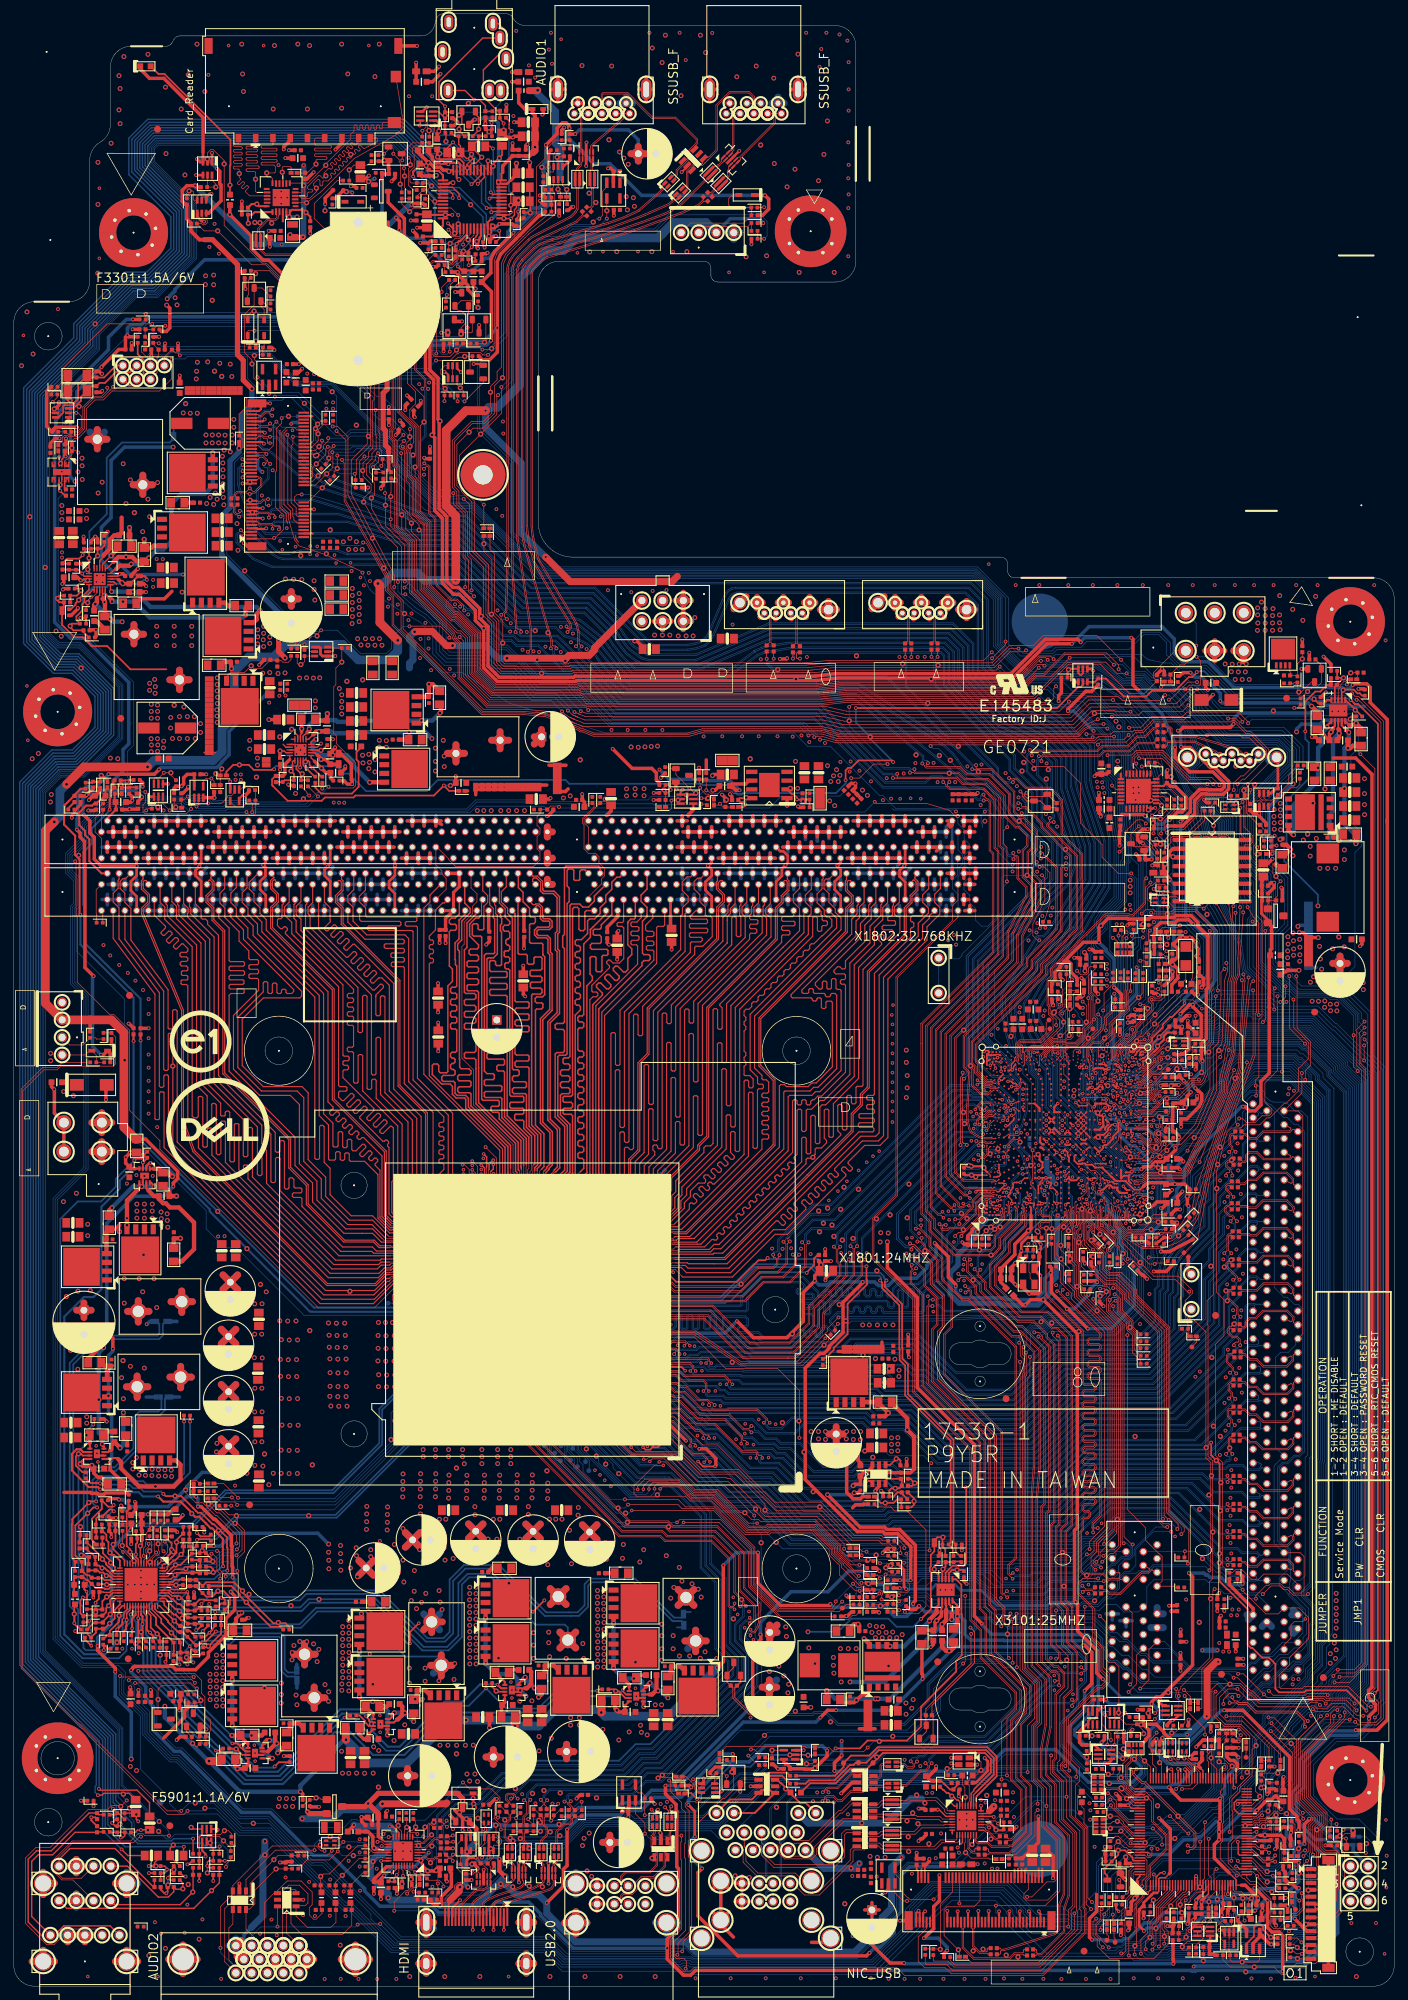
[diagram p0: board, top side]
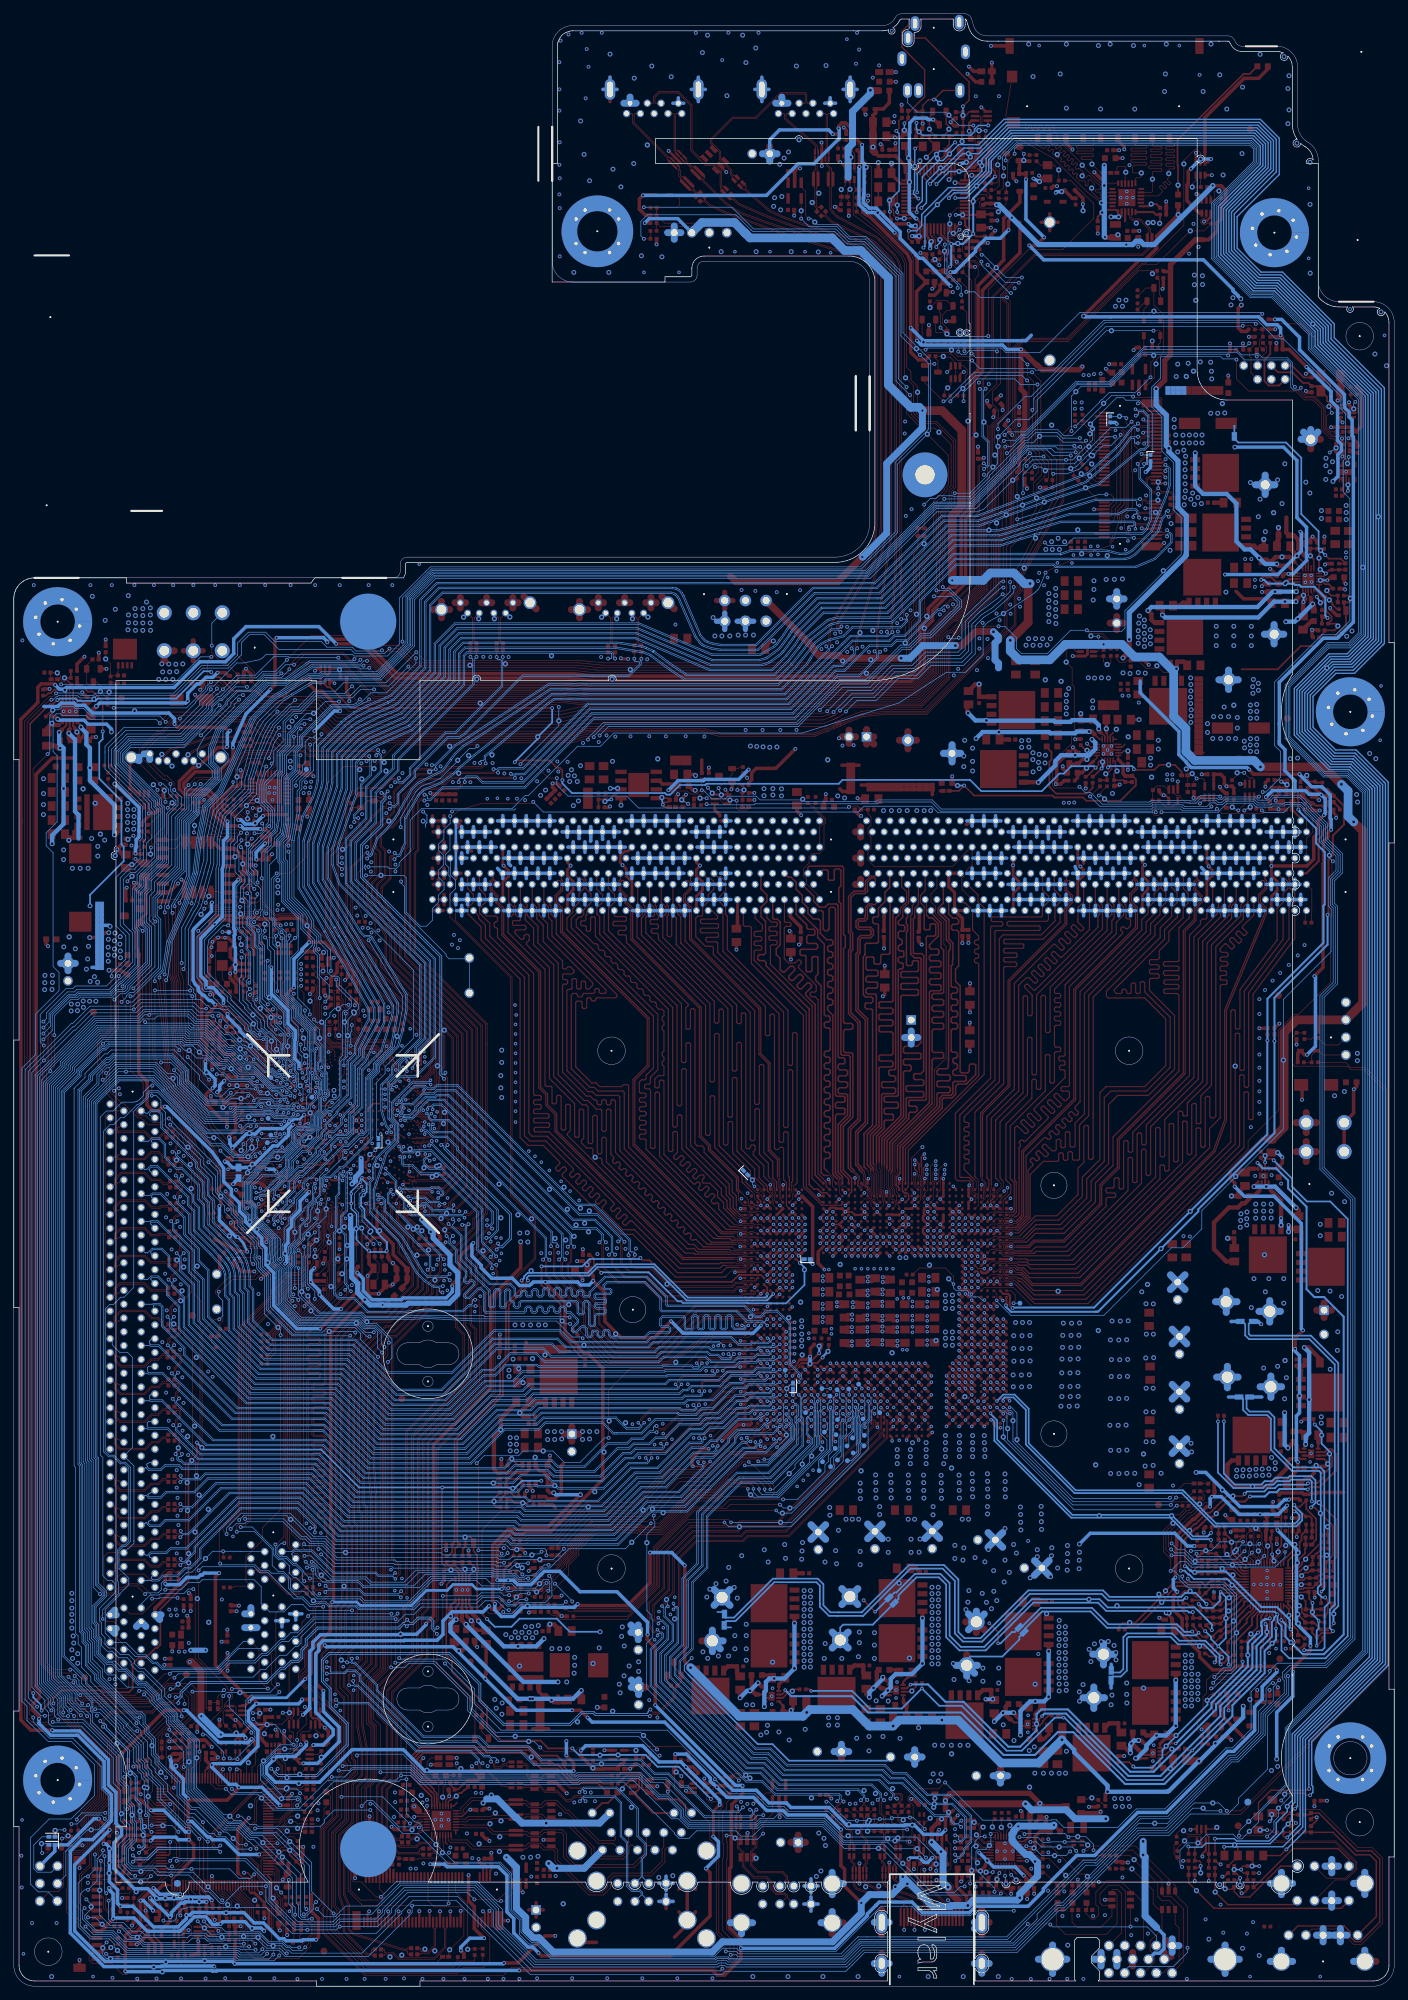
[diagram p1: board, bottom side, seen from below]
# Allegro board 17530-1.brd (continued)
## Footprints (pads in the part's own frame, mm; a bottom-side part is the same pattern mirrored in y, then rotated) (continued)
C402H22
  custom 0.152x0.152 smd: 1(0,0.445) 2(0,-0.445)
C603H35
  custom 0.216x0.216 smd: 1(0,0.762) 2(0,-0.762)
C603H36
  custom 0.216x0.216 smd: 1(0,0.762) 2(0,-0.762)
C603H40
  custom 0.216x0.216 smd: 1(0,0.762) 2(0,-0.762)
C805H50
  rect 1.397x1.143 smd: 1(0,0.965) 2(0,-0.965)
C805H54
  rect 1.397x1.143 smd: 1(0,0.965) 2(0,-0.965)
C805H56
  rect 1.397x1.143 smd: 1(0,0.965) 2(0,-0.965)
C805H58
  rect 1.397x1.143 smd: 1(0,0.965) 2(0,-0.965)
C35012W-L101-39AA00R
  round 0.254 hole 1.27 unplated: (0,0) (0,-6)
  oval 1.321x2.134 hole 0.61x1.422: 1(-3.8,-9.1) 2(3.7,-1.5) 3(-3.7,0.8) 4(2.7,0.6) 5(2.2,-9.1) 6(3.8,-9.1) 7(-4.6,-3.5) 8(4.6,-4.5)
D5126145AKH91
  rect 1.702x2.032 smd: A(0,2.172) K(0,-2.172)
DFN8G2-G1309-UH40
  rect 0.305x0.737 smd: 1(0.75,1.018) 2(0.25,1.018) 3(-0.25,1.018) 4(-0.75,1.018) 5(-0.75,-1.018) 6(-0.25,-1.018) 7(0.25,-1.018) 8(0.75,-1.018)
  rect 1.295x0.889 smd: 9(0,0)
DFN10G3-G265175H32
  rect 0.305x0.914 smd: 1(1,1.549) 2(0.5,1.549) 3(0,1.549) 4(-0.5,1.549) 5(-1,1.549) 6(-1,-1.549) 7(-0.5,-1.549) 8(0,-1.549) 9(0.5,-1.549) 10(1,-1.549)
  rect 2.642x1.753 smd: 11(0,0)
DFN10G2510H26
  rect 0.305x0.787 smd: 1(1,0.494) 5(-1,0.494) 6(-1,-0.494) 10(1,-0.494)
  rect 0.254x0.787 smd: 2(0.521,0.494) 4(-0.521,0.494) 7(-0.521,-0.494) 9(0.521,-0.494)
  rect 0.025x0.025 smd: 3(0,0.494)
  rect 0.406x1.753 smd: 8(0,-0.494)
ECAP-100D6D3H375
  rect 1.397x1.397 hole 0.991: 1(0,-1.27)
  round 1.397 hole 0.991: 2(0,1.27)
ECAP-100D6D3H493
  rect 1.397x1.397 hole 0.991: 1(0,-1.27)
  round 1.397 hole 0.991: 2(0,1.27)
ECAP-138D8-UH355
  rect 1.397x1.397 hole 0.991: 1(0,-1.75)
  round 1.397 hole 0.991: 2(0,1.75)
GAP-CLOSE-PWR-2U
  rect 0.521x0.61 smd: 1(-0.235,0) 2(0.235,0)
GAP-CLOSE-PWR-3
  rect 0.66x0.762 smd: 1(-0.305,0) 2(0.305,0)
GEN315R158-8-F-C-S-U
  round 0.254 hole 4.013 unplated: (0,0)
  round 0.864 hole 0.508: 1(3.189,0.634) 2(1.806,2.703) 3(-0.634,3.189) 4(-2.703,1.806) 5(-3.189,-0.634) 6(-1.806,-2.703) 7(0.634,-3.189) 8(2.703,-1.806)
GEN330R190-8-F-C
  round 0.254 hole 4.826 unplated: (0,0)
  round 0.864 hole 0.508: 1(3.079,1.778) 2(1.778,3.079) 3(-1.778,3.079) 4(-3.079,1.778) 5(-3.079,-1.778) 6(-1.778,-3.079) 7(1.778,-3.079) 8(3.079,-1.778)
HB9603E-DW
  round 1.397 hole 0.991: 1(-2.54,0) 2(2.54,0)
HF2704F-RM1
  round 0.254 hole 1.27 unplated: (-1.27,-2.16)
  round 1.422 hole 1.016: 1(3.81,0) 2(1.27,0) 3(-1.27,0) 4(-3.81,0)
HM3502E-P1
  round 0.254 hole 3.023 unplated: (-6.8,-2.29)
  round 2.184 hole 1.422: 1(-2.1,2.75) 2(2.1,2.75) 3(-2.1,-2.75) 4(2.1,-2.75)
L402H24
  custom 0.14x0.14 smd: 1(0,0.445) 2(0,-0.445)
L603H38
  custom 0.216x0.216 smd: 1(0,0.762) 2(0,-0.762)
L805H44
  rect 1.397x1.143 smd: 1(0,0.965) 2(0,-0.965)
L1608-UH38
  custom 0.216x0.216 smd: 1(0,0.762) 2(0,-0.762)
L7066-1830-UH119
  rect 3.505x2.921 smd: 1(0,2.78) 2(0,-2.78)
L115100-2030H158
  rect 3.251x2.896 smd: 1(0,4.944) 2(0,-4.944)
L125100-4PH24
  rect 0.457x0.838 smd: 1(-0.326,-0.587) 2(0.326,-0.587) 3(0.326,0.587) 4(-0.326,0.587)
LE18077-Z55D-4F
  round 0.991 hole 0.635: 1(3.81,0) 2(2.755,1.5) 3(1.055,1.5) 4(0,0) 5(-1.055,1.5) 6(-2.755,1.5) 7(-3.81,0)
  round 1.854 hole 1.372: 8(6.29,0) 9(-6.54,1)
LED1608AKH28
  custom 0.216x0.216 smd: A(0,0.762) K(0,-0.762)
LQFP48H63
  rect 0.305x1.524 smd: 1(2.75,4.242) 2(2.25,4.242) 3(1.75,4.242) 4(1.25,4.242) 5(0.751,4.242) 6(0.25,4.242) 7(-0.25,4.242) 8(-0.751,4.242) 9(-1.25,4.242) 10(-1.75,4.242) 11(-2.25,4.242) 12(-2.75,4.242) 25(-2.75,-4.242) 26(-2.25,-4.242) 27(-1.75,-4.242) 28(-1.25,-4.242) 29(-0.751,-4.242) 30(-0.25,-4.242) 31(0.25,-4.242) 32(0.751,-4.242) 33(1.25,-4.242) 34(1.75,-4.242) 35(2.25,-4.242) 36(2.75,-4.242)
  rect 1.524x0.305 smd: 13(-4.242,2.75) 14(-4.242,2.25) 15(-4.242,1.75) 16(-4.242,1.25) 17(-4.242,0.751) 18(-4.242,0.25) 19(-4.242,-0.25) 20(-4.242,-0.751) 21(-4.242,-1.25) 22(-4.242,-1.75) 23(-4.242,-2.25) 24(-4.242,-2.75) 37(4.242,-2.75) 38(4.242,-2.25) 39(4.242,-1.75) 40(4.242,-1.25) 41(4.242,-0.751) 42(4.242,-0.25) 43(4.242,0.25) 44(4.242,0.751) 45(4.242,1.25) 46(4.242,1.75) 47(4.242,2.25) 48(4.242,2.75)
NTC-402H24-U
  custom 0.14x0.14 smd: 1(0,0.445) 2(0,-0.445)
OSC-3225-4P-3H36
  rect 1.397x0.914 smd: 1(-1.171,-0.825) 2(1.171,-0.825) 3(1.171,0.825) 4(-1.171,0.825)
P254-1104A0ADKP-W
  round 0.254 hole 1.27 unplated: (-1.27,-2.16)
  round 1.422 hole 1.016: 1(3.81,0) 2(1.27,0) 3(-1.27,0) 4(-3.81,0)
PFPCC128-5H48
  rect 0.203x1.524 smd: 1(6.2,7.747) 2(5.8,7.747) 3(5.4,7.747) 4(5,7.747) 5(4.6,7.747) 6(4.2,7.747) 7(3.8,7.747) 8(3.4,7.747) 9(3,7.747) 10(2.6,7.747) 11(2.2,7.747) 12(1.8,7.747) 13(1.4,7.747) 14(0.999,7.747) 15(0.599,7.747) 16(0.199,7.747) 17(-0.199,7.747) 18(-0.599,7.747) 19(-0.999,7.747) 20(-1.4,7.747) 21(-1.8,7.747) 22(-2.2,7.747) 23(-2.6,7.747) 24(-3,7.747) 25(-3.4,7.747) 26(-3.8,7.747) 27(-4.2,7.747) 28(-4.6,7.747) 29(-5,7.747) 30(-5.4,7.747) 31(-5.8,7.747) 32(-6.2,7.747) 65(-6.2,-7.747) 66(-5.8,-7.747) 67(-5.4,-7.747) 68(-5,-7.747) 69(-4.6,-7.747) 70(-4.2,-7.747) 71(-3.8,-7.747) 72(-3.4,-7.747) 73(-3,-7.747) 74(-2.6,-7.747) 75(-2.2,-7.747) 76(-1.8,-7.747) 77(-1.4,-7.747) 78(-0.999,-7.747) 79(-0.599,-7.747) 80(-0.199,-7.747) 81(0.199,-7.747) 82(0.599,-7.747) 83(0.999,-7.747) 84(1.4,-7.747) 85(1.8,-7.747) 86(2.2,-7.747) 87(2.6,-7.747) 88(3,-7.747) 89(3.4,-7.747) 90(3.8,-7.747) 91(4.2,-7.747) 92(4.6,-7.747) 93(5,-7.747) 94(5.4,-7.747) 95(5.8,-7.747) 96(6.2,-7.747)
  rect 1.524x0.203 smd: 33(-7.747,6.2) 34(-7.747,5.8) 35(-7.747,5.4) 36(-7.747,5) 37(-7.747,4.6) 38(-7.747,4.2) 39(-7.747,3.8) 40(-7.747,3.4) 41(-7.747,3) 42(-7.747,2.6) 43(-7.747,2.2) 44(-7.747,1.8) 45(-7.747,1.4) 46(-7.747,0.999) 47(-7.747,0.599) 48(-7.747,0.199) 49(-7.747,-0.199) 50(-7.747,-0.599) 51(-7.747,-0.999) 52(-7.747,-1.4) 53(-7.747,-1.8) 54(-7.747,-2.2) 55(-7.747,-2.6) 56(-7.747,-3) 57(-7.747,-3.4) 58(-7.747,-3.8) 59(-7.747,-4.2) 60(-7.747,-4.6) 61(-7.747,-5) 62(-7.747,-5.4) 63(-7.747,-5.8) 64(-7.747,-6.2) 97(7.747,-6.2) 98(7.747,-5.8) 99(7.747,-5.4) 100(7.747,-5) 101(7.747,-4.6) 102(7.747,-4.2) 103(7.747,-3.8) 104(7.747,-3.4) 105(7.747,-3) 106(7.747,-2.6) 107(7.747,-2.2) 108(7.747,-1.8) 109(7.747,-1.4) 110(7.747,-0.999) 111(7.747,-0.599) 112(7.747,-0.199) 113(7.747,0.199) 114(7.747,0.599) 115(7.747,0.999) 116(7.747,1.4) 117(7.747,1.8) 118(7.747,2.2) 119(7.747,2.6) 120(7.747,3) 121(7.747,3.4) 122(7.747,3.8) 123(7.747,4.2) 124(7.747,4.6) 125(7.747,5) 126(7.747,5.4) 127(7.747,5.8) 128(7.747,6.2)
POLYSW-2114H30
  rect 1.6x0.965 smd: 1(0,0.94) 2(0,-0.94)
PPAK-8P-3333-2H36
  rect 0.406x0.914 smd: 1(-0.975,-2.347) 2(-0.325,-2.347) 3(0.325,-2.347) 4(0.975,-2.347)
  rect 3.48x3.023 smd: 5(0,0)
  rect 0.025x0.025 smd: 6(0.975,1.029) 7(0,1.029) 8(-0.975,1.029)
PPAK-8P-5262H40
  rect 0.762x1.448 smd: 1(-1.905,-3.684) 2(-0.635,-3.684) 3(0.635,-3.684) 4(1.905,-3.684)
  rect 5.512x5.309 smd: 5(1.543,1.492)
  rect 0.025x0.025 smd: 6(-1.543,1.492) 7(-1.543,-1.492) 8(1.543,-1.492)
PPAK-8P-G5324H44-COLAY
  rect 0.762x1.016 smd: 1(-1.905,-3.01) 2(-0.635,-3.01) 3(0.635,-3.01) 4(1.905,-3.01) 5(1.905,3.01) 6(0.635,3.01) 7(-0.635,3.01) 8(-1.905,3.01)
  rect 5.207x2.896 smd: 9(0,0.65)
  rect 5.207x0.787 smd: 10(0,-1.7)
QFN20-G1D75H32
  rect 0.203x0.914 smd: 1(0.8,1.551) 2(0.4,1.551) 3(0,1.551) 4(-0.4,1.551) 5(-0.8,1.551) 11(-0.8,-1.551) 12(-0.4,-1.551) 13(0,-1.551) 14(0.4,-1.551) 15(0.8,-1.551)
  rect 0.914x0.203 smd: 6(-1.551,0.8) 7(-1.551,0.4) 8(-1.551,0) 9(-1.551,-0.4) 10(-1.551,-0.8) 16(1.551,-0.8) 17(1.551,-0.4) 18(1.551,0) 19(1.551,0.4) 20(1.551,0.8)
  rect 1.753x1.753 smd: 21(0,0)
QFN24-G2D5H40-U
  rect 0.305x0.838 smd: 1(1.25,2.095) 6(-1.25,2.095) 13(-1.25,-2.095) 18(1.25,-2.095)
  rect 0.305x0.965 smd: 2(0.751,2.032) 3(0.25,2.032) 4(-0.25,2.032) 5(-0.751,2.032) 14(-0.751,-2.032) 15(-0.25,-2.032) 16(0.25,-2.032) 17(0.751,-2.032)
  rect 0.838x0.305 smd: 7(-2.095,1.25) 12(-2.095,-1.25) 19(2.095,-1.25) 24(2.095,1.25)
  rect 0.965x0.305 smd: 8(-2.032,0.751) 9(-2.032,0.25) 10(-2.032,-0.25) 11(-2.032,-0.751) 20(2.032,-0.751) 21(2.032,-0.25) 22(2.032,0.25) 23(2.032,0.751)
  rect 2.489x2.489 smd: 25(0,0)
QFN32G5-G3D6H32
  rect 0.305x0.914 smd: 1(1.75,2.551) 8(-1.75,2.551) 17(-1.75,-2.551) 24(1.75,-2.551)
  rect 0.305x0.991 smd: 2(1.25,2.513) 3(0.75,2.513) 4(0.25,2.513) 5(-0.25,2.513) 6(-0.75,2.513) 7(-1.25,2.513) 18(-1.25,-2.513) 19(-0.75,-2.513) 20(-0.25,-2.513) 21(0.25,-2.513) 22(0.75,-2.513) 23(1.25,-2.513)
  rect 0.914x0.305 smd: 9(-2.551,1.75) 16(-2.551,-1.75) 25(2.551,-1.75) 32(2.551,1.75)
  rect 0.991x0.305 smd: 10(-2.513,1.25) 11(-2.513,0.75) 12(-2.513,0.25) 13(-2.513,-0.25) 14(-2.513,-0.75) 15(-2.513,-1.25) 26(2.513,-1.25) 27(2.513,-0.75) 28(2.513,-0.25) 29(2.513,0.25) 30(2.513,0.75) 31(2.513,1.25)
  rect 3.607x3.607 smd: 33(0,0)
QFN32J4-G2D85H36
  rect 0.203x0.864 smd: 1(1.4,2.085) 2(1,2.085) 3(0.6,2.085) 4(0.2,2.085) 5(-0.2,2.085) 6(-0.6,2.085) 7(-1,2.085) 8(-1.4,2.085) 17(-1.4,-2.085) 18(-1,-2.085) 19(-0.6,-2.085) 20(-0.2,-2.085) 21(0.2,-2.085) 22(0.6,-2.085) 23(1,-2.085) 24(1.4,-2.085)
  rect 0.864x0.203 smd: 9(-2.085,1.4) 10(-2.085,1) 11(-2.085,0.6) 12(-2.085,0.2) 13(-2.085,-0.2) 14(-2.085,-0.6) 15(-2.085,-1) 16(-2.085,-1.4) 25(2.085,-1.4) 26(2.085,-1) 27(2.085,-0.6) 28(2.085,-0.2) 29(2.085,0.2) 30(2.085,0.6) 31(2.085,1) 32(2.085,1.4)
  rect 2.845x2.845 smd: 33(0,0)
QFN52J6-G4D8-UH40
  rect 0.203x0.838 smd: 1(2.4,3.063) 13(-2.4,3.063) 27(-2.4,-3.063) 39(2.4,-3.063)
  rect 0.203x0.889 smd: 2(2,3.063) 3(1.6,3.063) 4(1.2,3.063) 5(0.8,3.063) 6(0.4,3.063) 7(0,3.063) 8(-0.4,3.063) 9(-0.8,3.063) 10(-1.2,3.063) 11(-1.6,3.063) 12(-2,3.063) 28(-2,-3.063) 29(-1.6,-3.063) 30(-1.2,-3.063) 31(-0.8,-3.063) 32(-0.4,-3.063) 33(0,-3.063) 34(0.4,-3.063) 35(0.8,-3.063) 36(1.2,-3.063) 37(1.6,-3.063) 38(2,-3.063)
  rect 0.838x0.203 smd: 14(-3.063,2.4) 26(-3.063,-2.4) 40(3.063,-2.4) 52(3.063,2.4)
  rect 0.889x0.203 smd: 15(-3.063,2) 16(-3.063,1.6) 17(-3.063,1.2) 18(-3.063,0.8) 19(-3.063,0.4) 20(-3.063,0) 21(-3.063,-0.4) 22(-3.063,-0.8) 23(-3.063,-1.2) 24(-3.063,-1.6) 25(-3.063,-2) 41(3.063,-2) 42(3.063,-1.6) 43(3.063,-1.2) 44(3.063,-0.8) 45(3.063,-0.4) 46(3.063,0) 47(3.063,0.4) 48(3.063,0.8) 49(3.063,1.2) 50(3.063,1.6) 51(3.063,2)
  rect 4.801x4.801 smd: 53(0,0)
R402H14
  custom 0.14x0.14 smd: 1(0,0.445) 2(0,-0.445)
R402H16
  custom 0.14x0.14 smd: 1(0,0.445) 2(0,-0.445)
R603
  custom 0.216x0.216 smd: 1(0,0.762) 2(0,-0.762)
R603H22
  custom 0.216x0.216 smd: 1(0,0.762) 2(0,-0.762)
R805H24
  rect 1.397x1.143 smd: 1(0,0.965) 2(0,-0.965)
R1206H28
  rect 1.651x1.27 smd: 1(0,1.397) 2(0,-1.397)
RT-D6D3-1D4-103065H394
  round 2.388 hole 1.626: 1(3.15,0.7) 2(-3.15,-0.7)
RT-D6D4-1D9-103072H394
  round 1.778 hole 1.016: 1(3.2,0.95) 2(-3.2,-0.95)
RT-D6D6-6D6-108108H426
  round 2.083 hole 1.321: 1(-3.3,-3.3) 2(3.3,3.3)
RUA1JA-KJKC-DE0-0R
  round 1.346 hole 0.94: 1(-3.5,-7.34) 2(-1,-7.34) 3(1,-7.34) 4(3.5,-7.34) 5(-3.5,-4.72) 6(-1,-4.72) 7(1,-4.72) 8(3.5,-4.72)
  round 1.321 hole 0.914: 9(5.715,0.1) 10(4.445,2.64) 11(3.175,0.1) 12(1.905,2.64) 13(0.635,0.1) 14(-0.635,2.64) 15(-1.905,0.1) 16(-3.175,2.64) 17(-4.445,0.1) 18(-5.715,2.64) 19(-4.66,5.47) 20(-7.2,5.47) 21(4.66,5.47) 22(7.2,5.47)
  round 2.718 hole 2.311: 23(-9.35,-12.68) 24(9.35,-12.68) 25(-6.57,-10.05) 26(6.57,-10.05) 27(-6.57,-4.37) 28(6.57,-4.37) 29(-9.35,0) 30(9.35,0)
SC70-5H44
  rect 0.406x1.219 smd: 1(0.65,0.826) 2(0,0.826) 3(-0.65,0.826) 4(-0.65,-0.826) 5(0.65,-0.826)
SE3116H241
  rect 1.626x3.099 smd: 1(0,2.654) 2(0,-2.654)
SKT-HDMI23-150122-9-U
  rect 0.305x2.591 smd: 1(4.5,0.76) 2(4,0.76) 3(3.5,0.76) 4(3,0.76) 5(2.5,0.76) 6(2,0.76) 7(1.5,0.76) 8(1,0.76) 9(0.5,0.76) 10(0,0.76) 11(-0.5,0.76) 12(-1,0.76) 13(-1.5,0.76) 14(-2,0.76) 15(-2.5,0.76) 16(-3,0.76) 17(-3.5,0.76) 18(-4,0.76) 19(-4.5,0.76)
  oval 1.626x3.124 hole 0.914x2.413: 20(7.25,0) 21(-7.25,0)
  oval 1.626x2.311 hole 0.914x1.6: 22(7.25,-5.96) 23(-7.25,-5.96)
SKT-SOIC8-1H211
  rect 0.889x1.499 smd: 1(1.905,3.751) 2(0.635,3.751) 3(-0.635,3.751) 4(-1.905,3.751) 5(-1.905,-3.751) 6(-0.635,-3.751) 7(0.635,-3.751) 8(1.905,-3.751)
SKT-SOIC16-153139H258
  rect 0.508x1.676 smd: 1(4.445,4.897) 2(3.175,4.897) 3(1.905,4.897) 4(0.635,4.897) 5(-0.635,4.897) 6(-1.905,4.897) 7(-3.175,4.897) 8(-4.445,4.897) 9(-4.445,-4.897) 10(-3.175,-4.897) 11(-1.905,-4.897) 12(-0.635,-4.897) 13(0.635,-4.897) 14(1.905,-4.897) 15(3.175,-4.897) 16(4.445,-4.897)
SKT-USB11-138166
  round 1.067 hole 0.711: 1(-3.5,2) 2(-1,2) 3(1,2) 4(3.5,2) 5(4,3.5) 6(2,3.5) 7(0,3.5) 8(-2,3.5) 9(-4,3.5)
  oval 1.524x3.023 hole 0.813x2.311: 10(-6.4,0) 11(6.4,0)
SKT-USB12-157183
  round 1.346 hole 0.94: 1(-3.5,2.71) 2(-1,2.71) 3(1,2.71) 4(3.5,2.71) 5(-3.5,5.33) 6(-1,5.33) 7(1,5.33) 8(3.5,5.33)
  round 2.718 hole 2.311: 9(-6.57,0) 10(6.57,0) 11(-6.57,5.68) 12(6.57,5.68)
SKTBGA1151R754612-UH369
  round 0.254 hole 3.81 unplated: (-35.21,0) (25.81,18) (25.81,-18)
  round 0.508 smd: A4(-16.187,18.288) A5(-15.273,18.288) AT40(18.931,-14.63) AU1(-18.931,-14.63) AU39(18.016,-15.545) AU40(18.931,-15.545) AV1(-18.931,-15.545) AV2(-18.016,-15.545) AV38(17.102,-16.459) AV39(18.016,-16.459) AW2(-18.016,-16.459) AW3(-17.102,-16.459) AW37(16.187,-17.374) AW38(17.102,-17.374) AY3(-17.102,-17.374) AY4(-16.187,-17.374) B3(-17.102,17.374) B4(-16.187,17.374) B37(16.187,16.459) B38(17.102,16.459) B39(18.016,16.459) C2(-18.016,16.459) C3(-17.102,16.459) C39(18.016,15.545) C40(18.931,15.545) D1(-18.931,15.545) D2(-18.016,15.545) D40(18.931,14.63) E40(18.931,13.716)
  round 0.429 smd: A6(-14.359,18.288) A7(-13.444,18.288) A25(3.015,18.288) A26(3.929,18.288) A27(4.844,18.288) A28(5.758,18.288) A29(6.673,18.288) A30(7.587,18.288) AA5(-15.273,0) AA6(-14.359,0) AA7(-13.444,0) AA8(-12.53,0) AA33(12.53,-0.914) AA34(13.444,-0.914) AA35(14.359,-0.914) AA36(15.273,-0.914) AA37(16.187,-0.914) AA38(17.102,-0.914) AB5(-15.273,-0.914) AB6(-14.359,-0.914) AB7(-13.444,-0.914) AB8(-12.53,-0.914) AB33(12.53,-1.829) AB34(13.444,-1.829) AB35(14.359,-1.829) AB36(15.273,-1.829) AB37(16.187,-1.829) AC5(-15.273,-1.829) AC6(-14.359,-1.829) AC7(-13.444,-1.829) AC8(-12.53,-1.829) AC33(12.53,-2.743) AC34(13.444,-2.743) AC35(14.359,-2.743) AC36(15.273,-2.743) AC37(16.187,-2.743) AD3(-17.102,-2.743) AD4(-16.187,-2.743) AD5(-15.273,-2.743) AD6(-14.359,-2.743) AD7(-13.444,-2.743) AD8(-12.53,-2.743) AD33(12.53,-3.658) AD34(13.444,-3.658) AD35(14.359,-3.658) AD36(15.273,-3.658) AD37(16.187,-3.658) AE3(-17.102,-3.658) AE4(-16.187,-3.658) AE5(-15.273,-3.658) AE6(-14.359,-3.658) AE7(-13.444,-3.658) AE8(-12.53,-3.658) AE33(12.53,-4.572) AE34(13.444,-4.572) AE35(14.359,-4.572) AE36(15.273,-4.572) AE37(16.187,-4.572) AE38(17.102,-4.572) AF4(-16.187,-4.572) AF5(-15.273,-4.572) AF6(-14.359,-4.572) AF7(-13.444,-4.572) AF8(-12.53,-4.572) AF33(12.53,-5.486) AF34(13.444,-5.486) AF35(14.359,-5.486) AF36(15.273,-5.486) AF37(16.187,-5.486) AF38(17.102,-5.486) AG4(-16.187,-5.486) AG5(-15.273,-5.486) AG6(-14.359,-5.486) AG7(-13.444,-5.486) AG8(-12.53,-5.486) AG33(12.53,-6.401) AG34(13.444,-6.401) AG35(14.359,-6.401) AG36(15.273,-6.401) AG37(16.187,-6.401) AG38(17.102,-6.401) AH3(-17.102,-6.401) AH4(-16.187,-6.401) AH5(-15.273,-6.401) AH6(-14.359,-6.401) AH7(-13.444,-6.401) AH8(-12.53,-6.401) AH33(12.53,-7.315) AH34(13.444,-7.315) AH35(14.359,-7.315) AH36(15.273,-7.315) AH37(16.187,-7.315) AH38(17.102,-7.315) AJ3(-17.102,-7.315) AJ4(-16.187,-7.315) AJ5(-15.273,-7.315) AJ6(-14.359,-7.315) AJ7(-13.444,-7.315) AJ8(-12.53,-7.315) AJ9(-11.615,-7.315) AJ11(-7.587,-8.23) AJ12(-6.673,-8.23) AJ13(-5.758,-8.23) AJ14(-4.844,-8.23) AJ15(-3.929,-8.23) AJ16(-3.015,-8.23) AJ17(-2.101,-8.23) AJ18(-1.186,-8.23) AJ19(-0.272,-8.23) AJ20(0.643,-8.23) AJ21(1.557,-8.23) AJ22(2.471,-8.23) AJ23(3.386,-8.23) AJ24(4.3,-8.23) AJ25(5.215,-8.23) AJ26(6.129,-8.23) AJ27(7.043,-8.23) AJ28(7.958,-8.23) AJ29(8.872,-8.23) AJ30(9.787,-8.23) AJ31(10.701,-8.23) AJ32(11.615,-8.23) AJ33(12.53,-8.23) AJ34(13.444,-8.23) AJ35(14.359,-8.23) AJ36(15.273,-8.23) AJ37(16.187,-8.23) AJ38(17.102,-8.23) AK3(-17.102,-8.23) AK4(-16.187,-8.23) AK5(-15.273,-8.23) AK6(-14.359,-8.23) AK7(-13.444,-8.23) AK8(-12.53,-8.23) AK9(-11.615,-8.23) AK10(-10.701,-8.23) AK11(-7.587,-9.144) AK12(-6.673,-9.144) AK13(-5.758,-9.144) AK14(-4.844,-9.144) AK15(-3.929,-9.144) AK16(-3.015,-9.144) AK17(-2.101,-9.144) AK18(-1.186,-9.144) AK19(-0.272,-9.144) AK20(0.643,-9.144) AK21(1.557,-9.144) AK22(2.471,-9.144) AK23(3.386,-9.144) AK24(4.3,-9.144) AK25(5.215,-9.144) AK26(6.129,-9.144) AK27(7.043,-9.144) AK28(7.958,-9.144) AK29(8.872,-9.144) AK30(9.787,-9.144) AK31(10.701,-9.144) AK32(11.615,-9.144) AK33(12.53,-9.144) AK34(13.444,-9.144) AK35(14.359,-9.144) AK36(15.273,-9.144) AK37(16.187,-9.144) AK38(17.102,-9.144) AL3(-17.102,-9.144) AL4(-16.187,-9.144) AL5(-15.273,-9.144) AL6(-14.359,-9.144) AL7(-13.444,-9.144) AL8(-12.53,-9.144) AL9(-11.615,-9.144) AL10(-10.701,-9.144) AL11(-7.587,-10.058) AL12(-6.673,-10.058) AL13(-5.758,-10.058) AL14(-4.844,-10.058) AL15(-3.929,-10.058) AL16(-3.015,-10.058) AL17(-2.101,-10.058) AL18(-1.186,-10.058) AL19(-0.272,-10.058) AL20(0.643,-10.058) AL21(1.557,-10.058) AL22(2.471,-10.058) AL23(3.386,-10.058) AL24(4.3,-10.058) AL25(5.215,-10.058) AL26(6.129,-10.058) AL27(7.043,-10.058) AL28(7.958,-10.058) AL29(8.872,-10.058) AL30(9.787,-10.058) AL31(10.701,-10.058) AL32(11.615,-10.058) AL33(12.53,-10.058) AL34(13.444,-10.058) AL35(14.359,-10.058) AL36(15.273,-10.058) AL37(16.187,-10.058) AL38(17.102,-10.058) AM3(-17.102,-10.058) AM4(-16.187,-10.058) AM5(-15.273,-10.058) AM6(-14.359,-10.058) AM7(-13.444,-10.058) AM8(-12.53,-10.058) AM9(-11.615,-10.058) AM10(-10.701,-10.058) AM11(-7.587,-10.973) AM12(-6.673,-10.973) AM13(-5.758,-10.973) AM14(-4.844,-10.973) AM15(-3.929,-10.973) AM16(-3.015,-10.973) AM17(-2.101,-10.973) AM18(-1.186,-10.973) AM19(-0.272,-10.973) AM20(0.643,-10.973) AM21(1.557,-10.973) AM22(2.471,-10.973) AM23(3.386,-10.973) AM24(4.3,-10.973) AM25(5.215,-10.973) AM26(6.129,-10.973) AM27(7.043,-10.973) AM28(7.958,-10.973) AM29(8.872,-10.973) AM30(9.787,-10.973) AM31(10.701,-10.973) AM32(11.615,-10.973) AM33(12.53,-10.973) AM34(13.444,-10.973) AM35(14.359,-10.973) AM36(15.273,-10.973) AM37(16.187,-10.973) AM38(17.102,-10.973) AN3(-17.102,-10.973) AN4(-16.187,-10.973) AN5(-15.273,-10.973) AN6(-14.359,-10.973) AN7(-13.444,-10.973) AN8(-12.53,-10.973) AN9(-11.615,-10.973) AN10(-10.701,-10.973) AN11(-7.587,-11.887) AN12(-6.673,-11.887) AN13(-5.758,-11.887) AN14(-4.844,-11.887) AN15(-3.929,-11.887) AN16(-3.015,-11.887) AN17(-2.101,-11.887) AN18(-1.186,-11.887) AN19(-0.272,-11.887) AN20(0.643,-11.887) AN21(1.557,-11.887) AN22(2.471,-11.887) AN23(3.386,-11.887) AN24(4.3,-11.887) AN25(5.215,-11.887) AN26(6.129,-11.887) AN27(7.043,-11.887) AN28(7.958,-11.887) AN29(8.872,-11.887) AN30(9.787,-11.887) AN31(10.701,-11.887) AN32(11.615,-11.887) AN33(12.53,-11.887) AN34(13.444,-11.887) AN35(14.359,-11.887) AN36(15.273,-11.887) AN37(16.187,-11.887) AN38(17.102,-11.887) AP3(-17.102,-11.887) AP4(-16.187,-11.887) AP5(-15.273,-11.887) AP6(-14.359,-11.887) AP7(-13.444,-11.887) AP8(-12.53,-11.887) AP9(-11.615,-11.887) AP10(-10.701,-11.887) AP11(-7.587,-12.802) AP12(-6.673,-12.802) AP13(-5.758,-12.802) AP14(-4.844,-12.802) AP15(-3.929,-12.802) AP16(-3.015,-12.802) AP17(-2.101,-12.802) AP18(-1.186,-12.802) AP19(-0.272,-12.802) AP20(0.643,-12.802) AP21(1.557,-12.802) AP22(2.471,-12.802) AP23(3.386,-12.802) AP24(4.3,-12.802) AP25(5.215,-12.802) AP26(6.129,-12.802) AP27(7.043,-12.802) AP28(7.958,-12.802) AP29(8.872,-12.802) AP30(9.787,-12.802) AP31(10.701,-12.802) AP32(11.615,-12.802) AP33(12.53,-12.802) AP34(13.444,-12.802) AP35(14.359,-12.802) AP36(15.273,-12.802) AP37(16.187,-12.802) AP38(17.102,-12.802) AR3(-17.102,-12.802) AR4(-16.187,-12.802) AR5(-15.273,-12.802) AR6(-14.359,-12.802) AR7(-13.444,-12.802) AR8(-12.53,-12.802) AR9(-11.615,-12.802) AR10(-10.701,-12.802) AR11(-7.587,-13.716) AR12(-6.673,-13.716) AR13(-5.758,-13.716) AR14(-4.844,-13.716) AR15(-3.929,-13.716) AR16(-3.015,-13.716) AR17(-2.101,-13.716) AR18(-1.186,-13.716) AR19(-0.272,-13.716) AR20(0.643,-13.716) AR21(1.557,-13.716) AR22(2.471,-13.716) AR23(3.386,-13.716) AR24(4.3,-13.716) AR25(5.215,-13.716) AR26(6.129,-13.716) AR27(7.043,-13.716) AR28(7.958,-13.716) AR29(8.872,-13.716) AR30(9.787,-13.716) AR31(10.701,-13.716) AR32(11.615,-13.716) AR33(12.53,-13.716) AR34(13.444,-13.716) AR35(14.359,-13.716) AR36(15.273,-13.716) AR37(16.187,-13.716) AR38(17.102,-13.716) AT3(-17.102,-13.716) AT4(-16.187,-13.716) AT5(-15.273,-13.716) AT6(-14.359,-13.716) AT7(-13.444,-13.716) AT8(-12.53,-13.716) AT9(-11.615,-13.716) AT10(-10.701,-13.716) AT11(-7.587,-14.63) AT12(-6.673,-14.63) AT13(-5.758,-14.63) AT14(-4.844,-14.63) AT15(-3.929,-14.63) AT16(-3.015,-14.63) AT17(-2.101,-14.63) AT18(-1.186,-14.63) AT19(-0.272,-14.63) AT20(0.643,-14.63) AT21(1.557,-14.63) AT22(2.471,-14.63) AT23(3.386,-14.63) AT24(4.3,-14.63) AT25(5.215,-14.63) AT26(6.129,-14.63) AT27(7.043,-14.63) AT28(7.958,-14.63) AT29(8.872,-14.63) AT30(9.787,-14.63) AT31(10.701,-14.63) AT32(11.615,-14.63) AT33(12.53,-14.63) AT34(13.444,-14.63) AT35(14.359,-14.63) AT36(15.273,-14.63) AT37(16.187,-14.63) AT38(17.102,-14.63) AU3(-17.102,-14.63) AU4(-16.187,-14.63) AU5(-15.273,-14.63) AU6(-14.359,-14.63) AU7(-13.444,-14.63) AU8(-12.53,-14.63) AU9(-11.615,-14.63) AU10(-10.701,-14.63) AU11(-7.587,-15.545) AU12(-6.673,-15.545) AU13(-5.758,-15.545) AU14(-4.844,-15.545) AU15(-3.929,-15.545) AU16(-3.015,-15.545) AU17(-2.101,-15.545) AU18(-1.186,-15.545) AU19(-0.272,-15.545) AU20(0.643,-15.545) AU21(1.557,-15.545) AU24(4.3,-15.545) AU25(5.215,-15.545) AU26(6.129,-15.545) AU27(7.043,-15.545) AU28(7.958,-15.545) AU29(8.872,-15.545) AU30(9.787,-15.545) AU31(10.701,-15.545) AU32(11.615,-15.545) AU33(12.53,-15.545) AU34(13.444,-15.545) AU35(14.359,-15.545) AU36(15.273,-15.545) AU37(16.187,-15.545) AU38(17.102,-15.545) AV3(-17.102,-15.545) AV4(-16.187,-15.545) AV5(-15.273,-15.545) AV6(-14.359,-15.545) AV7(-13.444,-15.545) AV8(-12.53,-15.545) AV9(-11.615,-15.545) AV10(-10.701,-15.545) AV11(-7.587,-16.459) AV12(-6.673,-16.459) AV13(-5.758,-16.459) AV14(-4.844,-16.459) AV24(4.3,-16.459) AV25(5.215,-16.459) AV28(7.958,-16.459) AV29(8.872,-16.459) AV37(16.187,-16.459) AW4(-16.187,-16.459) AW9(-11.615,-16.459) AW10(-10.701,-16.459) AW11(-7.587,-17.374) AW12(-6.673,-17.374) AW13(-5.758,-17.374) AW14(-4.844,-17.374) AY10(-10.701,-17.374) B5(-15.273,17.374) B6(-14.359,17.374) B7(-13.444,17.374) B25(3.015,17.374) B26(3.929,17.374) B27(4.844,17.374) B28(5.758,17.374) B29(6.673,17.374) B30(7.587,17.374) B31(10.701,16.459) B32(11.615,16.459) B33(12.53,16.459) B34(13.444,16.459) B35(14.359,16.459) B36(15.273,16.459) C4(-16.187,16.459) C5(-15.273,16.459) C6(-14.359,16.459) C7(-13.444,16.459) C8(-12.53,16.459) C9(-11.615,16.459) C12(-8.872,16.459) C13(-7.958,16.459) C14(-7.043,16.459) C15(-6.129,16.459) C16(-5.215,16.459) C17(-4.3,16.459) C25(3.015,16.459) C26(3.929,16.459) C27(4.844,16.459) C28(5.758,16.459) C29(6.673,16.459) C30(7.587,16.459) C31(10.701,15.545) C32(11.615,15.545) C33(12.53,15.545) C34(13.444,15.545) C35(14.359,15.545) C36(15.273,15.545) C37(16.187,15.545) C38(17.102,15.545) D3(-17.102,15.545) D4(-16.187,15.545) D5(-15.273,15.545) D6(-14.359,15.545) D7(-13.444,15.545) D8(-12.53,15.545) D9(-11.615,15.545) D10(-10.701,15.545) D11(-9.787,15.545) D12(-8.872,15.545) D13(-7.958,15.545) D14(-7.043,15.545) D15(-6.129,15.545) D16(-5.215,15.545) D17(-4.3,15.545) D24(2.101,15.545) D25(3.015,15.545) D26(3.929,15.545) D27(4.844,15.545) D28(5.758,15.545) D29(6.673,15.545) D30(7.587,15.545) D31(10.701,14.63) D32(11.615,14.63) D33(12.53,14.63) D34(13.444,14.63) D35(14.359,14.63) D36(15.273,14.63) D37(16.187,14.63) D38(17.102,14.63) D39(18.016,14.63) E3(-17.102,14.63) E4(-16.187,14.63) E5(-15.273,14.63) E6(-14.359,14.63) E7(-13.444,14.63) E8(-12.53,14.63) E9(-11.615,14.63) E10(-10.701,14.63) E11(-9.787,14.63) E12(-8.872,14.63) E13(-7.958,14.63) E14(-7.043,14.63) E15(-6.129,14.63) E16(-5.215,14.63) E17(-4.3,14.63) E18(-3.386,14.63) E19(-2.471,14.63) E21(-0.643,14.63) E23(1.186,14.63) E24(2.101,14.63) E25(3.015,14.63) E26(3.929,14.63) E27(4.844,14.63) E28(5.758,14.63) E29(6.673,14.63) E30(7.587,14.63) E31(10.701,13.716) E32(11.615,13.716) E33(12.53,13.716) E34(13.444,13.716) E35(14.359,13.716) E36(15.273,13.716) E37(16.187,13.716) E38(17.102,13.716) E39(18.016,13.716) F4(-16.187,13.716) F5(-15.273,13.716) F6(-14.359,13.716) F7(-13.444,13.716) F8(-12.53,13.716) F9(-11.615,13.716) F10(-10.701,13.716) F11(-9.787,13.716) F12(-8.872,13.716) F13(-7.958,13.716) F14(-7.043,13.716) F15(-6.129,13.716) F16(-5.215,13.716) F17(-4.3,13.716) F18(-3.386,13.716) F19(-2.471,13.716) F20(-1.557,13.716) F21(-0.643,13.716) F22(0.272,13.716) F23(1.186,13.716) F24(2.101,13.716) F25(3.015,13.716) F26(3.929,13.716) F27(4.844,13.716) F28(5.758,13.716) F29(6.673,13.716) F30(7.587,13.716) F31(10.701,12.802) F32(11.615,12.802) F33(12.53,12.802) F34(13.444,12.802) F35(14.359,12.802) F36(15.273,12.802) F37(16.187,12.802) F38(17.102,12.802) F39(18.016,12.802) F40(18.931,12.802) G3(-17.102,12.802) G4(-16.187,12.802) G5(-15.273,12.802) G6(-14.359,12.802) G7(-13.444,12.802) G8(-12.53,12.802) G9(-11.615,12.802) G10(-10.701,12.802) G11(-9.787,12.802) G12(-8.872,12.802) G13(-7.958,12.802) G14(-7.043,12.802) G15(-6.129,12.802) G16(-5.215,12.802) G17(-4.3,12.802) G18(-3.386,12.802) G19(-2.471,12.802) G20(-1.557,12.802) G21(-0.643,12.802) G22(0.272,12.802) G23(1.186,12.802) G24(2.101,12.802) G25(3.015,12.802) G26(3.929,12.802) G27(4.844,12.802) G28(5.758,12.802) G29(6.673,12.802) G30(7.587,12.802) G31(10.701,11.887) G32(11.615,11.887) G33(12.53,11.887) G34(13.444,11.887) G35(14.359,11.887) G36(15.273,11.887) G37(16.187,11.887) G38(17.102,11.887) G39(18.016,11.887) G40(18.931,11.887) H4(-16.187,11.887) H5(-15.273,11.887) H6(-14.359,11.887) H7(-13.444,11.887) H8(-12.53,11.887) H9(-11.615,11.887) H10(-10.701,11.887) H11(-9.787,11.887) H12(-8.872,11.887) H13(-7.958,11.887) H14(-7.043,11.887) H15(-6.129,11.887) H16(-5.215,11.887) H17(-4.3,11.887) H18(-3.386,11.887) H19(-2.471,11.887) H20(-1.557,11.887) H21(-0.643,11.887) H22(0.272,11.887) H23(1.186,11.887) H24(2.101,11.887) H25(3.015,11.887) H26(3.929,11.887) H27(4.844,11.887) H28(5.758,11.887) H29(6.673,11.887) H30(7.587,11.887) H31(10.701,10.973) H32(11.615,10.973) H33(12.53,10.973) H34(13.444,10.973) H35(14.359,10.973) H36(15.273,10.973) H37(16.187,10.973) H38(17.102,10.973) H39(18.016,10.973) H40(18.931,10.973) J3(-17.102,10.973) J4(-16.187,10.973) J5(-15.273,10.973) J6(-14.359,10.973) J7(-13.444,10.973) J8(-12.53,10.973) J9(-11.615,10.973) J10(-10.701,10.973) J11(-9.787,10.973) J12(-8.872,10.973) J13(-7.958,10.973) J14(-7.043,10.973) J15(-6.129,10.973) J16(-5.215,10.973) J17(-4.3,10.973) J18(-3.386,10.973) J19(-2.471,10.973) J20(-1.557,10.973) J21(-0.643,10.973) J22(0.272,10.973) J23(1.186,10.973) J24(2.101,10.973) J25(3.015,10.973) J26(3.929,10.973) J27(4.844,10.973) J28(5.758,10.973) J29(6.673,10.973) J30(7.587,10.973) J31(10.701,10.058) J32(11.615,10.058) J33(12.53,10.058) J34(13.444,10.058) J35(14.359,10.058) J36(15.273,10.058) J37(16.187,10.058) J38(17.102,10.058) J39(18.016,10.058) J40(18.931,10.058) K4(-16.187,10.058) K5(-15.273,10.058) K6(-14.359,10.058) K7(-13.444,10.058) K8(-12.53,10.058) K9(-11.615,10.058) K10(-10.701,10.058) K11(-9.787,10.058) K12(-8.872,10.058) K13(-7.958,10.058) K14(-7.043,10.058) K15(-6.129,10.058) K16(-5.215,10.058) K17(-4.3,10.058) K18(-3.386,10.058) K19(-2.471,10.058) K20(-1.557,10.058) K21(-0.643,10.058) K22(0.272,10.058) K23(1.186,10.058) K24(2.101,10.058) K25(3.015,10.058) K26(3.929,10.058) K27(4.844,10.058) K28(5.758,10.058) K29(6.673,10.058) K30(7.587,10.058) K31(10.701,9.144) K32(11.615,9.144) K33(12.53,9.144) K34(13.444,9.144) K35(14.359,9.144) K36(15.273,9.144) K37(16.187,9.144) K38(17.102,9.144) K39(18.016,9.144) K40(18.931,9.144) L3(-17.102,9.144) L4(-16.187,9.144) L5(-15.273,9.144) L6(-14.359,9.144) L7(-13.444,9.144) L8(-12.53,9.144) L9(-11.615,9.144) L10(-10.701,9.144) L11(-9.787,9.144) L12(-8.872,9.144) L13(-7.958,9.144) L14(-7.043,9.144) L15(-6.129,9.144) L16(-5.215,9.144) L17(-4.3,9.144) L18(-3.386,9.144) L19(-2.471,9.144) L20(-1.557,9.144) L21(-0.643,9.144) L22(0.272,9.144) L23(1.186,9.144) L24(2.101,9.144) L25(3.015,9.144) L26(3.929,9.144) L27(4.844,9.144) L28(5.758,9.144) L29(6.673,9.144) L30(7.587,9.144) L31(10.701,8.23) L32(11.615,8.23) L33(12.53,8.23) L34(13.444,8.23) L35(14.359,8.23) L36(15.273,8.23) L37(16.187,8.23) L38(17.102,8.23) L39(18.016,8.23) L40(18.931,8.23) M4(-16.187,8.23) M5(-15.273,8.23) M6(-14.359,8.23) M7(-13.444,8.23) M8(-12.53,8.23) M9(-11.615,8.23) M10(-10.701,8.23) M11(-9.787,8.23) M12(-8.872,8.23) M13(-7.958,8.23) M14(-7.043,8.23) M15(-6.129,8.23) M16(-5.215,8.23) M17(-4.3,8.23) M18(-3.386,8.23) M19(-2.471,8.23) M20(-1.557,8.23) M21(-0.643,8.23) M22(0.272,8.23) M23(1.186,8.23) M24(2.101,8.23) M25(3.015,8.23) M26(3.929,8.23) M27(4.844,8.23) M28(5.758,8.23) M29(6.673,8.23) M30(7.587,8.23) M32(11.615,7.315) M33(12.53,7.315) M34(13.444,7.315) M35(14.359,7.315) M36(15.273,7.315) M37(16.187,7.315) M38(17.102,7.315) M39(18.016,7.315) M40(18.931,7.315) N3(-17.102,7.315) N4(-16.187,7.315) N5(-15.273,7.315) N6(-14.359,7.315) N7(-13.444,7.315) N8(-12.53,7.315) N33(12.53,6.401) N34(13.444,6.401) N35(14.359,6.401) N36(15.273,6.401) N37(16.187,6.401) N38(17.102,6.401) N39(18.016,6.401) N40(18.931,6.401) P4(-16.187,6.401) P5(-15.273,6.401) P6(-14.359,6.401) P7(-13.444,6.401) P8(-12.53,6.401) P33(12.53,5.486) P34(13.444,5.486) P35(14.359,5.486) P36(15.273,5.486) P37(16.187,5.486) P38(17.102,5.486) P39(18.016,5.486) P40(18.931,5.486) R3(-17.102,5.486) R4(-16.187,5.486) R5(-15.273,5.486) R6(-14.359,5.486) R7(-13.444,5.486) R8(-12.53,5.486) R33(12.53,4.572) R34(13.444,4.572) R35(14.359,4.572) R36(15.273,4.572) R37(16.187,4.572) R38(17.102,4.572) R39(18.016,4.572) R40(18.931,4.572) T4(-16.187,4.572) T5(-15.273,4.572) T6(-14.359,4.572) T7(-13.444,4.572) T8(-12.53,4.572) T33(12.53,3.658) T34(13.444,3.658) T35(14.359,3.658) T36(15.273,3.658) T37(16.187,3.658) T38(17.102,3.658) T39(18.016,3.658) T40(18.931,3.658) U4(-16.187,3.658) U5(-15.273,3.658) U6(-14.359,3.658) U7(-13.444,3.658) U8(-12.53,3.658) U33(12.53,2.743) U34(13.444,2.743) U35(14.359,2.743) U36(15.273,2.743) U37(16.187,2.743) U38(17.102,2.743) U39(18.016,2.743) U40(18.931,2.743) V4(-16.187,2.743) V5(-15.273,2.743) V6(-14.359,2.743) V7(-13.444,2.743) V8(-12.53,2.743) V33(12.53,1.829) V34(13.444,1.829) V35(14.359,1.829) V36(15.273,1.829) V37(16.187,1.829) V38(17.102,1.829) V39(18.016,1.829) V40(18.931,1.829) W4(-16.187,1.829) W5(-15.273,1.829) W6(-14.359,1.829) W7(-13.444,1.829) W8(-12.53,1.829) W33(12.53,0.914) W34(13.444,0.914) W35(14.359,0.914) W36(15.273,0.914) W37(16.187,0.914) W38(17.102,0.914) Y5(-15.273,0.914) Y6(-14.359,0.914) Y7(-13.444,0.914) Y8(-12.53,0.914) Y33(12.53,0) Y34(13.444,0) Y35(14.359,0) Y36(15.273,0) Y37(16.187,0) Y38(17.102,0)
  oval 0.356x0.457 smd: A11(-9.787,18.288) A12(-8.872,18.288) A13(-7.958,18.288) A14(-7.043,18.288) A15(-6.129,18.288) A16(-5.215,18.288) A17(-4.3,18.288) A18(-3.386,18.288) A23(1.186,18.288) A24(2.101,18.288) AU22(2.471,-15.545) AU23(3.386,-15.545) AV15(-3.929,-16.459) AV16(-3.015,-16.459) AV17(-2.101,-16.459) AV18(-1.186,-16.459) AV19(-0.272,-16.459) AV20(0.643,-16.459) AV21(1.557,-16.459) AV22(2.471,-16.459) AV23(3.386,-16.459) AV26(6.129,-16.459) AV27(7.043,-16.459) AV30(9.787,-16.459) AV31(10.701,-16.459) AV32(11.615,-16.459) AV33(12.53,-16.459) AV34(13.444,-16.459) AV35(14.359,-16.459) AV36(15.273,-16.459) AW5(-15.273,-16.459) AW6(-14.359,-16.459) AW7(-13.444,-16.459) AW8(-12.53,-16.459) AW15(-3.929,-17.374) AW16(-3.015,-17.374) AW17(-2.101,-17.374) AW18(-1.186,-17.374) AW23(3.386,-17.374) AW24(4.3,-17.374) AW25(5.215,-17.374) AW26(6.129,-17.374) AW27(7.043,-17.374) AW28(7.958,-17.374) AW29(8.872,-17.374) AW30(9.787,-17.374) AW31(10.701,-17.374) AW32(11.615,-17.374) AW33(12.53,-17.374) AW34(13.444,-17.374) AW35(14.359,-17.374) AW36(15.273,-17.374) AY5(-15.273,-17.374) AY6(-14.359,-17.374) AY7(-13.444,-17.374) AY8(-12.53,-17.374) AY9(-11.615,-17.374) AY11(-7.587,-18.288) AY12(-6.673,-18.288) AY13(-5.758,-18.288) AY14(-4.844,-18.288) AY15(-3.929,-18.288) AY16(-3.015,-18.288) AY17(-2.101,-18.288) AY18(-1.186,-18.288) AY23(3.386,-18.288) AY24(4.3,-18.288) AY25(5.215,-18.288) AY26(6.129,-18.288) AY27(7.043,-18.288) AY28(7.958,-18.288) AY29(8.872,-18.288) AY30(9.787,-18.288) AY31(10.701,-18.288) B8(-12.53,17.374) B9(-11.615,17.374) B10(-10.701,17.374) B11(-9.787,17.374) B12(-8.872,17.374) B13(-7.958,17.374) B14(-7.043,17.374) B15(-6.129,17.374) B16(-5.215,17.374) B17(-4.3,17.374) B18(-3.386,17.374) B23(1.186,17.374) B24(2.101,17.374) C10(-10.701,16.459) C11(-9.787,16.459) C18(-3.386,16.459) C19(-2.471,16.459) C20(-1.557,16.459) C21(-0.643,16.459) C22(0.272,16.459) C23(1.186,16.459) C24(2.101,16.459) D18(-3.386,15.545) D19(-2.471,15.545) D20(-1.557,15.545) D21(-0.643,15.545) D22(0.272,15.545) D23(1.186,15.545) E20(-1.557,14.63) E22(0.272,14.63)
  oval 0.457x0.356 smd: AA3(-17.102,0) AA4(-16.187,0) AB3(-17.102,-0.914) AB4(-16.187,-0.914) AB38(17.102,-1.829) AB39(18.016,-1.829) AB40(18.931,-1.829) AC1(-18.931,-1.829) AC2(-18.016,-1.829) AC3(-17.102,-1.829) AC4(-16.187,-1.829) AC38(17.102,-2.743) AC39(18.016,-2.743) AC40(18.931,-2.743) AD1(-18.931,-2.743) AD2(-18.016,-2.743) AD38(17.102,-3.658) AD39(18.016,-3.658) AD40(18.931,-3.658) AE1(-18.931,-3.658) AE2(-18.016,-3.658) AE39(18.016,-4.572) AE40(18.931,-4.572) AF1(-18.931,-4.572) AF2(-18.016,-4.572) AF3(-17.102,-4.572) AF39(18.016,-5.486) AF40(18.931,-5.486) AG1(-18.931,-5.486) AG2(-18.016,-5.486) AG3(-17.102,-5.486) AG39(18.016,-6.401) AG40(18.931,-6.401) AH1(-18.931,-6.401) AH2(-18.016,-6.401) AH39(18.016,-7.315) AH40(18.931,-7.315) AJ1(-18.931,-7.315) AJ2(-18.016,-7.315) AJ39(18.016,-8.23) AJ40(18.931,-8.23) AK1(-18.931,-8.23) AK2(-18.016,-8.23) AK39(18.016,-9.144) AK40(18.931,-9.144) AL1(-18.931,-9.144) AL2(-18.016,-9.144) AL39(18.016,-10.058) AL40(18.931,-10.058) AM1(-18.931,-10.058) AM2(-18.016,-10.058) AM39(18.016,-10.973) AM40(18.931,-10.973) AN1(-18.931,-10.973) AN2(-18.016,-10.973) AN39(18.016,-11.887) AN40(18.931,-11.887) AP1(-18.931,-11.887) AP2(-18.016,-11.887) AP39(18.016,-12.802) AP40(18.931,-12.802) AR1(-18.931,-12.802) AR2(-18.016,-12.802) AR39(18.016,-13.716) AR40(18.931,-13.716) AT1(-18.931,-13.716) AT2(-18.016,-13.716) AT39(18.016,-14.63) AU2(-18.016,-14.63) E1(-18.931,14.63) E2(-18.016,14.63) F1(-18.931,13.716) F2(-18.016,13.716) F3(-17.102,13.716) G1(-18.931,12.802) G2(-18.016,12.802) H1(-18.931,11.887) H2(-18.016,11.887) H3(-17.102,11.887) J1(-18.931,10.973) J2(-18.016,10.973) K1(-18.931,10.058) K2(-18.016,10.058) K3(-17.102,10.058) L1(-18.931,9.144) L2(-18.016,9.144) M1(-18.931,8.23) M2(-18.016,8.23) M3(-17.102,8.23) N1(-18.931,7.315) N2(-18.016,7.315) P1(-18.931,6.401) P2(-18.016,6.401) P3(-17.102,6.401) R1(-18.931,5.486) R2(-18.016,5.486) T1(-18.931,4.572) T2(-18.016,4.572) T3(-17.102,4.572) U1(-18.931,3.658) U2(-18.016,3.658) U3(-17.102,3.658) V1(-18.931,2.743) V2(-18.016,2.743) V3(-17.102,2.743) W1(-18.931,1.829) W2(-18.016,1.829) W3(-17.102,1.829) Y3(-17.102,0.914) Y4(-16.187,0.914)
SMD49-3215-0713H36
  rect 1.549x1.549 smd: 1(0,1.371) 2(0,-1.371)
SMD-ARES4H18
  rect 0.356x0.66 smd: 1(-0.325,-0.599) 2(0.325,-0.599) 3(0.325,0.599) 4(-0.325,0.599)
SMD-OSC38H20
  rect 1.092x0.737 smd: 1(-0.769,-0.495) 2(0.769,-0.495) 3(0.769,0.495) 4(-0.769,0.495)
SOD323AKH38
  rect 0.559x1.016 smd: A(0,1.143) K(0,-1.143)
SOD-523-4H28
  rect 0.559x0.864 smd: 1(0,0.778) 2(0,-0.778)
SOIC8-1H86
  rect 0.635x1.651 smd: 1(-1.905,-3.493) 2(-0.635,-3.493) 3(0.635,-3.493) 4(1.905,-3.493) 5(1.905,3.493) 6(0.635,3.493) 7(-0.635,3.493) 8(-1.905,3.493)
SOIC8-G3530H63
  rect 0.635x1.651 smd: 1(-1.905,-2.555) 2(-0.635,-2.555) 3(0.635,-2.555) 4(1.905,-2.555) 5(1.905,2.555) 6(0.635,2.555) 7(-0.635,2.555) 8(-1.905,2.555)
  rect 3.505x2.997 smd: 9(0,0)
SOIC16-6H105
  rect 0.635x1.651 smd: 1(-4.445,-4.718) 2(-3.175,-4.718) 3(-1.905,-4.718) 4(-0.635,-4.718) 5(0.635,-4.718) 6(1.905,-4.718) 7(3.175,-4.718) 8(4.445,-4.718) 9(4.445,4.718) 10(3.175,4.718) 11(1.905,4.718) 12(0.635,4.718) 13(-0.635,4.718) 14(-1.905,4.718) 15(-3.175,4.718) 16(-4.445,4.718)
SON14J3020-G2610H32
  rect 0.025x0.025 smd: 1(1.2,1.105) 6(-0.8,1.105) 9(-0.8,-1.105) 14(1.2,-1.105)
  custom 0.151x0.151 smd: 2(0.8,1.105) 7(-1.2,1.105) 8(-1.2,-1.105) 13(0.8,-1.105)
  rect 0.203x0.813 smd: 3(0.4,1.105) 4(0,1.105) 5(-0.4,1.105) 10(-0.4,-1.105) 11(0,-1.105) 12(0.4,-1.105)
  rect 2.591x0.889 smd: 15(0,0)
SOT23-2D4-123H44
  custom 0.191x0.191 smd: 1(0,0.953) 2(-0.984,-0.953) 3(0.984,-0.953)
SOT23-2D4-312H48
  custom 0.191x0.191 smd: 1(-0.984,-0.953) 2(0.984,-0.953) 3(0,0.953)
SOT23CBE2D4H44
  custom 0.191x0.191 smd: B(-0.984,-0.953) C(0,0.953) E(0.984,-0.953)
SOT23DGS2D4H44
  custom 0.191x0.191 smd: D(0,0.953) G(-0.984,-0.953) S(0.984,-0.953)
SOT23DGS2D4H48
  custom 0.191x0.191 smd: D(0,0.953) G(-0.984,-0.953) S(0.984,-0.953)
SOT23DGS2D8H50
  custom 0.254x0.254 smd: D(0,1.118) G(-1.016,-1.118) S(1.016,-1.118)
SOT-6-1H58
  rect 0.584x1.219 smd: 1(-0.95,-1.194) 2(0,-1.194) 3(0.95,-1.194) 4(0.95,1.194) 5(0,1.194) 6(-0.95,1.194)
SOT-6H58
  rect 0.584x1.016 smd: 1(-0.953,-1.346) 2(0,-1.346) 3(0.953,-1.346) 4(0.953,1.346) 5(0,1.346) 6(-0.953,1.346)
SOT-23-5H51
  rect 0.508x1.524 smd: 1(-0.95,-1.143) 2(0,-1.143) 3(0.95,-1.143) 4(0.95,1.143) 5(-0.95,1.143)
SOT-23-5H56
  rect 0.508x1.524 smd: 1(-0.95,-1.143) 2(0,-1.143) 3(0.95,-1.143) 4(0.95,1.143) 5(-0.95,1.143)
SOT-23-5H58
  rect 0.508x1.524 smd: 1(-0.95,-1.143) 2(0,-1.143) 3(0.95,-1.143) 4(0.95,1.143) 5(-0.95,1.143)
SOT-23-9H44
  custom 0.178x0.178 smd: 1(-0.95,-0.999) 2(0.95,-0.999) 3(0,0.999)
SOT-363-1H44
  rect 0.356x1.219 smd: 1(-0.65,-0.922) 2(0,-0.922) 3(0.65,-0.922) 4(0.65,0.922) 5(0,0.922) 6(-0.65,0.922)
SOT-363H44
  rect 0.406x1.016 smd: 1(-0.65,-0.94) 2(0,-0.94) 3(0.65,-0.94) 4(0.65,0.94) 5(0,0.94) 6(-0.65,0.94)
STF256R109H99
  round 6.502 hole 2.769: 1(0,0)
TPAD28
  round 0.711 smd: 1(0,0)
TPAD30
  round 0.762 smd: 1(0,0)
unnamed#2
  round 1.016 smd: (0,0)
unnamed#3
  round 8.153 smd: 1(0,0)
VDS075W-D307-00A3F2B
  round 1.448 hole 1.041: 1(4.33,1.98) 2(2.04,1.98) 3(-0.25,1.98) 4(-2.54,1.98) 5(-4.83,1.98) 6(5.475,0) 7(3.185,0) 8(0.895,0) 9(-1.395,0) 10(-3.685,0) 11(4.33,-1.98) 12(2.04,-1.98) 13(-0.25,-1.98) 14(-2.54,-1.98) 15(-4.83,-1.98)
  round 3.607 hole 3.2: 16(-12.495,0) 17(12.495,0)
W4202VT-203P-D
  round 0.254 hole 3.023 unplated: (-8.9,0)
  round 2.184 hole 1.422: 1(-4.2,5.04) 2(0,5.04) 3(4.2,5.04) 4(-4.2,-0.46) 5(0,-0.46) 6(4.2,-0.46)
WK21921-151146-7H
  round 0.254 hole 1.219 unplated: (-11.2,0)
  round 0.254 hole 1.702 unplated: (10.8,0)
  rect 0.813x1.194 smd: 1(6.925,4.6) 2(4.425,4.6) 3(1.925,4.6) 4(-0.575,4.6) 5(-3.075,4.6) 6(-5.575,4.6) 7(-8,4.6) 8(-9.7,4.6) 9(9.425,4.6)
  rect 1.905x1.6 smd: 10(-13.17,2.35)
  rect 1.499x1.702 smd: 11(-13.39,-4.3)
  rect 1.194x2.311 smd: 12(-13.75,-8.75) 13(13.75,-8.75)

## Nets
1V_CPU_CORE: CPU1.A25 CPU1.A26 CPU1.A27 CPU1.A28 CPU1.A29 CPU1.A30 CPU1.AJ11 CPU1.AJ12 CPU1.AJ13 CPU1.AJ14 CPU1.AJ15 CPU1.AJ16 CPU1.AJ17 CPU1.AJ18 CPU1.AJ19 CPU1.AJ20 CPU1.AJ21 CPU1.AJ25 CPU1.AJ26 CPU1.AJ27 CPU1.AJ28 CPU1.AJ29 CPU1.AK21 CPU1.B25 CPU1.B27 CPU1.B29 CPU1.B31 CPU1.B32 CPU1.B33 CPU1.B34 CPU1.B35 CPU1.B36 CPU1.B37 CPU1.C25 CPU1.C26 CPU1.C27 CPU1.C28 CPU1.C29 CPU1.C30 CPU1.C32 CPU1.C34 CPU1.C36 CPU1.D25 CPU1.D27 CPU1.D29 CPU1.D31 CPU1.D32 CPU1.D33 CPU1.D34 CPU1.D35 CPU1.D36 CPU1.E24 CPU1.E25 CPU1.E26 CPU1.E27 CPU1.E28 CPU1.E29 CPU1.E30 CPU1.E32 CPU1.E34 CPU1.E36 CPU1.F23 CPU1.F24 CPU1.F25 CPU1.F27 CPU1.F29 CPU1.F31 CPU1.F32 CPU1.F33 CPU1.F34 CPU1.F35 CPU1.F37 CPU1.G23 CPU1.G24 CPU1.G25 CPU1.G26 CPU1.G27 CPU1.G28 CPU1.G29 CPU1.G30 CPU1.G32 CPU1.G34 CPU1.G35 CPU1.H22 CPU1.H23 CPU1.H25 CPU1.H27 CPU1.H29 CPU1.H31 CPU1.H32 CPU1.H33 CPU1.H34 CPU1.J21 CPU1.J22 CPU1.J23 CPU1.J24 CPU1.J25 CPU1.J26 CPU1.J27 CPU1.J28 CPU1.J29 CPU1.J30 CPU1.J31 CPU1.J33 CPU1.J35 CPU1.K16 CPU1.K18 CPU1.K20 CPU1.K21 CPU1.K23 CPU1.K25 CPU1.K27 CPU1.K29 CPU1.K31 CPU1.K32 CPU1.K34 CPU1.L14 CPU1.L15 CPU1.L16 CPU1.L17 CPU1.L18 CPU1.L19 CPU1.L20 CPU1.L21 CPU1.L22 CPU1.L23 CPU1.L24 CPU1.L25 CPU1.L26 CPU1.L27 CPU1.L28 CPU1.L29 CPU1.L30 CPU1.L31 CPU1.L33 CPU1.M13 CPU1.M14 CPU1.M16 CPU1.M18 CPU1.M20 CPU1.M22 CPU1.M24 CPU1.M26 CPU1.M28 CPU1.M30 CPU1.M32 PC1001.1 PC1002.1 PC1004.1 PC1005.1 PC1006.1 PC1007.1 PC1008.1 PC1009.1 PC1010.1 PC1011.1 PC1012.1 PC1018.1 PC1019.1 PC1020.1 PC1021.1 PC1022.1 PC1023.1 PG4502.1 PG4504.1 PG4506.1 PG4508.1 PL4501.2 PL4502.2 PL4503.2 PL4504.2 PR4416.1 PT4502.1 PT4503.1 PT4505.1 PT4507.1 PT4508.1
1V_CPU_GT: CPU1.AA34 CPU1.AA35 CPU1.AA36 CPU1.AA37 CPU1.AA38 CPU1.AB33 CPU1.AB34 CPU1.G36 CPU1.G37 CPU1.G38 CPU1.G39 CPU1.G40 CPU1.H36 CPU1.H38 CPU1.H40 CPU1.J36 CPU1.J37 CPU1.J38 CPU1.J39 CPU1.J40 CPU1.K36 CPU1.K38 CPU1.K40 CPU1.L34 CPU1.L35 CPU1.L36 CPU1.L37 CPU1.L38 CPU1.L39 CPU1.L40 CPU1.M33 CPU1.M34 CPU1.M36 CPU1.M38 CPU1.M40 CPU1.N34 CPU1.N35 CPU1.N36 CPU1.N37 CPU1.N38 CPU1.N39 CPU1.N40 CPU1.P33 CPU1.P34 CPU1.P36 CPU1.P38 CPU1.P40 CPU1.R34 CPU1.R35 CPU1.R36 CPU1.R37 CPU1.R38 CPU1.R39 CPU1.R40 CPU1.T33 CPU1.T34 CPU1.T36 CPU1.T38 CPU1.T40 CPU1.U34 CPU1.U35 CPU1.U36 CPU1.U37 CPU1.U38 CPU1.U39 CPU1.U40 CPU1.V33 CPU1.V34 CPU1.V36 CPU1.V38 CPU1.V40 CPU1.W34 CPU1.W35 CPU1.W36 CPU1.W37 CPU1.W38 CPU1.Y33 CPU1.Y34 CPU1.Y36 CPU1.Y38 PC1034.1 PC1035.1 PC1036.1 PC1037.1 PC1038.1 PC1039.1 PC1040.1 PC1041.1 PC1042.1 PC1043.1 PC1044.1 PC1045.1 PC1058.1 PG4602.1 PG4604.1 PL4601.2 PL4602.2 PR4445.1 PT4602.1 PT4603.1 PT4604.1 PT4605.1
1V_PCH_SB: C2113.1 C2114.1 C2115.1 C2116.1 C2117.1 C2120.1 C2121.1 C2122.1 C2123.1 C2124.1 C2127.1 C2128.1 C2129.1 L2101.1 L2102.1 PR5117.2 PR5118.2 PR5119.2 PR5120.2 PR5121.2 PR5122.2 PR5123.2 PR5124.2 PR5125.2 PR5126.2 PR5127.2 PR5128.2 PR5129.2 PR5130.2 PR5131.2 PR5132.2 PR5133.2 PR5134.2 PR5135.2 Q801.D Q2406.1 R803.1 R9909.1 SB1.AA22 SB1.AA23 SB1.AB20 SB1.AB22 SB1.AB23 SB1.AB27 SB1.AB28 SB1.AB30 SB1.AD20 SB1.AD23 SB1.AD27 SB1.AD28 SB1.AD30 SB1.AD31 SB1.AE17 SB1.AF23 SB1.AF27 SB1.AF30 SB1.AF31 SB1.AG31 SB1.B1 SB1.B2 SB1.B3 SB1.C1 SB1.C2 SB1.D1 SB1.E1 SB1.U26 SB1.U29 SB1.V19 SB1.V25 SB1.V27 SB1.V28 SB1.V30 SB1.V31 SB1.W19 SB1.W20 SB1.W22 SB1.W23 SB1.W31
1V_VCCA_XTAL: C2118.1 C2119.1 L2102.2 SB1.P2 SB1.P3
1V_VCCAMPHYPLL: C2110.1 C2111.1 C2112.1 L2101.2 SB1.C49 SB1.D49 SB1.E49
1V_VCCDSW: C2125.1 SB1.BG45 SB1.BG46
5V_AUD_S5: C2704.1 C2705.1 C2708.1 C2709.1 D2701.1 L2701.1 R2701.1 U2701.24
5V_DDC_HDMI: C5609.1 D5601.K RN5601.1(A) RN5601.2(A)
5V_DISPLAY_S0: C5906.1 C5907.1 D5601.A F5901.1 Q5901.D U5602.3 U5901.17
5V_DISPLAY_SFR_G: Q5901.G R5918.2 R5919.1
5V_HDMI_CONN: HDMI1.18 U5602.2
5V_S0: C4207.1 C4208.1 C6013.1 C9902.1 C9907.1 C9908.1 C9909.1 C9910.1 C9911.1 PR4712.2 Q2402.4 R6418.1 R6419.1 SATAP1.2 U4201.13 U4201.14
5V_S5: C3201.1 C3805.1 C3901.1 C4203.1 L2701.2 PC5202.1 PR4401.1 PR4925.2 PR4927.2 PR4929.2 PR4933.2 PR4934.2 PR4936.2 PR4937.2 PR4938.2 PR4939.2 PR4940.2 PR4945.2 PR4946.2 PR4947.2 PR4948.2 PR4949.2 PR5001.1 PR5002.2 PR5115.2 PU5201.6 Q5901.S R2419.2 R2468.1 R3816.2 R4301.1 R6409.1 R6413.1 U3201.5 U3801.5 U3901.5 U4201.1 U4201.2 U4201.4
5V_USB_FRONT: R3811.1 TC3801.1 U3801.1 UC3801.1 USB3F1.1 USB3F2.1
5V_USB_REAR: TC3901.1 U3901.1 UC3901.1 USB2R1.1 USB2R1.5
5V_USB_RJ45: RJ45R1.1 RJ45R1.5 TC3201.1 U3201.1 UC3203.1
5V_VGA_CONN: F5901.2 RN5901.1(A) RN5901.2(A) VGA1.9
12V_CPU: ATX2.3 ATX2.4 C4220.1 C4221.1 C4225.1 C4303.1 D4301.K PC4501.1 PC4502.1 PC4506.1 PC4507.1 PC4511.1 PC4512.1 PC4516.1 PC4517.1 PC4601.1 PC4602.1 PC4606.1 PC4607.1 PR4402.1 PR4701.2 PR4702.2 PR4703.2 PR4704.2 PR4705.2 PR4706.2 PT4501.1 PT4504.1 PT4506.1 PT4601.1 PU4501.5 PU4501.6 PU4501.7 PU4501.8 PU4505.5 PU4505.6 PU4505.7 PU4505.8 PU4509.5 PU4509.6 PU4509.7 PU4509.8 PU4513.5 PU4513.6 PU4513.7 PU4513.8 PU4601.5 PU4601.6 PU4601.7 PU4601.8 PU4604.5 PU4604.6 PU4604.7 PU4604.8 Q4206.S R2402.1 R4222.1
12V_CPU_N: C4224.1 C4225.2 Q4206.G R4223.2
12V_CPU_S0: C4222.1 C4223.1 PR4525.1 PR4526.1 PR4527.1 PR4528.1 PR4808.1 Q4206.D R5918.1
12V_S0: C6014.1 C9106.1 C9310.1 C9405.1 FANC1.2 FANS1.2 PR4613.1 PR4614.1 Q9101.G R2601.1 R2615.1 R4203.1 SATAP1.1 SATAP1.4 SLOT1.A2 SLOT1.A3 SLOT1.B1 SLOT1.B2 SLOT1.B3 SLOT2.A2 SLOT2.A3 SLOT2.B1 SLOT2.B2 SLOT2.B3 U4204.5 U4204.6 U4204.7 U4204.8
12V_S5: ATX1.5 ATX1.6 C4218.1 C4304.1 D4302.K PL4903.1 PL4904.1 PL4905.1 PL5002.2 PL5003.2 PL5104.2 PL5105.2 R804.1 R807.1 R2466.1 R2467.1 R4206.1 R4220.1 U4204.1 U4204.2 U4204.3
12VBDC_EN_2: Q4205.C R4220.2 R4221.1
12VBDC_EN_3: C4218.2 C4219.1 R4221.2 U4204.4
12VCPU_EN_2: Q4207.C R4222.2 R4223.1
+12V_PG_U29: R4207.1 U4202.5
AGND: AUD1.1 AUD1.4 AUD1.24 AUD1.34 AUD1.G1 AUD1.G2 AUD1.G3 AUD1.G4 C2701.1 C2703.2 C2704.2 C2705.2 C2706.2 C2707.2 C2708.2 C2709.2 C2710.2 C2719.2 C2720.2 C2903.2 C2906.2 C2907.2 C3003.2 C3004.2 C3005.2 C3006.2 C3009.2 C3010.2 HPMIC1.3 HPMIC1.5 HPMIC1.7 HPMIC1.8 Q2901.1 Q2901.4 Q3001.1 Q3001.4 R2701.2 R2705.2 R2708.2 R2907.2 R2909.2 R3003.2 R3004.2 R3007.2 R3009.2 R3015.2 R3016.2 R9929.2 R9930.2 U2701.26 U2701.35 U2701.38
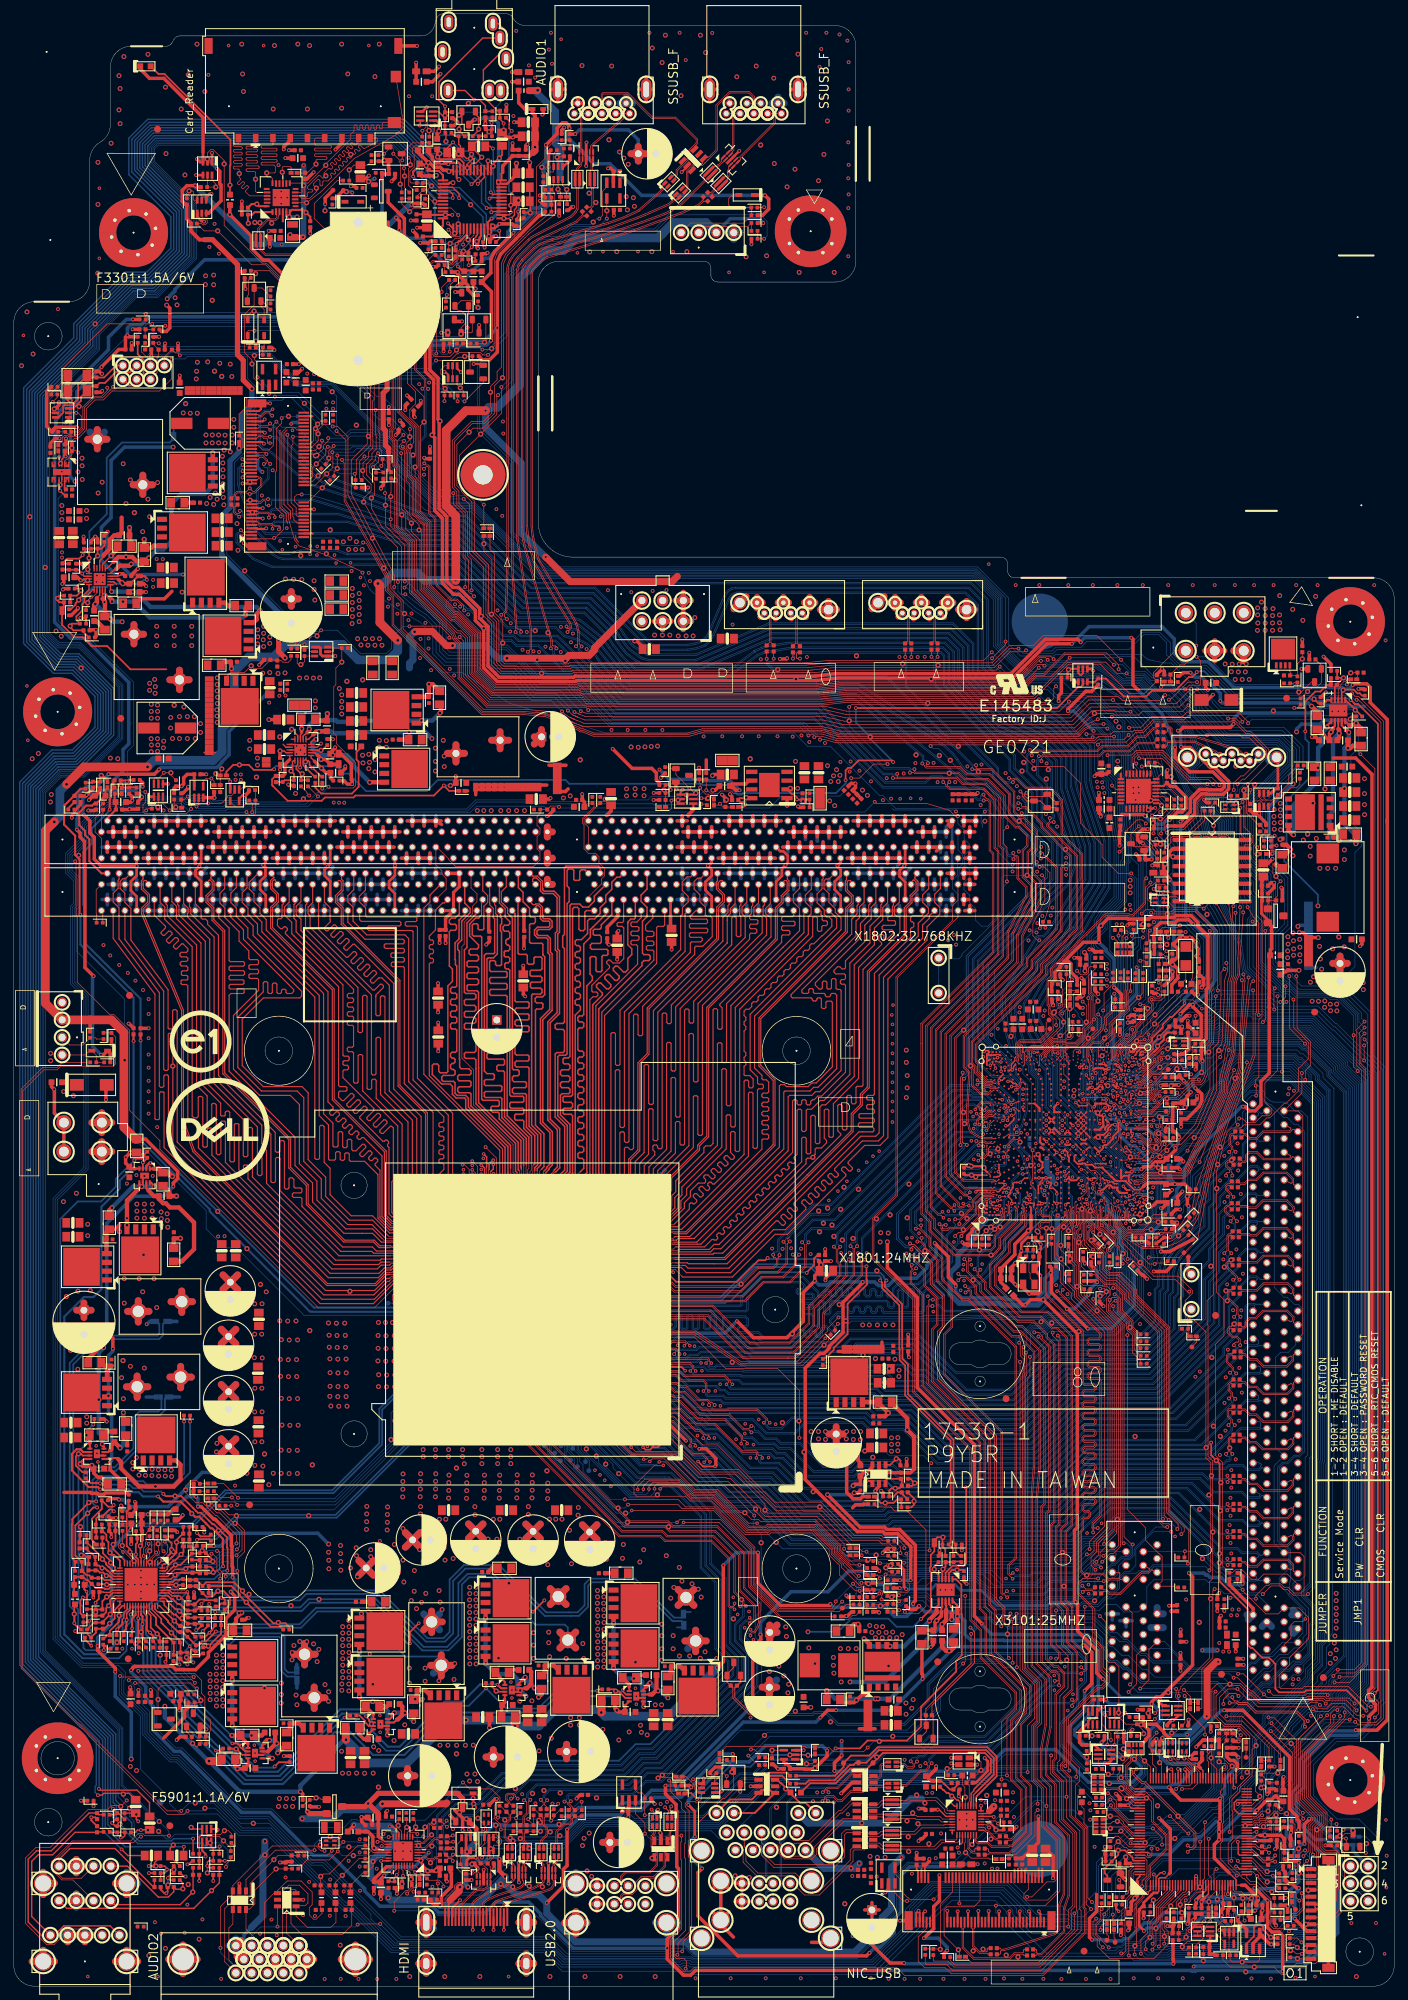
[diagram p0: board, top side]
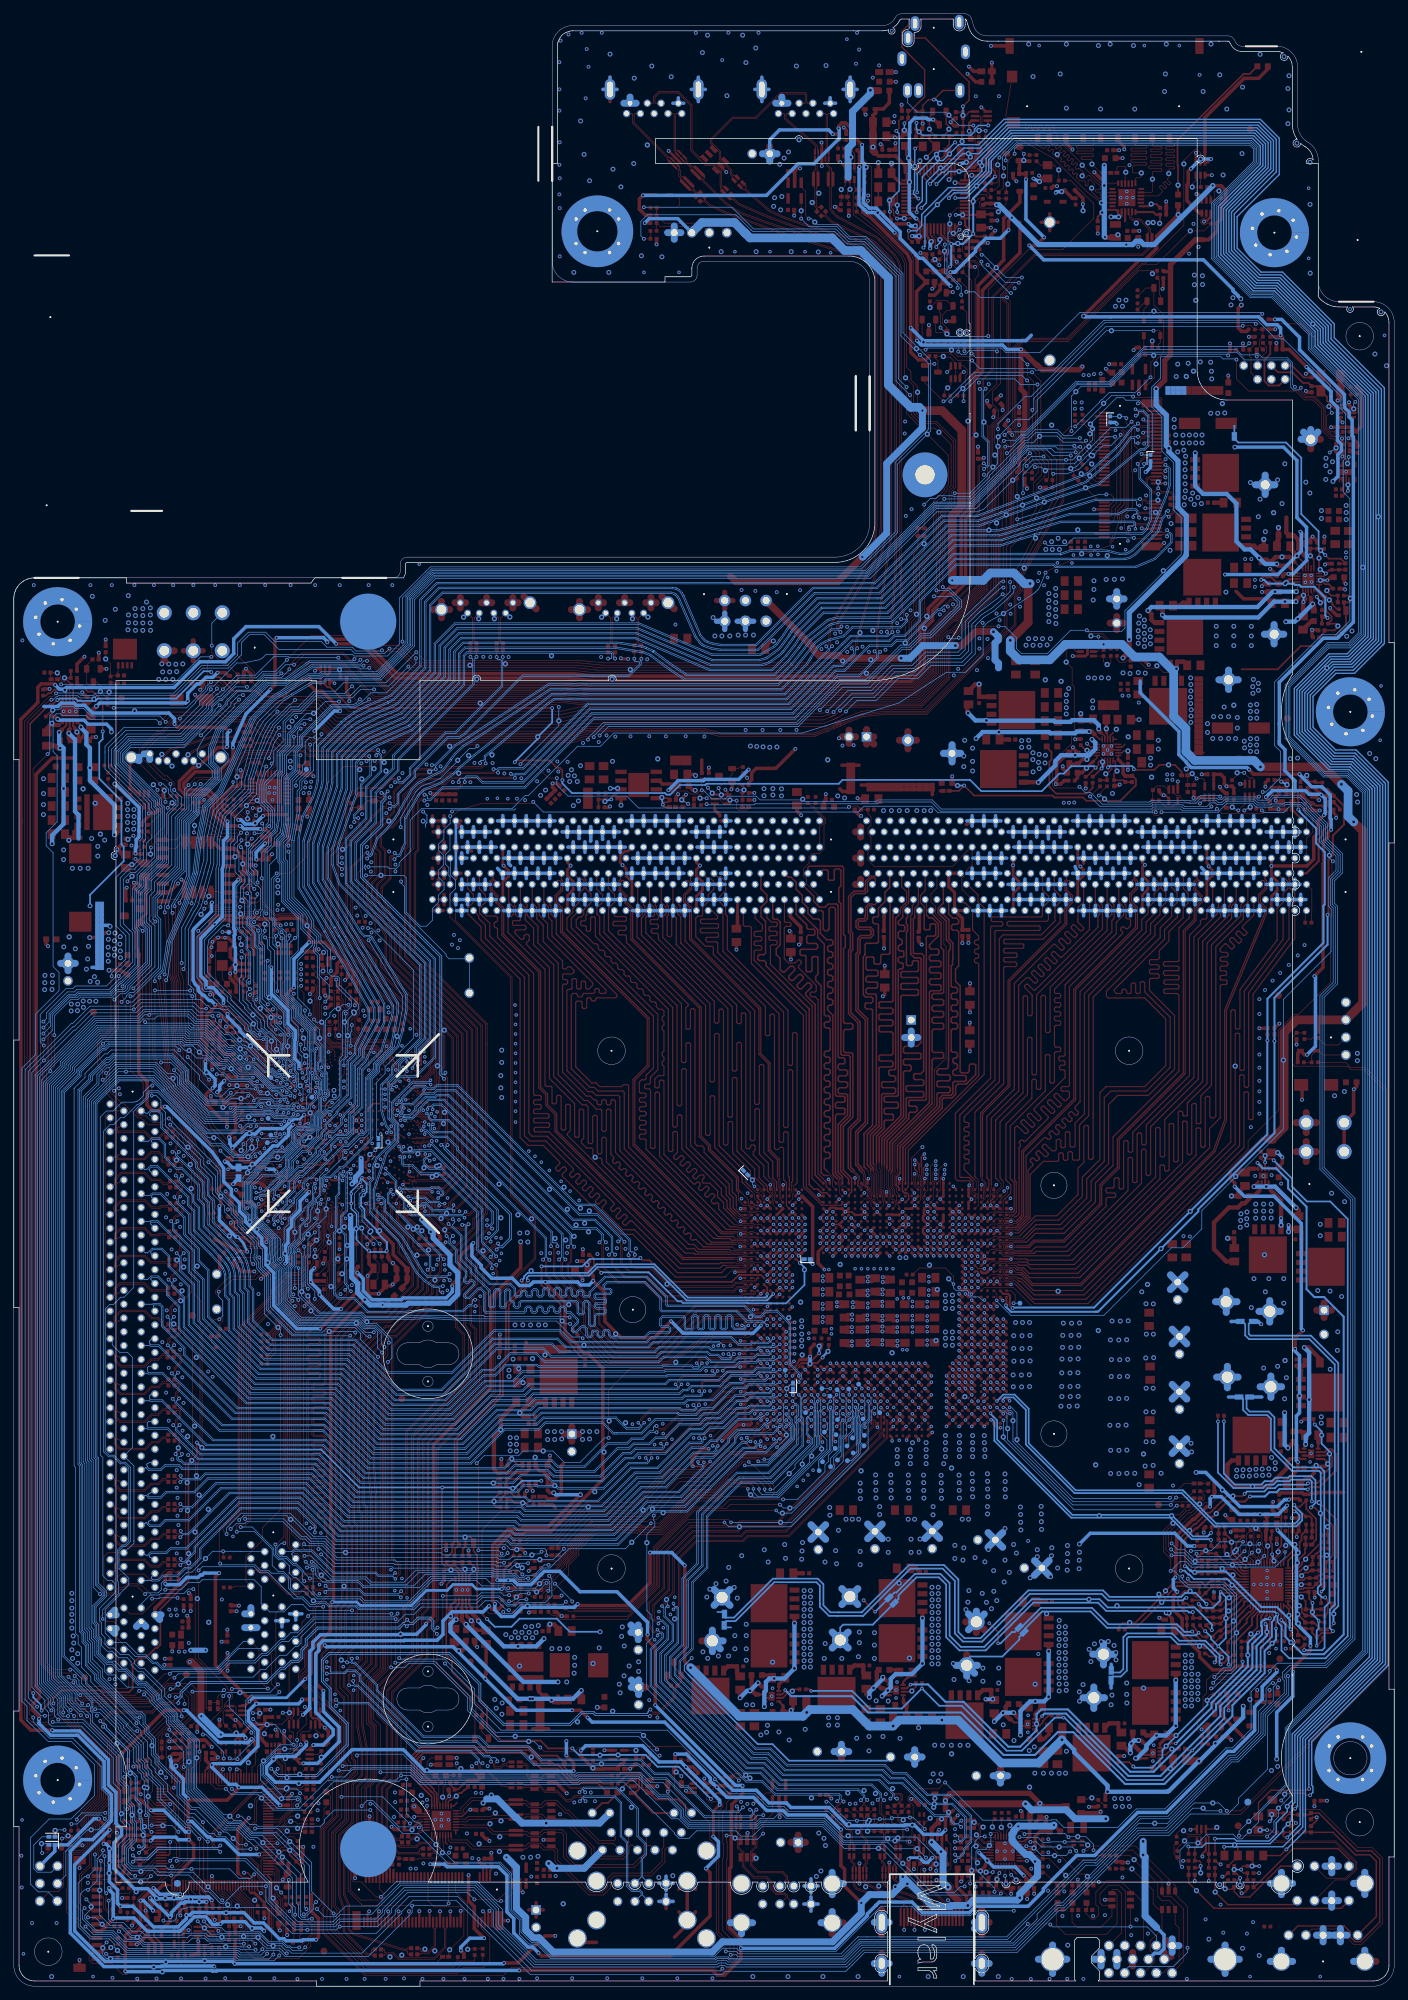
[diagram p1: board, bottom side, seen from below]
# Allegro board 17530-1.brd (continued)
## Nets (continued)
GND: ATX1.2 ATX1.3 ATX2.1 ATX2.2 BT2501.2 C402.2 C403.2 C601.2 C603.2 C801.2 C802.2 C804.2 C805.2 C806.2 C807.2 C808.2 C1025.2 C1026.2 C1027.2 C1028.2 C1029.2 C1030.2 C1031.2 C1032.2 C1033.2 C1101.2 C1102.2 C1103.2 C1104.2 C1105.2 C1106.2 C1107.2 C1108.2 C1109.2 C1110.2 C1201.2 C1202.2 C1203.2 C1204.2 C1205.2 C1206.2 C1207.2 C1208.2 C1210.2 C1211.2 C1212.2 C1213.2 C1801.2 C1802.2 C1803.2 C1804.2 C2006.2 C2007.2 C2101.2 C2102.2 C2103.2 C2104.2 C2105.2 C2106.2 C2107.2 C2108.2 C2109.2 C2110.2 C2111.2 C2112.2 C2113.2 C2114.2 C2115.2 C2116.2 C2117.2 C2118.2 C2119.2 C2120.2 C2121.2 C2122.2 C2123.2 C2124.2 C2125.2 C2126.2 C2127.2 C2128.2 C2129.2 C2405.2 C2406.2 C2407.2 C2408.2 C2411.2 C2412.2 C2413.2 C2414.2 C2415.2 C2416.2 C2417.2 C2418.2 C2419.2 C2420.2 C2421.2 C2422.2 C2423.2 C2424.2 C2425.2 C2426.2 C2501.2 C2711.2 C2712.2 C2713.2 C2714.2 C2715.2 C2717.2 C2718.2 C2719.1 C2720.1 C2721.2 C2722.2 C3101.2 C3102.2 C3103.2 C3104.2 C3105.2 C3106.2 C3107.2 C3108.2 C3111.2 C3112.2 C3113.2 C3114.2 C3117.2 C3118.2 C3119.2 C3201.2 C3301.2 C3302.2 C3303.2 C3304.2 C3305.2 C3306.2 C3307.2 C3805.2 C3806.2 C3807.2 C3901.2 C4007.2 C4008.2 C4009.2 C4010.2 C4011.2 C4012.2 C4013.2 C4201.2 C4202.2 C4203.2 C4204.2 C4205.2 C4206.2 C4207.2 C4208.2 C4209.2 C4211.2 C4212.2 C4219.2 C4220.2 C4221.2 C4222.2 C4223.2 C4224.2 C4226.2 C4227.2 C4301.2 C4302.2 C4303.2 C4304.2 C5101.2 C5609.2 C5610.2 C5611.2 C5901.2 C5902.2 C5903.1 C5904.2 C5905.2 C5906.2 C5907.2 C5908.2 C5909.2 C5916.2 C5917.2 C5918.2 C5919.2 C5920.2 C5921.2 C5922.2 C5923.2 C6013.2 C6014.2 C6201.2 C6203.2 C6205.2 C6206.2 C6213.2 C6214.2 C6215.2 C6301.2 C6302.2 C6303.2 C6304.2 C6307.2 C6308.2 C6309.2 C6310.2 C6402.2 C6403.2 C6404.2 C9101.2 C9102.2 C9103.2 C9104.2 C9105.2 C9106.2 C9310.2 C9311.2 C9312.2 C9403.2 C9404.2 C9405.2 C9410.2 C9411.2 C9901.2 C9902.2 C9903.2 C9904.2 C9905.2 C9907.2 C9908.2 C9909.2 C9910.2 C9911.2 CPU1.A4 CPU1.A7 CPU1.A11 CPU1.A13 CPU1.A15 CPU1.A17 CPU1.A24 CPU1.AA3 CPU1.AA8 CPU1.AA33 CPU1.AB5 CPU1.AB39 CPU1.AC3 CPU1.AC6 CPU1.AC33 CPU1.AC34 CPU1.AC35 CPU1.AD1 CPU1.AD4 CPU1.AD6 CPU1.AD7 CPU1.AD8 CPU1.AD33 CPU1.AD36 CPU1.AD37 CPU1.AD38 CPU1.AD39 CPU1.AD40 CPU1.AE3 CPU1.AE5 CPU1.AE8 CPU1.AE33 CPU1.AE36 CPU1.AF1 CPU1.AF5 CPU1.AF8 CPU1.AF33 CPU1.AF36 CPU1.AF37 CPU1.AF40 CPU1.AG1 CPU1.AG2 CPU1.AG3 CPU1.AG4 CPU1.AG5 CPU1.AG8 CPU1.AG33 CPU1.AG36 CPU1.AH5 CPU1.AH8 CPU1.AH33 CPU1.AH36 CPU1.AH37 CPU1.AH38 CPU1.AH39 CPU1.AH40 CPU1.AJ1 CPU1.AJ4 CPU1.AJ5 CPU1.AJ8 CPU1.AJ24 CPU1.AJ30 CPU1.AJ31 CPU1.AJ32 CPU1.AJ33 CPU1.AJ34 CPU1.AJ35 CPU1.AJ36 CPU1.AK5 CPU1.AK6 CPU1.AK7 CPU1.AK8 CPU1.AK9 CPU1.AK10 CPU1.AK12 CPU1.AK13 CPU1.AK15 CPU1.AK16 CPU1.AK17 CPU1.AK18 CPU1.AK19 CPU1.AK20 CPU1.AK22 CPU1.AK23 CPU1.AK25 CPU1.AK26 CPU1.AK27 CPU1.AK28 CPU1.AK29 CPU1.AK30 CPU1.AK36 CPU1.AK37 CPU1.AK40 CPU1.AL1 CPU1.AL2 CPU1.AL3 CPU1.AL4 CPU1.AL5 CPU1.AL11 CPU1.AL14 CPU1.AL21 CPU1.AL24 CPU1.AL27 CPU1.AL30 CPU1.AL36 CPU1.AM5 CPU1.AM11 CPU1.AM14 CPU1.AM17 CPU1.AM19 CPU1.AM24 CPU1.AM27 CPU1.AM30 CPU1.AM31 CPU1.AM32 CPU1.AM33 CPU1.AM34 CPU1.AM35 CPU1.AM36 CPU1.AM37 CPU1.AM38 CPU1.AM39 CPU1.AM40 CPU1.AN1 CPU1.AN4 CPU1.AN5 CPU1.AN6 CPU1.AN7 CPU1.AN8 CPU1.AN9 CPU1.AN10 CPU1.AN11 CPU1.AN14 CPU1.AN16 CPU1.AN19 CPU1.AN22 CPU1.AN23 CPU1.AN24 CPU1.AN27 CPU1.AN30 CPU1.AN36 CPU1.AP5 CPU1.AP11 CPU1.AP14 CPU1.AP24 CPU1.AP27 CPU1.AP30 CPU1.AP36 CPU1.AP37 CPU1.AP40 CPU1.AR1 CPU1.AR2 CPU1.AR3 CPU1.AR4 CPU1.AR5 CPU1.AR11 CPU1.AR14 CPU1.AR16 CPU1.AR17 CPU1.AR18 CPU1.AR19 CPU1.AR20 CPU1.AR21 CPU1.AR22 CPU1.AR23 CPU1.AR24 CPU1.AR27 CPU1.AR30 CPU1.AR31 CPU1.AR32 CPU1.AR33 CPU1.AR34 CPU1.AR35 CPU1.AR36 CPU1.AT5 CPU1.AT6 CPU1.AT7 CPU1.AT8 CPU1.AT9 CPU1.AT10 CPU1.AT11 CPU1.AT12 CPU1.AT13 CPU1.AT14 CPU1.AT15 CPU1.AT17 CPU1.AT24 CPU1.AT25 CPU1.AT26 CPU1.AT27 CPU1.AT28 CPU1.AT29 CPU1.AT30 CPU1.AT31 CPU1.AT32 CPU1.AT34 CPU1.AT36 CPU1.AT37 CPU1.AT38 CPU1.AT39 CPU1.AT40 CPU1.AU1 CPU1.AU4 CPU1.AU5 CPU1.AU7 CPU1.AU25 CPU1.AU30 CPU1.AU34 CPU1.AU39 CPU1.AU40 CPU1.AV2 CPU1.AV5 CPU1.AV9 CPU1.AV26 CPU1.AV28 CPU1.AV30 CPU1.AV34 CPU1.AV38 CPU1.AV39 CPU1.AW3 CPU1.AW5 CPU1.AW9 CPU1.AW30 CPU1.AW32 CPU1.AW34 CPU1.AW36 CPU1.AW38 CPU1.AY5 CPU1.AY7 CPU1.AY9 CPU1.AY27 CPU1.AY30 CPU1.B6 CPU1.B24 CPU1.B26 CPU1.B28 CPU1.B30 CPU1.B38 CPU1.C2 CPU1.C5 CPU1.C8 CPU1.C10 CPU1.C12 CPU1.C14 CPU1.C16 CPU1.C18 CPU1.C20 CPU1.C22 CPU1.C24 CPU1.C31 CPU1.C33 CPU1.C35 CPU1.C37 CPU1.D4 CPU1.D7 CPU1.D24 CPU1.D26 CPU1.D28 CPU1.D30 CPU1.D37 CPU1.D39 CPU1.D40 CPU1.E3 CPU1.E6 CPU1.E9 CPU1.E11 CPU1.E13 CPU1.E15 CPU1.E17 CPU1.E19 CPU1.E21 CPU1.E23 CPU1.E31 CPU1.E33 CPU1.E35 CPU1.E37 CPU1.F1 CPU1.F4 CPU1.F7 CPU1.F10 CPU1.F22 CPU1.F26 CPU1.F28 CPU1.F30 CPU1.F36 CPU1.F40 CPU1.G3 CPU1.G6 CPU1.G11 CPU1.G13 CPU1.G15 CPU1.G17 CPU1.G19 CPU1.G22 CPU1.G31 CPU1.G33 CPU1.H1 CPU1.H4 CPU1.H7 CPU1.H9 CPU1.H11 CPU1.H12 CPU1.H21 CPU1.H24 CPU1.H26 CPU1.H28 CPU1.H30 CPU1.H35 CPU1.H37 CPU1.H39 CPU1.J3 CPU1.J6 CPU1.J10 CPU1.J12 CPU1.J16 CPU1.J18 CPU1.J20 CPU1.J32 CPU1.J34 CPU1.K1 CPU1.K4 CPU1.K7 CPU1.K14 CPU1.K15 CPU1.K17 CPU1.K19 CPU1.K22 CPU1.K24 CPU1.K26 CPU1.K28 CPU1.K30 CPU1.K33 CPU1.K35 CPU1.K37 CPU1.K39 CPU1.L3 CPU1.L6 CPU1.L9 CPU1.L11 CPU1.L13 CPU1.L32 CPU1.M1 CPU1.M4 CPU1.M7 CPU1.M10 CPU1.M12 CPU1.M15 CPU1.M17 CPU1.M19 CPU1.M21 CPU1.M23 CPU1.M25 CPU1.M27 CPU1.M29 CPU1.M35 CPU1.M37 CPU1.M39 CPU1.N3 CPU1.N6 CPU1.N8 CPU1.N33 CPU1.P1 CPU1.P4 CPU1.P35 CPU1.P37 CPU1.P39 CPU1.R3 CPU1.R6 CPU1.R8 CPU1.R33 CPU1.T1 CPU1.T4 CPU1.T35 CPU1.T37 CPU1.T39 CPU1.U3 CPU1.U6 CPU1.U33 CPU1.V1 CPU1.V8 CPU1.V35 CPU1.V37 CPU1.V39 CPU1.W3 CPU1.W6 CPU1.W33 CPU1.Y5 CPU1.Y35 CPU1.Y37 D2701.2 D4301.A D4302.A DB2001.2 DIMM1.2 DIMM1.4 DIMM1.6 DIMM1.9 DIMM1.11 DIMM1.13 DIMM1.15 DIMM1.17 DIMM1.20 DIMM1.22 DIMM1.24 DIMM1.26 DIMM1.28 DIMM1.31 DIMM1.33 DIMM1.35 DIMM1.37 DIMM1.39 DIMM1.42 DIMM1.44 DIMM1.46 DIMM1.48 DIMM1.50 DIMM1.53 DIMM1.55 DIMM1.57 DIMM1.94 DIMM1.96 DIMM1.98 DIMM1.101 DIMM1.103 DIMM1.105 DIMM1.107 DIMM1.109 DIMM1.112 DIMM1.114 DIMM1.116 DIMM1.118 DIMM1.120 DIMM1.123 DIMM1.125 DIMM1.127 DIMM1.129 DIMM1.131 DIMM1.134 DIMM1.136 DIMM1.138 DIMM1.139 DIMM1.140 DIMM1.147 DIMM1.149 DIMM1.151 DIMM1.154 DIMM1.156 DIMM1.158 DIMM1.160 DIMM1.162 DIMM1.165 DIMM1.167 DIMM1.169 DIMM1.171 DIMM1.173 DIMM1.176 DIMM1.178 DIMM1.180 DIMM1.182 DIMM1.184 DIMM1.187 DIMM1.189 DIMM1.191 DIMM1.193 DIMM1.195 DIMM1.198 DIMM1.200 DIMM1.202 DIMM1.238 DIMM1.239 DIMM1.241 DIMM1.243 DIMM1.246 DIMM1.248 DIMM1.250 DIMM1.252 DIMM1.254 DIMM1.257 DIMM1.259 DIMM1.261 DIMM1.263 DIMM1.265 DIMM1.268 DIMM1.270 DIMM1.272 DIMM1.274 DIMM1.276 DIMM1.279 DIMM1.281 DIMM1.283 DIMM2.2 DIMM2.4 DIMM2.6 DIMM2.9 DIMM2.11 DIMM2.13 DIMM2.15 DIMM2.17 DIMM2.20 DIMM2.22 DIMM2.24 DIMM2.26 DIMM2.28 DIMM2.31 DIMM2.33 DIMM2.35 DIMM2.37 DIMM2.39 DIMM2.42 DIMM2.44 DIMM2.46 DIMM2.48 DIMM2.50 DIMM2.53 DIMM2.55 DIMM2.57 DIMM2.94 DIMM2.96 DIMM2.98 DIMM2.101 DIMM2.103 DIMM2.105 DIMM2.107 DIMM2.109 DIMM2.112 DIMM2.114 DIMM2.116 DIMM2.118 DIMM2.120 DIMM2.123 DIMM2.125 DIMM2.127 DIMM2.129 DIMM2.131 DIMM2.134 DIMM2.136 DIMM2.138 DIMM2.139 DIMM2.147 DIMM2.149 DIMM2.151 DIMM2.154 DIMM2.156 DIMM2.158 DIMM2.160 DIMM2.162 DIMM2.165 DIMM2.167 DIMM2.169 DIMM2.171 DIMM2.173 DIMM2.176 DIMM2.178 DIMM2.180 DIMM2.182 DIMM2.184 DIMM2.187 DIMM2.189 DIMM2.191 DIMM2.193 DIMM2.195 DIMM2.198 DIMM2.200 DIMM2.202 DIMM2.238 DIMM2.239 DIMM2.241 DIMM2.243 DIMM2.246 DIMM2.248 DIMM2.250 DIMM2.252 DIMM2.254 DIMM2.257 DIMM2.259 DIMM2.261 DIMM2.263 DIMM2.265 DIMM2.268 DIMM2.270 DIMM2.272 DIMM2.274 DIMM2.276 DIMM2.279 DIMM2.281 DIMM2.283 EU3201.2 EU3202.2 EU3203.2 EU3204.2 EU3801.3 EU3801.8 EU3802.3 EU3802.8 EU3803.2 EU3901.2 EU5601.3 EU5601.8 EU5602.3 EU5602.8 EU5603.3 EU5603.8 EU5901.2 EU5902.2 FANC1.1 FANS1.1 HDMI1.2 HDMI1.5 HDMI1.8 HDMI1.11 HDMI1.17 HDMI1.20 HDMI1.21 HDMI1.22 HDMI1.23 HS1902.1 HS1902.2 HS2601.1 HS2601.2 HS2601.3 HS2601.4 HS2601.5 HS2601.6 HS2601.7 HS2601.8 HS2602.1 HS2602.2 HS2602.3 HS2602.4 HS2602.5 HS2602.6 HS2602.7 HS2602.8 HS2603.1 HS2603.2 HS2603.3 HS2603.4 HS2603.5 HS2603.6 HS2603.7 HS2603.8 HS2604.1 HS2604.2 HS2604.3 HS2604.4 HS2604.5 HS2604.6 HS2604.7 HS2604.8 HS2605.1 HS2605.2 HS2605.3 HS2605.4 HS2605.5 HS2605.6 HS2605.7 HS2605.8 HS2606.1 HS2606.2 HS2606.3 HS2606.4 HS2606.5 HS2606.6 HS2606.7 HS2606.8 HS6301.1 JMP1.4 LPC1.3 LPC1.15 LPC1.16 NGFF1.7 NGFF1.13 NGFF1.18 NGFF1.19 NGFF1.33 NGFF1.39 NGFF1.45 NGFF1.57 NGFF1.63 NGFF1.69 NGFF1.75 NGFF1.76 NGFF1.77 NGFF2.1 NGFF2.3 NGFF2.9 NGFF2.15 NGFF2.21 NGFF2.27 NGFF2.33 NGFF2.39 NGFF2.45 NGFF2.51 NGFF2.57 NGFF2.71 NGFF2.73 NGFF2.75 NGFF2.76 NGFF2.77 PC1001.2 PC1002.2 PC1004.2 PC1005.2 PC1006.2 PC1007.2 PC1008.2 PC1009.2 PC1010.2 PC1011.2 PC1012.2 PC1018.2 PC1019.2 PC1020.2 PC1021.2 PC1022.2 PC1023.2 PC1034.2 PC1035.2 PC1036.2 PC1037.2 PC1038.2 PC1039.2 PC1040.2 PC1041.2 PC1042.2 PC1043.2 PC1044.2 PC1045.2 PC1046.2 PC1047.2 PC1048.2 PC1049.2 PC1050.2 PC1051.2 PC1052.2 PC1053.2 PC1058.2 PC4401.2 PC4402.2 PC4403.2 PC4414.2 PC4416.2 PC4426.2 PC4427.2 PC4428.2 PC4429.2 PC4501.2 PC4502.2 PC4504.1 PC4505.2 PC4506.2 PC4507.2 PC4509.1 PC4510.2 PC4511.2 PC4512.2 PC4514.1 PC4515.2 PC4516.2 PC4517.2 PC4519.1 PC4520.2 PC4601.2 PC4602.2 PC4604.1 PC4605.2 PC4606.2 PC4607.2 PC4609.1 PC4610.2 PC4701.2 PC4702.2 PC4703.2 PC4705.2 PC4706.2 PC4707.2 PC4801.2 PC4802.2 PC4803.2 PC4804.2 PC4805.2 PC4808.2 PC4809.2 PC4810.2 PC4901.2 PC4902.2 PC4903.2 PC4904.2 PC4905.2 PC4906.2 PC4909.2 PC4910.2 PC4911.2 PC4912.2 PC4913.2 PC4916.2 PC4917.2 PC4918.2 PC4919.2 PC5001.2 PC5002.2 PC5003.2 PC5004.2 PC5005.2 PC5006.2 PC5007.2 PC5009.2 PC5010.2 PC5011.2 PC5012.2 PC5014.2 PC5015.2 PC5101.2 PC5102.2 PC5103.2 PC5104.2 PC5105.2 PC5107.2 PC5109.2 PC5110.2 PC5201.2 PC5202.2 PC5203.2 PC5204.2 PC5205.2 PR4403.2 PR4413.2 PR4423.2 PR4424.2 PR4430.2 PR4441.2 PR4454.2 PR4456.2 PR4458.2 PR4465.2 PR4466.2 PR4467.2 PR4468.2 PR4469.2 PR4471.2 PR4708.1 PR4711.2 PR4717.2 PR4816.2 PR4952.2 PR4953.2 PR4956.2 PR4957.2 PR4961.2 PR4962.2 PR5003.2 PR5025.2 PR5111.2 PR5112.2 PR5116.2 PR5206.2 PT4501.2 PT4502.2 PT4503.2 PT4504.2 PT4505.2 PT4506.2 PT4507.2 PT4508.2 PT4601.2 PT4602.2 PT4603.2 PT4604.2 PT4605.2 PT4701.2 PT4702.2 PT4801.2 PT4901.2 PT4902.2 PT4903.2 PT5001.2 PT5101.2 PU4401.53 PU4502.6 PU4502.9 PU4503.1 PU4503.2 PU4503.3 PU4504.1 PU4504.2 PU4504.3 PU4506.6 PU4506.9 PU4507.1 PU4507.2 PU4507.3 PU4508.1 PU4508.2 PU4508.3 PU4510.6 PU4510.9 PU4511.1 PU4511.2 PU4511.3 PU4512.1 PU4512.2 PU4512.3 PU4514.6 PU4514.9 PU4515.1 PU4515.2 PU4515.3 PU4516.1 PU4516.2 PU4516.3 PU4602.6 PU4602.9 PU4603.1 PU4603.2 PU4603.3 PU4605.6 PU4605.9 PU4606.1 PU4606.2 PU4606.3 PU4701.11 PU4702.5 PU4702.6 PU4702.7 PU4801.2 PU4902.21 PU4904.1 PU4904.2 PU4904.3 PU4905.1 PU4905.2 PU4905.3 PU5001.1 PU5001.3 PU5001.14 PU5001.21 PU5003.1 PU5003.2 PU5003.3 PU5101.11 PU5102.5 PU5102.6 PU5102.7 PU5201.1 PWRSW1.4 Q802.1 Q802.4 Q2401.1 Q2401.4 Q2407.S Q2408.1 Q2408.4 Q2702.C Q2703.C Q2704.C Q3801.4 Q4002.1 Q4002.4 Q4205.E Q4207.E Q5601.1 Q6401.1 Q6401.4 Q9102.E Q9103.1 Q9103.4 R415.2 R418.2 R420.2 R424.2 R426.2 R427.2 R602.2 R806.2 R808.2 R810.2 R902.1 R903.1 R1106.2 R1206.2 R1207.2 R1511.1 R1512.2 R1514.2 R1515.2 R1516.2 R1609.2 R1610.2 R1611.2 R1708.2 R1713.2 R1802.1 R1905.2 R1918.2 R1919.2 R2011.2 R2035.2 R2043.2 R2045.2 R2046.2 R2047.2 R2048.2 R2052.2 R2053.2 R2054.2 R2055.2 R2304.2 R2305.2 R2309.2 R2312.2 R2323.2 R2326.2 R2328.2 R2406.2 R2408.2 R2409.2 R2410.2 R2416.2 R2417.2 R2423.2 R2424.2 R2442.2 R2446.1 R2448.1 R2449.1 R2450.1 R2453.2 R2471.2 R2472.2 R2474.2 R2475.2 R2505.2 R2604.2 R2611.2 R2617.2 R2619.2 R2704.2 R2705.1 R2708.1 R3101.1 R3106.2 R3302.2 R3812.1 R3815.2 R3817.2 R4023.2 R4205.2 R5609.2 R5904.2 R5908.2 R5909.2 R5910.2 R5913.2 R5914.2 R5915.2 R5919.2 R6301.1 R6302.1 R6308.2 R6315.2 R6406.2 R6407.2 R6408.2 R9110.1 R9904.1 R9929.1 R9930.1 R9938.2 R9939.2 RJ45R1.4 RJ45R1.8 RJ45R1.18 RJ45R1.23 RJ45R1.24 RJ45R1.25 RJ45R1.26 RJ45R1.27 RJ45R1.28 RJ45R1.29 RJ45R1.30 SATA1.1 SATA1.4 SATA1.7 SATA1.8 SATA1.9 SATA2.1 SATA2.4 SATA2.7 SATA2.8 SATA2.9 SATA3.1 SATA3.4 SATA3.7 SATA3.8 SATA3.9 SATAP1.3 SATAP1.5 SB1.A2 SB1.A3 SB1.A4 SB1.A5 SB1.A8 SB1.A28 SB1.A33 SB1.A37 SB1.A45 SB1.A46 SB1.A47 SB1.A48 SB1.AA5 SB1.AA19 SB1.AA20 SB1.AA25 SB1.AA27 SB1.AA28 SB1.AA30 SB1.AA31 SB1.AA49 SB1.AB19 SB1.AB25 SB1.AB31 SB1.AC4 SB1.AC12 SB1.AC17 SB1.AC33 SB1.AC38 SB1.AC46 SB1.AD1 SB1.AD2 SB1.AD19 SB1.AD22 SB1.AD25 SB1.AD49 SB1.AE4 SB1.AE12 SB1.AE33 SB1.AE38 SB1.AE46 SB1.AF22 SB1.AF25 SB1.AF28 SB1.AG1 SB1.AG22 SB1.AG23 SB1.AG25 SB1.AG27 SB1.AG28 SB1.AG30 SB1.AG49 SB1.AH12 SB1.AH17 SB1.AH33 SB1.AH38 SB1.AJ19 SB1.AJ20 SB1.AJ25 SB1.AJ27 SB1.AJ28 SB1.AJ30 SB1.AJ31 SB1.AK4 SB1.AK19 SB1.AK20 SB1.AK25 SB1.AK27 SB1.AK28 SB1.AK30 SB1.AK31 SB1.AK46 SB1.AL12 SB1.AL17 SB1.AL21 SB1.AL24 SB1.AL26 SB1.AL29 SB1.AL33 SB1.AL38 SB1.AM1 SB1.AM18 SB1.AM32 SB1.AM49 SB1.AN12 SB1.AN16 SB1.AN34 SB1.AN38 SB1.AP4 SB1.AP46 SB1.AR12 SB1.AR16 SB1.AR34 SB1.AR38 SB1.AT1 SB1.AT16 SB1.AT18 SB1.AT21 SB1.AT24 SB1.AT26 SB1.AT29 SB1.AT32 SB1.AT34 SB1.AT45 SB1.AV11 SB1.AV39 SB1.AW4 SB1.AW10 SB1.AW40 SB1.AW46 SB1.B47 SB1.B48 SB1.B49 SB1.BA5 SB1.BA6 SB1.BA12 SB1.BA14 SB1.BA44 SB1.BB9 SB1.BB41 SB1.BB43 SB1.BC8 SB1.BC10 SB1.BC13 SB1.BC15 SB1.BC19 SB1.BC24 SB1.BC26 SB1.BC31 SB1.BC35 SB1.BC40 SB1.BC45 SB1.BD43 SB1.BE44 SB1.BF1 SB1.BF2 SB1.BF3 SB1.BF48 SB1.BF49 SB1.BG2 SB1.BG3 SB1.BG4 SB1.BG17 SB1.BG22 SB1.BG25 SB1.BG28 SB1.BG33 SB1.BG37 SB1.BG48 SB1.C4 SB1.C5 SB1.C12 SB1.C25 SB1.C30 SB1.C48 SB1.D8 SB1.D12 SB1.D16 SB1.D17 SB1.D30 SB1.D33 SB1.E8 SB1.E10 SB1.E13 SB1.E15 SB1.E17 SB1.E19 SB1.E22 SB1.E24 SB1.E26 SB1.E31 SB1.E33 SB1.E35 SB1.E40 SB1.E42 SB1.F41 SB1.F43 SB1.F47 SB1.G6 SB1.G44 SB1.H8 SB1.J4 SB1.J9 SB1.J10 SB1.J26 SB1.J29 SB1.J40 SB1.J46 SB1.J47 SB1.J48 SB1.K11 SB1.K39 SB1.M5 SB1.M16 SB1.M18 SB1.M21 SB1.M24 SB1.M32 SB1.M34 SB1.M49 SB1.N12 SB1.N16 SB1.N34 SB1.N35 SB1.N37 SB1.N38 SB1.P4 SB1.P26 SB1.P29 SB1.P46 SB1.R3 SB1.R4 SB1.R12 SB1.R16 SB1.R26 SB1.R29 SB1.R34 SB1.R38 SB1.T4 SB1.T5 SB1.T7 SB1.T17 SB1.T18 SB1.T32 SB1.T49 SB1.U12 SB1.U15 SB1.U17 SB1.U21 SB1.U24 SB1.U33 SB1.U38 SB1.V4 SB1.V20 SB1.V22 SB1.V46 SB1.W25 SB1.W27 SB1.W28 SB1.W30 SB1.Y9 SB1.Y10 SB1.Y12 SB1.Y17 SB1.Y33 SB1.Y38 SD1.3 SD1.6 SD1.12 SD1.13 SLOT1.A1 SLOT1.A4 SLOT1.A12 SLOT1.A15 SLOT1.A18 SLOT1.B4 SLOT1.B7 SLOT1.B13 SLOT1.B16 SLOT1.B18 SLOT2.A1 SLOT2.A4 SLOT2.A12 SLOT2.A15 SLOT2.A18 SLOT2.A20 SLOT2.A23 SLOT2.A24 SLOT2.A27 SLOT2.A28 SLOT2.A31 SLOT2.A34 SLOT2.A37 SLOT2.A38 SLOT2.A41 SLOT2.A42 SLOT2.A45 SLOT2.A46 SLOT2.A49 SLOT2.A51 SLOT2.A54 SLOT2.A55 SLOT2.A58 SLOT2.A59 SLOT2.A62 SLOT2.A63 SLOT2.A66 SLOT2.A67 SLOT2.A70 SLOT2.A71 SLOT2.A74 SLOT2.A75 SLOT2.A78 SLOT2.A79 SLOT2.A82 SLOT2.B4 SLOT2.B7 SLOT2.B13 SLOT2.B16 SLOT2.B18 SLOT2.B21 SLOT2.B22 SLOT2.B25 SLOT2.B26 SLOT2.B29 SLOT2.B32 SLOT2.B35 SLOT2.B36 SLOT2.B39 SLOT2.B40 SLOT2.B43 SLOT2.B44 SLOT2.B47 SLOT2.B49 SLOT2.B52 SLOT2.B53 SLOT2.B56 SLOT2.B57 SLOT2.B60 SLOT2.B61 SLOT2.B64 SLOT2.B65 SLOT2.B68 SLOT2.B69 SLOT2.B72 SLOT2.B73 SLOT2.B76 SLOT2.B77 SLOT2.B80 SSKT1.4 SSKT2.10 TC1101.2 TC3201.2 TC3801.2 TC3901.2 U401.1 U401.4 U2401.1 U2401.3 U2401.17 U2401.18 U2401.35 U2401.40 U2401.59 U2401.66 U2401.82 U2401.83 U2401.86 U2401.88 U2401.90 U2401.117 U2405.3 U2501.4 U2502.10 U2601.2 U2601.4 U2602.3 U2701.1 U3101.33 U3201.2 U3301.25 U3801.2 U3901.2 U4002.1 U4002.4 U4003.S U4009.3 U4010.3 U4201.11 U4201.15 U4202.1 U4202.4 U4801.1 U4801.4 U5602.1 U5901.24 U5901.33 U6301.2 U6303.S U6401.1 U6401.4 U6402.1 U6402.4 U9101.16 U9101.23 U9101.33 UC3201.2 UC3202.2 UC3203.2 UC3801.2 UC3901.2 USB2R1.4 USB2R1.8 USB2R1.9 USB2R1.10 USB2R1.11 USB2R1.12 USB3F1.4 USB3F1.7 USB3F1.10 USB3F1.11 USB3F2.4 USB3F2.7 USB3F2.10 USB3F2.11 VGA1.5 VGA1.6 VGA1.7 VGA1.8 VGA1.10 VGA1.16 VGA1.17 X1801.2 X1801.4 X3101.2 X3101.4
V5_ALW_MON: C2426.1 Q2408.3 R2468.2 R2472.1 U2401.15
V5_ALW_MON_1: Q2408.5 Q2408.6 R2467.2
V5_ALW_MON_2: C2425.1 Q2408.2 R2466.2 R2471.1
VBAT1: BT2501.1 R2506.1 TP2501.1
VBAT1_L: D2501.A D2502.2 R2506.2 TP2502.1
VBAT1_R: D2502.1 R2504.2 R2505.1
VBAT2: C2405.1 D2501.K U2401.21
VCCGT_VCC_SEN: CPU1.F39 PR4445.2 PR4447.1
VCCGT_VSS_SEN: CPU1.F38 PC4422.2 PC4423.1 PR4450.1 PR4454.1
VCCIO_SENSE: CPU1.AF4 PR4815.2
VCCPLL_OC_R: C801.1 CPU1.AJ9 R801.1
VCCSA_SENSE: CPU1.AD5 PR4714.1 PR4715.2
VCCST_GD_CPU: CPU1.U2 R419.2 R420.1
VCCST_GD_DRIVER: R419.1 R4014.2 R9908.1
VDDQ_EN: C4012.1 R4024.2 R5003.1
VDDQ_EN_CR: R4024.1 U4010.4
VIN_DET: C2407.1 R2411.2 R2416.1 U2401.46
VSS_SA_IO_SENSE: CPU1.AE4 PR4716.2 PR4717.1
0D95V_CPU_VCCIO: CPU1.AJ23 CPU1.AK11 CPU1.AK14 CPU1.AK24 CPU1.M8 CPU1.P8 CPU1.T8 CPU1.U8 CPU1.W8 PC1046.1 PC1047.1 PC1048.1 PC1049.1 PC4806.2 PC4808.1 PC4809.1 PC4810.1 PR4812.2 PR4815.1 PT4801.1 PU4802.1 PU4802.2 PU4802.3 Q2402.1 R301.1 R422.1 R425.2 R701.2 R9912.1
0D675V_VTT_S0: C1204.1 C1205.1 DIMM1.77 DIMM1.221 DIMM2.77 DIMM2.221 PG5005.1 PG5006.1
1D2V_SM_S3: C807.1 C808.1 C1025.1 C1026.1 C1027.1 C1028.1 C1029.1 C1030.1 C1031.1 C1101.1 C1102.1 C1105.1 C1201.1 C1202.1 C1203.1 C1208.1 CPU1.AT18 CPU1.AT21 CPU1.AU13 CPU1.AU15 CPU1.AU19 CPU1.AU23 CPU1.AV11 CPU1.AV17 CPU1.AV21 CPU1.AW10 CPU1.AW14 CPU1.AW25 CPU1.AY12 CPU1.AY16 CPU1.AY18 CPU1.AY23 DIMM1.7 DIMM1.18 DIMM1.29 DIMM1.40 DIMM1.51 DIMM1.59 DIMM1.61 DIMM1.64 DIMM1.67 DIMM1.70 DIMM1.73 DIMM1.76 DIMM1.80 DIMM1.83 DIMM1.85 DIMM1.88 DIMM1.90 DIMM1.92 DIMM1.99 DIMM1.110 DIMM1.121 DIMM1.132 DIMM1.204 DIMM1.206 DIMM1.209 DIMM1.212 DIMM1.215 DIMM1.217 DIMM1.220 DIMM1.223 DIMM1.226 DIMM1.229 DIMM1.231 DIMM1.233 DIMM1.236 DIMM2.7 DIMM2.18 DIMM2.29 DIMM2.40 DIMM2.51 DIMM2.59 DIMM2.61 DIMM2.64 DIMM2.67 DIMM2.70 DIMM2.73 DIMM2.76 DIMM2.80 DIMM2.83 DIMM2.85 DIMM2.88 DIMM2.90 DIMM2.92 DIMM2.99 DIMM2.110 DIMM2.121 DIMM2.132 DIMM2.204 DIMM2.206 DIMM2.209 DIMM2.212 DIMM2.215 DIMM2.217 DIMM2.220 DIMM2.223 DIMM2.226 DIMM2.229 DIMM2.231 DIMM2.233 DIMM2.236 PR4801.2 PR4802.2 PR4803.2 PR4804.2 PR4805.2 PR4806.2 PR4807.2 PR4809.2 PR5006.2 PR5008.2 PR5010.2 PR5011.2 PR5012.2 PR5013.2 PR5014.1 PR5015.2 PR5017.2 PR5018.2 PR5020.2 PR5021.2 PR5022.2 PR5023.2 PR5026.2 PR5027.2 PR5028.2 PR5029.2 PR5030.2 Q2405.4 R801.2 R1101.1 R1103.1 R1104.1 R1201.1 R1203.1 R3818.2 TC1101.1
1D05V_CPU_SA: CPU1.AA6 CPU1.AA7 CPU1.AB6 CPU1.AB7 CPU1.AB8 CPU1.AC7 CPU1.AC8 CPU1.N7 CPU1.P7 CPU1.R7 CPU1.T7 CPU1.U7 CPU1.V7 CPU1.W7 CPU1.Y6 CPU1.Y7 CPU1.Y8 PC1050.1 PC1051.1 PC1052.1 PC1053.1 PC4705.1 PG4701.1 PL4701.2 PT4701.1 PT4702.1
1D05V_LAN: C3103.1 C3104.1 C3106.1 C3107.1 C3108.1 C3111.1 C3112.1 U3101.3 U3101.8 U3101.22 U3101.24 U3101.30
1D8V_SB: C2108.1 R2101.2 R2303.2 R2310.2 R9936.1 R9937.1 SB1.AF19 SB1.AF20 SB1.AG19 SB1.AG20 SB1.AN15 SB1.AR15 SB1.BB11
1D8V_SB_CNVI: R2101.1 R2102.1 SB1.AN24
1D24V_PCH: C2109.1 SB1.AJ22 SB1.AJ23 SB1.AK22 SB1.AK23 SB1.BG5
2D5V_VPP_S3: C1103.1 C1104.1 C1206.1 C1207.1 DIMM1.142 DIMM1.143 DIMM1.286 DIMM1.287 DIMM1.288 DIMM2.142 DIMM2.143 DIMM2.286 DIMM2.287 DIMM2.288 PR5203.2
3D3V_AUD_S0: C2706.1 C2707.1 C2713.1 C2714.1 C2718.1 L2702.2 L2703.2 U2701.5 U2701.37 U2701.48
3D3V_CARD_S0: F3301.1 U3301.5
3D3V_LAN: C3101.1 C3102.1 C3105.1 C3113.1 C3114.1 C3117.1 R3105.2 RJ45R1.21 U3101.11 U3101.23 U3101.32
3D3V_PCIVAUX_SB: C9312.1 C9404.1 C9410.1 C9411.1 R9403.2 SLOT1.B10 SLOT2.B10
3D3V_S0: C1109.1 C1110.1 C1212.1 C1213.1 C2406.1 C3301.1 C3302.1 C4210.2 C4211.1 C4212.1 C5904.1 C5905.1 C6201.1 C6203.1 C6205.1 C6206.1 C6213.1 C6214.1 C9311.1 C9403.1 D2601.K D2602.K DIMM1.284 DIMM2.140 DIMM2.284 L2702.1 L5901.1 L5902.1 LPC1.10 NGFF2.2 NGFF2.4 NGFF2.12 NGFF2.14 NGFF2.16 NGFF2.18 NGFF2.70 NGFF2.72 NGFF2.74 Q2406.4 Q4201.1 Q4201.2 Q4201.3 Q5601.2 Q5601.5 R1506.1 R1601.2 R1704.2 R1706.2 R1714.2 R1801.2 R1803.2 R1805.2 R1806.1 R1807.2 R1809.2 R1906.2 R1907.2 R1908.2 R1910.2 R1911.2 R1912.2 R2001.2 R2002.2 R2003.2 R2302.2 R2324.2 R2327.2 R2329.2 R2404.1 R2405.1 R2412.1 R2413.1 R2414.1 R2415.1 R2435.1 R2462.2 R2463.2 R2464.2 R2465.2 R2469.2 R2470.2 R2473.2 R2476.2 R2603.1 R2616.1 R2706.1 R2707.1 R2717.1 R3103.1 R4003.1 R4005.1 R4022.2 R4205.1 R4801.1 R5610.2 R5901.1 R5902.1 R5903.2 R5905.1 R5906.1 R5907.1 R6314.1 R6402.1 R6403.1 R6404.1 R6415.1 R6416.1 R6421.2 R9101.1 R9922.1 RN2401.5(B) RN2401.6(B) RN2401.7(B) RN2401.8(B) RN2402.6(B) RN2402.7(B) RN2402.8(B) RN2405.3(B) RN2405.4(B) SATAP1.6 SLOT1.A9 SLOT1.A10 SLOT1.B8 SLOT2.A9 SLOT2.A10 SLOT2.B8 U2401.4 U3301.4 U5601.2 U5601.5 U5901.14 U5901.26
3D3V_S5: C2107.1 C2415.1 C2416.1 C2417.1 C2418.1 C2419.1 C2420.1 C2421.1 C2422.1 C2423.1 C2424.1 C2721.1 C4204.1 C6310.1 PR4901.1 PR4902.1 PR4903.1 PR4904.1 PR4905.1 PR4906.1 PR4908.1 PR4910.1 PR4912.1 PR4914.1 PR4916.1 PR4918.1 PR4920.1 PR4922.1 PR4924.1 PR5201.2 PR5202.1 Q2701.E Q4201.5 Q4201.6 Q4201.7 Q4201.8 R2014.2 R2015.2 R2044.2 R2318.2 R2403.1 R2504.1 R2613.1 R2714.2 R3807.1 R6304.2 R6306.1 R6309.1 R6313.1 R6417.1 RN2001.3(B) RN2001.4(B) SB1.BE48 SB1.BE49 U2401.22 U2401.32 U2401.45 U2401.55 U2401.60 U2401.65 U2401.77 U2401.104 U2401.120 U2601.5 U2602.5 U4201.6 U4201.7 U6301.4 U6301.5
3D3V_SB: C2104.1 C2105.1 C2106.1 C2126.1 C2408.1 C4007.1 C4011.1 C4205.1 C4206.1 C9104.1 C9105.1 JMP1.2 L2703.1 PR5107.1 R413.1 R414.1 R1502.2 R1503.2 R1508.1 R1509.1 R1510.1 R1604.2 R1605.2 R1606.2 R1607.2 R1705.2 R1709.1 R1712.1 R1901.2 R1902.2 R1917.2 R2005.2 R2007.2 R2009.2 R2010.2 R2012.2 R2013.2 R2034.1 R2041.1 R2102.2 R2301.2 R2307.2 R2314.2 R2411.1 R2421.2 R2425.2 R2427.2 R2431.2 R2432.2 R2452.1 R2477.2 R2478.2 R2503.1 R3105.1 R3808.1 R4001.1 R4011.1 R4017.1 R4018.1 R4802.1 R4803.2 R6410.1 R6412.1 R9104.1 R9403.1 R9923.1 R9928.1 RN1901.5(B) RN1901.6(B) RN1901.7(B) RN1901.8(B) RN2403.5(B) RN2403.6(B) RN2403.7(B) RN2403.8(B) RN2404.3(B) RN2404.4(B) SB1.AC35 SB1.AC36 SB1.AE35 SB1.AE36 SB1.AN21 SB1.AN26 SB1.AN32 SB1.AN44 SB1.AP26 SB1.AT44 SB1.AW9 SB1.AY8 SB1.BB7 SB1.BB14 SB1.V23 U2401.27 U2405.5 U4009.5 U4010.5 U4201.8 U4201.9 U9101.1
3D3V_SPI: C2501.1 R2313.2 R2317.2 R2325.2 R2501.1 R2502.1 R2503.2 SSKT1.8 SSKT2.2 U2501.8 U2502.2
3D3V_WLAN_SB: C6301.1 C6302.1 C6303.1 C6304.1 C6307.1 C6308.1 C6309.1 NGFF1.2 NGFF1.4 NGFF1.72 NGFF1.74 R6309.2 R6311.1 R6312.1 U6301.3
3P0V_BAT_VREG: C2102.1 C2103.1 D2502.3 R1507.2 R2040.2 R2042.1 SB1.BC49 SB1.BD49
3P3V_S5_EN: C5101.1 PU5101.3 R5101.2
A20GATE: R2464.1 U2401.119
ACPRESENT: R2015.1 SB1.BG42
ALDO_CAP: C2710.1 U2701.23
ALL_SYS_PWRGD: C4008.1 R4014.1 R4016.1 U4009.4
AUD_AZACPU_SCLK: CPU1.V3 R2027.1
AUD_AZACPU_SCLK_R: R2027.2 SB1.AM3
AUD_AZACPU_SDI: CPU1.U1 R702.1
AUD_AZACPU_SDI_R: R702.2 SB1.AN3
AUD_AZACPU_SDO: CPU1.V2 R2025.1
AUD_AZACPU_SDO_R: R2025.2 SB1.AM2
AUD_BEEP: C2716.1 U2701.8
AUD_BEEP_R: C2716.2 C2717.1 R2702.1 R2704.1
AUD_LINE1_L: C3001.1 U2701.28
AUD_LINE1_R: C3002.1 U2701.27
AUD_LINE2_L: C2901.1 U2701.13
AUD_LINE2_R: C2902.1 U2701.14
AUD_LINK_SDO_C: Q2001.C R2038.2 R2039.1
AUD_LINK_SDO_R1: JMP1.1 R2039.2
AUD_MIC1_L: C3007.1 U2701.15
AUD_MIC1_R: C3008.1 U2701.16
AUD_MIC2_L: C2905.1 U2701.19
AUD_MIC2_L_C: C2901.2 C2902.2 R2902.1
AUD_MIC2_R: C2904.1 U2701.20
AUD_VREF: C2703.1 U2701.25
AUDOUT_L: R3005.1 U2701.40
AUDOUT_LL: L3003.1 Q3001.3 R3005.2 R3007.1
AUDOUT_R: R3006.1 U2701.39
AUDOUT_RR: L3004.1 Q3001.6 R3006.2 R3009.1
BATLOW_N: RN2001.1(A) SB1.BF44
BC1_TP: SB1.BC1 TP1509.1
BLUE_CRT: C5919.1 EU5901.4 L5905.2 VGA1.3
BPM_CPU_N0: CPU1.D16 TP417.1
BPM_CPU_N1: CPU1.D17 TP418.1
BPM_CPU_N2: CPU1.G14 TP401.1
BPM_CPU_N3: CPU1.H14 TP402.1
CAP_1: C2414.1 U2401.128
CATERR#_CPU: CPU1.D13 TP403.1
CBN: C2702.1 U2701.34
CBP: C2702.2 U2701.36
CHASSIS_ID_0: C9905.1 PWRSW1.7 R6415.2 SB1.L47
CNV_BRI_DT: R2303.1 R2305.1 R9932.2 SB1.AV4
CNV_BRI_DT_R: NGFF1.36 R9932.1
CNV_BRI_RSP: R9933.2 R9936.2 SB1.AY2
CNV_BRI_RSP_R: NGFF1.22 R9933.1
CNV_DET_S: D6301.A D6302.A R6313.2 U6302.S
CNV_RGI_DT: R2310.1 R2312.1 R9934.2 SB1.BA4
CNV_RGI_DT_R: NGFF1.32 R9934.1
CNV_RGI_RSP: R9935.2 R9937.2 SB1.AV3
CNV_RGI_RSP_R: NGFF1.34 R9935.1
CNV_WR_0_DN: NGFF1.15 SB1.BB3
CNV_WR_0_DP: NGFF1.17 SB1.BB4
CNV_WR_1_DN: NGFF1.9 SB1.BA3
CNV_WR_1_DP: NGFF1.11 SB1.BA2
CNV_WR_CLK_DN: NGFF1.21 SB1.BD4
CNV_WR_CLK_DP: NGFF1.23 SB1.BE3
CNV_WT_0_DN: NGFF1.65 SB1.BE6
CNV_WT_0_DP: NGFF1.67 SB1.BD7
CNV_WT_1_DN: NGFF1.59 SB1.BG6
CNV_WT_1_DP: NGFF1.61 SB1.BF6
CNV_WT_CLK_DN: NGFF1.71 SB1.BC5
CNV_WT_CLK_DP: NGFF1.73 SB1.BB6
CNV_WT_RCOMP: R1512.1 SB1.BA1
CPU1_AY3: CPU1.AY3 R903.2
CPU1_G8: CPU1.G8 R902.2
CPU_FAN_CTRL_CONN: D2601.A FANC1.4 R2603.2 R2605.2
CPU_FAN_CTRL_SIO: R2605.1 U2401.47
CPU_FAN_TACH_1: FANC1.3 R2601.2 R2602.1
CPU_FAN_TACH_SIO: R2602.2 R2604.1 U2401.37
CPU_THERMDA+: C2401.1 C2404.1 Q2404.B Q2404.C U2401.41
CPU_THERMDA-: C2401.2 C2404.2 Q2404.E U2401.42
CPVEE: C2701.2 U2701.33
DAS/DSS#: NGFF2.10 R9922.2 U6402.2
DAS/DSS#_NMOS: R6421.1 U6402.5 U6402.6
DCPRTC: C2101.1 SB1.BF47 SB1.BG47
DDI_VGA_DATA_C_N2: C5913.1 U5901.6
DDI_VGA_DATA_C_N3: C5915.1 U5901.8
DDI_VGA_DATA_C_P2: C5912.1 U5901.5
DDI_VGA_DATA_C_P3: C5914.1 U5901.7
DDI_VGA_DATA_CPU_N2: C5913.2 CPU1.H10
DDI_VGA_DATA_CPU_N3: C5915.2 CPU1.G9
DDI_VGA_DATA_CPU_P2: C5912.2 CPU1.G10
DDI_VGA_DATA_CPU_P3: C5914.2 CPU1.F9
DDPC_CTRL_CLK: R1906.1 SB1.AN13
DDPC_CTRL_DATA: R2327.1 SB1.AL10
DDPD_CTRL_CLK: R1907.1 SB1.AL9
DDPD_CTRL_DATA: R2329.1 SB1.AR3
DDR_VTT_CNTL_CPU: R414.2 R4025.1 U401.3
DDR_VTT_CNTL_GATE: R413.2 U401.5 U401.6
DDR_VTT_CNTL_R: R416.1 U401.2
DDSP_B_TX_N0: Q5601.6 R5601.2 R5602.2 R5603.2 R5604.2 R5605.2 R5606.2 R5607.2 R5608.2
DEVSLP: NGFF2.38 R6201.1
DEVSLP_N: R6201.2 SB1.AH35
DIMM1_EVENT_N: DIMM1.78 R1101.2
DIMM2_EVENT_N: DIMM2.78 R1201.2
DIMM_CA_CPU_VREF_RC: C602.2 R602.1
DIMM_CA_VREF_A: R601.2 R1103.2 R1105.1 R1106.1
DIMM_CA_VREF_A_L: C1106.1 C1107.1 DIMM1.146 R1105.2
DIMM_CA_VREF_B: R1203.2 R1205.1 R1206.1
DIMM_CA_VREF_B_L: C1210.1 C1211.1 DIMM2.146 R1204.2 R1205.2
DIMM_DQ_CPU_VREF_B_RC: C1209.2 R1207.1
DISP_UTIL_CPU: CPU1.D14 TP701.1
DLDO_CAP: C2711.1 C2712.1 U2701.47
DMI_RX_CPU_N0: CPU1.Y4 SB1.C29
DMI_RX_CPU_N1: CPU1.AA5 SB1.C31
DMI_RX_CPU_N2: CPU1.AB3 SB1.C32
DMI_RX_CPU_N3: CPU1.AC5 SB1.C33
DMI_RX_CPU_P0: CPU1.Y3 SB1.B29
DMI_RX_CPU_P1: CPU1.AA4 SB1.B31
DMI_RX_CPU_P2: CPU1.AB4 SB1.B32
DMI_RX_CPU_P3: CPU1.AC4 SB1.B33
DMI_TX_CPU_N0: CPU1.AC1 SB1.G30
DMI_TX_CPU_N1: CPU1.AD2 SB1.K32
DMI_TX_CPU_N2: CPU1.AE1 SB1.G33
DMI_TX_CPU_N3: CPU1.AF3 SB1.K34
DMI_TX_CPU_P0: CPU1.AC2 SB1.F30
DMI_TX_CPU_P1: CPU1.AD3 SB1.J32
DMI_TX_CPU_P2: CPU1.AE2 SB1.F34
DMI_TX_CPU_P3: CPU1.AF2 SB1.J35
DP_AUX_CON_N: C5911.1 U5901.3
DP_AUX_CON_P: C5910.1 U5901.2
DP_AUX_CPU_N: C5911.2 CPU1.E12
DP_AUX_CPU_P: C5910.2 CPU1.D12
DP_HPD_CPU: R1701.1 R5910.1 SB1.AL15 U5901.32
EAPD: R2719.1 U2701.45
EC_PWRGD_3V: R2433.2 U2401.57
EDP_5VDDCCL: EU5902.1 RN5901.4(B) U5901.15 VGA1.15
EDP_5VDDCDA: EU5902.3 RN5901.3(B) U5901.16 VGA1.12
EDP_AVC12: C5901.1 C5902.1 C5903.2 U5901.4 U5901.25
EDP_AVC33: C5908.1 L5901.2 U5901.1
EDP_BLUE_P: C5916.1 L5905.1 R5913.1 U5901.21
EDP_DAC33: C5909.1 L5902.2 U5901.20
EDP_EXPCLKIN: R5904.1 U5901.28
EDP_GPI1: R5905.2 U5901.11
EDP_GPI2: R5906.2 U5901.12
EDP_GPI3: R5907.2 U5901.13
EDP_GREEN_P: C5917.1 L5904.1 R5914.1 U5901.22
EDP_HSYNC: R5917.1 U5901.19
EDP_HSYNC_C: C5923.1 EU5902.6 R5917.2 VGA1.13
EDP_LDORSTB: R5903.1 U5901.27
EDP_RED_P: C5918.1 L5903.1 R5915.1 U5901.23
EDP_VSYNC: R5916.1 U5901.18
EDP_VSYNC_C: C5922.1 EU5902.4 R5916.2 VGA1.14
FDI_COMP: CPU1.M9 R701.1
FORM_FAC_ID_0: R6404.2 R6408.1 SB1.BD38
FORM_FAC_ID_1: R6403.2 R6407.1 SB1.BF35
FORM_FAC_ID_2: R6402.2 R6406.1 SB1.BD34
FP_CBL_DET: C9903.1 PWRSW1.6 R1510.2 SB1.BA24
FP_CBL_DET_PD: R2448.2 U2401.50
FP_MIC2_L: C2903.1 FL2901.2 HPMIC1.4
FP_OUT_L: C2906.1 FL2903.2 HPMIC1.1
FP_OUT_LL: FL2903.1 Q2901.6 R2906.2 R2907.1
FP_OUT_R: C2907.1 FL2902.2 HPMIC1.2
FP_OUT_RR: FL2902.1 Q2901.3 R2905.2 R2909.1
FP_RST_N: R2005.1 R9921.1 SB1.AU2
FP_RST_N_CN: R9921.2 TP9906.1
FRONT_JD: AUD1.23 R2710.2
GPD7: R2318.1 SB1.BE41
GPIO_LAN_RESET_N: R1912.1 SB1.M45
GPIO_PCI_RESET_N: R1601.1 SB1.AV43
GPIO_PEG_RESET_N: R1911.1 SB1.AT49
GPP_A7: R1902.1 SB1.BA36
GPP_A8: R2001.1 SB1.AV32
GPP_H_12: SB1.AB47 TP1506.1
GPP_H_15: R2301.1 SB1.AC47
GPP_J1: R1511.2 SB1.AY3
GPP_K3: R6314.2 R6315.1 SB1.U47 U6302.G
GPP_K5: R1713.1 R1714.1 SB1.N47
GREEN_CRT: C5920.1 EU5901.1 L5904.2 VGA1.2
H_PRDY_N: CPU1.B10 R9902.2
H_PREQ_N: CPU1.B9 R9901.2
H_PWRGD: C402.1 CPU1.F8 R2006.2 R9907.1
H_PWRGD_R: R2006.1 SB1.AE3
H_RSTOUT_XDP_N: R9909.2 R9910.2 R9911.2
H_SKTOCC_CPU: CPU1.AC38 R2478.1 R9924.2 U2405.1
H_SKTOCC_N: R1509.2 R9924.1 SB1.AP3 U2405.4
H_TCK: CPU1.F11 R415.1 R2021.1 SB1.AH4
H_TDI: CPU1.G12 R411.1
H_TDO: CPU1.H13 R402.1 R410.1
H_TMS: CPU1.F13 R412.1
H_TRST_N: CPU1.F12 R417.1
H_TRST_N_R: R417.2 R427.1 SB1.AM4
HD_LED_PWR1: PWRSW1.2 R6419.2
HDA_BITCLK_CODEC: C2715.1 R2017.1 U2701.2
HDA_BITCLK_PCH: R2017.2 R2052.1 SB1.BD11
HDA_RST#_CODEC: R2019.1 R2718.1 U2701.7
HDA_RST#_PCH: R2019.2 R2053.1 SB1.BE10
HDA_SDIN0_CODEC: R2703.2 U2701.4
HDA_SDIN0_PCH: R2703.1 SB1.BE11
HDA_SDOUT_CODEC: R2020.1 U2701.3
HDA_SDOUT_PCH: R2020.2 R2038.1 SB1.BF12
HDA_SYNC_CODEC: R2022.1 U2701.6
HDA_SYNC_PCH: R2022.2 SB1.BG13
HDD_LED_PWR1: LED1.A R6418.2
HDMI1_DETECT: R1702.2 SB1.P47
HDMI_CLK_CON: C5610.1 EU5603.1 EU5603.10 HDMI1.15 RN5601.4(B) U5601.3
HDMI_CLK_CPU: R1908.1 SB1.AL13 U5601.4
HDMI_DATA_CMC_N0: C5602.2 R5601.1 TR5601.4
HDMI_DATA_CMC_N1: C5604.2 R5603.1 TR5602.4
HDMI_DATA_CMC_N2: C5606.2 R5605.1 TR5603.4
HDMI_DATA_CMC_N3: C5608.2 R5607.1 TR5604.4
HDMI_DATA_CMC_P0: C5601.2 R5602.1 TR5601.3
HDMI_DATA_CMC_P1: C5603.2 R5604.1 TR5602.3
HDMI_DATA_CMC_P2: C5605.2 R5606.1 TR5603.3
HDMI_DATA_CMC_P3: C5607.2 R5608.1 TR5604.3
HDMI_DATA_CON: C5611.1 EU5603.2 EU5603.9 HDMI1.16 RN5601.3(B) U5601.6
HDMI_DATA_CON_N0: EU5601.2 EU5601.9 HDMI1.3 TR5601.1
HDMI_DATA_CON_N1: EU5601.5 EU5601.6 HDMI1.6 TR5602.1
HDMI_DATA_CON_N2: EU5602.2 EU5602.9 HDMI1.9 TR5603.1
HDMI_DATA_CON_N3: EU5602.5 EU5602.6 HDMI1.12 TR5604.1
HDMI_DATA_CON_P0: EU5601.1 EU5601.10 HDMI1.1 TR5601.2
HDMI_DATA_CON_P1: EU5601.4 EU5601.7 HDMI1.4 TR5602.2
HDMI_DATA_CON_P2: EU5602.1 EU5602.10 HDMI1.7 TR5603.2
HDMI_DATA_CON_P3: EU5602.4 EU5602.7 HDMI1.10 TR5604.2
HDMI_DATA_CPU: R2324.1 SB1.AR8 U5601.1
HDMI_DATA_CPU_N0: C5602.1 CPU1.D21
HDMI_DATA_CPU_N1: C5604.1 CPU1.E22
HDMI_DATA_CPU_N2: C5606.1 CPU1.A23
HDMI_DATA_CPU_N3: C5608.1 CPU1.D23
HDMI_DATA_CPU_P0: C5601.1 CPU1.C21
HDMI_DATA_CPU_P1: C5603.1 CPU1.D22
HDMI_DATA_CPU_P2: C5605.1 CPU1.B23
HDMI_DATA_CPU_P3: C5607.1 CPU1.C23
HDMI_DET_CON: EU5603.4 EU5603.7 HDMI1.19 Q5601.3 R5609.1
HDMI_DET_CPU: Q5601.4 R1702.1 R5610.1 SB1.AT6
HP_OUT_L: C2905.2 R2904.2 R2906.1 U2701.31
HP_OUT_R: C2904.2 R2903.2 R2905.1 U2701.32
I2C0_SCL_VGA: R5911.1 U5901.30
I2C0_SDA_VGA: R5912.1 U5901.29
I2S1_SFRM: R2054.1 SB1.BD12
ITP_PMODE: R9911.1 SB1.AL3
KBRST_N: R2463.1 SB1.BE39 U2401.118
KCLK: RN2403.4(A) U2401.113
KDAT: RN2403.3(A) U2401.114
LAN_CONN_CVT: RJ45R1.9 UC3201.1 UC3202.1
LAN_LEDACT_R#: EU3202.6 R3204.1 RJ45R1.22
LAN_MDI0_DN: R3203.3 U3101.2
LAN_MDI0_DN_C: EU3201.1 R3203.2 RJ45R1.11
LAN_MDI0_DP: R3203.4 U3101.1
LAN_MDI0_DP_C: EU3201.6 R3203.1 RJ45R1.10
LAN_MDI1_DN: R3205.3 U3101.5
LAN_MDI1_DN_C: EU3201.4 R3205.2 RJ45R1.13
LAN_MDI1_DP: R3205.4 U3101.4
LAN_MDI1_DP_C: EU3201.3 R3205.1 RJ45R1.12
LAN_MDI2_DN: R3206.3 U3101.7
LAN_MDI2_DN_C: EU3203.1 R3206.2 RJ45R1.15
LAN_MDI2_DP: R3206.4 U3101.6
LAN_MDI2_DP_C: EU3203.6 R3206.1 RJ45R1.14
LAN_MDI3_DN: R3207.3 U3101.10
LAN_MDI3_DN_C: EU3203.4 R3207.2 RJ45R1.17
LAN_MDI3_DP: R3207.4 U3101.9
LAN_MDI3_DP_C: EU3203.3 R3207.1 RJ45R1.16
LAN_RSET: R3101.2 U3101.31
LAN_XTALI: C3119.1 R3104.2 U3101.28 X3101.1
LAN_XTALO: R3104.1 R9931.2 U3101.29
LAN_XTALO_C: C3118.1 R9931.1 X3101.3
LANCLK_REQ_U_N: R3102.1 U3101.12
LANWAKE_R_N: RN2001.2(A) SB1.BG44
LDO5V: PG4903.2 PR4958.2 PR4959.1
LINE1_JD: AUD1.33 R2711.2
LINE1_JD/LINE2_JD: R2707.2 R2711.1 R2712.1 U2701.43
LINE1_LL: L3001.1 R3001.2 R3003.1
LINE1_LL_C: C3001.2 R3001.1
LINE1_RR: L3002.1 R3002.2 R3004.1
LINE1_RR_C: C3002.2 R3002.1
LINE2_JD: HPMIC1.6 R2712.2
LINE2_VREFO: R2901.1 U2701.12
LINEIN_L: D2901.2 R2904.1
LINEIN_R: D2901.3 R2903.1
LINK_ACTIVITY_N: R3204.2 TP3101.1 U3101.27
LPC_AD_PCH_P0: LPC1.9 SB1.BB39 U2401.8
LPC_AD_PCH_P1: LPC1.8 SB1.AW37 U2401.9
LPC_AD_PCH_P2: LPC1.7 SB1.AV37 U2401.10
LPC_AD_PCH_P3: LPC1.6 SB1.BA38 U2401.11
LPC_CLK_14M_DEBUG: LPC1.2 R1915.2
LPC_CLK_14M_EC: R1914.2 U2401.7
LPC_CLK_33M_EC: R1916.2 U2401.16
LPC_CLK_PCH_P0: R1914.1 R1915.1 SB1.BB36
LPC_CLK_PCH_P1: R1916.1 SB1.BB34
LPC_FRAME#_PCH: LPC1.5 R1913.2 U2401.12
LPC_FRAME#_PCH_R: R1913.1 SB1.BE38
LPC_PME_N: R2421.1 SB1.AV21 U2401.75
LPC_SERIRQ_PCH: LPC1.1 R1910.1 SB1.AW35 U2401.127
LPSS_GSPI0_MOSI: SB1.BE30 TP1508.1
LPSS_GSPI1_MOSI: SB1.BA26 TP1507.1
M_A_A0: CPU1.AW15 DIMM1.79
M_A_A1: CPU1.AU18 DIMM1.72
M_A_A2: CPU1.AU17 DIMM1.216
M_A_A3: CPU1.AV19 DIMM1.71
M_A_A4: CPU1.AT19 DIMM1.214
M_A_A5: CPU1.AU20 DIMM1.213
M_A_A6: CPU1.AV20 DIMM1.69
M_A_A7: CPU1.AU21 DIMM1.211
M_A_A8: CPU1.AT20 DIMM1.68
M_A_A9: CPU1.AT22 DIMM1.66
M_A_A10: CPU1.AY14 DIMM1.225
M_A_A11: CPU1.AU22 DIMM1.210
M_A_A12: CPU1.AV22 DIMM1.65
M_A_A13: CPU1.AV12 DIMM1.232
M_A_A14: CPU1.AV14 DIMM1.228
M_A_A15: CPU1.AY11 DIMM1.86
M_A_A16: CPU1.AW13 DIMM1.82
M_A_ACT#: CPU1.AU24 DIMM1.62
M_A_ALERT#: CPU1.AT23 DIMM1.208
M_A_BG0: CPU1.AW23 DIMM1.63
M_A_BG1: CPU1.AV23 DIMM1.207
M_A_BS0: CPU1.AY13 DIMM1.81
M_A_BS1: CPU1.AV15 DIMM1.224
M_A_CKE0: CPU1.AY24 DIMM1.60
M_A_CKE1: CPU1.AW24 DIMM1.203
M_A_CLK0: CPU1.AW18 DIMM1.74
M_A_CLK1: CPU1.AW17 DIMM1.218
M_A_CLK#0: CPU1.AV18 DIMM1.75
M_A_CLK#1: CPU1.AY17 DIMM1.219
M_A_CS#0: CPU1.AW12 DIMM1.84
M_A_CS#1: CPU1.AU11 DIMM1.89
M_A_DQ0: CPU1.AE40 DIMM1.5
M_A_DQ1: CPU1.AE37 DIMM1.150
M_A_DQ2: CPU1.AG38 DIMM1.12
M_A_DQ3: CPU1.AG37 DIMM1.157
M_A_DQ4: CPU1.AE39 DIMM1.3
M_A_DQ5: CPU1.AE38 DIMM1.148
M_A_DQ6: CPU1.AG39 DIMM1.10
M_A_DQ7: CPU1.AG40 DIMM1.155
M_A_DQ8: CPU1.AJ40 DIMM1.16
M_A_DQ9: CPU1.AJ37 DIMM1.161
M_A_DQ10: CPU1.AL38 DIMM1.23
M_A_DQ11: CPU1.AL37 DIMM1.168
M_A_DQ12: CPU1.AJ39 DIMM1.14
M_A_DQ13: CPU1.AJ38 DIMM1.159
M_A_DQ14: CPU1.AL39 DIMM1.21
M_A_DQ15: CPU1.AL40 DIMM1.166
M_A_DQ16: CPU1.AN40 DIMM1.27
M_A_DQ17: CPU1.AN37 DIMM1.172
M_A_DQ18: CPU1.AR38 DIMM1.34
M_A_DQ19: CPU1.AR37 DIMM1.179
M_A_DQ20: CPU1.AN39 DIMM1.25
M_A_DQ21: CPU1.AN38 DIMM1.170
M_A_DQ22: CPU1.AR39 DIMM1.32
M_A_DQ23: CPU1.AR40 DIMM1.177
M_A_DQ24: CPU1.AV37 DIMM1.38
M_A_DQ25: CPU1.AW37 DIMM1.183
M_A_DQ26: CPU1.AU35 DIMM1.45
M_A_DQ27: CPU1.AV35 DIMM1.190
M_A_DQ28: CPU1.AU38 DIMM1.36
M_A_DQ29: CPU1.AU37 DIMM1.181
M_A_DQ30: CPU1.AT35 DIMM1.43
M_A_DQ31: CPU1.AW35 DIMM1.188
M_A_DQ32: CPU1.AY8 DIMM1.97
M_A_DQ33: CPU1.AU8 DIMM1.242
M_A_DQ34: CPU1.AV6 DIMM1.104
M_A_DQ35: CPU1.AU6 DIMM1.249
M_A_DQ36: CPU1.AW8 DIMM1.95
M_A_DQ37: CPU1.AV8 DIMM1.240
M_A_DQ38: CPU1.AY6 DIMM1.102
M_A_DQ39: CPU1.AW6 DIMM1.247
M_A_DQ40: CPU1.AV4 DIMM1.108
M_A_DQ41: CPU1.AV3 DIMM1.253
M_A_DQ42: CPU1.AT3 DIMM1.115
M_A_DQ43: CPU1.AT2 DIMM1.260
M_A_DQ44: CPU1.AY4 DIMM1.106
M_A_DQ45: CPU1.AW4 DIMM1.251
M_A_DQ46: CPU1.AT4 DIMM1.113
M_A_DQ47: CPU1.AT1 DIMM1.258
M_A_DQ48: CPU1.AP1 DIMM1.119
M_A_DQ49: CPU1.AP2 DIMM1.264
M_A_DQ50: CPU1.AM3 DIMM1.126
M_A_DQ51: CPU1.AM2 DIMM1.271
M_A_DQ52: CPU1.AP4 DIMM1.117
M_A_DQ53: CPU1.AP3 DIMM1.262
M_A_DQ54: CPU1.AM4 DIMM1.124
M_A_DQ55: CPU1.AM1 DIMM1.269
M_A_DQ56: CPU1.AK1 DIMM1.130
M_A_DQ57: CPU1.AK2 DIMM1.275
M_A_DQ58: CPU1.AH3 DIMM1.137
M_A_DQ59: CPU1.AH2 DIMM1.282
M_A_DQ60: CPU1.AK4 DIMM1.128
M_A_DQ61: CPU1.AK3 DIMM1.273
M_A_DQ62: CPU1.AH4 DIMM1.135
M_A_DQ63: CPU1.AH1 DIMM1.280
M_A_DQS_DN0: CPU1.AF39 DIMM1.152
M_A_DQS_DN1: CPU1.AK39 DIMM1.163
M_A_DQS_DN2: CPU1.AP39 DIMM1.174
M_A_DQS_DN3: CPU1.AU36 DIMM1.185
M_A_DQS_DN4: CPU1.AW7 DIMM1.244
M_A_DQS_DN5: CPU1.AU3 DIMM1.255
M_A_DQS_DN6: CPU1.AN3 DIMM1.266
M_A_DQS_DN7: CPU1.AJ3 DIMM1.277
M_A_DQS_DP0: CPU1.AF38 DIMM1.153
M_A_DQS_DP1: CPU1.AK38 DIMM1.164
M_A_DQS_DP2: CPU1.AP38 DIMM1.175
M_A_DQS_DP3: CPU1.AV36 DIMM1.186
M_A_DQS_DP4: CPU1.AV7 DIMM1.245
M_A_DQS_DP5: CPU1.AU2 DIMM1.256
M_A_DQS_DP6: CPU1.AN2 DIMM1.267
M_A_DQS_DP7: CPU1.AJ2 DIMM1.278
M_A_ODT0: CPU1.AW11 DIMM1.87
M_A_ODT1: CPU1.AU14 DIMM1.91
M_A_PARITY: CPU1.AY15 DIMM1.222
M_B_A0: CPU1.AL19 DIMM2.79
M_B_A1: CPU1.AL22 DIMM2.72
M_B_A2: CPU1.AM22 DIMM2.216
M_B_A3: CPU1.AM23 DIMM2.71
M_B_A4: CPU1.AP23 DIMM2.214
M_B_A5: CPU1.AL23 DIMM2.213
M_B_A6: CPU1.AW26 DIMM2.69
M_B_A7: CPU1.AY26 DIMM2.211
M_B_A8: CPU1.AU26 DIMM2.68
M_B_A9: CPU1.AW27 DIMM2.66
M_B_A10: CPU1.AP18 DIMM2.225
M_B_A11: CPU1.AU27 DIMM2.210
M_B_A12: CPU1.AV27 DIMM2.65
M_B_A13: CPU1.AR15 DIMM2.232
M_B_A14: CPU1.AL17 DIMM2.228
M_B_A15: CPU1.AP16 DIMM2.86
M_B_A16: CPU1.AN18 DIMM2.82
M_B_ACT#: CPU1.AU28 DIMM2.62
M_B_ALERT#: CPU1.AY25 DIMM2.208
M_B_BG0: CPU1.AW28 DIMM2.63
M_B_BG1: CPU1.AY28 DIMM2.207
M_B_BS0: CPU1.AL18 DIMM2.81
M_B_BS1: CPU1.AM18 DIMM2.224
M_B_CKE0: CPU1.AY29 DIMM2.60
M_B_CKE1: CPU1.AV29 DIMM2.203
M_B_CLK0: CPU1.AM20 DIMM2.74
M_B_CLK1: CPU1.AP22 DIMM2.218
M_B_CLK#0: CPU1.AM21 DIMM2.75
M_B_CLK#1: CPU1.AP21 DIMM2.219
M_B_CS#0: CPU1.AP17 DIMM2.84
M_B_CS#1: CPU1.AN15 DIMM2.89
M_B_DQ0: CPU1.AE34 DIMM2.5
M_B_DQ1: CPU1.AE35 DIMM2.150
M_B_DQ2: CPU1.AH34 DIMM2.12
M_B_DQ3: CPU1.AH35 DIMM2.157
M_B_DQ4: CPU1.AD34 DIMM2.3
M_B_DQ5: CPU1.AD35 DIMM2.148
M_B_DQ6: CPU1.AG34 DIMM2.10
M_B_DQ7: CPU1.AG35 DIMM2.155
M_B_DQ8: CPU1.AL34 DIMM2.16
M_B_DQ9: CPU1.AL35 DIMM2.161
M_B_DQ10: CPU1.AK31 DIMM2.23
M_B_DQ11: CPU1.AL31 DIMM2.168
M_B_DQ12: CPU1.AK34 DIMM2.14
M_B_DQ13: CPU1.AK35 DIMM2.159
M_B_DQ14: CPU1.AK32 DIMM2.21
M_B_DQ15: CPU1.AL32 DIMM2.166
M_B_DQ16: CPU1.AP35 DIMM2.27
M_B_DQ17: CPU1.AN34 DIMM2.172
M_B_DQ18: CPU1.AN31 DIMM2.34
M_B_DQ19: CPU1.AP31 DIMM2.179
M_B_DQ20: CPU1.AN35 DIMM2.25
M_B_DQ21: CPU1.AP34 DIMM2.170
M_B_DQ22: CPU1.AN32 DIMM2.32
M_B_DQ23: CPU1.AP32 DIMM2.177
M_B_DQ24: CPU1.AM29 DIMM2.38
M_B_DQ25: CPU1.AM28 DIMM2.183
M_B_DQ26: CPU1.AR29 DIMM2.45
M_B_DQ27: CPU1.AR28 DIMM2.190
M_B_DQ28: CPU1.AL29 DIMM2.36
M_B_DQ29: CPU1.AL28 DIMM2.181
M_B_DQ30: CPU1.AP29 DIMM2.43
M_B_DQ31: CPU1.AP28 DIMM2.188
M_B_DQ32: CPU1.AR12 DIMM2.97
M_B_DQ33: CPU1.AP12 DIMM2.242
M_B_DQ34: CPU1.AL13 DIMM2.104
M_B_DQ35: CPU1.AL12 DIMM2.249
M_B_DQ36: CPU1.AR13 DIMM2.95
M_B_DQ37: CPU1.AP13 DIMM2.240
M_B_DQ38: CPU1.AM13 DIMM2.102
M_B_DQ39: CPU1.AM12 DIMM2.247
M_B_DQ40: CPU1.AP9 DIMM2.108
M_B_DQ41: CPU1.AR9 DIMM2.253
M_B_DQ42: CPU1.AP7 DIMM2.115
M_B_DQ43: CPU1.AP6 DIMM2.260
M_B_DQ44: CPU1.AP10 DIMM2.106
M_B_DQ45: CPU1.AR10 DIMM2.251
M_B_DQ46: CPU1.AR7 DIMM2.113
M_B_DQ47: CPU1.AR6 DIMM2.258
M_B_DQ48: CPU1.AM9 DIMM2.119
M_B_DQ49: CPU1.AL9 DIMM2.264
M_B_DQ50: CPU1.AL6 DIMM2.126
M_B_DQ51: CPU1.AL7 DIMM2.271
M_B_DQ52: CPU1.AM10 DIMM2.117
M_B_DQ53: CPU1.AL10 DIMM2.262
M_B_DQ54: CPU1.AM6 DIMM2.124
M_B_DQ55: CPU1.AM7 DIMM2.269
M_B_DQ56: CPU1.AJ7 DIMM2.130
M_B_DQ57: CPU1.AH6 DIMM2.275
M_B_DQ58: CPU1.AF7 DIMM2.137
M_B_DQ59: CPU1.AE7 DIMM2.282
M_B_DQ60: CPU1.AH7 DIMM2.128
M_B_DQ61: CPU1.AJ6 DIMM2.273
M_B_DQ62: CPU1.AF6 DIMM2.135
M_B_DQ63: CPU1.AE6 DIMM2.280
M_B_DQS_DN0: CPU1.AF34 DIMM2.152
M_B_DQS_DN1: CPU1.AK33 DIMM2.163
M_B_DQS_DN2: CPU1.AN33 DIMM2.174
M_B_DQS_DN3: CPU1.AN29 DIMM2.185
M_B_DQS_DN4: CPU1.AN13 DIMM2.244
M_B_DQS_DN5: CPU1.AR8 DIMM2.255
M_B_DQS_DN6: CPU1.AM8 DIMM2.266
M_B_DQS_DN7: CPU1.AG6 DIMM2.277
M_B_DQS_DP0: CPU1.AF35 DIMM2.153
M_B_DQS_DP1: CPU1.AL33 DIMM2.164
M_B_DQS_DP2: CPU1.AP33 DIMM2.175
M_B_DQS_DP3: CPU1.AN28 DIMM2.186
M_B_DQS_DP4: CPU1.AN12 DIMM2.245
M_B_DQS_DP5: CPU1.AP8 DIMM2.256
M_B_DQS_DP6: CPU1.AL8 DIMM2.267
M_B_DQS_DP7: CPU1.AG7 DIMM2.278
M_B_ODT0: CPU1.AM16 DIMM2.87
M_B_ODT1: CPU1.AL16 DIMM2.91
M_B_PARITY: CPU1.AL20 DIMM2.222
M_VREF_DQ_DIM0: CPU1.AC40 TP601.1
M_VREF_DQ_DIM1: C603.1 C1209.1 CPU1.AC39 R1204.1
MB_REG_PG: Q2402.6 Q2405.6 Q2406.3 Q2406.6 R2469.1 U2401.109
MB_REG_PG_1: Q2402.2 R2404.2 R2409.1
MB_REG_PG_2: Q2406.5 R2415.2 R2424.1
MB_REG_PG_3: Q2406.2 R2414.2 R2423.1
MCLK: RN2403.2(A) U2401.115
MDAT: RN2403.1(A) U2401.116
ME_CNTL: R2037.1 SB1.BF32
ME_CNTL_1: Q2001.B R2037.2
ME_CNTL_2: Q2001.E R2034.2
MEM_REG_PG: Q2405.3 R2470.1 U2401.111
MEM_REG_PG_1: Q2405.5 R2413.2 R2417.1
MEM_REG_PG_2: Q2405.2 R2412.2
MIC1_JD: AUD1.3 R2709.2
MIC1_JD/FRONT_JD: R2706.2 R2709.1 R2710.1 U2701.44
MIC1_LL: L3005.1 R3011.2 R3013.2 R3016.1
MIC1_LL_C: C3007.2 R3013.1
MIC1_RR: L3006.1 R3012.2 R3014.2 R3015.1
MIC1_RR_C: C3008.2 R3014.1
MIC1_VREFO_LL: R3011.1 U2701.9
MIC1_VREFO_RR: R3012.1 U2701.10
MIC2_VREFO: D2901.1 U2701.11
MUTE: Q2701.C R2908.1 R2910.1 R3008.1 R3010.1
MUTE_AUDOUT_LL: Q3001.5 R3010.2
MUTE_AUDOUT_RR: Q3001.2 R3008.2
MUTE_FP_OUT_LL: Q2901.2 R2908.2
MUTE_FP_OUTR_RR: Q2901.5 R2910.2
NGFF_WIFI_PWR_CRL: D6302.K R1712.2 SB1.U48
NGFF_WIFI_PWR_EN: R6306.2 U6301.1 U6302.D
PC_SPKR_DET_PD: R2449.2 U2401.54
PCH_CPU_BCLK_DN: CPU1.W4 SB1.C8
PCH_CPU_BCLK_DP: CPU1.W5 SB1.B8
PCH_CPU_NSSC_CLK_DN: CPU1.J9 SB1.C6
PCH_CPU_NSSC_CLK_DP: CPU1.K9 SB1.D7
PCH_CPU_PCIBCLK_DN: CPU1.W2 SB1.B6
PCH_CPU_PCIBCLK_DP: CPU1.W1 SB1.A6
PCH_DPWROK: R2612.2 R2619.1 SB1.AW41 U2602.4
PCH_HEATSINK_DET: HS1901.1 HS1901.2 RN1901.2(A) SB1.AN37
PCH_INTRUDER_N: R1507.1 SB1.BB44
PCH_JTAG_TCK_48077565: R2011.1 SB1.AJ3
PCH_JTAG_TDI: R411.2 R2026.1 SB1.AH2
PCH_JTAG_TDO: R410.2 R2024.1 SB1.AH3
PCH_JTAG_TMS: R412.2 R2028.1 SB1.AJ4
PCH_PECI: R1708.1 SB1.AF2
PCH_PME_N: R1508.2 SB1.BE36
PCH_PS_ON_N: R1919.1 SB1.AP41
PCH_PWROK: DB2001.1 R4016.2 SB1.AY42
PCH_PWROK_EC: C2413.1 R2433.1 R2439.1 R2442.1
PCH_RTCRST_DOWN: JMP1.6 R2035.1
PCH_RTCRST_N: R2036.2 R9919.1
PCH_RTCRST_PULLUP: C2006.1 JMP1.5 R2036.1 R2040.1 SB1.BE47
PCH_RTCX1: C1803.1 R1814.1 SB1.BA49 X1802.1
PCH_RTCX2: C1804.1 R1814.2 SB1.BA48 X1802.2
PCH_SATA_LED_N: R1704.1 SB1.AK48 U6401.2
PCH_SATA_LED_NMOS: R6416.2 U6401.5 U6401.6
PCH_SIO_DPWROK: R2475.1 R2612.1 U2401.28 U2602.1
PCH_SLP_A_N: R2047.1 R9916.1 SB1.BE40 U2401.126
PCH_SRTCRSTB_PULLUP: C2007.1 R2042.2 R2043.1 SB1.BD46
PCH_SYSPWROK: R2003.1 R2439.2 R9905.1 SB1.AU3
PCH_WAKE_N: NGFF1.55 R2014.1 R6202.2 SB1.BB47 SLOT1.B11 SLOT2.B11 U3101.21
PCH_XDP_PRDY_R_N: R9902.1 SB1.AM5
PCH_XDP_PREQ_R_N: R9901.1 SB1.AL2
PCIAUX_GATE: R2432.1 U2401.92
PCIE_RCOMP_N: R1513.1 SB1.B12
PCIE_RCOMP_P: R1513.2 SB1.A13
PCIE_RX_CON_N5: C3109.1 U3101.18
PCIE_RX_CON_P5: C3110.1 U3101.17
PCIE_RX_PCH_N5: C3109.2 SB1.F20
PCIE_RX_PCH_N7: SB1.L24 SLOT1.A17
PCIE_RX_PCH_N8: NGFF1.43 SB1.F24
PCIE_RX_PCH_P5: C3110.2 SB1.G20
PCIE_RX_PCH_P7: SB1.J24 SLOT1.A16
PCIE_RX_PCH_P8: NGFF1.41 SB1.G24
PCIE_SLOT1_PRSNT_N: R1506.2 SB1.BB26 SLOT1.B17
PCIE_SLOT2_PRSNT_N: R1806.2 SB1.BA30 SLOT2.B17 SLOT2.B31 SLOT2.B48 SLOT2.B81
PCIE_TX_CON_N5: C3115.1 U3101.14
PCIE_TX_CON_N7: C9402.2 SLOT1.B15
PCIE_TX_CON_N8: C6305.1 NGFF1.37
PCIE_TX_CON_P5: C3116.1 U3101.13
PCIE_TX_CON_P7: C9401.2 SLOT1.B14
PCIE_TX_CON_P8: C6306.1 NGFF1.35
PCIE_TX_PCH_N5: C3115.2 SB1.B21
PCIE_TX_PCH_N7: C9402.1 SB1.C23
PCIE_TX_PCH_N8: C6305.2 SB1.B24
PCIE_TX_PCH_P5: C3116.2 SB1.A22
PCIE_TX_PCH_P7: C9401.1 SB1.B23
PCIE_TX_PCH_P8: C6306.2 SB1.C24
PCIRST1#: R2401.1 R2406.1 U2401.51
PCIRST2#: R2407.1 R2410.1 U2401.52
PCIVAUX_CTRL: R1905.1 SB1.AN40
PCM_OUT: NGFF1.14 R2032.1 R6301.2 R6303.2
PCM_OUT_C: Q9103.3 R6303.1
PCM_OUT_PCH: R2032.2 SB1.BA17
PCM_SYNC: NGFF1.10 R2033.1 R6302.2 R6321.2
PCM_SYNC_C: Q9103.6 R6321.1
PCM_SYNC_PCH: R2033.2 SB1.BE16
PECI_CPU: CPU1.G7 R2428.1
PECI_EC: R2428.2 U2401.30
PECI_READY: R2430.2 U2401.31
PEG_CLK1_PCH: NGFF1.47 SB1.AH10
PEG_CLK1_PCH#: NGFF1.49 SB1.AH9
PEG_CLK2_PCH: SB1.AE15 U3101.15
PEG_CLK2_PCH#: SB1.AE14 U3101.16
PEG_CLK8_PCH: SB1.AC15 SLOT2.A13
PEG_CLK8_PCH#: SB1.AC14 SLOT2.A14
PEG_CLK9_PCH: SB1.U3 SLOT1.A13
PEG_CLK9_PCH#: SB1.U2 SLOT1.A14
PEG_CLKREQ1_PCH#: NGFF1.53 R1801.1 SB1.BE31
PEG_CLKREQ2_PCH#: R1803.1 R3102.2 SB1.AR32
PEG_CLKREQ3_PCH#: R1805.1 SB1.BB30
PEG_CLKREQ8_PCH#: R1807.1 SB1.AE41 SLOT2.B12
PEG_CLKREQ9_PCH#: R1809.1 SB1.AF48 SLOT1.B12
PEG_RCOMP_CPU: CPU1.L7 R301.2
PEG_RX_CPU_N0: CPU1.B7 SLOT2.A17
PEG_RX_CPU_N1: CPU1.C6 SLOT2.A22
PEG_RX_CPU_N2: CPU1.D5 SLOT2.A26
PEG_RX_CPU_N3: CPU1.E4 SLOT2.A30
PEG_RX_CPU_N4: CPU1.F5 SLOT2.A36
PEG_RX_CPU_N5: CPU1.G4 SLOT2.A40
PEG_RX_CPU_N6: CPU1.H5 SLOT2.A44
PEG_RX_CPU_N7: CPU1.J4 SLOT2.A48
PEG_RX_CPU_N8: CPU1.K5 SLOT2.A53
PEG_RX_CPU_N9: CPU1.L4 SLOT2.A57
PEG_RX_CPU_N10: CPU1.M5 SLOT2.A61
PEG_RX_CPU_N11: CPU1.N4 SLOT2.A65
PEG_RX_CPU_N12: CPU1.P5 SLOT2.A69
PEG_RX_CPU_N13: CPU1.R4 SLOT2.A73
PEG_RX_CPU_N14: CPU1.T5 SLOT2.A77
PEG_RX_CPU_N15: CPU1.U4 SLOT2.A81
PEG_RX_CPU_P0: CPU1.B8 SLOT2.A16
PEG_RX_CPU_P1: CPU1.C7 SLOT2.A21
PEG_RX_CPU_P2: CPU1.D6 SLOT2.A25
PEG_RX_CPU_P3: CPU1.E5 SLOT2.A29
PEG_RX_CPU_P4: CPU1.F6 SLOT2.A35
PEG_RX_CPU_P5: CPU1.G5 SLOT2.A39
PEG_RX_CPU_P6: CPU1.H6 SLOT2.A43
PEG_RX_CPU_P7: CPU1.J5 SLOT2.A47
PEG_RX_CPU_P8: CPU1.K6 SLOT2.A52
PEG_RX_CPU_P9: CPU1.L5 SLOT2.A56
PEG_RX_CPU_P10: CPU1.M6 SLOT2.A60
PEG_RX_CPU_P11: CPU1.N5 SLOT2.A64
PEG_RX_CPU_P12: CPU1.P6 SLOT2.A68
PEG_RX_CPU_P13: CPU1.R5 SLOT2.A72
PEG_RX_CPU_P14: CPU1.T6 SLOT2.A76
PEG_RX_CPU_P15: CPU1.U5 SLOT2.A80
PEG_TX_CON_N0: C9304.2 SLOT2.B15
PEG_TX_CON_N1: C9302.2 SLOT2.B20
PEG_TX_CON_N2: C9303.2 SLOT2.B24
PEG_TX_CON_N3: C9308.2 SLOT2.B28
PEG_TX_CON_N4: C9313.2 SLOT2.B34
PEG_TX_CON_N5: C9315.2 SLOT2.B38
PEG_TX_CON_N6: C9317.2 SLOT2.B42
PEG_TX_CON_N7: C9319.2 SLOT2.B46
PEG_TX_CON_N8: C9321.2 SLOT2.B51
PEG_TX_CON_N9: C9323.2 SLOT2.B55
PEG_TX_CON_N10: C9325.2 SLOT2.B59
PEG_TX_CON_N11: C9328.2 SLOT2.B63
PEG_TX_CON_N12: C9331.2 SLOT2.B67
PEG_TX_CON_N13: C9334.2 SLOT2.B71
PEG_TX_CON_N14: C9336.2 SLOT2.B75
PEG_TX_CON_N15: C9338.2 SLOT2.B79
PEG_TX_CON_P0: C9301.2 SLOT2.B14
PEG_TX_CON_P1: C9305.2 SLOT2.B19
PEG_TX_CON_P2: C9306.2 SLOT2.B23
PEG_TX_CON_P3: C9307.2 SLOT2.B27
PEG_TX_CON_P4: C9309.2 SLOT2.B33
PEG_TX_CON_P5: C9314.2 SLOT2.B37
PEG_TX_CON_P6: C9316.2 SLOT2.B41
PEG_TX_CON_P7: C9318.2 SLOT2.B45
PEG_TX_CON_P8: C9320.2 SLOT2.B50
PEG_TX_CON_P9: C9322.2 SLOT2.B54
PEG_TX_CON_P10: C9324.2 SLOT2.B58
PEG_TX_CON_P11: C9326.2 SLOT2.B62
PEG_TX_CON_P12: C9329.2 SLOT2.B66
PEG_TX_CON_P13: C9332.2 SLOT2.B70
PEG_TX_CON_P14: C9335.2 SLOT2.B74
PEG_TX_CON_P15: C9337.2 SLOT2.B78
PEG_TX_CPU_N0: C9304.1 CPU1.A6
PEG_TX_CPU_N1: C9302.1 CPU1.B5
PEG_TX_CPU_N2: C9303.1 CPU1.C4
PEG_TX_CPU_N3: C9308.1 CPU1.D3
PEG_TX_CPU_N4: C9313.1 CPU1.E2
PEG_TX_CPU_N5: C9315.1 CPU1.F3
PEG_TX_CPU_N6: C9317.1 CPU1.G2
PEG_TX_CPU_N7: C9319.1 CPU1.H3
PEG_TX_CPU_N8: C9321.1 CPU1.J2
PEG_TX_CPU_N9: C9323.1 CPU1.K3
PEG_TX_CPU_N10: C9325.1 CPU1.L2
PEG_TX_CPU_N11: C9328.1 CPU1.M3
PEG_TX_CPU_N12: C9331.1 CPU1.N2
PEG_TX_CPU_N13: C9334.1 CPU1.P3
PEG_TX_CPU_N14: C9336.1 CPU1.R1
PEG_TX_CPU_N15: C9338.1 CPU1.T3
PEG_TX_CPU_P0: C9301.1 CPU1.A5
PEG_TX_CPU_P1: C9305.1 CPU1.B4
PEG_TX_CPU_P2: C9306.1 CPU1.C3
PEG_TX_CPU_P3: C9307.1 CPU1.D2
PEG_TX_CPU_P4: C9309.1 CPU1.E1
PEG_TX_CPU_P5: C9314.1 CPU1.F2
PEG_TX_CPU_P6: C9316.1 CPU1.G1
PEG_TX_CPU_P7: C9318.1 CPU1.H2
PEG_TX_CPU_P8: C9320.1 CPU1.J1
PEG_TX_CPU_P9: C9322.1 CPU1.K2
PEG_TX_CPU_P10: C9324.1 CPU1.L1
PEG_TX_CPU_P11: C9326.1 CPU1.M2
PEG_TX_CPU_P12: C9329.1 CPU1.N1
PEG_TX_CPU_P13: C9332.1 CPU1.P2
PEG_TX_CPU_P14: C9335.1 CPU1.R2
PEG_TX_CPU_P15: C9337.1 CPU1.T2
PF_MIC2_LL: FL2901.1 R2901.2 R2902.2
PIRQA_N: R1917.1 R1918.1 R9112.2 SB1.T45
PLTRST#_PCH: R1504.1 SB1.AV29
PLTRST#_SIO: R1504.2 R1516.1 U2401.14
PLTRST_BUF_LAN_N: R2407.2 R4008.1
PLTRST_BUF_PCI_N: R2401.2 R4009.1 R4010.1
PLTRST_CPU_N: C403.1 CPU1.E7 R9910.1 SB1.AG5
PLTRST_LAN_N: LPC1.4 NGFF1.52 NGFF2.50 Q9101.D R4008.2 R9111.1 U3101.19
PLTRST_PCI_N: R4010.2 SLOT1.A11
PLTRST_PEG_N: R4009.2 SLOT2.A11
PM_DOWN_CPU: CPU1.D8 R421.2
PM_DOWN_PCH: R421.1 SB1.AE2
PM_SYNC_CPU: CPU1.E8 R1711.2
PM_SYNC_PCH: R1711.1 SB1.AF3
POL1_SDA: R5901.2 R5908.1 U5901.10
POL2_SCL: R5902.2 R5909.1 U5901.9
PROC_TRIGIN_CPU: CPU1.D1 R2201.2
PROC_TRIGIN_PCH: R2201.1 SB1.AK3
PROC_TRIGOUT_CPU: CPU1.B3 R901.2
PROC_TRIGOUT_PCH: R901.1 SB1.AK2
PROCHOT#_CPU: CPU1.C39 R409.2
PROCHOT#_CPU_R: PR4461.1 R404.2 R409.1 R2458.2
PROCHOT#_EC: R2458.1 U2401.36
PROCHOT#_IMVP: PR4461.2 PU4401.10
PS_ON_N: ATX1.1 C4302.1 R4301.2 R4302.2
PSPWRGD: ATX1.4 C4301.1 R4201.1 R4207.2
PULSAR_38D4M_REFCLK: NGFF1.64 R1816.2 R6308.1
PW_CLEAR: JMP1.3 R2041.2 SB1.V48
PWR2_PRSN_1: Q2401.2 R2402.2 R2408.1
PWR2_PRSN_2: Q2401.5 Q2401.6 R2403.2 U2405.2
PWR2_PRSNT: Q2401.3 R2465.1 U2401.108
PWR_1D0V: PC5107.1 PC5108.1 PL5101.2 PR5114.1 PR5117.1 PR5118.1 PR5119.1 PR5120.1 PR5121.1 PR5122.1 PR5123.1 PR5124.1 PR5125.1 PR5126.1 PR5127.1 PR5128.1 PR5129.1 PR5130.1 PR5131.1 PR5132.1 PR5133.1 PR5134.1 PR5135.1 PT5101.1
PWR_1D0V_BOOT: PR5110.2 PU5101.10
PWR_1D0V_BOOT_R: PC5106.2 PR5110.1
PWR_1D0V_CS: PR5111.1 PU5101.2
PWR_1D0V_FB: PC5108.2 PR5114.2 PR5116.1 PU5101.4
PWR_1D0V_LGATE: PU5101.6 PU5102.8
PWR_1D0V_PG: PR5107.2 PU5101.1
PWR_1D0V_PHASE: PC5106.1 PL5101.1 PR5109.2 PR5113.1 PU5101.8 PU5102.9
PWR_1D0V_RF: PR5112.1 PU5101.5
PWR_1D0V_SNB: PC5110.1 PR5113.2
PWR_1D0V_UGATE: PR5108.2 PU5101.9
PWR_1D0V_UGATE_R: PR5108.1 PR5109.1 PU5102.1
PWR_1D0V_VCC: PC5109.1 PR5115.1 PU5101.7
PWR_2D5V: PC5203.1 PC5204.1 PC5206.2 PR5203.1 PR5205.1 PU5201.3 PU5201.4
PWR_2D5V_EN: PC5205.1 PR5204.1 PU5201.8
PWR_2D5V_FB: PC5206.1 PR5205.2 PR5206.1 PU5201.2
PWR_2D5V_VIN: PC5201.1 PR5201.1 PU5201.5 PU5201.9
PWR_3D3V: PC4909.1 PG4902.2 PL4901.1 PR4901.2 PR4902.2 PR4903.2 PR4904.2 PR4905.2 PR4906.2 PR4908.2 PR4910.2 PR4912.2 PR4914.2 PR4916.2 PR4918.2 PR4920.2 PR4922.2 PR4924.2 PT4902.1
PWR_3D3V_SN: PC4911.1 PR4950.2
PWR_3V_BOOT2: PR4942.2 PU4902.9
PWR_3V_BOOT2_R: PC4907.2 PR4942.1
PWR_3V_CS2: PR4952.1 PU4902.5
PWR_3V_EN2: PC4918.1 PR4959.2 PR4961.1 PU4902.6
PWR_3V_FB2: PC4914.2 PR4954.2 PR4956.1 PU4902.4
PWR_3V_FB2_A: PC4914.1 PG4902.1 PR4954.1
PWR_3V_LGATE2: PU4902.11 PU4904.4
PWR_3V_PHASE2: PC4907.1 PL4901.2 PR4950.1 PU4901.1 PU4901.2 PU4901.3 PU4902.8 PU4904.5 PU4904.6 PU4904.7 PU4904.8
PWR_3V_UGATE2: PR4944.1 PU4902.10
PWR_3V_UGATE2R: PR4944.2 PU4901.4
PWR_5V: PC4910.1 PC4913.1 PG4901.2 PL4902.2 PR4925.1 PR4927.1 PR4929.1 PR4933.1 PR4934.1 PR4936.1 PR4937.1 PR4938.1 PR4939.1 PR4940.1 PR4945.1 PR4946.1 PR4947.1 PR4948.1 PR4949.1 PT4903.1 PU4902.14
PWR_5V3D3V_LDO3: PC4916.1 PU4902.3
PWR_5V3D3V_VIN: PC4901.1 PC4902.1 PC4903.1 PC4904.1 PC4905.1 PL4903.2 PL4904.2 PL4905.2 PR4932.1 PR4960.1 PT4901.1 PU4901.5 PU4901.6 PU4901.7 PU4901.8 PU4903.5 PU4903.6 PU4903.7 PU4903.8
PWR_5V_BOOT1: PR4943.1 PU4902.17
PWR_5V_BOOT1_R: PC4908.1 PR4943.2
PWR_5V_CS1: PR4953.1 PU4902.1
PWR_5V_EN1: PC4919.1 PR4960.2 PR4962.1 PU4902.20
PWR_5V_FB1: PC4915.2 PR4955.2 PR4957.1 PU4902.2
PWR_5V_FB1_A: PC4915.1 PG4901.1 PR4955.1
PWR_5V_LGATE1: PU4902.15 PU4905.4
PWR_5V_PHASE1: PC4908.2 PL4902.1 PR4951.1 PU4902.18 PU4903.1 PU4903.2 PU4903.3 PU4905.5 PU4905.6 PU4905.7 PU4905.8
PWR_5V_SN: PC4912.1 PR4951.2
PWR_5V_UGATE1: PR4941.2 PU4902.16
PWR_5V_UGATE1R: PR4941.1 PU4903.4
PWR_12V_DUAL_1D0V: PC5101.1 PC5102.1 PC5103.1 PC5104.1 PC5105.1 PL5104.1 PL5105.1 PU5102.2 PU5102.3 PU5102.4 PU5102.10
PWR_BTNJ_C: PWRSW1.5 R6420.1
PWR_DDR4_BT: PR5007.1 PU5001.18
PWR_DDR4_BT1: PC5008.1 PR5007.2
PWR_DDR4_CS: PR5003.1 PU5001.13
PWR_DDR4_FB: PC5013.2 PR5024.2 PR5025.1 PU5001.6
PWR_DDR4_LDOIN: PC5009.1 PR5014.2 PU5001.19
PWR_DDR4_LG: PU5001.15 PU5003.4
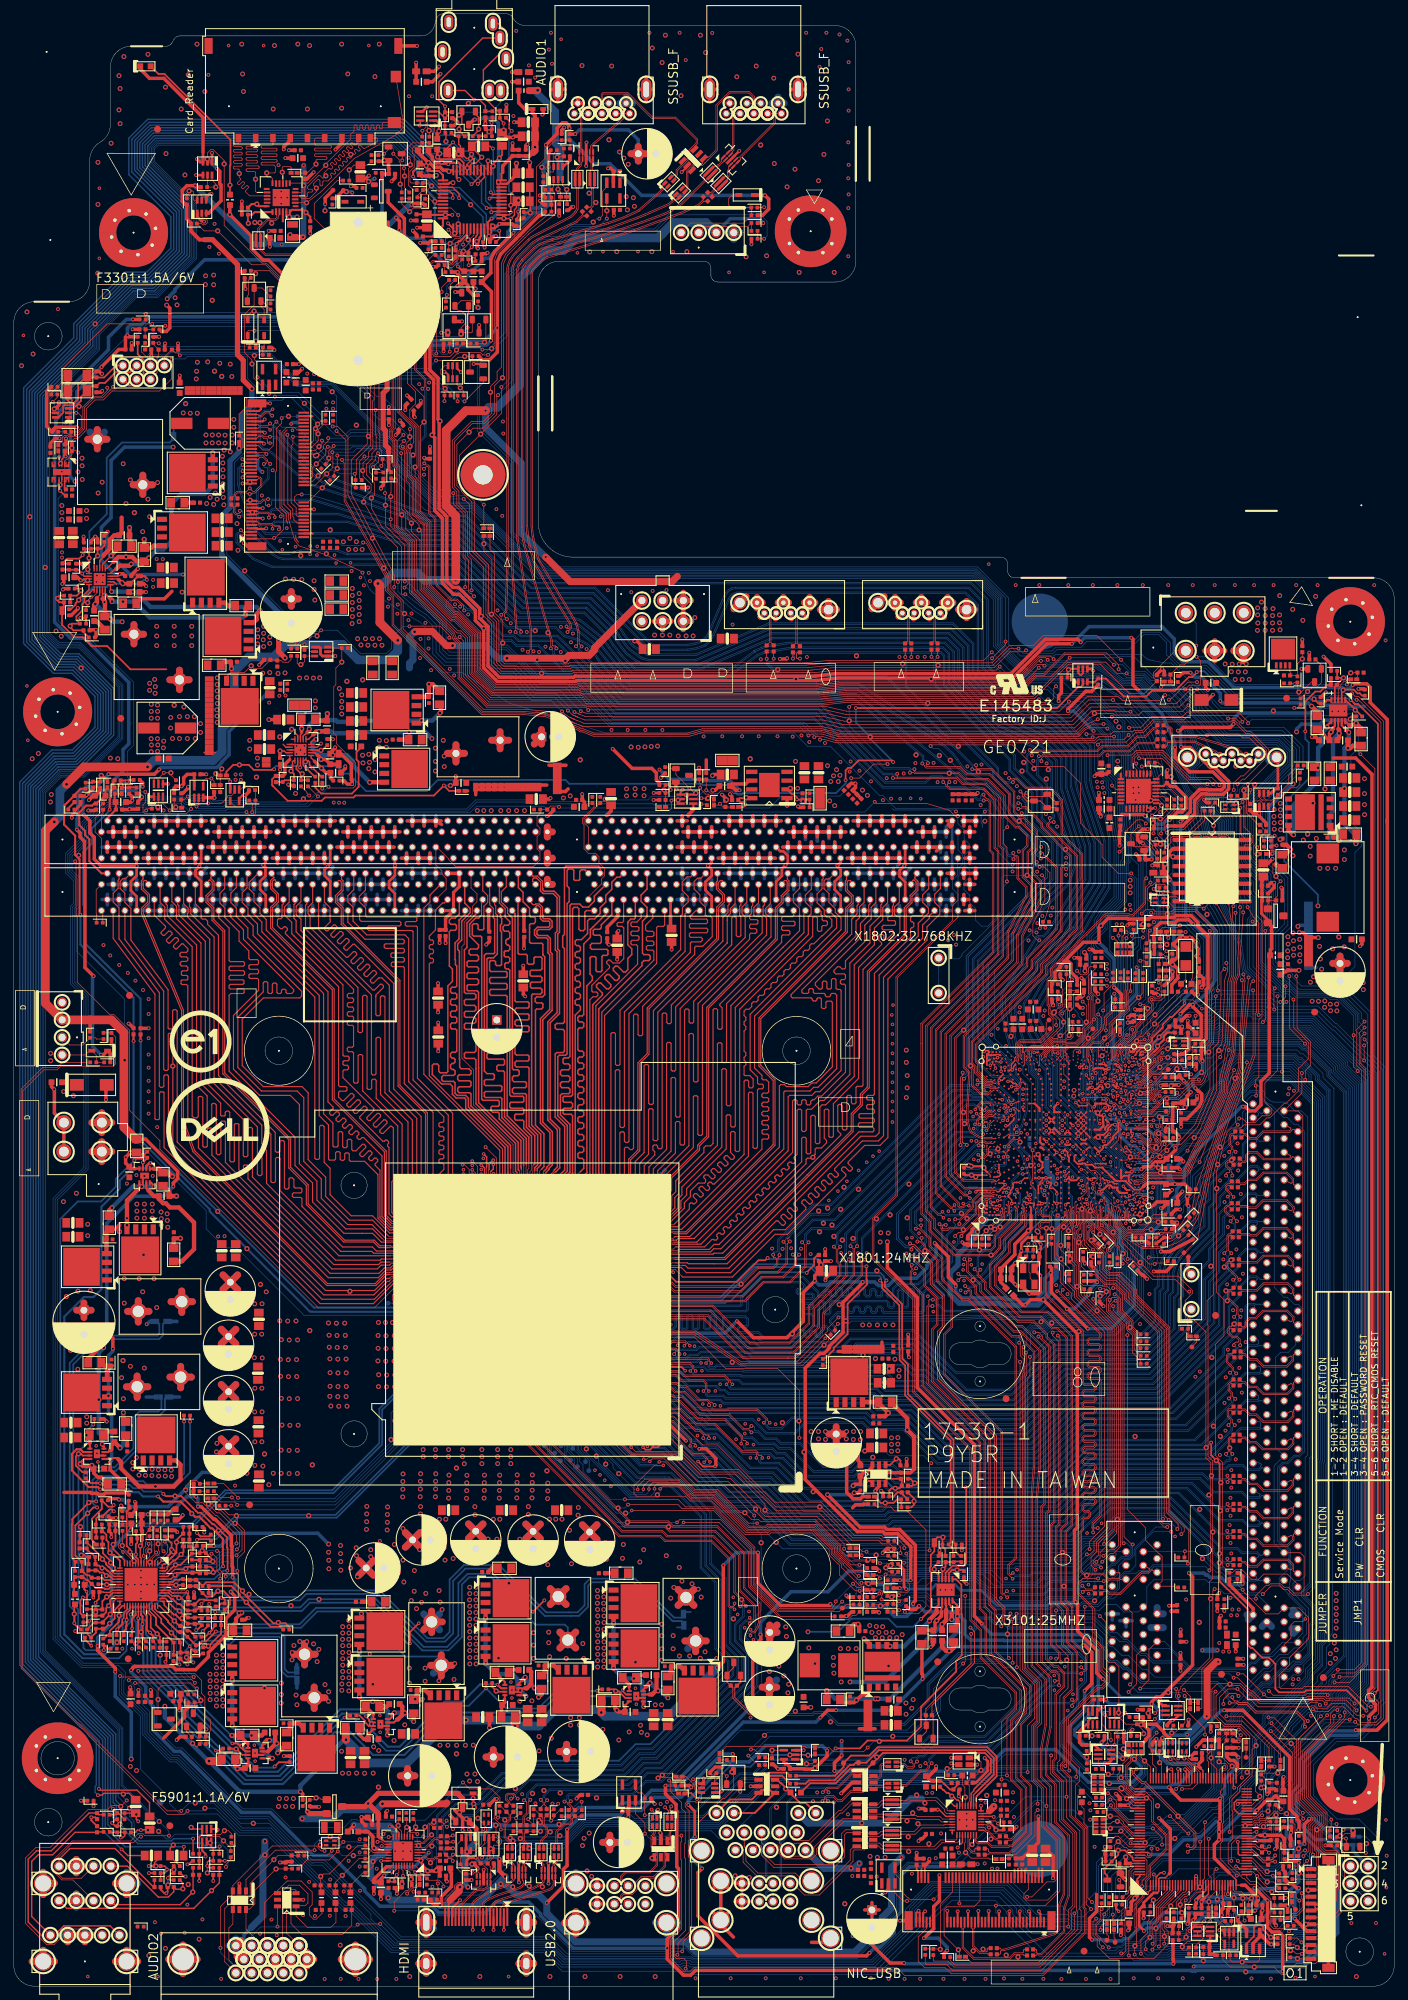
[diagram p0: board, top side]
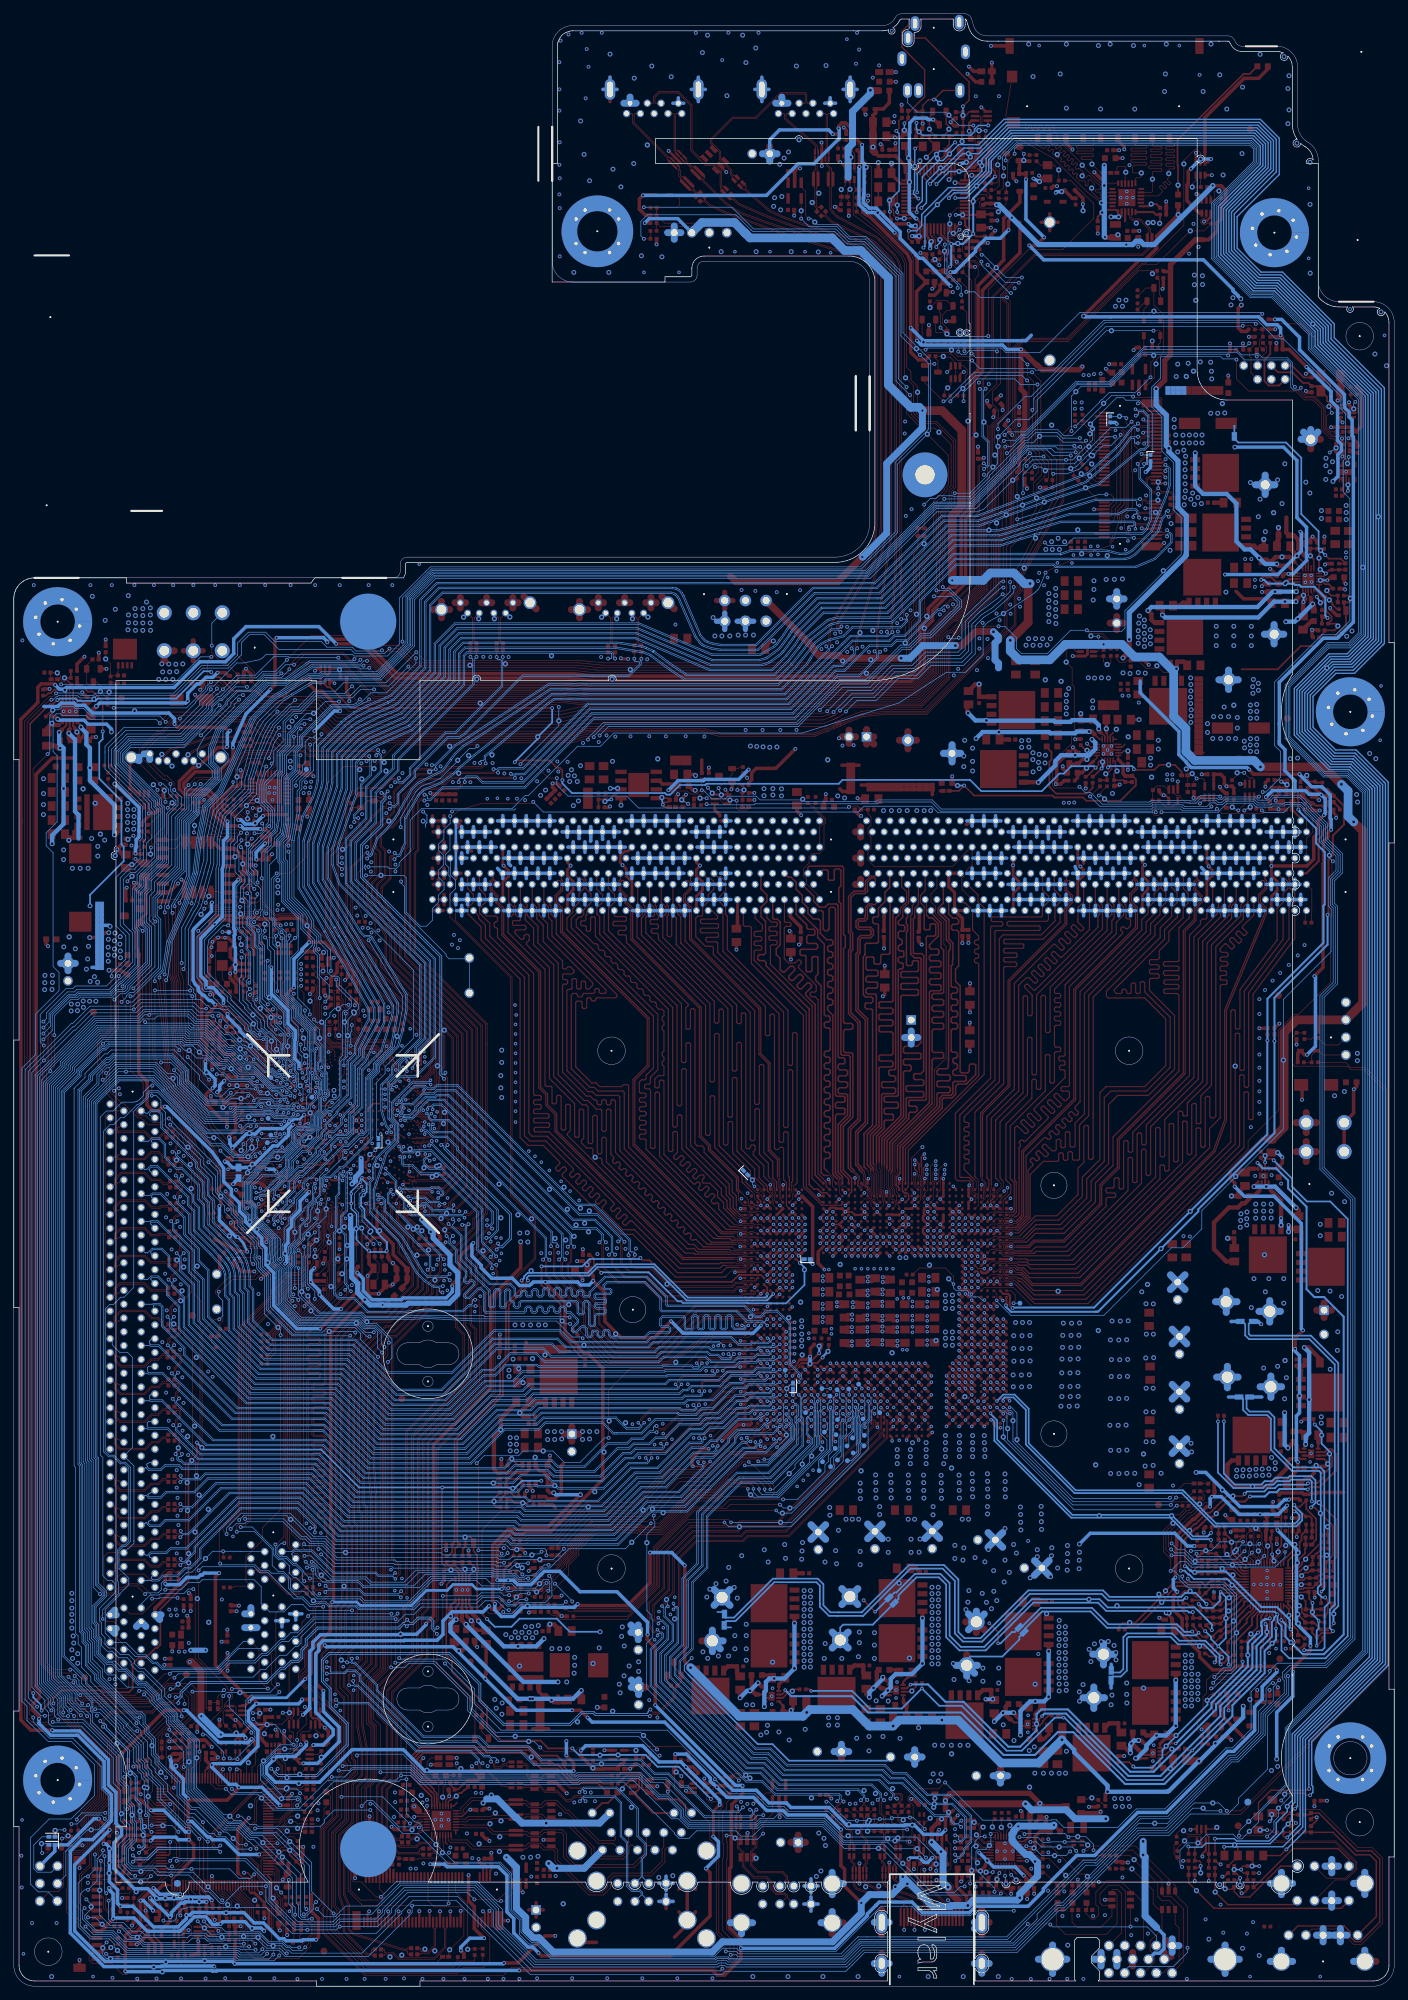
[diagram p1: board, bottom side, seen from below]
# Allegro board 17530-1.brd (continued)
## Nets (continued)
PWR_DDR4_LX: PC5008.2 PL5001.1 PR5004.2 PR5016.1 PU5001.16 PU5002.1 PU5002.2 PU5002.3 PU5003.5 PU5003.6 PU5003.7 PU5003.8
PWR_DDR4_UG: PR5005.2 PU5001.17
PWR_DDR4_UG1: PR5004.1 PR5005.1 PU5002.4
PWR_DDR4_VDDQ: PC5013.1 PR5019.1 PR5024.1 PU5001.5
PWR_DDR4_VTTREF: PC5015.1 PU5001.4
PWR_GT_BST1: PR4601.1 PU4602.1
PWR_GT_BST1_R: PC4603.1 PR4601.2
PWR_GT_BST2: PR4608.1 PU4605.1
PWR_GT_BST2_R: PC4608.1 PR4608.2
PWR_GT_COMP: PC4418.2 PC4419.2 PU4401.18
PWR_GT_COMP_A: PC4417.1 PR4439.2
PWR_GT_COMP_R: PC4418.1 PR4440.2
PWR_GT_CSCOMP: PC4424.1 PC4425.1 PR4451.1 PR4455.1 PR4457.2 PU4401.19
PWR_GT_CSN1: PC4420.2 PG4602.2 PR4443.2 PR4459.2 PU4401.24
PWR_GT_CSN2: PC4421.2 PG4604.2 PR4446.2 PR4460.2 PU4401.26
PWR_GT_CSP1: PG4601.2 PR4444.1 PR4449.2
PWR_GT_CSP1_IC: PC4420.1 PR4443.1 PR4444.2 PU4401.23
PWR_GT_CSP2: PG4603.2 PR4448.1 PR4453.2
PWR_GT_CSP2_IC: PC4421.1 PR4446.1 PR4448.2 PU4401.25
PWR_GT_CSREF: PC4427.1 PR4459.1 PR4460.1 PU4401.22
PWR_GT_CSSUM: PC4424.2 PC4425.2 PR4449.1 PR4452.2 PR4453.1 PU4401.21
PWR_GT_DOUT: PR4439.1 PR4442.1 PU4401.16
PWR_GT_EN1: PR4606.2 PU4602.3
PWR_GT_EN2: PR4612.2 PU4605.3
PWR_GT_FB: PC4417.2 PC4419.1 PR4440.1 PR4442.2 PU4401.17
PWR_GT_HG1: PR4604.1 PU4602.8
PWR_GT_HG1_R: PR4603.1 PR4604.2 PU4601.4
PWR_GT_HG2: PR4610.1 PU4605.8
PWR_GT_HG2_R: PR4609.1 PR4610.2 PU4604.4
PWR_GT_ILIM: PR4457.1 PU4401.20
PWR_GT_IOUT: PC4426.1 PR4458.1 PU4401.13
PWR_GT_LG1: PU4602.5 PU4603.4
PWR_GT_LG2: PU4605.5 PU4606.4
PWR_GT_PWM1: PR4465.1 PU4401.28 PU4602.2
PWR_GT_PWM2: PR4441.1 PU4401.29 PU4605.2
PWR_GT_SNB1: PC4605.1 PR4605.2
PWR_GT_SNB2: PC4610.1 PR4611.2
PWR_GT_SW1: PC4603.2 PG4601.1 PL4601.1 PR4603.2 PR4605.1 PU4601.1 PU4601.2 PU4601.3 PU4602.7 PU4603.5 PU4603.6 PU4603.7 PU4603.8
PWR_GT_SW2: PC4608.2 PG4603.1 PL4602.1 PR4609.2 PR4611.1 PU4604.1 PU4604.2 PU4604.3 PU4605.7 PU4606.5 PU4606.6 PU4606.7 PU4606.8
PWR_GT_TCP: PR4451.2 PR4452.1 PR4455.2
PWR_GT_TSNS: PC4428.1 PR4463.1 PU4401.27
PWR_GT_TSNS_R: PR4463.2 PR4467.1 PR4468.1
PWR_GT_VCC1: PC4604.2 PR4613.2 PU4602.4
PWR_GT_VCC2: PC4609.2 PR4614.2 PU4605.4
PWR_GT_VSN: PC4423.2 PR4450.2 PU4401.14
PWR_GT_VSP: PC4422.1 PR4447.2 PU4401.15
PWR_LED_G: C6402.1 PWRSW1.1 Q6401.6 R6409.2
PWR_LED_Y: C6403.1 PWRSW1.3 Q6401.3 R6413.2
PWR_PSYS: PR4462.1 PR4471.1 PU4401.8
PWR_RT6575_LDO5: PC4917.1 PG4903.1 PU4902.13
PWR_RT6575_PG: PR4958.1 PU4902.7
PWR_RT6575_VIN: PC4906.1 PR4932.2 PU4902.12
PWR_V_12V_CPU_S0_VSA: PC4701.1 PC4702.1 PC4703.1 PR4701.1 PR4702.1 PR4703.1 PR4704.1 PR4705.1 PR4706.1 PU4702.2 PU4702.3 PU4702.4 PU4702.10
PWR_VCCIO_DRV: PC4807.1 PR4810.2 PR4811.1 PU4801.5
PWR_VCCIO_DRV_R: PC4806.1 PR4810.1 PU4802.4
PWR_VCCIO_FB: PC4807.2 PC4811.2 PC4812.2 PR4814.2 PR4816.1 PU4801.3
PWR_VCCIO_FB1: PR4812.1 PR4813.1 PR4814.1
PWR_VCCIO_FB2: PC4811.1 PR4813.2
PWR_VCCIO_FB3: PC4812.1 PR4811.2
PWR_VCCIO_SS: PC4805.1 PU4801.4
PWR_VCCIO_VCC: PC4804.1 PR4808.2 PU4801.6
PWR_VCCIO_VCCSA_EN: PU4701.3 PU4801.1 R4801.2 U4801.3
PWR_VCCIO_VIN: PC4801.1 PC4802.1 PC4803.1 PR4801.1 PR4802.1 PR4803.1 PR4804.1 PR4805.1 PR4806.1 PR4807.1 PR4809.1 PU4802.5 PU4802.6 PU4802.7 PU4802.8
PWR_VCCSA_BOOT: PR4709.1 PU4701.10
PWR_VCCSA_BOOT_R: PC4704.2 PR4709.2
PWR_VCCSA_CS: PR4708.2 PU4701.2
PWR_VCCSA_FB: PC4708.2 PR4714.2 PR4716.1 PU4701.4
PWR_VCCSA_FB1: PC4708.1 PG4701.2 PR4715.1
PWR_VCCSA_LG: PU4701.6 PU4702.8
PWR_VCCSA_PG: PU4701.1 R4006.1
PWR_VCCSA_PHASE: PC4704.1 PL4701.1 PR4710.1 PR4713.1 PU4701.8 PU4702.9
PWR_VCCSA_RF: PR4711.1 PU4701.5
PWR_VCCSA_SNB: PC4707.1 PR4713.2
PWR_VCCSA_UG: PR4707.2 PU4701.9
PWR_VCCSA_UG_R: PR4707.1 PR4710.2 PU4702.1
PWR_VCCSA_VCC: PC4706.1 PR4712.1 PU4701.7
PWR_VCORE_BST1: PR4501.1 PU4502.1
PWR_VCORE_BST1_R: PC4503.1 PR4501.2
PWR_VCORE_BST2: PR4507.1 PU4506.1
PWR_VCORE_BST2_R: PC4508.1 PR4507.2
PWR_VCORE_BST3: PR4514.1 PU4510.1
PWR_VCORE_BST3_R: PC4513.1 PR4514.2
PWR_VCORE_BST4: PR4520.1 PU4514.1
PWR_VCORE_BST4_R: PC4518.1 PR4520.2
PWR_VCORE_COMP: PC4405.2 PC4406.2 PU4401.48
PWR_VCORE_COMP_A: PC4404.1 PR4407.2
PWR_VCORE_COMP_R: PC4405.1 PR4408.2
PWR_VCORE_CSCOMP: PC4413.1 PC4415.1 PR4427.1 PR4431.1 PR4433.2 PU4401.47
PWR_VCORE_CSN1: PC4407.2 PG4502.2 PR4412.2 PR4435.2 PU4401.36
PWR_VCORE_CSN2: PC4408.2 PG4504.2 PR4415.2 PR4436.2 PU4401.38
PWR_VCORE_CSN3: PC4410.2 PG4506.2 PR4419.2 PR4437.2 PU4401.40
PWR_VCORE_CSN4: PC4412.2 PG4508.2 PR4422.2 PR4438.2 PU4401.42
PWR_VCORE_CSP1: PG4501.2 PR4414.1 PR4426.2
PWR_VCORE_CSP1_IC: PC4407.1 PR4412.1 PR4414.2 PU4401.37
PWR_VCORE_CSP2: PG4503.2 PR4417.1 PR4429.2
PWR_VCORE_CSP2_IC: PC4408.1 PR4415.1 PR4417.2 PU4401.39
PWR_VCORE_CSP3: PG4505.2 PR4421.1 PR4432.2
PWR_VCORE_CSP3_IC: PC4410.1 PR4419.1 PR4421.2 PU4401.41
PWR_VCORE_CSP4: PG4507.2 PR4425.1 PR4434.2
PWR_VCORE_CSP4_IC: PC4412.1 PR4422.1 PR4425.2 PU4401.43
PWR_VCORE_CSREF: PC4416.1 PR4435.1 PR4436.1 PR4437.1 PR4438.1 PU4401.44
PWR_VCORE_CSSUM: PC4413.2 PC4415.2 PR4426.1 PR4428.2 PR4429.1 PR4432.1 PR4434.1 PU4401.45
PWR_VCORE_DOUT: PR4407.1 PR4409.1 PU4401.50
PWR_VCORE_DRVON: PR4506.1 PR4512.1 PR4518.1 PR4524.1 PR4606.1 PR4612.1 PU4401.30
PWR_VCORE_EN1: PR4506.2 PU4502.3
PWR_VCORE_EN2: PR4512.2 PU4506.3
PWR_VCORE_EN3: PR4518.2 PU4510.3
PWR_VCORE_EN4: PR4524.2 PU4514.3
PWR_VCORE_FB: PC4404.2 PC4406.1 PR4408.1 PR4409.2 PU4401.49
PWR_VCORE_HG1: PR4504.1 PU4502.8
PWR_VCORE_HG1_R: PR4503.1 PR4504.2 PU4501.4
PWR_VCORE_HG2: PR4510.1 PU4506.8
PWR_VCORE_HG2_R: PR4509.1 PR4510.2 PU4505.4
PWR_VCORE_HG3: PR4516.1 PU4510.8
PWR_VCORE_HG3_R: PR4515.1 PR4516.2 PU4509.4
PWR_VCORE_HG4: PR4522.1 PU4514.8
PWR_VCORE_HG4_R: PR4521.1 PR4522.2 PU4513.4
PWR_VCORE_ILIM: PR4433.1 PU4401.46
PWR_VCORE_IOUT: PC4414.1 PR4430.1 PU4401.1
PWR_VCORE_LG1: PU4502.5 PU4503.4 PU4504.4
PWR_VCORE_LG2: PU4506.5 PU4507.4 PU4508.4
PWR_VCORE_LG3: PU4510.5 PU4511.4 PU4512.4
PWR_VCORE_LG4: PU4514.5 PU4515.4 PU4516.4
PWR_VCORE_PWM1: PR4413.1 PU4401.34 PU4502.2
PWR_VCORE_PWM2: PR4424.1 PU4401.33 PU4506.2
PWR_VCORE_PWM3: PR4456.1 PU4401.32 PU4510.2
PWR_VCORE_PWM4: PR4403.1 PU4401.31 PU4514.2
PWR_VCORE_SCLK: PR4411.1 PU4401.5
PWR_VCORE_SDIO: PR4410.1 PU4401.3
PWR_VCORE_SNB1: PC4505.1 PR4505.2
PWR_VCORE_SNB2: PC4510.1 PR4511.2
PWR_VCORE_SNB3: PC4515.1 PR4517.2
PWR_VCORE_SNB4: PC4520.1 PR4523.2
PWR_VCORE_SW1: PC4503.2 PG4501.1 PL4501.1 PR4503.2 PR4505.1 PU4501.1 PU4501.2 PU4501.3 PU4502.7 PU4503.5 PU4503.6 PU4503.7 PU4503.8 PU4504.5 PU4504.6 PU4504.7 PU4504.8
PWR_VCORE_SW2: PC4508.2 PG4503.1 PL4502.1 PR4509.2 PR4511.1 PU4505.1 PU4505.2 PU4505.3 PU4506.7 PU4507.5 PU4507.6 PU4507.7 PU4507.8 PU4508.5 PU4508.6 PU4508.7 PU4508.8
PWR_VCORE_SW3: PC4513.2 PG4505.1 PL4503.1 PR4515.2 PR4517.1 PU4509.1 PU4509.2 PU4509.3 PU4510.7 PU4511.5 PU4511.6 PU4511.7 PU4511.8 PU4512.5 PU4512.6 PU4512.7 PU4512.8
PWR_VCORE_SW4: PC4518.2 PG4507.1 PL4504.1 PR4521.2 PR4523.1 PU4513.1 PU4513.2 PU4513.3 PU4514.7 PU4515.5 PU4515.6 PU4515.7 PU4515.8 PU4516.5 PU4516.6 PU4516.7 PU4516.8
PWR_VCORE_TCP: PR4427.2 PR4428.1 PR4431.2
PWR_VCORE_TSNS: PC4429.1 PR4464.1 PU4401.35
PWR_VCORE_TSNS_R: PR4464.2 PR4466.1 PR4469.1
PWR_VCORE_VCC: PC4402.1 PR4401.2 PR4462.2 PU4401.7
PWR_VCORE_VCC1: PC4504.2 PR4525.2 PU4502.4
PWR_VCORE_VCC2: PC4509.2 PR4526.2 PU4506.4
PWR_VCORE_VCC3: PC4514.2 PR4527.2 PU4510.4
PWR_VCORE_VCC4: PC4519.2 PR4528.2 PU4514.4
PWR_VCORE_VRMP: PC4403.1 PR4402.2 PU4401.9
PWR_VCORE_VSN: PC4411.2 PR4420.2 PU4401.52
PWR_VCORE_VSP: PC4409.1 PR4418.2 PU4401.51
PWR_VDDQ: PC5010.1 PL5001.2 PR5006.1 PR5008.1 PR5010.1 PR5011.1 PR5012.1 PR5013.1 PR5015.1 PR5017.1 PR5018.1 PR5019.2 PR5020.1 PR5021.1 PR5022.1 PR5023.1 PR5026.1 PR5027.1 PR5028.1 PR5029.1 PR5030.1 PT5001.1
PWR_VDDQ_PG: PU5001.10 R4802.2 U4801.2
PWR_VDDQ_PG_ISOLATE: R4803.1 U4801.5 U4801.6
PWR_VDDQ_S3_EN: PU5001.7 R5001.1 R5002.1
PWR_VDDQ_S5_EN: PU5001.8 R5003.2
PWR_VDDQ_SNB: PC5014.1 PR5016.2
PWR_VDDQ_TON: PR5009.2 PU5001.9
PWR_VDDQ_VDDP: PC5002.1 PR5002.1 PU5001.12
PWR_VDDQ_VIN: PC5003.1 PC5004.1 PC5005.1 PC5006.1 PC5007.1 PL5002.1 PL5003.1 PR5009.1 PU5002.5 PU5002.6 PU5002.7 PU5002.8
PWR_VDDQ_VIOP: PC5001.1 PR5001.2 PU5001.11
PWR_VTT: PC5011.1 PC5012.1 PG5005.2 PG5006.2 PU5001.2 PU5001.20
PWRBTN_N: C6404.1 C9904.1 R6417.2 R6420.2 R9920.1 SB1.BE46 U2401.34
PWRBTN_N_CN: R9920.2 TP9905.1
PWRGD_PS: Q2407.D R2435.2 U2401.123
PWRGD_VPP: PR5202.2 PU5201.7 U4010.2
Q82_B: Q2703.B R2718.2
Q83_B: Q2704.B R2719.2
Q84_B: Q2702.B Q2703.E Q2704.E R2717.2
Q84_E: Q2702.E R2715.1
Q84_E2: C2722.1 R2715.2 R2716.1
Q85_B: Q2701.B R2714.1 R2716.2
Q9103: Q9103.2 Q9103.5 R6304.1 U6303.D
RED_CRT: C5921.1 EU5901.3 L5903.2 VGA1.1
RP_AUDOUT_L: AUD1.22 C3006.1 L3003.2
RP_AUDOUT_R: AUD1.25 C3005.1 L3004.2
RP_LINE1_L: AUD1.32 C3004.1 L3001.2
RP_LINE1_R: AUD1.35 C3003.1 L3002.2
RP_MIC1_L: AUD1.2 C3010.1 L3005.2
RP_MIC1_R: AUD1.5 C3009.1 L3006.2
RSMRST_SIO_N: R2434.1 R2474.1 R9906.1 SB1.BA47 U6303.G
RSMRST_SIO_N_1: R2434.2 U2401.58
RTCRST_N_CN: R9919.2 TP9904.1
RTL_ISOLATE_N: R3103.2 R3106.1 U3101.20
S0_5V_EN: R4201.2 U4201.3
S3_QUK: R4001.2 U4002.2 U4002.3 U4003.G
S4_VPP_OR: Q4002.5 R4021.1
S4_VPP_OR_R: C4010.1 R4021.2 R4022.1 R4023.1
SATA_LED_OUT: LED1.K U6401.3 U6402.3
SATA_RX_CON_N0: C6004.2 SATA1.5
SATA_RX_CON_N2: C6007.2 SATA2.3
SATA_RX_CON_N3: C6012.2 SATA3.5
SATA_RX_CON_P0: C6003.2 SATA1.6
SATA_RX_CON_P2: C6008.2 SATA2.2
SATA_RX_CON_P3: C6011.2 SATA3.6
SATA_RX_PCH_N0: C6004.1 SB1.C45
SATA_RX_PCH_N1: C6210.1 SB1.D46
SATA_RX_PCH_N1_C: C6210.2 NGFF2.43
SATA_RX_PCH_N2: C6007.1 SB1.F44
SATA_RX_PCH_N3: C6012.1 SB1.L41
SATA_RX_PCH_P0: C6003.1 SB1.C46
SATA_RX_PCH_P1: C6209.1 SB1.C47
SATA_RX_PCH_P1_C: C6209.2 NGFF2.41
SATA_RX_PCH_P2: C6008.1 SB1.E45
SATA_RX_PCH_P3: C6011.1 SB1.M40
SATA_TX_CON_N0: C6001.2 SATA1.3
SATA_TX_CON_N2: C6006.2 SATA2.5
SATA_TX_CON_N3: C6010.2 SATA3.3
SATA_TX_CON_P0: C6002.2 SATA1.2
SATA_TX_CON_P2: C6005.2 SATA2.6
SATA_TX_CON_P3: C6009.2 SATA3.2
SATA_TX_PCH_N0: C6001.1 SB1.B38
SATA_TX_PCH_N1: C6211.1 SB1.C39
SATA_TX_PCH_N1_C: C6211.2 NGFF2.47
SATA_TX_PCH_N2: C6006.1 SB1.B40
SATA_TX_PCH_N3: C6010.1 SB1.B41
SATA_TX_PCH_P0: C6002.1 SB1.C38
SATA_TX_PCH_P1: C6212.1 SB1.D39
SATA_TX_PCH_P1_C: C6212.2 NGFF2.49
SATA_TX_PCH_P2: C6005.1 SB1.C40
SATA_TX_PCH_P3: C6009.1 SB1.C41
SB3V_CT2: C4202.1 U4201.10
SB3V_EN: R4202.2 U4201.5
SB5V_CT1: C4201.1 U4201.12
SD_CD_BD: SD1.10 U3301.13
SD_CLK_BD: C3305.1 R3301.1 SD1.5
SD_CMD_BD: SD1.2 U3301.18
SD_DATA0_BD: SD1.7 U3301.11
SD_DATA1_BD: SD1.8 U3301.10
SD_DATA2_BD: SD1.9 U3301.21
SD_DATA3_BD: SD1.1 U3301.20
SD_RCOMP: R1514.1 SB1.BD1 SB1.BE1 SB1.BE2 SB1.BE4 SB1.BE5
SD_WP_BD: SD1.11 U3301.8
SIO_GREEN: R6412.2 R6414.2 U2401.2 U2401.24
SIO_GREEN_1: Q6401.5 R6414.1
SIO_PECI_REQ_N: R2002.1 SB1.BF36 U2401.20
SIO_PS_ON_N: R4302.1 U2401.53
SIO_SMBCLK1: R2425.1 U2401.70
SIO_SMBCLK2: R2426.2 U2401.26
SIO_SMBDAT1: R2427.1 U2401.72
SIO_SMBDAT2: R2422.2 U2401.25
SIO_SPKR: R2452.2 R2453.1 U2401.125
SIO_YELLOW: R6410.2 R6411.2 U2401.23
SIO_YELLOW_1: Q6401.2 R6411.1
SKL_CNL_N: CPU1.AB36 R422.2
SKL_PCUDEBUG_0: CPU1.H15 R9913.1 TP404.1
SKL_PCUDEBUG_1: CPU1.F15 TP405.1
SKL_PCUDEBUG_2: CPU1.F16 TP406.1
SKL_PCUDEBUG_3: CPU1.H16 R423.1 TP407.1
SKL_PCUDEBUG_4: CPU1.F19 R424.1
SKL_PCUDEBUG_5: CPU1.H18 TP408.1
SKL_PCUDEBUG_6: CPU1.G21 TP409.1
SKL_PCUDEBUG_7: CPU1.H20 TP410.1
SKL_PCUDEBUG_8: CPU1.G16 TP411.1
SKL_PCUDEBUG_9: CPU1.E16 R425.1
SKL_PCUDEBUG_10: CPU1.F17 TP412.1
SKL_PCUDEBUG_11: CPU1.H17 TP413.1
SKL_PCUDEBUG_12: CPU1.G20 TP414.1
SKL_PCUDEBUG_13: CPU1.F20 TP415.1
SKL_PCUDEBUG_14: CPU1.F21 R426.1
SKL_PCUDEBUG_15: CPU1.H19 TP416.1
SKL_PCUSTB_0_DN: CPU1.E14 TP420.1
SKL_PCUSTB_0_DP: CPU1.F14 TP419.1
SKL_PCUSTB_1_DN: CPU1.G18 TP422.1
SKL_PCUSTB_1_DP: CPU1.F18 TP421.1
SLP_A_N_CN: R9916.2 TP9901.1
SLP_S0_N: DB2002.1 SB1.BC28 U9101.29
SLP_S0_PLT_N: DB2002.2 TP2002.1
SLP_S3_N: R2046.1 R4224.1 R4225.1 R5002.2 R9917.1 SB1.BF42 U2401.121 U4002.5
SLP_S3_N_CN: R9917.2 TP9902.1
SLP_S3_N_Q4205: C4226.1 Q4205.B R4225.2
SLP_S3_N_Q4207: C4227.1 Q4207.B R4224.2
SLP_S4_N: R809.2 R2045.1 R4020.1 R9918.1 SB1.BE42 U2401.69 U2401.122 U3201.4 U3801.4 U3901.4 U4010.1
SLP_S4_N_CN: R9918.2 TP9903.1
SLP_S4_N_SFR: C806.1 Q802.2 R809.1
SLP_S4_N_SFR_1: Q802.5 Q802.6 R807.2 R810.1
SLP_S4_N_SFR_2: Q802.3 R804.2 R805.1 R806.1
SLP_S4_N_SFR_G: C802.1 C803.1 Q801.G R805.2
SLP_S4_VPP_N: Q4002.2 R4020.2
SLP_S5_N: SB1.BC42 TP2003.1
SLP_SUSB: R2055.1 R4202.1 R5101.1 SB1.BD39 U2401.71
SLP_WLAN_N: D6301.K R2044.1 R2048.1 SB1.BD42
SM_DRAMRST#: C1108.1 DIMM1.58 DIMM2.58 R1104.2 SB1.BB46
SM_PGCNTL: CPU1.AC36 R416.2
SMB_CLK_MAIN: DIMM1.141 DIMM2.141 R5911.2 RN2405.1(A) U2401.81
SMB_CLK_RESUME: RN2404.1(A) SB1.BE26 SLOT1.B5 SLOT2.B5 U2401.80
SMB_DATA_MAIN: DIMM1.285 DIMM2.285 R5912.2 RN2405.2(A) U2401.79
SMB_DATA_RESUME: RN2404.2(A) SB1.BF26 SLOT1.B6 SLOT2.B6 U2401.78
SMBALERT_N: R2314.1 SB1.BE25
SML0ALERT#: R2323.1 SB1.BF24
SML0CLK_PCH: R2009.1 SB1.BF25
SML0DATA_PCH: R2010.1 SB1.BE24
SMLICLK_PCH: R2012.1 R2426.1 SB1.BF27
SMLIDATA_PCH: R2013.1 R2422.1 SB1.BE27
SP_CTS_N: RN2402.3(A) U2401.101
SP_DCD_N: RN2401.4(A) U2401.96
SP_DSR_N: RN2401.3(A) U2401.97
SP_DTR_N: RN2402.2(A) U2401.102
SP_RI_N: RN2402.1(A) U2401.103
SP_RTS_N: RN2401.1(A) U2401.99
SP_RXD_N: R6802.1 RN2401.2(A) U2401.98
SP_RXD_N_CON: LPC1.14 R6802.2
SP_TXD_N: Q2402.3 R2429.2 R2473.1
SP_TXD_N_1: Q2402.5 R2405.2
SP_TXD_SIO: R2429.1 R6801.1 U2401.100
SP_TXD_SIO_CON: LPC1.13 R6801.2
SPEED_100*_CON: EU3202.4 R3201.1 RJ45R1.19
SPEED_100_N: R3201.2 TP3102.1 U3101.26
SPEED_1000*_CON: EU3202.3 R3202.1 RJ45R1.20
SPEED_1000_N: R3202.2 TP3103.1 U3101.25
SPI_CLK_PCH: R1515.1 R9107.1 RN2502.4(B) SB1.AW47
SPI_CLK_ROM1: RN2502.1(A) SSKT1.6 SSKT2.16 U2501.6 U2502.16
SPI_CLK_TPM: R9107.2 U9101.19
SPI_CS_PCH_N0: SB1.AY47 SSKT1.1 SSKT2.7 U2501.1 U2502.7
SPI_CS_PCH_N2: R9108.1 R9928.2 SB1.AT40
SPI_HOLD_PCH: R2317.1 R2502.2 R2507.2 SB1.BA46
SPI_HOLD_ROM1: R2507.1 SSKT1.7 SSKT2.1 U2501.7 U2502.1
SPI_SI_PCH: R2325.1 R2326.1 R9106.1 R9903.1 RN2502.3(B) SB1.AU41
SPI_SI_ROM1: RN2502.2(A) SSKT1.5 SSKT2.15 U2501.5 U2502.15
SPI_SI_TPM: R9106.2 U9101.21
SPI_SO_PCH: R2328.1 R9113.1 RN2501.1(A) SB1.BA45
SPI_SO_PCH_TPM: R9105.1 R9113.2
SPI_SO_ROM1: RN2501.4(B) SSKT1.2 SSKT2.8 U2501.2 U2502.8
SPI_SO_TPM: R9105.2 U9101.24
SPI_WP_PCH: R2313.1 R2501.2 RN2501.2(A) SB1.AY48
SPI_WP_ROM1: RN2501.3(B) SSKT1.3 SSKT2.9 U2501.3 U2502.9
SPKR: R2302.1 R2304.1 R2702.2 SB1.AW29
SSD_PEDET: C6215.1 NGFF2.69 R1705.1 SB1.AM46
SSD_PEWAKE_N: NGFF2.54 R6202.1 R6203.1
SUS_ACK_EN_N: Q3801.1 R2419.1 R3809.2 U2401.94
SUS_PWR_ACK: C3806.1 R2004.1 R3807.2 R3809.1 R3810.1 R3812.2 SB1.BE35
SUS_PWR_ACK_5V_DUAL: R3811.2 R3814.1 R3815.1 R3818.1
SUS_PWR_ACK_5V_DUAL_L: C3807.1 Q3801.5 R3814.2
SUS_PWR_ACK_BJT: Q3801.2 R3813.2 R3817.1
SUS_PWR_ACK_BJT_L: Q3801.3 R3813.1 R3816.1
SUS_PWR_ACK_R: Q3801.6 R3808.2 R3810.2
SUS_WARNB: R2004.2 R2438.1 R2477.1 SB1.BC37
SUS_WARNB_R: C2412.1 R2438.2 U2401.68
SUSCLK: R1818.1 R1822.1 SB1.BE45
SUSCLK_SIO: R1818.2 U2401.19
SUSCLK_WIFI: NGFF1.50 R1822.2
SYS_FAN2_TACH_SIO: R2462.1 U2401.39
SYS_FAN_CTRL_CONN: D2602.A FANS1.4 R2614.2 R2616.2
SYS_FAN_CTRL_SIO: R2614.1 U2401.48
SYS_FAN_TACH_1: FANS1.3 R2615.2 R2618.1
SYS_FAN_TACH_SIO: R2476.1 R2617.1 R2618.2 U2401.38
SYS_THERMDA+: C2402.1 C2403.1 C2427.1 Q2403.B Q2403.C Q2409.E U2401.43
SYS_THERMDA-: C2402.2 C2403.2 C2427.2 Q2403.E Q2409.B Q2409.C U2401.44
TH_SET: R2611.1 U2601.1
THERMTRIP#_CPU: CPU1.D11 R1703.1 R1710.2
THERMTRIP#_PCH: R1710.1 SB1.AD3
TMIN_SHIFT: R2306.2 R2431.1 R2446.2 U2401.33
TMIN_SHIFT_PCH: R2306.1 R2307.1 R2309.1 SB1.BD33
TP_CLKIN_XTAL: R1816.1 SB1.R6
TP_CPU1_L8: CPU1.L8 TP903.1
TP_DIMM1_PIN1: DIMM1.1 R1102.1
TP_DIMM1_PIN145: DIMM1.145 R1102.2
TP_DIMM2_PIN1: DIMM2.1 R1202.1
TP_DIMM2_PIN145: DIMM2.145 R1202.2
TP_SLP_LAN_N: SB1.BF40 TP2001.1
TP_VCCPHY_SENSE: SB1.K47 TP2101.1
TP_VSS_AL37: SB1.AL37 TP1501.1
TP_VSSPHY_SENSE: SB1.K46 TP2102.1
TPEV_CFG_RCOMP: CPU1.M11 R418.1
TPM_CS: R9108.2 U9101.20
TPM_PIRQ: R9112.1 U9101.18
TPM_PP: TP9106.1 U9101.4
TPM_RST_R: Q9101.S R9110.2 R9111.2 U9101.17
TPM_VDD_P8: C9101.1 C9102.1 C9103.1 R9101.2 R9104.2 U9101.8 U9101.22
TRST_N: R2450.2 U2401.124
TS_CRIT#: R2613.2 U2601.3 U2602.2
U1.1: R3302.1 U3301.1
U1.6: C3304.1 U3301.6
U1.15: R3301.2 U3301.15
U1.24: C3303.1 U3301.24
UART0_RX: SB1.BE23 TP1505.1
UART0_TX: SB1.BB24 TP1504.1
UART_BT_WAKE_N: NGFF1.20 R2007.1 SB1.BE32
USB2_COMP: R1609.1 SB1.F4
USB2_ID: R1611.1 SB1.G3
USB2_VBUSSENSE: R1610.1 SB1.F3
USB30_RX_CON_N1: EU3801.1 EU3801.10 R3804.4 USB3F1.5
USB30_RX_CON_N2: EU3802.1 EU3802.10 R3806.4 USB3F2.5
USB30_RX_CON_P1: EU3801.2 EU3801.9 R3804.3 USB3F1.6
USB30_RX_CON_P2: EU3802.2 EU3802.9 R3806.3 USB3F2.6
USB30_RX_PCH_N1: R3804.1 SB1.D11
USB30_RX_PCH_N2: R3806.1 SB1.B9
USB30_RX_PCH_P1: R3804.2 SB1.C11
USB30_RX_PCH_P2: R3806.2 SB1.C9
USB30_TX_CMC_N1: C3802.2 R3801.1
USB30_TX_CMC_N2: C3804.2 R3802.1
USB30_TX_CMC_P1: C3801.2 R3801.2
USB30_TX_CMC_P2: C3803.2 R3802.2
USB30_TX_CON_N1: EU3801.4 EU3801.7 R3801.4 USB3F1.8
USB30_TX_CON_N2: EU3802.4 EU3802.7 R3802.4 USB3F2.8
USB30_TX_CON_P1: EU3801.5 EU3801.6 R3801.3 USB3F1.9
USB30_TX_CON_P2: EU3802.5 EU3802.6 R3802.3 USB3F2.9
USB30_TX_PCH_N1: C3802.1 SB1.F9
USB30_TX_PCH_N2: C3804.1 SB1.C3
USB30_TX_PCH_P1: C3801.1 SB1.F7
USB30_TX_PCH_P2: C3803.1 SB1.D4
USB_CON_PN1: EU3803.1 TR3801.4 USB3F1.2
USB_CON_PN2: EU3803.4 TR3802.4 USB3F2.2
USB_CON_PN5: EU3204.4 RJ45R1.2 TR3202.4
USB_CON_PN6: EU3204.1 RJ45R1.6 TR3201.4
USB_CON_PN7: EU3901.4 TR3902.3 USB2R1.6
USB_CON_PN8: R3303.2 U3301.2
USB_CON_PN9: EU3901.1 TR3901.3 USB2R1.2
USB_CON_PP1: EU3803.6 TR3801.3 USB3F1.3
USB_CON_PP2: EU3803.3 TR3802.3 USB3F2.3
USB_CON_PP5: EU3204.3 RJ45R1.3 TR3202.3
USB_CON_PP6: EU3204.6 RJ45R1.7 TR3201.3
USB_CON_PP7: EU3901.3 TR3902.4 USB2R1.7
USB_CON_PP8: R3303.1 U3301.3
USB_CON_PP9: EU3901.6 TR3901.4 USB2R1.3
USB_OC0_R_N: RN1901.4(A) SB1.AH36 U3801.3
USB_OC1_R_N: RN1901.3(A) SB1.AL40 U3901.3
USB_OC2_R_N: R1605.1 SB1.AJ44
USB_OC3_R_N: R1604.1 SB1.AL41 U3201.3
USB_OC4_R_N: R1607.1 SB1.AV47
USB_OC5_R_N: RN1901.1(A) SB1.AR35
USB_OC6_R_N: R1606.1 SB1.AR37
USB_PCH_PN1: SB1.J3 TR3801.1
USB_PCH_PN2: SB1.N13 TR3802.1
USB_PCH_PN5: SB1.M1 TR3202.1
USB_PCH_PN6: SB1.K7 TR3201.1
USB_PCH_PN7: SB1.L4 TR3902.2
USB_PCH_PN8: R3303.3 SB1.G4
USB_PCH_PN9: SB1.M6 TR3901.2
USB_PCH_PN14: NGFF1.5 SB1.E5
USB_PCH_PP1: SB1.J2 TR3801.2
USB_PCH_PP2: SB1.N15 TR3802.2
USB_PCH_PP5: SB1.L2 TR3202.2
USB_PCH_PP6: SB1.K6 TR3201.2
USB_PCH_PP7: SB1.L3 TR3902.1
USB_PCH_PP8: R3303.4 SB1.G5
USB_PCH_PP9: SB1.N8 TR3901.1
USB_PCH_PP14: NGFF1.3 SB1.F6
V_3_CARD_BD: C3306.1 C3307.1 F3301.2 SD1.4
V_CPU_ST_PLL: C803.2 C804.1 C805.1 C1032.1 C1033.1 C2411.1 CPU1.V4 CPU1.V5 CPU1.V6 PC4401.1 PR4404.1 PR4405.1 PR4406.1 Q801.S R401.1 R402.2 R403.1 R404.1 R803.2 R808.1 R1703.2 R2021.2 R2024.2 R2026.2 R2028.2 R2430.1 U2401.29
V_SM_VREF_CNT: C601.1 C602.1 CPU1.AB40 R601.1
V_VCC3P3_EN: C4209.1 C4210.1 Q4201.4 R4204.2
V_VCC3P3_EN_R: R4203.2 R4204.1 U4202.6
VCORE_VCC_SEN: CPU1.C38 PR4416.2 PR4418.1 R802.1
VCORE_VSS_SEN: CPU1.D38 PC4409.2 PC4411.1 PR4420.1 PR4423.1 R802.2
VCTRL_VCC_EN: Q2407.G R4206.2 U4202.2 U4202.3
VGA1_DETECT: R1701.2 R1706.1 SB1.P48
VGA_CABLE_DET_N: EU5901.6 R1502.1 SB1.Y48 VGA1.4
VIDALERT#_CPU: CPU1.E39 R405.2
VIDALERT#_CPU_R: PR4406.2 PU4401.4 R401.2 R405.1
VIDSCK_CPU: CPU1.E38 R407.2
VIDSCK_CPU_R: PR4405.2 PR4411.2 R407.1
VIDSOUT_CPU: CPU1.E40 R408.2
VIDSOUT_CPU_R: PR4404.2 PR4410.2 R403.2 R408.1
VPP_EN: C4009.1 PR5204.2 R4019.2
VPP_EN_CR: Q9102.C R4017.2 R4019.1
VPP_EN_DDR4: Q4002.3 Q4002.6 Q9102.B R4018.2
VR_ENABLE: R4005.2 R4006.2 R4007.1
VR_ENABLE_IMVP: PU4401.2 R4007.2 U4002.6
VR_READY: Q2405.1 R4013.2 R4015.1
VR_READY_A: R4011.2 U4009.1
VR_READY_B: R4015.2 U4009.2
VR_READY_IMVP: PU4401.6 R4003.2 R4013.1 U4003.D
VTT_EN: C4013.1 R4025.2 R5001.2
W_DISABLE#1: NGFF1.56 R6311.2
W_DISABLE#2: NGFF1.54 R6312.2
WAKE_M2_SSD_N: R1503.1 R6203.2 SB1.AL47
WLAN_PEDET: NGFF1.51 R1709.2 R9938.1 SB1.AR42
WLAN_USB_DET: NGFF1.1 R1901.1 R9939.1 SB1.AP48
XCLK_RBIAS: R1802.2 SB1.T3
XDP_PCUDEBUG_3: R423.2 R9904.2
XDP_PWR_DEBUG: R9912.2 R9913.2
XDP_PWRGD: R9906.2 R9907.2 R9908.2
XDP_VR_READY: C9901.1 R9903.2 R9905.2 R9923.2
XTAL_24M_PCH_IN: C1802.1 R1812.1 SB1.U10 X1801.3
XTAL_24M_PCH_OUT: C1801.1 R1812.2 SB1.U9 X1801.1

Pads without a net: CPU1 A12 A14 A16 A18 AB35 AB37 AB38 AC37 AJ22 AL15 AL25 AL26 AM15 AM25 AM26 AN17 AN20 AN21 AN25 AN26 AP15 AP19 AP20 AP25 AP26 AR25 AR26 AT16 AT33 AU9 AU10 AU12 AU16 AU29 AU31 AU32 AU33 AV1 AV10 AV13 AV16 AV24 AV25 AV31 AV32 AV33 AW2 AW16 AW29 AW31 AW33 AY10 AY31 B11 B12 B13 B14 B15 B16 B17 B18 B39 C9 C11 C13 C15 C17 C19 C40 D9 D10 D15 D18 D19 D20 E10 E18 E20 H8 J7 J8 J11 J13 J14 J15 J17 J19 K8 K10 K11 K12 K13 L10 L12; DIMM1 8 19 30 41 47 49 52 54 56 93 100 111 122 133 144 192 194 196 197 199 201 205 227 230 234 235 237; DIMM2 8 19 30 41 47 49 52 54 56 93 100 111 122 133 144 192 194 196 197 199 201 205 227 230 234 235 237; EU3201 5; EU3202 1 5; EU3203 5; EU3204 5; EU3803 5; EU3901 5; EU5603 5 6; EU5901 5; EU5902 5; HDMI1 13 14; LPC1 11 12; NGFF1 6 8 12 16 38 40 42 44 46 48 58 60 62 66 68 70; NGFF2 5 6 7 8 11 13 17 19 20 22 23 24 25 26 28 29 30 31 32 34 35 36 37 40 42 44 46 48 52 53 55 56 58 67 68; NOREF#44 1; NOREF#45 1; PU4401 11 12; PU4902 19; PWRSW1 8; RN2402 4 5; SB1 A17 A25 A42 A44 AA1 AA45 AB2 AB3 AB48 AC2 AC3 AC6 AC7 AC9 AC11 AC39 AC41 AC43 AC44 AC48 AD47 AD48 AE6 AE7 AE9 AE11 AE39 AE43 AE44 AE47 AE48 AF47 AG45 AH14 AH15 AH40 AH41 AH46 AH47 AH48 AJ6 AJ7 AJ43 AJ46 AJ47 AK47 AL35 AL48 AM7 AM43 AM45 AM47 AM48 AN4 AN6 AN10 AN18 AN29 AN35 AN46 AN47 AP2 AP9 AP21 AP24 AP29 AP47 AR2 AR13 AR18 AR47 AR48 AT5 AT10 AU4 AU9 AU24 AU26 AU46 AU47 AU48 AV6 AV7 AV13 AV16 AV18 AV34 AV44 AV46 AW2 AW3 AW13 AW15 AW18 AW21 AW24 AW26 AW32 AW48 B10 B14 B15 B17 B18 B19 B25 B26 B27 B35 B36 B42 B44 BA20 BA33 BB16 BB20 BC17 BC22 BC33 BD8 BD16 BD17 BD20 BD21 BD29 BD30 BE8 BE9 BE12 BE14 BE15 BE17 BE18 BE19 BE20 BE21 BE29 BE33 BE34 BF8 BF9 BF10 BF14 BF15 BF17 BF18 BF19 BF21 BF23 BF29 BF31 BF33 BF38 BF41 BG8 C10 C14 C15 C16 C17 C18 C19 C20 C21 C26 C27 C34 C35 C36 C42 C44 D20 D21 D29 D34 D38 D42 D43 E28 E37 F11 F14 F16 F26 F36 F39 F46 G1 G2 G12 G14 G17 G26 G36 G38 G45 G46 G47 G48 G49 H2 H3 H42 H47 H48 J13 J15 J18 J21 J37 J41 K3 K4 K13 K16 K18 K21 K29 K37 K43 K44 L9 L26 L46 L48 M10 M26 M29 M44 N2 N3 N18 N32 N42 N48 P9 P21 P24 P41 R10 R13 R15 R18 R21 R24 R32 R35 R37 R40 R44 R46 R47 T1 T2 T43 T46 T47 T48 U13 U35 U37 U40 U41 V2 V3 V47 W3 W4 W6 W7 W43 W44 W46 W47 Y2 Y3 Y4 Y14 Y15 Y35 Y36 Y40 Y41 Y46 Y47; SLOT1 A5 A6 A7 A8 B9; SLOT2 A5 A6 A7 A8 A19 A32 A33 A50 B9 B30 B82; SSKT2 3 4 5 6 11 12 13 14; U2401 5 6 13 49 56 61 62 63 64 67 73 74 76 84 85 87 89 91 93 95 105 106 107 110 112; U2502 3 4 5 6 11 12 13 14; U2701 17 18 21 22 29 30 41 42 46; U3301 7 9 12 14 16 17 19 22 23; U5901 31; U9101 2 3 5 6 7 9 10 11 12 13 14 15 25 26 27 28 30 31 32; VGA1 11

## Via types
v1: diameter 0.508, hole 0.254, TOP to BOTTOM, 1346 vias
v2: diameter 0.762, hole 0.381, TOP to BOTTOM, 918 vias
v3: diameter 0.559, hole 0.305, TOP to BOTTOM, 2123 vias
v4: diameter 0.711, hole 0.406, TOP to BOTTOM, 1126 vias

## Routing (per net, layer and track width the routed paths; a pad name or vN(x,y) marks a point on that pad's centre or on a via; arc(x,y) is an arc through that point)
1V_CPU_CORE: length 235.9
  TOP w0.254: v1(58.67,52.58) 57.4,51.31 v1(57.4,49.66) ; v1(75.21,54.23) v3(76.87,55.89)
  TOP w0.406: v1(59.44,84.71) 58.95,85.2 CPU1.F37
  TOP w0.432: CPU1.L30 v1(67.07,88.4) ; CPU1.G32 v1(63.95,85.66) CPU1.F32 ; v1(67.99,82) 67.98,82 CPU1.D29 ; CPU1.L25 v1(72.55,89.31) CPU1.L24 ; CPU1.M28 v1(69.81,90.23) ; CPU1.L17 v1(79.87,89.31) CPU1.L16 ; CPU1.G23 v1(74.38,85.66) ; CPU1.L23 v1(74.38,89.31) CPU1.L22 ; CPU1.M32 v1(63.04,90.23) CPU1.L33 v1(62.12,89.31) CPU1.K34 v1(61.21,88.4) CPU1.J35 ; v1(71.64,82.02) 71.18,81.57 CPU1.C26 ; v1(71.64,82.02) 72.07,82.46 CPU1.D25 ; v1(71.64,82.02) 72.1,81.57 CPU1.C25 ; CPU1.M16 v1(80.78,90.23) ; CPU1.G35 v1(61.21,86.57) CPU1.H34 v1(62.12,87.48) CPU1.J33 v1(63.04,88.4) CPU1.K32 v1(63.95,89.31) CPU1.L31 ; CPU1.J21 v1(76.21,87.48) CPU1.K20 ; CPU1.AJ21 v1(73.1,105.77) ; v1(68.91,79.11) 68.91,79.27 CPU1.A28 ; CPU1.C34 v1(62.12,82) ; CPU1.D31 v1(64.87,83.83) ; CPU1.M26 v1(71.64,90.23) ; CPU1.AJ18 v1(76.75,105.77) CPU1.AJ17 ; CPU1.M13 v1(82.61,89.31) CPU1.M14 ; CPU1.E30 v1(67.07,83.83) ; CPU1.L29 v1(68.89,89.31) CPU1.L28 ; CPU1.AJ27 v1(67.63,105.79) ; CPU1.L20 v1(76.21,89.31) CPU1.L21 ; v1(66.92,80.21) 67.02,80.21 CPU1.A30 ; CPU1.D32 v1(63.95,83.83) ; CPU1.H32 v1(63.95,87.48) ; CPU1.L26 v1(70.72,89.31) CPU1.L27 ; CPU1.M30 v1(67.98,90.23) ; CPU1.G29 v1(68.89,85.66) ; CPU1.L18 v1(78.04,89.31) CPU1.L19 ; CPU1.K31 v1(64.87,88.4) CPU1.J31 ; CPU1.F31 v1(64.87,85.66) ; CPU1.AJ26 v1(68.54,105.79) ; CPU1.K18 v1(78.95,87.48) ; CPU1.AJ25 v1(69.46,105.79) ; CPU1.J30 v1(67.07,87.48) ; CPU1.A27 70.64,79.34 v1(70.64,79.09) ; CPU1.B35 v1(61.21,81.08) ; CPU1.G27 v1(70.72,85.66) ; CPU1.M18 v1(78.95,90.23) ; CPU1.M20 v1(77.12,90.23) ; CPU1.E29 v1(68.89,83.83) ; CPU1.B36 59.84,81.52 v1(59.41,81.08) 58.95,81.54 CPU1.B37 ; CPU1.AJ15 v1(78.58,105.77) CPU1.AJ16 ; CPU1.AJ13 v1(81.33,105.77) ; CPU1.K16 v1(80.78,87.48) ; CPU1.J29 v1(68.89,87.48) ; CPU1.J23 v1(74.38,87.48) CPU1.K23 ; CPU1.L15 v1(81.7,89.31) CPU1.L14 ; CPU1.M22 v1(75.3,90.23) ; CPU1.G25 v1(72.55,85.66) ; CPU1.D36 v1(60.29,83.83) ; CPU1.J25 v1(72.55,87.48) ; CPU1.AJ19 v1(74.92,105.77) CPU1.AJ20 ; CPU1.AJ29 v1(65.8,105.79) ; CPU1.M24 v1(73.47,90.23) ; CPU1.D34 v1(62.12,83.83) ; CPU1.H31 v1(64.87,87.48) ; v1(63.04,87.48) CPU1.H33 v1(62.12,86.57) CPU1.G34 v1(61.21,85.66) ; CPU1.C36 v1(60.29,82) ; CPU1.D27 v1(69.81,82) ; CPU1.AJ28 v1(66.71,105.79) ; CPU1.B31 v1(64.87,81.08) ; CPU1.J27 v1(70.72,87.48) ; CPU1.C32 v1(63.95,82) ; CPU1.E27 v1(70.72,83.83) ; CPU1.G30 v1(67.07,85.66) ; CPU1.B33 v1(63.04,81.08)
  TOP w0.508: v3(74.13,100.23) 74.83,100.23 PC1022.1 74.9,100.91 v3(74.12,100.91) ; v3(74.1,102.01) 73.38,102.01 PC1023.1 73.36,102.69 v3(74.1,102.69) ; v1(74.14,93.57) 74.94,93.57 PC1007.1 74.85,92.94 v1(74.16,92.94) ; v1(78.56,92.79) 79.27,92.79 PC1005.1 79.41,93.42 v1(78.56,93.42) ; v3(28.96,63.75) 28.07,63.75 28.04,63.78 PR4416.1 ; v1(76.31,96.55) 77.19,96.55 PC1019.1 76.92,97.18 v1(76.31,97.18) ; v1(80.76,98.45) 79.96,98.45 PC1018.1 79.93,99.09 v1(80.76,99.09) ; v1(76.31,95.45) 77.02,95.45 PC1006.1 77.08,94.82 v1(76.31,94.82) ; v1(72,97.08) 72.82,97.08 PC1004.1 72.59,96.39 v1(72,96.39) ; v1(74.16,98.53) 74.9,98.53 PC1021.1 74.88,99.16 v1(74.16,99.16) ; v1(72,95.45) 72.7,95.45 PC1008.1 72.72,94.77 v1(72,94.77)
  TOP w1.016: PT4502.1 52.11,61.63 ; PT4502.1 52.11,59.52 ; PT4502.1 50,61.63 ; PT4502.1 50,59.52 ; PL4503.2 80.01,55.29 ; PL4503.2 77.72,57.59 ; PL4503.2 77.72,55.29 ; PL4503.2 80.01,57.59 ; PT4505.1 67.98,64.86 ; PT4505.1 65.87,66.97 ; PT4505.1 67.98,66.97 ; PT4505.1 65.87,64.86 ; 74.18,64.83 PT4507.1 ; PT4507.1 74.18,66.94 ; PT4507.1 76.29,64.83 ; PT4507.1 76.29,66.94 ; PL4501.2 42.12,49.63 ; PL4501.2 43.67,48.08 ; PL4501.2 42.12,46.53 ; PL4501.2 40.57,48.08 ; 96.24,57.46 PL4504.2 ; PL4504.2 96.24,55.17 ; PL4504.2 98.53,55.17 ; PL4504.2 98.53,57.46 ; PT4503.1 58.84,63.59 ; PT4503.1 56.73,63.59 ; PT4503.1 58.84,65.7 ; PT4503.1 56.73,65.7 ; 59.39,51.62 PL4502.2 ; PL4502.2 60.54,54.32 ; PL4502.2 62.09,52.77 ; PL4502.2 60.54,51.22 ; 82.38,66.84 PT4508.1 ; PT4508.1 84.49,64.73 ; PT4508.1 84.49,66.84 ; PT4508.1 82.38,64.73
  BOTTOM w0.254: PG4504.1 54.99,51.31 55.37,51.31 57.02,49.66 v1(57.4,49.66) ; PG4508.1 98.07,54.2 ; PG4506.1 v1(75.21,54.23)
  BOTTOM w0.508: v4(45.61,64.03) 44.03,65.61 31.81,65.61 29.95,63.75 v3(28.96,63.75) ; PG4502.1 41,46.63
  BOTTOM w1.016: 65.87,66.97 PT4505.1 ; PT4505.1 67.98,66.97 ; PT4505.1 65.87,64.86 ; PT4505.1 67.98,64.86 ; 82.38,64.73 PT4508.1 ; PT4508.1 84.49,66.84 ; PT4508.1 84.49,64.73 ; PT4508.1 82.38,66.84 ; PT4503.1 58.84,65.7 ; PT4503.1 56.73,65.7 ; PT4503.1 56.73,63.59 ; PT4503.1 58.84,63.59 ; 40.57,48.08 PL4501.2 ; PL4501.2 42.12,46.53 ; PL4501.2 43.67,48.08 ; PL4501.2 42.12,49.63 ; PT4507.1 76.29,64.83 ; PT4507.1 76.29,66.94 ; PT4507.1 74.18,66.94 ; PT4507.1 74.18,64.83 ; PL4502.2 61.68,51.62 ; PL4502.2 59.39,53.92 ; PL4502.2 60.54,54.32 ; PL4502.2 61.68,53.92 ; PT4502.1 52.11,61.63 ; PT4502.1 52.11,59.52 ; PT4502.1 50,59.52 ; PT4502.1 50,61.63 ; PL4503.2 80.01,57.59 ; PL4503.2 77.72,57.59 ; PL4503.2 77.72,55.29 ; PL4503.2 80.01,55.29 ; PL4504.2 98.53,57.46 ; PL4504.2 98.53,55.17 ; PL4504.2 96.24,55.17 ; PL4504.2 96.24,57.46
  vias: v1(60.29,84.75) v1(70.59,92.18) v1(71.22,92.2) v1(71.72,79.08) v1(72.53,83.84) v1(72.62,103.93) v1(73.44,84.75) v1(73.44,83.84) v1(73.53,103.93) v1(74.44,103.93) v1(75.36,103.93) v1(75.84,105.77) v1(76.27,103.93) v1(76.26,98.93) v1(76.28,98.3) v1(77.19,103.93) v1(77.67,105.77) v1(78.1,103.93) v1(79.5,105.77) v1(82.61,87.48) v2(42.72,68.15) v2(44.22,56.03) v2(62.2,85.39) v2(64.14,75.06) v2(67.33,104.45) v2(72.75,91.74) v2(77.24,74.65) v2(80.26,104.55) v3(53.04,64.49) v4(40.34,48.34) v4(40.31,47.27) v4(40.59,49.35) v4(41.43,49.94) v4(42.44,49.91) v4(43.43,49.58) v4(43.94,47.02) v4(44.2,48.79) v4(45.61,62.86) v4(45.64,61.7) v4(45.65,60.47) v4(47.34,63.83) v4(47.34,62.66) v4(47.37,61.5) v4(47.38,60.27) v4(48.77,60.58) v4(49.6,63.51) v4(49.66,62.36) v4(49.78,59.31) v4(51.13,68.41) v4(51.12,67.28) v4(51.09,66.17) v4(51.15,69.5) v4(51.71,63.22) v4(51.71,62.2) v4(52.73,59.16) v4(54.13,68.32) v4(54.12,67.2) v4(54.09,66.08) v4(54.15,69.41) v4(54.74,62.74) v4(55.14,63.98) v4(55.75,59.94) v4(56.34,70.87) v4(56.39,74.2) v4(56.37,73.11) v4(56.37,71.98) v4(56.39,66.29) v4(56.39,61.72) v4(56.52,58.55) v4(57.58,55.85) v4(58.04,60.2) v4(58.01,57.2) v4(58.34,54.69) v4(58.8,63.25) v4(58.94,74.23) v4(58.91,73.14) v4(58.91,72.01) v4(58.88,70.9) v4(58.93,69.47) v4(58.92,68.4) v4(59.08,55.6) v4(59.31,77.72) v4(59.31,76.71) v4(59.31,61.47) v4(59.38,79.76) v4(59.38,78.74) v4(59.69,56.9) v4(60.73,62.08) v4(61.09,79.76) v4(61.09,78.74) v4(61.09,77.72) v4(61.09,76.71) v4(61.14,74.23) v4(61.11,73.14) v4(61.11,72.01) v4(61.08,70.9) v4(61.62,57.3) v4(61.77,55.63) v4(62.05,54.56) v4(62.36,63.5) v4(62.48,61.72) v4(62.99,79.76) v4(62.99,78.74) v4(62.99,77.72) v4(62.99,76.71) v4(63.03,72.94) v4(63.02,71.81) v4(62.99,70.7) v4(63.05,74.03) v4(63.65,63.86) v4(63.65,61.95) v4(65.02,79.76) v4(65.02,78.74) v4(65.02,77.72) v4(65.02,76.71) v4(65.27,75.68) v4(65.63,72.91) v4(65.62,71.78) v4(65.6,70.67) v4(65.65,74) v4(66.8,69.47) v4(66.81,68.28) v4(67.82,78.74) v4(67.82,77.72) v4(67.82,76.71) v4(67.82,75.69) v4(68.14,70.7) v4(68.19,74.03) v4(68.17,72.94) v4(68.17,71.81) v4(68.71,64.77) v4(68.83,62.87) v4(69.79,78.72) v4(70,64.74) v4(70,62.84) v4(70.1,77.72) v4(70.1,76.71) v4(70.1,75.69) v4(70.34,70.7) v4(70.39,74.03) v4(70.37,72.94) v4(70.37,71.81) v4(72.01,77.72) v4(72.01,76.71) v4(72.01,75.69) v4(72.94,74.06) v4(72.91,72.97) v4(72.91,71.84) v4(72.88,70.73) v4(73.3,64.74) v4(73.3,62.84) v4(74.55,69.47) v4(74.55,68.33) v4(75.14,74.06) v4(75.11,72.97) v4(75.11,71.84) v4(75.08,70.73) v4(77.34,70.63) v4(77.37,72.87) v4(77.37,71.74) v4(77.37,62.97) v4(77.37,61.06) v4(80.52,66.04) v4(80.8,61.19) v4(80.92,63.09) v4(81.79,69.34) v4(81.75,68.23) v4(82.47,61.44) v4(85.72,64.26) v4(85.8,63.04) v4(85.85,61.85) v4(88.19,61.98) v4(88.32,63.98) v4(90.7,61.44) v4(91.26,63.22) v4(94.54,62.36) v4(95.17,56.21) v4(95.63,57.76) v4(96.42,60.66) v4(96.8,58.67) v4(98.27,58.29) v4(99.16,57.51) v4(99.59,56.36)
1V_CPU_GT: length 143.5
  TOP w0.432: CPU1.R36 v1(60.29,92.97) CPU1.P36 ; CPU1.P38 v1(58.47,92.97) CPU1.R38 ; CPU1.U38 v1(58.47,94.8) CPU1.T38 ; CPU1.Y33 v1(63.04,98.46) ; CPU1.W36 v1(60.29,96.63) CPU1.V36 ; CPU1.L39 v1(56.64,90.23) CPU1.L40 ; CPU1.P40 v1(56.64,92.97) CPU1.R40 ; CPU1.G38 v1(58.47,86.57) ; CPU1.Y38 v1(58.47,98.46) CPU1.AA37 ; CPU1.M38 v1(58.47,91.14) ; CPU1.J37 v1(58.47,88.4) CPU1.J38 ; CPU1.N37 v1(59.38,92.06) CPU1.N36 ; CPU1.H40 v1(56.64,87.48) ; CPU1.K40 v1(56.64,89.31) ; CPU1.M33 v1(63.04,91.14) ; CPU1.U34 v1(62.12,94.8) CPU1.T34 ; CPU1.AB33 v1(63.04,100.29) ; CPU1.AA38 v1(57.55,98.46) ; CPU1.J40 v1(56.64,88.4) CPU1.J39 ; CPU1.R34 v1(62.12,92.97) CPU1.P34 ; CPU1.M34 v1(62.12,91.14) ; CPU1.W38 v1(58.47,96.63) CPU1.V38 ; CPU1.R35 v1(61.21,93.89) ; CPU1.G37 v1(59.38,86.57) ; CPU1.N40 v1(56.64,92.06) CPU1.N39 v1(57.55,92.06) CPU1.N38 ; CPU1.M40 v1(56.64,91.14) ; CPU1.L35 v1(60.29,90.23) CPU1.L36 ; CPU1.U35 v1(61.21,95.71) ; CPU1.G39 v1(57.55,86.57) ; CPU1.G40 v1(56.64,86.57) ; CPU1.AA35 v1(61.21,99.37) ; CPU1.L34 v1(62.12,90.23) ; CPU1.W37 v1(59.38,97.54) ; CPU1.Y36 v1(60.29,98.46) CPU1.AA36 ; CPU1.R39 v1(57.55,93.89) ; CPU1.AA34 v1(62.12,98.46) CPU1.Y34 ; CPU1.M36 v1(60.29,91.14) ; CPU1.U39 v1(57.55,95.71) ; CPU1.V33 v1(63.04,96.63) ; CPU1.L37 v1(58.47,90.23) CPU1.L38 ; CPU1.N34 v1(61.21,92.06) CPU1.N35 ; CPU1.AB34 v1(62.12,100.29) ; CPU1.U36 v1(60.29,94.8) CPU1.T36 ; CPU1.V40 v1(56.64,96.63) ; v1(60.29,88.4) CPU1.J36 ; CPU1.W35 v1(61.21,97.54) ; CPU1.T33 v1(63.04,94.8) ; CPU1.W34 v1(62.12,96.63) CPU1.V34 ; CPU1.H38 v1(58.47,87.48) ; CPU1.U40 v1(56.64,95.71) ; CPU1.U37 v1(59.38,95.71) ; CPU1.K38 v1(58.47,89.31) ; CPU1.K36 v1(60.29,89.31) ; CPU1.P33 v1(63.04,92.97) ; CPU1.T40 v1(56.64,94.8) ; CPU1.R37 v1(59.38,93.89)
  TOP w0.457: PR4445.1 13.85,70.61 15.12,70.61 v3(15.24,70.48)
  TOP w1.016: PT4604.1 32.17,93.05 ; PT4604.1 30.06,95.16 ; PT4604.1 32.17,95.16 ; PT4604.1 30.06,93.05 ; PL4602.2 24.33,100.7 ; PL4602.2 25.88,99.15 ; PL4602.2 24.33,97.6 ; PL4602.2 22.78,99.15 ; PL4601.2 25.72,88.23 ; PL4601.2 22.62,88.23 ; PL4601.2 24.17,86.68 ; PL4601.2 24.17,89.78 ; PT4602.1 32.17,77.18 ; PT4602.1 30.06,79.29 ; PT4602.1 32.17,79.29 ; PT4602.1 30.06,77.18 ; PT4605.1 32.17,85.05 ; PT4605.1 32.17,87.16 ; PT4605.1 30.06,87.16 ; PT4605.1 30.06,85.05 ; PT4603.1 32.42,100.93 ; PT4603.1 32.42,103.04 ; PT4603.1 30.31,100.93 ; PT4603.1 30.31,103.04
  BOTTOM w0.508: 23.62,96.27 23.6,96.29 PG4604.1 ; v4(28.7,74.42) 27.3,74.42 22.35,69.47 16.9,69.47 15.89,70.48 15.61,70.48 15.6,70.48 v3(15.24,70.48) ; PG4602.1 24,85.34
  BOTTOM w1.016: 30.31,100.93 PT4603.1 ; PT4603.1 30.31,103.04 ; PT4603.1 32.42,103.04 ; PT4603.1 32.42,100.93 ; 24.17,86.68 PL4601.2 ; PL4601.2 25.72,88.23 ; PL4601.2 22.62,88.23 ; PL4601.2 24.17,89.78 ; 30.06,93.05 PT4604.1 ; PT4604.1 32.17,93.05 ; PT4604.1 30.06,95.16 ; PT4604.1 32.17,95.16 ; 30.06,85.05 PT4605.1 ; PT4605.1 32.17,87.16 ; PT4605.1 32.17,85.05 ; PT4605.1 30.06,87.16 ; PL4602.2 24.33,100.7 ; PL4602.2 22.78,99.15 ; PL4602.2 24.33,97.6 ; PL4602.2 25.88,99.15 ; 30.06,79.29 PT4602.1 ; PT4602.1 32.17,79.29 ; PT4602.1 32.17,77.18 ; PT4602.1 30.06,77.18
  vias: v1(67.67,97.08) v1(67.67,96.39) v1(67.67,93.57) v1(67.67,92.89) v1(69.82,97.13) v1(69.8,96.44) v2(35.74,101.65) v2(36.32,77.09) v2(42.88,94.97) v2(43.26,75.51) v2(66.19,100.91) v2(66.4,93.52) v4(29.44,78.64) v4(29.36,77.39) v4(33.78,74.3) v4(34.9,98.83) v4(34.85,91.04) v4(34.9,83.19) v4(34.92,75.44) v4(35.97,98.85) v4(36,91) v4(35.97,83.2) v4(36.09,75.34) v4(36.58,100.58) v4(37.59,74.3) v4(38.54,96.38) v4(38.62,90.78) v4(38.65,88.34) v4(38.73,77.65) v4(38.73,74.3) v4(38.76,93.64) v4(38.76,85.14) v4(38.85,81.28) v4(39.68,96.34) v4(39.77,90.74) v4(39.8,88.3) v4(39.91,93.6) v4(39.91,85.1) v4(39.88,77.61) v4(39.88,74.26) v4(40,81.24) v4(40.88,96.36) v4(40.97,90.76) v4(41,88.31) v4(41.11,93.61) v4(41.11,85.11) v4(41.08,77.63) v4(41.08,74.27) v4(41.2,81.26) v4(45.59,96.07) v4(45.68,94.3) v4(45.71,92.55) v4(45.79,90.87) v4(45.82,88.87) v4(45.82,86.9) v4(45.79,85.44) v4(45.94,84.04) v4(46.74,96.03) v4(46.82,94.26) v4(46.85,92.51) v4(46.94,90.83) v4(46.94,85.4) v4(46.97,88.83) v4(46.97,86.86) v4(47.08,84) v4(47.94,96.04) v4(48.02,94.27) v4(48.05,92.53) v4(48.14,90.84) v4(48.14,85.41) v4(48.17,88.84) v4(48.17,86.87) v4(48.28,84.01) v4(52.83,96.14) v4(52.78,94.25) v4(52.78,92.4) v4(52.75,90.57) v4(52.84,86.85) v4(52.86,88.57) v4(53.85,96.14) v4(53.92,94.21) v4(53.92,92.36) v4(53.9,90.53) v4(54.01,88.53) v4(53.98,86.81) v4(54.86,96.14) v4(55.12,94.23) v4(55.12,92.37) v4(55.1,90.54) v4(55.21,88.54) v4(55.18,86.83) v4(64.01,100.1) v4(64.01,99.19) v4(64.01,98.17) v4(64.01,94.77) v4(64.01,93.85) v4(64.01,92.84) v4(65.02,100.1) v4(65.02,99.19) v4(65.02,98.17) v4(65.02,94.77) v4(65.02,93.85) v4(65.02,92.84)
1V_PCH_SB: length 180.2
  TOP w0.254: SB1.E1 SB1.D1 ; SB1.AE17 152.88,120.06 152.68,120.26 152.68,120.79 SB1.AD20
  TOP w0.305: v1(151.91,120.79) 152.3,121.17 SB1.AD20
  TOP w0.356: Q2406.1 166.87,40.71 166.39,40.71 v3(165.86,41.24)
  TOP w0.406: v3(129.29,57.53) 128.98,57.84 128.98,60.3 128.13,61.15 R9909.1
  TOP w0.508: v3(157.79,44.48) 156.9,45.38 156.9,48.68 154.13,51.45 154.13,55.37 v3(153.86,55.64) 153.68,55.82 153.68,66.04 154.08,66.44 154.08,94.51 v2(149.15,99.44) 147.32,99.44 v1(146.56,98.68) 146.18,98.68 L2102.1 ; v4(155.19,147.04) 155.19,147.76 C2113.1 ; C2114.1 155.38,149.44 155.12,149.71 v4(155.12,149.76) ; C2116.1 166.47,130.56 166.37,130.47 166.25,130.47 166.23,130.44 v3(166.17,130.44) ; v3(161.42,140.33) 161.47,140.33 161.48,140.34 161.49,140.34 161.81,140.65 C2123.1 ; C2120.1 154.27,143.28 154.67,143.28 v3(154.88,143.48) 154.88,143.7 155.07,143.89 C2124.1 ; v3(140.91,111.04) 140.27,111.04 138.86,109.63 138.86,109.32 138.23,108.69 C2115.1 ; PR5133.2 PR5134.2 PR5135.2 PR5117.2 PR5119.2 PR5118.2 PR5126.2 186.81,152.61 v4(186.25,152.61) ; C2117.1 169.2,139.9 169.81,140.51 169.85,140.51 169.91,140.58 v3(170.36,140.58)
  BOTTOM w0.406: v3(129.29,57.53) 132.97,57.53 133.63,58.19 136.35,58.19 137.21,57.33 140.21,57.33 142.39,55.14 149.78,55.14 150.28,55.64 v3(153.86,55.64) ; v3(157.79,44.48) 160.49,41.78 165.32,41.78 v3(165.86,41.24)
  BOTTOM w0.508: PR5132.2 PR5131.2 PR5130.2 PR5129.2 PR5128.2 ; PR5128.2 PR5127.2 PR5126.2 PR5120.2 PR5121.2 PR5122.2 PR5123.2 PR5124.2 PR5125.2 ; PR5128.2 186.22,153.67 v4(186.05,153.51)
  BOTTOM w0.762: v3(151.26,111.63) 151.19,111.57 151.19,109.66 151.05,109.52 151.05,109.23 151.04,109.21 151.04,103.63 151.04,103.62 151.04,102.67 150.16,101.8 150.16,100.45 148.4,98.68 v1(146.56,98.68) 146.53,98.65 143.15,98.65 142.88,98.93 136.96,98.93 135.68,100.21 135.68,103.34 136.8,104.47 136.8,105.93 139.24,108.37 139.24,109.37 v3(140.91,111.04) ; v1(149.68,119.91) 149.68,118.01 150.5,117.19 150.5,116.72 150.52,116.7 150.52,116.69 v3(151,116.2)
  vias: v1(149.61,126.25) v1(149.59,125.44) v1(149.59,124.66) v1(149.59,123.89) v1(150.38,121.61) v1(151.91,125.44) v1(151.91,124.66) v1(151.91,123.94) v1(151.89,122.3) v1(152.69,126.21) v1(152.66,122.31) v3(149.17,140.54) v3(149.37,141.33) v4(184.59,152.02) v4(184.63,150.95) v4(184.56,149.95) v4(184.56,148.97) v4(185.34,152.55) v4(185.41,151.43) v4(185.42,150.25) v4(185.42,149.33) v4(186.31,151.64) v4(186.33,150.49) v4(186.33,149.41) v4(186.31,148.46)
1V_VCCA_XTAL: length 14
  TOP w0.254: 147.37,111.71 SB1.P2 147.37,112.79 SB1.P3
  TOP w0.508: L2102.2 143.76,101.22 143,101.98 C2119.1 143,102.95 143,102.95 143,103.78 C2118.1 143.03,103.97 145.03,105.98 145.03,107.47 v2(147,109.44) 147.37,109.81 147.37,111.71
1V_VCCAMPHYPLL:
  vias: v2(144.48,137.59)
1V_VCCDSW: length 7.4
  TOP w0.203: SB1.BG45 SB1.BG46 163.74,133.96 165.15,135.37 165.23,135.37
  TOP w0.305: C2125.1 167.08,138.13 166.62,137.67 166.62,137.1 v2(165.71,136.19) 165.71,135.85 165.23,135.37
5V_AUD_S5: length 18.1
  TOP w0.305: 70.84,262.74 70.66,262.56 U2701.24
  TOP w0.508: 70.84,262.74 70.84,263.68 72.26,265.1 C2704.1 C2708.1 R2701.1 74.74,265.11 75.24,265.61 ; D2701.1 74.04,271.91 73.15,272.8 L2701.1
  TOP w0.559: C2705.1 75.51,270.97 75.14,271.34 D2701.1
  TOP w1.016: 75.24,265.61 75.51,265.89 v2(75.51,266.4) C2709.1 C2705.1
5V_DDC_HDMI:
  vias: v2(66.62,26.42)
5V_DISPLAY_S0: length 27.1
  TOP w0.203: 53.09,21.46 53.37,21.18 53.49,21.18 53.72,20.96 U5901.17
  TOP w0.508: 53.09,21.46 52.82,21.73 C5906.1 52.82,24.42 C5907.1
  TOP w0.762: U5602.3 65.02,27.18 D5601.A 52.81,27.94 v2(51.33,26.47) ; C5907.1 52.81,24.99 v2(51.33,26.47) ; v2(51.33,26.47) 50.88,26.02 Q5901.D
5V_DISPLAY_SFR_G: length 4.1
  TOP w0.102: R5918.2 41.85,26.11 42.26,26.52 42.4,26.52 R5919.1 43.52,26.99 v2(43.81,27.28) 44.3,27.28 44.55,27.03 Q5901.G
5V_HDMI_CONN: length 15.9
  TOP w0.305: HDMI1.18 63,12.25 63.17,12.42
  TOP w0.635: v4(67.02,20.85) 67.02,22.82 U5602.2
  TOP w1.016: v4(64.64,14.35) 64.52,14.22 64.52,13.76 63.17,12.42
  BOTTOM w1.016: v4(67.02,20.85) v2(65.67,19.5) 65.36,19.19 65.36,16.13 65.35,16.13 65.35,15.06 v4(64.64,14.35)
5V_S0: length 247.7
  TOP w0.406: Q2402.4 158.99,32.68 158.58,32.27
  TOP w0.508: v3(116.87,38.91) 117.92,39.97 v3(119.13,39.97) ; C9910.1 v3(54.33,228.75) ; v3(65.02,22.61) 65.02,24.36 63.88,25.5 ; v3(56.73,228.3) 56.73,228.98 56.97,229.22 ; v4(45.01,241.91) 40.92,246 40.92,246.01 36.92,250.01 36.14,250.01 34.42,251.74 34.42,253.49 v2(31.29,256.62) 31.29,257.96 R6418.1 ; C9909.1 v3(60.3,223) ; v3(154.94,49.38) 155.16,49.38 156.17,48.36 156.17,43.83 v3(155.14,42.8) ; R6419.1 16.68,238.93 v3(16.46,239.14) 16.18,238.86 C9902.1 15.22,237.08 12.71,234.57 v3(12.71,234.54) ; C9907.1 57.95,227.41 v3(58.09,227.26) ; 158.58,32.27 v3(158.04,32.27) ; v3(131.67,44.5) 131.67,45.16 131.57,45.26 PR4712.2 ; 56.39,226.09 56.39,226.29 55.96,226.72 55.96,226.77 v3(55.92,226.8)
  TOP w0.762: 92.81,197.71 SATAP1.2 ; SATAP1.2 94,196.52 ; SATAP1.2 95.19,197.71
  TOP w1.016: 62.74,26.54 62.61,26.42 v4(53.42,26.42)
  BOTTOM w0.508: v3(154.94,49.38) 154.73,49.17 136.34,49.17 v3(131.67,44.5) 127.14,39.97 v3(119.13,39.97) ; v3(16.46,239.14) 16.46,240.16 16.56,240.26 16.56,240.28 16.95,240.66 18.47,240.66 19.62,241.81 41.05,241.81 44.77,241.81 44.87,241.91 v4(45.01,241.91) ; v4(8.88,217.97) 8.15,218.7 8.15,221.29 8.17,221.3 8.17,221.85 7.65,222.37 7.65,223.33 8.22,223.91 8.22,224.45 8.2,224.47 8.2,228.68 9.14,229.62 9.14,229.72 9.14,229.72 9.14,230.27 9.14,230.27 9.14,231 12.68,234.54 v3(12.71,234.54) ; v3(158.04,32.27) 155.99,32.27 152.87,35.4 152.87,37.53 155.14,39.8 v3(155.14,42.8) ; v3(116.87,38.91) 116.21,38.25 105.7,38.25 95.83,28.38 92.41,28.38 90.58,26.54 88.06,26.54 87.4,25.88 81.84,25.88 79.22,23.27 70.94,23.27 70.84,23.37 69.55,23.37 68.18,22 65.63,22 v3(65.02,22.61)
  BOTTOM w0.762: 92.81,197.71 SATAP1.2 ; SATAP1.2 95.19,197.71 ; SATAP1.2 94,196.52
  BOTTOM w1.016: v4(53.42,26.42) 52.55,25.55 47.52,25.55 46.23,24.26 v4(41.78,24.26)
  vias: v2(4.55,205.51) v4(5.31,171.53) v4(5.33,135.13) v4(5.33,134.06) v4(5.44,172.62) v4(6.12,196.29) v4(6.88,195.54) v4(9.91,218.25) v4(12.22,216.28) v4(12.8,217.86) v4(92.84,195.71) v4(93.98,195.71) v4(95.05,195.71)
5V_S5: length 243
  TOP w0.203: v3(7.51,221.58) 7.37,221.58 6.96,221.17 U4201.4
  TOP w0.508: v3(14.7,45.54) 14.7,46.08 12.14,48.63 v3(12.14,49.3) ; v3(81.05,257.73) 80.85,257.73 80.35,257.24 R3816.2 ; v3(168,3.25) 168,3.91 167.96,3.95 167.96,5.98 167.92,6.02 167.92,6.67 R2468.1 ; v3(165.53,35.81) 165.03,35.31 165.03,35.21 164.97,35.16 R2419.2 ; PR5002.2 47.37,178.54 48.9,177.01 48.9,174.75 49.02,174.62 v3(49.02,174.12) 48.34,174.12 47.83,174.62 PR5001.1 ; PU5201.6 106.51,174.62 106.02,174.14 104.04,174.14 PC5202.1 103.94,173.69 104.18,173.69 104.64,173.23 v3(105.16,173.23) ; v3(170.49,190.26) 170.48,190.27 169.38,190.27 168.91,189.8 R4301.1 ; v3(128.98,3.35) 126.97,3.35 123.04,7.29 v3(121.54,7.29) ; v3(175.37,39.96) 175.39,39.98 178.08,39.98 184.86,33.2 184.86,25.67 185.93,24.6 185.93,24.2 186.22,23.91 186.22,22.74 v3(186.11,22.63) ; v3(16.89,66.04) 17.02,66.17 PR4401.1 ; v3(7.51,221.58) 7.41,221.68 C4203.1
  TOP w0.635: v4(188.03,185.41) 188.85,184.59 PR5115.2
  TOP w0.762: v3(8.18,229.69) 7.8,230.07 7.8,231.06 R6413.1 R6409.1 ; Q5901.S 42.82,25 v3(42.55,25.27)
  TOP w1.016: v4(75.9,274.62) 75.84,274.57 L2701.2
  BOTTOM w0.508: v3(170.49,190.26) 171.17,189.59 172.16,189.59 173.1,188.65 173.43,188.65 174.8,187.27 v3(174.8,186.16) 175.08,185.88 187.56,185.88 v4(188.03,185.41) ; v3(186.11,22.63) 191.18,17.56 191.18,7.98 186.81,3.61 168.35,3.61 v3(168,3.25) 129.08,3.25 v3(128.98,3.35) ; v3(12.14,49.3) 12.14,50.5 14.15,52.5 14.15,63.3 v3(16.89,66.04) ; v3(93.55,176.23) 94.97,174.8 99.9,174.8 99.93,174.78 100.08,174.62 103.76,174.62 v3(105.16,173.23) ; v3(14.7,45.54) 14.7,41.98 17.02,39.66 v4(17.02,32.89) ; v3(165.53,35.81) 165.68,35.67 166.06,35.28 166.61,35.28 166.64,35.31 170.29,35.31 174.95,39.96 v3(175.37,39.96)
  BOTTOM w1.016: 79.12,262 79.12,266.24 78.49,266.88 78.49,271.55 75.9,274.14 v4(75.9,274.62)
  vias: v2(28.75,244.2) v2(29.08,233.93) v2(30.12,233.17) v2(35.03,248.06) v2(92.46,18.54) v2(120.4,11.94) v4(2.67,177.8) v4(3.56,178.56) v4(8.95,220.82) v4(9.3,219.35) v4(9.89,221.33) v4(9.89,220.24) v4(14,177.89) v4(15.06,177.8) v4(16.89,31.83) v4(17.78,31.24) v4(26.44,232.82) v4(26.48,233.92) v4(26.59,235.23) v4(27.79,247.75) v4(27.76,246.48) v4(28.09,235.28) v4(28.96,247.85) v4(28.96,246.46) v4(29.84,235.08) v4(31.37,234.95) v4(31.59,233.16) v4(65.66,30.73) v4(66.04,29.72) v4(66.8,30.73) v4(67.18,29.64) v4(82.4,20.37) v4(82.63,21.41) v4(83.37,22.18) v4(88.72,259.23) v4(88.9,257.3) v4(89.78,259.06) v4(89.92,257.81) v4(124.06,18.8) v4(125.12,18.67) v4(126.24,18.67)
5V_USB_FRONT: length 25.6
  TOP w0.508: R3811.1 80.53,268.27 v3(81.33,268.27)
  TOP w1.016: 90.47,264.38 TC3801.1 ; TC3801.1 90.47,266.48 ; TC3801.1 91.53,265.43 ; TC3801.1 89.42,265.43
  BOTTOM w0.508: v3(81.33,268.27) 81.94,268.88 89.05,268.88 90.47,267.46 TC3801.1
  BOTTOM w1.016: 109.83,272.75 USB3F2.1 ; USB3F2.1 111.61,272.75 ; USB3F2.1 110.72,273.64 ; 90.47,264.38 TC3801.1 ; TC3801.1 91.53,265.43 ; TC3801.1 89.42,265.43 ; USB3F1.1 89.61,272.75 ; USB3F1.1 87.83,272.75 ; USB3F1.1 88.72,273.64
  vias: v2(86.23,267.46) v2(108.2,266.7) v4(87.76,265.68) v4(88.39,264.8) v4(89.03,263.91)
5V_USB_REAR: length 20.7
  TOP w0.508: USB2R1.1 85.53,11.9 ; USB2R1.1 84.5,10.87 ; USB2R1.1 84.5,12.93 ; USB2R1.1 83.47,11.9 ; 84.5,13.49 USB2R1.5 ; USB2R1.5 84.5,15.55 ; USB2R1.5 83.47,14.52 ; USB2R1.5 85.53,14.52
  TOP w1.016: TC3901.1 87.41,20.83 ; TC3901.1 86.36,21.88 ; TC3901.1 85.31,20.83 ; TC3901.1 86.36,19.77
  BOTTOM w0.508: 84.5,10.87 USB2R1.1 ; USB2R1.1 85.53,11.9 ; USB2R1.1 84.5,12.93 ; USB2R1.1 83.47,11.9 ; 83.47,14.52 USB2R1.5 ; USB2R1.5 84.5,13.49 ; USB2R1.5 85.53,14.52 ; USB2R1.5 84.5,15.55
  vias: v4(83.06,16.69) v4(83.72,15.9)
5V_USB_RJ45: length 19.7
  TOP w0.508: 104.47,14.9 RJ45R1.5 ; RJ45R1.5 105.5,15.93 ; RJ45R1.5 105.5,13.87 ; RJ45R1.5 106.53,14.9 ; 124.33,9.99 TC3201.1 ; TC3201.1 124.33,12.1 ; TC3201.1 125.39,11.05 ; TC3201.1 123.28,11.05 ; 104.47,12.28 RJ45R1.1 ; RJ45R1.1 105.5,13.31 ; RJ45R1.1 106.53,12.28 ; RJ45R1.1 105.5,11.25
  BOTTOM w0.508: RJ45R1.1 105.5,13.31 ; RJ45R1.1 104.47,12.28 ; RJ45R1.1 106.53,12.28 ; RJ45R1.5 105.5,15.93 ; RJ45R1.5 106.53,14.9 ; RJ45R1.5 104.47,14.9 ; RJ45R1.5 105.5,13.87
  vias: v4(104.52,16) v4(106.55,15.75)
5V_VGA_CONN: length 19.7
  BOTTOM w0.508: VGA1.9 34.73,4.77 34,4.77 33.36,5.42 33.36,7.45 34.42,8.51
  BOTTOM w1.016: 34.42,8.51 36.09,10.19 36.09,18.73 v2(36.37,19.01) v4(36.37,20.98)
12V_CPU: length 122.7
  TOP w0.508: 7.26,71.53 11.11,71.53 11.24,71.39 12.08,71.39 12.24,71.24 13.08,71.24 13.28,71.45 16.42,71.45 PR4402.1 ; R4222.1 25.3,41.08 25.3,40.44 24.77,39.9 24.77,38.99 21.72,35.94 ; v3(118.89,31.17) 118.9,31.17 118.9,32.33 119.94,33.38 v3(119.94,33.43) ; v3(157.61,35.31) 158.03,35.73 R2402.1 ; 122.5,37.29 PR4706.2 PR4705.2 PR4704.2 PR4703.2 PR4702.2 PR4701.2
  TOP w1.016: PT4501.1 70.53,33.2 ; PT4501.1 69.47,34.25 ; PT4501.1 68.42,33.2 ; PT4501.1 69.47,32.14 ; 12.75,119.44 ATX2.3 ; ATX2.3 12.75,122.34 ; ATX2.3 11.3,120.89 ; ATX2.3 14.2,120.89 ; PT4601.1 11.21,97.91 ; PT4601.1 10.16,98.97 ; PT4601.1 9.11,97.91 ; PT4601.1 10.16,96.86 ; PT4506.1 58.11,30.48 ; PT4506.1 57.05,29.43 ; PT4506.1 57.05,31.53 ; PT4506.1 56,30.48 ; ATX2.4 14.2,125.09 ; ATX2.4 11.3,125.09 ; ATX2.4 12.75,126.54 ; ATX2.4 12.75,123.64 ; PT4504.1 80.09,35.04 ; PT4504.1 80.09,32.93 ; PT4504.1 79.03,33.99 ; PT4504.1 81.14,33.99
  BOTTOM w0.508: v3(118.89,31.17) 118.95,31.11 140.41,31.11 143.56,34.26 150.98,34.26 155.7,29.55 162.1,29.55 163.37,30.82 163.37,31.78 161.88,33.27 159.2,33.27 157.61,34.87 v3(157.61,35.31) ; v3(119.94,33.43) v3(119.94,35.51)
  BOTTOM w1.016: 56,30.48 PT4506.1 ; PT4506.1 58.11,30.48 ; PT4506.1 57.05,29.43 ; 69.47,32.14 PT4501.1 ; PT4501.1 68.42,33.2 ; PT4501.1 69.47,34.25 ; PT4501.1 70.53,33.2 ; PT4504.1 81.14,33.99 ; PT4504.1 80.09,35.04 ; PT4504.1 79.03,33.99
  vias: v2(52.83,28.83) v2(64.14,33.66) v4(7.21,129.59) v4(7.19,113.64) v4(7.62,99.9) v4(8.18,94.79) v4(8.23,92.1) v4(8.64,128.98) v4(9.07,114.86) v4(9.3,100.69) v4(9.27,89.36) v4(11.07,100.76) v4(38.35,26.04) v4(38.48,27.18) v4(39.37,26.04) v4(39.5,27.18) v4(40.39,26.04) v4(40.51,27.18) v4(47.62,30.86) v4(48.54,30.84) v4(49.66,30.86) v4(50.83,30.85) v4(52.07,30.86) v4(61.75,34.9) v4(62.89,34.9) v4(64.16,34.9) v4(65.43,34.9) v4(66.57,34.91) v4(71.6,35.89) v4(74.07,36.17) v4(76.1,36.17) v4(76.1,34.09) v4(77.88,35.92) v4(80.67,38.89) v4(80.67,37.82) v4(81.94,38.89) v4(81.94,37.82) v4(85.34,37.21) v4(87.66,35.66) v4(89.15,36.83) v4(90.81,37.8) v4(90.93,36.78) v4(91.77,36.4)
12V_CPU_N: length 12.1
  TOP w0.102: R4223.2 25.26,42.39 25.27,42.41 25.27,42.85 24.56,43.56 21.46,43.56 20.9,43 v2(20.9,41.53) 20.9,39.71 Q4206.G 20.68,39.67 19.91,40.43 C4224.1 19.02,42.06 C4225.2
12V_CPU_S0: length 187.4
  TOP w0.508: R5918.1 41.85,27.84 v4(41.53,28.17) ; v3(118.31,55.36) 118.16,55.14 111.08,55.14 107.82,58.39 v3(107.82,62.81) ; PR4808.1 122.31,71.48 v4(121.77,71.48) ; v4(117.9,71.19) 122.61,66.5 126.16,66.5 126.49,66.17 128.35,66.17 130.61,63.9 130.61,55.81 130.3,55.5 v3(130.3,55.37) ; v3(102.81,60.95) 102.79,60.95 102.79,46.98 v4(101.96,46.15)
  TOP w1.143: v4(85.12,39.65) 85.17,39.7 PR4528.1 ; v4(48.13,35.7) 48.1,35.73 48.1,37.42 PR4526.1 ; PR4527.1 v4(72.59,37.68) ; v4(28.3,32.61) 29.87,32.61 PR4525.1
  BOTTOM w0.508: v3(118.31,55.36) 118.78,54.89 126.26,54.89 127.6,53.55 129.36,53.55 130.3,54.49 v3(130.3,55.37) ; v3(102.81,60.95) 104.67,62.81 v3(107.82,62.81) ; v4(121.77,71.48) 121.49,71.19 v4(117.9,71.19)
  BOTTOM w0.635: v4(48.13,35.7) 47.84,35.7 46.37,34.23 46.37,33.9 41.53,29.06 v4(41.53,28.17) 32.86,28.17 32.76,28.27 32.64,28.27 v4(28.3,32.61) 28.21,32.61 21.88,38.95 v4(21.88,40.55)
  BOTTOM w1.27: v4(48.13,35.7) 51.5,32.33 56.97,32.33 63.18,38.54 v2(65.53,38.54) 71.73,38.54 v4(72.59,37.68) 76.06,37.68 78.45,40.07 84.7,40.07 v4(85.12,39.65) 85.66,39.1 94.91,39.1 v4(101.96,46.15)
12V_S0: length 431.3
  TOP w0.508: PR4613.1 15.57,73.2 13.96,74.82 v3(13.96,75.93) ; C9310.1 v3(178.18,46.55) ; v3(13.21,95) 14.35,93.85 v3(14.35,92.33) ; v3(163.6,165.53) 163.43,165.7 163.16,165.7 162.81,166.05 162.81,166.89 163.52,167.59 164.28,167.59 v3(164.29,167.6) ; v3(164.85,163.2) 164.84,163.19 C9106.1 163.89,163.3 163.89,164.37 Q9101.G ; v3(167.22,168.05) 168.22,168.05 168.22,168.05 169.33,168.05 171.09,169.82 171.09,171.73 172.07,172.71 172.79,172.71 172.84,172.65 175.24,172.65 176.01,173.42 176.01,174.52 174,176.53 173.35,176.53 172.3,177.56 170.44,179.43 169.19,179.43 v3(169.11,179.51) ; R4203.1 v3(42.11,194.36) ; R2601.1 11.05,139.97 ; R2615.1 v3(108.58,255.4) ; v3(23.11,115.82) 23.11,116.35 23.74,116.97 23.74,118.05 19.11,122.68 PR4614.1 ; v3(168.66,181.86) 168.93,181.86 169.42,182.35 176.25,182.35 v3(176.72,182.82) ; C9405.1 v3(169.04,45.69)
  TOP w0.762: SATAP1.4 98.19,200.71 ; SATAP1.4 97,199.52 ; SATAP1.4 95.81,200.71 ; SATAP1.4 97,201.9 ; SATAP1.1 97,198.9 ; SATAP1.1 98.19,197.71 ; SATAP1.1 97,196.52
  TOP w1.016: v3(77.06,207.01) 80.62,203.45 95.38,203.45 96.14,204.22
  TOP w1.27: v4(19.38,176.61) 10.16,176.61 v4(7.65,174.09) ; v4(5.87,168.65) 4.57,167.35 4.57,142.4 FANC1.2 14.13,139.97 15.95,138.15 15.95,124.41 17.68,122.68 PR4614.1 ; v4(55.63,194.94) 53.04,197.54 53.04,202.9 v4(52.76,203.17) ; v3(64.03,203.63) 64.03,212.98 63.49,213.52 63.49,213.58 62.65,214.42 62.65,215.81 62.64,215.82 62.64,216.69 62.65,216.7 62.65,225.36 65.51,228.22 v3(68.35,228.22)
  BOTTOM w0.508: v3(168.66,181.86) 169.06,181.46 169.06,179.56 v3(169.11,179.51) ; 195.65,185.37 193.6,185.37 193.12,185.85 191.27,185.85 190.95,185.53 189.72,185.53 188.6,184.42 177.55,184.42 176.72,183.59 v3(176.72,182.82) ; v3(108.58,255.4) 107.95,256.03 103.8,256.03 FANS1.2 ; v3(23.11,115.82) 21.72,114.43 17.4,114.43 14.67,111.7 14.67,111.7 13.46,110.49 13.46,95.25 v3(13.21,95) ; v3(14.35,92.33) 14.35,91.97 13.72,91.34 v2(13.72,85.52) 13.72,83.06 14.17,82.6 14.17,76.15 v3(13.96,75.93) ; v3(164.85,163.2) 164.9,163.25 164.9,164.24 v3(163.6,165.53) ; v3(164.29,167.6) 164.34,167.65 166.67,167.65 167.08,168.05 v3(167.22,168.05)
  BOTTOM w0.762: 97,196.52 SATAP1.1 ; SATAP1.1 98.19,197.71 ; SATAP1.1 97,198.9
  BOTTOM w1.016: v3(77.06,207.01) 77,207.01 73.53,210.47 73.53,220.55 68.35,225.73 v3(68.35,228.22)
  BOTTOM w1.27: v3(64.03,203.63) 59.56,203.63 58.5,204.7 55.09,204.7 53.57,203.17 v4(52.76,203.17) ; v4(19.38,176.61) 20.32,177.55 28.91,177.55 30.18,178.82 30.18,182.17 31.96,183.95 31.96,190.45 34.04,192.53 37.62,192.53 39.45,194.36 v3(42.11,194.36) 47.66,194.36 49.9,192.13 54.36,192.13 55.63,193.4 v4(55.63,194.94) ; v4(5.87,168.65) 6.68,169.45 6.68,173.13 v4(7.65,174.09) ; v3(68.35,228.22) 68.83,228.7 70.06,228.7 73.28,231.92 73.28,247.42 77.26,251.41 79.63,251.41 81.46,253.24 93.35,253.24 93.9,253.79 94.1,254 95.58,255.47 100.3,255.47 FANS1.2
  vias: v4(96.27,195.58) v4(97.41,195.58) v4(98.42,195.58) v4(98.68,198.25) v4(180.21,199.64) v4(180.21,198.63) v4(180.24,197.46) v4(180.19,196.39) v4(180.78,200.49) v4(181.31,199.54) v4(181.31,198.53) v4(181.31,197.46) v4(181.31,196.39) v4(182.44,199.54) v4(182.37,198.53) v4(182.37,197.46) v4(182.37,196.39) v4(183.39,198.63) v4(183.39,197.49) v4(183.46,196.48) v4(190.74,48.16) v4(190.73,46.79) v4(191.32,49.71) v4(191.41,50.72) v4(191.49,47.47) v4(191.59,48.72) v4(194.41,146.43) v4(194.41,145.39) v4(194.46,144.37) v4(195.49,146.4) v4(195.51,145.36) v4(195.53,144.35)
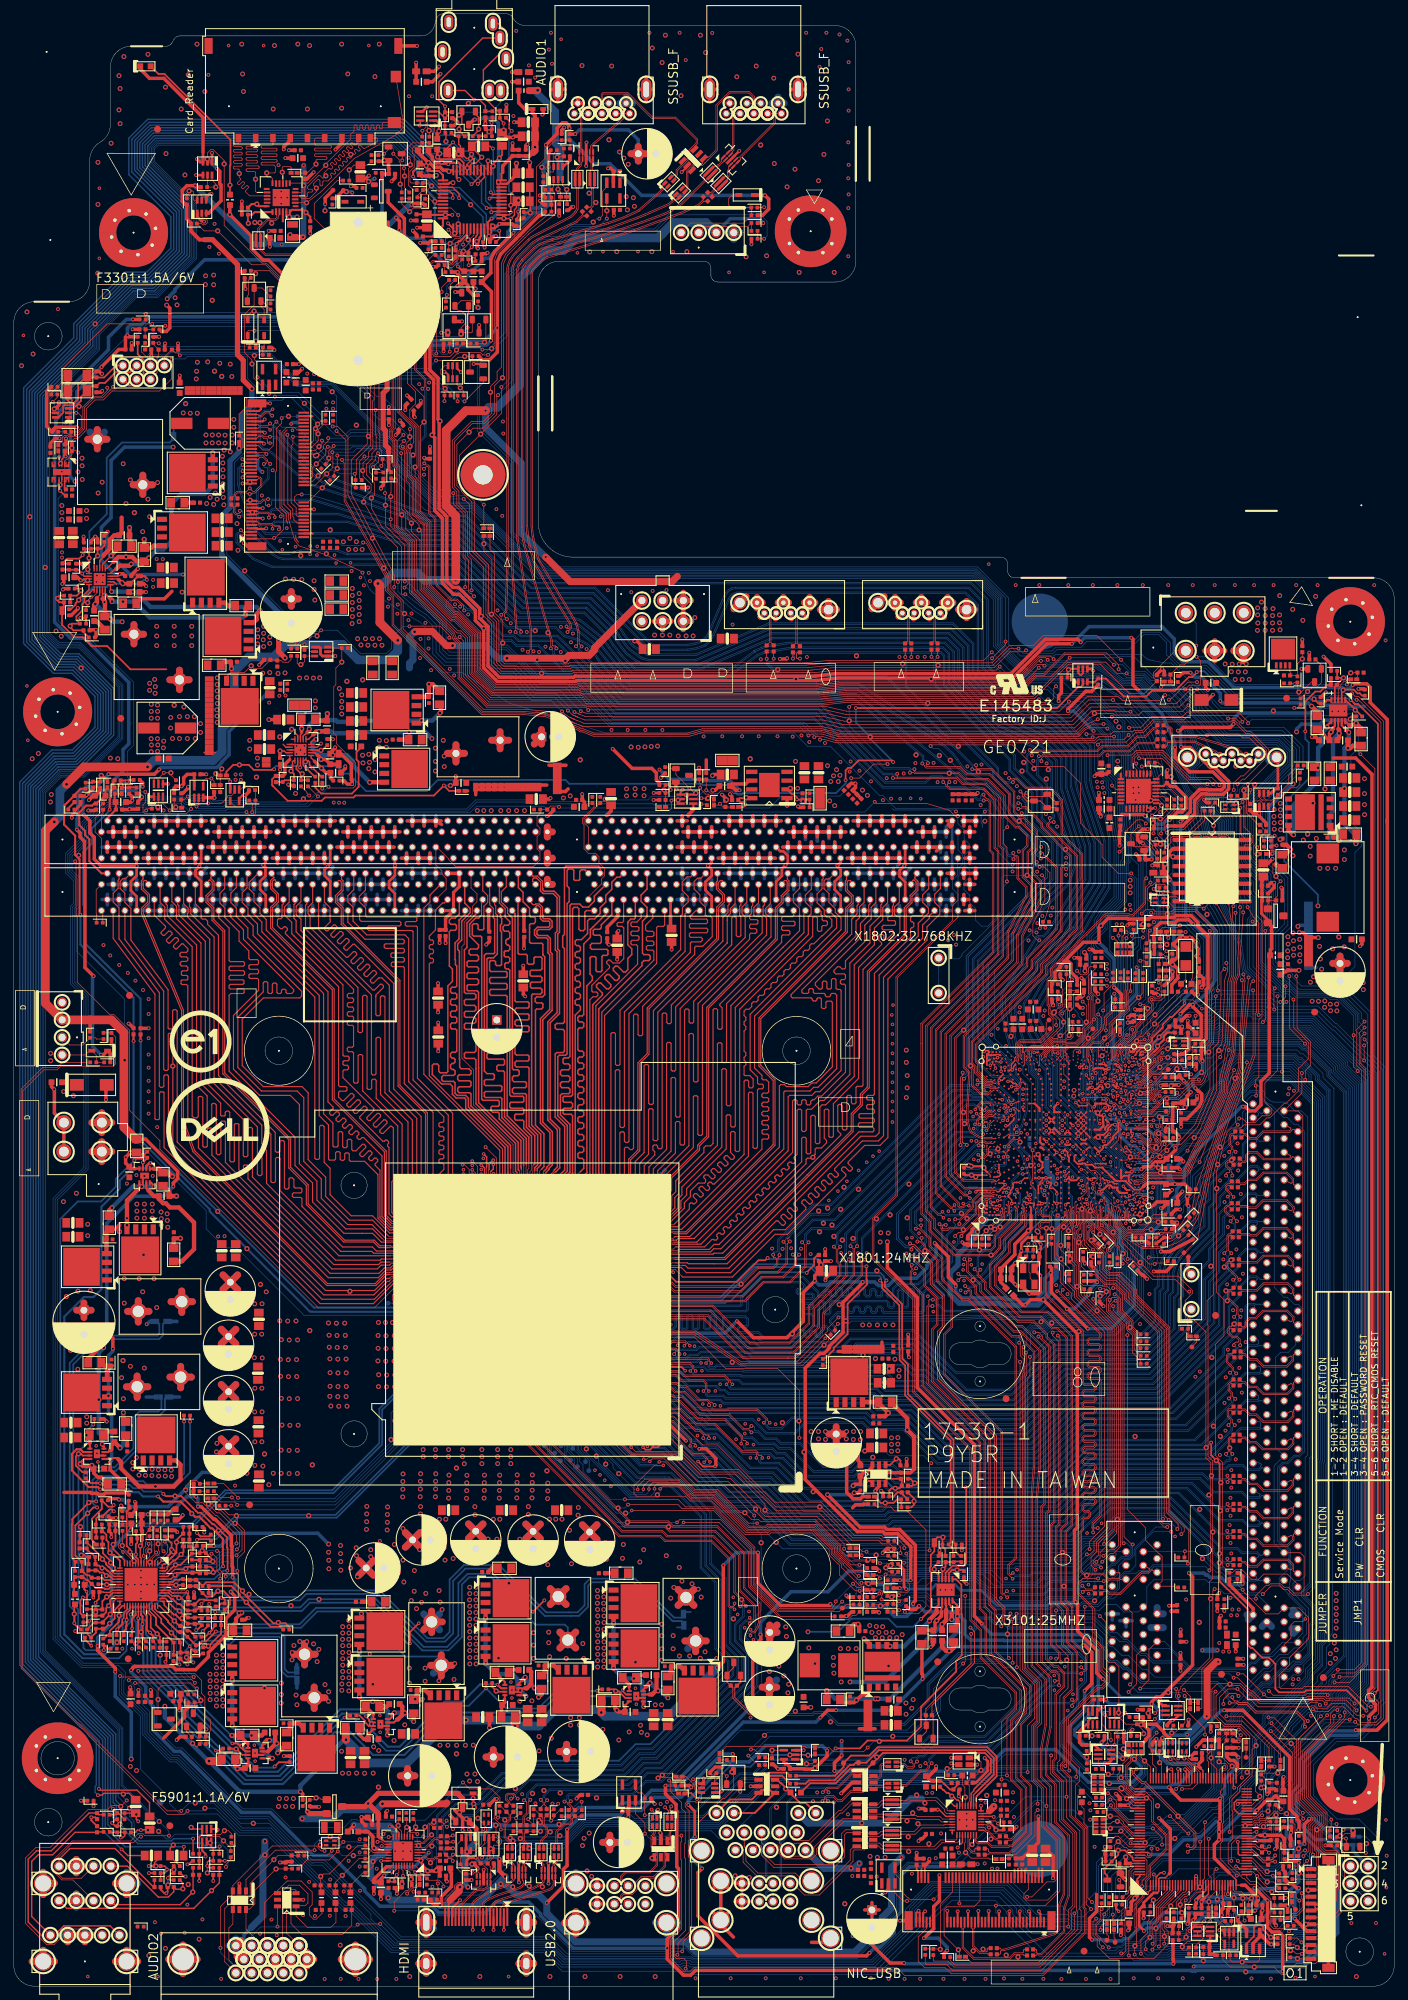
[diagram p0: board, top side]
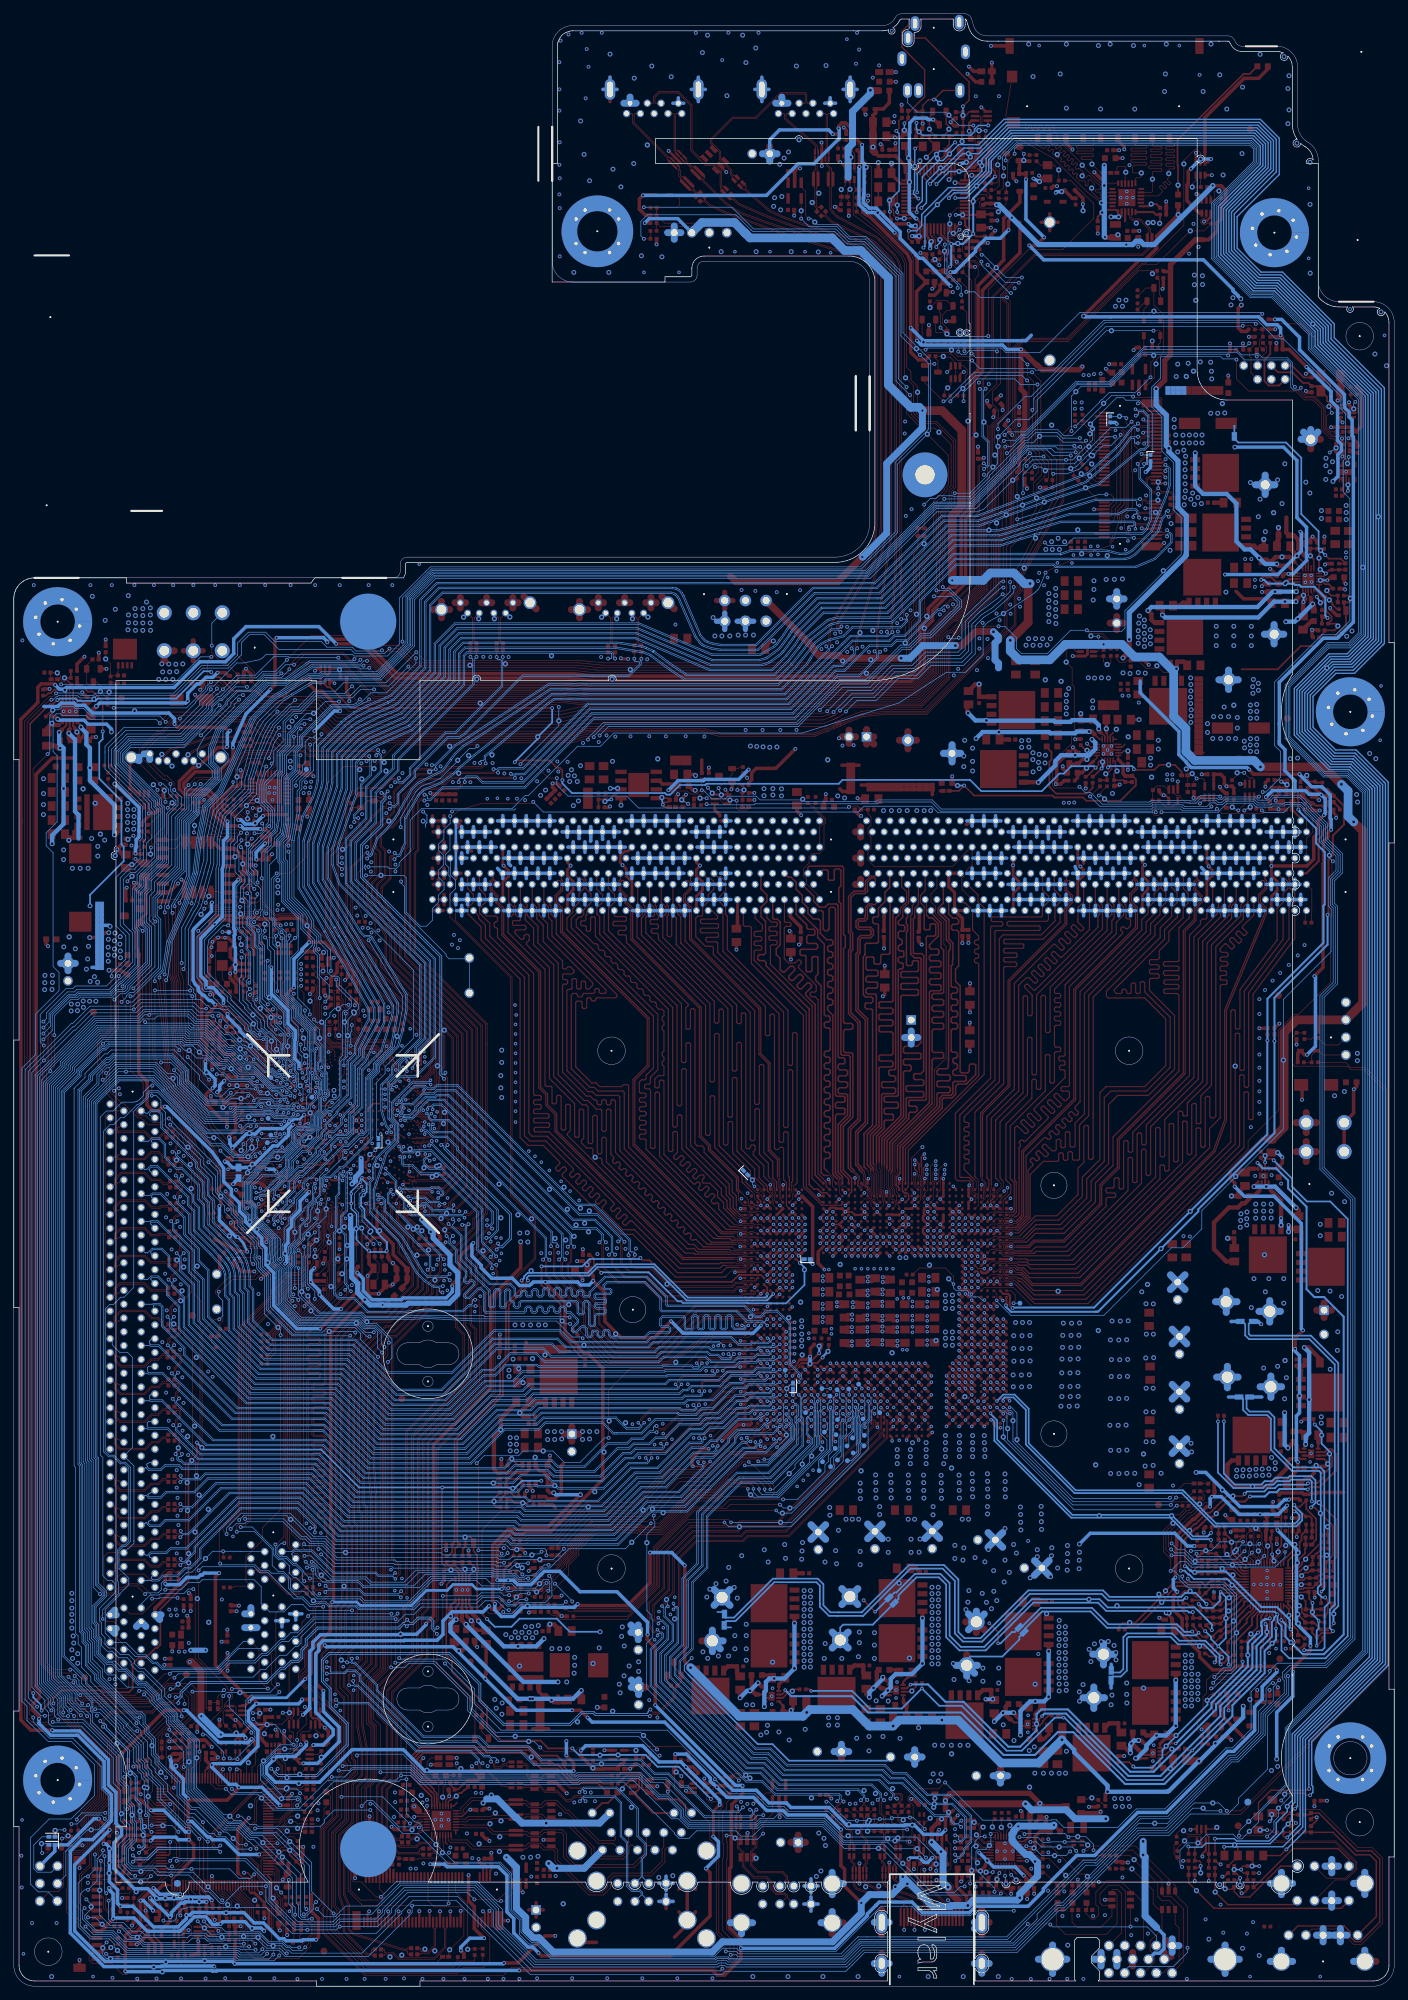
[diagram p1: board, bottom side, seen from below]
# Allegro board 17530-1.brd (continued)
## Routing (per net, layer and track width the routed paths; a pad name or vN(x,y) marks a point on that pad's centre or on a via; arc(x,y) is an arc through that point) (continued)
12V_S5: length 217.1
  TOP w0.508: v3(196.34,38.73) 196.34,39.07 197.28,40.01 197.28,40.83 197.07,41.03 196.29,41.81 196.29,42.81 196.77,43.29 196.77,175.54 194.41,177.9 191.16,177.9
  TOP w0.762: ATX1.5 175.45,193.44 ; ATX1.5 172.55,193.44 ; ATX1.5 174,194.89 ; ATX1.5 174,191.99
  TOP w1.016: 176.75,193.44 ATX1.6 178.2,191.99
  BOTTOM w0.508: v3(170.94,2.84) 170.98,2.84 171.05,2.92 178.57,2.92 178.65,2.84 186.94,2.84 191.81,7.72 191.81,19.56 190.14,21.23 188.57,21.23 185.86,23.94 185.86,27.75 186.92,28.8 186.92,32.53 190.73,36.35 194.63,36.35 196.34,38.06 v3(196.34,38.73)
  vias: v2(182.5,184.73) v4(49.05,202.46) v4(49.05,201.45) v4(49.05,200.43) v4(49.05,199.42) v4(49.05,198.4) v4(49.01,197.38) v4(49.81,195.18) v4(50.04,201.73) v4(50.04,200.72) v4(50.04,199.7) v4(50.04,198.68) v4(50.04,197.67) v4(50.29,194.29) v4(50.95,195.18) v4(51.31,194.23) v4(51.96,195.18) v4(52.32,194.23) v4(52.98,195.18) v4(53.34,194.23) v4(175.52,191.52) v4(176.4,190.41) v4(176.53,191.49) v4(176.96,189.28) v4(177.42,190.37) v4(177.55,191.51) v4(177.98,189.28) v4(178.44,190.37) v4(178.56,191.54) v4(178.99,189.28)
12VBDC_EN_2: length 5.5
  TOP w0.102: Q4205.C 188,188.91 186.53,187.45 v2(186.18,187.45) 185.98,187.66 R4221.1 185.97,188.85 185.52,188.85 185.39,188.72 R4220.2
12VBDC_EN_3: length 6.4
  TOP w0.102: C4219.1 v2(186.69,192.25) 185.98,191.54 R4221.2 185.84,189.87 C4218.2 184.94,189.88 184.94,190.35 184.87,190.41 U4204.4
12VCPU_EN_2: length 4.4
  TOP w0.102: R4223.1 26.62,42.27 27.1,41.78 v2(27.1,41.4) 27.1,41.32 26.87,41.1 R4222.2 26.16,41.08 26.16,40.64 26.3,40.5 26.3,40.12 26.01,39.83 Q4207.C
+12V_PG_U29: length 6.8
  TOP w0.102: U4202.5 42.96,193.32 42.85,193.42 v3(42.85,195.48) 42.24,195.48 41.06,194.3 R4207.1
  BOTTOM w0.102: v2(43.94,195.58) v3(42.85,195.48)
AGND: length 168.4
  TOP w0.254: C3003.2 21.27,14 21.81,13.46 v3(22.1,13.46) 22.29,13.65 C3004.2 ; R3007.2 25.86,18.16 25.35,17.65 v3(25.15,17.65) ; v3(24.89,15.88) 24.64,15.88 24.13,16.38 R3003.2 ; R3015.2 14.72,23.18 v3(14.25,23.65) 14.8,24.19 R3016.2 ; R3009.2 v3(30.58,18.16) ; C3005.2 v3(28.89,15.24) ; v3(26.86,15.24) C3006.2 ; C3010.2 11.8,24.46 v3(11.23,24.46) 11.23,24.02 C3009.2 ; R3004.2 v3(19.58,16.38)
  TOP w0.305: v4(63.63,261.24) 63.15,261.24 62.99,261.08 U2701.38 ; U2701.35 64.17,261.99 64.46,261.7 v4(64.5,261.7) ; v3(29.51,22.66) 29.41,22.77 Q3001.1 ; v4(68.71,264.41) 68.67,264.38 U2701.26 ; v3(27.79,18.8) 27.79,19.15 27.29,19.65 Q3001.4
  TOP w0.356: Q2901.4 59.18,271.54 59.79,272.15 v3(59.82,272.15) ; v4(61.58,268.7) 61.58,269.89 61.22,270.24 Q2901.1
  TOP w0.508: R2708.2 v3(72.19,277.27) ; C2903.2 71.37,271.72 v3(71.37,272.54) ; C2708.2 C2704.2 v3(72.26,266.95) ; C2720.2 73.09,275.86 v3(72.19,275.86) ; R2705.2 60.93,277.37 v3(61.62,278.05) ; R9929.2 v3(11.56,26.06) ; R2907.2 68.39,269.13 68.33,269.2 v3(68.33,269.8) C2906.2 ; C2907.2 63.7,270.57 v3(64.27,270) 63.77,269.49 R2909.2 ; v3(74.42,266.81) 74.4,266.81 74.17,266.57 R2701.2 ; C2705.2 v3(72.48,270) ; C2719.2 60.66,275.84 v3(61.82,277.01) ; C2709.2 72.52,267.97 v3(72.34,267.79) 71.45,267.79 C2703.2 ; C2710.2 v4(74.75,264.16) ; C2706.2 59.09,262.22 C2707.2 61.13,262.22 v4(61.21,262.3) ; v4(61.58,268.7) 61.58,268.59 61.34,268.35 C2701.1
  TOP w1.016: 8.77,7.39 AUD1.4 7.8,6.42 ; AUD1.24 10.02,12.39 ; AUD1.24 8.08,12.39 ; AUD1.24 9.05,13.36 ; AUD1.1 11.27,7.39 ; AUD1.1 10.3,6.42 ; AUD1.1 9.33,7.39 ; AUD1.G1 5.87,3.59 ; AUD1.G1 2.65,3.59 ; AUD1.G1 4.26,5.2 ; AUD1.34 10.02,17.39 ; AUD1.34 9.05,16.42 ; AUD1.34 9.05,18.36 ; AUD1.34 8.08,17.39 ; AUD1.G3 5.87,14.89 ; AUD1.G3 4.26,13.28 ; AUD1.G3 4.26,16.5 ; 14.73,3.59 AUD1.G2 ; AUD1.G2 17.95,3.59 ; AUD1.G2 16.34,5.2 ; 16.34,13.28 AUD1.G4 14.73,14.89
  L3SGND w0.508: HPMIC1.3 62.99,284.46 62.99,281.79
  L3SGND w1.016: 7.8,6.42 AUD1.4 ; AUD1.4 8.77,7.39 ; AUD1.4 6.83,7.39 ; AUD1.4 7.8,8.36 ; 16.34,13.28 AUD1.G4 ; AUD1.G4 17.95,14.89 ; AUD1.G4 16.34,16.5 ; AUD1.G4 14.73,14.89 ; HPMIC1.7 62.12,281.51 ; HPMIC1.7 62.12,278.87 ; HPMIC1.7 61.21,280.19 ; HPMIC1.7 63.03,280.19 ; 9.05,16.42 AUD1.34 ; AUD1.34 10.02,17.39 ; AUD1.34 9.05,18.36 ; AUD1.34 8.08,17.39 ; AUD1.24 10.02,12.39 ; AUD1.24 9.05,11.42 ; AUD1.24 9.05,13.36 ; AUD1.24 8.08,12.39 ; 71.32,277.87 HPMIC1.8 ; HPMIC1.8 71.32,280.51 ; HPMIC1.8 72.23,279.19 ; HPMIC1.8 70.4,279.19 ; 9.33,7.39 AUD1.1 ; AUD1.1 10.3,8.36 ; AUD1.1 10.3,6.42 ; AUD1.1 11.27,7.39 ; 4.26,13.28 AUD1.G3 ; AUD1.G3 4.26,16.5 ; AUD1.G3 5.87,14.89 ; AUD1.G3 2.65,14.89 ; HPMIC1.5 68.92,275.91 ; HPMIC1.5 68,274.59 ; HPMIC1.5 68.92,273.27 ; AUD1.G2 17.95,3.59 ; AUD1.G2 16.34,1.98 ; AUD1.G2 14.73,3.59 ; AUD1.G2 16.34,5.2 ; AUD1.G1 4.26,5.2 ; AUD1.G1 2.65,3.59 ; AUD1.G1 4.26,1.98 ; AUD1.G1 5.87,3.59
  BOTTOM w1.016: AUD1.34 9.05,18.36 ; AUD1.34 9.05,16.42 ; AUD1.34 8.08,17.39 ; AUD1.34 10.02,17.39 ; AUD1.24 9.05,13.36 ; AUD1.24 10.02,12.39 ; AUD1.24 8.08,12.39 ; AUD1.24 9.05,11.42 ; AUD1.1 11.27,7.39 ; AUD1.1 9.33,7.39 ; AUD1.1 10.3,6.42 ; AUD1.1 10.3,8.36 ; 4.26,13.28 AUD1.G3 ; AUD1.G3 4.26,16.5 ; AUD1.G3 5.87,14.89 ; 5.87,3.59 AUD1.G1 4.26,5.2 ; AUD1.4 8.77,7.39 ; AUD1.4 6.83,7.39 ; AUD1.4 7.8,6.42 ; AUD1.4 7.8,8.36 ; 14.73,3.59 AUD1.G2 ; AUD1.G2 17.95,3.59 ; AUD1.G2 16.34,5.2 ; AUD1.G4 17.95,14.89 ; AUD1.G4 16.34,16.5 ; AUD1.G4 14.73,14.89 ; AUD1.G4 16.34,13.28
  vias: v2(25.27,14.73) v3(25.15,11.81) v3(60.62,273.76) v3(72.39,270.89)
GND: length 2950.6
  TOP w0.102: SB1.A8 141.05,115.27 142.31,115.27 SB1.D8 ; CPU1.AU40 v1(55.6,114.13) ; v1(56.51,115.18) 56.51,115.09 57.09,114.5 CPU1.AV39 ; CPU1.AW38 58.01,115.7 v1(57.63,116.08) ; v1(56.02,115.66) 56.02,114.92 57.09,113.85 CPU1.AU39 ; 112.43,108.56 112.2,108.33 112.01,108.33
  TOP w0.127: 40.08,212.52 40.08,213.69 39.14,214.63 39.14,224.97 39.6,225.43 ; 39.62,211.86 39.62,212.06 39.47,212.22 39.47,213.28 38.56,214.2 38.56,225.35 38.61,225.4 ; v3(177.44,42.04) 177.06,42.42 176.15,42.42 175.26,41.53 v3(175.26,40.87) ; 41.27,209.17 41.06,209.39 40.93,209.56 40.89,209.67 40.82,210.13
  TOP w0.152: SB1.J47 145.02,134.45 SB1.J48 ; v1(151.93,111.22) 152.3,111.59 SB1.AD1 SB1.AD2 ; SB1.AJ28 154.24,125.44 ; SB1.AJ28 v1(154.98,125.41) ; SB1.AJ28 155.01,124.66 ; 154.24,125.44 SB1.AJ30 ; 154.24,125.44 SB1.AG30 ; 154.24,125.44 SB1.AG28 ; SB1.AK25 155.01,123.89 ; 155.01,123.89 SB1.AJ25 ; 155.01,123.89 SB1.AK27 155.01,124.66 ; 155.01,123.89 SB1.AJ27 ; 154.24,123.89 SB1.AG25 v1(154.24,123.11) ; 154.24,123.89 SB1.AJ25 ; 154.24,123.89 SB1.AG27 ; 154.24,123.89 SB1.AJ27 ; 155.03,126.23 SB1.AJ31 154.28,126.25 154.22,126.25 v1(154.21,126.24) SB1.AJ30 ; 155.03,126.23 SB1.AJ30 ; 155.03,126.23 SB1.AK31 ; 155.03,126.23 SB1.AK30 ; v1(153.94,110.06) 153.94,110.18 153.98,110.21 SB1.AG1 ; SB1.AG23 v1(154.24,123.11) ; v1(154.24,123.11) SB1.AJ25 ; v1(163.71,121.34) 163.61,121.43 SB1.BG22 ; SB1.AJ30 v1(154.98,125.41) ; SB1.AA49 150.78,135.15 v1(151.26,135.15) ; 155.01,124.66 SB1.AK28 v1(154.98,125.41) ; 155.01,124.66 SB1.AJ27 ; SB1.AJ20 SB1.AG22 ; v1(164.05,125.56) 163.99,125.56 SB1.BG28 ; SB1.AE46 152.88,133.75 152.58,134.05 152.58,135.04 SB1.AD49 ; SB1.AG49 v1(154.41,135.31) ; v1(140.68,126.87) 140.68,127.06 SB1.A33 ; SB1.AM1 156.17,111.41 v1(156.36,111.22) ; v1(140.56,129.82) 140.81,129.57 SB1.A37 ; SB1.AM49 v1(156.17,135.8) ; SB1.N38 v1(146.22,129.94) ; SB1.BG37 v1(164.21,129.57) ; SB1.AR16 SB1.AN16
  TOP w0.203: SB1.AT1 158.4,111.3 158.24,111.14 v1(158.24,111.08) ; SB1.AK46 154.77,133.25 154.57,133.25 v1(154.42,133.1) ; v1(164.16,127.42) 164.12,127.37 SB1.BG33 ; SB1.E10 143.31,116.33 143.36,116.28 143.44,116.28 143.6,116.11 v1(143.64,116.11) 143.64,116.09 143.17,115.62 143.17,115.61 142.94,115.39 SB1.E8 142.73,115.09 SB1.D8 ; 160.43,118.25 SB1.BA14 ; v1(147.83,135.25) 148.35,135.25 148.41,135.31 SB1.T49 ; SB1.C12 142.41,117.2 SB1.D12 142.73,117.29 SB1.E13 142.94,117.7 v1(142.66,117.98) 142.74,118.06 SB1.E15 142.74,118.99 SB1.D16 ; U2401.82 170.29,31.07 169.94,31.42 v3(169.7,31.42) 169.7,31.19 169.89,31 U2401.83 ; SB1.A8 140.96,115.23 139.57,115.23 v1(139.4,115.06) ; SB1.C5 142.05,113.57 v1(141.53,113.57) 141.53,113.4 SB1.C4 ; SB1.K39 145.14,130.76 SB1.J40 144.58,130.97 144.58,130.97 144.48,131.07 v1(144.05,131.07) ; U5901.24 53.22,18.16 v3(53.21,18.16) ; v1(149.77,116.46) 150.14,116.46 SB1.Y10 150.29,116.06 150.1,115.87 SB1.Y9 150.61,115.58 151.12,115.08 v1(151.12,114.78) ; SB1.M32 146.22,126.92 v1(146.22,127.33) ; SB1.N12 146.46,117.06 v1(145.83,116.43) 145.82,116.42 SB1.K11 144.97,116.42 SB1.J10 144.79,115.74 SB1.J9 144.72,115.58 144.4,115.26 SB1.H8 144.31,114.88 144.31,114.78 144.1,114.56 SB1.G6 144.58,113.89 v1(144.58,113.36) 144.65,113.44 SB1.J4 ; CPU1.V1 94.69,95.26 95.2,95.77 v1(95.2,95.83) ; v1(145.97,136.17) 146.2,135.94 146.2,135.32 SB1.M49 ; v1(143.74,124.64) 144.04,124.64 144.88,125.48 SB1.J29 ; CPU1.AW3 92.21,114.17 91.75,113.72 v1(91.75,113.09) 92.62,113.09 93.07,113.54 CPU1.AV2 ; SB1.T7 148.46,115.43 148.45,115.44 148.45,115.95 148.69,116.19 148.69,116.47 149.04,116.82 SB1.U12 v1(148.53,117.08) 148.5,117.08 148.47,117.06 SB1.R12 ; PU5001.3 v1(41.53,179.07) ; v3(164.21,13.46) 164.69,13.94 U2401.1 ; v3(44.5,179.98) 44.37,179.85 44.34,179.85 43.96,179.47 PU5001.14 ; v1(142.77,131.22) 142.66,131.11 142.66,130.75 SB1.E40 ; v1(142.77,131.22) 142.77,131.23 142.77,131.52 SB1.E42 143.3,132.05 SB1.F43 ; v1(142.77,131.22) 143.22,131.22 SB1.F41 ; SB1.J26 144.95,124.22 v1(145.31,124.59) ; SB1.AL33 155.45,127.53 SB1.AH33 153.92,127.92 153.92,127.98 v1(153.89,128.02) ; U2401.18 171.49,15.76 v3(171.3,15.95) 171.3,15.9 171.09,15.7 U2401.17 ; U2401.40 177.6,18.98 177.39,19.18 177.39,20.86 v3(177.34,20.91) ; v3(176.83,28.75) 176.69,28.9 U2401.66 ; U2401.90 167.09,31.22 167.29,31.42 v3(167.69,31.42) 167.89,31.22 U2401.88 ; SB1.C48 142.25,134.87 142.33,134.96 142.71,134.96 142.8,134.87 142.93,134.87 SB1.F47 ; U2401.59 177.53,26.58 v3(177.33,26.38) ; SB1.E35 143.13,128.47 143.21,128.39 v1(143.22,128.39) ; U2401.86 v3(168.69,31.47) ; SB1.AT16 SB1.AR16 ; SB1.AW10 159.46,116.24 SB1.AV11 159.19,116.51 v1(158.6,116.51) 158.34,116.76 158.04,116.76 SB1.AR12 ; SB1.M5 146.5,113.64 v1(146.78,113.36) 146.86,113.44 SB1.P4 147.36,113.4 SB1.R4 147.83,113.18 147.74,113.08 SB1.R3 ; SB1.AE12 152.55,116.84 152.49,116.84 v1(152.36,116.71) ; U4201.11 U4201.15 ; SB1.AL24 155.89,123.01 SB1.AK25 ; v1(40.97,179.65) 40.75,179.87 PU5001.1 ; v3(166.65,16.43) 166.12,16.43 165.68,16 165.68,15.99 165.49,15.8 U2401.3 ; SB1.T5 148.7,113.64 v1(148.98,113.36) ; v1(161.99,129.15) 161.86,129.02 SB1.BC35 ; SB1.G44 144.31,132.63 144.4,132.72 v1(144.65,132.72) ; CPU1.AW36 59.84,116 v1(59.76,116.08) ; v1(58.47,113.11) 58.47,113.73 58.01,114.18 CPU1.AV38 ; SB1.BC31 v1(161.86,126.76) ; U2401.117 161.92,20.58 v3(161.8,20.7) ; 80.41,110.34 v1(81.33,110.34) ; SB1.BC40 161.51,130.67 v1(161.33,130.85) 161.07,131.1 SB1.BB41 ; v1(148.98,113.36) 148.8,113.19 SB1.T4 ; v1(148.98,113.36) 149.05,113.44 SB1.V4 ; SB1.J46 145.13,133.45 144.84,133.16 144.84,132.91 v1(144.65,132.72) ; SB1.AP4 157.27,113.53 157.56,113.82 157.56,113.82 v1(157.56,113.83) ; SB1.N34 SB1.R34 ; v1(144.65,132.72) 144.53,132.84 144.53,133.56 SB1.J47 ; SB1.BG25 v1(164.1,123.5) ; SB1.AK20 155.71,121.49 SB1.AL21 ; SB1.AK4 155.42,113.44 v1(155.57,113.28) ; v3(177.08,17.34) 177.23,17.34 177.59,16.98 U2401.35 ; SB1.AA5 150.98,113.36 v1(151.12,113.36) 151.2,113.44 SB1.AC4 ; v1(161.11,121.54) 161.12,121.54 161.86,120.8 SB1.BC19 ; 148.01,125.12 SB1.R29 ; v1(164.98,120.21) 164.39,119.63 SB1.BG17 ; v1(140.46,125.18) SB1.A28
  TOP w0.254: SB1.AE12 152.91,117.14 152.91,117 153.19,116.71 153.59,116.71 153.62,116.74 153.95,116.74 SB1.AH12 ; SB1.A5 SB1.A4 140.68,113.04 140.53,112.89 ; SB1.AH17 v1(154.9,119.82) ; 161.54,117.39 161.54,116.65 SB1.BC10 ; 161.54,117.39 SB1.BC13 ; 161.54,117.39 160.81,117.39 SB1.BA12 ; SB1.U12 v1(149.55,117.1) SB1.Y12 ; v1(160.76,115.88) 160.79,115.84 160.79,115.83 161.07,115.55 SB1.BB9 161.24,115.31 SB1.BC8 ; SB1.AN12 156.35,117.06 v1(156.13,116.84) 155.8,116.84 SB1.AL12 ; v1(79.51,112.17) 79.25,112.17 79.23,112.16 78.57,112.16 CPU1.AR16 ; CPU1.AF1 94.7,102.57 v1(94.74,102.53) ; SB1.A48 SB1.A47 SB1.A46 ; SB1.A48 SB1.B49 141.15,135.51 140.72,135.51 v1(140.59,135.38) ; SB1.A48 141.08,134.87 141.43,134.87 SB1.B48 141.51,134.87 SB1.C48 ; SB1.BG48 SB1.BF48 SB1.BF49 163.33,135.38 163.87,135.38 163.88,135.39 v1(163.89,135.39) ; SB1.B47 SB1.A46 ; SB1.A46 SB1.A45 ; SB1.BC24 162.06,123.12 v1(162.06,123.51) 161.86,123.71 SB1.BC26 ; SB1.A3 140.9,112.54 140.55,112.89 140.53,112.89 ; CPU1.AD1 v1(94.68,100.74) ; v1(94.59,79.34) 93.32,78.08 92.55,78.08 ; CPU1.AF8 v1(87.18,103.03) ; SB1.AF22 152.95,121.83 152.42,121.83 SB1.AD22 ; SB1.AT26 158.13,124.22 158.15,124.24 158.15,124.38 158.55,124.78 v1(158.55,124.97) ; SB1.AA20 v1(151.13,120.78) SB1.AA19 ; C3118.2 136.77,29.19 136.14,28.57 C3106.2 135.64,28.49 134.9,29.23 134.87,29.23 134.35,29.76 R3101.1 ; v1(101.6,75.31) 101.58,75.29 99.85,75.29 v1(99.13,76.01) ; 140.53,112.89 v1(140.5,112.89) ; 92.55,78.08 v1(92.55,78.83) ; 92.55,78.08 92.19,77.71 91.51,77.71 v1(91.16,78.07) ; v1(97.28,89.15) 96.74,89.69 v1(94.76,89.69) ; SB1.BC15 161.74,118.53 v1(161.42,118.85) ; v1(152.4,113.18) 152.66,113.44 SB1.AE4 ; SB1.AB19 v1(152.02,119.89) ; v3(33.15,218.54) 33.15,218.65 33.67,219.17 NGFF1.39 ; v3(33.12,221.18) 33.64,220.67 NGFF1.45 ; SB1.BF3 163.43,113.04 SB1.BG4 ; SB1.A2 140.64,112.04 140.42,112.26 v1(140.41,112.26)
  TOP w0.305: v1(68,116.99) 68,116.96 68.07,116.9 CPU1.AY27 ; v3(66.62,234.99) 67.58,234.99 67.78,234.79 U6303.S ; v3(64.64,12.45) 63.78,11.58 63.73,11.58 63.57,11.42 63.57,10.08 HDMI1.17 ; EU3803.2 97.59,263.6 v3(96.77,262.77) ; PU4502.6 35.2,33.51 v1(34.95,33.76) ; SB1.V20 148.89,121.49 SB1.U21 ; v3(36.23,223.44) 36.01,223.67 NGFF1.57 ; SB1.AP46 157.72,133.56 v1(157.86,133.7) 158.21,133.36 SB1.AT45 ; PU4514.6 90.44,41.76 v1(90.19,42) ; SB1.AW46 159.72,133.56 v1(159.97,133.31) 160.5,132.78 SB1.BA44 ; NGFF1.7 35.28,211.17 35.36,211.09 36.49,211.09 v3(36.58,211.18) ; v1(156.22,130.21) 155.85,130.21 SB1.AL38 ; v3(165.38,170.67) 165.08,170.67 164.96,170.55 U9101.16 ; NGFF1.33 v3(33.15,217.67) ; NGFF2.27 v3(142.75,10.84) ; v3(182.96,165.23) 182.31,165.23 R806.2 ; NGFF2.15 v3(145.75,10.84) ; NGFF1.75 35.56,228.17 35.81,228.42 35.81,228.69 NGFF1.77 v3(37.13,229.27) ; SB1.AV39 159.69,130.16 v1(159.96,130.16) 159.81,130.31 SB1.AW40 ; SB1.AT29 158.55,125.17 v1(158.55,124.97) ; v1(158.7,123.42) 158.62,123.42 SB1.AT24 ; NGFF2.9 147.25,10.66 v3(147.07,10.85) ; NGFF2.71 131.75,10.57 v3(132.03,10.85) ; SB1.AA30 v1(150.36,125.44) ; v1(150.36,125.44) SB1.W30 ; v1(150.36,125.44) SB1.AA28 ; v1(150.36,125.44) SB1.W28 ; CPU1.AM39 57.09,109.07 57.45,109.46 v1(57.54,109.46) ; HDMI1.11 v3(66.5,8.16) ; v1(160.07,10.85) 159.74,11.18 159.74,11.25 159.7,11.29 R2453.2 ; SB1.V22 149.01,121.95 148.71,122.26 SB1.U24 ; CPU1.AD8 v1(87.18,101.2) ; v1(156.52,127.37) 156.69,127.55 SB1.AN34 SB1.AR34 SB1.AT34 158.76,127.34 v1(158.8,127.34) 158.8,127.17 158.38,126.76 SB1.AT32 ; CPU1.AE8 v1(87.18,102.11) ; v3(148.51,10.84) 148.51,10.73 148.75,10.49 NGFF2.3 ; SB1.R34 148.62,127.14 SB1.T32 ; SB1.AF25 153.02,123.5 v1(152.67,123.84) 152.33,123.5 SB1.AD25 ; SB1.AA25 v1(150.36,123.89) ; v1(150.36,123.89) SB1.W27 ; v1(150.36,123.89) SB1.AA27 SB1.AB25 ; v1(150.36,123.89) SB1.W25 ; v3(165.52,166.22) 165.48,166.22 166.31,165.4 R9110.1 ; Q2401.4 156.96,39.11 156.66,38.8 156.02,38.8 155.85,38.64 155.85,38.62 155.66,38.43 Q2401.1 ; NGFF2.33 v3(141.25,10.87) ; PU4602.9 12.29,76.86 PU4602.6 ; v1(63.04,89.31) CPU1.K33 ; NGFF1.13 35.98,212.67 v3(36.07,212.59) ; HDMI1.8 v3(68,8.16) ; NGFF2.21 v3(144.25,10.84) ; Q9103.4 64.23,234.32 64.74,233.81 v3(64.77,233.81) ; PU4605.9 18.7,117.15 PU4605.6 ; v3(36.07,214.09) 35.36,214.09 35.28,214.17 NGFF1.19 ; v1(55.52,105.32) CPU1.AH40 CPU1.AH39 ; U9101.23 164.19,174.35 ; CPU1.AT13 81,112.77 81.65,112.77 CPU1.AT12 ; SB1.BF1 SB1.BG2 ; v1(72.16,42.9) 72.41,42.65 PU4510.6 ; NGFF1.63 36.12,225.17 36.27,225.02 v3(36.37,225.02) ; NGFF2.45 v3(138.25,10.85) ; CPU1.AR17 CPU1.AR16 ; SB1.BA14 SB1.BA12 ; 98.46,170.41 Q4002.1 ; v3(62.92,255.35) 62.92,255.34 U2701.1 ; PU4506.6 53.36,37.7 v1(53.11,37.95) ; v3(96.9,173.32) 96.9,173.3 96.61,173.02 Q4002.4 ; NGFF2.57 v3(135.25,10.92) ; v1(74.01,107.6) 74.01,107.61 ; NGFF1.69 36.07,226.67 v3(36.35,226.95) ; SB1.T18 SB1.T17 148.94,119.37 SB1.U17 SB1.U15 v1(148.5,118.07) ; SB1.AR38 157.74,130.22 v1(157.52,130.45) 157.37,130.45 156.87,129.94 SB1.AN38 ; NGFF2.51 v3(136.75,10.84) ; HDMI1.5 v3(69.5,8.15) ; NGFF1.18 v3(43.48,213.92) ; Q9103.1 62.92,233.43 62.62,233.73 62.56,233.73 62.46,233.83 v3(62.35,233.83) ; HDMI1.2 v3(71,8.15) ; NGFF2.73 131.25,10.61 131.09,10.77 v3(131.09,10.92) 131.05,10.92 130.75,10.62 NGFF2.75 ; SB1.AB31 SB1.AA31 150.75,127.36 v1(151.26,127.86) ; SB1.AF28 v1(153.46,124.66) ; CPU1.L32 v1(63.95,90.23) ; 73.56,108.06 CPU1.AL21 ; NGFF2.39 v3(139.75,10.9)
  TOP w0.356: v1(55.52,112.63) CPU1.AT40 ; CPU1.AF37 59.11,103.3 59.65,103.3 CPU1.AF36 ; CPU1.AM11 v1(83.15,109.43) CPU1.AN11 ; CPU1.AW32 63.49,115.46 v1(63.88,115.85) ; v3(154.95,37.44) 155.43,37.92 Q2401.1 ; CPU1.C16 v1(80.78,81.08) ; CPU1.F22 v1(74.38,84.74) ; CPU1.AT28 67.15,112.66 67.58,113.1 v1(67.71,113.1) 67.72,113.11 67.73,112.95 68.07,112.66 CPU1.AT27 68.11,112.59 68.11,112.45 68.13,112.42 68.13,111.96 68.11,111.93 68.11,111.76 CPU1.AR27 68.07,111.71 68.27,111.51 68.27,111.01 CPU1.AP27 68.04,110.8 v1(67.57,110.34) 68.04,109.89 CPU1.AN27 68.27,109.68 68.27,109.18 CPU1.AM27 ; CPU1.AK23 v1(71.27,107.6) ; v1(55.52,107.14) CPU1.AK40 ; CPU1.AT12 81.78,112.61 v1(82.24,112.17) CPU1.AT11 ; CPU1.AR11 v1(83.15,111.26) CPU1.AP11 ; CPU1.T1 94.65,93.43 v1(94.71,93.49) ; CPU1.D24 v1(73.42,82.86) ; CPU1.AT32 v1(63.01,113.1) ; CPU1.AT26 69.01,112.63 v1(69.48,113.09) 69.87,112.63 CPU1.AT25 CPU1.AT24 ; U2405.3 v3(31.35,174.5) ; CPU1.C18 v1(78.95,81.08) ; v1(61.56,116.03) 61.67,115.93 CPU1.AW34 CPU1.AV34 61.67,114.43 v1(61.23,114) 61.67,113.57 CPU1.AU34 CPU1.AT34 ; CPU1.C14 v1(82.61,81.08) ; CPU1.A15 81.24,79.16 v1(80.95,78.87) ; CPU1.AT37 58.92,112.66 ; 58.92,112.66 v1(59.38,113.11) 59.84,112.66 CPU1.AT36 ; 58.92,112.66 v1(58.47,113.11) 58.01,112.66 CPU1.AT38 57.98,112.63 v1(57.55,113.06) 57.12,112.63 CPU1.AT39 ; CPU1.AM40 v1(55.52,108.97) ; CPU1.AU25 69.9,113.57 v1(69.48,114) 69.44,114 CPU1.AV26 ; v1(86.2,82.01) 85.81,81.61 CPU1.C10 ; v1(88.1,103.94) CPU1.AH8 ; CPU1.A24 72.74,79.44 v1(72.74,78.99) ; CPU1.F10 v1(85.35,84.74) CPU1.G11 ; CPU1.AW9 86.73,114.48 v1(86.28,114.93) CPU1.AY9 ; CPU1.AW5 v1(90.84,114) CPU1.AV5 ; v1(76.73,112.17) CPU1.AR17 ; v1(76.73,112.17) CPU1.AT17 ; v1(76.73,112.17) CPU1.AR18 ; CPU1.G19 v1(77.11,84.74) ; CPU1.B24 v1(72.58,81.06) ; v1(63.04,89.31) CPU1.L32 ; v3(157.84,40.46) 157.67,40.46 Q2401.4 ; CPU1.AL1 v1(94.75,107.14) ; CPU1.AL2 93.1,107.14 v1(92.67,107.58) 92.24,107.14 CPU1.AL3 ; CPU1.E17 79.4,83.37 v1(78.96,82.93) ; CPU1.AN22 v1(72.18,109.43) CPU1.AN23 71.27,110.34 v1(71.17,110.34) ; CPU1.F40 56.12,85.2 v1(55.72,84.8) ; v1(87.15,113.13) 86.73,113.54 CPU1.AV9 ; CPU1.P1 v1(94.87,91.6) ; CPU1.AK36 v1(59.38,107.58) 59.84,108.03 CPU1.AL36 ; CPU1.E21 v1(75.3,82.91) ; CPU1.AA3 v1(92.85,98) ; CPU1.AG2 v1(92.67,103.94) ; v1(88.1,103.03) CPU1.AG8 ; CPU1.A13 83.07,79.05 v1(82.83,78.82) ; v1(67.56,114.03) 67.56,114.05 CPU1.AV28 ; CPU1.E23 v1(74.36,83.81) ; CPU1.A11 v1(84.9,78.89) ; CPU1.AP24 v1(70.35,111.26) CPU1.AR24 ; CPU1.AP24 71.17,110.44 v1(71.17,110.34) ; CPU1.AP24 v1(70.35,110.34) CPU1.AN24 71.17,110.25 v1(71.17,110.34) ; v1(65.32,116.98) CPU1.AY30 CPU1.AW30 CPU1.AV30 65.35,114.43 65.37,114.43 v1(65.79,114.02) 65.32,113.56 CPU1.AU30 ; CPU1.F1 v1(94.68,84.28) ; CPU1.C24 v1(72.55,82) ; CPU1.A17 79.41,79.01 ; CPU1.H1 v1(94.68,86.11) ; v1(95.53,103.41) 95.45,103.49 CPU1.AG1 ; v1(94.76,89.69) 94.69,89.77 CPU1.M1 ; CPU1.E19 v1(77.12,82.91) ; v1(74.88,80.96) 74.84,80.99 CPU1.C22 ; v1(58.47,107.58) CPU1.AK37 ; CPU1.AY5 90.38,116.05 90.39,116.06 v1(90.39,116.07) ; CPU1.AG36 59.84,104.41 v1(59.36,104.89) 58.93,105.32 CPU1.AH37 CPU1.AH38 ; v1(83.15,108.52) CPU1.AL11 v1(83.15,107.6) ; CPU1.C20 v1(76.67,80.96) ; v1(94.7,110.8) CPU1.AR1 ; CPU1.AR19 v1(74.9,112.17) CPU1.AR20 ; v1(56.72,99.33) 57.09,99.7 CPU1.AB39 ; v3(105.12,265.85) EU3802.8 ; v1(94.7,108.97) CPU1.AN1 ; CPU1.AR3 v1(92.67,111.26) CPU1.AR2 ; v1(55.52,110.8) CPU1.AP40 ; Q2408.1 173.34,6.64 173.28,6.58 v3(173.28,6.5) ; v3(170.35,8) 170.35,8.03 170.92,8.6 Q2408.4 ; CPU1.AT13 CPU1.AT14 79.95,112.61 v1(79.51,112.17) CPU1.AR14 ; CPU1.AR22 72.71,111.79 73.49,111.79 CPU1.AR21 ; CPU1.AP14 80.41,110.34 CPU1.AN14 ; v1(89.01,113.09) CPU1.AU7 ; CPU1.AN36 v1(59.38,109.46) ; 74.01,107.61 73.56,108.06 ; v1(55.52,101.66) CPU1.AD40 ; CPU1.G17 v1(78.95,84.74) ; v1(92.67,95.71) CPU1.W3 ; v1(55.52,103.49) CPU1.AF40 ; CPU1.AY7 88.55,116.04 88.53,116.07 v1(88.53,116.08) ; v1(94.7,105.32) CPU1.AJ1 ; CPU1.AL21 v1(73.1,107.6) ; CPU1.AM14 v1(79.5,108.52) ; CPU1.K1 v1(94.68,87.94)
  TOP w0.381: v1(71.2,112.19) 71.26,112.19 CPU1.AR23 CPU1.AR22 ; v3(140.67,33.05) 141.09,32.62 141.09,31.16 139.39,29.46 C3119.2 ; 145.78,105.69 145.78,106.1 145.97,106.28 v3(145.97,106.54) 145.97,107.54 146.86,108.43 R1802.1 148.02,108.24 v3(148.79,107.47) 148.79,106.78 v3(148.56,106.55) ; v3(80.26,264.21) 79.63,263.58 Q3801.4 ; v1(79.51,112.17) 79.05,112.63 CPU1.AT15 ; CPU1.AU7 CPU1.AT6 ; v3(129.69,91.1) 129.69,91.11 129.59,91.21 C808.2 ; U6401.4 v3(26.42,262.33)
  TOP w0.406: v3(77.47,14.86) EU5601.8 EU5601.3 v3(77.47,17.79) ; v3(73.2,15.04) 73.15,15.09 EU5602.8 EU5602.3 v3(73.15,17.91) ; U6402.4 27.88,259.15 28.32,259.59 v3(28.65,259.59) ; v1(78.03,86.55) 78.5,87.02 CPU1.J18 ; C4010.2 v3(92.68,171.83) ; U6402.1 26.58,256.29 27.16,255.7 27.46,255.7 v3(27.56,255.6) ; v1(79.88,86.58) 80.32,87.02 CPU1.J16 ; R4023.2 v3(92.71,172.85) ; 29.01,172.15 29.02,172.14 v3(29.08,172.14) ; v3(82.98,267.06) 82.93,267 EU3801.8 EU3801.3 v3(82.93,263.65) ; v3(8.41,169.24) 8.39,169.55 8.77,169.96 8.77,170.08 8.78,170.09 R602.2 8.98,170.43 9.67,171.13 C1105.2 ; Q5601.1 66.18,22.41 v3(65.94,22.66) ; v3(7.49,226.51) 7.49,226.52 7.92,226.95 Q6401.1 ; U401.1 v3(19.59,172.31) ; v3(180.44,169.87) 180.46,169.89 Q802.1 ; v3(102.62,28.32) 102.35,28.05 U4002.1 ; CPU1.AJ24 70.81,106.23 v1(70.36,106.68) ; PR4458.2 13.82,66.75 13.83,66.74 PC4426.2 13.83,65.87 14.12,65.58 v3(14.12,65.05) ; U4202.4 44.27,193.97 44.43,193.81 44.43,192.96 44.72,192.67 U4202.1 v3(46.58,192.67) ; v1(153.53,188.72) 153.73,188.93 U4801.1 ; U2602.3 175.11,8.13 v3(174.69,8.13) ; v3(68.07,16.88) EU5603.3 EU5603.8 ; U401.4 v3(22.32,174.15) ; v1(59.37,85.66) 59.84,85.2 CPU1.F36 ; U4002.4 99.95,29.66 v3(99.95,30.09) ; U6401.1 v3(28.72,265.56) ; CPU1.K7 88.19,87.58 v1(88.11,87.58) ; U4009.3 v3(114.43,34.18) ; U4801.4 156.11,190.8 v3(156.36,190.55) ; CPU1.G22 v1(75.3,85.66) ; SATA2.8 183.15,177.83 R810.2 182.82,173.47 182.13,172.79 Q802.4 ; CPU1.H9 87.12,85.72 v1(87.12,85.62)
  TOP w0.432: v1(62.12,103.94) CPU1.AG33 ; CPU1.AE33 v1(62.12,102.11) CPU1.AD33 ; CPU1.AK26 v1(68.54,106.7) ; CPU1.E31 v1(64.87,84.74) ; CPU1.M12 v1(83.53,89.31) ; CPU1.AR36 v1(59.38,111.26) CPU1.AP36 ; CPU1.D37 v1(59.38,83.83) ; CPU1.M7 v1(89.01,90.23) CPU1.N6 ; CPU1.AK9 v1(86.29,105.79) 85.85,106.23 CPU1.AK10 v1(85.35,106.69) ; CPU1.H4 v1(91.75,86.57) CPU1.J3 ; CPU1.AF5 v1(90.84,102.11) CPU1.AE5 ; v1(84.45,81.07) 84.45,81.07 CPU1.C12 ; CPU1.B30 v1(67.07,81.08) ; CPU1.K22 v1(75.3,88.4) ; v1(89.04,100.21) 89.05,100.21 89.06,100.2 89.09,100.2 89.47,99.83 CPU1.AC6 ; CPU1.AM35 60.35,109.37 v1(60.35,109.47) ; CPU1.AK17 v1(77.67,106.69) ; CPU1.AT31 64.4,112.63 v1(63.94,112.17) ; CPU1.C8 v1(88.15,81.03) ; CPU1.AU5 v1(90.84,113.09) CPU1.AU4 ; v1(55.67,82.94) 55.75,82.94 CPU1.D40 ; v1(91.75,109.46) 91.32,108.97 CPU1.AN4 ; CPU1.AC3 92.21,99.85 v1(91.75,100.31) 91.73,100.31 CPU1.AD4 ; CPU1.AT10 v1(85.38,111.26) ; v1(90.84,103.03) CPU1.AG5 v1(89.93,103.94) ; CPU1.L13 v1(83.53,88.4) ; CPU1.AR32 v1(63.94,112.17) ; v1(63.94,112.17) CPU1.AR31 ; CPU1.AE36 v1(59.38,102.11) CPU1.AD36 ; CPU1.AT8 v1(87.18,112.17) CPU1.AT9 ; CPU1.L9 v1(87.18,88.4) ; CPU1.N33 v1(63.04,92.06) ; v1(87.18,105.77) CPU1.AJ8 ; CPU1.AL27 v1(67.61,107.6) ; v1(86.27,108.52) CPU1.AN10 85.81,109 v1(85.35,109.46) ; v1(91.75,93.89) CPU1.U3 ; CPU1.K19 v1(78.04,88.4) ; CPU1.W6 v1(89.93,95.71) ; CPU1.B28 v1(68.89,81.08) ; CPU1.AD39 57.1,101.66 57.52,102.08 v1(57.55,102.11) 57.59,102.07 58.01,101.66 CPU1.AD38 ; CPU1.AN30 65.32,109.91 v1(65.78,110.34) CPU1.AP30 CPU1.AR30 ; v1(63.04,101.2) CPU1.AC33 v1(62.12,101.2) CPU1.AC34 61.25,100.33 61.25,100.26 v1(61.24,100.25) CPU1.AC35 ; CPU1.AB5 90.78,98.52 90.78,98.52 90.83,98.47 v1(90.83,98.44) ; CPU1.V8 v1(86.87,95.26) ; CPU1.K30 v1(67.98,88.4) ; CPU1.AM17 v1(77.67,108.52) ; CPU1.AP5 v1(90.84,109.46) CPU1.AN5 ; CPU1.G6 v1(89.01,84.74) CPU1.F7 ; v1(74.92,108.52) CPU1.AM19 75.38,109 v1(75.81,109.43) 75.38,109.86 CPU1.AN19 ; CPU1.D7 v1(89.01,82) ; CPU1.K35 v1(61.21,89.31) ; v1(90.84,104.86) CPU1.AH5 ; CPU1.D26 v1(71.64,82.91) ; CPU1.E35 v1(61.21,84.74) ; CPU1.AK19 v1(75.84,106.69) ; CPU1.AK30 v1(64.87,107.6) CPU1.AL30 ; CPU1.D30 v1(67.98,82.91) ; CPU1.H26 v1(71.64,86.57) ; v1(62.12,103.03) CPU1.AF33 ; v1(70.35,108.52) CPU1.AM24 ; CPU1.K24 v1(73.47,88.4) ; CPU1.AM5 v1(90.84,107.58) CPU1.AL5 ; CPU1.M37 v1(59.38,91.14) ; v1(63.04,105.77) CPU1.AJ32 ; CPU1.D28 v1(69.81,82.91) ; CPU1.H28 v1(69.81,86.57) ; CPU1.E11 v1(85.35,83.83) ; CPU1.K26 v1(71.64,88.4) ; CPU1.AH36 v1(59.38,105.75) CPU1.AJ36 ; v1(89.01,92.06) CPU1.R6 ; CPU1.AM33 v1(63.04,109.46) ; CPU1.H21 v1(75.31,86.55) ; CPU1.AM36 59.84,109 v1(59.38,109.46) ; CPU1.AR34 v1(61.21,111.26) CPU1.AR35 ; CPU1.W33 v1(63.04,97.54) ; CPU1.E15 v1(80.8,82.93) ; CPU1.AT7 v1(88.1,111.26) ; CPU1.N8 v1(88.1,90.23) ; v1(63.04,99.37) CPU1.AA33 ; CPU1.AR4 v1(91.75,111.26) ; CPU1.H37 v1(59.38,87.48) ; CPU1.B6 v1(89.01,80.17) CPU1.A7 ; CPU1.AK29 v1(65.8,106.7) ; CPU1.G33 v1(63.04,86.57) ; CPU1.H39 v1(57.55,87.48) ; CPU1.C35 v1(61.21,82.91) ; v1(90.84,79.23) 91.3,79.69 CPU1.A4 ; CPU1.AK15 v1(79.5,106.69) ; v1(87.18,109.46) CPU1.AN8 ; CPU1.K14 v1(81.7,87.48) CPU1.K15 ; CPU1.AK12 v1(82.24,106.69) ; CPU1.R8 v1(86.87,92.51) ; CPU1.AT32 63.47,112.63 v1(63.04,112.2) 62.58,111.74 CPU1.AR33 ; CPU1.AK5 v1(90.84,105.77) CPU1.AJ5 ; CPU1.K4 v1(91.75,88.4) CPU1.L3 ; v1(86.27,109.46) CPU1.AN9 ; CPU1.J6 v1(89.01,86.57) CPU1.H7 ; CPU1.E3 v1(92.66,82.93) ; v1(92.67,101.23) CPU1.AE3 ; CPU1.T35 v1(61.21,94.8) ; CPU1.AK13 v1(81.33,106.69) ; CPU1.C37 v1(59.38,82.91) ; CPU1.K39 v1(57.55,89.31) ; CPU1.P4 v1(91.75,92.06) CPU1.R3 ; CPU1.G13 v1(82.61,84.74) ; CPU1.M21 v1(76.21,90.23) ; CPU1.AK22 v1(72.2,106.7) ; CPU1.D4 91.31,82.46 91.74,81.99 v1(91.73,81.99) ; CPU1.AT5 v1(90.84,111.26) CPU1.AR5 ; CPU1.AN6 v1(89.01,109.46) ; CPU1.Y35 v1(61.21,98.46) ; CPU1.Y37 v1(59.38,98.46) ; CPU1.C5 90.76,81.14 90.76,81.05 v1(90.81,81) ; CPU1.G31 v1(64.87,86.57) ; CPU1.AK25 v1(69.46,106.7) ; CPU1.E9 v1(87.18,82.91) ; CPU1.L11 v1(85.35,89.31) CPU1.M10 ; CPU1.V37 v1(59.38,96.63) ; CPU1.B26 v1(70.72,81.08) ; CPU1.AM34 v1(61.21,109.46) ; CPU1.E33 v1(63.04,84.74) ; v1(89.01,106.69) CPU1.AK6 v1(89.93,105.77) ; v1(91.75,107.58) 91.32,107.14 CPU1.AL4 ; v1(58.47,102.11) CPU1.AD37 ; CPU1.AK18 v1(76.75,106.69) ; CPU1.C31 v1(64.87,82.91) ; v1(66.68,113.18) 66.67,113.18 66.67,113.07 66.24,112.64 CPU1.AT29 CPU1.AT30 ; CPU1.U33 v1(63.04,95.71) ; CPU1.Y5 v1(89.93,96.63) ; v1(88.1,109.46) CPU1.AN7 ; CPU1.H24 v1(73.47,86.57) ; CPU1.AK8 v1(88.1,105.77) ; CPU1.V39 v1(57.55,96.63) ; CPU1.E13 v1(82.61,82.91) ; CPU1.AJ30 v1(64.88,105.79) ; v1(58.47,111.26) CPU1.AP37 ; CPU1.K28 v1(69.81,88.4) ; CPU1.M29 v1(68.89,90.23) ; CPU1.M19 v1(78.04,90.23) ; CPU1.AJ35 60.38,105.85 60.38,105.75 v1(60.35,105.72) ; v1(63.95,105.77) CPU1.AJ31 ; CPU1.K33 v1(62.12,88.4) CPU1.J34 v1(61.21,87.48) CPU1.H35 ; CPU1.K17 v1(79.87,88.4) ; CPU1.L6 v1(89.01,88.4) ; v1(92.67,103.94) CPU1.AG3 ; CPU1.J10 v1(85.35,87.48) ; v1(58.46,109.46) CPU1.AM37 ; v1(62.12,104.86) CPU1.AH33 ; v1(61.21,92.97) CPU1.P35 ; CPU1.F4 v1(91.75,84.74) CPU1.G3 ; CPU1.T39 v1(57.55,94.8) ; CPU1.E6 v1(89.93,82.91) ; v1(58.47,103.94) CPU1.AF37 ; CPU1.AD7 v1(89.01,101.2) CPU1.AD6 ; CPU1.E37 v1(58.5,83.86) ; CPU1.AK16 v1(78.58,106.69) ; CPU1.N3 v1(91.75,90.23) CPU1.M4 ; CPU1.F26 v1(71.64,84.74) ; CPU1.AA8 87.25,98.39 v1(87.22,98.39) ; v1(59.38,92.97) CPU1.P37 ; CPU1.AK28 v1(66.71,106.7) ; CPU1.C33 v1(63.04,82.91) ; CPU1.AK20 v1(74.92,106.69) ; v1(76.17,86.58) 76.22,86.58 CPU1.J20 ; CPU1.AM14 v1(80.41,108.52) CPU1.AL14 v1(80.41,107.6) ; CPU1.M39 v1(57.55,91.14) ; CPU1.AG4 v1(91.78,103.94) ; CPU1.AM31 v1(64.87,108.52) ; CPU1.AJ4 v1(91.75,105.77) ; CPU1.AM38 v1(57.54,109.46) ; v1(57.55,92.97) CPU1.P39 ; CPU1.J12 v1(83.53,87.48) ; CPU1.J32 v1(63.95,88.4) ; CPU1.M25 v1(72.55,90.23) ; v1(65.78,108.52) CPU1.AM30 ; v1(89.01,105.77) CPU1.AK7 ; CPU1.AN16 v1(78.58,110.34) ; v1(62.12,105.77) CPU1.AJ33 ; CPU1.F28 v1(69.81,84.74) ; CPU1.M17 v1(79.87,90.23) ; CPU1.M23 v1(74.38,90.23) ; CPU1.H30 v1(67.98,86.57) ; CPU1.AM32 v1(63.95,109.46) ; CPU1.F30 v1(67.98,84.74) ; CPU1.D39 v1(56.64,82.91) ; CPU1.M27 v1(70.72,90.23) ; CPU1.V35 v1(61.21,96.63) ; CPU1.M35 v1(61.21,91.14) ; CPU1.U6 v1(89.01,93.89) ; CPU1.G15 v1(80.76,84.72) ; v1(61.21,105.77) CPU1.AJ34 v1(61.21,106.69) ; CPU1.AK27 v1(67.63,106.7) ; v1(70.35,107.6) CPU1.AL24 ; CPU1.M15 v1(81.7,90.23) ; CPU1.R33 v1(63.04,93.89) ; CPU1.T37 v1(59.38,94.8) ; CPU1.K37 v1(59.38,89.31) ; v1(67.61,108.52) CPU1.AM27
  TOP w0.457: PR4454.2 13.96,67.82 v3(14.81,67.82) ; v1(89.93,109.46) 89.47,109 CPU1.AN6 ; CPU1.T4 v1(91.75,93.89)
  TOP w0.508: DIMM2.15 24.6,164.14 ; DIMM2.15 23.86,163.4 ; DIMM2.15 24.6,162.66 ; DIMM2.15 25.34,163.4 ; C2722.2 51.04,261.85 v3(51.45,262.26) ; DIMM2.178 41.49,168.8 ; DIMM2.178 40.75,168.06 ; DIMM2.178 40.01,168.8 ; PR5025.2 40.59,173.93 40.58,173.94 39.89,173.94 v3(39.77,174.07) ; R1611.2 R1609.2 R1610.2 C2115.2 138.13,107.51 137.69,107.51 v1(137.42,107.77) ; C3107.2 131.89,25.73 v3(131.09,25.73) ; DIMM2.26 33.95,165.74 ; DIMM2.26 34.69,165 ; DIMM2.26 33.95,164.26 ; DIMM2.26 33.21,165 ; R2055.2 v3(173.42,36.86) ; 99.4,166.46 DIMM2.241 ; DIMM2.241 99.4,167.94 ; DIMM2.241 100.14,167.2 ; DIMM2.241 98.66,167.2 ; R2043.2 167.85,148.13 168.64,147.33 168.64,146.7 v3(168.66,146.69) 168.66,146.03 168.25,145.62 168.25,145.55 167.78,145.08 C1804.2 ; R2043.2 167.27,148.08 C2007.2 ; R2043.2 168.19,148.65 168.63,149.1 168.63,150.29 168,150.93 168,150.93 ; U2501.4 175.23,159.82 v3(175.72,160.3) ; PC4705.2 v4(115.47,40.39) ; 100.82,272.98 USB3F2.11 ; USB3F2.11 101.84,274.75 ; USB3F2.11 100.82,276.52 ; USB3F2.11 99.8,274.75 ; v3(6.55,229.43) 6.55,229.05 Q6401.4 ; C1203.2 85.98,151.13 v3(86.23,150.88) ; DIMM2.257 113.74,167.2 ; DIMM2.257 113,167.94 ; DIMM2.257 112.26,167.2 ; DIMM2.257 113,166.46 ; LPC1.15 v3(190.47,17.13) ; 117.25,164.26 DIMM2.118 ; DIMM2.118 116.51,165 ; DIMM2.118 117.99,165 ; DIMM2.118 117.25,165.74 ; DIMM2.101 102.8,164.14 ; DIMM2.101 102.8,162.66 ; DIMM2.101 103.54,163.4 ; DIMM2.101 102.06,163.4 ; C2117.2 168.31,139.88 C2101.2 168.39,138.94 169.16,138.94 169.23,139 v3(169.27,139) 169.27,138.79 169.1,138.62 C2125.2 ; R2423.2 v3(162.81,40.06) ; PC4805.2 129.36,75.45 v3(129.36,76.38) ; DIMM2.151 18.54,167.2 ; DIMM2.151 17.8,166.46 ; DIMM2.151 17.8,167.94 ; DIMM2.151 17.06,167.2 ; 54.35,164.26 DIMM2.50 ; DIMM2.50 54.35,165.74 ; DIMM2.50 55.09,165 ; DIMM2.50 53.61,165 ; C1030.2 v3(95.31,150.15) ; v3(13.35,128.4) 13.35,129.79 13.47,129.92 D4301.A ; v3(13.46,81.79) 13.08,82.17 PR4468.2 ; C5902.2 v3(52.17,13.39) ; DIMM2.9 20.24,163.4 ; DIMM2.9 19.5,164.14 ; DIMM2.9 19.5,162.66 ; DIMM2.9 18.76,163.4 ; v3(7.56,224.18) 7.56,223.47 C4203.2 ; HS1902.2 170.17,103.57 C6215.2 ; C2416.2 C2405.2 171.2,9.91 v3(170.89,9.6) ; C2419.2 182.7,28.59 R2442.2 181.91,28.12 181.61,27.81 v3(181.61,27.79) ; 80.93,272.75 USB3F1.4 ; USB3F1.4 81.72,273.54 ; USB3F1.4 82.51,272.75 ; DIMM2.28 35.65,165.74 ; DIMM2.28 36.39,165 ; DIMM2.28 34.91,165 ; DIMM2.28 35.65,164.26 ; v3(169.31,115.12) 169.31,115.08 168.58,114.35 168.58,113.49 C2109.2 ; DIMM2.17 26.3,164.14 ; DIMM2.17 25.56,163.4 ; DIMM2.17 26.3,162.66 ; v3(46.56,179.45) 46.56,179.35 46.15,178.94 46.15,178.84 PC5002.2 ; 43.41,168.8 DIMM2.182 ; DIMM2.182 44.15,168.06 ; DIMM2.182 44.89,168.8 ; 16.95,164.26 DIMM2.6 ; DIMM2.6 16.95,165.74 ; DIMM2.6 16.21,165 ; DIMM2.6 17.69,165 ; DIMM2.44 49.25,165.74 ; DIMM2.44 48.51,165 ; DIMM2.44 49.99,165 ; DIMM2.44 49.25,164.26 ; v3(76.29,100.76) 77.01,100.76 PC1020.2 77.04,100.08 v3(76.29,100.08) ; DIMM2.191 52.54,167.2 ; DIMM2.191 51.06,167.2 ; DIMM2.191 51.8,167.94 ; DIMM2.191 51.8,166.46 ; v3(150.59,142.07) 150.57,142.09 150.57,142.17 150.55,142.2 150.55,142.24 150.44,142.35 150.44,142.79 150.38,142.85 R6406.2 ; v3(63.37,249.78) 63.98,250.39 C2718.2 ; PC4402.2 17.64,68.9 PC4403.2 17.64,70.06 v1(17.54,70.16) ; v3(27.6,65.71) 27.6,66.27 PR4423.2 ; v3(133.64,31.86) 133.64,31.55 133.55,31.47 133.55,31.39 132.59,30.43 C3102.2 132.83,29.76 C3101.2 R3101.1 ; Q2702.C 64.8,245.4 v3(63.95,245.4) ; U2502.10 177.51,158.42 v3(176.21,159.72) ; C603.2 v3(19.53,138.75) ; v3(38.56,17.92) C5923.2 39.52,18.05 C5922.2 ; C1102.2 73.91,151.94 v3(73.91,150.33) ; R2617.2 v3(106.87,252.3) ; 166.37,190.78 166.69,190.46 C4302.2 ; 166.37,190.78 v3(166.37,190.83) ; 166.37,190.78 165.61,190.01 C4301.2 ; v3(154.69,146.05) 155.07,145.67 C2124.2 ; 78.82,272.98 USB3F1.11 ; USB3F1.11 78.82,276.52 ; USB3F1.11 77.8,274.75 ; USB3F1.11 79.84,274.75 ; v3(154.95,37.44) 154.42,36.91 R2408.2 154.42,35.32 154.79,34.95 155.44,34.95 R2409.2 ; v3(148.56,106.55) 148.56,105.73 C1802.2 148.53,105.61 148.53,104.63 X1801.4 147.89,103.79 148.7,102.97 148.7,102.92 v3(148.73,102.9) 148.73,100.59 148.45,100.3 v3(147.13,100.3) 146.24,101.2 X1801.2 146.04,101.44 145.32,101.44 v3(145.11,101.65) 144.53,102.23 C2119.2 144.53,102.95 144.48,103 144.48,103.73 C2118.2 144.55,104.15 145.08,104.68 v3(145.08,104.76) 145.13,104.76 145.66,105.28 145.66,105.56 145.78,105.69 C1801.2 ; R1515.2 172.82,171.45 v1(172.43,171.84) ; Q2703.C v3(67.41,240.61) ; v3(138.05,58.29) 137.67,58.67 PR4708.1 ; R415.2 124.97,60.58 v3(125.4,60.15) ; DIMM2.187 49.14,167.2 ; DIMM2.187 47.66,167.2 ; DIMM2.187 48.4,167.94 ; DIMM2.187 48.4,166.46 ; R2424.2 170.14,37.76 170.21,37.82 v3(170.21,38.61) ; DIMM2.46 51.69,165 ; DIMM2.46 50.95,165.74 ; DIMM2.46 50.21,165 ; DIMM2.46 50.95,164.26 ; R2323.2 166.88,124.23 167.21,124.56 v3(167.21,124.61) ; C6214.2 150.53,18.88 150.53,18.76 150.58,18.71 150.58,15.67 v3(150.56,15.65) ; v3(167.13,8.69) R2472.2 ; R2472.2 168.07,8.83 R1516.2 ; R2472.2 167.93,7.72 C2426.2 ; v3(51.31,217.08) 51.31,217.07 50.82,217.07 50.81,217.07 R6302.1 ; v3(164.95,162.34) 164.99,162.34 165.04,162.4 165.76,162.4 C2501.2 ; 34.8,166.46 DIMM2.171 ; DIMM2.171 34.8,167.94 ; DIMM2.171 34.06,167.2 ; DIMM2.171 35.54,167.2 ; v3(188.09,180.94) 188.63,180.94 PC5109.2 ; 7.24,204.09 7.24,203.33 v3(7.03,203.12) ; v3(159.69,27.87) 160.22,27.34 160.22,27.11 C2417.2 ; DIMM2.31 38.94,163.4 ; DIMM2.31 38.2,162.66 ; DIMM2.31 38.2,164.14 ; DIMM2.31 37.46,163.4 ; 127.56,163.4 DIMM2.131 ; DIMM2.131 128.3,164.14 ; DIMM2.131 128.3,162.66 ; DIMM2.165 29.7,167.94 ; DIMM2.165 28.96,167.2 ; DIMM2.165 30.44,167.2 ; DIMM2.165 29.7,166.46 ; 47.55,164.26 DIMM2.42 ; DIMM2.42 48.29,165 ; DIMM2.42 46.81,165 ; DIMM2.42 47.55,165.74 ; C2408.2 176.11,11.99 176.11,11.32 175.93,11.14 175.93,11.07 R2475.2 175.91,10.9 175.87,10.86 v3(175.87,10.24) ; R2035.2 v3(190.04,20.4) ; 97.81,165 DIMM2.96 ; DIMM2.96 99.29,165 ; DIMM2.96 98.55,164.26 ; DIMM2.96 98.55,165.74 ; U3801.2 86.87,262.83 UC3801.2 86.5,263.32 v3(86.1,263.32) ; v3(54.36,226.12) 54.36,226.95 C9910.2 ; DIMM2.180 43.19,168.8 ; DIMM2.180 41.71,168.8 ; DIMM2.180 42.45,168.06 ; v3(183.97,30.33) 183.88,30.24 C2413.2 183.88,28.36 C2424.2 ; 28.11,165 DIMM2.20 ; DIMM2.20 28.85,165.74 ; DIMM2.20 28.85,164.26 ; DIMM2.20 29.59,165 ; 45,162.66 DIMM2.39 ; DIMM2.39 45,164.14 ; DIMM2.39 44.26,163.4 ; U4003.S v3(105.25,28.17) ; v3(7.11,202.31) 7.24,202.44 PR4956.2 ; 112.6,274.75 USB3F2.10 ; USB3F2.10 113.62,276.52 ; USB3F2.10 114.64,274.75 ; USB3F2.10 113.62,272.98 ; DIMM2.276 129.89,168.8 ; DIMM2.276 129.15,168.06 ; DIMM2.276 128.41,168.8 ; DIMM2.276 129.15,169.54 ; v3(19.84,42.91) 19.84,42.82 19.91,42.75 C4224.2 ; v3(38.58,176.2) PC5015.2 ; DIMM2.127 124.9,164.14 ; DIMM2.127 125.64,163.4 ; DIMM2.127 124.16,163.4 ; DIMM2.127 124.9,162.66 ; C6308.2 41.21,233.72 v3(41.78,234.29) ; C2103.2 171.7,148.84 v1(171.32,149.22) 171.56,149.47 171.56,150.29 v1(171.36,150.5) 171.36,151.13 v1(171.21,151.27) 170.62,151.86 170.42,151.86 v3(170.38,151.9) 170.37,151.89 v1(169.39,151.89) 169.36,151.86 168.95,151.86 168.88,151.79 168.86,151.79 168,150.93 ; R2047.2 160.45,7.59 160.39,7.53 v3(160.39,7.39) ; 50.1,166.46 DIMM2.189 ; DIMM2.189 49.36,167.2 ; DIMM2.189 50.1,167.94 ; DIMM2.189 50.84,167.2 ; 60.3,162.66 DIMM2.57 ; DIMM2.57 60.3,164.14 ; DIMM2.57 59.56,163.4 ; 133.51,165 DIMM2.138 133.68,164.43 ; EU3203.2 v3(123.27,21.21) ; v3(125.37,54.13) 125.35,54.13 125.25,54.23 C402.2 ; EU5901.2 v3(41.94,12.52) ; R424.2 120.45,53.57 120.5,53.62 v3(120.62,53.62) 120.78,53.62 121.39,54.23 R426.2 ; C403.2 126.49,63.37 125.98,62.87 125.98,62.83 v3(125.89,62.74) ; v3(151.99,145.75) 151.63,146.11 R1713.2 ; v3(12.8,233.55) 12.7,233.55 12.33,233.92 C6402.2 ; 108.86,163.4 DIMM2.109 ; DIMM2.109 109.6,162.66 ; DIMM2.109 110.34,163.4 ; DIMM2.109 109.6,164.14 ; 106.2,162.66 DIMM2.105 ; DIMM2.105 105.46,163.4 ; DIMM2.105 106.94,163.4 ; DIMM2.105 106.2,164.14 ; PC4401.2 23.88,67.56 24.47,68.15 v3(24.47,68.24) ; DIMM2.243 101.84,167.2 ; DIMM2.243 101.1,166.46 ; DIMM2.243 101.1,167.94 ; DIMM2.243 100.36,167.2 ; 118.95,164.26 DIMM2.120 ; DIMM2.120 119.69,165 ; DIMM2.120 118.95,165.74 ; DIMM2.120 118.21,165 ; R2305.2 v3(163.41,107.77) 163.46,107.82 164.23,107.82 R2312.2 ; DIMM2.265 120.54,167.2 ; DIMM2.265 119.06,167.2 ; DIMM2.265 119.8,167.94 ; DIMM2.265 119.8,166.46 ; PR4952.2 8.32,198.56 9.27,199.52 v3(9.27,199.64) ; C9106.2 163.11,163.46 162.6,163.97 v3(162.59,163.97) ; DIMM2.22 31.29,165 ; DIMM2.22 30.55,164.26 ; DIMM2.22 29.81,165 ; DIMM2.22 30.55,165.74 ; v3(157.88,98.5) 157.3,99.08 R427.2 ; PR4953.2 10.11,209.16 v3(10.11,209.98) ; v3(78.57,94.77) 79.32,94.77 PC1005.2 79.3,95.46 v3(78.56,95.46) ; C5611.2 66.74,17.59 67.18,17.14 67.18,17 v3(67.19,16.99) ; R2704.2 67.78,250.28 67.79,250.29 C2717.2 67.88,250.95 68.45,250.95 68.58,251.08 v3(68.64,251.08) ; DIMM2.274 128.19,168.8 ; DIMM2.274 127.45,169.54 ; DIMM2.274 126.71,168.8 ; DIMM2.274 127.45,168.06 ; C3807.2 80.58,264.53 v3(80.26,264.21) ; DIMM2.254 111.19,168.8 ; DIMM2.254 110.45,168.06 ; DIMM2.254 109.71,168.8 ; DIMM2.254 110.45,169.54 ; R6301.1 53.54,217.45 53.21,217.12 53.21,216.92 v3(53.21,216.92) ; PC4506.2 v4(68.91,37.43) ; DIMM2.252 109.49,168.8 ; DIMM2.252 108.75,169.54 ; DIMM2.252 108.01,168.8 ; DIMM2.252 108.75,168.06 ; C6403.2 12.6,230.87 v3(12.8,231.08) ; C2412.2 176.77,35.46 v3(177.47,35.46) ; v3(10.88,171.81) 11.02,171.94 11.02,171.98 11.53,172.49 11.71,172.49 C1107.2 12.52,173.2 R1106.2 ; DIMM2.4 15.25,165.74 ; DIMM2.4 15.25,164.26 ; DIMM2.4 14.51,165 ; DIMM2.4 15.99,165 ; v3(125.65,71.75) 125.95,71.46 PR4816.2 ; C1025.2 77.6,171.96 77.72,172.09 v3(77.76,172.09) ; DIMM2.239 98.44,167.2 ; DIMM2.239 97.7,166.46 ; DIMM2.239 96.96,167.2 ; DIMM2.239 97.7,167.94 ; 58.6,162.66 DIMM2.55 ; DIMM2.55 59.34,163.4 ; DIMM2.55 58.6,164.14 ; DIMM2.55 57.86,163.4 ; DIMM2.147 15.14,167.2 ; DIMM2.147 14.4,166.46 ; DIMM2.147 13.66,167.2 ; DIMM2.147 14.4,167.94 ; SD1.3 40.04,267.37 39.12,266.45 39.12,266.08 v3(39.1,266.07) ; DIMM2.173 36.5,167.94 ; DIMM2.173 37.24,167.2 ; DIMM2.173 36.5,166.46 ; DIMM2.173 35.76,167.2 ; DIMM2.33 39.9,164.14 ; DIMM2.33 39.16,163.4 ; DIMM2.33 40.64,163.4 ; DIMM2.33 39.9,162.66 ; v3(113.61,170.89) 113.68,170.89 113.8,170.76 PR5206.2 ; U5602.1 64.03,23.95 v3(63.24,24.74) ; v3(87.42,148.71) C1027.2 ; 120.76,163.4 DIMM2.123 ; DIMM2.123 122.24,163.4 ; DIMM2.123 121.5,164.14 ; DIMM2.123 121.5,162.66 ; C1031.2 v3(61.47,145.29) ; R2054.2 168.73,118.54 v1(168.96,118.31) ; v3(148.45,24.61) 148.45,20.82 C6206.2 147.49,19.91 C6205.2 146.08,18.5 C6203.2 ; C5610.2 69.6,17.72 v3(69.6,16.94) ; v3(173,187.78) 172.67,188.11 C4304.2 ; v3(169.03,48.29) 169.04,48.28 C9405.2 ; v3(33.03,258.52) C3303.2 R3302.2 ; C2713.2 66.59,246.21 v3(66.93,245.87) ; v3(190.08,187.41) 189.37,186.7 PR5112.2 ; v3(153.64,148.97) 154.24,148.97 154.37,148.84 C2114.2 C2113.2 ; 107.9,162.66 DIMM2.107 ; DIMM2.107 107.9,164.14 ; DIMM2.107 108.64,163.4 ; DIMM2.107 107.16,163.4 ; v3(36.98,230.65) U6301.2 ; C1201.2 v3(61.7,151.12) ; C1206.2 C1207.2 C1103.2 C1104.2 139.46,172.66 v3(139.65,172.85) ; C4227.2 24.06,36.12 v3(23.6,35.66) ; v3(182.37,163.3) 181.74,162.66 C804.2 ; 131.81,165 DIMM2.136 ; DIMM2.136 132.55,164.26 ; DIMM2.136 133.29,165 ; DIMM2.136 132.55,165.74 ; R9904.1 120.85,56.36 v3(120.62,56.59) ; 115.55,164.26 DIMM2.116 ; DIMM2.116 116.29,165 ; DIMM2.116 114.81,165 ; DIMM2.116 115.55,165.74 ; C4011.2 v3(27.89,175.54) ; R2448.1 183.63,22.83 183.85,23.05 R2406.2 R2410.2 185.12,22.3 v3(185.04,22.23) 184.98,22.16 C2407.2 R2416.2 ; DIMM2.94 97.59,165 ; DIMM2.94 96.11,165 ; DIMM2.94 96.85,164.26 ; DIMM2.94 96.85,165.74 ; v3(154.87,141.73) 154.5,141.73 C2120.2 ; DIMM2.37 43.3,164.14 ; DIMM2.37 43.3,162.66 ; DIMM2.37 44.04,163.4 ; DIMM2.37 42.56,163.4 ; R2446.1 v3(184.3,12.78) ; v3(74.13,96.42) 74.7,96.42 75.18,96.91 ; C1204.2 82.68,171.51 C1205.2 v3(82.36,172.67) ; DIMM2.167 32.14,167.2 ; DIMM2.167 30.66,167.2 ; DIMM2.167 31.4,167.94 ; DIMM2.167 31.4,166.46 ; 56.16,163.4 DIMM2.53 ; DIMM2.53 57.64,163.4 ; DIMM2.53 56.9,164.14 ; DIMM2.53 56.9,162.66 ; v3(19.91,236.07) C9904.2 ; PC5010.2 v3(64.03,175.26) ; v3(78.45,99.06) 77.77,99.06 PC1019.2 77.67,98.36 78.39,98.36 78.41,98.37 v3(78.45,98.37) ; 25.45,168.06 DIMM2.160 ; DIMM2.160 26.19,168.8 ; DIMM2.160 24.71,168.8 ; v3(46.61,266.04) 47.54,266.98 SD1.6 ; DIMM2.184 46.59,168.8 ; DIMM2.184 45.85,168.06 ; DIMM2.184 45.11,168.8 ; C5909.2 50.39,23.86 50.39,24.49 v3(50.37,24.51) 50.39,24.51 50.47,24.43 C5907.2 51.93,23.79 C5906.2 ; C2712.2 v3(57.51,255.77) ; C2423.2 170.69,32.89 v3(170.43,33.15) 171.07,33.78 C2422.2 ; R1905.2 161.61,153.91 v3(161.34,153.64) ; 27.15,168.06 DIMM2.162 ; DIMM2.162 26.41,168.8 ; DIMM2.162 27.89,168.8 ; C1032.2 117.6,102.54 v3(117.6,102.23) ; 130.96,167.2 DIMM2.279 ; DIMM2.279 131.7,166.46 ; DIMM2.279 132.44,167.2 ; DIMM2.279 131.7,167.94 ; v3(76.29,102.08) 75.67,102.08 PC1022.2 75.47,102.8 76.19,102.8 76.23,102.77 v3(76.29,102.77) ; DIMM2.263 118.84,167.2 ; DIMM2.263 117.36,167.2 ; DIMM2.263 118.1,167.94 ; DIMM2.263 118.1,166.46 ; DIMM2.11 21.2,164.14 ; DIMM2.11 20.46,163.4 ; DIMM2.11 21.2,162.66 ; DIMM2.11 21.94,163.4 ; DIMM2.48 52.65,165.74 ; DIMM2.48 52.65,164.26 ; DIMM2.48 53.39,165 ; DIMM2.48 51.91,165 ; C5908.2 62.62,15.35 62.74,15.24 v3(62.74,15.16) ; C9101.2 157.23,169.93 157.48,169.67 v3(157.48,169.42) ; v3(187.69,193.17) 187.69,192.19 C4226.2 ; C9909.2 59.59,221.26 v3(59.46,221.4) ; PC4918.2 11.06,196.47 v3(11.91,196.47) 11.91,195.54 PR4961.2 ; R2619.2 174.03,4.47 173.85,4.65 R2471.2 C2425.2 173.24,6.46 v3(173.28,6.5) ; DIMM2.238 96.85,169.54 ; DIMM2.238 96.85,168.06 ; DIMM2.238 97.59,168.8 ; DIMM2.238 96.11,168.8 ; 113.96,167.2 DIMM2.259 ; DIMM2.259 114.7,167.94 ; DIMM2.259 115.44,167.2 ; DIMM2.259 114.7,166.46 ; DIMM2.24 32.99,165 ; DIMM2.24 32.25,164.26 ; DIMM2.24 32.25,165.74 ; DIMM2.24 31.51,165 ; v3(174.64,56.96) 174.62,56.94 174.62,56.9 174.37,56.64 C9311.2 ; v3(19.18,202.79) 18.82,203.15 PC4917.2 ; v3(18.66,173.75) 18.66,174.31 R1207.2 ; 13.55,164.26 DIMM2.2 ; DIMM2.2 13.55,165.74 ; DIMM2.2 14.29,165 ; C3304.2 v3(42.95,253.87) ; v3(78.55,97.28) 79.2,97.28 PC1018.2 79.32,96.55 v3(78.55,96.55) ; v3(134.11,63.13) 134.11,62.45 PR4711.2 ; C1211.2 16.95,171.53 v3(17.17,171.74) 17.17,172.28 R1206.2 ; v3(128.4,9.5) 129.03,9.5 129.65,9.5 NGFF2.77 ; v3(128.37,57.66) R420.2 ; R2328.2 162.55,141.41 v3(162.46,141.5) ; PC4706.2 133.22,49.48 v3(132.87,49.12) ; v3(21.92,237.95) 21.87,237.9 C9903.2 ; C3307.2 v3(39.85,265.94) ; X3101.4 v3(139.6,32.09) ; PC5201.2 101.4,175.51 101.24,175.36 v4(101.23,175.36) ; v3(161.44,8.08) 161.6,8.24 161.6,9.08 C2414.2 ; C806.2 179.59,169.9 180.41,169.9 v3(180.44,169.87) 180.44,169.47 181.44,168.47 C9901.2 ; v3(76.58,271.09) 76.7,271.21 D2701.2 ; v3(117.55,106.76) 117.55,105.93 C801.2 ; v3(37.76,236.98) 37.38,237.36 R2048.2 ; C9908.2 57.07,230.38 57.06,230.38 57.02,230.42 v3(56.98,230.42) ; 91.62,272.98 USB3F1.10 ; USB3F1.10 90.6,274.75 ; USB3F1.10 92.64,274.75 ; USB3F1.10 91.62,276.52 ; ATX2.1 ATX2.2 5.88,126.46 5.88,129.88 v3(5.84,129.92) 5.46,130.3 C4303.2 ; DIMM2.13 22.9,164.14 ; DIMM2.13 23.64,163.4 ; DIMM2.13 22.16,163.4 ; DIMM2.13 22.9,162.66 ; v1(99.31,77.85) 99.32,77.84 100.32,77.84 101.72,76.44 101.72,75.43 v1(101.6,75.31) ; v3(43.45,262.75) 42.48,261.79 C3305.2 ; DIMM2.103 105.24,163.4 ; DIMM2.103 104.5,162.66 ; DIMM2.103 104.5,164.14 ; DIMM2.103 103.76,163.4 ; C601.2 16.69,139.43 v3(16.63,139.43) ; v3(17.98,205.28) 17.91,205.28 17.34,204.7 17.34,204.7 17.03,204.39 PC4913.2 ; 52.76,167.2 DIMM2.193 ; DIMM2.193 53.5,166.46 ; DIMM2.193 54.24,167.2 ; DIMM2.193 53.5,167.94 ; 125.75,168.06 DIMM2.272 ; DIMM2.272 125.75,169.54 ; DIMM2.272 126.49,168.8 ; DIMM2.272 125.01,168.8 ; C9902.2 17.07,237.09 v3(17.07,238.02) ; v4(112.03,171.05) PU5201.1 ; PC5001.2 48.03,176.4 v3(48.03,176.7) ; R9929.1 v3(9.74,26.87) ; DIMM2.248 105.35,169.54 ; DIMM2.248 105.35,168.06 ; DIMM2.248 104.61,168.8 ; DIMM2.248 106.09,168.8 ; v3(170.09,139.85) 170.09,139.04 C2107.2 170.35,139 171.22,138.13 DB2001.2 ; v3(74.13,95.55) 74.88,95.55 PC1007.2 74.82,94.84 v3(74.13,94.84) ; DIMM2.246 103.65,169.54 ; DIMM2.246 103.65,168.06 ; DIMM2.246 104.39,168.8 ; DIMM2.246 102.91,168.8 ; C3301.2 v3(36.93,254.25) ; C9103.2 160.32,167.43 160.21,167.31 v3(160.21,165.2) ; C2116.2 v3(168.78,130.56) ; R5919.2 43,25.97 v3(44.22,25.97) ; v3(58.29,278.63) R2705.1 C2719.1 ; C4223.2 24.19,41.47 C4222.2 v3(24,39.95) ; C1028.2 v3(61.49,139.57) ; v3(64.95,241.15) 64.1,241.15 Q2704.C ; C5609.2 69.74,27.13 v3(69.98,27.13) ; R2011.2 154.94,105.09 155.17,104.87 v3(155.17,104.67) ; v3(27.91,37.2) 27.9,37.2 27.47,37.63 Q4207.E 26.94,37.57 R2046.2 ; 100.25,164.26 DIMM2.98 ; DIMM2.98 100.25,165.74 ; DIMM2.98 99.51,165 ; DIMM2.98 100.99,165 ; PR4430.2 PC4414.2 23.37,66.04 23.62,65.79 v1(23.7,65.79) ; 168,150.93 C2006.2 ; C2415.2 v3(180.91,10.95) 180.77,10.81 C2411.2 ; 39.05,168.06 DIMM2.176 ; DIMM2.176 39.79,168.8 ; DIMM2.176 38.31,168.8 ; 122.46,163.4 DIMM2.125 ; DIMM2.125 123.2,164.14 ; DIMM2.125 123.2,162.66 ; DIMM2.125 123.94,163.4 ; v3(161.39,139.56) 161.39,139.56 161.45,139.62 162.04,139.62 162.18,139.76 C2123.2 ; C2418.2 182.99,20.09 v3(182.75,19.85) ; C3806.2 76.76,258.06 76.25,258.57 v3(76.25,258.62) ; 59.45,168.06 DIMM2.200 ; DIMM2.200 58.71,168.8 ; DIMM2.200 60.19,168.8 ; 115.66,167.2 DIMM2.261 ; DIMM2.261 117.14,167.2 ; DIMM2.261 116.4,166.46 ; DIMM2.261 116.4,167.94 ; v3(35.56,191.39) 35.56,191.4 C4209.2 ; v3(171.45,128.96) 171.45,128.53 170.94,128.02 C2126.2 ; v3(112.04,192.35) 111.94,192.25 v3(111,192.25) ; C2721.2 55.23,261.94 v3(54.74,261.44) ; v3(16.87,43.29) 16.87,43.13 16.92,43.08 C4221.2 ; U3901.2 89.13,26.06 89.04,25.97 UC3901.2 v3(89.04,24.49) ; R1708.2 v1(152.81,106.73) ; Q9102.E 95.92,173.48 v3(96.03,173.37) ; C4007.2 v3(110.69,31.5) 110.05,32.14 C4008.2 ; C4204.2 5.31,223.49 6.02,224.21 v3(6.63,224.21) ; 98.46,170.41 97.71,169.66 97.71,169.49 ; 60.41,168.8 DIMM2.202 ; DIMM2.202 61.89,168.8 ; DIMM2.202 61.98,168.28 ; DIMM2.202 61.15,168.06 ; v3(33.57,245.86) 33.45,245.97 33.45,247.43 R6315.2 ; C5904.2 53.91,25.21 v3(54.1,25.4) ; v3(118.39,105.03) C1033.2 ; 32.36,167.2 DIMM2.169 ; DIMM2.169 33.84,167.2 ; DIMM2.169 33.1,167.94 ; DIMM2.169 33.1,166.46 ; C802.2 183.78,158.99 v3(183.64,159.13) ; 121.61,168.8 DIMM2.268 ; DIMM2.268 123.09,168.8 ; DIMM2.268 122.35,169.54 ; DIMM2.268 122.35,168.06 ; DIMM2.35 41.6,164.14 ; DIMM2.35 41.6,162.66 ; DIMM2.35 42.34,163.4 ; DIMM2.35 40.86,163.4 ; C3108.2 132.14,21.87 131.64,21.36 131.41,21.36 v3(131.09,21.03) ; v3(77.25,169.51) 77.4,169.51 78.17,170.28 C1108.2 ; 15.36,167.2 DIMM2.149 ; DIMM2.149 16.1,166.46 ; DIMM2.149 16.84,167.2 ; DIMM2.149 16.1,167.94 ; v3(183.57,25.63) 182.91,26.29 R2449.1 ; U3201.2 126.72,14.05 v3(126.26,13.59) ; v3(162.08,37.16) 161.84,36.92 R2417.2 ; v3(46.23,180.62) 45.87,180.62 45.83,180.66 PR5003.2 ; C2714.2 58.36,253.47 58.36,253.73 57.86,254.23 57.86,254.25 v3(57.81,254.3) ; v3(165.79,143.58) 165.56,143.81 165.12,143.81 R2326.2 ; DIMM2.158 24.49,168.8 ; DIMM2.158 23.75,168.06 ; DIMM2.158 23.01,168.8 ; 106.31,168.8 DIMM2.250 ; DIMM2.250 107.05,168.06 ; DIMM2.250 107.05,169.54 ; DIMM2.250 107.79,168.8 ; R2304.2 61.28,249.05 v3(60.73,249.05) ; v3(161.04,15.44) 160.82,15.66 160.82,15.67 160.34,16.15 Q2407.S 160.34,16.73 160.21,16.86 R2450.1 ; v3(122.33,76.86) 122.33,76.15 122.66,75.82 PC4804.2 ; 130.85,164.26 DIMM2.134 ; DIMM2.134 131.59,165 ; DIMM2.134 130.11,165 ; DIMM2.134 130.85,165.74 ; C2421.2 C2420.2 v3(177.47,34.53) ; C805.2 182.16,159.84 v3(182.6,159.84) 182.6,159.14 R808.2 ; PC4919.2 12.14,209.63 11.81,209.96 ; 54.46,167.2 DIMM2.195 ; DIMM2.195 55.2,166.46 ; DIMM2.195 55.94,167.2 ; DIMM2.195 55.2,167.94 ; DIMM2.129 127.34,163.4 ; DIMM2.129 126.6,162.66 ; DIMM2.129 125.86,163.4 ; DIMM2.129 126.6,164.14 ; PC4427.2 v1(11.52,56.29) ; R1919.2 160.27,137.82 v3(160.25,137.79) ; v3(29.08,172.14) 29.02,172.2 C4012.2 ; 19.61,168.8 DIMM2.154 ; DIMM2.154 20.35,168.06 ; DIMM2.154 21.09,168.8 ; v3(195.05,150.65) 195.33,150.93 PC5107.2 ; v3(76.2,259.38) 76.68,259.38 76.98,259.08 R3812.1 ; v3(58.97,229.65) 58.97,229.23 C9907.2 ; PU4801.2 125.35,72.38 124.99,72.03 124.99,71.96 124.82,71.78 v3(124.82,71.73) ; U2601.2 179.55,6.2 180.5,7.15 U2601.4 180.97,7.25 180.97,7.1 182.03,6.05 v3(182.19,6.05) 182.23,6.08 R2611.2 ; v3(178.13,47.43) C9310.2 ; D4302.A 172.97,186.31 v3(173.74,187.07) ; C9312.2 v3(167.72,54.32) ; R2505.2 49.39,260.73 v3(48.85,260.73) ; C4220.2 v3(18.06,42.93) ; v3(55.5,13.39) 55.5,13.91 C5905.2 55.2,14.22 55.23,14.25 55.55,14.25 55.59,14.29 R5904.2 ; v3(167.16,176.15) 167.06,176.05 C9102.2 ; C2106.2 156.65,144.21 157.1,143.76 v3(157.1,143.71) ; v3(76.29,92.84) 77.04,92.84 PC1006.2 77.03,93.51 76.31,93.51 v3(76.29,93.53) ; SD1.12 v3(58.42,281.05) ; DIMM2.198 58.49,168.8 ; DIMM2.198 57.75,168.06 ; DIMM2.198 57.01,168.8 ; v3(93.68,22.2) 93.68,22.15 93.75,22.08 EU3901.2 ; v3(167.82,115.34) 167.13,114.66 C2108.2 ; v3(10.02,205.93) 9.97,205.93 9.84,206.06 PR4957.2 ; 104.27,7.11 102.43,8.95 RJ45R1.25 ; C2711.2 v3(58.45,254.72) ; v3(33.32,209.04) 33.4,209.04 33.87,208.57 NGFF1.76 ; 22.05,168.06 DIMM2.156 ; DIMM2.156 22.79,168.8 ; DIMM2.156 21.31,168.8 ; v3(137.35,63.13) PR4717.2 ; C3805.2 v3(86.93,256.46) ; PR4466.2 v3(39.12,33.34) ; C1026.2 86.53,170.22 v3(85.92,169.61) ; C3302.2 v3(37.08,251.97) ; 113.85,164.26 DIMM2.114 ; DIMM2.114 114.59,165 ; DIMM2.114 113.11,165 ; DIMM2.114 113.85,165.74 ; CPU1.H12 v1(84.44,86.57) ; 101.24,14.06 RJ45R1.27 ; RJ45R1.27 103.62,14.06 ; RJ45R1.27 RJ45R1.25 ; v3(68.45,150.88) 68.91,151.33 C1101.2 ; C1803.2 171.11,143.64 v3(171.55,143.64) 171.45,143.74 171.45,145.08 171.7,145.33 C2102.2 ; v3(130.81,19.33) C6213.2 C6201.2 ; 133.4,166.46 DIMM2.281 ; DIMM2.281 132.66,167.2 ; DIMM2.281 133.4,167.94 ; v3(19.15,201.96) PC4906.2 ; v3(73.81,147.83) C1029.2 ; PC4416.2 26.12,57.01 26.11,57.02 v1(26.11,57.1) ; C6013.2 91.11,194.01 90.26,194.85 v4(89.95,194.85) ; 11.81,209.96 11.81,209.93 11.18,209.3 PR4962.2 ; 11.81,209.96 v3(11.81,209.98) ; v3(156.59,175.26) 156.92,175.59 C9104.2 158.33,175.59 C9105.2 ; C1213.2 C1212.2 121.56,173.24 121.95,173.63 v3(121.95,174.22) 121.3,174.22 C1110.2 ; C9905.2 v3(23.8,237.95) ; v3(103.76,172.67) 103.76,172.59 104.03,172.33 104.03,171.88 PC5205.2 ; v3(81.53,27.18) 81.53,27.2 82.04,27.71 C3901.2 ; 115.57,6.35 117.76,6.35 RJ45R1.24 ; C2127.2 C2122.2 v4(186.21,147.15) ; X3101.2 v3(135.82,33.08) ; C9410.2 C9404.2 174.69,53.4 174.88,53.59 v3(174.88,53.67) ; C9911.2 55.76,225.1 v3(55.34,224.68) ; v3(34.04,53.37) 33.81,53.37 33.53,53.09 PC4505.2 ; DIMM2.270 124.79,168.8 ; DIMM2.270 124.05,168.06 ; DIMM2.270 124.05,169.54 ; DIMM2.270 123.31,168.8 ; C5903.1 v3(63.63,19.96) ; CPU1.C2 93.35,81.31 v1(94.27,81.31) 95.08,81.31 v1(97.4,78.99) ; C2104.2 C2105.2 156.59,149.85 156.28,150.16 155.86,150.16 v3(155.84,150.19) ; v3(169,112.51) 168.35,112.51 167.73,111.89 R1514.2 ; EU3202.2 v3(106.76,28.96) ; v3(58.88,252.53) 58.89,252.51 60.05,252.51 R2052.2 60.34,252.76 C2715.2 ; C4009.2 103,171.82 103,172.21 v3(102.62,172.59) ; v3(25.25,173.74) 25.25,173.56 24.47,172.78 C4013.2 ; v4(101.28,173.23) 101.6,173.23 PC5202.2 ; v3(14.15,136.4) R2604.2 ; C6404.2 v3(17.22,240) ; v3(71.97,93.47) 72.75,93.47 PC1008.2 72.66,92.79 v3(71.97,92.79) ; v3(186.57,190.82) Q4205.E ; R3817.2 v3(79.02,256.44) ; C9411.2 v3(177.04,48.49) ; EU5902.2 v3(32.69,14.86) ; v3(194.82,187.91) 195.54,187.91 195.63,187.82 PR5111.2 ; v3(92.86,26.42) 92.32,26.96 R2045.2 ; R2474.2 v3(182.68,31.81) ; C1202.2 v3(62.56,151.09) ; v3(10.79,170.3) 11.65,170.3 11.78,170.42 C1106.2 ; R2309.2 182.64,9.13 182.88,8.89 v3(182.88,8.79) ; v3(189.76,192.58) 190.84,191.5 PR5116.2 ; RJ45R1.25 103.62,10.76 ; RJ45R1.25 101.24,10.76 ; R2053.2 v3(62.27,236.8) ; v3(163.68,9.83) 163.68,9.86 163.7,9.88 C2406.2 ; DIMM2.112 112.89,165 ; DIMM2.112 111.41,165 ; DIMM2.112 112.15,165.74 ; v1(138.05,24.1) v1(138.05,24.99) ; v3(74.13,97.1) 74.16,97.08 75.01,97.08 75.18,96.91 ; C9403.2 v3(169.9,49.9) ; R3815.2 79.39,268.3 79.39,268.84 79.76,269.2 v3(79.76,269.24) ; PR4471.2 v3(17.01,64.03) ; 75.18,96.91 PC1021.2 ; LPC1.16 v3(190.47,3.8) ; U4010.3 29.01,172.15 ; v3(24.04,233.3) PC4910.2 ; v3(41.3,234.95) C6310.2 ; R1918.2 154.27,138.02 154.28,138.01 v3(154.28,137.82) ; CPU1.H11 v1(85.35,86.57) ; R6408.2 R6407.2 171.33,132.87 v3(171.22,132.77) ; CPU1.AU1 v1(94.7,112.63) ; v3(53.19,12.62) C5901.2 ; v1(57.02,80.9) 57.39,80.9 58.01,81.52 CPU1.B38 ; C4219.2 v3(186.69,195.07) ; C1208.2 17.96,170.5 16.78,170.5 v3(16.76,170.48) 16.69,170.48 16.64,170.43 C1210.2 ; v3(119.89,27.94) 119.89,27.94 121.46,29.51 EU3204.2 ; R1511.1 167.83,109.65 168.56,110.38 v3(168.56,110.59) 168.51,110.64 167.86,110.64 R1512.2 ; v4(36.96,183.46) PC5009.2 ; C3306.2 v3(39.34,264.8) ; R5609.2 v3(66.32,15.38)
  TOP w1.016: 40.2,196.5 PT4901.2 ; PT4901.2 41.15,197.45 ; PT4901.2 39.25,197.45 ; PT4901.2 40.2,198.4 ; SATA1.9 118.04,200.58 ; SATA1.9 118.04,198.22 ; SATA1.9 116.86,199.4 ; SATA1.9 119.22,199.4 ; 73.18,9.25 HDMI1.20 ; HDMI1.20 75.32,9.25 ; HDMI1.20 74.25,7.43 ; HDMI1.20 74.25,11.07 ; HDMI1.23 59.75,4.7 ; HDMI1.23 60.82,3.29 ; HDMI1.23 58.68,3.29 ; HDMI1.23 59.75,1.88 ; 138.04,198.22 SATA3.9 ; SATA3.9 139.22,199.4 ; SATA3.9 136.86,199.4 ; SATA3.9 138.04,200.58 ; 49.49,1.84 VGA1.17 ; VGA1.17 49.49,5.96 ; VGA1.17 47.44,3.9 ; VGA1.17 51.55,3.9 ; 73.18,3.29 HDMI1.22 ; HDMI1.22 75.32,3.29 ; HDMI1.22 74.25,4.7 ; HDMI1.22 74.25,1.88 ; SATA3.1 128.44,200.4 ; SATA3.1 127.69,199.65 ; SATA3.1 127.69,201.15 ; SATA3.1 126.94,200.4 ; SATA1.4 112.25,200.4 ; SATA1.4 110.75,200.4 ; SATA1.4 111.5,201.15 ; 33.31,4.88 VGA1.10 32.35,4.32 ; VGA1.6 43.45,3.9 ; VGA1.6 42.47,2.92 ; VGA1.6 42.47,4.88 ; 37.9,2.92 VGA1.8 37.9,4.88 ; SATA1.7 116.06,200.4 ; SATA1.7 115.31,199.65 ; SATA1.7 114.56,200.4 ; SATA1.7 115.31,201.15 ; 126.1,201.29 SATA3.8 124.32,199.51 ; 106.94,200.4 SATA1.1 ; SATA1.1 108.44,200.4 ; SATA1.1 107.69,201.15 ; SATA1.1 107.69,199.65 ; 78.04,180.97 PT5001.2 ; PT5001.2 78.99,180.02 ; PT5001.2 79.95,180.97 ; PT5001.2 78.99,181.93 ; USB2R1.9 83.04,9.19 ; USB2R1.9 81.43,10.8 ; USB2R1.9 81.43,7.58 ; USB2R1.9 79.82,9.19 ; 33.13,6.3 VGA1.5 32.91,6.62 ; 40.18,4.88 VGA1.7 40.18,2.92 ; VGA1.16 24.5,5.96 ; VGA1.16 26.56,3.9 ; VGA1.16 22.45,3.9 ; VGA1.16 24.5,1.84 ; 130.75,200.4 SATA3.4 ; SATA3.4 131.5,201.15 ; SATA3.4 132.25,200.4 ; 135.31,199.65 SATA3.7 ; SATA3.7 135.31,201.15 ; SATA3.7 136.06,200.4 ; SATA3.7 134.56,200.4 ; 59.75,7.43 HDMI1.21 ; HDMI1.21 60.82,9.25 ; HDMI1.21 58.68,9.25 ; HDMI1.21 59.75,11.07 ; 104.32,199.51 SATA1.8 106.1,201.29
  L3SGND w0.508: SLOT2.A54 179.55,100.58 ; SLOT2.A54 179.55,99 ; SLOT2.A54 178.76,99.79 ; SLOT2.A54 180.34,99.79 ; 113.62,272.98 USB3F2.10 ; USB3F2.10 113.62,276.52 ; USB3F2.10 112.6,274.75 ; USB3F2.10 114.64,274.75 ; 181.55,116 SLOT2.A71 ; SLOT2.A71 182.34,116.79 ; SLOT2.A71 181.55,117.58 ; SLOT2.A71 180.76,116.79 ; USB3F2.7 108.01,271.25 ; USB3F2.7 107.22,272.04 ; USB3F2.7 106.43,271.25 ; USB3F2.7 107.22,270.46 ; 185.26,109.79 SLOT2.B64 ; SLOT2.B64 186.05,110.58 ; SLOT2.B64 186.05,109 ; SLOT2.B64 186.84,109.79 ; RJ45R1.29 99.65,21.23 ; RJ45R1.29 99.65,18.01 ; RJ45R1.29 101.26,19.62 ; RJ45R1.29 98.04,19.62 ; 185.26,105.79 SLOT2.B60 ; SLOT2.B60 186.05,105 ; SLOT2.B60 186.84,105.79 ; SLOT2.B60 186.05,106.58 ; SLOT2.B39 184.84,84.79 ; SLOT2.B39 184.05,85.58 ; SLOT2.B39 183.26,84.79 ; SLOT2.B39 184.05,84 ; SLOT2.B35 184.05,81.58 ; SLOT2.B35 184.84,80.79 ; SLOT2.B35 184.05,80 ; SLOT2.B35 183.26,80.79 ; FANC1.1 7,143.48 ; FANC1.1 7.97,142.51 ; FANC1.1 7,141.54 ; FANC1.1 6.03,142.51 ; SLOT2.A23 181.55,69.58 ; SLOT2.A23 182.34,68.79 ; SLOT2.A23 180.76,68.79 ; SLOT2.A23 181.55,68 ; 181.55,72 SLOT2.A27 ; SLOT2.A27 181.55,73.58 ; SLOT2.A27 180.76,72.79 ; SLOT2.A27 182.34,72.79 ; SLOT2.B32 186.84,77.79 ; SLOT2.B32 186.05,78.58 ; SLOT2.B32 185.26,77.79 ; SLOT2.B32 186.05,77 ; 184.05,66 SLOT2.B21 ; SLOT2.B21 184.05,67.58 ; SLOT2.B21 183.26,66.79 ; SLOT2.B21 184.84,66.79 ; 186.05,67 SLOT2.B22 ; SLOT2.B22 186.05,68.58 ; SLOT2.B22 185.26,67.79 ; SLOT2.B22 186.84,67.79 ; 98.04,6.94 RJ45R1.23 ; RJ45R1.23 101.26,6.94 ; RJ45R1.23 99.65,8.55 ; RJ45R1.23 99.65,5.33 ; 179.55,103 SLOT2.A58 ; SLOT2.A58 178.76,103.79 ; SLOT2.A58 179.55,104.58 ; SLOT2.A58 180.34,103.79 ; SLOT2.B77 184.05,123.58 ; SLOT2.B77 183.26,122.79 ; SLOT2.B77 184.84,122.79 ; SLOT2.B77 184.05,122 ; SLOT2.B53 184.05,99.58 ; SLOT2.B53 184.05,98 ; SLOT2.B53 184.84,98.79 ; SLOT2.B53 183.26,98.79 ; 49.91,234.39 BT2501.2 ; BT2501.2 51.03,235.51 ; BT2501.2 49.91,236.63 ; BT2501.2 48.79,235.51 ; 60.41,168.8 DIMM2.202 ; DIMM2.202 61.15,168.06 ; DIMM2.202 61.89,168.8 ; DIMM2.202 61.15,169.54 ; USB3F1.4 82.51,272.75 ; USB3F1.4 81.72,273.54 ; USB3F1.4 80.93,272.75 ; 9.21,94.41 PT4601.2 ; PT4601.2 10.16,95.37 ; PT4601.2 11.11,94.41 ; PT4601.2 10.16,93.46 ; PT4603.2 31.37,100.39 ; PT4603.2 32.32,99.44 ; PT4603.2 30.42,99.44 ; PT4603.2 31.37,98.49 ; 181.55,76 SLOT2.A31 ; SLOT2.A31 182.34,76.79 ; SLOT2.A31 180.76,76.79 ; SLOT2.A31 181.55,77.58 ; 186.05,71 SLOT2.B26 ; SLOT2.B26 186.05,72.58 ; SLOT2.B26 186.84,71.79 ; SLOT2.B26 185.26,71.79 ; SLOT2.B18 186.05,64.58 ; SLOT2.B18 186.05,63 ; SLOT2.B18 185.26,63.79 ; SLOT2.B18 186.84,63.79 ; DIMM2.274 128.19,168.8 ; DIMM2.274 127.45,169.54 ; DIMM2.274 127.45,168.06 ; DIMM2.274 126.71,168.8 ; SLOT2.A24 180.34,69.79 ; SLOT2.A24 178.76,69.79 ; SLOT2.A24 179.55,70.58 ; SLOT2.A24 179.55,69 ; DIMM2.248 106.09,168.8 ; DIMM2.248 105.35,169.54 ; DIMM2.248 104.61,168.8 ; 178.76,119.79 SLOT2.A74 ; SLOT2.A74 180.34,119.79 ; SLOT2.A74 179.55,120.58 ; SLOT2.A74 179.55,119 ; 179.55,91 SLOT2.A46 ; SLOT2.A46 179.55,92.58 ; SLOT2.A46 178.76,91.79 ; SLOT2.A46 180.34,91.79 ; 185.26,81.79 SLOT2.B36 ; SLOT2.B36 186.05,82.58 ; SLOT2.B36 186.84,81.79 ; SLOT2.B36 186.05,81 ; 184.05,74 SLOT2.B29 ; SLOT2.B29 184.05,75.58 ; SLOT2.B29 184.84,74.79 ; SLOT2.B29 183.26,74.79 ; 178.76,65.79 SLOT2.A20 ; SLOT2.A20 179.55,66.58 ; SLOT2.A20 180.34,65.79 ; SLOT2.A20 179.55,65 ; SLOT2.A51 181.55,97.58 ; SLOT2.A51 181.55,96 ; SLOT2.A51 182.34,96.79 ; SLOT2.A51 180.76,96.79 ; 21.31,168.8 DIMM2.156 ; DIMM2.156 22.79,168.8 ; DIMM2.156 22.05,169.54 ; SLOT2.B65 184.84,110.79 ; SLOT2.B65 183.26,110.79 ; SLOT2.B65 184.05,111.58 ; SLOT2.B65 184.05,110 ; 102.93,272.75 USB3F2.4 ; USB3F2.4 103.72,273.54 ; USB3F2.4 104.51,272.75 ; 116.74,19.62 RJ45R1.30 ; RJ45R1.30 118.35,21.23 ; RJ45R1.30 119.96,19.62 ; RJ45R1.30 118.35,18.01 ; 45.11,168.8 DIMM2.184 ; DIMM2.184 45.85,169.54 ; DIMM2.184 46.59,168.8 ; 183.26,70.79 SLOT2.B25 ; SLOT2.B25 184.84,70.79 ; SLOT2.B25 184.05,70 ; SLOT2.B25 184.05,71.58 ; 179.55,57 SLOT2.A12 ; SLOT2.A12 178.76,57.79 ; SLOT2.A12 179.55,58.58 ; SLOT2.A12 180.34,57.79 ; 124.05,168.06 DIMM2.270 ; DIMM2.270 123.31,168.8 ; DIMM2.270 124.79,168.8 ; DIMM2.270 124.05,169.54 ; RJ45R1.27 104.04,15.25 ; RJ45R1.27 102.43,13.64 ; RJ45R1.27 102.43,16.86 ; RJ45R1.27 100.82,15.25 ; DIMM2.154 21.09,168.8 ; DIMM2.154 20.35,169.54 ; DIMM2.154 19.61,168.8 ; DIMM2.250 107.79,168.8 ; DIMM2.250 106.31,168.8 ; DIMM2.250 107.05,169.54 ; SLOT2.A70 180.34,115.79 ; SLOT2.A70 178.76,115.79 ; SLOT2.A70 179.55,115 ; SLOT2.A70 179.55,116.58 ; DIMM2.198 58.49,168.8 ; DIMM2.198 57.01,168.8 ; DIMM2.198 57.75,168.06 ; DIMM2.198 57.75,169.54 ; 185.26,85.79 SLOT2.B40 ; SLOT2.B40 186.05,86.58 ; SLOT2.B40 186.84,85.79 ; SLOT2.B40 186.05,85 ; SLOT2.A78 179.55,124.58 ; SLOT2.A78 179.55,123 ; SLOT2.A78 180.34,123.79 ; SLOT2.A78 178.76,123.79 ; 85.22,270.46 USB3F1.7 ; USB3F1.7 84.43,271.25 ; USB3F1.7 86.01,271.25 ; USB3F1.7 85.22,272.04 ; 181.55,104 SLOT2.A59 ; SLOT2.A59 180.76,104.79 ; SLOT2.A59 181.55,105.58 ; SLOT2.A59 182.34,104.79 ; 185.26,125.79 SLOT2.B80 ; SLOT2.B80 186.05,125 ; SLOT2.B80 186.84,125.79 ; SLOT2.B80 186.05,126.58 ; 179.55,63 SLOT2.A18 ; SLOT2.A18 179.55,64.58 ; SLOT2.A18 178.76,63.79 ; SLOT2.A18 180.34,63.79 ; SLOT2.A38 180.34,83.79 ; SLOT2.A38 179.55,84.58 ; SLOT2.A38 179.55,83 ; SLOT2.A38 178.76,83.79 ; 181.55,108 SLOT2.A63 ; SLOT2.A63 181.55,109.58 ; SLOT2.A63 182.34,108.79 ; SLOT2.A63 180.76,108.79 ; 125.01,168.8 DIMM2.272 ; DIMM2.272 125.75,169.54 ; DIMM2.272 125.75,168.06 ; DIMM2.272 126.49,168.8 ; 185.26,117.79 SLOT2.B72 ; SLOT2.B72 186.05,117 ; SLOT2.B72 186.05,118.58 ; SLOT2.B72 186.84,117.79 ; SLOT2.B4 186.05,48.58 ; SLOT2.B4 186.05,47 ; SLOT2.B4 186.84,47.79 ; SLOT2.B4 185.26,47.79 ; 196.22,13.89 JMP1.4 ; JMP1.4 197.18,14.86 ; JMP1.4 195.25,14.86 ; JMP1.4 196.22,15.82 ; 183.26,102.79 SLOT2.B57 ; SLOT2.B57 184.84,102.79 ; SLOT2.B57 184.05,103.58 ; SLOT2.B57 184.05,102 ; PT4605.2 31.11,84.52 ; PT4605.2 32.07,83.57 ; PT4605.2 31.11,82.61 ; PT4605.2 30.16,83.57 ; SLOT2.A4 180.34,47.79 ; SLOT2.A4 178.76,47.79 ; SLOT2.A4 179.55,47 ; SLOT2.A4 179.55,48.58 ; SLOT2.A28 179.55,74.58 ; SLOT2.A28 180.34,73.79 ; SLOT2.A28 179.55,73 ; SLOT2.A28 178.76,73.79 ; PT4602.2 32.07,75.69 ; PT4602.2 31.11,76.65 ; PT4602.2 31.11,74.74 ; PT4602.2 30.16,75.69 ; SLOT2.B49 184.05,95.58 ; SLOT2.B49 183.26,94.79 ; SLOT2.B49 184.84,94.79 ; SLOT2.B49 184.05,94 ; RJ45R1.26 117.18,9.57 ; RJ45R1.26 115.57,7.96 ; RJ45R1.26 113.96,9.57 ; RJ45R1.26 115.57,11.18 ; RJ45R1.8 112.5,15.83 ; RJ45R1.8 111.57,14.9 ; RJ45R1.8 112.5,13.97 ; RJ45R1.8 113.43,14.9 ; 185.26,97.79 SLOT2.B52 ; SLOT2.B52 186.05,98.58 ; SLOT2.B52 186.05,97 ; SLOT2.B52 186.84,97.79 ; DIMM2.178 40.75,169.54 ; DIMM2.178 41.49,168.8 ; DIMM2.178 40.01,168.8 ; 185.26,113.79 SLOT2.B68 ; SLOT2.B68 186.05,114.58 ; SLOT2.B68 186.84,113.79 ; SLOT2.B68 186.05,113 ; SLOT2.B61 184.84,106.79 ; SLOT2.B61 183.26,106.79 ; SLOT2.B61 184.05,107.58 ; SLOT2.B61 184.05,106 ; DIMM2.162 27.89,168.8 ; DIMM2.162 27.15,169.54 ; DIMM2.162 26.41,168.8 ; SLOT2.A75 182.34,120.79 ; SLOT2.A75 181.55,121.58 ; SLOT2.A75 180.76,120.79 ; SLOT2.A75 181.55,120 ; USB3F1.11 79.84,274.75 ; USB3F1.11 78.82,276.52 ; USB3F1.11 78.82,272.98 ; USB3F1.11 77.8,274.75 ; 178.76,79.79 SLOT2.A34 ; SLOT2.A34 180.34,79.79 ; SLOT2.A34 179.55,80.58 ; SLOT2.A34 179.55,79 ; USB3F2.11 101.84,274.75 ; USB3F2.11 99.8,274.75 ; USB3F2.11 100.82,272.98 ; USB3F2.11 100.82,276.52 ; TC3901.2 88.9,21.78 ; TC3901.2 89.85,20.83 ; TC3901.2 88.9,19.87 ; TC3901.2 87.95,20.83 ; SLOT2.A67 181.55,113.58 ; SLOT2.A67 180.76,112.79 ; SLOT2.A67 181.55,112 ; SLOT2.A67 182.34,112.79 ; 183.26,118.79 SLOT2.B73 ; SLOT2.B73 184.05,118 ; SLOT2.B73 184.84,118.79 ; SLOT2.B73 184.05,119.58 ; DIMM2.158 24.49,168.8 ; DIMM2.158 23.01,168.8 ; DIMM2.158 23.75,169.54 ; 12.81,164.68 DIMM2.2 12.81,165 ; 181.55,60 SLOT2.A15 ; SLOT2.A15 180.76,60.79 ; SLOT2.A15 181.55,61.58 ; SLOT2.A15 182.34,60.79 ; 116.74,6.94 RJ45R1.24 ; RJ45R1.24 118.35,5.33 ; RJ45R1.24 118.35,8.55 ; RJ45R1.24 119.96,6.94 ; 180.76,86.79 SLOT2.A41 ; SLOT2.A41 181.55,87.58 ; SLOT2.A41 182.34,86.79 ; SLOT2.A41 181.55,86 ; 24.71,168.8 DIMM2.160 ; DIMM2.160 25.45,169.54 ; DIMM2.160 26.19,168.8 ; 121.61,168.8 DIMM2.268 ; DIMM2.268 122.35,169.54 ; DIMM2.268 123.09,168.8 ; DIMM2.268 122.35,168.06 ; 178.76,111.79 SLOT2.A66 ; SLOT2.A66 180.34,111.79 ; SLOT2.A66 179.55,112.58 ; SLOT2.A66 179.55,111 ; DIMM2.252 108.75,169.54 ; DIMM2.252 109.49,168.8 ; DIMM2.252 108.01,168.8 ; 183.26,58.79 SLOT2.B13 ; SLOT2.B13 184.05,58 ; SLOT2.B13 184.84,58.79 ; SLOT2.B13 184.05,59.58 ; 128.41,168.8 DIMM2.276 ; DIMM2.276 129.89,168.8 ; DIMM2.276 129.15,169.54 ; SLOT2.A62 179.55,108.58 ; SLOT2.A62 179.55,107 ; SLOT2.A62 180.34,107.79 ; SLOT2.A62 178.76,107.79 ; 102.37,22.26 RJ45R1.18 ; RJ45R1.18 103.29,21.35 ; RJ45R1.18 104.2,22.26 ; RJ45R1.18 103.29,23.17 ; 30.16,91.57 PT4604.2 ; PT4604.2 31.11,90.61 ; PT4604.2 32.07,91.57 ; PT4604.2 31.11,92.52 ; 181.55,100 SLOT2.A55 ; SLOT2.A55 182.34,100.79 ; SLOT2.A55 181.55,101.58 ; SLOT2.A55 180.76,100.79 ; SLOT2.A79 181.55,125.58 ; SLOT2.A79 181.55,124 ; SLOT2.A79 180.76,124.79 ; SLOT2.A79 182.34,124.79 ; SLOT2.B69 184.05,115.58 ; SLOT2.B69 184.84,114.79 ; SLOT2.B69 183.26,114.79 ; SLOT2.B69 184.05,114 ; 179.55,127 SLOT2.A82 ; SLOT2.A82 180.34,127.79 ; SLOT2.A82 178.76,127.79 ; 186.05,121 SLOT2.B76 ; SLOT2.B76 186.05,122.58 ; SLOT2.B76 185.26,121.79 ; SLOT2.B76 186.84,121.79 ; 180.76,44.79 SLOT2.A1 ; SLOT2.A1 181.55,44 ; SLOT2.A1 182.34,44.79 ; SLOT2.A1 181.55,45.58 ; 39.05,169.54 DIMM2.176 39.79,168.8 ; SLOT2.B7 184.84,50.79 ; SLOT2.B7 183.26,50.79 ; SLOT2.B7 184.05,50 ; SLOT2.B47 184.84,92.79 ; SLOT2.B47 183.26,92.79 ; SLOT2.B47 184.05,93.58 ; SLOT2.B47 184.05,92 ; 58.71,168.8 DIMM2.200 ; DIMM2.200 60.19,168.8 ; DIMM2.200 59.45,168.06 ; DIMM2.200 59.45,169.54 ; DIMM2.254 110.45,169.54 ; DIMM2.254 109.71,168.8 ; DIMM2.254 111.19,168.8 ; SLOT2.A37 182.34,82.79 ; SLOT2.A37 180.76,82.79 ; SLOT2.A37 181.55,82 ; SLOT2.A37 181.55,83.58 ; SLOT2.B44 186.84,89.79 ; SLOT2.B44 186.05,90.58 ; SLOT2.B44 186.05,89 ; SLOT2.B44 185.26,89.79 ; 115.57,13.64 RJ45R1.28 ; RJ45R1.28 117.18,15.25 ; RJ45R1.28 115.57,16.86 ; RJ45R1.28 113.96,15.25 ; 103.65,169.54 DIMM2.246 104.39,168.8 ; SLOT2.A49 181.55,95.58 ; SLOT2.A49 182.34,94.79 ; SLOT2.A49 180.76,94.79 ; SLOT2.A49 181.55,94 ; SLOT2.A42 180.34,87.79 ; SLOT2.A42 179.55,87 ; SLOT2.A42 178.76,87.79 ; SLOT2.A42 179.55,88.58 ; 91.62,272.98 USB3F1.10 ; USB3F1.10 92.64,274.75 ; USB3F1.10 90.6,274.75 ; USB3F1.10 91.62,276.52 ; 180.76,90.79 SLOT2.A45 ; SLOT2.A45 181.55,90 ; SLOT2.A45 181.55,91.58 ; SLOT2.A45 182.34,90.79 ; 111.57,12.28 RJ45R1.4 ; RJ45R1.4 112.5,13.21 ; RJ45R1.4 113.43,12.28 ; RJ45R1.4 112.5,11.35 ; SLOT2.B56 186.05,102.58 ; SLOT2.B56 186.05,101 ; SLOT2.B56 185.26,101.79 ; SLOT2.B56 186.84,101.79 ; RJ45R1.25 102.43,11.18 ; RJ45R1.25 102.43,7.96 ; RJ45R1.25 100.82,9.57 ; RJ45R1.25 104.04,9.57 ; 184.05,88 SLOT2.B43 ; SLOT2.B43 183.26,88.79 ; SLOT2.B43 184.05,89.58 ; SLOT2.B43 184.84,88.79 ; DIMM2.182 44.89,168.8 ; DIMM2.182 44.15,169.54 ; DIMM2.182 43.41,168.8 ; SLOT2.B16 186.84,61.79 ; SLOT2.B16 186.05,62.58 ; SLOT2.B16 186.05,61 ; SLOT2.B16 185.26,61.79 ; DIMM2.180 42.45,169.54 ; DIMM2.180 41.71,168.8 ; DIMM2.180 43.19,168.8
  L3SGND w0.762: 178.2,197.59 ATX1.3 ; ATX1.3 178.2,200.29 ; ATX1.3 176.85,198.94 ; 7.25,119.54 ATX2.1 ; ATX2.1 5.9,120.89 ; ATX2.1 7.25,122.24 ; ATX2.1 8.6,120.89 ; ATX1.2 175.35,198.94 ; ATX1.2 174,200.29 ; ATX1.2 172.65,198.94 ; ATX1.2 174,197.59 ; SATAP1.5 94,201.8 ; SATAP1.5 94,199.62 ; SATAP1.5 92.91,200.71 ; SATAP1.5 95.09,200.71 ; 7.25,123.74 ATX2.2 ; ATX2.2 8.6,125.09 ; ATX2.2 7.25,126.44 ; ATX2.2 5.9,125.09 ; 89.91,197.71 SATAP1.3 ; SATAP1.3 91,198.8 ; SATAP1.3 92.09,197.71 ; SATAP1.3 91,196.62
  L3SGND w1.016: SATA1.9 118.04,200.58 ; SATA1.9 118.04,198.22 ; SATA1.9 116.86,199.4 ; SATA1.9 119.22,199.4 ; 159.15,63.14 SLOT1.A18 159.15,64.74 ; 79.82,9.19 USB2R1.9 ; USB2R1.9 81.43,10.8 ; USB2R1.9 81.43,7.58 ; USB2R1.9 83.04,9.19 ; 170.02,176.86 SATA2.9 ; SATA2.9 171.16,178 ; SATA2.9 168.88,178 ; 32.34,3.9 VGA1.10 ; VGA1.10 33.31,2.92 ; VGA1.10 33.31,4.88 ; 138.04,198.22 SATA3.9 ; SATA3.9 136.86,199.4 ; SATA3.9 139.22,199.4 ; SATA3.9 138.04,200.58 ; 164.85,61.94 SLOT1.B16 ; SLOT1.B16 166.45,61.94 ; SLOT1.B16 165.65,62.74 ; SLOT1.B16 165.65,61.14 ; 58.68,3.29 HDMI1.23 ; HDMI1.23 59.75,1.88 ; HDMI1.23 59.75,4.7 ; HDMI1.23 60.82,3.29 ; HDMI1.22 75.32,3.29 ; HDMI1.22 74.25,4.7 ; HDMI1.22 73.18,3.29 ; HDMI1.22 74.25,1.88 ; PT5001.2 79.95,180.97 ; PT5001.2 78.99,180.02 ; PT5001.2 78.04,180.97 ; PT5001.2 78.99,181.93 ; PT4508.2 84.39,63.25 ; PT4508.2 83.44,62.29 ; PT4508.2 82.49,63.25 ; PT4508.2 83.44,64.2 ; FANS1.1 105.28,254 ; FANS1.1 103.34,254 ; FANS1.1 104.31,253.03 ; FANS1.1 104.31,254.97 ; 158.35,47.94 SLOT1.A4 ; SLOT1.A4 159.15,48.74 ; SLOT1.A4 159.15,47.14 ; SLOT1.A4 159.95,47.94 ; 59.37,64.64 PT4503.2 ; PT4503.2 61.28,64.64 ; PT4503.2 60.33,63.69 ; PT4503.2 60.33,65.6 ; VGA1.5 32.17,6.86 ; VGA1.5 31.19,5.88 ; VGA1.5 32.17,4.9 ; 107.69,199.65 SATA1.1 ; SATA1.1 107.69,201.15 ; SATA1.1 108.44,200.4 ; SATA1.1 106.94,200.4 ; 170.6,102.19 HS1902.2 ; HS1902.2 169.65,103.14 ; HS1902.2 170.6,104.09 ; HS1902.2 171.55,103.14 ; TC3201.2 125.29,8.51 ; TC3201.2 124.33,7.56 ; TC3201.2 123.38,8.51 ; TC3201.2 124.33,9.46 ; 92.06,265.43 TC3801.2 ; TC3801.2 93.97,265.43 ; TC3801.2 93.01,266.38 ; TC3801.2 93.01,264.48 ; USB2R1.4 91.5,12.83 ; USB2R1.4 91.5,10.97 ; USB2R1.4 90.57,11.9 ; USB2R1.4 92.43,11.9 ; PT4501.2 73.92,33.2 ; PT4501.2 72.97,34.15 ; PT4501.2 72.97,32.24 ; PT4501.2 72.02,33.2 ; PT4502.2 54.55,60.58 ; PT4502.2 53.59,61.53 ; PT4502.2 52.64,60.58 ; 24.5,1.84 VGA1.16 ; VGA1.16 22.45,3.9 ; VGA1.16 26.56,3.9 ; VGA1.16 24.5,5.96 ; 177.31,178.85 SATA2.4 176.5,177.69 ; HDMI1.21 60.82,9.25 ; HDMI1.21 59.75,11.07 ; HDMI1.21 59.75,7.43 ; HDMI1.21 58.68,9.25 ; USB2R1.12 96.18,14.87 ; USB2R1.12 94.57,16.48 ; USB2R1.12 92.96,14.87 ; USB2R1.12 94.57,13.26 ; 165.65,47.14 SLOT1.B4 ; SLOT1.B4 166.45,47.94 ; SLOT1.B4 164.85,47.94 ; SLOT1.B4 165.65,48.74 ; 67.98,217.08 HS6301.1 ; HS6301.1 67.98,220.76 ; HS6301.1 66.14,218.92 ; HS6301.1 69.82,218.92 ; 91.5,13.59 USB2R1.8 ; USB2R1.8 92.43,14.52 ; USB2R1.8 90.57,14.52 ; USB2R1.8 91.5,15.45 ; 118.2,77.44 PT4801.2 ; PT4801.2 119.15,78.4 ; PT4801.2 119.15,76.49 ; PT4801.2 120.1,77.44 ; 40.2,196.5 PT4901.2 ; PT4901.2 41.15,197.45 ; PT4901.2 39.25,197.45 ; PT4901.2 40.2,198.4 ; PT4506.2 60.55,31.43 ; PT4506.2 60.55,29.53 ; PT4506.2 61.5,30.48 ; PT4506.2 59.6,30.48 ; SATA3.7 136.06,200.4 ; SATA3.7 135.31,201.15 ; SATA3.7 134.56,200.4 ; SATA3.7 135.31,199.65 ; 164.85,63.94 SLOT1.B18 ; SLOT1.B18 165.65,63.14 ; SLOT1.B18 165.65,64.74 ; SLOT1.B18 166.45,63.94 ; 181.84,178 SATA2.8 182.98,176.86 ; 162.85,58.94 SLOT1.B13 ; SLOT1.B13 163.65,59.74 ; SLOT1.B13 164.45,58.94 ; SATA1.7 115.31,201.15 ; SATA1.7 115.31,199.65 ; SATA1.7 114.56,200.4 ; SATA1.7 116.06,200.4 ; 131.5,199.65 SATA3.4 ; SATA3.4 130.75,200.4 ; SATA3.4 131.5,201.15 ; SATA3.4 132.25,200.4 ; 126.94,200.4 SATA3.1 ; SATA3.1 128.44,200.4 ; SATA3.1 127.69,199.65 ; SATA3.1 127.69,201.15 ; USB2R1.10 96.18,9.19 ; USB2R1.10 92.96,9.19 ; USB2R1.10 94.57,10.8 ; USB2R1.10 94.57,7.58 ; 111.5,199.65 SATA1.4 ; SATA1.4 111.5,201.15 ; SATA1.4 110.75,200.4 ; SATA1.4 112.25,200.4 ; 65.98,63.37 PT4505.2 ; PT4505.2 66.93,64.33 ; PT4505.2 66.93,62.42 ; PT4505.2 67.88,63.37 ; 37.9,2.92 VGA1.8 37.9,4.88 ; 73.18,9.25 HDMI1.20 ; HDMI1.20 75.32,9.25 ; HDMI1.20 74.25,7.43 ; HDMI1.20 74.25,11.07 ; SLOT1.A12 159.95,57.94 ; SLOT1.A12 159.15,57.14 ; SLOT1.A12 159.15,58.74 ; 109.47,39.81 109.47,40.77 ; 109.47,40.77 108.52,40.77 ; 109.47,40.77 110.43,40.77 ; 109.47,40.77 109.47,41.72 ; PT4507.2 75.23,64.3 ; PT4507.2 75.23,62.39 ; PT4507.2 76.19,63.35 ; PT4507.2 74.28,63.35 ; 17.12,232.07 PWRSW1.4 17.8,231.86 ; 42.47,2.92 VGA1.6 ; VGA1.6 42.47,4.88 ; VGA1.6 43.45,3.9 ; 125.21,199.22 SATA3.8 ; SATA3.8 126.39,200.4 ; SATA3.8 125.21,201.58 ; SATA3.8 124.03,200.4 ; 172.69,177.69 SATA2.7 171.88,178.5 ; 163.65,50.14 SLOT1.B7 163.03,50.32 ; 104.03,200.4 SATA1.8 ; SATA1.8 105.21,201.58 ; SATA1.8 105.21,199.22 ; SATA1.8 106.39,200.4 ; SLOT1.A1 161.15,45.74 ; SLOT1.A1 160.35,44.94 ; SLOT1.A1 161.95,44.94 ; HS1902.1 170.6,99.01 ; HS1902.1 171.55,98.06 ; HS1902.1 169.65,98.06 ; SLOT1.A15 161.95,60.94 ; SLOT1.A15 160.35,60.94 ; SLOT1.A15 161.15,61.74 ; SLOT1.A15 161.15,60.14 ; 181.12,178.5 SATA2.1 180.31,177.69 ; USB2R1.11 83.04,14.87 ; USB2R1.11 81.43,13.26 ; USB2R1.11 81.43,16.48 ; USB2R1.11 79.82,14.87 ; VGA1.17 51.55,3.9 ; VGA1.17 47.44,3.9 ; VGA1.17 49.49,5.96 ; VGA1.17 49.49,1.84 ; 82.64,33.99 PT4504.2 ; PT4504.2 84.54,33.99 ; PT4504.2 83.59,33.03 ; PT4504.2 83.59,34.94 ; PT4702.2 110.48,48.72 ; PT4702.2 109.52,49.67 ; PT4702.2 108.57,48.72 ; 40.18,2.92 VGA1.7 40.18,4.88
  BOTTOM w0.102: 136.12,170.38 136.12,170.38 127.48,170.38 127.25,170.6
  BOTTOM w0.127: v3(140.69,170.14) 140.14,169.6 140.14,168.53 140.34,168.34 140.34,167.87 ; 147.7,120.22 148.16,119.68 ; 149.05,161.7 149.05,161.79 149.14,161.88 149.14,162.27 149.05,162.36 149.05,162.46
  BOTTOM w0.152: 102.27,45.12 102.84,45.69 102.84,46.48 v3(101.79,47.54)
  BOTTOM w0.203: v1(151.12,114.78) 151.14,114.81 151.14,115.1 v1(149.77,116.46) 149.77,116.89 149.57,117.1 149.55,117.1 v1(149.55,117.1) ; v1(151.12,113.36) 151.12,112.63 150.34,111.86 150.34,108.13 148.77,106.55 v3(148.56,106.55)
  BOTTOM w0.254: PT4501.2 73.51,32.66 87.68,32.66 90.08,35.06 92.21,35.06 102.27,45.12 ; v1(149.55,117.1) 149.53,117.08 149.53,116.9 148.88,116.25 148.88,115.05 v3(149.33,114.6) 149.69,114.24 149.69,113.03 149.2,112.55 149.2,111.33 147.45,109.58 147.45,109.27 145.92,107.75 145.92,106.59 v3(145.97,106.54) 146.16,106.35 148.36,106.35 v3(148.56,106.55) ; v1(151.12,114.78) v1(151.12,113.36)
  BOTTOM w0.508: DIMM2.15 25.36,163.4 ; DIMM2.15 24.6,164.16 ; DIMM2.15 24.6,162.64 ; DIMM2.15 23.84,163.4 ; DIMM2.107 107.9,164.16 ; DIMM2.107 108.66,163.4 ; DIMM2.107 107.14,163.4 ; DIMM2.107 107.9,162.64 ; DIMM1.48 53.41,157.4 ; DIMM1.48 51.89,157.4 ; DIMM1.48 52.65,156.64 ; DIMM1.48 52.65,158.16 ; DIMM2.149 16.86,167.2 ; DIMM2.149 16.1,167.96 ; DIMM2.149 15.34,167.2 ; DIMM2.149 16.1,166.44 ; 126.69,161.2 DIMM1.274 ; DIMM1.274 127.45,160.44 ; DIMM1.274 127.45,161.96 ; DIMM1.274 128.21,161.2 ; 39.99,161.2 DIMM1.178 ; DIMM1.178 40.75,160.44 ; DIMM1.178 40.75,161.96 ; DIMM1.178 41.51,161.2 ; 43.3,162.64 DIMM2.37 ; DIMM2.37 44.06,163.4 ; DIMM2.37 42.54,163.4 ; DIMM2.37 43.3,164.16 ; DIMM2.147 14.4,167.96 ; DIMM2.147 15.16,167.2 ; DIMM2.147 13.64,167.2 ; DIMM2.147 14.4,166.44 ; DIMM1.283 135.1,160.36 ; DIMM1.283 135.1,158.84 ; DIMM1.283 134.34,159.6 ; DIMM2.252 109.51,168.8 ; DIMM2.252 107.99,168.8 ; DIMM2.252 108.75,168.04 ; DIMM2.252 108.75,169.56 ; 34.8,158.84 DIMM1.171 ; DIMM1.171 34.04,159.6 ; DIMM1.171 34.8,160.36 ; DIMM1.171 35.56,159.6 ; DIMM1.31 38.96,155.8 ; DIMM1.31 37.44,155.8 ; DIMM1.31 38.2,155.04 ; DIMM1.31 38.2,156.56 ; 113.94,167.2 DIMM2.259 ; DIMM2.259 114.7,167.96 ; DIMM2.259 114.7,166.14 114.68,166.12 ; DIMM2.259 115.46,167.2 ; DIMM2.189 50.1,166.18 ; DIMM2.189 50.1,167.96 ; DIMM2.189 49.34,167.2 ; DIMM2.189 50.86,167.2 ; 131.7,158.84 DIMM1.279 ; DIMM1.279 132.46,159.6 ; DIMM1.279 130.94,159.6 ; DIMM1.279 131.7,160.36 ; 57.84,163.4 DIMM2.55 ; DIMM2.55 59.36,163.4 ; DIMM2.55 58.6,164.16 ; DIMM2.55 58.6,162.64 ; 33.95,156.64 DIMM1.26 ; DIMM1.26 33.95,158.16 ; DIMM1.26 34.71,157.4 ; DIMM1.26 33.19,157.4 ; DIMM1.189 50.86,159.6 ; DIMM1.189 50.1,158.84 ; DIMM1.189 50.1,160.36 ; DIMM1.189 49.34,159.6 ; DIMM1.250 107.05,161.96 ; DIMM1.250 107.05,160.44 ; DIMM1.250 106.29,161.2 ; DIMM1.250 107.81,161.2 ; DIMM1.112 112.15,158.16 ; DIMM1.112 111.39,157.4 ; DIMM1.112 112.15,156.64 ; DIMM1.112 112.91,157.4 ; 130.09,165 DIMM2.134 ; DIMM2.134 130.85,165.76 ; DIMM2.134 131.61,165 ; DIMM2.134 130.85,164.24 ; 44.24,155.8 DIMM1.39 ; DIMM1.39 45.76,155.8 ; DIMM1.39 45,155.04 ; DIMM1.39 45,156.56 ; DIMM2.176 39.05,169.56 ; DIMM2.176 38.29,168.8 ; DIMM2.176 39.05,168.04 ; DIMM2.176 39.81,168.8 ; 47.64,159.6 DIMM1.187 ; DIMM1.187 49.16,159.6 ; DIMM1.187 48.4,160.36 ; DIMM1.187 48.4,158.84 ; DIMM1.125 123.2,156.56 ; DIMM1.125 122.44,155.8 ; DIMM1.125 123.96,155.8 ; DIMM1.125 123.2,155.04 ; DIMM1.17 27.06,155.8 ; DIMM1.17 26.3,156.56 ; DIMM1.17 25.54,155.8 ; DIMM1.17 26.3,155.04 ; DIMM1.6 17.71,157.4 ; DIMM1.6 16.95,158.16 ; DIMM1.6 16.95,156.64 ; DIMM1.6 16.19,157.4 ; DIMM2.96 98.55,165.76 ; DIMM2.96 98.55,164.24 ; DIMM2.96 99.31,165 ; DIMM2.96 97.79,165 ; 114.7,158.84 DIMM1.259 ; DIMM1.259 115.46,159.6 ; DIMM1.259 114.7,160.36 ; DIMM1.259 113.94,159.6 ; 97.7,166.44 DIMM2.239 ; DIMM2.239 97.7,167.96 ; DIMM2.239 98.46,167.2 ; DIMM2.239 96.94,167.2 ; DIMM2.241 99.4,167.96 ; DIMM2.241 99.4,166.44 ; DIMM2.241 98.64,167.2 ; DIMM2.241 100.16,167.2 ; 28.09,157.4 DIMM1.20 ; DIMM1.20 28.85,158.16 ; DIMM1.20 28.85,156.64 ; DIMM1.20 29.61,157.4 ; DIMM2.57 60.3,164.16 ; DIMM2.57 60.3,162.64 ; DIMM2.57 61.06,163.4 ; DIMM2.57 59.54,163.4 ; DIMM1.200 60.21,161.2 ; DIMM1.200 59.45,161.96 ; DIMM1.200 58.69,161.2 ; DIMM1.200 59.45,160.44 ; 128.02,162.31 128.3,162.59 DIMM2.131 ; 56.9,155.04 DIMM1.53 ; DIMM1.53 57.66,155.8 ; DIMM1.53 56.9,156.56 ; DIMM1.53 56.14,155.8 ; 39.9,162.64 DIMM2.33 ; DIMM2.33 39.14,163.4 ; DIMM2.33 40.66,163.4 ; DIMM2.33 39.9,164.16 ; DIMM1.257 113.76,159.6 ; DIMM1.257 112.24,159.6 ; DIMM1.257 113,158.84 ; DIMM1.257 113,160.36 ; DIMM1.116 116.31,157.4 ; DIMM1.116 115.55,158.16 ; DIMM1.116 115.55,156.64 ; DIMM1.116 114.79,157.4 ; 102.89,168.8 DIMM2.246 ; DIMM2.246 103.65,168.04 ; DIMM2.246 104.41,168.8 ; DIMM2.246 103.65,169.56 ; DIMM2.261 117.16,167.2 ; DIMM2.261 115.64,167.2 ; DIMM2.261 116.4,167.96 ; DIMM2.261 116.4,165.92 116.46,165.86 ; DIMM1.147 14.4,160.36 ; DIMM1.147 13.64,159.6 ; DIMM1.147 14.4,158.84 ; DIMM1.147 15.16,159.6 ; 57.75,160.44 DIMM1.198 ; DIMM1.198 58.51,161.2 ; DIMM1.198 56.99,161.2 ; DIMM1.198 57.75,161.96 ; DIMM2.11 21.2,164.16 ; DIMM2.11 21.2,162.64 ; DIMM2.11 20.44,163.4 ; DIMM2.11 21.96,163.4 ; DIMM2.160 25.45,169.56 ; DIMM2.160 26.21,168.8 ; DIMM2.160 25.45,168.04 ; DIMM2.160 24.69,168.8 ; DIMM2.109 109.6,164.16 ; DIMM2.109 108.84,163.4 ; DIMM2.109 109.6,162.64 ; DIMM2.109 110.36,163.4 ; DIMM1.35 42.36,155.8 ; DIMM1.35 41.6,155.04 ; DIMM1.35 41.6,156.56 ; DIMM1.35 40.84,155.8 ; 135.1,166.44 DIMM2.283 ; DIMM2.283 135.1,167.96 ; DIMM2.283 134.34,167.2 ; DIMM1.98 101.01,157.4 ; DIMM1.98 100.25,156.64 ; DIMM1.98 99.49,157.4 ; DIMM1.98 100.25,158.16 ; 113,166.44 DIMM2.257 ; DIMM2.257 113.76,167.2 ; DIMM2.257 113,167.96 ; DIMM2.257 112.24,167.2 ; 30.64,167.2 DIMM2.167 ; DIMM2.167 31.4,166.44 ; DIMM2.167 32.16,167.2 ; DIMM2.167 31.4,167.96 ; 117.34,167.2 DIMM2.263 ; DIMM2.263 118.1,167.96 ; DIMM2.263 118.1,166.25 118.11,166.24 ; DIMM2.263 118.86,167.2 ; DIMM1.165 30.46,159.6 ; DIMM1.165 29.7,160.36 ; DIMM1.165 29.7,158.84 ; DIMM1.165 28.94,159.6 ; DIMM2.101 102.8,164.16 ; DIMM2.101 103.56,163.4 ; DIMM2.101 102.8,162.64 ; DIMM2.101 102.04,163.4 ; 26.3,162.64 DIMM2.17 ; DIMM2.17 26.3,164.16 ; DIMM2.17 27.06,163.4 ; DIMM2.17 25.54,163.4 ; DIMM2.42 48.31,165 ; DIMM2.42 47.55,165.76 ; DIMM2.42 46.79,165 ; DIMM2.42 47.55,164.24 ; DIMM2.270 124.05,169.56 ; DIMM2.270 124.05,168.04 ; DIMM2.270 124.81,168.8 ; DIMM2.270 123.29,168.8 ; DIMM2.195 55.96,167.2 ; DIMM2.195 55.2,167.96 ; DIMM2.195 54.44,167.2 ; DIMM2.195 55.2,166.44 ; DIMM1.254 110.45,161.96 ; DIMM1.254 111.21,161.2 ; DIMM1.254 110.45,160.44 ; DIMM1.254 109.69,161.2 ; 19.5,162.64 DIMM2.9 ; DIMM2.9 18.74,163.4 ; DIMM2.9 19.5,164.16 ; DIMM2.9 20.26,163.4 ; DIMM1.37 44.06,155.8 ; DIMM1.37 42.54,155.8 ; DIMM1.37 43.3,155.04 ; DIMM1.37 43.3,156.56 ; 22.05,160.44 DIMM1.156 ; DIMM1.156 21.29,161.2 ; DIMM1.156 22.05,161.96 ; DIMM1.156 22.81,161.2 ; 19.59,168.8 DIMM2.154 ; DIMM2.154 21.11,168.8 ; DIMM2.154 20.35,169.56 ; DIMM2.154 20.35,168.04 ; DIMM2.154 20.32,167.87 ; 14.49,165 DIMM2.4 ; DIMM2.4 16.01,165 ; DIMM2.4 15.25,164.24 ; DIMM2.4 15.25,165.76 ; 124.99,161.2 DIMM1.272 ; DIMM1.272 126.51,161.2 ; DIMM1.272 125.75,161.96 ; DIMM1.272 125.75,160.44 ; DIMM1.15 24.6,156.56 ; DIMM1.15 25.36,155.8 ; DIMM1.15 24.6,155.04 ; DIMM1.15 23.84,155.8 ; DIMM1.149 16.1,160.36 ; DIMM1.149 15.34,159.6 ; DIMM1.149 16.86,159.6 ; DIMM1.149 16.1,158.84 ; DIMM1.176 39.81,161.2 ; DIMM1.176 39.05,160.44 ; DIMM1.176 38.29,161.2 ; DIMM1.176 39.05,161.96 ; 50.19,165 DIMM2.46 ; DIMM2.46 50.95,165.76 ; DIMM2.46 51.71,165 ; DIMM2.46 50.95,164.24 ; DIMM2.191 52.56,167.2 ; DIMM2.191 51.8,166.44 ; DIMM2.191 51.04,167.2 ; DIMM2.191 51.8,167.96 ; DIMM1.193 53.5,160.36 ; DIMM1.193 54.26,159.6 ; DIMM1.193 52.74,159.6 ; DIMM1.193 53.5,158.84 ; 122.35,160.44 DIMM1.268 ; DIMM1.268 121.59,161.2 ; DIMM1.268 123.11,161.2 ; DIMM1.268 122.35,161.96 ; DIMM2.165 30.46,167.2 ; DIMM2.165 29.7,166.44 ; DIMM2.165 29.7,167.96 ; DIMM2.165 28.94,167.2 ; DIMM1.182 44.91,161.2 ; DIMM1.182 44.15,161.96 ; DIMM1.182 43.39,161.2 ; DIMM1.182 44.15,160.44 ; 121.5,155.04 DIMM1.123 ; DIMM1.123 121.5,156.56 ; DIMM1.123 122.26,155.8 ; DIMM1.123 120.74,155.8 ; 129.92,161.93 129.2,161.2 DIMM1.276 ; 132.64,167.2 DIMM2.281 ; DIMM2.281 133.4,166.44 ; DIMM2.281 134.16,167.2 ; DIMM2.281 133.4,167.96 ; DIMM1.169 33.86,159.6 ; DIMM1.169 33.1,160.36 ; DIMM1.169 32.34,159.6 ; DIMM1.169 33.1,158.84 ; 112.15,164.24 DIMM2.112 ; DIMM2.112 112.15,165.76 ; DIMM2.112 111.39,165 ; DIMM2.112 112.91,165 ; 96.09,165 DIMM2.94 ; DIMM2.94 97.61,165 ; DIMM2.94 96.85,165.76 ; DIMM2.94 96.85,164.24 ; 116.49,165 DIMM2.118 ; DIMM2.118 117.25,165.76 ; DIMM2.118 118.01,165 ; DIMM2.118 117.25,164.24 ; 34.04,167.2 DIMM2.171 ; DIMM2.171 34.8,167.96 ; DIMM2.171 35.56,167.2 ; DIMM2.171 34.8,166.44 ; 122.35,168.04 DIMM2.268 ; DIMM2.268 121.59,168.8 ; DIMM2.268 122.35,169.56 ; DIMM2.268 123.11,168.8 ; 113.85,164.24 DIMM2.114 ; DIMM2.114 113.85,165.76 ; DIMM2.114 114.61,165 ; DIMM2.114 113.09,165 ; 22.9,162.64 DIMM2.13 ; DIMM2.13 22.14,163.4 ; DIMM2.13 23.66,163.4 ; DIMM2.13 22.9,164.16 ; 51.8,158.84 DIMM1.191 ; DIMM1.191 51.8,160.36 ; DIMM1.191 51.04,159.6 ; DIMM1.191 52.56,159.6 ; 118.19,165 DIMM2.120 ; DIMM2.120 118.95,165.76 ; DIMM2.120 118.95,164.24 ; DIMM2.120 119.71,165 ; 124.05,160.44 DIMM1.270 ; DIMM1.270 123.29,161.2 ; DIMM1.270 124.05,161.96 ; DIMM1.270 124.81,161.2 ; DIMM2.254 110.45,169.56 ; DIMM2.254 110.45,168.04 ; DIMM2.254 111.21,168.8 ; DIMM2.254 109.69,168.8 ; 134.25,164.24 DIMM2.138 ; DIMM2.138 134.25,165.76 ; DIMM2.138 135.01,165 ; DIMM2.138 133.49,165 ; DIMM2.116 115.55,165.76 ; DIMM2.116 115.55,164.24 ; DIMM2.116 116.31,165 ; DIMM2.116 114.79,165 ; 107.99,161.2 DIMM1.252 ; DIMM1.252 108.75,161.96 ; DIMM1.252 109.51,161.2 ; DIMM1.252 108.75,160.44 ; DIMM1.173 37.26,159.6 ; DIMM1.173 36.5,160.36 ; DIMM1.173 36.5,158.84 ; DIMM1.173 35.74,159.6 ; USB3F2.10 113.62,276.52 ; USB3F2.10 112.6,274.75 ; USB3F2.10 114.64,274.75 ; 100.25,164.24 DIMM2.98 ; DIMM2.98 100.25,165.76 ; DIMM2.98 99.49,165 ; DIMM2.98 101.01,165 ; DIMM2.265 120.56,167.2 ; DIMM2.265 119.8,167.96 ; DIMM2.265 119.04,167.2 ; DIMM2.265 119.8,166.44 ; DIMM2.127 125.66,163.4 ; DIMM2.127 124.14,163.4 ; DIMM2.127 124.9,164.16 ; DIMM2.127 124.9,162.64 ; 16.19,165 DIMM2.6 ; DIMM2.6 17.71,165 ; DIMM2.6 16.95,165.76 ; DIMM2.6 16.95,164.24 ; 129.15,168.04 DIMM2.276 ; DIMM2.276 128.39,168.8 ; DIMM2.276 129.91,168.8 ; DIMM2.276 129.15,169.56 ; 35.74,167.2 DIMM2.173 ; DIMM2.173 36.5,166.44 ; DIMM2.173 37.26,167.2 ; DIMM2.173 36.5,167.96 ; DIMM2.35 41.6,164.16 ; DIMM2.35 41.6,162.64 ; DIMM2.35 42.36,163.4 ; DIMM2.35 40.84,163.4 ; 27.15,168.04 DIMM2.162 ; DIMM2.162 26.39,168.8 ; DIMM2.162 27.91,168.8 ; DIMM2.162 27.15,169.56 ; DIMM2.105 106.2,164.16 ; DIMM2.105 105.44,163.4 ; DIMM2.105 106.96,163.4 ; DIMM2.105 106.2,162.64 ; DIMM2.103 105.26,163.4 ; DIMM2.103 104.5,162.64 ; DIMM2.103 103.74,163.4 ; DIMM2.103 104.5,164.16 ; DIMM1.151 17.8,160.36 ; DIMM1.151 18.56,159.6 ; DIMM1.151 17.8,158.84 ; DIMM1.151 17.04,159.6 ; DIMM1.136 133.31,157.4 ; DIMM1.136 132.55,156.64 ; DIMM1.136 132.55,158.16 ; DIMM1.136 131.79,157.4 ; DIMM1.139 135.86,155.8 ; DIMM1.139 135.1,156.56 ; DIMM1.139 135.1,155.04 ; DIMM1.139 134.34,155.8 ; 118.19,157.4 DIMM1.120 ; DIMM1.120 119.71,157.4 ; DIMM1.120 118.95,158.16 ; DIMM1.120 118.95,156.64 ; 91.62,272.98 USB3F1.10 ; USB3F1.10 90.6,274.75 ; USB3F1.10 91.62,276.52 ; USB3F1.10 92.64,274.75 ; DIMM2.136 132.55,165.76 ; DIMM2.136 132.55,164.24 ; DIMM2.136 131.79,165 ; DIMM2.136 133.31,165 ; 21.2,155.04 DIMM1.11 ; DIMM1.11 21.96,155.8 ; DIMM1.11 21.2,156.56 ; DIMM1.11 20.44,155.8 ; DIMM1.246 104.41,161.2 ; DIMM1.246 103.65,160.44 ; DIMM1.246 102.89,161.2 ; DIMM1.246 103.65,161.96 ; DIMM2.20 29.61,165 ; DIMM2.20 28.09,165 ; DIMM2.20 28.85,164.24 ; DIMM2.20 28.85,165.76 ; 122.44,163.4 DIMM2.125 ; DIMM2.125 123.2,162.64 ; DIMM2.125 123.2,164.16 ; DIMM2.125 123.96,163.4 ; 128.39,161.2 DIMM1.276 ; DIMM1.276 129.15,160.44 ; DIMM1.107 107.9,156.56 ; DIMM1.107 107.14,155.8 ; DIMM1.107 108.66,155.8 ; DIMM1.107 107.9,155.04 ; 37.44,163.4 DIMM2.31 ; DIMM2.31 38.96,163.4 ; DIMM2.31 38.2,164.16 ; DIMM2.31 38.2,162.64 ; R9938.2 35.31,219.99 35.95,219.34 v3(36.02,219.34) ; DIMM2.22 31.31,165 ; DIMM2.22 30.55,164.24 ; DIMM2.22 30.55,165.76 ; DIMM2.22 29.79,165 ; DIMM1.134 131.61,157.4 ; DIMM1.134 130.85,158.16 ; DIMM1.134 130.85,156.64 ; DIMM1.134 130.09,157.4 ; DIMM1.46 51.71,157.4 ; DIMM1.46 50.95,156.64 ; DIMM1.46 50.95,158.16 ; DIMM1.46 50.19,157.4 ; 107.05,168.04 DIMM2.250 ; DIMM2.250 106.29,168.8 ; DIMM2.250 107.81,168.8 ; DIMM2.250 107.05,169.56 ; DIMM1.180 42.45,161.96 ; DIMM1.180 42.45,160.44 ; DIMM1.180 41.69,161.2 ; DIMM1.180 43.21,161.2 ; 100.34,167.2 DIMM2.243 ; DIMM2.243 101.1,167.96 ; DIMM2.243 101.86,167.2 ; DIMM2.243 101.1,166.44 ; 108.84,155.8 DIMM1.109 ; DIMM1.109 109.6,155.04 ; DIMM1.109 110.36,155.8 ; DIMM1.109 109.6,156.56 ; DIMM2.50 54.35,165.76 ; DIMM2.50 55.11,165 ; DIMM2.50 54.35,164.24 ; DIMM2.50 53.59,165 ; 105.35,160.44 DIMM1.248 ; DIMM1.248 106.11,161.2 ; DIMM1.248 105.35,161.96 ; DIMM1.248 104.59,161.2 ; 52.65,164.24 DIMM2.48 ; DIMM2.48 51.89,165 ; DIMM2.48 53.41,165 ; DIMM2.48 52.65,165.76 ; DIMM1.33 40.66,155.8 ; DIMM1.33 39.9,156.56 ; DIMM1.33 39.9,155.04 ; DIMM1.33 39.14,155.8 ; DIMM1.28 35.65,158.16 ; DIMM1.28 34.89,157.4 ; DIMM1.28 36.41,157.4 ; DIMM1.28 35.65,156.64 ; DIMM2.187 49.16,167.2 ; DIMM2.187 47.64,167.2 ; DIMM2.187 48.4,167.96 ; DIMM2.187 48.4,166.44 ; DIMM1.118 118.01,157.4 ; DIMM1.118 117.25,156.64 ; DIMM1.118 116.49,157.4 ; DIMM1.118 117.25,158.16 ; DIMM1.162 27.91,161.2 ; DIMM1.162 27.94,162.05 ; DIMM1.162 27.15,160.44 ; DIMM1.162 26.39,161.2 ; 124.14,155.8 DIMM1.127 ; DIMM1.127 124.9,156.56 ; DIMM1.127 125.66,155.8 ; DIMM1.127 124.9,155.04 ; 101.1,158.84 DIMM1.243 ; DIMM1.243 101.86,159.6 ; DIMM1.243 100.34,159.6 ; DIMM1.243 101.1,160.36 ; DIMM1.42 48.31,157.4 ; DIMM1.42 47.55,158.16 ; DIMM1.42 46.79,157.4 ; DIMM1.42 47.55,156.64 ; DIMM1.44 49.25,158.16 ; DIMM1.44 50.01,157.4 ; DIMM1.44 49.25,156.64 ; DIMM1.44 48.49,157.4 ; 77.8,274.75 USB3F1.11 ; USB3F1.11 78.82,276.52 ; USB3F1.11 78.82,272.98 ; USB3F1.11 79.84,274.75 ; DIMM1.22 31.31,157.4 ; DIMM1.22 30.55,158.16 ; DIMM1.22 29.79,157.4 ; DIMM1.22 30.55,156.64 ; 40.75,168.04 DIMM2.178 ; DIMM2.178 40.75,169.56 ; DIMM2.178 41.51,168.8 ; DIMM2.178 39.99,168.8 ; 22.9,155.04 DIMM1.13 ; DIMM1.13 23.66,155.8 ; DIMM1.13 22.14,155.8 ; DIMM1.13 22.9,156.56 ; 134.25,156.64 DIMM1.138 ; DIMM1.138 135.01,157.4 ; DIMM1.138 134.25,158.16 ; DIMM1.138 133.49,157.4 ; 17.8,166.44 DIMM2.151 ; DIMM2.151 17.04,167.2 ; DIMM2.151 17.8,167.96 ; DIMM2.151 18.56,167.2 ; 48.49,165 DIMM2.44 ; DIMM2.44 49.25,164.24 ; DIMM2.44 49.25,165.76 ; DIMM2.44 50.01,165 ; 22.99,168.8 DIMM2.158 ; DIMM2.158 23.75,168.04 ; DIMM2.158 24.51,168.8 ; DIMM2.158 23.75,169.56 ; DIMM2.123 122.26,163.4 ; DIMM2.123 120.74,163.4 ; DIMM2.123 121.5,162.64 ; DIMM2.123 121.5,164.16 ; DIMM2.26 33.95,165.76 ; DIMM2.26 33.19,165 ; DIMM2.26 33.95,164.24 ; DIMM2.26 34.71,165 ; 96.85,168.04 DIMM2.238 ; DIMM2.238 96.85,169.56 ; DIMM2.238 96.09,168.8 ; 127.54,155.8 DIMM1.131 ; DIMM1.131 128.3,156.56 ; DIMM1.131 128.3,155.04 ; DIMM1.131 129.06,155.8 ; 126.69,168.8 DIMM2.274 ; DIMM2.274 127.45,168.04 ; DIMM2.274 128.21,168.8 ; DIMM2.274 127.45,169.56 ; DIMM1.9 19.5,156.56 ; DIMM1.9 19.5,155.04 ; DIMM1.9 18.74,155.8 ; DIMM1.9 20.26,155.8 ; DIMM1.96 99.31,157.4 ; DIMM1.96 98.55,156.64 ; DIMM1.96 98.55,158.16 ; DIMM1.96 97.79,157.4 ; DIMM2.193 53.5,167.96 ; DIMM2.193 52.74,167.2 ; DIMM2.193 53.5,166.44 ; DIMM2.193 54.26,167.2 ; DIMM2.2 14.31,165 ; DIMM2.2 12.79,165 ; DIMM2.2 13.55,164.24 ; DIMM2.2 13.55,165.76 ; 32.25,156.64 DIMM1.24 ; DIMM1.24 33.01,157.4 ; DIMM1.24 32.25,158.16 ; DIMM1.24 31.49,157.4 ; 130.94,167.2 DIMM2.279 ; DIMM2.279 132.46,167.2 ; DIMM2.279 131.7,167.96 ; DIMM2.279 131.7,166.44 ; 60.3,155.04 DIMM1.57 ; DIMM1.57 61.06,155.8 ; DIMM1.57 60.3,156.56 ; DIMM1.57 59.54,155.8 ; DIMM1.261 116.4,160.36 ; DIMM1.261 115.64,159.6 ; DIMM1.261 117.16,159.6 ; DIMM1.261 116.4,158.84 ; DIMM2.39 45.76,163.4 ; DIMM2.39 44.24,163.4 ; DIMM2.39 45,164.3 ; R902.1 87.12,86.45 v1(87.12,85.62) ; DIMM1.103 104.5,156.56 ; DIMM1.103 105.26,155.8 ; DIMM1.103 104.5,155.04 ; DIMM1.103 103.74,155.8 ; DIMM1.281 133.4,160.36 ; DIMM1.281 133.4,158.84 ; DIMM1.281 134.16,159.6 ; DIMM1.281 132.64,159.6 ; 58.69,168.8 DIMM2.200 ; DIMM2.200 59.45,168.04 ; DIMM2.200 59.45,169.56 ; DIMM2.200 60.21,168.8 ; DIMM1.154 21.11,161.2 ; DIMM1.154 20.35,160.44 ; DIMM1.154 20.35,161.96 ; DIMM1.154 19.59,161.2 ; 32.34,167.2 DIMM2.169 ; DIMM2.169 33.86,167.2 ; DIMM2.169 33.1,167.96 ; DIMM2.169 33.1,166.44 ; 56.9,162.64 DIMM2.53 ; DIMM2.53 56.14,163.4 ; DIMM2.53 57.66,163.4 ; DIMM2.53 56.9,164.16 ; DIMM1.263 118.86,159.6 ; DIMM1.263 118.1,158.84 ; DIMM1.263 118.1,160.36 ; DIMM1.263 117.34,159.6 ; DIMM1.202 61.15,161.96 ; DIMM1.202 60.39,161.2 ; DIMM1.202 61.91,161.2 ; DIMM1.202 61.15,160.44 ; 58.6,155.04 DIMM1.55 ; DIMM1.55 59.36,155.8 ; DIMM1.55 57.84,155.8 ; DIMM1.55 58.6,156.56 ; DIMM2.248 105.35,169.56 ; DIMM2.248 106.11,168.8 ; DIMM2.248 104.59,168.8 ; DIMM2.248 105.35,168.04 ; DIMM1.167 32.16,159.6 ; DIMM1.167 31.4,160.36 ; DIMM1.167 30.64,159.6 ; DIMM1.167 31.4,158.84 ; 128.27,164.34 128.3,164.31 DIMM2.131 ; 135.19,157.4 DIMM1.140 ; DIMM1.140 135.95,158.16 ; DIMM1.140 135.95,156.64 ; v1(40.18,226.29) 40.4,226.5 R9939.2 ; 98.64,159.6 DIMM1.241 ; DIMM1.241 100.16,159.6 ; DIMM1.241 99.4,160.36 ; DIMM1.241 99.4,158.84 ; 96.85,156.64 DIMM1.94 ; DIMM1.94 97.61,157.4 ; DIMM1.94 96.85,158.16 ; DIMM1.94 96.09,157.4 ; 44.15,168.04 DIMM2.182 ; DIMM2.182 43.39,168.8 ; DIMM2.182 44.91,168.8 ; DIMM2.182 44.15,169.56 ; DIMM1.238 96.85,161.96 ; DIMM1.238 96.85,160.44 ; DIMM1.238 97.61,161.2 ; DIMM1.238 96.09,161.2 ; 45.85,168.04 DIMM2.184 ; DIMM2.184 46.61,168.8 ; DIMM2.184 45.85,169.56 ; DIMM2.184 45.09,168.8 ; 31.49,165 DIMM2.24 ; DIMM2.24 33.01,165 ; DIMM2.24 32.25,165.76 ; DIMM2.24 32.25,164.24 ; DIMM1.2 13.55,158.16 ; DIMM1.2 14.31,157.4 ; DIMM1.2 13.55,156.64 ; DIMM1.2 12.79,157.4 ; 15.25,156.64 DIMM1.4 ; DIMM1.4 14.49,157.4 ; DIMM1.4 16.01,157.4 ; DIMM1.4 15.25,158.16 ; 102.8,155.04 DIMM1.101 ; DIMM1.101 102.04,155.8 ; DIMM1.101 102.8,156.56 ; DIMM1.101 103.56,155.8 ; 119.8,158.84 DIMM1.265 ; DIMM1.265 120.56,159.6 ; DIMM1.265 119.04,159.6 ; DIMM1.265 119.8,160.36 ; DIMM2.28 36.41,165 ; DIMM2.28 34.89,165 ; DIMM2.28 35.65,165.76 ; DIMM2.28 35.65,164.24 ; DIMM2.272 125.75,169.56 ; DIMM2.272 124.99,168.8 ; DIMM2.272 125.75,168.04 ; DIMM2.272 126.51,168.8 ; 96.94,159.6 DIMM1.239 ; DIMM1.239 97.7,158.84 ; DIMM1.239 97.7,160.36 ; DIMM1.239 98.46,159.6 ; DIMM1.184 46.61,161.2 ; DIMM1.184 45.09,161.2 ; DIMM1.184 45.85,160.44 ; DIMM1.184 46.23,162.18 ; DIMM2.180 42.45,169.56 ; DIMM2.180 42.45,168.04 ; DIMM2.180 43.21,168.8 ; DIMM2.180 41.69,168.8 ; 57.75,168.04 DIMM2.198 ; DIMM2.198 56.99,168.8 ; DIMM2.198 58.51,168.8 ; DIMM2.198 57.75,169.56 ; DIMM2.202 61.91,168.8 ; DIMM2.202 61.15,168.04 ; DIMM2.202 61.15,169.56 ; DIMM2.202 60.39,168.8 ; 100.82,272.98 USB3F2.11 ; USB3F2.11 100.82,276.52 ; USB3F2.11 99.8,274.75 ; USB3F2.11 101.84,274.75 ; 53.59,157.4 DIMM1.50 ; DIMM1.50 54.35,156.64 ; DIMM1.50 54.35,158.16 ; DIMM1.50 55.11,157.4 ; DIMM1.105 106.2,156.56 ; DIMM1.105 105.44,155.8 ; DIMM1.105 106.96,155.8 ; DIMM1.105 106.2,155.04 ; 127.54,163.4 DIMM2.131 ; DIMM2.131 129.06,163.4 ; 126.6,162.64 DIMM2.129 ; DIMM2.129 127.36,163.4 ; DIMM2.129 126.6,164.16 ; DIMM2.129 125.84,163.4 ; 113.09,157.4 DIMM1.114 ; DIMM1.114 113.85,158.16 ; DIMM1.114 113.85,156.64 ; DIMM1.114 114.61,157.4 ; 24.69,161.2 DIMM1.160 ; DIMM1.160 26.21,161.2 ; DIMM1.160 25.45,160.44 ; DIMM1.160 25.45,161.96 ; 23.75,160.44 DIMM1.158 ; DIMM1.158 23.75,161.96 ; DIMM1.158 24.51,161.2 ; DIMM1.158 22.99,161.2 ; USB3F1.4 81.72,273.54 ; USB3F1.4 80.93,272.75 ; USB3F1.4 82.51,272.75 ; DIMM1.195 55.2,160.36 ; DIMM1.195 55.96,159.6 ; DIMM1.195 54.44,159.6 ; DIMM1.195 55.2,158.84 ; DIMM2.139 135.1,164.16 ; DIMM2.139 135.1,162.64 ; DIMM2.139 134.34,163.4 ; USB3F2.4 104.51,272.75 ; USB3F2.4 102.93,272.75 ; USB3F2.4 103.72,273.54 ; 126.6,155.04 DIMM1.129 ; DIMM1.129 125.84,155.8 ; DIMM1.129 126.6,156.56 ; DIMM1.129 127.36,155.8 ; DIMM2.156 22.05,169.56 ; DIMM2.156 22.81,168.8 ; DIMM2.156 21.29,168.8 ; DIMM2.156 22.05,168.04
  BOTTOM w1.016: 58.68,3.29 HDMI1.23 ; HDMI1.23 60.82,3.29 ; HDMI1.23 59.75,1.88 ; 74.25,1.88 HDMI1.22 ; HDMI1.22 75.32,3.29 ; HDMI1.22 73.18,3.29 ; VGA1.17 49.49,5.96 ; VGA1.17 49.49,1.84 ; VGA1.17 51.55,3.9 ; VGA1.17 47.44,3.9 ; 69.98,136.46 TC1101.2 ; TC1101.2 70.93,137.41 ; TC1101.2 69.98,138.37 ; TC1101.2 69.02,137.41 ; 22.45,3.9 VGA1.16 ; VGA1.16 24.5,5.96 ; VGA1.16 26.56,3.9 ; VGA1.16 24.5,1.84 ; 103.34,254 FANS1.1 ; FANS1.1 104.31,253.03 ; FANS1.1 105.28,254 ; FANS1.1 104.31,254.97 ; 79.82,14.87 USB2R1.11 ; USB2R1.11 81.43,16.48 ; USB2R1.11 81.43,13.26 ; VGA1.5 32.17,6.86 ; VGA1.5 31.19,5.88 ; VGA1.5 32.17,4.9 ; 94.57,7.58 USB2R1.10 ; USB2R1.10 96.18,9.19 ; USB2R1.10 92.96,9.19 ; 40.18,4.88 VGA1.7 40.18,2.92 ; 83.04,9.19 USB2R1.9 81.43,10.8 ; 181.12,178.5 SATA2.1 180.31,177.69 ; 181.86,177.52 SATA2.8 181.84,178 ; VGA1.6 43.45,3.9 ; VGA1.6 42.47,4.88 ; VGA1.6 42.47,2.92 ; 60.82,8.34 HDMI1.21 60.82,9.25 ; 73.18,9.25 HDMI1.20 75.32,9.25
  vias: v1(1.4,239.12) v1(1.91,188.34) v1(2.03,180.47) v1(6.96,219.38) v1(10.72,1.4) v1(11.94,78.27) v1(12.04,204.34) v1(11.96,203.4) v1(12.04,77.19) v1(12.19,75.95) v1(12.4,260.44) v1(12.4,250.28) v1(12.93,204.34) v1(12.88,203.35) v1(16.51,58.17) v1(17.12,48.9) v1(17.53,58.17) v1(18.41,60.2) v1(18.41,59.18) v1(18.44,58.17) v1(18.41,57.15) v1(18.41,56.13) v1(19.3,58.19) v1(20.35,58.19) v1(20.88,1.4) v1(31.12,281.1) v1(34.85,34.91) v1(34.96,32.6) v1(36.2,281.1) v1(37.85,259.08) v1(38.58,209.35) v1(38.73,259.97) v1(38.73,259.08) v1(38.73,258.19) v1(38.91,208.08) v1(39.55,211.2) v1(39.62,259.08) v1(40.38,225.37) v1(40.82,208.51) v1(40.97,178.49) v1(42.11,179.65) v1(42.11,178.51) v1(42.93,207.4) v1(42.95,208.58) v1(43.92,207.3) v1(43.97,208.55) v1(46.47,207.3) v1(46.69,206.15) v1(48.8,206.17) v1(50.23,204.05) v1(51.44,281.1) v1(53.04,39.23) v1(53.09,36.78) v1(55.24,19.56) v1(56.39,20.7) v1(56.39,19.56) v1(56.39,18.41) v1(57.53,19.56) v1(65.15,118.27) v1(66.42,118.88) v1(66.42,117.61) v1(67.41,102.79) v1(67.41,102.03) v1(67.44,100.84) v1(67.44,100.08) v1(67.72,118.3) v1(67.67,99.16) v1(67.67,98.37) v1(67.67,95.53) v1(67.67,94.82) v1(68.02,119.91) v1(69.8,99.19) v1(69.8,98.45) v1(69.8,95.5) v1(69.8,94.72) v1(70.36,99.71) v1(71.12,99.71) v1(71.68,1.4) v1(72.01,99.57) v1(72.03,44.06) v1(72.17,41.74) v1(79.3,282.02) v1(81.53,95.25) v1(81.53,94.49) v1(81.66,251.08) v1(84.2,74.74) v1(84.94,74.07) v1(85.36,251.25) v1(85.62,73.28) v1(86.51,72.39) v1(87.25,106.68) v1(90.07,43.16) v1(90.2,40.85) v1(90.44,251.25) v1(93.68,114.87) v1(94.57,114.07) v1(95.52,251.25) v1(96.19,92.84) v1(97.21,91.57) v1(98.63,92.71) v1(99.12,86.23) v1(99.06,79.76) v1(99.57,90.27) v1(99.69,89.15) v1(99.82,84.33) v1(101.5,79.41) v1(101.65,86.23) v1(102.35,87.2) v1(102.37,84.07) v1(103.63,248.25) v1(104.24,56.34) v1(104.65,79.22) v1(104.87,53.84) v1(105.91,80.05) v1(105.89,51.92) v1(105.97,81.46) v1(106.53,54.27) v1(106.72,76.53) v1(107.16,78.45) v1(107.16,50.18) v1(107.92,82.09) v1(108.71,248.25) v1(109.35,76.57) v1(110.37,81.41) v1(118.08,113.82) v1(119.41,115.16) v1(120.7,116.59) v1(122.4,118.16) v1(123.57,119.35) v1(124.49,120.22) v1(125.37,120.95) v1(127.2,140.69) v1(127.3,139.32) v1(127.3,137.92) v1(127.3,136.53) v1(127.3,135.13) v1(127.3,133.73) v1(127.3,132.33) v1(127.3,130.94) v1(127.3,129.54) v1(127.3,128.14) v1(127.3,126.75) v1(127.3,125.17) v1(127.38,142.11) v1(128.43,172) v1(129.41,108.37) v1(129.35,106.15) v1(129.61,105.11) v1(129.93,172.07) v1(130.13,108.43) v1(130.55,103.23) v1(131.15,109.07) v1(131.4,172.01) v1(131.44,111) v1(132.43,99.95) v1(133.22,97.71) v1(134.24,57.4) v1(135,57.4) v1(135.41,112.25) v1(135.51,111.02) v1(135.89,57.4) v1(136.22,107.8) v1(137.03,24.1) v1(137.16,114.17) v1(137.19,100.79) v1(137.54,103.76) v1(137.59,104.52) v1(137.67,102.21) v1(138.05,23.22) v1(138.68,126.64) v1(138.73,122.45) v1(138.74,104.5) v1(138.94,24.1) v1(138.99,125.96) v1(139.06,124.23) v1(139.09,119.76) v1(140.31,104.6) v1(140.39,120.55) v1(140.46,134.62) v1(140.46,133.86) v1(140.46,123.42) v1(140.49,121.67) v1(141.26,205.98) v1(142.57,138.68) v1(142.74,126.86) v1(142.74,123.41) v1(142.66,120.18) v1(143.03,56.26) v1(143.76,136.22) v1(143.76,59.05) v1(144.81,57.3) v1(145.41,119.51) v1(145.36,60.33) v1(146.22,129.18) v1(146.22,128.42) v1(146.67,124.88) v1(146.84,123.44) v1(146.86,119.78) v1(148.08,122.07) v1(148.49,118.92) v1(148.58,132.69) v1(150.24,47.55) v1(150.74,45) v1(150.76,118.89) v1(150.77,42.88) v1(151.24,117.02) v1(152.17,131.09) v1(152.27,46.28) v1(152.7,39.93) v1(153.39,117.2) v1(153.48,121.6) v1(153.47,42.28) v1(154.21,124.69) v1(154.64,44.4) v1(154.69,116.71) v1(154.66,46.99) v1(155.01,120.84) v1(155.51,65.64) v1(155.7,58.17) v1(155.73,56.85) v1(157.61,67.06) v1(157.93,119.82) v1(158.9,119.38) v1(159.94,113.74) v1(161.07,113.57) v1(161.54,132.63) v1(162.2,173.61) v1(162.23,172.8) v1(162.53,171.83) v1(162.97,173.65) v1(163.02,172.85) v1(163.17,110.82) v1(164.08,112.27) v1(168.25,65.15) v1(188.52,1.4) v1(191.01,184.66) v1(191.9,184.66) v1(192.79,184.66) v1(198.6,4.68) v1(198.81,24.08) v2(23.04,133.27) v2(34.92,255.47) v2(40.03,253.7) v2(48.26,189.01) v2(48.69,100.66) v2(48.82,265.33) v2(115.77,120.07) v3(6.4,242.93) v3(6.99,207.7) v3(6.99,206.93) v3(12.99,150.8) v3(13.97,149.3) v3(15.27,147.93) v3(15.72,48.9) v3(16.38,116.26) v3(16.52,146.77) v3(17.62,145.65) v3(17.77,117.47) v3(18.11,48.26) v3(18.72,144.3) v3(18.92,117.35) v3(19.53,142.98) v3(19.53,140.82) v3(19.53,137.31) v3(19.53,134.95) v3(19.53,133.05) v3(19.53,131.14) v3(19.53,129.62) v3(19.53,128.09) v3(19.53,126.39) v3(20.13,117.37) v3(20.18,203.71) v3(20.18,202.69) v3(20.45,9.27) v3(20.7,206.72) v3(20.78,124.43) v3(21.34,7.62) v3(21.59,206.72) v3(24.77,7.75) v3(27.33,9.68) v3(28.19,276.86) v3(28.35,251.94) v3(29.08,255.27) v3(29.62,108.6) v3(29.72,250.95) v3(30.05,1.07) v3(30.53,108.64) v3(32.05,72.52) v3(35.69,7.62) v3(35.94,215.93) v3(37.01,185.93) v3(37.34,9.65) v3(37.52,219.58) v3(38.1,7.39) v3(38.35,263.78) v3(38.48,186.92) v3(38.68,212.9) v3(39.37,186.94) v3(39.37,15.75) v3(41.91,10.29) v3(42.52,233.58) v3(42.8,15.11) v3(43.5,233.51) v3(43.62,10.16) v3(44.25,233.35) v3(45.01,233.38) v3(45.03,1.04) v3(45.85,15.44) v3(45.78,10.21) v3(47.37,1.07) v3(47.8,13.72) v3(48.07,10.16) v3(48.51,18.16) v3(48.94,204.99) v3(49.94,1.04) v3(50.11,21.27) v3(50.11,19.37) v3(50.11,17.34) v3(50.16,13.84) v3(50.72,202.92) v3(51.44,204.72) v3(51.61,203.53) v3(52.58,17.02) v3(52.65,1.04) v3(54.2,199.82) v3(54.36,200.99) v3(55,245.94) v3(55.42,1.04) v3(55.63,200.13) v3(55.58,198.81) v3(57.18,197.87) v3(57.26,273.76) v3(57.62,198.83) v3(58.74,232.06) v3(58.93,195.15) v3(58.85,192.38) v3(59.44,218.95) v3(59.64,197.48) v3(60.1,195.22) v3(60.09,193.75) v3(60.17,232.28) v3(60.45,190.63) v3(60.65,14.41) v3(63.17,190.8) v3(63.63,22.76) v3(63.8,189.87) v3(63.93,200.16) v3(65.84,198.7) v3(69.93,213.94) v3(70.08,199.29) v3(70.76,212.98) v3(70.87,226.64) v3(70.93,224.9) v3(71.91,196.22) v3(72.01,197.43) v3(72.8,283.24) v3(73.71,193.59) v3(73.66,27.81) v3(74.32,196.16) v3(74.63,278.23) v3(75.54,276.45) v3(75.58,26.48) v3(76.1,193.27) v3(77.03,194.03) v3(77.52,280.52) v3(77.83,282.96) v3(77.98,278.46) v3(78.05,26.45) v3(78.32,179.75) v3(78.87,26.42) v3(79.25,193.27) v3(79.28,196.9) v3(79.93,179.71) v3(80.44,180.77) v3(80.72,194.67) v3(81.01,195.93) v3(82.81,102.84) v3(82.79,102.16) v3(82.8,100.94) v3(82.79,100.15) v3(82.8,98.83) v3(82.79,98.12) v3(82.79,96.93) v3(82.82,96.22) v3(82.99,193.68) v3(86.08,202.21) v3(86.6,181.97) v3(88.94,181.97) v3(89.46,201.93) v3(91.51,181.97) v3(92.1,282.96) v3(92.56,202.11) v3(93.72,26.41) v3(93.97,181.97) v3(94.56,202.23) v3(94.64,26.7) v3(96.47,282.96) v3(97.36,278.99) v3(98.78,1.14) v3(99.95,181.03) v3(101.19,282.93) v3(102.65,181.05) v3(103.86,1.14) v3(104.14,197.23) v3(105.52,181.05) v3(106.74,38.91) v3(107.92,181.05) v3(107.94,41.44) v3(108.23,192.2) v3(108.94,1.14) v3(109.87,106.85) v3(110.65,181.05) v3(111.38,106.81) v3(112.62,106.9) v3(112.85,181) v3(114.02,1.14) v3(114.12,181.18) v3(114.05,106.82) v3(114.81,282.96) v3(114.91,192.53) v3(115.25,180.21) v3(115.44,106.05) v3(115.8,26.8) v3(116.41,28.06) v3(116.74,278.03) v3(116.99,280.59) v3(117.14,273.46) v3(117.52,180.08) v3(117.73,282.96) v3(118.8,26.62) v3(119.1,1.14) v3(119.63,282.7) v3(119.76,177.34) v3(119.86,106.2) v3(120.78,281.81) v3(120.9,267.08) v3(120.9,261.87) v3(120.9,257.56) v3(120.9,250.57) v3(120.85,24.89) v3(120.95,278.69) v3(120.95,274.75) v3(120.95,271.68) v3(120.95,263.83) v3(120.95,259.54) v3(121.1,175.94) v3(121.11,106.25) v3(121.25,177.4) v3(121.49,15.96) v3(122.3,106.17) v3(122.53,176.07) v3(123.57,106.17) v3(124.18,174.52) v3(124.18,1.14) v3(125.02,15.88) v3(125.93,171.8) v3(126.47,174.98) v3(126.75,1.07) v3(127.11,172.01) v3(128.32,192.53) v3(128.93,175.67) v3(129.06,32.79) v3(129.06,1.07) v3(130.63,177.16) v3(130.96,192.53) v3(131.34,31.88) v3(131.32,1.07) v3(131.98,192.56) v3(133.26,177.2) v3(133.58,18.54) v3(133.85,174.39) v3(134.7,1.07) v3(135.82,32.28) v3(136.39,174.41) v3(136.5,170.15) v3(137.74,1.07) v3(138.16,176.68) v3(140.09,171.1) v3(140.21,176.96) v3(140.79,1.07) v3(141.66,137.82) v3(143.46,1.12) v3(143.69,175.72) v3(144.7,162.46) v3(144.71,161.47) v3(144.78,28.07) v3(144.75,26.67) v3(144.91,24.51) v3(145.16,202.95) v3(145.33,173.82) v3(145.56,172.2) v3(145.62,164.36) v3(145.69,141.05) v3(145.75,132.77) v3(145.75,141.81) v3(146.03,169.9) v3(146.13,1.07) v3(146.41,178.84) v3(147.01,151.47) v3(147.18,152.93) v3(147.71,177.49) v3(148.21,162.81) v3(148.17,152.63) v3(148.27,161.44) v3(148.31,153.98) v3(148.59,202.95) v3(148.84,165.02) v3(149.02,155.03) v3(149.17,1.07) v3(149.54,169.78) v3(149.46,153.32) v3(149.64,177.13) v3(150.24,155.08) v3(150.48,156.24) v3(151.03,101.55) v3(151.16,167.97) v3(151.79,1.04) v3(152.17,130.18) v3(152.48,163.47) v3(152.48,160.99) v3(152.67,100.24) v3(152.78,202.95) v3(155.35,1.04) v3(156.34,202.95) v3(158.9,1.04) v3(159.89,202.95) v3(161.62,109.82) v3(162.26,1.14) v3(163.58,202.95) v3(164.53,113.3) v3(165.07,115.7) v3(165.81,1.14) v3(167.26,202.95) v3(169.37,1.14) v3(170.81,202.95) v3(171.2,88.27) v3(171.83,89.03) v3(172.21,1.12) v3(173.99,202.95) v3(174.74,76.94) v3(174.75,116.71) v3(175.24,105.27) v3(175.39,120.27) v3(175.41,113.59) v3(175.42,84.48) v3(175.55,80.48) v3(175.58,88.19) v3(175.8,101.65) v3(175.77,1.12) v3(175.9,109.98) v3(175.9,92.2) v3(176.15,66.8) v3(176.28,70.74) v3(176.28,68.15) v3(176.28,64.21) v3(176.4,74.75) v3(176.4,72.21) v3(176.4,62.69) v3(176.66,97.92) v3(176.91,202.95) v3(177.04,76.31) v3(177.13,106.72) v3(177.3,122.08) v3(177.39,118.16) v3(177.55,81.92) v3(177.56,89.56) v3(177.77,114.76) v3(177.94,111.37) v3(177.85,97.89) v3(177.93,85.98) v3(178.08,103.2) v3(178.49,93.29) v3(179.32,1.12) v3(179.71,202.95) v3(182.12,1.09) v3(182.52,202.95) v3(185.7,1.22) v3(185.8,202.95) v3(187.96,39.19) v3(188.9,202.95) v3(189.26,14.99) v3(193.8,9.14) v3(197.1,202.95) v3(197.36,9.14) v3(198.75,194.94) v3(198.91,18.9) v3(198.86,14.3) v4(1.12,234.72) v4(1.91,242.52) v4(2.79,236.42) v4(10.54,213.74) v4(10.54,212.6) v4(10.57,82.47) v4(10.57,81.56) v4(10.71,110.36) v4(10.71,108.71) v4(12.19,264.19) v4(12.19,258.09) v4(12.17,248.13) v4(14.1,266.95) v4(15.24,276.73) v4(15.24,271.78) v4(15.4,274.87) v4(15.4,269.79) v4(15.95,279.5) v4(17.23,75.84) v4(17.25,74.93) v4(17.83,113.28) v4(17.83,112.27) v4(17.83,111.25) v4(17.77,76.58) v4(18.14,74.04) v4(18.17,74.96) v4(18.92,113.28) v4(18.92,112.27) v4(18.92,111.25) v4(19.13,74.9) v4(19.07,73.99) v4(19.43,279.83) v4(19.56,4.45) v4(19.92,185.68) v4(19.91,184.66) v4(19.91,183.67) v4(19.9,180.7) v4(19.94,179.79) v4(19.91,178.81) v4(20.04,74.88) v4(20,73.97) v4(20.07,113.28) v4(20.07,112.27) v4(20.07,111.25) v4(20.83,185.57) v4(20.83,184.66) v4(20.83,183.67) v4(20.81,180.7) v4(20.83,178.87) v4(20.86,179.79) v4(20.95,74.8) v4(20.99,73.89) v4(21.34,112.14) v4(21.36,111.18) v4(21.36,110.26) v4(21.72,180.34) v4(21.67,179.38) v4(21.89,74.8) v4(21.97,275.08) v4(22.05,265.46) v4(21.95,73.89) v4(21.97,5.49) v4(22.21,111.88) v4(22.24,110.92) v4(22.3,109.93) v4(22.81,74.75) v4(22.86,73.84) v4(24.26,271.91) v4(24.79,262.36) v4(25.27,276.86) v4(26.54,281.31) v4(26.85,6.81) v4(27.69,274.45) v4(27.85,224.69) v4(27.85,223.55) v4(27.94,214.76) v4(28.45,215.65) v4(28.42,45.19) v4(28.45,44.25) v4(28.45,43.33) v4(28.45,42.42) v4(28.45,41.5) v4(28.76,224.69) v4(28.76,223.55) v4(28.96,214.63) v4(29.21,216.28) v4(29.34,45.19) v4(29.36,47.96) v4(29.36,47.04) v4(29.36,46.13) v4(29.36,44.25) v4(29.36,43.33) v4(29.36,42.42) v4(29.36,41.5) v4(29.36,40.59) v4(29.46,215.39) v4(29.67,224.69) v4(29.67,223.55) v4(30.23,221.62) v4(30.25,216.6) v4(30.29,220.64) v4(30.3,219.65) v4(30.3,218.63) v4(30.3,217.62) v4(30.28,47.96) v4(30.28,47.04) v4(30.28,46.13) v4(30.25,45.19) v4(30.28,44.25) v4(30.28,43.33) v4(30.28,42.42) v4(30.28,41.5) v4(30.28,40.59) v4(30.35,215.65) v4(30.43,214.58) v4(30.48,222.5) v4(30.61,224.66) v4(30.61,223.52) v4(31.37,222.25) v4(31.66,224.69) v4(31.66,223.55) v4(31.88,226.95) v4(31.88,225.81) v4(32.33,211.86) v4(32.47,207.99) v4(33.02,281.31) v4(33.15,276.99) v4(33.27,274.45) v4(34.18,180.47) v4(34.18,179.2) v4(34.89,94.45) v4(34.92,86.61) v4(34.92,78.87) v4(35.35,196.47) v4(35.34,195.45) v4(35.33,194.44) v4(35.91,94.45) v4(35.94,86.61) v4(35.94,78.87) v4(36.15,195.03) v4(36.2,197.89) v4(36.2,196.98) v4(36.2,195.96) v4(36.2,194.06) v4(36.91,198.47) v4(37.01,197.43) v4(36.96,72.64) v4(37.08,196.34) v4(37.08,195.43) v4(37.08,194.51) v4(37.59,271.91) v4(37.77,281.1) v4(41.15,281.31) v4(42.55,271.91) v4(42.85,281.1) v4(47.16,187.97) v4(47.29,5.94) v4(47.5,281.31) v4(47.5,272.03) v4(47.51,187.06) v4(47.51,186.11) v4(47.51,185.19) v4(47.51,184.28) v4(47.52,43.77) v4(47.52,42.86) v4(47.49,34.04) v4(47.62,50.24) v4(47.65,52.07) v4(47.65,51.16) v4(47.65,49.33) v4(47.65,48.34) v4(47.65,47.42) v4(47.65,46.51) v4(47.65,45.59) v4(47.65,44.68) v4(48.39,276.99) v4(48.51,208.11) v4(48.53,52.98) v4(48.54,50.24) v4(48.54,43.76) v4(48.54,42.77) v4(48.56,52.07) v4(48.56,51.16) v4(48.56,49.33) v4(48.56,48.34) v4(48.56,47.42) v4(48.56,46.51) v4(48.56,45.59) v4(48.56,44.68) v4(49.53,208.11) v4(50.47,208.11) v4(50.53,178.31) v4(50.59,177.19) v4(51.44,178.44) v4(51.43,176.37) v4(51.53,177.28) v4(52.13,34.67) v4(52.32,276.61) v4(52.34,178.66) v4(52.32,175.9) v4(52.35,177.67) v4(52.93,179.48) v4(52.87,34.13) v4(52.96,281.31) v4(52.96,180.47) v4(53.98,180.42) v4(53.98,179.45) v4(55.09,35.59) v4(56.64,37.86) v4(57.36,1.4) v4(61.67,67.64) v4(62.44,1.4) v4(62.59,67.64) v4(66.03,55.96) v4(66.04,54.13) v4(66.04,53.19) v4(66.06,57.78) v4(66.06,56.87) v4(66.06,55.04) v4(66.06,52.27) v4(66.06,51.36) v4(66.06,50.44) v4(66.06,49.53) v4(66.06,48.62) v4(66.07,47.6) v4(66.07,46.69) v4(66.95,55.96) v4(66.97,57.78) v4(66.97,56.87) v4(66.97,55.04) v4(66.95,54.13) v4(66.95,53.19) v4(66.97,52.27) v4(66.97,51.36) v4(66.97,50.44) v4(66.97,49.53) v4(66.97,48.62) v4(66.98,47.6) v4(66.98,46.69) v4(67.52,1.4) v4(69.49,67.64) v4(70.41,67.64) v4(73.3,41.3) v4(75.06,41.34) v4(77.6,67.64) v4(77.68,1.4) v4(78.51,67.64) v4(79.43,67.64) v4(82.32,278.21) v4(82.76,1.4) v4(83.44,251.21) v4(84.55,55.47) v4(84.57,57.3) v4(84.57,56.39) v4(84.57,54.56) v4(84.6,53.62) v4(84.6,52.68) v4(84.6,51.71) v4(84.6,50.8) v4(84.6,49.89) v4(84.6,48.97) v4(84.6,48.06) v4(84.58,47.14) v4(84.58,46.23) v4(85.49,57.3) v4(85.49,56.39) v4(85.46,55.47) v4(85.49,54.56) v4(85.51,53.62) v4(85.52,52.68) v4(85.51,51.71) v4(85.51,50.8) v4(85.51,49.89) v4(85.51,48.97) v4(85.51,48.06) v4(85.49,47.14) v4(85.49,46.23) v4(86.61,278.13) v4(87.36,251.25) v4(87.84,1.4) v4(92.44,251.25) v4(92.51,280.75) v4(92.94,40.75) v4(92.92,1.4) v4(93.93,278.64) v4(93.85,40.75) v4(94.4,282.6) v4(96.67,273.84) v4(97.52,251.25) v4(99.48,282.6) v4(100.23,280.09) v4(104.75,276.58) v4(106.1,250.49) v4(107.57,278.13) v4(109.07,250.65) v4(110.11,276.38) v4(110.19,264.01) v4(112.04,260.63) v4(113.18,263.19) v4(113.26,177.42) v4(113.61,279.86) v4(113.79,248.25) v4(116.59,261.52) v4(117.37,265.33) v4(117.88,270.18) v4(117.89,176.78) v4(118.87,248.25) v4(124.02,52.24) v4(124.33,51.24) v4(124.84,50.48) v4(124.96,52.1) v4(125.34,51.25) v4(125.83,50.46) v4(125.88,52.07) v4(126.39,51.24) v4(126.92,50.48) v4(127.17,79.43) v4(127.17,78.49) v4(127.17,77.49) v4(127.34,51.3) v4(127.66,90.83) v4(127.91,50.48) v4(128.08,79.46) v4(128.08,78.51) v4(128.08,77.55) v4(128.24,88.32) v4(128.25,89.23) v4(128.71,50.93) v4(129.26,41.02) v4(129.27,39.4) v4(130.1,40.26) v4(130.3,41.53) v4(182.6,170.43) v4(182.58,169.43) v4(182.62,168.5) v4(182.63,167.58) v4(183.41,201.42) v4(183.49,171.33) v4(183.52,170.42) v4(183.49,169.5) v4(183.53,168.57) v4(183.54,167.51) v4(185.29,199.44) v4(186.77,197.84) v4(188.62,201.32) v4(194.52,1.4) v4(195.69,174.9) v4(195.69,172.75) v4(195.69,171.15) v4(195.71,169.7)
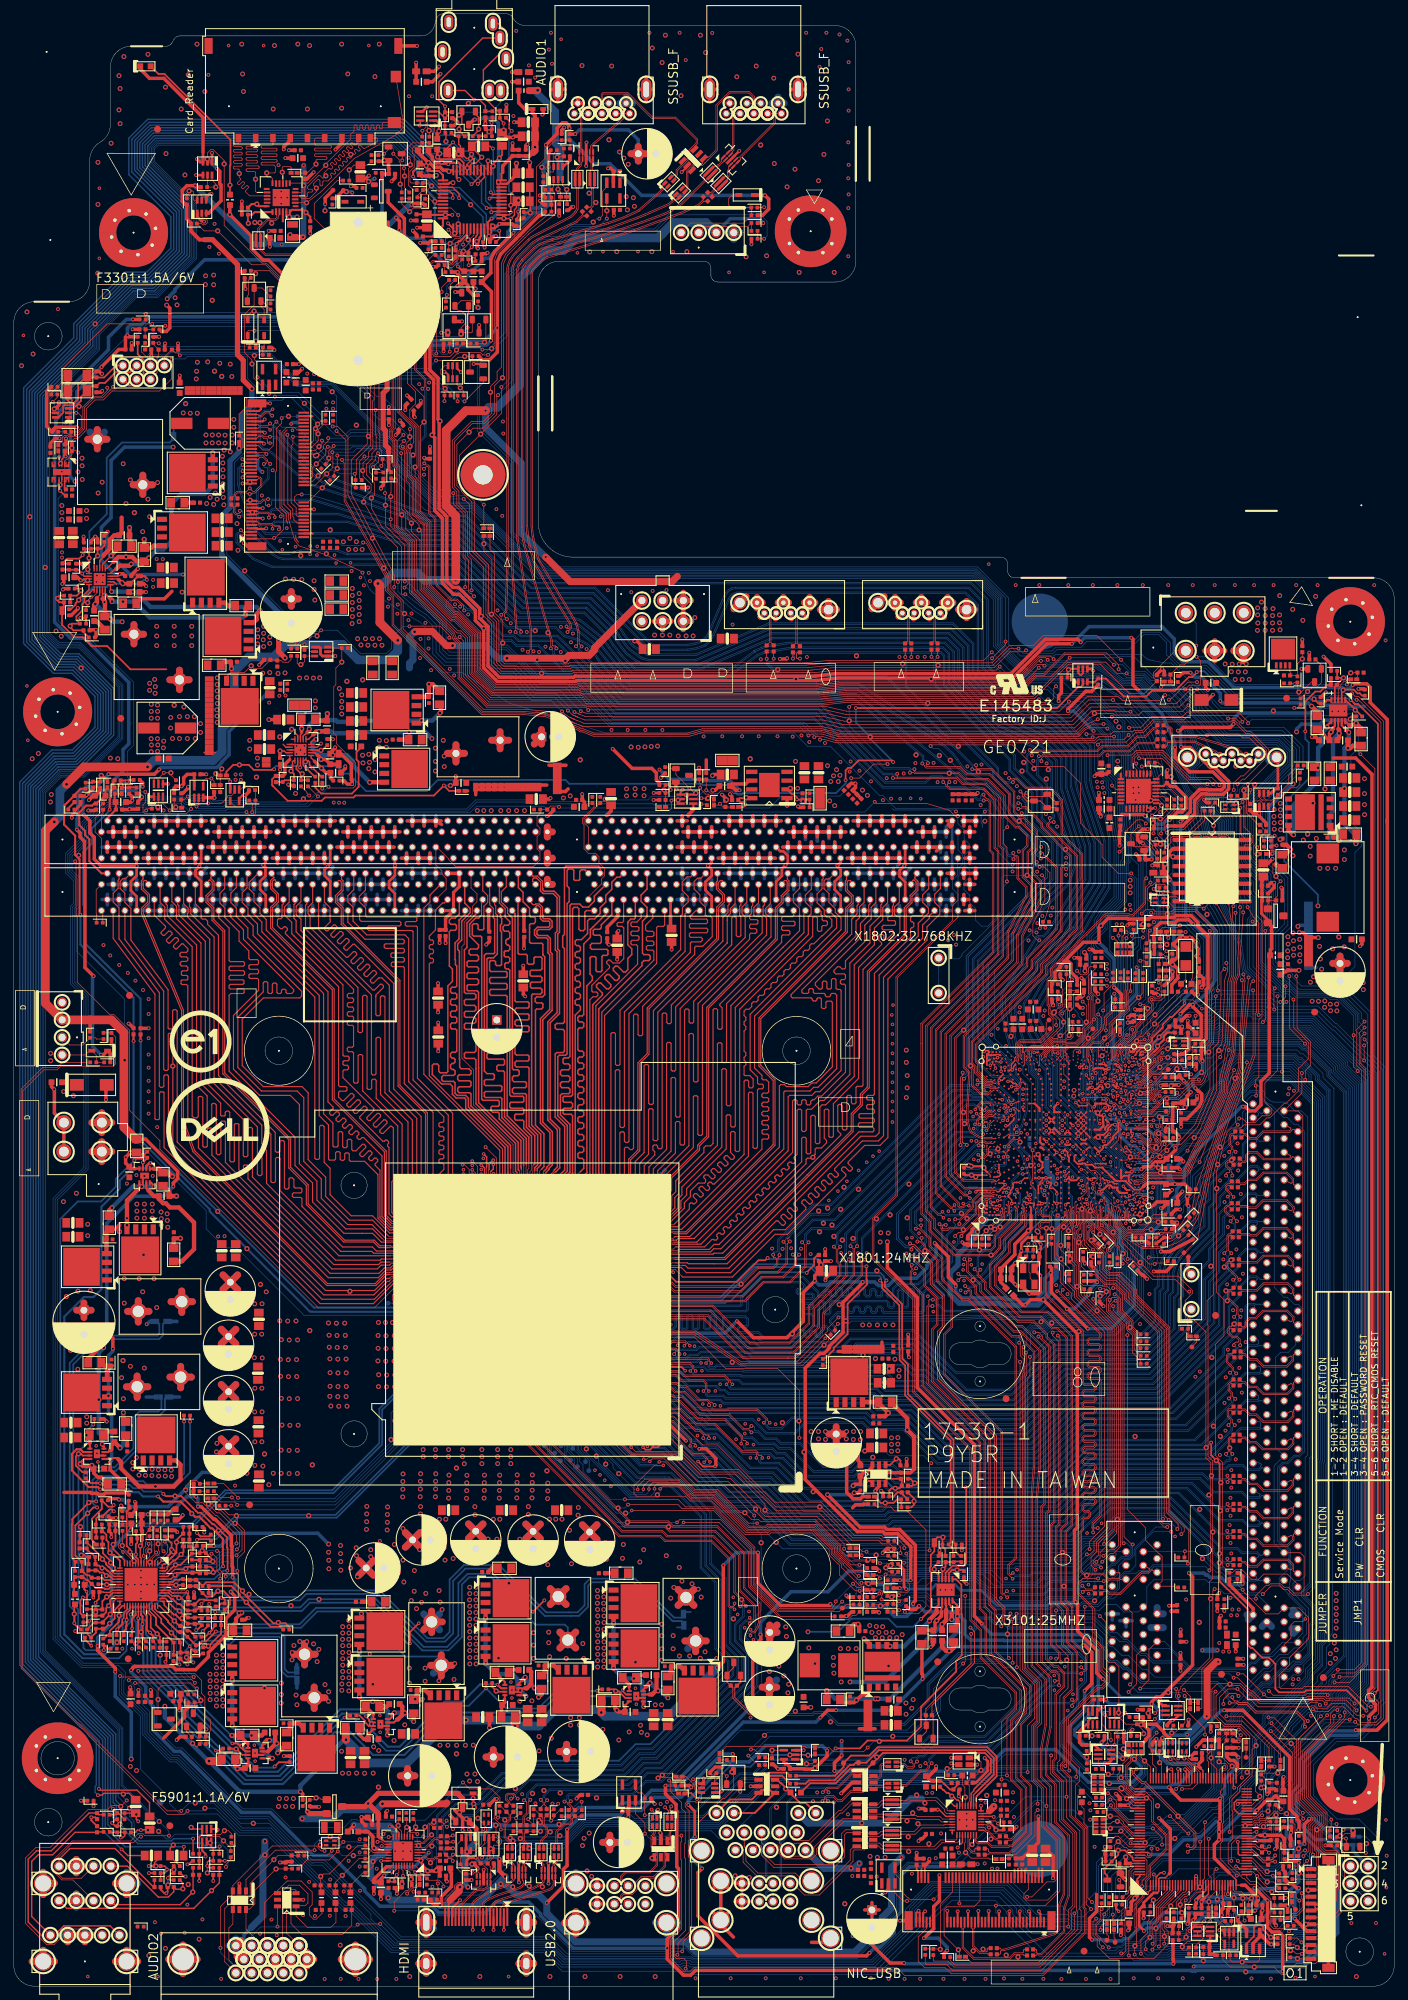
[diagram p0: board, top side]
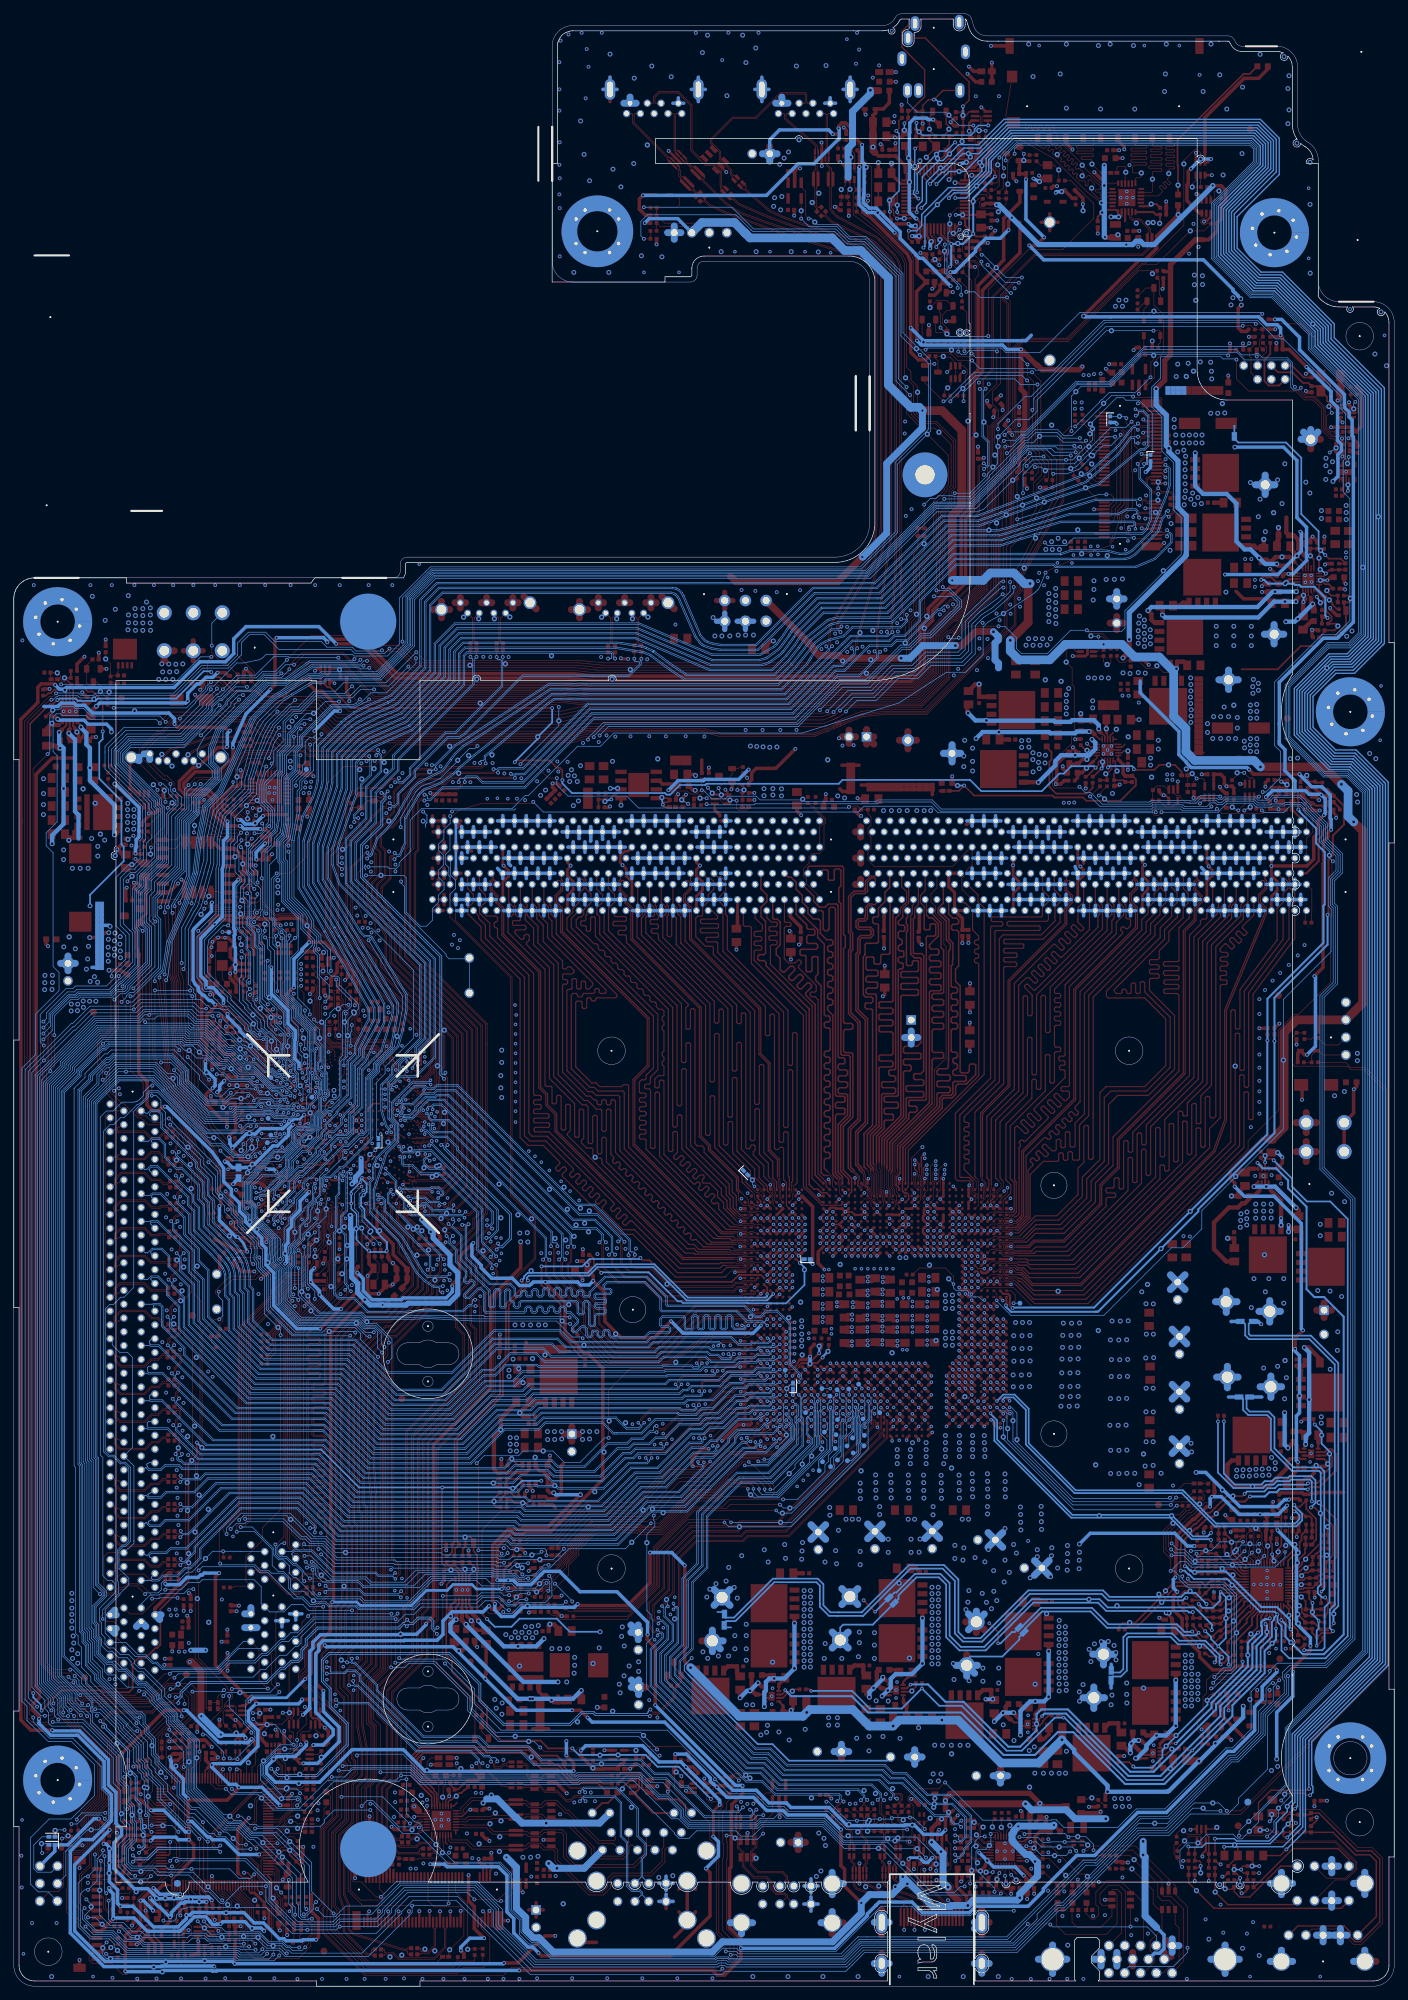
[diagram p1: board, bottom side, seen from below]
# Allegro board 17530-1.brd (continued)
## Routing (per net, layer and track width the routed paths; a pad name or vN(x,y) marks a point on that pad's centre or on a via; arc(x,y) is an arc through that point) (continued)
V5_ALW_MON: length 15.3
  TOP w0.102: U2401.15 170.29,13.78 169.82,13.31 169.55,13.31 168.42,12.18 168.42,11.47 168.61,11.29 168.61,9.35 168.81,9.14 168.81,8.7 R2472.1 168.81,8.67 168.81,8.23 168.78,8.2 168.78,7.68 C2426.1 168.78,7.66 168.78,6.69 R2468.2 169.42,6.68 v2(169.85,7.11) 169.85,8.15 170.66,8.96 172.18,8.96 172.53,8.6 Q2408.3
V5_ALW_MON_1: length 5.3
  TOP w0.102: R2467.2 169.89,5.23 169.39,5.23 169.29,5.33 v2(169.29,5.71) 170.03,6.45 170.34,6.45 170.66,6.78 170.66,7.14 170.83,7.3 Q2408.6 Q2408.5
V5_ALW_MON_2: length 6.6
  TOP w0.102: Q2408.2 172.67,7.95 172.31,7.59 172.31,6.96 171.3,5.94 R2466.2 171.84,5.6 171.91,5.66 C2425.1 R2471.1 v2(172.35,3.68)
VBAT1: length 8.3
  TOP w0.508: 48.69,255.51 BT2501.1 ; BT2501.1 49.91,254.29 ; BT2501.1 51.13,255.51 ; BT2501.1 49.91,256.73 ; TP2501.1 45.11,259 v3(45.11,258.11)
  BOTTOM w0.254: v3(45.11,258.11) v2(45.08,257.17)
VBAT1_L: length 3
  TOP w0.508: R2506.2 46.6,258.97 TP2502.1
  BOTTOM w0.508: v2(48.18,259.94) 48.92,259.94 49.02,259.84 49.02,259.84 49.04,259.82 v3(49.04,259.78)
VBAT1_R: length 1
  BOTTOM w0.508: v3(52.27,261.83) v2(51.39,261.4)
VBAT2: length 411.8
  TOP w0.203: 171.87,13.06 172.45,13.64 172.49,13.64 172.69,13.84 U2401.21
  TOP w0.508: v3(153.3,194.45) 149.69,194.45 144.73,189.48 143.01,189.48 142.38,189.48 119.44,189.48 116.25,189.13 81.56,189.13 81.41,188.97 70.05,188.97 68.07,190.95 68.07,196.62 66.88,197.82 66.88,199.28 64.54,201.63 63.7,201.63 62.1,203.23 62.1,212.57 61.84,212.84 61.84,212.89 60.99,213.75 60.99,224.28 v2(60.58,224.69) 60.83,224.94 60.83,232.67 59.65,233.85 59.65,245.65 54.23,251.07 54.23,255.52 ; C2405.1 171.2,11.85 171.32,11.97 v3(171.32,12.45) 171.32,12.51 171.87,13.06 ; v3(194.01,188.47) 194.18,188.65 196.01,188.65 196.52,188.14 196.52,185.94 198.98,183.48 198.98,168.94 198.98,168.58 198.98,38.56 198.13,37.71 197.82,37.39 197.71,37.29 197.71,37.29 197.51,37.08 v3(194.44,37.08)
  BOTTOM w0.508: v3(194.01,188.47) 193.98,188.47 193.4,187.88 192.64,187.88 192.41,188.11 176.76,188.11 173.04,191.84 169.32,191.84 168.14,193.02 168.14,195.16 166.36,196.94 155.79,196.94 v3(153.3,194.45) ; v3(171.32,12.45) 171.79,12.91 175.38,12.91 175.62,12.67 179.15,12.67 180.59,14.12 182.55,14.12 185.49,17.06 185.49,20.78 184.38,21.89 184.38,22.76 185.19,23.57 185.19,28.07 186.28,29.16 186.28,32.8 190.47,36.98 194.34,36.98 v3(194.44,37.08)
VCCGT_VCC_SEN: length 67.9
  TOP w0.254: v1(56.65,84.75) 57.09,85.2 CPU1.F39 ; v3(14.47,69.69) 14.47,69.69 14.24,69.46 13.66,69.46 PR4445.2 12.74,69.13 11.3,67.69 11.3,64.68 11.95,64.04 PR4447.1
  BOTTOM w0.254: v1(56.65,84.75) 56.65,85.09 56.46,85.28 55.17,85.28 53.37,83.48 53.37,78.48 46.31,71.42 30.79,71.42 25.97,66.61 25.76,66.61 25.76,66.6 24.69,66.6 24.69,66.61 20.04,66.61 ; 20.04,66.61 v2(20.04,66.32) ; 20.04,66.61 14.2,66.61 13.34,67.47 13.34,68.42 14.47,69.56 v3(14.47,69.69)
VCCGT_VSS_SEN: length 63.8
  TOP w0.254: CPU1.F38 58.01,85.2 v1(57.57,84.75) ; PC4422.2 11.95,65.76 11.87,65.84 PC4423.1 PR4450.1 11.87,66.93 11.95,67.01 11.95,67.76 12.23,68.05 PR4454.1 13.84,69.05 14.21,69.05 14.51,68.75 14.51,68.78 v3(14.49,68.78)
  BOTTOM w0.254: 28.41,69.63 25.8,67.01 25.59,67.01 25.59,67.01 24.86,67.01 24.85,67.01 14.37,67.01 13.74,67.64 13.74,68.25 14.27,68.78 v3(14.49,68.78) ; 28.41,69.63 v2(28.19,69.85) ; 28.41,69.63 30.38,71.59 30.62,71.83 46.14,71.83 52.96,78.65 52.96,83.65 55,85.69 56.63,85.69 v1(57.57,84.75)
VCCIO_SENSE: length 51.3
  TOP w0.254: CPU1.AF4 91.74,103.02 94.5,103.02 94.53,103.04 94.95,103.04 95.96,102.03 104.78,102.03 107.9,105.16 108.89,105.16 v3(109.22,105.49) ; PR4815.2 117.39,91.04 117.67,91.04 118.79,92.16 118.79,92.44 120.8,94.45 120.8,96.09 120.8,96.09 120.8,98.82 123.62,101.64 123.62,102.27 123.55,102.35 v3(123.55,104.27)
  BOTTOM w0.254: 117.17,104.73 116.56,105.33 109.37,105.33 v3(109.22,105.49) ; 117.17,104.73 117.63,104.27 v3(123.55,104.27) ; 117.17,104.73 v2(116.95,104.51)
VCCPLL_OC_R: length 41
  TOP w0.254: v3(86.1,104.77) 86.65,105.32 CPU1.AJ9 ; v3(114.88,103.33) 114.94,103.38 114.94,103.45 115.95,104.47 115.95,105.41 116.46,105.92 C801.1
  BOTTOM w0.254: v3(114.88,103.33) 114.81,103.4 108,103.4 103.81,99.21 103.3,99.21 103.04,98.96 93.7,98.96 93.67,98.92 90.63,98.92 90.61,98.91 88.11,98.91 85.45,101.57 v2(85.45,103.78) 85.45,104.11 v3(86.1,104.77) 85.56,105.31 R801.1
VCCSA_SENSE: length 84.8
  TOP w0.254: CPU1.AD5 89.97,100.33 89.97,100.28 v1(89.95,100.27) ; PR4714.1 136.14,62.66 136.06,62.75 136.06,63.36 135.45,63.97 PR4715.2 135.45,64 135.74,64.29 135.74,79 129.14,85.59 129.14,89.9 128.35,90.7 128.35,92.25 128.29,92.3 128.29,98.64 125.81,101.13 125.81,101.93 v3(125.52,102.22)
  BOTTOM w0.254: v3(125.52,102.22) 125.68,102.38 125.68,102.62 125.38,102.92 116.66,102.92 115.42,104.17 107.34,104.17 105.12,101.94 ; 105.12,101.94 v2(105.36,101.7) ; 105.12,101.94 102.51,99.34 90.88,99.34 v1(89.95,100.27)
VCCST_GD_CPU: length 79.4
  TOP w0.102: v3(129.32,62.65) 129.44,62.53 129.44,58.59 129.74,58.29 129.74,57.34 129.48,57.07 128.46,57.07 128.43,57.1 127.14,57.1 R419.2 R420.1 ; v3(132.93,75.76) 132.69,75.51 v3(132.69,63.13) ; v3(113.82,79.43) 113.82,86.31 110.67,89.46 103.17,89.46 98.62,94.01 93.51,94.01 93.18,94.34 CPU1.U2
  BOTTOM w0.102: v3(132.69,63.13) 129.8,63.13 v3(129.32,62.65) ; v3(132.93,75.76) 131.85,76.83 126.87,76.83 126.19,77.52 v2(123.29,77.52) 121.89,77.52 120.24,75.87 117.96,75.87 114.4,79.43 v3(113.82,79.43)
VCCST_GD_DRIVER: length 61.2
  TOP w0.102: R9908.1 R419.1 128.02,56.52 128.14,56.64 v3(128.24,56.64) ; v3(137.54,46.74) 137.85,47.04 v3(137.85,56.54) ; R4014.2 107.98,33.19 107.98,33.63 107.31,34.29 v3(106.81,34.29)
  BOTTOM w0.102: v3(137.54,46.74) 133.6,42.8 133.6,40.21 130.17,36.78 109.22,36.78 v2(108.76,36.32) 106.81,34.37 v3(106.81,34.29) ; v3(128.24,56.64) 129.02,56.64 129.35,56.97 132.3,56.97 132.73,56.54 v3(137.85,56.54)
VDDQ_EN: length 3.4
  TOP w0.102: v2(30.12,176.33) 29.91,176.11 R5003.1 R4024.2 C4012.1
VDDQ_EN_CR: length 4.2
  TOP w0.102: U4010.4 27.45,174.61 27.77,174.93 v3(28.63,174.93) 29.02,174.54 R4024.1
  BOTTOM w0.102: v3(28.63,174.93) v2(29.27,175.64)
VIN_DET: length 7.9
  TOP w0.203: 180.5,21.87 180.48,21.84 180.03,21.84 179.57,21.38 U2401.46
  TOP w0.508: 180.5,21.87 v2(181.28,21.87) 183.01,21.87 183.02,21.86 183.58,21.86 184.09,21.35 C2407.1 R2416.1 184.09,19.33 R2411.2
VSS_SA_IO_SENSE: length 85.7
  TOP w0.254: CPU1.AE4 90.83,101.19 90.83,100.32 90.86,100.29 v1(90.86,100.25) ; v3(126.43,102.22) 126.21,102 126.21,101.29 128.7,98.81 128.7,92.47 128.75,92.42 128.75,90.87 129.55,90.07 129.55,85.76 136.14,79.17 136.14,64.3 PR4717.1 136.46,62.92 137.06,62.32 PR4716.2
  BOTTOM w0.254: v1(90.86,100.25) 90.86,99.94 91.05,99.75 102.35,99.75 107.17,104.57 115.59,104.57 116.83,103.33 125.04,103.33 ; v3(126.43,102.22) 126.09,102.57 126.09,102.79 125.54,103.33 125.04,103.33 ; 125.04,103.33 v2(125.04,103.63)
0D95V_CPU_VCCIO: length 73.8
  TOP w0.381: v3(156.59,34.94) 156.6,34.94 157.14,34.4 Q2402.1
  TOP w0.432: CPU1.P8 86.88,91.6 v1(86.87,91.61) ; 83.46,106.04 83.46,106.38 CPU1.AK11 ; CPU1.M8 87.64,89.85 v1(86.96,90.53) ; CPU1.U8 v1(86.87,94.34) ; CPU1.AK14 v1(80.41,106.69) ; CPU1.T8 v1(86.87,93.43) ; CPU1.AK24 70.81,107.1 v1(71.24,106.67) 71.68,106.23 CPU1.AJ23 ; CPU1.W8 v1(86.87,96.17)
  TOP w0.508: R425.2 123.11,69.82 123.03,69.75 122.51,69.75 121.97,69.75 121.54,69.32 ; R9912.1 129.73,54.61 130.68,54.61 v3(131.15,55.08) ; v1(82.55,103.81) 83.46,104.72 83.46,106.04 ; 120.4,75.69 120.68,75.41 120.68,71.53 121.59,70.61 122.67,70.61 122.98,70.92 PR4812.2
  TOP w1.016: 118.1,79.98 PT4801.1 ; PT4801.1 119.15,78.93 ; PT4801.1 120.21,79.98 ; PT4801.1 119.15,81.04
  BOTTOM w0.508: v3(131.15,55.08) 132,54.23 132.35,54.23 132.35,54.23 136.5,54.23 137.82,52.91 137.82,50.95 138.65,50.11 143.37,50.11 143.44,50.05 155.2,50.05 155.8,49.45 155.8,48.6 156.26,48.14 156.26,39.7 153.73,37.17 153.73,36.41 155.2,34.94 v3(156.59,34.94)
  vias: v1(81.92,103.81) v1(84.81,94.59) v1(84.81,93.83) v2(85.78,91.44) v2(86,99.09) v4(70.74,105.54) v4(71.63,105.54) v4(115.52,80.34) v4(116.59,80.34) v4(116.59,79.27) v4(117.6,80.34) v4(117.6,79.2) v4(120.62,79.26) v4(120.65,80.34) v4(121.63,79.2) v4(121.67,80.34) v4(122.68,80.34) v4(122.66,79.17)
0D675V_VTT_S0: length 9.8
  TOP w1.016: 77.3,162.66 DIMM2.77 ; DIMM2.77 77.3,164.14 ; DIMM2.77 78.04,163.4 ; 77.3,160.34 DIMM1.221 78.04,159.6 ; 77.3,166.46 DIMM2.221 ; DIMM2.221 77.3,167.94 ; DIMM2.221 78.04,167.2
  L3SGND w0.762: DIMM1.221 77.43,159.47 77.43,155.93 DIMM1.77
  vias: v4(35.31,177.89) v4(35.31,176.87) v4(79.64,172.12) v4(80.62,172.42)
1D2V_SM_S3: length 357
  TOP w0.127: v3(158.1,39.32) 158.81,38.61 Q2405.4
  TOP w0.254: CPU1.AW25 69.9,115.34 69.52,114.97 v1(69.52,114.89) ; CPU1.AY16 78.13,117.08 v1(78.12,117.08) ; CPU1.AV17 v1(76.75,114.92)
  TOP w0.305: CPU1.AY12 81.78,116.63 81.97,116.81 v1(81.97,116.87)
  TOP w0.356: CPU1.AV21 73.55,114.85 73.56,114.87 v1(73.56,115.06) ; v1(74.9,113.09) 75.36,113.54 CPU1.AU19 ; CPU1.AY23 71.72,116.91 v1(71.67,116.97) ; CPU1.AT18 v1(76.73,113.09) ; v1(79.52,114.93) 79.9,115.3 79.9,115.32 CPU1.AW14 ; CPU1.AT21 73.2,112.98 v1(73.2,113.08) ; v1(79.51,113.09) 79.05,113.54 CPU1.AU15 ; CPU1.AW10 v1(86.27,114) ; CPU1.AU23 71.7,113.54 v1(71.27,113.97) ; v1(83.36,114.63) 83.19,114.46 CPU1.AV11 ; CPU1.AU13 v1(80.41,114) ; CPU1.AY18 76.3,116.84 76.17,116.96 v1(76.17,116.97)
  TOP w0.406: DIMM2.51 55.2,162.63 55.22,162.61 55.22,162.36 v3(55.22,162.36) 55.22,162.35 55.22,160.88 54.39,160.05 54.39,159.11 55.2,158.3 DIMM1.51 ; DIMM2.40 45.85,162.56 v3(45.47,162.18) 45.04,161.75 45.04,160.86 45.44,160.47 45.85,160.05 DIMM1.40 ; DIMM2.132 129.15,162.42 v3(129.03,162.31) 128.34,161.61 128.34,160.75 129.15,159.94 DIMM1.132 ; DIMM2.18 27.15,162.67 26.92,162.44 26.92,162.25 v3(26.88,162.21) 26.88,162.19 26.34,161.65 26.34,160.86 27.15,160.05 DIMM1.18 ; DIMM2.29 36.5,162.8 v3(36.12,162.42) 36.46,162.07 36.46,160.83 35.69,160.05 35.69,158.86 36.5,158.04 DIMM1.29 ; DIMM1.99 101.1,157.86 100.21,158.75 100.21,159.95 101.11,160.85 101.11,161.74 100.58,162.27 v3(100.58,162.32) 100.63,162.32 101.11,162.79 101.11,163.39 DIMM2.99 ; DIMM2.7 17.79,163.39 v3(17.79,162.27) 17.79,160.85 16.96,160.03 16.96,158.68 17.8,157.85 DIMM1.7 ; DIMM2.110 111.04,164.41 111.48,164.41 112.14,163.75 112.14,162.72 v3(111.81,162.39) 111.29,161.87 111.29,160.85 110.45,160.01 DIMM1.110 ; DIMM1.92 95.15,154.99 ; DIMM2.121 119.81,163.39 119.81,162.79 v3(119.33,162.32) 119.33,162.22 119.81,161.74 119.81,160.86 118.94,159.99 118.94,158.83 119.8,157.97 DIMM1.121
  TOP w0.457: DIMM1.59 DIMM1.61 63.7,158.41 64.54,159.25 64.54,161.19 DIMM1.206
  TOP w0.508: C1201.1 C1202.1 62.56,154.66 DIMM1.61 ; 80.01,176.86 PR5013.2 PR5012.2 PR5011.2 PR5010.2 PR5008.2 PR5006.2 79.93,173.05 80.31,173.43 ; v3(87.6,152.85) 87.42,152.67 C1027.1 ; v3(74.09,143.38) 73.81,143.66 C1029.1 ; C808.1 v3(129.59,94.39) ; DIMM1.73 73.9,154.94 73.91,154.92 73.91,152.92 C1102.1 ; 95.15,154.99 95.15,153.34 C1030.1 ; R1103.1 11.48,173.48 v3(10.54,172.54) 10.4,172.41 C1105.1 ; DIMM1.204 DIMM1.206 ; 125.78,93.29 PR4807.2 PR4805.2 PR4809.2 PR4806.2 PR4804.2 PR4803.2 PR4802.2 PR4801.2 ; C1101.1 68.8,152.85 DIMM1.67 ; 66.93,172.59 PR5027.2 PR5030.2 PR5028.2 PR5029.2 PR5026.2 PR5015.2 PR5017.2 PR5018.2 PR5020.2 PR5021.2 PR5022.2 PR5023.2 ; DIMM1.83 87.5,154.94 85.98,153.42 C1203.1 ; v3(17.79,162.27) 12.65,162.27 11.66,163.26 11.66,166.42 11.02,167.06 11.02,168.78 10.21,169.6 10.21,169.6 v3(10.2,169.61) ; C1208.1 18.01,171.63 18.57,172.19 v3(18.57,172.26) 18.57,172.26 18.1,172.73 R1203.1 ; v3(61.49,135.42) C1028.1 ; v4(126.57,107.82) 126.57,104.07 130.52,100.13 130.9,99.74 130.9,86.71 139.18,78.43 139.18,53.61 v1(140.26,52.53) ; C1031.1 v3(61.47,141.06) ; v3(84.25,104.6) 84.25,112.9 CPU1.AW10 ; R3818.2 v3(17.27,241.43)
  BOTTOM w0.508: v1(140.26,52.53) 140.26,52.36 141.64,50.98 143.73,50.98 143.79,50.91 155.56,50.91 156.67,49.81 156.67,48.96 157.12,48.5 157.12,40.24 158.04,39.32 v3(158.1,39.32) ; R801.2 84.59,104.94 v3(84.25,104.6) ; v3(10.2,169.61) 10.01,169.8 10.01,172.01 v3(10.54,172.54) 10.64,172.64 12.32,172.64 12.86,173.18 14.38,173.18 ; 14.38,173.18 17.65,173.18 v3(18.57,172.26) ; 14.38,173.18 14.38,174.6 15.82,176.05 15.82,179.12 16.65,179.95 16.65,180.33 16.65,182.9 16.65,182.9 16.65,188.87 15.13,190.38 10.27,195.25 8.25,195.25 8.04,195.46 8.04,195.46 7.61,195.89 7.6,195.89 5.92,197.58 5.92,224.43 6.1,224.61 6.1,226.87 6.53,227.3 6.53,228.02 7.19,228.68 7.19,229.1 7.21,229.13 7.21,230.55 13.72,237.05 13.72,238.84 16.3,241.43 v3(17.27,241.43)
  vias: v2(35.15,175.13) v3(32.13,175.51) v3(32.13,174.75) v3(32.89,175.51) v3(32.89,174.75) v3(135.38,151.51) v3(135.64,150.37) v3(136.22,152.27) v3(136.53,150.88) v4(43.69,186.18) v4(43.69,185.17) v4(67.16,170.28) v4(68.1,170.28) v4(69.16,170.28) v4(70.56,170.28) v4(71.7,170.28) v4(72.85,170.28) v4(73.99,170.28) v4(88.77,173.43) v4(88.77,172.42) v4(90.02,173.46) v4(90.02,172.54) v4(91.31,173.46) v4(91.31,172.44) v4(122.99,95.78) v4(123.95,95.78) v4(125.13,95.78) v4(125.53,107.8) v4(125.6,109.14) v4(126.25,95.8) v4(126.7,109.09) v4(127.38,95.78) v4(129.31,135.59) v4(129.31,133.81) v4(129.31,128.73) v4(129.44,131.9) v4(129.44,130.12) v4(140.69,168.76)
1D05V_CPU_SA: length 54.5
  TOP w0.254: PG4701.1 133.38,62.99 132.87,62.48 132.87,60.8 132.72,60.65 132.72,60.12 132.87,59.97 132.87,54.61 v3(131.44,53.19)
  TOP w0.432: CPU1.N7 v1(88.1,91.14) CPU1.P7 v1(88.1,92.06) CPU1.R7 v1(88.1,92.97) CPU1.T7 v1(88.1,93.89) CPU1.U7 v1(88.1,94.8) CPU1.V7
  TOP w1.016: PT4702.1 110.58,51.26 ; PT4702.1 109.52,52.31 ; PT4702.1 110.58,52.31 ; PT4702.1 109.52,50.2 ; 108.42,43.31 PT4701.1 ; PT4701.1 110.53,43.31 ; PT4701.1 109.47,42.25 ; PT4701.1 109.47,44.36
  BOTTOM w0.254: v4(115.06,51.33) 119.43,51.33 121.34,53.24 126.72,53.24 127.89,52.07 130.33,52.07 v3(131.44,53.19)
  BOTTOM w1.016: PT4701.1 109.47,44.36 ; PT4701.1 110.53,43.31 ; PT4701.1 110.53,44.36 ; PT4701.1 109.47,42.25 ; PT4702.1 110.58,52.31 ; PT4702.1 109.52,50.2 ; PT4702.1 109.52,52.31 ; PT4702.1 110.58,51.26
  vias: v1(89.01,96.63) v1(89.01,95.71) v2(116.08,46.74) v4(85.85,94.45) v4(85.85,93.56) v4(85.85,92.7) v4(85.85,96.39) v4(85.85,95.5) v4(109.47,46.99) v4(109.47,45.59) v4(110.85,46.38) v4(111.56,49.28) v4(111.58,44.96) v4(111.84,52.04) v4(111.94,50.67) v4(112.15,42.5) v4(112.27,43.74) v4(115.19,49)
1D05V_LAN: length 9.3
  TOP w0.203: U3101.3 135.04,24.6 134.06,25.58 v3(133.86,25.58) ; v3(141.99,24.51) 141.89,24.6 U3101.22 ; U3101.30 137.44,26.1 137.44,26.95 136.91,27.47 v3(136.91,27.51) ; 135.97,22.05 135.97,22.28 135.96,22.28 U3101.8
  TOP w0.254: U3101.24 v3(140.13,26.14)
  TOP w0.508: v3(136.91,27.51) 136.91,28.37 C3106.1 ; v3(133.86,25.58) 133.03,25.58 C3107.1
  vias: v2(140.97,27.64) v3(134.34,22.12) v3(140.13,27) v3(140.79,26.62)
1D8V_SB: length 40
  TOP w0.254: SB1.AG19 153.67,120.22 153.67,119.56 154.14,119.09 154.71,119.09 154.79,119.18 155.19,119.18 155.38,118.99 156.24,118.99 SB1.AN15 SB1.AR15 157.74,118.53 159.02,117.25 159.08,117.25 159.36,116.96 159.36,116.91 159.57,116.7 159.68,116.7 159.75,116.63 SB1.BB11 161.1,116.59 162.3,115.39 163.2,115.39 163.63,115.82
  TOP w0.381: v3(167.56,108.51) 167.49,108.45 R2303.2 166.45,108.24 166.32,108.24 165.94,107.86 165.81,107.86 R2310.2
  TOP w0.508: 163.63,115.82 163.74,115.93 163.76,115.93 164.01,116.18 164.18,116.18 164.38,116.38 166.73,116.38 C2108.1 v3(168.22,116.18) 169.63,116.18 R9936.1 170.37,114.74 v2(170.03,114.4) 170.03,113.18 v3(170.21,113) ; R9937.1 167.41,106.4 v3(166.17,106.4)
  BOTTOM w0.381: v3(166.17,106.4) 166.85,107.8 v3(167.56,108.51)
  BOTTOM w0.508: R2101.2 168,116.5 168,116.41 v3(168.22,116.18) ; v3(167.56,108.51) 167.8,108.51 170.21,110.92 v3(170.21,113)
1D8V_SB_CNVI: length 18.3
  TOP w0.254: v3(159.54,124.79) 159.06,124.79 158.51,124.24 158.51,123.92 157.9,123.32 157,123.32 SB1.AN24
  TOP w0.508: v3(169.46,119.48) 169.1,119.84 R2102.1
  BOTTOM w0.508: v3(159.54,124.79) 160.19,124.14 160.19,123.27 160.54,122.92 160.6,122.92 161.8,121.72 162.47,121.72 165.14,119.04 v2(165.43,119.04) 165.44,119.04 165.88,118.6 166.45,118.6 166.47,118.58 R2101.1 168.32,118.58 169.09,119.34 169.32,119.34 v3(169.46,119.48)
1D24V_PCH: length 8.3
  TOP w0.254: SB1.AJ22 154.75,122.07 155.28,122.07 SB1.AK22 ; SB1.AK23 155.21,122.54 154.81,122.54 SB1.AJ23
  TOP w0.279: 165.15,113.12 164.8,112.77 164.31,112.77 164.01,113.08 164.01,113.2 163.76,113.45 163.7,113.45 SB1.BG5
  TOP w0.508: v1(166.18,112.71) 166.41,112.71 167.03,113.33 C2109.1 166.96,113.46 166.82,113.6 165.63,113.6 165.15,113.12
  BOTTOM w0.254: v3(157.93,122.36) v2(157.1,122.96)
2D5V_VPP_S3: length 24.3
  TOP w0.508: 138.5,166.46 DIMM2.287 ; DIMM2.287 138.5,167.94 ; DIMM2.287 137.76,167.2 ; DIMM2.287 139.24,167.2 ; DIMM2.286 138.39,168.8 ; DIMM2.286 137.65,168.06 ; DIMM2.286 137.65,169.54 ; 139.35,168.06 DIMM2.288 ; DIMM2.288 138.61,168.8 ; DIMM2.288 139.35,169.54 ; 138.5,162.66 DIMM2.143 ; DIMM2.143 139.24,163.4 ; DIMM2.143 138.5,164.14 ; DIMM2.143 137.76,163.4 ; 137.65,160.46 DIMM1.286 ; DIMM1.286 138.39,161.2 ; DIMM1.286 137.65,161.94 ; 138.5,158.86 DIMM1.287 ; DIMM1.287 137.76,159.6 ; DIMM1.287 139.24,159.6 ; DIMM1.287 138.5,160.34 ; DIMM1.288 139.35,161.94 ; DIMM1.288 138.61,161.2 ; DIMM1.288 139.35,160.46 ; 137.65,156.66 DIMM1.142 ; DIMM1.142 137.65,158.14 ; DIMM1.142 138.39,157.4 ; DIMM2.142 138.39,165 ; DIMM2.142 137.65,165.74 ; DIMM2.142 137.65,164.26 ; DIMM1.143 138.5,156.54 ; DIMM1.143 137.76,155.8 ; DIMM1.143 139.24,155.8
  vias: v4(118.19,171.69) v4(118.93,171) v4(122.96,173.25) v4(123.67,172.49)
3D3V_AUD_S0: length 36.5
  TOP w0.305: U2701.48 62.18,255.02 v3(61,253.84) 60.6,253.44 C2714.1 ; L2703.2 67.67,248.51 66.59,248.51 66.59,248.51 C2713.1 66.47,248.51 65.38,248.51 L2702.2 65.15,248.54 64.9,248.54 v3(64.34,249.1) ; v3(57.86,262.13) 57.86,262.83 58.82,263.79 C2706.1 59.22,264.01 C2707.1 60.29,262.94 61.57,262.94 62.18,262.33 U2701.37 ; U2701.5 65.67,253.77 64.68,252.78 64.49,252.78 64.19,252.48 v3(64.19,252.37) 64.06,252.25 64.06,252.15 63.89,251.99 63.89,251.64 63.98,251.55 C2718.1
  BOTTOM w0.305: v3(64.34,249.1) 64.19,249.25 v3(64.19,252.37) 62.46,252.37 v3(61,253.84) v2(61,258.52) 61,258.99 v3(57.86,262.13)
3D3V_CARD_S0: length 3.5
  TOP w0.305: v4(41.05,256.29) 40.88,256.12 39.81,256.12 39.49,256.45 U3301.5
  BOTTOM w0.508: v4(41.05,256.29) v2(39.93,256.29)
3D3V_LAN: length 24.7
  TOP w0.203: 135.76,26.59 136.27,26.09 U3101.32 ; U3101.11 137.45,20.81 137.21,20.57 ; 141.36,25.39 140.97,25 U3101.23
  TOP w1.016: v3(141.99,26.04) 141.99,26.02 141.36,25.39
  BOTTOM w1.016: 131.5,27.13 129.97,27.13 127.28,24.43 127.18,24.43 126.36,23.62 v2(122.86,23.62) 115.13,23.62 RJ45R1.21
  vias: v3(132.26,27.99) v3(133.07,28.02) v3(136.75,20.09) v3(136.93,19.35) v3(142.16,26.95)
3D3V_PCIVAUX_SB: length 4.9
  TOP w0.508: C9312.1 168.47,55.12 v3(167.39,55.12)
  BOTTOM w1.016: 165.65,54.84 SLOT1.B10 166.55,53.94 ; 185.16,53.79 SLOT2.B10 185.37,54.47
  vias: v2(173.41,56.13) v3(176.38,53.72) v3(176.55,54.57) v3(177.24,53.72) v3(177.47,54.55)
3D3V_S0: length 791.6
  TOP w0.203: U5901.14 55.79,22.24 55.66,22.37 ; 54.72,16.27 55.39,16.93 U5901.26 ; 165.66,13.52 165.89,13.74 U2401.4 165.89,15.55 166.07,15.72 166.85,15.72 167.41,16.28
  TOP w0.254: v3(54.47,23.15) 54.88,23.15 55.66,22.37 ; C6201.1 132,17.42 NGFF2.70 ; 131.5,16.99 NGFF2.72 ; C6213.1 130.81,16.89 131,16.7 NGFF2.74
  TOP w0.305: 38.99,255.65 38.99,255.65 U3301.4 ; NGFF2.12 146.5,16.83 146.69,17.02 ; 146,16.97 NGFF2.14 ; RN2405.3 167.9,35.2 167.9,35.69 167.57,36.02 167.49,36.02 167.43,36.08 167.25,36.08 RN2405.4 ; NGFF2.16 145.5,17 ; 149,17.07 NGFF2.2 ; 148.5,17.06 NGFF2.4 ; 145,16.91 NGFF2.18
  TOP w0.356: v3(167.87,38.56) 168.1,38.56 168.71,39.17 Q2406.4
  TOP w0.406: 66.02,18.62 v3(66.92,18.62) ; 66.02,18.62 65.6,18.19 R5610.2 ; 66.02,18.62 65.53,19.11 Q5601.5 Q5601.2 ; U5601.5 U5601.2 68.83,18.68 68.77,18.62 v3(68.77,18.62) ; 165.66,13.52 165.12,13.52 164.82,13.22 164.82,13.21 163.7,12.09 C2406.1 163.53,11.57 163.07,11.11 163.07,10.97 163.04,10.95 163.04,8.76 163.74,8.06 v3(163.74,7.99)
  TOP w0.508: C6201.1 132.14,17.59 132.64,18.08 132.64,18.39 v3(132.66,18.41) ; 167.41,16.28 167.55,16.42 167.55,22.74 v3(165.95,24.35) ; 160.82,35.28 R2405.1 v3(160.82,36.96) ; v3(169.11,124.47) R2001.2 169.94,125.62 171.77,127.44 172.11,128.25 172.11,129.23 171.72,129.62 171.65,129.62 v3(171.2,130.07) ; R1706.2 154.05,145.75 154.03,145.78 154.03,146.03 153.16,146.89 153.16,148.08 152.81,148.43 152.17,148.43 ; R1911.2 160.41,142.9 R1704.2 160.46,143.67 159.49,144.65 v3(159.41,144.65) ; 152.17,148.43 154.95,151.21 v3(157.23,151.21) 157.23,153.37 158.55,154.69 161.31,154.69 161.43,154.57 R1601.2 164.39,154.57 R6415.1 164.62,154.81 168.1,154.81 168.37,155.08 170.57,155.08 171.55,154.1 171.55,153.54 173.02,152.07 173.02,144.61 172.77,144.35 172.77,137.23 172.07,136.53 R6404.1 R6403.1 172.06,135.49 172.06,134.33 172.24,134.15 v3(172.24,133.99) ; 152.17,148.43 152.17,148.38 151.63,147.84 R1714.2 151.63,147.64 150.85,146.86 150.85,145.83 150.38,145.36 R1912.2 R6402.1 ; v3(135.22,5.16) 134.79,4.72 R1805.2 ; DIMM2.284 135.95,168.21 135.65,167.91 ; DIMM2.284 135.21,168.8 ; DIMM2.284 135.38,168.23 ; R4801.1 156.17,187.58 155.33,187.58 152.73,184.98 v3(152.73,184.71) ; v3(185.6,9.78) 185.67,9.7 185.67,9.68 186.79,8.56 186.79,8.5 187.02,8.28 187.07,8.28 187.39,7.96 LPC1.10 ; v3(175.39,54.36) R1806.1 ; v3(167.87,38.56) 167.77,38.56 167.12,37.91 R2415.1 ; 135.21,165 DIMM2.140 ; DIMM2.140 135.95,165.74 ; DIMM2.140 135.95,164.26 ; C9311.1 v3(174.37,54.33) ; v3(80.16,22.68) 80.16,17.48 79.63,16.94 79.63,14.48 v3(77.22,12.06) ; R2413.1 165.51,37.95 166.62,36.83 166.62,36.7 167.25,36.08 ; R2413.1 164.47,37.1 164.47,36.25 164.01,35.79 164.01,35.63 RN2401.5 ; R2413.1 R2414.1 R2412.1 ; R2003.2 168.08,104.66 166.96,103.53 v3(165.15,103.53) ; v3(77.09,266.7) 78.71,268.33 78.71,269.13 79.48,269.9 80.03,269.9 80.42,269.51 80.42,269.21 v3(80.52,269.11) ; R6314.1 33.34,248.36 32.41,248.36 ; R4022.2 93.54,174.3 93.1,174.74 93.1,175.74 92.44,176.4 89.59,176.4 v3(86.77,179.22) ; v3(12.62,134.92) 13,134.92 D2601.K 13.97,135.13 13.97,133.83 R2603.1 ; v3(164.19,102.46) 163.61,103.04 163.45,103.04 R2329.2 ; R2463.2 158.83,20.18 v3(158.06,20.18) 158.12,20.13 158.12,19.16 R2464.2 R2435.1 ; v3(21.02,176.24) 21.02,176.21 20.37,175.56 v3(13.72,175.56) ; R9922.1 25.64,255.41 25.07,255.98 R6421.2 24.85,258.08 24.41,258.52 24.41,260.13 25.08,260.81 26.28,260.81 v3(26.29,260.82) 26.29,260.8 26.49,260.6 R6416.1 ; R1910.2 183.91,17.37 183.91,16.86 184.21,16.55 R2462.2 R2476.2 184.37,15.29 184.8,14.86 185.22,14.86 185.85,14.22 v3(186.18,14.22) ; D2602.K 108.2,259.46 108.26,259.4 v3(108.84,259.4) 109.37,258.87 109.37,257.41 108.5,256.54 R2616.1 ; v3(49.29,23.35) 49.29,23.3 L5902.1 ; v3(55.88,254.38) 55.88,255.68 v3(55.4,256.16) ; v3(131.86,6.95) 132.5,7.59 132.54,7.59 133.28,8.34 133.28,11.54 134.11,12.37 v3(134.11,16.08) ; SLOT2.A10 179.55,54.72 176.12,58.15 R1807.2 ; v3(145.28,23.1) 144.88,22.71 R3103.1 ; v3(9.14,167.51) 9.6,167.06 9.6,166.47 10.24,165.83 10.24,162.63 10.31,162.55 10.31,147.55 v3(11.56,146.3) ; R2706.1 59.46,258.03 59.26,258.23 R2707.1 57.8,258.23 v3(57.61,258.04) ; DIMM1.284 135.95,161.94 ; DIMM1.284 135.95,160.46 ; DIMM1.284 135.21,161.2 ; L5901.1 63.25,16.54 63.4,16.39 63.4,14.43 61.95,12.98 61.95,12.08 61.94,12.08 61.94,11.85 v4(61.77,11.68) 60.99,11.68 60.41,12.26 R5902.1 R5901.1 ; v3(170.05,9.01) 170.23,9.19 R2002.2 ; L2702.1 65.78,246.39 65.78,245.75 66.6,244.93 67.25,244.93 R2717.1 ; L2702.1 64.96,246.57 64.58,246.57 v3(64.26,246.25) ; L2702.1 65.28,247.01 64.31,247.98 v3(64.31,248.28) R2302.2 ; v3(104.17,33.62) 104.2,33.59 R4003.1 ; v3(98.15,28.83) 97.92,29.06 R4005.1 ; v3(169.06,51.66) C9403.1 ; R9101.1 157.23,172.85 v3(157.2,172.87) ; R1801.2 v4(32.64,222.76)
  TOP w0.559: R9922.1 25.64,254.24 26.9,252.98 27.64,252.98
  TOP w0.635: v4(71.2,15.88) 70.36,16.71 v3(70.36,18.41)
  TOP w0.762: v4(38.38,195.07) 38.38,193.32 v4(39.29,192.41) ; v4(34.49,231.39) 33.25,232.64 33.25,235.48 32.41,236.32 32.41,249.37 28.8,252.98 27.64,252.98
  TOP w1.016: v4(63.58,194.18) 62.69,194.18 60.63,196.24 58.39,196.24 58.34,196.19 v4(58.06,196.19) ; v4(71.45,192.35) 71.45,192.35 80.02,192.35 80.44,192.77 83.37,192.77 84.15,193.55 84.15,193.86 SATAP1.6
  L3SGND w0.508: SLOT1.A10 160.05,53.94 ; SLOT1.A10 158.25,53.94 ; SLOT1.A10 159.15,53.04 ; SLOT1.A10 159.15,54.84 ; 160.25,52.94 SLOT1.A9 ; SLOT1.A9 161.15,53.84 ; SLOT1.A9 161.15,52.04 ; SLOT1.A9 162.05,52.94
  L3SGND w1.016: 182.44,52.79 SLOT2.A9 180.66,52.79 ; 178.66,53.79 SLOT2.A10 ; SLOT2.A10 180.44,53.79 ; SLOT2.A10 179.55,54.68 ; 186.94,51.79 SLOT2.B8 185.16,51.79 ; 166.55,51.94 SLOT1.B8 164.75,51.94
  BOTTOM w0.381: DIMM1.284 DIMM2.140 DIMM2.284
  BOTTOM w0.406: v3(70.36,18.41) 70.15,18.62 v3(68.77,18.62)
  BOTTOM w0.508: v3(21.02,176.24) 21.05,176.24 21.34,176.53 29.41,176.53 30.1,177.22 30.1,177.3 31.19,178.4 31.19,181.75 36.8,187.36 36.8,189.05 ; v3(135.22,5.16) 135.22,5.67 133.94,6.95 v3(131.86,6.95) ; v3(11.56,146.3) 11.4,146.15 11.4,136.14 v3(12.62,134.92) ; v3(108.84,259.4) 90.95,259.4 86.37,263.98 84.08,263.98 80.42,267.65 80.42,269.01 v3(80.52,269.11) ; v3(152.73,184.71) 153.57,184.71 v3(156.45,181.83) ; v3(157.23,151.21) 158.24,150.19 158.24,149.94 159.41,148.78 v3(159.41,144.65) ; 160.25,52.94 SLOT1.A9 ; SLOT1.A9 161.15,52.04 ; SLOT1.A9 162.05,52.94 ; v3(66.92,18.62) 66.92,18.6 67.56,17.96 68.11,17.96 v3(68.77,18.62) ; v3(64.31,248.28) 63.65,248.28 60.66,251.28 60.66,251.68 59.15,253.19 57.07,253.19 v3(55.88,254.38) ; v3(64.26,246.25) 68.3,250.29 68.79,250.29 69.3,250.81 69.3,250.86 71.58,253.13 71.58,254.12 72.12,254.66 72.15,254.66 75.05,257.56 76.07,257.56 76.48,257.96 76.52,257.96 76.91,258.35 76.91,258.9 76.86,258.95 76.86,259.66 76.81,259.71 76.81,264.01 77.09,264.29 v3(77.09,266.7) ; v3(172.24,133.99) 172.24,132.78 170.84,131.39 170.84,130.43 v3(171.2,130.07) ; v3(9.14,167.51) 9.14,169.04 9.27,169.17 9.27,172.54 10.46,173.74 11.94,173.74 13.72,175.51 v3(13.72,175.56) ; v3(186.18,14.22) 186.16,14.2 186.16,13.96 185.94,13.74 185.94,13.72 185.62,13.4 185.62,12.69 185.6,12.67 185.6,9.78 v3(185.6,9.78) 185.5,9.88 182.58,9.88 180.65,7.96 175.93,7.96 174.35,9.53 174.35,9.54 173.84,10.06 172.19,10.06 171.55,9.42 171.55,9.33 171.17,8.94 170.62,8.94 170.58,8.98 170.09,8.98 v3(170.05,9.01) 169.72,9.35 166.52,9.35 165.61,8.43 164.19,8.43 v3(163.74,7.99) ; v3(80.16,22.68) 80.21,22.68 82.33,24.8 87.9,24.8 88.55,25.45 90.92,25.45 92.83,27.36 96.68,27.36 v3(98.15,28.83) 98.63,29.31 98.7,29.31 99.09,29.7 99.09,30.16 102.55,33.62 v3(104.17,33.62) ; SLOT1.A10 160.05,53.94 ; SLOT1.A10 158.25,53.94 ; SLOT1.A10 159.15,53.04
  BOTTOM w0.762: v3(26.29,260.82) 26.29,260.76 34.78,252.27 36.28,252.27 36.76,252.76 37.41,252.76 37.89,252.27 v3(38.81,252.27) 51.51,252.27 v3(55.4,256.16) 57.28,258.04 v3(57.61,258.04) ; v4(38.38,195.07) 38.38,198.97 30.23,207.13 30.23,207.21 30.12,207.31 30.12,213 31.33,214.21 31.33,220.94 32.64,222.25 v4(32.64,222.76) 33.02,223.14 33.02,227.56 34.49,229.03 v4(34.49,231.39)
  BOTTOM w1.016: v4(58.06,196.19) 57.36,195.49 57.36,195 57.84,194.53 57.84,192.12 57.33,191.61 57.33,190.96 ; 185.37,51.11 SLOT2.B8 185.16,51.79 ; v4(71.45,192.35) 70.16,192.35 68.33,194.18 v4(63.58,194.18) ; 178.87,53.11 SLOT2.A10 178.66,53.79 ; 182.23,52.11 SLOT2.A9 180.87,52.11 ; 164.75,51.94 SLOT1.B8 166.55,51.94 ; v3(128.63,18.67) 127.18,17.22 127.18,11.31 125.83,9.96 125.83,8.12 124.72,7.01 123.9,7.01 121.83,4.95 98.82,4.95 97.34,6.43 81.37,6.43 77.22,10.58 v3(77.22,12.06) 76.02,13.26 72.77,13.26 71.2,14.83 v4(71.2,15.88) 66.85,11.53 64.26,11.53 64.11,11.68 v4(61.77,11.68) 60.99,12.47 54.58,12.47 v4(54.25,12.8) 54.25,13.36 51.66,15.95 51.66,17.9 52.83,19.08 53.39,19.08 55.12,20.8 55.12,20.83 55.17,20.88 55.17,20.95 55.37,21.15 55.37,22.04 55.12,22.29 55.12,22.5 v3(54.47,23.15) 54.43,23.19 49.45,23.19 v3(49.29,23.35)
  vias: v2(82.08,177.64) v2(171.75,52.7) v3(130.12,16.31) v3(141.73,17.03) v3(142.52,17.03) v3(155.85,26.49) v3(155.98,25.48) v3(156.92,174.47) v3(157.02,173.66) v3(157.68,174.38) v3(157.78,173.63) v3(158.01,172.82) v3(163.17,95.91) v3(164.54,100.25) v3(169.86,56.01) v4(36.07,190.2) v4(37.08,190.28) v4(38.28,190.14) v4(39.29,190.23) v4(41.4,189.48) v4(42.42,189.52) v4(43.41,189.48) v4(44.32,189.52) v4(118.36,174.5) v4(118.77,175.31) v4(119.2,176.2) v4(119.46,174.5) v4(119.69,175.39) v4(188.11,142.67) v4(189.03,142.67) v4(189.94,142.7) v4(189.92,141.79) v4(190.75,142.24) v4(190.78,141.3) v4(191.59,56.9) v4(191.59,55.85) v4(191.59,54.76) v4(191.59,53.85) v4(191.59,52.88) v4(191.59,51.87) v4(191.66,142.25) v4(191.69,141.27)
3D3V_S5: length 323.2
  TOP w0.203: 179.84,25.21 179.6,24.98 U2401.55 177.46,24.98 176.82,25.62 176.82,26.59 177.21,26.98 U2401.60 ; v3(161.42,26.2) 161.51,26.2 161.93,25.78 U2401.104 ; v3(164.44,19.08) 164.44,19.22 164.29,19.38 U2401.120 ; 171.93,31.59 172.29,31.23 U2401.77 ; U2401.22 173.09,13.38 172.47,12.75 ; 177.09,31.36 U2401.65 ; 176.08,16.42 176.88,15.62 176.89,15.62 177.09,15.42 U2401.32 177.85,14.63 ; U2401.45 180.06,20.98 v3(180.16,21.08)
  TOP w0.254: v1(164.47,135.81) 164.39,135.89 163.3,135.89 162.76,135.35 SB1.BE49 SB1.BE48 ; PR4908.1 29.18,178.69
  TOP w0.305: RN2001.4 169.94,136.9 170.23,137.19 ; RN2001.3 170.05,136.25 170.23,136.07
  TOP w0.508: C2107.1 170.13,137.29 170.23,137.19 ; 172.47,12.75 172.09,12.37 v3(172.09,12.22) C2416.1 ; C2417.1 v3(161.42,26.2) ; C2415.1 180.06,11.82 180.06,12.19 180.29,12.42 v3(180.29,12.76) 180.17,12.89 180.17,12.96 179.75,13.38 179.75,13.38 179.64,13.49 179.56,13.49 178.42,14.63 177.85,14.63 ; R2014.2 177.55,59.88 178.05,59.37 v3(178.05,58.29) ; v3(164.85,40.89) 164.85,41.16 165.59,41.9 166.17,41.9 170.79,46.51 170.79,59.31 v3(170.26,59.84) ; 170.23,137.19 170.23,135.76 169.48,135.01 R2318.2 169.14,135.01 169.06,134.94 168.3,134.94 168.22,135.01 168.15,135.01 R2015.2 ; 170.23,137.19 171.75,137.19 172.03,137.47 172.03,140.69 170.81,141.9 v3(170.81,142.18) 170.38,142.18 v3(169.04,140.84) ; 171.93,31.59 171.47,32.05 ; 171.47,32.05 v3(171.32,32.05) ; 171.47,32.05 171.52,32.05 172.17,32.71 C2423.1 172.15,32.92 C2422.1 ; v3(50.72,253.31) 51.89,252.15 v3(52.86,252.15) ; R2403.1 v3(158.24,41.53) ; U2601.5 178.6,8.23 178.09,8.74 178.02,8.74 177.37,9.39 v3(177.37,9.98) ; 179.84,25.21 v3(180.11,25.49) 181.28,26.65 181.28,26.67 181.66,27.05 182.26,27.05 182.71,27.5 C2419.1 183.63,26.77 C2424.1 ; R6304.2 67.35,236.11 67.88,235.57 68.93,235.57 70.05,236.7 v3(70.05,240.21) 70.05,249.79 70.53,250.88 72.76,253.11 76.1,256.45 76.2,256.5 76.34,256.5 76.67,256.73 76.71,256.76 R3807.1 ; R2714.2 54.2,264.35 Q2701.E 54.29,263.33 54.34,263.28 C2721.1 53.48,262.51 R2504.1 53.33,262.51 53.35,262.48 v3(53.35,261.7) ; C2418.1 182.03,21.08 v3(180.16,21.08) ; v3(167.39,28.8) 167.74,28.45 167.74,28.3 169.09,26.95 174.52,26.95 v3(174.75,27.18) v3(174.75,23.88) 174.62,23.75 v3(174.62,22.35) v3(174.62,21.21) 173.94,20.52 173.94,18.56 176.08,16.42 ; v4(22.15,243.51) 22.61,243.05 22.61,240.2 22.1,239.69 21.38,239.69 R6417.1 ; 100.33,177.62 PR5202.1 ; v3(177.44,33.15) 176.94,33.64 C2420.1 C2421.1 175.74,33.21 176.25,32.7 176.78,32.7 177.29,32.19 177.29,31.56 177.09,31.36
  BOTTOM w0.508: v3(50.72,253.31) 53.35,255.94 v3(53.35,261.7) ; v3(70.05,240.21) 68.2,238.35 53.37,238.35 52.58,239.14 ; v3(174.75,23.88) 174.21,23.88 171.95,21.62 171.62,21.62 171.2,21.2 169.5,21.2 167.38,19.08 v3(164.44,19.08) ; v3(169.04,140.84) 169.04,140.43 167.23,138.63 167.23,138.35 166.47,137.59 166.17,137.59 164.47,135.88 v1(164.47,135.81) ; v4(22.23,244.42) 22.63,244.83 22.63,244.88 23.06,245.31 23.11,245.31 23.35,245.55 23.35,245.78 27.64,250.06 50.77,250.06 v3(52.86,252.15) ; v3(177.44,33.15) 177.29,33 177.29,32.64 177.19,32.54 177.19,31.78 175.44,30.02 175.44,27.86 v3(174.75,27.18) ; v3(158.24,41.53) 158.24,41.4 158.75,40.89 v3(164.85,40.89) 164.94,40.89 166.01,39.82 166.01,38.43 164.64,37.06 164.64,34.75 167.16,32.23 171.15,32.23 v3(171.32,32.05) 171.32,31.75 168.81,29.24 167.82,29.24 v3(167.39,28.8) 164.02,28.8 v3(161.42,26.2) ; v3(178.05,58.29) 177.93,58.17 175.98,58.17 174.93,59.21 173.31,59.21 172.95,59.56 172.69,59.56 172.42,59.84 v3(170.26,59.84) ; v3(180.16,21.08) 179.65,21.59 176.53,21.59 176.15,21.21 v3(174.62,21.21) ; v3(172.09,12.22) 175.18,12.22 175.36,12.04 175.8,12.04 177.16,10.68 177.16,10.19 v3(177.37,9.98) 178.89,11.51 179.03,11.51 v3(180.29,12.76) ; v3(170.81,142.18) 171.41,142.77 171.69,142.77 172.46,143.54 172.6,143.54 173.25,144.19 173.25,144.44 173.28,144.51 173.28,144.71 173.75,145.18 174.02,145.75 174.02,152.9 173.85,153.22 172.55,154.52 172.53,154.52 172.08,154.97 171.36,155.69 171.36,156.92 v3(171.31,156.97) ; v3(174.62,22.35) 175.13,22.35 178.27,25.49 v3(180.11,25.49)
  vias: v2(2.31,212.85) v2(9.75,190.93) v2(11.79,240.79) v3(185.28,43.72) v3(185.37,44.48) v3(186.13,44.48) v4(19.68,188.72) v4(19.67,187.71) v4(20.41,189.28) v4(20.5,188.24) v4(20.47,187.27) v4(23.37,244.58) v4(23.65,243.54) v4(29.41,184.89) v4(29.44,183.97) v4(29.49,189.51) v4(29.46,188.54) v4(29.46,187.63) v4(29.52,186.72) v4(29.49,185.8) v4(29.47,183.06) v4(38.86,244.22) v4(39.37,243.33) v4(39.88,244.22) v4(40.39,243.33) v4(89.43,179.5) v4(90.47,179.45) v4(91.44,179.52) v4(92.36,179.57) v4(93.27,179.63) v4(161.75,160.2) v4(161.75,159.28) v4(161.75,158.37) v4(187.86,145.43) v4(188.32,146.22) v4(188.93,145.54)
3D3V_SB: length 431.1
  TOP w0.203: U2401.27 175.09,12.74 175.21,12.62 175.21,12.57 175.23,12.55 175.23,12.03 C2408.1
  TOP w0.254: v1(160.12,125.3) 160.03,125.21 160.03,125.02 160.05,125 160.05,124.58 160.03,124.57 160.03,123.84 159.27,123.08 159.27,122.76 158.37,121.87 158.04,121.87 157.82,121.64 157.82,121.4 157.1,120.68 157.1,120.65 v3(157.09,120.64) 157.09,120.99 SB1.AN21 ; v3(157.2,115.06) 157.3,115.06 157.64,115.4 157.87,115.4 ; v3(161.98,117.98) 161.87,117.88 SB1.BB14
  TOP w0.305: SB1.AN44 156.7,132.97 157.79,132.97 SB1.AT44 157.98,132.8 157.99,132.81 158.41,132.81 158.42,132.8 158.55,132.8 v1(158.67,132.92) ; SB1.AN32 157.34,126.11 157.78,126.11 157.89,126.21 v3(157.95,126.21) 157.94,126.21 157.94,126.06 157.8,125.92 157.8,125.24 157.86,125.18 157.86,124.63 157.77,124.54 157.77,124.49 SB1.AP26 SB1.AN26 ; SB1.V23 149.57,122.35 149.63,122.35 v1(149.65,122.34) ; SB1.BB7 160.25,114.91 SB1.AY8 159.88,115.29 SB1.AW9 159.2,115.68 158.88,115.99 158.46,115.99 157.87,115.4 ; U9101.1 160.39,175.63 160.38,175.64 ; U2405.5 32.65,172.02 33.15,172.52 v3(33.38,172.52)
  TOP w0.406: C4011.1 26.14,175.53 26.14,174.9 26.15,174.89 U4010.5 ; v3(97.73,26.27) 98.65,25.35 v3(98.65,21.67) ; U4009.5 111.57,32.45
  TOP w0.508: R1510.1 20.21,238.91 v3(21.06,238.91) ; v4(193.65,183.54) 194.03,183.92 PR5107.1 ; v3(186.15,17.88) 185.92,18.11 184.42,18.11 R2411.1 ; R1712.1 35.05,237.36 v4(35.05,238.3) ; v3(175.01,10.29) 174.99,10.3 174.99,11.03 175.21,11.25 175.21,11.3 175.23,11.33 175.23,12 C2408.1 ; v3(93.76,175.01) 93.76,175.1 R4018.1 ; R2478.2 34.07,173.02 33.57,172.52 v3(33.38,172.52) ; v3(151.38,186.13) 151.38,186.94 151.78,187.34 R4803.2 ; R2007.2 54.66,219.3 54.32,219.65 54.32,220.54 54.31,220.55 54.31,221.2 R1709.1 54.31,221.22 54.31,222.17 ; R4001.1 100.9,31.02 101.63,31.75 v3(102.62,31.75) ; R2307.2 v3(184.56,11.58) 184.4,11.73 R2431.2 ; R3808.1 77.47,265.62 v3(77.47,263.52) ; v3(72.39,254) 69.65,251.26 69.12,250.19 69.12,248.19 L2703.1 69.19,245.47 69.19,240.6 69.16,240.58 69.16,238.38 v3(69.14,238.35) ; R414.1 23.24,173.55 R413.1 v3(24.31,173.8) 24.31,173.85 24.61,174.16 24.61,175.03 25.12,175.54 C4011.1 ; R2432.2 166.01,35.36 166.34,35.69 166.34,35.86 v3(166.44,35.96) ; v3(187.68,24.26) 187.68,24.15 186.99,23.46 v3(186.99,20.62) ; 156.9,13.31 156.9,10.85 155.85,9.8 155.85,7.09 v3(156.21,6.73) ; R1508.1 168.59,131.67 R1902.2 168.9,131.76 v3(169.52,131.14) ; v3(163.38,118.34) 163.73,118.69 164.7,118.69 165.41,119.41 166.59,119.41 R2102.2 168.32,121.14 v3(168.32,121.42) ; R4017.1 99.32,175.71 99.32,176.43 99.29,176.45 v3(99.29,176.5) ; v3(170.54,129.49) 170,128.96 170,128.72 169.38,128.09 C2126.1 169.24,128.02 169.15,127.93 168.36,127.93 168.32,127.89 R2009.2 167.96,127.56 167.92,127.52 167.92,125.99 167.88,125.95 R2314.2 167.87,125.46 167.87,123.91 R2010.2 168.16,123.79 168.81,123.14 v3(168.81,122.96) ; v3(9.14,225.81) 6.05,225.81 5.76,225.53 5.76,225.37 R6410.1 4.78,225.93 4.78,230.99 5.45,231.67 R6412.1 ; v3(44.7,173.48) R4802.1 ; v3(123.98,4.83) 123.55,4.39 104.91,4.39 99.14,10.17 99.14,16.46 v3(99.72,17.04) ; R2425.2 R2477.2 174.51,35.64 173.52,35.64 R2427.2 R2421.2 172.3,35.65 v3(171.32,34.67) ; v3(182.37,164.06) 182.32,164.01 R9923.1 ; 111.57,32.45 111.84,32.18 112.02,32.18 112.46,31.74 C4007.1 114.49,31.5 114.54,31.45 115.79,31.45 R4011.1 116.09,31.75 116.25,31.75 117.83,33.33 v3(117.83,34.14)
  TOP w0.762: v3(45.19,234.59) 45.64,234.14 51,234.14 51.69,234.82 51.82,234.82 v3(54.08,237.08) 54.08,231.31 53.52,230.76 53.52,225.68 53.85,225.35 53.85,223.22 54.31,222.76 54.31,222.17
  TOP w1.016: v3(172.83,39.1) 172.89,39.16 172.89,45.64 174.24,46.99 v3(174.5,46.99)
  L3SGND w0.508: v1(160.12,125.3) 159.96,125.3 159.81,125.45 159.51,125.45 159.48,125.48 158.96,125.48 158.84,125.6 158.26,125.6 158.13,125.48 157.72,125.48 156.46,126.74 156.26,126.74 155.88,127.11 155.88,127.64 156.31,128.07 156.62,128.07 157.95,129.4 157.95,129.77 158.75,130.57 158.75,131.95 158.83,132.04 158.83,132.76 v1(158.67,132.92)
  BOTTOM w0.381: v3(157.95,126.21) 158.57,125.59 159.4,125.59 159.63,125.36 160.06,125.36 v1(160.12,125.3)
  BOTTOM w0.508: v1(160.68,104.65) 160.45,104.88 160.45,105.33 160.45,105.73 160.63,105.91 160.63,107.14 160.63,107.14 160.63,107.3 160.27,107.66 160.27,109.5 159.74,110.03 159.74,111.17 158.52,112.39 158.52,113.73 157.4,114.85 157.4,114.85 v3(157.2,115.06) ; v4(185.85,181.69) 185.85,182.09 186.56,182.8 189.25,182.8 189.84,183.39 193.5,183.39 v4(193.65,183.54) ; v3(117.83,34.14) 117.13,34.84 108.89,34.84 106.54,32.49 103.35,32.49 v3(102.62,31.75) 100.05,29.18 99.99,29.18 97.73,26.93 v3(97.73,26.27) ; v3(170.54,129.49) 170.15,129.87 170.15,130.51 v3(169.52,131.14) ; v3(170,36.44) 169.92,36.35 166.75,36.35 166.44,36.04 v3(166.44,35.96) ; v3(186.99,20.62) 186.66,20.62 186.15,20.12 v3(186.15,17.88) 186.15,15.13 184.96,13.94 184.96,11.99 v3(184.56,11.58) 182.75,11.58 179.76,8.59 176.19,8.59 174.99,9.8 174.99,10.3 ; 174.99,10.3 174.49,10.3 174.1,10.69 171.93,10.69 171.87,10.63 v2(169.24,10.63) 166.64,10.63 165.18,9.17 163.83,9.17 161.53,6.87 160.85,6.87 160.56,6.58 158.23,6.58 158.08,6.73 v3(156.21,6.73) ; 174.99,10.3 v3(175.01,10.29) ; v3(77.47,263.52) 77.47,263.49 77.55,263.41 77.55,258.09 76.79,257.33 76.74,257.33 76.34,256.92 75.68,256.92 75.68,256.92 75.31,256.92 v3(72.39,254) ; v3(162.69,147.57) 162.69,143.74 160.27,141.33 160.27,139.44 159.21,138.38 159.21,137.16 159.28,137.08 159.28,134.35 158.67,133.74 v1(158.67,132.92) ; v3(187.68,24.26) 188.39,24.26 192.18,20.47 R2034.1 194.06,20.43 194.06,19.56 JMP1.2 ; v3(98.65,21.67) 97.91,20.92 97.91,18.85 v3(99.72,17.04) ; v3(123.98,4.83) 124.82,5.66 125.51,5.66 127.56,7.71 127.56,9.78 128.55,10.78 128.55,16.05 129.79,17.3 137.21,17.3 137.58,17.68 v3(139.65,17.68) ; v1(160.12,125.3) 160.12,125.1 161,124.22 164.23,124.22 165.01,123.44 166.3,123.44 v3(168.32,121.42) 168.71,122.07 168.71,122.86 v3(168.81,122.96) ; v3(161.98,117.98) 162.33,118.34 v3(163.38,118.34) ; v3(54.08,237.08) 56.11,237.08 56.74,237.72 68.46,237.72 68.59,237.85 68.63,237.85 v3(69.14,238.35) ; v4(185.36,174.13) 185.25,174.13 181.84,170.72 181.84,169.99 181.84,169.99 181.84,169.13 181.86,169.1 181.86,167.34 181.86,166.48 182.27,166.07 182.27,164.95 182.37,164.85 v3(182.37,164.06)
  BOTTOM w0.762: v3(172.21,48.67) v3(174.37,48.67)
  BOTTOM w1.016: v3(170,36.44) 170.17,36.44 v3(172.83,39.1)
  vias: v2(165.71,26.14) v3(46.36,171.46) v3(47.12,171.42) v3(47.88,171.42) v3(140.67,17.78) v3(153.57,140.56) v3(154.89,140.84) v3(155.95,24.13) v3(156.59,20.19) v3(158.37,148.08) v3(158.37,147.32) v3(158.37,146.56) v3(158.37,145.8) v3(158.37,144.91) v3(159.09,183.86) v3(159.79,153.82) v3(160.55,153.82) v3(161.04,155.96) v3(161.7,156.64) v3(161.8,155.88) v3(174.65,49.71) v3(175.23,48.46) v3(176.07,48.46) v3(184.64,129.2) v3(184.79,130.05) v3(185.47,129.7) v4(6.96,214.48) v4(6.96,213.46) v4(6.96,212.45) v4(40.82,172.77) v4(153.62,129.77) v4(153.57,128.93) v4(159.69,183.24) v4(159.94,177.44) v4(159.94,176.53) v4(160.12,182.4)
3D3V_SPI: length 28.5
  TOP w0.508: R2317.2 167.33,145.59 167.33,145.59 167.62,145.88 167.62,145.88 167.9,146.16 v3(167.9,146.94) 167.89,146.94 167.7,147.13 R2313.2 R2325.2 ; U2501.8 170.93,165.57 170.13,164.77 U2502.2 SSKT2.2 167.94,164.77 167.44,164.26 167.44,163.89 166.93,163.39 166.75,163.39 R2502.1 166.62,163.26 166.62,162.5 166.69,162.43 C2501.1 166.62,162.29 R2503.2 167.46,160.45 v3(167.46,160.28) 167.34,160.16 R2501.1
  BOTTOM w0.508: v3(167.9,146.94) v2(167.9,147.98) 167.9,150.45 168.07,150.62 168.07,152.19 167.97,152.3 167.97,153.01 168.12,153.16 168.12,159.62 v3(167.46,160.28)
3D3V_WLAN_SB: length 2.6
  TOP w0.305: NGFF1.4 43.33,210.42 ; NGFF1.72 43.27,227.42
  vias: v2(49.63,226.11) v3(45.29,229.41) v3(45.29,228.5) v3(46.25,229.41) v3(46.25,228.5) v4(47.75,209.22) v4(48.69,209.73) v4(49.64,209.24)
3P0V_BAT_VREG: length 265.1
  TOP w0.254: SB1.BC49 SB1.BD49 162.26,135.35 163.15,136.25 164.22,136.25 164.92,136.94 164.92,137.34 166.45,138.86 166.45,139.29 167.54,140.39 167.79,140.39 169.62,142.21 v1(169.62,142.42)
  TOP w0.508: v3(154.58,194.67) 154.14,195.11 149.45,195.11 144.47,190.12 142.38,190.12 118.91,190.12 116.11,189.76 81.3,189.76 81.15,189.61 70.32,189.61 68.71,191.22 68.71,196.95 67.51,198.15 67.51,199.55 64.45,202.62 63.61,202.62 62.74,203.49 62.74,212.84 62.47,213.1 62.47,213.16 61.62,214.01 61.62,226.56 v2(61.76,226.69) 61.47,226.98 61.47,232.93 60.29,234.11 60.29,246.32 56.58,250.02 56.58,256.04 54.24,258.39 D2502.3 ; v3(168.25,179.43) 168.25,177.97 170.33,175.9 173.74,175.9 175.38,174.26 175.38,173.69 174.97,173.29 173.11,173.29 173.05,173.34 171.81,173.34 170.46,172 170.46,170.13 v3(169.04,168.71) ; v3(162.81,187.83) 162.15,188.49 162.15,195.1 v3(161.93,195.33) ; C2103.1 C2102.1 171.95,146.37 172.39,145.93 172.39,145.03 172.14,144.77 v3(172.14,144.65) ; v3(170.89,153.82) 170.88,153.82 170.26,154.45 168.63,154.45 168.24,154.05 166.16,154.05 165.33,153.22 165.33,152.41 165.17,152.24 R2040.2 165.17,151.67 165.24,151.6 165.24,150.67 R1507.2 165.24,150.57 R2042.1
  BOTTOM w0.508: v3(161.93,195.33) 155.12,195.33 154.58,194.79 v3(154.58,194.67) ; v3(168.25,179.43) 168.25,180.01 166.37,184.28 v3(162.81,187.83) ; v1(169.62,142.42) 169.62,143.05 170.54,143.97 170.54,144.06 171.13,144.65 v3(172.14,144.65) 172.14,145.57 172.91,146.34 172.91,151.77 172.56,152.11 172.45,152.23 172.29,152.39 172.29,152.39 v3(170.89,153.82) 170.88,153.82 169.8,154.91 169.8,161.76 169.62,162.4 169.62,165.91 169.04,166.5 v3(169.04,168.71)
3P3V_S5_EN: length 6.9
  TOP w0.102: 193.65,190.23 193.69,190.2 194.11,190.2 194.18,190.27 C5101.1 194.67,190.26 194.67,189.67 194.58,189.59 R5101.2 ; 193.65,190.23 193.22,189.8 193.22,189.28 192.89,188.95 192.68,188.95 192.18,188.44 192.18,188.11 191.9,187.84 PU5101.3 ; 193.65,190.23 v2(193.7,190.23)
A20GATE: length 5.9
  TOP w0.102: R2464.1 159.47,19.5 159.47,20.4 v2(160.02,20.95) 160.86,20.12 161.15,20.12 161.49,19.78 U2401.119
ACPRESENT: length 6.2
  TOP w0.102: R2015.1 167.75,134.52 v2(167.21,134.52) 167.03,134.7 166.1,134.7 165.86,134.46 165.86,134 164.7,132.84 164.61,132.84 163.69,131.91 163.69,131.87 SB1.BG42
ALDO_CAP: length 4.3
  TOP w0.305: U2701.23 71.47,261.08 71.53,261.14 71.54,261.14 71.7,261.31 71.7,261.32 71.96,261.57
  TOP w0.508: 71.96,261.57 72.82,262.43 C2710.1 v2(72.82,264.03)
ALL_SYS_PWRGD: length 5.1
  TOP w0.102: R4016.1 R4014.1 108.99,33.03 C4008.1 v2(109.86,34.16) 109.87,34.18 U4009.4
AUD_AZACPU_SCLK: length 77.2
  TOP w0.102: v1(117.58,93.86) 113.91,90.2 105.34,90.2 98.63,94.7 92.77,94.7 CPU1.V3 ; v1(158.75,104.01) R2027.1
  BOTTOM w0.102: v1(117.58,93.86) 117.75,94.03 119.05,94.03 121.36,96.34 133.12,96.34 139.89,96.72 140.11,96.72 142.32,96.58 149.17,96.58 149.44,96.85 149.44,96.85 149.77,97.18 156.29,97.18 v2(156.95,97.84) 156.95,98.21 158.75,100.01 v1(158.75,104.01)
AUD_AZACPU_SCLK_R: length 8.9
  TOP w0.102: SB1.AM3 156.4,112.59 156.6,112.38 156.6,112.03 156.98,111.65 156.98,109.96 157.46,109.49 157.65,109.49 159.21,107.92 159.21,107.77 159.21,107.77 159.21,107.58 158.68,107.05 158.57,107.05 158.3,106.78 158.3,106.4 158.75,105.95 R2027.2
AUD_AZACPU_SDI: length 27.8
  TOP w0.102: CPU1.U1 98.63,94.34 105.25,89.97 105.59,89.97 114.33,89.97 117.22,92.86 v2(117.39,92.86) 118.03,93.5 118.03,94.07 R702.1
AUD_AZACPU_SDI_R: length 56.2
  TOP w0.089: 157.19,111.26 157.19,111.78 156.8,112.17 156.8,112.82 SB1.AN3
  TOP w0.102: v3(119.4,95.94) 118.97,95.51 R702.2 ; v3(158.76,106.59) 159.44,107.27 159.44,107.98 157.73,109.69 157.54,109.69 157.19,110.04 157.19,111.26
  BOTTOM w0.102: v3(119.4,95.94) 120.12,95.94 v2(120.55,96.37) 120.85,96.67 133.2,96.67 139.87,96.95 140.21,96.95 143.57,96.82 143.7,96.81 149.08,96.81 149.21,96.95 149.68,97.41 155.72,97.41 158.32,100.01 158.32,106.15 v3(158.76,106.59)
AUD_AZACPU_SDO: length 78.8
  TOP w0.102: R2025.1 158.45,107.65 v3(157.92,107.12) ; CPU1.V2 93.48,94.9 98.81,94.9 105.4,90.45 113.46,90.45 117.9,94.88 117.9,95.29 v3(119.48,96.88)
  BOTTOM w0.102: v3(119.48,96.88) 119.6,96.99 131.81,96.99 132,97.18 132.01,97.17 141.9,97.17 142.25,97.16 143.06,97.09 143.36,97.07 143.71,97.04 148.98,97.04 149.58,97.64 155.63,97.64 157.12,99.14 157.12,99.69 v2(157.4,99.97) 158.09,100.66 158.09,101.51 158.09,105.69 157.92,105.85 v3(157.92,107.12)
AUD_AZACPU_SDO_R: length 4.6
  TOP w0.102: R2025.2 157.36,108.93 v2(157.36,108.93) 157.36,109.12 157.37,109.14 157.37,109.28 156.78,109.87 156.78,111.49 156.37,111.91 SB1.AM2
AUD_BEEP: length 5.3
  TOP w0.203: C2716.1 65.85,251.4 66.32,251.87 66.32,251.89 v3(66.34,251.92) 66.47,252.05 66.47,252.89 66.98,253.4 66.98,253.5 67.17,253.69 U2701.8
  BOTTOM w0.203: v3(66.34,251.92) 66.34,252.02 65.82,252.54 v2(65.82,252.99)
AUD_BEEP_R: length 5.4
  TOP w0.102: C2717.1 66.9,250.37 66.9,250.37 66.9,249.92 R2704.1 66.27,249.29 v3(65.91,249.29) 65.86,249.34 R2702.1 65.85,250.14 65.85,250.19 C2716.2
  BOTTOM w0.102: v3(65.91,249.29) v2(66.54,250.12)
AUD_LINE1_L: length 343.1
  TOP w0.203: v3(24.64,20.19) 24.59,20.14 C3001.1 ; U2701.28 67.67,262.33 66.36,261.02 v3(66.32,261.02)
  BOTTOM w0.203: v3(66.32,261.02) 64.47,262.86 v2(63.04,262.86) 62.21,262.86 55.88,269.19 19.89,269.19 17.88,267.18 17.88,263.23 23.95,257.16 23.95,251.26 19.78,247.09 16.71,247.09 9.93,240.31 9.93,238.2 2.64,230.91 2.64,195.01 6.18,191.46 8.82,191.46 12.95,187.34 12.95,181.86 8.86,177.78 5.95,177.78 5.92,177.75 2.3,174.12 2.06,173.88 2.06,47.07 13.25,35.88 13.25,23.07 16.12,20.19 v3(24.64,20.19)
AUD_LINE1_R: length 338.8
  TOP w0.203: U2701.27 68.17,262 v3(67.23,261.06) ; v3(15.62,19.81) 16.51,18.92 C3002.1
  BOTTOM w0.203: v3(15.62,19.81) 12.87,22.57 12.87,35.73 1.68,46.92 1.68,174.04 5.77,178.13 5.82,178.18 8.73,178.18 12.57,182.02 12.57,187.18 8.67,191.08 6.02,191.08 2.26,194.85 2.26,231.07 9.55,238.36 9.55,240.47 16.55,247.47 19.62,247.47 23.57,251.42 23.57,256.97 17.5,263.04 17.5,267.34 19.73,269.57 56.06,269.57 60.18,265.45 v2(61.71,265.45) 62.51,265.45 65.23,262.74 65.56,262.74 v3(67.23,261.06)
AUD_LINE2_L: length 5.3
  TOP w0.203: C2901.1 72.82,257.6 72.54,257.32 72.54,256.54 v3(72.03,256.03) 72.01,256.03 72.01,256.03 71.23,256.03 71.18,256.08 U2701.13
  BOTTOM w0.203: v3(72.03,256.03) v2(70.99,256.06)
AUD_LINE2_R: length 6.6
  TOP w0.203: U2701.14 71.79,256.58 72.01,256.79 v3(72.01,256.96) 72.01,259.64 72.82,260.45 C2902.1
  BOTTOM w0.203: v3(72.01,256.96) v2(72.01,257.98)
AUD_LINK_SDO_C: length 6.3
  TOP w0.102: v3(192.66,22.65) 192.66,22.57 R2038.2 192.39,21.63 192.87,22.11 Q2001.C
  BOTTOM w0.102: v3(192.66,22.65) 193.93,22.65 v2(194.02,22.56) R2039.1
AUD_LINK_SDO_R1: length 10.1
  BOTTOM w0.102: 193.68,17.4 194.56,16.51 196.58,16.51 197.1,17.03 197.1,20.45 195.91,21.64 R2039.2
AUD_MIC1_L: length 339.4
  TOP w0.203: v3(12.19,27.67) 12.79,27.67 13.06,27.94 16.71,27.94 C3007.1 ; U2701.15 69.3,257.08 v3(69.18,256.96)
  BOTTOM w0.203: v3(12.19,27.67) 11.79,28.07 11.79,28.93 11.95,29.1 11.95,35.42 1.1,46.27 0.86,46.51 0.86,174.41 5.52,179.07 8.47,179.07 11.76,182.36 11.76,186.84 8.43,190.17 5.75,190.17 1.66,194.26 1.42,194.5 1.42,231.52 8.69,238.79 8.69,240.79 16.18,248.28 19.29,248.28 22.76,251.76 22.76,256.31 16.66,262.41 16.66,267.69 19.38,270.41 56.54,270.41 60.2,266.75 63.08,266.75 v2(64.43,265.4) 65.38,264.45 66.01,264.45 68.38,262.08 68.38,258.6 69.18,257.79 v3(69.18,256.96)
AUD_MIC1_R: length 340.4
  TOP w0.203: v3(12.32,28.57) 12.5,28.4 17.85,28.4 19.66,26.59 19.66,24.61 C3008.1 ; U2701.16 v3(68.51,257.58)
  BOTTOM w0.203: v3(12.32,28.57) 12.36,28.61 12.36,35.59 1.27,46.68 1.27,174.21 1.51,174.45 5.6,178.54 5.6,178.54 5.67,178.61 8.59,178.61 12.17,182.19 12.17,187.01 8.55,190.63 5.91,190.63 1.85,194.68 1.85,231.31 9.14,238.6 9.14,240.64 16.39,247.88 19.45,247.88 23.17,251.59 23.17,256.72 17.09,262.79 17.09,267.51 19.56,269.98 56.3,269.98 60.03,266.24 62.41,266.24 65.27,263.39 v2(65.72,263.39) 67.77,261.34 67.77,258.32 v3(68.51,257.58)
AUD_MIC2_L: length 10.7
  TOP w0.203: C2905.1 69.04,266.5 69.34,266.19 v3(69.41,266.19) ; U2701.19 69.1,259.08 68.96,258.94 v3(68.94,258.94)
  BOTTOM w0.203: v3(69.41,266.19) 69.46,266.13 69.46,263.63 v2(69.45,263.62) 69.49,262.46 69.49,260.21 69.65,260.06 69.65,259.62 68.97,258.94 v3(68.94,258.94)
AUD_MIC2_L_C: length 4.7
  TOP w0.203: R2902.1 73.98,256.9 v2(74.83,256.9) 74.83,258.47 C2901.2 C2902.2
AUD_MIC2_R: length 13.6
  TOP w0.203: C2904.1 62.79,266.24 v3(63.63,267.08) ; U2701.20 69.35,259.58 69.11,259.81 v3(69.11,259.84)
  BOTTOM w0.203: v3(63.63,267.08) 64.74,265.97 64.76,265.97 64.92,265.81 65.86,265.81 v2(66.32,265.35) 69.11,262.56 v3(69.11,259.84)
AUD_VREF: length 4.2
  TOP w0.254: 70.74,266.57 70.74,265.25 70.36,264.86 v2(70.36,264.8) 70.1,264.54 70.03,264.54 69.17,263.68 U2701.25
AUDOUT_L: length 338.3
  TOP w0.203: v3(63.6,259.02) 63.6,259.56 63.09,260.08 U2701.40 ; v3(25.97,21.36) R3005.1
  BOTTOM w0.203: v3(63.6,259.02) 62,259.02 58.37,262.66 58.37,264.44 55.14,267.67 20.52,267.67 19.41,266.55 19.41,263.87 25.48,257.79 25.48,250.63 20.41,245.57 17.34,245.57 11.46,239.68 11.46,237.57 4.17,230.28 4.17,195.64 6.81,192.99 9.46,192.99 14.48,187.97 14.48,181.23 9.47,176.23 6.56,176.23 3.82,173.49 3.58,173.25 3.58,47.71 14.77,36.52 14.77,26.89 15.49,26.16 v2(15.49,26.04) 15.49,25.27 17.09,23.67 17.09,22.07 18.13,21.03 22.83,21.03 23.16,21.36 v3(25.97,21.36)
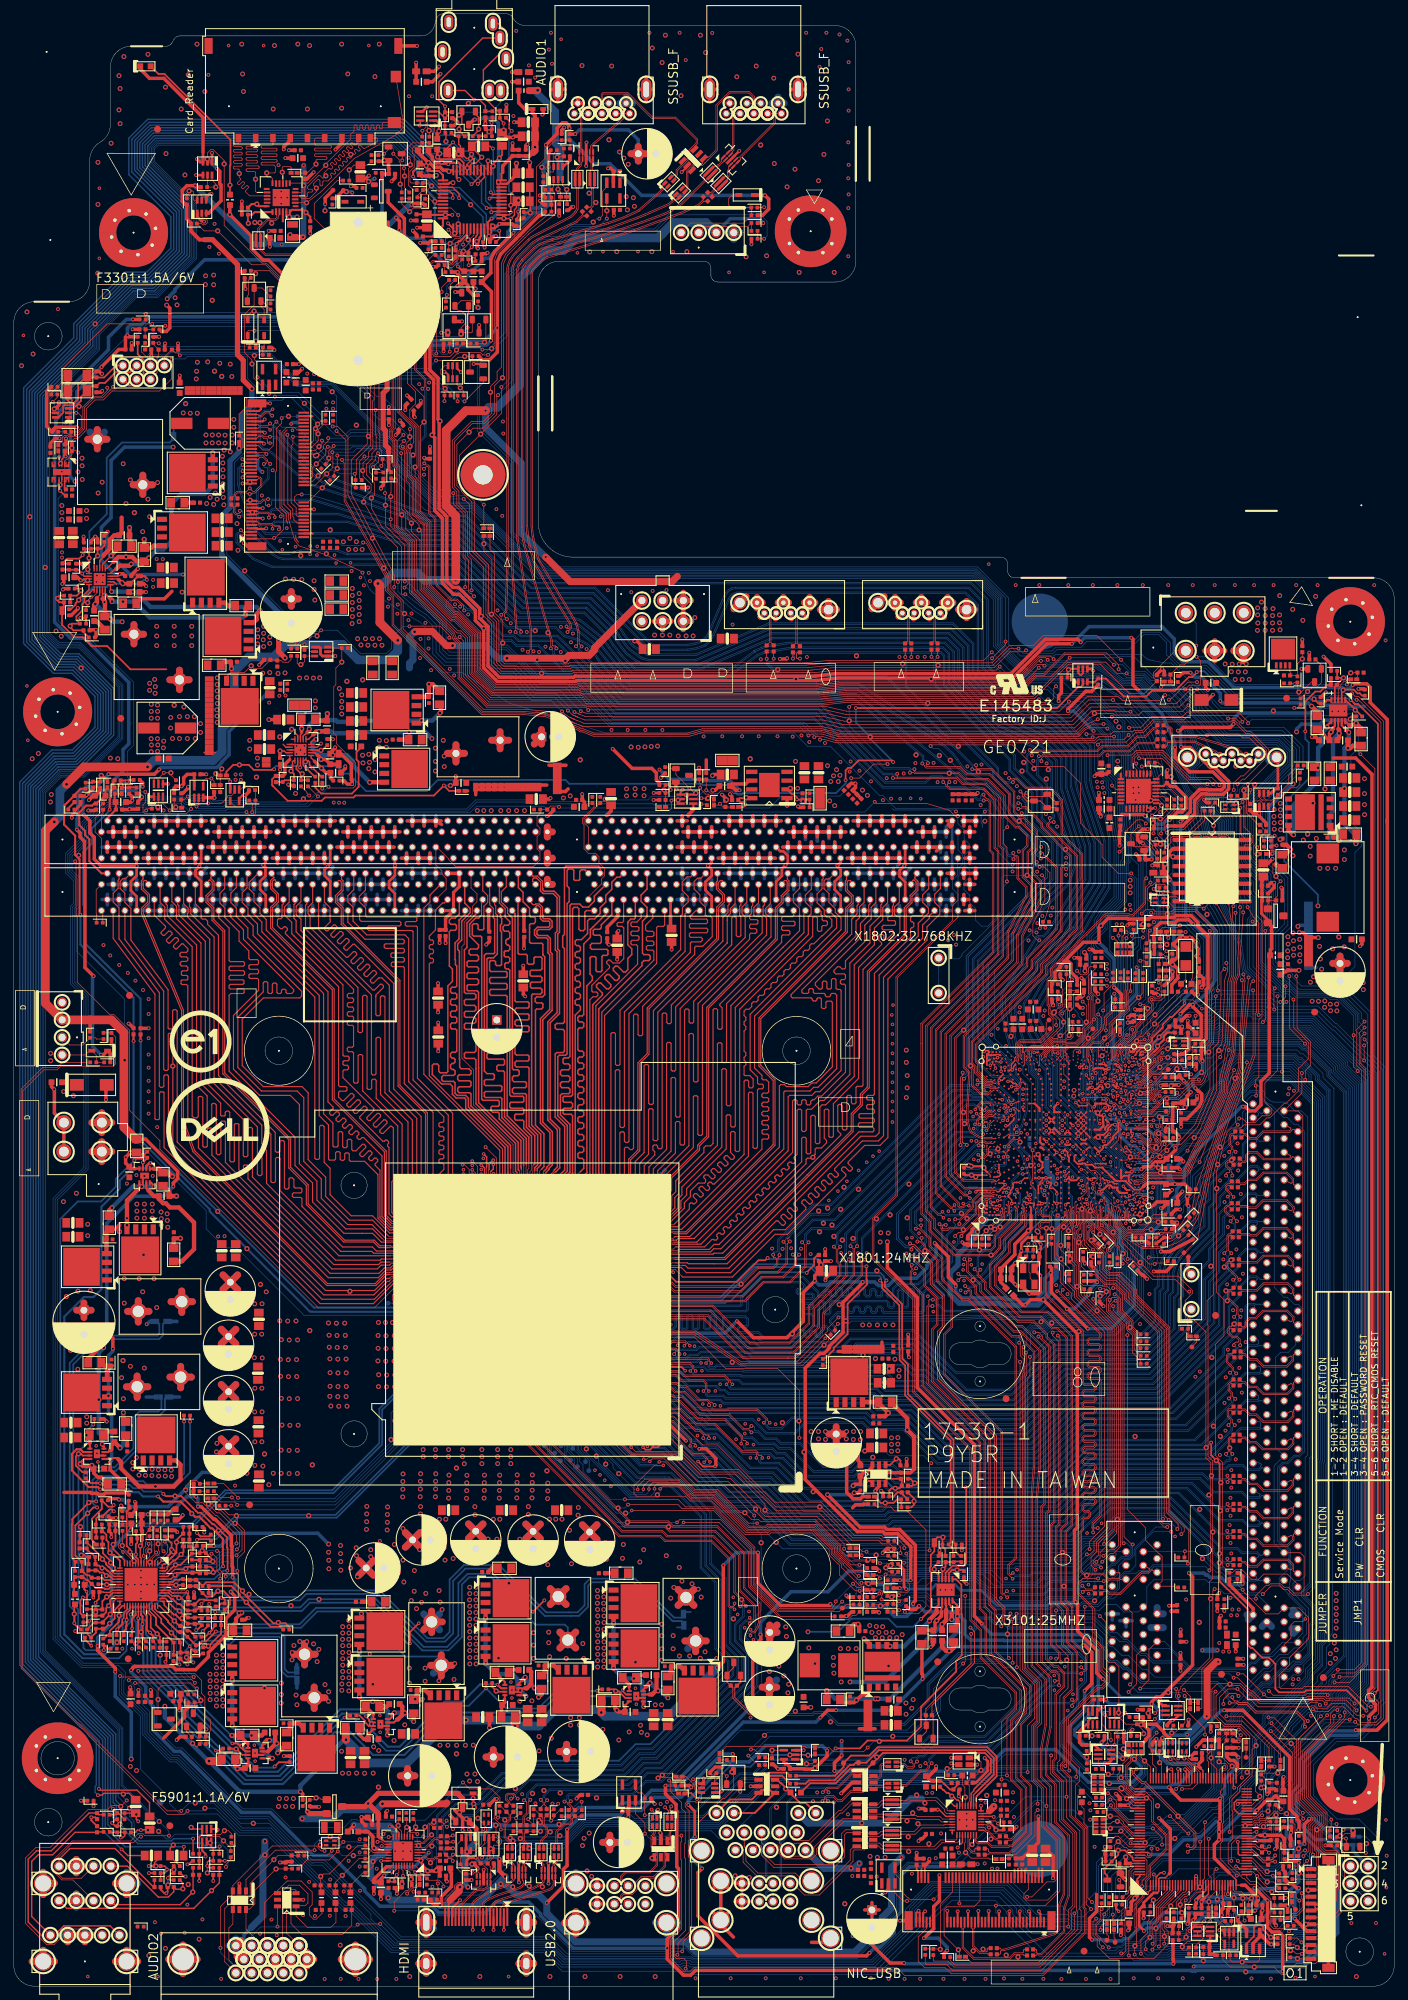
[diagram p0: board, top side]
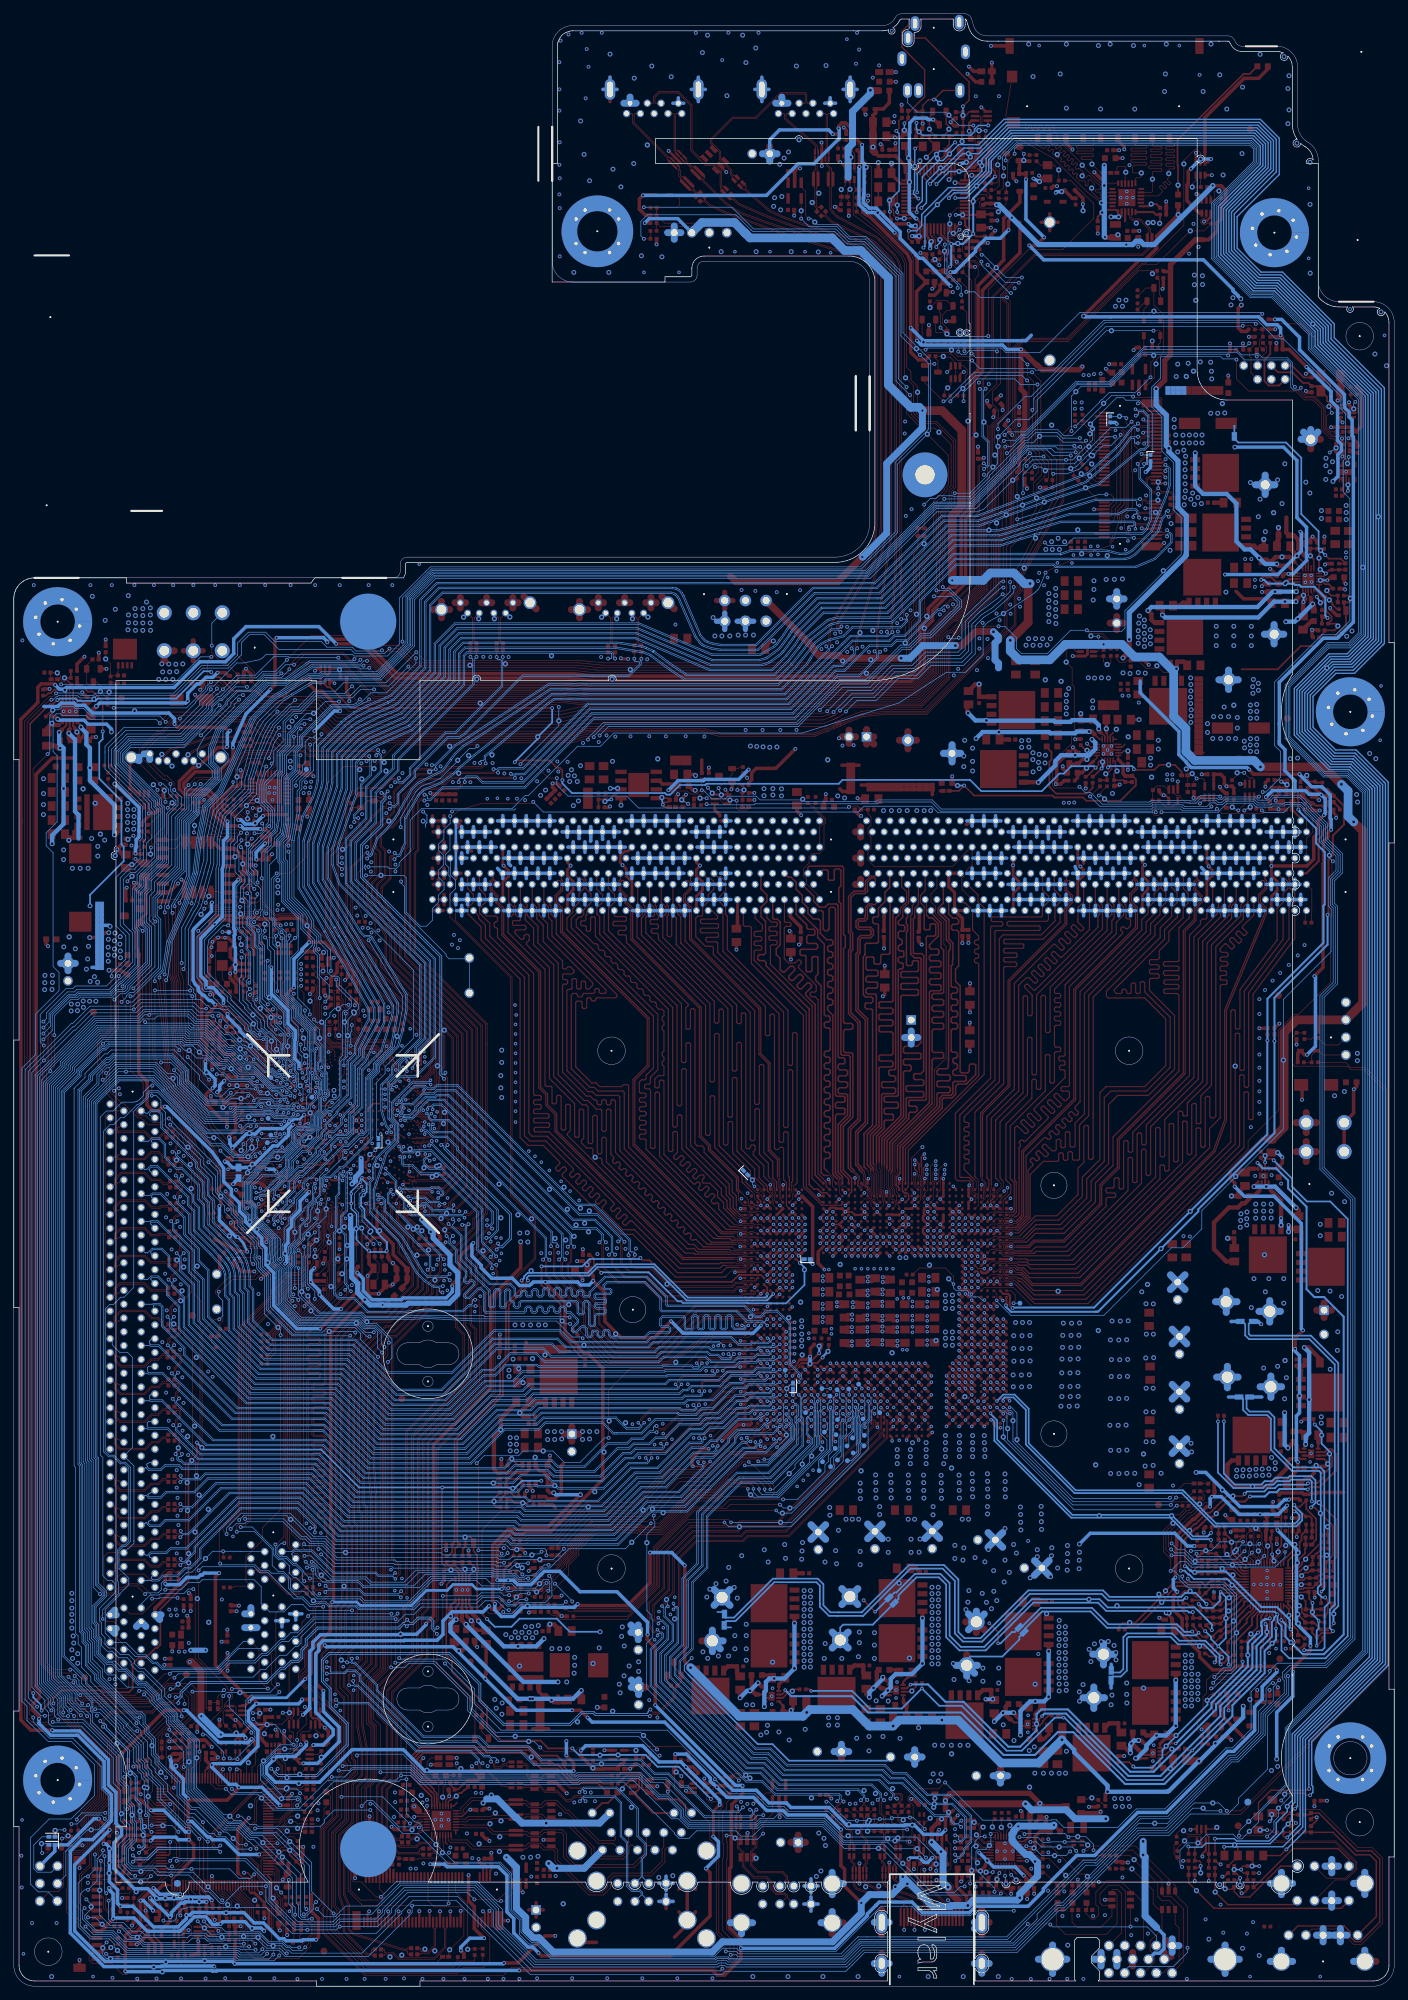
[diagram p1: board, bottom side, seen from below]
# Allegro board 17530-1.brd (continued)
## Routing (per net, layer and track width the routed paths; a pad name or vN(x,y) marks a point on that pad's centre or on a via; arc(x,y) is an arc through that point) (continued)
AUDOUT_LL: length 7.5
  TOP w0.203: L3003.1 R3007.1 R3005.2 26.86,21.6 26.88,21.63 27.29,22.03 Q3001.3 25.93,22.77 v2(25.7,23)
AUDOUT_R: length 344.8
  TOP w0.203: U2701.39 63.55,260.58 64.52,259.61 v3(64.52,259) ; R3006.1 29.78,20.19 v3(29.83,20.24)
  BOTTOM w0.203: v3(64.52,259) 63.75,259.77 61.8,259.77 58.75,262.81 58.75,264.6 55.3,268.05 20.36,268.05 19.02,266.71 19.02,263.71 25.1,257.64 25.1,250.79 20.25,245.95 17.19,245.95 11.07,239.84 11.07,237.72 3.78,230.43 3.78,195.48 6.66,192.61 9.3,192.61 14.1,187.81 14.1,181.39 9.31,176.61 6.4,176.61 3.44,173.65 3.2,173.41 3.2,47.55 14.39,36.36 14.39,26.63 14.86,26.16 14.86,24 v2(15.37,23.5) 16.13,22.73 16.13,22.49 17.97,20.65 22.99,20.65 23.04,20.7 27.3,20.7 27.86,20.14 29.73,20.14 v3(29.83,20.24)
AUDOUT_RR: length 6.3
  TOP w0.203: Q3001.6 28.59,20.22 28.89,19.91 R3006.2 R3009.1 28.24,18.16 28.04,17.96 v3(28.04,17.42) 28.32,17.14 L3004.1
  BOTTOM w0.203: v3(28.04,17.42) v2(28.04,16.41)
BATLOW_N: length 7.3
  TOP w0.102: RN2001.1 167.47,136.9 v2(167.28,137.08) 166.63,136.43 166.63,136.32 165.27,134.96 165.1,134.96 164.54,134.4 164.54,133.97 163.74,133.17 163.38,133.17 SB1.BF44
BC1_TP: length 8.3
  TOP w0.089: SB1.BC1 162.77,110.67 162.77,110.65 162.87,110.55 162.87,110.5 163.11,110.27 163.94,110.27 164.21,110.54
  TOP w0.102: 164.21,110.54 164.92,111.25 168.73,111.25 TP1509.1
BLUE_CRT: length 23.1
  TOP w0.102: L5905.2 44.45,11.94 44.45,11.15 44.55,11.05 C5919.1 44.65,11.04 44.65,10.54 43.81,9.7 43.44,9.7 42.81,10.33 42.81,11.39 43.23,11.81 43.23,13.64 41.63,15.24 39.6,15.24 38.2,13.84 EU5901.4 37.71,13.47 36.32,12.09 36.32,6.31 VGA1.3
BPM_CPU_N0: length 8.1
  TOP w0.102: v1(79.88,82) CPU1.D16
  BOTTOM w0.102: TP417.1 81.66,76.45 80.44,77.67 80.44,78.08 80.47,78.11 80.47,79.43 80.16,79.74 80.16,81.72 v1(79.88,82)
BPM_CPU_N1: length 7.1
  TOP w0.102: CPU1.D17 v1(78.96,82.02)
  BOTTOM w0.102: TP418.1 80.03,76.86 80.03,79.29 79.36,79.96 79.36,81.62 v1(78.96,82.02)
BPM_CPU_N2: length 1.6
  TOP w0.102: CPU1.G14 v1(82.61,85.66)
  BOTTOM w0.102: TP401.1 81.97,85.66 v1(82.61,85.66)
BPM_CPU_N3: length 1.9
  TOP w0.102: CPU1.H14 v1(81.7,86.57)
  BOTTOM w0.102: TP402.1 v1(81.7,86.57)
CAP_1: length 6.2
  TOP w0.254: 162.76,15.14 162.76,15.52 163.14,15.9 U2401.128
  TOP w0.508: C2414.1 161.87,10.9 161.87,11.43 161.9,11.46 161.9,12.18 162.4,12.68 162.4,12.72 v2(162.43,12.75) 162.76,13.08 162.76,15.14
CATERR#_CPU: length 3.5
  TOP w0.102: CPU1.D13 83.53,82.91 83.53,83.55 83.8,83.83 v1(84.44,83.83)
  BOTTOM w0.102: v1(84.44,83.83) 84.73,83.54 84.84,83.54 TP403.1
CBN: length 7.9
  TOP w0.305: U2701.34 64.67,263.88 64.44,264.11 63.15,264.11 v3(62.95,263.91)
  TOP w0.508: v3(62.95,263.91) 62.76,264.11 61.17,264.11 61.12,264.16 61.09,264.19 60.64,264.63 60.64,264.99 60.07,265.56 C2702.1
  BOTTOM w0.508: v3(62.95,263.91) 61.98,264.21 v2(61.98,264.21)
CBP: length 6.5
  TOP w0.254: U2701.36 62.87,263.07
  TOP w0.508: 62.87,263.07 62.2,263.07 61.79,263.47 60.9,263.47 60.23,264.15 v2(60.05,264.15) 58.55,265.65 C2702.2
CHASSIS_ID_0: length 247
  TOP w0.102: v3(157.05,183.51) 155.2,182.63 154.05,181.48 119.61,181.48 118.31,181.86 117.08,182.14 99.79,182.14 97.49,181.51 84.09,181.51 83.88,181.59 82.48,182.14 82.2,182.14 82.02,182.33 81.33,182.6 81.05,182.71 81.02,182.73 80.93,182.78 80.86,182.81 80.63,182.91 80.54,182.95 80.44,182.99 80.34,183.03 80.29,183.05 79.93,183.21 79.86,183.28 79.83,183.29 79.24,183.52 77.16,184.34 77.12,184.34 77.07,184.36 76.94,184.36 75.93,184.46 73.95,184.66 67.94,184.66 56.11,196.48 56.11,200.56 54.33,202.34 54.33,204.15 54.28,204.25 54.11,204.57 54.11,204.57 54.06,204.66 53.99,204.8 53.98,204.81 48.11,215.17 48.11,223.92 v3(46.76,225.27) ; v3(24.05,236.22) 24.05,236.3 23.77,236.58 23.43,236.58 23.23,236.78 23.19,236.78 C9905.1 22.9,237.06 21.8,235.96 PWRSW1.7 ; v3(164.08,160.48) 163.75,160.16 163.75,156.92 162.07,155.24 161.69,155.24 161.59,155.35 158.15,155.35 150.19,147.38 150.19,146.34 149.7,145.85 149.7,142.1 149.91,141.9 149.91,140.78 150.57,140.12 150.57,138.98 150.65,138.9 150.65,138.46 148.86,136.68 145.91,136.68 145.57,136.34 145.57,136 145.8,135.77 145.8,134.52 SB1.L47 ; R6415.2 164.78,153.71 v3(165.2,154.13)
  BOTTOM w0.102: v3(165.2,154.13) 164.24,155.09 164.24,155.62 163.93,155.92 163.93,160.3 164.08,160.45 v3(164.08,160.48) 164.08,164.22 163.09,165.2 163.09,166.36 162.06,167.39 161.77,168.98 161.77,175.39 161.32,175.85 161.32,178.58 160.1,179.8 160.1,181.31 159.13,182.27 159.13,182.45 158.07,183.51 v3(157.05,183.51) ; v3(24.05,236.22) 24.22,236.39 36.35,236.39 40.99,231.75 45.34,231.75 v2(46.13,230.96) 46.76,230.33 v3(46.76,225.27)
CNV_BRI_DT: length 15.6
  TOP w0.102: SB1.AV4 159.29,113.08 159.29,112.66 159.19,112.57 159.19,112.23 159.26,112.16 159.53,110.43 159.55,110.27 159.99,109.69 161.12,108.56 161.98,108.46 R2305.1 162.52,107.96 162.53,107.94 162.97,107.5 163.6,107.15 163.63,107.12 165.87,107.12 R2303.1 167.84,108.01 v2(168.76,108.69) R9932.2
CNV_BRI_DT_R: length 224.9
  TOP w0.102: NGFF1.36 43.06,218.42 43.31,218.67 43.31,219.98 v2(43.83,220.5) 45.2,221.87 45.21,222.7 v3(45.49,222.99) ; v3(178.9,146.12) 178.14,137.95 177.89,132.99 177.78,132.64 177.71,132.38 177.5,131.76 177.44,131.6 177.44,131.59 177.37,131.4 176.69,129.48 176.46,128.84 174.91,124.44 173.17,118.86 171.57,112.04 171.5,111.87 171.18,111.25 170.09,110.17
  BOTTOM w0.102: v3(178.9,146.12) 178.84,146.18 178.84,146.51 178.55,146.8 178.27,147.11 177.57,151.26 175.18,156.98 173.87,161.12 173.87,161.13 173.85,161.18 173.83,161.24 173.78,161.39 173.29,165.76 173.23,166.37 173.23,166.42 172.83,168.44 172.42,170.88 172.42,170.88 170.17,173.13 165.54,183.56 162.4,186.7 161.69,187.14 161.56,187.22 161.4,187.32 161.22,187.43 157.26,189.87 155.66,189.87 155.35,190.17 147.25,190.17 142.95,194.47 142.95,201 142.95,201.18 139.58,204.56 139.31,204.83 76.52,204.83 66.61,214.73 61.24,214.73 55.19,220.78 55.19,220.98 54.93,221.25 53.19,222.98 53,222.98 49.04,222.98 48.71,222.65 46.16,222.65 45.83,222.98 45.49,222.98 v3(45.49,222.99)
CNV_BRI_RSP: length 231.3
  TOP w0.102: v3(177.93,145.72) 178.07,145.56 177.43,133.07 177.06,131.91 176.03,129 174.48,124.59 174.47,124.58 174.42,124.43 174.42,124.41 174.38,124.27 174.37,124.26 174.35,124.19 174.35,124.19 172.45,118.83 R9936.2 170.74,112.73 170.11,111.92 168.93,110.12 168.06,109.25 168.02,109.2 166.47,109.2 164.9,109.06 164.16,109.06 164.12,109.09 162.08,109.09 161.97,108.98 161.27,108.98 160.34,109.91 159.92,110.69 159.92,112.15 SB1.AY2 ; v3(46.87,221.71) 46.86,221.71 v2(46.86,219.84) 46.42,219.39 R9933.2
  BOTTOM w0.102: v3(46.87,221.71) 46.87,221.72 49.48,221.72 50.29,222.53 53,222.53 54.74,220.79 54.74,220.59 61.06,214.27 66.42,214.27 76.33,204.37 139.12,204.37 142.49,201 142.49,194.28 142.49,194.28 147.06,189.71 155.16,189.71 155.47,189.41 157.06,189.41 159.86,187.68 160.43,187.35 160.5,187.31 160.51,187.31 160.98,187.03 160.98,187.03 161.3,186.84 162.16,186.29 165,183.45 169.79,172.85 171.88,170.76 172.6,167.23 172.67,166.86 172.75,166.49 172.77,166.27 172.77,166.27 172.78,166.17 172.79,166.16 172.92,164.96 173.32,161.41 173.33,161.3 173.4,161.1 173.41,161.05 173.43,160.99 174.72,156.91 174.72,156.89 175.78,154.36 177.09,151.22 177.09,150.2 177.11,150.07 177.69,146.26 177.7,146.26 177.7,146.15 177.82,145.83 177.93,145.72 v3(177.93,145.72)
CNV_BRI_RSP_R: length 5.1
  TOP w0.102: NGFF1.22 42.58,214.92 v2(44.7,217.04) R9933.1
CNV_DET_S: length 8.6
  TOP w0.102: D6302.A 33.88,241.98 34.53,242.63 v2(34.81,242.63) 35.02,242.63 D6301.A 36.27,242.87 35.81,243.33 U6302.S 35.98,244.08 37.19,242.88 R6313.2
CNV_RGI_DT: length 16.3
  TOP w0.089: SB1.BA4 160.09,113.2 159.82,112.93 159.82,112.83 159.64,112.21
  TOP w0.102: R9934.2 169.12,109.98 169.11,109.97 168.11,108.97 166.52,108.97 R2310.1 R2312.1 164.46,108.47 164.04,108.89 162.16,108.89 162.05,108.78 161.19,108.78 160.14,109.82 159.71,110.58 159.64,111.04 159.64,112.21
CNV_RGI_DT_R: length 222.2
  TOP w0.102: v3(178.15,146.55) 178.34,145.96 178.39,145.91 178.39,145.53 178.37,145.51 178.13,142.2 177.8,135.75 177.66,133.03 177.55,132.7 177.49,132.45 177.4,132.19 177.28,131.83 177.25,131.75 177.25,131.75 176.62,129.97 176.42,129.4 176.25,128.92 174.69,124.51 174.69,124.51 174.66,124.43 174.66,124.42 172.95,118.93 172.92,118.84 172.92,118.83 R9934.1 ; v3(46.15,222.2) 46.16,222.2 46.23,222.12 46.23,219.96 v2(45.34,219.07) 43.68,217.42 NGFF1.32
  BOTTOM w0.102: v3(178.15,146.55) 178.12,146.61 177.32,151.22 177.32,151.26 174.96,156.9 173.65,161.06 173.63,161.12 173.61,161.17 173.56,161.34 173.55,161.44 173.01,166.28 173.01,166.28 173,166.29 172.97,166.53 172.61,168.4 172.27,170.36 172.2,170.77 172.19,170.78 169.97,173 166.81,180.14 165.23,183.5 165.23,183.55 162.31,186.47 161.5,186.99 161.5,186.99 161.42,187.04 161.35,187.08 161.34,187.08 161.09,187.23 161.09,187.23 160.78,187.41 160.54,187.55 157.15,189.64 155.56,189.64 155.26,189.94 147.16,189.94 142.72,194.38 142.72,200.9 142.72,201.09 139.35,204.46 139.21,204.6 76.42,204.6 66.52,214.5 61.15,214.5 54.97,220.69 54.97,220.89 54.83,221.02 53.1,222.75 49.73,222.75 49.17,222.2 46.15,222.2 v3(46.15,222.2)
CNV_RGI_RSP: length 237.6
  TOP w0.102: R9935.2 45.64,220.92 v2(45.64,221.34) 45.65,222.42 46.35,223.1 v3(46.35,223.11) ; SB1.AV3 159.06,112.72 158.99,112.65 158.99,112.14 159.06,112.07 159.37,110.12 159.72,109.67 161.03,108.36 163.4,106.92 163.42,106.92 163.49,106.88 166.23,106.88 168.45,107.64 R9937.2 171.55,111.21 171.84,112.05 171.88,112.16 173.34,118.56 173.94,120.46 173.98,120.65 173.98,120.67 174.13,121.16 174.95,123.8 175.03,124.06 175.11,124.27 175.13,124.33 176.66,128.68 176.9,129.36 177.96,132.36 178,132.6 178.11,132.95 178.3,136.7 179.17,145.17 v3(179.58,145.59)
  BOTTOM w0.102: v3(46.35,223.11) 46.45,223.21 53.29,223.21 55.02,221.48 55.42,221.08 55.42,220.88 61.34,214.96 66.71,214.96 76.61,205.05 139.4,205.05 139.8,204.65 143.18,201.28 143.18,194.63 147.41,190.4 155.45,190.4 155.75,190.09 157.34,190.09 162.52,186.9 165.77,183.65 165.77,183.65 169.33,175.58 170.36,173.26 172.63,170.99 172.63,170.99 173.06,168.48 173.47,166.37 173.47,166.32 174.02,161.41 174.09,161.16 174.09,161.16 175.39,157.06 177.75,151.41 177.78,151.39 177.79,151.32 177.87,151.13 178.11,149.4 178.48,147.22 178.66,147.02 179.58,146.1 v3(179.58,145.59)
CNV_RGI_RSP_R: length 3.7
  TOP w0.102: R9935.1 44.55,219.82 44.55,219.25 v2(44.1,218.8) 43.22,217.92 NGFF1.34
CNV_WR_0_DN: length 220.9
  TOP w0.089: v1(162.26,110.31) 162.14,111.01 161.91,111.24 161.56,111.47 161.47,111.56 161.47,111.76 SB1.BB3
  TOP w0.102: NGFF1.15 35.22,213.17 35.34,213.3 36.82,213.3 36.96,213.16 v3(36.96,212.72)
  BOTTOM w0.102: v3(36.96,212.72) 37.13,212.9 37.13,213.74 37.4,214.01 38.71,214.01 40.06,213.35 46.99,213.35 54.53,211.08 56.3,210.51 57.24,210.29 64.24,210.29 74.06,200.47 83.27,200.47 87.12,196.62 87.12,196.62 87.22,196.52 87.38,196.3 87.44,196.23 87.47,196.17 87.67,195.86 87.68,195.85 87.94,195.45 88.7,194.42 89.03,193.98 89.35,193.66 90.89,192.54 91.11,192.43 91.98,192.19 98.77,192.19 109.6,196.79 135.82,196.79 138.39,194.21 138.39,190.02 143.93,184.47 149.31,182.06 150.3,181.4 150.86,180.92 153.28,178.5 153.28,173.79 154.61,169.65 155.94,165.52 155.94,165.44 156.02,165.17 156.02,160.06 145.2,142.09 145.2,141.07 145.29,140.56 146.86,135.49 149.63,132.71 149.63,127.35 151,125.98 151,123.57 151.64,122.93 153.07,122.93 154.15,121.84 154.15,121.11 154.82,120.44 155.17,120.44 158.21,117.4 158.65,117.4 159.46,116.59 159.46,115.27 160.57,114.16 160.57,113.25 162.52,111.29 162.52,110.91 162.26,110.64 v1(162.26,110.31)
CNV_WR_0_DP: length 221
  TOP w0.089: SB1.BB4 161.29,112.54 161.29,111.99 161.28,111.98 161.28,111.48 161.71,111.05 161.72,111.01 161.73,110.91 v1(161.74,110.84)
  TOP w0.102: NGFF1.17 35.25,213.67 35.41,213.51 36.91,213.51 37.19,213.23 37.69,213.23 37.82,213.11 v1(37.82,212.78)
  BOTTOM w0.102: v1(37.82,212.78) 37.82,213.08 37.67,213.23 37.41,213.23 37.35,213.3 37.35,213.65 37.49,213.79 38.66,213.79 39.97,213.15 39.99,213.13 46.96,213.13 54.46,210.88 56.25,210.3 56.26,210.29 57.21,210.07 64.15,210.07 73.97,200.25 83.18,200.25 86.95,196.48 87.05,196.38 87.26,196.1 87.26,196.1 87.45,195.81 87.51,195.72 87.6,195.57 87.68,195.46 87.76,195.33 88.29,194.61 88.53,194.29 88.87,193.84 89.21,193.5 90.78,192.35 91.03,192.23 91.95,191.97 98.83,191.97 98.85,191.99 109.65,196.57 135.73,196.57 138.18,194.12 138.18,190.1 138.18,189.93 143.81,184.29 149.21,181.87 150.16,181.23 150.71,180.76 153.06,178.41 153.06,173.76 155.73,165.48 155.73,165.4 155.8,165.14 155.8,160.12 144.98,142.15 144.98,141.05 145.08,140.51 146.67,135.37 149.42,132.62 149.42,127.26 150.79,125.9 150.79,123.48 151.55,122.71 152.98,122.71 153.94,121.75 153.94,121.02 154.73,120.22 155.08,120.22 158.12,117.18 158.56,117.18 159.25,116.5 159.25,115.18 160.35,114.07 160.35,113.16 162.31,111.2 162.31,111 162.15,110.84 v1(161.74,110.84)
CNV_WR_1_DN: length 218.9
  TOP w0.089: v1(161.11,110.52) 161.2,111.16 161.09,111.43 161.09,112.06 161.1,112.07 161.1,112.27 SB1.BA3
  TOP w0.102: v1(37.49,211.1) 37.49,211.46 37.27,211.67 NGFF1.9
  BOTTOM w0.102: v1(161.11,110.52) 161.26,111.03 161.49,111.25 161.49,111.57 159.54,113.52 159.54,114.17 158.14,115.57 158.14,116.36 157.32,117.18 156.96,117.18 152.29,121.86 151.63,121.86 150,123.48 149.42,123.48 149.06,123.85 149.06,131.6 147.87,132.79 147.87,133.65 145.42,136.09 144.5,141 144.5,142.41 155.32,160.26 155.32,165.07 155.24,165.35 152.75,173.05 152.58,173.59 152.58,178.17 150.16,180.59 148.79,181.49 143.6,183.82 137.68,189.74 137.68,193.93 135.53,196.09 109.78,196.09 104.35,193.77 99,191.48 92.05,191.48 91.67,191.49 91.01,191.66 90.62,191.86 90.55,191.88 90.28,192.03 89.16,192.87 88.89,193.1 88.71,193.28 88.58,193.44 88.5,193.52 88.32,193.77 88.1,194.04 87.7,194.6 87.36,195.05 87.25,195.23 87.04,195.53 87.03,195.53 86.64,196.11 86.58,196.17 86.57,196.18 83,199.75 82.98,199.75 73.79,199.75 63.95,209.59 56.86,209.59 54.32,210.42 48.32,212.22 37.71,212.22 37.49,211.99 v1(37.49,211.1)
CNV_WR_1_DP: length 219
  TOP w0.089: SB1.BA2 160.9,112.11 160.9,111.37 v1(160.73,111.2)
  TOP w0.102: NGFF1.11 35.25,212.17 35.54,211.89 37.36,211.89 37.74,211.51 38.48,211.51 38.58,211.4 38.58,211.21 38.4,211.03 v3(38.4,211.02)
  BOTTOM w0.102: v3(38.4,211.02) 38.4,211.03 38.58,211.21 38.58,211.4 38.48,211.51 37.87,211.51 37.7,211.67 37.7,211.9 37.8,212 48.29,212 54.25,210.21 56.83,209.37 63.86,209.37 73.7,199.54 82.89,199.54 82.9,199.54 82.91,199.54 86.41,196.04 86.41,196.04 86.47,195.97 86.86,195.41 86.86,195.4 87.07,195.11 87.18,194.93 87.53,194.47 87.93,193.91 88.14,193.64 88.34,193.38 88.42,193.3 88.55,193.14 88.74,192.94 89.03,192.7 90.16,191.85 90.46,191.69 90.53,191.66 90.93,191.46 91.64,191.27 92.05,191.26 99.04,191.26 109.82,195.87 135.44,195.87 137.46,193.84 137.46,189.65 143.47,183.64 148.68,181.3 150.02,180.42 152.36,178.08 152.36,173.56 155.04,165.28 155.11,165.04 155.11,160.32 144.28,142.47 144.28,140.98 145.22,135.99 147.65,133.56 147.65,132.7 148.84,131.51 148.84,123.76 149.33,123.26 149.91,123.26 151.54,121.64 152.2,121.64 156.87,116.97 157.23,116.97 157.92,116.27 157.92,115.48 159.32,114.08 159.32,113.43 161.27,111.48 161.27,111.34 161.13,111.2 v1(160.73,111.2)
CNV_WR_CLK_DN: length 215.8
  TOP w0.102: v1(161.76,113.2) SB1.BD4 ; v1(36.92,214.48) 36.55,214.48 36.45,214.59 36.45,215.08 36.35,215.18 36.16,215.18 35.78,214.8 35.37,214.8 35.24,214.67 NGFF1.21
  BOTTOM w0.102: v1(161.76,113.2) 161.76,113.47 161.44,113.79 161.07,114.16 161.07,114.16 160.06,115.17 160.06,116.45 158.57,117.93 158.11,117.93 155.59,120.46 155.59,120.88 153.27,123.2 151.76,123.2 151.26,123.71 151.26,126.21 149.96,127.51 149.96,132.87 149.02,133.81 146.24,139.52 146.24,142.36 148.91,147.17 151.17,150.78 151.91,152.07 152.64,153.37 156.51,159.84 156.51,165.58 153.98,173.25 153.76,174.34 153.76,178.7 151.05,181.41 150.73,181.68 150.48,181.88 150.15,182.14 149.55,182.48 149,182.73 147.13,183.71 145.29,184.42 144.94,184.55 144.4,184.8 144.1,185.01 143.84,185.25 138.88,190.21 138.88,194.4 136.02,197.27 109.46,197.27 98.86,192.76 91.82,192.76 89.81,193.93 89.42,194.28 89.39,194.31 88.97,194.87 88.97,194.87 88.33,195.73 87.84,196.5 87.58,196.85 87.49,196.97 87.36,197.15 83.87,200.65 83.56,200.95 74.84,200.95 74.26,200.95 64.44,210.77 57.43,210.77 56.1,211.08 53.63,211.88 45.89,214.4 43.32,215.18 37.44,215.18 37.34,215.08 37.34,214.59 37.24,214.48 v1(36.92,214.48)
CNV_WR_CLK_DP: length 215.8
  TOP w0.102: v3(36.83,215.4) 36.07,215.4 35.69,215.01 35.41,215.01 35.25,215.17 NGFF1.23 ; SB1.BE3 v1(162.08,112.5)
  BOTTOM w0.102: v3(36.83,215.4) 43.35,215.4 45.95,214.61 53.69,212.09 56.16,211.29 57.45,210.99 64.53,210.99 74.35,201.17 74.75,201.17 83.65,201.17 87.53,197.29 87.66,197.1 87.75,196.98 88.01,196.62 88.51,195.85 89.13,195.01 89.14,195.01 89.55,194.45 89.57,194.44 89.94,194.11 91.88,192.98 98.81,192.98 109.42,197.49 136.11,197.49 139.1,194.49 139.1,190.3 143.99,185.41 144.24,185.18 144.5,184.98 145.03,184.75 147.22,183.91 149.09,182.92 149.65,182.68 150.25,182.33 150.28,182.31 150.64,182.03 150.87,181.85 150.93,181.8 151.2,181.57 153.97,178.79 153.97,174.36 154.19,173.31 156.73,165.61 156.73,159.78 152.82,153.26 152.18,152.12 151.36,150.66 149.09,147.06 146.46,142.31 146.46,139.57 149.19,133.94 150.18,132.96 150.18,127.6 151.47,126.3 151.47,123.8 151.85,123.42 153.36,123.42 155.8,120.97 155.8,120.55 158.2,118.15 158.66,118.15 160.27,116.54 160.27,115.26 161.29,114.25 161.29,114.25 161.53,114.01 161.53,114.01 162.16,113.37 162.16,112.89 v1(162.08,112.5)
CNV_WT_0_DN: length 222.9
  TOP w0.102: v1(164.88,114.96) 164.59,114.96 164.2,114.56 163.48,114.56 162.81,114.56 SB1.BE6 ; v1(37.13,225.43) 36.75,225.81 35.52,225.81 35.38,225.67 NGFF1.65
  BOTTOM w0.102: v1(164.88,114.96) 164.39,114.96 164.3,115.05 163.66,115.05 161.78,116.93 161.54,116.93 160.01,118.46 160.01,119.67 158.1,121.58 157.39,121.58 155.91,123.07 155.91,123.8 155.41,124.3 155.41,125.61 154.38,126.65 153.92,126.65 151.52,129.04 151.52,133.92 150.44,135 150.44,136.17 149.24,138.56 148.45,140.02 148.45,141.48 151.67,147.17 154.86,152.81 154.86,152.82 154.87,152.83 156.06,154.94 158.61,159.13 158.61,166.32 158.43,167.31 158.43,167.31 158.27,168.22 158.27,168.22 158.15,168.87 158.06,169.37 158.05,169.4 156.55,172.18 156.08,173.59 155.87,174.6 155.86,174.65 155.86,179.57 155.74,179.69 155.49,179.94 155.45,179.98 152.47,182.95 152.47,182.96 152.39,183.04 152.36,183.07 151.88,183.48 151.87,183.48 151.72,183.6 151.41,183.82 151.39,183.84 150.62,184.38 149.66,184.91 148.97,185.27 148.69,185.38 146.08,186.5 146.06,186.51 145.46,186.8 145.2,186.97 140.98,191.19 140.98,200.81 138.66,203.13 75.22,203.13 65.48,212.86 60.31,212.86 60.23,212.9 44.3,219.03 40.67,222.3 40.26,222.71 40.17,222.79 39.77,223.2 37.9,225.63 37.74,225.79 37.5,225.79 v1(37.13,225.43)
CNV_WT_0_DP: length 222.8
  TOP w0.102: SB1.BD7 162.37,114.78 162.78,114.78 162.79,114.78 163.46,114.78 163.48,114.78 164.11,114.78 164.29,114.96 v1(164.29,115.58) ; NGFF1.67 35.38,226.17 35.52,226.03 36.8,226.03 v3(37.13,226.36)
  BOTTOM w0.102: v3(37.13,226.36) 37.48,226.01 37.83,226.01 38.06,225.78 39.93,223.34 40.32,222.95 40.41,222.87 40.82,222.46 44.42,219.22 44.42,219.21 51.14,216.63 60.31,213.1 60.35,213.08 65.57,213.08 75.31,203.34 138.75,203.34 141.2,200.89 141.2,191.28 145.33,187.14 145.57,186.99 146.15,186.7 146.17,186.69 148.78,185.58 149.06,185.46 149.77,185.1 150.42,184.74 150.72,184.57 150.73,184.56 150.74,184.55 151.2,184.24 151.52,184.01 151.54,183.99 151.85,183.78 152.02,183.64 152.5,183.23 152.53,183.2 152.61,183.12 152.61,183.12 155.64,180.09 155.89,179.84 156.08,179.66 156.08,179.48 156.07,179.48 156.07,174.68 156.08,174.65 156.29,173.64 156.74,172.27 158.24,169.49 158.25,169.49 158.27,169.43 158.36,168.91 158.48,168.24 158.48,168.24 158.59,167.63 158.64,167.39 158.65,167.35 158.83,166.34 158.83,159.07 156.25,154.83 155.06,152.73 155.05,152.71 148.67,141.42 148.67,140.07 149.43,138.66 149.44,138.66 150.66,136.22 150.66,135.09 151.74,134.01 151.74,129.13 154,126.86 154.47,126.86 155.63,125.7 155.63,124.39 156.12,123.89 156.12,123.16 157.48,121.79 158.19,121.79 160.22,119.76 160.22,118.55 161.63,117.14 161.87,117.14 163.75,115.27 163.97,115.27 v1(164.29,115.58)
CNV_WT_1_DN: length 229.5
  TOP w0.102: SB1.BG6 163.61,113.96 163.8,113.77 163.94,113.77 v1(164.09,113.92) ; NGFF1.59 35.16,224.17 35.44,224.45 35.95,224.45 36.18,224.22 36.62,224.22 36.73,224.11 36.73,223.57 36.78,223.52 v1(37.13,223.52)
  BOTTOM w0.102: v1(37.13,223.52) 37.54,223.52 37.64,223.62 37.64,224.12 37.74,224.22 38.09,224.22 38.15,224.15 40,221.74 44.6,217.79 56.91,213.34 57.06,213.28 57.73,213.02 58.32,212.81 59.29,212.49 59.57,212.4 60.18,212.17 65.19,212.17 74.93,202.43 84.16,202.43 92.43,194.16 97.56,194.16 98.76,194.36 99.56,194.63 99.61,194.65 99.92,194.84 100.09,195.01 100.29,195.2 100.64,195.66 100.68,195.73 102.84,200.75 103.08,201.3 103.32,201.75 103.71,202.14 104.01,202.3 104.11,202.35 104.62,202.43 138.33,202.43 140.28,200.47 140.28,190.9 144.92,186.26 145.73,185.87 146.12,185.67 146.3,185.58 147.3,185.16 148.5,184.67 150.27,183.77 151.3,183.05 151.36,183 151.42,182.95 151.91,182.53 152,182.44 152,182.44 154.95,179.49 154.99,179.45 155.16,179.28 155.16,174.48 155.34,173.59 155.35,173.57 155.98,171.66 156.09,171.41 156.98,168.68 157.83,166.13 157.88,165.96 157.92,165.85 157.92,159.33 153.89,152.72 147.66,141.72 147.66,140.02 147.78,139.79 147.99,139.4 149.81,135.75 149.81,134.8 151.01,133.6 151.01,128.71 153.1,126.62 153.1,126.38 154.69,124.79 154.69,124.21 155.27,123.62 155.27,123.06 157.53,120.8 158.14,120.8 159.5,119.44 159.5,118.37 163.42,114.45 164.24,114.45 164.4,114.29 164.4,114.02 164.3,113.92 v1(164.09,113.92)
CNV_WT_1_DP: length 229.5
  TOP w0.102: v3(37.11,224.43) 36.27,224.43 36.04,224.67 NGFF1.61 ; v1(164.95,114.12) 164.16,114.35 163.48,114.35 SB1.BF6
  BOTTOM w0.102: v3(37.11,224.43) 38.18,224.43 38.32,224.29 40.16,221.89 44.71,217.98 56.9,213.57 56.9,213.57 56.91,213.57 57.14,213.48 57.8,213.22 58.39,213.01 59.36,212.7 59.64,212.61 60.22,212.38 65.28,212.38 75.02,202.64 84.25,202.64 92.52,194.37 97.54,194.37 98.71,194.57 99.48,194.83 99.5,194.84 99.78,195.01 99.94,195.16 100.12,195.34 100.46,195.78 100.48,195.83 102.64,200.83 102.88,201.4 102.9,201.42 102.89,201.41 103.14,201.88 103.17,201.9 103.56,202.29 103.58,202.31 103.91,202.5 103.96,202.52 104.06,202.56 104.09,202.56 104.59,202.64 104.61,202.64 138.42,202.64 140.5,200.56 140.5,190.99 145.05,186.44 145.33,186.3 145.83,186.06 146.39,185.78 147.38,185.36 148.59,184.86 150.38,183.95 151.43,183.22 151.56,183.11 152.06,182.69 152.14,182.6 152.14,182.6 155.11,179.64 155.15,179.6 155.38,179.37 155.38,174.5 155.55,173.65 156.18,171.74 156.29,171.48 157.19,168.75 158.03,166.19 158.09,166.02 158.13,165.88 158.13,159.27 154.08,152.61 147.88,141.67 147.88,140.07 147.97,139.89 148.18,139.5 150.03,135.8 150.03,134.89 151.22,133.69 151.22,128.8 153.31,126.71 153.31,126.47 154.9,124.88 154.9,124.3 155.49,123.71 155.49,123.15 157.62,121.02 158.23,121.02 159.72,119.53 159.72,118.46 163.51,114.67 164.33,114.67 164.64,114.35 164.72,114.35 v1(164.95,114.12)
CNV_WT_CLK_DN: length 234.3
  TOP w0.102: SB1.BC5 v1(162.33,114.01) ; NGFF1.71 35.38,227.17 35.52,227.31 35.75,227.31 35.75,227.31 35.92,227.31 36.49,227.88 37.08,227.88 37.42,227.54 37.42,227.51 v3(37.43,227.5)
  BOTTOM w0.102: v1(162.33,114.01) 162.33,115.26 158.75,118.83 158.26,118.83 156.34,120.75 156.34,121.36 154.96,122.74 154.96,123.32 154.39,123.89 153.66,123.89 152.65,124.89 152.65,125.67 152.28,126.04 152.28,126.24 150.7,127.82 150.7,133.38 149.45,134.62 149.45,135.73 147.76,138.75 147.55,139.15 147.51,139.23 147.16,139.95 147.16,141.82 152.97,152.07 152.98,152.09 153.66,153.29 153.67,153.32 157.43,159.48 157.43,165.78 157.42,165.81 157.41,165.87 156.19,169.54 155.63,171.24 155.53,171.5 154.87,173.49 154.67,174.43 154.67,179.08 154.61,179.15 151.67,182.09 151.17,182.51 151.15,182.53 150.64,182.92 150.01,183.3 147.88,184.4 147.57,184.52 147.51,184.55 145.96,185.14 145.14,185.52 144.7,185.75 144.45,185.93 139.8,190.59 139.8,200.07 137.92,201.95 104.72,201.95 104.31,201.81 104.09,201.69 104.03,201.64 103.76,201.35 103.73,201.31 103.52,200.97 103.51,200.95 103.5,200.95 101.22,195.7 101.13,195.54 101.05,195.4 100.69,194.94 100.51,194.7 100.14,194.35 100.01,194.27 98.88,193.89 97.6,193.68 92.23,193.68 84.04,201.87 74.64,201.87 64.82,211.68 60.09,211.68 59.4,211.95 59.14,212.03 58.17,212.35 57.56,212.57 56.74,212.88 49.45,215.52 42.86,217.67 39.82,220.2 36.77,222.72 36.23,222.72 35.75,223.2 35.75,227.44 36.39,228.08 36.99,228.08 37.06,228.02 37.06,227.62 37.17,227.5 v3(37.43,227.5)
CNV_WT_CLK_DP: length 234.3
  TOP w0.102: NGFF1.73 35.38,227.67 35.52,227.53 35.66,227.53 35.67,227.53 35.83,227.53 36.4,228.1 37.16,228.1 v1(37.49,228.43) ; SB1.BB6 161.17,114.25 161.53,114.25 161.65,114.37 v1(161.65,114.5)
  BOTTOM w0.102: v1(161.65,114.5) 161.99,114.5 162.11,114.63 162.11,115.17 158.66,118.62 158.17,118.62 156.12,120.66 156.12,121.27 154.74,122.65 154.74,123.23 154.31,123.67 153.57,123.67 152.44,124.8 152.44,125.58 152.07,125.95 152.07,126.15 150.48,127.73 150.48,133.29 149.24,134.53 149.24,135.68 147.57,138.65 147.36,139.05 147.31,139.14 146.94,139.9 146.94,141.88 152.78,152.18 152.79,152.2 153.44,153.35 153.44,153.36 153.49,153.43 157.22,159.54 157.22,165.75 155.99,169.47 155.43,171.17 155.32,171.42 154.66,173.44 154.46,174.41 154.46,178.99 151.52,181.93 151.04,182.34 151.02,182.35 150.52,182.74 149.9,183.12 147.79,184.2 147.48,184.32 147.42,184.35 145.88,184.94 145.04,185.32 144.59,185.57 144.31,185.77 139.58,190.5 139.58,199.98 137.83,201.73 104.76,201.73 104.4,201.61 104.21,201.5 104.18,201.48 103.92,201.21 103.9,201.19 103.7,200.86 101.42,195.62 101.31,195.43 101.23,195.28 100.78,194.69 100.66,194.54 100.29,194.2 100.26,194.17 100.1,194.07 98.93,193.68 97.62,193.46 92.14,193.46 83.95,201.65 74.55,201.65 64.73,211.47 60.05,211.47 59.33,211.74 59.07,211.83 58.1,212.15 57.49,212.37 56.67,212.68 49.38,215.32 42.75,217.48 36.69,222.5 36.14,222.5 35.53,223.11 35.53,227.53 36.3,228.3 37.36,228.3 v1(37.49,228.43)
CNV_WT_RCOMP: length 8.8
  TOP w0.102: SB1.BA1 160.32,111.39 160.32,110.88 160.78,110.05 161.44,109.39 161.8,109.39 161.98,109.58 163.6,109.58 164.72,110.69 v2(165.81,110.69) 165.85,110.73 166.85,110.73 R1512.1
CPU1_AY3: length 2.7
  TOP w0.102: CPU1.AY3 v1(92.68,115.84)
  BOTTOM w0.102: R903.2 92.99,116.85 v2(92.99,116.79) 92.99,116.15 v1(92.68,115.84)
CPU1_G8: length 2.9
  TOP w0.102: CPU1.G8 88.01,85.57 v1(88.09,85.57)
  BOTTOM w0.102: R902.2 87.22,87.36 v2(88.02,86.56) 88.09,86.5 v1(88.09,85.57)
CPU_FAN_CTRL_CONN: length 7.7
  TOP w0.102: FANC1.4 10.33,134.89 10.95,135.51 11.3,135.51 11.95,134.86 R2605.2 R2603.2
CPU_FAN_CTRL_SIO: length 308.6
  TOP w0.102: v3(176.4,18.16) 176.4,20.61 177.57,21.78 U2401.47 ; v3(25.17,25.4) 25.15,25.4 24.64,24.89 22.23,24.89 10.86,36.27 10.66,36.56 9.89,37.33 9.6,37.53 1.07,46.06 1.07,129.96 2.85,131.74 4.21,133.1 6.29,133.1 7.02,133.82 R2605.1
  BOTTOM w0.102: v3(176.4,18.16) 166.49,18.16 163.02,14.69 163.02,12.39 159.23,8.61 153.48,8.61 152.72,9.37 147.39,9.37 146.25,10.51 146.25,10.98 143.31,13.92 133.44,13.92 130.48,10.96 130.48,8.58 125.1,3.2 124.68,2.79 97.93,2.79 97.72,3 97,3 96.79,2.79 79.33,2.79 78.91,3.2 76.88,5.23 54.79,5.23 48.67,11.35 47.82,11.35 36.97,22.2 32.77,22.2 29.18,25.78 v2(27.69,25.78) 27.3,25.4 v3(25.17,25.4)
CPU_FAN_TACH_1: length 7
  TOP w0.102: R2602.1 12.03,137.2 12.01,137.18 11.82,137.38 R2601.2 11.04,137.38 9.99,136.33 8.1,136.33 FANC1.3
CPU_FAN_TACH_SIO: length 314.9
  TOP w0.102: R2602.2 R2604.1 14.15,138.07 14.73,137.49 14.73,133.6 14.39,133.26 6.78,133.26 6.64,133.12 6.26,132.74 4.35,132.74 1.3,129.68 1.3,46.15 9.28,38.16 9.82,37.8 22.23,25.4 v3(24.26,25.4) ; U2401.37 177.65,17.78 177.34,18.08 v3(177.34,18.16)
  BOTTOM w0.102: v3(24.26,25.4) 25.4,26.54 v2(26.29,26.54) 28.97,26.54 32.96,22.56 37.12,22.56 47.97,11.71 48.81,11.71 54.93,5.59 77.03,5.59 79.47,3.14 96.64,3.14 96.85,3.35 97.87,3.35 98.08,3.14 124.54,3.14 130.12,8.73 130.12,11.11 133.29,14.27 143.46,14.27 146.61,11.13 146.61,10.66 147.54,9.73 152.87,9.73 153.63,8.97 159.09,8.97 162.66,12.54 162.66,14.84 166.34,18.52 176.11,18.52 176.21,18.62 176.89,18.62 v3(177.34,18.16)
CPU_THERMDA+: length 128
  TOP w0.127: 103.86,43.54 C2401.1 ; 103.86,43.54 103.33,44.06 Q2404.B 103.33,45.19 104.32,46.17 Q2404.C ; 103.86,43.54 104.18,43.22 104.18,41.73 106.5,39.41 106.95,39.41 106.95,39.41 107.56,39.41 v3(107.85,39.12) ; U2401.41 179.49,19.38 179.83,19.03 179.88,19.03 181.03,17.88 181.44,17.88 C2404.1 182.16,18.02 182.37,18.02 182.38,18.02 v3(182.75,18.02) ; v3(170.09,19.46) 170.44,19.81 170.8,19.81 171.27,20.28 171.27,22.28 163.94,29.61 163.54,29.61 162.33,30.82 162.33,31.14 v3(162.69,31.5)
  BOTTOM w0.127: 118.59,38.55 119.34,37.8 129.1,37.8 132.61,41.31 132.61,43.7 136.98,48.06 154.25,48.06 155.15,47.16 155.15,44.25 154.03,43.12 154.03,40.56 151.56,38.1 151.56,34.86 156.04,30.38 161.76,30.38 162.32,30.93 162.32,31.13 v3(162.69,31.5) ; 118.59,38.55 v2(118.33,38.29) ; 118.59,38.55 117.65,39.48 116.04,39.48 115.77,39.22 107.95,39.22 v3(107.85,39.12) ; v3(170.09,19.46) 170.45,19.82 179.05,19.82 180.56,18.31 182.46,18.31 v3(182.75,18.02)
CPU_THERMDA-: length 124.8
  TOP w0.127: v3(161.77,31.5) 162.05,31.22 162.05,30.7 163.42,29.33 163.82,29.33 170.99,22.16 170.99,20.39 170.69,20.09 170.36,20.09 v3(170.08,20.38) ; v3(182.75,18.94) 182.75,18.8 182.25,18.3 181.92,18.3 C2404.2 181.42,18.16 181.15,18.16 179.99,19.31 179.95,19.31 179.49,19.78 U2401.42 ; v3(107.78,40.08) 107.39,39.69 107.07,39.69 107.07,39.69 106.61,39.69 104.46,41.85 104.46,43.22 104.76,43.53 C2401.2 104.77,43.54 105.3,44.06 Q2404.E
  BOTTOM w0.127: v3(161.77,31.5) 162.04,31.23 162.04,31.05 161.65,30.66 156.15,30.66 151.84,34.97 151.84,37.98 154.31,40.45 154.31,43.01 155.43,44.14 155.43,47.28 154.36,48.34 136.86,48.34 132.33,43.82 132.33,41.43 128.98,38.07 119.46,38.07 117.77,39.76 115.92,39.76 115.66,39.5 113.23,39.5 ; v3(170.08,20.38) 170.35,20.1 179.16,20.1 180.67,18.59 182.32,18.59 182.65,18.92 182.74,18.92 v3(182.75,18.94) ; 113.23,39.5 108.25,39.5 108.12,39.62 108.12,39.74 v3(107.78,40.08) ; 113.23,39.5 v2(113.23,39.83)
CPVEE: length 6.3
  TOP w0.254: v2(61.4,264.95) 61.41,264.95 61.7,264.66 64.65,264.66 65.17,264.13 U2701.33
  TOP w0.508: C2701.2 61.4,266 v2(61.4,264.95)
DAS/DSS#: length 393.6
  TOP w0.102: v3(149.86,186.4) 149.39,185.93 120.3,185.93 117.42,185.6 82.97,185.6 82.86,185.49 68.61,185.49 64.59,189.51 64.59,194.46 63.88,195.17 63.63,195.9 57.69,201.83 57.58,201.94 57.58,209.14 55.42,211.3 55.42,220.01 55.16,220.27 55.16,223.88 54.65,224.4 54.65,225.39 55.04,225.78 55.04,237.23 53.79,238.48 47.35,238.48 36.48,249.35 34.44,249.35 v2(29.54,254.25) 27.58,254.25 26.53,255.31 R9922.2 27.19,255.32 27.37,255.14 27.75,255.14 28.02,255.41 28.02,255.79 27.72,256.08 27.43,256.08 27.23,256.29 U6402.2 ; v3(146.62,91.78) 146.76,91.64 146.76,88.49 146.61,88.34 146.61,46.05 148.6,44.05 148.6,38.22 147.96,37.57 147.96,29.91 149.15,28.72 149.15,23.26 151.24,21.16 151.24,13.92 149.8,12.48 146.62,12.48 146.35,12.74 146.35,13.4 147,14.04 NGFF2.10
  BOTTOM w0.102: v3(149.86,186.4) 150.39,185.87 150.41,185.85 150.82,185.62 154.01,185.62 154.18,185.46 158.6,181.04 158.6,180.85 158.6,180.66 158.6,179.74 159.41,178.93 159.41,176.25 160.64,175.01 160.64,168.44 160.68,168.23 160.68,168.21 160.93,166.89 160.95,166.76 160.99,166.72 161.73,165.97 161.73,162.82 161.45,162.54 161.45,161 161.72,160.73 161.97,160.73 162.32,160.38 162.32,154.76 162.01,154.45 162.01,153.67 161.48,153.14 161.02,153.14 160.53,152.64 160.53,151.51 160.55,151.49 160.55,143.58 158.75,141.78 158.75,140.58 156.64,138.48 156.64,135.69 156.26,135.31 156.26,132.67 156.08,132.5 156.08,131.97 155.4,131.29 155.4,129.87 155.47,129.8 155.47,129.25 155.8,128.92 155.8,126.97 156.64,126.13 156.64,124.81 157.1,124.35 157.83,124.35 158.07,124.12 158.86,124.12 159.32,123.66 159.32,122.18 160.78,120.73 162.17,120.73 164.92,117.98 164.92,117.85 166.34,116.43 166.34,113.48 165.77,112.9 165.77,112.78 165.58,112.59 165.58,111.08 164.35,109.84 164.18,109.84 162.49,108.15 162.49,105.92 162.58,105.84 162.58,104.85 161.44,103.71 161.44,98.96 158.65,96.16 150.19,96.16 149.28,95.25 147.74,95.25 147.32,94.83 147.32,92.48 v3(146.62,91.78)
DAS/DSS#_NMOS: length 5.6
  TOP w0.102: R6421.1 25.07,259.71 v2(25.4,260.05) 25.91,260.05 26.06,259.89 26.06,258.8 26.16,258.7 U6402.6 26.58,259.3 26.74,259.46 27.05,259.46 27.23,259.28 U6402.5
DCPRTC: length 6.7
  TOP w0.203: C2101.1 165.94,137.53 v2(165.94,137.46) 165.05,136.57 165.05,135.75 163.76,134.46 SB1.BG47 SB1.BF47
DDI_VGA_DATA_C_N2: length 4.1
  TOP w0.102: C5913.1 61.62,21.47 60.93,21.47 59.52,20.07 59.15,20.07 59.06,20.16 U5901.6
DDI_VGA_DATA_C_N3: length 5.3
  TOP w0.102: 59.94,23.04 59.94,21.48 59.33,20.87 58.93,20.87 58.84,20.96 U5901.8 ; 59.94,23.04 v2(59.56,23.04) ; 59.94,23.04 59.94,23.39 60.17,23.62 60.51,23.62 C5915.1
DDI_VGA_DATA_C_P2: length 4.6
  TOP w0.102: v2(60.58,20.29) 60.32,20.56 ; 60.32,20.56 61.02,21.26 61.42,21.26 61.85,20.83 C5912.1 ; 60.32,20.56 59.61,19.85 59.15,19.85 59.06,19.76 U5901.5
DDI_VGA_DATA_C_P3: length 5.3
  TOP w0.102: 60.16,21.92 60.16,23.3 60.26,23.4 60.43,23.4 C5914.1 ; 60.16,21.92 60.16,21.39 59.42,20.65 58.95,20.65 58.86,20.56 U5901.7 ; 60.16,21.92 v2(60.53,21.92)
DDI_VGA_DATA_CPU_N2: length 108.7
  TOP w0.102: v3(63.6,21.84) 63.47,21.72 C5913.2 ; CPU1.H10 v1(86.27,85.66)
  BOTTOM w0.102: 66.73,26.29 67.33,26.29 71.08,30.04 72.96,30.04 74.11,31.19 88.3,31.19 90.7,33.59 92.87,33.59 104.31,45.02 104.31,47.39 102.48,49.22 102.48,58.08 102.48,58.84 100.36,60.96 100.36,68.4 94.99,73.76 94.24,73.76 94.23,73.76 90.39,73.76 85.8,78.35 85.8,82.17 86.06,82.43 86.06,85.44 v1(86.27,85.66) ; 66.73,26.29 v2(66.73,25.91) ; 66.73,26.29 64.08,26.29 62.23,24.44 62.23,21.62 62.7,21.15 63.02,21.15 63.12,21.25 63.12,21.72 63.25,21.84 v3(63.6,21.84)
DDI_VGA_DATA_CPU_N3: length 104.6
  TOP w0.102: C5915.2 62.2,23.58 62.45,23.58 62.71,23.85 v3(62.71,23.99) ; CPU1.G9 v1(87.18,84.74)
  BOTTOM w0.102: v3(62.71,23.99) 63.12,23.58 63.66,23.58 64.11,24.03 64.11,24.46 64.47,24.82 64.56,24.82 ; 64.56,24.82 66.54,24.82 71.27,29.54 73.14,29.54 74.31,30.71 88.5,30.71 90.9,33.11 93.07,33.11 104.79,44.82 104.79,47.59 102.98,49.4 102.98,59.02 100.84,61.16 100.84,68.6 95.19,74.24 94.03,74.24 90.59,74.24 86.36,78.47 86.36,81.59 86.61,81.84 86.61,82.32 86.32,82.61 86.32,84.11 86.6,84.39 86.83,84.39 v1(87.18,84.74) ; 64.56,24.82 v2(64.56,25.2)
DDI_VGA_DATA_CPU_P2: length 108.6
  TOP w0.102: C5912.2 63.55,20.83 v3(63.65,20.93) ; v1(85.38,85.63) CPU1.G10
  BOTTOM w0.102: v3(63.65,20.93) 62.61,20.93 62.01,21.53 62.01,24.52 63.99,26.5 65.02,26.5 ; v2(65.02,26.87) 65.02,26.5 ; 65.02,26.5 67.24,26.5 70.99,30.25 72.87,30.25 74.02,31.4 88.21,31.4 90.61,33.81 92.78,33.81 104.09,45.11 104.09,47.3 102.26,49.13 102.26,58.17 102.26,58.75 100.14,60.87 100.14,68.31 94.9,73.55 94.32,73.55 90.3,73.55 85.58,78.26 85.58,82.26 85.84,82.52 85.84,85.17 v1(85.38,85.63)
DDI_VGA_DATA_CPU_P3: length 104.7
  TOP w0.102: v3(62.75,23.08) 62.46,23.37 62.2,23.37 61.79,22.95 C5914.2 ; v1(87.18,83.83) 87.18,84.19 87.09,84.28 CPU1.F9
  BOTTOM w0.102: 65.58,24.6 66.63,24.6 71.35,29.32 73.23,29.32 74.4,30.49 88.59,30.49 90.99,32.89 93.16,32.89 105,44.73 105,47.68 103.2,49.49 103.2,59.11 101.05,61.25 101.05,68.69 95.28,74.46 93.95,74.46 93.94,74.46 90.68,74.46 86.58,78.56 86.58,81.5 86.83,81.75 86.83,82.41 86.54,82.7 86.54,84.02 86.69,84.18 86.83,84.18 v1(87.18,83.83) ; 65.58,24.6 64.56,24.6 64.33,24.37 64.33,23.94 63.75,23.37 63.04,23.37 v3(62.75,23.08) ; 65.58,24.6 v2(65.58,24.23)
DDPC_CTRL_CLK: length 32.2
  TOP w0.102: R1906.1 163.26,90.75 163.16,90.86 162.98,90.86 162.1,91.73 162.1,94.27 161.24,95.13 161.24,95.96 159.28,97.91 v3(159.28,98.5) ; SB1.AN13 156.96,117.51 156.96,116.84 v1(156.36,116.25)
  BOTTOM w0.102: v3(159.28,98.5) 159.52,98.5 160.43,99.4 160.43,102.91 160.43,102.91 160.43,103.29 160.43,104.24 160.01,104.65 160.01,105.15 160.01,105.15 160.01,105.91 160.2,106.09 160.2,106.96 160.2,107.12 159.84,107.48 159.84,107.48 159.28,108.04 v2(159.28,109.22) 159.28,111.01 157.96,112.33 157.96,112.65 156.74,113.87 156.74,115.86 v1(156.36,116.25)
DDPC_CTRL_DATA: length 26.6
  TOP w0.102: R2327.1 162.15,95.51 162.15,96.39 160.63,97.92 160.63,100.16 159.67,101.12 v3(159.28,101.12) ; v1(154.38,114.02) 154.58,114.22 154.58,114.23 154.76,114.41 154.78,114.41 155.45,115.07 155.45,116.21 SB1.AL10
  BOTTOM w0.102: v3(159.28,101.12) 159.28,104.09 159.1,104.27 159.1,106.25 159.1,106.25 159.1,106.29 159.26,106.45 159.28,106.47 159.28,106.74 157.86,108.16 157.86,108.71 156.06,110.52 155.76,110.52 154.74,111.53 v2(154.74,112.58) 154.74,113.68 154.41,114.02 v1(154.38,114.02)
DDPD_CTRL_CLK: length 26.2
  TOP w0.102: SB1.AL9 155.79,114.32 v1(155.42,113.94) ; v3(159.49,100.2) 159.7,100.2 160.33,99.57 160.33,97.84 161.93,96.24 161.93,95.42 162.79,94.56 162.79,93.86 R1907.1
  BOTTOM w0.102: v3(159.49,100.2) 159.74,100.45 159.74,102.62 159.74,103 159.74,103.96 159.33,104.37 159.33,106.19 159.51,106.38 159.51,106.84 158.12,108.23 158.12,108.87 155.91,111.08 155.91,112.22 v2(155.98,112.29) 156.01,112.32 156.01,113.36 155.98,113.39 155.98,113.44 155.96,113.46 155.96,113.48 155.74,113.69 155.68,113.69 v1(155.42,113.94)
DDPD_CTRL_DATA: length 10.7
  TOP w0.102: R2329.1 161.94,104.55 161.53,104.55 160.71,105.37 v2(160.71,106.12) 160.12,106.71 160.12,107.12 159.89,107.35 159.89,108.28 158.23,109.95 158.23,110.23 157.63,110.82 157.63,111.33 157.66,111.36 157.66,112.59 SB1.AR3
DDR_VTT_CNTL_CPU: length 5.7
  TOP w0.102: R414.2 23.24,170.88 R4025.1 23.05,170.31 v3(22.58,170.31) 21.6,171.28 U401.3
  BOTTOM w0.102: v3(22.58,170.31) v2(23.47,170.79)
DDR_VTT_CNTL_GATE: length 6.7
  TOP w0.102: U401.5 20.95,174.76 20.68,175.03 ; 20.68,175.03 21.03,175.03 21.73,175.73 v3(21.73,175.76) 22.43,175.76 R413.2 ; 20.68,175.03 20.48,175.03 20.31,174.85 U401.6
  BOTTOM w0.102: v3(21.73,175.76) 21.75,175.77 v2(22.76,175.77)
DDR_VTT_CNTL_R: length 3.7
  TOP w0.102: v3(21.72,170.31) 21.46,170.56 R416.1 20.88,170.57 20.88,170.87 20.95,170.94 U401.2
  BOTTOM w0.102: v2(20.85,170.79) v3(21.72,170.31)
DDSP_B_TX_N0: length 30
  TOP w0.102: v3(70.15,24.43) 70.22,24.43 70.36,24.56 R5607.2 ; R5601.2 79.11,25.51 78.35,24.75 R5604.2 78.26,24.73 78.26,24.38 v3(77.85,23.98) ; Q5601.6 66.77,19.63 67.77,20.63 67.77,22.52 v3(68.02,22.78) ; v3(82.27,26.72) 82.3,26.7 R5602.2 ; v3(74.52,24.21) 74.52,24.12 R5606.2 R5603.2 ; R5608.2 73.39,25.08 73,24.69 73,24.49 72.85,24.33 v3(72.77,24.33) 72.77,23.85 72.8,23.83 72.8,23.72 72.4,23.33 R5605.2
  BOTTOM w0.102: v3(82.27,26.72) 81.94,26.72 79.2,23.98 v3(77.85,23.98) 76.12,23.98 v2(76.07,24.03) 75.9,24.21 v3(74.52,24.21) 72.9,24.21 v3(72.77,24.33) 72.68,24.43 v3(70.15,24.43) 69.67,24.43 v3(68.02,22.78)
DEVSLP: length 16.8
  TOP w0.102: R6201.1 136.99,5.14 v2(136.86,5.28) 136.83,5.28 134.79,7.32 134.79,11.11 135.19,11.51 139.12,11.51 140,12.39 NGFF2.38
DEVSLP_N: length 162.7
  TOP w0.102: v1(157.35,124.96) 157.06,125.25 157.06,125.96 156.29,126.73 156.29,127.03 156.11,127.21 156.11,127.51 155.69,127.94 154.67,127.94 SB1.AH35 ; R6201.2 138.77,3.38 148.43,3.38 153.24,8.19 153.24,10.29 153.19,10.34 153.19,11 153.73,11.55 153.73,22.2 153.71,22.22 151.82,24.11 151.82,29.61 150.48,30.95 150.48,32.66 150.85,33.03 150.85,42.31 152.03,43.5 152.03,45.36 151.22,46.18 150.68,46.18 149.49,47.36 149.49,68.54 149.92,68.97 149.92,92.61 148.83,93.7 148.83,93.74 v3(148.46,94.11)
  BOTTOM w0.102: v3(148.46,94.11) 148.84,94.11 150.44,95.71 158.84,95.71 161.9,98.77 161.9,103.52 163.04,104.66 163.04,106.02 162.95,106.11 162.95,107.96 163.22,108.23 163.31,108.23 165.99,110.91 165.99,111.56 166.84,112.41 166.84,114.17 166.8,114.2 166.8,117.17 v2(166.13,117.84) 165.63,117.84 162.34,121.13 161.57,121.13 160.94,121.13 159.73,122.35 159.73,123.83 159.03,124.52 158.24,124.52 157.8,124.96 v1(157.35,124.96)
DIMM1_EVENT_N: length 17.7
  TOP w0.102: DIMM1.78 83.25,157.77 85.14,159.66 85.14,160.37 85.59,160.82 85.59,161.89 84.79,162.69 84.79,163.61 84.31,164.09 83.27,164.09 82.62,164.74 82.62,168.25 82.41,168.45 82.41,169.15 84.07,170.81 84.07,171.13 R1101.2
DIMM2_EVENT_N: length 7.7
  TOP w0.102: DIMM2.78 83.25,167.9 82.62,168.54 82.62,169.06 82.99,169.44 83.02,169.44 84.3,170.71 84.3,170.75 84.94,171.39 R1201.2
DIMM_CA_CPU_VREF_RC: length 1.5
  TOP w0.305: R602.1 7.89,170.61 C602.2
DIMM_CA_VREF_A: length 4.5
  TOP w0.305: R1105.1 13.56,174.68 12.86,175.38 12.68,175.38 v2(12.67,175.39) 12.52,175.23 R1106.1 12.4,174.49 12.37,174.46 11.51,174.46 R1103.2 11.33,174.33 R601.2
DIMM_CA_VREF_A_L: length 17
  TOP w0.305: R1105.2 13.28,173.32 C1107.1 13.28,172.44 13.25,172.44 11.94,171.31 C1106.1 11.66,171.31 11.36,171.01 10.5,171.01 9.49,170 9.49,168.17 10.31,167.35 10.31,167.11 10.31,167.11 10.31,166.76 10.95,166.13 10.95,162.96 12.71,161.2 DIMM1.146
DIMM_CA_VREF_B: length 2.2
  TOP w0.305: R1203.2 17.74,173.66 16.75,173.66 R1206.1 R1205.1
DIMM_CA_VREF_B_L: length 5.6
  TOP w0.305: R1205.2 R1204.2 14.61,171.65 C1211.1 14.8,171.46 C1210.1 13.55,169.19 DIMM2.146
DIMM_DQ_CPU_VREF_B_RC: length 3
  TOP w0.305: R1207.1 16.64,174.73 v3(16.38,174.47) 16.21,174.65 C1209.2
  BOTTOM w0.305: v2(15.52,174.04) v3(16.38,174.47)
DISP_UTIL_CPU: length 2.7
  TOP w0.102: CPU1.D14 v1(82.59,82.02)
  BOTTOM w0.102: v1(82.59,82.02) 82.12,81.54 82.12,80.7 TP701.1
DLDO_CAP: length 6.2
  TOP w0.254: v3(63.53,256.58) U2701.47
  TOP w0.305: U2701.47 59.94,256.58 C2711.1 58.35,256.65 C2712.1
  BOTTOM w0.254: v2(62.53,256.58) v3(63.53,256.58)
DMI_RX_CPU_N0: length 73.1
  TOP w0.102: CPU1.Y4 91.49,96.89 91.49,96.74 91.72,96.51 100.04,96.51 100.97,95.57 103.81,92.73 105.49,91.06 105.61,90.93 112.1,90.93 113.26,90.93 117.41,95.08 117.41,97.42 122.99,103 122.99,104.92 v3(123.32,105.25) ; SB1.C29 141.67,125.13 141.33,124.79 141.33,124.37 v1(140.94,123.98)
  BOTTOM w0.102: v1(140.94,123.98) 140.68,123.98 140.52,123.83 140.23,123.83 139.32,122.91 137.29,122.91 135.82,121.44 135.82,121.11 126.69,111.98 ; 126.69,111.98 v2(126.96,111.72) ; 126.69,111.98 123.01,108.31 123.01,105.55 v3(123.32,105.25)
DMI_RX_CPU_N1: length 75.3
  TOP w0.102: CPU1.AA5 90.57,97.81 90.57,97.6 90.76,97.42 92.49,97.42 92.86,97.04 100.52,97.04 105.93,91.63 112.39,91.63 112.97,91.63 116.71,95.37 116.71,97.85 121.82,102.95 121.82,106.83 v3(122.17,107.19) ; v1(139.89,124.8) 139.73,124.97 139.73,125.37 139.94,125.59 140.88,125.59 141.28,125.98 141.86,125.98 SB1.C31
  BOTTOM w0.102: v1(139.89,124.8) 139.88,124.8 139.71,124.63 139.71,123.97 139.35,123.61 136.59,123.61 129.43,116.45 ; v3(122.17,107.19) 122.17,109.19 129.43,116.45 ; 129.43,116.45 v2(129.69,116.18)
DMI_RX_CPU_N2: length 73.5
  TOP w0.102: SB1.C32 141.86,126.63 141.32,126.63 140.69,126.01 139.88,126.01 v1(139.5,126.39) ; v3(120.08,105.26) 120.51,104.83 120.51,102.94 120.14,102.57 115.8,98.23 115.8,95.75 112.59,92.54 106.4,92.54 100.99,97.96 93.77,97.96 92.95,98.78 92.35,98.78 CPU1.AB3
  BOTTOM w0.102: 120.41,108.08 120.41,108.99 136.97,125.55 139.45,125.55 139.74,125.84 139.74,126.15 v1(139.5,126.39) ; 120.41,108.08 v2(120.04,108.08) ; 120.41,108.08 120.41,105.59 v3(120.08,105.26)
DMI_RX_CPU_N3: length 76.4
  TOP w0.102: SB1.C33 141.51,128.08 140.07,128.08 139.56,127.57 139.56,127.26 v1(139.3,126.99) ; v3(119.73,107.11) 119.38,106.76 119.38,105.03 119.84,104.57 119.84,102.95 119.66,102.77 115.32,98.43 115.32,95.95 112.39,93.03 106.6,93.03 104.25,95.38 101.19,98.44 93.66,98.44 92.86,99.24 90.76,99.24 90.57,99.43 90.57,99.64 CPU1.AC5
  BOTTOM w0.102: 137.34,126.85 138.06,127.57 139.13,127.57 139.3,127.4 v1(139.3,126.99) ; 137.34,126.85 119.41,108.91 119.41,107.44 v3(119.73,107.11) ; 137.34,126.85 v2(137.6,126.58)
DMI_RX_CPU_P0: length 73.2
  TOP w0.102: CPU1.Y3 91.81,97.09 91.71,96.98 91.71,96.98 91.71,96.82 91.81,96.72 100.13,96.72 105.7,91.15 112.19,91.15 113.17,91.15 117.2,95.17 117.2,97.51 122.77,103.09 122.77,105.07 122.63,105.21 v3(122.4,105.21) ; v1(140.59,124.55) 140.75,124.38 141.05,124.38 141.12,124.46 141.12,124.88 141.48,125.24 SB1.B29
  BOTTOM w0.102: v3(122.4,105.21) 122.8,105.6 122.8,108.4 125.27,110.87 ; 125.27,110.87 135.6,121.2 135.6,121.53 137.2,123.13 139.23,123.13 140.14,124.04 140.43,124.04 140.59,124.2 v1(140.59,124.55) ; 125.27,110.87 v2(124.99,111.15)
DMI_RX_CPU_P1: length 75.3
  TOP w0.102: SB1.B31 141.22,126.23 140.8,125.81 139.85,125.81 139.51,125.46 139.51,124.98 139.37,124.84 v1(139.26,124.84) ; CPU1.AA4 91.3,98 90.89,98 90.79,97.89 90.79,97.69 90.85,97.63 92.58,97.63 92.95,97.26 100.61,97.26 106.02,91.85 112.48,91.85 112.88,91.85 116.5,95.46 116.5,97.94 121.6,103.04 121.6,106.82 v3(121.23,107.19)
  BOTTOM w0.102: 121.96,108.31 121.96,109.28 136.5,123.83 139.26,123.83 139.5,124.06 139.5,124.6 v1(139.26,124.84) ; 121.96,108.31 121.96,107.77 121.86,107.67 121.34,107.67 121.23,107.57 v3(121.23,107.19) ; 121.96,108.31 v2(121.59,108.31)
DMI_RX_CPU_P2: length 73.5
  TOP w0.102: v3(120.99,105.26) 120.73,105 120.73,102.85 120.36,102.48 116.02,98.14 116.02,95.66 112.68,92.33 106.31,92.33 100.9,97.74 93.68,97.74 92.86,98.56 91.65,98.56 CPU1.AB4 ; v1(140.16,126.42) 140.16,126.4 140.34,126.23 140.6,126.23 141.27,126.89 SB1.B32
  BOTTOM w0.102: v1(140.16,126.42) 139.95,126.21 139.95,125.75 139.54,125.34 137.74,125.34 ; v2(137.74,124.94) 137.74,125.34 ; 137.74,125.34 137.06,125.34 120.62,108.9 120.62,105.64 v3(120.99,105.26)
DMI_RX_CPU_P3: length 76.4
  TOP w0.102: SB1.B33 141.53,127.61 141.53,127.75 141.42,127.86 140.16,127.86 139.78,127.48 139.78,127.33 v1(140.06,127.04) ; CPU1.AC4 90.9,99.83 90.89,99.83 90.79,99.72 90.79,99.52 90.85,99.46 92.95,99.46 93.75,98.65 101.28,98.65 106.69,93.24 112.3,93.24 115.1,96.04 115.1,98.52 119.44,102.86 119.62,103.04 119.62,104.48 119.16,104.94 119.16,106.77 v3(118.82,107.11)
  BOTTOM w0.102: v2(118.82,108.61) 119.19,108.61 ; 119.19,108.61 119.19,109 137.97,127.79 139.22,127.79 139.55,127.46 139.98,127.46 140.06,127.38 v1(140.06,127.04) ; 119.19,108.61 119.19,107.48 v3(118.82,107.11)
DMI_TX_CPU_N0: length 68.4
  TOP w0.102: CPU1.AC1 93.79,99.83 93.7,99.74 93.7,99.47 93.82,99.35 105.89,99.35 108.64,102.11 112.42,102.11 114.58,104.27 114.58,107.39 v3(114.21,107.76) ; SB1.G30 v1(143.96,125.42)
  BOTTOM w0.102: v3(114.21,107.76) 114.59,108.14 114.59,108.93 115.53,109.87 118.54,109.87 ; 118.54,109.87 v2(118.54,110.26) ; 118.54,109.87 118.98,109.87 137.6,128.49 139.97,128.49 141.34,127.12 141.34,126.78 142.29,125.83 143.39,125.83 143.42,125.8 143.58,125.8 v1(143.96,125.42)
DMI_TX_CPU_N1: length 70.9
  TOP w0.102: CPU1.AD2 92.86,100.74 92.76,100.64 92.76,100.43 92.82,100.37 94.42,100.37 94.74,100.05 105.6,100.05 108.35,102.81 111.42,102.81 113.21,104.6 113.21,105.63 v3(112.87,105.97) ; v1(144.39,126.87) 144.4,126.88 144.4,126.94 144.76,127.3 145.01,127.3 SB1.K32
  BOTTOM w0.102: 120.08,112.28 118.91,111.11 115.76,111.11 113.22,108.57 113.22,106.32 v3(112.87,105.97) ; 120.08,112.28 136.98,129.18 138.72,129.18 139,128.91 140.37,128.91 141.94,127.34 141.94,126.97 142.66,126.25 143.57,126.25 143.6,126.22 143.93,126.22 144.17,126.46 144.17,126.65 v1(144.39,126.87) ; 120.08,112.28 v2(119.8,112.53)
DMI_TX_CPU_N2: length 68.8
  TOP w0.102: SB1.G33 v1(143.77,126.63) ; v3(111.52,107.84) 111.87,107.48 111.87,104.74 110.64,103.5 108.06,103.5 105.31,100.75 95.76,100.75 95.12,101.38 94.37,101.38 94.28,101.29 93.8,101.29 93.69,101.4 93.69,101.56 93.79,101.66 CPU1.AE1
  BOTTOM w0.102: v2(116.61,112.29) 116.61,111.9 ; 116.61,111.9 115.4,111.9 111.87,108.37 111.87,108.19 v3(111.52,107.84) ; 116.61,111.9 118.02,111.9 136,129.88 138.72,129.88 139.19,129.41 140.74,129.41 142.28,127.88 143.61,127.88 143.92,127.57 143.92,127.25 v1(143.77,126.63)
DMI_TX_CPU_N3: length 70.1
  TOP w0.102: v3(110.93,105.9) 110.93,105.7 110.71,105.47 110.71,104.56 110.13,103.99 107.85,103.99 105.1,101.23 95.86,101.23 95.33,101.76 94.49,101.76 94.25,102 92.59,102 92.4,102.19 92.4,102.38 CPU1.AF3 ; SB1.K34 v1(144.54,127.74)
  BOTTOM w0.102: v1(144.54,127.74) 143.91,127.86 143.64,128.14 143.64,128.56 141.94,130.25 140.42,130.25 140.08,129.91 139.09,129.91 138.63,130.37 135.75,130.37 118.45,113.07 117.91,113.07 ; 117.91,113.07 115.89,113.07 110.87,108.05 110.87,106.31 110.93,106.25 v3(110.93,105.9) ; 117.91,113.07 v2(117.91,112.7)
DMI_TX_CPU_P0: length 68.4
  TOP w0.102: CPU1.AC2 93.39,99.83 93.48,99.74 93.48,99.38 93.73,99.14 105.98,99.14 108.73,101.89 112.51,101.89 114.8,104.18 114.8,107.4 v3(115.14,107.75) ; SB1.F30 143.63,125.86 143.63,125.72 143.32,125.41 v1(143.32,125.41)
  BOTTOM w0.102: 116.74,109.65 115.62,109.65 114.81,108.84 114.81,108.08 v3(115.14,107.75) ; 116.74,109.65 119.07,109.65 137.69,128.27 139.88,128.27 141.12,127.03 141.12,126.7 142.2,125.62 143.11,125.62 v1(143.32,125.41) ; 116.74,109.65 v2(116.74,109.27)
DMI_TX_CPU_P1: length 70.9
  TOP w0.102: v1(144.59,126.14) 144.86,126.14 145.08,126.37 145.08,126.8 SB1.J32 ; CPU1.AD3 92.44,100.74 92.54,100.64 92.54,100.34 92.73,100.16 94.33,100.16 94.65,99.83 105.69,99.83 108.44,102.59 111.51,102.59 113.42,104.51 113.42,105.6 v3(113.78,105.95)
  BOTTOM w0.102: v2(117.3,110.52) 117.3,110.9 ; 117.3,110.9 119,110.9 137.07,128.97 138.63,128.97 138.91,128.69 140.28,128.69 141.72,127.25 141.72,126.88 142.57,126.03 143.48,126.03 143.51,126 144.02,126 144.3,126.28 144.45,126.28 v1(144.59,126.14) ; 117.3,110.9 115.85,110.9 113.44,108.48 113.44,106.3 v3(113.78,105.95)
DMI_TX_CPU_P2: length 68.7
  TOP w0.102: CPU1.AE2 93.38,101.66 93.47,101.57 93.47,101.31 93.71,101.07 94.37,101.07 94.46,101.17 95.03,101.17 95.67,100.53 105.4,100.53 108.15,103.29 110.73,103.29 112.09,104.65 112.09,107.54 v3(112.43,107.88) ; v1(143.49,127.21) 143.76,127.21 143.86,127.31 143.86,127.62 143.76,127.72 SB1.F34
  BOTTOM w0.102: v1(143.49,127.21) 143.63,127.21 143.7,127.28 143.7,127.48 143.52,127.66 142.19,127.66 140.65,129.2 139.1,129.2 138.63,129.67 136.09,129.67 122.12,115.7 ; 122.12,115.7 118.11,111.68 115.49,111.68 112.09,108.28 112.09,107.98 112.19,107.88 v3(112.43,107.88) ; 122.12,115.7 v2(122.39,115.43)
DMI_TX_CPU_P3: length 70.2
  TOP w0.102: SB1.J35 144.85,128.24 144.75,128.14 144.23,128.14 v1(144.14,128.23) ; CPU1.AF2 92.72,102.57 92.62,102.47 92.62,102.28 92.68,102.22 94.34,102.22 94.58,101.97 95.42,101.97 95.94,101.45 105.01,101.45 107.76,104.2 110.04,104.2 110.49,104.65 110.49,105.41 110.39,105.51 110.12,105.51 110.02,105.61 v3(110.02,105.94)
  BOTTOM w0.102: 120.55,115.47 v2(120.28,115.74) ; 120.55,115.47 118.36,113.28 115.8,113.28 110.66,108.14 110.66,106.45 110.55,106.35 110.12,106.35 110.02,106.25 v3(110.02,105.94) ; 120.55,115.47 135.66,130.58 138.72,130.58 139.18,130.12 139.99,130.12 140.33,130.47 142.03,130.47 143.85,128.65 143.85,128.35 143.97,128.23 v1(144.14,128.23)
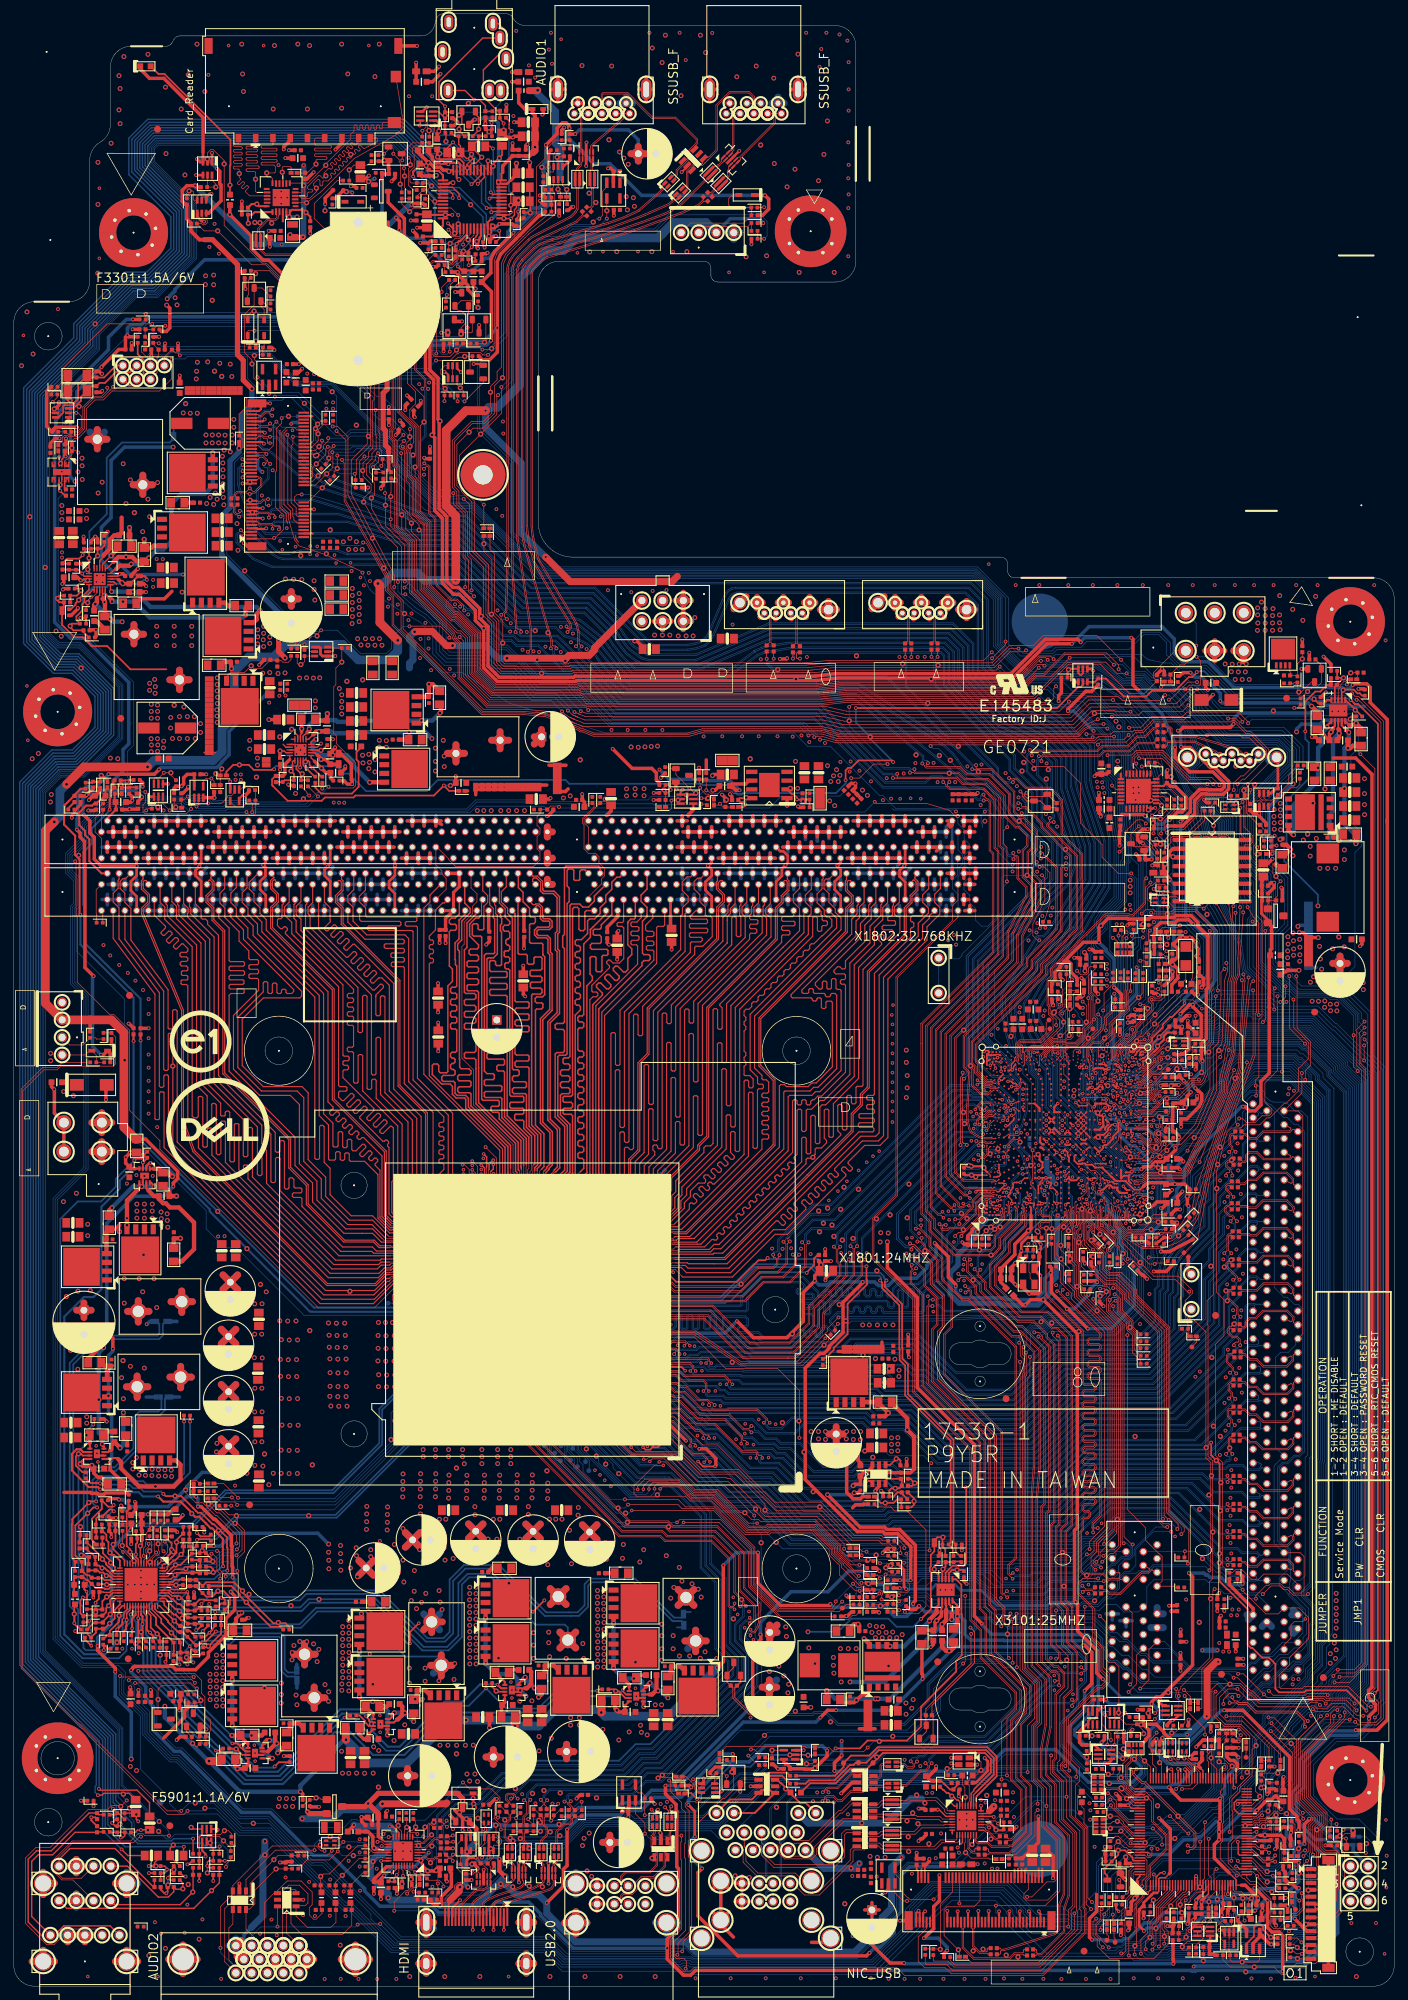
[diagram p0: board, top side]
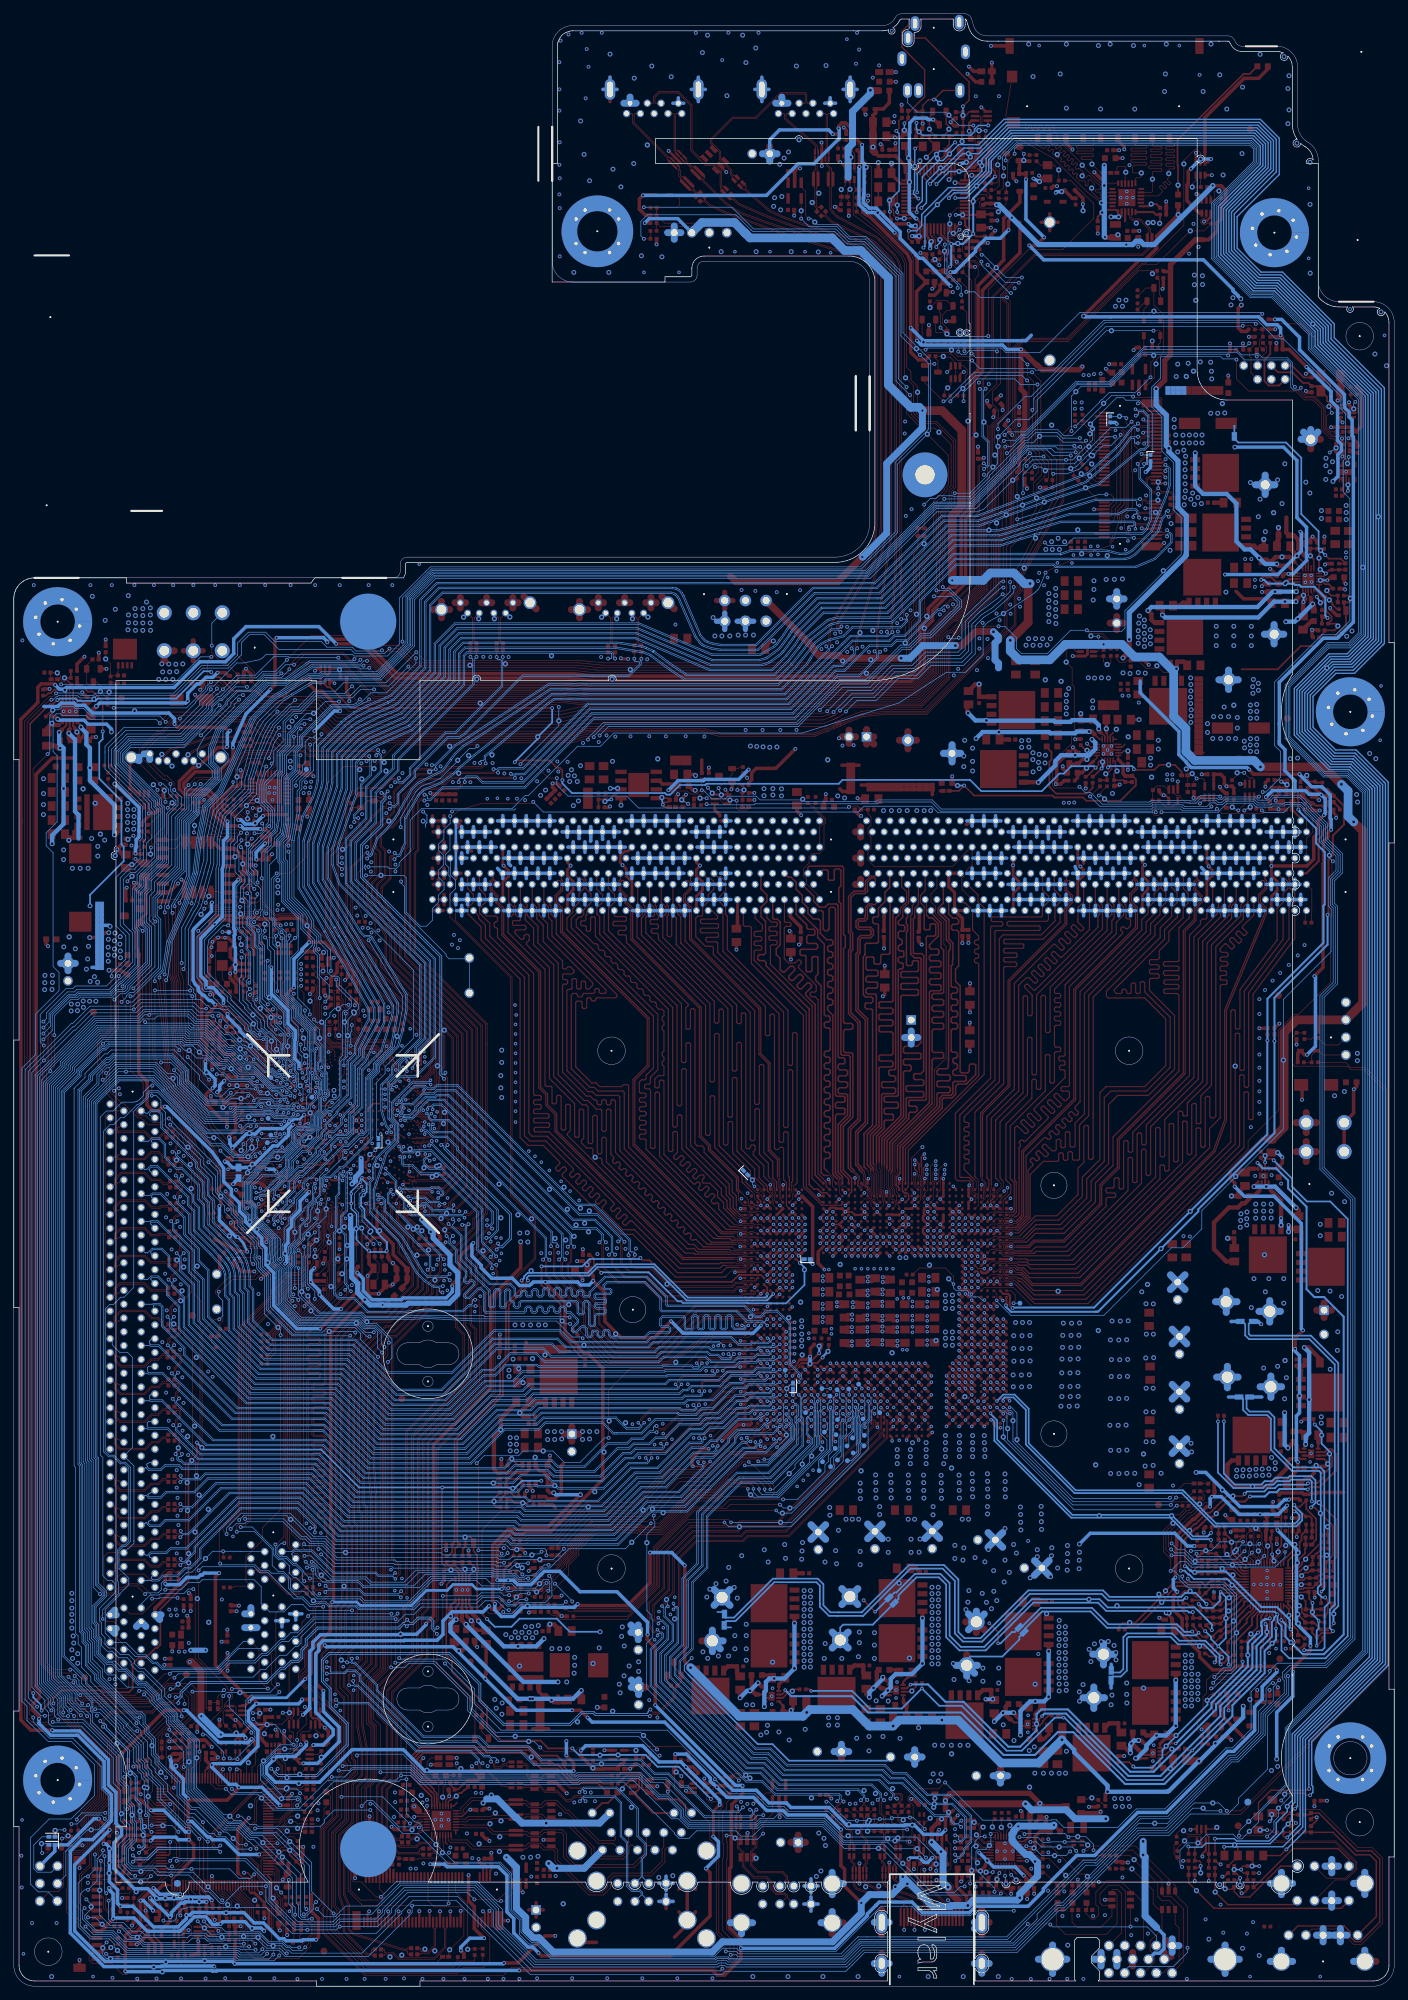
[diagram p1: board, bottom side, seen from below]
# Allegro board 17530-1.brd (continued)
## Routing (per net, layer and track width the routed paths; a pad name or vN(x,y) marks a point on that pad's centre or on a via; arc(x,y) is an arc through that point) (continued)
DP_AUX_CON_N: length 3.7
  TOP w0.102: U5901.3 59.06,18.96 59.15,18.87 59.62,18.87 59.99,18.49 60.78,18.49 61.01,18.72 61.4,18.72 C5911.1
DP_AUX_CON_P: length 4.1
  TOP w0.102: C5910.1 61.39,18.5 61.1,18.5 60.87,18.28 60.38,18.28 ; 60.38,18.28 59.9,18.28 59.53,18.65 59.15,18.65 59.06,18.56 U5901.2 ; 60.38,18.28 v2(60.38,17.88)
DP_AUX_CPU_N: length 109.3
  TOP w0.102: v1(84.44,82.94) 84.41,82.94 CPU1.E12 ; C5911.2 62.98,18.69 63.45,18.69 63.63,18.87 v3(63.63,19.05)
  BOTTOM w0.102: 66.55,27.6 64.41,27.6 61.44,24.64 61.44,20.9 62.45,19.9 62.45,19.35 63.07,18.73 63.31,18.73 v3(63.63,19.05) ; 66.55,27.6 67.65,27.6 70.79,30.73 72.67,30.73 73.82,31.89 88.01,31.89 90.41,34.29 92.58,34.29 103.61,45.31 103.61,47.1 101.78,48.93 101.78,58.55 99.66,60.67 99.66,68.11 94.7,73.06 94.52,73.06 90.1,73.06 84.49,78.67 84.49,79.25 85.18,79.93 85.18,82.34 84.96,82.55 84.83,82.55 v1(84.44,82.94) ; 66.55,27.6 v2(66.55,27.2)
DP_AUX_CPU_P: length 109.3
  TOP w0.102: C5910.2 62.94,18.48 63.46,18.48 63.6,18.34 v3(63.6,18.14) ; CPU1.D12 v1(84.44,82)
  BOTTOM w0.102: 61.23,23.72 61.23,24.73 64.32,27.81 67.56,27.81 70.7,30.95 72.58,30.95 73.73,32.1 87.92,32.1 90.32,34.51 92.49,34.51 103.39,45.4 103.39,47.01 101.56,48.84 101.56,58.46 99.44,60.58 99.44,68.02 94.61,72.85 90.01,72.85 84.27,78.58 84.27,79.34 84.96,80.02 84.96,82.25 84.87,82.33 84.78,82.33 v1(84.44,82) ; 61.23,23.72 v2(60.86,23.72) ; 61.23,23.72 61.23,20.81 62.23,19.81 62.23,19.26 62.98,18.51 63.22,18.51 v3(63.6,18.14)
DP_HPD_CPU: length 257.1
  TOP w0.102: R1701.1 153.04,145.67 153.19,145.82 v3(153.29,145.82) ; v3(62.24,14.45) 62.24,14.75 61.63,15.36 61.23,15.36 61.21,15.34 60.11,15.34 R5910.1 59.83,15.61 59.44,16 59.44,16.2 58.17,17.47 U5901.32 ; v3(146.89,30.99) 146.89,37.77 147.87,38.75 147.87,43.74 145.8,45.81 v3(145.8,90.42) ; SB1.AL15 156.04,118.12 156.78,118.12 157.41,117.49 v1(157.41,116.09)
  BOTTOM w0.102: v1(157.41,116.09) 157.41,115.51 159,113.92 159,112.49 160.15,111.34 160.15,110.92 160.15,110.92 160.15,110.42 160.83,109.75 160.83,107.79 161.11,107.5 161.11,107.34 161.11,107.34 161.11,105.71 160.93,105.53 160.93,105.14 161.33,104.73 ; 161.33,104.73 161.42,104.73 161.84,105.15 161.84,105.53 161.76,105.62 161.76,108.28 163.93,110.45 164.1,110.45 164.97,111.33 164.97,112.84 165.16,113.03 165.16,113.19 165.71,113.74 165.71,115.96 164.12,117.55 161.8,117.55 160.63,118.72 160.63,120.01 158.66,121.98 158.66,122.53 157.45,123.74 156.84,123.74 156.03,124.56 156.03,125.88 154.89,127.02 154.89,127.59 154.05,128.42 153.72,128.42 153.72,128.42 153.36,128.42 152.81,128.97 152.81,134.37 152.37,134.8 152.37,141.08 152.1,141.36 151.67,141.36 151.05,141.97 151.05,142.66 153.29,144.89 v3(153.29,145.82) ; 161.33,104.73 161.33,104.64 160.71,104.01 160.71,103.4 160.71,103.02 160.71,99.26 158.34,96.9 149.89,96.9 148.97,95.99 147.43,95.99 145.21,93.77 145.21,91.01 v3(145.8,90.42) ; v3(62.24,14.45) 62.84,14.45 63.73,13.56 66.95,13.56 v2(71.19,17.79) 73.94,20.55 79.88,20.55 82.77,23.44 91.63,23.44 92.19,22.89 102.33,22.89 103.69,24.25 104.69,24.25 110.27,29.83 117.95,29.83 118.27,29.51 141.07,29.51 141.18,29.62 141.18,29.62 142.56,30.99 v3(146.89,30.99)
EAPD: length 16.4
  TOP w0.102: v3(64.39,256.54) 63.35,257.58 U2701.45 ; v3(62.74,244.98) 62.61,244.86 R2719.1
  BOTTOM w0.102: v3(64.39,256.54) v2(64.39,255.27) 64.39,254.18 64.64,253.93 64.64,251.59 64.59,251.54 64.59,250.92 64.8,250.72 64.8,248.12 64.38,247.7 64.17,247.7 62.74,246.27 v3(62.74,244.98)
EC_PWRGD_3V: length 5.7
  TOP w0.102: U2401.57 179.61,25.78 181.08,27.25 181.08,28.37 v2(180.72,28.74) 180.72,28.74 R2433.2
EDP_5VDDCCL: length 42.9
  TOP w0.102: v3(43.57,19.7) 37.9,19.7 33.64,15.44 EU5902.1 33.64,13.27 33.4,13.03 32.36,13.03 30.56,11.23 30.56,3.53 VGA1.15 ; v3(53.56,22.03) 53.57,22.03 53.92,22.37 55.16,22.37 55.39,22.15 U5901.15 ; RN5901.4 46.75,21.08 47.19,21.52 v3(47.19,21.59)
  BOTTOM w0.102: v3(53.56,22.03) 53.46,22.12 47.73,22.12 v3(47.19,21.59) 47.13,21.66 v2(45.85,21.66) 44.67,21.66 43.57,20.56 v3(43.57,19.7)
EDP_5VDDCDA: length 50.7
  TOP w0.102: v3(47.75,20.9) 47.27,20.43 RN5901.3 ; U5901.16 54.36,21.64 v3(54.31,21.59) ; v3(45.02,19.61) 44.53,19.61 43.83,20.31 37.45,20.31 31.74,14.59 EU5902.3 31.74,13.32 29.95,11.53 v3(29.95,5.56)
  BOTTOM w0.102: v3(54.31,21.59) 54.23,21.51 51.59,21.51 50.89,20.82 49.92,20.82 49.84,20.9 v3(47.75,20.9) 44.86,20.9 v2(44.4,20.45) 44.4,20.23 v3(45.02,19.61) ; VGA1.12 39.04,2.26 38.46,2.84 31.98,2.84 29.95,4.88 v3(29.95,5.56)
EDP_AVC12: length 15.1
  TOP w0.203: U5901.4 59.57,19.36 ; U5901.25 54.68,17.47 54.51,17.3
  TOP w0.508: v3(53.68,16.03) 53.68,16.01 53.19,15.52 C5901.1 C5902.1 52.17,15.47 54,17.3 54.51,17.3
  BOTTOM w0.508: v3(60.11,19.34) v2(58.97,18.2) 58.04,17.27 54.92,17.27 v3(53.68,16.03)
EDP_AVC33: length 5.2
  TOP w0.203: 59.23,17.65 58.72,18.16 U5901.1
  TOP w0.508: 59.23,17.65 59.23,17.4 v2(59.94,16.69) 60.93,16.69 61.32,17.07 L5901.2 61.72,16.01 C5908.1
EDP_BLUE_P: length 14.5
  TOP w0.102: L5905.1 44.45,13.72 44.45,14.59 C5916.1 v2(44.46,15.9) 44.82,16.26 45.72,16.26 49.85,20.38 R5913.1 51.02,20.38 52.04,19.36 U5901.21
EDP_DAC33: length 6.4
  TOP w0.203: U5901.20 53.1,19.76 52.98,19.88 52.72,19.88
  TOP w0.508: L5902.2 49.92,22.42 C5909.1 51.3,22.42 52.02,21.69 52.02,20.19 v2(52.2,20.02) 52.34,19.88 52.72,19.88
EDP_EXPCLKIN: length 3.6
  TOP w0.102: R5904.1 56.26,15.88 56.36,15.98 v3(56.39,15.98) 56.39,16.73 56.19,16.94 U5901.28
  BOTTOM w0.102: v3(56.39,15.98) v2(56.24,14.83)
EDP_GPI1: length 3.5
  TOP w0.102: U5901.11 56.99,22.23 57.29,22.53 57.68,22.53 v2(58.22,23.06) 58.22,23.89 R5905.2
EDP_GPI2: length 2.7
  TOP w0.102: R5906.2 56.93,24.16 56.93,23.02 v2(56.93,23.01) 56.82,22.9 56.82,22.89 56.59,22.66 U5901.12
EDP_GPI3: length 2.9
  TOP w0.102: R5907.2 55.69,24.05 v2(55.69,23.28) 55.69,22.95 56.19,22.45 U5901.13
EDP_GREEN_P: length 10.8
  TOP w0.102: U5901.22 51.72,18.96 51.24,18.48 R5914.1 50.03,18.48 v2(47.6,16.05) 46.62,15.07 C5917.1 46.61,14.59 L5904.1
EDP_HSYNC: length 15
  TOP w0.102: U5901.19 53.43,20.16 53.31,20.28 v3(53.3,20.28) ; v3(46.94,19.53) 45.7,18.29 42.48,18.29 R5917.1
  BOTTOM w0.102: v3(46.94,19.53) 47.56,18.91 v2(49.2,18.91) 51.04,18.91 52.41,20.28 v3(53.3,20.28)
EDP_HSYNC_C: length 21.6
  TOP w0.102: VGA1.13 36.31,1.92 34.7,3.53 34.7,4.48 35.36,5.14 35.36,6.55 33.64,8.27 EU5902.6 33.76,11.1 33.84,11.18 34.17,11.18 34.92,11.93 34.92,13.91 v2(38,16.99) 39.35,16.99 C5923.1 40.31,17.03 R5917.2
EDP_LDORSTB: length 3.6
  TOP w0.102: R5903.1 55.16,15.79 v3(55.49,16.12) 55.49,16.22 55.79,16.52 U5901.27
  BOTTOM w0.102: v3(55.49,16.12) v2(54.76,15.39)
EDP_RED_P: length 8.6
  TOP w0.102: U5901.23 53.46,18.56 53.4,18.62 52.6,18.62 v2(52.04,18.06) 52.04,17.37 51.12,16.45 R5915.1 50.62,16.45 C5918.1 48.77,14.59 L5903.1
EDP_VSYNC: length 13.2
  TOP w0.102: R5916.1 45.39,18.92 v3(46.08,19.61) ; U5901.18 53.69,20.56 53.34,20.9 v3(52.7,20.9)
  BOTTOM w0.102: v3(52.7,20.9) 51.85,20.9 51.11,20.17 v2(48.54,20.17) 46.63,20.17 v3(46.08,19.61)
EDP_VSYNC_C: length 25.7
  TOP w0.102: R5916.2 40.27,18.92 C5922.1 38.29,18.94 v2(37.68,18.33) 34.25,14.9 34.25,13.02 33.65,12.42 32.61,12.42 31.74,11.54 EU5902.4 31.74,9 31.17,8.43 31.17,3.79 32.13,2.82 32.54,2.82 33.45,1.92 VGA1.14
FDI_COMP: length 5.9
  TOP w0.254: CPU1.M9 86.59,90.03 86.28,90.53 86.11,90.78
  TOP w0.508: 86.11,90.78 85.04,90.78 v3(84.63,91.19) 84.58,91.24 84.58,92.39 R701.1
  BOTTOM w0.508: v2(84.65,90.17) 84.63,90.19 v3(84.63,91.19)
FORM_FAC_ID_0: length 15
  TOP w0.102: R6404.2 171.18,136.51 170.74,136.07 170.74,134.88 R6408.1 170.31,134.44 169.85,133.99 169.85,133.26 169.99,133.12 169.99,132.73 169.74,132.47 168.93,132.47 v2(168.5,132.91) 167.73,132.13 166.45,132.13 165.54,131.23 165.54,131 165.06,130.51 165.05,130.51 164.96,130.42 164.85,130.42 164.58,130.15 164.58,129.78 164.62,129.74 164.62,129.4 164.38,129.17 164.04,129.17 163.86,129.34 162.48,129.34 SB1.BD38
FORM_FAC_ID_1: length 15.2
  TOP w0.102: SB1.BF35 164.5,128.43 165.23,129.15 165.23,129.36 165.74,129.87 165.74,130.62 166.16,131.04 168.95,131.04 169.3,130.68 169.71,130.68 169.98,130.95 169.98,131.01 170.44,131.47 170.5,131.47 171.17,131.47 172.05,132.35 v2(172.09,132.35) 172.09,133.48 171.78,133.8 171.78,133.93 171.78,133.93 171.78,134 R6407.1 171.33,135.08 171.18,135.23 R6403.2
FORM_FAC_ID_2: length 27.3
  TOP w0.102: SB1.BD34 160.96,127.04 160.31,127.04 160.13,127.22 160.13,127.37 159.57,127.94 159.23,127.94 159.14,127.85 158.89,127.85 158.71,128.03 158.71,128.28 158.74,128.3 158.74,128.47 158.44,128.76 158.1,128.76 158.06,128.72 155.25,128.72 v3(154.97,128.44) ; R6402.2 151.25,144.06 151.25,142.99 R6406.1 151.1,142.81 151.1,142.57 v3(151.51,142.16)
  BOTTOM w0.102: v3(154.97,128.44) 154.74,128.66 154.61,128.66 154.25,129.02 154.25,129.39 154.25,129.56 154.58,129.89 154.58,132.32 154.82,132.55 154.82,139.92 154.2,140.54 154.2,140.94 153.57,141.58 v2(152.98,141.58) 152.4,142.16 v3(151.51,142.16)
FP_CBL_DET: length 301.5
  TOP w0.089: 163.44,120.93 162.87,120.36 162.01,120.36 161.95,120.42
  TOP w0.102: SB1.BA24 160.41,121.58 160.76,121.23 160.76,120.92 161.26,120.42 161.95,120.42 ; v3(184.25,144.82) 184.25,143.29 v3(183.51,142.55) ; v3(161.24,190.17) 159.82,190.17 158.19,191.8 152.69,191.8 147.74,186.84 120.76,186.84 117.12,186.46 117.09,186.44 82.62,186.44 82.51,186.33 68.96,186.33 65.43,189.86 65.43,195.24 64.66,196.01 64.23,196.01 58.04,202.21 58.04,209.33 56.21,211.16 v2(56.21,213.13) 55.88,213.46 55.88,220.2 55.62,220.46 55.62,223.9 56.41,224.69 56.44,224.69 v3(56.45,224.7) ; 163.44,120.93 163.98,120.93 164.17,121.12 164.55,121.12 165.04,120.62 166.04,120.62 167.84,122.43 168.92,122.43 169,122.5 169.27,122.77 170.5,124.13 171.08,124.71 172.76,128.68 173.3,129.96 173.3,136.02 173.3,136.02 173.3,136.09 173.81,136.6 173.81,136.87 173.82,136.87 v3(174.14,143.38) ; v3(21.01,237.97) 20.94,238.04 R1510.2 20.19,237.84 C9903.1 20.98,236.12 20.75,235.89 20.75,233.7 PWRSW1.6
  BOTTOM w0.102: v3(183.51,142.55) 182.8,142.55 181.64,143.71 174.47,143.71 v3(174.14,143.38) ; v3(21.01,237.97) 21.49,237.49 23.61,237.49 23.61,237.49 36.22,237.49 41.28,232.44 45.77,232.44 45.77,232.44 46.15,232.44 53.44,225.15 55.98,225.15 56.43,224.7 v3(56.45,224.7) ; v3(161.24,190.17) 161.55,189.85 163.72,189.85 165.84,187.73 167.68,187.73 169.27,186.14 169.27,185.82 175.26,179.82 182.99,179.82 184.28,178.54 184.28,177.36 178.87,171.96 178.87,171.18 178.44,170.75 178.44,163.01 180.95,160.49 180.95,159.16 181.64,158.47 181.64,153.81 180.87,153.05 180.87,148.3 184.25,144.93 v3(184.25,144.82)
FP_CBL_DET_PD: length 3.7
  TOP w0.102: U2401.50 179.51,22.98 179.65,22.83 180.77,22.83 v2(181.05,23.12) 181.34,22.83 R2448.2
FP_MIC2_L: length 19.5
  TOP w0.203: v3(70.97,269.83) 70.97,269.9 70.42,270.45 FL2901.2 C2903.1 70.09,271.65 68.03,273.71 68.03,277.56 71.31,280.84 71.31,283.17 70.19,284.29 HPMIC1.4
  BOTTOM w0.203: v2(70.97,268.83) v3(70.97,269.83)
FP_OUT_L: length 9.2
  TOP w0.203: HPMIC1.1 65.37,274.59 v3(66.7,273.27) 67.47,273.27 68.33,272.42 C2906.1 FL2903.2
  BOTTOM w0.203: v2(65.85,272.73) 66.38,273.27 v3(66.7,273.27)
FP_OUT_LL: length 16
  TOP w0.203: Q2901.6 58.9,269.72 58.8,269.62 v3(58.8,269.53) ; R2906.2 R2907.1 69.28,269.81 69.21,269.88 v3(69.21,269.9) 69.21,269.91 69.34,270.04 FL2903.1
  BOTTOM w0.203: v3(58.8,269.53) 60.25,269.53 60.77,269.01 60.77,268.68 61.33,268.12 68.35,268.12 v2(68.85,268.62) 69.22,268.99 69.22,269.9 v3(69.21,269.9)
FP_OUT_R: length 18.5
  TOP w0.203: HPMIC1.2 67.94,282.19 61.59,275.84 61.59,273.18 v3(62.48,272.29) FL2902.2 C2907.1
  BOTTOM w0.203: v2(62.48,270.98) v3(62.48,272.29)
FP_OUT_RR: length 5.6
  TOP w0.203: Q2901.3 61.53,271.54 62.48,270.59 FL2902.1 62.48,270.08 62.45,270.04 R2909.1 62.45,268.53 R2905.2 62.61,268.36 v2(62.61,267.21)
FP_RST_N: length 25.9
  TOP w0.102: SB1.AU2 158.57,111.9 158.65,111.82 158.65,110.1 160.6,108.15 160.6,107.72 161.87,106.45 161.87,106.15 v2(163.2,104.82) 165.18,102.84 168.72,102.84 170.76,100.8 170.76,100.36 169.72,99.32 169.72,96.3 170.14,95.88 R2005.1 170.14,94.44 R9921.1
FP_RST_N_CN: length 1.8
  TOP w0.102: TP9906.1 171.34,93.23 R9921.2
FRONT_JD: length 347.6
  TOP w0.102: v3(22.48,21.79) 18.99,21.79 18.66,22.12 18.05,22.12 16.96,21.03 8.47,21.03 5.43,18 5.43,16.93 6.97,15.39 8.55,15.39 AUD1.23 ; R2710.2 56.21,260.81 v2(55.99,261.03) 56.03,261.07 56.03,264.07 55.83,264.28 55.83,264.59 v3(54.99,265.43)
  BOTTOM w0.102: v3(54.99,265.43) 54.99,266.16 54.47,266.67 20.93,266.67 20.4,266.14 20.4,264.31 26.47,258.24 26.47,250.22 20.82,244.58 17.75,244.58 12.45,239.27 12.45,237.07 5.16,229.78 5.16,196.05 6.59,194.61 9.04,194.61 9.04,194.62 9.66,194.62 15.8,188.48 15.8,180.72 10.24,175.16 6.89,175.16 4.57,172.84 4.57,48.62 15.79,37.41 15.79,29.15 v2(21.07,23.86) 22.48,22.45 v3(22.48,21.79)
GPD7: length 8.2
  TOP w0.089: SB1.BE41 162.71,131.06 163.22,131.06 163.52,131.36 163.82,131.36 164.3,131.84
  TOP w0.102: 164.3,131.84 164.3,131.97 164.78,132.44 165.37,132.44 v2(166.04,133.12) 166.63,133.71 168.48,133.71 168.89,134.12 R2318.1
GPIO_LAN_RESET_N: length 16.1
  TOP w0.102: R1912.1 151.27,145.12 151.97,144.42 151.97,141.97 151.7,141.71 151.35,141.71 v2(150.76,141.12) 150.76,140.69 151.49,139.96 151.49,138.87 148.89,136.27 147.41,136.27 146.46,135.32 146.46,133.51 SB1.M45
GPIO_PCI_RESET_N: length 25.6
  TOP w0.102: SB1.AV43 159.2,132.23 159.54,132.23 v1(159.89,132.59) ; v3(163.65,152.88) 163.65,153.39 163.36,153.68 R1601.1
  BOTTOM w0.102: v2(163.65,153.85) v3(163.65,152.88) 163.65,152.58 164.06,152.17 164.06,151.18 163.68,150.8 163.68,143.37 161.87,141.56 161.87,139.4 160.68,138.21 160.68,136.58 160.88,136.38 160.88,135.91 160.84,135.87 160.84,134.75 159.57,133.48 159.57,132.92 v1(159.89,132.59)
GPIO_PEG_RESET_N: length 7.5
  TOP w0.102: SB1.AT49 158.31,135.31 v3(157.85,135.78) ; v3(158.24,138.46) 158.24,139.17 158.34,139.27 158.34,140.26 159.52,141.44 R1911.1
  BOTTOM w0.102: v3(157.85,135.78) 157.85,137.15 v2(158.03,137.33) 158.24,137.54 v3(158.24,138.46)
GPP_A7: length 13.3
  TOP w0.102: v3(170.59,132.09) 170.59,132.08 170.48,131.98 R1902.1 ; SB1.BA36 160.77,128.4 v1(160.82,128.4)
  BOTTOM w0.102: v3(170.59,132.09) 170.53,132.03 169.65,132.03 168.68,131.06 165.99,131.06 165.44,130.51 165.4,130.51 165.28,130.39 164.82,130.39 164.58,130.15 164.58,129.78 164.62,129.74 164.62,129.4 164.38,129.17 163.42,129.17 v2(163.25,129.33) 162.99,129.33 162.26,128.6 161.01,128.6 v1(160.82,128.4)
GPP_A8: length 11.7
  TOP w0.102: SB1.AV32 159.33,127.11 159.33,127.46 v1(159.4,127.53) ; R2001.1 169.11,126.72 v3(168.59,127.25)
  BOTTOM w0.102: v1(159.4,127.53) 159.55,127.38 161.33,127.38 161.54,127.58 162.79,127.58 v2(163.09,127.89) 163.23,128.03 164.42,128.03 164.98,127.47 168.36,127.47 v3(168.59,127.25)
GPP_H_12: length 7.6
  TOP w0.102: TP1506.1 155.55,137.9 155.55,137.62 154.06,136.13 152.75,136.13 152.67,136.04 152.42,135.8 152.12,135.8 151.7,135.38 151.7,134.91 151.34,134.54 151.34,134.41 SB1.AB47
GPP_H_15: length 15.7
  TOP w0.102: SB1.AC47 152.07,134.52 152.07,135.46 152.21,135.59 152.51,135.59 152.84,135.92 154.33,135.92 156.97,138.56 156.97,140.22 156.63,140.56 156.63,142.26 v2(157.07,142.7) 157.07,143.06 156.16,143.97 156.16,144.9 156.65,145.4 R2301.1
GPP_J1: length 9.9
  TOP w0.102: R1511.2 166.8,109.61 v2(164.79,109.61) 164.79,109.61 163.92,109.61 163.69,109.37 162.07,109.37 161.88,109.18 161.35,109.18 160.61,109.93 160.12,110.83 160.12,111.48 160.31,112.14 160.31,112.46 SB1.AY3
GPP_K3: length 243.1
  TOP w0.102: U6302.G 33.84,244.83 34.02,245.02 34.02,247.14 R6315.1 34.35,247.47 R6314.2 37.02,248.49 47.26,238.25 53.7,238.25 54.81,237.14 54.81,225.87 54.42,225.48 54.42,224.3 54.94,223.79 54.94,220.17 55.19,219.91 55.19,211.2 57.35,209.04 57.35,201.84 57.53,201.67 57.62,201.58 62.36,196.85 63.43,195.77 63.44,195.76 63.65,195.08 64.36,194.37 64.36,189.42 68.51,185.27 82.96,185.27 83.05,185.36 117.68,185.36 120.66,184.68 151.49,184.68 v3(152.88,186.08) ; v3(151.18,136.22) 150.58,136.22 149.37,135.01 149.37,134.89 149.3,134.82 149.3,134.58 SB1.U47 ; v3(151.03,139.22) 151.02,139.22 151.02,140 150.14,140.88 150.14,141.99 149.93,142.2 149.93,145.59 150.42,146.08 150.42,147.04 150.44,147.07 150.44,147.32 158.25,155.12 161.49,155.12 161.6,155.01 162.17,155.01 163.98,156.82 163.98,159.17 v3(164.69,159.87)
  BOTTOM w0.102: v3(151.18,136.22) 151.18,138.2 151.03,138.35 v3(151.03,139.22) ; v3(164.69,159.87) 164.69,161.44 165.4,162.15 165.4,164.38 162.28,167.5 162.21,167.86 162.21,170.46 163.45,171.7 163.45,171.9 163.45,173.26 163.45,173.26 163.45,173.61 163.45,173.93 163.39,174.1 161.54,175.95 161.54,178.3 161.54,178.67 160.32,179.89 160.32,181.42 159.36,182.38 159.36,182.57 157.55,184.38 v2(156.57,184.38) 154.86,186.08 v3(152.88,186.08)
GPP_K5: length 17.4
  TOP w0.102: R1714.1 R1713.1 152.52,143.1 152.3,142.88 152.3,141.87 151.79,141.36 151.72,141.36 151.45,141.09 151.45,140.71 152.1,140.07 v2(152.1,139.65) 152.1,139.05 150.51,137.46 150.39,137.46 148.99,136.07 147.49,136.07 146.94,135.52 146.94,134.5 146.71,134.27 SB1.N47
GREEN_CRT: length 26.7
  TOP w0.102: VGA1.2 38.91,6.01 38.91,13.69 39.85,14.63 41.38,14.63 42.62,13.39 42.62,12.06 42.22,11.66 40.98,11.66 EU5901.1 40.89,10.16 42.55,8.51 45.92,8.51 46.67,9.26 C5920.1 46.67,12 L5904.2
H_PRDY_N: length 44
  TOP w0.102: CPU1.B10 85.81,79.81 88.81,76.81 95.42,76.81 99.15,73.08 103.52,73.08 v2(107.47,69.12) 107.47,68.78 108.69,67.56 116.13,67.56 116.35,67.35 116.35,67.35 119.81,63.88 119.81,63.15 120.09,62.87 120.12,62.87 120.6,62.38 120.68,62.38 120.7,62.41 R9902.2
H_PREQ_N: length 42.9
  TOP w0.102: R9901.2 121.25,63.55 121.25,63.97 116.68,68.53 109.27,68.53 v2(108.84,68.96) 108.84,69.88 104.54,74.17 99.43,74.17 96.38,77.22 89.51,77.22 86.73,80 CPU1.B9
H_PWRGD: length 152.5
  TOP w0.102: v1(94.11,75.44) 92.81,75.44 89.85,72.48 89.85,71.36 90.25,70.97 97.31,70.97 98,70.28 101.1,70.28 105.95,65.42 109.41,65.42 109.65,65.66 115.66,65.66 118.14,63.19 118.14,62.55 118.21,62.38 119.4,61.19 119.42,61.19 119.64,60.97 119.64,59.56 121.92,57.28 v3(122.56,57.28) 122.56,57.06 122.96,56.66 122.96,56.09 123.63,55.42 R9907.1 123.65,55.23 123.65,54.79 123.63,54.78 123.63,54.72 123.62,54.71 123.62,54.24 C402.1 ; CPU1.F8 v1(88.1,83.83) ; R2006.2 152.91,101.81 154,100.72 154,99.91 158.83,95.09 158.83,66.27 156.85,64.3 156.85,62.88 156.08,62.11 156.08,60.96 v3(156.72,60.33)
  BOTTOM w0.102: v1(88.1,83.83) 87.69,83.42 87.69,82.56 87.23,82.1 87.23,81.58 86.88,81.23 86.88,79.17 90.69,75.36 94.03,75.36 v1(94.11,75.44) ; v3(156.72,60.33) 156.64,60.25 156.64,57.16 155.9,56.41 149.72,56.41 149.13,55.83 142.68,55.83 139.45,59.05 131.6,59.05 130.84,58.29 127.83,58.29 127.59,58.05 127.2,57.66 124.46,57.66 v2(123.83,58.29) 123.24,58.88 122.62,58.88 122.35,58.61 122.35,57.48 v3(122.56,57.28)
H_PWRGD_R: length 11.3
  TOP w0.089: SB1.AE3 153.06,112.87 153.06,112.21 152.9,112.05 152.9,111.05 152.72,110.86
  TOP w0.102: 152.72,110.86 151.46,109.6 151.46,107.86 151.12,107.53 151.12,105.96 v2(151.74,105.34) 151.74,105.2 152.91,104.03 R2006.1
H_RSTOUT_XDP_N: length 4
  TOP w0.102: R9910.2 126.7,62.36 127.25,61.8 127.25,61.18 R9909.2 126.54,61.16 126.34,60.96 v2(126.34,60.6) 126.34,60.48 126.8,60.02 R9911.2
H_SKTOCC_CPU: length 138.3
  TOP w0.102: CPU1.AC38 57.58,100.32 v1(57.58,99.34) ; U2405.1 32.86,173.34 33.36,173.85 34.37,173.85 R2478.1 35.01,173.2 R9924.2 35,171.74 35,171.3 35,171.3 35,169.86 34.73,169.6 34.17,169.6 v3(33.71,170.05)
  BOTTOM w0.102: v1(57.58,99.34) 57.58,99.24 55.52,97.18 42.06,97.18 32.28,106.96 30.61,106.96 27.88,109.69 27.88,112.33 16.05,124.15 v2(16.05,134.14) 16.05,142.95 9.14,149.86 9.14,156.06 9.55,156.47 9.55,160.5 8.43,161.62 8.43,163.7 10.57,165.84 10.57,168.02 12.98,170.44 12.98,170.61 13.54,171.17 15.71,171.17 15.94,170.94 17.62,170.94 17.77,170.79 20.02,170.79 20.58,171.35 24.22,171.35 25.52,170.05 v3(33.71,170.05)
H_SKTOCC_N: length 211
  TOP w0.102: v3(148.59,151.5) 148.32,151.5 147.64,152.18 147.64,153.84 149.38,157.26 149.38,160.5 v3(148.97,160.91) ; R1509.2 159.89,107.03 159.66,107.26 159.66,108.18 v3(157.63,110.21) 157.43,110.42 157.43,110.74 157.43,112.22 157.45,112.25 157.45,112.54 157.38,112.62 SB1.AP3 ; U2405.4 31.35,171.59 32.13,170.81 33.12,170.81 34.06,171.75 R9924.1 34.54,171.33 v3(34.54,170.05) ; v3(136.78,169.49) 136.4,169.49 135.56,170.33 132.25,171.32 124.97,171.32 v3(124.74,171.55)
  BOTTOM w0.102: v3(136.78,169.49) 136.78,168.43 137.69,167.51 137.69,166.18 138.47,165.4 138.47,164.56 137.72,163.8 137.72,162.4 138.47,161.65 138.47,160.67 137.66,159.87 137.66,158.83 138.47,158.02 138.47,156.98 139.32,156.13 139.32,154.43 140.21,153.54 141.1,153.54 143.15,155.59 143.15,160.55 143.51,160.91 v2(146.81,160.91) v3(148.97,160.91) ; v3(157.63,110.21) 156.97,110.87 156.97,112.46 156.66,112.78 156.66,113.09 156.13,113.62 156.13,113.97 155.52,114.58 155.52,116.64 155.51,116.65 155.51,117.06 155.03,117.54 154.83,117.54 152.43,119.94 152.43,120.06 152.32,120.16 152.32,120.96 152.08,121.19 151.5,121.19 149.81,122.89 149.15,122.89 148.54,123.49 148.54,131.52 147.45,132.62 147.45,133.48 144.87,136.05 144.27,138.47 144.27,138.47 144.21,138.76 143.8,140.94 143.8,140.96 143.71,141.43 143.71,143.45 148.57,151.47 148.59,151.49 v3(148.59,151.5) ; v3(34.54,170.05) 34.62,169.98 66.09,169.98 67.03,170.92 76.81,170.92 77.65,170.08 123.27,170.08 v3(124.74,171.55)
H_TCK: length 149.9
  TOP w0.089: 153.75,111.73 153.75,111.82 153.94,112.01 153.94,113 SB1.AH4
  TOP w0.102: CPU1.F11 v1(84.44,84.74) ; R415.1 123.2,61.01 122.53,61.04 v3(122.52,61.04) 121.3,61.04 120.97,61.37 120.97,61.37 119.93,62.41 119.9,62.41 119.35,62.96 119.35,63.69 116.17,66.88 115.16,66.88 115.16,66.88 109.15,66.88 108.91,66.64 106.55,66.64 101.69,71.5 98.51,71.5 96.56,73.44 91.43,73.44 90.4,72.42 v1(90.4,71.96) ; 153.75,111.73 153.75,110.68 153.69,110.62 153.69,110.61 153.52,110.44 153.52,109.86 153.75,109.63 153.75,109.14 153.59,108.98 153.59,108.29 153.75,108.14 153.75,105.03 154.23,104.55 154.23,104.3 154.23,104.3 154.23,101.82 R2021.1 155.08,100.13 159.74,95.47 159.74,65.89 159.74,65.56 158.43,64.24 158.43,63.85 157.39,62.81 157.39,62.01 v3(156.84,61.47)
  BOTTOM w0.102: v1(84.44,84.74) 84.03,84.33 84.03,78.35 86.82,75.56 86.82,75.08 v2(87.66,74.24) 89.94,71.96 v1(90.4,71.96) ; v3(156.84,61.47) 156.57,61.47 154.08,58.98 149.07,58.98 148.36,58.27 148.3,58.22 143.03,58.22 141.35,59.89 130.68,59.89 130.55,59.77 127.33,59.77 126.75,59.18 126.12,59.18 125.79,59.51 124.66,59.51 123.13,61.04 v3(122.52,61.04)
H_TDI: length 59.3
  TOP w0.102: R411.1 123.63,59.83 123.24,60.22 121.79,60.22 120.87,61.14 119.83,62.18 119.81,62.18 119.13,62.86 119.13,63.6 116.07,66.65 115.25,66.65 115.25,66.65 109.24,66.65 109,66.41 106.44,66.41 101.58,71.27 98.41,71.27 98.28,71.4 96.46,73.22 92.02,73.22 91.21,72.41 v1(91.21,71.98) ; CPU1.G12 v1(84.44,85.66)
  BOTTOM w0.102: v1(84.44,85.66) 83.96,85.17 83.96,84.56 83.8,84.41 83.8,83.37 83.82,83.35 83.82,79.68 83.69,79.55 83.69,78.29 85.76,76.22 v2(85.76,75.62) 85.76,75.23 89.51,71.48 91,71.48 91.21,71.68 v1(91.21,71.98)
H_TDO: length 63.9
  TOP w0.102: v1(92.84,72.04) 92.84,72.4 93.19,72.76 96.27,72.76 97.82,71.21 98.22,70.81 101.38,70.81 106.23,65.95 109.19,65.95 109.43,66.19 115.44,66.19 115.88,66.19 118.67,63.41 118.67,62.67 119.62,61.72 119.64,61.72 120.17,61.19 120.17,61.04 122.29,58.93 124.13,58.93 124.42,58.63 124.42,58.52 R410.1 125.81,58.42 126.19,58.8 R402.1 ; CPU1.H13 v1(83.53,85.66)
  BOTTOM w0.102: v1(92.84,72.04) 92.84,71.58 92.23,70.97 89.33,70.97 82.95,77.34 v2(82.95,77.83) 82.95,78.22 83.28,78.55 83.28,79.72 83.41,79.85 83.41,83.18 83.26,83.34 83.12,83.48 83.12,84.91 83.53,85.32 v1(83.53,85.66)
H_TMS: length 59.6
  TOP w0.102: CPU1.F13 v1(82.61,83.83) ; R412.1 123.4,57.4 122.84,57.96 122.62,57.96 119.94,60.64 119.94,61.1 119.73,61.32 119.55,61.49 119.53,61.49 118.46,62.55 118.44,62.61 118.44,63.31 115.79,65.96 115.54,65.96 109.53,65.96 109.29,65.72 106.08,65.72 101.22,70.58 98.13,70.58 97.59,71.12 96.38,72.33 93.94,72.33 v1(93.65,72.03)
  BOTTOM w0.102: v1(82.61,83.83) 82.61,83.7 83.08,83.23 83.08,80.01 82.19,79.12 82.19,77.73 89.15,70.78 89.19,70.78 89.23,70.74 92.81,70.74 v2(93.24,71.17) 93.65,71.58 v1(93.65,72.03)
H_TRST_N: length 166.7
  TOP w0.102: R417.1 157.4,107.26 157.4,106.94 158.14,106.2 158.14,104.01 158.77,103.38 160.02,103.38 160.48,103.38 162.52,101.33 162.52,101.07 162.66,100.93 162.66,100.23 167.49,95.4 167.49,68.86 170.23,66.12 170.23,61.34 v3(170.1,61.22) ; v1(92.02,72.01) 92.02,72.4 92.61,72.99 96.37,72.99 98.05,71.31 98.32,71.04 101.48,71.04 106.33,66.18 109.1,66.18 109.34,66.42 115.35,66.42 115.98,66.42 118.9,63.5 118.9,62.77 119.72,61.95 119.74,61.95 120.71,60.98 121.69,59.99 122.25,59.44 v3(122.43,59.44) ; CPU1.F12 v1(83.53,84.74)
  BOTTOM w0.102: v1(92.02,72.01) 92.02,71.65 91.57,71.2 89.42,71.2 85.66,74.96 85.63,74.96 84.72,75.86 84.72,76.47 v2(84.4,76.78) 84.4,77.29 83.49,78.2 83.49,79.64 83.62,79.77 83.62,83.27 83.53,83.36 v1(83.53,84.74) ; v3(122.43,59.44) 122.05,59.05 122.05,56.93 122.02,56.91 122.02,56.53 122.29,56.26 122.33,56.26 123.04,55.55 126.82,55.55 127.3,55.07 128.52,55.07 129.76,56.31 132.11,56.31 133.02,55.4 141.17,55.4 142.03,54.53 150.04,54.53 150.44,54.94 154.37,54.94 154.88,55.45 156.18,55.45 156.36,55.27 156.98,55.27 158.09,56.39 158.95,56.39 160.23,57.67 160.23,59.04 161,59.82 162.66,59.82 163.05,60.22 164.24,60.22 165.06,61.04 169.92,61.04 v3(170.1,61.22)
H_TRST_N_R: length 16.9
  TOP w0.089: SB1.AM4 156.32,112.98 156.14,112.8 156.14,112.02 155.95,111.83 155.95,111.13 155.96,111.12 155.96,111.06 156.1,110.91 156.1,110.89 156.13,110.87
  TOP w0.102: 156.13,110.87 156.57,110.42 156.57,110.41 156.58,110.41 156.58,109.79 156.58,109.78 156.58,109.4 v3(156.38,109.2) 156.38,108.29 R417.2 ; v3(157.39,101.03) 158,101.03 158.29,100.74 v2(158.29,100.61) 158.29,100.51 157.86,100.08 157.31,100.08 R427.1
  BOTTOM w0.102: v3(156.38,109.2) 157.38,108.2 157.38,105.97 157.78,105.56 157.78,101.64 157.78,101.63 157.78,101.42 v3(157.39,101.03)
HD_LED_PWR1: length 9.5
  TOP w0.254: R6419.2 17.96,236.41 18.8,235.58 18.8,232.49 18.17,231.86 16.69,231.86 PWRSW1.2
HDA_BITCLK_CODEC: length 6.8
  TOP w0.102: U2701.2 64.17,253.76 64.06,253.64 63.38,253.64 63.28,253.75 63.28,254.13 v3(62.99,254.43) 62.01,253.46 C2715.1 62.01,251.82 R2017.1
  BOTTOM w0.102: v3(62.99,254.43) 63.52,253.9 v2(63.88,253.9)
HDA_BITCLK_PCH: length 260.3
  TOP w0.102: v3(59.77,250.8) 59.77,250.85 60.07,251.15 R2052.1 60.46,251.6 60.66,251.79 R2017.2 ; v3(177.67,156.3) 177.37,148.9 177.37,146.56 177.34,146.51 177.33,146.49 177.07,145.99 177.05,145.95 176.88,145.42 176.88,138.79 176.88,138.79 176.86,138.27 176.86,138.26 176.86,138.24 176.86,138.19 176.71,135.61 176.71,135.35 176.69,135.28 176.69,135.28 175.44,131 175.44,129.52 172.87,123.47 171.07,120.04 170.6,118.92 170.6,118.91 170.53,118.75 170.52,118.74 170.49,118.67 170.37,118.41 170.24,118.13 170.2,118.05 170.13,117.9 169.42,117.2 164.33,117.2 163.93,116.79 163.76,116.79 163.57,116.61 162.76,116.61 162.66,116.51 162.22,116.51 SB1.BD11 ; v3(53.95,247.5) 54.52,247.5 57.05,244.97 57.05,232.16 58.17,231.03 58.17,229.15 57.37,228.35 57.37,227.24 58.7,225.91 58.7,213.56 60.22,212.04 60.22,202.82 61.92,201.13 63.92,199.13 64.35,199.13 67.41,196.06 67.41,190.68 69.78,188.31 81.68,188.31 81.84,188.47 116.28,188.47 116.42,188.48 118.89,188.72 119.05,188.74 119.59,188.82 145.01,188.82 148.62,192.43 149.49,192.43 v3(149.79,192.13)
  BOTTOM w0.102: v3(177.67,156.3) 176.68,160.01 175.18,161.51 175.18,168.67 173.8,170.06 173.8,170.06 173.74,170.12 173.74,170.12 173.74,172.12 172.75,173.1 172.56,173.1 170.71,174.95 170.71,176.34 171.54,177.17 171.54,179.27 170.48,182 168.65,183.83 163.35,189.13 160.74,189.13 160.48,189.3 160.41,189.35 157.46,191.52 157.11,191.74 150.17,191.74 v3(149.79,192.13) ; v3(53.95,247.5) 56.24,247.5 v2(57.67,248.93) 59.54,250.8 v3(59.77,250.8)
HDA_RST#_CODEC: length 29.9
  TOP w0.102: U2701.7 66.67,253.66 66.17,253.15 66.17,252.69 65.04,251.56 64.63,251.56 64.47,251.4 64.47,250.23 64.05,249.81 64.04,249.81 63.56,249.33 63.18,249.33 62.75,249.76 60.8,249.76 60.27,249.24 60.27,247.73 60.72,247.28 60.72,236.35 61.03,236.04 63.18,236.04 v2(64.14,237) R2019.1 R2718.1
HDA_RST#_PCH: length 246.7
  TOP w0.102: v3(63.16,236.78) 63.16,237.43 63.15,237.44 63.15,237.88 63.16,237.9 R2053.1 63.65,237.95 63.65,237.95 R2019.2 ; v3(57.56,236.8) 57.59,236.78 57.59,232.08 59.44,230.23 v2(59.44,226.57) 58.94,226.07 58.94,213.64 60.45,212.13 60.45,202.92 60.81,202.56 60.81,202.56 61.6,201.78 63.67,199.7 64.09,199.7 67.64,196.16 67.64,190.78 69.87,188.54 81.59,188.54 81.74,188.69 116.27,188.69 118.86,188.95 119.04,188.98 119.5,189.05 144.92,189.05 148.52,192.66 150.21,192.66 v3(150.65,192.22) ; SB1.BE10 162.43,116.15 163.11,116.15 163.3,116.33 163.59,116.33 163.84,116.59 164.01,116.59 164.39,116.97 169.52,116.97 170.33,117.78 170.37,117.87 170.45,118.03 170.48,118.11 170.7,118.53 170.7,118.54 170.75,118.64 171.25,119.84 173.06,123.34 175.16,128.27 175.67,129.48 175.67,130.9 176.94,135.31 176.94,135.59 177.08,138.07 177.09,138.27 177.09,138.29 177.11,138.69 177.11,138.7 177.11,145.38 177.11,145.39 177.25,145.82 177.27,145.89 177.59,146.47 177.7,149.27 v3(178.13,155.55)
  BOTTOM w0.102: v3(178.13,155.55) 178.13,156.49 176.98,160.14 175.41,161.71 175.41,168.76 174.03,170.15 174.03,170.16 173.96,170.22 173.96,172.21 172.85,173.33 172.66,173.33 170.94,175.05 170.94,176.25 171.77,177.08 171.77,179.37 170.71,182.09 163.45,189.36 160.81,189.36 160.71,189.42 160.54,189.53 158.42,191.09 157.71,191.61 157.53,191.74 157.18,191.97 150.9,191.97 v3(150.65,192.22) ; v3(63.16,236.78) 62.73,236.35 62.08,236.35 61.81,236.61 61.81,236.66 61.52,236.96 57.71,236.96 v3(57.56,236.8)
HDA_SDIN0_CODEC: length 4.4
  TOP w0.102: U2701.4 65.17,253.74 64.62,253.19 63.97,253.19 v2(63.22,252.44) 63.02,252.23 R2703.2
HDA_SDIN0_PCH: length 258.9
  TOP w0.102: v3(177.01,155.47) 177.01,146.41 176.84,146.04 176.66,145.46 176.66,138.89 176.64,138.36 176.63,138.35 176.63,138.25 176.48,135.62 176.48,135.38 176.46,135.33 176.46,135.33 175.23,131.11 175.21,131.1 175.21,129.57 172.68,123.6 171.04,120.58 170.39,119 170.32,118.84 170.31,118.83 170.03,118.23 169.94,118.03 169.33,117.42 164.27,117.42 163.84,117 163.68,117 163.49,116.81 162.67,116.81 162.6,116.74 SB1.BE11 ; v3(58.9,249.34) 60.04,249.34 60.69,249.99 62.45,249.99 R2703.1 ; v3(54.39,246.75) 54.94,246.75 56.79,244.9 56.79,244.33 56.11,243.65 56.11,228.14 58.13,226.12 58.41,225.84 58.41,220.31 v2(58.14,220.04) 58.14,218.71 58.41,218.44 58.41,213.53 59.99,211.94 59.99,202.73 63.76,198.97 63.83,198.9 64.25,198.9 67.18,195.97 67.18,190.59 69.68,188.08 81.79,188.08 81.94,188.24 116.29,188.24 119.96,188.59 145.11,188.59 148.48,191.97 v3(148.82,191.97)
  BOTTOM w0.102: v3(148.82,191.97) 149.29,191.97 149.77,191.49 156.76,191.49 157.19,191.21 157.24,191.16 158.59,190.27 160.27,189.16 160.28,189.16 160.45,189.04 160.67,188.9 163.25,188.9 170.26,181.89 171.32,179.13 171.32,177.27 170.48,176.44 170.48,174.86 172.47,172.87 172.66,172.87 173.51,172.02 173.51,170.05 173.63,169.88 173.67,169.83 174.96,168.54 174.96,160.91 175.66,159.07 177.16,156.59 177.16,155.62 v3(177.01,155.47) ; v3(58.9,249.34) 56.31,246.75 v3(54.39,246.75)
HDA_SDOUT_CODEC: length 6.9
  TOP w0.102: U2701.3 64.67,253.6 64.49,253.42 v3(62.79,253.42) 62.56,253.19 62.56,251.35 R2020.1
  BOTTOM w0.102: v2(61.97,253.92) v3(62.79,253.42)
HDA_SDOUT_PCH: length 392.1
  TOP w0.102: R2020.2 60.78,250.77 v3(59.82,249.81) ; R2038.1 191.72,23.42 v3(191.64,23.5) ; SB1.BF12 163.21,117.14 163.54,117.14 163.59,117.2 163.76,117.2 164.21,117.65 169.23,117.65 169.74,118.16 169.86,118.4 170.14,119 170.14,119.01 170.17,119.09 170.18,119.1 170.85,120.7 172.49,123.75 172.94,124.82 174.98,129.62 174.98,130.72 174.96,130.76 174.96,130.99 174.98,131.07 174.98,131.27 v3(176.02,135.59) 176.43,139 176.43,145.49 176.63,146.15 176.71,146.32 176.71,153.83 176.56,154.88 176.56,156.28 v3(176.71,156.43) ; v3(182.12,36.96) 185.29,33.78 185.29,25.92 186.63,24.59 186.69,24.59 186.79,24.49 186.79,24.27 v3(186.82,24.25) ; v3(149.33,191.28) 149.18,191.43 148.26,191.43 145.2,188.37 120.03,188.37 116.33,188.01 82.04,188.01 81.88,187.86 69.59,187.86 66.95,190.49 66.95,195.87 64.16,198.67 63.73,198.67 63.71,198.69 59.77,202.64 59.77,211.85 58.18,213.43 58.18,218.23 57.58,218.83 57.58,221.51 v2(57.85,221.78) 57.87,221.78 58.17,222.08 58.17,225.76 58.03,225.89 55.88,228.05 55.88,243.74 56.57,244.43 56.57,244.81 56.11,245.27 v3(55.54,245.27)
  BOTTOM w0.102: v3(176.71,156.43) 176.71,156.79 175.27,159.15 174.97,160.04 174.73,160.74 174.73,168.45 173.5,169.68 173.28,169.97 173.28,171.93 172.56,172.64 172.37,172.64 170.26,174.76 170.26,176.53 171.09,177.36 171.09,178.98 170.03,181.8 163.16,188.67 160.6,188.67 160.19,188.94 160.07,189.02 157.09,190.98 156.7,191.24 149.37,191.24 v3(149.33,191.28) ; v3(176.02,135.59) 176.02,135.66 176.53,136.17 186.13,136.17 186.69,135.61 187.06,135.61 190.25,132.42 190.25,131.86 192.66,129.44 192.66,47.88 189.41,44.63 189.41,43.9 183.48,37.97 183.48,37.86 182.58,36.96 v3(182.12,36.96) ; v3(191.64,23.5) 190.82,23.5 189.52,24.79 187.31,24.79 186.82,24.3 v3(186.82,24.25) ; v3(55.54,245.27) 55.73,245.27 59.82,249.35 v3(59.82,249.81)
HDA_SYNC_CODEC: length 11.4
  TOP w0.102: U2701.6 66.17,253.81 65.1,252.74 v3(65.1,252.27) ; R2022.1 63.93,247.14 63.25,246.46 v3(63.25,246)
  BOTTOM w0.102: v3(63.25,246) 63.25,246.46 64.26,247.47 64.47,247.47 65.15,248.15 v2(65.15,251.31) 65.15,251.66 65.1,251.71 v3(65.1,252.27)
HDA_SYNC_PCH: length 251.4
  TOP w0.102: v3(56.11,244.62) 55.65,244.16 55.65,227.95 57.94,225.67 57.94,223.57 v2(57.4,223.04) 57.4,222.13 57.29,222.01 57.29,218.8 57.95,218.14 57.95,213.34 59.54,211.75 59.54,202.54 63.64,198.44 64.06,198.44 66.73,195.78 66.73,190.4 69.49,187.63 81.98,187.63 82.13,187.78 116.47,187.78 120.11,188.14 145.67,188.14 v3(148.5,190.97) ; SB1.BG13 164.07,117.88 169.14,117.88 169.56,118.3 169.66,118.5 169.97,119.18 170.67,120.87 172.3,123.89 174.75,129.66 174.75,130.66 174.71,130.73 174.71,130.97 174.75,131.1 174.75,131.59 175.35,134.11 175.56,135.69 175.83,136.46 176.13,142.33 176.13,142.33 176.17,143.13 176.2,143.49 176.2,145.53 176.48,146.43 176.48,153.63 v3(176,156.92) ; R2022.2 62,246.08 v3(62,245.43)
  BOTTOM w0.102: v3(148.5,190.97) 148.65,190.82 149.82,190.82 150.01,191.01 156.63,191.01 160.53,188.44 163.06,188.44 169.7,181.81 169.7,179.2 168.95,178.45 168.95,177.43 169.95,176.43 169.95,174.74 172.28,172.41 172.47,172.41 173.05,171.83 173.05,169.9 173.32,169.53 174.5,168.35 174.5,160.64 175.08,158.96 v3(176,156.92) ; v3(56.11,244.62) 59.96,244.62 60.77,245.43 v3(62,245.43)
HDD_LED_PWR1: length 23.9
  TOP w0.254: R6418.2 v2(31.32,260.88) 31.32,263.74 31.39,263.81 31.39,267.42 21.83,276.99 20.95,276.99 LED1.A
HDMI1_DETECT: length 12.2
  TOP w0.102: R1702.2 153.03,141.64 152.65,141.25 152.65,139.14 152.63,139.11 152.63,138.44 151.89,137.69 151.74,137.69 151.74,137.69 v2(151.64,137.69) 151.21,137.26 150.47,137.26 149.07,135.86 147.58,135.86 147.14,135.43 147.14,134.46 147.32,134.28 147.32,134.16 SB1.P47
HDMI_CLK_CON: length 19
  TOP w0.102: RN5601.4 69.49,23.66 v2(69.82,23.33) 69.87,23.29 69.87,21.98 70.69,21.16 70.69,20.76 70.35,20.42 69.59,20.42 69.48,20.32 U5601.3 69.48,18.63 68.64,17.79 C5610.1 68.64,17.72 69.07,17.29 EU5603.1 EU5603.10 69.07,14.46 69,14.39 68.03,13.84 67.01,13.84 64.5,11.33 HDMI1.15
HDMI_CLK_CPU: length 202.7
  TOP w0.102: v3(160.81,64.16) 160.58,64.39 160.58,95.81 158.6,97.8 158.6,98.79 158.79,98.97 v3(158.79,99.4) 159.13,99.74 159.83,99.74 160.1,99.48 160.1,97.74 161.7,96.15 161.7,95.32 162.56,94.46 162.56,93.08 R1908.1 ; v1(154.67,118.3) 155.1,118.3 SB1.AL13 ; v3(157.1,59.06) 154.86,59.06 154.11,58.3 154.11,56.85 156.29,54.67 156.29,50.37 157.66,49 157.66,45.81 158.53,44.94 158.53,44.11 157.7,43.28 157,43.28 154.61,40.89 154.61,40.7 154.61,40.58 152.83,38.79 152.83,31.34 v3(152.93,31.24) ; v3(70.21,20.93) 70.21,21.25 69.93,21.54 U5601.4
  BOTTOM w0.102: v3(160.81,64.16) 161.26,64.16 161.87,63.55 161.87,62.64 161.45,62.22 160.45,62.22 159.45,61.22 159.08,61.22 157.98,60.11 157.98,59.93 v3(157.1,59.06) ; v3(152.93,31.24) 151.41,31.24 150.97,31.67 142.52,31.67 140.97,30.12 140.97,30.12 140.86,30.02 118.48,30.02 118.16,30.34 109.39,30.34 106.48,27.43 105.17,27.43 103.22,25.48 103.22,24.5 102.12,23.39 92.4,23.39 91.84,23.95 82.56,23.95 79.67,21.06 v2(72.34,21.06) 70.34,21.06 v3(70.21,20.93) ; v3(158.79,99.4) 159.13,99.74 159.68,99.74 159.97,100.03 159.97,102.72 159.97,102.72 159.97,103.1 159.97,104.05 159.56,104.46 159.56,104.96 159.56,106.1 159.74,106.28 159.74,106.93 158.45,108.22 158.45,110 157.28,111.18 157.28,112.76 156.34,113.7 156.34,114.05 155.73,114.66 155.73,117.25 v1(154.67,118.3)
HDMI_DATA_CMC_N0: length 7.7
  TOP w0.102: R5601.1 C5602.2 80.73,24.28 80.73,23.71 80.63,23.61 79.72,23.61 79.27,23.17 ; 79.27,23.17 78.53,22.42 78.53,20.72 78.29,20.48 TR5601.4 ; 79.27,23.17 v2(78.99,23.44)
HDMI_DATA_CMC_N1: length 7.2
  TOP w0.102: TR5602.4 76.13,20.45 76.34,20.66 76.34,21.17 77.11,21.95 77.11,22.86 76.64,23.33 76.64,23.72 ; v2(76.28,23.72) 76.64,23.72 ; 76.64,23.72 76.64,24.42 76.33,24.74 C5604.2 75.44,25.64 R5603.1
HDMI_DATA_CMC_N2: length 4.2
  TOP w0.102: v2(73.38,21.39) 73.76,21.39 ; 73.76,21.39 73.76,21.03 74.07,20.72 74.07,20.65 73.84,20.43 TR5603.4 ; 73.76,21.39 73.76,22.09 C5606.2 R5605.1
HDMI_DATA_CMC_N3: length 7.9
  TOP w0.102: 71.41,23.81 71.04,23.44 71.04,21.51 71.77,20.78 71.77,20.64 71.56,20.43 TR5604.4 ; 71.41,23.81 v2(71.13,24.09) ; 71.41,23.81 71.77,24.17 71.77,24.87 C5608.2 71.36,25.26 70.47,26.15 R5607.1
HDMI_DATA_CMC_P0: length 7.7
  TOP w0.102: 78.75,21.79 78.75,20.67 78.94,20.48 TR5601.3 ; 78.75,21.79 78.75,22.33 79.81,23.39 80.72,23.39 80.95,23.62 80.95,24.3 C5601.2 R5602.1 ; 78.75,21.79 v2(79.12,21.79)
HDMI_DATA_CMC_P1: length 7.3
  TOP w0.102: 77.33,22.35 77.33,22.95 76.86,23.42 76.86,24.4 C5603.2 78.11,25.64 R5604.1 ; 77.33,22.35 v2(77.72,22.35) ; 77.33,22.35 77.33,21.86 76.55,21.08 76.55,20.71 76.78,20.48 TR5602.3
HDMI_DATA_CMC_P2: length 4.8
  TOP w0.102: v2(76.3,22.44) R5606.1 C5605.2 74.3,22.43 73.98,22.11 73.98,21.12 74.29,20.81 74.29,20.66 74.49,20.45 TR5603.3
HDMI_DATA_CMC_P3: length 7.8
  TOP w0.102: TR5604.3 72.21,20.45 71.99,20.67 71.99,20.87 71.65,21.21 ; 71.65,21.21 71.26,21.6 71.26,23.35 71.98,24.08 71.98,24.84 72.39,25.25 C5607.2 73.1,25.97 R5608.1 ; 71.65,21.21 v2(71.92,21.48)
HDMI_DATA_CON: length 18.7
  TOP w0.102: HDMI1.16 64,11.21 64.78,11.99 64.83,11.99 66.92,14.07 67.97,14.07 67.98,14.08 67.99,14.08 68.59,14.42 EU5603.9 EU5603.2 68.59,17.01 67.82,17.78 C5611.1 67.37,18.03 67.37,19.81 68.18,20.62 U5601.6 68.18,22.29 68.48,22.59 68.48,22.97 68.29,23.15 68.28,23.15 68.13,23.31 RN5601.3 67.91,23.66 v2(67.23,24.33)
HDMI_DATA_CON_N0: length 14.5
  TOP w0.102: HDMI1.3 70.5,11.29 70.89,11.68 70.89,11.93 70.99,12.06 71.05,12.09 73.85,12.92 77.49,14.06 77.82,14.24 78.14,14.69 78.14,15.33 77.99,15.48 EU5601.9 EU5601.2 77.99,17.28 78.13,17.42 78.13,17.72 78.49,18.08 78.49,18.31 78.29,18.51 TR5601.1
HDMI_DATA_CON_N1: length 14.5
  TOP w0.102: 74.9,14.14 75.84,14.62 76.53,15.07 76.61,15.14 76.61,15.32 76.47,15.45 EU5601.6 EU5601.5 76.47,17.19 76.6,17.32 76.6,17.53 76.35,17.78 76.35,18.21 76.13,18.44 TR5602.1 ; 74.9,14.14 v2(74.68,14.51) ; 74.9,14.14 73.56,13.6 70.75,12.73 70.09,12.48 69.66,12.23 69.39,11.96 69.39,11.71 69,11.32 HDMI1.6
HDMI_DATA_CON_N2: length 13.5
  TOP w0.102: HDMI1.9 67.5,11.29 67.91,11.7 67.91,12.03 68.33,12.45 68.85,12.76 69.97,13.25 70.1,13.3 72.3,14.01 72.39,14.05 ; 72.39,14.05 73.31,14.39 73.55,14.57 73.56,14.58 73.77,14.79 73.84,14.94 73.84,15.23 73.67,15.39 EU5602.9 EU5602.2 73.67,17.39 73.79,17.5 73.79,17.76 74.07,18.04 74.07,18.23 73.84,18.46 TR5603.1 ; 72.39,14.05 v2(72.29,14.4)
HDMI_DATA_CON_N3: length 13.3
  TOP w0.102: HDMI1.12 66,11.34 66.4,11.74 66.4,12.04 66.58,12.31 66.6,12.33 67.09,12.76 69.45,14.09 70.46,14.37 70.63,14.42 ; 70.63,14.42 70.96,14.51 70.97,14.52 71.24,14.63 72.25,15.42 72.25,15.56 72.15,15.66 EU5602.6 EU5602.5 72.15,17.36 72.24,17.45 72.24,17.6 71.78,18.06 71.78,18.27 71.56,18.49 TR5604.1 ; 70.63,14.42 v2(70.54,14.81)
HDMI_DATA_CON_P0: length 14.5
  TOP w0.102: TR5601.2 78.94,18.51 78.7,18.28 78.7,17.99 78.35,17.63 78.35,17.44 78.47,17.31 EU5601.1 EU5601.10 78.47,15.48 78.36,15.37 78.36,14.63 77.97,14.08 77.58,13.87 73.91,12.71 71.13,11.89 71.11,11.86 71.11,11.67 71.5,11.28 HDMI1.1
HDMI_DATA_CON_P1: length 14.4
  TOP w0.102: HDMI1.4 70,11.33 69.61,11.72 69.61,11.88 69.79,12.06 70.18,12.28 70.82,12.53 73.64,13.39 74.99,13.95 75.93,14.43 75.95,14.44 76.41,14.73 ; v2(76.58,14.4) 76.41,14.73 ; 76.41,14.73 76.67,14.9 76.82,15.05 76.82,15.33 76.95,15.46 EU5601.7 EU5601.4 76.95,17.22 76.82,17.35 76.82,17.62 76.57,17.87 76.57,18.17 76.78,18.39 TR5602.2
HDMI_DATA_CON_P2: length 13.1
  TOP w0.102: TR5603.2 74.49,18.44 74.29,18.23 74.29,17.95 74,17.67 74,17.39 74.15,17.24 EU5602.1 EU5602.10 74.15,14.99 74.05,14.89 73.95,14.66 73.72,14.43 73.72,14.43 73.7,14.41 73.68,14.4 73.42,14.2 72.37,13.81 70.17,13.1 70.05,13.05 68.95,12.57 68.47,12.28 68.12,11.94 68.12,11.71 68.5,11.33 HDMI1.7
HDMI_DATA_CON_P3: length 12.9
  TOP w0.102: TR5604.2 72.21,18.51 71.99,18.3 71.99,18.15 72.46,17.69 72.46,17.56 72.63,17.39 EU5602.4 EU5602.7 72.63,15.61 72.47,15.44 72.47,15.31 71.35,14.44 71.06,14.32 71.03,14.3 69.53,13.88 67.22,12.58 66.76,12.18 66.62,11.97 66.62,11.67 67,11.28 HDMI1.10
HDMI_DATA_CPU: length 206.1
  TOP w0.102: v3(157.92,58.67) 157.85,58.6 154.73,58.6 154.34,58.21 154.34,56.94 156.64,54.64 156.64,50.34 157.89,49.09 157.89,46.16 158.76,45.29 158.76,44.02 157.79,43.05 157.1,43.05 154.84,40.79 154.84,40.1 153.05,38.32 153.05,32.34 153.94,31.46 v3(153.94,30.3) ; U5601.1 68.18,18.97 v3(67.83,18.62) ; v3(162.1,63.97) 161.99,63.97 160.86,65.1 160.86,95.85 160.04,96.67 158.83,97.89 158.83,98.69 159.42,99.29 v3(159.64,99.29) 159.87,99.06 159.87,97.65 161.47,96.05 161.47,95.23 162.33,94.37 162.33,92.24 R2324.1 ; v1(156.31,115.61) 156.31,115.61 156.31,115.44 156.76,114.99 156.76,114.88 157.02,114.63 157.03,114.63 157.05,114.6 157.41,114.6 157.66,114.86 157.66,114.88 SB1.AR8
  BOTTOM w0.102: v3(162.1,63.97) 162.1,62.55 161.54,61.99 160.54,61.99 159.54,60.99 159.17,60.99 158.21,60.02 158.21,58.96 v3(157.92,58.67) ; v3(159.64,99.29) 160.2,99.84 160.2,102.81 160.2,103.19 160.2,104.15 159.79,104.56 159.79,105.06 159.78,105.06 159.78,106 159.97,106.19 159.97,107.03 158.65,108.34 158.65,110.09 157.51,111.24 157.51,112.82 156.54,113.78 156.54,114.81 156.31,115.04 v1(156.31,115.61) ; v3(153.94,30.3) 152.02,30.3 150.88,31.45 142.62,31.45 141.07,29.9 141.06,29.9 140.96,29.79 118.38,29.79 118.06,30.11 109.49,30.11 106.58,27.2 105.27,27.2 103.45,25.39 103.45,24.41 102.21,23.16 92.31,23.16 91.75,23.72 82.66,23.72 79.76,20.83 73.36,20.83 72.45,19.91 v2(69.11,19.91) 67.83,18.63 v3(67.83,18.62)
HDMI_DATA_CPU_N0: length 99.4
  TOP w0.102: v3(79.79,26.75) 80.03,26.75 80.2,26.58 80.2,26.4 80.68,25.92 80.68,25.81 C5602.1 ; CPU1.D21 75.75,82.26 75.65,82.16 75.45,82.16 75.17,81.88 75.17,81.24 89.22,67.18 94.77,67.18 95.47,66.48 101.89,66.48 105.7,62.67 105.7,57.62 107.91,55.41 107.91,52.8 107.91,52.76 107.67,52.08 107.31,51.46 107.25,51.4 106.98,51.4 v1(106.74,51.64)
  BOTTOM w0.102: 93.34,29.78 93.84,29.78 107.58,43.53 107.58,48.75 105.88,50.45 105.88,51.07 106.11,51.3 106.4,51.3 v1(106.74,51.64) ; 93.34,29.78 91.53,29.78 89.63,27.89 80.4,27.89 80.12,27.61 80.12,27.07 79.8,26.75 v3(79.79,26.75) ; 93.34,29.78 v2(93.34,30.15)
HDMI_DATA_CPU_N1: length 103.2
  TOP w0.102: CPU1.E22 74.84,83.24 74.74,83.14 74.5,83.14 74.25,82.89 74.25,80.7 88.47,66.48 94.32,66.48 95.02,65.79 101.6,65.79 105,62.38 105,57.33 107.21,55.12 107.21,53.16 107.11,53.06 106.76,53.06 106.63,53.19 v1(106.63,53.38) ; v3(76.36,26.99) 76.7,26.65 76.7,26.26 76.33,25.9 C5604.1
  BOTTOM w0.102: v2(76.81,28.35) 77.1,28.05 ; 77.1,28.05 77.63,28.58 89.34,28.58 91.77,31.01 94.08,31.01 106.88,43.82 106.88,48.46 105.14,50.2 105.14,52.19 105.99,53.04 106.28,53.04 106.63,53.38 v1(106.63,53.38) ; 77.1,28.05 76.7,27.65 76.7,27.32 v3(76.36,26.99)
HDMI_DATA_CPU_N2: length 103.5
  TOP w0.102: v1(105.23,55.01) 105.53,55.31 105.58,55.35 105.58,55.77 104.31,57.04 104.31,62.09 101.31,65.09 94.61,65.09 93.91,65.79 88.08,65.79 74.35,79.52 74.35,79.88 74.17,80.06 74.03,80.06 73.92,79.95 CPU1.A23 ; C5606.1 73.76,23.69 73.76,24.57 74.31,25.11 74.31,26.71 74.08,26.94 v3(73.92,26.94)
  BOTTOM w0.102: v3(73.92,26.94) 74.28,27.3 74.28,27.89 75.68,29.28 89.05,29.28 91.48,31.71 93.79,31.71 106.18,44.11 106.18,48.17 104.39,49.96 104.39,52.43 105.6,53.63 105.6,54.88 105.47,55.01 v1(105.23,55.01) v2(105.43,56)
HDMI_DATA_CPU_N3: length 105.6
  TOP w0.102: CPU1.D23 73.92,82.23 73.82,82.13 73.6,82.13 73.37,81.9 73.37,81.72 73.37,79.42 87.7,65.09 93.62,65.09 94.32,64.39 101.02,64.39 103.49,61.91 103.49,55.05 103.73,54.81 104.2,54.81 v1(104.43,54.58) ; C5608.1 71.65,26.43 71.65,26.57 71.25,26.97 71.25,27.69 71.5,27.94 72.36,27.94 72.63,27.67 72.63,27.54 v3(73,27.17)
  BOTTOM w0.102: 103.9,53.21 103.9,49.78 105.7,47.97 105.7,44.31 93.59,32.19 91.28,32.19 88.85,29.77 74.66,29.77 72.67,27.77 72.67,27.5 v3(73,27.17) ; 103.9,53.21 103.9,54.7 104,54.8 104.21,54.8 v1(104.43,54.58) ; 103.9,53.21 v2(104.27,53.21)
HDMI_DATA_CPU_P0: length 99.4
  TOP w0.102: v3(80.7,26.79) 80.56,26.79 80.42,26.65 80.42,26.49 80.9,26.01 80.9,25.9 C5601.1 ; CPU1.C21 75.75,81.85 75.67,81.94 75.54,81.94 75.38,81.79 75.38,81.33 89.31,67.4 94.86,67.4 95.55,66.7 101.98,66.7 105.92,62.76 105.92,57.71 108.13,55.5 108.13,52.78 108.12,52.71 107.87,51.99 107.48,51.33 107.34,51.18 106.83,51.18 106.73,51.08 v1(106.73,50.77)
  BOTTOM w0.102: 84.43,27.67 80.49,27.67 80.34,27.52 80.34,27.15 v3(80.7,26.79) ; 84.43,27.67 89.72,27.67 91.62,29.57 93.93,29.57 107.8,43.44 107.8,48.84 106.1,50.54 106.1,50.98 106.2,51.08 106.63,51.08 106.73,50.98 v1(106.73,50.77) ; 84.43,27.67 v2(84.43,27.28)
HDMI_DATA_CPU_P1: length 103.1
  TOP w0.102: C5603.1 77.22,25.96 76.91,26.26 76.91,26.57 v3(77.27,26.94) ; CPU1.D22 74.84,82.82 74.74,82.92 74.59,82.92 74.47,82.8 74.47,80.79 88.56,66.7 94.41,66.7 95.11,66 101.69,66 105.22,62.47 105.22,57.42 107.43,55.21 107.43,53.07 107.2,52.84 106.71,52.84 106.61,52.74 v1(106.61,52.52)
  BOTTOM w0.102: v3(77.27,26.94) 76.91,27.3 76.91,27.56 77.72,28.37 79.17,28.37 ; 79.17,28.37 v2(79.17,28) ; 79.17,28.37 89.43,28.37 91.86,30.8 94.17,30.8 107.1,43.73 107.1,48.55 105.36,50.29 105.36,52.1 106.08,52.82 106.49,52.82 106.61,52.7 v1(106.61,52.52)
HDMI_DATA_CPU_P2: length 102.9
  TOP w0.102: C5605.1 73.98,23.65 73.98,24.48 74.52,25.02 74.52,26.7 v3(74.83,27) ; v1(106.09,55.07) 105.79,55.37 105.79,55.86 104.52,57.13 104.52,62.18 101.4,65.3 94.7,65.3 94,66 88.17,66 74.56,79.61 74.56,79.97 74.26,80.27 74.03,80.27 73.92,80.37 CPU1.B23
  BOTTOM w0.102: 74.89,28.19 74.5,27.8 74.5,27.34 v3(74.83,27) ; 74.89,28.19 75.77,29.07 89.14,29.07 91.57,31.5 93.88,31.5 106.4,44.02 106.4,48.26 104.61,50.05 104.61,52.34 105.82,53.54 105.82,54.79 v1(106.09,55.07) ; 74.89,28.19 v2(75.16,27.91)
HDMI_DATA_CPU_P3: length 105.6
  TOP w0.102: v3(72.05,27.17) 72.27,27.17 72.42,27.32 72.42,27.58 72.27,27.72 71.59,27.72 71.46,27.6 71.46,27.06 71.87,26.66 71.87,26.46 71.97,26.36 C5607.1 ; CPU1.C23 73.92,81.82 73.83,81.91 73.68,81.91 73.58,81.81 73.58,79.51 87.79,65.3 93.71,65.3 94.41,64.6 101.11,64.6 103.71,62 103.71,55.14 103.82,55.03 104.25,55.03 104.43,55.21 v1(104.43,55.45)
  BOTTOM w0.102: 72.94,28.35 74.57,29.98 88.76,29.98 91.19,32.41 93.5,32.41 105.49,44.4 105.49,47.88 103.68,49.69 103.68,54.79 103.91,55.02 104.24,55.02 104.43,55.21 104.43,55.45 v1(104.43,55.45) ; 72.94,28.35 72.45,27.86 72.45,27.28 72.35,27.17 v3(72.05,27.17) ; 72.94,28.35 v2(72.67,28.63)
HDMI_DET_CON: length 19.7
  TOP w0.102: HDMI1.19 62.5,12.12 62.48,12.13 62.48,12.7 63.83,14.05 63.83,14.51 64.36,15.04 65.1,15.04 v2(65.79,14.35) 67.4,14.35 67.55,14.5 EU5603.7 EU5603.4 67.55,16.28 67.3,16.53 66.85,16.53 66.74,16.43 66.74,16.42 66.56,16.24 66.18,16.24 66.17,16.26 65.52,16.26 R5609.1 65.01,16.27 64.24,17.04 64.24,20.55 64.88,21.19 Q5601.3
HDMI_DET_CPU: length 259.1
  TOP w0.102: SB1.AT6 157.97,114.19 157.97,113.3 158.14,113.13 158.14,111.55 157.83,111.25 157.83,110.91 158.45,110.29 158.45,110.02 160.17,108.29 160.17,107.47 161.39,106.26 v3(161.39,105.34) 161.89,105.34 162.97,104.26 163.08,104.26 164.98,102.36 168.28,102.36 170.03,100.61 v3(170.31,100.61) ; v3(170.23,96.6) 170.89,96.6 172.72,94.77 172.72,76.53 173.35,75.9 173.35,60.53 173.23,60.4 v3(173.23,60.22) ; R1702.1 152.79,142.87 152.68,142.87 152.58,142.77 152.58,141.57 v3(151.91,140.9) ; v3(66.37,16.7) 66.06,17.02 65.28,17.02 64.71,17.59 R5610.1 64.71,18.58 64.88,18.76 Q5601.4 ; v3(155.17,54.97) 155.17,51.09 157.38,48.88 157.38,45.69 158.25,44.82 158.25,44.23 157.58,43.56 156.89,43.56 154.33,41 154.33,40.69 152.55,38.91 152.55,32.16 152.53,32.15 152.53,32.06 v3(152.36,31.88)
  BOTTOM w0.102: v3(170.31,100.61) 170.31,99.87 169.72,99.29 169.72,97.1 v3(170.23,96.6) ; v3(151.91,140.9) 151.91,134.67 152.6,133.98 152.6,128.72 154.07,127.25 154.36,127.25 155.83,125.79 155.83,124.47 156.76,123.54 157.36,123.54 158.46,122.45 158.46,121.89 160.43,119.92 160.43,118.63 161.71,117.35 163.93,117.35 164.95,116.33 165.05,116.33 165.51,115.88 165.51,113.82 164.96,113.27 164.96,113.12 164.77,112.93 164.77,111.41 164.11,110.75 163.91,110.75 161.39,108.23 161.39,105.35 v3(161.39,105.34) ; v3(155.17,54.97) 157.07,54.97 158.21,56.11 159.34,56.11 163.17,59.94 164.36,59.94 165.18,60.76 172.69,60.76 v3(173.23,60.22) ; v3(152.36,31.88) 152.29,31.95 142.41,31.95 140.86,30.4 140.85,30.4 140.75,30.3 118.59,30.3 118.27,30.62 109.28,30.62 108.98,30.32 106.37,27.71 105.06,27.71 102.94,25.6 102.94,24.62 102,23.67 92.52,23.67 91.88,24.31 89.89,24.31 89.25,24.94 88.73,24.94 88.1,24.32 82.53,24.32 79.83,21.62 69.25,21.62 66.37,18.74 v2(66.37,17.68) v3(66.37,16.7)
HP_OUT_L: length 7.9
  TOP w0.203: R2906.1 R2904.2 67.37,267.5 C2905.2 66.37,266.34 v2(67.79,264.92) 66.93,264.06 66.4,264.06 66.17,263.83 U2701.31
HP_OUT_R: length 7.4
  TOP w0.203: R2905.1 63.41,268.44 63.88,267.97 R2903.2 64.47,267.96 64.47,266.79 64.72,266.53 C2904.2 65.59,264.74 v2(66.17,264.74) 66.2,264.71 66.2,264.42 65.67,263.89 U2701.32
I2C0_SCL_VGA: length 4
  TOP w0.102: U5901.30 56.99,17.04 57.18,16.85 57.84,16.85 v3(58.16,16.52) 58.16,16.23 58.79,15.61 R5911.1
  BOTTOM w0.102: v3(58.16,16.52) v2(59.13,16.52)
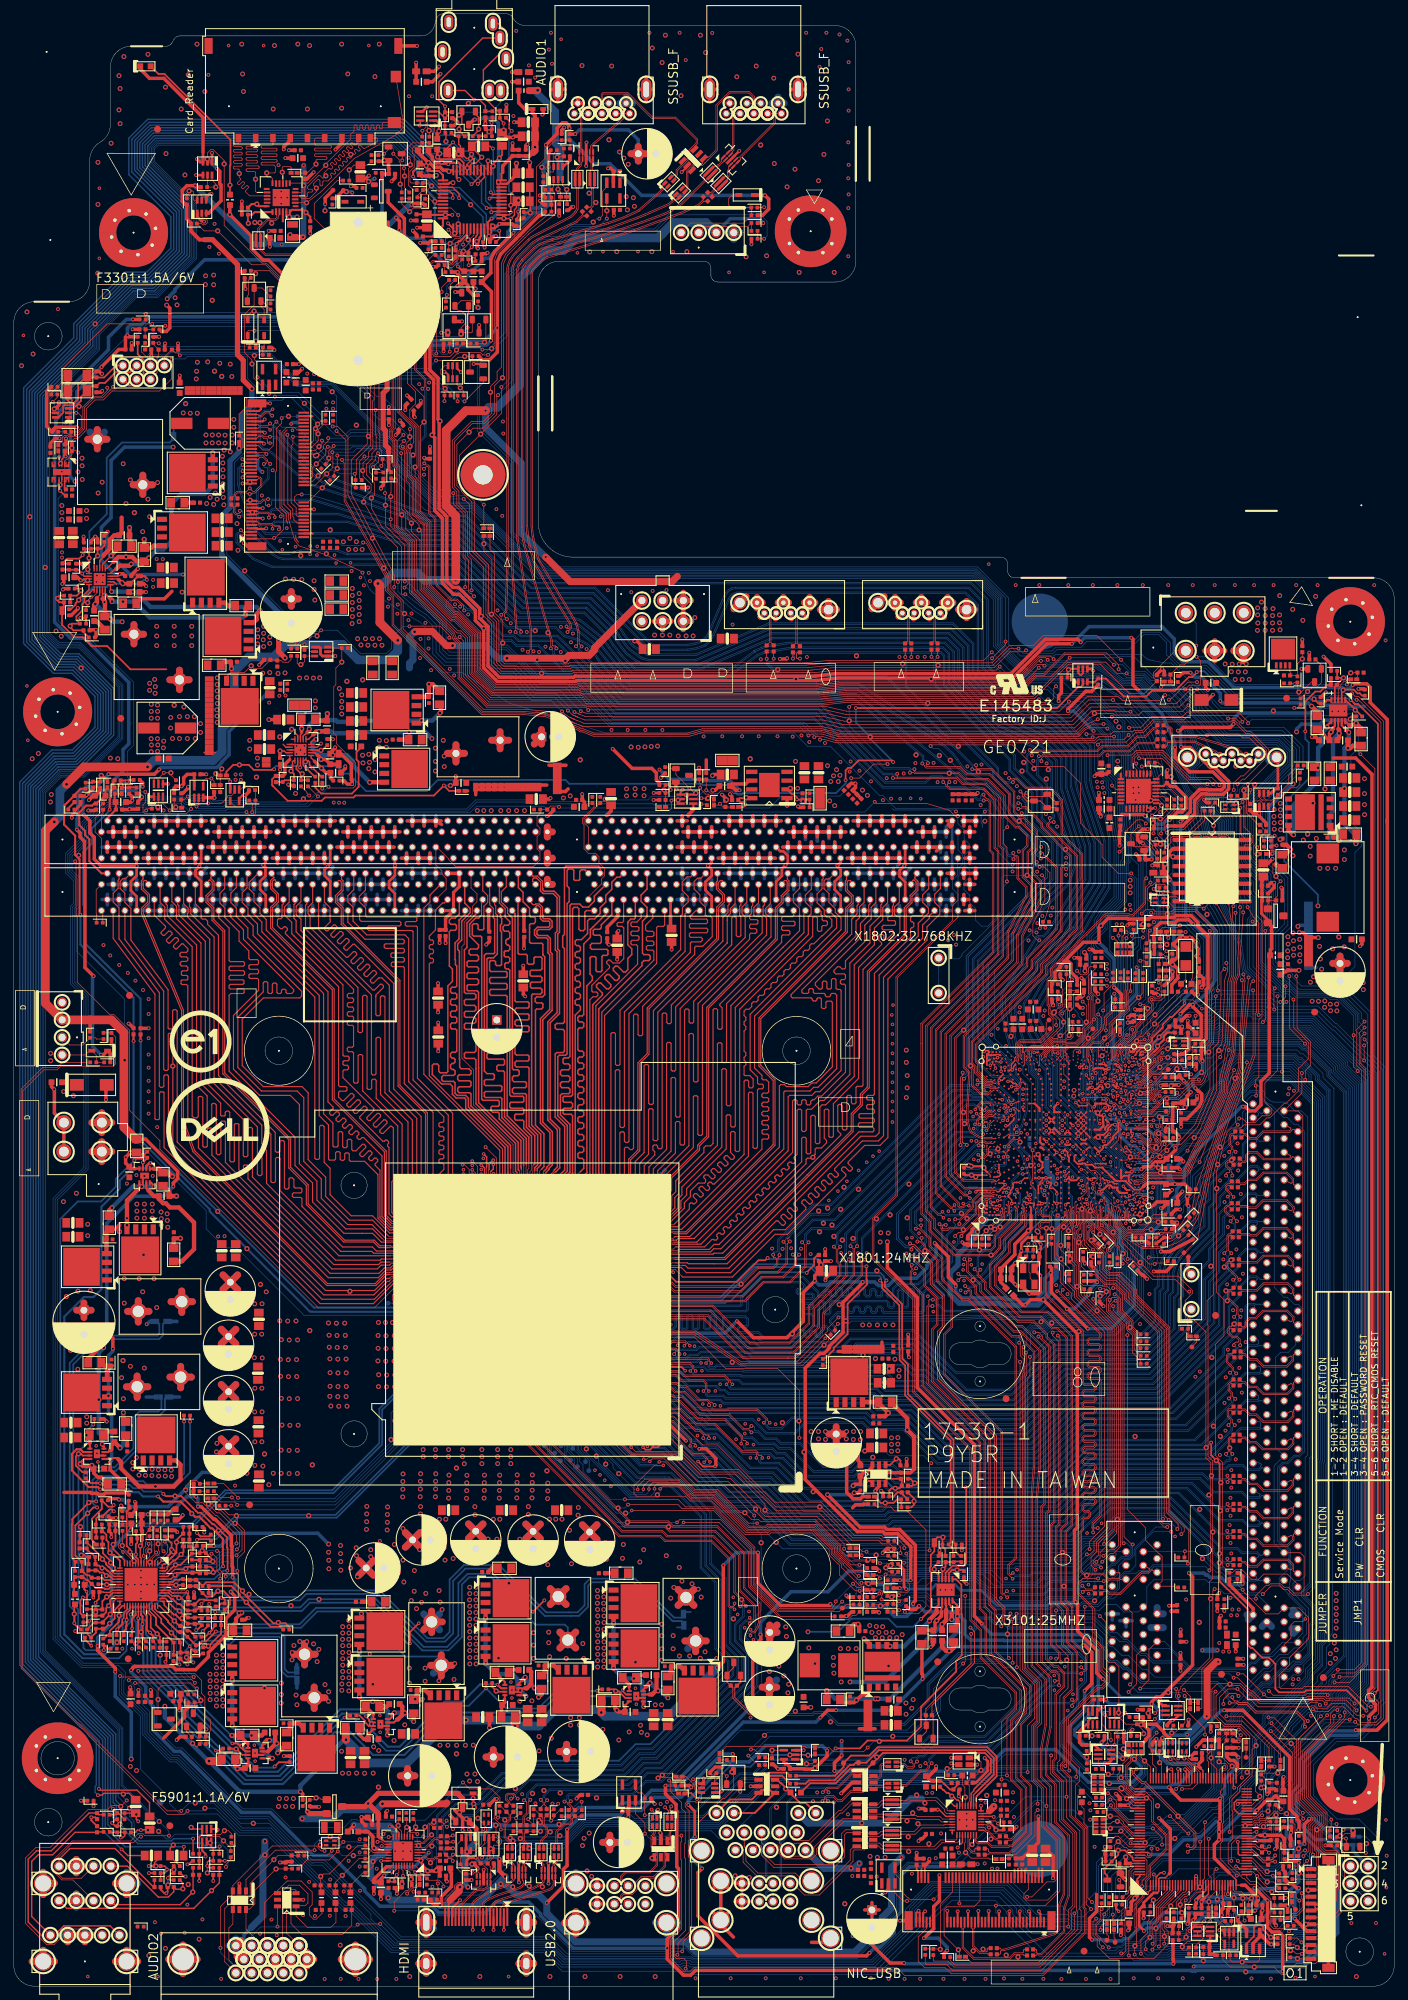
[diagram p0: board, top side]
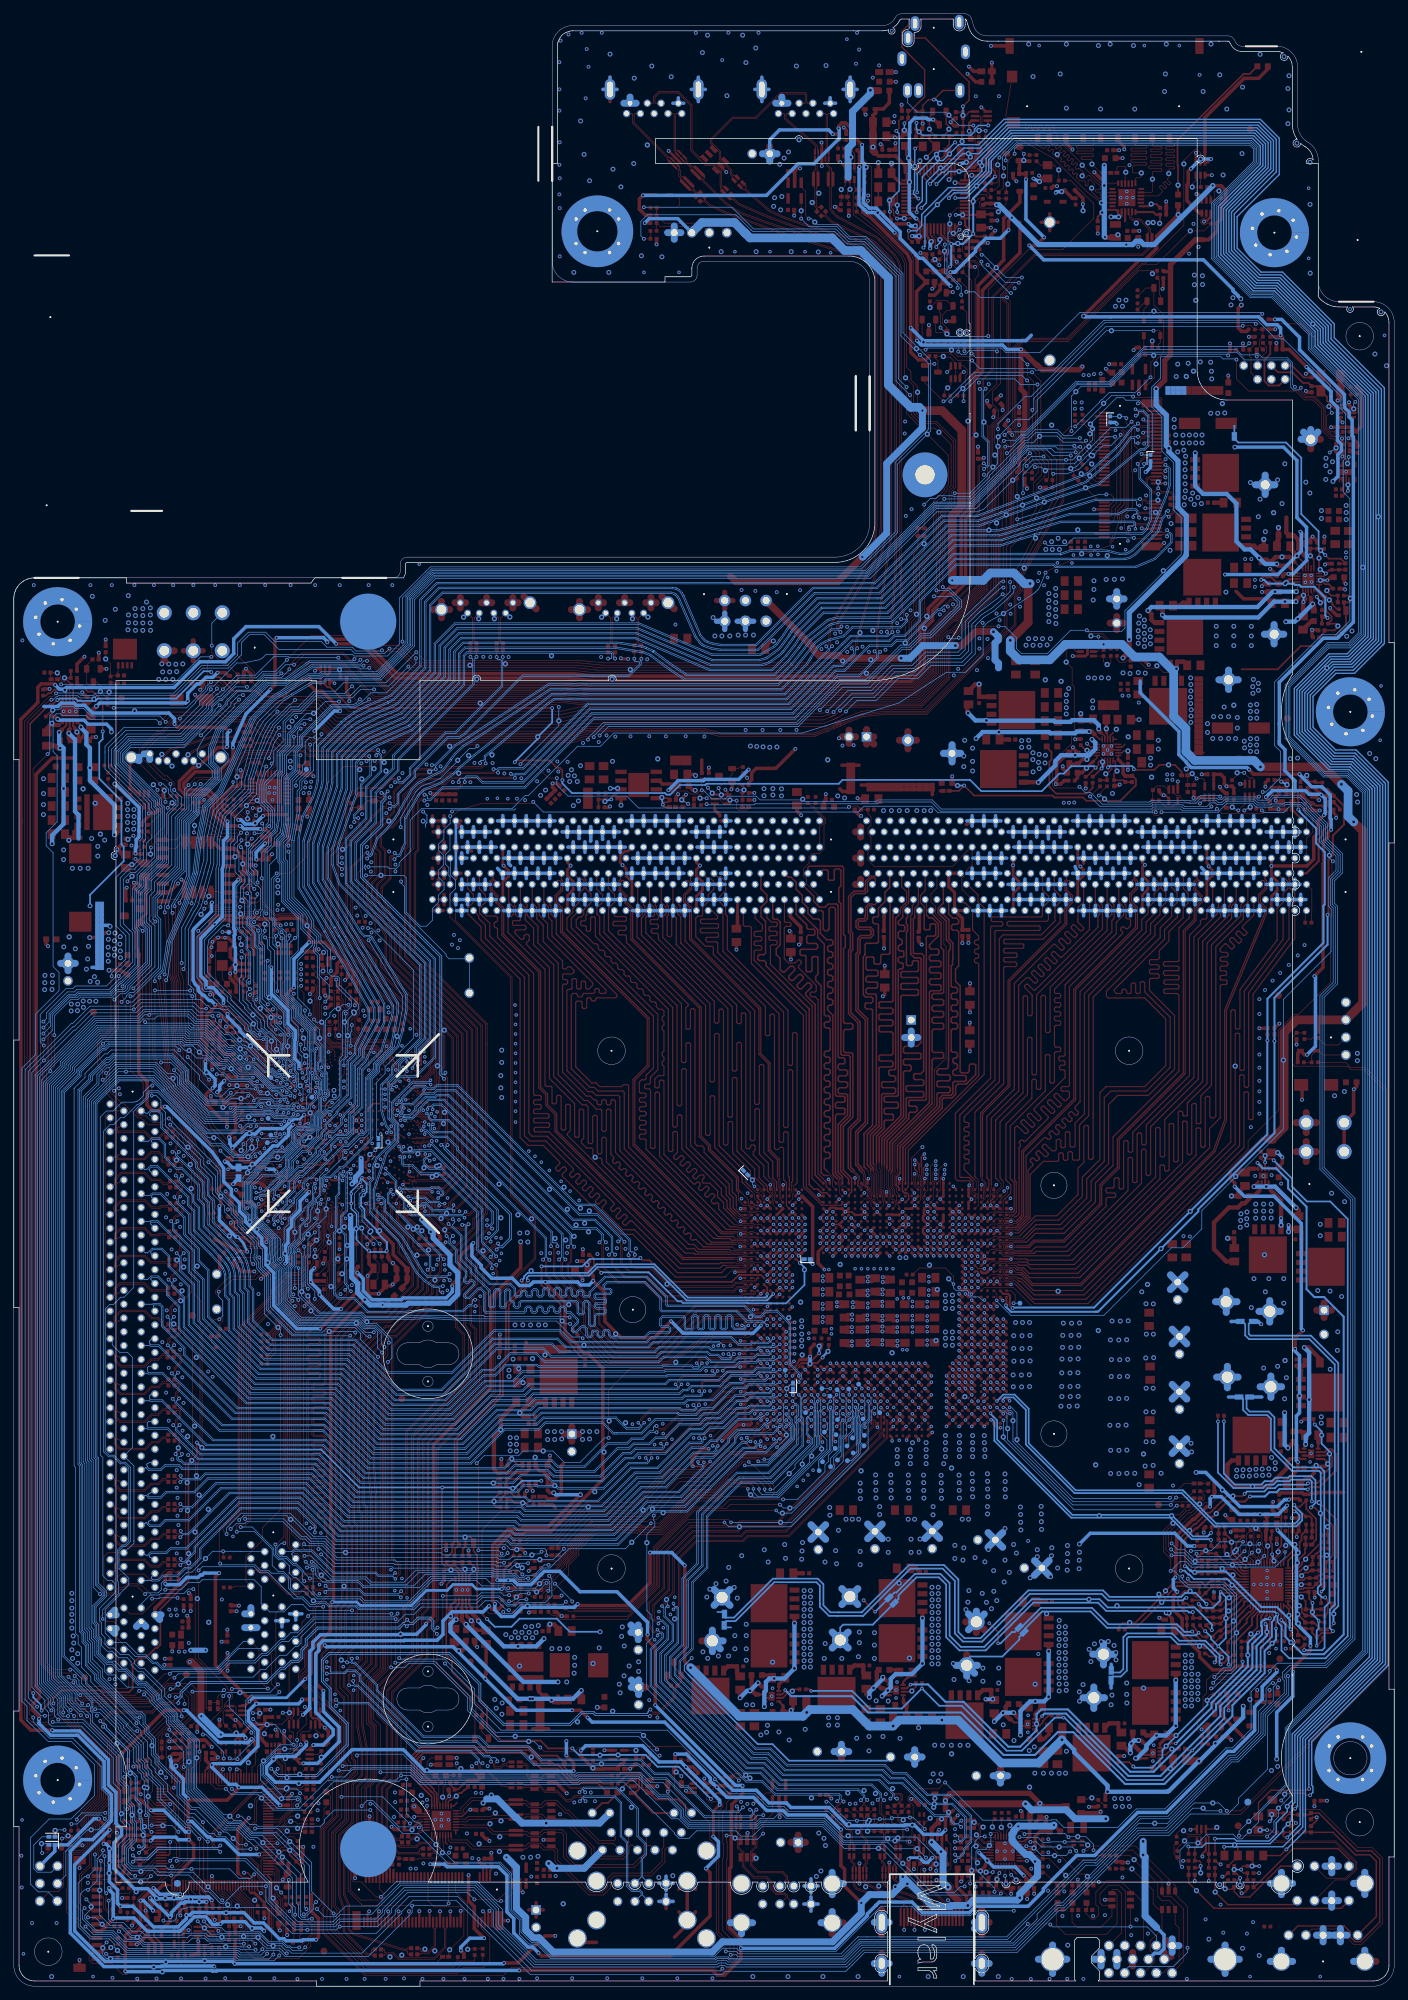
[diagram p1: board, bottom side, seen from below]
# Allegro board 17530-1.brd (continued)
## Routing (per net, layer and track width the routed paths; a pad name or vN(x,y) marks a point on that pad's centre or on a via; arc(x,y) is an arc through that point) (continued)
I2C0_SDA_VGA: length 3.3
  TOP w0.102: U5901.29 56.59,17.02 57.2,16.41 57.2,16.4 v3(57.21,16.39) 57.66,15.94 R5912.1
  BOTTOM w0.102: v3(57.21,16.39) v2(57.54,15.47)
I2S1_SFRM: length 5.3
  TOP w0.089: SB1.BD12 162.28,117.46 163.28,117.46 164.11,118.29 165.01,118.29
  TOP w0.102: R2054.1 v2(165.86,118.54) 165.26,118.54 165.01,118.29
ITP_PMODE: length 91.1
  TOP w0.089: v1(155.78,110.06) 155.78,110.4 155.53,110.64 155.53,110.68 155.39,110.82 155.39,110.88 155.38,110.89 155.38,112.11 155.44,112.18 155.44,112.57 SB1.AL3
  TOP w0.102: v3(156.39,99.55) 156.39,99.25 160.05,95.59 160.05,64.48 160.05,63.81 159.45,63.22 158.76,63.22 v3(157.88,62.33) ; v3(126.31,59.64) 126.39,59.56 127.66,59.56 128.12,60.02 R9911.1
  BOTTOM w0.102: v3(156.39,99.55) 156.39,100.67 157.48,101.76 157.48,105.44 157.05,105.87 157.05,107.14 v2(156.13,108.05) 155.78,108.41 v1(155.78,110.06) ; v3(157.88,62.33) 156.92,62.33 153.88,59.29 148.94,59.29 148.23,58.57 148.17,58.52 143.46,58.52 141.73,60.25 130.6,60.25 130.43,60.07 128,60.07 127.8,60.27 126.94,60.27 v3(126.31,59.64)
KBRST_N: length 167.9
  TOP w0.089: 163.74,130.19 162.49,130.19 SB1.BE39
  TOP w0.102: v1(163.98,130.37) 163.93,130.37 163.74,130.19 ; R2463.1 159.59,21.73 160.04,21.73 161.59,20.18 U2401.118 164.19,20.18 164.4,20.4 165.17,20.4 v3(165.71,19.86)
  BOTTOM w0.102: v1(163.98,130.37) 164.19,130.58 164.73,130.58 164.74,130.59 165.19,130.59 165.89,131.29 168.5,131.29 169.52,132.31 169.91,132.31 172.05,134.45 173.51,134.45 v2(174.6,135.54) 175.21,135.54 176.07,136.4 186.23,136.4 186.79,135.84 186.98,135.84 186.98,135.84 187.15,135.84 190.47,132.52 190.47,131.95 192.89,129.54 192.89,47.78 189.64,44.53 189.64,43.8 183.71,37.87 183.71,37.68 181.2,35.18 181.2,33.04 180.67,32.51 180.67,31.84 180.09,31.26 180.09,30.78 178.29,28.99 178.29,27.99 174.79,24.49 174.09,24.49 171.7,22.1 170.99,22.1 170.53,21.64 169.32,21.64 167.54,19.86 v3(165.71,19.86)
KCLK: length 6.7
  TOP w0.102: RN2403.4 158.41,24.17 v2(158.88,24.64) 159.92,24.64 160.77,23.79 160.77,23.58 162.17,22.18 U2401.113
KDAT: length 6.4
  TOP w0.102: U2401.114 162.25,21.78 160.15,23.88 v2(159.89,23.88) 159.26,23.88 158.9,23.52 RN2403.3
LAN_CONN_CVT: length 9.2
  BOTTOM w1.016: RJ45R1.9 117.36,17.08 v2(121.31,17.08) 121.8,17.08 122.12,17.39 v4(122.5,17.78)
LAN_LEDACT_R#: length 8
  TOP w0.267: EU3202.6 110.61,29.91 111.11,29.4 111.19,29.4 R3204.1 112.52,27.94 113.92,26.54 114.75,26.54 RJ45R1.22
LAN_MDI0_DN: length 9.6
  TOP w0.102: 132,26.89 133.57,26.89 134.82,25.64 134.82,25.34 135.16,25 135.96,25 U3101.2 ; 132,26.89 v2(132,26.54) ; 132,26.89 129.98,26.89 129.56,26.47 128.42,26.47 128.3,26.34 127.89,26.34
LAN_MDI0_DN_C: length 18
  TOP w0.102: RJ45R1.11 113.16,20.71 115.38,20.71 119.74,25.07 120.04,25.07 121.49,26.52 121.96,26.52 EU3201.1 122.29,26.52 122.83,26.52 123.48,25.87 125.31,25.87 125.94,26.5 126.08,26.5 126.24,26.34 R3203.2
LAN_MDI0_DP: length 9.7
  TOP w0.102: 130.81,27.3 133.74,27.3 135.23,25.81 135.23,25.5 135.33,25.4 U3101.1 ; 130.81,27.3 129.81,27.3 129.39,26.87 128.4,26.87 128.27,27 127.89,27 ; 130.81,27.3 v2(130.81,27.69)
LAN_MDI0_DP_C: length 18.1
  TOP w0.102: RJ45R1.10 112.85,21.67 112.85,21.26 113,21.11 115.21,21.11 119.57,25.48 119.88,25.48 121.32,26.92 123,26.92 123.65,26.28 124.44,26.28 EU3201.6 124.58,26.28 125.14,26.28 125.77,26.9 126.12,26.9 126.21,27 R3203.1
LAN_MDI1_DN: length 8.7
  TOP w0.102: 127.89,24.18 128.3,24.18 128.42,24.31 129.41,24.31 ; 129.41,24.31 130.58,24.31 130.73,24.16 134.04,24.16 134.39,23.8 U3101.5 ; 129.41,24.31 v2(129.41,23.95)
LAN_MDI1_DN_C: length 21.9
  TOP w0.102: RJ45R1.13 110.36,20.45 110.64,20.45 110.87,20.22 110.87,19.24 111.67,18.44 115.66,18.44 116.33,19.11 116.33,19.94 120.24,23.85 122.98,23.85 123.65,24.52 124.44,24.52 EU3201.4 124.58,24.52 125.84,24.52 126.19,24.18 R3205.2
LAN_MDI1_DP: length 8.7
  TOP w0.102: 130.24,24.71 128.4,24.71 128.27,24.84 127.89,24.84 ; 130.24,24.71 v2(130.24,25.1) ; 130.24,24.71 130.75,24.71 130.9,24.56 134.21,24.56 134.56,24.21 135.96,24.21 U3101.4
LAN_MDI1_DP_C: length 21.8
  TOP w0.102: R3205.1 126.19,24.84 126.1,24.93 123.48,24.93 122.81,24.26 122.32,24.26 EU3201.3 121.93,24.26 120.08,24.26 115.93,20.11 115.93,19.28 115.49,18.85 111.84,18.85 111.28,19.41 111.28,20.39 110.91,20.76 RJ45R1.12
LAN_MDI2_DN: length 8.9
  TOP w0.102: U3101.7 135.02,23 134.95,22.94 131.55,22.94 130.64,22.02 129.59,22.02 ; 129.59,22.02 v2(129.59,21.64) ; 129.59,22.02 128.45,22.02 128.32,21.89 127.89,21.89
LAN_MDI2_DN_C: length 26.3
  TOP w0.102: RJ45R1.15 107.79,20.42 108.12,20.42 108.31,20.23 108.31,19.01 110.09,17.22 118.87,17.22 120.35,18.69 120.35,21.92 120.68,22.25 122.03,22.25 EU3203.1 122.21,22.25 123.16,22.25 123.74,21.68 125.46,21.68 125.75,21.97 126.14,21.97 126.21,21.89 R3206.2
LAN_MDI2_DP: length 8.9
  TOP w0.102: v2(131,23.53) 131.29,23.25 ; 131.29,23.25 131.38,23.34 134.78,23.34 134.85,23.41 135.96,23.41 U3101.6 ; 131.29,23.25 130.47,22.43 128.4,22.43 128.27,22.56 127.89,22.56
LAN_MDI2_DP_C: length 26.2
  TOP w0.102: RJ45R1.14 108.37,20.74 108.71,20.4 108.71,19.18 110.26,17.63 118.7,17.63 119.94,18.86 119.94,22.09 120.51,22.66 123.33,22.66 123.9,22.09 124.44,22.09 EU3203.6 124.58,22.09 125.29,22.09 125.58,22.38 126.03,22.38 126.21,22.56 R3206.1
LAN_MDI3_DN: length 10.9
  TOP w0.102: v2(129.64,19.51) 129.64,19.86 ; 129.64,19.86 133.55,19.86 134.47,20.78 136.7,20.78 137.05,21.12 U3101.10 ; 129.64,19.86 128.4,19.86 128.27,19.74 127.89,19.74
LAN_MDI3_DN_C: length 30.9
  TOP w0.102: RJ45R1.17 105.2,20.07 105.37,20.07 105.66,19.77 105.66,17.96 107.65,15.98 113.06,15.98 113.54,15.49 113.54,14.22 114.55,13.21 116.71,13.21 121.59,18.08 121.59,19.54 121.78,19.74 123.24,19.74 123.83,20.32 124.45,20.32 EU3203.4 124.57,20.32 125.28,20.32 125.71,19.89 126.03,19.89 126.19,19.74 R3207.2
LAN_MDI3_DP: length 10.2
  TOP w0.102: v2(132.59,20.62) 132.59,20.27 ; 132.59,20.27 128.42,20.27 128.3,20.4 127.89,20.4 ; 132.59,20.27 133.38,20.27 134.3,21.18 136.53,21.18 136.64,21.29 136.64,21.91 U3101.9
LAN_MDI3_DP_C: length 31.5
  TOP w0.102: R3207.1 126.16,20.4 126.06,20.29 125.88,20.29 125.45,20.73 123.66,20.73 123.07,20.14 122.24,20.14 EU3203.3 122.01,20.14 121.62,20.14 121.18,19.71 121.18,18.25 116.54,13.61 114.72,13.61 113.94,14.39 113.94,15.66 113.22,16.38 107.81,16.38 106.07,18.13 106.07,19.94 105.83,20.19 RJ45R1.16
LAN_RSET: length 4.4
  TOP w0.203: 136.37,27.21 136.61,26.97 136.82,26.97 137.05,26.74 U3101.31
  TOP w0.254: R3101.2 134.2,28.87 134.65,28.42 134.72,28.42 135.15,28 135.42,28 v2(135.89,27.53) 136.05,27.53 136.37,27.21
LAN_XTALI: length 9.7
  TOP w0.102: X3101.1 139.54,33.08 140.13,32.49 v2(140.13,31.27) 139.39,30.53 R3104.2 138.42,30.02 138.42,29.85 C3119.1 138.43,29.07 138.43,27.19 138.43,26.74 138.25,26.57 U3101.28
LAN_XTALO: length 5.8
  TOP w0.102: R9931.2 136.31,30.53 R3104.1 137.45,30.47 137.45,29.92 137.45,29.15 137.79,28.81 137.79,27.45 v2(137.87,27.38) 137.85,27.36 U3101.29
LAN_XTALO_C: length 4.3
  TOP w0.102: C3118.1 135.37,29.95 R9931.1 135.23,30.72 v2(135.23,31.52) 135.71,31.52 136.28,32.09 X3101.3
LANCLK_REQ_U_N: length 7.5
  TOP w0.102: U3101.12 137.85,20.81 137.74,20.7 137.74,19.49 137.89,19.35 v2(137.9,19.35) 137.9,19.34 138.7,18.54 141.25,18.54 141.38,18.41 R3102.1
LANWAKE_R_N: length 6.3
  TOP w0.102: RN2001.2 167.64,136.25 v2(167.18,135.79) 166.41,135.79 165.38,134.76 165.19,134.76 164.74,134.32 164.74,133.89 163.82,132.96 163.68,132.96 SB1.BG44
LDO5V: length 16.6
  TOP w0.305: v3(9.65,198.2) 10.22,198.2 PR4958.2 10.46,197.37 PR4959.1 ; PG4903.2 18.95,204.24 19.28,203.91 v3(19.28,203.71)
  BOTTOM w0.305: v3(9.65,198.2) 9.98,198.53 9.98,201.12 11.58,202.72 13.51,202.72 13.77,202.97 14.38,202.97 14.56,203.15 v2(15.8,203.15) 18.29,203.15 18.85,203.71 v3(19.28,203.71)
LINE1_JD: length 343.9
  TOP w0.102: v3(18.42,21.67) 18.24,21.67 17.37,20.8 8.56,20.8 5.66,17.9 5.66,17.02 7.05,15.64 9.8,15.64 AUD1.33 ; R2711.2 57.88,260.17 57.17,260.89 57.17,263.29 57.45,263.57 v2(57.45,263.83) 57.45,264.6 v3(57.19,264.86)
  BOTTOM w0.102: v3(18.42,21.67) 17.42,22.66 17.42,23.89 16.76,24.55 v2(16.76,25.78) 15.1,27.44 15.1,37.13 4.29,47.94 4.02,48.21 3.89,48.34 3.89,173.12 4.12,173.36 4.12,173.36 6.68,175.92 10.03,175.92 15.11,181 15.11,188.2 9.46,193.85 6.38,193.85 4.47,195.76 4.47,230.11 11.76,237.4 11.76,238.98 11.76,239.55 17.47,245.26 20.54,245.26 25.78,250.51 25.78,257.96 19.71,264.03 19.71,266.43 20.65,267.36 54.91,267.36 57.2,265.07 57.2,264.87 v3(57.19,264.86)
LINE1_JD/LINE2_JD: length 8.7
  TOP w0.102: U2701.43 61.18,258.58 60.22,259.54 59.16,259.54 59.05,259.44 59.05,259.22 58.95,259.12 R2707.2 58.47,259.37 R2711.1 59.92,260.17 v2(60.52,260.77) 60.1,261.19 R2712.1
LINE1_LL: length 4.2
  TOP w0.203: L3001.1 22.63,15.37 v3(22.33,15.67) 22.33,15.8 22.91,16.38 R3003.1 23.2,16.4 23.2,17.38 R3001.2
  BOTTOM w0.203: v3(22.33,15.67) v2(22.33,14.66)
LINE1_LL_C: length 3.8
  TOP w0.203: R3001.1 22.66,18.81 C3001.2 22.66,19.99 v2(23.11,20.45)
LINE1_RR: length 4.5
  TOP w0.203: R3002.2 21.87,17.4 22.17,17.09 v3(22.17,16.89) 22.17,16.71 21.84,16.38 R3004.1 L3002.1
  BOTTOM w0.203: v3(22.17,16.89) v2(23.19,16.89)
LINE1_RR_C: length 3.6
  TOP w0.203: C3002.2 20.9,18.41 20.38,17.89 R3002.1 v3(19.56,17.4)
  BOTTOM w0.203: v3(19.56,17.4) v2(20.6,17.4)
LINE2_JD: length 24.9
  TOP w0.102: R2712.2 57.58,261.19 57.4,261.37 57.4,262.88 58.01,263.5 58.01,265.2 57.78,265.43 57.78,266.24 58.12,266.57 60.49,266.57 60.73,266.81 60.73,268.55 60.98,268.79 v3(60.98,269.53)
  BOTTOM w0.102: HPMIC1.6 70.52,272.83 69.14,271.45 64.95,271.45 v2(64.52,271.02) 63.96,270.46 63.95,270.46 63.02,269.53 v3(60.98,269.53)
LINE2_VREFO: length 5.2
  TOP w0.305: v3(70.36,255.27) 69.67,254.58 U2701.12
  TOP w0.508: v3(70.36,255.27) 72.2,255.27 72.52,254.95 R2901.1
  BOTTOM w0.508: v2(69.39,254.96) 69.39,254.97 70.05,254.97 v3(70.36,255.27)
LINEIN_L: length 4.1
  TOP w0.203: R2904.1 67.35,268.83 v2(67.35,268.99) 67.35,270.7 66.88,271.16 D2901.2
LINEIN_R: length 4.1
  TOP w0.203: D2901.3 64.91,269.77 64.52,269.37 v2(64.52,268.99) 64.52,268.78 65.33,267.97 R2903.1
LINK_ACTIVITY_N: length 38.3
  TOP w0.203: 139.32,28.73 139.09,28.49 139.09,28.3 138.71,27.92 138.71,27.07 138.71,26.68 138.71,26.63 138.66,26.58 138.66,26.1 138.65,26.09 U3101.27
  TOP w0.267: 139.32,28.73 141.56,30.97 141.56,32.91 140.7,33.77 125.9,33.77 TP3101.1 123.64,31.52 121.19,31.52 119.07,29.39 115.37,29.39 R3204.2
LPC_AD_PCH_P0: length 212.7
  TOP w0.102: v1(160.42,130.62) 160.68,130.37 SB1.BB39 ; v3(192.83,39.66) 192.83,38.94 187.55,33.67 187.55,27.48 189.99,25.04 189.99,23.41 189.27,22.68 189.27,20.08 189.94,19.41 191.48,19.41 191.9,18.98 191.9,14.12 192.11,13.91 192.11,11.14 v3(189.61,8.64) 189.28,8.96 LPC1.9 ; U2401.8 167.49,13.85 167.16,13.51 165.25,11.61 165.25,9.94 164.62,9.31 v2(164.62,7.06) 163.98,6.43 v3(163.98,5.36)
  BOTTOM w0.102: v3(189.61,8.64) 188.44,7.47 185.81,7.47 183.53,5.18 167.45,5.18 167.09,4.83 164.52,4.83 v3(163.98,5.36) ; v3(192.83,39.66) 192.83,40.16 193.04,40.37 193.04,41.77 195.4,44.13 195.4,130.82 192.99,133.23 192.99,133.77 187.85,138.91 174.73,138.91 174.35,138.53 174.31,138.53 173.11,138.53 172.29,138.53 169.15,135.39 168.53,135.39 166.72,133.58 164.97,133.58 163.73,132.34 162.71,132.34 161.98,131.61 161.5,131.61 160.52,130.62 v1(160.42,130.62)
LPC_AD_PCH_P1: length 211.9
  TOP w0.102: SB1.AW37 159.61,129.69 159.34,129.69 159.31,129.72 v1(159.24,129.72) ; LPC1.8 v3(189.26,9.96) 191.62,12.32 191.62,18.87 191.36,19.13 189.82,19.13 188.99,19.96 188.99,22.8 189.71,23.52 189.71,24.92 187.27,27.36 187.27,33.79 192.15,38.66 v3(192.15,39.12) ; v3(165,6.15) 165.18,6.32 165.18,7.29 164.92,7.55 164.92,8.81 165.53,9.43 165.53,11.5 167.27,13.23 167.28,13.23 167.89,13.84 U2401.9
  BOTTOM w0.102: v1(159.24,129.72) 159.27,129.75 159.27,130.34 160.07,131.14 160.75,131.14 161.42,131.81 161.9,131.81 162.62,132.54 163.65,132.54 164.95,133.84 165.42,133.84 165.44,133.86 166.6,133.86 168.41,135.67 169.03,135.67 172.17,138.81 173.23,138.81 173.23,138.81 173.99,138.81 173.99,138.81 174.19,138.81 174.57,139.19 187.96,139.19 193.27,133.88 193.27,133.35 195.68,130.94 195.68,44.01 193.32,41.65 193.32,39.5 192.93,39.12 v3(192.15,39.12) ; v3(189.26,9.96) 188.2,9.96 v2(187.2,8.97) 186.69,8.46 184.41,8.46 183.01,7.06 181.77,7.06 181.01,6.3 174.8,6.3 174.14,6.96 172.37,6.96 171.97,6.55 169.62,6.55 169.51,6.66 165.51,6.66 v3(165,6.15)
LPC_AD_PCH_P2: length 210.7
  TOP w0.102: U2401.10 168.29,13.85 167.4,12.95 167.39,12.95 165.81,11.38 165.81,9.31 165.48,8.98 v2(165.48,8.38) 165.48,5.94 164.97,5.43 v3(164.97,5.28) ; v1(159.32,128.81) 159.06,129.08 SB1.AV37 ; v3(191.26,39.12) 191.26,38.17 187,33.9 187,27.66 187,27.25 189.43,24.81 189.43,23.64 188.71,22.91 188.71,19.85 189.05,19.5 189.05,17.59 190.5,16.14 190.5,12.06 v3(189.74,11.3) 189.4,10.96 LPC1.7
  BOTTOM w0.102: v3(189.74,11.3) 190.06,10.98 190.06,9.73 189.43,9.09 189.42,9.09 188.08,7.75 185.7,7.75 183.41,5.46 167.33,5.46 167.15,5.28 v3(164.97,5.28) ; v1(159.32,128.81) 159.32,128.96 160.12,129.76 160.13,129.76 160.76,130.39 162.27,130.39 165.18,133.3 166.83,133.3 168.65,135.11 169.26,135.11 172.35,138.2 174.45,138.2 174.88,138.63 187.73,138.63 192.71,133.65 192.71,133.12 195.12,130.71 195.12,44.25 192.76,41.88 192.76,40.49 192.23,39.95 192.23,39.82 191.96,39.55 191.69,39.55 v3(191.26,39.12)
LPC_AD_PCH_P3: length 207.1
  TOP w0.102: LPC1.6 188.88,11.96 v3(189.48,12.57) 190.22,13.31 190.22,16.02 188.77,17.47 188.77,19.39 188.43,19.73 188.43,23.03 189.15,23.76 189.15,24.69 186.72,27.13 186.72,27.78 186.72,34.02 190.76,38.06 190.76,39.45 191.31,40.01 v3(191.77,40.01) ; U2401.11 168.69,13.85 167.52,12.67 167.5,12.67 166.09,11.26 166.09,9.19 166.09,9.19 166.09,5.93 v3(165.91,5.74) ; SB1.BA38 v1(160.43,129.46)
  BOTTOM w0.102: v1(160.43,129.46) 160.68,129.71 160.68,129.85 161.02,130.19 162.35,130.19 165.18,133.02 166.95,133.02 168.76,134.83 169.38,134.83 172.47,137.92 174.57,137.92 175.01,138.35 187.61,138.35 192.43,133.54 192.43,133 194.84,130.59 194.84,44.36 192.48,42 192.48,41.77 192.48,40.72 v3(191.77,40.01) ; v3(165.91,5.74) 165.93,5.74 165.99,5.69 167.16,5.69 167.21,5.74 181.24,5.74 182,6.5 184.06,6.5 185.58,8.03 187.96,8.03 189.31,9.37 189.31,9.37 189.71,9.78 189.71,10.26 188.8,11.18 v2(188.8,11.52) 188.8,11.89 v3(189.48,12.57)
LPC_CLK_14M_DEBUG: length 2.9
  TOP w0.102: LPC1.2 186.88,15.96 186.46,16.38 v2(186.18,16.38) 186.17,16.4 R1915.2
LPC_CLK_14M_EC: length 4.3
  TOP w0.102: U2401.7 167.09,13.92 165.63,12.46 v2(165.11,12.46) 164.74,12.09 164.74,11.67 R1914.2
LPC_CLK_33M_EC: length 4.9
  TOP w0.102: R1916.2 169.04,10.86 168.99,10.86 168.99,11.79 v2(169.01,11.81) 169.01,12.34 169.68,13 169.95,13 170.69,13.75 U2401.16
LPC_CLK_PCH_P0: length 209.3
  TOP w0.102: v3(189.26,15.9) 188.84,15.48 186.46,15.48 186.44,15.51 185.89,15.51 185.88,15.52 185.43,15.52 185.42,15.51 R1915.1 ; v1(161.09,129.69) 161.1,129.68 SB1.BB36 ; v3(163.3,4.71) 163.3,6.76 164.26,7.72 164.26,9.38 164.49,9.61 164.49,10.45 164.67,10.63 R1914.1 ; v3(190.28,39.24) 186.41,35.37 186.41,27.9 186.41,27.9 186.41,27 188.85,24.57 188.85,23.88 188.12,23.16 188.12,19.19 v3(188.24,19.08)
  BOTTOM w0.102: v3(190.28,39.24) 190.32,39.24 192.18,41.09 192.18,41.64 192.18,42.13 194.54,44.49 194.54,130.46 192.13,132.88 192.13,133.41 187.49,138.05 175.16,138.05 174.73,137.62 172.59,137.62 169.51,134.53 168.89,134.53 167.07,132.72 165.17,132.72 162.44,129.99 162.28,129.99 162.26,129.97 161.38,129.97 v1(161.09,129.69) ; v3(188.24,19.08) 188.24,16.92 v3(189.26,15.9) 189.26,15.9 189.71,15.9 190.67,14.94 190.67,8.62 188.91,6.86 186.18,6.86 185.37,6.05 185.37,5.56 v2(184.99,5.18) 184.38,4.57 167.7,4.57 167.34,4.22 163.8,4.22 v3(163.3,4.71)
LPC_CLK_PCH_P1: length 178.9
  TOP w0.102: v1(160.3,127.99) 160.66,127.99 160.66,127.99 160.83,127.99 SB1.BB34 ; R1916.1 169.67,10.35 169.67,12.3 169.77,12.4 169.77,12.42 v3(169.8,12.45)
  BOTTOM w0.102: v3(169.8,12.45) 169.93,12.45 v2(171.86,14.38) 173.99,16.51 174.46,16.51 174.46,16.51 178.92,16.51 179.5,17.1 182.94,17.1 183.66,17.82 183.66,20.02 182.54,21.15 182.54,23.6 182.78,23.83 182.78,26.01 183.34,26.57 183.34,28.92 184.46,30.04 184.46,33.63 188.89,38.07 188.89,39.3 189.73,40.13 190.35,40.13 191.57,41.35 191.57,41.87 191.57,42.38 193.93,44.74 193.93,130.21 191.52,132.62 191.52,133.16 187.23,137.44 175.44,137.44 175.01,137.01 173.14,137.01 170.05,133.92 169.14,133.92 167.33,132.11 165.14,132.11 162.58,129.55 161.82,129.55 161.08,128.81 160.65,128.81 160.3,128.46 v1(160.3,127.99)
LPC_FRAME#_PCH: length 36.2
  TOP w0.102: U2401.12 169.09,13.85 167.64,12.4 167.62,12.4 166.37,11.15 166.37,9.08 166.37,9.07 166.37,8.3 166.7,7.97 v2(166.7,7.21) 166.7,6.17 v3(166.67,6.15) ; LPC1.5 187.09,12.96 187,12.87 187,11.27 185.99,10.26 185.4,10.26 185.11,9.98 185.11,9.11 R1913.2 185.46,8.65 v3(184.76,7.95)
  BOTTOM w0.102: v3(184.76,7.95) 183.59,6.78 181.89,6.78 181.13,6.02 171.78,6.02 171.63,6.17 166.7,6.17 v3(166.67,6.15)
LPC_FRAME#_PCH_R: length 191.6
  TOP w0.089: 164.36,130.08 164.25,129.97 163.68,129.97 163.65,130 162.82,130 SB1.BE38
  TOP w0.102: v1(165.34,131.62) 165.34,131.09 164.97,130.72 164.97,130.72 164.87,130.62 164.77,130.62 164.36,130.22 164.36,130.08 ; R1913.1 184.14,8.33 182.55,8.33 182.13,8.75 182.13,12.58 179.95,14.76 179.95,14.76 179.09,14.76 178.26,15.6 178.1,15.6 177.64,16.06 177.64,16.22 177.25,16.61 177.16,16.61 175.95,17.82 175.95,20.66 176.61,21.32 176.61,25.36 176.49,25.48 176.49,27.1 177.6,28.21 177.6,28.65 179.41,30.46 179.41,34.27 v2(179.98,34.85) 179.98,35.74 177.79,37.93 175.52,37.93 174.19,39.26 174.19,40.19 174.19,42.03 175.69,43.54 177.64,43.54 178.99,42.19 179.22,42.19 180.46,40.95 187.67,40.95 187.81,41.1 188.88,41.1 v3(189.24,40.74)
  BOTTOM w0.102: v3(189.24,40.74) 189.5,40.48 190.27,40.48 191.11,41.32 191.11,42.35 193.62,44.87 193.62,130.08 191.21,132.5 191.21,133.03 187.11,137.13 175.56,137.13 175.13,136.7 173.26,136.7 170.18,133.62 169.27,133.62 167.45,131.8 165.52,131.8 v1(165.34,131.62)
LPC_PME_N: length 146.1
  TOP w0.102: v1(160.8,123.53) 160.79,123.52 160.58,123.52 160.11,123.05 160.11,122.9 160.02,122.81 160.02,122.53 SB1.AV21 ; U2401.75 173.09,32.52 172.89,32.72 172.89,33.44 173.09,33.64 173.09,33.66 173.1,33.67 v3(173.1,33.96) 173.1,34.12 R2421.1
  BOTTOM w0.102: v1(160.8,123.53) 160.8,123.47 161.43,122.83 162.47,122.83 162.55,122.76 164.09,122.76 164.35,123.01 165.62,123.01 166.27,122.36 166.27,121.06 166.83,120.5 167.94,120.5 168.41,120.97 168.51,120.97 170.45,122.91 v2(171.02,122.91) 171.87,122.91 178.54,129.58 178.54,129.64 178.59,129.69 178.59,129.76 179.97,131.14 184.68,131.14 187.69,128.14 187.95,127.87 187.95,76.74 187.73,76.51 187.73,58.4 186.59,57.27 186.59,56.42 188.09,54.93 188.09,52.79 187.76,52.46 187.76,50.78 187.27,50.3 187.27,49.33 186.46,48.51 185.72,48.51 184.78,47.57 183.57,47.57 183.01,47.02 183.01,46.56 181.99,45.54 181.59,45.54 181.3,45.54 178.61,42.86 178.61,42.86 178.61,41.79 176.38,39.56 176.25,39.42 176.25,38.69 173.73,36.17 173.73,36.17 173.33,35.77 173.1,35.54 v3(173.1,33.96)
LPC_SERIRQ_PCH: length 218.2
  TOP w0.102: v3(160.45,4.75) 160.76,4.75 161.11,5.1 161.11,7.22 160.99,7.34 160.99,11.05 161.32,11.38 161.32,11.66 161.34,11.69 161.34,12.41 161.84,12.95 162.15,13.26 162.15,13.28 162.18,13.31 162.18,16.36 162.4,16.58 U2401.127 ; v3(189.38,39.1) 186.11,35.83 186.11,28.03 186.11,26.88 188.54,24.44 188.54,24.01 187.82,23.28 187.82,19.34 187.71,19.22 187.71,18.49 187.95,18.25 LPC1.1 186.43,16.96 186.42,16.97 184.89,16.97 184.77,17.08 R1910.1 186.62,17.4 v3(187.39,18.16) ; v1(159.94,129.01) 159.75,128.81 SB1.AW35
  BOTTOM w0.102: v3(189.38,39.1) 190.11,39.83 190.48,39.83 191.87,41.22 191.87,41.51 191.87,41.52 191.87,42 191.87,42 191.87,42.25 194.23,44.61 194.23,130.34 191.82,132.75 191.82,133.28 187.36,137.74 175.31,137.74 174.88,137.31 172.9,137.31 169.81,134.23 169.01,134.23 167.2,132.41 165.15,132.41 162.52,129.78 162.52,129.78 162.49,129.75 161.73,129.75 160.99,129.01 160.56,129.01 160.56,129.01 v1(159.94,129.01) ; v3(160.45,4.75) 160.71,4.75 161.46,5.5 163.39,5.5 164.83,6.94 169.76,6.94 169.87,6.83 171.85,6.83 172.33,7.32 174.57,7.32 174.85,7.04 181.36,7.04 181.66,7.34 182.9,7.34 184.35,8.79 186.03,8.79 187.55,10.31 v2(187.55,13.89) 187.55,16.52 187.39,16.69 v3(187.39,18.16)
LPSS_GSPI0_MOSI: length 4.9
  TOP w0.102: SB1.BE30 162.53,125.87 162.59,125.8 163.38,125.8 163.55,125.96 165.05,125.96 165.81,126.72 TP1508.1
LPSS_GSPI1_MOSI: length 3.9
  TOP w0.102: SB1.BA26 160.41,124.89 v1(160.81,125.29)
  BOTTOM w0.102: v1(160.81,125.29) 162.74,125.29 TP1507.1
M_A_A0: length 55.4
  TOP w0.089: 80.29,116.99 80.3,116.98 80.3,116.09 80.08,115.87 79.53,115.87 CPU1.AW15
  TOP w0.216: DIMM1.79 82.95,155.8 82.74,155.58 82.74,153.11 82.52,152.89 82.09,152.89 81.88,153.11 81.88,156.06 81.66,156.27 81.17,156.27 80.96,156.06 80.96,129.12 80.74,128.9 79.74,128.9 79.58,128.73 79.58,128.2 79.74,128.04 80.74,128.04 80.96,127.82 80.96,127.39 80.74,127.17 79.74,127.17 79.58,127.01 79.58,126.47 79.74,126.31 80.74,126.31 80.96,126.09 80.96,117.74 80.29,117.08 80.29,116.99
M_A_A1: length 57.3
  TOP w0.089: 75.83,118.1 75.83,117.69 75.46,117.32 75.46,114.92 75.73,114.65 75.73,114.11 CPU1.AU18
  TOP w0.216: DIMM1.72 73.05,149.63 73.22,149.46 74.23,149.46 74.4,149.3 74.4,148.21 74.56,148.04 75.2,148.04 75.36,148.21 75.36,148.92 75.53,149.08 76.37,149.08 76.53,148.92 76.53,147.38 76.31,147.16 74.97,147.16 74.8,147 74.8,146.47 74.97,146.3 76.31,146.3 76.53,146.08 76.53,145.65 76.31,145.44 75.02,145.44 74.85,145.27 74.85,144.74 75.02,144.57 76.31,144.57 76.53,144.36 76.53,143.93 76.31,143.71 75.2,143.71 75.03,143.54 75.03,124.72 76.34,123.42 76.34,118.94 75.83,118.43 75.83,118.1
M_A_A2: length 56.2
  TOP w0.089: CPU1.AU17 76.71,114.05 76.1,114.05 75.95,114.2 75.95,114.74 75.68,115.01 75.68,117.18 76.17,117.68 76.17,118.06 76.45,118.34
  TOP w0.216: 76.45,118.34 76.81,118.69 76.81,123.48 75.58,124.72 75.58,141.37 75.74,141.54 76.44,141.54 76.66,141.76 76.66,142.26 76.49,142.43 75.76,142.43 75.54,142.64 75.54,143.07 75.76,143.29 76.59,143.29 76.92,143.62 76.92,149.11 76.67,149.36 76.67,149.46 76.66,149.47 76.66,150.9 76.49,151.06 74.89,151.06 74.73,151.23 74.73,152.68 74.73,153.74 74.89,153.91 75.35,153.91 75.56,154.12 75.56,154.71 75.4,154.87 74.89,154.87 74.73,155.04 74.73,156.15 73.78,157.09 73.78,158.45 73.1,159.13 73.1,161.15 DIMM1.216
M_A_A3: length 58.7
  TOP w0.089: CPU1.AV19 75.25,114.59 75.25,117.47 75.49,117.72 75.49,118.11
  TOP w0.216: 75.49,118.11 75.49,118.57 75.9,118.98 75.9,123.32 74.65,124.57 74.65,132.98 74.49,133.15 72.83,133.15 72.62,133.36 72.62,133.8 72.83,134.01 74.49,134.01 74.65,134.18 74.65,134.71 74.49,134.88 72.83,134.88 72.62,135.09 72.62,138.02 72.83,138.24 74.49,138.24 74.65,138.4 74.65,138.94 74.49,139.1 72.83,139.1 72.62,139.32 72.62,139.75 72.83,139.97 74.49,139.97 74.65,140.13 74.65,140.66 74.49,140.83 72.83,140.83 72.62,141.05 72.62,141.48 72.83,141.69 74.49,141.69 74.65,141.86 74.65,142.42 74.49,142.58 72.78,142.58 72.62,142.75 72.62,155.38 DIMM1.71
M_A_A4: length 57.8
  TOP w0.089: 75.36,119 75.21,118.85 75.21,117.86 75.06,117.7 75.06,117.59 75.03,117.56 75.03,114.26 75.33,113.97 75.5,113.97 75.79,113.68 75.79,113.04 CPU1.AT19
  TOP w0.165: 71.78,155.17 71.53,155.42 71.53,156.16 70.91,156.78 70.89,156.78 70.64,157.03 70.64,158.53 71.35,159.25 DIMM1.214
  TOP w0.216: 71.78,155.17 72.24,154.71 72.24,132.91 72.4,132.74 73.03,132.74 73.23,132.54 73.23,132.08 73.03,131.88 72.45,131.88 72.24,131.66 72.24,131.23 72.45,131.01 74.1,131.01 74.27,130.85 74.27,130.31 74.1,130.15 72.45,130.15 72.24,129.93 72.24,129.5 72.45,129.29 74.1,129.29 74.27,129.12 74.27,124.41 75.49,123.19 75.49,119.12 75.36,119
M_A_A5: length 59.5
  TOP w0.089: CPU1.AU20 74.82,113.89 74.82,114.65 74.77,114.7 74.77,117.95 74.99,118.17 74.99,118.94 75.01,118.95 75.01,119.2
  TOP w0.165: DIMM1.213 70.36,159.46 70.36,158.67 70.35,158.65 70.35,157.15 70.35,156.91 70.77,156.49 70.79,156.49 71.19,156.09 71.19,155 71.2,155
  TOP w0.216: 75.01,119.2 75.01,123.13 73.89,124.25 73.89,125.29 73.72,125.45 72.73,125.45 72.57,125.62 72.57,126.15 72.73,126.31 73.72,126.31 73.89,126.48 73.89,127.01 73.72,127.18 72.02,127.18 71.86,127.34 71.86,127.88 72.02,128.04 73.72,128.04 73.89,128.21 73.89,128.74 73.72,128.91 72.06,128.91 71.86,129.11 71.86,147.16 71.64,147.37 71.31,147.37 71.15,147.54 71.15,148.07 71.31,148.23 71.64,148.23 71.86,148.45 71.86,148.88 71.64,149.1 71.21,149.1 71.05,149.26 71.05,149.8 71.21,149.96 71.64,149.96 71.86,150.18 71.86,150.61 71.64,150.83 71.5,150.83 71.29,151.04 71.29,151.47 71.5,151.69 71.64,151.69 71.86,151.9 71.86,152.6 71.64,152.82 71.1,152.82 70.88,153.03 70.88,153.46 71.1,153.68 71.64,153.68 71.86,153.89 71.86,154.2 71.2,154.86 71.2,155
M_A_A6: length 57.5
  TOP w0.089: 74.63,119.43 74.63,118.47 74.47,118.31 74.47,115.42 74.49,115.4 74.49,115.08 74.49,114.72 74.49,114.69 74.47,114.66 CPU1.AV20
  TOP w0.216: DIMM1.69 70.5,154.86 70.69,154.67 70.69,153.89 70.5,153.71 70.5,152.87 70.67,152.7 70.67,147.98 70.53,147.84 69.96,147.84 69.8,148 69.8,148.39 69.63,148.55 69.08,148.55 68.94,148.41 68.94,147.14 69.1,146.98 71.31,146.98 71.48,146.81 71.48,146.28 71.31,146.11 69.1,146.11 68.94,145.95 68.94,145.41 69.1,145.25 71.31,145.25 71.48,145.08 71.48,144.55 71.31,144.38 69.1,144.38 68.94,144.22 68.94,143.69 69.1,143.52 71.31,143.52 71.48,143.36 71.48,126.11 74.63,122.96 74.63,119.43
M_A_A7: length 58.7
  TOP w0.089: CPU1.AU21 73.89,113.88 73.89,114.3 73.9,114.31 73.9,114.74 74.06,114.9 74.06,115.22 73.89,115.39 73.89,118.82 73.86,118.85
  TOP w0.165: 69.47,154.99 69.47,156.12 68.94,156.65 68.94,156.85 68.95,156.86 68.95,158.09 68.94,158.11 68.94,159.46 DIMM1.211
  TOP w0.216: 73.86,118.85 73.86,122.65 70.71,125.8 70.71,128.56 70.55,128.73 68.34,128.73 68.17,128.89 68.17,129.43 68.34,129.59 70.55,129.59 70.71,129.76 70.71,130.29 70.55,130.45 68.34,130.45 68.17,130.62 68.17,131.15 68.34,131.32 69.44,131.32 69.62,131.5 69.62,132 69.44,132.18 68.56,132.18 68.17,132.57 68.17,149.3 68.44,149.57 69.53,149.57 69.67,149.71 69.67,154.6 69.47,154.8 69.47,154.99
M_A_A8: length 56.2
  TOP w0.089: 74.24,119.02 74.24,118.69 74.21,118.66 74.21,115.37 74.28,115.31 74.28,114.99 74.28,114.81 74.12,114.65 74.12,114.22 74.11,114.21 74.11,113.79 74.02,113.7 74.02,113.08 CPU1.AT20
  TOP w0.165: 70.05,154.58 70.05,155.12 69.82,155.35 69.82,156.49 69.65,156.66 DIMM1.68
  TOP w0.216: 70.05,154.58 70.05,149.52 69.49,148.96 69.15,148.96 69.14,148.95 68.71,148.95 68.55,148.79 68.55,136.69 69.1,136.14 70.88,136.14 71.09,135.93 71.09,135.32 70.93,135.15 68.72,135.15 68.55,134.99 68.55,134.45 68.72,134.29 70.93,134.29 71.09,134.12 71.09,133.59 70.93,133.43 70.18,133.43 69.98,133.22 69.98,132.77 70.18,132.56 70.93,132.56 71.09,132.4 71.09,125.95 74.24,122.8 74.24,119.02
M_A_A9: length 60.4
  TOP w0.089: 73.19,118.14 73.25,118.07 73.25,115.66 72.92,115.33 72.92,114.8 72.99,114.73 72.99,114.19 72.77,113.97 72.52,113.97 72.29,113.74 72.29,112.98 CPU1.AT22
  TOP w0.165: 67.55,154.93 67.77,155.14 67.77,157.22 DIMM1.66
  TOP w0.216: 73.19,118.14 73.08,118.25 73.08,122.24 67.34,127.97 67.34,133.05 67.34,133.05 67.34,143.98 67.12,144.19 65.82,144.19 65.67,144.35 65.67,144.9 65.82,145.06 67.12,145.06 67.34,145.27 67.34,145.71 67.12,145.92 65.85,145.92 65.67,146.11 65.67,146.6 65.85,146.78 67.12,146.78 67.34,147 67.34,147.43 67.12,147.65 65.85,147.65 65.67,147.83 65.67,148.33 65.85,148.51 67.12,148.51 67.34,148.73 67.34,149.16 67.12,149.38 66.17,149.38 65.96,149.59 65.96,150.02 66.17,150.24 67.12,150.24 67.34,150.46 67.34,150.84 66.04,152.13 66.04,153.85 66.91,154.72 67.35,154.72 67.55,154.93
M_A_A10: length 55.6
  TOP w0.216: CPU1.AY14 79.95,116.84 79.95,116.85 79.95,117.22 79.95,117.22 79.95,117.28 80.58,117.9 80.58,124.84 79.2,126.22 79.2,129.04 79.43,129.28 80.4,129.28 80.58,129.45 80.58,129.93 80.36,130.14 79.41,130.14 79.2,130.36 79.2,130.79 79.41,131.01 80.36,131.01 80.58,131.22 80.58,131.66 80.36,131.87 79.41,131.87 79.2,132.09 79.2,132.52 79.41,132.74 80.36,132.74 80.58,132.95 80.58,133.38 80.36,133.6 79.76,133.6 79.58,133.78 79.58,134.28 79.76,134.46 80.36,134.46 80.58,134.68 80.58,156.54 80.79,156.75 81.99,156.75 82.43,156.31 83.26,156.31 84.1,157.15 84.1,157.9 DIMM1.225
M_A_A11: length 58.6
  TOP w0.089: CPU1.AU22 73.01,113.54 73.2,113.74 73.2,114.82 73.14,114.89 73.14,115.24 73.52,115.62 73.52,118.35
  TOP w0.165: DIMM1.210 67.95,158.68 68.66,157.97 68.66,156.98 68.11,156.43 68.11,155.07
  TOP w0.216: 68.11,155.07 68.11,153.19 67.94,153.02 67.42,153.02 67.26,153.19 67.26,153.72 67.09,153.88 66.61,153.88 66.42,153.69 66.42,152.32 66.63,152.11 67.63,152.11 67.79,151.94 67.79,128.49 67.96,128.32 70.17,128.32 70.33,128.16 70.33,127.62 70.17,127.46 69.3,127.46 69.14,127.29 69.14,126.83 69.37,126.59 70.17,126.59 70.33,126.43 70.33,125.64 73.48,122.49 73.48,118.69 73.52,118.65 73.52,118.35
M_A_A12: length 57.6
  TOP w0.089: 72.92,117.82 72.92,115.63 72.64,115.35 CPU1.AV22
  TOP w0.216: 72.92,117.82 72.69,118.05 72.69,122.08 66.96,127.81 66.96,132.89 66.95,132.9 66.95,134.18 66.74,134.39 65.46,134.39 65.28,134.57 65.28,135.08 65.46,135.25 66.74,135.25 66.95,135.47 66.95,138.4 66.74,138.62 65.46,138.62 65.28,138.8 65.28,139.3 65.46,139.48 66.74,139.48 66.95,139.7 66.95,140.13 66.74,140.35 65.46,140.35 65.28,140.52 65.28,141.03 65.46,141.21 66.74,141.21 66.95,141.43 66.95,141.86 66.74,142.07 65.46,142.07 65.28,142.25 65.28,142.76 65.46,142.94 66.74,142.94 66.95,143.15 66.95,143.58 66.74,143.8 65.46,143.8 65.28,143.98 65.28,150.08 65.66,150.46 65.66,154.01 67.1,155.45 DIMM1.65
M_A_A13: length 54.1
  TOP w0.216: DIMM1.232 91.75,158.92 90.88,158.05 90.88,157.14 91.74,156.27 91.74,154.93 91.08,154.27 91.08,149.64 91.3,149.42 91.99,149.42 92.2,149.21 92.2,148.77 91.99,148.56 91.3,148.56 91.01,148.27 91.01,147.81 84.76,141.57 84.76,116.13 84.07,115.44 83.49,115.44 83.17,115.12 83.16,115.12 82.96,114.92 82.25,114.92 CPU1.AV12
M_A_A14: length 57.1
  TOP w0.089: CPU1.AV14 80.37,114.87 80.37,115.85 80.52,116 80.52,116.81 80.64,116.93
  TOP w0.216: DIMM1.228 87.79,160.64 87.38,160.64 86.64,159.9 86.64,158.89 85.77,158.02 85.77,157.03 84.95,156.22 84.95,155.4 84.15,154.6 83.41,154.6 83.13,154.32 83.13,152.49 82.24,151.59 81.55,151.59 81.34,151.38 81.34,150.94 81.55,150.73 81.88,150.73 82.09,150.51 82.09,150.08 81.88,149.86 81.55,149.86 81.34,149.65 81.34,149.22 81.55,149 81.88,149 82.09,148.78 82.09,148.35 81.88,148.14 81.55,148.14 81.34,147.92 81.34,147.49 81.55,147.27 81.88,147.27 82.09,147.06 82.09,146.63 81.88,146.41 81.55,146.41 81.34,146.19 81.34,145.76 81.55,145.55 81.88,145.55 82.09,145.33 82.09,144.9 81.88,144.68 81.55,144.68 81.34,144.47 81.34,144.03 81.55,143.82 81.88,143.82 82.09,143.6 82.09,143.17 81.88,142.96 81.55,142.96 81.34,142.74 81.34,142.31 81.55,142.09 81.88,142.09 82.09,141.88 82.09,141.41 81.34,140.66 81.34,117.62 80.64,116.93
M_A_A15: length 53.2
  TOP w0.216: CPU1.AY11 83.9,117.49 83.9,142.18 85.27,143.55 85.27,143.86 84.42,144.71 84.42,145.01 84.73,145.32 85.03,145.32 85.88,144.47 86.19,144.47 86.49,144.77 86.49,145.08 85.64,145.93 85.64,146.23 85.95,146.54 86.26,146.54 87.1,145.69 87.41,145.69 87.72,146 87.72,146.3 86.87,147.15 86.87,147.45 87.17,147.76 87.48,147.76 88.33,146.91 88.63,146.91 88.96,147.24 88.96,148.87 89.53,149.44 89.53,150.26 88.96,150.84 88.96,154.01 88.98,154.02 88.98,154.16 89.39,154.57 89.89,154.57 90.05,154.74 DIMM1.86
M_A_A16: length 56.4
  TOP w0.089: 82.15,117.43 81.84,117.43 81.41,116.99 81.41,115.91 CPU1.AW13
  TOP w0.216: 82.15,117.43 82.62,117.43 83.03,117.85 83.03,144.92 83.82,145.71 83.82,146.26 83.49,146.59 83.49,148.97 83.65,149.13 84.19,149.13 84.35,148.97 84.35,147.12 84.52,146.95 85.05,146.95 85.22,147.12 85.22,149.15 85.38,149.31 85.92,149.31 86.08,149.48 86.08,150.02 85.92,150.19 83.76,150.19 83.54,150.4 83.54,150.83 83.76,151.05 84.95,151.05 85.12,151.22 85.12,152.01 84.9,152.23 84.11,152.23 83.95,152.4 83.95,152.93 84.11,153.09 84.9,153.09 85.12,153.31 85.12,153.73 86.65,155.27 DIMM1.82
M_A_ACT#: length 57.7
  TOP w0.216: DIMM1.62 64.55,155.32 63.96,154.72 63.4,154.72 63.1,154.42 63.1,154.03 63.32,153.82 63.95,153.82 64.13,153.64 64.13,153.13 63.95,152.95 63.32,152.95 63.1,152.74 63.1,147.78 63.55,147.33 63.55,145.55 62.89,144.89 62.89,132.5 62.7,132.31 61.79,132.31 61.57,132.52 61.57,133.36 61.35,133.58 60.85,133.58 60.63,133.36 60.63,132.06 61.95,130.73 62.01,130.73 62.06,130.68 63.21,130.68 63.55,130.34 63.55,129.18 64.08,128.65 65.3,128.65 65.48,128.47 65.48,127.2 71.18,121.5 71.18,116.76 71.25,116.7 71.25,115.21 71.22,115.19 71.22,115.15 70.98,114.91 70.94,114.91 70.94,114.91 70.62,114.91 70.35,114.63 70.35,114.01 CPU1.AU24
M_A_ALERT#: length 53.4
  TOP w0.101: 72.67,117.45 72.67,115.69 72.39,115.41 72.39,114.78 72.09,114.48 72.09,113.84 72.07,113.83 72.07,113.3 71.95,113.17
  TOP w0.102: DIMM1.208 66.25,159.09 67.11,158.23 67.11,157.08 66.45,156.42 66.45,155.31 65.25,154.11 65.25,150.93 64.92,150.6 64.92,134.42 66.6,132.74 66.6,127.66 72.33,121.93 72.33,117.89 72.67,117.55 72.67,117.45 ; CPU1.AT23 71.72,112.95 71.95,113.17
M_A_BG0: length 56.2
  TOP w0.216: CPU1.AW23 71.72,115.65 72.16,116.09 72.16,117.17 71.59,117.74 71.59,121.62 65.86,127.36 65.86,128.63 65.45,129.03 64.24,129.03 63.93,129.34 63.93,130.85 63.72,131.06 62.22,131.06 62,131.28 62,131.71 62.22,131.93 63.72,131.93 63.93,132.14 63.93,132.57 63.72,132.79 63.49,132.79 63.27,133.01 63.27,133.44 63.49,133.65 63.72,133.65 63.93,133.87 63.93,134.25 63.75,134.43 63.49,134.43 63.27,134.64 63.27,135.08 63.49,135.29 64,135.29 64.18,135.48 64.18,138.47 64,138.65 63.46,138.65 63.27,138.85 63.27,139.33 63.46,139.52 64,139.52 64.18,139.7 64.18,140.2 64,140.38 63.46,140.38 63.27,140.57 63.27,141.06 63.46,141.25 64,141.25 64.18,141.43 64.18,141.93 64,142.11 63.46,142.11 63.27,142.3 63.27,142.78 63.46,142.97 64,142.97 64.18,143.16 64.18,143.65 64,143.84 63.49,143.84 63.27,144.05 63.27,144.48 63.49,144.7 64,144.7 64.18,144.88 64.18,147.77 63.98,147.97 63.98,148.65 63.93,148.7 63.93,151.12 64.51,151.7 64.51,154.42 64.55,154.46 64.55,154.47 65.4,155.33 DIMM1.63
M_A_BG1: length 57.3
  TOP w0.089: CPU1.AV23 71.72,114.68 72.14,115.09 72.14,115.67 72.44,115.97 72.44,117.33 71.97,117.79 71.97,118.48
  TOP w0.216: DIMM1.207 65.33,159.53 65.33,156.89 66.12,156.1 66.12,155.49 64.89,154.26 64.89,151.54 64.31,150.96 64.31,150.18 64.56,149.93 64.56,149.78 64.56,134.27 64.6,134.23 64.6,133.11 64.81,132.89 65.93,132.89 66.24,132.59 66.24,132.18 66.06,132.01 64.53,132.01 64.31,131.79 64.31,131.36 64.53,131.14 66.06,131.14 66.24,130.96 66.24,130.46 66.06,130.28 64.53,130.28 64.31,130.06 64.31,129.63 64.53,129.42 66.06,129.42 66.24,129.24 66.24,127.51 71.97,121.78 71.97,118.48
M_A_BS0: length 54.9
  TOP w0.089: CPU1.AY13 81.19,116.61 81.19,117.08 82.08,117.97
  TOP w0.216: 82.08,117.97 82.58,118.47 82.58,119.69 82.36,119.91 81.93,119.91 81.72,120.12 81.72,120.55 81.93,120.77 82.36,120.77 82.58,120.99 82.58,121.42 82.36,121.63 81.93,121.63 81.72,121.85 81.72,122.28 81.93,122.5 82.36,122.5 82.58,122.71 82.58,123.14 82.36,123.36 81.93,123.36 81.72,123.58 81.72,124.01 81.93,124.22 82.36,124.22 82.58,124.44 82.58,124.87 82.36,125.09 81.93,125.09 81.72,125.3 81.72,125.74 81.93,125.95 82.36,125.95 82.58,126.17 82.58,126.6 82.36,126.81 81.93,126.81 81.72,127.03 81.72,127.46 81.93,127.68 82.36,127.68 82.58,127.89 82.58,128.33 82.36,128.54 81.93,128.54 81.72,128.76 81.72,129.19 81.93,129.41 82.36,129.41 82.58,129.62 82.58,130.05 82.36,130.27 81.93,130.27 81.72,130.48 81.72,130.92 81.93,131.13 82.36,131.13 82.58,131.35 82.58,131.78 82.36,132 81.93,132 81.72,132.21 81.72,132.64 81.93,132.86 82.36,132.86 82.58,133.08 82.58,133.51 82.36,133.72 81.93,133.72 81.72,133.94 81.72,134.37 81.93,134.59 82.36,134.59 82.58,134.8 82.58,135.23 82.36,135.45 81.93,135.45 81.72,135.67 81.72,138.6 81.93,138.81 82.36,138.81 82.58,139.03 82.58,139.46 82.36,139.68 81.93,139.68 81.72,139.89 81.72,140.33 81.93,140.54 82.36,140.54 82.58,140.76 82.58,150.96 83.53,151.92 83.53,153.04 83.57,153.07 83.57,153.09 83.95,153.48 83.97,153.48 85.8,155.31 DIMM1.81
M_A_BS1: length 58.5
  TOP w0.216: DIMM1.224 84.95,162.02 84.73,162.24 80,162.24 79.78,162.02 79.78,152.36 79.53,152.11 79.53,150.54 79.78,150.29 79.78,139.67 79.57,139.46 78.65,139.46 78.44,139.24 78.44,138.81 78.65,138.59 79.57,138.59 79.78,138.38 79.78,135.45 79.57,135.23 78.65,135.23 78.44,135.01 78.44,125.9 79.81,124.52 79.81,118.22 78.61,117.02 78.61,115.07 79.04,114.65 CPU1.AV15
M_A_CKE0: length 49.2
  TOP w0.165: DIMM1.60 62.36,156.91 62.13,156.91 61.09,155.87 61.09,153 60.2,152.11 60.2,151.7 60.36,151.53 60.64,151.53 60.81,151.37 60.81,151.04 60.64,150.87 60.36,150.87 60.2,150.71 60.2,150.38 60.36,150.21 60.64,150.21 60.81,150.05 60.81,149.72 60.64,149.55 60.36,149.55 60.2,149.39 60.2,149.06 60.36,148.89 60.64,148.89 60.81,148.73 60.81,148.4 60.64,148.23 60.36,148.23 60.2,148.07 60.2,131.88 65.05,127.03 65.05,127.02 70.81,121.25 CPU1.AY24
M_A_CKE1: length 50.1
  TOP w0.165: CPU1.AW24 70.4,115.78 70.4,121.09 64.64,126.85 64.64,126.86 59.41,132.09 59.41,156.17 60.3,157.06 60.3,158.05 61.85,159.6 DIMM1.203
M_A_CLK0: length 50
  TOP w0.089: CPU1.AW18 76.3,115.63 76.37,115.7 76.52,115.7 76.55,115.72 76.83,116.01 76.84,116.01 76.84,117.51 76.97,117.65 76.97,117.74 77.09,117.86
  TOP w0.165: 76.64,155.17 76.61,155.2 76.61,156.3 76.15,156.76 75.62,156.76 75.51,156.65 75.25,156.65 75,156.89 DIMM1.74
  TOP w0.216: 76.64,155.17 76.64,154.79 76.81,154.62 77.62,154.62 77.99,154.25 77.99,153.42 77.62,153.06 76.01,153.06 75.79,152.84 75.79,152.41 76.01,152.19 77.32,152.19 77.74,151.78 77.74,149.8 77.99,149.55 77.99,141.35 76.64,140 76.64,125.16 78.02,123.78 78.02,118.96 77.55,118.48 77.55,118.31 77.09,117.86
M_A_CLK1: length 51.2
  TOP w0.089: CPU1.AW17 77.78,115.94 77.78,116.71 77.66,116.83 77.66,117.19 77.7,117.23 77.7,117.25 77.95,117.5 77.97,117.5 78.4,117.94 78.51,117.94
  TOP w0.165: DIMM1.218 75.16,160.79 75.86,160.79 76.61,160.04 76.61,159.04 76.64,159
  TOP w0.216: 78.51,117.94 79.09,118.52 79.09,124.22 77.71,125.6 77.71,139.54 79.06,140.89 79.06,149.99 78.8,150.24 78.8,152.41 79.06,152.66 79.06,157.83 78.28,158.61 76.84,158.61 76.64,158.81 76.64,159
M_A_CLK#0: length 49.9
  TOP w0.089: 76.3,155.17 76.3,155.18 76.32,155.2 76.34,155.2 76.34,155.2 ; CPU1.AV18 76.3,114.83 75.95,115.18 75.95,115.57 76.27,115.89 76.44,115.89 76.47,115.91 76.65,116.09 76.65,117.59 76.76,117.7 76.76,118.01 76.85,118.1
  TOP w0.165: 76.34,155.2 76.34,156.19 76.04,156.49 75.73,156.49 75.6,156.36 DIMM1.75
  TOP w0.216: 76.85,118.1 77.2,118.45 77.2,118.62 77.68,119.1 77.68,123.64 76.3,125.02 76.3,140.15 77.65,141.49 77.65,149.41 77.39,149.66 77.39,151.63 77.18,151.85 75.87,151.85 75.45,152.27 75.45,152.98 75.87,153.4 77.48,153.4 77.65,153.56 77.65,154.11 77.48,154.28 76.67,154.28 76.3,154.64 76.3,155.17
M_A_CLK#1: length 51.2
  TOP w0.089: 78.27,118.18 78.27,118.07 77.89,117.69 77.87,117.69 77.51,117.33 77.51,117.31 77.47,117.27 77.47,116.9 77.47,116.75 77.59,116.63 77.59,116.02 77.34,115.77 77.19,115.77 77.05,115.91 77.05,116.13 CPU1.AY17
  TOP w0.165: DIMM1.219 75.18,160.02 75.18,160.36 75.35,160.53 75.75,160.53 76.34,159.93 76.34,158.96 76.3,158.92 76.3,158.9
  TOP w0.216: 78.27,118.18 78.75,118.66 78.75,124.08 77.37,125.46 77.37,139.68 78.71,141.03 78.71,149.85 78.46,150.1 78.46,152.55 78.71,152.8 78.71,157.69 78.13,158.27 76.7,158.27 76.3,158.67 76.3,158.9
M_A_CS#0: length 49.5
  TOP w0.165: CPU1.AW12 82.3,115.9 82.3,116.5 82.43,116.62 82.43,116.63 83.46,117.67 83.46,142.87 83.91,143.32 84.43,143.32 84.61,143.5 84.61,143.84 84.44,144 83.91,144 83.74,144.17 83.74,144.97 86.31,147.54 86.31,147.77 85.91,148.17 85.91,148.4 86.14,148.64 86.38,148.64 86.81,148.21 87.75,148.21 88.37,148.83 88.37,153.28 88.14,153.52 87.5,153.52 87.4,153.62 87.4,153.92 87.57,154.09 88.18,154.09 88.35,154.25 DIMM1.84
M_A_CS#1: length 51.5
  TOP w0.165: CPU1.AU11 82.93,113.54 85.19,115.81 85.19,141.08 92.74,148.63 92.74,149.91 92.57,150.07 91.81,150.07 91.64,150.24 91.64,150.57 91.81,150.73 92.57,150.73 92.74,150.9 92.74,151.23 92.57,151.39 91.81,151.39 91.64,151.56 91.64,151.89 91.81,152.05 92.57,152.05 92.74,152.22 92.74,152.62 92.55,152.81 91.76,152.81 91.53,153.03 91.53,153.67 92.6,154.74 DIMM1.89
M_A_DQ0: length 90.6
  TOP w0.089: CPU1.AE40 54.85,102.57 54.48,102.21
  TOP w0.165: DIMM1.5 16.1,151.63 21.72,144.12 21.72,132.81 21.88,132.65 22.21,132.65 22.38,132.81 22.38,137.9 22.5,138.02 22.91,138.02 23.04,137.9 23.04,122.01 44.91,100.14 52.16,100.14 54.1,102.08 54.36,102.08 54.48,102.21
M_A_DQ1: length 94.1
  TOP w0.089: CPU1.AE37 58.41,103.09 57.43,103.09 57.38,103.14 56.76,103.14 56.55,102.92 56.38,102.92 56.38,102.92 55.98,102.92 55.97,102.92 55.87,102.81 54.73,102.81 54.53,102.62
  TOP w0.165: 54.53,102.62 54.43,102.51 54.01,102.51 52.27,100.77 45.17,100.77 23.67,122.28 23.67,141.2 23.63,141.29 23.47,141.45 23.19,141.45 23.01,141.27 23.01,138.79 22.89,138.66 22.48,138.66 22.35,138.78 22.35,144.33 16.97,151.53 16.97,156.12 16.09,157 16.09,158.32 15.41,159 15.41,160.02 15.82,160.44 16.19,160.44 DIMM1.150
M_A_DQ2: length 92.3
  TOP w0.089: 54.51,104.52 54.65,104.66 55.77,104.66 55.86,104.75 56.38,104.75 56.43,104.7 56.85,104.7 56.9,104.75 57.29,104.75 57.34,104.7 57.71,104.7 CPU1.AG38
  TOP w0.165: DIMM1.12 22.05,156.77 22.23,156.58 22.23,155.07 26.48,150.82 26.48,130.5 28.02,128.96 28.02,125.07 28.14,124.94 28.57,124.94 28.68,125.04 28.68,127.74 28.8,127.86 29.12,127.86 29.34,127.64 29.34,120.65 29.54,120.45 29.81,120.45 30,120.64 30,125.17 30.12,125.3 30.53,125.3 30.66,125.17 30.66,119.33 46.09,103.9 52.67,103.9 53.21,104.44 54.43,104.44 54.51,104.52
M_A_DQ3: length 93.3
  TOP w0.089: CPU1.AG37 58.41,104.92 57.43,104.92 57.38,104.97 56.81,104.97 56.76,104.92 56.52,104.92 56.46,104.97 55.77,104.97 55.7,104.89 54.43,104.89
  TOP w0.165: 54.43,104.89 53.2,104.89 52.84,104.53 46.35,104.53 33.93,116.95 33.93,118.82 33.81,118.95 33.4,118.95 33.27,118.82 33.27,118.24 33.11,118.08 32.81,118.08 32.61,118.27 32.61,124.82 32.49,124.94 32.08,124.94 31.95,124.82 31.95,119.53 31.83,119.41 31.48,119.41 31.29,119.59 31.29,126.58 31.13,126.75 30.8,126.75 30.63,126.58 30.63,126.17 30.52,126.06 30.09,126.06 29.97,126.17 29.97,127.91 27.11,130.76 27.11,151.09 23.57,154.64 23.57,156.43 22.9,157.1 DIMM1.157
M_A_DQ4: length 91.8
  TOP w0.089: 54.93,101.71 55.3,102.08 55.82,102.08 55.89,102.01 56.46,102.01 56.52,102.06 56.87,102.06 57.09,102.28 CPU1.AE39
  TOP w0.165: DIMM1.3 14.4,151.77 20.45,143.69 20.45,125.65 20.57,125.53 20.98,125.53 21.11,125.65 21.11,129.41 21.23,129.54 21.64,129.54 21.77,129.41 21.77,121.49 44.38,98.87 52.09,98.87 54.93,101.71
M_A_DQ5: length 93.1
  TOP w0.089: 54.58,101.85 54.95,102.22 55.11,102.22 55.19,102.3 55.91,102.3 55.98,102.22 56.38,102.22 56.69,102.54 56.69,102.72 56.9,102.92 57.29,102.92 57.4,102.81 57.48,102.77 CPU1.AE38
  TOP w0.165: DIMM1.148 15.25,160.34 15.11,160.2 15.11,159.03 14.4,158.32 14.4,157.04 15.24,156.2 15.24,151.72 21.08,143.91 21.08,130.38 21.26,130.2 21.56,130.2 21.74,130.38 21.74,131.85 21.89,132 22.25,132 22.4,131.85 22.4,121.75 44.65,99.5 52.23,99.5 54.58,101.85
M_A_DQ6: length 91
  TOP w0.089: 54.88,103.95 54.92,103.99 54.92,103.99 55.06,104.13 55.79,104.13 55.86,104.05 56.38,104.05 56.72,104.4 CPU1.AG39
  TOP w0.165: DIMM1.10 20.35,155.15 21.98,153.52 21.98,153.31 21.35,152.67 21.35,152.49 21.63,152.2 21.81,152.2 22.43,152.82 22.68,152.82 22.92,152.58 22.92,152.37 22.12,151.57 22.12,151.39 22.4,151.1 22.58,151.1 23.36,151.88 23.62,151.88 23.85,151.65 23.85,151.44 23.14,150.73 23.14,150.55 23.43,150.26 23.61,150.26 24.33,150.99 24.51,150.99 25.21,150.29 25.21,149.95 25.02,149.76 24.26,149.76 24.08,149.58 24.08,149.27 24.26,149.1 25.02,149.1 25.21,148.9 25.21,148.63 25.02,148.44 24.3,148.44 24.1,148.24 24.1,147.97 24.3,147.78 25.02,147.78 25.21,147.58 25.21,147.2 25.08,147.07 24.44,147.07 24.28,146.91 24.28,146.54 24.41,146.41 25.06,146.41 25.21,146.27 25.21,145.88 25.08,145.75 24.36,145.75 24.23,145.62 24.23,145.22 24.36,145.09 25.02,145.09 25.21,144.9 25.21,125.77 26.75,124.23 26.75,121.44 45.56,102.63 52.81,102.63 53.91,103.73 54.66,103.73 54.88,103.95
M_A_DQ7: length 90
  TOP w0.089: 54.76,104.24 54.93,104.42 56.16,104.42 CPU1.AG40
  TOP w0.165: 54.76,104.24 54.55,104.04 53.69,104.04 52.91,103.26 45.82,103.26 28.7,120.38 28.7,124.18 28.57,124.31 28.17,124.31 28.04,124.18 28.04,121.7 27.88,121.53 27.56,121.53 27.38,121.71 27.38,128.7 27.2,128.88 26.85,128.88 26.72,128.75 26.72,125.98 26.52,125.78 26.1,125.78 25.84,126.03 25.84,150.56 21.87,154.54 21.87,156.31 21.2,156.98 DIMM1.155
M_A_DQ8: length 80.5
  TOP w0.165: DIMM1.16 25.45,156.36 25.63,156.18 25.63,155.36 29.02,151.97 29.02,131.64 35.93,124.73 35.93,122.03 36.09,121.87 36.42,121.87 36.59,122.03 36.59,123.43 36.75,123.6 37.06,123.6 37.25,123.41 37.25,116.57 37.41,116.41 37.74,116.41 37.91,116.57 37.91,119.88 38.07,120.04 38.4,120.04 38.57,119.88 38.57,115.24 47.37,106.44 51.88,106.44 52.14,106.17 55.11,106.17 55.17,106.23 CPU1.AJ40
M_A_DQ9: length 83.7
  TOP w0.089: CPU1.AJ37 58.41,106.74 57.8,106.74 57.75,106.79 56.68,106.79 56.47,106.58 55.98,106.58 55.91,106.5 55.05,106.5 55.04,106.5
  TOP w0.165: DIMM1.161 26.3,156.79 27.13,155.96 27.13,154.75 27.31,154.57 27.79,154.57 28.08,154.28 28.08,153.8 29.65,152.23 29.65,131.9 37.88,123.67 37.88,120.97 38.05,120.8 38.38,120.8 38.54,120.97 38.54,122.31 38.71,122.48 39.04,122.48 39.2,122.31 39.2,115.65 39.37,115.48 39.7,115.48 39.87,115.65 39.87,116.93 40.03,117.09 40.36,117.09 40.59,116.87 40.59,115.79 40.75,115.62 41.58,115.62 41.74,115.46 41.74,115.07 41.58,114.91 40.53,114.91 40.36,114.74 40.36,114.41 40.53,114.25 41.58,114.25 41.74,114.08 41.74,112.96 47.63,107.07 51.96,107.07 52.53,106.5 55.04,106.5
M_A_DQ10: length 81.8
  TOP w0.089: 53.73,108.47 53.87,108.33 55.91,108.33 55.98,108.41 57.29,108.41 57.34,108.36 57.35,108.36 CPU1.AL38
  TOP w0.165: DIMM1.23 31.4,154.9 33.27,153.02 33.27,151.64 40.55,144.37 40.55,144.08 40.26,143.79 39.61,143.79 39.44,143.96 39.44,144.24 39.28,144.41 38.95,144.41 38.78,144.24 38.78,143.96 38.62,143.79 38.28,143.79 38.12,143.96 38.12,145.13 37.95,145.3 37.62,145.3 37.46,145.13 37.46,143.96 37.29,143.79 36.96,143.79 36.8,143.96 36.8,145.34 36.63,145.5 36.3,145.5 36.14,145.34 36.14,144.03 32.46,140.36 32.46,133.09 35.88,129.67 41.05,129.67 42.01,128.7 42.01,119.47 44.55,116.93 44.55,114.13 48.36,110.32 51.88,110.32 53.73,108.47
M_A_DQ11: length 82.7
  TOP w0.089: CPU1.AL37 57.85,108.57 57.8,108.62 55.89,108.62 55.82,108.55 54.39,108.55 54.23,108.71
  TOP w0.165: DIMM1.168 32.25,159.14 31.45,158.34 31.45,156.98 32.24,156.18 32.24,154.95 33.91,153.28 33.91,151.9 41.71,144.11 41.71,143.42 41.44,143.16 36.16,143.16 33.1,140.09 33.1,133.35 36.14,130.3 41.76,130.3 42.65,129.41 42.65,119.74 45.19,117.2 45.19,114.39 48.62,110.96 51.98,110.96 54.23,108.71
M_A_DQ12: length 81.6
  TOP w0.089: CPU1.AJ39 56.58,105.71 56.52,105.71 56.46,105.66 55.77,105.66 55.7,105.74 55.34,105.74 54.93,105.33 54.75,105.33
  TOP w0.165: DIMM1.14 23.75,156.66 23.93,156.49 23.93,155.18 27.75,151.36 27.75,131.03 33.25,125.53 33.25,120.31 33.41,120.14 33.74,120.14 33.91,120.31 33.91,124.23 34.06,124.38 34.42,124.38 34.57,124.23 34.57,117.21 46.61,105.17 53.1,105.17 53.26,105.33 54.75,105.33
M_A_DQ13: length 82.8
  TOP w0.089: 54.62,105.8 55.1,105.8 55.25,105.96 55.79,105.96 55.86,105.88 56.38,105.88 56.69,106.2 56.69,106.37 56.9,106.58 57.66,106.58 CPU1.AJ38
  TOP w0.165: DIMM1.159 24.6,156.8 25.27,156.12 25.27,155.49 25.13,155.35 25.13,154.91 28.38,151.66 28.38,131.37 35.29,124.47 35.29,117.62 35.49,117.42 35.79,117.42 35.95,117.59 35.95,121.07 36.12,121.23 36.45,121.23 36.61,121.07 36.61,116.3 47.11,105.8 54.62,105.8
M_A_DQ14: length 80.3
  TOP w0.089: 55.09,107.79 55.79,107.79 55.86,107.71 56.38,107.71 56.58,107.91 56.58,107.93 56.71,108.06 CPU1.AL39
  TOP w0.165: 55.09,107.79 53.25,107.79 51.98,109.05 50.46,109.05 47.83,109.05 43.28,113.6 43.28,116.35 40.74,118.89 40.74,122.99 31.19,132.54 31.19,143.52 31.46,143.79 33.21,143.79 33.38,143.96 33.38,144.29 33.21,144.45 31.36,144.45 31.19,144.62 31.19,144.95 31.36,145.11 33.19,145.11 33.35,145.28 33.35,145.61 33.19,145.77 31.36,145.77 31.19,145.94 31.19,146.27 31.36,146.43 33.26,146.43 33.43,146.6 33.43,146.93 33.26,147.09 31.36,147.09 31.19,147.26 31.19,147.59 31.36,147.75 33.26,147.75 33.43,147.92 33.43,148.25 33.26,148.41 31.36,148.41 31.19,148.58 31.19,153.27 29.7,154.77 DIMM1.21
M_A_DQ15: length 79.2
  TOP w0.089: 53.37,108.31 53.37,108.31 53.62,108.06 CPU1.AL40
  TOP w0.165: DIMM1.166 30.55,158.99 29.86,158.3 29.86,156.89 30.58,156.17 30.58,154.8 32.64,152.74 32.64,151.38 34.05,149.97 34.05,148.87 34.21,148.7 35.29,148.7 35.46,148.54 35.46,148.13 35.29,147.96 34.23,147.96 34.06,147.8 34.06,147.47 34.23,147.3 35.29,147.3 35.46,147.13 35.46,146.8 35.29,146.64 34.23,146.64 34.06,146.47 34.06,146.14 34.23,145.98 35.29,145.98 35.46,145.81 35.46,144.25 31.83,140.62 31.83,132.82 32.2,132.45 35.62,129.03 40.06,129.03 41.38,127.71 41.38,119.15 43.92,116.61 43.92,113.87 48.09,109.69 51.98,109.69 53.37,108.31
M_A_DQ16: length 70
  TOP w0.165: DIMM1.27 34.8,155.28 35.94,154.14 35.94,152.73 44.88,143.79 44.88,126.37 46.23,125.01 46.23,121.73 46.4,121.56 46.82,121.56 46.99,121.73 46.99,123.61 47.15,123.77 47.48,123.77 47.65,123.61 47.65,121.62 47.81,121.46 48.14,121.46 48.31,121.62 48.31,122.5 48.47,122.67 48.8,122.67 48.97,122.5 48.97,121.19 49.15,121.01 49.57,121.01 50.51,121.95 50.75,121.95 50.98,121.72 50.98,121.48 50.13,120.64 50.13,120.4 50.37,120.17 50.6,120.17 51.42,120.99 51.65,120.99 51.89,120.76 51.89,120.52 51.42,120.06 51.42,119.82 51.66,119.59 51.89,119.59 52.25,119.95 52.49,119.95 52.72,119.72 52.72,119.49 52.36,119.12 52.36,118.89 53.05,118.2 53.05,111.37 54.55,109.87 56.16,109.87 CPU1.AN40
M_A_DQ17: length 72.7
  TOP w0.089: CPU1.AN37 58.41,110.4 57.43,110.4 57.38,110.45 56.76,110.45 56.54,110.24 55.98,110.24 55.87,110.12 54.71,110.12 54.56,110.26
  TOP w0.165: DIMM1.172 35.42,161.2 34.11,159.89 34.11,158.93 34.8,158.24 34.8,157.09 35.66,156.22 35.66,155.41 36.58,154.49 36.58,152.99 45.52,144.05 45.52,128.09 46.25,127.36 46.25,127.13 45.75,126.63 45.75,126.39 45.98,126.16 46.22,126.16 46.72,126.66 46.95,126.66 47.18,126.43 47.18,126.19 46.69,125.69 46.69,125.46 46.92,125.23 47.15,125.23 47.65,125.72 47.88,125.72 48.12,125.49 48.12,125.26 47.62,124.76 47.62,124.53 47.85,124.29 48.09,124.29 48.58,124.79 48.82,124.79 49.05,124.56 49.05,124.32 48.55,123.83 48.55,123.59 48.79,123.36 49.02,123.36 49.52,123.86 49.75,123.86 49.99,123.62 49.99,123.39 49.72,123.13 49.72,122.89 49.96,122.66 50.19,122.66 50.45,122.92 50.69,122.92 53.34,120.27 53.34,111.49 54.56,110.26
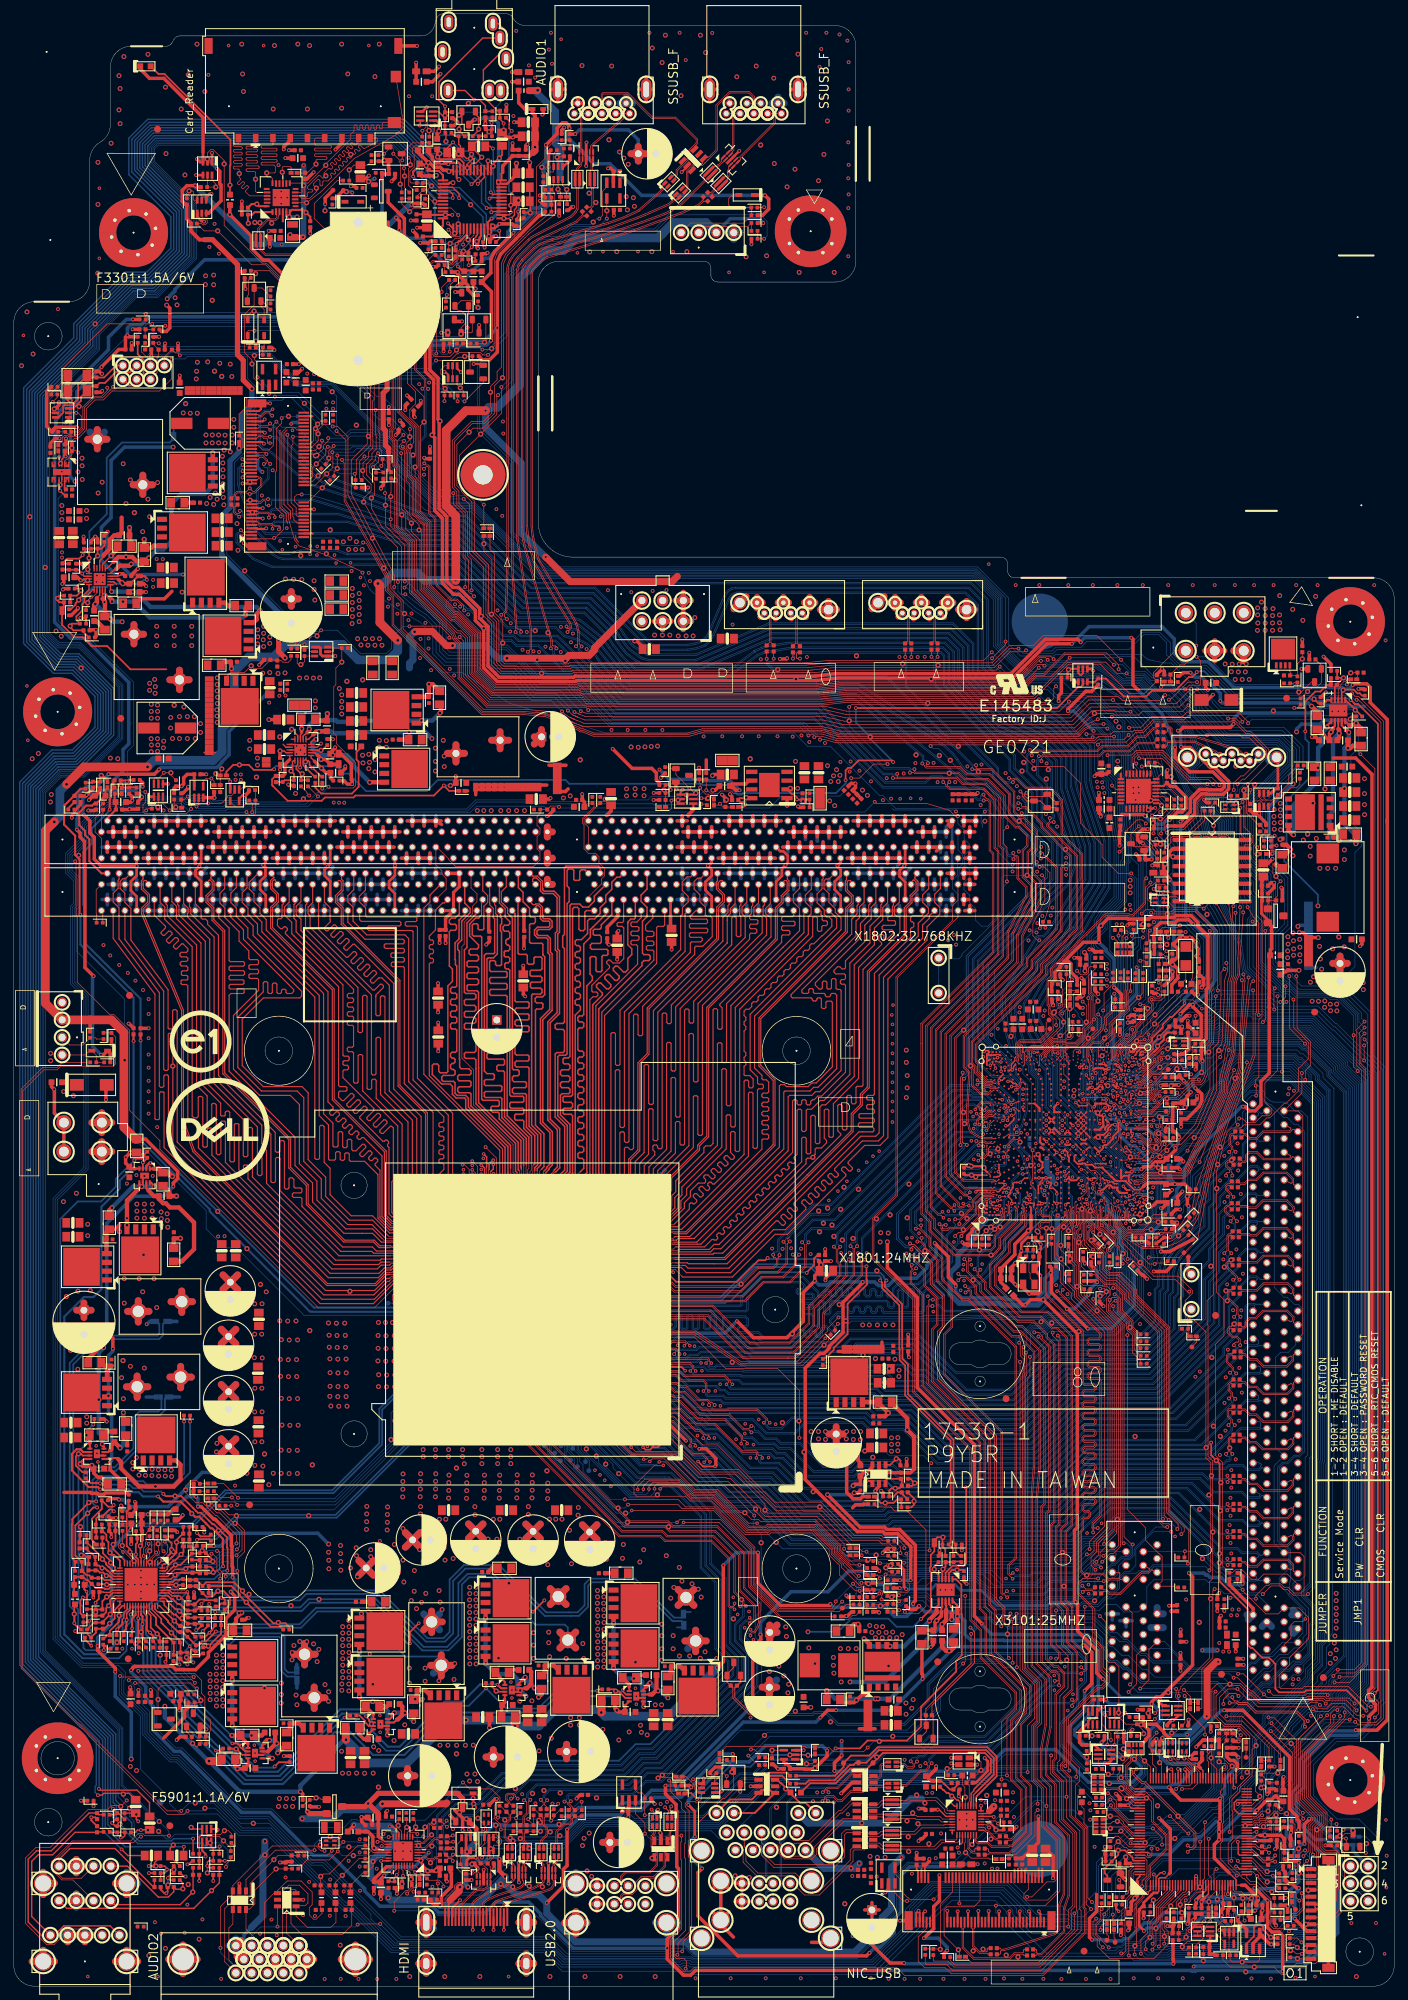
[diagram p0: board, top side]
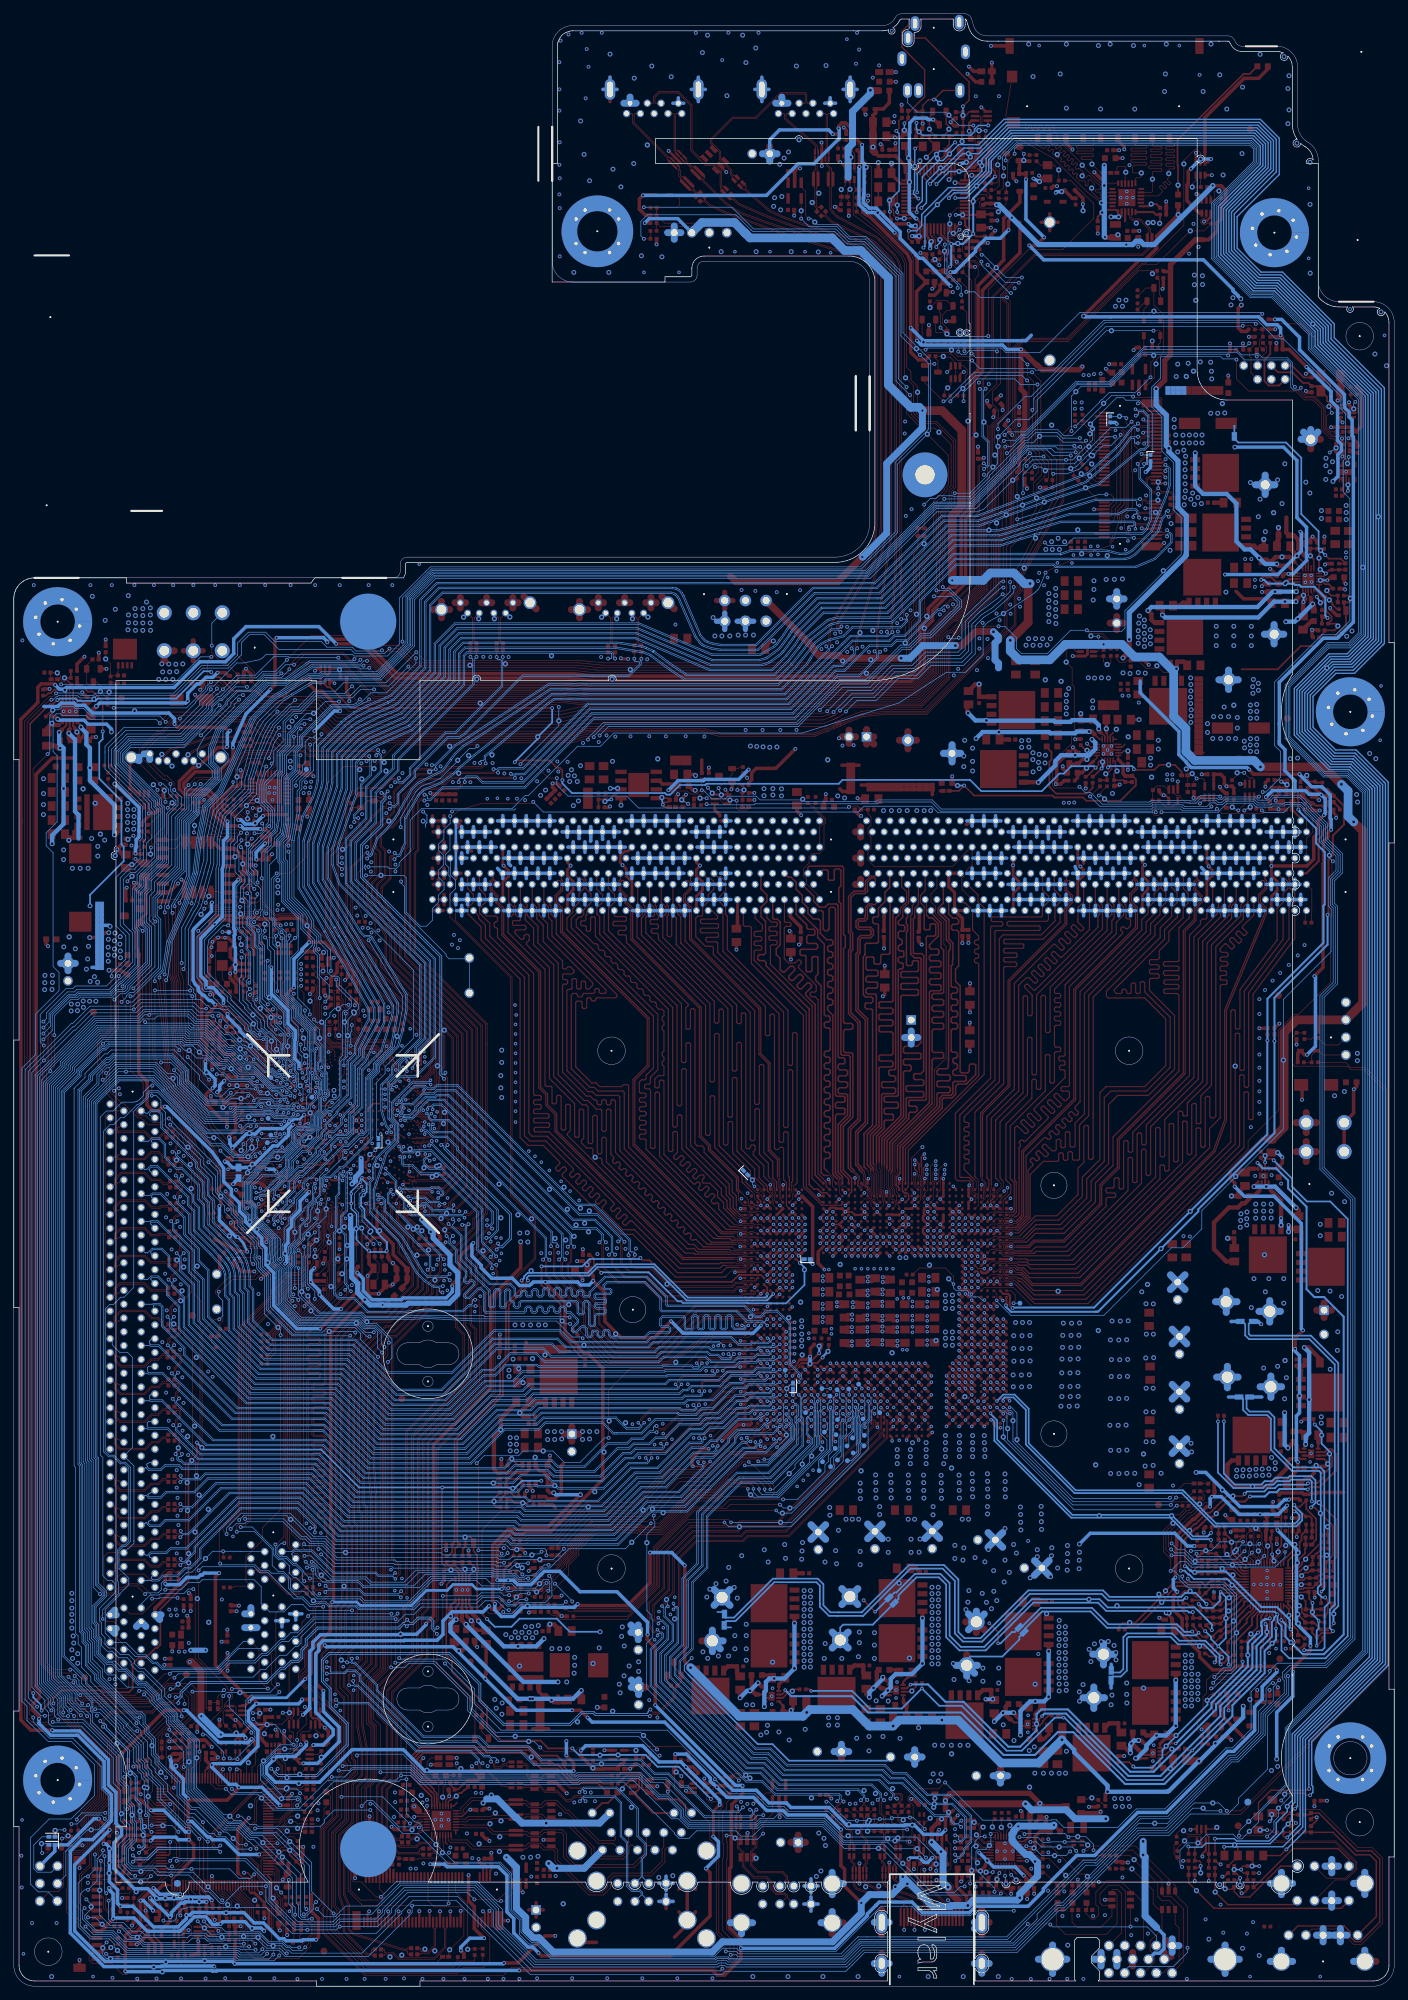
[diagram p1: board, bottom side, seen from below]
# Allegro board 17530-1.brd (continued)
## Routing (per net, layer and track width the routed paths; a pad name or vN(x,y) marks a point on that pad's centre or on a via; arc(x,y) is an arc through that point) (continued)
M_A_DQ18: length 70.6
  TOP w0.089: CPU1.AR38 57.66,112.07 56.67,112.07 56.62,112.12 56.32,112.12
  TOP w0.165: DIMM1.34 40.75,156.83 40.59,156.67 40.59,154.67 40.9,154.36 40.9,152.72 49.23,144.4 49.23,143.97 49.06,143.8 48.49,143.8 48.32,143.64 48.32,143.31 48.49,143.14 49.06,143.14 49.23,142.98 49.23,142.65 49.06,142.48 48.49,142.48 48.32,142.32 48.32,141.99 48.49,141.82 49.06,141.82 49.23,141.66 49.23,141.33 49.06,141.16 48.49,141.16 48.32,141 48.32,140.66 48.49,140.5 49.06,140.5 49.23,140.33 49.23,140 49.06,139.84 48.49,139.84 48.32,139.67 48.32,139.34 48.49,139.18 49.06,139.18 49.23,139.01 49.23,136.18 49.06,136.02 48.49,136.02 48.32,135.85 48.32,135.52 48.49,135.36 49.06,135.36 49.23,135.19 49.23,130.98 49.39,130.81 49.72,130.81 49.89,130.98 49.89,134.79 50.05,134.95 50.38,134.95 50.55,134.79 50.55,129.68 55.63,124.6 55.63,116.97 55.06,116.4 55.06,112.28 55.22,112.12 56.32,112.12
M_A_DQ19: length 71.6
  TOP w0.089: CPU1.AR37 58.52,112.12 57.91,112.12 57.75,112.28 56.86,112.28 56.67,112.47 56.67,113.77 56.49,113.94
  TOP w0.165: DIMM1.179 41.6,157.1 40.92,156.42 40.92,155.24 41.6,154.56 41.6,152.92 49.86,144.66 49.86,138.3 50.03,138.14 50.36,138.14 50.52,138.3 50.52,143.35 50.69,143.52 51,143.52 51.18,143.34 51.18,130.06 51.35,129.9 51.68,129.9 51.84,130.06 51.84,131.2 52.01,131.37 52.34,131.37 52.5,131.2 52.5,128.63 56.26,124.87 56.26,116.79 55.55,116.08 55.55,114.88 56.49,113.94
M_A_DQ20: length 70.7
  TOP w0.089: CPU1.AN39 57.09,109.73 56.69,109.32 55.77,109.32 55.7,109.4 55.34,109.4 55.06,109.12 54.89,109.12
  TOP w0.165: 54.89,109.12 54.43,109.12 51.96,111.59 48.88,111.59 45.82,114.66 45.82,118.48 44.96,119.34 44.96,124.49 44.76,124.69 44.46,124.69 44.3,124.52 44.3,119.93 44.13,119.76 43.78,119.76 43.61,119.93 43.61,125.84 43.61,143.26 34.67,152.2 34.67,153.58 33.1,155.15 DIMM1.25
M_A_DQ21: length 71.9
  TOP w0.089: CPU1.AN38 57.62,109.89 57.49,110.01 57.49,110.03 57.29,110.24 56.9,110.24 56.69,110.03 56.69,109.78 56.45,109.54 55.86,109.54 55.79,109.61 54.9,109.61 54.81,109.52
  TOP w0.165: DIMM1.170 33.79,161.04 33.79,159.1 33.1,158.4 33.1,156.98 33.93,156.14 33.93,155.23 35.31,153.86 35.31,152.46 44.25,143.52 44.25,126.1 45.6,124.75 45.6,119.78 45.72,119.66 46.46,119.66 46.62,119.82 46.62,120.71 46.79,120.88 47.12,120.88 47.28,120.71 47.28,119.8 47.45,119.63 47.78,119.63 47.94,119.8 47.94,120.54 48.11,120.7 48.44,120.7 48.6,120.54 48.6,119.65 48.77,119.48 50.83,119.48 52.76,117.55 52.76,111.25 54.48,109.52 54.81,109.52
M_A_DQ22: length 69.2
  TOP w0.089: CPU1.AR39 56.72,111.72 56.38,111.37 55.86,111.37 55.79,111.44 54.97,111.44
  TOP w0.165: DIMM1.32 39.05,156.77 38.87,156.59 38.87,154.79 38.7,154.62 38.37,154.62 38.2,154.46 38.2,153.63 38.65,153.18 38.88,153.18 39.16,153.45 39.39,153.45 39.63,153.22 39.63,152.99 39.35,152.71 39.35,152.48 39.63,152.19 39.63,152.19 40.38,151.45 47.05,144.77 47.05,130.47 47.22,130.31 48.09,130.31 48.26,130.14 48.26,129.81 48.09,129.65 47.22,129.65 47.05,129.48 47.05,128.79 47.56,128.29 47.79,128.29 48.82,129.31 49.05,129.31 49.28,129.08 49.28,128.84 48.26,127.82 48.26,127.58 48.49,127.35 48.73,127.35 49.76,128.39 50,128.39 50.23,128.15 50.23,127.92 49.19,126.88 49.19,126.65 49.43,126.42 49.66,126.42 50.7,127.45 50.93,127.45 51.16,127.22 51.16,126.99 50.13,125.95 50.13,125.72 53.45,122.4 53.68,122.4 53.84,122.56 54.08,122.56 54.31,122.32 54.31,122.09 54.15,121.93 54.15,121.7 54.36,121.49 54.36,111.86 54.77,111.44 54.97,111.44
M_A_DQ23: length 68.2
  TOP w0.165: DIMM1.177 39.9,157.02 39.22,156.33 39.22,155.15 40.27,154.09 40.27,152.46 40.64,152.08 47.69,145.04 47.69,134.88 47.85,134.71 48.43,134.71 48.59,134.55 48.59,134.22 48.43,134.05 47.85,134.05 47.69,133.88 47.69,133.55 47.85,133.39 48.32,133.39 48.49,133.22 48.49,132.89 48.32,132.73 47.85,132.73 47.69,132.56 47.69,131.61 52.17,127.13 52.17,126.86 51.16,125.85 51.16,125.62 51.4,125.39 51.63,125.39 52.67,126.42 52.9,126.42 53.13,126.19 53.13,125.96 52.1,124.92 52.1,124.69 52.33,124.45 52.57,124.45 53.6,125.49 53.84,125.49 54.07,125.26 54.07,125.02 53.03,123.99 53.03,123.75 53.27,123.52 53.5,123.52 54.54,124.56 54.74,124.56 54.99,124.31 54.99,116.75 54.76,116.52 54.76,112.06 55.11,111.72 CPU1.AR40
M_A_DQ24: length 61.6
  TOP w0.089: CPU1.AV37 58.5,114.88 58.5,115.49 58.38,115.6 58.38,116.03
  TOP w0.165: 58.38,116.03 58.38,125.71 54.41,129.68 54.41,144.98 53.33,146.06 52.88,146.06 52.13,145.32 51.9,145.32 51.67,145.55 51.67,145.78 52.54,146.65 52.54,146.85 52.27,147.12 52.07,147.12 51.2,146.25 50.97,146.25 50.73,146.48 50.73,146.72 51.58,147.56 51.58,147.8 51.35,148.03 51.11,148.03 50.27,147.18 50.03,147.18 49.8,147.42 49.8,147.65 50.67,148.52 50.67,148.72 50.4,148.99 50.2,148.99 49.33,148.12 49.1,148.12 48.87,148.35 48.87,148.59 49.67,149.39 49.67,149.62 49.43,149.85 49.2,149.85 48.4,149.05 48.16,149.05 44.15,153.07 DIMM1.38
M_A_DQ25: length 60.6
  TOP w0.165: DIMM1.183 45,157.04 45.82,156.22 45.82,154.47 45.87,154.42 45.87,154.19 45.02,153.35 45.02,153.11 45.25,152.88 45.49,152.88 46.33,153.72 46.57,153.72 46.8,153.49 46.8,153.26 45.95,152.41 45.95,152.18 46.19,151.94 46.42,151.94 47.25,152.77 47.48,152.77 47.72,152.54 47.72,152.3 46.89,151.48 46.89,151.24 47.12,151.01 47.35,151.01 48.11,151.76 48.34,151.76 48.57,151.53 48.57,151.29 47.82,150.54 47.82,150.31 48.06,150.08 48.29,150.08 49.14,150.92 49.37,150.92 55.04,145.25 55.04,129.95 59.02,125.97 59.02,117.11 58.72,116.81 58.72,115.82 58.92,115.63 CPU1.AW37
M_A_DQ26: length 63.2
  TOP w0.089: CPU1.AU35 60.75,113.91 60.4,114.26 60.4,114.65 60.61,114.86 60.78,114.86 61.1,115.18 61.1,115.57 60.97,115.7 60.97,115.7 60.92,115.75 60.92,116.47 61.06,116.61
  TOP w0.165: 61.06,116.61 61.59,117.14 62.78,117.14 62.94,117.31 62.94,126.18 57.85,131.27 57.85,152.75 57.68,152.92 51.45,152.92 51.28,153.08 51.28,153.41 51.45,153.58 55.92,153.58 56.08,153.74 56.08,154.07 55.92,154.24 50.34,154.24 50.1,154.48 DIMM1.45
M_A_DQ27: length 62.3
  TOP w0.089: 61.42,116.51 61.14,116.23 61.14,115.84 61.27,115.71 61.27,115.71 61.32,115.66 61.32,114.87 60.91,114.46 CPU1.AV35
  TOP w0.165: DIMM1.190 50.95,158.76 50.06,157.87 50.06,157.1 50.98,156.19 50.98,155.04 51.14,154.87 58.24,154.87 58.39,154.72 58.39,154.37 58.24,154.21 56.88,154.21 56.72,154.05 56.72,153.72 56.88,153.55 58.32,153.55 58.48,153.39 58.48,131.53 63.59,126.43 63.59,117.01 63.25,116.66 61.57,116.66 61.42,116.51
M_A_DQ28: length 62.1
  TOP w0.089: 58,113.54 57.54,114 57.54,114.88 56.62,115.8 56.62,116.58 56.75,116.71
  TOP w0.102: 58,113.54 CPU1.AU38
  TOP w0.165: DIMM1.36 42.45,156.75 42.27,156.57 42.27,153.15 51.82,143.6 51.82,132.17 51.98,132 52.31,132 52.48,132.17 52.48,137.27 52.64,137.44 52.97,137.44 53.14,137.27 53.14,129.16 57.11,125.18 57.11,117.08 56.75,116.71
M_A_DQ29: length 62.9
  TOP w0.089: 57.38,116.69 56.94,116.25 56.94,115.84 57.9,114.88 58.18,114.88 58.48,114.59 58.48,114.19 58.92,113.75 CPU1.AU37
  TOP w0.165: 57.38,116.69 57.75,117.06 57.75,125.45 53.77,129.42 53.77,143.28 53.61,143.44 53.28,143.44 53.11,143.28 53.11,140.74 52.95,140.57 52.62,140.57 52.45,140.74 52.45,143.34 52.45,143.57 52.72,143.83 53.56,144.67 53.56,144.9 53.32,145.14 53.09,145.14 52.25,144.3 52.02,144.3 42.93,153.39 42.93,155.07 42.63,155.36 42.63,156.3 43.3,156.96 DIMM1.181
M_A_DQ30: length 64.3
  TOP w0.089: 60.54,117.04 60.24,116.74 60.24,114.8 60.19,114.74 60.19,114.17 60.24,114.12 60.24,113.14 CPU1.AT35
  TOP w0.165: 60.54,117.04 60.74,117.25 60.74,126.58 56.58,130.74 56.58,147.52 56.41,147.69 54.85,147.69 54.69,147.85 54.69,148.18 54.85,148.35 56.41,148.35 56.58,148.51 56.58,148.84 56.41,149.01 54.8,149.01 54.64,149.17 54.64,149.5 54.8,149.67 56.41,149.67 56.58,149.83 56.58,150.16 56.41,150.33 53.84,150.33 53.67,150.49 53.67,150.82 53.84,150.99 56.4,150.99 56.57,151.15 56.57,151.48 56.4,151.65 50.88,151.65 48.4,154.13 DIMM1.43
M_A_DQ31: length 61.2
  TOP w0.089: 60.83,116.84 60.55,116.56 60.55,115.57 CPU1.AW35
  TOP w0.165: 60.83,116.84 62.31,118.31 62.31,119.01 62.14,119.17 61.76,119.17 61.59,119.34 61.59,119.67 61.76,119.83 62.14,119.83 62.31,120 62.31,120.33 62.14,120.49 61.76,120.49 61.59,120.66 61.59,120.99 61.76,121.15 62.14,121.15 62.31,121.32 62.31,121.65 62.14,121.81 61.76,121.81 61.59,121.98 61.59,122.31 61.76,122.47 62.14,122.47 62.31,122.64 62.31,122.97 62.14,123.13 61.76,123.13 61.59,123.3 61.59,123.63 61.76,123.79 62.14,123.79 62.31,123.96 62.31,124.29 62.14,124.45 61.76,124.45 61.59,124.62 61.59,124.95 61.76,125.11 62.14,125.11 62.31,125.28 62.31,125.91 57.21,131.01 57.21,151.74 56.67,152.28 51.14,152.28 49.15,154.28 49.15,156.3 48.39,157.07 48.39,157.95 49.25,158.81 DIMM1.188
M_A_DQ32: length 61.9
  TOP w0.165: DIMM1.97 98.82,155.8 98.02,155 98.02,154.74 98.18,154.57 100.34,154.57 100.51,154.41 100.51,154.07 100.34,153.91 98.03,153.91 97.89,153.77 97.89,153.39 98.03,153.25 100.37,153.25 100.53,153.08 100.53,152.75 100.37,152.59 98.06,152.59 97.89,152.42 97.89,152.09 98.06,151.93 99.58,151.93 99.75,151.76 99.75,151.48 99.53,151.27 98.18,151.27 98.02,151.1 98.02,149.76 89.13,140.87 89.13,122.39 88.96,122.22 88.63,122.22 88.47,122.39 88.47,123.58 88.3,123.75 87.97,123.75 87.81,123.58 87.81,117.37 87.64,117.21 CPU1.AY8
M_A_DQ33: length 64.8
  TOP w0.165: CPU1.AU8 88.07,113.06 88.07,116.41 88.47,116.81 88.47,121.35 88.63,121.51 88.96,121.51 89.29,121.18 89.58,121.18 89.79,121.39 89.79,140.63 89.96,140.8 90.28,140.8 90.45,140.64 90.45,137.84 90.61,137.68 90.94,137.68 91.11,137.84 91.11,141.93 98.65,149.47 98.65,150.47 98.82,150.63 99.8,150.63 100.71,151.55 100.71,151.55 101.19,152.03 101.19,154.72 100.91,155 100.37,155 100.2,155.17 100.2,156.3 99.39,157.11 99.39,158.1 98.58,158.91 98.58,160.01 99.06,160.49 99.54,160.49 DIMM1.242
M_A_DQ34: length 62.1
  TOP w0.089: CPU1.AV6 89.82,113.89 89.82,114.74 90.03,114.96 90.03,115.66 89.96,115.73 89.96,116.25 90.21,116.5 90.54,116.5 90.68,116.64
  TOP w0.165: 90.68,116.64 91.34,117.3 91.34,118.87 92.86,120.39 92.86,120.88 92.6,121.15 92.6,121.68 92.76,121.84 93.1,121.84 93.27,121.68 93.27,121.48 93.43,121.31 93.78,121.31 93.94,121.48 93.94,140.79 94.11,140.96 94.44,140.96 94.6,140.79 94.6,139.6 94.77,139.43 95.1,139.43 95.26,139.6 95.26,142.11 103.98,150.83 103.98,150.85 104.02,150.88 104.02,151.39 104.01,151.4 104.01,154.74 104.18,154.9 104.51,154.9 104.67,154.74 104.67,152.2 104.84,152.03 105.17,152.03 105.33,152.2 105.33,155 105.16,155.18 105.16,155.51 105.17,155.52 105.17,156.08 105.16,156.09 105.16,156.42 105.35,156.62 DIMM1.104
M_A_DQ35: length 63.1
  TOP w0.089: CPU1.AU6 89.99,113.15 89.99,113.76 90.03,113.8 90.03,114.65 90.24,114.86 90.25,114.86 90.3,114.91 90.53,114.91 90.68,115.06
  TOP w0.165: 90.68,115.06 90.83,115.21 90.83,115.9 92.02,117.09 92.02,118.65 94.58,121.21 94.58,136.54 94.74,136.7 95.07,136.7 95.24,136.54 95.24,132.73 95.4,132.56 95.73,132.56 95.9,132.73 95.9,141.85 105.97,151.92 105.97,154.88 105.87,154.99 105.87,155 105.51,155.36 105.51,156.29 106.2,156.99 DIMM1.249
M_A_DQ36: length 63
  TOP w0.089: CPU1.AW8 87.64,114.75 87.29,115.1 87.29,115.95
  TOP w0.165: DIMM1.95 97.25,155.35 97.25,149.89 88.47,141.1 88.47,124.55 88.3,124.38 87.97,124.38 87.81,124.55 87.81,132.58 87.64,132.74 87.31,132.74 87.15,132.58 87.15,116.64 87.29,116.49 87.29,115.95
M_A_DQ37: length 64
  TOP w0.089: 86.82,116.06 87.07,115.81 87.07,114.76 87.12,114.71 87.12,114.71 87.2,114.63 87.2,113.99 CPU1.AV8
  TOP w0.165: DIMM1.240 98.04,160.69 97.56,160.69 96.85,159.98 96.85,158.71 97.71,157.85 97.71,157.06 96.88,156.22 96.88,155.26 96.62,155 96.62,150.15 87.83,141.37 87.83,133.54 87.67,133.38 87.34,133.38 87.17,133.54 87.17,137.96 87.01,138.13 86.68,138.13 86.51,137.96 86.51,116.37 86.82,116.06
M_A_DQ38: length 59.8
  TOP w0.165: CPU1.AY6 89.47,116.5 90.04,117.07 90.04,119.47 91.33,120.76 91.33,133.34 91.49,133.5 91.82,133.5 91.99,133.34 91.99,127.9 92.15,127.74 92.51,127.74 92.67,127.9 92.67,141.32 102.71,151.35 102.71,151.37 102.73,151.4 102.73,154.79 103.47,155.52 103.47,156.5 103.65,156.69 DIMM1.102
M_A_DQ39: length 61
  TOP w0.089: 90.37,116.97 89.75,116.34 89.75,115.64 89.82,115.57 89.82,115.17 89.65,114.93 CPU1.AW6
  TOP w0.165: DIMM1.247 104.5,156.78 103.84,156.11 103.84,156.08 103.83,156.08 103.83,155.39 103.37,154.93 103.37,154.42 103.37,154.42 103.37,151.13 103.34,151.11 103.34,151.09 93.31,141.06 93.31,122.64 93.14,122.48 92.79,122.48 92.62,122.64 92.62,126.94 92.46,127.1 92.13,127.1 91.96,126.94 91.96,120.49 90.68,119.21 90.68,117.27 90.37,116.97
M_A_DQ40: length 66.1
  TOP w0.089: 93.27,115.8 92.43,114.96 92.4,114.96 92.39,114.95 92.1,114.95 91.68,114.53 91.68,114.3 91.3,113.91 CPU1.AV4
  TOP w0.165: DIMM1.108 108.75,156.61 108.57,156.43 108.57,155.22 109.07,154.72 109.07,152.26 99.14,142.33 99.14,131.15 98.97,130.99 98.64,130.99 98.48,131.15 98.48,137.83 98.31,138 97.98,138 97.82,137.83 97.82,121.75 93.93,117.86 93.93,116.46 93.27,115.8
M_A_DQ41: length 65.9
  TOP w0.089: 93.07,115.06 92.66,114.66 92.66,114.07 92.21,113.62 CPU1.AV3
  TOP w0.165: DIMM1.253 109.6,156.78 108.92,156.09 108.92,155.38 109.35,154.95 109.5,154.95 109.71,154.74 109.71,151.99 109.02,151.29 109,151.29 99.77,142.06 99.77,123.41 99.61,123.24 99.28,123.24 99.11,123.41 99.11,128.82 98.95,128.98 98.62,128.98 98.45,128.82 98.45,121.49 94.49,117.53 94.49,116.49 93.07,115.06
M_A_DQ42: length 67
  TOP w0.089: 95.42,111.91 94.95,111.44 94.31,111.44 94.24,111.37 93.85,111.37 93.63,111.58 93.63,111.75 93.32,112.07 92.56,112.07 CPU1.AT3
  TOP w0.165: 95.42,111.91 96.22,112.71 96.22,114.02 96.8,114.6 96.8,115.75 102.58,121.53 102.58,132.73 102.74,132.89 103.07,132.89 103.24,132.73 103.24,127.7 103.4,127.53 103.73,127.53 103.9,127.7 103.9,142.04 114.48,152.61 114.48,155.58 DIMM1.115
M_A_DQ43: length 65.3
  TOP w0.089: 95.57,111.65 95.15,111.23 94.4,111.23 94.33,111.15 93.68,111.15 93.13,111.7 CPU1.AT2
  TOP w0.165: 95.57,111.65 96.66,112.73 96.66,113.77 97.49,114.6 97.49,115.55 103.21,121.27 103.21,126.05 103.38,126.21 103.71,126.21 103.87,126.05 103.87,124.63 104.04,124.46 104.37,124.46 104.53,124.63 104.53,141.77 115.11,152.35 115.11,154.93 115.52,155.33 115.52,156.2 114.68,157.03 114.68,158.05 115.55,158.92 DIMM1.260
M_A_DQ44: length 64.1
  TOP w0.165: CPU1.AY4 91.3,115.83 92.66,117.2 92.66,118.39 95.22,120.96 95.22,131.47 95.38,131.62 95.72,131.62 95.89,131.46 95.89,126.05 96.05,125.88 96.38,125.88 96.55,126.05 96.55,141.6 106.6,151.66 106.6,152.35 106.77,152.51 107.46,152.51 107.65,152.7 107.65,153.01 107.48,153.17 106.77,153.17 106.6,153.34 106.6,153.67 106.77,153.83 107.66,153.83 107.8,153.98 107.8,154.35 107.66,154.49 106.77,154.49 106.6,154.66 106.6,155.1 106.88,155.38 106.88,156.38 107.05,156.55 DIMM1.106
M_A_DQ45: length 65.2
  TOP w0.089: CPU1.AW4 91.3,114.74 91.75,115.2 91.75,115.55 92.59,116.38
  TOP w0.165: DIMM1.251 107.9,156.92 107.21,156.24 107.21,155.14 107.38,154.98 108.27,154.98 108.44,154.81 108.44,152.59 98.5,142.66 98.5,139.67 98.34,139.51 98.01,139.51 97.84,139.67 97.84,141.37 97.68,141.54 97.38,141.54 97.18,141.34 97.18,122.01 97.01,121.84 96.69,121.84 96.52,122.01 96.52,125.08 96.35,125.25 96.02,125.25 95.86,125.08 95.86,120.69 93.29,118.13 93.29,117.09 92.59,116.38
M_A_DQ46: length 68.3
  TOP w0.089: 95.32,113 95.32,112.65 94.88,112.21 93.49,112.21 93.41,112.28 92.47,112.28 92.41,112.22 91.8,112.22 CPU1.AT4
  TOP w0.165: DIMM1.113 113,155.09 112.83,154.93 111.41,154.93 111.24,154.76 111.24,154.42 111.41,154.25 113.02,154.25 113.18,154.09 113.18,153.76 113.02,153.59 111.41,153.59 111.24,153.43 111.24,153.1 111.41,152.93 112.28,152.93 112.45,152.77 112.45,152.44 112.28,152.27 111.41,152.27 111.24,152.11 111.24,151.87 111.24,151.87 111.24,151.35 111.24,151.35 111.24,151.2 102.3,142.25 102.3,142.04 102.63,141.7 102.63,138.78 102.46,138.62 102.13,138.62 101.97,138.78 101.97,141.43 101.8,141.59 101.48,141.59 101.31,141.41 101.31,122.06 100.97,121.72 100.26,121.72 99.99,121.45 99.99,120.76 95.91,116.69 95.91,115.07 95.32,114.48 95.32,113
M_A_DQ47: length 65
  TOP w0.165: DIMM1.258 113.85,159.02 112.95,158.13 112.95,157.01 113.84,156.12 113.84,152.89 111.46,150.51 111.45,150.51 103.26,142.32 103.26,133.95 103.1,133.78 102.77,133.78 102.6,133.95 102.6,136.49 102.44,136.65 102.11,136.65 101.94,136.49 101.94,121.8 96.34,116.2 96.34,114.81 95.77,114.24 95.77,112.74 94.75,111.72 CPU1.AT1
M_A_DQ48: length 76.8
  TOP w0.089: 95.48,110.01 95.28,110.01 95.16,109.89 CPU1.AP1
  TOP w0.165: DIMM1.119 119.22,154.68 119.22,153.31 106.69,140.78 106.69,132.74 107.76,131.67 107.76,130.82 107.92,130.66 108.45,130.66 108.61,130.49 108.61,130.16 108.45,130 107.92,130 107.75,129.82 107.75,121.53 107.58,121.36 107.26,121.36 107.1,121.53 107.1,129.32 106.93,129.49 106.6,129.49 106.44,129.32 106.44,120.23 96.22,110.01 95.48,110.01
M_A_DQ49: length 77
  TOP w0.089: CPU1.AP2 93.5,109.89 93.85,109.54 94.24,109.54 94.35,109.65 95,109.65 95.02,109.63
  TOP w0.165: 95.02,109.63 96.77,109.63 108.39,121.26 108.39,122.57 108.53,122.71 109.21,122.71 109.37,122.87 109.37,123.25 109.21,123.42 108.57,123.42 108.41,123.58 108.41,123.92 108.57,124.08 109.18,124.08 109.35,124.25 109.35,124.58 109.18,124.75 108.56,124.75 108.39,124.91 108.39,125.24 108.56,125.41 109.21,125.41 109.37,125.57 109.37,125.9 109.21,126.07 108.57,126.07 108.38,126.26 108.38,126.54 108.57,126.73 109.21,126.73 109.37,126.89 109.37,127.22 109.21,127.39 108.57,127.39 108.38,127.58 108.38,127.86 108.57,128.05 109.21,128.05 109.37,128.21 109.37,128.54 109.21,128.71 108.57,128.71 108.38,128.9 108.38,129.18 108.57,129.37 109.2,129.37 109.37,129.54 109.37,130.96 109.04,131.29 108.56,131.29 108.39,131.46 108.39,131.93 107.33,133 107.33,140.52 119.86,153.05 119.86,154.72 119.02,155.55 119.02,156.07 118.11,156.99 118.11,158.27 117.39,158.99 117.39,160.12 117.65,160.37 118.12,160.37 DIMM1.264
M_A_DQ50: length 79
  TOP w0.089: CPU1.AM3 92.56,108.41 93.32,108.41 93.64,108.09 93.64,107.91 93.85,107.71 94.24,107.71 94.31,107.79 95.02,107.79 95.03,107.77 95.66,107.77
  TOP w0.165: 95.66,107.77 98.94,107.77 112.19,121.02 112.19,128.83 112.39,129.03 115.61,129.03 116.15,129.57 116.78,129.57 119.86,132.65 119.86,144.22 119.7,144.38 119.29,144.38 119.13,144.55 119.13,145.78 118.96,145.95 118.63,145.95 118.47,145.78 118.47,144.6 118.3,144.44 117.97,144.44 117.81,144.6 117.81,145.41 117.64,145.58 117.31,145.58 117.14,145.41 117.14,144.6 116.98,144.44 116.69,144.44 116.13,144.99 116.13,145.35 122.66,151.88 122.66,153.94 123.87,155.15 123.87,156.6 124.05,156.78 DIMM1.126
M_A_DQ51: length 77.9
  TOP w0.089: 95.42,107.48 95.02,107.48 94.93,107.57 94.58,107.57 94.5,107.49 93.47,107.49 93.13,107.84 CPU1.AM2
  TOP w0.165: DIMM1.271 124.9,156.94 124.23,156.27 124.23,154.61 123.3,153.68 123.3,151.33 120.5,148.52 120.5,147.51 120.34,147.36 119.99,147.36 119.68,147.67 119.36,147.67 118.82,147.13 118.82,146.9 119.09,146.63 120.33,146.63 120.5,146.47 120.5,145.97 120.33,145.81 119.93,145.81 119.76,145.64 119.76,145.31 119.93,145.15 120.33,145.15 120.5,144.98 120.5,132.38 117.05,128.93 116.48,128.93 115.95,128.4 115.7,128.4 115.47,128.17 115.47,127.83 115.3,127.66 114.97,127.66 114.81,127.83 114.81,128.23 114.64,128.4 114.31,128.4 114.15,128.23 114.15,127.83 113.98,127.66 113.65,127.66 113.49,127.83 113.49,128.23 113.32,128.4 113.03,128.4 112.83,128.19 112.83,121.28 112.83,121.28 112.83,120.76 99.56,107.49 99.08,107.49 99.06,107.48 95.42,107.48
M_A_DQ52: length 79.1
  TOP w0.089: CPU1.AP4 91.77,110.36 92.75,110.36 92.84,110.45 94.45,110.45 94.52,110.38 94.88,110.38 95.13,110.63 95.13,110.65 95.42,110.93 95.42,110.99
  TOP w0.165: DIMM1.117 116.8,155.8 116.97,155.63 116.97,155.19 117.12,155.04 117.12,154.48 117.28,154.32 117.72,154.32 117.88,154.15 117.88,153.8 117.72,153.63 117.23,153.63 117.07,153.47 117.07,152.96 116.9,152.79 116.6,152.79 116.43,152.96 116.43,154.74 116.27,154.9 115.91,154.9 115.75,154.74 115.75,152.09 105.17,141.51 105.17,121.07 105,120.9 104.67,120.9 104.51,121.07 104.51,123.63 104.34,123.8 104.01,123.8 103.85,123.63 103.85,120.77 104.4,120.23 104.4,119.99 104.16,119.76 103.93,119.76 103.38,120.31 103.15,120.31 102.91,120.07 102.91,119.84 103.46,119.29 103.46,119.06 103.23,118.82 102.99,118.82 102.45,119.37 102.21,119.37 101.98,119.14 101.98,118.91 102.53,118.36 102.53,118.12 102.29,117.89 102.06,117.89 101.51,118.44 101.28,118.44 101.05,118.2 101.05,117.97 101.59,117.42 101.59,117.19 101.36,116.96 101.13,116.96 100.58,117.5 100.14,117.5 99.97,117.34 99.97,117.1 100.23,116.85 100.23,116.49 100.06,116.33 99.17,116.33 98.02,115.18 98.02,114.36 97.16,113.49 97.16,112.73 95.42,110.99
M_A_DQ53: length 78.5
  TOP w0.089: 95.72,110.41 95.6,110.29 95.25,110.29 95.12,110.16 94.44,110.16 94.36,110.24 92.93,110.24 92.58,109.89 CPU1.AP3
  TOP w0.165: DIMM1.262 117.25,160.39 117.1,160.24 117.1,158.94 116.38,158.23 116.38,156.96 117.42,155.92 117.42,155.24 117.79,154.87 118.11,154.87 118.52,154.47 118.52,153.5 117.17,152.16 117.09,152.16 115.92,150.99 115.55,150.99 115.31,150.76 115.31,150.3 115.07,150.06 114.62,150.06 114.38,149.82 114.38,149.36 114.14,149.13 113.68,149.13 113.45,148.89 113.45,148.43 113.21,148.19 112.75,148.19 112.51,147.95 112.51,147.5 112.27,147.26 111.82,147.26 111.58,147.02 111.58,146.56 111.34,146.32 110.88,146.32 110.64,146.08 110.64,145.63 110.4,145.39 109.95,145.39 109.71,145.15 109.71,144.69 109.47,144.45 109.01,144.45 108.77,144.22 108.77,143.76 108.54,143.52 108.08,143.52 107.84,143.28 107.84,142.82 107.6,142.59 107.14,142.59 106.91,142.35 106.91,141.89 106.53,141.51 106.08,141.51 105.8,141.23 105.8,140.6 106.06,140.35 106.06,139.94 105.8,139.69 105.8,139.28 106.06,139.03 106.06,138.62 105.8,138.36 105.8,135.46 106.06,135.2 106.06,134.8 105.8,134.54 105.8,134.14 106.06,133.88 106.06,133.48 105.8,133.22 105.8,132.02 105.92,131.9 106.63,131.9 107.12,131.41 107.12,130.29 106.96,130.12 106.63,130.12 106.46,130.29 106.46,131.08 106.3,131.24 105.97,131.24 105.8,131.08 105.8,120.49 101.51,116.2 101.27,116.2 101,116.47 100.77,116.47 100.54,116.23 100.54,116 100.81,115.73 100.81,115.5 100.57,115.26 100.34,115.26 99.75,115.85 99.52,115.85 99.28,115.62 99.28,115.38 99.87,114.8 99.87,114.56 99.64,114.33 99.4,114.33 98.92,114.81 98.69,114.81 98.45,114.58 98.45,114.35 98.94,113.86 98.94,113.63 98.64,113.33 98.4,113.33 98.28,113.45 98.03,113.45 97.87,113.29 97.87,112.56 95.72,110.41
M_A_DQ54: length 79.7
  TOP w0.089: CPU1.AM4 91.7,108.46 92.31,108.46 92.47,108.62 93.41,108.62 93.63,108.41 94.36,108.41 94.44,108.33 95.53,108.33 95.71,108.51
  TOP w0.165: DIMM1.124 122.35,156.69 122.17,156.51 122.17,155.33 121.39,154.55 121.39,152.41 112.62,143.64 112.62,143.33 112.79,143.17 115.52,143.17 115.68,143 115.68,142.87 115.85,142.71 116.18,142.71 116.34,142.87 116.34,143 116.51,143.17 116.84,143.17 117.01,143 117.01,141.78 117.17,141.62 117.5,141.62 117.67,141.78 117.67,142.52 117.83,142.68 118.43,142.68 118.59,142.52 118.59,133.17 116.26,130.84 115.62,130.84 115.09,130.3 111.94,130.3 111.66,130.58 111.1,130.58 110.92,130.4 110.92,121.55 97.96,108.58 95.78,108.58 95.71,108.51
M_A_DQ55: length 77.1
  TOP w0.165: CPU1.AM1 95.53,108.06 95.53,108.06 96.01,108.06 96.23,108.29 98.08,108.29 98.1,108.32 98.59,108.32 111.56,121.28 111.56,129.49 111.73,129.67 115.35,129.67 115.88,130.2 116.52,130.2 119.23,132.91 119.23,143.55 118.97,143.8 118.5,143.8 118.34,143.64 118.34,143.48 118.17,143.32 117.74,143.32 117.58,143.48 117.58,143.64 117.41,143.8 116,143.8 115.84,143.97 115.84,144.35 115.67,144.51 115.34,144.51 115.18,144.35 115.18,143.97 115.01,143.8 114.36,143.8 114.18,143.98 114.18,144.3 122.03,152.15 122.03,154.29 122.53,154.79 122.53,156.32 123.2,156.99 DIMM1.269
M_A_DQ56: length 85.9
  TOP w0.089: 96.55,106.36 96.28,106.36 96.26,106.34 95.16,106.34 95.11,106.29 94.34,106.29 94.28,106.23 CPU1.AK1
  TOP w0.165: 96.55,106.36 100.95,106.36 101.41,106.81 102.44,106.81 113.68,118.05 114.78,119.15 114.78,119.76 114.96,119.94 115.57,119.94 115.99,120.36 115.99,120.36 116.1,120.48 116.1,121.23 116.28,121.41 117.02,121.41 117.75,122.15 117.75,122.5 117.42,122.83 117.42,126.86 117.59,127.03 117.92,127.03 118.08,126.86 118.08,123.13 118.25,122.96 118.58,122.96 118.75,123.13 118.75,127.84 122.4,131.5 122.4,147.56 125.73,150.89 125.73,151.12 125.32,151.52 125.32,152.17 125.49,152.33 125.9,152.33 126.06,152.17 126.06,151.83 126.23,151.67 126.53,151.67 127.38,152.52 127.38,152.85 127.22,153.01 125.97,153.01 125.81,153.18 125.81,153.49 125.99,153.67 127.62,153.67 127.75,153.8 127.75,154.21 127.62,154.33 126.72,154.33 126.62,154.43 126.62,154.83 126.75,154.96 127.05,154.96 127.3,155.21 127.3,156.41 127.45,156.56 DIMM1.130
M_A_DQ57: length 86.1
  TOP w0.089: CPU1.AK2 93.5,106.23 93.85,105.88 94.24,105.88 94.39,106.03 94.96,106.03
  TOP w0.165: 94.96,106.03 101.32,106.03 101.46,106.18 102.71,106.18 114.32,117.79 119.81,123.28 119.81,123.47 119.38,123.9 119.38,127.57 119.55,127.74 119.88,127.74 120.04,127.57 120.04,124.19 120.21,124.03 120.54,124.03 120.7,124.19 120.7,128.87 120.87,129.03 121.2,129.03 121.36,128.87 121.36,127.98 121.53,127.81 121.86,127.81 122.02,127.98 122.02,130.19 122.19,130.35 122.87,130.35 123.04,130.52 123.04,147.27 128.38,152.62 128.38,154.79 128.22,154.95 127.94,154.95 127.58,155.31 127.58,156.29 128.3,157.01 DIMM1.275
M_A_DQ58: length 89.5
  TOP w0.089: 95,104.11 94.3,104.11 94.24,104.05 93.85,104.05 93.63,104.26 93.63,104.43 93.53,104.54 93.53,104.55 93.32,104.75 92.93,104.75 92.58,104.4 CPU1.AH3
  TOP w0.165: 95,104.11 96.7,104.11 97.46,103.35 103.85,103.35 110.07,109.58 111.79,109.58 114.75,112.54 114.75,112.84 114.17,113.43 114.17,113.66 114.41,113.9 114.64,113.9 115.23,113.31 115.46,113.31 115.71,113.56 115.71,113.79 115.12,114.38 115.12,114.61 115.36,114.85 115.59,114.85 116.18,114.27 116.42,114.27 116.66,114.51 116.66,114.74 116.07,115.33 116.07,115.56 116.31,115.81 116.55,115.81 117.13,115.22 117.37,115.22 117.61,115.46 117.61,115.69 117.04,116.27 117.04,116.53 117.27,116.76 117.5,116.76 118.09,116.17 118.32,116.17 118.56,116.41 118.56,116.65 117.97,117.23 117.97,117.47 118.2,117.7 118.46,117.7 118.97,117.19 119.23,117.19 119.46,117.42 119.46,117.66 118.93,118.19 118.93,118.43 122.93,122.43 125.25,122.43 126.01,123.19 126.01,146.14 131.67,151.8 131.67,153.71 132.64,154.67 132.64,155.04 DIMM1.137
M_A_DQ59: length 88
  TOP w0.089: CPU1.AH2 93.69,103.84 95.81,103.84 96.77,102.87
  TOP w0.165: DIMM1.282 134.25,159 133.42,158.17 133.42,157 134.16,156.25 134.16,155.29 132.31,153.44 132.31,151.54 126.64,145.87 126.64,122.93 125.51,121.79 123.29,121.79 120.89,119.39 120.89,119.16 121.48,118.57 121.48,118.33 121.24,118.09 121.01,118.09 120.44,118.66 120.15,118.66 119.94,118.44 119.94,118.21 120.54,117.6 120.54,117.37 112.09,108.92 110.31,108.92 104.11,102.72 96.93,102.72 96.77,102.87
M_A_DQ60: length 87.9
  TOP w0.089: CPU1.AK4 91.68,106.62 92.66,106.62 92.84,106.79 94.5,106.79 94.58,106.72 94.93,106.72 94.98,106.77 95.55,106.77 95.87,107.09
  TOP w0.165: DIMM1.128 125.75,156.74 125.63,156.62 125.63,155.11 124.05,153.53 124.05,153.01 124.05,153.01 124.05,151.12 121.13,148.19 121.13,132.05 117.37,128.3 116.84,128.3 115.57,127.03 114.97,127.03 114.81,126.86 114.81,124.02 114.59,123.8 114.31,123.8 114.15,123.96 114.15,126.86 113.98,127.03 113.65,127.03 113.49,126.86 113.49,120.5 113.06,120.07 113.06,119.84 113.25,119.65 113.25,119.42 113.02,119.19 112.79,119.19 112.6,119.37 112.36,119.37 112.13,119.14 112.13,118.91 112.32,118.72 112.32,118.48 112.09,118.25 111.85,118.25 111.66,118.44 111.43,118.44 111.2,118.21 111.2,117.97 111.38,117.78 111.38,117.55 111.15,117.32 110.92,117.32 110.73,117.51 110.5,117.51 110.26,117.27 110.26,117.04 110.45,116.85 110.45,116.62 110.22,116.38 109.98,116.38 109.79,116.57 109.56,116.57 109.33,116.34 109.33,116.1 109.52,115.92 109.52,115.68 109.28,115.45 109.05,115.45 108.86,115.64 108.63,115.64 108.39,115.4 108.39,115.17 108.58,114.98 108.58,114.75 108.35,114.51 108.11,114.51 107.93,114.7 107.69,114.7 107.46,114.47 107.46,114.24 107.65,114.05 107.65,113.81 107.41,113.58 107.18,113.58 106.99,113.77 106.76,113.77 106.53,113.54 106.53,113.3 106.71,113.11 106.71,112.88 106.48,112.65 106.25,112.65 106.06,112.83 105.82,112.83 105.59,112.6 105.59,112.37 105.78,112.18 105.78,111.95 105.55,111.71 105.31,111.71 105.12,111.9 104.89,111.9 104.66,111.67 104.66,111.43 104.85,111.24 104.85,111.01 104.61,110.78 104.38,110.78 104.19,110.97 103.96,110.97 103.72,110.73 103.72,110.5 103.91,110.31 103.91,110.08 103.68,109.84 103.44,109.84 103.26,110.03 103.02,110.03 102.79,109.8 102.79,109.56 102.98,109.38 102.98,109.14 102.74,108.91 102.51,108.91 102.32,109.1 102.09,109.1 101.85,108.86 101.85,108.63 101.97,108.51 101.97,108.28 101.77,108.08 101.47,108.08 101.39,108.16 101.15,108.16 100.08,107.09 95.87,107.09
M_A_DQ61: length 86.8
  TOP w0.089: CPU1.AK3 92.58,106.23 92.93,106.58 94.41,106.58 94.49,106.5 95.02,106.5 95.07,106.55 96.17,106.55 96.27,106.65
  TOP w0.165: DIMM1.273 126.6,156.94 125.9,156.23 125.9,154.48 124.69,153.27 124.69,150.85 121.77,147.93 121.77,131.79 117.64,127.66 117.1,127.66 116.79,127.35 116.79,122.21 116.62,122.05 116.29,122.05 116.13,122.21 116.13,125.97 115.96,126.14 115.63,126.14 115.47,125.97 115.47,120.74 115.3,120.57 114.97,120.57 114.81,120.74 114.81,122.8 114.64,122.96 114.31,122.96 114.15,122.8 114.15,119.42 113.05,118.31 102.18,107.45 101.46,107.45 100.74,106.72 96.34,106.72 96.27,106.65
M_A_DQ62: length 89.8
  TOP w0.089: CPU1.AH4 91.7,104.8 92.68,104.8 92.84,104.97 93.46,104.97 93.67,104.75 94.24,104.75 94.36,104.62 95.22,104.62 95.38,104.78 95.86,104.78
  TOP w0.165: 95.86,104.78 97.61,104.78 97.74,104.65 101.46,104.65 101.46,104.64 103.34,104.64 115.85,117.15 122.45,123.75 122.98,123.75 122.98,123.75 124.45,123.75 124.61,123.91 124.61,124.24 124.45,124.41 122.54,124.41 122.38,124.57 122.38,124.9 122.54,125.07 124.52,125.07 124.69,125.23 124.69,125.56 124.52,125.73 122.62,125.73 122.45,125.9 122.45,126.23 122.62,126.39 124.52,126.39 124.69,126.56 124.69,126.89 124.52,127.05 123.74,127.05 123.57,127.22 123.57,127.55 123.74,127.71 124.52,127.71 124.69,127.88 124.69,128.21 124.52,128.37 123.74,128.37 123.57,128.54 123.57,128.87 123.74,129.03 124.52,129.03 124.69,129.2 124.69,146.7 129.92,151.93 129.92,153.16 130.09,153.33 130.21,153.33 130.4,153.52 130.4,153.99 130.21,154.18 130.09,154.18 129.92,154.34 129.92,154.77 130.16,155.02 131.47,155.02 131.7,155.25 DIMM1.135
M_A_DQ63: length 86.7
  TOP w0.089: 96.82,104.4 CPU1.AH1
  TOP w0.165: 96.82,104.4 97.3,104.4 97.69,104.01 103.61,104.01 110.46,110.86 110.69,110.86 111.34,110.22 111.54,110.22 111.81,110.48 111.81,110.68 111.16,111.33 111.16,111.56 111.39,111.79 111.63,111.79 112.27,111.15 112.47,111.15 112.74,111.42 112.74,111.62 112.1,112.26 112.1,112.49 112.33,112.73 112.56,112.73 113.06,112.23 113.3,112.23 113.53,112.46 113.53,112.7 113.03,113.2 113.03,113.43 116.49,116.89 122.71,123.11 124.89,123.11 125.37,123.6 125.37,146.47 131.04,152.13 131.04,153.97 132.51,155.44 132.51,156.17 131.67,157.01 131.67,158.09 132.55,158.97 DIMM1.280
M_A_DQS_DN0: length 83.3
  TOP w0.089: CPU1.AF39 57.09,103.78 57.01,103.86 56.83,103.86 56.66,103.7 56.66,103.4 56.41,103.15 56.39,103.15 56.38,103.14 55.89,103.14 55.88,103.14 55.81,103.06 55.34,103.06 55.33,103.07 54.38,103.07
  TOP w0.165: DIMM1.152 18.72,161.13 18.72,160.35 18.49,160.12 18.49,158.92 19.39,158.02 19.39,157.05 18.5,156.15 18.5,155.35 24.31,141.32 24.31,125.46 25.97,120.88 45.35,101.5 52.47,101.5 54.04,103.07 54.38,103.07
M_A_DQS_DN1: length 72.8
  TOP w0.089: 54.48,106.98 54.49,106.97 55.04,106.97 55.3,106.72 55.82,106.72 55.89,106.79 56.38,106.79 56.58,107 56.58,107.34 56.75,107.51 57.15,107.51 57.23,107.43 57.23,107.28 CPU1.AK39
  TOP w0.165: DIMM1.163 28,159.9 28.34,160.24 28.42,160.24 28.74,159.92 28.74,158.86 27.84,157.96 27.84,157 28.71,156.13 28.71,154.38 30.29,152.81 30.29,132.16 39.84,122.61 39.84,118.51 42.38,115.97 42.38,113.22 47.81,107.8 52.11,107.8 52.92,106.98 54.48,106.98
M_A_DQS_DN2: length 61.9
  TOP w0.089: 54.67,110.57 54.75,110.49 55.17,110.49 55.33,110.34 55.71,110.34 55.75,110.38 55.79,110.38 55.87,110.45 56.38,110.45 56.39,110.46 56.41,110.46 56.59,110.64 56.59,110.87 56.67,110.95 56.95,110.95 CPU1.AP39
  TOP w0.165: DIMM1.174 37.69,160.56 37.68,160.55 37.5,160.45 37.2,160.15 37.2,158.98 38.06,158.12 38.06,157.13 37.21,156.28 37.21,153.25 46.15,144.31 46.15,128.4 53.7,120.86 53.7,111.55 54.08,111.16 54.67,110.57
M_A_DQS_DN3: length 53.9
  TOP w0.089: 59.65,117.43 59.65,117.31 59.68,117.28 59.68,116.95 59.14,116.42 59.14,116.26 59.14,115.79 59.32,115.61 59.32,115.05 59.29,115.01 59.29,114.09 59.5,113.88 59.5,113.88 CPU1.AU36
  TOP w0.165: DIMM1.185 46.7,159.8 47.06,160.16 47.29,160.16 47.44,160.01 47.44,158.81 46.59,157.96 46.59,156.98 47.44,156.13 47.44,153.81 55.68,145.58 55.68,130.37 59.65,126.4 59.65,117.43
M_A_DQS_DN4: length 53.8
  TOP w0.089: 89.1,117.35 89.1,116.99 88.98,116.87 88.98,115.89 88.91,115.83 88.91,114.2 88.81,114.1 88.66,114.1 88.55,114.2 CPU1.AW7
  TOP w0.165: DIMM1.244 101.95,160.11 101.79,159.95 101.79,158.9 102.69,158.01 102.69,157.16 101.83,156.3 101.83,151.75 91.77,141.69 91.77,135.1 90.42,133.75 90.42,121.13 89.1,119.81 89.1,117.35
M_A_DQS_DN5: length 57.1
  TOP w0.089: 94.68,115.03 93.6,113.94 93.6,113.42 93.3,113.12 93.28,113.12 93.14,112.98 92.93,112.98 92.73,112.78 CPU1.AU3
  TOP w0.165: 94.68,115.03 95.02,115.37 95.02,115.37 95.03,115.38 95.03,117.17 99.09,121.23 99.09,121.75 99.09,121.82 100.41,123.14 100.41,141.79 110.34,151.72 110.34,156.2 111.19,157.05 111.19,157.96 112.04,158.81 112.04,160.01 111.89,160.16 111.66,160.16 111.3,159.8 DIMM1.255
M_A_DQS_DN6: length 69.4
  TOP w0.089: 95.76,109.26 95.59,109.26 95.49,109.36 94.92,109.36 94.88,109.4 94.49,109.4 94.42,109.32 93.85,109.32 93.72,109.19 93.45,109.19 93.32,109.32 92.99,109.32 CPU1.AN3
  TOP w0.165: DIMM1.266 120.65,160.28 120.49,160.12 120.49,158.7 121.34,157.85 121.34,157 120.49,156.15 120.49,152.78 107.96,140.25 107.96,133.26 110.02,131.21 110.02,121.92 97.36,109.26 95.76,109.26
M_A_DQS_DN7: length 78.2
  TOP w0.089: CPU1.AJ3 92.56,105.66 94.45,105.66 94.52,105.74 94.88,105.74 95.1,105.52 95.72,105.52 95.75,105.54 95.86,105.54
  TOP w0.165: 95.86,105.54 102.97,105.54 114.95,117.52 121.34,123.91 121.34,126.39 122.66,127.71 122.66,129.24 123.67,130.25 123.67,147 129.02,152.35 129.02,156.21 129.87,157.06 129.87,157.98 130.72,158.84 130.72,159.94 130.42,160.24 130.34,160.24 130,159.9 DIMM1.277
M_A_DQS_DP0: length 83.4
  TOP w0.089: 54.48,103.34 54.77,103.34 55.34,103.91 55.7,103.91 55.77,103.84 56.53,103.84 56.75,104.05 57.09,104.05 57.65,103.49 CPU1.AF38
  TOP w0.165: 54.48,103.34 53.93,103.34 52.35,101.76 45.46,101.76 26.2,121.02 24.57,125.51 24.57,141.38 18.76,155.4 18.76,156.04 19.66,156.94 19.66,158.13 18.76,159.03 18.76,160.01 18.91,160.16 19.14,160.16 19.5,159.8 DIMM1.153
M_A_DQS_DP1: length 73
  TOP w0.089: CPU1.AK38 57.78,107.14 57.23,107.7 56.67,107.7 56.46,107.49 55.77,107.49 55.7,107.57 55.34,107.57 55.29,107.52 55.29,107.52 54.94,107.17 54.72,107.17 54.68,107.21 54.63,107.21 54.59,107.25
  TOP w0.165: DIMM1.164 28.55,160.63 28.55,160.49 29.01,160.03 29.01,158.75 28.11,157.85 28.11,157.11 28.98,156.24 28.98,154.49 30.56,152.92 30.56,132.27 40.11,122.72 40.11,118.63 42.65,116.09 42.65,113.33 47.92,108.06 52.22,108.06 53.03,107.25 54.59,107.25
M_A_DQS_DP2: length 62
  TOP w0.089: CPU1.AP38 57.67,111.14 57.3,111.14 57.29,111.15 56.9,111.15 56.89,111.14 56.34,111.14 56.32,111.15 55.77,111.15 55.7,111.23 55.34,111.23 55.03,110.91 55.03,110.82 54.97,110.76 54.86,110.76 54.73,110.88
  TOP w0.165: 54.73,110.88 54.19,111.43 54.19,111.43 53.96,111.66 53.96,120.97 46.42,128.51 46.42,144.42 37.48,153.36 37.48,156.17 38.33,157.02 38.33,158.23 37.47,159.09 37.47,160.04 37.66,160.23 37.74,160.27 37.86,160.24 DIMM1.175
M_A_DQS_DP3: length 54
  TOP w0.089: 59.92,117.43 59.92,117.3 59.87,117.25 59.87,116.87 59.34,116.34 59.34,115.87 59.51,115.69 59.51,114.97 59.48,114.93 59.48,114.17 59.58,114.07 59.74,114.07 59.84,114.17 CPU1.AV36
  TOP w0.165: DIMM1.186 47.48,161.13 47.48,160.35 47.71,160.12 47.71,158.7 46.86,157.85 46.86,157.09 47.71,156.24 47.71,153.92 55.94,145.69 55.94,130.48 59.92,126.51 59.92,117.43
M_A_DQS_DP4: length 53.9
  TOP w0.089: 89.37,117.35 89.37,117.34 89.33,117.3 89.33,117.25 89.29,117.22 89.29,116.91 89.17,116.79 89.17,115.81 89.1,115.75 89.1,114.12 88.84,113.85 88.84,113.83 CPU1.AV7
  TOP w0.165: 89.37,117.35 89.37,119.7 90.69,121.02 90.69,133.64 92.04,134.99 92.04,141.58 102.1,151.64 102.1,156.19 102.96,157.05 102.96,158.12 102.06,159.01 102.06,159.84 102.37,160.16 102.6,160.16 102.8,159.96 DIMM1.245
M_A_DQS_DP5: length 57
  TOP w0.089: CPU1.AU2 93.37,112.87 93.37,112.92 93.57,113.12 94.27,113.12 95.02,113.87 95.02,114.88
  TOP w0.165: 95.02,114.88 95.02,114.99 95.29,115.26 95.29,115.26 95.3,115.27 95.3,117.06 99.35,121.11 99.35,121.71 100.67,123.03 100.67,141.68 110.61,151.61 110.61,156.09 111.46,156.94 111.46,157.85 112.31,158.7 112.31,160.12 112.08,160.35 112.08,161.13 DIMM1.256
M_A_DQS_DP6: length 69.3
  TOP w0.089: CPU1.AN2 93.49,108.97 93.84,108.62 94.45,108.62 94.52,108.55 94.98,108.55 95.15,108.71 95.15,109.11 95.21,109.17 95.41,109.17 95.59,108.99 95.76,108.99
  TOP w0.165: 95.76,108.99 97.47,108.99 110.29,121.81 110.29,131.32 108.23,133.38 108.23,140.14 120.76,152.67 120.76,156.04 121.61,156.89 121.61,157.96 120.76,158.81 120.76,160.01 120.91,160.16 121.21,160.16 121.5,159.87 DIMM1.267
M_A_DQS_DP7: length 78.2
  TOP w0.089: 95.86,105.28 95.85,105.28 95.81,105.32 95.76,105.32 95.75,105.33 95.22,105.33 95.13,105.24 95.13,105.03 94.98,104.89 94.4,104.89 94.33,104.97 93.85,104.97 93.5,105.32 CPU1.AJ2
  TOP w0.165: DIMM1.278 130.55,160.63 130.55,160.49 130.99,160.05 130.99,158.73 130.13,157.87 130.13,156.95 129.29,156.1 129.29,152.24 123.94,146.89 123.94,130.14 122.92,129.13 122.92,127.6 121.6,126.28 121.6,123.8 115.22,117.41 103.08,105.28 95.86,105.28
M_A_ODT0: length 49.3
  TOP w0.165: CPU1.AW11 84.33,117 84.33,142 90.38,148.05 90.38,150.68 90.21,150.84 89.57,150.84 89.41,151.01 89.41,151.34 89.57,151.5 90.41,151.5 90.58,151.67 90.58,152 90.41,152.16 89.57,152.16 89.41,152.33 89.41,152.66 89.57,152.82 90.41,152.82 90.58,152.99 90.58,153.32 90.41,153.48 89.57,153.48 89.41,153.65 89.41,153.98 89.57,154.14 90.28,154.14 90.9,154.77 DIMM1.87
M_A_ODT1: length 51.2
  TOP w0.165: DIMM1.91 94.3,153.69 94.13,153.53 93.31,153.53 93.14,153.36 93.14,148.14 85.6,140.6 85.6,115.8 82.94,113.14 82.9,113.14 82.87,113.12 80.12,113.12 79.95,113.29 CPU1.AU14
M_A_PARITY: length 53.9
  TOP w0.216: DIMM1.222 82.74,161.71 82.22,161.71 82,161.49 82,160.31 81.87,160.18 81.26,160.18 81.14,160.31 81.14,161.62 80.92,161.83 80.38,161.83 80.16,161.62 80.16,159.37 80.47,159.07 80.47,157.11 80.16,156.81 80.16,135.06 79.95,134.85 79.03,134.85 78.82,134.63 78.82,126.06 80.19,124.68 80.19,118.06 79.04,116.9 CPU1.AY15
M_B_A0: length 71.1
  TOP w0.216: CPU1.AL19 v1(75.84,107.6)
  L3SGND w0.089: v1(75.84,107.6) 75.41,108.03 75.41,108.63 74.85,109.19 74.85,109.52
  L3SGND w0.191: 74.85,109.52 74.85,110.82 75.4,111.37 75.4,115.2 75.45,115.24 75.45,115.26 76.65,116.46 76.65,117.23 76.4,117.48 76.4,118.21 76.77,118.57 76.77,119.66 80.59,123.47 80.59,142.6 80.62,142.63 80.62,142.64 82.42,144.44 82.42,148.44 82.23,148.63 81.06,148.63 80.87,148.82 80.87,149.2 81.06,149.39 82.23,149.39 82.42,149.58 82.42,149.96 82.23,150.15 81.06,150.15 80.87,150.34 80.87,150.72 81.06,150.91 82.23,150.91 82.42,151.1 82.42,151.48 82.23,151.67 81.06,151.67 80.87,151.86 80.87,152.25 81.06,152.44 82.23,152.44 82.42,152.63 82.42,153.01 82.23,153.2 81.06,153.2 80.87,153.39 80.87,156.98 80.52,157.34 80.52,159.82 DIMM2.79
M_B_A1: length 72.3
  TOP w0.216: CPU1.AL22 v1(72.18,107.6)
  L3SGND w0.089: v1(72.18,107.6) 72.18,107.78 71.73,108.23 71.73,109.74 71.86,109.87 71.86,112.64 71.75,112.75 71.75,113.26
  L3SGND w0.191: DIMM2.72 73.05,162.76 73.91,161.9 73.91,160.84 73.2,160.13 73.2,158.81 73.94,158.08 73.94,157.11 73.05,156.22 73.05,155.02 73.24,154.83 73.98,154.83 74.17,154.64 74.17,154.26 73.98,154.07 73.24,154.07 73.05,153.88 73.05,153.5 73.24,153.31 73.93,153.31 74.12,153.12 74.12,152.74 73.93,152.55 73.24,152.55 73.05,152.36 73.05,151.98 73.24,151.79 74.03,151.79 74.22,151.6 74.22,151.21 74.03,151.02 73.24,151.02 73.05,150.83 73.05,149.74 73.24,149.55 73.93,149.55 74.12,149.36 74.12,148.98 73.93,148.79 73.24,148.79 73.05,148.6 73.05,147.58 73.41,147.23 76.48,147.23 76.81,146.9 76.81,125.02 72.73,120.94 72.73,117.01 71.63,115.9 71.63,114.29 71.75,114.17 71.75,113.26
M_B_A2: length 69.8
  TOP w0.216: CPU1.AM22 v1(72.18,108.52)
  L3SGND w0.089: v1(72.18,108.52) 72.61,109.25 72.61,109.65 72.09,110.17 72.09,113.44
  L3SGND w0.191: DIMM2.216 73.05,166.43 73.91,165.57 73.91,164.62 74.73,163.81 74.73,162.75 75.62,161.86 75.62,160.82 76.45,159.98 76.45,158.91 75.59,158.05 75.59,156.96 74.75,156.12 74.75,150.65 74.94,150.46 75.81,150.46 75.96,150.31 75.96,149.85 75.81,149.7 74.94,149.7 74.75,149.51 74.75,148.46 74.94,148.27 77.06,148.27 77.25,148.08 77.25,124.84 73.18,120.76 73.18,116.56 72.09,115.47 72.09,113.44
M_B_A3: length 70.8
  TOP w0.216: v1(71.27,109.43) CPU1.AM23
  L3SGND w0.089: 71.27,112.83 71.63,112.47 71.63,110.11 71.27,109.75 v1(71.27,109.43)
  L3SGND w0.191: DIMM2.71 72.2,162.48 72.37,162.31 72.37,160.69 72.88,160.18 72.88,158.78 72.19,158.09 72.19,157.14 71.37,156.32 71.37,154.91 71.56,154.72 72.42,154.72 72.61,154.53 72.61,154.15 72.42,153.96 71.56,153.96 71.37,153.77 71.37,153.39 71.56,153.2 72.42,153.2 72.61,153.01 72.61,152.62 72.42,152.43 71.56,152.43 71.37,152.24 71.37,151.86 71.56,151.67 72.42,151.67 72.61,151.48 72.61,151.1 72.42,150.91 71.56,150.91 71.37,150.72 71.37,150.34 71.56,150.15 72.42,150.15 72.61,149.96 72.61,149.58 72.42,149.39 71.56,149.39 71.37,149.2 71.37,148.79 71.56,148.6 72.42,148.6 72.61,148.41 72.61,147.01 72.83,146.78 75.96,146.78 76.37,146.38 76.37,125.2 72.29,121.13 72.29,118.39 70.8,116.9 70.8,113.3 71.27,112.83
M_B_A4: length 69.7
  TOP w0.216: CPU1.AP23 71.2,111.3 v1(71.2,111.3)
  L3SGND w0.191: v1(71.2,111.3) 71.17,111.33 71.17,111.33 70.46,112.04 70.46,117.12 71.84,118.5 71.84,121.31 75.9,125.36 75.9,146.04 75.59,146.34 71.17,146.34 70.89,146.62 70.89,147.07 71.08,147.26 71.95,147.26 72.14,147.45 72.14,147.83 71.95,148.02 71.08,148.02 70.89,148.21 70.89,154.24 69.81,155.32 69.81,156.09 70.67,156.95 70.67,157.82 71.52,158.67 71.52,160.08 72.03,160.58 72.03,161.94 71.52,162.45 71.52,163.86 72.21,164.55 72.21,165.59 71.35,166.46 DIMM2.214
M_B_A5: length 72.3
  TOP w0.216: CPU1.AL23 v1(71.27,108.52)
  L3SGND w0.089: 70.22,109.56 v1(71.27,108.52)
  L3SGND w0.191: 70.22,109.56 69.88,109.91 69.88,112.39 70,112.52 70,117.26 71.4,118.66 71.4,122.64 71.59,122.83 72.36,122.83 72.56,123.02 72.56,123.4 72.37,123.59 71.59,123.59 71.4,123.78 71.4,124.29 71.67,124.56 74.47,124.56 75.45,125.55 75.45,145.69 75.26,145.88 70.64,145.88 70.45,146.07 70.45,153.31 69.48,154.28 69.48,156.19 70.35,157.06 70.35,158.11 71.19,158.95 71.19,160.11 70.67,160.63 70.67,161.92 71.18,162.43 71.18,163.8 70.66,164.32 70.66,166.17 70.5,166.33 DIMM2.213
M_B_A6: length 63.1
  TOP w0.089: v1(69.49,117.67) 69.49,117.62 69.6,117.49 69.6,116.53 69.55,116.48 69.55,115.92 69,115.37 CPU1.AW26
  L3SGND w0.178: 69.94,118.12 v1(69.49,117.67)
  L3SGND w0.191: 69.94,118.12 70.94,119.12 70.94,124.47 71.22,124.75 71.48,125.01 74.28,125.01 75.01,125.73 75.01,145.13 74.75,145.38 74.13,145.38 73.94,145.19 73.94,144.22 73.75,144.03 73.37,144.03 73.18,144.22 73.18,145.19 72.99,145.38 72.61,145.38 72.41,145.19 72.41,144.22 72.22,144.03 71.84,144.03 71.65,144.22 71.65,145.19 71.46,145.38 70.51,145.38 70,145.89 70,153.05 68.24,154.81 68.24,155.4 68.12,155.52 68.12,156.29 68.83,157.01 68.83,158.13 69.57,158.86 69.57,160.09 70.33,160.85 70.33,162.39 70.5,162.56 DIMM2.69
M_B_A7: length 61.3
  TOP w0.089: CPU1.AY26 68.99,116.3 68.99,117.27 68.8,117.46 68.8,118.23 68.86,118.29
  TOP w0.216: 68.86,118.29 68.86,119.1 69.41,119.66 v1(69.47,119.66)
  L3SGND w0.191: DIMM2.211 70.35,165.65 70.35,164.45 69.81,163.9 69.81,162.66 68.97,161.82 68.97,160.75 68.12,159.9 68.12,159.88 68.12,159.88 68.12,158.77 67.27,157.92 67.27,156.68 67.78,156.17 67.78,154.47 69.56,152.69 69.56,145.69 72.59,142.66 74.35,142.66 74.56,142.44 74.56,125.91 74.1,125.45 70.89,125.45 70.5,125.06 70.5,120.68 v1(69.47,119.66)
M_B_A8: length 64.9
  TOP w0.089: 69.08,117.99 69.07,117.97 69.07,117.5 69.17,117.4 69.17,117.4 69.33,117.24 69.33,116.09 69.11,115.87 68.94,115.87 68.63,115.57 68.63,113.89 CPU1.AU26
  TOP w0.216: 69.08,117.99 69.47,118.37 v1(69.47,119.02)
  L3SGND w0.191: v1(69.47,119.02) 69.4,119.02 68.94,119.48 68.94,119.81 70.05,120.93 70.05,125.63 70.32,125.9 73.88,125.9 74.12,126.14 74.12,138.81 73.93,139 72.3,139 72.11,139.19 72.11,139.58 72.3,139.77 73.93,139.77 74.12,139.96 74.12,140.5 69.11,145.5 69.11,152.51 66.42,155.2 66.42,156.31 66.93,156.82 66.93,157.12 66.93,157.12 66.93,157.68 66.93,157.68 66.93,158.11 67.8,158.98 67.8,160.08 68.63,160.91 68.63,162.03 69.48,162.88 69.48,164 69.65,164.17 DIMM2.68
M_B_A9: length 61.1
  TOP w0.102: CPU1.AW27 68.07,115.73 68.42,116.08 68.42,116.57 68.43,116.59 68.43,117.17 68.21,117.39 68.21,117.7
  TOP w0.216: v1(67.72,118.94) 67.74,118.94 67.89,118.79 67.93,118.79 68.21,118.5 68.21,117.7
  L3SGND w0.191: DIMM2.66 67.23,164.28 66.9,164.28 66.27,163.65 66.27,163.29 65.24,162.26 65.24,160.91 64.39,160.06 64.39,159.02 63.53,158.16 63.53,156.83 63.01,156.31 63.01,155 63.33,154.67 64,154.67 64.19,154.48 64.19,154.02 64,153.83 63.31,153.83 63.12,153.64 63.12,152.81 63.67,152.26 64.19,152.26 64.38,152.45 64.38,152.99 64.57,153.18 64.95,153.18 65.14,152.99 65.14,152.45 65.33,152.26 66.33,152.26 66.52,152.07 66.52,141.58 66.53,141.57 66.53,134.71 66.71,134.52 66.92,134.52 67.11,134.33 67.11,133.95 66.92,133.76 66.71,133.76 66.53,133.58 66.53,133.18 66.71,133 66.92,133 67.11,132.81 67.11,132.43 66.92,132.24 66.71,132.24 66.53,132.05 66.53,131.66 66.71,131.48 66.92,131.48 67.11,131.28 67.11,130.9 66.92,130.71 66.71,130.71 66.53,130.53 66.53,128.87 67.13,128.28 67.13,127.91 67.13,120 67.23,119.89 67.23,119.42 v1(67.72,118.94)
M_B_A10: length 70.2
  TOP w0.216: v1(76.73,111.34) 76.66,111.27 76.66,111.15 76.32,110.8 CPU1.AP18
  L3SGND w0.191: v1(76.73,111.34) 76.72,111.34 76.68,111.38 76.57,111.38 76.23,111.72 76.23,115.11 77.31,116.2 77.31,117.55 77.66,117.9 77.66,118.51 77.66,119.29 81.48,123.1 81.48,142.23 81.51,142.26 81.51,142.27 83.41,144.17 83.41,145.93 83.6,146.12 84.17,146.12 84.34,146.28 84.34,146.72 84.17,146.88 83.6,146.88 83.41,147.07 83.41,147.45 83.6,147.64 84.17,147.64 84.34,147.8 84.34,148.24 84.17,148.4 83.6,148.4 83.41,148.59 83.41,148.97 83.6,149.16 84.17,149.16 84.34,149.33 84.34,149.76 84.17,149.93 83.6,149.93 83.41,150.12 83.41,150.5 83.6,150.69 84.17,150.69 84.34,150.85 84.34,151.29 84.17,151.45 83.6,151.45 83.41,151.64 83.41,152.02 83.6,152.21 84.17,152.21 84.34,152.37 84.34,152.81 84.17,152.97 83.6,152.97 83.41,153.16 83.41,153.55 83.6,153.74 84.17,153.74 84.34,153.9 84.34,154.34 84.17,154.5 83.6,154.5 83.41,154.69 83.41,156.1 84.25,156.94 84.25,158.22 83.42,159.05 83.42,159.91 84.26,160.74 84.26,161.75 85.12,162.61 85.12,163.95 85.8,164.63 DIMM2.225
M_B_A11: length 64.8
  TOP w0.089: CPU1.AU27 68.07,113.86 68.42,114.21 68.42,115.75 68.55,115.88
  TOP w0.102: 68.51,118.68 68.51,117.44 68.68,117.27 68.68,116.52 68.64,116.48 68.64,116.1 68.64,116.09 68.64,115.97 68.55,115.88
  TOP w0.216: v1(68.07,120.55) 68.22,120.4 68.22,120.4 68.51,120.12 68.51,118.68
  L3SGND w0.191: v1(68.07,120.55) 68.48,120.55 69.61,121.68 69.61,125.81 70.14,126.34 72.26,126.34 73.67,127.75 73.67,131.51 67.82,137.36 67.82,152.92 66.1,154.63 66.1,156.23 65.56,156.78 65.56,158.11 66.41,158.96 66.41,159.97 67.27,160.83 67.27,161.91 68.12,162.76 68.12,163.68 68.96,164.52 68.96,165.64 67.95,166.66 DIMM2.210
M_B_A12: length 64.7
  TOP w0.102: v1(67.72,117.61) 67.57,117.46 67.57,115.32 68.07,114.82 CPU1.AV27
  L3SGND w0.191: v1(67.72,117.61) 68.17,118.07 68.17,118.08 68.2,118.1 68.2,119.12 68.17,119.15 67.89,119.44 67.82,119.44 67.54,119.72 67.54,122.05 67.94,122.45 68.25,122.45 68.39,122.59 68.39,122.97 68.2,123.16 67.76,123.16 67.57,123.36 67.57,123.74 67.76,123.93 68.17,123.93 68.36,124.12 68.36,124.5 68.17,124.69 67.76,124.69 67.57,124.88 67.57,125.26 67.76,125.45 68.26,125.45 68.45,125.64 68.45,126.02 68.26,126.21 67.76,126.21 67.57,126.4 67.57,126.78 67.76,126.97 68.35,126.97 68.54,127.17 68.54,127.55 68.35,127.74 67.76,127.74 67.57,127.93 67.57,128.31 67.76,128.5 68.35,128.5 68.54,128.69 68.54,129.07 68.35,129.26 67.76,129.26 67.57,129.45 67.57,129.83 67.76,130.02 68.35,130.02 68.54,130.21 68.54,130.59 68.35,130.78 67.76,130.78 67.57,130.98 67.57,131.36 67.76,131.55 68.35,131.55 68.54,131.74 68.54,132.12 68.35,132.31 67.76,132.31 67.57,132.5 67.57,132.88 67.76,133.07 68.35,133.07 68.54,133.26 68.54,133.64 68.35,133.83 67.76,133.83 67.57,134.02 67.57,134.4 67.76,134.59 68.35,134.59 68.54,134.79 68.54,135.51 67.02,137.03 67.02,152.41 64.41,155.02 64.41,156.28 63.87,156.82 63.87,158.07 64.68,158.88 64.68,158.9 64.71,158.92 64.71,159.95 65.56,160.8 65.56,161.86 DIMM2.65
M_B_A13: length 66.7
  TOP w0.216: CPU1.AR15 79.5,111.25 v1(79.56,111.25)
  L3SGND w0.191: v1(79.56,111.25) 79.02,111.8 79.02,113.41 80.64,115.04 80.64,118.28 84.3,121.94 84.3,141.06 84.33,141.1 84.33,141.1 91.84,148.61 91.84,154.5 91.34,155 90.55,155 90.04,155.51 90.04,156.22 89.37,156.89 89.37,158.08 89.99,158.7 89.99,159.93 90.73,160.67 90.73,160.92 90.73,160.92 90.73,161.48 90.73,161.48 90.73,161.86 90.22,162.37 90.22,163.7 90.93,164.41 90.93,165.73 91.75,166.55 DIMM2.232
M_B_A14: length 71.9
  TOP w0.216: CPU1.AL17 v1(77.67,107.6)
  L3SGND w0.089: 77.65,110.82 77.5,110.68 77.47,110.68 77.23,110.43 77.23,110.42 77.19,110.39 77.19,109.14 77.37,108.97 77.98,108.97 78.13,108.81 78.13,108.06 v1(77.67,107.6)
  L3SGND w0.191: 77.65,110.82 77.86,111.03 77.86,114.87 79.1,116.1 79.1,118.84 82.81,122.55 82.81,141.68 82.84,141.71 82.84,141.72 88.52,147.4 88.52,149.48 88.33,149.67 87.66,149.67 87.47,149.86 87.47,150.24 87.66,150.43 88.33,150.43 88.52,150.62 88.52,152.94 86.49,154.98 86.49,156.26 87.33,157.1 87.33,157.83 86.48,158.68 86.48,160.06 87.33,160.91 87.33,160.91 87.33,160.92 87.33,162.06 86.79,162.6 86.79,163.84 87.49,164.54 87.49,165.75 88.35,166.61 DIMM2.228
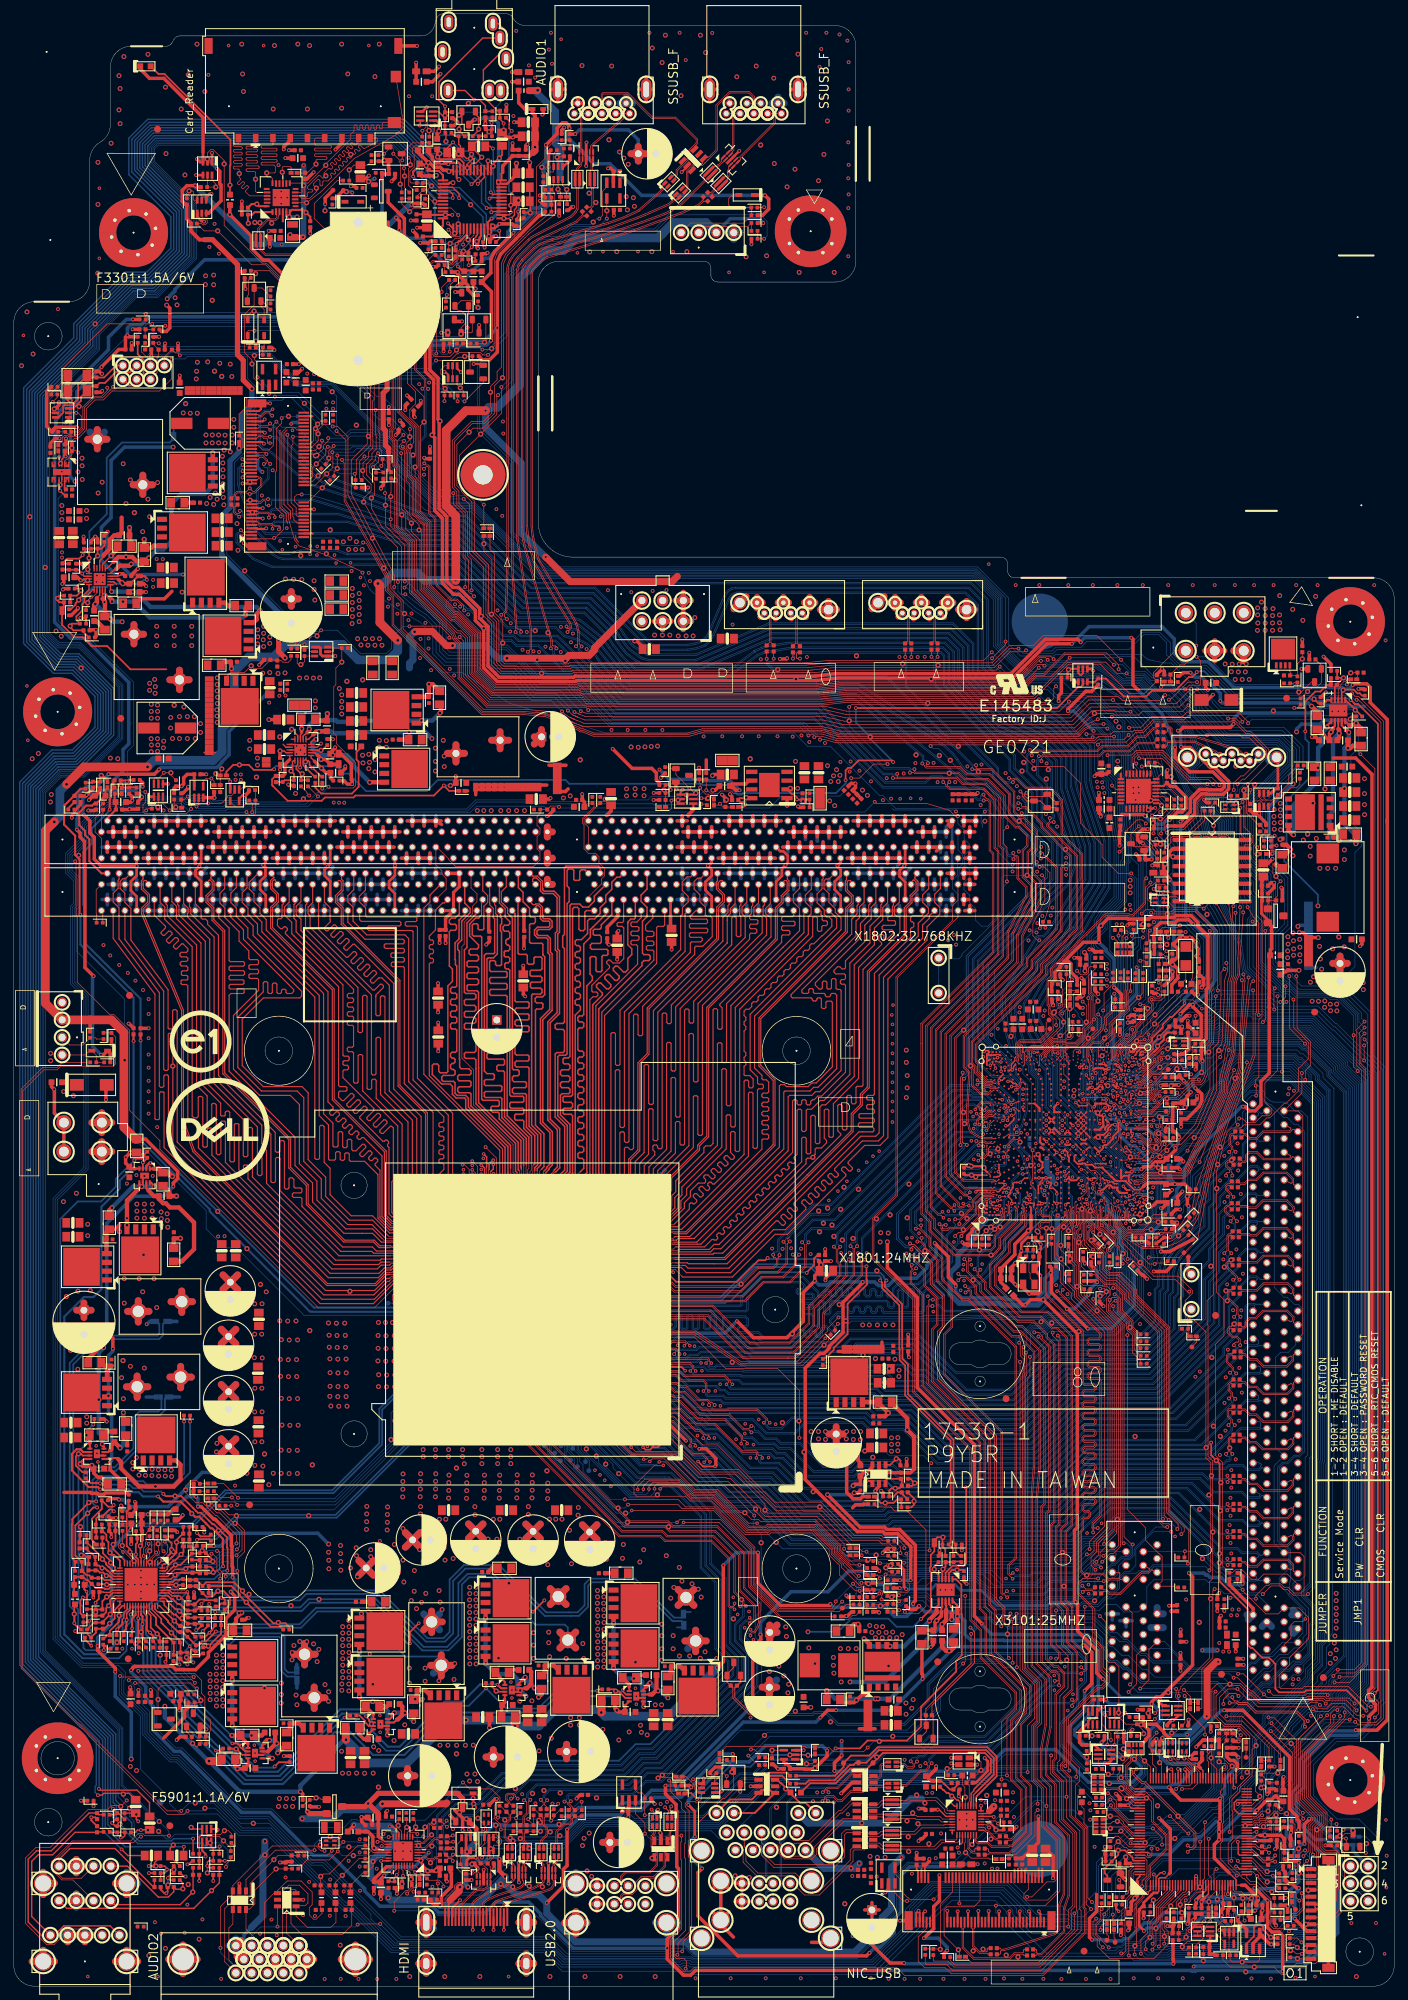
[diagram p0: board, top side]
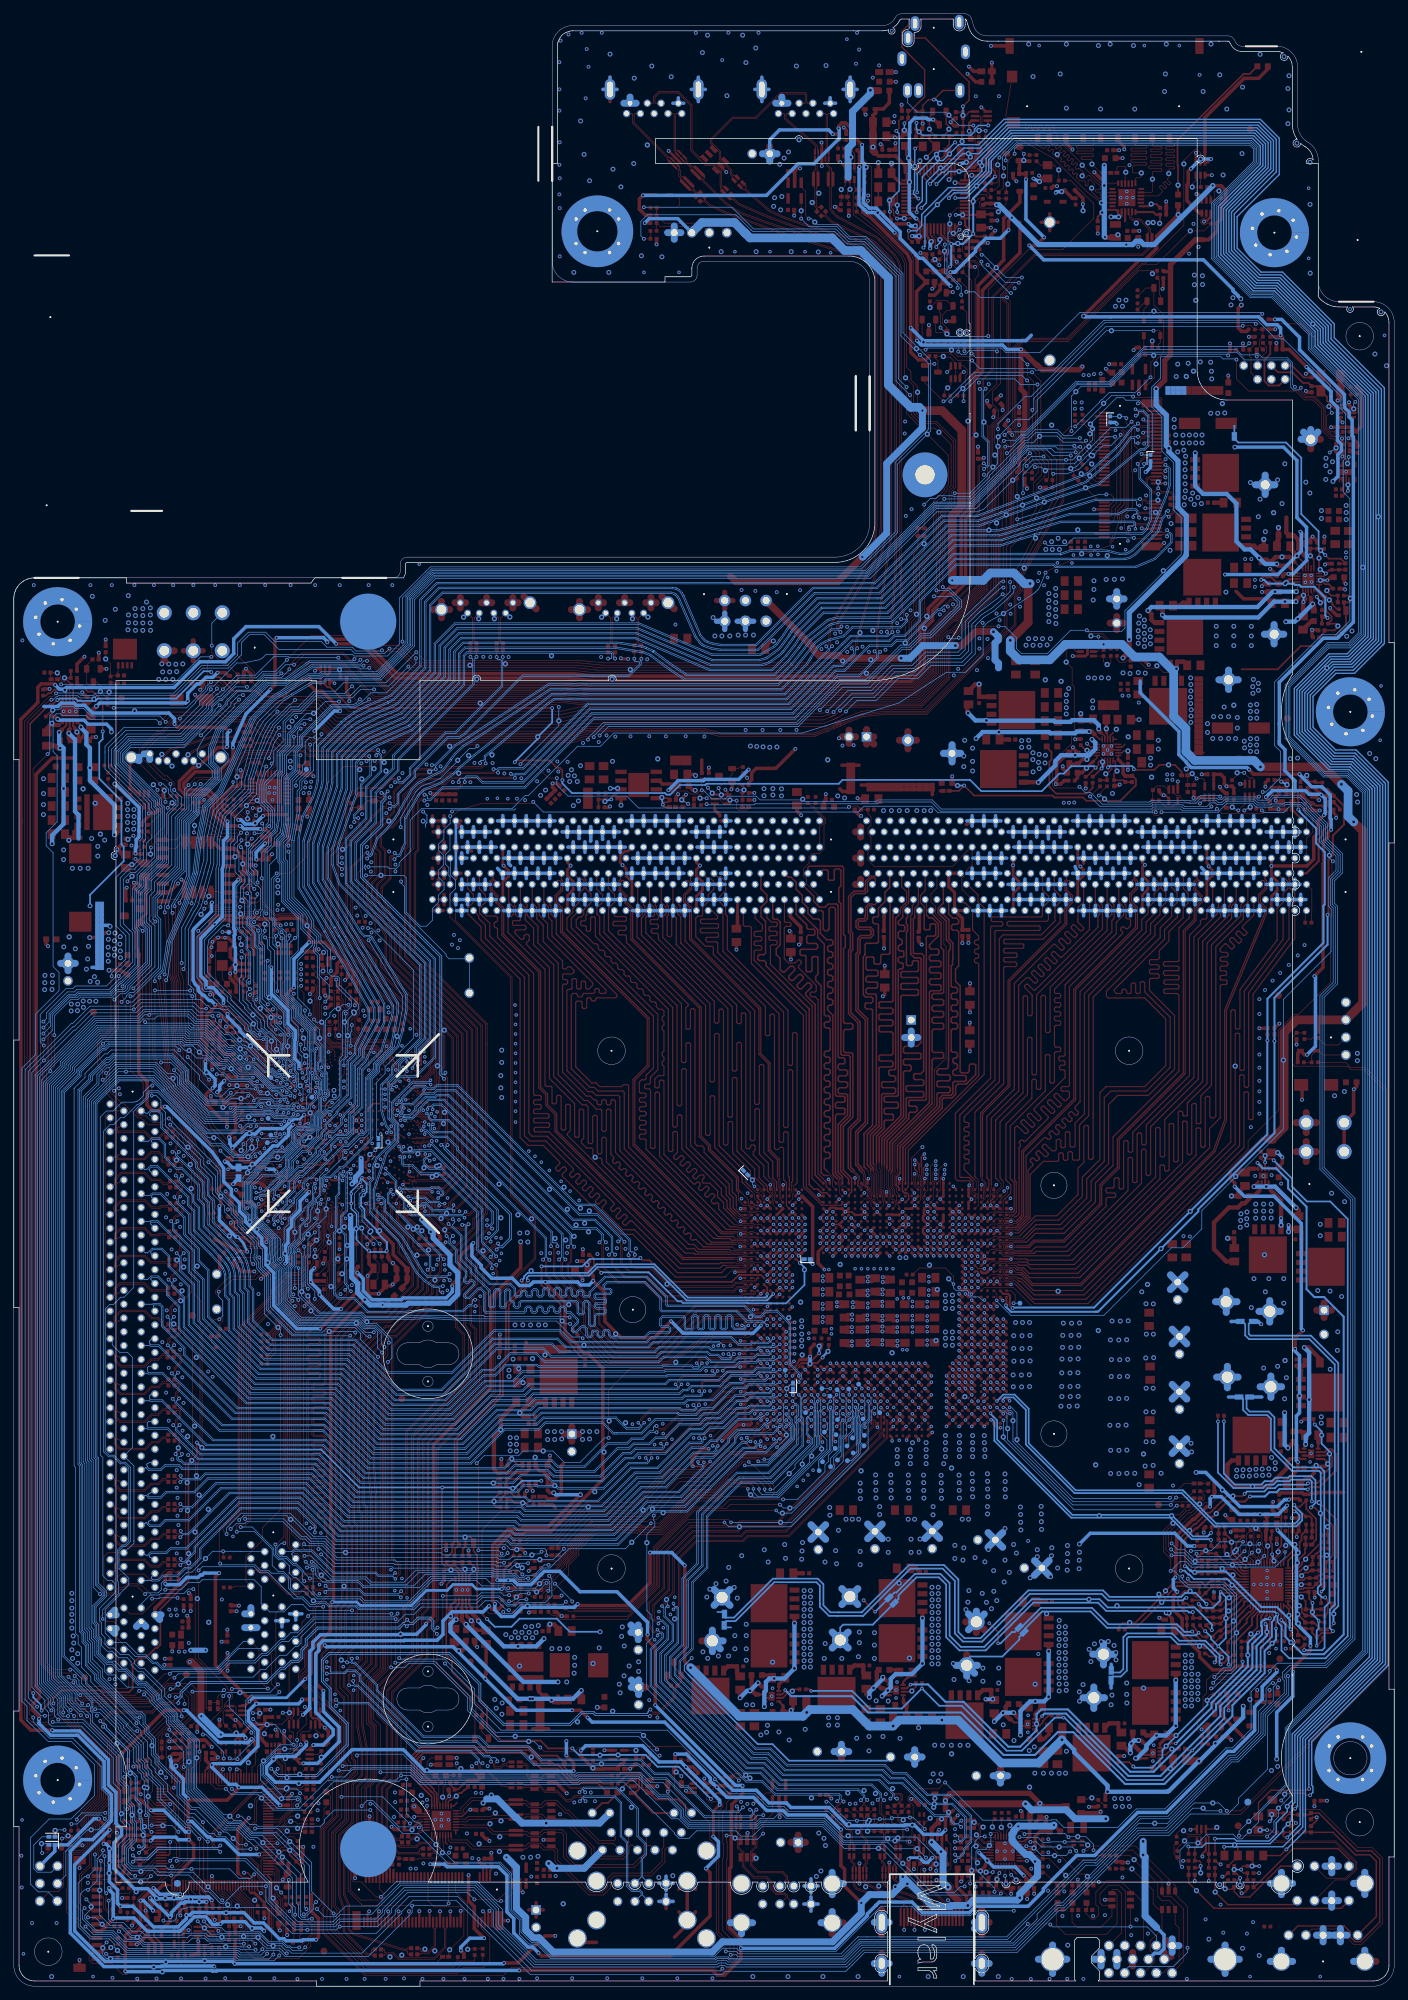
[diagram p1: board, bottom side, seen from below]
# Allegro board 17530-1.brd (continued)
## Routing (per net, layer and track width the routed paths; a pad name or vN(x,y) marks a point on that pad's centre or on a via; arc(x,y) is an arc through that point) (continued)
M_B_A15: length 68.8
  TOP w0.216: v1(78.67,111.28) 78.6,111.28 CPU1.AP16
  L3SGND w0.191: v1(78.67,111.28) 78.67,114.76 80.2,116.29 80.2,118.47 83.85,122.12 83.85,141.25 83.88,141.28 83.88,141.29 91.34,148.74 91.34,149.71 91.15,149.9 90.28,149.9 90.09,150.09 90.09,150.47 90.28,150.66 91.05,150.66 91.24,150.85 91.24,151.23 91.05,151.42 90.28,151.42 90.09,151.61 90.09,151.99 90.28,152.18 91.01,152.18 91.21,152.37 91.21,152.75 91.02,152.94 90.28,152.94 90.09,153.13 90.09,153.52 90.28,153.71 91.02,153.71 91.22,153.9 91.22,154.34 91.06,154.49 89.2,154.49 88.37,155.33 88.37,156.17 89.04,156.84 89.04,158.16 89.04,158.16 89.04,158.41 88.34,159.11 88.34,159.9 89.2,160.77 89.2,161.91 89.9,162.61 89.9,164.07 90.05,164.22 DIMM2.86
M_B_A16: length 69.3
  TOP w0.216: CPU1.AN18 76.33,109.89 v1(76.73,109.49)
  L3SGND w0.089: v1(76.73,109.49) 76.73,110.33 77.34,110.94
  L3SGND w0.191: DIMM2.82 86.65,164.32 86.5,164.18 86.5,163.97 86.5,163.96 86.5,162.49 85.96,161.95 85.96,160.72 85.53,160.29 85.51,160.29 85.11,159.89 85.11,159.1 85.97,158.24 85.97,156.95 85.12,156.1 85.12,155.35 85.44,155.03 85.44,154.44 85.63,154.25 86.28,154.25 86.92,153.62 86.92,152.02 87.11,151.83 87.77,151.83 87.96,151.64 87.96,151.26 87.77,151.07 87.06,151.07 86.87,150.88 86.87,148.99 86.68,148.8 86.41,148.8 86.22,148.61 86.22,148.23 86.41,148.04 87.68,148.04 87.87,147.85 87.87,147.52 87.63,147.28 85.41,147.28 85.22,147.1 85.22,146.63 85.39,146.46 86.04,146.46 86.23,146.27 86.23,145.74 82.4,141.9 82.4,141.9 82.37,141.86 82.37,122.74 78.66,119.03 78.66,116.15 77.55,115.04 77.55,111.16 77.34,110.95 77.34,110.94
M_B_ACT#: length 64.1
  TOP w0.089: CPU1.AU28 66.73,113.96 66.73,115.49 66.59,115.63 66.59,116.57 66.6,116.58 66.6,116.8 v1(66.42,116.98)
  L3SGND w0.191: DIMM2.62 64.07,164.52 63.62,164.52 62.87,163.76 62.87,163 62.03,162.16 62.03,160.84 61.32,160.14 61.32,158.95 60.47,158.1 60.47,156.85 60.98,156.34 60.98,155.5 60.81,155.33 60.81,152.63 61.06,152.38 61.06,149.67 63.28,147.45 63.28,145.01 63.59,144.7 64.89,144.7 65.19,144.4 65.19,143.95 65,143.76 63.42,143.76 63.23,143.57 63.23,143.19 63.42,143 65,143 65.19,142.81 65.19,142.43 65,142.24 63.42,142.24 63.23,142.05 63.23,141.67 63.42,141.48 65,141.48 65.19,141.29 65.19,141.03 65.2,141.02 65.2,128.32 65.77,127.74 65.77,117.59 66.22,117.14 66.26,117.14 66.42,116.98 v1(66.42,116.98)
M_B_ALERT#: length 58.3
  TOP w0.102: CPU1.AY25 69.9,117.46 69.93,117.49 69.93,119.96 v3(68.35,121.54)
  L3SGND w0.102: v3(68.35,121.54) 68.35,121.84 68.94,122.43 68.94,135.68 67.42,137.2 67.42,152.57 64.72,155.27 64.72,156.42 65.25,156.96 65.25,158.18 66.04,158.96 66.04,160.02 66.9,160.88 66.9,162.04 67.78,162.92 67.78,163.82 68.65,164.68 68.65,165.45 67.82,166.28 66.88,166.28 66.25,166.91 DIMM2.208
M_B_BG0: length 63
  TOP w0.089: v1(66.42,118.25) 66.85,117.82 66.85,116.53 66.8,116.48 66.8,115.72 CPU1.AW28
  L3SGND w0.191: v1(66.42,118.25) 66.58,118.41 66.62,118.41 66.9,118.69 66.9,118.79 66.9,118.8 66.9,119.74 66.68,119.96 66.68,128.09 66.08,128.69 66.08,141.39 66.08,141.39 66.08,148.51 65.89,148.7 63.8,148.7 63.61,148.89 63.61,149.27 63.8,149.47 65.89,149.47 66.08,149.66 66.08,150.04 65.89,150.23 63.8,150.23 63.61,150.42 63.61,150.8 63.8,150.99 65.89,150.99 66.08,151.18 66.08,151.62 65.89,151.81 63.49,151.81 61.87,153.43 61.87,154.69 62.7,155.52 62.7,156.28 62.16,156.83 62.16,157.82 63.02,158.68 63.02,159.9 63.86,160.74 63.86,161.7 64.71,162.55 64.71,162.77 65.33,163.4 DIMM2.63
M_B_BG1: length 61.5
  TOP w0.102: CPU1.AY28 67.16,116.3 67.16,118.78 v1(66.42,119.52)
  L3SGND w0.191: v1(66.42,119.52) 66.41,119.52 66.22,119.71 66.22,127.56 66.22,127.56 66.22,127.93 65.64,128.5 65.64,141.2 65.63,141.21 65.63,144.95 65.44,145.14 64.02,145.14 63.83,145.33 63.83,145.71 64.02,145.9 65.24,145.9 65.43,146.09 65.43,146.47 65.24,146.66 64.02,146.66 63.83,146.86 63.83,147.24 64.02,147.43 65.16,147.43 65.35,147.62 65.35,148.07 65.16,148.26 63.62,148.26 63.17,148.71 63.17,151.37 61.32,153.22 61.32,156.31 61.85,156.84 61.85,157.94 62.68,158.77 62.68,159.99 63.53,160.84 63.53,160.91 63.53,160.92 63.53,161.48 63.53,161.49 63.53,161.8 64.4,162.67 64.4,163.6 65.43,164.63 65.43,167.17 DIMM2.207
M_B_BS0: length 70.5
  TOP w0.165: CPU1.AL18 v1(76.75,107.6)
  L3SGND w0.089: v1(76.75,107.6) 76.33,108.02 76.33,109.29 76.3,109.31 76.3,109.67 76.33,109.69 76.33,110.31 77.23,111.21 77.23,111.38
  L3SGND w0.191: DIMM2.81 85.8,162.22 85.65,162.08 85.65,160.85 85.4,160.6 85.39,160.6 84.8,160.01 84.8,158.83 85.64,157.99 85.64,157.11 84.78,156.25 84.78,153.84 84.97,153.65 86.22,153.65 86.44,153.43 86.44,153.08 86.25,152.89 84.97,152.89 84.78,152.7 84.78,152.32 84.97,152.13 86.27,152.13 86.46,151.94 86.46,151.55 86.35,151.44 85.05,151.44 84.78,151.17 84.78,150.79 84.97,150.6 85.73,150.6 85.98,150.36 85.98,150.03 85.79,149.84 84.97,149.84 84.78,149.65 84.78,149.27 84.97,149.08 85.56,149.08 85.75,148.89 85.75,148.51 85.56,148.32 84.97,148.32 84.78,148.13 84.78,144.92 81.95,142.09 81.95,142.08 81.92,142.05 81.92,122.92 78.1,119.1 78.1,118.69 78.11,117.73 77.62,117.25 77.62,115.87 77.23,115.48 77.23,111.38
M_B_BS1: length 71
  TOP w0.165: CPU1.AM18 v1(75.84,108.52)
  L3SGND w0.191: v1(75.84,108.52) 75.84,108.73 75.34,109.23 75.34,109.24 75.34,109.25 75.34,110.41 75.72,110.8 75.72,115.05 76.96,116.29 76.96,117.83 77.22,118.08 77.22,119.47 81.03,123.29 81.03,142.42 81.06,142.45 81.06,142.46 82.96,144.35 82.96,153.46 82.77,153.65 81.72,153.65 81.53,153.84 81.53,154.22 81.72,154.41 82.64,154.41 82.84,154.6 82.84,154.98 82.64,155.17 81.75,155.17 81.56,155.36 81.56,155.75 81.75,155.94 82.77,155.94 83.93,157.1 83.93,157.85 82.96,158.83 82.96,159.2 82.96,159.92 83.95,160.91 83.95,162.06 84.79,162.91 84.79,163.94 84.12,164.6 84.12,165.42 84.95,166.24 DIMM2.224
M_B_CKE0: length 54.7
  TOP w0.102: CPU1.AY29 65.98,116.54 65.98,118.29 65.29,118.99 v1(65.02,118.99)
  L3SGND w0.152: DIMM2.60 62.2,164.35 61.93,164.35 61.31,163.73 61.31,162.53 60.43,161.65 60.43,160.77 60.96,160.23 60.96,159.87 60.96,159.28 60.11,158.43 60.11,156.87 59.64,156.4 59.64,155.19 59.93,154.91 59.93,152.78 60.45,152.26 60.45,149.55 62.66,147.33 62.66,141.16 62.87,140.96 64.52,140.96 64.67,140.8 64.67,137.53 64.67,137.52 64.67,127.91 65.25,127.33 65.25,119.18 65.06,118.99 v1(65.02,118.99)
M_B_CKE1: length 57.4
  TOP w0.089: v1(65.15,117.63) 65.27,117.63 65.76,117.14 65.76,115.32 65.89,115.2 65.89,115.18 66.09,114.97 66.11,114.97 66.24,114.85 CPU1.AV29
  L3SGND w0.152: DIMM2.203 62,164.81 61.01,163.83 61.01,162.99 60.15,162.13 60.15,160.64 59.46,159.95 59.46,158.73 58.6,157.87 58.6,157.06 59.31,156.35 59.31,152.38 59.82,151.87 59.82,149.47 62.16,147.12 62.16,140.95 64.17,138.94 64.17,127.53 64.52,127.18 64.52,118.27 64.69,118.09 64.69,118.08 64.96,117.81 64.97,117.81 v1(65.15,117.63)
M_B_CLK0: length 66.3
  TOP w0.216: v1(74.01,108.52) CPU1.AM20
  L3SGND w0.089: 72.68,111.58 72.68,111.56 72.63,111.5 72.63,110.25 72.92,109.95 73.91,109.29 74.01,109.19 v1(74.01,108.52)
  L3SGND w0.191: DIMM2.74 75.24,164.51 75.93,164.51 76.61,163.84 76.61,162.92 78.39,161.14 78.39,154.31 78.01,153.93 77.1,153.93 76.91,153.74 76.91,153.36 77.1,153.17 78.01,153.17 78.39,152.79 78.39,152.15 78.01,151.77 77.25,151.77 77.06,151.58 77.06,151.2 77.25,151.01 78.01,151.01 78.39,150.64 78.39,124.52 74.11,120.23 74.11,116.31 73.09,115.29 73.09,114.93 73.09,114.93 73.09,114.06 72.68,113.17 72.68,111.58
M_B_CLK1: length 64
  TOP w0.216: CPU1.AP22 v1(73.12,111.22)
  L3SGND w0.191: DIMM2.218 74.93,168.46 74.93,168.1 74.59,167.76 74.59,166.47 75.14,165.93 76.88,165.93 77.23,165.57 77.48,165.29 78.08,164.47 78.36,163.77 78.91,161.53 79,160.9 79.11,159.54 79.11,124.08 76.35,121.32 76.35,121.3 76.31,121.26 76.27,121.22 76.18,121.13 75.75,120.6 75.63,120.41 75.51,120.21 75.37,119.89 75.35,119.85 75,118.59 74.48,115.89 74.44,115.66 74.17,114.93 74.09,114.7 73.91,114.06 73.91,114.04 73.84,113.7 73.84,113.67 73.84,110.9 73.63,110.7 73.45,110.7 73.12,111.03 v1(73.12,111.22)
M_B_CLK#0: length 66.3
  TOP w0.216: CPU1.AM21 v1(73.12,108.55)
  L3SGND w0.089: 72.36,111.58 72.36,111.57 72.44,111.5 72.44,110.17 72.8,109.81 73.79,109.14 73.82,109.12 73.82,109 73.37,108.55 v1(73.12,108.55)
  L3SGND w0.191: DIMM2.75 75.27,163.73 75.27,164 75.46,164.19 75.8,164.19 76.29,163.71 76.29,162.79 78.07,161.01 78.07,154.44 77.88,154.25 76.97,154.25 76.59,153.87 76.59,153.23 76.97,152.85 77.88,152.85 78.07,152.66 78.07,152.28 77.88,152.09 77.12,152.09 76.75,151.72 76.75,151.07 77.12,150.69 77.88,150.69 78.07,150.5 78.07,124.65 77.37,123.95 73.79,120.36 73.79,116.44 72.77,115.43 72.77,115.39 72.77,115.39 72.77,114.8 72.77,114.8 72.77,114.13 72.36,113.24 72.36,111.58
M_B_CLK#1: length 64
  TOP w0.216: CPU1.AP21 v1(73.1,110.38)
  L3SGND w0.191: v1(73.1,110.38) 73.77,110.38 74.16,110.77 74.16,111.03 74.16,111.03 74.16,113.64 74.22,113.98 74.4,114.62 74.75,115.57 75.31,118.53 75.31,118.53 75.66,119.76 75.8,120.08 76.01,120.41 76.42,120.92 76.67,121.17 76.67,121.19 79.43,123.95 79.43,159.54 79.43,159.56 79.32,160.92 79.28,161.2 79.23,161.58 79.22,161.61 78.67,163.85 78.65,163.89 78.37,164.59 78.33,164.66 77.74,165.47 77.72,165.49 77.47,165.78 77.48,165.77 77.01,166.24 75.27,166.24 74.91,166.6 74.91,167.63 75.03,167.75 75.23,167.75 75.35,167.65 75.37,167.64 DIMM2.219
M_B_CS#0: length 62.7
  TOP w0.165: CPU1.AP17 77.21,110.69 77.65,110.25 v1(77.65,110.25)
  L3SGND w0.152: DIMM2.84 88.35,163.12 87.68,162.45 87.68,160.73 86.83,159.88 86.83,159.01 87.69,158.15 87.69,157.04 86.83,156.17 86.83,155.37 89.31,152.89 89.31,147.45 83.36,141.5 83.36,141.5 83.33,141.46 83.33,122.34 79.63,118.63 79.63,116.18 78.15,114.7 78.15,110.75 77.68,110.28 77.68,110.28 v1(77.65,110.25)
M_B_CS#1: length 64.5
  TOP w0.165: v1(79.47,109.49) 79.36,109.49 79.04,109.81 CPU1.AN15
  L3SGND w0.152: DIMM2.89 92.6,160.75 93.42,159.93 93.42,158.58 92.61,157.77 92.61,156.96 93.45,156.12 93.45,155.55 94.08,154.91 94.08,154.64 93.93,154.49 93.73,154.49 93.57,154.34 93.57,154.03 93.73,153.88 93.93,153.88 94.08,153.73 94.08,153.42 93.93,153.27 93.73,153.27 93.57,153.12 93.57,152.81 93.73,152.66 93.93,152.66 94.08,152.51 94.08,152.2 93.93,152.05 93.73,152.05 93.57,151.9 93.57,151.59 93.73,151.44 93.93,151.44 94.08,151.29 94.08,150.98 93.93,150.83 93.73,150.83 93.57,150.68 93.57,150.38 93.73,150.22 93.93,150.22 94.08,150.07 94.08,149.41 85.35,140.68 85.35,140.67 85.32,140.64 85.32,121.51 81.43,117.63 81.43,113.88 80.49,112.94 80.49,110.97 79.47,109.95 v1(79.47,109.49)
M_B_DQ0: length 100.1
  TOP w0.165: CPU1.AE34 v1(61.21,102.11)
  L3SGND w0.089: 16.14,162.72 16.07,162.76 arc(15.59,163.79) 16.71,163.59 16.64,163.49 DIMM2.5
  L3SGND w0.102: 16.14,162.72 16.16,162.64 16.16,162.42
  L3SGND w0.152: v1(61.21,102.11) 60.75,101.66 60.05,101.66 59.74,101.35 56.9,101.35 56.13,102.11 54.1,102.11 53.03,101.04 44.83,101.04 32.83,113.04 30.67,116.51 28.04,120.56 26.3,123.45 24,127.22 24,146.91 21.73,149.18 21.73,149.4 22.01,149.67 22.01,149.89 21.76,150.14 21.54,150.14 21.15,149.75 20.97,149.75 20.68,150.03 20.68,150.21 21.07,150.61 21.07,150.82 20.82,151.08 20.61,151.08 20.33,150.8 20.12,150.8 19.87,151.05 19.87,151.27 20.14,151.54 20.14,151.76 19.89,152.01 19.67,152.01 19.4,151.73 19.18,151.73 18.93,151.99 18.93,152.2 19.17,152.44 19.17,152.66 18.92,152.91 18.71,152.91 18.46,152.67 18.25,152.67 18,152.92 18,153.14 18.24,153.38 18.24,153.59 17.99,153.84 17.77,153.84 17.53,153.6 17.31,153.6 17.06,153.85 17.06,154.07 17.34,154.35 17.34,154.56 16.97,154.93 16.97,155.91 16.82,156.2 16.33,156.84 16.21,157.02 16.01,157.76 15.27,159.23 15.27,160.01 16.1,160.84 16.1,162.36 16.16,162.42
M_B_DQ1: length 98.9
  TOP w0.165: CPU1.AE35 v1(60.29,102.11)
  L3SGND w0.089: 16.99,168.12 16.92,168.16 arc(16.44,169.19) 17.56,168.99 17.49,168.89 DIMM2.150
  L3SGND w0.102: 16.99,168.12 17.01,168.04 17.01,167.82
  L3SGND w0.152: v1(60.29,102.11) 60.05,102.11 59.6,101.66 57.22,101.66 56.49,102.39 53.85,102.39 53.15,101.69 45.1,101.69 33.6,113.18 32.71,114.55 32.71,114.55 32.01,115.64 31.3,116.72 31.16,116.95 31.16,116.95 30.45,118.03 30.45,118.04 28.59,120.91 24.79,127.22 24.65,127.5 24.65,148.16 19.57,153.24 19.57,154.63 19.46,154.75 18.82,154.75 18.67,154.9 18.67,156.22 17.81,157.08 17.81,158.05 16.99,158.86 16.99,160.08 17.81,160.89 17.81,161.53 17.02,162.32 17.02,163.76 16.08,164.7 16.08,165.72 17.01,166.65 17.01,167.82
M_B_DQ2: length 98.9
  TOP w0.165: CPU1.AH34 v1(61.21,104.86)
  L3SGND w0.089: DIMM2.12 22.59,165.09 22.66,165.19 arc(21.54,165.39) 22.02,164.36 22.09,164.32
  L3SGND w0.102: 22.09,164.32 22.11,164.24 22.11,164.02
  L3SGND w0.152: 22.11,164.02 21.86,163.77 21.86,162.54 22.71,161.7 22.71,161.48 22.71,161.47 22.71,160.72 23.56,159.87 23.56,158.79 22.89,158.11 22.89,156.98 23.72,156.14 23.72,155.36 27.52,151.56 27.52,129.81 27.93,129.39 27.93,129.1 27.59,128.76 27.59,128.54 27.84,128.3 28.05,128.3 28.43,128.68 28.65,128.68 28.9,128.42 28.9,128.21 28.52,127.83 28.52,127.61 28.76,127.37 28.98,127.37 29.36,127.75 29.58,127.75 29.82,127.51 29.82,127.29 29.44,126.91 29.44,126.7 29.68,126.45 29.9,126.45 30.28,126.83 30.49,126.83 30.74,126.59 30.74,126.38 30.35,125.99 30.35,125.78 30.6,125.54 30.81,125.54 31.19,125.92 31.41,125.92 31.65,125.67 31.65,125.46 31.27,125.08 31.27,124.86 31.51,124.62 31.73,124.62 32.11,125 32.33,125 32.57,124.76 32.57,124.54 32.19,124.16 32.19,123.95 32.43,123.7 32.65,123.7 33.03,124.08 33.24,124.08 33.48,123.84 33.48,123.63 33.1,123.25 33.1,123.03 33.35,122.79 33.56,122.79 33.78,123.01 33.96,123.01 34.24,122.73 34.24,122.55 34.02,122.33 34.02,122.11 34.64,121.5 36.49,118.04 36.49,114.36 46.28,104.56 52.6,104.56 52.79,104.75 58.85,104.75 59.2,104.4 60.75,104.4 v1(61.21,104.86)
M_B_DQ3: length 98
  TOP w0.165: CPU1.AH35 v1(60.29,104.86)
  L3SGND w0.089: DIMM2.157 23.44,167.29 23.51,167.39 arc(22.39,167.59) 22.87,166.56 22.94,166.52 ; 58.6,105.56 58.84,105.32 59.83,105.32 v1(60.29,104.86)
  L3SGND w0.102: 22.96,166.22 22.96,166.44 22.94,166.52
  L3SGND w0.152: 22.96,166.22 22.96,165.8 22.88,165.72 22.88,164.31 22.24,163.67 22.24,162.98 23.09,162.13 23.09,160.93 23.94,160.08 23.94,158.79 24.61,158.11 24.61,156.88 25.4,156.09 25.4,154.6 28.17,151.83 28.17,130.07 35.28,122.96 35.28,121.77 35.66,121.39 36.93,121.39 37.06,121.26 37.06,120.85 36.93,120.73 36.22,120.73 36.04,120.55 36.04,120.24 36.1,120.13 36.23,120.01 37.59,120.01 37.72,119.88 37.72,119.46 37.59,119.34 36.94,119.34 36.8,119.2 36.8,118.82 36.81,118.81 36.93,118.69 37.74,118.69 37.95,118.49 37.95,118.14 37.8,117.99 37.33,117.99 37.19,117.85 37.19,117.5 37.34,117.34 37.74,117.34 37.9,117.19 37.9,116.85 37.74,116.7 37.27,116.7 37.16,116.58 37.16,116.2 37.31,116.05 37.74,116.05 37.9,115.9 37.9,115.55 37.74,115.4 37.34,115.4 37.19,115.25 37.19,114.9 37.34,114.75 37.74,114.75 37.9,114.6 37.9,113.86 46.55,105.21 54.51,105.21 54.84,105.54 55.09,105.54 55.33,105.77 58.39,105.77 58.6,105.56
M_B_DQ4: length 100
  TOP w0.165: CPU1.AD34 v1(61.21,101.2)
  L3SGND w0.089: DIMM2.3 14.94,163.49 15.01,163.59 arc(13.89,163.79) 14.37,162.76 14.44,162.72
  L3SGND w0.102: 14.46,162.42 14.46,162.64 14.44,162.72
  L3SGND w0.152: 14.46,162.42 14.37,162.32 13.32,162.32 12.69,161.69 12.69,160.83 13.36,160.16 13.36,158.9 12.84,158.38 12.84,156.89 13.54,156.2 13.54,155.22 22.71,140.67 22.71,126.63 23.64,125.16 23.58,124.9 23.12,124.61 23.07,124.4 23.26,124.1 23.47,124.06 23.93,124.35 24.19,124.29 24.33,124.06 24.27,123.8 23.82,123.52 23.78,123.31 23.97,123.01 24.16,122.96 24.62,123.25 24.88,123.2 25.6,122.06 25.98,121.47 26.94,119.88 28.55,117.4 30.83,113.79 31.81,112.23 44.29,99.75 53.52,99.75 54.23,100.46 55.15,100.46 55.42,100.73 60.73,100.73 v1(61.21,101.2)
M_B_DQ5: length 99.2
  TOP w0.165: CPU1.AD35 v1(60.29,101.2)
  L3SGND w0.089: 15.29,168.12 15.22,168.16 arc(14.74,169.19) 15.86,168.99 15.79,168.89 DIMM2.148
  L3SGND w0.102: 15.31,167.82 15.31,168.04 15.29,168.12
  L3SGND w0.152: v1(60.29,101.2) 60.11,101.02 53.95,101.02 53.33,100.39 44.56,100.39 32.32,112.63 30.12,116.17 27.49,120.22 25.89,122.87 23.35,126.82 23.35,140.94 15.24,155.3 15.24,155.96 15.04,156.39 14.6,156.84 14.43,157.23 14.33,157.73 13.72,159.13 13.72,159.31 13.71,159.32 13.71,159.88 13.72,159.89 13.72,160.02 13.85,160.21 14.31,160.87 14.49,161.52 15.23,163.04 15.23,163.83 14.38,164.68 14.38,165.48 15.31,167 15.31,167.82
M_B_DQ6: length 99.4
  TOP w0.165: v1(61.21,103.94) CPU1.AG34
  L3SGND w0.089: DIMM2.10 20.89,165.09 20.96,165.19 arc(19.84,165.39) 20.32,164.36 20.39,164.32
  L3SGND w0.102: 20.41,164.12 20.41,164.24 20.39,164.32
  L3SGND w0.152: v1(61.21,103.94) 60.05,103.94 59.59,103.48 57.68,103.48 57.15,104.01 53.37,104.01 52.62,103.26 45.75,103.26 35.19,113.82 35.19,116.83 33,119.02 33,119.23 33.51,119.74 33.51,119.96 33.25,120.22 33.03,120.22 32.41,119.6 32.19,119.6 31.95,119.84 31.95,120.05 32.9,121.01 32.9,121.22 32.66,121.47 32.45,121.47 32.07,121.09 31.89,121.09 31.61,121.37 31.61,121.55 32.02,121.96 32.02,122.18 28.94,125.26 26.23,127.98 26.23,150.43 25.87,150.79 25.69,150.79 25.07,150.18 24.87,150.18 22.15,152.89 22.15,153.93 22,154.09 21.3,154.09 21.15,154.24 21.15,154.66 21.31,154.82 21.69,154.82 21.84,154.98 21.84,155.51 21.86,155.53 21.86,156.15 21.01,157 21.01,158.27 20.29,158.99 20.29,159.98 21.01,160.69 21.01,160.92 21.01,160.93 21.01,161.47 21.01,161.48 21.01,161.8 20.17,162.64 20.17,163.88 20.41,164.12
M_B_DQ7: length 98.6
  TOP w0.165: v1(59.39,103.94) 60.2,103.94 60.21,103.96 60.31,103.96 CPU1.AG35
  L3SGND w0.089: 21.24,166.52 21.17,166.56 arc(20.69,167.59) 21.81,167.39 21.74,167.29 DIMM2.155
  L3SGND w0.102: 21.24,166.52 21.26,166.44 21.26,166.22
  L3SGND w0.152: v1(59.39,103.94) 59.12,103.94 58.65,104.4 53.11,104.4 52.62,103.91 46.02,103.91 35.84,114.09 35.84,117.88 34.14,121.05 26.87,128.32 26.87,150.83 25.93,151.77 25.75,151.77 25.09,151.11 24.87,151.11 24.63,151.35 24.63,151.57 25.31,152.24 25.31,152.42 25.04,152.68 24.83,152.68 24.17,152.02 23.96,152.02 23.72,152.27 23.72,152.48 24.26,153.03 24.26,153.28 24.06,153.49 23.8,153.49 23.26,152.94 23.04,152.94 22.8,153.18 22.8,153.4 23.35,153.95 23.35,154.16 22.25,155.26 22.25,155.52 22.24,155.53 22.24,156.2 21.41,157.03 21.41,157.1 21.39,157.13 21.39,157.98 22.05,158.63 22.05,160.04 21.39,160.7 21.39,162.03 20.54,162.87 20.54,163.76 21.18,164.4 21.18,165.68 21.26,165.76 21.26,166.22
M_B_DQ8: length 87.7
  TOP w0.165: CPU1.AL34 61.37,108.06 61.21,107.89 v1(61.21,107.58)
  L3SGND w0.089: 25.49,164.32 25.42,164.36 arc(24.94,165.39) 26.06,165.19 25.99,165.09 DIMM2.16
  L3SGND w0.102: 25.49,164.32 25.51,164.24 25.51,164.02
  L3SGND w0.152: 25.51,164.02 25.27,163.78 25.27,162.43 26.11,161.6 26.11,160.8 26.96,159.95 26.96,158.69 27.81,157.84 27.81,156.92 28.66,156.07 28.66,154.66 30.21,153.11 30.21,133.17 30.21,131.93 37.14,125 37.35,125 37.7,125.35 37.92,125.35 38.16,125.11 38.16,124.9 37.81,124.55 37.81,124.33 38.05,124.09 38.27,124.09 38.64,124.46 38.86,124.46 39.1,124.22 39.1,124.01 38.73,123.63 38.73,123.41 40.04,122.1 40.04,114.55 46.48,108.11 51.17,108.11 52.14,107.14 54.41,107.14 54.86,106.69 55.71,106.69 55.8,106.78 59.66,106.78 60,107.12 60.75,107.12 v1(61.21,107.58)
M_B_DQ9: length 87.1
  TOP w0.165: CPU1.AL35 60.29,107.6 v1(60.29,107.58)
  L3SGND w0.089: DIMM2.161 26.84,167.29 26.91,167.39 arc(25.79,167.59) 26.27,166.56 26.34,166.52
  L3SGND w0.102: 26.36,166.22 26.36,166.44 26.34,166.52
  L3SGND w0.152: v1(60.29,107.58) 60.03,107.58 59.57,107.12 57.32,107.12 56.84,107.6 54.78,107.6 54.51,107.87 52.32,107.87 51.44,108.76 46.75,108.76 40.69,114.82 40.69,125.35 39.87,126.17 37.06,126.17 30.86,132.37 30.86,132.91 30.86,153.38 29.04,155.2 29.04,156.28 28.19,157.13 28.19,158.12 27.33,158.98 27.33,160.09 26.49,160.93 26.49,161.92 25.64,162.77 25.64,163.67 26.36,164.4 26.36,166.22
M_B_DQ10: length 90.3
  TOP w0.165: CPU1.AK31 v1(64.87,106.69)
  L3SGND w0.089: DIMM2.23 31.94,163.49 32.01,163.59 arc(30.89,163.79) 31.37,162.76 31.44,162.72 ; v1(64.87,106.69) 64.41,107.15 64.41,107.81 64.12,108.09 63.78,108.09 63.15,108.71 61.93,108.71 61.62,109.03 61.16,109.03 61.16,109.03 60.13,109.03 59.81,109.36 59.81,109.68 59.66,109.82
  L3SGND w0.102: 31.44,162.72 31.46,162.64 31.46,162.42
  L3SGND w0.152: 59.66,109.82 59.55,109.93 57.94,109.93 57.84,110.03 54.53,110.03 52.91,111.66 48.13,111.66 48.12,111.67 47.9,111.67 43.56,116.01 43.56,140.12 39.89,143.79 35.97,143.79 35.81,143.94 35.81,144.37 35.97,144.52 37.34,144.52 37.5,144.67 37.5,145 37.33,145.17 34.52,145.17 34.37,145.32 34.37,145.66 34.52,145.82 35.38,145.82 35.53,145.97 35.53,146.31 35.38,146.46 33.93,146.46 33.76,146.64 33.76,156.1 32.91,156.95 32.91,158.1 32.06,158.95 32.06,159.89 31.22,160.73 31.22,161.98 31.46,162.22 31.46,162.42
M_B_DQ11: length 89.6
  TOP w0.165: CPU1.AL31 v1(63.95,108.52)
  L3SGND w0.089: 32.29,168.12 32.22,168.16 arc(31.74,169.19) 32.86,168.99 32.79,168.89 DIMM2.168 ; 58.96,110.24 59.8,110.24 60.12,109.92 61.36,109.92 61.69,109.58 61.69,109.38 61.74,109.32 61.74,109.31 61.99,109.07 62,109.07 62.05,109.02 63.44,109.02 v1(63.95,108.52)
  L3SGND w0.102: 32.31,167.82 32.31,168.04 32.29,168.12
  L3SGND w0.152: 32.31,167.82 32.31,166.38 31.42,165.49 31.42,164.68 32.23,163.87 32.23,162.2 31.59,161.56 31.59,160.93 32.44,160.08 32.44,159.33 33.29,158.48 33.29,157.13 34.14,156.28 34.14,155.22 34.57,154.79 34.57,148.93 38.9,144.6 40,144.6 44.21,140.39 44.21,121.18 44.36,121.03 45.11,121.03 45.26,120.88 45.26,120.54 45.11,120.38 44.36,120.38 44.21,120.23 44.21,119.89 44.36,119.74 45.19,119.74 45.34,119.58 45.34,119.24 45.19,119.09 44.36,119.09 44.21,118.94 44.21,116.28 48.17,112.32 53.04,112.32 54.99,110.36 55.31,110.36 55.33,110.34 55.71,110.34 55.73,110.36 57.9,110.36 58.02,110.24 58.96,110.24
M_B_DQ12: length 88.6
  TOP w0.165: CPU1.AK34 v1(62.12,106.69)
  L3SGND w0.089: DIMM2.14 24.29,165.09 24.36,165.19 arc(23.24,165.39) 23.72,164.36 23.79,164.32
  L3SGND w0.102: 23.81,164.02 23.81,164.24 23.79,164.32
  L3SGND w0.152: v1(62.12,106.69) 61.67,106.23 60.51,106.23 60.48,106.2 59.19,106.2 59.03,106.04 50.95,106.04 50.75,106.25 50.75,106.58 50.59,106.73 50.25,106.73 50.1,106.58 50.1,106.45 49.95,106.3 49.6,106.3 49.45,106.45 49.45,106.65 49.3,106.81 45.95,106.81 38.75,114.01 38.75,121.25 28.92,131.08 28.92,131.56 28.92,133.71 28.92,133.71 28.92,152.55 26.96,154.51 26.96,156.07 26.92,156.11 26.92,156.15 26.11,156.96 26.11,157.67 25.29,158.5 25.29,159.96 24.41,160.84 24.41,161.47 24.41,161.72 23.57,162.56 23.57,163.78 23.81,164.02
M_B_DQ13: length 87.6
  TOP w0.165: CPU1.AK35 60.75,106.95 60.46,106.66 v1(60.29,106.66)
  L3SGND w0.089: 24.64,166.52 24.57,166.56 arc(24.09,167.59) 25.21,167.39 25.14,167.29 DIMM2.159
  L3SGND w0.102: 24.66,166.22 24.66,166.44 24.64,166.52
  L3SGND w0.152: v1(60.29,106.66) 59.93,106.66 59.78,106.51 59.11,106.51 58.98,106.38 51.99,106.38 50.9,107.47 46.21,107.47 39.4,114.28 39.4,121.52 29.57,131.35 29.57,131.83 29.57,152.82 27.34,155.04 27.34,156.13 26.49,156.97 26.49,157.12 26.49,157.13 26.49,157.67 26.49,157.68 26.49,158 25.63,158.87 25.63,160.09 24.79,160.93 24.79,162.13 23.94,162.98 23.94,163.67 24.58,164.31 24.58,165.71 24.66,165.79 24.66,166.22
M_B_DQ14: length 90.1
  TOP w0.165: CPU1.AK32 v1(63.95,106.69)
  L3SGND w0.089: 61.45,108.52 61.53,108.52 62.03,108.03 63.25,108.03 63.48,107.8 63.48,107.48 v1(63.95,106.69) ; 29.74,162.72 29.67,162.76 arc(29.19,163.79) 30.31,163.59 30.24,163.49 DIMM2.21
  L3SGND w0.102: 29.74,162.72 29.76,162.64 29.76,162.42
  L3SGND w0.152: 61.45,108.52 57.45,108.52 57.41,108.56 57.38,108.56 56.49,109.45 53.47,109.45 52.58,110.34 47.4,110.34 42.27,115.47 42.27,126.74 41.25,127.76 40.05,127.76 39.8,128.02 39.8,129.21 39.6,129.41 39.3,129.41 39.15,129.26 39.15,127.99 39,127.84 38.65,127.84 38.5,127.99 38.5,129.26 38.35,129.41 38.01,129.41 37.85,129.26 37.85,128.27 37.7,128.12 37.38,128.12 37.21,128.3 37.21,129.26 37.05,129.41 36.37,129.41 32.44,133.35 32.44,154.37 32.06,154.74 32.06,156.2 31.21,157.05 31.21,157.67 30.36,158.52 30.36,159.94 29.51,160.78 29.51,162.17 29.76,162.42
M_B_DQ15: length 89.3
  TOP w0.165: CPU1.AL32 63.49,108.03 v1(63.94,107.59)
  L3SGND w0.089: v1(63.94,107.59) 63.94,107.63 63.2,108.37 61.98,108.37 61.73,108.61 61.73,108.62 61.56,108.79 61.06,108.79 ; 30.59,168.12 30.52,168.16 arc(30.04,169.19) 31.16,168.99 31.09,168.89 DIMM2.166
  L3SGND w0.102: 30.61,167.82 30.61,168.04 30.59,168.12
  L3SGND w0.152: 61.06,108.79 57.56,108.79 56.62,109.73 54.05,109.73 52.77,111.01 47.64,111.01 42.91,115.74 42.91,127.01 39.87,130.06 36.64,130.06 33.08,133.62 33.08,154.64 32.7,155.01 32.67,155.01 32.44,155.24 32.44,156.28 31.59,157.13 31.59,157.76 30.74,158.61 30.74,160.08 29.89,160.93 29.89,161.95 30.53,162.59 30.53,163.87 29.67,164.73 29.67,165.59 30.61,166.54 30.61,167.82
M_B_DQ16: length 75.9
  TOP w0.165: CPU1.AP35 v1(60.29,111.26)
  L3SGND w0.089: 34.84,162.72 34.77,162.76 arc(34.29,163.79) 35.41,163.59 35.34,163.49 DIMM2.27
  L3SGND w0.102: 34.84,162.72 34.86,162.64 34.86,162.42
  L3SGND w0.152: 34.86,162.42 34.61,162.17 34.61,160.79 35.46,159.94 35.46,158.52 36.31,157.67 36.31,157.02 37.16,156.17 37.16,156.07 37.16,155.33 36.96,155.13 36.96,149.81 39.87,146.9 40.74,146.9 46.47,141.17 46.47,127.92 46.62,127.77 47.73,127.77 47.88,127.62 47.88,127.27 47.73,127.12 46.55,127.12 46.39,126.97 46.39,126.63 46.55,126.47 47.98,126.47 48.13,126.32 48.13,125.98 47.98,125.83 46.61,125.83 46.46,125.67 46.46,125.3 46.61,125.15 48,125.15 48.16,124.99 48.16,124.61 53.75,119.02 53.75,113.72 55.32,112.14 56.01,112.14 56.41,111.74 57.24,111.74 59.81,111.74 v1(60.29,111.26)
M_B_DQ17: length 77.8
  TOP w0.165: CPU1.AN34 62.05,109.52 62.14,109.52 v1(62.17,109.49)
  L3SGND w0.089: v1(62.17,109.49) 62.17,109.7 61.68,110.19 61.68,110.5 61.63,110.54 61.63,110.55 61.38,110.8 61.08,110.8 61.05,110.83 61.03,110.83 60.78,111.09 60.78,111.38 60.14,112.01 58.65,112.01 ; 35.69,168.12 35.62,168.16 arc(35.14,169.19) 36.26,168.99 36.19,168.89 DIMM2.172
  L3SGND w0.102: 35.69,168.12 35.71,168.04 35.71,167.82
  L3SGND w0.152: 35.71,167.82 35.71,166.51 34.82,165.62 34.82,164.65 35.69,163.79 35.69,162.67 34.98,161.96 34.98,160.89 35.84,160.02 35.84,158.61 36.69,157.76 36.69,157.13 37.54,156.28 37.54,155.33 37.6,155.27 37.6,150.08 40.13,147.55 41.01,147.55 47.12,141.44 47.12,129.31 48.81,127.62 48.81,124.88 54.28,119.41 54.28,114.53 56.79,112.01 58.65,112.01
M_B_DQ18: length 80.2
  TOP w0.165: CPU1.AN31 v1(63.95,110.34)
  L3SGND w0.089: v1(63.95,110.34) 63.47,110.83 63.47,111.51 63.21,111.77 62.86,111.77 62.58,112.06 62.58,112.28 62.26,112.59 ; 40.79,164.32 40.72,164.36 arc(40.24,165.39) 41.36,165.19 41.29,165.09 DIMM2.34
  L3SGND w0.102: 40.79,164.32 40.81,164.24 40.81,164.02
  L3SGND w0.152: 62.26,112.59 61.62,113.24 60.85,113.24 58.19,115.9 58.19,116.23 56.97,117.45 56.97,121.01 56.08,121.89 56.08,122.12 56.74,122.78 56.74,122.99 56.46,123.27 56.24,123.27 55.53,122.56 55.34,122.56 55.07,122.83 55.07,123.02 55.8,123.74 55.8,123.98 55.57,124.21 55.35,124.21 54.69,123.55 54.45,123.55 54.22,123.78 54.22,124 54.86,124.63 54.86,124.85 54.63,125.08 54.38,125.08 53.77,124.47 53.48,124.47 53.28,124.67 53.28,124.89 53.96,125.58 53.96,125.79 53.72,126.03 53.51,126.03 53.26,125.79 53.02,125.79 52.81,126.01 52.81,126.25 53.11,126.56 53.11,126.77 52.87,127.01 52.65,127.01 52.26,126.62 52.02,126.62 51.79,126.85 51.79,127.07 52.07,127.34 52.07,127.69 51.68,128.08 51.68,140.94 42.17,150.46 41.44,150.46 40.87,151.03 40.87,154.41 41.45,154.99 41.88,154.99 42.27,155.37 42.27,156.2 41.41,157.06 41.41,157.95 40.56,158.8 40.56,160.16 40.09,160.63 40.09,162.12 40.56,162.59 40.56,163.77 40.81,164.02
M_B_DQ19: length 79.3
  TOP w0.165: CPU1.AP31 v1(63.95,111.26)
  L3SGND w0.089: 62.2,113.22 62.8,112.62 63.21,112.62 63.52,112.32 63.52,112 63.95,111.56 v1(63.95,111.26) ; DIMM2.179 42.14,167.29 42.21,167.39 arc(41.09,167.59) 41.57,166.56 41.64,166.52
  L3SGND w0.102: 41.66,166.22 41.66,166.44 41.64,166.52
  L3SGND w0.152: 41.66,166.22 41.66,165.92 41.58,165.84 41.58,164.35 40.94,163.71 40.94,162.42 41.41,161.95 41.41,160.65 40.94,160.18 40.94,159.88 40.94,159.87 40.94,159.33 40.94,159.32 40.94,159.11 41.79,158.26 41.79,157.13 42.64,156.28 42.64,155.14 42.79,154.99 43.1,154.99 43.26,154.84 43.26,154.51 43.09,154.34 41.83,154.34 41.68,154.19 41.68,153.85 41.83,153.69 43.07,153.69 43.21,153.55 43.21,153.19 43.07,153.05 41.69,153.05 41.55,152.91 41.55,152.63 41.78,152.4 43.1,152.4 43.26,152.25 43.26,151.9 43.1,151.75 41.73,151.75 41.58,151.6 41.58,151.26 41.73,151.1 43.1,151.1 43.26,150.95 43.26,150.28 52.32,141.21 52.32,128.52 57.64,123.21 57.64,117.57 58.65,116.56 58.65,115.94 61.08,113.51 61.91,113.51 62.2,113.22
M_B_DQ20: length 77.1
  TOP w0.165: CPU1.AN35 v1(60.29,110.34)
  L3SGND w0.089: DIMM2.25 33.64,163.49 33.71,163.59 arc(32.59,163.79) 33.07,162.76 33.14,162.72
  L3SGND w0.102: 33.14,162.72 33.16,162.64 33.16,162.42
  L3SGND w0.152: v1(60.29,110.34) 60.11,110.53 58.11,110.53 57.87,110.77 56.24,110.77 55.63,111.38 54.94,111.38 52.76,113.56 52.76,118.16 51.41,119.51 51.41,119.51 49.76,121.16 46.75,121.16 46.59,121.31 46.59,121.65 46.75,121.8 48.46,121.8 48.62,121.96 48.62,122.3 48.46,122.45 46.41,122.45 46.25,122.6 46.25,123.59 46.1,123.75 45.4,123.75 45.1,124.05 45.1,140.71 40.21,145.6 39.33,145.6 35.51,149.42 35.51,156.09 34.61,157 34.61,157.77 33.76,158.62 33.76,159.91 32.91,160.77 32.91,162.17 33.16,162.42
M_B_DQ21: length 77.3
  TOP w0.165: CPU1.AP34 v1(61.21,110.37)
  L3SGND w0.089: DIMM2.170 34.01,168.81 33.92,168.16 33.99,168.12
  L3SGND w0.102: 34.01,167.82 34.01,168.04 33.99,168.12
  L3SGND w0.152: v1(61.21,110.37) 61.05,110.37 60.62,110.8 58.23,110.8 57.76,111.26 56.25,111.26 55.75,111.76 55.17,111.76 53.24,113.69 53.24,118.6 48.7,123.14 47.14,123.14 46.99,123.29 46.99,123.65 47.14,123.8 47.4,123.8 47.55,123.95 47.55,124.29 47.4,124.45 45.97,124.45 45.75,124.67 45.75,140.98 40.48,146.25 39.6,146.25 36.31,149.54 36.31,154.88 35.84,155.35 35.84,156.16 34.95,157.05 34.95,158.37 34.14,159.18 34.14,160.07 33.29,160.92 33.29,161.81 33.93,162.45 33.93,163.87 33.1,164.7 33.1,165.72 34.01,166.64 34.01,167.82
M_B_DQ22: length 79.4
  TOP w0.165: CPU1.AN32 v1(63.04,110.34)
  L3SGND w0.089: v1(63.04,110.34) 62.58,110.8 62.58,111.4 62.3,111.68 62.26,111.68 62.04,111.9 ; DIMM2.32 39.59,165.09 39.66,165.19 arc(38.54,165.39) 39.02,164.36 39.09,164.32
  L3SGND w0.102: 39.09,164.32 39.11,164.24 39.11,164.08
  L3SGND w0.152: 39.11,164.08 38.86,163.83 38.86,162.9 38.23,162.27 38.23,160.77 38.86,160.13 38.86,158.52 39.71,157.67 39.71,156.92 40.56,156.07 40.56,155.53 40.17,155.14 39.94,155.14 39.57,154.78 39.57,150.49 40.9,149.16 41.63,149.16 49.99,140.8 49.99,137.2 49.83,137.05 49.2,137.05 48.83,136.68 48.83,133.82 48.98,133.66 49.28,133.66 49.43,133.51 49.43,133.17 49.28,133.02 48.98,133.02 48.83,132.86 48.83,132.52 48.98,132.37 50.14,132.37 50.29,132.22 50.29,131.87 50.14,131.72 48.98,131.72 48.83,131.57 48.83,131.23 48.98,131.07 50.22,131.07 50.37,130.92 50.37,130.58 50.22,130.42 48.98,130.42 48.83,130.27 48.83,129.9 48.98,129.74 50.25,129.74 50.38,129.62 50.38,125.69 50.42,125.65 50.42,125.63 55.78,120.27 55.78,116.56 58.45,113.89 59.26,113.89 60.43,112.72 60.43,112.72 60.56,112.6 61.35,112.6 62.04,111.9
M_B_DQ23: length 78.8
  TOP w0.165: CPU1.AP32 v1(63.04,111.26)
  L3SGND w0.089: 62.31,112.02 62.76,111.58 v1(63.04,111.26) ; 39.94,166.52 39.87,166.56 arc(39.39,167.59) 40.51,167.39 40.44,167.29 DIMM2.177
  L3SGND w0.102: 39.96,166.22 39.96,166.44 39.94,166.52
  L3SGND w0.152: 62.31,112.02 61.37,112.96 60.62,112.96 58.93,114.66 58.34,114.66 56.31,116.69 56.31,120.68 51.95,125.03 51.95,125.25 52.22,125.52 52.22,125.73 51.98,125.98 51.76,125.98 51.49,125.71 51.28,125.71 51.03,125.96 51.03,132.95 50.88,133.1 50.24,133.1 50.09,133.26 50.09,133.6 50.24,133.75 50.9,133.75 51.03,133.88 51.03,134.27 50.9,134.4 49.91,134.4 49.76,134.55 49.76,134.89 49.91,135.05 50.85,135.05 51,135.2 51,135.54 50.85,135.69 49.89,135.69 49.73,135.85 49.73,136.19 49.89,136.34 50.88,136.34 51.03,136.49 51.03,140.68 41.9,149.81 41.17,149.81 40.22,150.76 40.22,154.68 40.6,155.05 40.69,155.05 40.94,155.31 40.94,156.2 40.06,157.08 40.06,157.91 39.24,158.74 39.24,160.15 39.71,160.63 39.71,162.03 39.21,162.52 39.21,163.68 39.24,163.71 39.24,163.72 39.88,164.36 39.88,165.75 39.96,165.83 39.96,166.22
M_B_DQ24: length 75.3
  TOP w0.165: CPU1.AM29 v1(65.78,109.43)
  L3SGND w0.089: 44.19,164.32 44.12,164.36 arc(43.64,165.39) 44.76,165.19 44.69,165.09 DIMM2.38 ; 64.67,112.98 64.79,112.86 64.79,111.62 64.79,111.61 64.79,110.42 v1(65.78,109.43)
  L3SGND w0.102: 44.21,164.02 44.21,164.24 44.19,164.32
  L3SGND w0.152: 44.21,164.02 43.96,163.77 43.96,162.47 44.81,161.62 44.81,160.77 45.67,159.91 45.67,158.68 45.03,158.05 45.03,156.93 45.87,156.09 45.87,154.74 46.02,154.59 46.72,154.59 46.88,154.44 46.88,151.58 51.3,147.16 51.3,146.95 50.72,146.37 50.72,146.15 50.96,145.91 51.18,145.91 51.76,146.49 51.97,146.49 52.21,146.25 52.21,146.03 51.65,145.47 51.65,145.25 51.89,145.01 52.11,145.01 52.67,145.57 52.89,145.57 53.13,145.33 53.13,145.11 52.54,144.52 52.54,144.31 52.78,144.07 53,144.07 53.59,144.66 53.8,144.66 54.33,144.13 54.33,129.62 59.58,124.37 59.58,117.33 62.04,114.87 62.78,114.87 64.67,112.98
M_B_DQ25: length 75.3
  TOP w0.165: v1(66.7,108.52) CPU1.AM28
  L3SGND w0.089: 45.04,166.52 44.97,166.56 arc(44.49,167.59) 45.61,167.39 45.54,167.29 DIMM2.183 ; 64.86,113.2 64.99,113.07 64.99,111.7 65,111.69 65,111.34 65,111 65,110.82 65,110.5 65.64,109.87 65.95,109.87 66.25,109.57 66.25,109.27 66.7,108.82 v1(66.7,108.52)
  L3SGND w0.102: 45.04,166.52 45.06,166.44 45.06,166.22
  L3SGND w0.152: 64.86,113.2 62.26,115.81 62.26,116.26 60.23,118.28 60.23,124.64 54.98,129.89 54.98,144.4 53.6,145.77 53.6,145.99 54.05,146.43 54.05,146.66 53.81,146.9 53.6,146.9 53.14,146.45 52.93,146.45 52.69,146.69 52.69,146.9 53.14,147.36 53.14,147.58 52.91,147.81 52.67,147.81 52.23,147.36 52.01,147.36 48.39,150.99 48.39,154.71 48.23,154.86 47.68,154.86 47.52,155.01 47.52,156.2 46.71,157.01 46.71,158.18 46.04,158.85 46.04,160.08 45.19,160.93 45.19,161.77 44.34,162.62 44.34,163.67 45.06,164.4 45.06,166.22
M_B_DQ26: length 72.8
  TOP w0.165: v1(66.66,112.19) 66.64,112.17 66.64,112.14 66.24,111.74 CPU1.AR29
  L3SGND w0.089: 50.26,162.56 50.18,162.7 50.07,162.76 arc(49.59,163.79) 50.71,163.59 50.64,163.49 DIMM2.45
  L3SGND w0.102: 50.26,162.56 50.26,162.42
  L3SGND w0.152: v1(66.66,112.19) 66.22,112.63 66.22,113.38 66.51,113.68 66.51,114.34 62.57,118.28 62.57,125.51 57.2,130.89 57.2,152.04 57.05,152.2 56.68,152.2 56.53,152.04 56.53,150.74 56.42,150.62 56,150.62 55.88,150.74 55.88,152.04 55.73,152.2 55.39,152.2 55.23,152.04 55.23,150.8 55.08,150.65 54.74,150.65 54.59,150.8 54.59,152.04 54.43,152.2 54.08,152.2 53.92,152.04 53.92,150.83 53.77,150.67 53.43,150.67 53.28,150.83 53.28,153.05 51.14,155.18 51.14,156.28 50.29,157.13 50.29,158.19 50.76,158.66 50.76,160.29 50.26,160.79 50.26,162.42
M_B_DQ27: length 72.8
  TOP w0.165: v1(67.57,112.19) 67.57,111.96 67.33,111.72 CPU1.AR28
  L3SGND w0.089: 50.99,168.12 50.92,168.16 arc(50.44,169.19) 51.56,168.99 51.49,168.89 DIMM2.190
  L3SGND w0.102: 51.01,167.82 51.01,168.04 50.99,168.12
  L3SGND w0.152: 51.01,167.82 51.01,166.35 51.74,165.62 51.75,165.62 51.77,165.61 51.77,164.6 52.54,163.83 52.54,162.93 51.96,162.35 51.96,160.59 52.7,159.85 52.7,159.04 51.99,158.33 51.99,157.13 51.99,157.12 51.99,157.08 52.83,156.24 52.83,155.27 53.25,154.85 56.95,154.85 57.1,154.7 57.1,154.36 56.95,154.2 56.69,154.2 56.54,154.05 56.54,153.67 56.69,153.52 58.34,153.52 58.5,153.37 58.5,131.45 63.87,126.07 63.87,117.79 66.36,115.29 66.95,115.29 67.39,114.86 68.17,114.07 68.17,112.92 68.17,112.91 68.03,112.77 68.03,112.63 67.59,112.19 v1(67.57,112.19)
M_B_DQ28: length 76.1
  TOP w0.165: CPU1.AL29 v1(65.78,107.6)
  L3SGND w0.089: DIMM2.36 42.99,165.09 43.06,165.19 arc(41.94,165.39) 42.42,164.36 42.49,164.32 ; 64.02,112.73 64.37,112.39 64.37,111.44 64.38,111.44 64.38,110.17 64.36,110.15 64.36,109.88 65.32,108.92 65.32,108.37 65.78,107.91 v1(65.78,107.6)
  L3SGND w0.102: 42.49,164.32 42.51,164.24 42.51,164.02
  L3SGND w0.152: 64.02,112.73 62.81,113.95 61.94,113.95 61.33,114.55 60.6,114.55 59.17,115.98 59.17,116.57 58.29,117.46 58.29,123.83 53.04,129.09 53.04,141.91 47.39,147.56 47.39,147.77 47.95,148.34 47.95,148.55 47.71,148.8 47.49,148.8 46.93,148.23 46.71,148.23 46.47,148.47 46.47,148.69 47.04,149.25 47.04,149.47 46.79,149.71 46.58,149.71 46.08,149.21 45.86,149.21 45.62,149.45 45.62,149.67 46.12,150.17 46.12,150.39 43.96,152.54 43.96,156.09 43.11,156.94 43.11,158.3 42.44,158.96 42.44,160.07 41.79,160.72 41.79,162.14 42.26,162.61 42.26,163.77 42.51,164.02
M_B_DQ29: length 76.4
  TOP w0.165: CPU1.AL28 v1(66.7,107.6)
  L3SGND w0.089: 43.34,166.52 43.27,166.56 arc(42.79,167.59) 43.91,167.39 43.84,167.29 DIMM2.181 ; 64.24,112.96 64.58,112.61 64.58,111.53 64.59,111.52 64.59,109.99 65.63,108.95 65.95,108.95 66.27,108.63 66.27,108.33 66.7,107.91 v1(66.7,107.6)
  L3SGND w0.102: 43.36,166.22 43.36,166.44 43.34,166.52
  L3SGND w0.152: 64.24,112.96 62.74,114.45 61.93,114.45 60.22,116.16 60.22,116.27 58.93,117.55 58.93,124.1 53.68,129.35 53.68,142.2 49.59,146.3 49.59,146.51 50.1,147.02 50.1,147.24 49.85,147.48 49.64,147.48 49.26,147.1 49.04,147.1 48.8,147.34 48.8,147.56 49.28,148.04 49.28,148.26 44.66,152.88 44.66,154.95 44.32,155.28 44.32,156.29 43.48,157.12 43.48,158.3 44.15,158.96 44.15,160.06 43.33,160.87 43.33,162.36 42.64,163.05 42.64,163.71 43.28,164.35 43.28,165.72 43.36,165.8 43.36,166.22
M_B_DQ30: length 73.3
  TOP w0.165: v1(66.67,111.26) 66.67,111.11 66.36,110.8 CPU1.AP29
  L3SGND w0.089: 48.44,162.72 48.37,162.76 arc(47.89,163.79) 49.01,163.59 48.94,163.49 DIMM2.43
  L3SGND w0.102: 48.44,162.72 48.46,162.64 48.46,162.42
  L3SGND w0.152: 48.46,162.42 48.84,162.04 49.76,162.04 49.91,161.89 49.91,160.72 49.25,160.06 49.25,158.76 49.91,158.1 49.91,156.95 50.76,156.1 50.76,153.35 51.05,153.06 51.87,153.06 52.02,152.91 52.02,152.56 51.87,152.41 50.22,152.41 50.06,152.26 50.06,151.9 50.22,151.75 52.34,151.75 52.45,151.64 52.45,151.24 52.3,151.09 51.21,151.09 51.05,150.94 51.05,150.58 51.21,150.43 52.25,150.43 53.11,149.57 56.4,149.57 56.55,149.41 56.55,130.54 61.93,125.17 61.93,118.54 66.24,114.22 66.24,113.79 65.86,113.41 65.86,112.61 65.96,112.51 65.96,111.97 v1(66.67,111.26)
M_B_DQ31: length 73.9
  TOP w0.165: CPU1.AP28 67.25,110.8 67.57,111.13 v1(67.57,111.26)
  L3SGND w0.089: 49.29,168.12 49.22,168.16 arc(48.74,169.19) 49.86,168.99 49.79,168.89 DIMM2.188
  L3SGND w0.102: 49.29,168.12 49.31,168.04 49.31,167.82
  L3SGND w0.152: 49.31,167.82 49.31,166.35 50.11,165.54 50.11,164.81 51.07,163.85 51.07,162.28 51.61,161.73 51.61,160.53 51.14,160.05 51.14,158.94 51.61,158.47 51.61,156.95 52.46,156.1 52.46,154.88 53.18,154.16 55.27,154.16 55.42,154.01 55.42,153.66 55.27,153.5 54.32,153.5 54.15,153.34 54.15,153 54.31,152.84 57.7,152.84 57.85,152.69 57.85,131.18 63.22,125.81 63.22,118.02 67.11,114.13 67.11,113.84 67.13,113.82 67.13,112.99 67.12,112.97 67.12,111.72 v1(67.57,111.26)
M_B_DQ32: length 74.4
  TOP w0.165: CPU1.AR12 v1(82.24,111.26)
  L3SGND w0.089: DIMM2.97 99.94,163.49 100.01,163.59 arc(98.89,163.79) 99.37,162.76 99.44,162.72
  L3SGND w0.102: 99.46,162.42 99.46,162.64 99.44,162.72
  L3SGND w0.152: 99.46,162.42 99.46,162.22 99.21,161.97 99.21,160.83 98.36,159.98 98.36,158.7 97.89,158.23 97.89,156.62 98.37,156.13 98.37,155.36 97.92,154.9 97.92,150.72 97.92,150.72 97.92,149.64 93.26,144.98 93.26,143.98 93.1,143.83 92.11,143.83 91.95,143.67 91.95,143.34 92.1,143.18 93.1,143.18 93.26,143.03 93.26,142.69 93.1,142.54 90.83,142.54 90.68,142.38 90.68,142.04 90.83,141.89 92.91,141.89 93.09,141.71 93.09,141.41 92.91,141.23 90.11,141.23 89.95,141.08 89.95,140.68 90.11,140.52 91.36,140.52 91.52,140.37 91.52,140 91.36,139.85 90.11,139.85 89.95,139.7 89.95,122.56 85.27,117.87 85.27,117.4 84.12,116.26 84.12,116.13 84.11,116.11 84.11,113.49 82.7,112.08 82.7,111.98 82.24,111.53 v1(82.24,111.26)
M_B_DQ33: length 74.3
  TOP w0.165: CPU1.AP12 v1(82.24,110.34)
  L3SGND w0.089: 100.29,168.12 100.22,168.16 arc(99.74,169.19) 100.86,168.99 100.79,168.89 DIMM2.242
  L3SGND w0.102: 100.31,167.82 100.31,168.04 100.29,168.12
  L3SGND w0.152: 100.31,167.82 100.31,166.65 99.38,165.72 99.38,164.7 100.33,163.75 100.33,163 100.02,162.69 100.02,162.12 99.59,161.69 99.59,160.77 98.74,159.92 98.74,158.83 99.42,158.15 99.42,157.06 98.74,156.39 98.74,154.53 98.86,154.42 98.86,153.6 98.56,153.31 98.56,152.75 98.95,152.37 98.95,151.86 98.56,151.48 98.56,151 98.95,150.62 98.95,149.75 93.9,144.71 93.9,140.7 93.75,140.55 92.46,140.55 92.28,140.37 92.28,139.32 92.13,139.17 91.82,139.17 91.67,139.02 91.67,138.66 91.82,138.51 92.08,138.51 92.23,138.36 92.23,138 92.08,137.85 91.72,137.85 91.57,137.7 91.57,137.34 91.72,137.19 92.08,137.19 92.23,137.04 92.23,136.53 92.08,136.37 91.59,136.37 90.6,135.38 90.6,122.29 86.18,117.87 86.18,117.81 84.38,116 84.38,113.38 83.11,112.11 83.11,111.86 82.7,111.45 82.7,111.07 82.7,111.06 82.7,110.81 v1(82.24,110.34)
M_B_DQ34: length 80
  TOP w0.165: CPU1.AL13 v1(81.33,107.6)
  L3SGND w0.089: 105.39,164.32 105.32,164.36 arc(104.84,165.39) 105.96,165.19 105.89,165.09 DIMM2.104 ; v1(81.33,107.6) 81.76,108.03 83.31,108.03 83.52,108.25
  L3SGND w0.102: 105.39,164.32 105.41,164.24 105.41,164.02
  L3SGND w0.152: 83.52,108.25 84.62,109.35 84.62,111.54 85.81,112.72 85.81,114.19 86.09,114.47 86.47,114.47 86.74,114.74 86.74,115.12 93.52,121.9 93.52,132.72 94.04,133.25 96.38,133.25 96.77,133.64 96.77,143.5 105.27,152 105.27,152.25 105.12,152.4 104.83,152.4 104.67,152.55 104.67,152.91 104.83,153.06 105.12,153.06 105.27,153.21 105.27,153.58 105.12,153.73 103.45,153.73 103.3,153.88 103.3,154.22 103.45,154.38 105.12,154.38 105.27,154.53 105.27,154.87 105.12,155.03 104.14,155.03 103.84,155.33 103.84,156.29 104.65,157.1 104.65,158.43 105.16,158.95 105.16,160.2 104.69,160.68 104.69,162.13 105.16,162.6 105.16,163.12 105.16,163.13 105.16,163.77 105.41,164.02
M_B_DQ35: length 79.6
  TOP w0.165: CPU1.AL12 v1(82.24,107.6)
  L3SGND w0.089: 106.24,166.52 106.17,166.56 arc(105.69,167.59) 106.81,167.39 106.74,167.29 DIMM2.249
  L3SGND w0.102: 106.26,166.22 106.26,166.44 106.24,166.52
  L3SGND w0.152: 106.26,166.22 106.26,165.8 106.18,165.72 106.18,164.35 105.92,164.09 105.92,164.09 105.54,163.71 105.54,162.48 106.01,162 106.01,160.64 105.54,160.17 105.54,158.33 106.01,157.86 106.01,157 105.38,156.37 105.38,155.38 105.92,154.85 105.92,151.73 97.42,143.24 97.42,133.36 96.65,132.59 94.36,132.59 94.2,132.44 94.2,132.06 94.36,131.91 94.82,131.91 94.97,131.76 94.97,131.4 94.82,131.25 94.32,131.25 94.17,131.1 94.17,130.74 94.32,130.59 94.82,130.59 94.97,130.44 94.97,130.08 94.82,129.93 94.32,129.93 94.17,129.78 94.17,120.74 88.37,114.94 87.92,114.94 86.42,113.43 86.42,112.94 84.9,111.42 84.9,109.23 84.89,109.22 84.89,108.72 83.61,107.45 83.61,107.41 83.34,107.14 82.96,107.14 82.94,107.17 82.67,107.17 v1(82.24,107.6)
M_B_DQ36: length 75.7
  TOP w0.165: CPU1.AR13 v1(81.33,112.17)
  L3SGND w0.089: DIMM2.95 98.24,163.49 98.31,163.59 arc(97.19,163.79) 97.67,162.76 97.74,162.72
  L3SGND w0.102: 97.74,162.72 97.76,162.64 97.76,162.42
  L3SGND w0.152: 97.76,162.42 97.67,162.32 96.62,162.32 96.14,161.84 96.14,160.86 96.67,160.33 96.67,158.48 95.96,157.77 95.96,157.08 96.69,156.36 96.69,155.52 96.62,155.45 96.62,150.18 87.5,141.06 87.5,133.57 87.66,133.42 88.33,133.42 88.48,133.27 88.48,132.91 88.33,132.76 87.66,132.76 87.5,132.61 87.5,132.25 87.66,132.1 88.4,132.1 88.55,131.95 88.55,131.59 88.4,131.44 87.66,131.44 87.5,131.29 87.5,130.93 87.66,130.78 88.4,130.78 88.55,130.63 88.55,130.27 88.4,130.12 87.66,130.12 87.5,129.97 87.5,129.61 87.66,129.46 88.44,129.46 88.6,129.31 88.6,128.95 88.44,128.8 87.78,128.8 87.63,128.65 87.63,128.29 87.78,128.14 88.44,128.14 88.6,127.99 88.6,127.63 88.44,127.48 87.81,127.48 87.66,127.33 87.66,126.97 87.81,126.82 88.44,126.82 88.6,126.67 88.6,126.31 88.44,126.16 87.81,126.16 87.66,126.01 87.66,125.65 87.81,125.5 88.44,125.5 88.6,125.35 88.6,124.99 88.44,124.84 87.83,124.84 87.68,124.68 87.68,124.33 87.83,124.18 88.44,124.18 88.6,124.02 88.6,123.03 83.97,118.41 83.97,117.37 82.8,116.2 82.8,114.22 81.33,112.75 v1(81.33,112.17)
M_B_DQ37: length 77.1
  TOP w0.165: v1(81.4,111.26) 81.33,111.19 81.26,111.19 CPU1.AP13
  L3SGND w0.089: DIMM2.240 99.09,168.89 99.16,168.99 arc(98.04,169.19) 98.52,168.16 98.59,168.12
  L3SGND w0.102: 98.61,167.82 98.61,168.04 98.59,168.12
  L3SGND w0.152: 98.61,167.82 98.61,166.58 97.68,165.64 97.68,164.68 98.53,163.83 98.53,162.51 97.64,161.62 97.64,160.74 97.03,160.13 97.03,158.84 97.51,158.35 97.51,156.73 97.03,156.25 97.03,155.23 97.27,154.99 97.27,150.45 97.27,150.45 97.27,149.91 89.31,141.95 89.31,140.36 89.15,140.2 88.42,140.2 88.27,140.05 88.27,139.7 88.42,139.54 89.15,139.54 89.31,139.39 89.31,139.04 89.15,138.88 88.42,138.88 88.27,138.73 88.27,138.37 88.42,138.22 89.15,138.22 89.31,138.07 89.31,137.71 89.15,137.56 88.42,137.56 88.27,137.41 88.27,137.05 88.42,136.9 89.15,136.9 89.31,136.75 89.31,136.39 89.15,136.24 88.68,136.24 88.53,136.09 88.53,135.73 88.68,135.58 89.15,135.58 89.31,135.43 89.31,135.1 89.13,134.92 88.7,134.92 88.54,134.77 88.54,134.39 88.7,134.23 89.15,134.23 89.31,134.08 89.31,122.82 84.62,118.14 84.62,117.39 83.95,116.71 83.95,116.46 83.85,116.37 83.85,116.25 83.84,116.23 83.84,114.42 81.78,112.36 81.78,111.64 v1(81.4,111.26)
M_B_DQ38: length 78.9
  TOP w0.165: CPU1.AM13 v1(81.33,108.52)
  L3SGND w0.089: 84.14,111.53 84.14,111.02 82.71,109.59 82.71,109.38 82.3,108.97 81.78,108.97 v1(81.33,108.52) ; 103.69,164.32 103.62,164.36 arc(103.14,165.39) 104.26,165.19 104.19,165.09 DIMM2.102
  L3SGND w0.102: 103.71,164.04 103.71,164.24 103.69,164.32
  L3SGND w0.152: 84.14,111.53 84.14,111.97 85.23,113.06 85.23,114.91 92.18,121.86 92.18,134.14 92.65,134.61 95.36,134.61 95.48,134.72 95.48,144.04 100.81,149.37 100.81,150.4 100.96,150.56 101.79,150.56 101.94,150.71 101.94,151.25 101.79,151.4 100.84,151.4 100.69,151.55 100.69,151.89 100.84,152.05 101.79,152.05 101.94,152.2 101.94,152.54 101.79,152.69 100.79,152.69 100.63,152.85 100.63,153.19 100.79,153.34 101.79,153.34 101.94,153.49 101.94,153.84 101.79,153.99 100.79,153.99 100.63,154.14 100.63,154.48 100.79,154.64 101.79,154.64 101.94,154.79 101.94,156.27 102.61,156.94 102.61,158.16 101.9,158.86 101.9,159.9 102.79,160.79 102.79,161.73 103.46,162.4 103.46,163.79 103.71,164.04
M_B_DQ39: length 78.7
  TOP w0.165: CPU1.AM12 v1(82.24,108.52)
  L3SGND w0.089: v1(82.24,108.52) 82.66,108.94 82.98,108.94 82.98,108.94 83.34,108.94 84.38,109.98 84.38,111.79 84.59,112 ; DIMM2.247 105.04,167.29 105.11,167.39 arc(103.99,167.59) 104.47,166.56 104.54,166.52
  L3SGND w0.102: 104.54,166.52 104.56,166.44 104.56,166.22
  L3SGND w0.152: 104.56,166.22 104.56,165.76 104.48,165.67 104.48,164.31 103.84,163.67 103.84,162.74 104.32,162.26 104.32,160.54 103.66,159.88 103.66,158.91 102.99,158.25 102.99,156.81 103.46,156.34 103.46,155.36 102.59,154.49 102.59,153.28 102.79,153.08 103.86,153.08 104.01,152.93 104.01,152.58 103.86,152.43 102.74,152.43 102.59,152.28 102.59,151.94 102.74,151.78 103.48,151.78 103.63,151.63 103.63,151.29 103.48,151.14 102.79,151.14 102.59,150.93 102.59,150.23 96.13,143.77 96.13,134.11 95.97,133.96 93.09,133.96 92.87,133.74 92.87,121.85 86.4,115.39 86.09,115.39 85.5,114.8 85.5,112.91 84.59,112
M_B_DQ40: length 79.7
  TOP w0.165: CPU1.AP9 v1(86.27,110.34)
  L3SGND w0.089: v1(86.27,110.34) 86.75,110.82 86.75,111.41 86.76,111.42 86.76,111.44 87.07,111.75 87.36,111.75 88.45,112.84 88.45,113.21 ; DIMM2.108 109.29,165.09 109.36,165.19 arc(108.24,165.39) 108.72,164.36 108.79,164.32
  L3SGND w0.102: 108.81,164.02 108.81,164.24 108.79,164.32
  L3SGND w0.152: 108.81,164.02 108.71,163.92 108.71,163.9 108.59,163.77 108.59,163.12 108.58,163.11 108.58,162.41 108.09,161.92 108.09,160.62 108.56,160.15 108.56,158.85 108.09,158.38 108.09,156.82 108.56,156.35 108.56,155.31 107.99,154.74 107.99,151.05 99.36,142.43 99.36,125.48 99.21,125.32 97.1,125.32 96.95,125.17 96.95,124.85 97.13,124.68 99.21,124.68 99.36,124.52 99.36,124.18 99.21,124.03 97.1,124.03 96.95,123.88 96.95,123.53 97.1,123.38 99.21,123.38 99.36,123.23 99.36,122.89 99.21,122.73 97.61,122.73 96.11,121.23 96.11,118.51 91.14,113.54 88.82,113.54 88.8,113.52 88.75,113.52 88.45,113.21
M_B_DQ41: length 78.3
  TOP w0.165: CPU1.AR9 v1(87.18,111.26)
  L3SGND w0.089: 91.87,113.77 91.62,113.51 91.58,113.51 91.33,113.26 91.33,112.97 90.99,112.63 88.56,112.63 v1(87.18,111.26) ; DIMM2.253 110.14,167.29 110.21,167.39 arc(109.09,167.59) 109.57,166.56 109.64,166.52
  L3SGND w0.102: 109.64,166.52 109.66,166.44 109.66,166.22
  L3SGND w0.152: 109.66,166.22 109.66,164.45 108.94,163.73 108.94,163.67 108.94,162.31 109.63,161.62 109.63,160.78 108.94,160.1 108.94,158.83 109.6,158.17 109.6,156.98 108.92,156.29 108.92,155.11 109.07,154.96 109.52,154.96 109.68,154.81 109.68,154.46 109.52,154.31 108.82,154.31 108.67,154.16 108.67,153.81 108.82,153.66 109.54,153.66 109.69,153.52 109.69,153.16 109.54,153.01 108.81,153.01 108.67,152.87 108.67,152.5 108.81,152.36 109.52,152.36 109.68,152.21 109.68,151.83 100.01,142.16 100.01,122.31 98.92,121.22 98.71,121.22 98.36,121.57 98.15,121.57 97.9,121.32 97.9,121.1 98.24,120.76 98.24,120.54 97.99,120.29 97.77,120.29 97.39,120.67 97.18,120.67 96.94,120.43 96.94,120.19 97.31,119.82 97.31,119.61 96.76,119.06 96.76,118.39 94.67,116.31 94.41,116.31 91.87,113.77
M_B_DQ42: length 78.4
  TOP w0.165: CPU1.AP7 v1(89.01,110.34)
  L3SGND w0.089: DIMM2.115 115.24,163.49 115.31,163.59 arc(114.19,163.79) 114.67,162.76 114.74,162.72 ; v1(89.01,110.34) 89.67,110.77 89.75,110.77 90.24,110.77 90.39,110.62 92.58,110.62 92.58,110.63 93.09,110.63 93.4,110.93
  L3SGND w0.102: 114.74,162.72 114.76,162.64 114.76,162.42
  L3SGND w0.152: 114.76,162.42 114.76,162.22 114.51,161.97 114.51,160.78 113.67,159.93 113.67,158.78 114.51,157.93 114.51,157.13 114.48,157.09 114.48,157.07 113.66,156.26 113.66,155.19 113.49,155.02 112.88,155.02 112.73,154.87 112.73,154.52 112.88,154.37 113.53,154.37 113.68,154.22 113.68,153.88 113.53,153.72 112.88,153.72 112.73,153.57 112.73,153.25 112.91,153.08 113.53,153.08 113.68,152.92 113.68,152.58 113.53,152.43 112.91,152.43 112.73,152.25 112.73,151.93 112.88,151.78 113.43,151.78 113.58,151.63 113.58,151.41 104.09,141.92 104.09,125.25 103.94,125.09 103.15,125.09 103,124.94 103,124.61 103.17,124.43 103.94,124.43 104.09,124.28 104.09,123.92 103.89,123.72 103.2,123.72 103.05,123.57 103.05,123.21 103.2,123.06 103.94,123.06 104.09,122.91 104.09,122.33 99.63,117.87 99.63,116.85 94.6,111.82 94.28,111.82 93.4,110.93
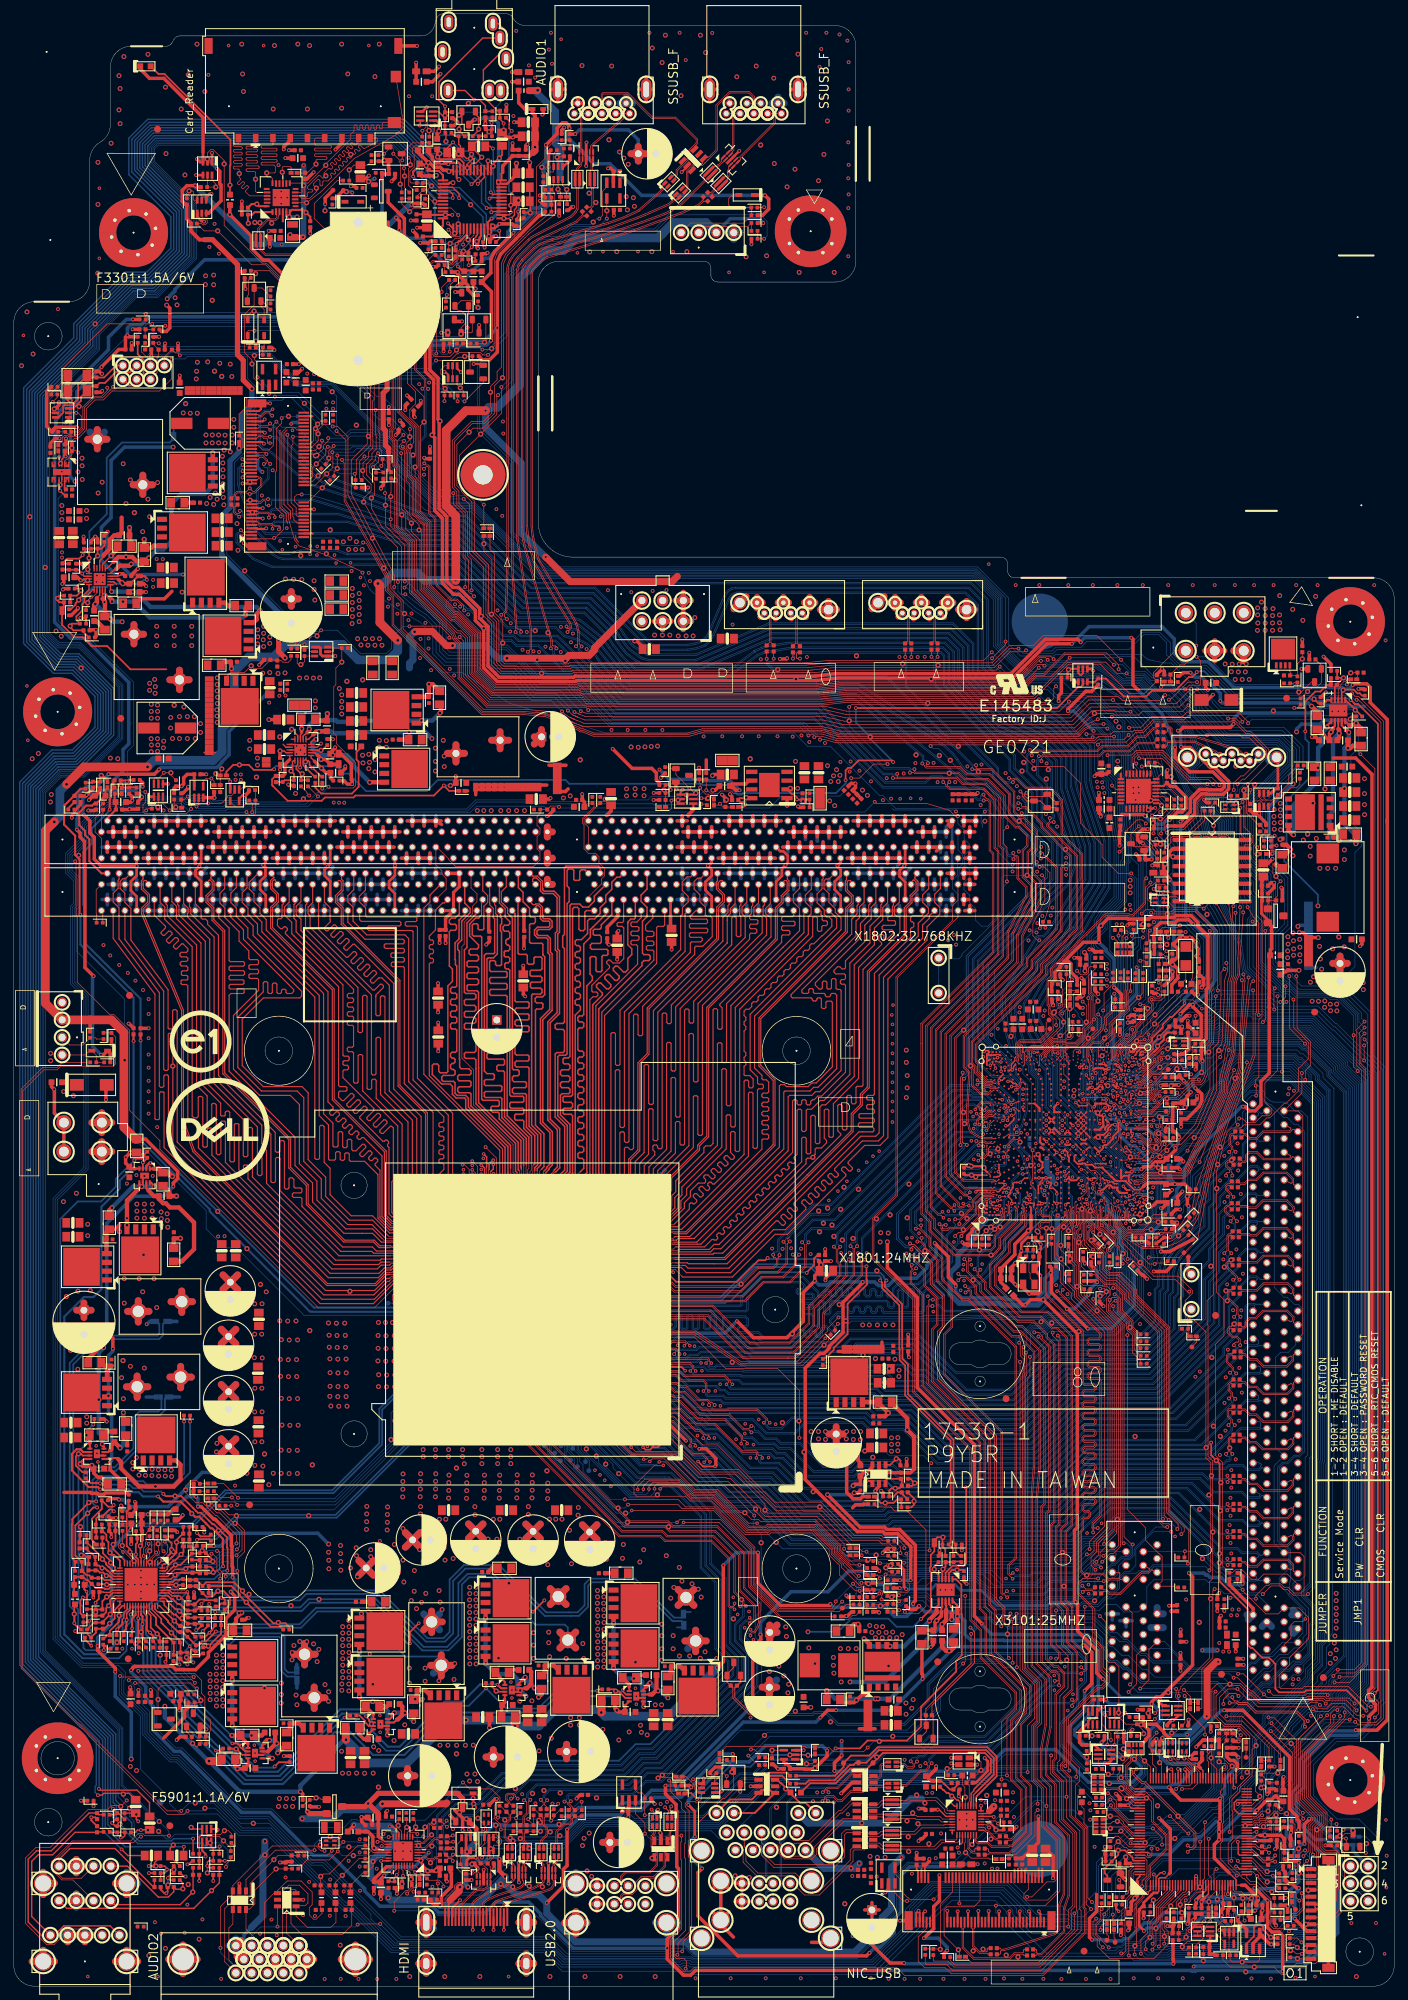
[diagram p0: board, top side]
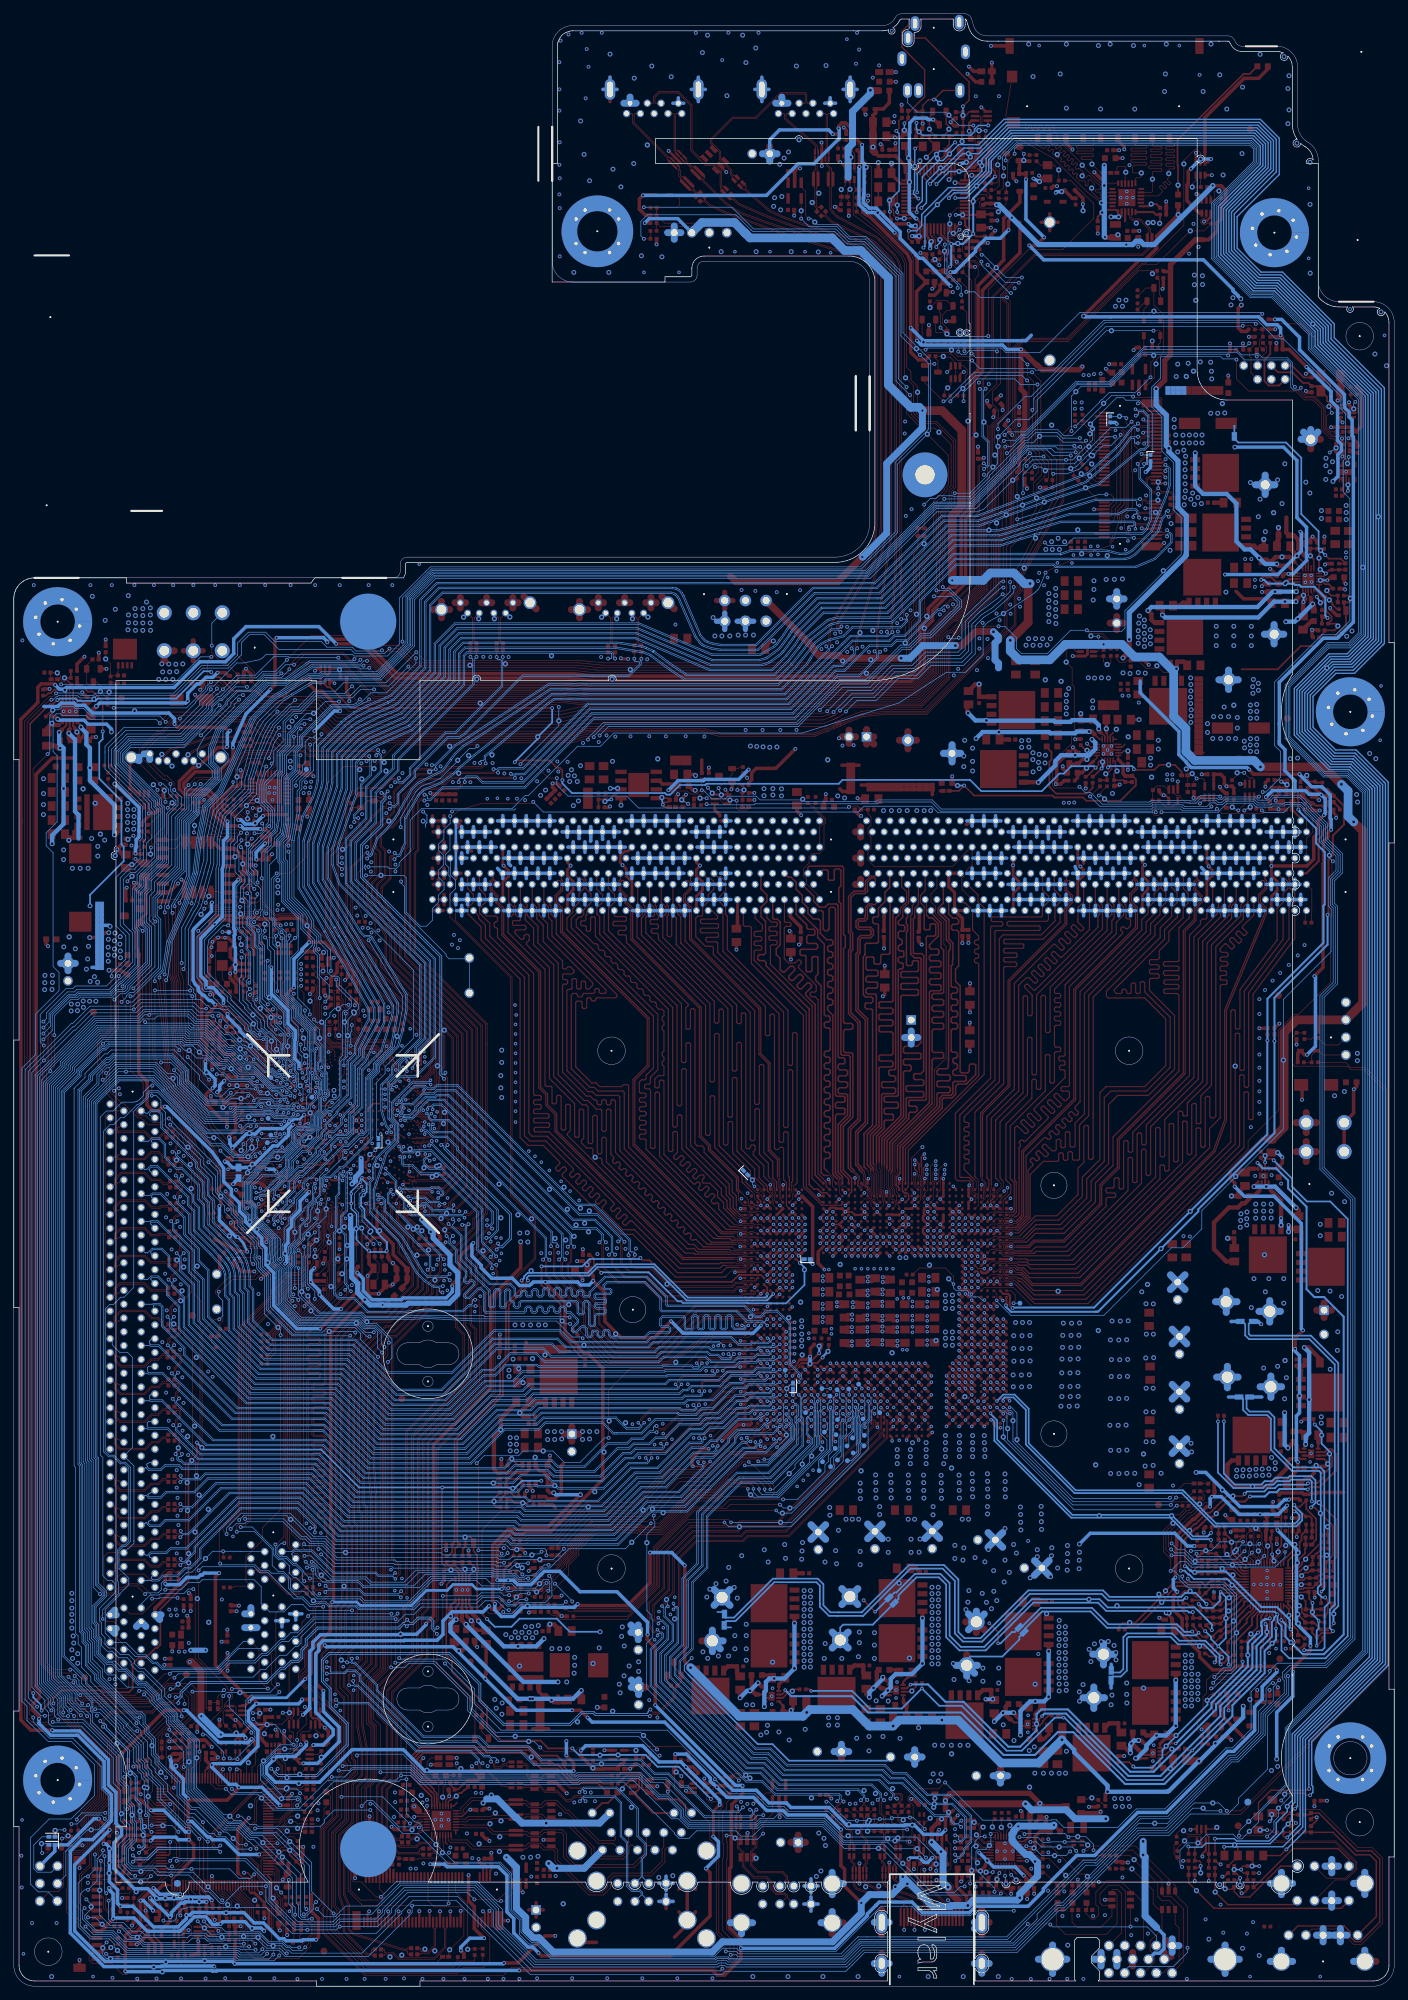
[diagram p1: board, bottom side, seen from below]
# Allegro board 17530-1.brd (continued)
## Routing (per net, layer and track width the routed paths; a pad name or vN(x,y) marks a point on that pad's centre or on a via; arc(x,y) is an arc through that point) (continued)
M_B_DQ43: length 77.5
  TOP w0.165: CPU1.AP6 v1(89.93,110.34)
  L3SGND w0.089: 115.59,168.12 115.52,168.16 arc(115.04,169.19) 116.16,168.99 116.09,168.89 DIMM2.260
  L3SGND w0.102: 115.61,167.82 115.61,168.04 115.59,168.12
  L3SGND w0.152: v1(89.93,110.34) 93.2,110.34 94.4,111.54 94.83,111.54 100.07,116.78 100.07,117.39 104.74,122.06 104.74,141.65 111.17,148.09 111.39,148.09 111.67,147.8 111.89,147.8 112.14,148.05 112.14,148.27 111.85,148.55 111.85,148.77 114.33,151.24 114.33,154.98 114.04,155.26 114.04,156.13 114.88,156.98 114.88,158.29 114,159.18 114,159.87 114.89,160.76 114.89,161.63 115.53,162.27 115.53,163.87 114.72,164.68 114.72,165.49 115.61,166.38 115.61,167.82
M_B_DQ44: length 80.2
  TOP w0.165: CPU1.AP10 v1(85.35,110.34)
  L3SGND w0.089: DIMM2.106 107.59,165.09 107.66,165.19 arc(106.54,165.39) 107.02,164.36 107.09,164.32
  L3SGND w0.102: 107.09,164.32 107.11,164.24 107.11,164.02
  L3SGND w0.152: v1(85.35,110.34) 85.84,110.83 85.84,111.86 86.69,112.71 86.69,113.32 87.8,114.43 89.71,114.43 91.06,115.77 91.06,116.97 94.82,120.73 94.82,127.8 94.97,127.95 96.22,127.95 96.37,128.1 96.37,128.45 96.22,128.6 95.71,128.6 95.55,128.75 95.55,129.11 95.71,129.26 97.92,129.26 98.07,129.41 98.07,129.78 97.92,129.93 95.89,129.93 95.73,130.09 95.73,130.43 95.89,130.58 97.92,130.58 98.07,130.73 98.07,131.08 97.92,131.23 96.16,131.23 96.01,131.38 96.01,131.72 96.16,131.88 97.92,131.88 98.07,132.03 98.07,142.97 106.57,151.46 106.57,154.99 106.86,155.28 106.86,155.52 106.86,155.53 106.86,156.07 106.86,156.08 106.86,156.4 106.39,156.87 106.39,158.01 106.89,158.51 106.89,160.16 106.39,160.65 106.39,161.99 106.86,162.46 106.86,163.12 106.86,163.13 106.86,163.77 107.11,164.02
M_B_DQ45: length 79.4
  TOP w0.165: CPU1.AR10 86.27,111.26 86.27,111.28 v1(86.29,111.3)
  L3SGND w0.089: 107.94,166.52 107.87,166.56 arc(107.39,167.59) 108.51,167.39 108.44,167.29 DIMM2.251
  L3SGND w0.102: 107.96,166.22 107.96,166.44 107.94,166.52
  L3SGND w0.152: 107.96,166.22 107.96,165.79 107.88,165.71 107.88,164.36 107.24,163.72 107.24,162.46 107.71,161.99 107.71,160.51 107.24,160.04 107.24,158.84 107.71,158.37 107.71,156.8 107.24,156.32 107.24,151.22 98.72,142.7 98.72,128.73 98.56,128.57 97.18,128.57 97.03,128.42 97.03,128.08 97.18,127.93 98.56,127.93 98.72,127.77 98.72,127.43 98.56,127.28 96.24,127.28 96.09,127.13 96.09,126.78 96.24,126.63 98.56,126.63 98.72,126.48 98.72,126.11 98.58,125.97 96.56,125.97 96.16,125.58 96.16,122.53 95.46,121.83 95.46,120.64 91.64,116.81 91.64,115.45 90.11,113.92 88.72,113.92 87.43,112.63 86.99,112.63 86.29,111.93 v1(86.29,111.3)
M_B_DQ46: length 76.9
  TOP w0.165: CPU1.AR7 v1(89.01,111.26)
  L3SGND w0.089: 113.04,162.72 112.97,162.76 arc(112.49,163.79) 113.61,163.59 113.54,163.49 DIMM2.113 ; 93.62,113.06 92.25,111.68 89.75,111.68 v1(89.01,111.26)
  L3SGND w0.102: 113.04,162.72 113.06,162.64 113.06,162.42
  L3SGND w0.152: 93.62,113.06 94.18,113.62 94.9,113.62 98.33,117.05 98.33,118.41 101.59,121.66 101.59,128.61 101.75,128.78 102.62,128.78 102.77,128.93 102.77,129.29 102.62,129.44 101.75,129.44 101.6,129.59 101.6,129.95 101.75,130.1 102.64,130.1 102.79,130.25 102.79,130.61 102.64,130.76 101.75,130.76 101.6,130.91 101.6,131.27 101.75,131.42 102.64,131.42 102.79,131.57 102.79,131.93 102.64,132.08 101.75,132.08 101.6,132.23 101.6,132.59 101.75,132.74 102.64,132.74 102.79,132.89 102.79,133.25 102.64,133.4 101.75,133.4 101.6,133.55 101.6,133.91 101.75,134.06 102.64,134.06 102.79,134.21 102.79,142.6 111.35,151.16 111.35,154.92 111.96,155.53 111.96,156.26 112.81,157.11 112.81,157.8 111.96,158.65 111.96,159.98 112.86,160.87 112.86,162.21 113.06,162.42
M_B_DQ47: length 76.2
  TOP w0.165: CPU1.AR6 v1(89.93,111.26)
  L3SGND w0.089: v1(89.93,111.26) 90.24,111.26 90.66,110.83 92.85,110.83 93.19,111.18 93.19,112.01 93.37,112.19 ; DIMM2.258 114.39,168.89 114.46,168.99 arc(113.34,169.19) 113.82,168.16 113.89,168.12
  L3SGND w0.102: 113.89,168.12 113.91,168.04 113.91,167.82
  L3SGND w0.152: 113.91,167.82 113.91,166.54 112.97,165.59 112.97,164.73 113.83,163.87 113.83,162.59 113.14,161.9 113.14,160.71 112.34,159.91 112.34,159.11 113.16,158.29 113.16,156.95 112.29,156.08 112.29,155.08 112.06,154.86 112.06,150.81 103.44,142.19 103.44,128.09 102.86,127.51 102.39,127.51 102.23,127.36 102.23,127 102.39,126.85 102.62,126.85 102.77,126.7 102.77,126.34 102.62,126.19 102.39,126.19 102.23,126.04 102.23,121.39 98.98,118.14 98.98,116.91 95.22,113.16 94.34,113.16 93.37,112.19
M_B_DQ48: length 87.8
  TOP w0.165: CPU1.AM9 v1(86.27,107.6)
  L3SGND w0.089: 92.51,108.92 92.37,108.78 87.44,108.78 v1(86.27,107.6) ; 118.14,162.72 118.07,162.76 arc(117.59,163.79) 118.71,163.59 118.64,163.49 DIMM2.119
  L3SGND w0.102: 118.16,162.42 118.16,162.64 118.14,162.72
  L3SGND w0.152: 92.51,108.92 92.77,109.18 93.59,109.18 94.14,109.73 95.15,109.73 109.8,124.38 109.8,129.57 109.58,129.79 107.54,129.79 107.39,129.95 107.39,130.29 107.54,130.44 108.03,130.44 108.18,130.59 108.18,130.94 108.03,131.09 107.34,131.09 106.68,131.75 106.68,140.85 110.55,144.71 112.17,144.71 116.32,148.87 116.32,150.47 117.27,151.42 117.27,152.71 117.42,152.86 118.11,152.86 118.26,153.02 118.26,153.36 118.11,153.51 116.66,153.51 116.45,153.71 116.45,154.06 116.61,154.21 118.01,154.21 118.16,154.36 118.16,154.65 118.01,154.81 117.42,154.81 117.27,154.96 117.27,156.23 117.91,156.87 117.91,158.1 117.25,158.76 117.25,160.12 117.91,160.79 117.91,162.16 117.91,162.16 118.16,162.42
M_B_DQ49: length 88.9
  TOP w0.165: CPU1.AL9 v1(86.27,106.69)
  L3SGND w0.089: v1(86.27,106.69) 86.75,107.17 86.75,107.66 86.82,107.73 86.82,107.75 87.07,107.99 87.09,107.99 87.59,108.5 92.57,108.5 92.68,108.61 ; 118.99,168.12 118.92,168.16 arc(118.44,169.19) 119.56,168.99 119.49,168.89 DIMM2.264
  L3SGND w0.102: 119.01,167.82 119.01,168.04 118.99,168.12
  L3SGND w0.152: 119.01,167.82 119.01,166.51 118.12,165.62 118.12,164.88 119.13,163.88 119.13,162.87 118.29,162.03 118.29,160.69 118.92,160.06 118.92,158.71 118.29,158.08 118.29,156.84 118.95,156.18 118.95,152.14 116.97,150.16 116.97,148.6 112.44,144.07 110.82,144.07 107.33,140.58 107.33,132.97 110.45,129.84 110.45,124.11 95.77,109.43 94.34,109.43 93.81,108.9 92.98,108.9 92.68,108.61
M_B_DQ50: length 87.2
  TOP w0.165: CPU1.AL6 v1(89.93,106.66)
  L3SGND w0.089: 124.09,164.32 124.02,164.36 arc(123.54,165.39) 124.66,165.19 124.59,165.09 DIMM2.126
  L3SGND w0.102: 124.11,164.02 124.11,164.24 124.09,164.32
  L3SGND w0.152: v1(89.93,106.66) 90.32,106.66 90.42,106.56 91.33,106.56 93.67,106.56 93.79,106.69 97.11,106.69 115.65,125.23 115.65,125.44 114.84,126.25 114.84,126.47 115.07,126.7 115.31,126.7 116.11,125.9 116.32,125.9 116.57,126.14 116.57,126.36 115.63,127.3 115.63,127.51 115.85,127.74 116.1,127.74 117.03,126.82 117.24,126.82 117.82,127.39 117.82,130.82 119.84,132.84 119.84,148.97 122.74,151.87 122.74,154.34 123.86,155.47 123.86,156.1 123.01,156.95 123.01,158.22 123.86,159.06 123.86,159.99 123.01,160.84 123.01,161.74 123.86,162.59 123.86,163.77 124.11,164.02
M_B_DQ51: length 88
  TOP w0.165: CPU1.AL7 v1(88.1,106.69)
  L3SGND w0.089: v1(88.1,106.69) 88.55,106.24 90.1,106.24 90.11,106.25 90.55,106.25 ; DIMM2.271 125.44,167.29 125.51,167.39 arc(124.39,167.59) 124.87,166.56 124.94,166.52
  L3SGND w0.102: 124.94,166.52 124.96,166.44 124.96,166.22
  L3SGND w0.152: 90.55,106.25 93.75,106.25 93.91,106.41 97.23,106.41 97.28,106.46 97.8,106.46 118.47,127.13 118.47,128.96 118.47,128.97 118.47,129.31 118.62,129.46 118.92,129.46 119.08,129.61 119.08,129.96 118.92,130.11 118.67,130.11 118.52,130.26 118.52,130.6 118.67,130.76 119.15,130.76 119.51,131.12 119.51,131.6 120.48,132.57 120.48,148.7 123.39,151.6 123.39,154.07 124.24,154.93 124.24,156.24 123.37,157.11 123.37,157.81 124.24,158.68 124.24,160.03 123.39,160.88 123.39,160.92 123.39,160.93 123.39,161.47 123.39,161.48 123.39,161.68 124.24,162.53 124.24,163.74 124.88,164.38 124.88,165.84 124.96,165.92 124.96,166.22
M_B_DQ52: length 88
  TOP w0.165: CPU1.AM10 v1(85.35,108.52)
  L3SGND w0.089: 90.58,109.96 90.14,109.96 90.06,109.88 87.01,109.88 86.75,109.63 86.75,109.33 86.42,109 86.23,109 v1(85.35,108.52) ; 116.44,162.72 116.37,162.76 arc(115.89,163.79) 117.01,163.59 116.94,163.49 DIMM2.117
  L3SGND w0.102: 116.44,162.72 116.46,162.64 116.46,162.42
  L3SGND w0.152: 90.58,109.96 93.21,109.96 94.51,111.26 95.73,111.26 100.7,116.22 100.7,117.11 106.91,123.32 106.91,125.04 107.06,125.2 108.32,125.2 108.47,125.35 108.47,125.74 108.32,125.9 106.91,125.9 106.76,126.05 106.76,126.39 106.91,126.54 108.32,126.54 108.47,126.7 108.47,127.04 108.32,127.19 106.86,127.19 106.71,127.34 106.71,127.69 106.86,127.84 108.32,127.84 108.47,127.99 108.47,128.33 108.32,128.49 106.67,128.49 105.38,129.77 105.38,141.38 110.01,146.01 111.63,146.01 112.77,147.15 112.77,147.15 114.99,149.37 114.99,154.66 115.36,155.03 115.36,156.18 116.2,157.02 116.2,157.12 116.21,157.13 116.21,157.67 116.2,157.68 116.2,158.01 115.36,158.86 115.36,160.04 116.2,160.88 116.2,160.92 116.21,160.93 116.21,162.17 116.46,162.42
M_B_DQ53: length 89.2
  TOP w0.165: CPU1.AL10 v1(85.35,107.6)
  L3SGND w0.089: 92.28,109.17 92.11,109 87.35,109 86.44,108.09 86.1,108.09 v1(85.35,107.6) ; DIMM2.262 117.79,168.89 117.86,168.99 arc(116.74,169.19) 117.22,168.16 117.29,168.12
  L3SGND w0.102: 117.29,168.12 117.31,168.04 117.31,167.82
  L3SGND w0.152: 117.31,167.82 117.31,166.64 116.4,165.72 116.4,164.7 117.23,163.87 117.23,162.45 116.59,161.81 116.59,160.76 115.74,159.91 115.74,159.16 116.59,158.31 116.59,157.01 115.74,156.16 115.74,152.51 116,152.24 116.43,152.24 116.59,152.09 116.59,151.75 116.43,151.6 115.86,151.6 115.67,151.41 115.67,149.13 113.04,146.5 111.9,145.36 110.28,145.36 106.03,141.11 106.03,130.34 107.24,129.13 108.84,129.13 109.12,128.85 109.12,124.61 101.08,116.57 101.08,116.21 94.88,110.01 94.02,110.01 94,109.98 93.98,109.98 93.46,109.46 92.57,109.46 92.28,109.17
M_B_DQ54: length 85.7
  TOP w0.165: CPU1.AM6 v1(89.93,107.58)
  L3SGND w0.089: DIMM2.124 122.89,165.09 122.96,165.19 arc(121.84,165.39) 122.32,164.36 122.39,164.32
  L3SGND w0.102: 122.41,164.02 122.41,164.24 122.39,164.32
  L3SGND w0.152: 122.41,164.02 122.21,163.82 122.21,163.78 122.16,163.73 122.16,163.05 121.31,162.2 121.31,160.76 122.15,159.92 122.15,159.89 122.16,159.87 122.16,159.01 121.31,158.16 121.31,156.95 122.16,156.1 122.16,155.32 121.44,154.6 121.44,152.41 118.54,149.51 118.54,133.38 115.53,130.37 113.28,130.37 113.13,130.21 113.13,129.84 113.28,129.68 114.91,129.68 115.09,129.51 115.09,129.19 114.94,129.04 113.08,129.04 112.93,128.88 112.93,125.98 113.08,125.83 113.43,125.83 113.72,125.54 113.72,125.12 96.42,107.83 95.72,107.83 95.7,107.86 95.08,107.86 95.06,107.88 94.45,107.88 94.42,107.86 93.8,107.86 93.06,107.12 90.65,107.12 90.35,107.42 90.08,107.42 v1(89.93,107.58)
M_B_DQ55: length 86.5
  TOP w0.165: CPU1.AM7 v1(89.01,107.58)
  L3SGND w0.089: DIMM2.269 123.74,167.29 123.81,167.39 arc(122.69,167.59) 123.17,166.56 123.24,166.52
  L3SGND w0.102: 123.26,166.22 123.26,166.44 123.24,166.52
  L3SGND w0.152: v1(89.01,107.58) 89.47,107.12 90.26,107.12 90.53,106.84 93.18,106.84 93.91,107.58 94.54,107.58 94.56,107.6 94.94,107.6 94.97,107.58 95.58,107.58 95.82,107.34 96.85,107.34 97.08,107.58 114.6,125.1 114.6,125.57 114.1,126.08 114.1,127.1 115.65,128.65 116.84,128.65 116.99,128.8 116.99,129.17 116.84,129.32 116.46,129.32 116.31,129.48 116.31,129.82 116.46,129.97 117.02,129.97 117.17,130.12 117.17,131.09 119.19,133.11 119.19,149.24 122.09,152.14 122.09,154.6 122.53,155.04 122.53,156.24 121.69,157.08 121.69,157.82 122.51,158.64 122.51,160.04 121.69,160.86 121.69,161.84 122.54,162.69 122.54,163.67 122.56,163.69 122.56,163.73 123.18,164.36 123.18,165.75 123.26,165.83 123.26,166.22
M_B_DQ56: length 99.2
  TOP w0.165: CPU1.AJ7 88.72,105.32 89.01,105.02 v1(89.01,104.86)
  L3SGND w0.089: v1(89.01,104.86) 89.01,104.56 89.18,104.39 90.2,104.39 90.37,104.22 91.14,104.22 91.69,104.78 94.84,104.78 95.14,105.07 ; DIMM2.130 127.99,165.09 128.06,165.19 arc(126.94,165.39) 127.42,164.36 127.49,164.32
  L3SGND w0.102: 127.49,164.32 127.51,164.24 127.51,164.02
  L3SGND w0.152: 95.14,105.07 95.3,105.23 99.57,105.23 100.33,105.99 100.69,105.99 100.91,105.77 101.19,105.77 101.43,106 101.43,106.21 101.02,106.62 101.02,106.84 101.26,107.08 101.48,107.08 101.89,106.67 102.1,106.67 102.34,106.92 102.34,107.13 101.94,107.54 101.94,107.75 102.18,108 102.4,108 102.8,107.59 103.02,107.59 103.26,107.83 103.26,108.05 102.85,108.45 102.85,108.67 103.1,108.91 103.31,108.91 103.72,108.51 103.93,108.51 104.18,108.75 104.18,108.96 103.77,109.37 103.77,109.59 104.01,109.83 104.23,109.83 104.64,109.42 104.85,109.42 105.09,109.67 105.09,109.88 104.69,110.29 104.69,110.5 104.93,110.75 105.14,110.75 105.55,110.34 105.77,110.34 106.01,110.58 106.01,110.8 105.6,111.2 105.6,111.42 105.85,111.66 106.06,111.66 106.47,111.26 106.68,111.26 106.93,111.5 106.93,111.71 106.52,112.12 106.52,112.34 106.76,112.58 106.98,112.58 107.38,112.17 107.6,112.17 107.84,112.41 107.84,112.63 107.44,113.04 107.44,113.25 107.68,113.5 107.89,113.5 108.3,113.09 108.52,113.09 122.48,127.05 122.48,147.68 125.62,150.81 125.62,153.56 126.3,154.24 126.3,154.53 127.26,155.49 127.26,156.24 126.77,156.73 126.77,158.65 127.26,159.14 127.26,160.15 126.79,160.62 126.79,162.13 127.26,162.6 127.26,163.77 127.51,164.02
M_B_DQ57: length 98.8
  TOP w0.165: CPU1.AH6 v1(89.01,103.94)
  L3SGND w0.089: DIMM2.275 128.84,167.29 128.91,167.39 arc(127.79,167.59) 128.27,166.56 128.34,166.52 ; v1(89.01,103.94) 89.44,103.52 90.1,103.52 90.52,103.94 91.17,103.94 91.76,104.52 95.07,104.52 95.29,104.74
  L3SGND w0.102: 128.36,166.22 128.36,166.44 128.34,166.52
  L3SGND w0.152: 95.29,104.74 95.43,104.88 100.53,104.88 100.73,105.08 101.42,105.08 123.13,126.78 123.13,146.04 123.6,146.51 123.6,146.73 123.14,147.18 123.14,147.4 123.39,147.65 123.61,147.65 124.08,147.18 124.3,147.18 124.55,147.43 124.55,147.65 124.08,148.12 124.08,148.33 124.33,148.59 124.54,148.59 124.91,148.22 125.13,148.22 125.38,148.47 125.38,148.69 125,149.06 125,149.28 125.25,149.53 125.47,149.53 125.94,149.06 126.15,149.06 126.4,149.31 126.4,149.53 125.93,150 125.93,150.21 126.19,150.47 126.4,150.47 126.87,150 127.09,150 127.74,150.65 127.74,151.08 127.51,151.31 126.62,151.31 126.26,151.66 126.26,153.13 127.2,154.07 127.2,154.51 127.64,154.95 127.64,156.25 128.3,156.9 128.3,158.29 127.64,158.95 127.64,160.26 128.22,160.84 128.22,162.05 127.64,162.63 127.64,163.71 128.36,164.43 128.36,166.22
M_B_DQ58: length 100.9
  TOP w0.165: CPU1.AF7 v1(88.1,102.11)
  L3SGND w0.089: DIMM2.137 133.94,163.49 134.01,163.59 arc(132.89,163.79) 133.37,162.76 133.44,162.72
  L3SGND w0.102: 133.46,162.42 133.46,162.64 133.44,162.72
  L3SGND w0.152: v1(88.1,102.11) 88.1,101.85 88.29,101.66 89.2,101.66 89.61,101.24 91.28,101.24 92,101.96 93.09,101.96 93.25,101.8 95.27,101.8 95.45,101.98 102.44,101.98 126,125.54 126,143.42 133.12,150.55 133.12,150.84 132.97,150.99 132.65,150.99 132.5,151.14 132.5,151.57 132.65,151.73 133.26,151.73 133.44,151.9 133.44,152.22 133.28,152.37 132.13,152.37 131.98,152.53 131.98,152.87 132.13,153.02 133.26,153.02 133.44,153.2 133.44,153.52 133.28,153.67 132.16,153.67 132,153.82 132,154.17 132.16,154.32 133.53,154.32 133.68,154.47 133.68,154.8 133.53,154.95 132.89,154.95 132.74,155.1 132.74,155.53 132.74,156.4 133.22,156.88 133.22,157.85 132.72,158.35 132.72,159.32 132.71,159.32 132.71,159.88 132.72,159.89 132.72,160.16 133.21,160.65 133.21,161.94 133.46,162.19 133.46,162.42
M_B_DQ59: length 101.1
  TOP w0.165: CPU1.AE7 v1(88.1,101.2)
  L3SGND w0.089: DIMM2.282 134.79,168.89 134.86,168.99 arc(133.74,169.19) 134.22,168.16 134.29,168.12
  L3SGND w0.102: 134.29,168.12 134.31,168.04 134.31,167.82
  L3SGND w0.152: v1(88.1,101.2) 88.8,100.74 89.32,100.74 89.93,100.82 91.37,100.82 92.23,101.68 92.97,101.68 93.13,101.52 102.89,101.52 126.64,125.27 126.64,143.15 134.08,150.59 134.08,153.78 134.37,154.06 134.37,156.31 133.58,157.1 133.58,158.05 134.26,158.74 134.26,159.85 133.58,160.54 133.58,161.77 134.37,162.56 134.37,163.77 133.47,164.67 133.47,166 134.31,166.85 134.31,167.82
M_B_DQ60: length 99.8
  TOP w0.165: v1(88.11,104.89) 88.11,104.85 CPU1.AH7
  L3SGND w0.089: v1(88.11,104.89) 88.53,105.32 92.06,105.32 92.29,105.55 ; 125.79,164.32 125.75,164.36 125.72,164.36 arc(125.24,165.39) 126.36,165.19 126.29,165.09 DIMM2.128
  L3SGND w0.102: 125.79,164.32 125.81,164.24 125.81,164.02
  L3SGND w0.152: 92.29,105.55 92.46,105.71 93.8,105.71 94.14,106.05 98.31,106.05 113.95,121.69 113.95,121.69 114.13,121.87 114.63,121.87 114.95,121.54 115.14,121.54 115.44,121.84 115.44,122.03 114.97,122.5 114.97,122.71 115.23,122.97 115.46,122.97 115.91,122.52 116.11,122.52 116.39,122.79 116.39,123 115.93,123.46 115.93,123.67 116.17,123.92 116.39,123.92 116.84,123.46 117.06,123.46 117.3,123.71 117.3,123.92 116.85,124.37 116.85,124.59 117.09,124.83 117.31,124.83 117.76,124.38 117.97,124.38 118.22,124.62 118.22,124.84 117.76,125.29 117.76,125.51 118.01,125.75 118.22,125.75 118.68,125.3 118.89,125.3 119.13,125.54 119.13,125.75 118.72,126.17 118.72,126.39 118.96,126.63 119.17,126.63 119.59,126.21 119.81,126.21 120.05,126.45 120.05,126.67 119.77,126.95 119.77,127.16 120.02,127.41 120.23,127.41 120.51,127.13 120.72,127.13 121.18,127.59 121.18,128.31 121.03,128.46 120.29,128.46 120.15,128.6 120.15,128.97 120.29,129.11 121.03,129.11 121.18,129.26 121.18,129.6 121.03,129.75 120.37,129.75 120.22,129.91 120.22,130.25 120.37,130.4 121.03,130.4 121.18,130.55 121.18,130.9 121.03,131.05 120.57,131.05 120.42,131.2 120.42,131.54 120.57,131.7 121.03,131.7 121.18,131.85 121.18,147.7 121.18,148.24 124.32,151.37 124.32,154.09 125.56,155.33 125.56,156.3 124.79,157.07 124.79,157.89 125.58,158.68 125.58,159.92 125.06,160.43 125.06,162.11 125.56,162.61 125.56,163.77 125.81,164.02
M_B_DQ61: length 98.2
  TOP w0.165: CPU1.AJ6 v1(89.93,104.86)
  L3SGND w0.089: DIMM2.273 127.14,167.29 127.21,167.39 arc(126.09,167.59) 126.57,166.56 126.64,166.52 ; v1(89.93,104.86) 90.21,104.86 90.64,104.43 91.02,104.43 91.68,105.09 92.47,105.09
  L3SGND w0.102: 126.64,166.52 126.66,166.44 126.66,166.22
  L3SGND w0.152: 92.47,105.09 93.83,105.09 94.51,105.77 98.95,105.77 107.42,114.25 108.06,114.25 108.16,114.14 108.3,114.01 108.52,114.01 108.98,114.47 108.98,114.68 108.53,115.14 108.53,115.35 108.77,115.6 108.99,115.6 109.44,115.14 109.66,115.14 109.9,115.39 109.9,115.6 109.44,116.05 109.44,116.27 109.69,116.51 109.9,116.51 110.36,116.06 110.57,116.06 110.81,116.3 110.81,116.52 110.36,116.97 110.36,117.19 110.6,117.43 110.82,117.43 111.27,116.98 111.49,116.98 111.73,117.22 111.73,117.43 111.28,117.89 111.28,118.1 111.52,118.35 111.74,118.35 112.19,117.89 112.4,117.89 112.65,118.14 112.65,118.35 112.19,118.8 112.19,119.02 112.44,119.26 112.65,119.26 113.11,118.81 113.32,118.81 113.56,119.05 113.56,119.27 113.18,119.65 113.18,119.86 113.44,120.12 113.63,120.12 114.02,119.73 114.24,119.73 114.48,119.97 114.48,120.18 114.12,120.54 114.12,120.75 114.37,121 114.58,121 114.94,120.64 115.15,120.64 121.83,127.32 121.83,147.97 124.97,151.11 124.97,153.82 125.65,154.51 125.65,154.78 125.94,155.06 125.94,156.62 126.42,157.1 126.42,158.06 125.94,158.54 125.94,160.24 126.41,160.71 126.41,162.58 125.94,163.05 125.94,163.71 126.58,164.35 126.58,165.72 126.66,165.8 126.66,166.22
M_B_DQ62: length 100.1
  TOP w0.165: CPU1.AF6 v1(89.93,102.11)
  L3SGND w0.089: v1(89.93,102.11) 90.38,102.57 91.28,102.57 91.43,102.72 91.96,102.72 ; 131.74,162.72 131.67,162.76 arc(131.19,163.79) 132.31,163.59 132.24,163.49 DIMM2.135
  L3SGND w0.102: 131.74,162.72 131.76,162.64 131.76,162.42
  L3SGND w0.152: 131.76,162.42 131.76,162.16 131.51,161.91 131.51,160.78 130.89,160.15 130.89,158.72 131.56,158.04 131.56,156.94 130.86,156.24 130.86,155.08 130.71,154.93 130.34,154.93 130.19,154.77 130.19,154.28 130.34,154.13 130.58,154.13 130.67,154.04 130.67,153.58 130.43,153.34 130.43,152.96 130.67,152.72 130.67,152.32 130.39,152.04 130.39,151.05 129.93,150.59 129.93,150.37 130.42,149.89 130.42,149.67 130.17,149.43 129.96,149.43 129.47,149.92 129.26,149.92 129.02,149.67 129.02,149.46 129.5,148.97 129.5,148.76 129.26,148.52 129.04,148.52 128.56,149 128.34,149 128.1,148.76 128.1,148.54 128.58,148.06 128.58,147.84 128.34,147.6 128.12,147.6 127.64,148.08 127.43,148.08 127.18,147.84 127.18,147.62 127.67,147.14 127.67,146.93 127.42,146.68 127.21,146.68 126.72,147.17 126.51,147.17 126.27,146.92 126.27,146.71 126.75,146.22 126.75,146.01 126.51,145.77 126.29,145.77 125.81,146.25 125.59,146.25 125.34,146 125.34,145.78 125.76,145.36 125.76,145.06 125.57,144.88 125.3,144.88 125.11,145.07 124.87,145.07 124.7,144.91 124.7,126.08 101.54,102.92 101.03,102.92 100.75,103.2 100.37,103.2 100.09,102.92 99.71,102.92 99.43,103.2 99.05,103.2 98.77,102.92 98.39,102.92 98.11,103.2 97.73,103.2 97.45,102.92 97.07,102.92 96.79,103.2 96.41,103.2 96.13,102.92 95.37,102.92 95.26,103.02 94.02,103.02 93.72,102.72 91.96,102.72
M_B_DQ63: length 99.9
  TOP w0.165: CPU1.AE6 v1(89.01,102.11)
  L3SGND w0.089: DIMM2.280 133.09,168.89 133.16,168.99 arc(132.04,169.19) 132.52,168.16 132.59,168.12
  L3SGND w0.102: 132.59,168.12 132.61,168.04 132.61,167.82
  L3SGND w0.152: v1(89.01,102.11) 89.28,102.11 89.74,101.66 91.29,101.66 91.97,102.34 93.45,102.34 93.71,102.08 94.93,102.08 95.31,102.46 102,102.46 125.35,125.81 125.35,143.69 131.8,150.14 131.8,150.33 131.65,150.48 131.19,150.48 131.04,150.63 131.04,150.98 131.19,151.13 131.7,151.13 131.85,151.28 131.85,151.62 131.7,151.78 131.47,151.78 131.32,151.93 131.32,154.8 131.44,154.93 132.18,154.93 132.36,155.1 132.36,155.53 132.36,156.45 131.84,156.97 131.84,158.33 132.36,158.85 132.36,159.33 132.36,160.21 131.89,160.68 131.89,161.77 132.53,162.41 132.53,163.79 131.78,164.55 131.78,165.96 132.61,166.8 132.61,167.82
M_B_DQS_DN0: length 98.9
  TOP w0.178: v1(61.21,103.03) CPU1.AF34
  L3SGND w0.152: DIMM2.152 18.93,168.26 18.86,168.01 18.7,167.92 18.52,167.74 18.52,166.64 17.68,165.81 17.68,164.56 18.52,163.73 18.52,162.7 19.38,161.83 19.38,160.89 18.51,160.02 18.51,158.8 19.35,157.95 19.35,156.96 20.22,156.09 20.22,153.51 25.3,148.43 25.3,127.65 25.36,127.53 29.35,123.54 29.35,123.26 28.67,122.58 28.67,122.14 29.09,121.72 29.54,121.72 30.14,122.33 30.35,122.33 30.61,122.07 30.61,121.86 29.81,121.06 29.81,120.62 34.26,116.17 34.26,113.44 45.36,102.34 53.19,102.34 53.51,102.66 60.02,102.66 60.1,102.57 60.75,102.57 v1(61.21,103.03)
M_B_DQS_DN1: length 87.8
  TOP w0.178: v1(63.04,106.69) CPU1.AK33
  L3SGND w0.089: v1(63.04,106.69) 63.02,106.69 62.7,107.01 62.43,107.01 61.42,108.03 57.62,108.03 57.56,107.97
  L3SGND w0.152: DIMM2.163 28.29,167.74 28.49,167.8 28.63,167.73 28.7,167.66 28.7,166.51 27.88,165.69 27.88,164.71 27.03,163.86 27.03,162.89 27.84,162.07 27.84,160.8 28.7,159.94 28.7,158.8 29.54,157.96 29.54,156.97 30.4,156.11 30.4,154.78 31.51,153.68 31.51,132.64 37.32,126.82 40.19,126.82 41.34,125.68 41.34,115.09 47.02,109.41 51.84,109.41 52.69,108.56 54.44,108.56 55.03,107.97 57.05,107.97 57.05,107.97 57.56,107.97
M_B_DQS_DN2: length 77.4
  TOP w0.178: v1(62.12,110.34) CPU1.AN33
  L3SGND w0.089: v1(62.12,110.34) 62.12,110.35 61.63,110.84 61.63,111.44 61.62,111.45 61.62,111.49 61.21,111.9 60.65,111.9 60.26,112.29 59.66,112.29
  L3SGND w0.152: 59.66,112.29 57.09,112.29 56.48,112.9 56.48,114.08 54.81,115.75 54.81,119.82 49.45,125.18 49.45,127.93 47.88,129.5 47.88,137.66 48.19,137.98 48.9,137.98 49.05,138.13 49.05,138.47 48.9,138.63 48.23,138.63 47.91,138.94 47.91,139.52 48.23,139.83 48.9,139.83 49.05,139.99 49.05,140.33 48.9,140.48 48.19,140.48 47.76,140.91 47.76,141.71 41.28,148.19 40.42,148.19 38.51,150.1 38.51,154.94 38.91,155.35 38.91,156.11 38.05,156.97 38.05,157.96 37.19,158.82 37.19,159.91 36.37,160.73 36.37,161.89 37.21,162.72 37.21,163.71 36.36,164.57 36.36,165.82 37.21,166.67 37.21,167.91 37.35,168.05 DIMM2.174
M_B_DQS_DN3: length 73.6
  TOP w0.178: v1(66.7,109.43) CPU1.AN29
  L3SGND w0.089: 65.04,113.4 65.18,113.26 65.18,113.17 65.2,113.15 65.2,111.79 67.12,109.87 67.12,109.64 66.91,109.43 v1(66.7,109.43)
  L3SGND w0.152: 65.04,113.4 62.74,115.71 62.74,116.6 60.88,118.46 60.88,124.91 55.63,130.16 55.63,146.63 55.47,146.78 54.85,146.78 54.53,147.1 54.53,147.67 54.85,147.99 55.45,147.99 55.6,148.14 55.6,148.49 55.45,148.64 51.69,148.64 49.1,151.23 49.1,156.14 48.26,156.98 48.26,157.92 47.43,158.75 47.43,159.88 46.58,160.73 46.58,162 45.69,162.89 45.69,163.8 46.56,164.67 46.56,165.68 47.4,166.52 47.4,167.65 47.29,167.75 47.19,167.8 46.99,167.74 DIMM2.185
M_B_DQS_DN4: length 76.8
  TOP w0.178: CPU1.AN13 80.87,109.8 v1(81.33,109.35)
  L3SGND w0.089: v1(81.33,109.35) 81.9,109.92 82.42,109.92 82.42,109.92 82.45,109.92 83.58,111.05 83.58,111.94 83.52,112
  L3SGND w0.152: DIMM2.244 101.95,168.12 101.79,167.95 101.79,166.64 100.98,165.84 100.98,164.57 101.83,163.72 101.83,162.85 100.98,162 100.98,160.85 100.13,160 100.13,159.2 100.97,158.37 100.97,157.08 100.13,156.25 100.13,155.42 99.59,154.87 99.59,149.49 94.55,144.44 94.55,139.78 94.37,139.6 93.28,139.6 92.94,139.26 92.94,138.69 93.25,138.38 94.37,138.38 94.53,138.23 94.53,137.87 94.37,137.72 93.43,137.72 93.09,137.38 93.09,136.82 93.41,136.5 94.31,136.5 94.46,136.35 94.46,135.67 94.32,135.53 91.77,135.53 91.25,135.01 91.25,122.02 84.68,115.45 84.68,113.29 83.52,112.14 83.52,112
M_B_DQS_DN5: length 78.3
  TOP w0.178: v1(87.18,110.34) CPU1.AR8
  L3SGND w0.089: v1(87.18,110.34) 87.55,110.9 87.66,111.07 87.67,111.09 87.67,111.44 87.93,111.7 88.37,111.7 88.46,111.79
  L3SGND w0.152: DIMM2.255 111.44,167.75 111.53,167.84 111.71,167.84 111.99,167.56 111.99,166.71 111.18,165.91 111.18,164.7 110.33,163.85 110.33,162.49 111.13,161.68 111.14,161.58 111.14,160.8 110.3,159.97 110.3,158.88 111.14,158.04 111.14,157.12 110.33,156.31 110.33,151.52 100.66,141.84 100.66,139.75 100.98,139.44 101.7,139.44 101.85,139.29 101.85,138.93 101.7,138.78 100.98,138.78 100.66,138.46 100.66,137.88 100.98,137.56 101.7,137.56 101.85,137.41 101.85,137.05 101.7,136.9 100.98,136.9 100.66,136.58 100.66,136 100.98,135.68 101.68,135.68 101.83,135.53 101.83,135.17 101.68,135.02 100.98,135.02 100.66,134.7 100.66,122.04 97.41,118.79 97.41,117.56 94.75,114.91 94.36,114.91 91.77,112.32 88.99,112.32 88.46,111.79
M_B_DQS_DN6: length 87.3
  TOP w0.178: CPU1.AM8 v1(87.25,107.57)
  L3SGND w0.089: v1(87.25,107.57) 87.93,108.25 92.81,108.25 92.86,108.29
  L3SGND w0.152: 92.86,108.29 93.04,108.29 93.24,108.49 95.77,108.49 111.1,123.82 111.1,130.11 107.98,133.23 107.98,140.31 110.82,143.15 112.49,143.15 115.98,146.64 116.48,146.64 116.76,146.35 116.98,146.35 117.22,146.6 117.22,146.81 116.93,147.1 116.93,147.6 117.61,148.28 117.61,149.89 120.52,152.79 120.52,156.14 119.68,156.97 119.68,158.26 120.52,159.1 120.52,159.94 119.66,160.8 119.66,161.9 120.49,162.73 120.49,163.68 120.08,164.09 120.07,164.09 119.65,164.5 119.65,165.81 120.49,166.66 120.49,167.75 120.7,167.96 120.87,168.05 120.94,168.26 DIMM2.266
M_B_DQS_DN7: length 99.2
  TOP w0.178: CPU1.AG6 v1(89.93,103.03)
  L3SGND w0.089: 93.73,103.91 93.72,103.9 93.72,103.82 93.71,103.8 93.71,103.76 93.47,103.52 91.22,103.52 91.1,103.65 90.54,103.65 v1(89.93,103.03)
  L3SGND w0.152: 93.73,103.91 93.94,104.11 95.19,104.11 95.51,104.43 101.69,104.43 123.77,126.51 123.77,145.74 129.46,151.43 129.46,151.81 129.3,151.98 127.27,151.98 126.95,152.3 126.95,152.87 127.27,153.19 129.26,153.19 129.41,153.34 129.41,153.69 129.26,153.84 128.23,153.84 127.91,154.15 127.91,154.68 128.23,154.99 128.85,154.99 129.01,155.15 129.01,156.19 129.84,157.03 129.84,158 129.01,158.84 129.01,160.01 129.84,160.85 129.84,162.19 129.03,163 129.03,163.89 129.88,164.74 129.88,165.62 130.73,166.47 130.73,167.71 130.44,168.01 129.54,168.01 129.39,167.85 129.39,167.35 129.54,167.2 DIMM2.277
M_B_DQS_DP0: length 98.9
  TOP w0.178: CPU1.AF35 60.63,103.61 60.43,103.61 60.27,103.45 60.27,103.18 v1(60.29,103.03)
  L3SGND w0.152: v1(60.29,103.03) 60.56,103.03 60.77,103.24 60.77,103.45 60.62,103.61 60.25,103.61 59.58,102.94 53.39,102.94 53.07,102.62 45.48,102.62 34.54,113.55 34.54,116.28 30.09,120.73 30.09,120.95 30.89,121.75 30.89,122.18 30.47,122.61 30.03,122.61 29.42,122 29.2,122 28.95,122.25 28.95,122.47 29.63,123.14 29.63,123.66 25.59,127.7 25.58,127.72 25.58,148.55 20.5,153.63 20.5,156.21 19.63,157.07 19.63,158.06 18.79,158.91 18.79,159.9 19.66,160.78 19.66,161.95 18.8,162.81 18.8,163.84 17.96,164.68 17.96,165.69 18.8,166.53 18.8,167.63 18.87,167.7 18.99,167.76 19.24,167.68 DIMM2.153
M_B_DQS_DP1: length 87.8
  TOP w0.178: v1(63.04,107.6) CPU1.AL33
  L3SGND w0.089: v1(63.04,107.6) 63.04,107.36 62.88,107.2 62.51,107.2 61.5,108.22 57.64,108.22 57.61,108.25
  L3SGND w0.152: 57.61,108.25 55.15,108.25 54.56,108.84 52.81,108.84 51.96,109.69 47.13,109.69 41.62,115.2 41.62,125.79 40.31,127.1 37.44,127.1 31.79,132.75 31.79,153.8 30.68,154.9 30.68,156.22 29.82,157.08 29.82,158.08 28.98,158.91 28.98,160.06 28.12,160.92 28.12,162.19 27.3,163 27.3,163.74 28.16,164.6 28.16,165.57 28.98,166.39 28.98,167.78 28.8,167.96 28.63,168.05 28.56,168.26 DIMM2.164
M_B_DQS_DP2: length 77.4
  TOP w0.178: v1(62.12,111.26) CPU1.AP33
  L3SGND w0.089: v1(62.12,111.26) 62.01,111.37 61.29,112.09 60.73,112.09 60.33,112.48 59.84,112.48 59.75,112.57 59.66,112.57
  L3SGND w0.152: DIMM2.175 38.56,167.56 38.56,167.92 38.37,168.11 37.81,168.11 37.49,167.79 37.49,166.56 36.63,165.7 36.63,164.69 37.49,163.83 37.49,162.61 36.65,161.77 36.65,160.85 37.47,160.03 37.47,158.93 38.33,158.08 38.33,157.08 39.19,156.22 39.19,155.23 38.79,154.83 38.79,150.22 40.53,148.47 41.4,148.47 48.04,141.83 48.04,141.03 48.31,140.76 49.01,140.76 49.33,140.44 49.33,139.87 49.01,139.55 48.34,139.55 48.19,139.4 48.19,139.06 48.34,138.91 49.01,138.91 49.33,138.59 49.33,138.02 49.01,137.7 48.31,137.7 48.16,137.55 48.16,129.62 49.73,128.04 49.73,125.3 55.09,119.94 55.09,115.86 56.76,114.2 56.76,113.02 57.2,112.57 59.66,112.57
M_B_DQS_DP3: length 73.7
  TOP w0.178: CPU1.AN28 67.57,109.47 v1(67.57,109.43)
  L3SGND w0.089: v1(67.57,109.43) 67.31,109.69 67.31,109.95 65.39,111.87 65.39,113.23 65.37,113.25 65.37,113.34 65.26,113.45 65.26,113.58 65.24,113.6
  L3SGND w0.152: DIMM2.186 47.33,168.38 47.33,168.05 47.46,167.98 47.68,167.76 47.68,166.41 46.84,165.57 46.84,164.55 45.97,163.68 45.97,163.01 46.86,162.12 46.86,160.85 47.71,159.99 47.71,158.86 48.54,158.04 48.54,157.1 49.38,156.26 49.38,151.34 51.8,148.92 55.56,148.92 55.88,148.6 55.88,148.03 55.56,147.71 54.97,147.71 54.81,147.56 54.81,147.22 54.97,147.06 55.59,147.06 55.91,146.75 55.91,130.27 61.16,125.02 61.16,118.58 63.02,116.72 63.02,115.82 65.24,113.6
M_B_DQS_DP4: length 76.8
  TOP w0.178: CPU1.AN12 81.78,109.86 v1(82.19,109.46)
  L3SGND w0.089: 83.8,112 83.77,111.96 83.77,110.98 82.53,109.73 82.46,109.73 v1(82.19,109.46)
  L3SGND w0.152: 83.8,112 83.8,112.02 84.96,113.18 84.96,115.33 91.53,121.9 91.53,134.9 91.89,135.25 94.44,135.25 94.74,135.56 94.74,136.46 94.43,136.78 93.52,136.78 93.37,136.93 93.37,137.26 93.55,137.44 94.49,137.44 94.81,137.76 94.81,138.34 94.49,138.66 93.37,138.66 93.22,138.81 93.22,139.14 93.4,139.32 94.49,139.32 94.83,139.66 94.83,144.33 99.87,149.37 99.87,154.76 100.41,155.3 100.41,156.14 101.24,156.97 101.24,158.49 100.41,159.32 100.41,159.88 101.26,160.73 101.26,161.89 102.11,162.74 102.11,163.84 101.26,164.69 101.26,165.73 102.07,166.53 102.07,167.84 102.46,168.24 102.7,168.24 102.8,168.13 DIMM2.245
M_B_DQS_DP5: length 78.3
  TOP w0.178: v1(88.1,110.34) CPU1.AP8
  L3SGND w0.089: 88.64,111.57 88.54,111.48 88.54,111.05 88.33,110.83 88.19,110.83 88.1,110.74 v1(88.1,110.34)
  L3SGND w0.152: DIMM2.256 111.76,168.41 111.76,168.19 112.27,167.68 112.27,166.59 111.46,165.79 111.46,164.59 110.61,163.73 110.61,162.6 111.42,161.8 111.42,160.69 110.58,159.85 110.58,159 111.42,158.16 111.42,157 110.61,156.2 110.61,151.4 100.94,141.73 100.94,139.87 101.09,139.72 101.82,139.72 102.13,139.4 102.13,138.81 101.82,138.5 101.09,138.5 100.94,138.35 100.94,137.99 101.09,137.84 101.82,137.84 102.13,137.52 102.13,136.94 101.82,136.62 101.09,136.62 100.94,136.47 100.94,136.11 101.09,135.96 101.79,135.96 102.11,135.64 102.11,135.06 101.79,134.74 101.09,134.74 100.94,134.59 100.94,121.93 97.69,118.68 97.69,117.45 94.87,114.63 94.48,114.63 91.89,112.04 89.1,112.04 88.64,111.57
M_B_DQS_DP6: length 87.3
  TOP w0.178: CPU1.AL8 v1(88.14,107.57)
  L3SGND w0.089: 92.93,108.01 92.9,108.01 92.86,108.06 88.01,108.06 87.78,107.83 87.78,107.67 87.88,107.57 v1(88.14,107.57)
  L3SGND w0.152: 92.93,108.01 93.16,108.01 93.35,108.21 95.89,108.21 111.38,123.7 111.38,130.23 108.25,133.35 108.25,140.19 110.94,142.88 112.61,142.88 116.09,146.36 116.36,146.36 116.65,146.07 117.09,146.07 117.5,146.48 117.5,146.93 117.21,147.21 117.21,147.48 117.89,148.16 117.89,149.78 120.79,152.68 120.79,156.25 119.96,157.08 119.96,158.14 120.8,158.98 120.8,160.05 119.94,160.92 119.94,161.78 120.77,162.61 120.77,163.8 120.2,164.37 120.18,164.37 119.93,164.62 119.93,165.7 120.77,166.54 120.77,167.63 120.87,167.73 121.01,167.8 121.21,167.74 DIMM2.267
M_B_DQS_DP7: length 99.3
  TOP w0.178: v1(89.01,103.03) CPU1.AG7
  L3SGND w0.089: v1(89.01,103.03) 89.7,102.6 90.1,102.6 90.29,102.8 90.37,103 90.43,103.17 90.48,103.28 90.64,103.45 91.02,103.45 91.14,103.33 93.55,103.33 93.95,103.73
  L3SGND w0.152: DIMM2.278 130.85,167.99 131.01,167.83 131.01,166.36 130.16,165.51 130.16,164.62 129.31,163.77 129.31,163.12 130.12,162.31 130.12,160.73 129.29,159.89 129.29,158.95 130.12,158.12 130.12,156.91 129.29,156.08 129.29,155.04 128.96,154.71 128.35,154.71 128.19,154.56 128.19,154.27 128.35,154.12 129.38,154.12 129.69,153.8 129.69,153.23 129.38,152.91 127.38,152.91 127.23,152.76 127.23,152.41 127.38,152.26 129.41,152.26 129.74,151.93 129.74,151.32 124.05,145.63 124.05,126.4 101.81,104.15 95.62,104.15 95.3,103.84 94.06,103.84 93.95,103.73
M_B_ODT0: length 65.6
  TOP w0.165: CPU1.AM16 78.53,109.38 v1(78.53,109.44)
  L3SGND w0.152: DIMM2.87 90.9,162.2 91.09,162.01 91.09,160.61 91.72,159.98 91.72,158.71 90.91,157.9 90.91,157.01 91.8,156.12 91.8,155.49 92.6,154.69 92.86,154.69 93.01,154.54 93.01,154.24 92.86,154.08 92.6,154.08 92.44,153.93 92.44,153.63 92.6,153.47 92.86,153.47 93.01,153.32 93.01,153.02 92.86,152.87 92.6,152.87 92.44,152.71 92.44,152.41 92.6,152.26 92.86,152.26 93.01,152.1 93.01,151.8 92.86,151.65 92.6,151.65 92.44,151.49 92.44,151.19 92.6,151.04 92.86,151.04 93.01,150.88 93.01,150.58 92.86,150.43 92.6,150.43 92.44,150.27 92.44,149.97 92.6,149.82 92.86,149.82 93.01,149.66 93.01,149.36 92.86,149.21 92.6,149.21 92.44,149.06 92.44,148.48 84.85,140.89 84.85,140.88 84.82,140.85 84.82,121.72 81.16,118.07 81.16,114.11 80.06,113 80.06,110.97 v1(78.53,109.44)
M_B_ODT1: length 66.4
  TOP w0.165: CPU1.AL16 v1(78.58,107.6)
  L3SGND w0.152: DIMM2.91 94.3,160.81 95.17,159.93 95.17,159.01 94.31,158.15 94.31,157.01 95.2,156.12 95.2,154.97 95.05,154.82 94.74,154.82 94.58,154.67 94.58,154.37 94.74,154.21 94.89,154.21 95.05,154.06 95.05,153.76 94.89,153.6 94.74,153.6 94.58,153.45 94.58,153.15 94.74,152.99 94.89,152.99 95.05,152.84 95.05,152.54 94.89,152.38 94.74,152.38 94.58,152.23 94.58,149.2 85.83,140.45 85.83,121.31 83.06,118.54 83.06,117.26 81.92,116.12 81.92,113.82 80.85,112.75 80.85,109.4 80.44,108.99 79.27,108.99 78.58,108.3 v1(78.58,107.6)
M_B_PARITY: length 70.4
  TOP w0.216: CPU1.AL20 v1(74.92,107.6)
  L3SGND w0.127: v1(74.92,107.6) 74.45,108.08 74.45,108.32 74.45,108.33 74.45,108.7 74.45,108.71 74.45,113.41 74.83,113.79
  L3SGND w0.191: DIMM2.222 80.83,168.8 80.14,168.11 80.14,148.01 80.33,147.82 80.77,147.82 80.96,147.63 80.96,147.25 80.77,147.06 80.33,147.06 80.14,146.87 80.14,146.49 80.33,146.3 80.73,146.3 80.92,146.11 80.92,145.73 80.73,145.54 80.33,145.54 80.14,145.34 80.14,144.96 80.33,144.77 80.68,144.77 80.87,144.58 80.87,144.2 80.68,144.01 80.33,144.01 80.14,143.82 80.14,123.66 76.33,119.84 76.33,118.76 75.69,118.12 75.69,115.94 75.14,115.39 75.14,115.37 75.04,115.28 75.04,114.01 74.83,113.79
M_VREF_DQ_DIM0: length 3.8
  TOP w0.102: CPU1.AC40 55.52,100.74 54.9,100.13 54.9,99.3 55.12,99.09 55.12,98.95 v3(55.15,98.92)
  BOTTOM w0.102: TP601.1 55.14,98.93 v3(55.15,98.92)
M_VREF_DQ_DIM1: length 108.7
  TOP w0.305: C1209.1 14.35,174.41 14.35,173.88 R1204.1 14.55,173.62 13.97,173.04 13.97,171.94 13.89,171.87 v3(13.89,170.43) ; CPU1.AC39 56.64,100.29 55.94,100.29 55.67,100.02 55.67,99.19 55.71,99.15 55.71,98.66 v3(55.3,98.25) ; C603.1 v3(18.36,136.98)
  BOTTOM w0.305: v3(55.3,98.25) 55.24,98.3 43.48,98.3 v2(29.55,112.23) 18.39,123.39 18.39,136.96 v3(18.36,136.98) 18.36,143.03 10.26,151.13 10.26,156.5 10.06,156.7 10.06,164.29 10.49,164.72 11.3,165.53 11.3,167.72 13.72,170.13 13.72,170.26 v3(13.89,170.43)
MB_REG_PG: length 39
  TOP w0.102: Q2406.6 167.93,40.58 167.82,40.47 167.82,39.67 167.42,39.28 Q2406.3 166.87,39.28 165.92,39.28 v3(165.32,38.68) ; R2469.1 158.09,26.26 v3(158.87,27.05) 159.51,26.4 159.51,25.8 161.53,23.78 U2401.109 ; Q2402.6 159,34.25 159,34.75 159.22,34.97 v3(159.46,34.97) 159.46,36.67 159.65,36.86 159.92,36.86 160.11,37.05 Q2405.6
  BOTTOM w0.102: v3(158.87,27.05) 161.44,27.05 164.26,29.87 164.26,32.15 161.44,34.97 v3(159.46,34.97) 161,36.5 161.01,36.5 161.39,36.88 161.39,37.12 162.17,37.9 v2(163.32,37.9) 164.53,37.9 v3(165.32,38.68)
MB_REG_PG_1: length 3.7
  TOP w0.102: R2404.2 155.45,32.3 v2(155.45,33.17) R2409.1 155.94,33.58 Q2402.2
MB_REG_PG_2: length 6.3
  TOP w0.102: Q2406.5 169.44,39.93 169.67,39.7 169.67,38.15 169.27,37.74 R2424.1 168.19,36.68 v2(167.77,36.68) 167.77,37.5 R2415.2
MB_REG_PG_3: length 4.8
  TOP w0.102: R2414.2 R2423.1 164.85,40.06 v3(165.35,39.55) 165.74,39.93 Q2406.2
  BOTTOM w0.102: v3(165.35,39.55) v2(164.36,39.55)
MCLK: length 6.2
  TOP w0.102: RN2403.2 158.72,23.02 v2(158.88,22.86) 159.07,23.05 160.62,23.05 160.96,22.71 160.96,22.68 162.26,21.38 U2401.115
MDAT: length 6.2
  TOP w0.102: RN2403.1 158.43,22.37 158.65,22.15 160.07,22.15 v2(160.4,22.48) 161.72,21.16 161.99,21.16 162.17,20.98 U2401.116
ME_CNTL: length 151.9
  TOP w0.102: v3(182.22,38.1) 182.22,38 v2(185.06,35.16) 185.6,34.62 185.6,26.26 v3(186.75,25.11) ; v3(168.56,129.41) 168.12,128.97 166.66,128.97 165.84,128.15 165.84,127.95 164.78,126.89 SB1.BF32 ; v3(190.88,24.13) 190.88,23.24 190.68,23.04 R2037.1
  BOTTOM w0.102: v3(182.22,38.1) 182.22,38.29 188.29,44.36 188.29,45.09 189.64,46.44 189.64,49.32 190.12,49.81 190.12,50.97 190.47,51.33 190.47,75.38 190.7,75.61 190.7,129.82 190.7,129.82 189.13,131.39 189.13,131.96 186.6,134.49 186.23,134.49 185.67,135.05 176.99,135.05 174.65,132.71 174.65,131.19 171.83,128.37 169.6,128.37 v3(168.56,129.41) ; v3(190.88,24.13) 190.88,24.34 190.12,25.11 v3(186.75,25.11)
ME_CNTL_1: length 4.9
  TOP w0.102: R2037.2 191.35,21.01 192.13,21.01 192.51,21.39 v3(193.01,21.39) 193.07,21.33 Q2001.B
  BOTTOM w0.102: v3(193.01,21.39) v2(192.13,21.78)
ME_CNTL_2: length 4.2
  TOP w0.102: Q2001.E 195.04,19.44 195.17,19.3 v3(195.89,19.3)
  BOTTOM w0.102: R2034.2 195.08,20.65 v2(195.99,20.65) 195.99,19.4 v3(195.89,19.3)
MEM_REG_PG: length 29.7
  TOP w0.102: U2401.111 162.01,22.98 158.96,26.02 v3(158.96,26.19) 158.85,26.19 157.89,25.22 R2470.1 ; Q2405.3 157.92,39.78 157.64,39.51 157.64,37.94 158.96,36.62 v3(158.96,35.67)
  BOTTOM w0.102: v3(158.96,26.19) 158.41,26.74 158.41,27.23 158.68,27.5 159.06,27.5 159.15,27.42 160.9,27.42 164.03,30.55 164.03,32.05 161.72,34.37 v2(160.76,34.37) 159.41,34.37 158.96,34.82 v3(158.96,35.67)
MEM_REG_PG_1: length 7.2
  TOP w0.102: Q2405.5 159.46,38.56 159.63,38.73 160.36,38.73 161.14,37.95 R2413.2 163.7,36.97 v2(163.7,36.58) 163.37,36.25 R2417.1
MEM_REG_PG_2: length 4.4
  TOP w0.102: Q2405.2 159.46,39.12 159.59,38.99 160.4,38.99 v3(161.03,39.62) R2412.2
  BOTTOM w0.102: v3(161.03,39.62) v2(160.06,39.62)
MIC1_JD: length 355.8
  TOP w0.102: v3(56.54,263.34) 56.61,263.27 v2(56.61,262.2) 56.61,260.51 57.29,259.83 R2709.2 ; v3(16.36,26.9) 15.62,26.16 14.55,26.16 14.54,26.17 14.16,26.17 13.59,25.6 10.78,25.6 5.24,20.07 3.18,20.07 1.68,18.57 1.68,9.11 4.74,6.04 5.86,6.04 6.91,7.1 6.91,7.76 7.43,8.28 11.91,8.28 AUD1.3
  BOTTOM w0.102: 15.88,27.82 15.88,27.94 15.33,28.49 15.33,37.22 4.11,48.43 4.11,173.03 6.43,175.35 6.7,175.62 10.05,175.62 15.34,180.91 15.34,188.29 9.5,194.13 6.43,194.13 4.7,195.86 4.7,230.02 11.99,237.31 11.99,239.08 11.99,239.46 17.57,245.03 20.63,245.03 26.01,250.41 26.01,258.05 19.94,264.12 19.94,266.33 20.74,267.13 54.66,267.13 56.74,265.06 56.74,264.67 56.74,264.66 56.74,263.71 56.54,263.5 v3(56.54,263.34) ; 15.88,27.82 v2(15.87,27.82) ; 15.88,27.82 15.88,27.39 v3(16.36,26.9)
MIC1_JD/FRONT_JD: length 10.8
  TOP w0.102: 56.22,258.94 R2709.1 ; 56.22,258.94 56.22,258.15 v2(57.35,257.03) 57.87,257.56 59.86,257.56 60.05,257.74 60.05,258.46 R2706.2 60.24,258.91 61.08,258.08 U2701.44 ; 56.22,258.94 R2710.1
MIC1_LL: length 336.1
  TOP w0.203: R3016.1 14.74,24.84 L3005.1 ; R3016.1 v3(14.35,25.72) ; R3016.1 15.15,25.08 R3013.2 ; R3011.2 67.98,252.63 67.98,252.05 v3(68.21,251.83)
  BOTTOM w0.203: v3(14.35,25.72) 14.01,26.06 14.01,36.2 2.82,47.39 2.82,173.57 3.06,173.81 6.24,176.99 9.16,176.99 13.72,181.55 13.72,187.65 9.14,192.23 6.5,192.23 3.4,195.32 3.4,230.59 10.69,237.88 10.69,239.99 17.03,246.33 20.1,246.33 24.72,250.95 24.72,257.48 18.64,263.55 18.64,266.87 20.2,268.43 55.46,268.43 59.13,264.76 59.13,262.97 61.96,260.15 64.09,260.15 v2(66.19,258.05) 67.98,256.25 67.98,252.05 v3(68.21,251.83)
MIC1_LL_C: length 4.1
  TOP w0.203: R3013.1 17.65,25.07 C3007.2 17.75,24.97 17.75,24.16 v3(18.03,23.88)
  BOTTOM w0.203: v2(17.75,24.87) 17.75,24.16 v3(18.03,23.88)
MIC1_RR: length 342.2
  TOP w0.203: L3006.1 13.97,22.29 R3015.1 16.06,22.29 R3014.2 16.08,21.79 15.83,21.54 15.5,21.54 v3(15.49,21.54) ; v3(70.32,254.28) 70.41,254.19 70.41,253.19 69.86,252.64 R3012.2
  BOTTOM w0.203: v3(70.32,254.28) 69.18,254.28 68.45,255 68.45,256.65 64.57,260.53 62.11,260.53 59.74,262.9 v2(59.74,263.7) 59.74,264.69 55.62,268.81 20.04,268.81 18.26,267.03 18.26,263.39 24.34,257.32 24.34,251.11 19.94,246.71 16.87,246.71 10.31,240.15 10.31,238.04 3.02,230.75 3.02,195.16 6.34,191.85 8.98,191.85 13.34,187.49 13.34,181.71 9,177.37 6.08,177.37 2.68,173.96 2.44,173.73 2.44,47.23 13.63,36.04 13.63,23.41 v3(15.49,21.54)
MIC1_RR_C: length 3.9
  TOP w0.203: C3008.2 18.47,22.66 v3(18.41,22.61) 17.91,22.61 17.58,22.28 17.47,22.28 17.46,22.27 R3014.1
  BOTTOM w0.203: v2(19.43,22.61) v3(18.41,22.61)
MIC1_VREFO_LL: length 4.3
  TOP w0.305: U2701.9 67.67,253.47 67.48,253.28 67.48,253.12 67.4,253.04 67.4,252.84 67.3,252.74 67.18,252.74 R3011.1
  TOP w0.508: R3011.1 67.08,252.23 67.13,252.18 67.13,251.82 v3(67.23,251.71)
  BOTTOM w0.508: v3(67.23,251.71) 67.23,252.55 v2(67.07,252.72)
MIC1_VREFO_RR: length 4.7
  TOP w0.305: 68.95,252.74 68.17,253.52 U2701.10
  TOP w0.508: v3(69.85,253.49) 69.8,253.44 69.54,253.44 68.96,252.86 R3012.1 68.95,252.66 68.95,252.74
  BOTTOM w0.508: v2(68.83,253.49) v3(69.85,253.49)
MIC2_VREFO: length 21
  TOP w0.305: U2701.11 68.67,255.49 v3(69.22,256.04)
  TOP w0.508: D2901.1 65.93,269.64 66.67,270.38 v3(66.79,270.38)
  BOTTOM w0.508: v3(69.22,256.04) 69.33,256.04 70.25,256.97 70.25,261.29 v2(70.23,261.32) 70.24,261.32 70.24,268.45 70.18,268.51 70.18,269.9 69.5,270.59 67.76,270.59 67.56,270.38 v3(66.79,270.38)
MUTE: length 338.6
  TOP w0.102: v3(30.73,17.27) 30.73,17.65 31.45,18.36 R3010.1 31.45,18.69 31.9,19.15 31.9,20.38 R3008.1 ; v3(56.29,264.46) 56.29,265.34 Q2701.C 57.78,267.02 R2910.1 R2908.1
  BOTTOM w0.102: v3(56.29,264.46) 56.29,265.19 54.57,266.9 20.83,266.9 20.17,266.24 20.17,264.22 26.24,258.15 26.24,250.32 20.73,244.81 17.66,244.81 12.22,239.36 12.22,239.17 12.22,237.21 4.93,229.92 4.93,195.95 6.5,194.39 9.57,194.39 15.57,188.39 15.57,180.81 10.14,175.39 6.79,175.39 6.66,175.25 6.66,175.25 4.34,172.94 4.34,48.53 15.56,37.31 15.56,29.05 19.68,24.92 19.68,23.72 v2(20.98,22.43) 22.07,21.34 22.67,21.34 23.35,22.02 27.15,22.02 v2(28.42,20.75) 29.96,20.75 31.04,19.67 31.04,17.58 v3(30.73,17.27)
MUTE_AUDOUT_LL: length 5.3
  TOP w0.102: Q3001.5 27.94,21.56 28.09,21.71 29.73,21.71 v2(30.38,21.06) 31.45,19.99 R3010.2
MUTE_AUDOUT_RR: length 5.2
  TOP w0.102: Q3001.2 27.94,22.1 28.07,21.97 29.95,21.97 v2(30.51,22.53) 31.09,22.53 31.52,22.1 R3008.2
MUTE_FP_OUT_LL: length 3.8
  TOP w0.102: Q2901.2 60.05,270.89 59.95,270.79 59.95,269.02 v2(60.16,268.81) 60.16,268.8 60.2,268.76 R2908.2
MUTE_FP_OUTR_RR: length 4.9
  TOP w0.102: R2910.2 59.18,268.75 v3(59.19,268.76) 59.72,269.29 59.72,270.79 59.62,270.89 Q2901.5
  BOTTOM w0.102: v3(59.19,268.76) v2(60.16,268.76)
NGFF_WIFI_PWR_CRL: length 220.9
  TOP w0.102: SB1.U48 148.91,134.84 150.72,136.65 152.42,136.65 152.5,136.74 153.81,136.74 154.79,137.72 154.79,138.64 155.35,139.21 155.75,139.65 155.75,142.17 155.68,142.24 v3(155.68,143.13) ; v3(65.41,202.67) 65.41,206.6 65.1,206.91 65.1,213.3 63.68,214.72 v3(63.68,216.26) ; v3(156.31,180.9) 156.13,180.72 119.3,180.72 117.25,181.32 116.99,181.38 115.79,181.38 v3(115.13,181.17) ; v3(34.87,239.8) 33.99,239.8 33.88,239.7 D6302.K 33.88,238.11 34.19,237.8 34.19,237.36 R1712.2
  BOTTOM w0.102: v3(155.68,143.13) 155.68,145.85 156.03,146.2 156.03,149.3 156.6,149.87 156.6,150.5 156.44,150.67 156.44,151.36 156.44,151.61 158.12,153.29 158.12,155.17 160.38,157.43 160.38,162.99 160.66,163.28 160.66,165.39 160,166.06 159.99,166.07 159.97,166.18 159.97,166.18 159.92,166.44 159.91,166.5 159.86,166.78 159.7,167.66 159.7,167.66 159.58,168.34 159.58,174.57 158.97,175.18 158.17,175.98 158.17,176.83 157.78,177.22 157.78,180.24 157.12,180.9 v3(156.31,180.9) ; v3(115.13,181.17) 113.85,182.45 86.36,182.45 80.41,188.39 80.16,188.65 76.28,188.65 71.28,193.65 70.06,193.65 68.41,195.3 67.13,195.3 62.71,199.72 62.71,200.51 62.71,200.76 64.44,202.49 65.23,202.49 v3(65.41,202.67) ; v3(34.87,239.8) v2(40.97,239.8) 41.71,239.8 51.74,229.77 51.74,228.11 52.92,226.92 54.87,226.92 57.48,224.32 57.48,220.51 58.98,219.01 58.98,218.76 61.48,216.26 v3(63.68,216.26)
NGFF_WIFI_PWR_EN: length 18.7
  TOP w0.102: U6301.1 35.76,231.95 34.77,232.93 34.77,234.72 v2(34.51,234.99) 34.51,235.55 33.43,236.64 33.43,242.15 34.82,243.55 U6302.D 35.98,245.99 37.19,244.78 R6306.2
PC_SPKR_DET_PD: length 4.4
  TOP w0.102: R2449.2 181.93,25.55 v2(181.73,25.35) 180.77,25.35 180.01,24.59 179.56,24.59 179.55,24.58 U2401.54
PCH_CPU_BCLK_DN: length 96.5
  TOP w0.089: 140.18,114.74 140.21,114.74 140.22,114.76 141.59,114.76 141.84,115.01 SB1.C8
  TOP w0.102: v1(90.84,95.71) CPU1.W4 ; 140.18,114.74 140.05,114.74 139.08,113.77 139.08,112.87 137.01,110.8 v3(137.01,110.42)
  BOTTOM w0.102: 119.6,99.12 v2(119.6,98.73) ; 119.6,99.12 118.56,99.12 118.39,98.94 118.39,97.49 118.13,97.23 117.57,97.23 117.34,97.46 117.34,98.94 117.17,99.12 116.91,99.12 116.73,98.94 116.73,95.81 116.46,95.53 115.92,95.53 115.69,95.76 115.69,97.06 115.51,97.24 114.49,97.24 114.18,97.55 114.18,97.98 114.49,98.28 115.51,98.28 115.69,98.46 115.69,98.67 115.59,98.77 114.36,98.77 114.13,99 114.13,99.47 114.36,99.69 115.63,99.69 115.74,99.8 115.74,100.08 115.63,100.18 113.58,100.18 113.35,100.41 113.35,100.86 113.58,101.09 114.33,101.09 114.43,101.19 114.43,101.47 114.03,101.87 108.59,101.87 106.4,99.67 106.4,97.94 106.14,97.68 95.32,97.68 93.82,96.18 91.65,96.18 91.54,96.08 91.2,96.08 v1(90.84,95.71) ; 119.6,99.12 126.42,99.12 126.6,98.94 126.6,98.5 126.91,98.2 127.34,98.2 127.64,98.5 127.64,98.94 127.82,99.12 127.98,99.12 128.21,99.35 128.21,100.66 128.31,100.77 128.59,100.77 128.69,100.66 128.69,98.45 128.92,98.22 129.42,98.22 129.65,98.45 129.65,100.75 129.75,100.85 130.11,100.85 130.26,100.7 130.26,98.5 130.49,98.27 130.98,98.27 131.2,98.5 131.2,100.72 133.87,103.38 133.87,103.74 135.29,105.17 135.29,108.7 v3(137.01,110.42)
PCH_CPU_BCLK_DP: length 96.6
  TOP w0.089: SB1.B8 141.39,114.95 140.15,114.95 140.14,114.96 140.13,114.96
  TOP w0.102: 137.58,111.67 137,111.1 v3(136.4,111.1) ; 137.58,111.67 138.86,112.96 138.86,113.86 139.96,114.96 140.13,114.96 ; 137.58,111.67 v2(137.3,111.95) ; CPU1.W5 v1(90.84,96.63)
  BOTTOM w0.102: v1(90.84,96.63) 91.18,96.29 91.45,96.29 91.56,96.4 93.73,96.4 95.23,97.9 106.05,97.9 106.18,98.03 106.18,99.76 108.5,102.08 114.12,102.08 114.64,101.56 114.64,101.1 114.42,100.88 113.67,100.88 113.56,100.77 113.56,100.5 113.67,100.39 115.72,100.39 115.95,100.17 115.95,99.71 115.72,99.48 114.45,99.48 114.35,99.38 114.35,99.09 114.45,98.98 115.68,98.98 115.91,98.76 115.91,98.37 115.6,98.07 114.58,98.07 114.4,97.89 114.4,97.64 114.58,97.46 115.6,97.46 115.91,97.15 115.91,95.85 116.01,95.75 116.37,95.75 116.52,95.9 116.52,99.03 116.82,99.34 117.25,99.34 117.56,99.03 117.56,97.55 117.66,97.45 118.04,97.45 118.17,97.57 118.17,99.03 118.47,99.34 126.51,99.34 126.82,99.03 126.82,98.59 127,98.41 127.25,98.41 127.43,98.59 127.43,99.03 127.73,99.34 127.89,99.34 127.99,99.44 127.99,100.75 128.22,100.98 128.68,100.98 128.91,100.75 128.91,98.54 129.01,98.44 129.34,98.44 129.44,98.54 129.44,100.84 129.66,101.07 130.2,101.07 130.48,100.79 130.48,98.59 130.58,98.48 130.89,98.48 130.99,98.59 130.99,100.81 133.66,103.47 133.66,103.83 135.08,105.26 135.08,108.79 136.45,110.16 136.45,110.31 136.1,110.66 136.1,110.8 v3(136.4,111.1)
PCH_CPU_NSSC_CLK_DN: length 91.7
  TOP w0.089: 140.15,113.97 140.17,113.99 140.17,114.01 140.54,114.38 141.91,114.38 SB1.C6
  TOP w0.102: CPU1.J9 v1(86.27,87.48) ; 140.15,113.97 139.52,113.34 139.52,111.94 137.3,109.72 135.6,109.72 135.37,109.49 134.56,109.49 134.33,109.71 134.33,110.18 v3(134.13,110.38)
  BOTTOM w0.102: 88,96.54 87.45,95.98 87.45,90.15 85.86,88.57 85.86,88.23 v1(86.27,87.48) ; 88,96.54 v2(87.72,96.82) ; 88,96.54 89.33,97.86 91.08,97.86 91.89,97.05 92.51,97.05 94.11,98.65 105.22,98.65 105.32,98.76 105.32,99.94 108.23,102.84 114.38,102.84 116.65,100.57 116.65,100.14 116.75,100.04 117.29,100.04 117.4,100.14 117.4,100.62 117.62,100.85 118.21,100.85 118.44,100.62 118.44,100.17 118.54,100.07 118.95,100.07 119.05,100.17 119.05,100.94 119.35,101.24 119.78,101.24 120.09,100.94 120.09,100.15 120.2,100.04 120.58,100.04 120.7,100.15 120.7,100.94 121,101.24 121.43,101.24 121.74,100.94 121.74,100.23 121.93,100.04 122.21,100.04 122.35,100.18 122.35,100.94 122.65,101.24 123.09,101.24 123.39,100.94 123.39,100.23 123.58,100.04 123.86,100.04 124,100.18 124,100.76 124.28,101.04 124.71,101.04 125.04,100.71 125.04,100.14 125.14,100.04 125.56,100.04 125.64,100.11 125.64,100.58 125.87,100.81 126.36,100.81 126.59,100.58 126.59,100.14 126.7,100.04 127.19,100.04 127.29,100.14 127.29,101.08 128.04,101.83 131.02,101.83 132.96,103.76 132.96,104.12 134.38,105.55 134.38,110.13 v3(134.13,110.38)
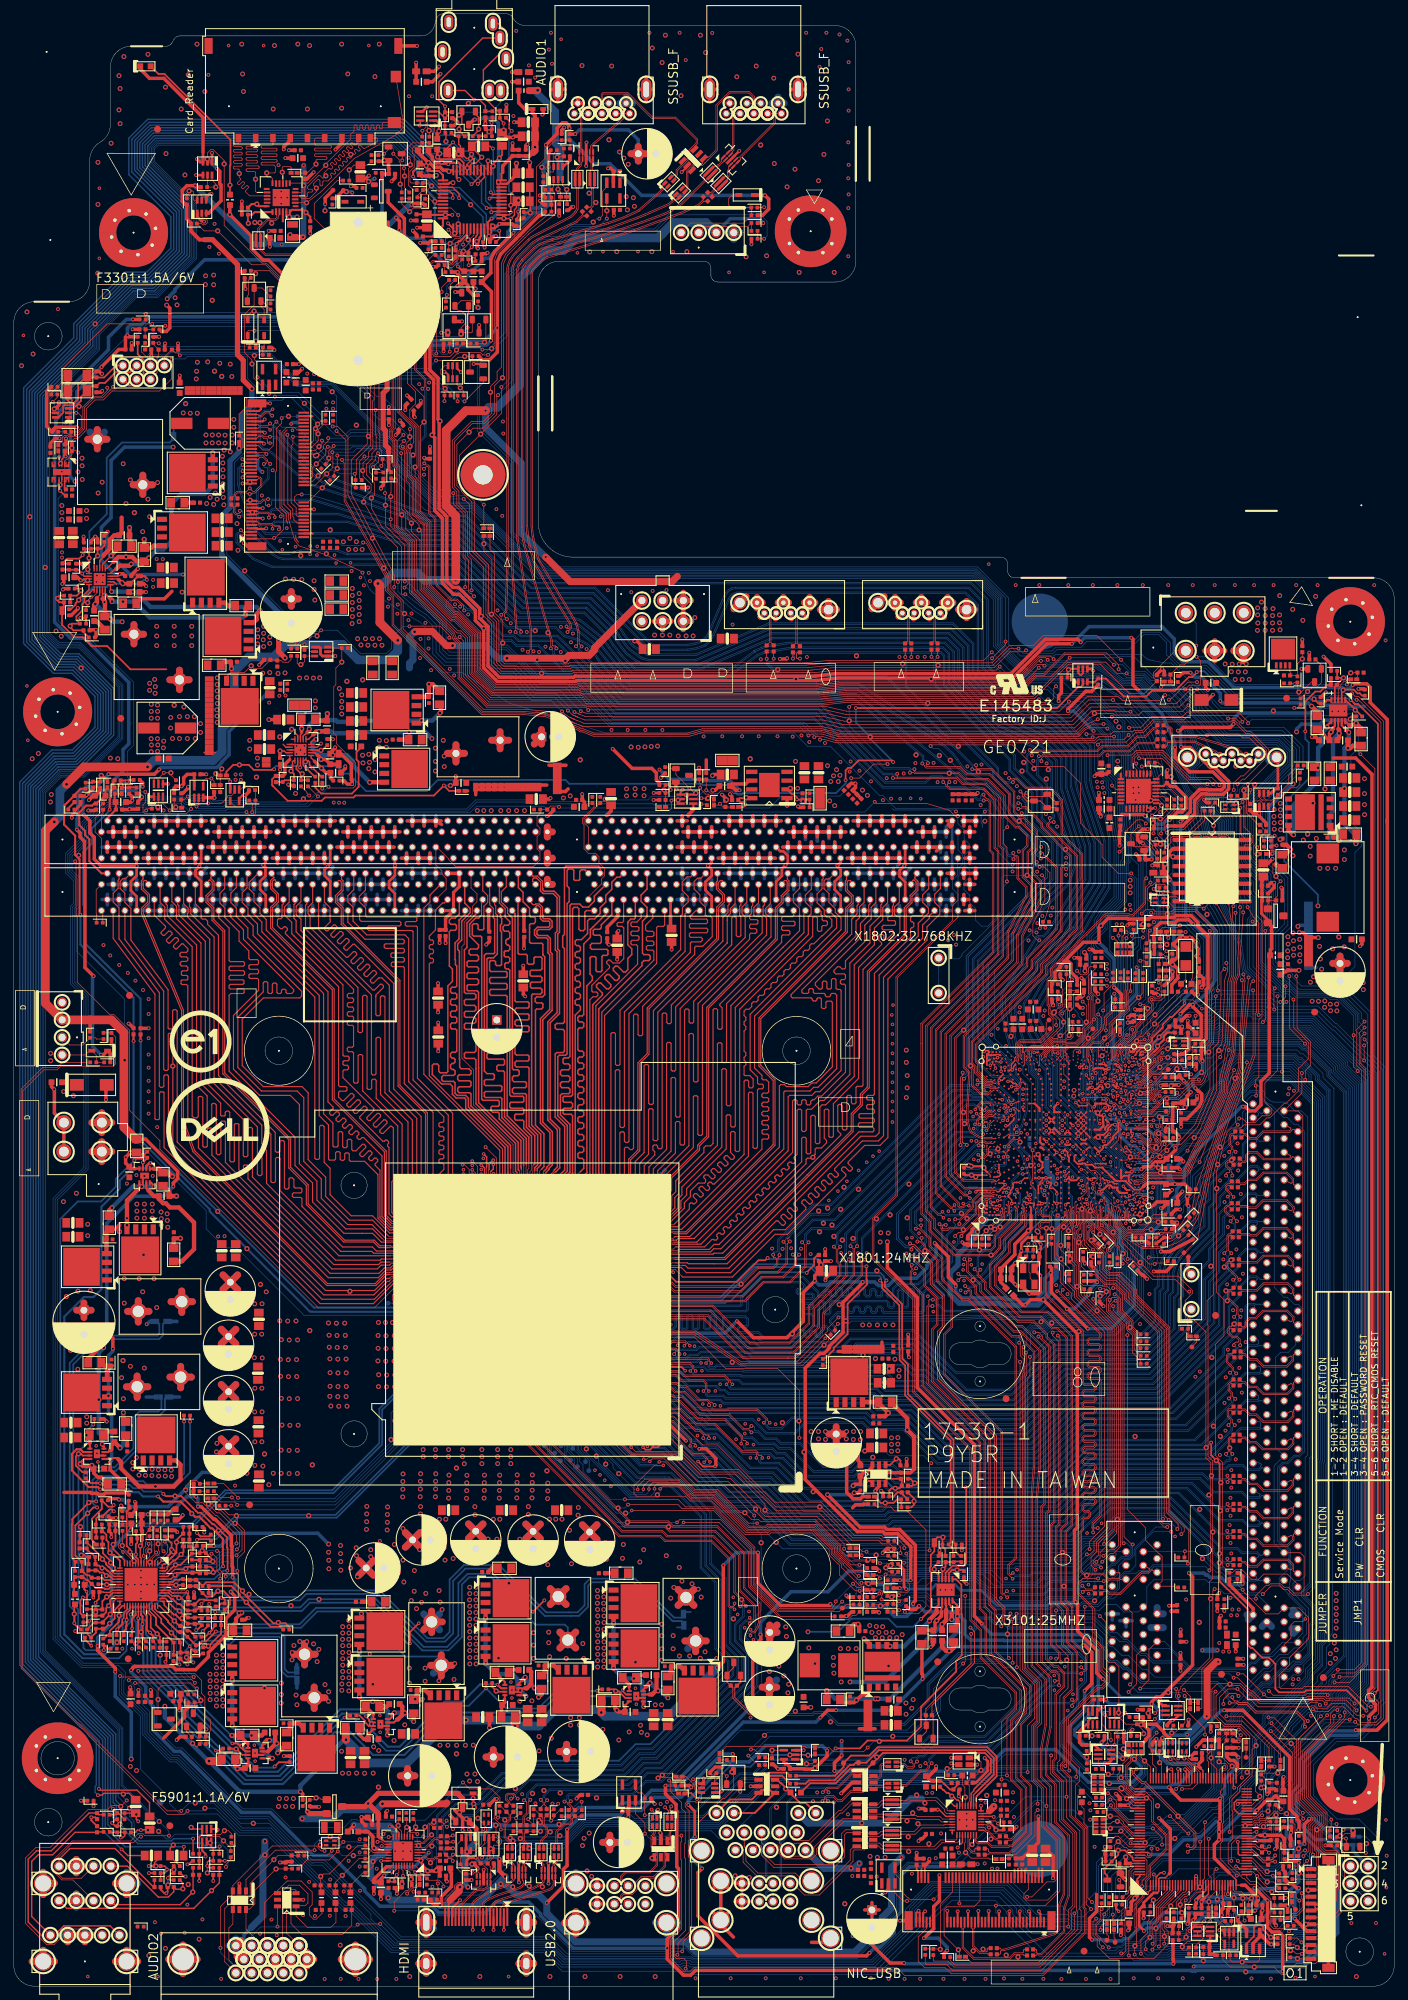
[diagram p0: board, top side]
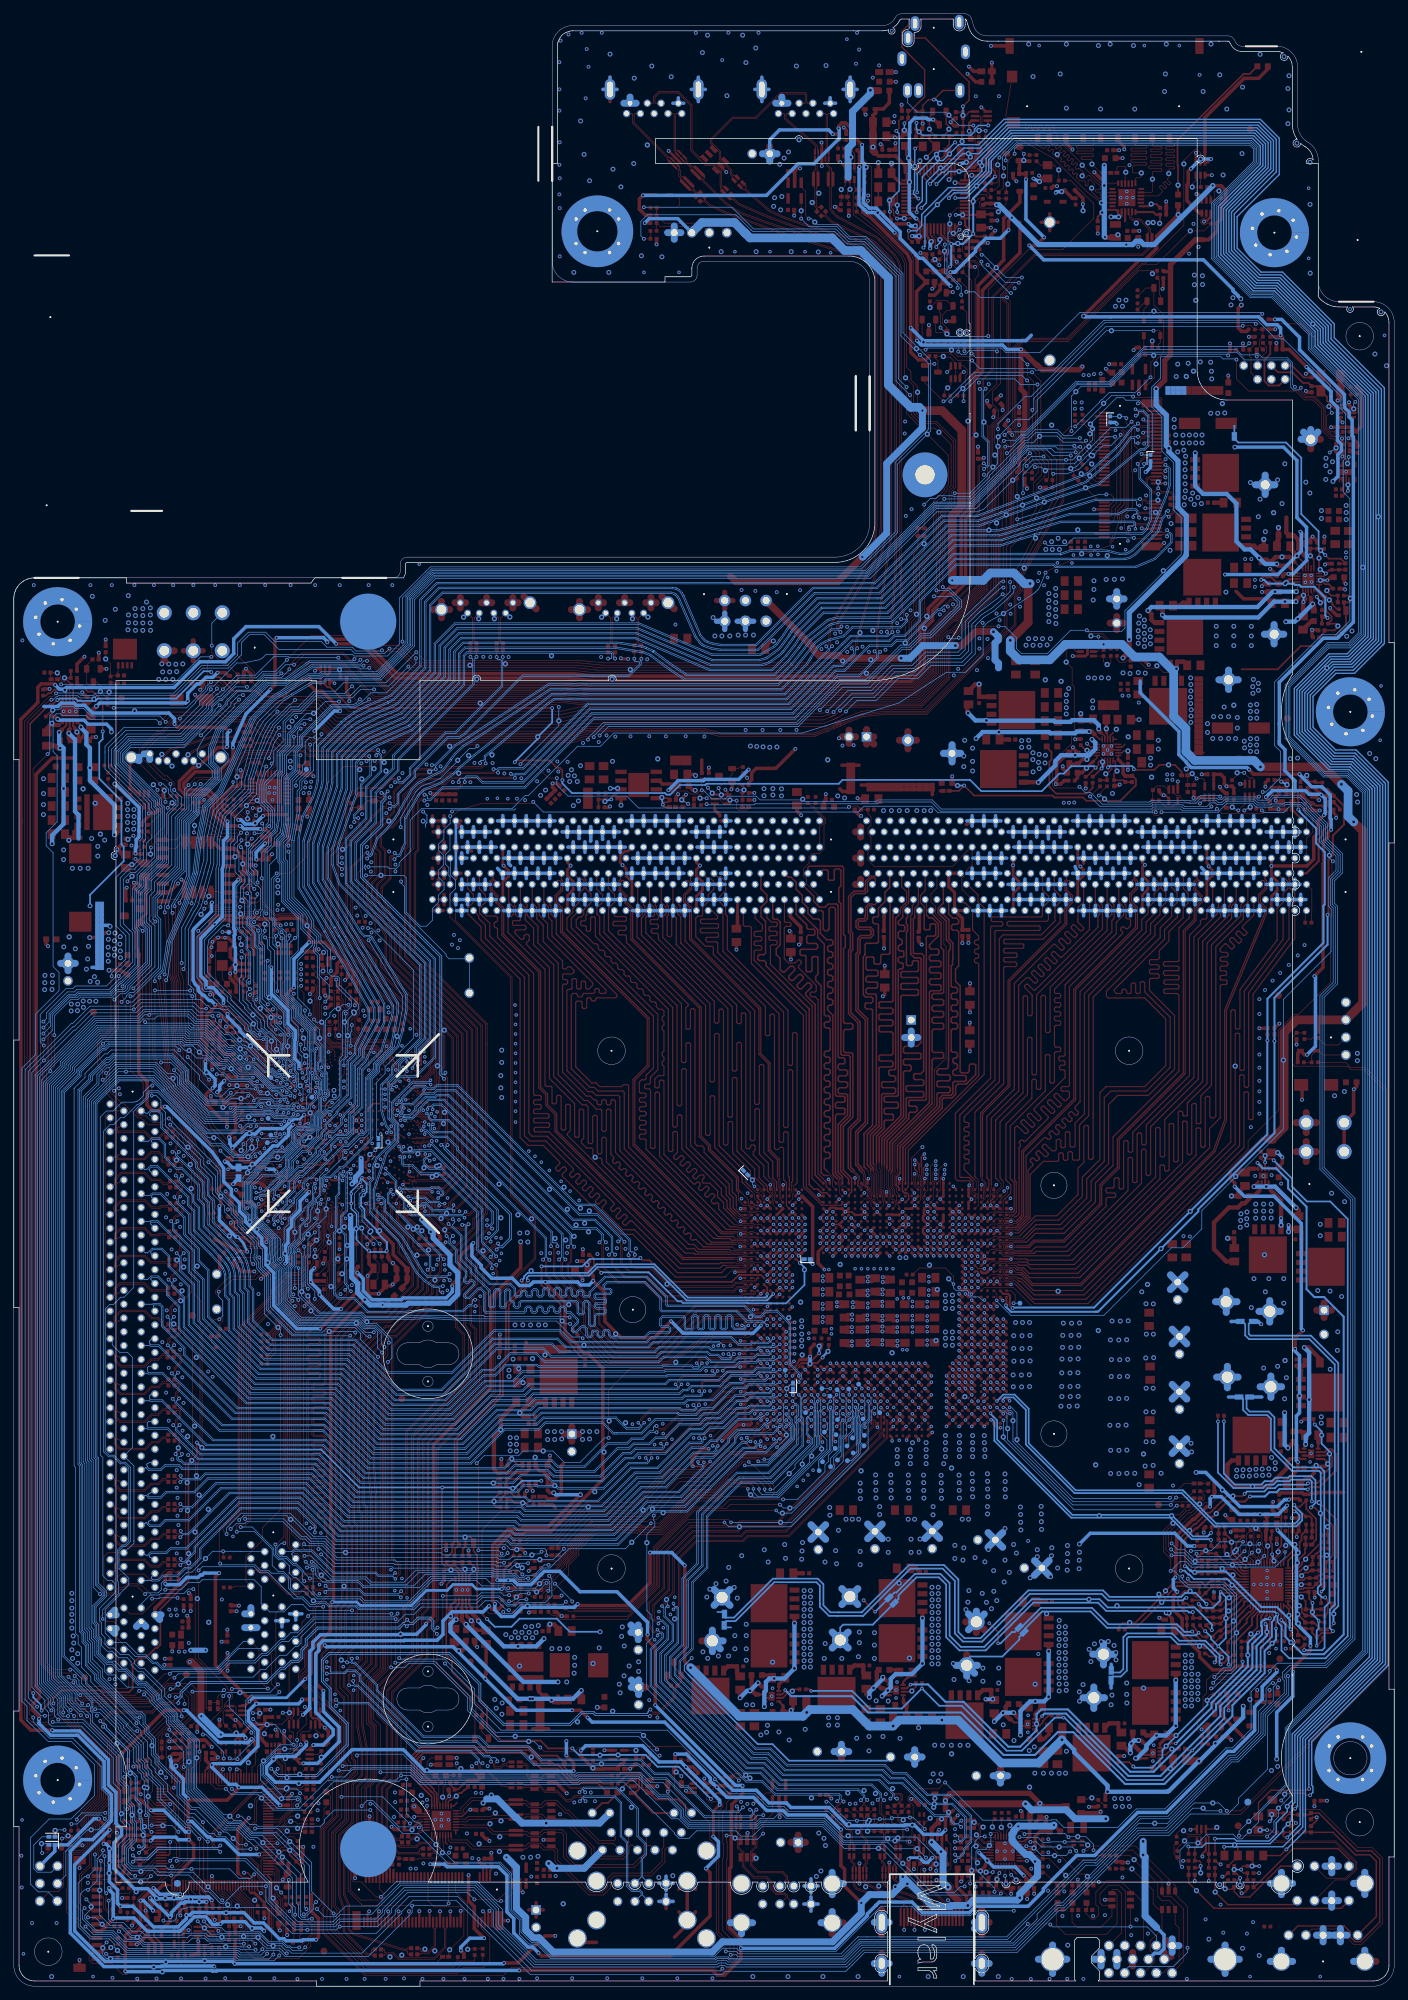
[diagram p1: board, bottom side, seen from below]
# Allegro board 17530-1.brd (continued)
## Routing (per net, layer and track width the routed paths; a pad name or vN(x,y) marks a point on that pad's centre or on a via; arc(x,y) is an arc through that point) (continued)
PCH_CPU_NSSC_CLK_DP: length 91.6
  TOP w0.089: SB1.D7 141.97,114.68 141.83,114.68 141.71,114.57 140.46,114.57 140.03,114.14 140.01,114.14 140,114.12
  TOP w0.102: CPU1.K9 86.26,87.94 86.18,88.03 86.18,88.31 v1(86.27,88.4) ; 140,114.12 139.3,113.43 139.3,112.03 137.21,109.94 135.51,109.94 135.28,109.7 134.65,109.7 134.54,109.8 134.54,110.11 134.7,110.27 v3(135.03,110.27)
  BOTTOM w0.102: v3(135.03,110.27) 134.94,110.36 134.7,110.36 134.59,110.26 134.59,105.46 133.17,104.03 133.17,103.67 131.11,101.61 128.13,101.61 127.51,100.99 127.51,100.05 127.28,99.82 126.61,99.82 126.38,100.05 126.38,100.49 126.28,100.59 125.96,100.59 125.86,100.49 125.86,100.02 125.65,99.82 125.05,99.82 124.83,100.05 124.83,100.62 124.62,100.83 124.37,100.83 124.22,100.67 124.22,100.09 123.95,99.82 123.49,99.82 123.17,100.14 123.17,100.85 123,101.03 122.74,101.03 122.56,100.85 122.56,100.09 122.3,99.82 121.84,99.82 121.52,100.14 121.52,100.85 121.34,101.03 121.09,101.03 120.91,100.85 120.91,100.06 120.67,99.82 120.11,99.82 119.87,100.06 119.87,100.85 119.69,101.03 119.44,101.03 119.26,100.85 119.26,100.08 119.03,99.86 118.45,99.86 118.22,100.08 118.22,100.53 118.12,100.63 117.71,100.63 117.61,100.53 117.61,100.05 117.38,99.82 116.66,99.82 116.43,100.05 116.43,100.48 114.29,102.63 108.32,102.63 105.54,99.85 105.54,98.67 105.31,98.44 94.2,98.44 92.99,97.23 ; 92.99,97.23 v2(93.26,96.96) ; 92.99,97.23 92.6,96.84 91.8,96.84 90.99,97.64 89.42,97.64 87.66,95.89 87.66,90.06 86.27,88.67 v1(86.27,88.4)
PCH_CPU_PCIBCLK_DN: length 98.7
  TOP w0.102: CPU1.W2 v1(93.58,95.71) ; v3(137.29,108.65) 137.49,108.92 139.99,111.42 139.99,112.96 140.86,113.83 141.1,113.83 SB1.B6
  BOTTOM w0.102: v1(93.58,95.71) 93.83,95.71 93.93,95.62 93.93,95.36 94.2,95.09 95.6,95.09 96.02,95.51 96.02,96.86 96.2,97.04 96.45,97.04 96.63,96.86 96.63,95.31 96.86,95.08 97.44,95.08 97.67,95.31 97.67,96.86 97.85,97.04 98.1,97.04 98.28,96.86 98.28,95.31 98.51,95.08 99.09,95.08 99.32,95.31 99.32,96.86 99.5,97.04 99.75,97.04 99.93,96.86 99.93,95.31 100.16,95.08 100.74,95.08 100.97,95.31 100.97,96.86 101.15,97.04 101.4,97.04 101.58,96.86 101.58,95.29 101.81,95.06 102.64,95.06 102.87,95.29 102.87,96.79 102.97,96.89 105.94,96.89 106.21,96.62 106.21,95.76 106.11,95.66 105.13,95.66 104.83,95.35 104.83,94.82 105.05,94.59 107.85,94.59 108.55,93.89 113.5,93.89 113.83,94.21 113.83,94.82 113.93,94.92 114.34,94.92 114.44,94.82 114.44,94.23 114.74,93.93 115.17,93.93 115.48,94.23 115.48,94.72 115.58,94.82 115.99,94.82 116.09,94.72 116.09,94.23 116.39,93.93 116.82,93.93 117.13,94.23 117.13,95.21 117.39,95.47 117.65,95.47 118.48,94.63 118.92,94.63 119.22,94.94 119.22,95.37 118.38,96.21 118.38,96.46 119.39,97.47 119.87,97.47 120.18,97.78 120.18,98.13 120.35,98.31 120.61,98.31 120.79,98.13 120.79,97.78 121.09,97.47 121.52,97.47 121.83,97.78 121.83,98.13 122.01,98.31 122.26,98.31 122.44,98.13 122.44,97.78 122.74,97.47 123.17,97.47 123.48,97.78 123.48,98.13 123.66,98.31 123.91,98.31 124.09,98.13 124.09,97.78 124.39,97.47 124.82,97.47 125.13,97.78 125.13,98.13 125.31,98.31 125.56,98.31 125.74,98.13 125.74,97.78 126.04,97.47 131.61,97.47 131.94,97.8 131.94,100.47 132.41,100.94 132.66,100.94 134.02,99.58 134.5,99.58 134.81,99.88 134.81,100.26 133.4,101.67 133.4,101.93 133.58,102.1 133.83,102.1 134.12,101.81 134.55,101.81 134.86,102.12 134.86,102.55 134.57,102.84 134.57,103.45 135.99,104.88 135.99,106.62 136.96,107.59 136.96,108.31 v3(137.29,108.65) v2(137.57,109.57)
PCH_CPU_PCIBCLK_DP: length 98.1
  TOP w0.102: v1(94.5,95.71) 94.14,95.71 94.04,95.82 CPU1.W1 ; v3(136.38,108.67) 136.85,109.14 137.41,109.14 139.77,111.51 139.77,113.05 140.83,114.1 SB1.A6
  BOTTOM w0.102: v1(94.5,95.71) 94.23,95.71 94.15,95.63 94.15,95.45 94.29,95.31 95.51,95.31 95.8,95.6 95.8,96.95 96.11,97.26 96.54,97.26 96.84,96.95 96.84,95.4 96.94,95.3 97.35,95.3 97.45,95.4 97.45,96.95 97.76,97.26 98.19,97.26 98.49,96.95 98.49,95.4 98.6,95.3 99,95.3 99.1,95.4 99.1,96.95 99.41,97.26 99.84,97.26 100.14,96.95 100.14,95.4 100.25,95.3 100.65,95.3 100.75,95.4 100.75,96.95 101.06,97.26 101.49,97.26 101.8,96.95 101.8,95.38 101.9,95.28 102.55,95.28 102.65,95.38 102.65,96.88 102.88,97.1 106.03,97.1 106.43,96.71 106.43,95.67 106.2,95.44 105.22,95.44 105.04,95.26 105.04,94.91 105.14,94.81 107.94,94.81 108.64,94.1 112.8,94.1 ; 112.8,94.1 113.41,94.1 113.61,94.3 113.61,94.91 113.84,95.14 114.43,95.14 114.65,94.91 114.65,94.32 114.83,94.15 115.08,94.15 115.26,94.32 115.26,94.81 115.49,95.03 116.08,95.03 116.3,94.81 116.3,94.32 116.48,94.15 116.74,94.15 116.91,94.32 116.91,95.3 117.3,95.69 117.74,95.69 118.57,94.85 118.83,94.85 119.01,95.03 119.01,95.28 118.17,96.12 118.17,96.55 119.3,97.69 119.78,97.69 119.96,97.87 119.96,98.22 120.27,98.53 120.7,98.53 121,98.22 121,97.87 121.18,97.69 121.43,97.69 121.61,97.87 121.61,98.22 121.92,98.53 122.35,98.53 122.65,98.22 122.65,97.87 122.83,97.69 123.08,97.69 123.26,97.87 123.26,98.22 123.57,98.53 124,98.53 124.3,98.22 124.3,97.87 124.48,97.69 124.73,97.69 124.91,97.87 124.91,98.22 125.22,98.53 125.65,98.53 125.95,98.22 125.95,97.87 126.13,97.69 131.52,97.69 131.72,97.89 131.72,100.55 132.32,101.15 132.75,101.15 134.11,99.79 134.41,99.79 134.59,99.97 134.59,100.18 133.19,101.58 133.19,102.02 133.49,102.32 133.92,102.32 134.21,102.03 134.46,102.03 134.64,102.21 134.64,102.46 134.35,102.75 134.35,103.54 135.78,104.97 135.78,106.71 136.75,107.68 136.75,108.3 v3(136.38,108.67) ; 112.8,94.1 v2(112.8,94.49)
PCH_DPWROK: length 204.2
  TOP w0.102: SB1.AW41 160.21,131.32 160.35,131.47 v1(160.35,131.55) ; v3(193.55,38.61) 192.89,38.61 187.83,33.55 187.83,27.59 190.27,25.16 190.27,23.29 189.55,22.57 189.55,20.19 190.06,19.68 191.59,19.68 192.18,19.1 192.18,14.24 192.39,14.02 192.39,13.79 192.39,10.77 189.08,7.46 189.08,3.76 188.58,3.27 185.81,3.27 184.25,1.7 183.66,1.7 182.59,2.77 v2(179.73,2.77) 176.25,2.77 175.18,3.84 175.18,4.28 175.2,4.29 R2619.1 175.18,4.48 175.18,5.08 175.45,5.35 U2602.4 175.42,6.16 175.42,6.35 174.23,7.55 174.23,8.62 175.06,9.45 R2612.2
  BOTTOM w0.102: v3(193.55,38.61) 194.09,39.15 194.09,40.13 194.36,40.4 194.72,40.75 194.72,41.76 196.6,43.63 196.6,131.85 188.25,140.2 181.99,140.2 181.01,141.17 174.52,141.17 173.38,140.03 171.66,140.03 169.46,137.82 168.79,137.82 166.97,136 166.58,136 166.32,135.74 166.17,135.74 166.12,135.68 166.11,135.68 164.74,134.32 164.74,134.29 163.2,132.74 162.54,132.74 161.81,132.02 161.33,132.02 160.96,131.64 160.44,131.64 v1(160.35,131.55)
PCH_HEATSINK_DET: length 125.5
  TOP w0.102: v3(143.89,160.02) 143.9,160.02 143.9,164.96 143.41,165.44 143.41,167.36 v3(143.94,167.89) ; v3(132.83,179.64) 132.99,179.81 141.89,179.81 144.68,179.81 147.81,176.67 152.13,176.67 154.56,174.24 154.56,168.48 157.67,165.37 157.67,163.54 160.02,161.19 v3(161.91,161.19) ; SB1.AN37 157.13,129.67 v1(157.32,129.67) ; RN1901.2 161.08,151.67 v3(161.21,151.8)
  BOTTOM w0.102: v3(132.83,179.64) 133.17,179.3 133.96,179.3 v2(135.69,177.57) 135.69,177.47 138.16,175 138.22,174.95 138.23,174.95 139.18,174.47 140.77,173.88 140.98,173.77 141.07,173.68 141.72,173.03 143.94,169.27 v3(143.94,167.89) ; HS1901.2 HS1901.1 134.12,148.82 136.93,148.82 137.37,149.26 137.37,149.49 143.41,155.52 143.41,159.28 143.89,159.77 v3(143.89,160.02) ; v1(157.32,129.67) 157.11,129.87 157.11,130.69 157.19,130.77 157.19,132.45 156.92,132.72 156.92,135.39 157.18,135.65 157.18,138.36 159.21,140.39 159.21,141.59 161.14,143.52 161.14,151.72 v3(161.21,151.8) 161.21,151.82 161.36,151.97 161.36,152.14 161.47,152.24 161.47,152.28 161.7,152.51 161.7,152.98 162.24,153.52 162.24,154.35 162.7,154.82 162.7,160.39 v3(161.91,161.19)
PCH_INTRUDER_N: length 21.7
  TOP w0.102: SB1.BB44 161.01,133.32 v1(161.04,133.35) ; R1507.1 166.4,150.62 167,150.01 v3(167,149.91)
  BOTTOM w0.102: v3(167,149.91) 166.42,149.32 166.42,146.21 166.8,145.82 166.8,142.81 166.07,142.08 166.07,141.77 164.26,139.96 164.26,139.69 164.19,139.61 164.19,138.77 164.13,138.71 163.99,138.71 163.36,138.07 163.06,138.07 161.93,136.93 v2(161.93,135.71) 161.47,135.25 161.47,134.52 161.04,134.09 v1(161.04,133.35)
PCH_JTAG_TCK_48077565: length 7.9
  TOP w0.089: 154.77,109.47 154.77,110.36 154.63,110.5 154.63,110.57 154.62,110.58 154.62,112.54 154.58,112.57 154.58,112.8 SB1.AJ3
  TOP w0.102: 154.77,109.47 154.77,108.98 154.51,108.71 v3(154.51,108.69) 154.51,107.77 154.51,107.77 154.51,107.28 154.51,107.28 154.51,106.79 R2011.1
  BOTTOM w0.102: v2(154.31,107.74) v3(154.51,108.69)
PCH_JTAG_TDI: length 94
  TOP w0.102: v3(157.71,61.49) 158.43,62.2 158.43,62.24 158.85,62.66 159.33,62.66 160.35,63.69 160.35,63.97 160.35,95.72 158.34,97.73 158.34,98.68 158.33,98.7 158.33,99.59 158.85,100.11 158.85,100.94 158.39,101.4 157.84,101.4 157.73,101.5 154.95,101.5 154.56,101.89 154.56,102.59 155.02,103.05 R2026.1 155.01,103.06 154.46,103.61 154.46,104.64 153.97,105.13 153.97,108.19 153.88,108.29 153.88,108.98 153.97,109.08 153.97,109.4 154.35,109.78 154.35,110.23 154.24,110.34 154.24,110.41 154.21,110.44 154.21,112.15 SB1.AH2 ; v3(125.48,59.05) 125.48,59.18 125.09,59.56 R411.2
  BOTTOM w0.102: v3(157.71,61.49) 157.24,61.01 156.43,61.01 155.94,60.52 155.94,60.03 v2(155.45,59.54) 154.66,58.75 150.06,58.75 149.35,58.04 149.29,57.99 142.06,57.99 140.87,59.18 140.39,59.66 130.77,59.66 130.65,59.54 127.42,59.54 126.84,58.95 126.03,58.95 125.93,59.05 v3(125.48,59.05)
PCH_JTAG_TDO: length 107.1
  TOP w0.089: 154.2,109.02 154.2,109.35 154.55,109.69 154.55,110.31 154.44,110.42 154.44,110.49 154.43,110.5 154.43,112.46 SB1.AH3
  TOP w0.102: 154.2,109.02 154.08,108.89 154.08,108.38 154.2,108.25 154.2,105.22 154.69,104.74 154.69,104.28 155.91,103.06 R2024.1 156.61,103.06 158.05,101.63 159.49,101.63 160.91,100.2 160.91,99.5 165.74,94.68 165.74,67.44 166.67,66.51 v3(167.13,66.51) ; v3(122.81,58.42) R410.2
  BOTTOM w0.102: v3(167.13,66.51) 165.45,66.51 162.33,63.39 162.33,62.45 161.64,61.76 160.95,61.76 160.05,60.86 160.05,59.81 159.45,59.22 159.13,59.22 156.02,56.11 149.84,56.11 149.26,55.52 142.55,55.52 139.32,58.75 132.97,58.75 132.21,57.99 129.1,57.99 128.83,57.72 128.83,57.47 128.56,57.2 127.79,57.2 127.64,57.35 124.61,57.35 124.36,57.1 v2(124.26,57.1) 124.26,57.1 124.13,57.1 v3(122.81,58.42)
PCH_JTAG_TMS: length 107.9
  TOP w0.089: SB1.AJ4 154.89,113.09 154.89,112.63 154.81,112.55 154.81,110.66 154.82,110.65 154.82,110.58 154.97,110.43 154.97,108.88 154.96,108.87
  TOP w0.102: v3(125.73,56.03) 125.73,56.58 125.86,56.71 125.86,57.09 125.53,57.42 124.54,57.42 R412.2 ; v3(167.69,65.84) 167.69,66.64 167.36,66.97 166.57,66.97 165.96,67.58 165.96,94.77 161.14,99.6 161.14,100.3 159.58,101.85 158.14,101.85 156.42,103.58 156.29,103.58 155.63,104.24 155.63,105.32 R2028.1 156.08,105.82 155.55,106.35 155.55,106.49 154.81,107.23 154.81,107.3 154.74,107.38 154.74,107.89 154.96,108.12 154.96,108.87
  BOTTOM w0.102: v3(125.73,56.03) 126.66,56.03 127.39,55.3 128.42,55.3 129.67,56.54 132.3,56.54 132.89,55.96 141.04,55.96 142.23,54.76 149.94,54.76 150.35,55.17 154.28,55.17 154.78,55.68 156.44,55.68 v2(156.59,55.83) 157.98,57.22 159.45,57.22 159.89,57.66 159.89,59.03 160.91,60.05 161.67,60.05 162.56,60.93 162.56,63.3 165.1,65.84 v3(167.69,65.84)
PCH_PECI: length 4.2
  TOP w0.089: SB1.AF2 153.49,112.11 153.28,111.9 153.28,110.87
  TOP w0.102: R1708.1 v2(152.81,109.4) 152.81,109.9 153.11,110.2 153.11,110.61 153.28,110.78 153.28,110.87
PCH_PME_N: length 6.3
  TOP w0.102: SB1.BE36 162.54,129.09 162.87,128.76 164.55,128.76 165.02,129.23 165.02,129.44 165.48,129.9 165.48,130.65 166.5,131.67 R1508.2
PCH_PS_ON_N: length 10.3
  TOP w0.102: R1919.1 159.51,138.75 159.51,137.55 158.45,136.48 v3(158.45,136.4) ; SB1.AP41 157.4,131.55 v1(158.12,131.55)
  BOTTOM w0.102: v1(158.12,131.55) 157.6,132.07 157.6,133 157.45,133.14 157.45,134.54 v2(157.68,134.77) 158.45,135.53 v3(158.45,136.4)
PCH_PWROK: length 248
  TOP w0.102: v3(176.73,44.68) 177.32,44.68 179.23,42.77 179.47,42.77 180.7,41.53 187.42,41.53 187.57,41.68 189.78,41.68 190.06,41.4 190.69,41.4 190.71,41.43 193.07,41.43 v3(194.55,39.94) ; v3(144.72,46.85) 144.67,46.9 v3(144.67,53.16) ; DB2001.1 v3(171.22,140.56) ; R4016.2 107.96,32.04 107.57,32.43 107.39,32.43 v3(106.43,33.4) ; SB1.AY42 160.78,132.03 v1(160.79,132.05)
  BOTTOM w0.102: v3(144.72,46.85) 143.34,46.85 143.12,47.07 139.02,47.07 138.74,46.79 133.91,41.97 133.91,40.08 130.02,36.2 v2(127.35,36.2) 109.5,36.2 106.71,33.4 v3(106.43,33.4) ; v3(194.55,39.94) 194.65,40.04 194.65,40.06 195.02,40.43 195.02,41.63 196.9,43.51 196.9,131.98 188.37,140.51 182.1,140.51 181.14,141.48 174.24,141.48 173.33,140.56 v3(171.22,140.56) 170.78,140.12 170.78,139.78 169.18,138.18 168.71,138.18 166.84,136.31 166.46,136.31 166.19,136.04 166.04,136.04 164.54,134.54 164.54,134.37 163.15,132.98 162.49,132.98 161.73,132.22 160.96,132.22 v1(160.79,132.05) ; v3(176.73,44.68) 176.16,45.25 170.25,45.25 168.69,46.81 165.05,46.81 163.95,47.91 163.22,47.91 161.22,49.91 160.2,49.91 159.45,50.66 158.97,50.66 156.45,53.19 144.7,53.19 v3(144.67,53.16)
PCH_PWROK_EC: length 6.4
  TOP w0.102: C2413.1 181.93,29.46 R2442.1 R2433.1 180.91,30.86 v2(183.13,30.86) 183.22,30.86 183.51,31.16 R2439.1
PCH_RTCRST_DOWN: length 10.7
  TOP w0.102: R2035.1 191.74,20.4 192.79,19.35 192.79,14.49 193.56,13.72 194.82,13.72 196.22,12.32
PCH_RTCRST_N: length 3.1
  TOP w0.102: v3(167.28,151.84) 167.01,152.11 R2036.2 167.58,152.75 167.61,152.77 R9919.1
  BOTTOM w0.102: v2(167.04,150.88) 167.04,150.85 v3(167.28,151.84)
PCH_RTCRST_PULLUP: length 287.7
  TOP w0.102: v1(162.08,134.5) 162.22,134.36 SB1.BE47 ; C2006.1 166.31,151.71 R2040.1 166.06,152.03 166.12,152.1 R2036.1 166.12,153.04 166.45,153.37 168.63,153.37 168.92,153.66 v3(168.96,153.66) ; v3(161.57,182.3) 161.63,182.36 163.3,182.36 164.86,183.92 169.34,183.92 169.97,184.56 177.42,184.56 178.83,183.14 v3(178.83,182.94)
  BOTTOM w0.102: v1(162.08,134.5) 163.25,135.67 163.25,137.39 164.16,138.3 164.69,138.3 165.15,138.76 165.15,139.21 165.23,139.29 165.23,139.56 168.53,142.86 168.53,143.45 171.91,146.84 171.91,150.54 171.75,151.52 170.36,152.92 170.36,152.95 169.65,153.66 v3(168.96,153.66) 168.81,153.81 168.81,161.62 168.63,162.26 168.63,165.5 168.05,166.08 168.05,169.27 v2(166.29,171.02) 165.43,171.88 165.43,172.04 164.85,172.62 164.85,172.68 164.85,172.75 164.85,173.4 164.85,173.41 164.84,173.61 164.84,174.16 163.71,177.73 163.64,177.8 163.64,177.95 163.6,178.06 163.02,179.38 162.68,180.37 162.39,180.8 162.03,181.53 v3(161.57,182.3) ; 193.68,12.32 195.02,13.67 196.46,13.67 197.59,14.79 197.59,21.5 194.87,24.22 191.7,24.22 188.29,27.63 188.29,32.07 191.65,35.43 195.01,35.43 198.09,38.51 198.09,40.56 198.83,41.29 198.83,132.95 196.85,134.93 196.85,140.79 193.45,144.2 193.45,146.84 194.31,147.7 194.31,164.2 195.31,165.2 195.31,167.06 193.73,168.65 193.73,178.26 194.31,178.84 194.31,183.85 193.86,184.3 193.22,184.3 193,184.08 189.56,184.08 188.98,183.5 179.4,183.5 v3(178.83,182.94)
PCH_RTCX1: length 20.6
  TOP w0.102: SB1.BA49 160.62,135.4 161.47,136.24 161.88,136.24 163.18,137.54 163.47,137.54 163.96,138.02 163.96,138.07 v2(165.28,139.4) 165.28,139.77 168.13,142.62 168.17,142.62 169.34,143.79 169.56,143.79 C1803.1 169.81,144.36 R1814.1 170.64,145.9 170.75,146.01 170.75,149.9 170.05,150.6 X1802.1
PCH_RTCX2: length 17.4
  TOP w0.089: 161.63,136.45 161.39,136.45 160.52,135.58 160.51,135.58 160.37,135.44 160.37,135.19 160.53,135.03 160.61,135.03 SB1.BA48
  TOP w0.102: 161.63,136.45 161.79,136.45 163.35,138 163.35,138.48 164.67,139.8 164.67,140.03 v2(165.35,140.7) 167.87,143.23 167.91,143.23 168.67,143.99 C1804.1 168.67,144.18 169.12,144.63 R1814.2 169.8,145.87 X1802.2
PCH_SATA_LED_N: length 246.6
  TOP w0.102: SB1.AK48 155.03,135.92 156.4,137.29 156.56,137.29 157.78,138.51 157.78,138.64 157.84,138.7 157.84,139.19 158.04,139.4 158.04,140.39 159.08,141.43 159.08,142.1 159.24,142.26 159.47,142.26 159.58,142.36 R1704.1 159.59,142.97 159.59,143.35 159.51,143.43 159.51,143.69 v3(159.44,143.77) ; U6401.2 28.07,265.56 28.52,266.01 28.91,266.01 30.48,264.44 v2(30.48,263.96) 30.48,255.06 35.96,249.58 36.59,249.58 47.46,238.71 53.89,238.71 55.27,237.33 55.27,225.68 54.88,225.29 54.88,224.49 55.39,223.98 55.39,220.36 55.65,220.1 55.65,211.39 57.81,209.23 57.81,202.03 58.25,201.6 63.83,196.03 64.11,195.27 64.82,194.56 64.82,189.61 68.7,185.72 82.77,185.72 82.87,185.83 117.28,185.83 120.83,186.23 148.36,186.23 148.39,186.26 v3(148.51,186.39)
  BOTTOM w0.102: v3(148.51,186.39) 148.81,186.09 148.97,186.02 149.26,185.9 149.49,185.78 149.5,185.78 149.63,185.71 149.99,185.52 150.64,185.17 153.82,185.17 158.14,180.85 158.14,179.93 158.14,179.55 158.95,178.74 158.95,176.06 159.22,175.79 160.19,174.83 160.19,168.4 160.51,166.65 160.53,166.52 160.54,166.48 161.27,165.74 161.27,163.03 160.98,162.74 160.98,157.18 158.72,154.92 158.72,152.05 158.8,151.98 158.8,150 159.87,148.93 159.87,144.2 v3(159.44,143.77)
PCH_SATA_LED_NMOS: length 5
  TOP w0.102: U6401.5 28.07,260.67 R6416.2 v2(29.26,260.6) 29.26,261.06 28.72,261.6 U6401.6
PCH_SIO_DPWROK: length 8.4
  TOP w0.102: U2401.28 175.49,13.58 175.44,13.52 175.44,13.15 175.76,12.83 v2(176.78,12.83) 176.78,12.27 176.8,12.26 R2475.1 176.8,10.55 176.68,10.44 176.68,10.08 176.38,9.77 176.38,9.46 R2612.1 176.39,8.93 176.75,8.57 U2602.1
PCH_SLP_A_N: length 190.3
  TOP w0.089: SB1.BE40 162.65,130.78 162.68,130.81
  TOP w0.102: v1(169.56,132.9) 169,133.46 167.18,133.46 166.6,132.89 166.6,132.89 165.96,132.24 164.86,132.24 164.5,131.88 164.5,131.75 163.91,131.16 163.6,131.16 163.3,130.86 162.73,130.86 162.68,130.81 ; v3(159.23,10.36) 159.23,9.47 159.41,9.3 R9916.1 159.51,8.98 160.35,8.98 R2047.1 160.45,9.53 160.53,9.6 160.53,10.99 161.04,11.5 161.04,12.5 161.14,12.6 161.59,13.09 161.59,13.1 161.6,13.1 161.87,13.38 161.87,16.61 162.24,16.98 U2401.126 ; v3(190.37,42.16) 190.12,42.42 187.41,42.42 187.13,42.14 182.47,42.14 v3(181.84,42.77)
  BOTTOM w0.102: v3(190.37,42.16) 190.37,42.34 193.12,45.08 193.12,129.63 190.7,132.05 190.7,132.61 187.25,136.07 186.88,136.07 186.32,136.63 175.87,136.63 175.44,136.19 175.28,136.19 174.02,136.19 v2(173.13,135.31) 172.59,134.77 172.05,134.77 170.18,132.9 v1(169.56,132.9) ; v3(159.23,10.36) 159.23,11.4 159.64,11.81 159.64,15.67 165.2,21.23 165.84,21.23 167.54,22.94 168,22.94 168,22.94 169.33,22.94 174.62,28.23 174.62,35.23 177.55,38.15 177.55,38.89 179.98,41.33 179.98,41.77 180.99,42.77 v3(181.84,42.77)
PCH_SRTCRSTB_PULLUP: length 22.2
  TOP w0.102: R2043.1 167.55,149.54 v3(167,149) 166.52,149.48 R2042.2 166.12,149.47 166.12,148.82 165.99,148.69 165.99,148.2 C2007.1 ; SB1.BD46 161.69,133.97 v1(161.58,133.87)
  BOTTOM w0.102: v3(167,149) 167,146.31 167.28,146.02 167.28,142.61 166.56,141.89 166.55,141.74 166.55,141.57 164.74,139.76 164.74,139.49 164.67,139.41 164.67,138.76 164.41,138.51 164.08,138.51 162.69,137.12 v2(162.69,136.91) 162.69,135.68 162.16,135.15 161.67,134.67 161.67,134.43 161.58,134.34 v1(161.58,133.87)
PCH_SYSPWROK: length 200.1
  TOP w0.089: 158.81,112.03 158.79,112.06 158.79,112.49 SB1.AU3
  TOP w0.102: 158.81,112.03 158.85,111.99 158.85,110.25 164.5,104.6 v3(165.31,104.6) 165.45,104.75 166.92,104.75 R2003.1 ; v3(180.01,129.01) 180.01,130.38 v3(179.93,130.45) 179.93,131.27 180.39,131.73 180.39,140.01 180.85,140.47 180.85,154.3 180.02,155.13 180.02,163.75 179.65,164.11 179.65,165.16 180.04,165.54 180.04,166.74 R9905.1 ; v3(175.68,39.09) 178,39.09 183.51,33.57 R2439.2
  BOTTOM w0.102: v3(179.93,130.45) 180.24,130.45 180.49,130.2 180.51,130.2 180.92,129.78 181.2,129.5 181.2,129.01 181.61,128.61 181.61,128.61 181.82,128.4 181.94,128.32 182.07,128.23 182.21,128.17 182.35,128.11 182.65,128.05 184.34,128.05 185.62,126.77 186.59,126.77 187.47,125.89 187.47,76.94 187.24,76.71 187.1,76.56 187.1,59.46 186.41,58.78 185.78,58.78 185.34,58.34 185.34,56.99 187.6,54.73 187.6,52.99 187.27,52.66 187.27,50.98 186.79,50.5 186.79,49.53 186.26,49 185.52,49 184.58,48.06 183.37,48.06 182.52,47.22 182.52,46.76 181.79,46.02 181.1,46.02 178.13,43.06 178.13,41.99 176.18,40.04 175.77,39.62 175.77,39.18 v3(175.68,39.09) ; v2(174.76,121.53) 174.76,121.53 ; 174.76,121.53 172.95,119.72 172.95,118.84 171.25,117.14 171.25,114.81 169.46,113.02 169.46,112.16 168.02,110.72 168.02,109.95 165.67,107.6 165.67,106.83 165.54,106.71 165.54,106.22 165.68,106.08 165.68,105.07 165.65,104.95 v3(165.31,104.6) ; 174.76,121.53 174.94,121.72 175.08,121.72 178,124.64 178,126.57 178.69,127.25 178.69,128.33 179.36,129.01 v3(180.01,129.01)
PCH_WAKE_N: length 526.9
  TOP w0.089: 161.96,135.61 161.65,135.61 161.47,135.43 161.47,135.19 161.51,135.15 161.61,135.04 SB1.BB47
  TOP w0.102: v3(182.63,141.48) 182.58,141.53 182.58,141.61 182.58,142.16 182.57,142.16 182.57,142.94 182.58,142.94 182.58,144.42 v3(182.69,144.54) ; 161.96,135.61 162.1,135.61 162.25,135.75 163.02,136.53 164.11,136.53 164.64,137.06 164.64,137.45 165.05,137.86 165.05,138.25 165.89,139.09 165.89,139.52 168.38,142.01 168.42,142.01 169.28,142.87 170.87,142.87 v1(172.14,141.6) ; v3(176.76,173.28) 176.76,174.28 177.79,175.31 178.16,175.31 181.05,178.19 181.05,178.81 179.03,180.82 178.03,180.82 177.47,181.38 173.08,181.38 v3(172.88,181.19) ; U3101.21 141.15,24.2 141.4,23.95 142.22,23.95 v3(142.61,23.56) ; NGFF1.55 35.4,223.17 36.04,222.53 36.98,222.53 37.59,223.15 37.59,226.16 v3(38.05,226.62) ; v3(56.64,203.48) 56.64,208.75 53.85,211.54 v2(53.85,214.53) 53.85,216.2 v3(53.78,216.27) ; R2014.1 177.29,58.19 v3(178.05,57.43) 178.05,57.43 178.05,57.28 181.41,53.92 183.18,53.92 SLOT2.B11 186.2,54.79 187.6,53.39 187.6,50.34 186.34,49.08 186.33,49.08 184.84,47.58 184.84,46.57 183.77,45.5 183.76,45.5 183.34,45.08 183.34,43.33 183.54,43.13 186.72,43.13 187,43.41 193.34,43.41 196.27,40.48 v3(196.62,40.48) ; R6202.2 132.05,3.28 132.18,3.15 135.16,3.15 136.02,2.29 148.88,2.29 154.64,8.04 154.64,8.44 154.64,10.94 154.44,11.13 154.44,22.49 152.53,24.41 v3(152.53,27.43) 152.53,29.91 151.19,31.25 151.19,32.37 151.56,32.74 151.56,42.02 152.74,43.2 152.74,47.84 151,49.58 v3(151,54.43) ; v3(83.22,184.85) 83.25,184.87 117.63,184.87 120.61,184.2 152.92,184.2 155.51,186.79 160.04,186.79 160.58,186.25 166.03,186.25 v3(166.8,187.02)
  BOTTOM w0.102: v3(56.64,203.48) 56.99,203.48 59.4,201.07 62.2,198.4 62.64,197.97 62.64,193.79 63.19,193.24 67.91,193.24 69.81,191.34 72.76,191.34 75.93,188.16 79.91,188.16 v3(83.22,184.85) ; v3(178.05,57.43) 175.74,57.43 174.71,58.46 173.09,58.46 172.67,58.88 165.18,58.88 164.16,57.86 164.16,55.45 SLOT1.B11 162.93,54.22 160.85,54.22 159.77,55.3 158.12,55.3 157.26,54.43 v3(151,54.43) ; v3(172.88,181.19) 168.55,185.52 168.55,185.85 167.38,187.02 v3(166.8,187.02) ; v3(38.05,226.62) 38.86,225.81 41.06,225.81 46.34,220.52 52.21,220.52 53.78,218.95 v3(53.78,216.27) ; v1(172.14,141.6) 173,141.6 173.81,142.42 173.82,142.42 173.84,142.44 181.54,142.44 182.5,141.48 v3(182.63,141.48) 188.77,141.48 191.28,138.96 191.46,138.96 197.87,132.55 197.87,41.76 196.7,40.59 196.7,40.56 v3(196.62,40.48) ; v3(182.69,144.54) 179.55,147.68 179.55,153.59 179.58,153.62 179.93,153.97 180.31,154.35 180.31,154.36 180.31,157.92 179.63,158.61 179.63,159.9 179.63,159.92 177.11,162.43 177.11,169.47 175.73,170.86 175.73,172.25 v3(176.76,173.28) ; v3(152.53,27.43) 146.56,27.43 142.69,23.56 v3(142.61,23.56)
PCH_XDP_PRDY_R_N: length 107.5
  TOP w0.089: 156.2,109.63 156.37,109.8 156.37,110.3 156.36,110.32 156.36,110.36 155.91,110.8 155.91,110.83 155.77,110.98 155.77,111.04 155.76,111.05 155.76,111.96 155.95,112.14 155.95,113.09 155.98,113.12 155.98,113.52 SB1.AM5
  TOP w0.102: v3(169.16,65.48) 169.58,65.9 169.58,66.44 167.39,68.63 167.26,68.76 167.26,95.31 162.43,100.13 162.43,100.83 160.12,103.15 158.68,103.15 157.91,103.92 157.91,106.11 156.31,107.71 156.31,107.75 155.78,108.28 155.78,109.21 156.2,109.63 ; v3(122.83,62.41) R9902.1
  BOTTOM w0.102: v3(169.16,65.48) 169.16,66.37 167.03,68.5 159.94,68.5 156.61,65.17 154.73,65.17 153.5,63.94 128.71,63.94 128.02,63.25 v2(127.13,63.25) 126.98,63.4 123.09,63.4 122.83,63.14 v3(122.83,62.41)
PCH_XDP_PREQ_R_N: length 102.9
  TOP w0.089: 155.74,108.02 155.57,108.19 155.57,109.29 155.94,109.66 155.94,109.66 156.18,109.89 156.18,110.22 156.17,110.24 156.17,110.28 155.72,110.72 155.72,110.75 155.58,110.9 155.58,110.96 155.57,110.97 155.57,112.04 155.63,112.1 155.63,112.26 SB1.AL2
  TOP w0.102: v3(168.58,66.22) 168.69,66.33 168.69,67.01 167.03,68.67 167.03,95.21 162.2,100.04 162.2,100.74 160.02,102.92 158.58,102.92 157.68,103.82 157.68,106.01 155.78,107.92 155.78,107.99 155.74,108.02 ; R9901.1 122.48,63.45 122.99,62.94 v3(123.55,62.94)
  BOTTOM w0.102: v3(168.58,66.22) 167.74,67.06 166.49,67.06 166.26,67.28 160.98,67.28 158.47,64.77 157.76,64.77 157.09,64.1 155.19,64.1 153.19,62.1 129.92,62.1 129.65,61.84 128.15,61.84 127.71,62.28 125.12,62.28 v2(124.94,62.46) 124.79,62.61 124.65,62.61 123.88,62.61 v3(123.55,62.94)
PCIAUX_GATE: length 4.1
  TOP w0.102: R2432.1 v2(166.01,32.38) 166.29,32.11 U2401.92
PCIE_RCOMP_N: length 4.7
  TOP w0.152: 141.03,117.92 141.48,117.47 SB1.B12
  TOP w0.305: R1513.1 137.88,118.77 v2(138.73,118.77) 140.18,118.77 141.03,117.92
PCIE_RCOMP_P: length 3.4
  TOP w0.152: SB1.A13 140.94,117.47 140.04,117.47
  TOP w0.305: R1513.2 137.86,117.47 v2(138.76,117.47) 140.04,117.47
PCIE_RX_CON_N5: length 3.6
  TOP w0.102: U3101.18 140.6,23 140.79,22.81 140.79,22.71 141.01,22.49 141.24,22.49 142.32,21.41 142.56,21.41 C3109.1
PCIE_RX_CON_P5: length 3.8
  TOP w0.102: 141.83,21.59 142.23,21.2 142.49,21.2 C3110.1 ; 141.83,21.59 v2(141.57,21.32) ; 141.83,21.59 141.15,22.28 140.92,22.28 140.59,22.6 U3101.17
PCIE_RX_PCH_N5: length 117.9
  TOP w0.102: v1(143.4,120.11) 143.68,120.39 143.68,120.64 SB1.F20 ; C3109.2 144.13,21.34 144.48,21.34 145.85,22.71 145.85,28.41 144.42,29.83 144.42,38.58 145.77,39.92 145.77,42.79 140.72,47.84 140.72,53.79 139.88,54.63 139.88,78.7 131.59,86.99 131.59,100.1 129.88,101.81 129.88,103.54 130.15,103.81 130.15,103.96 129.93,104.18 129.93,104.33 v3(130.1,104.5)
  BOTTOM w0.102: 132.27,106.26 130.5,104.5 v3(130.1,104.5) ; 132.27,106.26 v2(132,106.53) ; 132.27,106.26 132.72,106.71 132.72,112.21 138.33,117.82 141.01,117.82 142.19,119 143.46,119 143.6,119.14 143.6,119.9 v1(143.4,120.11)
PCIE_RX_PCH_N7: length 98.7
  TOP w0.102: v1(144.18,121.61) 144.18,121.85 144.19,121.86 144.19,121.89 144.92,122.62 145.41,122.62 SB1.L24 ; v1(144.76,59.87) 144.53,59.64 144.39,59.64 144.23,59.8 144.23,60.92 145.27,61.96 145.27,92.64 138.35,99.56 137.48,99.56 134.6,102.43 134.6,105.5 132.8,107.3 132.8,108.4 131.44,109.75 v3(131.44,110.21)
  BOTTOM w0.102: v1(144.76,59.87) 145.04,59.56 147.12,59.56 147.54,59.99 153.59,59.99 156.8,63.2 159.49,63.2 159.74,62.94 SLOT1.A17 ; 141.45,120.95 139.57,120.95 130.73,112.12 130.73,110.57 131.09,110.21 v3(131.44,110.21) ; 141.45,120.95 141.83,120.95 142.09,120.7 143.65,120.7 143.99,121.04 143.99,121.42 v1(144.18,121.61) ; 141.45,120.95 v2(141.45,120.57)
PCIE_RX_PCH_N8: length 211.3
  TOP w0.102: v1(145.31,123.67) 145.08,123.44 144.2,123.44 SB1.F24 ; NGFF1.43 33.35,220.17 v3(33.15,220.37)
  BOTTOM w0.102: v3(33.15,220.37) 32.88,220.1 32.68,220.1 32.45,219.88 32.45,217.6 32.45,217.34 32.96,215.75 35.07,210.69 37.87,207.89 38.55,207.48 38.88,207.38 39.82,207.37 41.54,207.81 43.59,207.87 45.29,207.87 ; 45.29,207.87 46.71,207.87 48.25,207.36 48.3,207.35 48.32,207.34 63.83,207.34 73.04,198.14 80.65,198.14 81.26,197.99 81.84,197.83 82.09,197.71 85.1,195.3 85.71,194.48 86.14,193.88 86.21,193.76 87.54,192.11 87.72,191.89 87.77,191.84 87.77,191.84 89.76,189.85 102.53,189.85 102.74,189.98 103.02,190.15 104.13,190.88 104.63,191.22 107.37,193.25 107.41,193.28 107.61,193.39 108.06,193.58 108.38,193.73 108.42,193.74 108.42,193.75 108.66,193.84 109.09,193.98 109.51,194.05 110.72,194.22 111.99,194.43 112.6,194.48 134.86,194.48 136.07,193.26 136.07,189.03 142.58,182.51 142.69,182.46 142.7,182.46 148.01,180.07 148.97,179.44 149.44,179.02 150.96,177.5 150.96,173.22 151.18,172.64 153.41,165.74 153.71,164.75 153.71,162.48 153.21,161.09 152.72,159.71 141,147.99 141,137.21 145.08,133.12 145.08,132.04 146.62,130.5 146.62,126.88 145.94,124.63 145.48,124.17 145.48,123.84 v1(145.31,123.67) ; 45.29,207.87 v2(45.29,207.49)
PCIE_RX_PCH_P5: length 117.9
  TOP w0.102: SB1.G20 143.89,120.85 143.89,120.29 v1(144.03,120.15) ; C3110.2 143.76,20.83 144.06,21.12 144.57,21.12 146.07,22.62 146.07,28.5 144.64,29.92 144.64,38.49 145.99,39.83 145.99,42.88 140.93,47.93 140.93,53.88 140.09,54.72 140.09,78.79 131.8,87.08 131.8,100.19 130.09,101.9 130.09,103.45 130.64,103.99 v3(130.74,103.99)
  BOTTOM w0.102: v1(144.03,120.15) 143.81,119.93 143.81,119.05 143.55,118.78 142.28,118.78 141.1,117.6 139.37,117.6 ; v3(130.74,103.99) 130.74,104.42 132.94,106.62 132.94,112.12 138.42,117.6 139.37,117.6 ; v2(139.37,117.25) 139.37,117.6
PCIE_RX_PCH_P7: length 98.7
  TOP w0.102: v1(144.72,59) 144.02,59.71 144.02,61.01 145.06,62.05 145.06,92.55 138.26,99.35 137.39,99.35 134.39,102.35 134.39,105.41 132.59,107.21 132.59,108.31 131.17,109.73 v3(130.68,109.73) ; v1(143.54,121.6) 143.6,121.6 144.92,122.92 SB1.J24
  BOTTOM w0.102: v2(142.6,121.28) 142.6,120.92 ; 142.6,120.92 143.56,120.92 143.78,121.13 143.78,121.36 v1(143.54,121.6) ; 142.6,120.92 142.18,120.92 141.92,121.17 139.48,121.17 130.52,112.21 130.52,110.48 130.9,110.09 130.9,109.95 v3(130.68,109.73) ; v1(144.72,59) 145.09,59.35 147.21,59.35 147.63,59.77 153.68,59.77 156.89,62.98 159.4,62.98 159.72,62.66 159.72,62.51 SLOT1.A16
PCIE_RX_PCH_P8: length 211.3
  TOP w0.102: NGFF1.41 33.36,219.67 v3(33.15,219.46) ; SB1.G24 144.19,123.12 144.29,123.23 145.55,123.23 v1(145.96,123.63)
  BOTTOM w0.102: v2(34.57,213.49) 34.2,213.34 ; 34.2,213.34 35.25,210.82 38,208.06 38.64,207.68 38.91,207.59 39.79,207.58 41.51,208.03 43.59,208.09 46.75,208.09 48.31,207.57 48.35,207.56 63.92,207.56 73.13,198.35 80.67,198.35 81.31,198.19 81.87,198.04 81.94,198.02 82.18,197.9 82.22,197.88 85.26,195.45 85.88,194.61 86.32,194 86.36,193.94 86.39,193.89 87.88,192.03 88.87,191.05 89.85,190.07 102.47,190.07 102.91,190.33 104.01,191.06 104.51,191.39 106,192.5 107.24,193.42 107.29,193.46 107.52,193.59 107.98,193.77 108.29,193.92 108.35,193.95 108.36,193.95 108.59,194.04 109.04,194.19 109.48,194.26 110.68,194.43 111.97,194.64 112.59,194.69 134.95,194.69 136.28,193.35 136.28,189.11 142.71,182.69 142.78,182.66 142.79,182.65 148.11,180.26 149.1,179.61 149.59,179.18 151.18,177.59 151.18,173.26 151.38,172.71 153.62,165.8 153.92,164.78 153.92,162.44 153.42,161.02 153.42,161.02 152.91,159.59 141.21,147.9 141.21,137.3 145.3,133.21 145.3,132.13 146.84,130.59 146.84,126.85 146.13,124.52 145.69,124.08 145.69,123.89 v1(145.96,123.63) ; 34.2,213.34 33.17,215.83 32.66,217.38 32.66,217.62 32.66,219.79 32.77,219.89 33.05,219.89 33.15,219.79 v3(33.15,219.46)
PCIE_SLOT1_PRSNT_N: length 134.5
  TOP w0.102: v3(169.67,62.99) 169.6,62.92 169.6,62.12 R1506.2 ; SB1.BB26 161.17,124.75 161.25,124.83 v1(161.25,124.83) ; v3(180.97,56.79) 181.95,57.77 181.97,57.77 182.17,57.98 183.43,57.98 183.75,57.66 183.78,57.63 183.93,57.48 184.53,57.48 185.36,56.65 187.36,56.65 v3(187.51,56.8)
  BOTTOM w0.102: v3(180.97,56.79) 180.8,56.97 179.07,56.97 178.64,57.4 178.64,58.37 178.21,58.8 176.08,58.8 175.02,59.86 175,59.86 174.89,59.97 174.19,59.97 v2(172.22,61.94) 171.17,62.99 v3(169.67,62.99) 167.13,62.99 167.08,62.94 SLOT1.B17 ; v3(187.51,56.8) 188.49,57.78 188.49,76.19 188.72,76.42 188.72,127.74 188.72,127.74 188.72,128.18 185,131.9 179.64,131.9 177.83,130.09 177.83,130.01 177.77,129.96 177.77,129.89 171.9,124.02 167.13,124.02 166.16,124.99 161.42,124.99 161.26,124.83 v1(161.25,124.83)
PCIE_SLOT2_PRSNT_N: length 130.4
  TOP w0.102: SB1.BA30 160.46,126.26 v1(160.2,126.52) ; v3(179.96,56.13) 179.96,56.59 181.45,58.08 181.84,58.08 182.05,58.28 183.3,58.28 183.55,58.28 183.94,57.89 183.97,57.87 184.06,57.78 184.66,57.78 185.49,56.95 186.49,56.95 186.94,57.4 186.94,62.23 186.38,62.79 SLOT2.B17 ; v3(186.63,132.27) 186.63,129.37 185.04,127.79 185.04,127.78 SLOT2.B81 186.06,126.79 186.76,126.08 186.76,94.5 SLOT2.B48 ; v3(176.28,56.26) 176.09,56.07 R1806.2
  BOTTOM w0.102: v3(179.96,56.13) 178.94,56.13 178.82,56.26 v3(176.28,56.26) ; SLOT2.B17 183.47,63.37 183.37,63.37 183.06,63.68 183.06,63.69 182.6,64.14 182.6,64.4 182.6,64.58 182.6,64.59 182.6,75.38 182.91,75.69 182.91,75.69 183.42,76.2 183.46,76.2 SLOT2.B31 182.81,78.03 182.81,91.09 183.54,91.82 184.66,91.82 185.74,92.9 185.74,93.48 SLOT2.B48 ; v1(160.2,126.52) 160.6,126.11 162.11,126.11 162.64,126.64 163.65,126.64 163.83,126.47 165.58,126.47 165.71,126.34 167.15,126.34 167.65,126.34 168.12,125.87 172.02,125.87 176.56,130.4 176.56,130.46 176.61,130.51 176.61,130.68 176.94,131.01 v2(176.94,131.5) 177.51,131.5 178.26,132.25 179.54,133.53 185.25,133.53 186.51,132.27 v3(186.63,132.27)
PCIE_TX_CON_N5: length 4.2
  TOP w0.102: v2(138.84,20.52) 138.46,20.52 ; 138.46,20.52 138.46,19.98 138.95,19.49 139.16,19.49 139.24,19.58 139.24,19.84 139.34,19.94 C3115.1 ; 138.46,20.52 138.46,21.21 138.65,21.39 U3101.14
PCIE_TX_CON_N7: length 10
  TOP w0.102: SLOT1.B15 164.54,60.49 164.59,60.36 164.52,60.23 164.34,60.05 163.37,60.05 160.29,56.96 158.79,56.96 158.32,57.43 157.9,57.43 C9402.2
PCIE_TX_CON_N8: length 8.7
  TOP w0.102: NGFF1.37 35.38,218.67 35.45,218.59 35.71,218.59 35.94,218.36 35.94,217.27 34.95,216.28 34.62,216.28 34.49,216.15 v3(34.19,216.15) 33.86,216.15 33.71,216.31 32.41,216.31 32.12,216.01 32.12,215.8 C6305.1
  BOTTOM w0.102: v3(34.19,216.15) v2(34.24,215.24)
PCIE_TX_CON_P5: length 3.9
  TOP w0.102: U3101.13 138.25,19.89 138.86,19.28 139.4,19.28 C3116.1
PCIE_TX_CON_P7: length 10
  TOP w0.102: SLOT1.B14 164.92,60.31 164.78,60.26 164.7,60.1 164.43,59.83 163.46,59.83 160.38,56.74 158.7,56.74 158.23,57.21 157.86,57.21 C9401.2
PCIE_TX_CON_P8: length 8.7
  TOP w0.102: NGFF1.35 35.24,218.17 35.45,218.38 35.62,218.38 35.73,218.27 35.73,217.36 34.86,216.5 34.66,216.5 v3(34.19,216.97) 33.74,216.52 32.32,216.52 31.9,216.1 31.9,215.89 C6306.1
  BOTTOM w0.102: v3(34.19,216.97) v2(34.19,217.88)
PCIE_TX_PCH_N5: length 124.2
  TOP w0.102: v3(130.11,105.72) 130.44,105.39 130.44,105.05 131.86,103.63 131.86,101.43 133.68,99.6 133.68,95.89 132.99,95.2 132.99,87.57 141.27,79.28 141.27,55.21 142.11,54.37 142.11,53.39 142.11,53.39 142.11,48.42 147.17,43.37 147.17,39.34 145.82,38 145.82,30.41 147.25,28.99 147.25,22.13 144.87,19.75 144.57,19.75 144.2,19.38 141.38,19.38 141.22,19.53 141.22,19.81 141.1,19.94 C3115.2 ; v1(139.73,119.57) 140.06,119.89 140.63,119.89 141.2,120.46 141.2,121.35 SB1.B21
  BOTTOM w0.102: v3(130.11,105.72) 130.42,106.03 130.42,106.19 132.02,107.79 132.02,112.62 137.93,118.53 138.35,118.53 ; v1(139.73,119.57) 140.06,119.89 140.21,119.89 140.46,119.63 140.46,119.25 139.74,118.53 138.35,118.53 ; v2(138.35,118.9) 138.35,118.53
PCIE_TX_PCH_N7: length 93.5
  TOP w0.102: v3(143.88,57.23) 143.54,56.9 143.34,56.9 143.23,57.01 143.23,80.37 134.94,88.66 134.94,94.39 136,95.44 136,100.05 133.9,102.15 133.9,105.21 132.11,107.01 132.11,107.35 131.53,107.92 v3(131.53,108.38) ; v3(154.83,58.01) 154.83,58.01 155.31,57.53 156.4,57.53 C9402.1 ; v3(139.8,121.79) 139.8,122.11 139.9,122.21 140.62,122.21 140.78,122.05 141.86,122.05 SB1.C23
  BOTTOM w0.102: v3(139.8,121.79) 139.7,121.89 139.48,121.89 130.02,112.44 130.02,109.53 131.13,108.42 131.14,108.42 131.18,108.38 v3(131.53,108.38) ; 152.15,57.57 154.38,57.57 v3(154.83,58.01) ; 152.15,57.57 149.88,57.57 149.16,56.85 144.26,56.85 v3(143.88,57.23) ; 152.15,57.57 v2(152.15,57.94)
PCIE_TX_PCH_N8: length 205.8
  TOP w0.102: SB1.B24 141.68,122.96 140.64,122.96 139.88,123.11 138.86,123.72 138.56,124.23 138.26,125.48 138.26,127.4 138.53,131.7 138.51,132.41 137.77,133.15 137.77,137.56 147.61,147.41 147.61,148.54 151.87,152.81 151.87,161.96 152.02,162.1 152.17,162.1 v3(152.46,161.81) ; C6305.2 32.05,214.26 32.05,213.54 32.26,213.33 32.61,213.33 32.77,213.49 v3(32.77,213.7)
  BOTTOM w0.102: 41.57,206.84 v2(41.57,207.21) ; 41.57,206.84 63.65,206.84 72.84,197.66 80.59,197.66 80.59,197.65 81.67,197.35 81.7,197.34 81.88,197.25 81.92,197.23 84.55,195.12 85.24,194.25 85.56,193.8 87.36,191.57 87.42,191.51 87.42,191.51 88.27,190.66 89.56,189.37 102.67,189.37 103.28,189.74 104.92,190.83 107.67,192.87 107.82,192.96 108.72,193.32 112.77,193.99 134.66,193.99 135.59,193.06 135.59,192.49 135.58,192.48 135.58,188.82 142.31,182.1 142.49,182.02 142.49,182.02 146.43,180.25 147.73,179.67 148.64,179.07 149.26,178.53 150.48,177.3 150.48,172.66 152.73,166.28 152.95,165.59 153.13,164.98 153.14,164.94 153.18,164.82 153.18,162.53 152.46,161.82 v3(152.46,161.81) ; 41.57,206.84 39.13,206.84 39.01,206.85 38.42,206.99 37.59,207.48 34.3,210.78 33.68,212.7 33.17,213.21 33.17,213.6 33.07,213.7 v3(32.77,213.7)
PCIE_TX_PCH_P5: length 124.2
  TOP w0.102: v3(130.92,105.63) 130.66,105.37 130.66,105.14 132.07,103.72 132.07,101.52 133.9,99.69 133.9,95.8 133.2,95.11 133.2,87.66 141.49,79.37 141.49,55.3 142.33,54.46 142.33,53.3 142.33,53.3 142.33,48.51 147.38,43.46 147.38,39.25 146.04,37.91 146.04,30.5 147.46,29.08 147.46,22.04 144.96,19.53 144.66,19.53 144.29,19.16 141.21,19.16 141.1,19.05 C3116.2 ; SB1.A22 140.99,120.55 140.54,120.11 140.06,120.11 v1(139.73,120.43)
  BOTTOM w0.102: 140.32,118.81 v2(140.58,118.55) ; 140.32,118.81 139.83,118.31 138.02,118.31 132.24,112.53 132.24,107.7 130.63,106.1 130.63,105.92 v3(130.92,105.63) ; 140.32,118.81 140.68,119.16 140.68,119.72 140.3,120.11 140.06,120.11 v1(139.73,120.43)
PCIE_TX_PCH_P7: length 93.4
  TOP w0.102: v3(130.91,107.86) 131.29,107.86 131.89,107.26 131.89,106.92 133.69,105.12 133.69,102.06 135.78,99.96 135.78,95.53 134.73,94.47 134.73,88.57 143.01,80.28 143.01,56.92 143.25,56.68 143.57,56.68 v3(143.94,56.32) ; C9401.1 156.24,57.32 155.09,57.32 154.87,57.1 v3(154.87,57.1) ; SB1.B23 141.57,122.27 140.87,122.27 140.71,122.43 v3(139.45,122.43)
  BOTTOM w0.102: v3(130.91,107.86) 130.91,108.33 129.81,109.44 129.81,111.3 ; v3(139.45,122.43) 139.45,122.17 129.81,112.53 129.81,111.3 ; 129.81,111.3 v2(129.44,111.3) ; v3(154.87,57.1) 154.61,57.35 149.97,57.35 149.25,56.63 144.25,56.63 v3(143.94,56.32)
PCIE_TX_PCH_P8: length 205.9
  TOP w0.102: v3(32.66,212.85) 32.4,213.12 32.17,213.12 31.84,213.45 31.84,214.3 C6306.2 ; SB1.C24 141.91,122.81 141.84,122.74 140.62,122.74 139.8,122.91 138.7,123.57 138.35,124.15 138.05,125.45 138.05,127.41 138.31,131.7 138.3,132.32 137.55,133.06 137.55,137.65 147.4,147.5 147.4,148.63 151.66,152.9 151.66,162.05 151.93,162.32 152.12,162.32 v3(152.46,162.66)
  BOTTOM w0.102: v3(32.66,212.85) 32.87,213.06 33.02,213.06 33.49,212.59 34.11,210.66 37.46,207.31 38.33,206.79 38.98,206.63 39.12,206.63 63.56,206.63 72.75,197.44 80.54,197.44 81.6,197.15 81.78,197.06 84.39,194.97 85.07,194.12 85.39,193.67 87.2,191.42 87.26,191.37 87.26,191.36 87.84,190.78 89.47,189.15 102.73,189.15 103.39,189.55 105.04,190.65 107.79,192.69 107.91,192.76 108.78,193.11 112.79,193.78 134.57,193.78 135.37,192.97 135.37,192.57 135.37,188.74 142.18,181.92 142.4,181.83 142.4,181.82 146.34,180.06 147.63,179.48 148.51,178.9 149.11,178.37 150.27,177.21 150.27,176.23 ; v2(149.89,176.23) 150.27,176.23 ; 150.27,176.23 150.27,172.62 152.52,166.21 152.74,165.53 152.92,164.92 152.96,164.79 152.96,162.76 152.86,162.66 v3(152.46,162.66)
PCIRST1#: length 6.9
  TOP w0.102: U2401.51 179.47,23.38 179.85,23.75 180.46,23.75 180.69,23.98 181.39,23.98 181.71,24.31 182.17,24.31 182.66,24.8 v2(182.88,24.8) 182.94,24.73 R2401.1 183.39,23.85 183.48,23.94 R2406.1
PCIRST2#: length 10.5
  TOP w0.102: R2407.1 185.62,22.34 185.62,23.43 R2410.1 185.12,24.29 v2(184.41,24.99) 183.48,24.99 183.11,25.35 182.65,25.35 181.91,24.61 181.59,24.61 181.26,24.29 180.57,24.29 180.33,24.05 179.78,24.05 179.5,23.78 U2401.52
PCIVAUX_CTRL: length 25.3
  TOP w0.102: v3(162.01,152.13) 162.04,152.13 162.21,152.3 162.21,152.97 R1905.1 ; SB1.AN40 157.24,130.96 157.56,130.96 157.66,131.06 v1(157.68,131.06)
  BOTTOM w0.102: v3(162.01,152.13) 162.01,152.01 162.11,151.91 162.11,151.76 162.11,151.36 v2(161.71,150.96) 161.37,150.62 161.37,143.42 159.44,141.49 159.44,140.3 157.4,138.27 157.4,135.59 157.12,135.31 157.12,133.18 157.39,132.91 157.39,131.36 v1(157.68,131.06)
PCM_OUT: length 55.9
  TOP w0.102: R6301.2 53.53,219.25 53.06,219.25 53.05,219.24 R2032.1 52.48,219.61 v3(52.04,220.04) 52.86,220.85 52.86,221.43 53.24,221.82 53.24,222.48 53.04,222.69 53.04,224.86 52.91,224.99 52.91,232.31 v3(53.19,232.59) ; NGFF1.14 41.08,212.92 40.91,213.09 40.91,213.62 40.91,214.15 40.57,214.49 40.18,214.88 40.18,223.07 40.44,223.33 v3(40.44,224.43) ; R6303.2 v3(64.3,229.57)
  BOTTOM w0.102: v3(53.19,232.59) 53.9,233.3 60.65,233.3 64.3,229.65 v3(64.3,229.57) ; v3(52.04,220.04) 51.1,220.04 50.6,219.53 v2(50.55,219.53) 50.32,219.76 46.96,219.76 46.08,220.1 41.75,224.43 v3(40.44,224.43)
PCM_OUT_C: length 2.8
  TOP w0.102: R6303.1 65.19,231.02 v2(64.69,231.52) 64.23,231.99 Q9103.3
PCM_OUT_PCH: length 214
  TOP w0.102: v1(164.34,120.71) 164.32,120.71 163.47,119.86 161.9,119.86 161.77,119.98 161.54,119.98 161.22,119.66 SB1.BA17 ; v3(175.67,148.21) 175.87,147.47 175.87,147.12 175.39,145.57 175.39,143.35 175.06,136.79 174.89,136.31 174.27,135.69 174.27,129.76 171.89,124.16 v3(170.06,121.02) ; v3(52.78,222.04) 52.38,221.63 52.38,221.05 51.56,220.24 51.56,219.28 52.48,218.36 R2032.2
  BOTTOM w0.102: v3(52.78,222.04) 52.8,222.04 54.25,220.59 54.25,220.39 60.6,214.05 66.33,214.05 76.24,204.14 139.02,204.14 142.21,200.95 142.21,194.24 142.26,194.19 142.26,194.19 147.02,189.43 154.76,189.43 155.27,188.93 156.92,188.93 157.18,188.77 157.22,188.74 158.68,187.81 158.7,187.8 159.63,187.26 159.78,187.17 159.79,187.17 159.8,187.16 160.18,186.94 160.4,186.8 160.42,186.8 160.89,186.52 161.88,185.89 164.29,183.48 164.7,182.96 165.53,181.14 166.51,178.88 167.67,176.24 v2(167.67,175.18) 167.67,173.75 169.85,171.57 171.1,170.25 171.48,168.63 171.59,168.14 171.61,167.93 171.71,167.52 171.82,167.08 171.92,166.6 171.94,166.49 171.98,166.11 171.98,163.06 172.45,161.38 172.45,161.27 173.81,156.66 174.21,156.07 174.26,155.98 174.33,155.84 174.57,155.39 175.67,153.31 v3(175.67,148.21) ; v3(170.06,121.02) 169.21,120.17 169.04,120.17 168.9,120.03 168.8,120.03 168.33,119.56 166.31,119.56 166.28,119.58 165.83,119.58 165.51,119.91 165.51,120.26 165.06,120.71 v1(164.34,120.71)
PCM_SYNC: length 56.3
  TOP w0.102: NGFF1.10 41.06,211.92 40.58,212.41 40.58,212.74 40.43,212.89 40.43,213.82 40.43,213.95 40.09,214.29 39.7,214.68 39.7,224.67 39.64,224.73 v3(39.63,224.73) ; R6302.2 49.52,217.09 R2033.1 49.52,218.81 49.4,218.92 v3(49.4,219.07) 49.63,219.3 49.63,221.13 51.69,223.19 v3(51.69,232) ; R6321.2 v3(62.4,229.59)
  BOTTOM w0.102: v3(39.63,224.73) 39.63,224.56 41,223.19 42.19,223.19 v2(43.7,221.68) 45.62,219.76 47.39,219.07 v3(49.4,219.07) ; v3(62.4,229.59) 62.4,230.87 60.45,232.82 54.97,232.82 54.15,232 v3(51.69,232)
PCM_SYNC_C: length 5.6
  TOP w0.102: R6321.1 63.28,230.62 v2(62.48,231.42) 62.16,231.75 62.16,233.25 61.87,233.53 61.87,234.16 62.43,234.72 Q9103.6
PCM_SYNC_PCH: length 210.9
  TOP w0.102: v3(50.8,221.58) 50.11,220.89 50.11,218.45 R2033.2 ; v3(175.41,147.35) 175.39,147.35 174.9,146.86 174.9,143.55 174.57,136.85 174.47,136.57 173.79,135.89 173.79,129.86 173.2,128.49 171.49,124.43 170.9,123.85 169.62,122.44 169.12,121.95 168.04,121.95 166.49,120.4 165.74,120.4 164.49,119.15 162.63,119.15 SB1.BE16
  BOTTOM w0.102: v3(50.8,221.58) 52.57,221.58 52.58,221.56 52.6,221.56 53.77,220.39 53.77,219.81 53.77,219.64 v2(55.27,218.14) 59.48,213.93 59.93,213.76 59.94,213.76 60.44,213.56 66.27,213.56 75.92,203.91 138.86,203.91 141.96,200.81 141.96,194.08 146.84,189.2 154.63,189.2 155.17,188.67 156.74,188.67 159.51,187.06 160.01,186.75 160.23,186.62 160.25,186.61 160.8,186.29 163.86,183.23 163.86,183.23 164.91,181.33 164.97,181.21 165.8,179.18 166.83,175.45 167,174.98 167,173.72 169.5,171.22 170.5,170.18 170.5,170.15 170.6,170.05 170.68,169.72 170.7,169.64 170.71,169.62 170.77,169.37 170.77,169.37 170.8,169.27 170.98,168.51 171.34,166.97 171.46,166.41 171.5,166.09 171.5,162.68 171.61,162.27 171.85,161.41 171.85,161.39 171.91,161.22 172.56,158.86 173.03,157.6 173.36,156.46 173.39,156.4 173.84,155.74 173.9,155.62 174.05,155.34 175.19,153.19 175.19,147.8 175.27,147.43 v3(175.41,147.35)
PECI_CPU: length 199.4
  TOP w0.102: CPU1.G7 v1(88.1,84.74) ; v3(107.29,68.17) 102.95,72.51 98.93,72.51 94.86,76.58 91.95,76.58 91.69,76.33 v1(91.26,76.33) ; R2428.1 177.85,10.74 178.13,10.46 178.13,9.77 178.28,9.62 178.28,9.55 v3(178.33,9.5) ; v3(97.33,2.54) 97.46,2.67 97.46,3.63 97.1,3.99 96.05,3.99 95.68,4.36 95.68,6.44 97.3,8.06 97.3,18.5 97.2,18.6 97.2,20.64 97.28,20.72 97.28,25.18 96.72,25.75 96.72,26.63 95.17,28.18 95.17,29.57 v3(94.95,29.79)
  BOTTOM w0.102: v1(88.1,84.74) 88.5,84.33 88.5,81.83 88.11,81.44 87.98,81.44 87.5,80.96 87.5,79.41 90.59,76.33 v1(91.26,76.33) ; v3(97.33,2.54) 97.64,2.23 124.91,2.23 125.66,2.97 135.69,13 142.73,13 144.73,11 144.73,10.42 147.54,7.61 159.64,7.61 163.43,11.4 171.55,11.4 171.61,11.46 174.86,11.46 175.04,11.28 175.47,11.28 176.4,10.35 176.4,9.87 176.85,9.42 178.26,9.42 v3(178.33,9.5) ; v3(94.95,29.79) 108.36,43.21 108.36,49.63 107.42,50.57 107.42,53.03 107.67,53.28 107.67,53.8 108.28,54.41 v2(108.28,64.24) 108.28,65.45 107.13,66.6 107.13,67.3 107.34,67.51 107.34,68.12 v3(107.29,68.17)
PECI_EC: length 4
  TOP w0.102: U2401.30 176.29,13.92 176.82,13.39 177.4,13.39 v2(178.06,12.73) 178.06,11.95 R2428.2
PECI_READY: length 5
  TOP w0.102: R2430.2 178.89,12.29 v2(179.33,12.73) 178.85,12.73 177.9,13.67 176.94,13.67 176.69,13.92 U2401.31
PEG_CLK1_PCH: length 221.3
  TOP w0.102: SB1.AH10 154.18,116.18 154.18,116.04 154.28,115.94 v1(154.87,115.94) ; v3(36.24,220.5) 36.46,220.5 36.56,220.6 36.56,220.97 36.08,221.45 35.66,221.45 35.38,221.17 NGFF1.47
  BOTTOM w0.102: 52.09,210.13 v2(51.97,209.75) ; 52.09,210.13 54.05,209.54 55.52,209.06 56.99,208.59 63.6,208.59 73.35,198.84 82.62,198.84 85.86,195.6 86.78,194.18 87.48,193.3 88,192.66 88.06,192.59 88.79,191.85 90.09,190.55 99.18,190.55 109.99,195.17 135.15,195.17 136.77,193.55 136.77,189.36 143.07,183.06 148.35,180.69 149.44,179.97 149.72,179.74 151.66,177.79 151.66,173.35 151.84,172.87 154.41,164.93 154.41,160.52 149.71,152.77 149.15,152.21 148.51,152.21 148.43,152.2 148.24,152.14 148.14,152.07 148.07,152 143.01,143.65 143.01,141.36 143.1,140.89 143.1,140.87 143.56,138.42 143.57,138.42 144.23,136.08 147.03,133.29 147.03,132.44 148.08,131.39 148.08,122.66 152.23,118.5 152.67,118.5 154.05,117.12 154.85,117.12 155.09,116.88 155.09,116.05 154.97,115.94 v1(154.87,115.94) ; 52.09,210.13 52.06,210.14 51.38,210.34 38.73,210.34 38.56,210.31 36.45,210.31 35.77,210.99 35.77,211.04 35.18,212.46 35.18,216.84 36.77,218.43 36.77,219.92 36.7,219.99 36.34,219.99 36.24,220.09 v3(36.24,220.5)
PEG_CLK1_PCH#: length 221.2
  TOP w0.102: NGFF1.49 36.17,221.67 36.78,221.06 36.78,220.87 v3(37.15,220.5) ; SB1.AH9 v1(155.05,115.24)
  BOTTOM w0.102: v3(37.15,220.5) 36.99,220.34 36.99,218.34 35.39,216.75 35.39,212.5 35.98,211.08 36.54,210.53 38.54,210.53 38.72,210.56 45.85,210.56 ; v1(155.05,115.24) 155.31,115.78 155.31,116.97 154.94,117.34 154.14,117.34 152.76,118.72 152.32,118.72 148.3,122.75 148.3,131.48 147.24,132.53 147.24,133.38 144.42,136.2 143.77,138.47 143.32,140.89 143.32,140.91 143.23,141.39 143.23,143.59 148.24,151.87 148.28,151.9 148.34,151.94 148.48,151.99 148.53,152 149.24,152 149.88,152.63 154.62,160.46 154.62,164.96 152.04,172.94 151.88,173.38 151.88,177.88 149.86,179.9 149.57,180.14 148.45,180.88 143.19,183.24 136.98,189.45 136.98,193.64 135.24,195.39 109.94,195.39 99.13,190.77 90.18,190.77 88.95,192 88.22,192.73 88.12,192.85 87.65,193.44 86.95,194.3 86.51,194.99 86.03,195.73 82.71,199.05 73.44,199.05 63.69,208.8 57.02,208.8 56.87,208.85 54.11,209.75 54.11,209.75 52.21,210.32 52.12,210.35 51.42,210.56 45.85,210.56 ; 45.85,210.56 v2(45.85,210.95)
PEG_CLK2_PCH: length 135.5
  TOP w0.102: v3(133.1,98.53) 132.69,98.53 132.5,98.34 132.5,87.37 140.79,79.08 140.79,55.01 141.63,54.17 141.63,48.22 146.68,43.17 146.68,43.05 146.69,43.05 146.69,39.54 145.34,38.2 145.34,30.21 146.76,28.79 146.76,22.33 144.67,20.23 144.29,20.23 144.16,20.1 141.64,20.1 141.12,20.62 139.61,20.62 139.14,21.1 139.14,21.39 139.05,21.48 U3101.15 ; SB1.AE15 v1(152.23,117.99)
  BOTTOM w0.102: v3(133.1,98.53) 134.01,98.53 134.85,97.69 141.73,97.69 143.73,97.52 148.7,97.52 150.71,99.53 152.95,99.53 153.66,100.24 153.66,101.35 ; 153.66,101.35 153.66,109.15 153.4,109.41 153.4,114.4 152.98,114.82 152.98,116.97 152.98,116.97 152.98,117.57 152.76,117.8 152.42,117.8 v1(152.23,117.99) ; 153.66,101.35 v2(154.05,101.35)
PEG_CLK2_PCH#: length 135.4
  TOP w0.102: v3(133.16,99.44) 132.67,99.44 132.59,99.35 132.59,98.73 132.29,98.43 132.29,87.28 140.58,78.99 140.58,54.92 141.41,54.08 141.41,48.13 146.47,43.08 146.47,42.96 146.47,42.96 146.47,39.63 145.12,38.29 145.12,30.12 146.55,28.7 146.55,22.42 144.58,20.45 144.2,20.45 144.07,20.32 141.73,20.32 141.21,20.84 139.7,20.84 139.36,21.19 139.36,21.37 139.45,21.47 U3101.16 ; SB1.AE14 v1(152.3,117.35)
  BOTTOM w0.102: v3(133.16,99.44) 133.48,99.44 133.58,99.34 133.58,98.84 133.68,98.74 134.1,98.74 134.94,97.9 141.74,97.9 143.74,97.74 148.61,97.74 150.62,99.75 152.86,99.75 153.44,100.33 153.44,105.36 ; 153.44,105.36 153.44,109.06 153.19,109.32 153.19,114.31 152.77,114.73 152.77,116.88 152.77,116.88 152.77,117.48 152.67,117.58 152.53,117.58 v1(152.3,117.35) ; 153.44,105.36 v2(153.06,105.36)
PEG_CLK8_PCH: length 102.4
  TOP w0.102: v3(157.05,66.36) 156.57,66.36 156.44,66.5 156.44,67.01 157.56,68.12 157.56,87.82 157.25,88.12 155.89,88.12 155.71,88.3 155.71,88.55 155.89,88.73 157.25,88.73 157.56,89.04 157.56,89.47 157.25,89.77 155.89,89.77 155.71,89.95 155.71,90.2 155.89,90.38 157.25,90.38 157.56,90.69 157.56,91.12 157.25,91.42 155.89,91.42 155.71,91.6 155.71,91.85 155.89,92.03 157.25,92.03 157.56,92.34 157.56,92.77 157.25,93.07 155.89,93.07 155.71,93.25 155.71,93.51 155.89,93.68 157.25,93.68 157.56,93.99 157.56,94.56 151.78,100.34 151.78,100.65 v1(151.99,100.86) ; v1(151.17,118.33) SB1.AC15
  BOTTOM w0.102: v3(157.05,66.36) 156.47,66.36 156.42,66.41 156.42,66.56 159.01,69.15 167.07,69.15 172.89,63.33 172.89,61.96 174.39,60.45 175.11,60.45 176.21,59.35 178.35,59.35 179.01,58.69 179.97,58.69 180.07,58.79 181.55,58.79 SLOT2.A13 ; v2(152.45,103.2) 152.07,103.2 ; 152.07,103.2 152.07,108.79 152.68,109.4 152.68,111.56 151.89,112.35 151.89,117.76 151.55,118.1 151.4,118.1 v1(151.17,118.33) ; 152.07,103.2 152.07,101.75 151.73,101.41 151.73,101.13 v1(151.99,100.86)
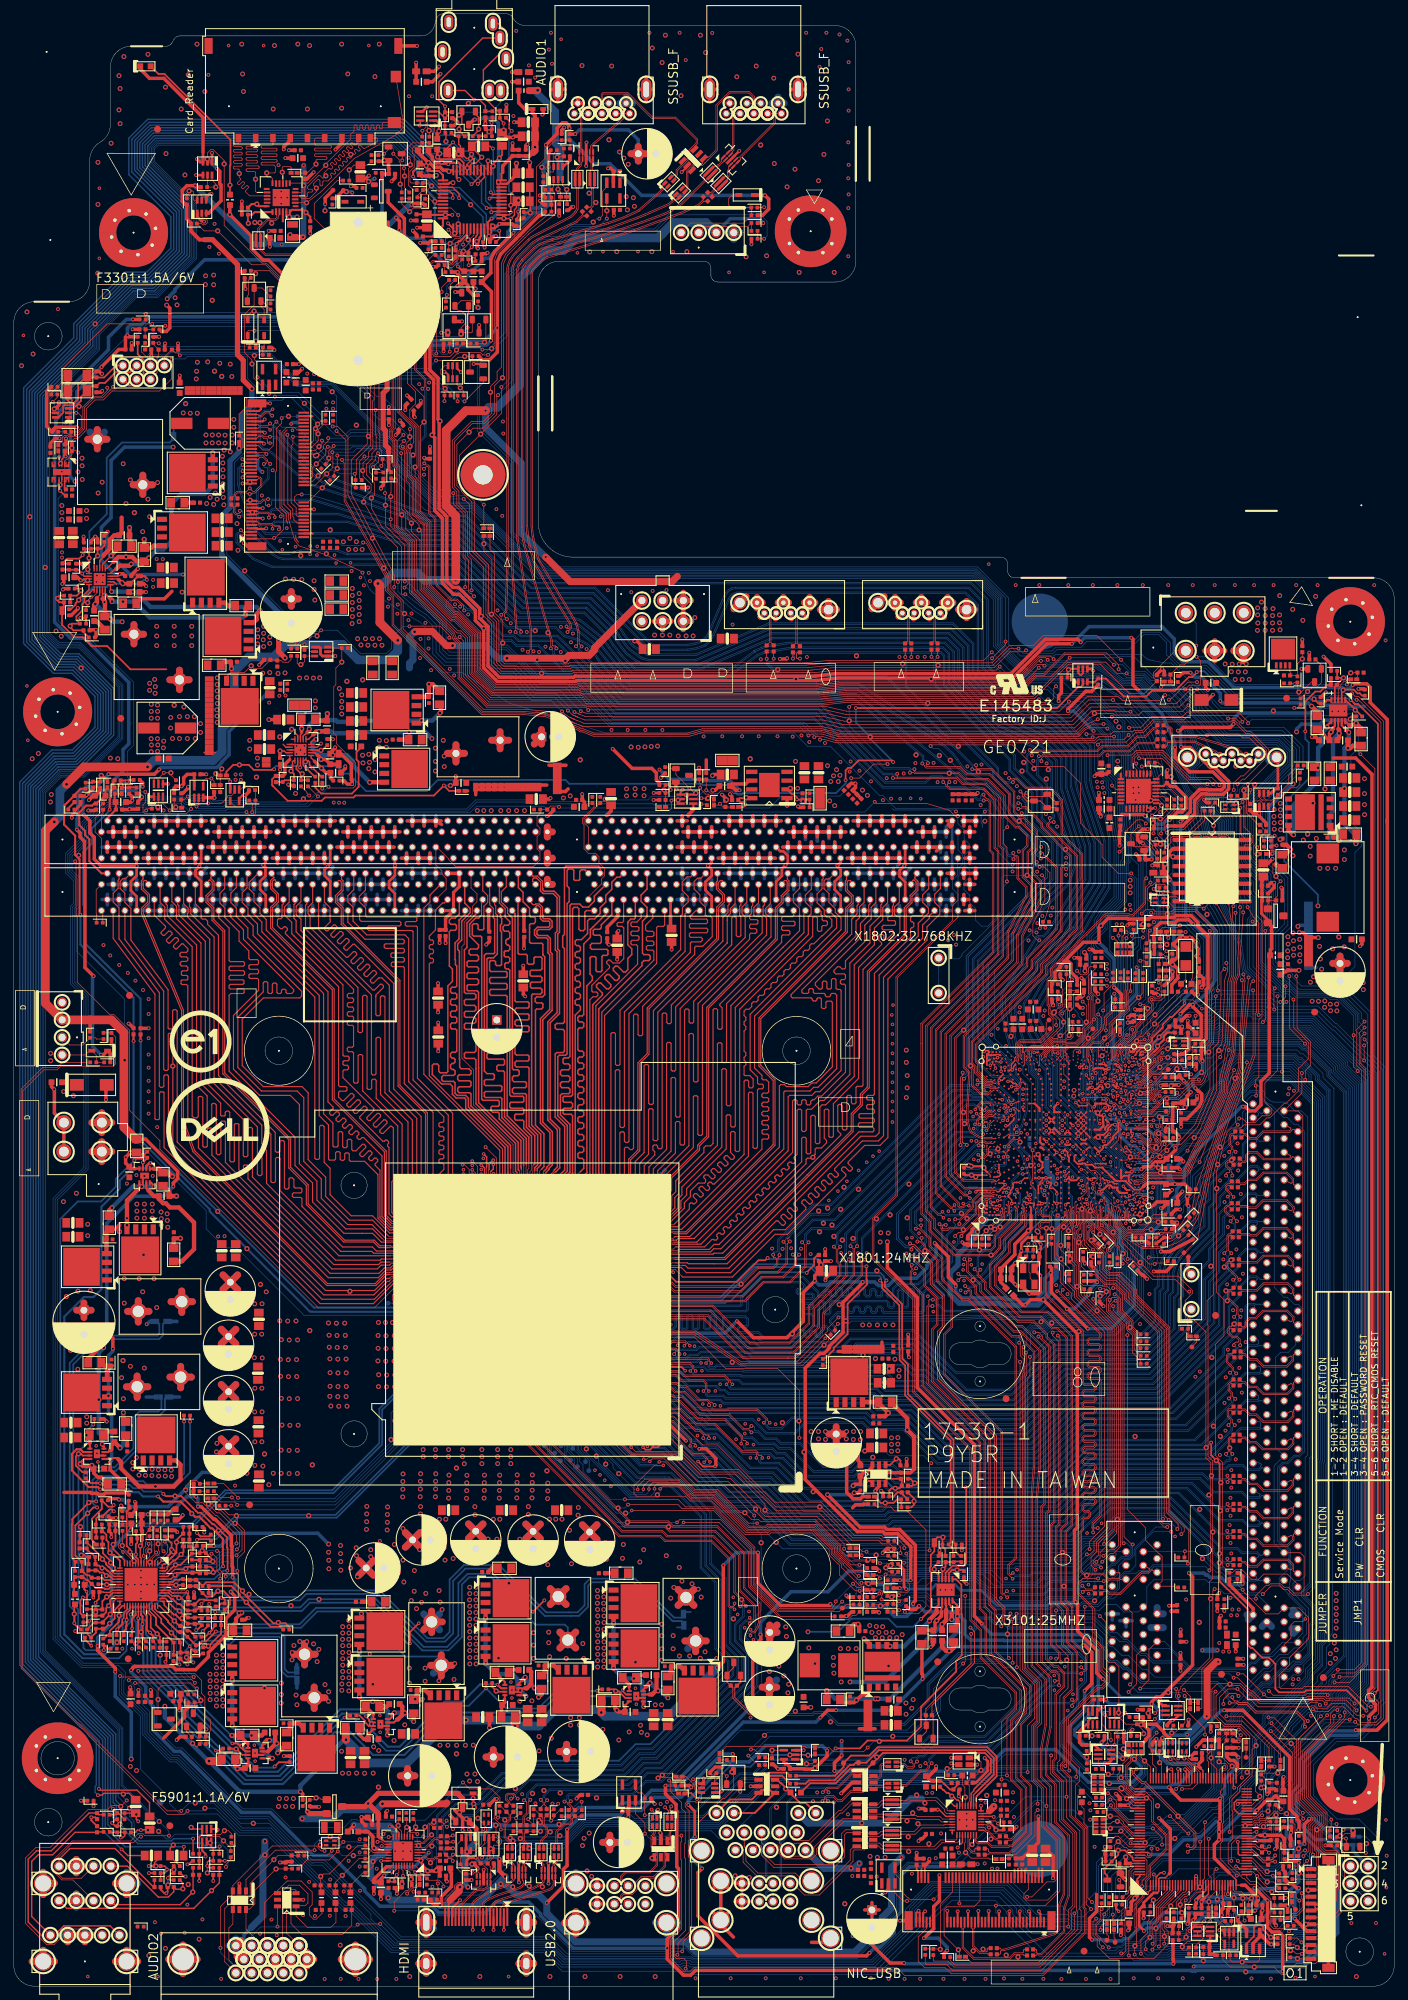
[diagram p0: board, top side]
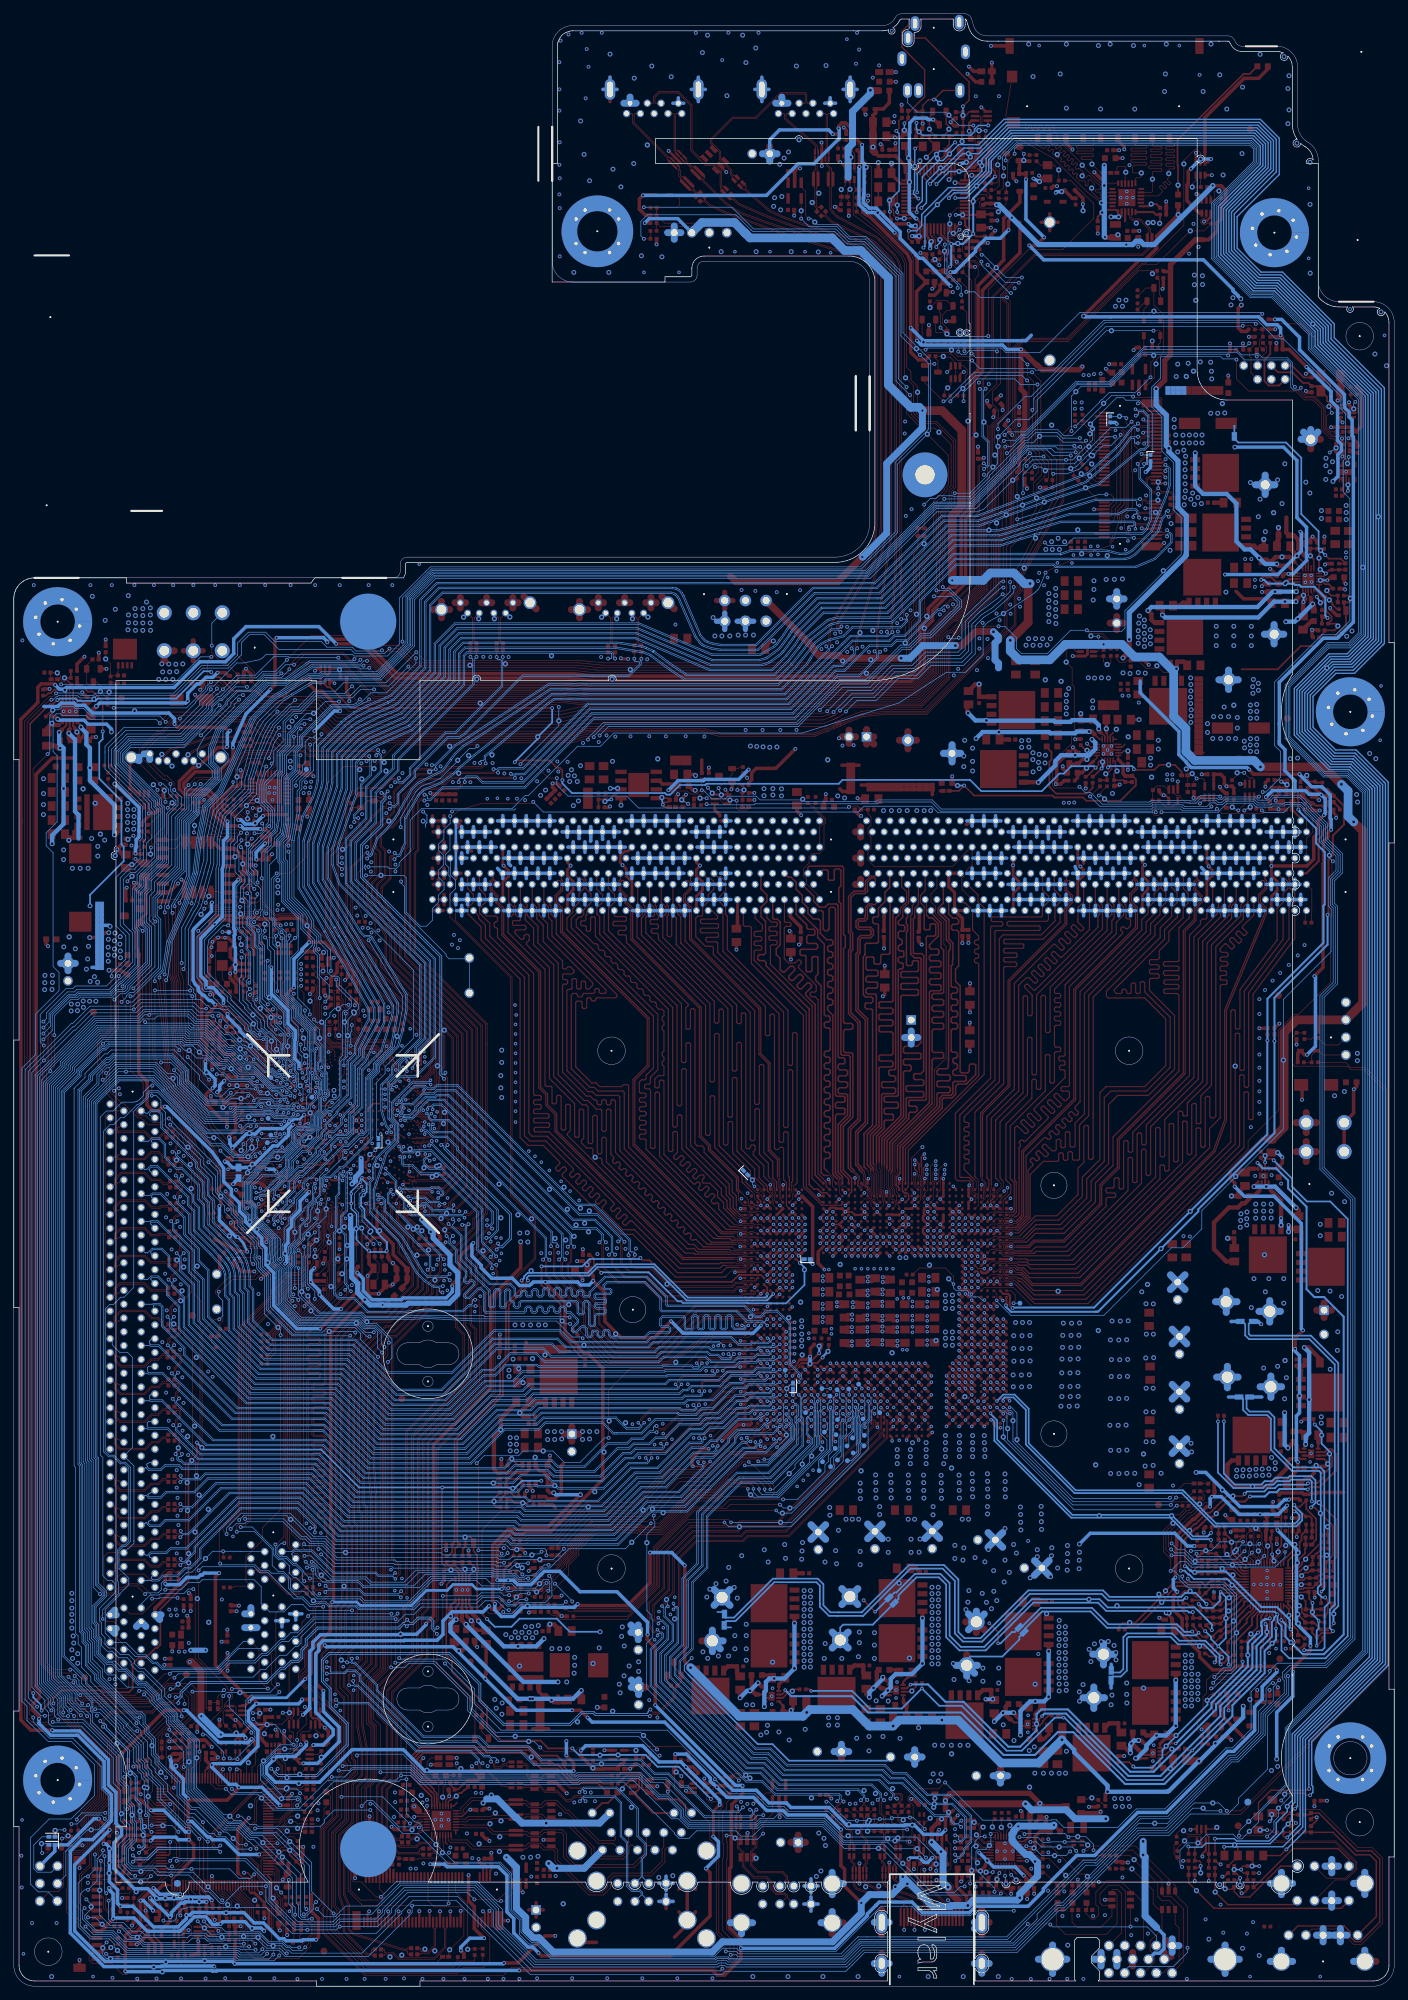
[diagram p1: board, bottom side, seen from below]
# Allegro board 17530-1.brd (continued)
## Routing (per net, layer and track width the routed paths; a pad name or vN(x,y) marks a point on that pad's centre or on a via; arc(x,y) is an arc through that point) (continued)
PEG_CLK8_PCH#: length 102.3
  TOP w0.102: v1(151.17,117.7) SB1.AC14 ; v1(151.15,100.67) 151.46,100.67 151.56,100.56 151.56,100.25 157.34,94.47 157.34,94.08 157.16,93.9 155.8,93.9 155.5,93.59 155.5,93.16 155.8,92.86 157.16,92.86 157.34,92.68 157.34,92.43 157.16,92.25 155.8,92.25 155.5,91.94 155.5,91.51 155.8,91.21 157.16,91.21 157.34,91.03 157.34,90.78 157.16,90.6 155.8,90.6 155.5,90.29 155.5,89.86 155.8,89.56 157.16,89.56 157.34,89.38 157.34,89.13 157.16,88.95 155.8,88.95 155.5,88.64 155.5,88.21 155.8,87.91 157.16,87.91 157.34,87.73 157.34,68.21 156.22,67.09 156.22,66.41 156.39,66.24 v3(156.39,65.73)
  BOTTOM w0.102: v2(152.12,109.98) 152.46,109.98 ; 152.46,109.98 152.46,109.49 151.85,108.88 151.85,101.84 151.51,101.5 151.51,101.03 v1(151.15,100.67) ; 152.46,109.98 152.46,111.47 151.67,112.26 151.67,117.67 151.46,117.88 151.35,117.88 v1(151.17,117.7) ; SLOT2.A14 180.07,59.27 180.07,59.09 179.88,58.9 179.1,58.9 178.44,59.56 176.3,59.56 175.2,60.67 174.48,60.67 173.1,62.05 173.1,63.42 167.16,69.36 158.92,69.36 156.21,66.65 156.21,66.32 156.38,66.15 156.39,66.15 v3(156.39,65.73)
PEG_CLK9_PCH: length 101.2
  TOP w0.102: SB1.U3 148.68,112.46 148.68,111.78 148.99,111.47 149.92,111.47 150.1,111.29 150.1,111.04 149.92,110.86 148.83,110.86 148.51,110.54 148.51,109.98 148.79,109.69 149.34,109.69 149.44,109.59 149.44,100.12 154.77,94.8 154.77,87.33 155.07,87.03 156.43,87.03 156.6,86.85 156.6,86.6 156.43,86.42 155.07,86.42 154.77,86.11 154.77,85.68 155.07,85.38 156.43,85.38 156.6,85.2 156.6,84.95 156.43,84.77 155.07,84.77 154.77,84.46 154.77,84.03 155.07,83.73 156.43,83.73 156.6,83.55 156.6,83.29 156.43,83.12 155.07,83.12 154.77,82.81 154.77,82.38 155.07,82.08 156.43,82.08 156.6,81.9 156.6,81.64 156.43,81.47 155.07,81.47 154.77,81.16 154.77,80.73 155.07,80.42 156.43,80.42 156.6,80.25 156.6,79.99 156.43,79.81 155.07,79.81 154.77,79.51 154.77,79.08 155.07,78.77 156.43,78.77 156.6,78.59 156.6,78.34 156.43,78.16 155.07,78.16 154.77,77.86 154.77,77.43 155.07,77.12 156.43,77.12 156.6,76.94 156.6,76.69 156.43,76.51 155.07,76.51 154.77,76.21 154.77,75.78 155.07,75.47 156.43,75.47 156.6,75.29 156.6,75.04 156.43,74.86 155.07,74.86 154.77,74.56 154.77,74.12 155.07,73.82 156.43,73.82 156.6,73.64 156.6,73.39 156.43,73.21 155.07,73.21 154.77,72.91 154.77,72.47 155.07,72.17 156.43,72.17 156.6,71.99 156.6,71.74 156.43,71.56 155.07,71.56 154.77,71.25 154.77,70.82 155.07,70.52 156.43,70.52 156.6,70.34 156.6,70.09 156.43,69.91 155.07,69.91 154.77,69.6 154.77,68.98 155.07,68.68 155.63,68.68 155.78,68.53 155.78,68.1 155.62,67.94 155,67.94 154.77,67.72 154.77,66.16 154.48,65.87 154.48,60.1 154.98,59.6 157.82,59.6 158.6,58.83 160.24,58.83 160.35,58.94 SLOT1.A13
PEG_CLK9_PCH#: length 101.2
  TOP w0.102: SLOT1.A14 160.15,59.94 160.25,59.84 160.25,59.14 160.15,59.04 158.69,59.04 157.91,59.82 155.07,59.82 154.7,60.19 154.7,65.78 154.98,66.07 154.98,67.63 155.09,67.73 155.71,67.73 155.99,68.01 155.99,68.62 155.72,68.9 155.16,68.9 154.98,69.07 154.98,69.51 155.16,69.69 156.51,69.69 156.82,70 156.82,70.43 156.51,70.73 155.16,70.73 154.98,70.91 154.98,71.16 155.16,71.34 156.51,71.34 156.82,71.65 156.82,72.08 156.51,72.38 155.16,72.38 154.98,72.56 154.98,72.82 155.16,72.99 156.51,72.99 156.82,73.3 156.82,73.73 156.51,74.04 155.16,74.04 154.98,74.21 154.98,74.47 155.16,74.65 156.51,74.65 156.82,74.95 156.82,75.38 156.51,75.69 155.16,75.69 154.98,75.87 154.98,76.12 155.16,76.3 156.51,76.3 156.82,76.6 156.82,77.03 156.51,77.34 155.16,77.34 154.98,77.52 154.98,77.77 155.16,77.95 156.51,77.95 156.82,78.25 156.82,78.68 156.51,78.99 155.16,78.99 154.98,79.17 154.98,79.42 155.16,79.6 156.51,79.6 156.82,79.9 156.82,80.34 156.51,80.64 155.16,80.64 154.98,80.82 154.98,81.07 155.16,81.25 156.51,81.25 156.82,81.55 156.82,81.99 156.51,82.29 155.16,82.29 154.98,82.47 154.98,82.72 155.16,82.9 156.51,82.9 156.82,83.21 156.82,83.64 156.51,83.94 155.16,83.94 154.98,84.12 154.98,84.37 155.16,84.55 156.51,84.55 156.82,84.86 156.82,85.29 156.51,85.59 155.16,85.59 154.98,85.77 154.98,86.02 155.16,86.2 156.51,86.2 156.82,86.51 156.82,86.94 156.51,87.24 155.16,87.24 154.98,87.42 154.98,94.89 149.66,100.21 149.66,109.68 149.43,109.91 148.88,109.91 148.73,110.06 148.73,110.45 148.92,110.65 150.01,110.65 150.32,110.95 150.32,111.38 150.01,111.69 149.08,111.69 148.9,111.87 148.9,112.3 SB1.U2
PEG_CLKREQ1_PCH#: length 247.6
  TOP w0.102: v3(37.82,230.25) 37.71,230.14 33.88,230.14 33.68,229.94 33.68,228.75 32.64,227.71 R1801.1 33.2,224.04 33.2,222.96 33.49,222.67 NGFF1.53 ; SB1.BE31 162.38,126.39 162.6,126.18 162.6,126.16 162.76,126 163.08,126 163.45,126.36 164.83,126.36 166.24,127.78 166.24,127.8 166.88,128.44 168.76,128.44 170.88,130.56 172.02,130.56 172.48,131.02 172.6,131.25 172.95,132.13 173,132.17 173,136.21 173.51,136.72 173.51,144.05 173.76,144.3 173.76,153.06 171.17,155.65 168.22,155.65 167.89,155.32 164.9,155.32 164.79,155.43 v3(164.79,155.49) ; v3(56.12,222.06) 56.18,222 56.18,213.98 56.79,213.37 56.79,211.06 58.36,209.5 58.36,208.36 58.44,202.23 64.36,196.32 64.78,196.32 65.74,195.37 65.74,189.99 69.08,186.64 82.39,186.64 82.49,186.74 116.84,186.74 120.71,187.15 147.12,187.15 v3(147.8,187.83)
  BOTTOM w0.102: v3(37.82,230.25) 37.98,230.41 40.97,230.41 v2(42.1,229.27) 42.1,229.16 46.67,224.59 47.88,224.59 48.74,225.45 52.04,225.45 53.21,224.28 53.74,224.28 55.95,222.07 56.11,222.07 v3(56.12,222.06) ; v3(147.8,187.83) 149.76,187.83 150.98,186.61 156.14,186.61 158.41,184.35 159.37,184.35 160.68,183.04 160.68,179.97 161.85,178.8 161.85,176.13 163.63,174.36 163.75,173.98 163.75,173.61 163.75,173.29 163.75,173.29 163.75,171.58 163.75,171.58 162.51,170.34 162.51,167.89 162.53,167.79 165.71,164.61 165.71,161.93 165.2,161.42 165.2,159.7 164.89,159.39 164.65,159.39 164.24,158.98 164.24,156.05 v3(164.79,155.49)
PEG_CLKREQ2_PCH#: length 191.1
  TOP w0.102: v3(148.34,25.51) 147.95,25.12 147.95,21.84 145.16,19.05 144.86,19.05 144.31,18.5 R1803.1 144.18,18.49 143.71,18.49 143.64,18.41 R3102.2 ; v3(167.51,24.64) 170.06,22.09 170.18,22.09 v3(170.18,22.12) ; SB1.AR32 157.95,127.25 158.11,127.25 v1(158.11,127.26)
  BOTTOM w0.102: v3(148.34,25.51) 153.57,25.51 154.97,24.12 154.97,23.76 155.56,23.16 164.64,23.16 164.9,23.42 165.81,23.42 167.03,24.64 v3(167.51,24.64) ; v3(170.18,22.12) 171.97,23.91 171.97,23.95 173.63,25.6 174.33,25.6 176.35,27.63 176.35,29.55 179.25,32.45 179.25,33.1 179.78,33.63 179.78,35.77 180.72,36.71 180.72,37.43 181.28,37.99 181.28,39.12 181.58,39.43 182.2,39.43 187.48,44.71 187.48,45.67 188.87,47.07 188.87,49.64 189.36,50.12 189.36,51.29 189.71,51.64 189.71,75.69 189.94,75.92 189.94,128.83 187.96,130.81 187.96,132.05 186.56,133.45 186.19,133.45 185.35,134.29 177.31,134.29 175.46,132.45 175.46,130.99 175.41,130.94 175.41,130.87 172.15,127.61 170.01,127.61 v2(169.7,127.29) 169.29,127.29 168.72,127.86 164.87,127.86 164.29,128.45 162.86,128.45 162.2,127.79 161.45,127.79 161.25,127.58 159.97,127.58 159.62,127.94 158.79,127.94 v1(158.11,127.26)
PEG_CLKREQ3_PCH#: length 201.2
  TOP w0.102: v3(166.37,20.49) 166.37,21.52 v3(165.04,22.85) ; v1(160.91,126.52) 161.2,126.23 SB1.BB30 ; v3(153.67,10.54) 153.67,8.19 148.56,3.07 136.35,3.07 135.66,3.76 135.66,4.2 R1805.1
  BOTTOM w0.102: v3(166.37,20.49) 167.3,20.49 v2(168.21,21.4) 169.14,22.33 169.6,22.33 173.18,25.91 174.2,25.91 176.02,27.73 176.02,29.65 178.94,32.57 178.94,33.22 179.48,33.76 179.48,35.9 180.42,36.84 180.42,37.55 180.97,38.11 180.97,39.25 181.46,39.73 182.07,39.73 187.12,44.78 187.12,45.9 188.57,47.35 188.57,49.76 189.05,50.25 189.05,51.42 189.41,51.77 189.41,75.82 189.63,76.04 189.63,127.36 189.63,128.71 187.66,130.68 187.66,131.92 186.56,133.02 186.19,133.02 185.38,133.83 179.41,133.83 177.76,132.18 176.8,132.18 176.3,131.69 176.3,130.64 176.25,130.59 176.25,130.53 171.9,126.18 168.25,126.18 167.94,126.49 167.75,126.67 163.92,126.67 163.74,126.85 162.56,126.85 162.06,126.35 161.07,126.35 v1(160.91,126.52) ; v3(153.67,10.54) 156.84,13.72 156.84,17.92 161.78,22.85 v3(165.04,22.85)
PEG_CLKREQ8_PCH#: length 231.6
  TOP w0.102: SB1.AE41 152.13,132.1 152.13,133.34 v1(152.17,133.38) ; v3(157.07,179.83) 157.45,180.2 161.16,180.2 162.53,181.57 163.62,181.57 165.19,183.13 169.01,183.13 176.32,183.13 176.51,183.32 176.93,183.32 177.23,183.03 177.23,182.73 178.53,181.43 178.79,181.43 179.1,181.43 181.53,179.01 181.53,177.99 178.36,174.83 177.99,174.83 v3(177.3,174.14) ; v3(185.41,142.91) 185.45,142.88 185.45,138.83 187.55,136.73 187.55,134.34 186.14,132.93 186.14,129.69 184.28,127.83 184.03,127.83 181.97,125.77 181.53,125.77 180.53,124.77 178.24,124.77 177.77,124.31 177.59,124.31 176.42,124.31 175.79,123.68 175.71,123.43 175.58,122.99 174.27,118.03 174.27,100.51 175.34,99.44 175.34,94.21 174.12,92.99 174.12,76.88 175.13,75.86 175.13,60.88 176.11,59.91 R1807.1 176.58,59.91 177.06,60.39 177.88,60.39 179.32,58.95 180.36,58.95 181.1,59.69 184.53,59.69 186.05,58.17 SLOT2.B12
  BOTTOM w0.102: v1(152.17,133.38) 152.17,134.12 151.69,134.6 151.69,136.32 151.6,136.41 151.6,140.04 v2(150.67,140.97) 150.06,141.58 150.06,142.26 152.81,145.01 152.81,146.02 153.09,146.3 153.97,146.3 154.53,146.87 154.53,149.96 155.8,151.23 155.8,152.12 156.84,153.16 156.84,154.28 156.94,154.45 157.61,155.56 159.72,157.66 159.72,165.92 159.7,166 159.69,166.03 159.69,166.03 159.68,166.06 159.61,166.43 159.61,166.44 159.56,166.73 159.42,167.48 159.42,167.52 159.39,167.68 159.27,168.31 159.27,168.31 159.01,169.73 158.95,170.05 158.95,173.14 158.57,173.52 158.57,174.57 157.65,175.49 157.6,175.49 157.05,176.04 157.05,176.51 157.07,176.53 v3(157.07,179.83) ; v3(185.41,142.91) 184.56,143.76 183.81,143.76 183.18,144.38 183.18,144.75 180.04,147.89 180.04,153.39 180.41,153.77 180.79,154.15 180.8,154.16 180.8,158.12 180.11,158.81 180.11,160.12 177.6,162.63 177.6,169.67 176.21,171.06 176.21,172.05 177.27,173.1 177.27,174.11 v3(177.3,174.14)
PEG_CLKREQ9_PCH#: length 200.4
  TOP w0.102: v3(157.12,140.76) 157.61,140.27 157.61,139.4 157.53,139.32 157.53,138.82 157.48,138.77 157.48,138.64 156.33,137.49 156.27,137.49 154.5,135.72 153.82,135.72 153.49,135.39 SB1.AF48 ; v3(161.35,94.31) 161.35,69.03 163.96,66.42 163.96,64.61 165.9,62.66 165.95,62.66 166.37,62.24 166.37,58.66 SLOT1.B12 168.07,57.94 168.25,57.76 R1809.1 ; v3(179.49,154.22) 180.06,153.64 180.06,141.07 179.86,140.87 179.86,134.83 179.73,134.48 176.99,126.94 176.99,125.13 v3(177.33,124.79) ; v3(158.47,178.3) 158.49,178.32 161.94,178.32 162.59,178.97 166.54,178.97 170.42,175.08 173.58,175.08 v3(174.69,173.97)
  BOTTOM w0.102: v3(157.12,140.76) 157.12,141.39 158.85,143.13 158.85,148.62 156.91,150.56 156.91,150.63 156.74,150.79 156.74,151.49 158.42,153.16 158.42,155.04 160.68,157.3 160.68,162.86 160.97,163.15 160.97,165.61 160.97,165.62 160.25,166.33 160.23,166.48 160.19,166.66 159.98,167.81 159.88,168.37 159.88,174.7 159.09,175.48 158.65,175.93 158.65,178.12 v3(158.47,178.3) ; v3(179.49,154.22) 179.83,154.56 179.83,157.72 179.15,158.41 179.15,159.7 176.63,162.22 176.63,169.27 175.24,170.67 175.24,173.43 v3(174.69,173.97) ; v3(177.33,124.79) 174.85,122.3 174.7,122.3 174.52,122.12 174.52,122.12 174.17,121.78 174.17,121.63 172.47,119.92 172.47,119.04 170.76,117.34 170.76,115.01 168.52,112.76 168.52,111.9 167.54,110.92 167.54,110.15 165.19,107.8 165.19,107.03 165.06,106.91 165.06,106.02 165.2,105.88 165.2,105.26 165.2,105.24 164.92,104.96 164.82,104.68 164.82,104.12 164.72,103.83 163.68,102.78 163.68,97.38 v2(161.72,95.43) 161.35,95.05 v3(161.35,94.31)
PEG_RCOMP_CPU: length 9
  TOP w0.203: CPU1.L7 88.08,89.33 86.58,89.33 86.23,89.67 86.23,89.94 85.93,90.24 85.84,90.24
  TOP w0.305: 85.84,90.24 84.77,90.24 v3(83.31,91.69) 83.31,92 82.98,92.33 R301.2
  BOTTOM w0.305: v2(83.31,92.71) v3(83.31,91.69)
PEG_RX_CPU_N0: length 107.3
  TOP w0.102: CPU1.B7 88.12,80.19 88.12,79.49 88.83,78.78 90.13,78.78 90.22,78.69 91.53,78.69 v1(91.79,78.96)
  BOTTOM w0.102: SLOT2.A17 180.74,62.38 180.6,62.43 180.54,62.56 180.19,62.9 177.94,62.9 177.31,63.54 175.02,63.54 167.7,70.85 158.44,70.85 152.92,65.34 128.13,65.34 127.59,64.8 112.78,64.8 107.98,69.6 102.83,69.6 94.35,78.07 92.72,78.07 92.15,78.64 91.89,78.64 91.79,78.74 v1(91.79,78.96)
PEG_RX_CPU_N1: length 105.1
  TOP w0.102: CPU1.C6 v1(89.93,81.08)
  BOTTOM w0.102: SLOT2.A22 180.49,67.32 180.54,67.18 180.48,67.05 180.23,66.8 178.89,66.8 178.09,67.6 174.68,67.6 170.04,72.25 157.86,72.25 152.34,66.74 127.56,66.74 127.01,66.19 113.36,66.19 108.56,70.99 103.41,70.99 95.59,78.81 95.59,79.48 94.92,80.15 90.01,80.15 89.42,80.74 89.42,80.99 89.52,81.08 v1(89.93,81.08)
PEG_RX_CPU_N2: length 102.4
  TOP w0.102: CPU1.D5 90.27,82.34 90.27,82.05 90.4,81.91 90.67,81.91 v1(90.86,82.09)
  BOTTOM w0.102: SLOT2.A26 180.53,71.3 180.57,71.17 180.5,71.03 180.37,70.89 178.77,70.89 177.99,71.67 173.9,71.67 171.91,73.65 157.1,73.65 151.59,68.14 126.98,68.14 126.43,67.59 113.94,67.59 109.14,72.39 105.56,72.39 101.26,76.69 98.72,76.69 96.53,78.87 96.53,79.38 95.21,80.7 92.02,80.7 91.21,81.51 90.93,81.67 90.86,81.74 v1(90.86,82.09)
PEG_RX_CPU_N3: length 100.3
  TOP w0.102: v1(91.75,82.91) 91.4,82.91 91.3,83.01 CPU1.E4
  BOTTOM w0.102: v1(91.75,82.91) 92.42,82.25 95.06,82.25 98.18,79.12 99.1,79.12 100.1,78.12 101.63,78.12 101.81,78.12 106.14,73.79 109.72,73.79 114.52,68.99 125.85,68.99 126.44,69.58 151.06,69.58 156.55,75.07 175.54,75.07 176.01,75.54 178.13,75.54 178.74,74.93 180.38,74.93 180.55,75.09 180.62,75.24 180.62,75.24 180.76,75.51 180.71,75.65 180.31,75.85 SLOT2.A30
PEG_RX_CPU_N4: length 103.1
  TOP w0.102: CPU1.F5 v1(89.93,83.83)
  BOTTOM w0.102: SLOT2.A36 180.49,81.79 180.67,81.61 180.67,81.06 180.49,80.89 177.66,80.89 173.24,76.47 155.97,76.47 150.48,70.98 125.86,70.98 125.27,70.38 115.39,70.38 110.59,75.18 106.77,75.18 101.84,80.11 100.06,80.11 99.17,81 97.14,81 95.07,83.07 93.46,83.07 92.95,83.58 90.17,83.58 v1(89.93,83.83)
PEG_RX_CPU_N5: length 103.1
  TOP w0.102: CPU1.G4 v1(90.84,84.74)
  BOTTOM w0.102: v1(90.84,84.74) 90.46,84.74 90.38,84.66 90.38,84.4 90.64,84.14 93.52,84.14 93.82,83.84 95.3,83.84 97.43,81.7 99.46,81.7 100.35,80.81 102.13,80.81 105.68,77.27 109.6,77.27 110.26,76.61 111.48,76.61 114.82,73.27 122.01,73.27 122.89,74.14 126.57,74.14 127.68,73.03 149.66,73.03 155.13,78.5 172.05,78.5 178.49,84.94 180.19,84.94 180.31,85.06 180.31,85.53 180.05,85.79 SLOT2.A40
PEG_RX_CPU_N6: length 104.5
  TOP w0.102: CPU1.H5 v1(89.93,85.66)
  BOTTOM w0.102: v1(89.93,85.66) 90.17,85.41 93.37,85.41 93.87,84.91 95.21,84.91 97.72,82.4 99.75,82.4 100.64,81.51 103.63,81.51 105.58,79.56 107.06,79.56 107.94,78.68 110.24,78.68 110.91,78 112.57,78 115.91,74.66 121.43,74.66 122.31,75.54 127.48,75.54 128.59,74.43 148.99,74.43 155.15,80.59 170.11,80.59 178.4,88.89 180.45,88.89 180.64,89.08 180.64,89.61 180.47,89.79 SLOT2.A44
PEG_RX_CPU_N7: length 105.3
  TOP w0.102: CPU1.J4 v1(90.84,86.57)
  BOTTOM w0.102: v1(90.84,86.57) 90.49,86.57 90.38,86.46 90.38,86.23 90.59,86.02 93.88,86.02 94.24,85.65 95.49,85.65 98.04,83.1 100.04,83.1 100.93,82.21 107.1,82.21 109.11,80.2 112.7,80.2 113.1,80.2 114.65,81.75 123.02,81.75 124.01,80.76 128.92,80.76 133.83,75.85 148.43,75.85 154.88,82.3 168.33,82.3 178.93,92.9 180.14,92.9 180.25,93.01 180.31,93.07 180.31,93.47 180,93.79 SLOT2.A48
PEG_RX_CPU_N8: length 107.9
  TOP w0.102: CPU1.K5 v1(89.93,87.48)
  BOTTOM w0.102: SLOT2.A53 179.87,98.79 179.77,98.89 178.82,98.89 178.38,98.46 178.38,95.68 175.2,92.49 175.2,91.5 167.54,83.85 154.45,83.85 147.88,77.27 134.38,77.27 129.5,82.16 124.59,82.16 123.6,83.15 103.77,83.15 103.73,83.11 103.71,83.11 103.51,82.91 101.22,82.91 100.33,83.8 98.78,83.8 95.78,86.79 94.01,86.79 93.5,87.29 90.12,87.29 v1(89.93,87.48)
PEG_RX_CPU_N9: length 108.6
  TOP w0.102: CPU1.L4 v1(90.84,88.4)
  BOTTOM w0.102: v1(90.84,88.4) 90.84,88.15 91.15,87.85 94.08,87.85 94.46,87.47 96.29,87.47 98.73,85.02 102.4,85.02 102.88,84.54 124.18,84.54 125.16,83.57 130.07,83.57 134.96,78.67 147.3,78.67 153.9,85.27 165.95,85.27 175.95,95.27 175.95,98.48 177.67,100.2 177.67,101.5 179.06,102.88 180.09,102.88 180.61,102.36 181.12,102.36 SLOT2.A57
PEG_RX_CPU_N10: length 111.9
  TOP w0.102: CPU1.M5 v1(89.93,89.31)
  BOTTOM w0.102: v1(89.93,89.31) 90.15,89.09 92.01,89.09 92.52,88.58 96.15,88.58 97.7,87.03 101.86,87.03 102.43,86.46 103.07,86.46 103.59,85.94 124.76,85.94 125.74,84.96 130.65,84.96 135.54,80.07 146.72,80.07 153.32,86.66 165.37,86.66 174.52,95.82 174.52,101.43 177.41,104.31 177.41,105.78 178.52,106.9 179.95,106.9 180.62,106.22 180.98,106.22 SLOT2.A61
PEG_RX_CPU_N11: length 112.9
  TOP w0.102: v1(90.84,90.23) CPU1.N4
  BOTTOM w0.102: v1(90.84,90.23) 90.5,89.89 90.5,89.73 90.6,89.62 92.39,89.62 92.93,89.09 96.7,89.09 97.89,87.9 105.07,87.9 105.63,87.34 125.34,87.34 126.32,86.36 131.23,86.36 136.12,81.47 146.14,81.47 152.79,88.11 164.8,88.11 173.11,96.43 173.11,102.12 174.52,103.53 174.52,106.3 179.1,110.88 180.15,110.88 180.24,110.79 SLOT2.A65
PEG_RX_CPU_N12: length 115.6
  TOP w0.102: CPU1.P5 v1(89.93,91.14)
  BOTTOM w0.102: SLOT2.A69 181.29,114.53 180.29,114.53 179.92,114.9 178.68,114.9 175.17,111.39 175.17,108.93 173.1,106.86 173.1,105.13 171.72,103.75 171.72,97.01 164.22,89.51 152.21,89.51 145.63,82.93 136.64,82.93 131.81,87.76 127.71,87.76 126.31,89.16 105.78,89.16 105.65,89.29 100.55,89.29 100.01,89.83 95.57,89.83 94.93,90.47 92.5,90.47 92.08,90.88 90.19,90.88 v1(89.93,91.14)
PEG_RX_CPU_N13: length 118.8
  TOP w0.102: CPU1.R4 v1(90.84,92.06)
  BOTTOM w0.102: SLOT2.A73 181.1,118.34 180.7,118.34 180.17,118.86 179.16,118.86 174.63,114.33 174.63,113.19 173.76,112.32 173.76,109.5 170.94,106.67 169.32,104.88 169.18,104.66 169.18,104.66 169.02,104.41 168.91,104.21 168.9,104.2 168.76,103.87 168.75,103.84 168.6,103.29 168.58,103.14 168.58,100.35 168.02,99.79 168.02,95.29 163.64,90.91 151.63,90.91 145.05,84.33 137.22,84.33 132.19,89.36 130.51,89.36 128.09,91.77 124.26,91.77 123.06,90.58 106.58,90.58 105.88,91.27 99.68,91.27 98.94,90.54 95.77,90.54 95.16,91.15 92.77,91.15 92.34,91.58 90.66,91.58 90.5,91.74 90.5,91.93 90.63,92.06 v1(90.84,92.06)
PEG_RX_CPU_N14: length 121.1
  TOP w0.102: CPU1.T5 v1(89.93,92.97)
  BOTTOM w0.102: v1(89.93,92.97) 90.18,92.71 92.01,92.71 92.44,92.29 98.86,92.29 99.25,92.67 106.52,92.67 107.18,92.01 120.86,92.01 122.02,93.17 130.35,93.17 137.74,85.78 144.53,85.78 151.05,92.3 163.06,92.3 166.62,95.87 166.62,100.38 167.12,100.88 167.12,102.74 167.22,103.56 167.44,104.36 167.45,104.39 167.6,104.73 167.6,104.73 167.84,105.16 167.86,105.19 167.89,105.24 167.9,105.26 167.95,105.34 167.99,105.39 168.18,105.69 168.39,105.98 168.68,106.36 168.89,106.61 168.98,106.71 169.13,106.88 172.36,110.11 172.36,113.27 173.13,114.03 173.13,116.1 175.56,118.54 176.4,118.54 177.99,120.13 177.99,121.98 178.88,122.87 180,122.87 180.47,122.4 181.16,122.4 SLOT2.A77
PEG_RX_CPU_N15: length 121.9
  TOP w0.102: v1(90.81,93.86) 90.84,93.89 CPU1.U4
  BOTTOM w0.102: v1(90.81,93.86) 90.79,93.89 90.6,93.89 90.47,93.76 90.47,93.55 90.75,93.28 93.12,93.28 93.32,93.08 94.98,93.08 96.01,94.11 107.65,94.11 108.35,93.4 119.14,93.4 120.83,95.1 130.43,95.1 136.54,88.99 145.76,88.99 150.49,93.73 162.51,93.73 165.23,96.45 165.23,100.97 165.72,101.46 165.72,102.83 165.85,103.84 166.19,105.09 166.42,105.55 166.43,105.55 166.7,105.99 166.75,106.06 166.82,106.17 166.86,106.23 167.07,106.55 167.08,106.57 167.09,106.58 167.15,106.67 167.67,107.34 168,107.72 168.07,107.79 168.2,107.92 169.84,109.56 169.84,109.56 170.97,110.69 170.97,111.31 170.97,113.85 171.73,114.61 171.73,116.94 173.43,118.64 173.43,119.38 178.49,124.44 178.49,126.37 179.03,126.91 180.15,126.91 180.6,126.46 180.88,126.46 SLOT2.A81
PEG_RX_CPU_P0: length 107.3
  TOP w0.102: CPU1.B8 87.91,80.36 87.91,79.4 88.74,78.57 90.04,78.57 90.13,78.48 91.51,78.48 v1(91.79,78.2)
  BOTTOM w0.102: v1(91.79,78.2) 91.79,78.32 91.89,78.42 92.06,78.42 92.63,77.85 94.26,77.85 102.74,69.38 107.89,69.38 112.69,64.58 127.68,64.58 128.22,65.13 153.01,65.13 158.53,70.64 167.61,70.64 174.93,63.32 177.22,63.32 177.85,62.69 180.1,62.69 180.36,62.43 180.41,62.33 180.36,62.2 SLOT2.A16
PEG_RX_CPU_P1: length 105.1
  TOP w0.102: CPU1.C7 v1(89.01,81.08)
  BOTTOM w0.102: v1(89.01,81.08) 89.2,80.89 89.2,80.65 89.92,79.93 94.83,79.93 95.38,79.39 95.38,78.72 103.32,70.78 108.47,70.78 113.27,65.98 127.1,65.98 127.64,66.52 152.43,66.52 157.95,72.03 169.95,72.03 174.59,67.39 178,67.39 178.8,66.59 180.31,66.59 180.65,66.92 180.73,67.08 180.87,67.13 SLOT2.A21
PEG_RX_CPU_P2: length 102.5
  TOP w0.102: CPU1.D6 v1(89.86,82.04)
  BOTTOM w0.102: v1(89.86,82.04) 90.78,81.5 90.79,81.5 90.79,81.49 91.08,81.33 91.09,81.32 91.14,81.28 91.93,80.48 95.12,80.48 96.32,79.29 96.32,78.78 98.63,76.47 101.17,76.47 105.47,72.17 109.05,72.17 113.85,67.37 126.52,67.37 127.07,67.92 151.68,67.92 157.19,73.43 171.82,73.43 173.81,71.45 177.9,71.45 178.68,70.68 180.46,70.68 180.68,70.9 180.76,71.07 180.9,71.11 SLOT2.A25
PEG_RX_CPU_P3: length 100.4
  TOP w0.102: CPU1.E5 v1(90.84,82.91)
  BOTTOM w0.102: v1(90.84,82.91) 91.69,82.44 91.92,82.44 92.33,82.03 94.97,82.03 98.09,78.91 99.01,78.91 100.01,77.9 101.72,77.9 106.05,73.57 109.63,73.57 114.43,68.77 125.94,68.77 126.53,69.36 151.15,69.36 156.64,74.85 175.63,74.85 176.1,75.32 178.04,75.32 178.65,74.71 180.47,74.71 180.72,74.97 180.77,75.06 180.91,75.11 SLOT2.A29
PEG_RX_CPU_P4: length 103.2
  TOP w0.102: CPU1.F6 v1(89.01,83.83)
  BOTTOM w0.102: v1(89.01,83.83) 89.89,83.37 92.86,83.37 93.37,82.86 94.98,82.86 97.05,80.79 99.08,80.79 99.97,79.9 101.75,79.9 106.68,74.97 110.5,74.97 115.3,70.17 125.36,70.17 125.95,70.76 150.57,70.76 156.06,76.25 173.33,76.25 177.75,80.67 180.58,80.67 180.7,80.79 SLOT2.A35
PEG_RX_CPU_P5: length 103
  TOP w0.102: CPU1.G5 v1(89.93,84.74)
  BOTTOM w0.102: SLOT2.A39 180.35,84.79 180.28,84.72 178.58,84.72 172.14,78.28 155.22,78.28 149.75,72.82 127.59,72.82 126.48,73.93 122.97,73.93 122.1,73.05 114.73,73.05 111.39,76.39 110.17,76.39 109.51,77.05 105.59,77.05 102.04,80.6 100.26,80.6 99.37,81.49 97.34,81.49 95.21,83.62 93.73,83.62 93.43,83.92 90.55,83.92 90.17,84.31 90.17,84.5 v1(89.93,84.74)
PEG_RX_CPU_P6: length 104.6
  TOP w0.102: CPU1.H6 v1(89.01,85.66)
  BOTTOM w0.102: SLOT2.A43 180.66,88.79 180.54,88.67 178.49,88.67 170.2,80.38 155.24,80.38 149.08,74.21 128.5,74.21 127.39,75.32 122.4,75.32 121.52,74.45 115.82,74.45 112.48,77.79 110.82,77.79 110.15,78.46 107.85,78.46 106.97,79.34 105.5,79.34 103.54,81.3 100.55,81.3 99.66,82.18 97.63,82.18 95.12,84.69 93.78,84.69 93.28,85.19 89.87,85.19 v1(89.01,85.66)
PEG_RX_CPU_P7: length 105.3
  TOP w0.102: CPU1.J5 v1(89.93,86.57)
  BOTTOM w0.102: v1(89.93,86.57) 90.17,86.33 90.17,86.14 90.5,85.8 93.79,85.8 94.15,85.44 95.4,85.44 97.95,82.88 99.95,82.88 100.84,81.99 107.01,81.99 109.02,79.98 112.61,79.98 113.01,79.98 113.18,79.98 114.73,81.53 122.93,81.53 123.92,80.54 128.83,80.54 133.74,75.64 148.52,75.64 154.97,82.08 168.42,82.08 179.02,92.68 180.23,92.68 180.34,92.79 SLOT2.A47
PEG_RX_CPU_P8: length 107.9
  TOP w0.102: CPU1.K6 v1(89.01,87.48)
  BOTTOM w0.102: SLOT2.A52 179.78,98.02 179.78,98.58 179.68,98.68 178.9,98.68 178.6,98.37 178.6,95.59 175.41,92.4 175.41,91.41 167.63,83.63 154.54,83.63 147.97,77.06 134.3,77.06 129.41,81.94 124.5,81.94 123.51,82.93 103.86,82.93 103.82,82.89 103.8,82.89 103.6,82.69 101.13,82.69 100.24,83.58 98.69,83.58 95.69,86.58 93.92,86.58 93.41,87.08 89.83,87.08 v1(89.01,87.48)
PEG_RX_CPU_P9: length 108.7
  TOP w0.102: v1(89.93,88.4) CPU1.L5
  BOTTOM w0.102: v1(89.93,88.4) 90.34,87.99 90.7,87.99 91.06,87.63 93.99,87.63 94.37,87.25 96.2,87.25 98.64,84.81 102.31,84.81 102.79,84.33 124.09,84.33 125.07,83.35 129.98,83.35 134.88,78.46 147.39,78.46 153.99,85.05 166.04,85.05 176.16,95.18 176.16,98.39 177.89,100.11 177.89,101.41 179.15,102.67 180,102.67 180.14,102.52 180.14,102.38 SLOT2.A56
PEG_RX_CPU_P10: length 112
  TOP w0.102: v1(89.01,89.31) CPU1.M6
  BOTTOM w0.102: SLOT2.A60 180.08,106.05 180.18,106.36 179.86,106.68 178.61,106.68 177.62,105.69 177.62,104.22 174.74,101.34 174.74,95.73 165.46,86.45 153.41,86.45 146.81,79.85 135.45,79.85 130.56,84.75 125.65,84.75 124.67,85.72 103.5,85.72 102.98,86.25 102.34,86.25 101.77,86.82 97.61,86.82 96.06,88.37 92.43,88.37 91.92,88.88 89.81,88.88 v1(89.01,89.31)
PEG_RX_CPU_P11: length 113
  TOP w0.102: v1(89.93,90.23) CPU1.N5
  BOTTOM w0.102: SLOT2.A64 180.17,110.41 180.17,110.56 180.06,110.67 179.19,110.67 174.74,106.21 174.74,103.44 173.33,102.03 173.33,96.34 164.89,87.9 152.88,87.9 146.23,81.25 136.03,81.25 131.14,86.14 126.23,86.14 125.25,87.12 105.54,87.12 104.98,87.68 97.8,87.68 96.61,88.87 92.84,88.87 92.3,89.41 90.51,89.41 90.29,89.64 90.29,89.87 v1(89.93,90.23)
PEG_RX_CPU_P12: length 115.7
  TOP w0.102: CPU1.P6 v1(89.01,91.14)
  BOTTOM w0.102: v1(89.01,91.14) 89.84,90.66 92,90.66 92.41,90.25 94.84,90.25 95.48,89.61 99.92,89.61 100.46,89.08 105.56,89.08 105.69,88.94 126.22,88.94 127.62,87.54 131.72,87.54 136.55,82.72 145.72,82.72 152.3,89.29 164.31,89.29 171.93,96.92 171.93,103.66 173.32,105.04 173.32,106.77 175.39,108.84 175.39,111.3 178.77,114.68 179.83,114.68 180.03,114.49 180.03,114.27 SLOT2.A68
PEG_RX_CPU_P13: length 118.9
  TOP w0.102: CPU1.R5 v1(89.93,92.06)
  BOTTOM w0.102: v1(89.93,92.06) 90.18,92.06 90.28,91.95 90.28,91.66 90.57,91.37 92.25,91.37 92.68,90.94 95.07,90.94 95.68,90.32 99.03,90.32 99.77,91.06 105.79,91.06 106.49,90.36 123.15,90.36 124.35,91.55 128,91.55 130.42,89.14 132.1,89.14 137.13,84.11 145.14,84.11 151.72,90.69 163.73,90.69 168.24,95.2 168.24,99.7 168.8,100.26 168.8,103.13 168.81,103.25 168.96,103.79 169.1,104.11 169.21,104.3 169.4,104.59 169.4,104.59 169.5,104.74 171.1,106.53 173.98,109.41 173.98,112.23 174.85,113.1 174.85,114.24 179.25,118.65 180.08,118.65 180.39,118.33 180.39,118.19 179.99,117.79 SLOT2.A72
PEG_RX_CPU_P14: length 121.2
  TOP w0.102: CPU1.T6 v1(89.01,92.97)
  BOTTOM w0.102: v1(89.01,92.97) 89.81,92.5 91.92,92.5 92.35,92.07 98.95,92.07 99.34,92.46 106.43,92.46 107.09,91.79 120.95,91.79 122.11,92.95 130.26,92.95 137.65,85.57 144.62,85.57 151.14,92.09 163.15,92.09 166.84,95.78 166.84,100.29 167.34,100.79 167.34,102.73 167.44,103.52 167.56,103.99 167.65,104.31 167.8,104.65 167.8,104.65 168.03,105.05 168.03,105.06 168.07,105.13 168.09,105.15 168.09,105.16 168.13,105.22 168.17,105.28 168.36,105.57 168.56,105.85 168.85,106.23 169.05,106.47 169.13,106.55 169.13,106.56 169.29,106.73 172.58,110.02 172.58,113.18 173.34,113.94 173.34,116.01 175.65,118.33 176.49,118.33 178.21,120.04 178.21,121.89 178.97,122.66 179.91,122.66 180.09,122.47 180.09,122.33 SLOT2.A76
PEG_RX_CPU_P15: length 121.9
  TOP w0.102: CPU1.U5 v1(89.93,93.89)
  BOTTOM w0.102: SLOT2.A80 180.35,126.19 180.35,126.41 180.06,126.7 179.12,126.7 178.7,126.28 178.7,124.35 173.65,119.29 173.65,118.55 171.95,116.85 171.95,114.52 171.18,113.76 171.18,111.22 171.18,110.6 170.05,109.47 169.07,108.49 168.23,107.65 168.06,107.46 167.98,107.37 167.85,107.21 167.32,106.53 167.27,106.46 167.26,106.44 167.25,106.43 167.04,106.12 167.01,106.05 166.93,105.94 166.88,105.87 166.61,105.44 166.39,105.01 166.06,103.79 165.94,102.82 165.94,101.37 165.44,100.88 165.44,96.36 162.6,93.51 150.58,93.51 145.85,88.77 136.45,88.77 130.34,94.88 120.92,94.88 119.23,93.19 108.26,93.19 107.56,93.89 96.1,93.89 95.07,92.86 93.23,92.86 93.03,93.07 90.66,93.07 90.26,93.46 90.26,93.55 v1(89.93,93.89)
PEG_TX_CON_N0: length 10.5
  TOP w0.102: C9304.2 177.94,61.32 178.31,61.32 178.92,60.71 180.16,60.71 181.1,61.65 184.58,61.65 185.22,61.01 185.22,60.48 185.15,60.35 185.02,60.31 SLOT2.B15
PEG_TX_CON_N1: length 10.7
  TOP w0.102: C9302.2 177.92,65.36 178.28,65.36 178.96,64.68 180.02,64.68 181,63.7 184.58,63.7 185.47,64.59 185.47,65.17 185.38,65.34 185.43,65.48 SLOT2.B20
PEG_TX_CON_N2: length 10.6
  TOP w0.102: SLOT2.B24 185.44,69.49 185.4,69.35 185.42,69.3 185.42,68.5 184.61,67.69 181,67.69 180.01,68.68 178.99,68.68 178.38,69.3 177.92,69.3 C9303.2
PEG_TX_CON_N3: length 10.6
  TOP w0.102: C9308.2 177.88,73.32 178.34,73.32 179.02,72.64 180.06,72.64 181.01,71.69 184.59,71.69 185.43,72.53 185.43,73.2 185.36,73.33 185.41,73.47 SLOT2.B28
PEG_TX_CON_N4: length 10.7
  TOP w0.102: C9313.2 177.92,79.33 178.38,79.33 179.02,78.69 179.93,78.69 180.92,77.7 184.63,77.7 185.46,78.53 185.46,79.16 185.37,79.34 185.42,79.47 SLOT2.B34
PEG_TX_CON_N5: length 10.8
  TOP w0.102: SLOT2.B38 185.42,83.47 185.37,83.34 185.46,83.16 185.46,82.49 184.63,81.66 180.98,81.66 179.96,82.68 179.04,82.68 178.33,83.39 177.92,83.39 C9315.2
PEG_TX_CON_N6: length 10.7
  TOP w0.102: SLOT2.B42 185.42,87.47 185.37,87.34 185.46,87.16 185.46,86.58 184.57,85.69 181.02,85.69 180.01,86.69 178.97,86.69 178.33,87.33 177.92,87.33 C9317.2
PEG_TX_CON_N7: length 10.5
  TOP w0.102: SLOT2.B46 185.39,91.46 185.34,91.32 185.41,91.19 185.41,90.59 184.49,89.67 181.01,89.67 180.01,90.68 179.04,90.68 178.32,91.4 178.05,91.4 C9319.2
PEG_TX_CON_N8: length 11.3
  TOP w0.102: SLOT2.B51 184.87,96.33 185.04,96.3 185.17,96.34 185.28,96.57 185.28,96.86 184.44,97.7 181.06,97.7 180.02,96.66 179.13,96.66 178.63,96.15 178.63,95.57 178.4,95.35 177.93,95.35 C9321.2
PEG_TX_CON_N9: length 10.4
  TOP w0.102: SLOT2.B55 185.05,100.29 185.18,100.34 185.25,100.47 185.25,100.96 184.53,101.68 181.13,101.68 180.14,100.69 178,100.69 177.62,100.3 C9323.2
PEG_TX_CON_N10: length 10.4
  TOP w0.102: SLOT2.B59 185.03,104.3 185.16,104.35 185.23,104.48 185.23,104.97 184.53,105.66 181.08,105.66 180.16,104.74 177.81,104.74 C9325.2
PEG_TX_CON_N11: length 10.4
  TOP w0.102: SLOT2.B63 185.01,108.31 185.15,108.35 185.22,108.48 185.22,108.87 184.4,109.68 181.08,109.68 180.06,108.66 179.09,108.66 178.95,108.81 177.81,108.81 C9328.2
PEG_TX_CON_N12: length 10.7
  TOP w0.102: C9331.2 177.69,112.86 178.61,112.86 178.8,112.66 180,112.66 181.01,113.68 184.39,113.68 185.29,112.78 185.32,112.63 185.19,112.39 185.14,112.34 185,112.31 SLOT2.B67
PEG_TX_CON_N13: length 10.8
  TOP w0.102: C9334.2 177.76,116.13 178.36,116.13 178.92,116.69 180.09,116.69 181.1,117.7 184.38,117.7 185.22,116.86 185.22,116.44 185.18,116.35 185.03,116.3 SLOT2.B71
PEG_TX_CON_N14: length 10.3
  TOP w0.102: SLOT2.B75 184.98,120.33 185.02,120.19 184.97,120.09 184.81,119.93 181.12,119.93 180.15,120.89 178.94,120.89 178.44,120.38 178.44,119.62 178.33,119.52 177.98,119.52 C9336.2
PEG_TX_CON_N15: length 9.3
  TOP w0.102: SLOT2.B79 184.99,124.32 185.04,124.18 184.98,124.05 184.81,123.89 180.99,123.89 180.02,122.92 179.11,122.92 178.5,123.53 178.16,123.53 C9338.2
PEG_TX_CON_P0: length 10.7
  TOP w0.102: C9301.2 177.93,61.53 178.4,61.53 179.01,60.92 180.07,60.92 181.01,61.86 184.67,61.86 185.43,61.1 185.43,60.43 185.34,60.26 185.39,60.12 SLOT2.B14
PEG_TX_CON_P1: length 10.6
  TOP w0.102: SLOT2.B19 185.06,65.29 185.19,65.25 185.26,65.12 185.26,64.68 184.49,63.92 181.09,63.92 180.11,64.9 179.05,64.9 178.37,65.58 177.95,65.58 C9305.2
PEG_TX_CON_P2: length 10.6
  TOP w0.102: SLOT2.B23 185.07,69.3 185.2,69.25 185.2,69.25 185.2,68.59 184.52,67.91 181.09,67.91 180.1,68.9 179.08,68.9 178.47,69.51 177.95,69.51 C9306.2
PEG_TX_CON_P3: length 10.6
  TOP w0.102: SLOT2.B27 185.04,73.28 185.17,73.24 185.17,73.24 185.21,73.15 185.21,72.62 184.5,71.91 181.1,71.91 180.15,72.86 179.11,72.86 178.43,73.54 177.98,73.54 C9307.2
PEG_TX_CON_P4: length 10.6
  TOP w0.102: SLOT2.B33 185.05,79.29 185.18,79.24 185.25,79.11 185.25,78.62 184.54,77.91 181.01,77.91 180.02,78.91 179.11,78.91 178.47,79.55 177.95,79.55 C9309.2
PEG_TX_CON_P5: length 10.7
  TOP w0.102: SLOT2.B37 185.05,83.29 185.18,83.24 185.25,83.11 185.25,82.58 184.54,81.88 181.06,81.88 180.05,82.89 179.13,82.89 178.42,83.61 177.95,83.61 C9314.2
PEG_TX_CON_P6: length 10.6
  TOP w0.102: C9316.2 177.95,87.55 178.42,87.55 179.06,86.91 180.1,86.91 181.1,85.9 184.48,85.9 185.25,86.67 185.25,87.11 185.18,87.24 185.05,87.29 SLOT2.B41
PEG_TX_CON_P7: length 10.4
  TOP w0.102: C9318.2 178.07,91.62 178.41,91.62 179.13,90.89 180.1,90.89 181.1,89.89 184.4,89.89 185.19,90.68 185.19,91.14 185.15,91.23 185.01,91.27 SLOT2.B45
PEG_TX_CON_P8: length 11.3
  TOP w0.102: SLOT2.B50 185.41,96.11 185.36,96.25 185.42,96.36 185.5,96.52 185.5,96.95 184.53,97.92 180.97,97.92 179.93,96.88 179.04,96.88 178.41,96.24 178.41,95.66 178.31,95.56 177.93,95.56 C9320.2
PEG_TX_CON_P9: length 10.4
  TOP w0.102: C9322.2 177.88,100.9 180.05,100.9 181.04,101.89 184.62,101.89 185.46,101.05 185.46,100.42 185.37,100.24 185.42,100.11 SLOT2.B54
PEG_TX_CON_P10: length 10.5
  TOP w0.102: SLOT2.B58 185.4,104.12 185.35,104.25 185.44,104.43 185.44,105.06 184.62,105.88 180.99,105.88 180.07,104.96 177.81,104.96 C9324.2
PEG_TX_CON_P11: length 10.6
  TOP w0.102: SLOT2.B62 185.39,108.12 185.34,108.26 185.43,108.43 185.43,108.95 184.49,109.89 180.99,109.89 179.97,108.88 179.18,108.88 179.04,109.02 177.81,109.02 C9326.2
PEG_TX_CON_P12: length 10.7
  TOP w0.102: C9329.2 177.69,113.07 178.7,113.07 178.89,112.88 179.91,112.88 180.92,113.89 184.48,113.89 185.5,112.88 185.54,112.6 185.36,112.25 185.41,112.11 SLOT2.B66
PEG_TX_CON_P13: length 10.8
  TOP w0.102: SLOT2.B70 185.42,116.11 185.37,116.26 185.43,116.39 185.43,116.95 184.47,117.92 181.01,117.92 180,116.9 178.83,116.9 178.27,116.34 177.6,116.34 C9332.2
PEG_TX_CON_P14: length 10.3
  TOP w0.102: C9335.2 177.91,119.3 178.42,119.3 178.65,119.53 178.65,120.29 179.03,120.68 180.06,120.68 181.03,119.71 184.9,119.71 185.15,119.96 185.23,120.12 185.34,120.14 186.04,119.79 SLOT2.B74
PEG_TX_CON_P15: length 9.3
  TOP w0.102: C9337.2 178.24,123.32 178.41,123.32 179.02,122.71 180.11,122.71 181.08,123.67 184.9,123.67 185.15,123.92 185.23,124.08 185.37,124.13 SLOT2.B78
PEG_TX_CPU_N0: length 102.3
  TOP w0.102: v3(175.87,61) 175.87,61.16 175.97,61.26 176.44,61.26 C9304.1 ; v1(88.99,79.28) 89.43,79.71 CPU1.A6
  BOTTOM w0.102: v3(175.87,61) 175.57,61.3 175.22,61.3 174.93,61.59 ; 174.93,61.59 v2(174.66,61.33) ; 174.93,61.59 174.27,62.25 173.67,62.85 173.67,63.54 167.27,69.94 158.82,69.94 153.3,64.43 128.51,64.43 127.97,63.88 112.4,63.88 107.6,68.68 103.37,68.68 102.45,68.68 93.89,77.24 90.96,77.24 89.34,78.86 89.34,79.19 89.25,79.28 v1(88.99,79.28)
PEG_TX_CPU_N1: length 98.5
  TOP w0.102: v3(175.87,65.02) 175.87,65.24 175.97,65.34 176.43,65.34 C9302.1 ; v1(93.26,78.91) 92.53,79.64 91.98,79.64 91.44,80.18 91.16,80.24 CPU1.B5
  BOTTOM w0.102: v3(175.87,65.02) 175.51,65.39 174.67,65.39 174,66.05 ; v2(173.74,65.79) 174,66.05 ; 174,66.05 168.72,71.34 158.24,71.34 152.72,65.82 127.93,65.82 127.39,65.28 112.98,65.28 108.18,70.08 103.03,70.08 94.47,78.64 93.8,78.64 93.53,78.91 v1(93.26,78.91)
PEG_TX_CPU_N2: length 97.4
  TOP w0.102: CPU1.C4 92.51,80.93 92.83,80.61 94.62,80.61 98.29,76.95 99.73,76.95 100.29,76.39 100.29,76.16 v1(100.01,75.88) ; v3(175.81,68.93) 176.15,69.27 176.44,69.27 C9303.1
  BOTTOM w0.102: v3(175.81,68.93) 175.48,69.27 174.83,69.27 ; 174.83,69.27 v2(174.83,68.88) ; 174.83,69.27 174.14,69.27 170.67,72.73 157.66,72.73 152.14,67.22 127.36,67.22 126.81,66.67 113.56,66.67 108.76,71.48 103.61,71.48 100.01,75.07 v1(100.01,75.88)
PEG_TX_CPU_N3: length 95
  TOP w0.102: C9308.1 176.4,73.37 175.97,73.37 175.87,73.27 v3(175.87,73.03) ; CPU1.D3 93.17,81.97 93.31,81.97 93.56,81.72 95.46,81.72 97.99,79.19 v1(97.99,78.26)
  BOTTOM w0.102: v2(174.88,72.95) 174.88,73.34 ; 174.88,73.34 172.98,73.34 172.19,74.13 156.9,74.13 151.39,68.62 126.78,68.62 126.23,68.07 114.14,68.07 109.34,72.87 105.76,72.87 101.46,77.17 98.57,77.17 98.13,77.61 98.13,78.12 v1(97.99,78.26) ; 174.88,73.34 175.56,73.34 v3(175.87,73.03)
PEG_TX_CPU_N4: length 97.1
  TOP w0.102: CPU1.E2 94.06,82.93 96.15,82.93 98.69,80.39 99.36,80.39 99.9,79.85 v3(99.9,79.38) ; C9313.1 176.39,79.35 176.28,79.35 176.17,79.25 176.17,77.47 v3(176.56,77.09)
  BOTTOM w0.102: v2(176.17,77.97) v3(176.56,77.09) 176.36,76.9 176.36,76.25 176.14,76.02 175.81,76.02 175.34,75.55 156.35,75.55 150.86,70.06 126.24,70.06 125.65,69.47 114.72,69.47 109.92,74.27 106.39,74.27 102.06,78.6 100.37,78.6 100.14,78.83 100.14,79.14 v3(99.9,79.38)
PEG_TX_CPU_N5: length 99
  TOP w0.102: v3(176.9,81.27) 176.56,81.61 176.56,82.07 176.02,82.6 176.02,83.32 176.12,83.42 176.38,83.42 C9315.1 ; CPU1.F3 92.47,84.28 92.57,84.19 92.57,83.95 92.82,83.7 94.37,83.7 94.55,83.52 96.58,83.52 97.49,82.6 98.82,81.28 101.55,81.28 105.49,77.34 107.49,77.34 107.59,77.24 107.59,76.52 v1(107.59,76.52)
  BOTTOM w0.102: v1(107.59,76.52) 107.91,76.19 107.91,75.96 108.21,75.67 110.84,75.67 114.51,72 115.82,72 ; v2(115.82,71.63) 115.82,72 ; 115.82,72 121.17,72 121.48,72.31 124.13,72.31 124.24,72.43 126.05,72.43 127.01,71.46 150.28,71.46 155.77,76.95 173.01,76.95 176.58,80.52 176.58,80.95 v3(176.9,81.27)
PEG_TX_CPU_N6: length 98.9
  TOP w0.102: v3(176.97,85.07) 176.57,85.48 176.57,85.97 176.15,86.39 176.15,87.14 176.3,87.3 176.44,87.3 C9317.1 ; v1(105.39,78.59) 105.39,79.6 103.01,81.98 99.12,81.98 96.4,84.7 94.48,84.7 94.4,84.61 93.69,84.61 93.46,84.85 93.46,85.12 93.39,85.2 CPU1.G2
  BOTTOM w0.102: v1(105.39,78.59) 105.71,78.27 105.71,78 105.97,77.75 109.87,77.75 110.53,77.09 111.68,77.09 115.02,73.75 121.81,73.75 122.69,74.63 127.03,74.63 128.13,73.52 149.37,73.52 154.86,79.01 171.16,79.01 173.55,81.39 ; v3(176.97,85.07) 176.65,84.75 176.65,84.5 173.55,81.39 ; v2(173.81,81.13) 173.55,81.39
PEG_TX_CPU_N7: length 100.9
  TOP w0.102: v3(177.11,88.76) 176.75,89.13 176.75,89.57 175.9,90.42 175.9,91.31 176.02,91.44 176.49,91.44 C9319.1 ; v3(106.88,80.23) 106.53,80.58 105.68,80.58 103.56,82.69 99.4,82.69 96.81,85.28 95.63,85.28 95.48,85.44 94.32,85.44 94.23,85.53 92.82,85.53 92.57,85.78 92.57,86.02 92.47,86.11 CPU1.H3
  BOTTOM w0.102: v2(114.48,77.37) 114.76,77.65 ; 114.76,77.65 117.26,75.15 121.23,75.15 122.11,76.02 127.79,76.02 128.9,74.91 148.79,74.91 155.04,81.17 169.86,81.17 176.78,88.09 176.78,88.43 v3(177.11,88.76) ; 114.76,77.65 113.89,78.51 111.09,78.51 110.42,79.18 108.83,79.18 107.78,80.23 v3(106.88,80.23)
PEG_TX_CPU_N8: length 102.9
  TOP w0.102: v1(108.67,81.62) 108.99,81.94 108.99,82.09 107.69,83.39 99.69,83.39 97.13,85.95 95.76,85.95 95.15,86.56 94.49,86.56 94.39,86.46 93.84,86.46 93.61,86.68 93.61,86.93 93.51,87.03 CPU1.J2 ; v3(177.69,92.84) 177.69,93.73 177.27,94.15 176.62,94.15 176.1,94.67 176.1,95.21 176.2,95.31 176.43,95.31 C9321.1
  BOTTOM w0.102: 113.74,82.23 123.22,82.23 124.21,81.24 129.12,81.24 134.01,76.36 148.26,76.36 154.83,82.93 167.95,82.93 177.33,92.32 177.33,92.49 v3(177.69,92.84) ; 113.74,82.23 v2(113.74,81.86) ; 113.74,82.23 112.81,82.23 111.27,80.68 109.37,80.68 108.99,81.06 108.99,81.29 v1(108.67,81.62)
PEG_TX_CPU_N9: length 104.7
  TOP w0.102: C9323.1 176.71,100.3 176.29,100.72 176.15,100.72 176.05,100.62 176.05,99.72 177.37,98.4 177.37,97.33 v3(177.73,96.97) ; v3(100.73,84.18) 100.73,84.49 100.43,84.79 99.31,84.79 97.35,86.74 96.43,86.74 95.96,87.21 94.48,87.21 94.34,87.36 92.82,87.36 92.6,87.59 92.6,87.82 92.47,87.94 CPU1.K3
  BOTTOM w0.102: v3(177.73,96.97) 177.42,96.66 177.42,95.45 173.31,91.34 ; v2(173.57,91.07) 173.31,91.34 ; 173.31,91.34 166.33,84.35 154.28,84.35 147.68,77.76 134.58,77.76 129.69,82.65 124.78,82.65 123.8,83.63 103.57,83.63 103.25,83.31 101.36,83.31 101.03,83.65 101.03,83.88 v3(100.73,84.18)
PEG_TX_CPU_N10: length 106.6
  TOP w0.102: v1(99.92,86.21) 100.2,86.49 100.2,87.26 99.86,87.6 96.65,87.6 95.86,88.4 94.52,88.4 94.39,88.27 93.68,88.27 93.45,88.5 93.45,88.76 93.36,88.86 CPU1.L2 ; v3(177.58,102.35) 177.27,102.66 177.27,102.82 175.82,104.27 175.82,104.64 175.92,104.74 176.28,104.74 C9325.1
  BOTTOM w0.102: v3(177.58,102.35) 177.16,101.93 177.16,101.45 175.45,99.73 175.45,99.29 ; 175.45,99.29 175.45,95.45 165.75,85.75 153.7,85.75 147.1,79.15 135.16,79.15 130.27,84.05 125.36,84.05 124.38,85.03 103.12,85.03 102.74,85.41 100.43,85.41 100.2,85.64 100.2,85.93 v1(99.92,86.21) ; 175.45,99.29 v2(175.82,99.29)
PEG_TX_CPU_N11: length 108
  TOP w0.102: C9328.1 176.32,108.76 176.09,108.76 175.98,108.65 175.98,106.59 v3(176.4,106.17) ; CPU1.M3 92.4,89.77 92.49,89.68 92.49,89.41 92.72,89.19 94.32,89.19 94.56,88.94 96.41,88.94 97.03,88.32 102.92,88.32 103.58,87.65 103.58,87.5 v1(103.26,87.18)
  BOTTOM w0.102: v3(176.4,106.17) 175.98,105.75 175.98,105.18 ; v2(176.38,105.18) 175.98,105.18 ; 175.98,105.18 175.98,103.57 174.03,101.61 174.03,96.05 165.13,87.15 153.12,87.15 146.52,80.55 135.74,80.55 130.85,85.45 125.94,85.45 124.96,86.42 103.84,86.42 103.61,86.65 103.61,86.83 v1(103.26,87.18)
PEG_TX_CPU_N12: length 110.5
  TOP w0.102: v1(98.02,89.13) 98.3,89.41 98.3,89.72 97.92,90.1 93.73,90.1 93.48,90.35 93.48,90.59 93.39,90.68 CPU1.N2 ; C9331.1 176.09,112.9 175.81,112.9 175.64,112.73 175.64,112.24 176.19,111.7 176.56,111.7 176.86,111.4 176.86,111.16 v3(177.21,110.81)
  BOTTOM w0.102: v3(177.21,110.81) 177.03,110.63 177.03,109.49 174.04,106.5 174.04,103.73 172.63,102.32 172.63,96.63 164.6,88.59 152.59,88.59 146.01,82.02 136.26,82.02 131.43,86.84 127.33,86.84 126.49,87.68 ; 126.49,87.68 125.93,88.25 105.4,88.25 105.27,88.38 98.53,88.38 98.3,88.61 98.3,88.84 v1(98.02,89.13) ; 126.49,87.68 v2(126.23,87.41)
PEG_TX_CPU_N13: length 111.8
  TOP w0.102: v1(176.74,114.32) 176.42,114.64 176.42,114.82 175.74,115.49 175.74,115.88 175.87,116 176.19,116 C9334.1 ; CPU1.P3 92.8,91.02 94.34,91.02 94.55,90.81 100.49,90.81 100.59,90.7 100.59,90.56 v1(100.28,90.25)
  BOTTOM w0.102: v1(176.74,114.32) 176.38,113.96 176.38,113.46 174.68,111.76 174.68,109.12 171.58,106.02 171.52,105.95 170.06,104.32 169.97,104.2 169.93,104.13 169.82,103.96 169.81,103.94 169.6,103.5 169.5,103.11 169.49,103.08 169.49,99.97 168.94,99.41 168.94,94.91 164.02,89.99 152.01,89.99 145.43,83.41 136.84,83.41 131.87,88.38 130.18,88.38 128.71,89.85 126.85,89.85 ; 126.85,89.85 124.22,89.85 124.01,89.64 106.04,89.64 105.91,89.78 101.84,89.78 101.59,89.52 100.79,89.52 100.57,89.75 100.57,89.97 v1(100.28,90.25) ; 126.85,89.85 v2(126.85,89.46)
PEG_TX_CPU_N14: length 114
  TOP w0.102: CPU1.R1 93.79,92.51 93.7,92.42 93.7,92.27 93.82,92.15 94.49,92.15 94.76,92.42 95.91,92.42 96.15,92.18 96.15,91.94 96.45,91.64 v3(96.45,91.56) ; C9336.1 176.38,119.55 175.82,119.55 175.56,119.3 175.56,118.77 176.16,118.17 176.16,117.93 176.06,117.83 175.73,117.83 175.63,117.73 v3(175.63,117.42)
  BOTTOM w0.102: 174.55,115.27 173.93,114.65 173.93,113.69 173.06,112.82 173.06,109.79 169.53,106.26 169.17,105.82 169.16,105.81 168.97,105.57 168.97,105.56 168.92,105.5 168.8,105.34 168.77,105.31 168.76,105.29 168.48,104.86 168.43,104.78 168.25,104.47 168.22,104.41 168.09,104.1 168.09,104.07 167.91,103.43 167.86,102.99 167.86,100.62 167.32,100.09 167.32,95.58 163.35,91.6 151.34,91.6 144.76,85.03 137.51,85.03 130.06,92.47 123.25,92.47 122.09,91.3 106.87,91.3 106.2,91.97 99.49,91.97 99.07,91.55 97.9,91.55 97.36,91.01 96.31,91.01 96.19,91.13 96.19,91.3 v3(96.45,91.56) ; 174.55,115.27 v2(174.3,115.55) ; 174.55,115.27 176,116.72 176,117.06 v3(175.63,117.42)
PEG_TX_CPU_N15: length 116.1
  TOP w0.102: v3(176.09,120.85) 176.4,121.16 176.4,121.54 176.06,121.88 176.06,122.92 176.18,123.3 176.38,123.5 176.65,123.5 C9338.1 ; v1(97.15,92.77) 97.38,93 97.38,93.14 97.26,93.26 95.36,93.26 94.95,92.84 94.77,92.84 92.73,92.84 92.52,93.05 92.52,93.27 92.36,93.43 CPU1.T3
  BOTTOM w0.102: v2(174.42,119.02) 174.69,118.76 ; 174.69,118.76 172.43,116.5 172.43,114.32 171.67,113.56 171.67,110.4 168.58,107.32 168.48,107.2 168.43,107.15 168.42,107.14 168.37,107.08 168.36,107.07 168.3,106.99 168.3,106.99 168.15,106.82 168.14,106.8 167.71,106.24 167.66,106.18 167.45,105.86 167.41,105.8 167.38,105.75 167.3,105.62 167.25,105.54 166.97,105.09 166.84,104.84 166.54,103.7 166.42,102.79 166.42,101.17 165.93,100.67 165.93,96.16 162.77,93 150.76,93 144.24,86.48 138.06,86.48 130.66,93.88 121.18,93.88 120.01,92.7 108.06,92.7 107.36,93.41 97.8,93.41 97.16,92.77 v1(97.15,92.77) ; 174.69,118.76 176.37,120.43 176.37,120.58 v3(176.09,120.85)
PEG_TX_CPU_P0: length 102.3
  TOP w0.102: CPU1.A5 90.37,79.71 v1(89.91,79.24) ; C9301.1 176.35,61.48 176.01,61.48 175.83,61.66 v3(175.83,61.91)
  BOTTOM w0.102: 174.42,62.4 173.88,62.94 173.88,63.63 167.36,70.15 158.73,70.15 153.21,64.64 128.42,64.64 127.88,64.1 112.49,64.1 107.69,68.9 103.28,68.9 103.28,68.9 102.54,68.9 93.98,77.46 91.05,77.46 89.56,78.95 89.56,79.14 89.66,79.24 v1(89.91,79.24) ; 174.42,62.4 v2(174.68,62.67) ; 174.42,62.4 175.31,61.51 175.73,61.51 175.83,61.61 v3(175.83,61.91)
PEG_TX_CPU_P1: length 98.5
  TOP w0.102: C9305.1 176.36,65.56 175.92,65.56 175.81,65.66 v3(175.81,65.95) ; CPU1.B4 91.55,80.38 92.07,79.86 92.62,79.86 93.06,79.41 93.2,79.41 93.46,79.67 93.6,79.67 v1(93.81,79.46)
  BOTTOM w0.102: 171.55,68.81 v2(171.82,69.08) ; 171.55,68.81 174.76,65.6 175.71,65.6 175.81,65.7 v3(175.81,65.95) ; 171.55,68.81 168.81,71.55 158.15,71.55 152.63,66.04 127.85,66.04 127.3,65.49 113.07,65.49 108.27,70.29 103.12,70.29 94.56,78.85 93.89,78.85 93.62,79.13 93.62,79.27 v1(93.81,79.46)
PEG_TX_CPU_P2: length 97.3
  TOP w0.102: C9306.1 176.35,69.48 175.97,69.48 175.87,69.58 v3(175.87,69.85) ; CPU1.C3 92.92,80.83 94.71,80.83 98.37,77.17 99.82,77.17 100.51,76.48 100.51,76.31 v1(100.87,75.95)
  BOTTOM w0.102: 172.86,70.85 174.23,69.48 175.5,69.48 v3(175.87,69.85) ; 172.86,70.85 170.76,72.95 157.57,72.95 152.06,67.44 127.27,67.44 126.72,66.89 113.65,66.89 108.85,71.69 103.7,71.69 100.23,75.16 100.23,75.44 100.33,75.54 100.77,75.54 100.87,75.64 v1(100.87,75.95) ; 172.86,70.85 v2(173.15,71.15)
PEG_TX_CPU_P3: length 95
  TOP w0.102: C9307.1 176.39,73.58 175.93,73.58 175.83,73.69 v3(175.83,73.94) ; v1(98.77,78.26) 98.77,78.54 98.67,78.64 98.31,78.64 98.21,78.74 98.21,79.28 95.55,81.93 93.65,81.93 CPU1.D2
  BOTTOM w0.102: 173.53,73.55 175.73,73.55 175.83,73.65 v3(175.83,73.94) ; 173.53,73.55 v2(173.53,73.94) ; 173.53,73.55 173.07,73.55 172.28,74.35 156.81,74.35 151.3,68.83 126.69,68.83 126.14,68.29 114.23,68.29 109.43,73.09 105.85,73.09 101.55,77.38 98.66,77.38 98.35,77.7 98.35,78.05 98.57,78.26 v1(98.77,78.26)
PEG_TX_CPU_P4: length 96.6
  TOP w0.102: v3(175.64,77.09) 175.96,77.41 175.96,79.34 176.19,79.57 176.4,79.57 C9309.1 ; v3(100.72,79.38) 100.72,79.73 100.62,79.83 100.23,79.83 99.45,80.61 98.78,80.61 96.24,83.15 94.26,83.15 CPU1.E1
  BOTTOM w0.102: v3(175.64,77.09) 175.64,76.83 175.74,76.73 176.05,76.73 176.15,76.63 176.15,76.34 176.05,76.24 175.72,76.24 175.25,75.77 174.22,75.77 ; 174.22,75.77 v2(174.22,76.15) ; 174.22,75.77 156.26,75.77 150.77,70.28 126.15,70.28 125.56,69.68 114.81,69.68 110.01,74.49 106.48,74.49 102.15,78.82 100.46,78.82 100.36,78.92 100.36,79.28 100.46,79.38 v3(100.72,79.38)
PEG_TX_CPU_P5: length 99.2
  TOP w0.102: C9314.1 176.41,83.64 176.03,83.64 175.81,83.41 175.81,82.51 176.34,81.98 176.34,81.64 v3(175.98,81.28) ; v1(108.45,76.52) 108.45,76.71 108.28,76.89 107.91,76.89 107.81,76.99 107.81,77.33 107.58,77.56 105.58,77.56 101.64,81.5 98.9,81.5 98.58,81.82 96.67,83.73 94.64,83.73 94.46,83.92 92.91,83.92 92.78,84.04 92.78,84.19 92.88,84.28 CPU1.F2
  BOTTOM w0.102: 175.11,79.35 176.36,80.61 176.36,80.9 v3(175.98,81.28) ; 175.11,79.35 172.92,77.17 155.68,77.17 150.19,71.68 127.1,71.68 126.14,72.64 124.15,72.64 124.04,72.53 121.39,72.53 121.08,72.21 114.6,72.21 110.93,75.88 108.29,75.88 108.13,76.05 108.13,76.19 v1(108.45,76.52) ; 175.11,79.35 v2(174.82,79.64)
PEG_TX_CPU_P6: length 99
  TOP w0.102: v1(106.25,78.59) 106.25,78.78 106.01,79.03 105.71,79.03 105.61,79.13 105.61,79.69 103.1,82.2 99.21,82.2 96.49,84.91 94.39,84.91 94.31,84.83 93.78,84.83 93.68,84.94 93.68,85.09 93.78,85.2 CPU1.G1 ; C9316.1 176.35,87.51 176.21,87.51 175.93,87.23 175.93,86.3 176.35,85.88 176.35,85.42 v3(176.06,85.13)
  BOTTOM w0.102: 162.46,79.22 171.07,79.22 176.44,84.59 176.44,84.76 v3(176.06,85.13) ; 162.46,79.22 v2(162.46,79.63) ; 162.46,79.22 154.77,79.22 149.28,73.73 128.22,73.73 127.12,74.84 122.6,74.84 121.72,73.96 115.11,73.96 111.77,77.3 110.62,77.3 109.96,77.97 106.06,77.97 105.93,78.09 105.93,78.27 v1(106.25,78.59)
PEG_TX_CPU_P7: length 101.1
  TOP w0.102: v3(106.88,81.15) 106.53,80.8 105.77,80.8 103.65,82.91 99.49,82.91 96.9,85.5 95.72,85.5 95.56,85.65 94.41,85.65 94.32,85.74 92.91,85.74 92.78,85.87 92.78,86.02 92.88,86.11 CPU1.H2 ; C9318.1 176.55,91.65 175.93,91.65 175.68,91.4 175.68,90.33 176.53,89.48 176.53,89.19 v3(176.21,88.87)
  BOTTOM w0.102: v3(106.88,81.15) 107.17,81.15 107.33,80.98 107.33,80.55 107.43,80.45 107.87,80.45 108.92,79.4 110.51,79.4 111.18,78.73 113.98,78.73 117.35,75.36 121.14,75.36 122.02,76.24 124.46,76.24 ; v2(124.46,76.61) 124.46,76.24 ; 124.46,76.24 127.88,76.24 128.99,75.13 148.7,75.13 154.95,81.38 169.77,81.38 176.57,88.18 176.57,88.5 v3(176.21,88.87)
PEG_TX_CPU_P8: length 102.8
  TOP w0.102: CPU1.J1 93.93,87.03 93.83,86.93 93.83,86.77 93.93,86.67 94.3,86.67 94.41,86.78 95.24,86.78 95.85,86.17 97.22,86.17 99.78,83.61 107.6,83.61 107.78,83.61 109.21,82.18 109.21,81.94 v1(109.53,81.62) ; C9320.1 176.37,95.53 176.11,95.53 175.88,95.3 175.88,94.58 176.53,93.93 177.18,93.93 177.47,93.64 177.47,93.4 177.36,93.29 177,93.29 176.77,93.06 v3(176.77,92.85)
  BOTTOM w0.102: v3(176.77,92.85) 177.12,92.5 177.12,92.41 167.86,83.15 154.74,83.15 148.17,76.58 134.09,76.58 129.21,81.46 124.3,81.46 123.31,82.45 112.73,82.45 111.62,81.34 ; v2(111.37,81.63) 111.62,81.34 ; 111.62,81.34 111.18,80.9 109.46,80.9 109.21,81.15 109.21,81.29 v1(109.53,81.62)
PEG_TX_CPU_P9: length 104.6
  TOP w0.102: v3(101.54,84.18) 101.14,84.59 100.93,84.59 100.52,85 99.4,85 97.44,86.96 96.52,86.96 96.05,87.43 94.57,87.43 94.43,87.57 92.91,87.57 92.81,87.67 92.81,87.85 92.9,87.94 CPU1.K2 ; C9322.1 176.49,100.94 176.06,100.94 175.83,100.71 175.83,99.63 177.15,98.31 177.15,97.31 v3(176.8,96.95)
  BOTTOM w0.102: 177.2,95.94 177.2,96.55 v3(176.8,96.95) ; 177.2,95.94 177.2,95.54 166.24,84.57 154.19,84.57 147.59,77.97 134.67,77.97 129.78,82.87 124.87,82.87 123.89,83.85 103.48,83.85 103.16,83.53 101.45,83.53 101.24,83.74 101.24,83.88 v3(101.54,84.18) ; 177.2,95.94 v2(176.83,95.94)
PEG_TX_CPU_P10: length 106.5
  TOP w0.102: v3(176.67,102.33) 176.91,102.33 177.05,102.48 177.05,102.73 175.6,104.18 175.6,104.72 175.83,104.95 176.26,104.95 C9324.1 ; CPU1.L1 93.76,88.86 93.67,88.76 93.67,88.59 93.77,88.49 94.3,88.49 94.43,88.61 95.95,88.61 96.74,87.82 99.95,87.82 100.42,87.35 100.42,86.49 v1(100.7,86.21)
  BOTTOM w0.102: v1(100.7,86.21) 100.42,85.93 100.42,85.72 100.52,85.62 102.82,85.62 103.21,85.24 124.47,85.24 125.45,84.26 130.36,84.26 135.25,79.37 147.01,79.37 153.61,85.97 165.66,85.97 175.23,95.54 175.23,99.82 175.88,100.47 ; 175.88,100.47 176.95,101.54 176.95,102.05 v3(176.67,102.33) ; 175.88,100.47 v2(175.62,100.74)
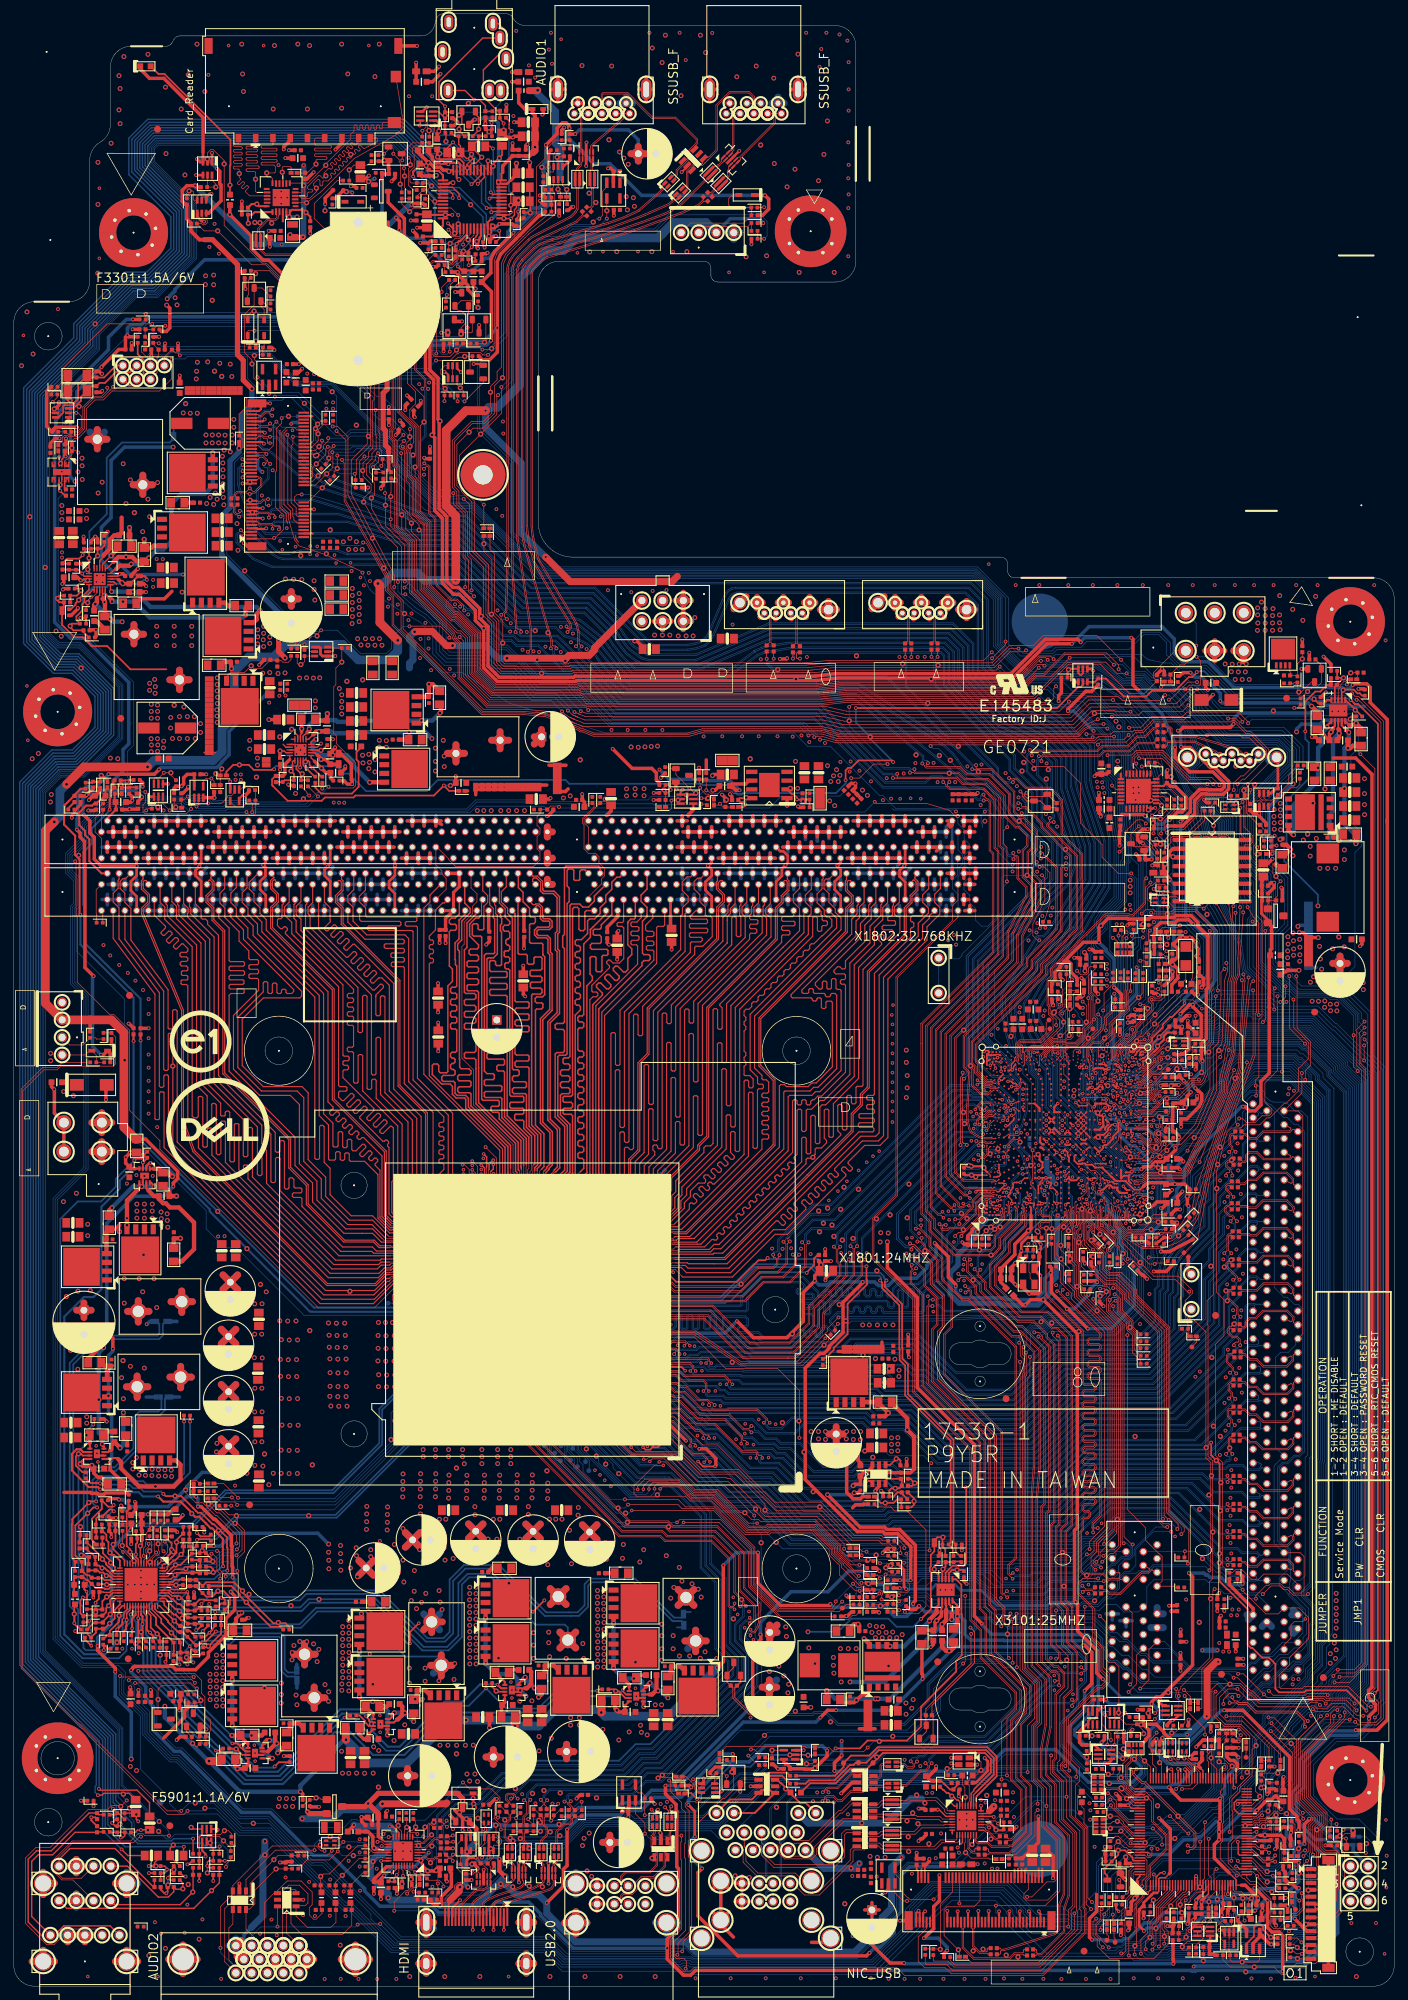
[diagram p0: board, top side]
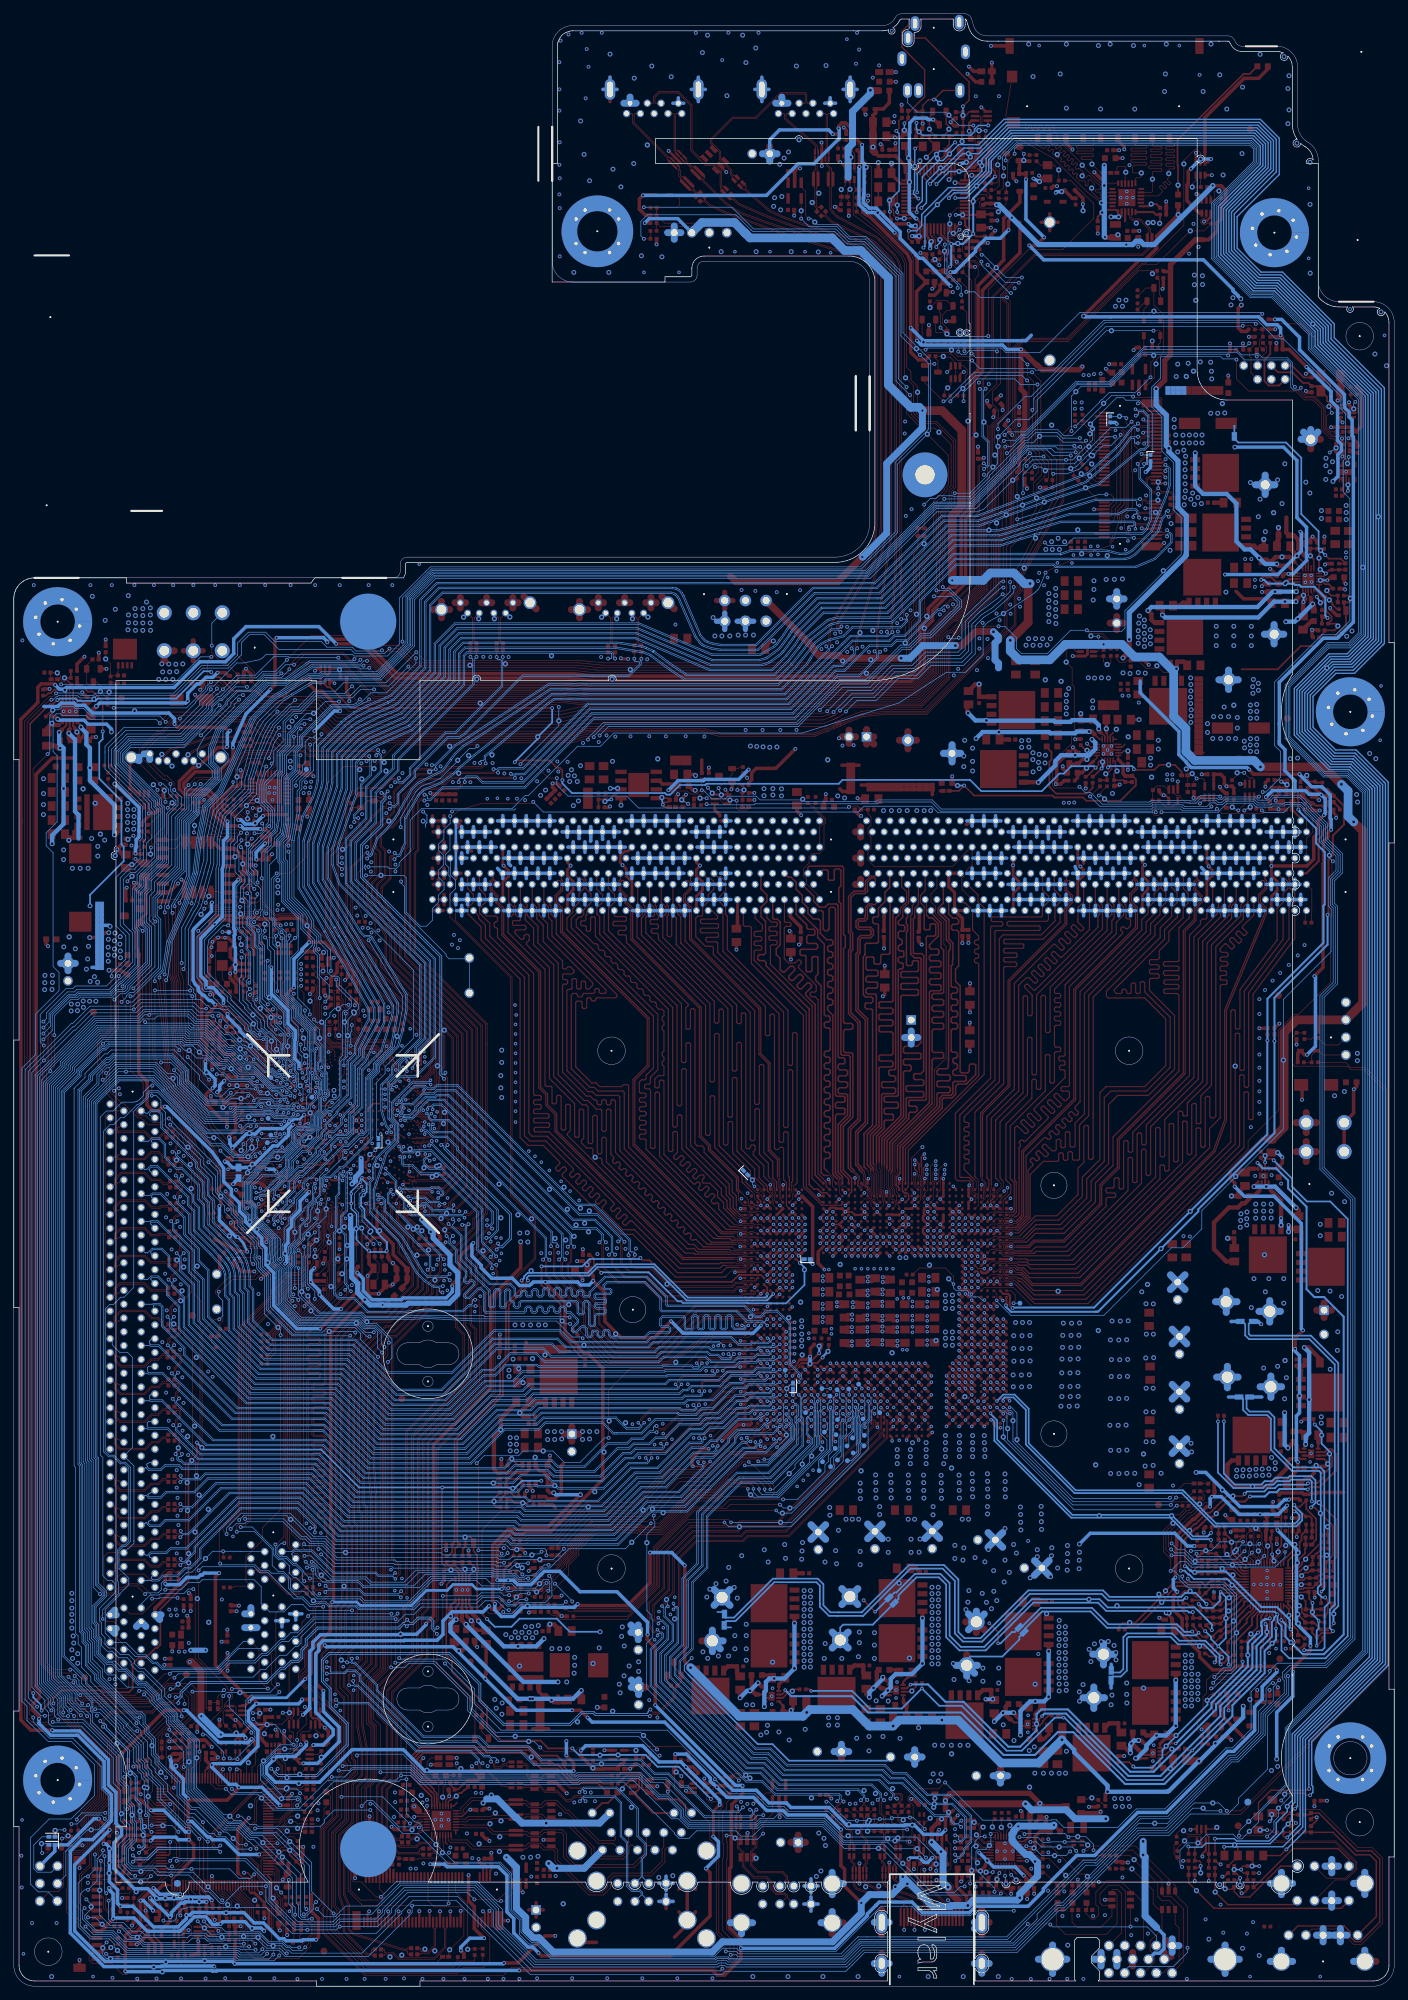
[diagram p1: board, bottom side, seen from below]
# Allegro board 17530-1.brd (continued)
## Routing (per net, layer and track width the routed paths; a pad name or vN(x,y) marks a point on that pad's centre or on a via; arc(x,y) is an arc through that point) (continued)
PEG_TX_CPU_P11: length 107.7
  TOP w0.102: v1(104.12,87.18) 103.8,87.5 103.8,87.74 103.01,88.53 97.12,88.53 96.5,89.15 94.65,89.15 94.41,89.4 92.81,89.4 92.71,89.5 92.71,89.68 92.8,89.77 CPU1.M2 ; C9326.1 176.22,108.97 176,108.97 175.77,108.74 175.77,106.55 v3(175.39,106.17)
  BOTTOM w0.102: 175.77,104.17 175.77,105.79 v3(175.39,106.17) ; 175.77,104.17 175.77,103.66 173.81,101.7 173.81,96.14 165.04,87.36 153.03,87.36 146.43,80.77 135.83,80.77 130.94,85.66 126.03,85.66 125.05,86.64 103.93,86.64 103.83,86.74 103.83,86.88 v1(104.12,87.18) ; 175.77,104.17 v2(175.39,104.17)
PEG_TX_CPU_P12: length 110.4
  TOP w0.102: v1(98.8,89.13) 98.51,89.41 98.51,89.81 98.01,90.32 93.82,90.32 93.7,90.44 93.7,90.59 93.79,90.68 CPU1.N1 ; C9329.1 176.17,113.12 175.72,113.12 175.43,112.82 175.43,112.15 176.1,111.48 176.47,111.48 176.64,111.31 176.64,111.16 v3(176.3,110.81)
  BOTTOM w0.102: v1(98.8,89.13) 98.51,88.84 98.51,88.7 98.62,88.6 105.36,88.6 105.49,88.46 126.01,88.46 127.42,87.06 131.52,87.06 136.35,82.23 145.92,82.23 152.5,88.81 164.51,88.81 172.42,96.72 172.42,102.41 173.82,103.82 173.82,104.29 ; 173.82,104.29 173.82,106.59 176.81,109.58 176.81,110.41 176.71,110.52 176.4,110.52 176.3,110.62 v3(176.3,110.81) ; 173.82,104.29 v2(173.43,104.29)
PEG_TX_CPU_P13: length 111.9
  TOP w0.102: CPU1.P2 93.11,91.62 92.79,91.62 92.71,91.54 92.71,91.41 92.89,91.23 94.43,91.23 94.64,91.02 100.58,91.02 100.81,90.79 100.81,90.51 v1(101.06,90.25) ; v1(175.87,114.38) 176.1,114.38 176.2,114.48 176.2,114.73 175.53,115.4 175.53,115.96 175.78,116.22 176.1,116.22 C9332.1
  BOTTOM w0.102: v1(101.06,90.25) 100.78,89.97 100.78,89.84 100.88,89.74 101.5,89.74 101.75,89.99 104.09,89.99 ; 104.09,89.99 v2(104.09,90.37) ; 104.09,89.99 105.99,89.99 106.13,89.86 123.92,89.86 124.13,90.07 128.8,90.07 130.27,88.6 131.96,88.6 136.93,83.63 145.34,83.63 151.92,90.21 163.93,90.21 168.72,95 168.72,99.5 169.28,100.06 169.28,103.1 169.29,103.15 169.4,103.57 169.62,104.04 169.63,104.06 169.78,104.29 169.88,104.45 171.36,106.09 171.42,106.17 174.46,109.2 174.46,111.85 176.16,113.55 176.16,114.09 v1(175.87,114.38)
PEG_TX_CPU_P14: length 114.1
  TOP w0.102: CPU1.R2 93.39,92.51 93.48,92.42 93.48,92.18 93.73,91.93 94.58,91.93 94.85,92.2 95.82,92.2 95.94,92.09 95.94,91.92 95.66,91.64 v3(95.66,91.56) ; C9335.1 176.38,119.34 175.91,119.34 175.78,119.21 175.78,118.86 176.38,118.26 176.38,117.94 176.54,117.77 v3(176.54,117.42)
  BOTTOM w0.102: v2(123.05,91.42) 122.8,91.71 ; 122.8,91.71 123.34,92.25 129.97,92.25 137.42,84.81 144.85,84.81 151.43,91.39 163.44,91.39 167.54,95.49 167.54,100 168.07,100.53 168.07,102.98 168.12,103.39 168.29,104.02 168.42,104.33 168.61,104.66 168.7,104.8 168.94,105.17 168.95,105.18 168.97,105.21 169.09,105.37 169.09,105.37 169.33,105.68 169.69,106.11 173.28,109.7 173.28,112.73 174.15,113.6 174.15,114.56 176.21,116.63 176.21,117.09 v3(176.54,117.42) ; 122.8,91.71 122.17,91.08 106.78,91.08 106.11,91.76 99.58,91.76 99.16,91.34 97.99,91.34 97.45,90.79 96.22,90.79 95.97,91.04 95.97,91.25 v3(95.66,91.56)
PEG_TX_CPU_P15: length 116.1
  TOP w0.102: CPU1.T2 92.84,93.43 92.74,93.32 92.74,93.14 92.82,93.06 94.86,93.06 95.27,93.47 97.35,93.47 97.6,93.23 97.6,93.14 v1(97.95,92.78) ; v3(177.01,120.85) 176.62,121.25 176.62,121.63 176.28,121.97 176.28,122.89 176.37,123.18 176.47,123.28 176.63,123.28 C9337.1
  BOTTOM w0.102: v1(97.95,92.78) 97.79,92.95 97.79,93.09 97.89,93.19 107.27,93.19 107.97,92.49 120.1,92.49 121.27,93.66 130.57,93.66 137.97,86.27 144.33,86.27 150.85,92.79 162.86,92.79 166.14,96.07 166.14,100.58 166.64,101.08 166.64,102.77 166.75,103.66 167.05,104.76 167.16,104.98 167.38,105.34 167.39,105.35 167.43,105.42 167.47,105.49 167.49,105.52 167.56,105.63 167.6,105.68 167.63,105.74 167.84,106.06 167.88,106.11 168.31,106.66 168.32,106.68 168.46,106.85 168.53,106.94 168.54,106.94 168.59,107 168.74,107.17 171.88,110.31 171.88,113.47 172.64,114.23 172.64,116.41 176.16,119.93 ; v3(177.01,120.85) 176.88,120.85 176.68,120.85 176.58,120.75 176.58,120.34 176.16,119.93 ; v2(176.43,119.66) 176.16,119.93
PF_MIC2_LL: length 17.1
  TOP w0.203: R2902.2 73.65,255.85 73.41,255.85 73.38,255.83 72.89,255.83 R2901.2 72.87,256.11 73.07,256.31 73.07,257 73.08,257 v3(73.08,257.05) ; v3(72.14,268.73) 71.76,269.11 71.76,269.69 71.78,269.71 71.78,270.17 FL2901.1
  BOTTOM w0.203: v3(73.08,257.05) 73.13,257.1 v2(73.13,258.67) 71.73,260.07 71.73,268.33 v3(72.14,268.73)
PIRQA_N: length 50.4
  TOP w0.102: SB1.T45 148.59,133.44 148.59,134.81 150.64,136.86 152.33,136.86 152.64,137.16 153.14,137.16 153.47,137.49 153.47,137.95 153.38,138.04 R1918.1 R1917.1 153.39,139.7 153.92,139.17 154.84,139.17 155.45,139.77 155.45,142.04 v3(154.87,142.62) ; v3(164.02,168.42) 164.02,168.42 163.5,168.94 162.74,168.94 160.99,167.18 160.99,165.12 v3(160.21,164.34) ; v3(165.13,166.99) 165.2,167.07 R9112.2
  BOTTOM w0.102: v3(154.87,142.62) 154.31,143.18 154.31,144.96 155.38,146.03 155.38,146.04 155.73,146.39 155.73,149.43 156.3,150 156.3,150.38 156.11,150.56 156.11,151.99 157.51,153.39 v2(157.51,153.62) 157.51,154.79 157.82,155.3 160.07,157.56 160.07,164.2 v3(160.21,164.34) ; v3(164.02,168.42) 163.83,168.23 163.83,167.41 164.25,166.99 v3(165.13,166.99)
PLTRST#_PCH: length 194.6
  TOP w0.102: v1(158.83,126.24) 158.98,126.08 SB1.AV29 ; R1504.1 167,9.28 166.67,8.95 166.67,8.5 167.26,7.91 167.26,6.08 165.16,3.99 158.78,3.99 156.97,5.8 156.97,6.73 156.36,7.34 156.36,9.32 v3(156.82,9.78)
  BOTTOM w0.102: v3(156.82,9.78) 156.84,9.75 157.25,9.75 157.36,9.64 158.31,9.64 158.78,10.11 158.78,11.76 159.08,12.06 159.08,15.95 v2(163.92,20.79) 164.67,21.54 165.71,21.54 167.42,23.24 169.19,23.24 174.32,28.37 174.32,35.36 177.24,38.28 177.24,39.01 179.68,41.45 179.68,41.9 181.1,43.32 183.58,43.32 184.76,44.5 184.76,44.51 185.33,45.08 186.34,45.08 186.82,45.55 186.82,46.47 188.26,47.92 188.26,49.89 188.75,50.37 188.75,51.54 189.1,51.9 189.1,75.95 189.33,76.17 189.33,127.49 189.33,128.44 184.85,132.92 179.79,132.92 177.22,130.35 177.22,130.26 177.16,130.21 177.16,130.15 172.28,125.26 167.87,125.26 167.4,125.73 165.71,125.73 165.38,126.06 163.66,126.06 163.48,126.24 162.81,126.24 162.28,125.7 159.77,125.7 159.54,125.93 159.13,125.93 v1(158.83,126.24)
PLTRST#_SIO: length 6.3
  TOP w0.102: U2401.14 169.89,13.81 169.7,13.61 169.42,13.61 167.63,11.82 v2(167.63,11.61) 167.6,11.58 167.59,11.58 167,11 R1504.2 167.06,10.73 167.07,10.72 167.61,10.72 167.61,10.72 168.06,10.72 R1516.1
PLTRST_BUF_LAN_N: length 2.5
  TOP w0.102: R2407.2 186.18,19.96 v2(186.15,19.93) 185.59,19.48 185.41,19.29 R4008.1
PLTRST_BUF_PCI_N: length 39.6
  TOP w0.102: 170.45,41.08 R4010.1 ; 170.45,41.08 R4009.1 ; 170.45,41.08 170.45,41.98 v3(169.53,42.89) ; v3(174.12,42.67) 173.88,42.44 173.88,40.07 173.88,39.13 175.39,37.62 177.67,37.62 179.07,36.22 179.07,30.56 177.29,28.78 177.29,28.33 176.15,27.19 v3(176.15,22.35) ; v3(180.04,23.29) 180.43,23.29 180.82,23.68 181.52,23.68 181.69,23.85 R2401.2
  BOTTOM w0.102: v3(169.53,42.89) 169.75,42.67 v3(174.12,42.67) ; v3(176.15,22.35) 177.05,23.25 v2(178.41,23.25) 180,23.25 v3(180.04,23.29)
PLTRST_CPU_N: length 137.2
  TOP w0.089: SB1.AG5 153.75,113.49 153.75,112.09 153.52,111.87 153.52,110.95
  TOP w0.102: v3(157.97,64.04) 157.97,64.55 159.44,66.02 159.44,95.34 154.64,100.14 154.64,100.98 153.92,101.69 153.92,104.42 153.39,104.95 153.39,106.19 153.39,106.2 153.39,109.07 153.44,109.12 153.44,109.65 153.31,109.78 153.31,109.95 153.31,110.52 153.49,110.7 153.49,110.71 153.52,110.74 153.52,110.95 ; v3(128.98,61.34) 128.91,61.34 127.89,62.36 R9910.1 C403.1 127.58,63.39 126.91,64.06 125.81,64.06 125.28,64.59 121.38,64.59 117.11,68.86 110.47,68.86 104.86,74.48 99.55,74.48 96.61,77.42 90.09,77.42 v1(89.43,78.08) ; CPU1.E7 v1(89.01,82.91)
  BOTTOM w0.102: v1(89.43,78.08) 88.06,79.45 v2(88.06,79.83) 88.06,80.26 88.57,80.77 88.57,81.22 88.87,81.52 89.1,81.52 89.42,81.83 89.42,82.51 v1(89.01,82.91) ; v3(128.98,61.34) 129.9,61.34 130.09,61.54 144.58,61.54 144.78,61.73 153.25,61.73 155.31,63.8 157.73,63.8 v3(157.97,64.04)
PLTRST_LAN_N: length 480.9
  TOP w0.102: v3(172.92,174.14) 170.5,174.14 166.28,178.36 162.84,178.36 162.33,177.85 162.33,177.4 v3(162.63,177.1) ; v3(177.53,125.68) 178.02,125.68 178.63,125.08 179.84,125.08 180.84,126.08 181.84,126.08 182.26,126.5 182.26,127.08 181.26,128.08 181.26,130.82 183.08,132.64 183.08,141.25 183.11,141.28 183.11,141.68 183.06,141.73 183.06,141.81 183.06,142.36 183.05,142.36 183.05,142.74 183.06,142.74 183.06,143.35 v3(183.09,143.39) ; R9111.1 165.66,163.4 164.67,164.39 164.67,164.81 164.43,165.05 164.42,165.05 164.41,165.06 162.29,165.06 Q9101.D 161.86,166.88 v3(163,168.01) ; v3(142.29,11.67) 149.43,11.67 151.55,13.79 151.55,21.29 149.61,23.23 v3(149.61,26.09) 149.61,28.69 148.26,30.04 148.26,37.44 148.91,38.09 148.91,44.18 146.91,46.17 146.91,88.14 147.22,88.45 v3(147.22,91.16) ; v3(44.65,223.88) 44.65,223.44 v2(44.22,223.01) 43.63,222.42 NGFF1.52 ; v3(65.19,215.43) 66.01,214.6 66.01,207.59 68.02,205.59 68.02,198.55 69.22,197.36 69.22,191.43 70.53,190.12 80.94,190.12 81.09,190.27 116.08,190.27 118.88,190.63 142.32,190.63 v3(142.84,191.15) ; v3(141.3,22.99) 140.89,23.4 U3101.19 ; LPC1.4 v3(189.26,13.96) ; v3(137,11.99) NGFF2.50 ; R4008.2 186.82,19.68 v3(187.08,19.68)
  BOTTOM w0.102: v3(142.84,191.15) 145.64,188.34 149.81,188.34 151.23,186.92 156.27,186.92 158.53,184.65 159.49,184.65 160.99,183.16 160.99,182.91 160.99,182.91 160.99,180.29 162.33,178.94 162.33,177.4 v3(162.63,177.1) 162.63,176.71 163.43,175.91 164.06,174.03 164.06,173.61 164.06,173.32 164.06,173.32 164.06,171.45 164.03,171.42 164.03,171.42 162.82,170.21 162.82,168.19 v3(163,168.01) ; v3(44.65,223.88) 44.87,223.65 47.95,223.65 48.83,224.54 51.36,224.54 v2(51.38,224.51) 52.32,223.57 53.36,223.57 55.73,221.2 55.73,221 61.3,215.43 v3(65.19,215.43) ; v3(183.09,143.39) 182.72,143.39 178.85,147.26 178.77,147.36 178.7,147.76 178.7,154.54 179.22,155.06 179.22,157.47 178.54,158.16 178.54,158.24 178.5,158.28 178.49,158.29 178.49,159.49 176.02,161.96 176.02,169.02 174.63,170.41 174.63,172.44 v3(172.92,174.14) ; v3(141.3,22.99) 141.39,23.08 144.18,23.08 147.98,26.89 148.81,26.89 v3(149.61,26.09) ; v3(177.53,125.68) 171.66,119.81 171.62,119.81 171.35,119.54 171.35,119.5 170.32,118.47 170.1,118.16 170.1,115.21 167.81,112.92 167.81,112.28 167.81,112.05 166.93,111.17 166.93,110.52 166.9,110.49 166.9,110.38 165.99,109.47 165.98,109.47 164.59,108.08 164.59,108.07 164.58,108.05 164.58,107.29 163.98,106.69 163.98,104.27 163.98,104.27 162.84,103.13 162.84,102.37 162.84,98.38 161.89,97.43 159.2,94.74 155.27,94.74 154.61,95.4 150.59,95.4 149.78,94.59 149.78,93.72 v3(147.22,91.16) ; v3(187.08,19.68) 187.08,19.29 187.93,18.44 187.93,15.29 v3(189.26,13.96) 189.75,13.96 190.37,13.34 190.37,8.74 188.78,7.16 185.94,7.16 183.65,4.88 167.57,4.88 167.22,4.52 164.18,4.52 163.5,5.2 161.58,5.2 160.68,4.29 148.65,4.29 142.29,10.65 v3(142.29,11.67) 137.32,11.67 v3(137,11.99)
PLTRST_PCI_N: length 22.7
  TOP w0.102: v3(161.72,43.71) 161.72,43.72 162.03,44.02 162.03,54.06 SLOT1.A11 ; R4010.2 170.09,40.2 169.82,40.46 169.82,41.86 v3(169.65,42.04)
  BOTTOM w0.102: v3(169.65,42.04) 169.15,42.53 v2(167.25,42.53) 162.91,42.53 v3(161.72,43.71)
PLTRST_PEG_N: length 27.6
  TOP w0.102: v3(173.99,57.52) 173.72,57.26 173.72,47.55 172.13,45.95 172.13,40.32 172,40.2 R4009.2
  BOTTOM w0.102: SLOT2.A11 181.55,55.36 180.24,56.67 178.94,56.67 178.71,56.9 175.35,56.9 174.72,57.52 v3(173.99,57.52)
PM_DOWN_CPU: length 48.1
  TOP w0.102: v1(92.15,76.03) 92.5,76.38 94.27,76.38 98.7,71.95 101.91,71.95 105.28,68.58 v2(105.92,68.58) 106.88,67.61 107.9,67.61 108.18,67.34 116.04,67.34 116.12,67.25 116.12,67.25 119.58,63.79 119.58,63.05 120,62.64 120.02,62.64 121.06,61.59 R421.2 ; CPU1.D8 v1(88.1,82)
  BOTTOM w0.102: v1(92.15,76.03) 92.04,75.92 90.71,75.92 87.29,79.34 87.29,81.04 87.64,81.39 87.64,81.54 v1(88.1,82)
PM_DOWN_PCH: length 87.8
  TOP w0.089: SB1.AE2 152.71,112.28 152.71,111.25 152.52,111.06 152.52,110.96 152.51,110.95
  TOP w0.102: 152.51,110.95 150.82,109.25 150.82,105.47 152.1,104.19 152.1,102.2 153.7,100.6 153.7,99.79 158.52,94.96 158.52,66.4 156.51,64.39 156.51,63.13 155.92,62.55 v3(155.47,62.55) ; R421.1 124.52,61.61 125.16,61.61 v3(125.5,61.26)
  BOTTOM w0.102: v3(155.47,62.55) 153.68,60.77 145.18,60.77 144.97,60.55 130.48,60.55 130.3,60.38 128.12,60.38 127.56,60.93 v2(127.01,60.93) 126.68,61.26 v3(125.5,61.26)
PM_SYNC_CPU: length 135.7
  TOP w0.102: v1(93.52,75.95) 94.38,75.95 98.6,71.73 101.79,71.73 106.26,67.26 106.44,67.07 v1(107.69,67.07) ; v1(88.1,82.88) 88.1,82.91 CPU1.E8 ; R1711.2 152.95,104.97 153.62,104.3 153.62,101.57 154.31,100.88 154.31,100.04 159.13,95.21 159.13,66.15 157.16,64.17 157.16,62.43 156.39,61.66 156.39,61.28 156.66,61.01 157.15,61.01 v3(157.52,60.65)
  BOTTOM w0.102: v1(88.1,82.88) 88.1,82.64 87.44,81.98 87.44,81.47 87.08,81.12 87.08,79.25 90.77,75.56 93.14,75.56 v1(93.52,75.95) ; v3(157.52,60.65) 157.04,60.65 156.91,60.78 156.53,60.78 156.26,60.51 156.26,59.56 155.23,58.52 153.89,58.52 153.64,58.52 150.16,58.52 149.44,57.81 149.39,57.76 141.18,57.76 139.58,59.36 139.07,59.36 130.79,59.36 130.72,59.28 127.49,59.28 127.2,58.99 126.81,58.6 125.25,58.6 123.27,60.58 122.33,60.58 119.53,63.37 111.39,63.37 v2(110.47,64.29) v1(107.69,67.07)
PM_SYNC_PCH: length 8.5
  TOP w0.089: 151.76,109.33 152.91,110.48 152.91,110.69 152.92,110.7 152.92,110.75 152.93,110.76 152.93,110.77 153.09,110.93 153.09,111.98 153.26,112.15 153.26,112.58 SB1.AF3
  TOP w0.102: R1711.1 152.49,105.85 151.68,106.66 v2(151.68,107.3) 151.76,107.38 151.76,109.33
POL1_SDA: length 14.7
  TOP w0.102: v3(57.91,13.68) 58.03,13.56 R5908.1 58.71,13.09 58.51,12.89 R5901.2 ; v3(58.47,22.05) 58.39,22.12 58.31,22.12 58.18,22.25 57.47,22.25 57.39,22.17 U5901.10
  BOTTOM w0.102: v3(57.91,13.68) 57.91,14.22 60.59,16.9 60.59,19.54 60.31,19.82 59.19,19.82 v2(58.65,20.37) 58.44,20.58 58.44,22.01 v3(58.47,22.05)
POL2_SCL: length 12.2
  TOP w0.102: U5901.9 57.94,21.64 58.06,21.53 59.17,21.53 v3(59.33,21.69) ; R5902.2 61.3,13.36 R5909.1 61.51,14.26 61.43,14.33 v3(61.43,14.88)
  BOTTOM w0.102: v3(59.33,21.69) 60.01,21.69 60.74,20.96 60.74,20.61 61.21,20.14 v2(61.21,16.76) 61.43,16.54 v3(61.43,14.88)
PROC_TRIGIN_CPU: length 126.1
  TOP w0.102: R2201.2 157.23,104.54 157.33,104.44 157.33,103.67 158.44,102.57 159.88,102.57 161.85,100.59 161.85,99.89 166.67,95.07 166.67,68.19 v3(167.34,67.52) ; CPU1.D1 95.71,82.46 99.77,78.4 101.94,78.4 110.24,70.1 116.97,70.1 121.77,65.3 125.64,65.3 125.97,64.97 127.85,64.97 129.01,63.81 v3(129.01,63.46)
  BOTTOM w0.102: v3(167.34,67.52) 166.72,68.15 160.43,68.15 v2(159.89,67.61) 159.6,67.61 156.8,64.81 154.89,64.81 154.47,64.39 154.47,64.39 153.45,63.37 138.1,63.37 137.88,63.59 129.14,63.59 v3(129.01,63.46)
PROC_TRIGIN_PCH: length 9.2
  TOP w0.089: 155.36,109.98 155.36,110.55 155.34,110.56 155.34,110.6 155.2,110.74 155.2,110.8 155.19,110.81 155.19,112.19 155.25,112.25 155.25,112.54 155.18,112.61 SB1.AK3
  TOP w0.102: 155.36,109.98 155.37,109.97 155.37,107.75 155.73,107.39 155.73,107.32 v3(156.37,106.68) 156.51,106.68 157.23,105.97 R2201.1
  BOTTOM w0.102: v3(156.37,106.68) v2(156.37,105.66)
PROC_TRIGOUT_CPU: length 41.1
  TOP w0.102: CPU1.B3 92.73,80.11 94.42,80.11 99.7,74.83 105.01,74.83 110.42,69.42 v2(116.76,69.42) 117.06,69.42 117.26,69.22 121.53,64.95 125.46,64.95 125.89,64.52 R901.2
PROC_TRIGOUT_PCH: length 93.2
  TOP w0.089: 155.16,108.03 155.16,110.48 155.15,110.49 155.15,110.52 155.01,110.66 155.01,110.73 155,110.74 155,112.37 SB1.AK2
  TOP w0.102: 155.16,108.03 155.09,107.96 155.09,107.52 155.17,107.45 155.17,107.38 155.91,106.64 155.91,106.49 156.18,106.22 156.38,106.22 156.64,105.95 156.64,104.63 156.95,104.32 156.95,103.55 158.29,102.21 159.73,102.21 161.49,100.45 161.49,99.74 166.32,94.92 166.32,67.87 v3(166.5,67.69) ; R901.1 128.46,63.63 v3(128.46,62.75)
  BOTTOM w0.102: v3(166.5,67.69) 160.89,67.69 158.32,65.13 157.61,65.13 156.95,64.46 155.04,64.46 153.4,62.81 v2(151.94,62.81) 138.13,62.81 137.77,62.46 129.77,62.46 129.51,62.2 129.01,62.2 v3(128.46,62.75)
PROCHOT#_CPU: length 33.9
  TOP w0.102: CPU1.C39 57.09,82.46 v1(56.61,81.98) ; R409.2 30.68,69.61 v3(31.5,69.61)
  BOTTOM w0.102: v3(31.5,69.61) 31.64,69.61 32.23,69.01 46.39,69.01 56.64,79.26 v2(56.64,79.55) 56.64,80.71 56.61,80.73 v1(56.61,81.98)
PROCHOT#_CPU_R: length 282.5
  TOP w0.102: v3(32.38,60.15) 32.38,61.88 33.43,62.92 33.43,66.03 32.38,67.08 32.38,68.02 v2(32.26,68.15) 32.13,68.28 31.16,68.28 29.84,69.6 R409.1 ; v1(15.82,62.89) 15.16,63.56 15.16,64.06 15.29,64.19 15.29,66.39 PR4461.1 15.75,67.79 15.72,67.81 R404.2 ; v3(26.06,44.79) 15.53,44.79 v3(15.39,44.93) ; v3(186.26,12.39) 185.78,12.88 185.78,13.46 185.57,13.67 185.04,13.67 184.48,14.22 184.24,14.22 R2458.2
  BOTTOM w0.102: v3(15.39,44.93) 15.28,44.82 15.28,42.19 18.34,39.13 18.34,31.45 22.56,27.23 22.56,26.46 24.07,24.94 29.51,24.94 32.61,21.84 36.83,21.84 47.67,11 48.52,11 54.64,4.88 76.73,4.88 78.55,3.06 79.45,2.16 96.92,2.16 97.41,1.67 125.15,1.67 126.22,2.74 135.92,12.45 142.16,12.45 143.79,10.81 143.79,10.57 149.57,4.79 159.74,4.79 160.19,5.23 160.65,5.23 161.27,5.86 163.25,5.86 164.68,7.29 169.91,7.29 170.01,7.19 171.7,7.19 172.19,7.67 175.43,7.67 175.7,7.4 180.98,7.4 181.55,7.96 182.87,7.96 184.12,9.22 185.83,9.22 186.26,9.65 v3(186.26,12.39) ; v3(26.06,44.79) 24.73,46.13 23.81,46.13 23.55,46.39 23.55,56.47 24.79,57.71 29.78,57.71 29.9,57.84 30.07,57.84 31.17,58.93 31.17,59.46 31.85,60.15 v3(32.38,60.15) 31.01,61.52 30.16,61.52 29.35,60.71 17.25,60.71 15.82,62.13 v1(15.82,62.89)
PROCHOT#_EC: length 6.1
  TOP w0.102: R2458.1 183.32,14.21 182.93,14.6 182.93,14.68 182.5,15.11 v2(181.61,15.11) 180.73,15.99 180.73,16 180.62,16.12 180.62,16.25 179.49,17.38 U2401.36
PROCHOT#_IMVP: length 5.4
  TOP w0.102: PU4401.10 17.24,61.66 16.26,62.64 16.26,63.07 15.72,63.61 v2(15.72,63.83) 15.72,64.4 15.75,64.43 PR4461.2
PS_ON_N: length 13.6
  TOP w0.102: v3(171.32,194.18) 171.32,193.15 170.91,192.75 170.91,192.74 169.56,191.39 168.97,191.39 C4302.1 R4302.2 167.64,188.91 R4301.2
  BOTTOM w0.102: ATX1.1 171.32,197.42 v3(171.32,194.18)
PSPWRGD: length 235.9
  TOP w0.102: R4207.2 40.17,193.84 42.29,195.96 42.65,195.96 42.65,195.96 43.05,195.96 43.06,195.96 44.09,195.96 v3(44.54,196.41) ; R4201.1 8.42,223.81 8.76,224.16 8.99,224.16 8.99,224.15 9.25,224.15 10.23,225.14 10.23,225.14 10.54,225.45 10.54,228.53 11.78,229.77 12.98,229.77 14.27,231.06 21.1,231.06 22.86,232.82 v3(22.86,235.61) ; v3(64.59,195.43) 65.13,194.9 65.13,189.73 68.83,186.03 82.64,186.03 82.75,186.13 117.22,186.13 120.8,186.54 147.86,186.54 147.89,186.56 152.82,191.49 157.38,191.49 161.63,187.24 163.81,187.24 C4301.1 165.1,189.55 165.1,190.26 168.28,193.44 ATX1.4 ; v3(57.33,196.98) 57.35,197 61.77,197 62.21,196.57 63.09,195.68 v3(63.09,195.33)
  BOTTOM w0.102: v3(64.59,195.43) 64.34,195.17 63.25,195.17 v3(63.09,195.33) ; v3(57.33,196.98) 56.4,196.98 55.26,195.83 54.74,195.31 54.74,193.76 53.99,193.01 50.27,193.01 46.88,196.41 v3(44.54,196.41) 44.34,196.22 39.52,196.22 39.01,196.72 39.01,199.24 30.86,207.39 30.86,212.72 31.97,213.83 31.97,220.68 33.66,222.37 33.66,227.3 35.13,228.77 35.13,231.62 33.85,232.91 33.85,235.98 33.74,236.09 25.17,236.09 24.8,235.71 22.96,235.71 v3(22.86,235.61)
PULSAR_38D4M_REFCLK: length 196.6
  TOP w0.102: NGFF1.64 41.03,225.42 40.64,225.8 39.55,225.8 38.83,225.09 38.83,214.33 39.82,213.34 39.82,212.5 40.5,210.06 40.71,209.45 41.3,208.64 45.11,207.37 47.36,206.32 50.32,204.95 v3(50.52,204.75) ; v3(148.68,153.25) 149,153.57 149,153.59 149.12,153.7 149.12,154.17 R6308.1 149.11,154.23 149.41,154.53 150.11,156.82 150.11,161.29 149.26,162.14 v3(148.63,162.14)
  BOTTOM w0.102: v3(148.63,162.14) 145.86,162.14 145.64,161.93 144.54,161.93 144.17,162.29 144.17,162.73 142.57,164.33 142.57,168.91 140.87,170.61 127.77,170.61 125.89,172.49 125.41,172.49 118.3,179.6 115,179.6 113.1,181.51 85.78,181.51 71.73,185.89 64.88,190.32 62.1,190.32 59.56,192.86 59.56,196.88 58.83,197.61 v2(56.62,198.83) 52.09,201.82 51.94,201.96 51.94,201.97 51.68,202.23 51.67,202.23 51.53,202.37 51.38,202.66 51.32,202.8 51.23,202.96 v3(50.52,204.75) ; R1816.2 147.47,123.1 147.47,130.91 146.2,132.18 146.2,133.2 142.11,137.29 142.11,147.22 148.15,153.25 v3(148.68,153.25)
PW_CLEAR: length 283.5
  TOP w0.102: v3(154.05,147.07) 154.61,146.51 155.41,146.51 155.73,146.82 155.73,147.47 155.98,147.73 R2041.2 156.67,147.71 156.67,147.33 155.7,146.37 155.7,143.78 156.14,143.35 156.14,142.94 156.06,142.86 156.06,139.54 155.94,139.41 155.63,139.06 155.58,139 155.09,138.52 155.09,137.73 153.89,136.53 152.59,136.53 152.5,136.45 152.05,136.45 151.39,135.79 151,135.79 150.99,135.8 150.44,135.8 149.57,134.92 SB1.V48 ; v3(177.99,183.13) 177.99,183.3 177.22,184.07 170.17,184.07 169.54,183.44 169.14,183.44 165.06,183.44 163.5,181.88 162.29,181.88 162.13,181.71 159.31,181.71 158.97,181.37 v3(155.41,181.37) ; v3(195.1,178.46) 197.21,176.35 197.21,43.12 196.72,42.63 196.72,42.15 197.5,41.37 197.71,41.17 197.71,39.44 v3(197.19,38.92)
  BOTTOM w0.102: v3(197.19,38.92) 197.19,38.29 194.81,35.92 191.45,35.92 187.35,31.81 187.35,28.63 186.3,27.57 186.3,24.12 187.76,22.66 v2(188.8,22.66) 189.33,22.66 192.46,19.53 192.46,16.08 193.68,14.86 ; v3(155.41,181.37) 155.41,181.1 156.56,179.95 156.56,179.28 156.56,176.1 157.48,175.18 157.53,175.18 158.27,174.44 158.27,173.39 158.6,173.06 158.6,169.95 158.67,169.73 158.71,169.71 158.74,169.55 158.74,169.55 158.87,168.8 158.97,168.28 158.97,168.28 159.07,167.72 159.1,167.54 159.14,167.32 159.16,167.21 159.26,166.67 159.32,166.37 159.39,165.98 159.39,165.98 159.4,165.94 159.41,165.87 159.41,157.78 157.37,155.75 156.67,154.6 156.54,154.36 156.54,153.29 155.5,152.25 155.5,151.49 154.15,150.14 154.1,150.05 154.1,148.78 154.05,148.73 v3(154.05,147.07) ; v3(195.1,178.46) 194.79,178.77 194.79,184.05 193.96,184.88 193.48,184.88 192.99,185.37 191.4,185.37 191.13,185.1 191.04,185.1 189.9,185.1 188.78,183.98 178.84,183.98 v3(177.99,183.13)
PWR2_PRSN_1: length 4
  TOP w0.102: Q2401.2 156.31,37.13 156.01,36.83 155.85,36.83 155.31,36.28 R2408.1 v2(156.21,36.27) 156.26,36.27 156.29,36.25 R2402.2
PWR2_PRSN_2: length 367.9
  TOP w0.102: Q2401.5 156.31,40.61 156.53,40.83 R2403.2 ; R2403.2 156.18,41.53 155.07,40.41 155.07,39.88 153.28,38.09 153.28,32.75 154.39,31.64 154.39,29.68 153.82,29.11 153.82,24.44 155.38,22.88 155.38,11.87 v3(156.08,11.18) ; R2403.2 155.66,40.66 Q2401.6 ; U2405.2 32,172.93 31.55,172.48 31.08,172.48 30.97,172.38 30.97,172.22 30.07,171.32 v3(28.14,171.32)
  BOTTOM w0.102: v3(28.14,171.32) 27.68,171.78 25.83,171.78 25.51,171.46 24.98,171.46 24.47,171.96 20.32,171.96 19.76,171.4 18.26,171.4 17.45,172.21 13.72,172.21 12.37,170.87 12.37,170.69 9.96,168.28 9.96,166.09 7.82,163.96 7.82,161.37 8.94,160.25 8.94,156.72 8.53,156.31 8.53,145.28 10.46,143.36 10.46,118.46 5.99,113.99 5.99,50.66 5.99,50.41 9.92,46.48 15.15,46.48 16.21,45.43 16.21,44.55 15.94,44.28 15.94,42.47 19,39.41 19,36.53 22.74,32.79 23.66,32.79 32.85,23.6 v2(34.7,23.6) 37.01,23.6 43.08,17.53 44.64,17.53 51.74,10.42 51.74,9.72 55.21,6.25 77.3,6.25 79.75,3.8 96.37,3.8 96.58,4.01 98.14,4.01 98.35,3.8 124.26,3.8 129.21,8.75 129.21,11.13 133.02,14.94 144.07,14.94 147.4,11.61 151.92,11.61 153.47,10.06 154.97,10.06 v3(156.08,11.18)
PWR2_PRSNT: length 26.4
  TOP w0.102: v3(158.42,34.99) 158.47,35.04 158.47,36.54 158.13,36.88 157.21,36.88 156.96,37.13 Q2401.3 ; R2465.1 157.73,27.3 158.37,27.94 v3(158.52,27.94) 158.62,27.94 159.74,26.82 159.74,25.89 161.46,24.18 U2401.108
  BOTTOM w0.102: v3(158.52,27.94) 158.52,28.09 159,28.57 v2(160.53,28.57) 161.74,28.57 163.8,30.64 163.8,31.96 162.03,33.73 159.68,33.73 v3(158.42,34.99)
PWR_1D0V: length 62.3
  TOP w0.254: v3(187.12,181.76) 187.12,186.08 188.57,187.53 189.3,187.53 190.26,188.49 PC5108.1
  TOP w0.508: PC5108.1 190.84,188.54 PR5114.1 ; PR5133.1 PR5134.1 PR5135.1 PR5117.1 PR5119.1 PR5118.1 v4(189,151.89)
  TOP w1.016: 192.15,147.1 PT5101.1 ; PT5101.1 192.15,149.21 ; PT5101.1 191.1,148.16 ; PT5101.1 193.21,148.16
  BOTTOM w0.254: v3(187.12,181.76) 187.12,180.64 187.62,180.15 187.62,174.92 184.4,171.7 184.4,165.38 184.07,165.05 184.07,162.97 188.95,158.09 v4(188.95,156.49)
  BOTTOM w0.508: 188.67,147.57 PR5125.1 PR5124.1 PR5123.1 PR5122.1 PR5121.1 PR5120.1 PR5126.1 PR5127.1 PR5128.1 PR5129.1 PR5130.1 PR5131.1 PR5132.1
  BOTTOM w1.016: PT5101.1 193.21,148.16 ; PT5101.1 192.15,147.1 ; PT5101.1 192.15,149.21 ; PT5101.1 191.1,148.16
  vias: v2(191.97,151.99) v4(189.18,150.62) v4(189.31,148.79) v4(189.48,147.32) v4(191.08,150.27) v4(192.76,150.55)
PWR_1D0V_BOOT: length 3.5
  TOP w0.305: 193.48,182.69 193.44,182.69 PU5101.10
  TOP w0.635: 193.48,182.69 194.25,182.69 v2(194.49,182.93) 194.49,182.91 195.2,182.19 PR5110.2
PWR_1D0V_BOOT_R: length 3.2
  TOP w0.635: PC5106.2 v2(193.29,179.32) 193.65,179.32 194.01,179.68 PR5110.1
PWR_1D0V_CS: length 5
  TOP w0.254: PR5111.1 195.75,186.94 195.34,186.94 195.01,187.28 194.66,187.28 194.13,187.81 192.66,187.81 v2(192.61,187.76) 192.41,187.55 192.41,186.34 PU5101.2
PWR_1D0V_FB: length 5.7
  TOP w0.254: PU5101.4 191.4,188.21 PC5108.2 191.74,188.56 191.74,188.62 192.51,189.38 192.53,189.38 v2(192.66,189.51) 191.76,189.51 PR5114.2 PR5116.1
PWR_1D0V_LGATE: length 20.5
  TOP w0.305: PU5101.6 190.29,182.63 190.29,182.39 v4(190.27,182.37)
  TOP w0.635: PU5102.8 184.7,167.41 185.33,166.78 v4(185.42,166.78)
  BOTTOM w0.635: v4(185.42,166.78) 185.42,171.09 188.98,174.65 v2(188.98,176.48) 188.98,179.36 189.48,179.87 189.48,181.51 190.27,182.3 v4(190.27,182.37)
PWR_1D0V_PG: length 3.5
  TOP w0.254: PR5107.2 194.45,184.84 v2(194.36,184.84) 194.36,184.92 193.51,185.77 193.47,185.77 192.91,186.33 PU5101.1
PWR_1D0V_PHASE: length 18.7
  TOP w0.254: 191.9,182.09 PU5101.8
  TOP w0.635: 191.9,182.09 192.02,181.97 v4(192.02,181.48) 192.02,180.85 191.77,180.59 PC5106.1
  BOTTOM w0.635: 190.63,166.24 190.63,169.67 191.13,170.18 191.13,180.59 v4(192.02,181.48)
  vias: v2(187.45,166.88) v2(188.21,171.35) v2(192.02,165.99) v4(186.84,166.01) v4(187.83,165.1) v4(187.83,163.7) v4(188.72,166.24) v4(189.23,161.93) v4(190.37,161.93) v4(191.52,161.93) v4(192.79,164.59) v4(192.79,163.19)
PWR_1D0V_RF: length 3.1
  TOP w0.254: PU5101.5 190.24,186.33 190.08,186.17 190.08,186.04 189.87,185.83 189.34,185.83 PR5112.1 189.01,185.81 v2(188.39,186.44)
PWR_1D0V_SNB: length 4
  TOP w0.635: PR5113.2 184.23,163.91 v3(184.99,164.67) 184.99,164.71 184.35,165.34 PC5110.1
  BOTTOM w0.254: v3(184.99,164.67) v2(185.32,163.76)
PWR_1D0V_UGATE: length 20.6
  TOP w0.305: PU5101.9 192.4,182.63 193.03,181.99
  TOP w0.635: v4(193.42,181.61) 193.04,181.99 193.03,181.99 ; PR5108.2 194.51,165.56 v4(194.44,165.48)
  BOTTOM w0.635: v4(193.42,181.61) 193.42,179.96 192.79,179.32 v2(192.79,173.48) 192.79,168.35 194.44,166.7 v4(194.44,165.48)
PWR_1D0V_UGATE_R: length 3.6
  TOP w0.635: PU5102.1 190.72,167.73 191.2,167.25 PR5109.1 192.07,166.37 PR5108.1
PWR_1D0V_VCC: length 5.6
  TOP w0.305: PU5101.7 191.4,182.53 191.16,182.3
  TOP w0.508: 191.16,182.3 191.16,182.14 190.96,181.94 190.96,181.76 v2(190.86,181.66) 190.63,181.43 PC5109.1 190.5,180.59 190.5,180.59 190.4,180.7 190.31,180.7 189.87,181.14 189.87,181.23 189.05,182.04 PR5115.1
PWR_2D5V: length 1
  BOTTOM w0.254: v4(113.56,173.51) v2(112.52,173.51)
PWR_2D5V_EN: length 5.6
  TOP w0.254: PU5201.8 105.17,172.09 104.97,171.88 PC5205.1 104.97,171.78 105.24,171.5 105.63,171.5 v3(105.98,171.15) 105.98,171.07 105.72,170.81 PR5204.1
  BOTTOM w0.254: v3(105.98,171.15) v2(106.11,172.18)
PWR_2D5V_FB: length 6.1
  TOP w0.254: PR5206.1 115.29,170.78 PR5205.2 PC5206.1 113.55,171.89 113.54,171.91 v3(113.44,171.91) 113.44,172.18 112.96,172.66 112.73,172.66 PU5201.2
  BOTTOM w0.254: v3(113.44,171.91) v2(114.36,171.61)
PWR_2D5V_VIN:
  vias: v2(106.71,177.77)
PWR_3D3V: length 31.2
  TOP w0.254: 22.1,190.75 16.89,190.75 13.53,194.12 11.26,194.12 9.98,195.4 8.76,195.4 6.99,197.18 PG4902.2 ; PR4908.2 27.58,178.69
  TOP w1.016: PL4901.1 25.4,189.23 ; PL4901.1 24,187.83 ; PL4901.1 24,190.63 ; PL4901.1 22.6,189.23
  BOTTOM w1.016: PL4901.1 24,190.63 ; PL4901.1 24,187.83 ; PL4901.1 22.6,189.23 ; PL4901.1 25.4,189.23
  vias: v2(23.24,185.55) v4(22.73,183.77) v4(22.72,182.25) v4(22.99,180.72) v4(24,183.9) v4(24,180.72) v4(24.64,185.29) v4(25.15,183.9) v4(25.15,180.72) v4(26.16,183.9) v4(26.29,180.72) v4(27.05,182.88) v4(27.05,181.61)
PWR_3D3V_SN: length 2.6
  TOP w0.635: v2(31.54,190.85) PC4911.1 30.51,191.85 PR4950.2
PWR_3V_BOOT2: length 5
  TOP w0.203: PU4902.9 12.85,200.97
  TOP w0.635: 12.85,200.97 13.14,200.68 v3(13.14,200.49) 13.21,200.43 PR4942.2
  BOTTOM w0.254: v2(13.14,201.46) v3(13.14,200.49)
PWR_3V_BOOT2_R: length 2.1
  TOP w0.635: PR4942.1 13.21,196.53 12,197.74 PC4907.2
PWR_3V_CS2: length 5
  TOP w0.203: PU4902.5 10.9,202.3 10.02,201.42 9.92,201.42
  TOP w0.254: PR4952.1 8.27,199.45 8.95,200.13 8.95,200.34 v2(9.4,200.79) 9.4,200.9 9.92,201.42
PWR_3V_EN2: length 11.5
  TOP w0.203: 11.05,201.85 11.48,202.28 PU4902.6
  TOP w0.254: 11.05,201.85 10.24,201.04 10.24,200.49 9.91,200.16 9.91,199.25 9.07,198.42 9.07,197.89 9.59,197.37 PR4959.2 8.42,197.36 8.17,197.1 v2(8.17,197.02) 8.17,196.86 8.64,196.39 PC4918.1 10.1,196.14 PR4961.1
PWR_3V_FB2: length 6.5
  TOP w0.203: 10.11,203.2 10.34,203.43 PU4902.4
  TOP w0.254: 10.11,203.2 9.98,203.07 9.46,203.07 PR4956.1 9.5,202.44 9.75,202.18 v2(9.75,202.16) 9.75,202.05 9.13,201.42 PR4954.2 PC4914.2
PWR_3V_FB2_A: length 3.5
  TOP w0.254: PG4902.1 7.24,199.82 7.24,200.15 7.28,200.19 PC4914.1 6.6,200.46 6.35,200.71 v2(6.35,201.02) 6.35,201.17 6.6,201.42 PR4954.1
PWR_3V_LGATE2: length 26.6
  TOP w0.203: PU4902.11 14,202.17 v4(14.17,202)
  TOP w0.635: PU4904.4 34.73,197.51 35.18,197.95 35.18,198.75 v4(35.69,199.26)
  BOTTOM w0.635: v4(35.69,199.26) 35.18,199.77 19.81,199.77 17.59,202 v2(17.27,202) v4(14.17,202)
PWR_3V_PHASE2: length 19.5
  TOP w0.203: 12.04,201.09 12.45,201.5 PU4902.8
  TOP w0.635: PC4907.1 11.63,200.03 v4(11.81,200.2) 12.04,200.43 12.04,201.09
  TOP w1.016: 17.4,194.43 PL4901.2 ; PL4901.2 16,195.83 ; PL4901.2 18.8,195.83 ; PL4901.2 17.4,197.23
  BOTTOM w0.635: v4(11.81,200.2) v2(13.97,198.04) 14.02,198.04 14.4,197.66 15.67,197.66 v4(15.7,197.64)
  BOTTOM w1.016: PL4901.2 17.4,197.23 ; PL4901.2 17.4,194.43 ; PL4901.2 18.8,195.83 ; PL4901.2 16,195.83
  vias: v4(20.7,196.98) v4(20.7,195.58) v4(20.7,194.18) v4(23.24,196.98) v4(23.24,195.58) v4(23.24,194.18) v4(25.78,196.98) v4(25.78,195.58) v4(25.78,194.18)
PWR_3V_UGATE2: length 24.1
  TOP w0.203: 13.84,201.17 13.25,201.76 PU4902.10
  TOP w0.635: v4(14.22,200.56) 14.22,200.79 13.84,201.17 ; v4(33.57,198.63) 33.57,199.56 PR4944.1
  BOTTOM w0.635: v4(33.57,198.63) 33.2,198.26 19.7,198.26 17.4,200.56 v2(15.82,200.56) v4(14.22,200.56)
PWR_3V_UGATE2R: length 2.5
  TOP w0.635: PR4944.2 31.04,199.97 30.61,200.4 PU4901.4
PWR_5V: length 43.3
  TOP w0.203: 15.16,204.42 14.98,204.24 PU4902.14
  TOP w0.508: PC4913.1 15.82,204.58 v3(15.33,204.58) 15.16,204.42
  TOP w1.016: 12.09,222.68 PL4902.2 ; PL4902.2 12.09,225.47 ; PL4902.2 10.69,224.08 ; PL4902.2 13.49,224.08
  BOTTOM w0.254: PG4901.2 23.16,226 23.13,226.03 23.14,226.03
  BOTTOM w0.508: v3(15.33,204.58) 14.62,204.58 12.7,206.5 12.7,211.33 14.1,212.72 14.1,221.01 16.03,222.94 v4(23.09,222.94)
  BOTTOM w1.016: 11.05,225.12 PL4902.2 ; PL4902.2 12.09,225.47 ; PL4902.2 13.13,225.12 ; PL4902.2 13.49,224.08
  vias: v2(24.89,229.24) v4(24.55,227.88) v4(25.57,227.84) v4(26.58,227.84)
PWR_5V3D3V_LDO3: length 3.4
  TOP w0.203: PU4902.3 10.16,203.84
  TOP w0.254: 10.16,203.84 9.97,203.64 v3(9.69,203.64)
  TOP w0.508: v3(9.69,203.64) 9.67,203.64 9.22,204.09 PC4916.1
  BOTTOM w0.254: v3(9.69,203.64) v2(10.69,203.64)
PWR_5V3D3V_VIN: length 30.4
  TOP w0.508: 22.91,202.06 21.82,200.96 18.39,200.96 PR4932.1 ; v3(13.59,210.69) 13.11,210.2 PR4960.1
  TOP w1.016: PT4901.1 41.26,200.95 ; PT4901.1 39.15,200.95 ; PT4901.1 40.2,202 ; PT4901.1 40.2,199.89
  BOTTOM w0.508: v3(24.51,204.48) 16.86,204.48 13.46,207.87 13.46,210.56 v3(13.59,210.69)
  BOTTOM w1.016: PT4901.1 40.2,202 ; PT4901.1 41.26,200.95 ; PT4901.1 40.2,199.89 ; PT4901.1 39.15,200.95
  vias: v2(33.45,205.03) v4(24.38,201.93) v4(39.37,203.84) v4(40.54,203.78) v4(41.73,203.76) v4(43.5,203.58) v4(43.51,202.31) v4(43.61,200.79)
PWR_5V_BOOT1: length 4.1
  TOP w0.203: PU4902.17 12.85,205.95 v2(14.1,207.2)
  TOP w0.635: v2(14.1,207.2) 14.1,207.26 15.06,208.23 PR4943.1
PWR_5V_BOOT1_R: length 2.8
  TOP w0.635: v2(16.76,211.28) PC4908.1 16.76,209.52 16.99,209.3 PR4943.2
PWR_5V_CS1: length 3.9
  TOP w0.203: PU4902.1 10.9,204.94
  TOP w0.254: PR4953.1 10.17,208.22 10.9,207.49 v2(10.9,206.86) 10.9,204.94
PWR_5V_EN1: length 5.7
  TOP w0.203: PU4902.20 11.65,206.69
  TOP w0.254: PC4919.1 11.2,208.24 PR4962.1 ; PC4919.1 v2(12.14,207.19) 11.65,206.69 ; PC4919.1 12.15,208.23 12.7,208.23 13.11,208.64 PR4960.2
PWR_5V_FB1: length 5.3
  TOP w0.203: v3(9.9,204.62) 9.91,204.62 9.91,204.52 10.19,204.24 PU4902.2
  TOP w0.254: PC4915.2 7.98,205.19 PR4955.2 PR4957.1 9.36,205.17 v3(9.9,204.62)
  BOTTOM w0.254: v2(10.72,205.21) v3(9.9,204.62)
PWR_5V_FB1_A: length 30.8
  TOP w0.254: PR4955.1 7.09,206.06 PC4915.1 7.06,206.1 7.74,206.78 9.47,206.78 9.98,207.29 v3(9.98,207.29)
  BOTTOM w0.254: v3(9.98,207.29) 9.99,207.29 v2(10.67,207.98) 10.69,207.98 10.95,208.23 10.95,210.72 13.46,213.23 13.46,221.39 15.67,223.6 22.58,223.6 PG4901.1
PWR_5V_LGATE1: length 29.1
  TOP w0.203: 14.81,205.26 14.62,205.26 PU4902.15
  TOP w0.635: 14.81,205.26 15.32,205.77 16.78,205.77 v4(17.02,206.01) ; PU4905.4 v4(28.83,222.1)
  BOTTOM w0.635: v4(28.83,222.1) 28.83,217.3 27.69,216.15 24.26,216.15 22.86,214.76 22.86,209.3 21.68,208.11 20.79,208.11 v2(19.56,206.88) 18.68,206.01 v4(17.02,206.01)
PWR_5V_PHASE1: length 20.2
  TOP w0.203: 13.02,207.23 13.02,207.07 12.45,206.5 PU4902.18
  TOP w0.635: 13.02,207.23 13.02,207.31 13.89,208.18 13.89,209.5 14.55,210.16 PC4908.2 15.62,210.54 15.62,212.72
  TOP w1.016: PL4902.1 18.69,218.87 ; PL4902.1 17.29,217.48 ; PL4902.1 18.69,216.08 ; PL4902.1 20.09,217.48
  BOTTOM w1.016: 18.69,216.08 PL4902.1 ; PL4902.1 18.69,218.87 ; PL4902.1 17.29,217.48 ; PL4902.1 20.09,217.48
  vias: v2(17.48,213.44) v4(15.85,220.52) v4(16.26,214.76) v4(16.89,218.19) v4(18.67,210.69) v4(19.43,215.39) v4(19.68,212.85) v4(20.83,217.81)
PWR_5V_SN: length 1.4
  TOP w0.635: PC4912.1 PR4951.2
PWR_5V_UGATE1: length 6.6
  TOP w0.203: PU4902.16 13.51,205.39 14.45,206.32
  TOP w0.635: PR4941.2 17.78,206.4 17.16,207.02 v2(16.26,207.02) 15.15,207.02 14.45,206.32
PWR_5V_UGATE1R: length 3.9
  TOP w0.635: PU4903.4 20.29,208.66 19.96,208.33 PR4941.1 v2(18.89,209.58)
PWR_12V_DUAL_1D0V:
  vias: v2(189.97,173.43)
PWR_BTNJ_C: length 4
  TOP w0.102: R6420.1 19.02,238 18.52,237.49 18.52,237.32 18.52,237.31 18.52,236.7 19.8,235.42 PWRSW1.5
PWR_DDR4_BT: length 3
  TOP w0.203: 41.69,181.64 41.69,181.44 41.53,181.28 PU5001.18
  TOP w0.508: 41.69,181.64 41.69,182.13 v2(41.71,182.14) PR5007.1
PWR_DDR4_BT1: length 2.8
  TOP w0.635: PR5007.2 43.84,183.31 PC5008.1 45.42,184.28 v2(45.42,184.33)
PWR_DDR4_CS: length 2.7
  TOP w0.203: PU5001.13 43.92,179.07
  TOP w0.254: 43.92,179.07 43.97,179.01 v2(44.5,179.01) 44.66,179.01 PR5003.1
PWR_DDR4_FB: length 6.1
  TOP w0.203: 40.38,176.95 40.37,176.96 40.37,177.37 40.53,177.52 PU5001.6
  TOP w0.254: PC5013.2 38.94,174.41 PR5024.2 39.2,174.68 40.58,174.68 PR5025.1 40.59,175.59 v2(40.16,176.02) 40.38,176.24 40.38,176.95
PWR_DDR4_LDOIN: length 1.2
  TOP w0.203: PU5001.19 41.13,181.17 40.69,181.61
  vias: v2(40.26,182.07)
PWR_DDR4_LG: length 15.6
  TOP w0.203: v4(43.79,180.59) 43.46,180.59 43.08,180.21 PU5001.15
  TOP w0.635: v4(51.56,174.37) 51.59,174.4 PU5003.4
  BOTTOM w0.635: v4(43.79,180.59) 43.31,180.11 43.31,179.2 44.2,178.31 v2(46.23,178.31) 48.26,178.31 49.09,177.48 49.09,176.85 v4(51.56,174.37)
PWR_DDR4_LX: length 30.4
  TOP w0.203: PU5001.16 42.7,180.62 43.4,181.32
  TOP w0.635: PC5008.2 44.37,181.79 44.32,181.74 v4(44.2,181.74) 43.81,181.74 43.4,181.32
  TOP w1.016: 62.81,178.58 PL5001.1 ; PL5001.1 64.06,177.33 ; PL5001.1 65.3,178.58 ; PL5001.1 64.06,179.82
  BOTTOM w0.635: v4(44.2,181.74) 45.97,181.74 46.23,181.48 49.82,181.48 50,181.66 v2(57.28,181.66) 59.64,181.66 v4(60.58,180.72)
  BOTTOM w1.016: PL5001.1 65.3,178.58 ; PL5001.1 64.06,179.82 ; PL5001.1 64.06,177.33 ; PL5001.1 62.81,178.58
  vias: v4(61.09,179.32) v4(61.09,177.42) v4(61.09,176.02) v4(62.23,180.47) v4(62.36,178.18) v4(62.36,176.66)
PWR_DDR4_UG: length 23.8
  TOP w0.203: 42.55,181.61 42.24,181.31 42.13,181.31 41.93,181.1 PU5001.17
  TOP w0.635: PR5005.2 61.88,185.46 61.88,184.56 v4(61.73,184.42) ; v4(42.8,182.12) 42.8,181.86 42.55,181.61
  BOTTOM w0.635: v4(42.8,182.12) 42.8,182.68 43.51,183.39 46.66,183.39 46.91,183.13 49.14,183.13 49.31,183.31 59.05,183.31 v2(59.08,183.34) 60.66,183.34 v4(61.73,184.42)
PWR_DDR4_UG1: length 5.6
  TOP w0.635: PR5005.1 60.68,188.59 v2(60.15,188.59) PR5004.1 60.1,186.75 60.08,186.77 PU5002.4
PWR_DDR4_VDDQ: length 36.2
  TOP w0.203: 39.98,177.67 PU5001.5
  TOP w0.254: PR5019.1 63.08,173.14 v3(62.31,173.91) 60.86,172.47 49.5,172.47 49.22,172.19 45.09,172.19 44.6,171.7 39.67,171.7 37.52,173.86 37.52,173.88 37.41,173.99 37.41,174.81 37.78,175.17 37.85,175.17 PC5013.1
  TOP w0.508: 39.98,177.67 39.27,176.96 39.27,175.63 PR5024.1 38.94,175.3 PC5013.1
  BOTTOM w0.254: v3(62.31,173.91) v2(63.27,173.91)
PWR_DDR4_VTTREF: length 2.5
  TOP w0.203: PU5001.4 39.44,178.67 39.19,178.92 v2(38.58,178.92)
  TOP w0.508: v2(38.58,178.92) PC5015.1
PWR_GT_BST1: length 2
  TOP w0.305: PU4602.1 11.02,78.55 11,78.57 11,78.69
  TOP w0.635: PR4601.1 11,78.69
PWR_GT_BST1_R: length 1.9
  TOP w0.635: PC4603.1 13.44,80.34 PR4601.2
PWR_GT_BST2: length 3.7
  TOP w0.305: PU4605.1 20.24,118.42
  TOP w0.635: 20.24,118.42 21.06,118.42 PR4608.1 22.41,117.86 v2(22.98,117.29)
PWR_GT_BST2_R: length 2.9
  TOP w0.635: v2(23.57,114.45) PC4608.1 22.53,115.01 PR4608.2
PWR_GT_COMP: length 5.1
  TOP w0.203: PU4401.18 14.35,58.97
  TOP w0.254: 14.35,58.97 14.06,59.26 14.03,59.26 13.82,59.46 v2(13.41,59.46) 12.95,59.92 12.46,59.92 12.16,60.22 11.85,60.22 PC4419.2 PC4418.2
PWR_GT_COMP_A: length 2.3
  TOP w0.254: PC4417.1 9.55,64.55 9.58,64.58 9.58,65 9.63,65.05 9.63,65.34 PR4439.2 9.64,65.61 9.66,65.63 v2(9.66,66.55)
PWR_GT_COMP_R: length 2.3
  TOP w0.254: v2(9.78,62.43) 10.24,62.43 10.49,62.18 PR4440.2 10.82,62.09 PC4418.1
PWR_GT_CSCOMP: length 44.7
  TOP w0.203: 14.33,58.57 PU4401.19
  TOP w0.254: v3(12.06,69.34) 11.53,69.34 v2(10.69,68.5) 8.92,66.73 8.92,62.38 9.83,61.47 PR4451.1 9.86,61.46 PC4425.1 9.92,60.16 10.57,59.51 10.93,59.51 PC4424.1 11.33,59.12 PR4457.2 12.84,59.12 13.13,58.83 13.95,58.83 14.21,58.57 14.33,58.57 ; PR4455.1 24.68,82.63 v3(24.68,81.79)
  BOTTOM w0.254: v3(24.68,81.79) 24.68,74.26 23.09,72.67 19.25,72.67 18.76,73.15 17.71,73.15 17.2,73.66 16.92,73.66 16.92,73.66 15.37,73.66 15.15,73.88 12,73.88 11.4,73.28 11.4,70 v3(12.06,69.34)
PWR_GT_CSN1: length 48.9
  TOP w0.203: PU4401.24 14.62,56.57 14.39,56.34
  TOP w0.254: 14.39,56.34 13.97,55.92 13.97,55.37 13.75,55.15 v2(13.75,55.12) 13.39,54.75 13.39,54.17 12.89,53.68 PC4420.2 PR4443.2 11.85,53.7 11.33,53.7 11.32,53.71 10.21,53.71 PR4459.2 9.65,54.01 9.65,55.91 10.01,56.26 v3(10.01,56.31)
  BOTTOM w0.254: v3(10.01,56.31) 10.46,56.31 11.07,56.93 11.07,57.73 10.64,58.17 10.64,74.38 10.9,74.64 14.64,74.64 14.64,74.64 14.8,74.64 17.86,77.7 17.86,82.19 18.4,82.73 21.15,82.73 21.89,83.47 21.89,85.06 PG4602.2
PWR_GT_CSN2: length 66.4
  TOP w0.203: PU4401.26 15.38,55.28
  TOP w0.254: v3(8.89,51.44) 9.19,51.14 10.55,51.14 PR4460.2 11.19,50.51 11.89,51.21 PR4446.2 PC4421.2 13.12,51.78 v2(13.88,52.54) 14.62,53.28 14.62,54.52 15.38,55.28
  BOTTOM w0.254: PG4604.2 21.59,95.89 21.59,94.28 21.04,93.73 12.28,93.73 8.61,90.06 8.61,55.27 9.32,54.56 9.32,51.87 v3(8.89,51.44)
PWR_GT_CSP1: length 40.1
  TOP w0.254: PR4444.1 10.59,56.05 10.62,56.08 10.62,57.05 10.53,57.14 v1(10.54,57.15) 10.24,57.45 10.24,58.12 PR4449.2
  BOTTOM w0.254: PG4601.2 21.39,85.22 21.39,83.68 20.94,83.24 18.19,83.24 17.35,82.4 17.35,77.91 14.58,75.15 14.43,75.15 14.43,75.15 11.3,75.15 ; v1(10.54,57.15) 10.13,57.56 10.13,74.6 10.69,75.15 11.3,75.15 ; 11.3,75.15 v2(11.3,75.44)
PWR_GT_CSP1_IC: length 6.5
  TOP w0.203: 13.9,56.56 14.08,56.74 14.11,56.74 14.33,56.97 PU4401.23
  TOP w0.254: 13.9,56.56 13.73,56.39 v2(13.46,56.39) 12.83,55.75 PC4420.1 PR4443.1 11.85,54.56 11.33,54.56 11.29,54.6 11.14,54.6 11.13,54.61 10.6,54.61 PR4444.2
PWR_GT_CSP2: length 58.8
  TOP w0.254: PR4448.1 9.3,52.08 9.15,52.08 8.76,52.47 v3(8.76,52.58) v2(8.76,53.92) 8.76,55.19 PR4453.2
  BOTTOM w0.254: v3(8.76,52.58) 8.81,52.63 8.81,54.35 8.1,55.06 8.1,90.27 12.07,94.23 20.83,94.23 21.08,94.49 21.08,95.94 PG4603.2
PWR_GT_CSP2_IC: length 7.5
  TOP w0.203: 14.45,55.75 14.87,56.17 PU4401.25
  TOP w0.254: 14.45,55.75 14.45,54.89 14.24,54.68 14.24,54.13 v2(13.98,53.87) 12.9,52.8 PC4421.1 PR4446.1 11.6,52.67 PR4448.2
PWR_GT_CSREF: length 14.2
  TOP w0.203: PU4401.22 14.26,57.37 13.94,57.05 13,57.05 12.95,57.1 PC4427.1
  TOP w0.254: v1(10.95,52.91) 10.87,52.91 10.66,52.69 PR4459.1 ; v3(11.85,55.52) 11.85,55.64 12.32,56.11 12.32,57.01 PC4427.1 ; PR4460.1 10.31,50.48 10.31,50.22 v1(11.23,49.3)
  BOTTOM w0.254: v3(11.85,55.52) v2(11.85,54.18) 11.85,53.88 10.95,52.98 v1(10.95,52.91) 10.95,51.79 11.23,51.51 v1(11.23,49.3)
PWR_GT_CSSUM: length 9.9
  TOP w0.203: 14.53,57.77 PU4401.21
  TOP w0.254: 14.53,57.77 13.96,57.77 13.73,57.53 13.2,57.53 13.05,57.68 11.86,57.68 11.28,58.27 PC4424.2 11.26,58.28 10.72,58.83 10.52,58.83 10.07,59.27 PC4425.2 PR4452.2 8.74,59.14 PR4449.1 8.74,56.95 PR4453.1
PWR_GT_DOUT: length 8.1
  TOP w0.203: 14.33,60.02 14.58,59.77 PU4401.16
  TOP w0.254: 14.33,60.02 14.33,60.19 13.81,60.71 13.76,60.71 13.39,61.08 13.39,61.3 v2(12.83,61.85) 12.83,62.03 PR4442.1 10.57,64.34 10.54,64.37 10.54,65.34 PR4439.1
PWR_GT_EN1: length 5.5
  TOP w0.254: PU4602.3 9.99,76.86 9.75,77.1 9.39,77.1 v2(9.37,77.12) 9,76.75 9,75.39 9.95,74.45 10.44,74.45 10.45,74.43 PR4606.2
PWR_GT_EN2: length 2.8
  TOP w0.254: PU4605.3 v3(18.7,119.33) 18.73,119.33 19.33,119.93 PR4612.2
  BOTTOM w0.254: v3(18.7,119.33) v2(18.7,120.29)
PWR_GT_FB: length 8.2
  TOP w0.203: 13.95,59.85 13.97,59.85 14.45,59.37 PU4401.17
  TOP w0.254: PC4417.2 PR4442.2 10.57,63.28 11.14,62.71 11.25,62.71 11.79,62.18 PR4440.1 11.8,61.68 11.84,61.65 PC4419.1 12.03,60.93 12.34,60.93 12.71,60.57 v2(12.79,60.57) 13.17,60.57 13.55,60.2 13.6,60.2 13.95,59.85
PWR_GT_HG1: length 18.7
  TOP w0.305: PU4602.8 13.06,78.13 12.82,78.36 v4(12.82,78.49)
  TOP w0.635: v4(13.03,92.51) 12.4,92.51 10.77,90.88 PR4604.1
  BOTTOM w0.635: v4(13.03,92.51) 12.32,91.8 v2(12.32,84.96) 12.32,80.14 12.82,79.63 v4(12.82,78.49)
PWR_GT_HG1_R: length 3.9
  TOP w0.635: PR4604.2 13.14,89.88 PR4603.1 13.72,89.45 13.72,89.44 13.5,89.22 PU4601.4
PWR_GT_HG2: length 9.7
  TOP w0.305: PU4605.8 19.89,116.38 20.32,115.95 v4(20.32,115.82)
  TOP w0.635: PR4610.1 13.84,112.39 v4(14.22,112.78)
  BOTTOM w0.635: v4(20.32,115.82) v2(18.54,115.82) 17.27,115.82 v4(14.22,112.78)
PWR_GT_HG2_R: length 6.4
  TOP w0.508: v3(15.3,110.25) 14.68,109.63 PR4610.2
  TOP w0.635: PR4610.2 13.42,109.21 PR4609.1 13.42,106.18 PU4604.4
  BOTTOM w0.508: v3(15.3,110.25) v2(15.3,109.28)
PWR_GT_ILIM: length 3.2
  TOP w0.203: PU4401.20 14.65,58.17
  TOP w0.254: 14.65,58.17 v2(13.46,58.17) 13.4,58.23 PR4457.1
PWR_GT_IOUT: length 6.5
  TOP w0.203: PU4401.13 16.04,61.68 15.49,62.23
  TOP w0.254: 15.49,62.23 14.4,63.32 v2(14.4,63.98) 14.73,64.31 14.73,65.93 PC4426.1 14.73,65.95 14.73,66.32 14.71,66.34 PR4458.1
PWR_GT_LG1: length 17.8
  TOP w0.305: PU4602.5 13.6,76.36 13.73,76.49 14.97,76.49 15.14,76.33
  TOP w0.635: PU4603.4 23.52,76.16 24.16,75.53 24.16,73.38 23.16,72.39 v2(20.52,72.39) 18.16,72.39 15.54,75.01 15.54,75.92 15.14,76.33
PWR_GT_LG2: length 8.5
  TOP w0.305: 17.91,115.32 18.2,115.61 PU4605.5
  TOP w0.635: 17.91,115.32 16.4,113.8 v3(16.4,111.25) PU4606.4
  BOTTOM w0.508: v3(16.4,111.25) v2(16.4,110.24)
PWR_GT_PWM1: length 60.3
  TOP w0.203: PU4401.28 16.44,54.63 15.95,54.14 15.95,53.35 15.72,53.11 15.72,52.86
  TOP w0.305: v3(12.53,71.95) 12.19,72.3 10.83,72.3 8.42,74.71 8.42,77.1 9.1,77.78 9.65,77.78 10.06,77.36 PU4602.2 ; 15.72,52.86 15.72,52.44 14.99,51.72 v3(14.99,51.69) 14.88,51.58 PR4465.1 ; v3(30.34,60.82) 30.34,60.83 30.29,60.88 30.29,64.79 28.76,66.32 28.55,66.32 27.87,67 27.87,67.01 26.88,68 26.24,68 v2(25.78,68.45) 25.78,68.58 24.17,70.19 21.65,70.19 20.91,70.94 v3(20.9,70.94)
  BOTTOM w0.305: v3(30.34,60.82) 30.18,60.82 29.56,60.2 29.43,60.2 29.3,60.07 24.38,60.07 19.23,54.91 16.98,54.91 15.14,53.07 15.14,51.84 v3(14.99,51.69) ; v3(12.53,71.95) 12.59,72.01 16.59,72.01 17.04,71.55 18.1,71.55 18.71,70.94 v3(20.9,70.94)
PWR_GT_PWM2: length 94.6
  TOP w0.203: 16.36,53.33 16.36,54 16.84,54.49 PU4401.29
  TOP w0.305: PR4441.1 15.93,51.41 16.25,51.73 16.25,52.11 16.32,52.19 16.32,52.85 16.36,52.88 v3(16.36,53.04) 16.36,53.33 ; PU4605.2 19.2,118.49 19.2,118.83 19.62,119.25 v3(19.81,119.25)
  BOTTOM w0.305: v3(19.81,119.25) 19.02,118.47 17.12,118.47 15.37,116.71 15.37,115.57 12.7,112.9 12.7,100.97 11.56,99.82 10.16,99.82 7.32,96.98 7.32,50.95 10.19,48.08 13.25,48.08 v2(14.95,49.79) 15.75,50.58 15.75,52.43 v3(16.36,53.04)
PWR_GT_SNB1: length 1.6
  TOP w0.559: PC4605.1 16.43,79.58 PR4605.2
PWR_GT_SNB2: length 2.4
  TOP w0.635: PR4611.2 PC4610.1 v2(24.14,108.33)
PWR_GT_SW1: length 22.9
  TOP w0.305: 13.98,77.66 13.68,77.36 PU4602.7
  TOP w0.635: 13.98,77.66 14.1,77.78 14.1,78.33 PC4603.2 15.39,78 v4(15.39,77.95)
  TOP w1.016: PL4601.1 17.87,88.38 ; PL4601.1 17.87,85.28 ; PL4601.1 16.32,86.83 ; PL4601.1 19.42,86.83
  BOTTOM w0.508: PG4601.1 19.18,85.34
  BOTTOM w0.635: v4(15.39,77.95) 15.88,78.44 v4(15.88,83.08)
  BOTTOM w1.016: PL4601.1 17.87,88.38 ; PL4601.1 16.32,86.83 ; PL4601.1 19.42,86.83 ; PL4601.1 17.87,85.28
  vias: v2(15.82,90.63) v4(15.62,88.14) v4(15.88,85.09) v4(16.89,89.79) v4(18.92,89.53)
PWR_GT_SW2: length 31
  TOP w0.305: PU4605.7 19.2,115.56 19.5,115.26
  TOP w0.635: PR4611.1 24.31,104.98 24.41,105.08 24.43,105.08 26.11,106.76 26.11,110.62 23.93,112.8 22.63,112.8 22.02,113.41 21.64,113.41 21.01,114.05 PC4608.2 20.31,114.45 19.5,115.26
  TOP w1.016: PL4602.1 18.03,99.3 ; PL4602.1 16.48,97.75 ; PL4602.1 18.03,96.2 ; PL4602.1 19.58,97.75
  BOTTOM w0.508: PG4603.1 19.71,96.29 19.3,95.89 v3(19.25,95.89)
  BOTTOM w1.016: 18.03,96.2 PL4602.1 ; PL4602.1 19.58,97.75 ; PL4602.1 18.03,99.3 ; PL4602.1 16.48,97.75
  vias: v2(18.8,105.94) v4(16,102.49) v4(16,98.93) v4(18.16,102.49) v4(18.67,100.58) v4(20.32,102.49) v4(20.7,98.3)
PWR_GT_TCP: length 38.6
  TOP w0.254: PR4455.2 v3(25.54,81.79) ; v3(11.94,70.23) 11.05,70.23 v2(10.87,70.05) 8.46,67.64 8.46,66.99 8.41,66.94 8.41,62.17 8.51,62.07 8.51,61.93 8.95,61.48 PR4451.2 8.86,61.38 PR4452.1
  BOTTOM w0.254: v3(25.54,81.79) 25.54,74.4 23.3,72.16 19.04,72.16 18.55,72.64 17.5,72.64 16.99,73.15 16.71,73.15 16.71,73.15 15.16,73.15 14.94,73.37 12.21,73.37 11.94,73.09 v3(11.94,70.23)
PWR_GT_TSNS: length 6.5
  TOP w0.203: PU4401.27 15.74,55.1
  TOP w0.254: PR4463.1 13.08,50.36 13.59,50.86 PC4428.1 13.92,51.47 14.64,52.2 14.64,52.2 15.25,52.81 v2(15.25,53.7) 15.25,54.62 15.74,55.1
PWR_GT_TSNS_R: length 39.7
  TOP w0.254: v3(13.04,48.67) 13.06,48.68 13.06,49.36 PR4463.2 13.08,49.47 13.65,48.9 PR4467.1 ; PR4468.1 11.67,81.52 v3(11.5,81.36)
  BOTTOM w0.254: v3(13.04,48.67) 10.43,48.67 10.08,49.01 10.08,54.88 9.37,55.59 9.37,77.44 10.52,78.59 v2(10.52,79.81) 10.52,80.37 v3(11.5,81.36)
PWR_GT_VCC1: length 7.4
  TOP w0.305: 9.64,75.83 10.17,76.36 PU4602.4
  TOP w0.508: 9.64,75.83 v2(9.64,75.65) 10.01,75.29 10.97,75.29 11.28,74.98 PC4604.2 11.61,74.93 11.61,74.3 12.19,73.71 12.67,73.71 PR4613.2
PWR_GT_VCC2: length 6
  TOP w0.305: PU4605.4 17.6,118.42
  TOP w0.508: 17.6,118.42 17.02,118.42 PC4609.2 16.21,119.23 v3(16.21,120.07) 16.89,120.75 PR4614.2
  BOTTOM w0.508: v3(16.21,120.07) v2(16.89,120.75)
PWR_GT_VSN: length 7.7
  TOP w0.203: PU4401.14 15.38,60.91
  TOP w0.254: PR4450.2 PC4423.2 12.92,65.89 13.41,65.39 13.41,64.62 13.72,64.32 13.72,62.99 v2(13.92,62.79) 13.92,62.76 14.17,62.51 14.35,62.51 14.38,62.48 14.53,62.48 15.38,61.63 15.38,60.91
PWR_GT_VSP: length 6.2
  TOP w0.203: 14.66,60.71 14.66,60.4 14.89,60.17 PU4401.15
  TOP w0.254: PC4422.1 PR4447.2 12.83,63.95 12.83,63.43 12.92,63.34 12.92,62.7 14.02,61.59 v2(14.02,61.34) 14.66,60.71
PWR_LED_G: length 14.9
  TOP w0.254: Q6401.6 6.46,227.25 7.16,227.94 7.16,228.86 7.31,229 8.41,229 9.32,229.92 9.32,232 R6409.2 10.88,233.03 C6402.1 11.98,233.02 13.08,233.02 14.81,234.75 PWRSW1.1
PWR_LED_Y: length 12.8
  TOP w0.254: PWRSW1.3 16.83,233.78 14.76,233.78 13.21,232.23 12.43,232.23 C6403.1 11.29,231.76 R6413.2 9.73,230.2 9.73,229.63 8.64,228.55 Q6401.3
PWR_PSYS: length 6
  TOP w0.203: PU4401.8 18.04,61.82 17.91,61.95
  TOP w0.254: 17.91,61.95 17.68,62.18 v3(17.68,62.53) 17.68,64.01 17.9,64.23 PR4471.1 17.9,65.1 17.73,65.27 17.73,65.92 PR4462.1
  BOTTOM w0.254: v3(17.68,62.53) v2(17.42,61.6)
PWR_RT6575_LDO5: length 4.7
  TOP w0.203: 15.14,203.73 15.04,203.84 PU4902.13
  TOP w0.305: PC4917.1 16.88,203.15 PG4903.1
  TOP w0.508: 15.14,203.73 15.2,203.73 15.46,203.48 15.49,203.48 v2(15.65,203.33) 15.82,203.15 PC4917.1
PWR_RT6575_PG: length 4.8
  TOP w0.102: PR4958.1 10.46,199.77 10.79,200.1 10.79,200.85 v3(11.21,201.26) 11.47,201.26 12.05,201.83 PU4902.7
  BOTTOM w0.254: v2(10.69,200.41) v3(11.21,201.26)
PWR_RT6575_VIN: length 1
  TOP w0.203: PU4902.12 14.5,203.43 14.86,203.07
PWR_V_12V_CPU_S0_VSA: length 4.5
  TOP w0.508: PR4701.1 PR4702.1 PR4703.1 PR4704.1 PR4705.1 PR4706.1 124.79,37.29
  vias: v2(125.22,41.63)
PWR_VCCIO_DRV: length 17.2
  TOP w0.508: PU4801.5 125.35,74.83 125.81,74.37 126.25,74.37 126.26,74.38 PC4807.1 PR4811.1 129.93,74.38 130.44,74.89
  TOP w0.635: 130.44,74.89 130.44,79.6 v2(129.45,80.59) 129.45,82.23 127.2,84.48 PR4810.2
PWR_VCCIO_DRV_R: length 6
  TOP w0.635: PU4802.4 123.79,84.61 123.79,84.61 PR4810.1 125.27,84.47 v2(126.7,83.05) 126.2,82.55 PC4806.1
PWR_VCCIO_FB: length 10.2
  TOP w0.254: PR4814.2 129.35,70.61 129.35,70.68 128.88,71.15 128.88,71.16 128.64,71.4 PC4811.2 128.04,71.53 127.46,70.94 PR4816.1 126.83,71.78 127.17,72.11 v2(127.71,72.11) 128.31,72.11 PC4812.2 128.66,73.36 PC4807.2 126.56,73.49 126.3,73.24 PU4801.3
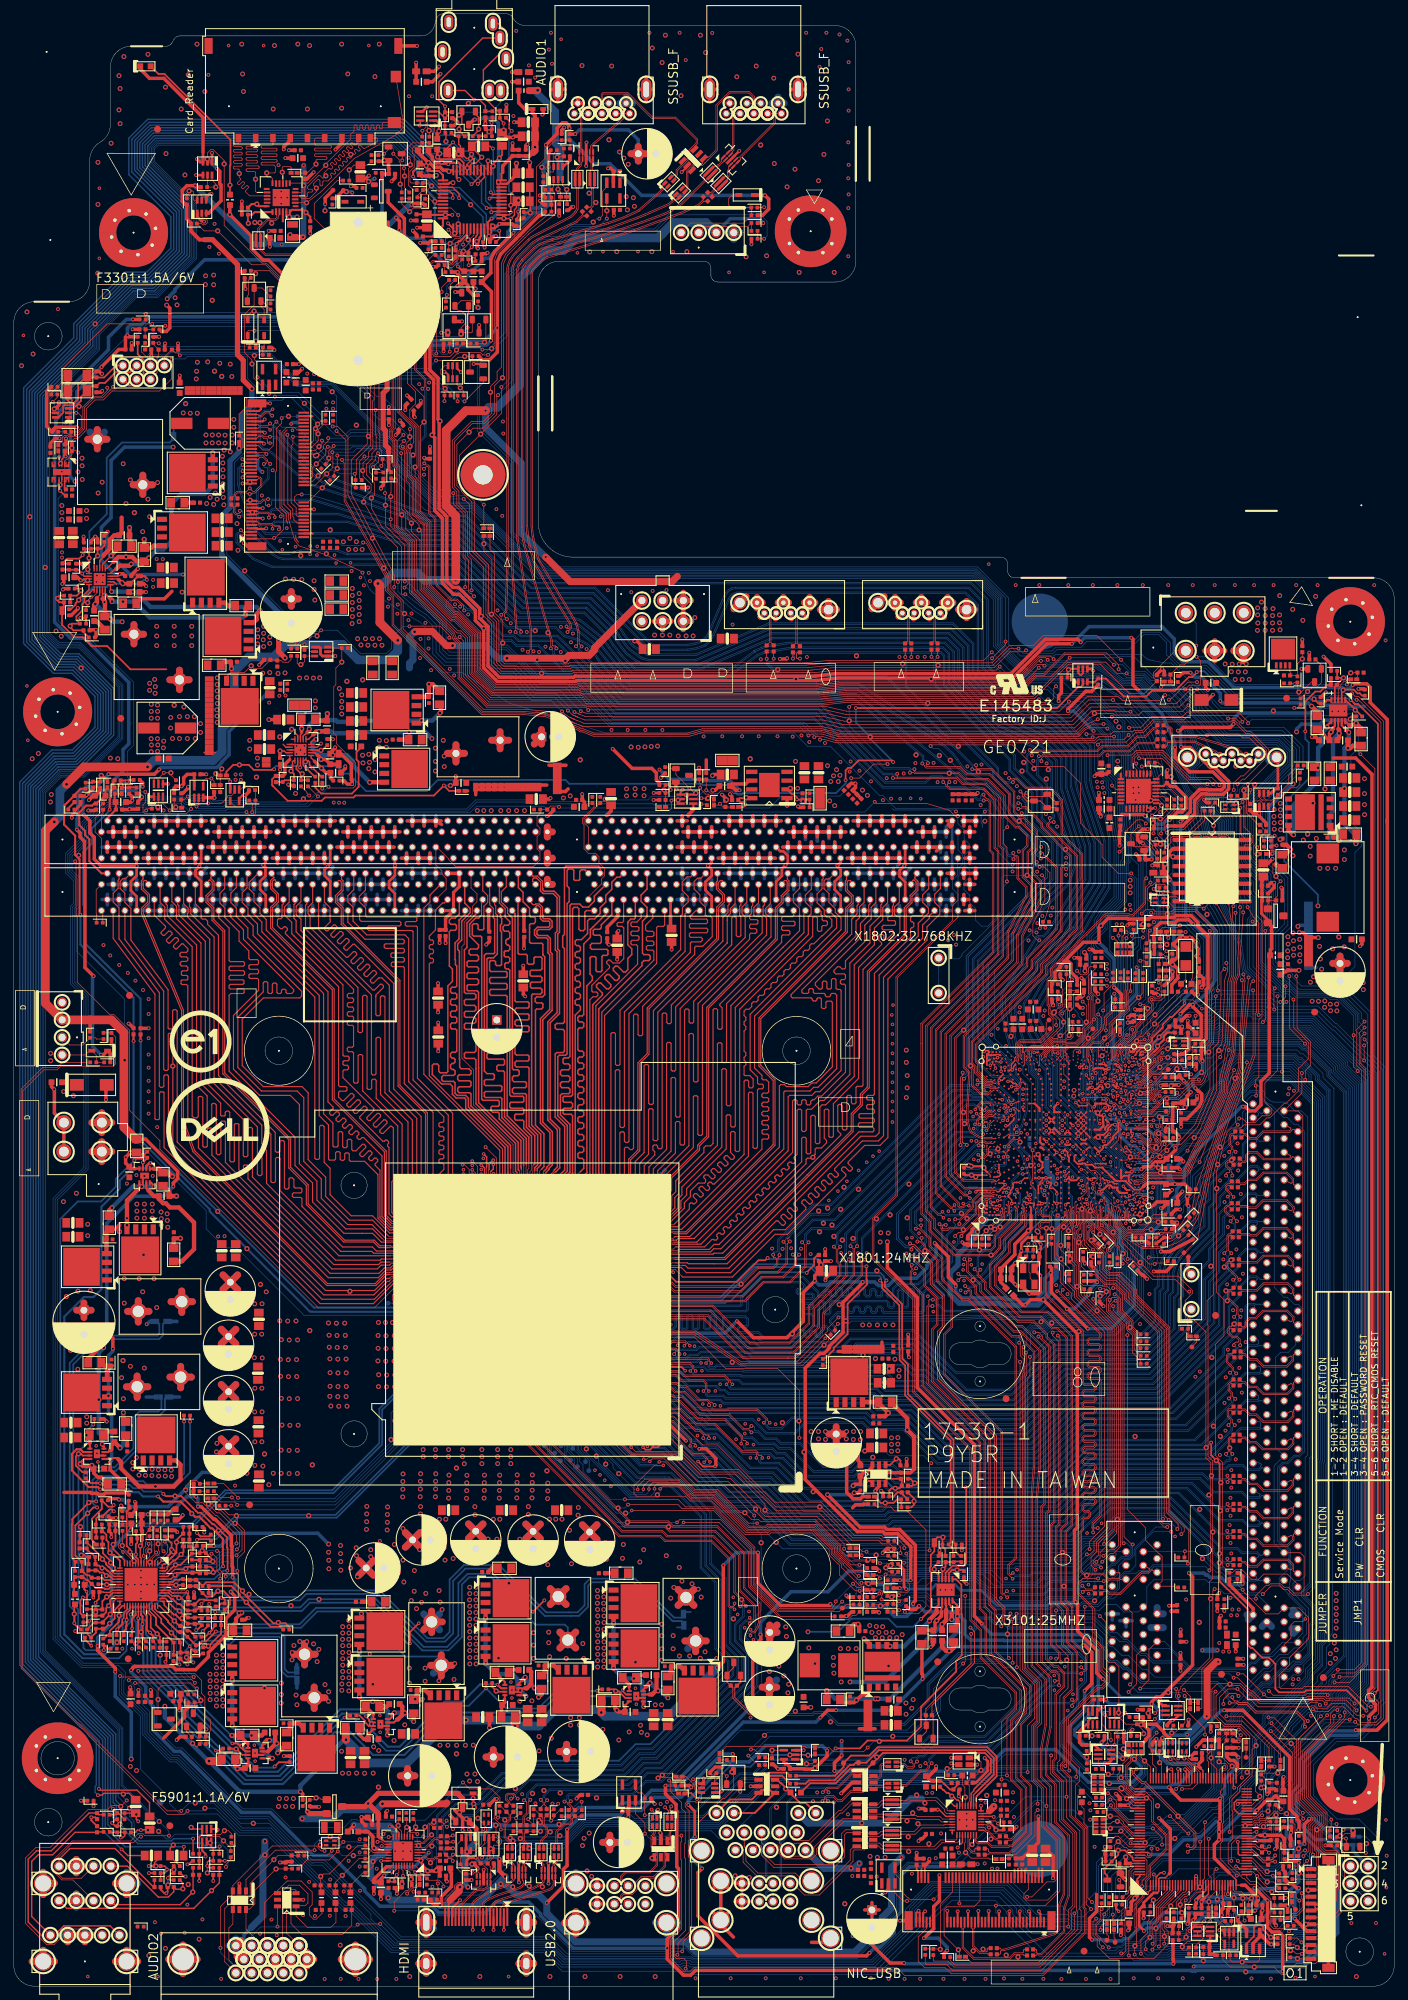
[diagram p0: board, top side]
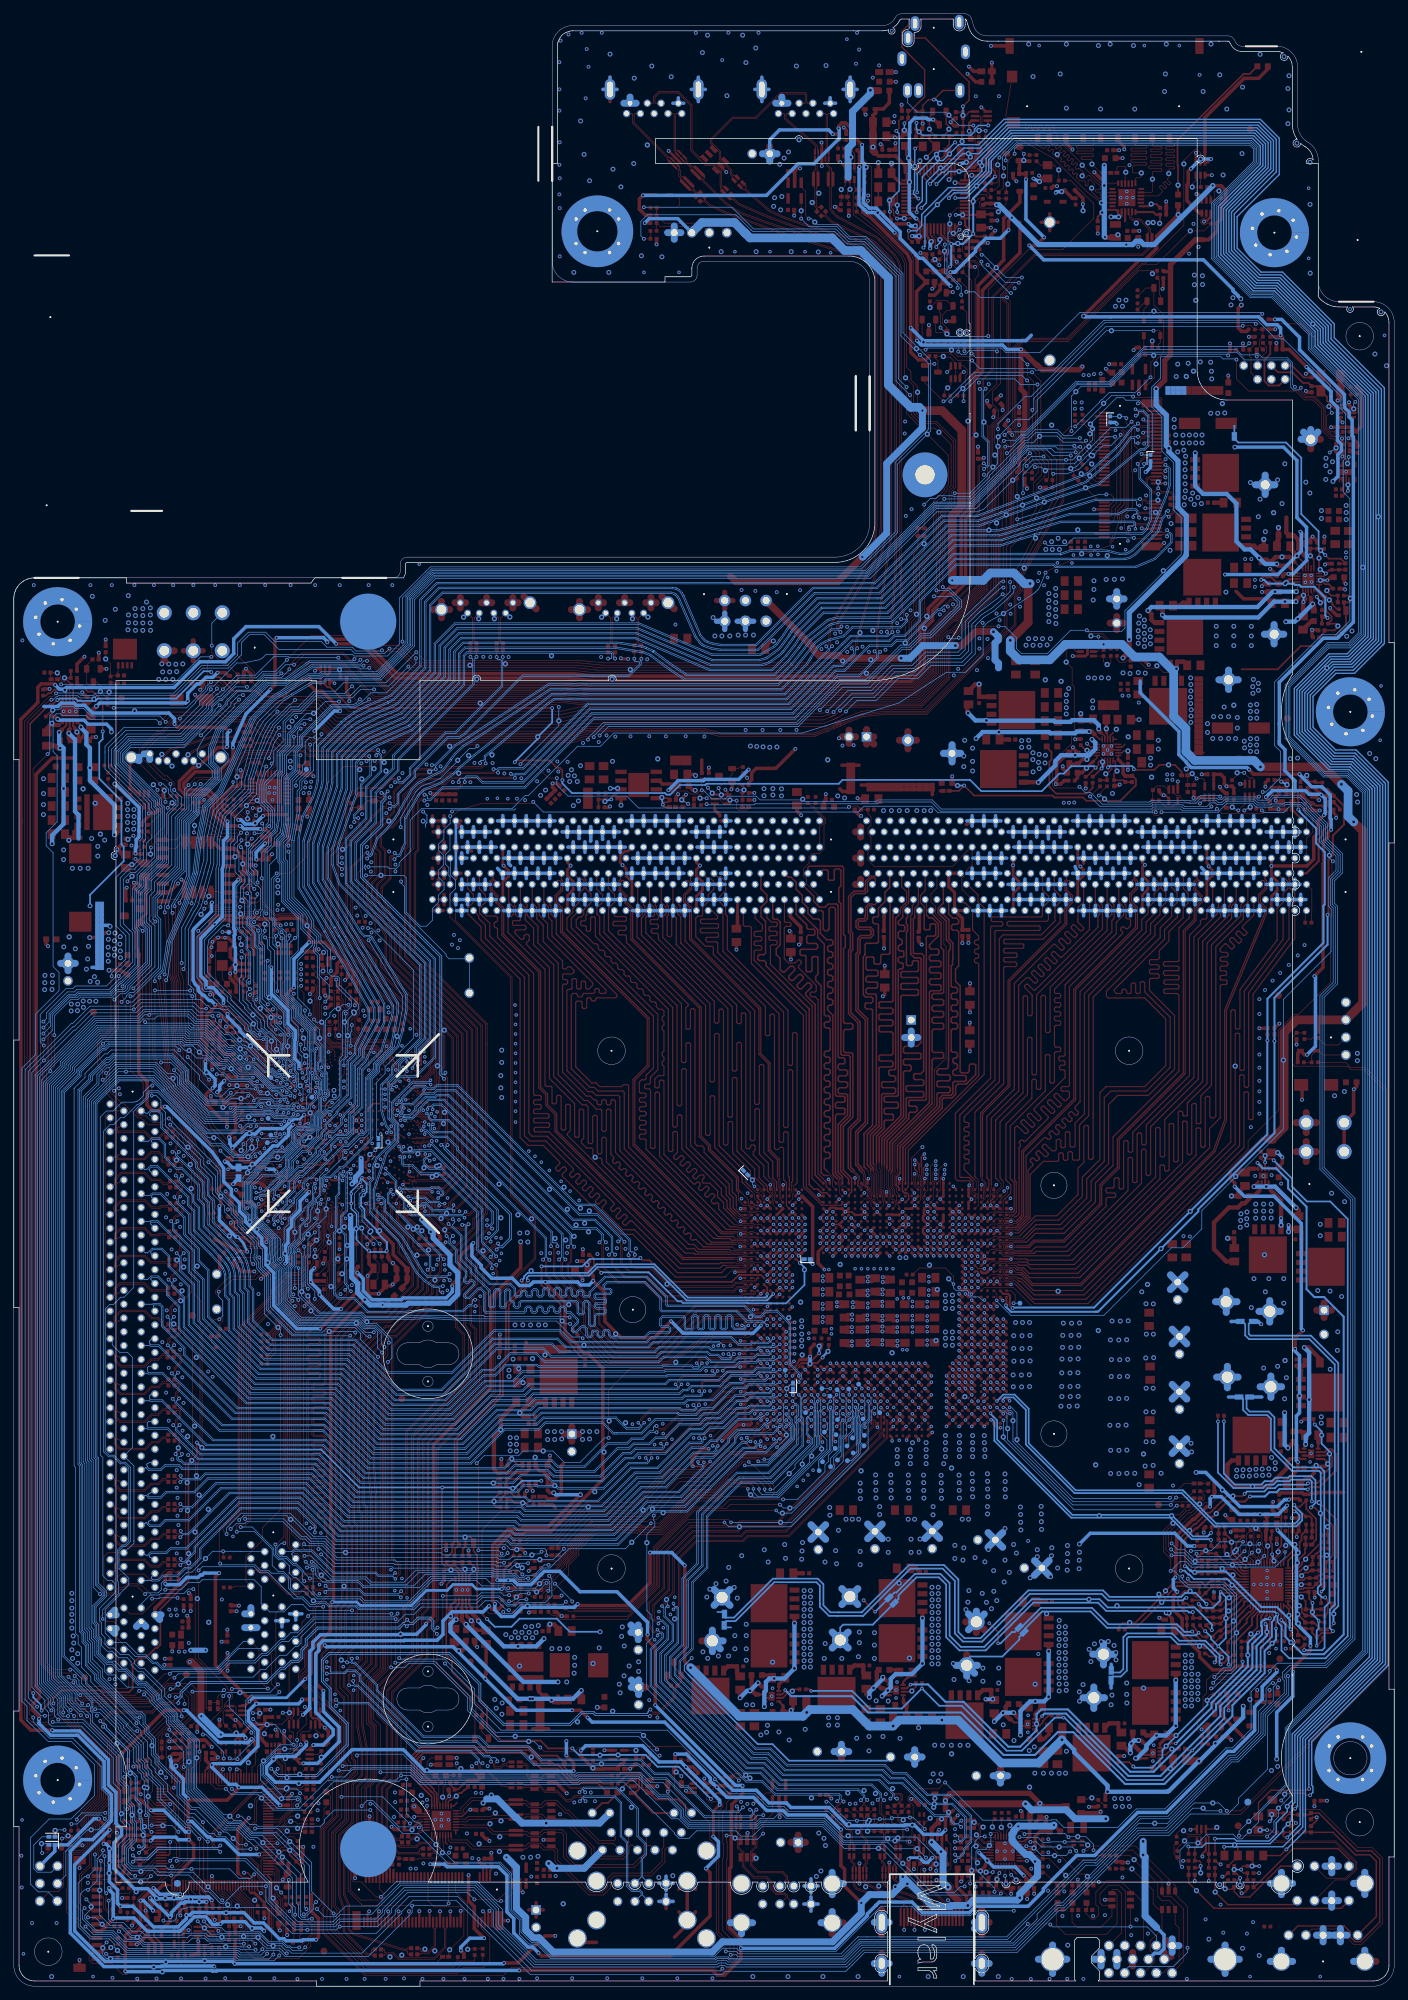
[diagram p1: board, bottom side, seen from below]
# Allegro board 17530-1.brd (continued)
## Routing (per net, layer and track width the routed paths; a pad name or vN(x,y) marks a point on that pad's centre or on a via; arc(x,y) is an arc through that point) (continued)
PWR_VCCIO_FB1: length 5.6
  TOP w0.254: PR4812.1 124.7,70.9 125.6,70 v2(126.26,70) 127.46,70 127.94,70.48 128.02,70.48 128.04,70.51 PR4814.1 128.57,70.5 128.57,69.95 128.6,69.93 128.6,69.38 PR4813.1
PWR_VCCIO_FB2: length 3.3
  TOP w0.254: PR4813.2 130.05,69.37 130.43,69.75 v2(130.43,70.23) 130.43,70.64 129.54,71.53 PC4811.1
PWR_VCCIO_FB3: length 2.4
  TOP w0.254: PR4811.2 129.91,73.49 v2(130.53,72.87) 130.12,72.47 PC4812.1
PWR_VCCIO_SS: length 3.3
  TOP w0.254: PC4805.1 128.46,76.15 128.21,76.4 v2(127.86,76.4) 126.97,75.51 PU4801.4
PWR_VCCIO_VCC: length 4.9
  TOP w0.508: PU4801.6 124.4,75.24 123.82,74.67 123.36,74.67 122.66,73.96 PC4804.1 PR4808.2 121.82,72.71 v2(121.62,72.51)
PWR_VCCIO_VCCSA_EN: length 316.5
  TOP w0.254: v3(171.4,190.35) 171.4,190.29 170.74,189.63 170.24,189.63 168.24,187.63 164.9,187.63 164.08,186.81 160.81,186.81 158.22,189.41 157.14,189.41 R4801.2 156.87,189.17 156.86,189.17 156.62,188.93 U4801.3 ; PU4701.3 135,59.88 136.03,60.91 136.53,60.91 136.55,60.93 136.89,60.93 136.9,60.91 137.61,60.91 137.99,61.28 137.99,72.17 v3(137.92,72.24) ; v3(197.18,42.44) 197.64,42.9 197.64,182.85 194.78,185.71 194.31,185.71 194.18,185.86 193.73,186.31 v3(193.69,186.31) ; v3(195.97,39.91) 194.94,40.94 194.94,41.01 193.11,42.85 187.23,42.85 186.95,42.58 183.3,42.58 182.78,43.1 182.78,46.67 181.88,47.58 180.88,47.58 179.45,49 179.22,49 178.76,49.46 178.76,54.61 174.7,58.67 174.7,75.68 173.48,76.9 v3(173.48,78.74) ; PU4801.1 124.02,73.2 v3(123.57,73.2)
  BOTTOM w0.254: v3(173.48,78.74) v2(172.76,78.02) 172.47,77.72 155.45,77.72 149.96,72.24 v3(137.92,72.24) 127.33,72.24 126.37,73.2 v3(123.57,73.2) ; v3(193.69,186.31) 193.56,186.31 193.36,186.51 191.03,186.51 190.69,186.17 188.16,186.17 187.82,186.51 176.46,186.51 172.51,190.47 171.52,190.47 v3(171.4,190.35) ; v3(197.18,42.44) 197.18,41.86 196.06,40.75 196.06,40 v3(195.97,39.91)
PWR_VCCIO_VIN: length 6.3
  TOP w0.508: 119.44,91.95 PR4801.1 PR4802.1 PR4803.1 PR4804.1 PR4806.1 PR4809.1 PR4805.1 PR4807.1
  vias: v2(124.84,90.91)
PWR_VCCSA_BOOT: length 4.6
  TOP w0.305: 136.7,54.76 136.7,55.15 PU4701.10
  TOP w0.635: PR4709.1 136.7,52.32 136.7,52.82 136.72,52.83 v2(136.72,53.59) 136.72,54.44 136.7,54.46 136.7,54.76
PWR_VCCSA_BOOT_R: length 3.8
  TOP w0.635: PC4704.2 134.49,49.15 135.05,48.59 v2(135.53,48.59) 135.74,48.59 136.14,49 PR4709.2
PWR_VCCSA_CS: length 3.3
  TOP w0.254: PR4708.2 137.51,60.29 v2(136.67,60.29) 135.95,60.29 135.5,59.84 PU4701.2
PWR_VCCSA_FB: length 5.1
  TOP w0.254: PU4701.4 134.5,60.28 v2(134.62,60.4) 135,60.78 PC4708.2 135.01,61.42 135.56,61.42 135.59,61.44 136.13,61.44 PR4714.2 136.33,61.43 136.42,61.52 137.13,61.52 137.21,61.43 PR4716.1
PWR_VCCSA_FB1: length 4.3
  TOP w0.254: PC4708.1 134.95,62.37 134.95,63.3 134.56,63.69 PR4715.1 134.56,64.96 v2(134.62,65.02) 133.83,65.02 PG4701.2
PWR_VCCSA_LG: length 16.3
  TOP w0.305: 133.69,54.55 133.69,54.92 134,55.23 PU4701.6
  TOP w0.635: v4(132.67,52.9) 132.67,53.08 133.69,54.1 133.69,54.55 ; v4(123.18,50.34) 123.95,49.57 PU4702.8
  BOTTOM w0.635: v4(132.67,52.9) 129,49.23 v2(126.95,49.23) 124.31,49.23 123.19,50.34 v4(123.18,50.34)
PWR_VCCSA_PG: length 63.6
  TOP w0.254: R4006.1 97.74,27.91 97.79,27.97 98.15,27.97 v3(99,27.11) ; PU4701.1 136.49,58.95 137.29,58.16 137.29,54.68 137.29,53.92 137.35,53.86 137.35,47.94 136.53,47.12 136.53,45.56 131.44,40.48 131.44,37.62 129.41,35.59 123.7,35.59 122.56,34.44 v3(119.08,34.44)
  BOTTOM w0.254: v3(119.08,34.44) 118.14,33.5 v2(112.45,33.5) 108.46,33.5 106.76,31.8 103.68,31.8 v3(99,27.11)
PWR_VCCSA_PHASE: length 21.2
  TOP w0.305: 135.09,54.52 135.09,55.15 135,55.24 PU4701.8
  TOP w0.635: 135.09,54.52 135.09,53.02 v4(134.49,52.43) PC4704.1
  BOTTOM w0.635: v4(134.49,52.43) 134.32,52.26 134.32,52.22 126.31,44.21 ; 126.17,44.07 v4(121.16,44.07)
  vias: v2(126.73,46.38) v4(118.75,47.62) v4(118.75,46.48) v4(118.82,45.34) v4(119.76,48.9) v4(119.89,44.07) v4(120.9,48.9) v4(122.05,48.9)
PWR_VCCSA_RF: length 3
  TOP w0.254: PU4701.5 134,59.52 133.35,60.17 v2(133.35,60.39) 133.35,60.8 PR4711.1
PWR_VCCSA_SNB: length 2.9
  TOP w0.635: PR4713.2 121.11,51.79 121.74,52.43 v2(122.33,52.43) 122.33,52.37 122.49,52.21 PC4707.1
PWR_VCCSA_UG: length 30
  TOP w0.305: PU4701.9 135.5,55.35 135.95,54.9 135.95,54.13
  TOP w0.635: PR4707.2 v4(117.78,42.84) ; 135.95,54.13 135.95,54 135.89,53.94 135.89,53.25 135.95,53.19 135.95,53.15 v4(135.9,53.1)
  BOTTOM w0.635: v4(117.78,42.84) 118.99,41.63 v2(124.84,41.63) 127,41.63 136.74,51.37 136.74,52.46 136.1,53.1 v4(135.9,53.1)
PWR_VCCSA_UG_R: length 5.8
  TOP w0.508: PU4702.1 123.95,42.68 123.46,42.19 122.86,42.19 v2(122.1,41.43) 121.75,41.08 PR4710.2 120.15,41.08 PR4707.1
PWR_VCCSA_VCC: length 6.5
  TOP w0.305: PU4701.7 134.5,54.92 134.39,54.81 134.39,54.23
  TOP w0.508: 134.39,54.23 134.39,53.63 v2(133.71,52.95) 133.48,52.72 133.48,51.82 PC4706.1 131.62,51.56 PR4712.1
PWR_VCORE_BST1: length 3.5
  TOP w0.305: 33.93,35.1 PU4502.1
  TOP w0.508: PR4501.1 32.84,36.2 33.93,35.1
  TOP w0.635: v2(31.61,36.32) PR4501.1
PWR_VCORE_BST1_R: length 1.8
  TOP w0.635: PR4501.2 35.92,36.32 PC4503.1
PWR_VCORE_BST2: length 2.2
  TOP w0.305: 52.09,39.4 PU4506.1
  TOP w0.508: PR4507.1 52.09,39.4
PWR_VCORE_BST2_R: length 1.6
  TOP w0.635: PR4507.2 54,40.49 PC4508.1
PWR_VCORE_BST3: length 2.4
  TOP w0.305: 70.42,44.8 71.14,44.07 PU4510.1
  TOP w0.508: PR4514.1 70.42,44.8
PWR_VCORE_BST3_R: length 1.6
  TOP w0.508: PC4513.1 72.09,45.82 PR4514.2
PWR_VCORE_BST4: length 2.3
  TOP w0.305: 89.17,43.41 PU4514.1
  TOP w0.508: PR4520.1 89.16,43.73 89.16,43.42 89.17,43.41
PWR_VCORE_BST4_R: length 1.6
  TOP w0.508: PC4518.1 90.53,45.06 PR4520.2
PWR_VCORE_COMP: length 5.9
  TOP w0.203: v2(23.37,59.56) 22.77,58.97 PU4401.48
  TOP w0.254: PC4405.2 26.9,59.88 PC4406.2 25.27,59.88 25.23,59.84 24.71,59.84 24.67,59.88 23.62,59.88 23.37,59.63 v2(23.37,59.56)
PWR_VCORE_COMP_A: length 2.8
  TOP w0.254: PC4404.1 28.03,61.52 28.75,61.52 28.76,61.53 v2(28.84,61.53) 28.84,61.72 28.46,62.1 28.42,62.1 28.11,62.42 28.11,62.45 PR4407.2
PWR_VCORE_COMP_R: length 2.8
  TOP w0.254: PR4408.2 28.52,60.76 28.91,60.38 v2(28.91,59.94) 28.78,59.82 PC4405.1
PWR_VCORE_CSCOMP: length 22.5
  TOP w0.203: 22.43,58.57 PU4401.47
  TOP w0.254: PR4431.1 39.92,52.03 39.37,52.58 37.59,52.58 34.32,55.85 34.32,55.86 33.94,56.24 33.93,56.24 33.24,56.93 33.24,57.16 v2(33.14,57.27) 31.9,58.5 30.14,58.5 30.13,58.49 29.69,58.49 29.68,58.5 27.88,58.5 PR4427.1 27.34,58 26.49,58.85 PC4413.1 PC4415.1 25.48,58.86 24.56,58.86 24.51,58.92 PR4433.2 24.42,58.9 23.98,58.9 23.94,58.86 23.36,58.86 23.06,58.57 22.43,58.57
PWR_VCORE_CSN1: length 35
  TOP w0.203: PU4401.36 19.64,54.35 20.27,53.72
  TOP w0.254: v3(25.15,46.61) 24.91,46.85 24.65,46.85 24.13,47.37 PC4407.2 23.95,47.43 23.39,47.99 PR4435.2 23.14,48.51 23.18,48.55 PR4412.2 23.11,49.85 23.11,49.85 23.08,49.87 20.6,52.34 20.6,53.39 20.27,53.72
  BOTTOM w0.254: 25.29,47.62 25.29,47.97 27.37,50.04 31.11,50.04 32.18,51.1 38.69,51.1 39.24,50.55 39.24,45.93 39.73,45.44 PG4502.2 ; 25.29,47.62 v2(25.02,47.62) ; 25.29,47.62 25.29,46.76 v3(25.15,46.61)
PWR_VCORE_CSN2: length 40
  TOP w0.203: PU4401.38 20.44,54.63 20.84,54.23 21.02,54.23
  TOP w0.254: v3(29.27,51.37) 27.84,49.94 27.25,49.94 26.73,49.42 PR4436.2 25.17,50.61 PR4415.2 24.46,51.3 PC4408.2 23.82,51.3 23.68,51.44 23.66,51.44 22.35,52.75 22.35,52.91 21.02,54.23
  BOTTOM w0.254: 54.11,52.18 53.82,52.18 51.21,54.79 43.77,54.79 41.41,52.43 38.33,52.43 ; 38.33,52.43 31.47,52.43 30.37,51.32 29.32,51.32 v3(29.27,51.37) ; 38.33,52.43 v2(38.33,52.68)
PWR_VCORE_CSN3: length 70.7
  TOP w0.203: 22.35,54.63 21.79,55.19 21.79,55.48 PU4401.40
  TOP w0.254: 22.35,54.63 23.15,53.83 23.43,53.83 23.44,53.82 23.45,53.82 24.25,53.02 24.27,53.02 24.69,53.02 PR4419.2 26.19,52.51 PC4410.2 27.03,52.49 PR4437.2 26.54,51.57 v3(26.42,51.57)
  BOTTOM w0.254: v3(26.42,51.57) 26.42,52.39 28.89,54.86 40.16,54.86 ; 40.16,54.86 41.5,54.86 42.7,56.06 52.48,56.06 59.39,49.15 62.78,49.15 64.41,50.78 64.41,58.39 65.08,59.06 65.75,59.73 69.43,59.73 72.14,57.02 72.42,57.02 PG4506.2 ; 40.16,54.86 v2(40.16,55.12)
PWR_VCORE_CSN4: length 99.9
  TOP w0.203: 22.04,56.57 PU4401.42
  TOP w0.254: PR4438.2 27.19,54.56 ; 27.19,54.56 27.06,54.69 26.67,54.69 26.53,54.55 26.34,54.55 PC4412.2 PR4422.2 25.07,54.55 24.88,54.55 24.07,55.36 23.75,55.36 23,56.11 22.78,56.11 22.32,56.57 22.04,56.57 ; 27.19,54.56 v3(27.19,55.37)
  BOTTOM w0.254: PG4508.2 96.83,53.39 95.66,53.39 90.02,59.03 89.6,59.03 83.5,59.03 82.7,58.23 82.7,55.18 81.68,54.15 80.49,54.15 80.49,54.15 77.25,54.15 77.24,54.15 77.14,54.15 70.29,61 65.22,61 63.14,58.92 63.14,51.31 62.26,50.42 59.92,50.42 56.76,53.58 53.01,57.33 42.17,57.33 41.23,56.39 34.09,56.39 ; v2(34.09,56.77) 34.09,56.39 ; 34.09,56.39 30.86,56.39 30.3,56.95 28.77,56.95 v3(27.19,55.37)
PWR_VCORE_CSP1: length 26.5
  TOP w0.254: v3(26.01,46.9) 25.68,46.9 PR4414.1 25.27,47.56 25.46,47.56 25.65,47.75 26.77,47.75 27.22,48.2 PR4426.2
  BOTTOM w0.254: 28.19,49.53 31.33,49.53 32.39,50.6 38.48,50.6 38.73,50.34 38.73,45.72 39.6,44.86 40.79,44.86 PG4501.2 ; 28.19,49.53 27.58,49.53 25.8,47.76 25.8,47.11 v3(26.01,46.9) ; 28.19,49.53 v2(28.19,49.25)
PWR_VCORE_CSP1_IC: length 9.5
  TOP w0.203: 21.37,53.21 20.04,54.53 PU4401.37
  TOP w0.254: PR4414.2 PC4407.1 24.16,48.35 24.16,49.69 PR4412.1 24.07,49.97 23.43,50.61 23.41,50.61 v2(22.84,51.18) 21.59,52.43 21.59,52.43 21.37,52.66 21.37,53.21
PWR_VCORE_CSP2: length 31.2
  TOP w0.254: PR4417.1 27.75,50.62 v1(28.34,51.21) 28.34,51.21 28.77,51.64 28.77,51.75 29.15,52.13 PR4429.2
  BOTTOM w0.254: PG4503.2 53.4,51.88 51,54.28 50.37,54.28 ; 50.37,54.28 43.98,54.28 41.62,51.92 31.68,51.92 30.58,50.81 28.73,50.81 v1(28.34,51.21) ; 50.37,54.28 v2(50.37,53.95)
PWR_VCORE_CSP2_IC: length 7.4
  TOP w0.203: 21.9,54.32 21.12,55.1 PU4401.39
  TOP w0.254: 21.9,54.32 21.9,54.27 v2(23.28,52.9) 23.99,52.18 PC4408.1 24.43,52.18 25.12,51.5 PR4415.1 25.46,51.5 26.28,50.69 PR4417.2
PWR_VCORE_CSP3: length 59.4
  TOP w0.254: PR4421.1 28.26,53.31 28.27,53.32 PR4432.2 29.15,54.17 v3(29.18,54.2)
  BOTTOM w0.254: v2(32.64,54.05) 32.64,54.36 ; 32.64,54.36 41.71,54.36 42.91,55.55 52.27,55.55 59.18,48.64 62.99,48.64 64.92,50.57 64.92,58.18 65.44,58.7 65.96,59.22 69.22,59.22 71.81,56.63 71.81,56.1 PG4505.2 ; 32.64,54.36 29.97,54.36 29.76,54.14 29.4,54.14 29.33,54.2 v3(29.18,54.2)
PWR_VCORE_CSP3_IC: length 7
  TOP w0.203: 22.44,55.59 22.18,55.85 22.18,55.96 21.97,56.17 PU4401.41
  TOP w0.254: 22.44,55.59 23.43,54.6 23.75,54.6 v2(24.01,54.34) 24.57,53.78 24.75,53.78 24.88,53.66 24.94,53.66 PR4419.1 25.2,53.4 25.39,53.4 25.41,53.38 PC4410.1 26.28,53.44 26.99,53.44 27.11,53.31 PR4421.2
PWR_VCORE_CSP4: length 91.3
  TOP w0.254: PR4425.1 29.6,55 30.04,55.44 PR4434.2 30.56,56.01 30.3,56.26 v3(30.1,56.26)
  BOTTOM w0.254: v3(30.1,56.26) 30.27,56.26 30.65,55.88 41.44,55.88 42.38,56.82 52.8,56.82 56.55,53.07 59.71,49.91 62.47,49.91 63.65,51.1 63.65,58.71 65.43,60.49 70.08,60.49 71.97,58.61 ; v2(71.73,58.37) 71.97,58.61 ; 71.97,58.61 76.93,53.64 77.03,53.64 77.04,53.64 80.7,53.64 80.7,53.64 81.89,53.64 83.21,54.97 83.21,55.39 83.21,58.02 83.71,58.52 89.81,58.52 95.45,52.88 96.77,52.88 PG4507.2
PWR_VCORE_CSP4_IC: length 8.8
  TOP w0.203: 23.31,56.51 22.91,56.51 22.48,56.95 22.44,56.95 22.42,56.97 PU4401.43
  TOP w0.254: 23.31,56.51 23.67,56.51 v2(23.93,56.26) 24.05,56.13 24.37,56.13 PR4422.1 PC4412.1 26.91,56.01 27.56,56.01 27.65,55.91 29.24,55.91 PR4425.2
PWR_VCORE_CSREF: length 29.2
  TOP w0.203: v1(25.15,57.12) 24.99,56.97 23.14,56.97 22.92,56.97 22.62,57.28 22.58,57.28 22.49,57.37 PU4401.44
  TOP w0.254: v1(25.48,49.23) 25.48,49.17 26.12,48.53 PR4436.1 ; v1(25.15,57.12) 25.23,57.04 PC4416.1 ; v3(24,46.58) 23.67,46.58 23.15,47.1 PR4435.1 ; v3(27.38,51.44) 28.13,52.18 PR4437.1 ; PR4438.1 28.08,54.75 28.32,54.99 v3(28.32,55.37)
  BOTTOM w0.254: v1(25.48,49.23) 25.48,49.33 24.38,50.42 v2(24.38,53.29) 24.38,56.36 v1(25.15,57.12) 25.25,57.02 25.25,55.83 26.26,54.81 27.76,54.81 v3(28.32,55.37) ; v1(25.48,49.23) 26.52,50.27 26.52,50.57 v3(27.38,51.44) ; v1(25.48,49.23) 24,47.75 v3(24,46.58)
PWR_VCORE_CSSUM: length 20.7
  TOP w0.203: 23.19,57.45 22.91,57.45 22.6,57.77 PU4401.45
  TOP w0.254: 23.19,57.45 24.74,57.45 25.24,57.96 PC4415.2 PC4413.2 26.39,57.91 PR4428.2 27.36,56.95 27.89,56.42 28.76,56.42 v2(29.57,57.23) 30.41,57.23 31.32,56.32 31.32,55.31 PR4434.1 30.56,54.18 30.04,53.66 PR4432.1 PR4429.1 30.04,51.08 28.04,49.09 PR4426.1
PWR_VCORE_DOUT: length 6.7
  TOP w0.203: PU4401.50 22.09,59.77 22.71,60.39
  TOP w0.254: PR4407.1 26.42,62.74 26.34,62.66 25.82,62.66 PR4409.1 24.16,61.02 v2(23.43,61.02) 23.34,61.02 22.71,60.39
PWR_VCORE_DRVON: length 238.9
  TOP w0.203: PU4401.30 17.24,54.25 16.93,53.94 v3(16.93,53.85)
  TOP w0.254: PR4518.1 68.43,43.9 v1(68.43,43.13) ; v3(30.93,60.19) 30.93,60.2 30.97,60.25 30.97,63.46 30.89,63.55 30.89,65.02 29,66.9 28.82,66.9 28.72,67.01 28.72,67.01 28.34,67.38 27.12,68.58 26.67,68.58 26.42,68.83 26.41,68.83 26.04,69.21 26.04,69.22 24.26,70.99 v2(23.37,70.99) 21.99,70.99 v3(21.67,71.31) ; v1(47.9,38.9) 48.22,39.22 PR4512.1 ; PR4506.1 30.12,34.42 29.84,34.14 v1(29.26,34.14) ; v3(12.5,72.84) 12.45,72.88 11.14,72.88 10.48,73.55 PR4606.1 ; PR4612.1 19.33,120.88 18.76,120.31 18.76,120.07 18.55,119.86 17.69,119.86 v3(17.46,119.63) ; v1(84.48,42.77) 84.71,43 PR4524.1
  BOTTOM w0.254: v1(84.48,42.77) 78.53,42.77 75.98,40.22 71.34,40.22 v1(68.43,43.13) 65.91,40.61 62.65,40.61 56.15,34.11 53.95,34.11 49.16,38.9 v1(47.9,38.9) 47.78,38.9 39.44,30.57 38.75,29.87 33.53,29.87 v1(29.26,34.14) 29.26,34.16 24.61,38.81 24.61,39.71 24.61,40.33 19.35,45.59 19.35,46.58 19.35,48.97 17.72,50.61 17.72,52.78 17.4,53.09 17.4,53.38 v3(16.93,53.85) ; v3(21.67,71.31) 21.33,71.65 18.82,71.65 18.34,72.14 17.29,72.14 16.78,72.64 16.5,72.64 16.5,72.64 12.69,72.64 v3(12.5,72.84) ; v3(16.93,53.85) 16.89,53.82 16.89,52.74 16.33,52.18 16.33,48.61 15.22,47.5 9.95,47.5 6.73,50.71 6.73,111.12 9.27,113.67 12.64,113.67 14.78,115.81 14.78,116.96 v3(17.46,119.63) ; v3(16.93,53.85) 17.33,54.25 19.46,54.25 24.18,58.98 29.04,58.98 29.67,59.61 29.8,59.61 30.37,60.19 v3(30.93,60.19)
PWR_VCORE_EN1: length 3.1
  TOP w0.254: PR4506.2 32.16,34.42 v2(32.22,34.36) 32.25,34.36 33.1,33.51 PU4502.3
PWR_VCORE_EN2: length 3.2
  TOP w0.254: PR4512.2 50.09,39.22 50.91,38.39 50.91,38.21 51.42,37.7 PU4506.3
PWR_VCORE_EN3: length 2.7
  TOP w0.254: PR4518.2 69.3,43.37 69.9,42.78 v2(69.9,42.75) 70,42.65 PU4510.3
PWR_VCORE_EN4: length 3.5
  TOP w0.254: PR4524.2 86.94,43 87.2,42.75 v2(87.2,42.74) 87.62,42.74 88.6,41.76 PU4514.3
PWR_VCORE_FB: length 8.3
  TOP w0.203: 23.79,60.39 23.32,60.39 22.3,59.37 PU4401.49
  TOP w0.254: 26.97,60.77 PC4406.1 25.26,60.77 24.97,60.48 v2(24.92,60.48) 24.83,60.39 23.79,60.39 ; 26.97,60.77 PR4408.1 ; 26.97,60.77 27.03,60.77 27.01,60.78 27.01,61.65 PC4404.2 25.87,61.72 PR4409.2
PWR_VCORE_HG1: length 6.2
  TOP w0.305: 36.3,35.23 35.97,34.9 PU4502.8
  TOP w0.635: v4(38.23,33.78) 39.27,34.82 PR4504.1 ; v4(37.03,35.61) 36.68,35.61 36.3,35.23
  BOTTOM w0.635: v4(37.03,35.61) 37.06,35.59 37.66,35.59 v2(38.08,35.16) 38.23,35.01 v4(38.23,33.78)
PWR_VCORE_HG1_R: length 3.7
  TOP w0.559: PR4503.1 39.97,37.2 PR4504.2
  TOP w0.635: PU4501.4 41.3,38.07 PR4503.1
PWR_VCORE_HG2: length 6.1
  TOP w0.305: PU4506.8 54.47,38.7 54.83,39.05 54.83,39.31
  TOP w0.635: v4(57.94,38.33) PR4510.1 ; 54.83,39.31 v4(55.13,39.61)
  BOTTOM w0.635: v4(55.13,39.61) 56.65,39.61 v2(56.67,39.59) v4(57.94,38.33)
PWR_VCORE_HG2_R: length 6.3
  TOP w0.635: v3(59.21,41.58) 59.08,41.45 PR4510.2 58.38,41.9 PR4509.1 59.59,42.9 PU4505.4
  BOTTOM w0.508: v3(59.21,41.58) v2(58.17,41.58)
PWR_VCORE_HG3: length 6.6
  TOP w0.305: PU4510.8 73.18,43.84 73.69,44.35
  TOP w0.635: v4(76.03,41.86) 76.03,41.87 76.48,42.32 PR4516.1 ; 73.69,44.35 v4(74.09,44.75)
  BOTTOM w0.635: v4(76.03,41.86) 76.03,42.6 v2(75.43,43.2) 74.09,44.54 v4(74.09,44.75)
PWR_VCORE_HG3_R: length 3.8
  TOP w0.635: PR4516.2 76.92,45.45 PR4515.1 78.22,46.46 PU4509.4
PWR_VCORE_HG4: length 6.3
  TOP w0.305: PU4514.8 91.2,42.97 91.64,43.4
  TOP w0.635: PR4522.1 v4(94.77,41.77) ; 91.64,43.4 v4(92.18,43.94)
  BOTTOM w0.635: v4(92.18,43.94) v2(93.33,42.79) 93.75,42.79 v4(94.77,41.77)
PWR_VCORE_HG4_R: length 3.8
  TOP w0.635: PU4513.4 96.55,46.33 PR4521.1 95.21,45.33 PR4522.2
PWR_VCORE_ILIM: length 3
  TOP w0.203: PU4401.46 22.38,58.17
  TOP w0.254: 22.38,58.17 23.42,58.17 v2(23.5,58.09) 23.51,58.1 PR4433.1
PWR_VCORE_IOUT: length 6.4
  TOP w0.203: 21.48,61.65 21.06,61.23 PU4401.1
  TOP w0.254: PC4414.1 PR4430.1 22.87,64.15 v2(22.87,63.21) 22.87,63.03 22.69,62.86 22.69,62.67 21.67,61.65 21.48,61.65
PWR_VCORE_LG1: length 18.1
  TOP w0.305: PU4502.5 36.89,33.01
  TOP w0.635: 36.89,33.01 37.45,33.01 v4(37.47,33.02) ; v4(31.65,44.32) PU4503.4 ; PU4504.4 v4(31.65,37.72)
  BOTTOM w0.635: v4(37.47,33.02) 37.26,33.02 35.89,34.39 35.89,34.86 v2(34.43,36.31) 33.05,36.31 v4(31.65,37.72) 31.65,44.32 v4(31.65,44.32)
PWR_VCORE_LG2: length 17.8
  TOP w0.305: v4(54.15,36.38) 54.15,36.66 54.13,36.68 PU4506.5
  TOP w0.635: PU4508.4 v4(50.06,41.91) ; v4(50.06,48.51) PU4507.4
  BOTTOM w0.635: v4(50.06,48.51) v4(50.06,41.91) 50.72,41.25 v2(52,41.25) 52.76,41.25 54.15,39.86 v4(54.15,36.38)
PWR_VCORE_LG3: length 18.2
  TOP w0.305: PU4510.5 74.05,42.15 v4(74.19,42.01)
  TOP w0.635: PU4512.4 68.35,47.6 v4(68.35,46.74) ; PU4511.4 68.35,54.3 v4(68.35,53.31)
  BOTTOM w0.635: v4(74.19,42.01) v2(73.37,42.83) 72.95,43.26 72.95,44.5 72.24,45.21 69.88,45.21 v4(68.35,46.74) v4(68.35,53.31)
PWR_VCORE_LG4: length 17.9
  TOP w0.305: PU4514.5 91.2,40.75 91.26,40.69 v4(91.26,40.49)
  TOP w0.635: PU4516.4 86.89,53.19 86.89,53.19 v4(86.89,52.58) ; v4(86.89,46.02) 86.89,46.2 86.89,46.2 PU4515.4
  BOTTOM w0.635: v4(91.26,40.49) 91.26,42.57 91.03,42.8 91.03,44.07 90.54,44.56 v2(89.83,44.56) 88.35,44.56 v4(86.89,46.02) v4(86.89,52.58)
PWR_VCORE_PWM1: length 29.6
  TOP w0.203: PU4401.34 18.84,54.08 19.11,53.81
  TOP w0.254: PU4502.2 33.53,34.01 33.22,34.32
  TOP w0.305: PR4413.1 20.19,50.69 19.74,51.15 v3(19.74,51.23) 19.65,51.23 19.26,51.63 19.26,53.67 19.11,53.81 ; v1(31.65,35.15) 31.67,35.18 32.37,35.18 33.22,34.32 33.22,34.32
  BOTTOM w0.305: v1(31.65,35.15) 26.47,40.34 26.47,41.03 21.21,46.29 v2(21.21,47.96) 21.21,49.76 v3(19.74,51.23)
PWR_VCORE_PWM2: length 56.6
  TOP w0.203: PU4401.33 18.44,53.94
  TOP w0.254: PU4506.2 51.71,38.2 51.47,38.44 51.47,38.63 51.21,38.89 51.21,38.94 v1(51.03,39.12)
  TOP w0.305: 18.44,53.94 18.44,53.77 18.65,53.57 v3(18.65,52.45) 18.65,50.44 19.14,49.95 PR4424.1
  BOTTOM w0.305: v1(51.03,39.12) 50.66,39.48 47.53,39.48 38.51,30.45 33.86,30.45 25.2,39.12 25.2,39.96 25.2,40.58 19.94,45.83 19.94,46.34 19.94,46.34 19.94,49.3 18.44,50.8 v2(18.44,51.31) 18.44,52.24 v3(18.65,52.45)
PWR_VCORE_PWM3: length 82.4
  TOP w0.203: PU4401.32 18.04,53.38
  TOP w0.254: PU4510.2 70.6,43.15
  TOP w0.305: PR4456.1 18.11,50.13 18.03,50.2 v3(18.03,53.29) 18.04,53.3 18.04,53.38 ; 70.6,43.15 v1(70.08,43.68)
  BOTTOM w0.305: v1(70.08,43.68) 70.04,43.71 67.54,43.71 65.02,41.2 62.41,41.2 55.91,34.7 54.19,34.7 51.82,37.07 v2(51.82,38) 51.82,38.69 51.82,39.39 51.12,40.09 47.28,40.09 38.25,31.06 34.83,31.06 25.81,40.09 25.81,40.83 20.55,46.09 20.55,49.56 19.15,50.95 19.15,52.09 19.26,52.2 19.26,52.7 18.9,53.06 18.83,53.06 18.73,53.16 18.16,53.16 v3(18.03,53.29)
PWR_VCORE_PWM4: length 98.4
  TOP w0.203: PU4401.31 17.64,54.03
  TOP w0.254: v1(88.24,42.9) 88.24,42.72 88.71,42.25 PU4514.2
  TOP w0.305: 17.64,54.03 17.64,53.77 17.13,53.27 v1(17.13,51.82) 17.13,50.98 PR4403.1
  BOTTOM w0.305: v1(17.13,51.82) 17.13,50.2 v2(17.68,49.66) 18.77,48.56 18.77,46.82 18.77,45.35 23.44,40.68 23.44,39.13 33.29,29.29 38.99,29.29 40.03,30.33 46.49,36.79 48.76,36.79 52.05,33.5 56.59,33.5 62.73,39.64 76.22,39.64 78.6,42.01 87.35,42.01 v1(88.24,42.9)
PWR_VCORE_SCLK: length 4.4
  TOP w0.102: PR4411.1 19.66,64.67 19.96,64.36 19.96,64.3 19.99,64.27 19.99,63.89 19.96,63.87 19.96,63.71 19.99,63.68 19.99,63.35 v2(19.68,63.05) 19.68,62.23 19.24,61.78 PU4401.5
PWR_VCORE_SDIO: length 4.7
  TOP w0.102: PR4410.1 20.78,64.32 20.88,64.22 20.88,64.11 v2(20.9,64.08) 20.98,64.01 20.98,63.1 21.08,63 21.08,62.62 20.81,62.35 20.52,62.35 20.04,61.87 PU4401.3
PWR_VCORE_SNB1: length 3
  TOP w0.508: PC4505.1 32.19,53.28 v2(33.02,54.1)
  TOP w0.559: PC4505.1 32.19,52.72 31.8,52.32 PR4505.2
PWR_VCORE_SNB2: length 1.4
  TOP w0.635: PR4511.2 PC4510.1
PWR_VCORE_SNB3: length 1.6
  TOP w0.635: PR4517.2 70.12,60.55 69.31,60.55 PC4515.1
PWR_VCORE_SNB4: length 1.4
  TOP w0.635: PC4520.1 PR4523.2
PWR_VCORE_SW1: length 17.3
  TOP w0.305: 36.83,34.01 PU4502.7
  TOP w0.635: PC4503.2 37.87,35.05 36.83,34.01
  TOP w1.016: PL4501.1 45.07,41.78 ; PL4501.1 43.52,40.23 ; PL4501.1 41.97,41.78 ; PL4501.1 43.52,43.33
  BOTTOM w0.508: PG4501.1 41.02,43.18
  BOTTOM w1.016: 41.97,41.78 PL4501.1 ; PL4501.1 43.52,40.23 ; PL4501.1 43.52,43.33 ; PL4501.1 45.07,41.78
  vias: v2(36.32,43.18) v4(38.73,41.02) v4(38.76,43.92) v4(38.76,42.27) v4(40.89,42.16) v4(41.02,40.77) v4(45.09,43.69) v4(45.62,42.65) v4(45.59,41.27)
PWR_VCORE_SW2: length 27.5
  TOP w0.305: PU4506.7 55.09,38.2 55.54,38.65
  TOP w0.635: 55.54,38.65 55.65,38.65 56.29,39.28 56.29,40.49 PC4508.2
  TOP w1.016: PL4502.1 61.94,48.02 ; PL4502.1 60.39,46.47 ; PL4502.1 63.49,46.47 ; PL4502.1 61.94,44.92
  BOTTOM w0.254: PL4502.1 61.94,47.23 61.42,47.75 56.77,47.75 54.31,50.22 54.31,50.6 53.84,51.07
  BOTTOM w1.016: 61.94,44.92 PL4502.1 ; PL4502.1 63.49,46.47 ; PL4502.1 60.39,46.47 ; PL4502.1 60.79,45.32
  vias: v2(52.02,43.74) v3(51.56,48.12) v4(57.3,46.08) v4(57.3,43.92) v4(59.59,46.08) v4(59.59,44.17) v4(61.59,44.25) v4(63.78,44.42) v4(63.88,46.74)
PWR_VCORE_SW3: length 28
  TOP w0.305: PU4510.7 74.07,43.15
  TOP w0.635: 74.07,43.15 74.32,43.15 74.96,43.79 74.96,45.54 PC4513.2
  TOP w1.016: 79.12,51.29 PL4503.1 ; PL4503.1 81.41,48.99 ; PL4503.1 79.12,48.99 ; PL4503.1 81.41,51.29
  BOTTOM w0.254: PG4505.1 75.54,52.37 79.83,52.37 80.27,51.94 PL4503.1
  BOTTOM w1.016: 79.12,51.29 PL4503.1 ; PL4503.1 81.41,48.99 ; PL4503.1 81.41,51.29 ; PL4503.1 79.12,48.99
  vias: v2(70.23,47.52) v4(75.3,51.21) v4(75.31,49.4) v4(75.31,47.47) v4(77.5,51.28) v4(77.5,49.76) v4(77.62,47.73) v4(80.04,47.47) v4(82.45,49.63) v4(82.58,47.47)
PWR_VCORE_SW4: length 17.8
  TOP w0.305: 92.1,42.25 PU4514.7
  TOP w0.635: 92.1,42.25 92.48,42.25 93.12,42.89 PC4518.2
  TOP w1.016: PL4504.1 100.34,50.01 ; PL4504.1 98.79,51.56 ; PL4504.1 98.79,48.46 ; PL4504.1 97.24,50.01
  BOTTOM w0.254: PG4507.1 96.09,51.97
  BOTTOM w1.016: 97.64,48.87 PL4504.1 ; PL4504.1 98.79,48.46 ; PL4504.1 98.79,51.56 ; PL4504.1 97.24,50.01
  vias: v2(90.07,46.94) v4(93.88,52.43) v4(93.88,50.77) v4(93.88,48.87) v4(93.88,47.22) v4(95.53,50.77) v4(95.53,48.87) v4(96.44,47.83) v4(97.92,47.83) v4(99.47,47.5) v4(100.15,48.44)
PWR_VCORE_TCP: length 14.6
  TOP w0.254: PR4431.2 38.62,52.07 37.21,52.07 v2(33.68,55.6) 32.74,56.55 32.74,56.77 31.53,57.97 PR4427.2 PR4428.1
PWR_VCORE_TSNS: length 6.9
  TOP w0.203: PU4401.35 19.24,54.28 19.84,53.68 19.84,53.32
  TOP w0.254: PR4464.1 PC4429.1 21.16,50.64 v2(20.77,51.03) 19.84,51.95 19.84,53.32
PWR_VCORE_TSNS_R: length 28.1
  TOP w0.254: v3(21.97,46.99) 22.11,47.13 PR4469.1 22.12,47.99 PR4464.2 ; PR4466.1 38.42,32.45 v3(37.8,31.83)
  BOTTOM w0.254: v3(37.8,31.83) 37.62,31.65 35.07,31.65 33.58,33.14 33.58,34.24 v2(33.04,34.78) 27.05,40.77 27.05,41.27 21.97,46.35 v3(21.97,46.99)
PWR_VCORE_VCC: length 7.3
  TOP w0.203: PU4401.7 18.44,61.99 18.31,62.12 18.31,63.74 18.33,63.76 v2(18.33,63.76) 18.34,63.76 18.59,64.02 18.59,64.57
  TOP w0.508: PC4402.1 18.47,68.2 18.47,67.11 PR4401.2 18.49,66.99 18.49,66.07 18.61,65.96 PR4462.2 18.59,65.92 18.59,64.57
PWR_VCORE_VCC1: length 4.2
  TOP w0.305: 33.93,32.33 PU4502.4
  TOP w0.508: PR4525.2 32.05,31.86 v2(32.41,31.51) 33.39,31.51 PC4504.2 33.93,32.05 33.93,32.33
PWR_VCORE_VCC2: length 4.3
  TOP w0.305: PU4506.4 51.51,36.61
  TOP w0.508: 51.51,36.61 51.31,36.41 PC4509.2 50.72,35.79 50.01,36.5 PR4526.2
PWR_VCORE_VCC3: length 3.4
  TOP w0.254: PU4510.4 71.14,41.6 71.09,41.55
  TOP w0.508: 71.09,41.55 71.09,41.07 PC4514.2 70.66,40.64 PR4527.2
PWR_VCORE_VCC4: length 4.6
  TOP w0.305: PU4514.4 88.54,40.63
  TOP w0.508: PR4528.2 87.1,40.23 v2(87.38,39.95) 87.6,39.73 PC4519.2 88.54,40.63
PWR_VCORE_VRMP: length 9.8
  TOP w0.203: 17.27,62.07 17.64,61.7 PU4401.9
  TOP w0.254: PR4402.2 16.65,70.31 16.65,69.45 PC4403.1 16.75,69.15 16.36,68.76 16.36,63.78 16.81,63.32 v2(16.81,62.92) 16.81,62.52 17.27,62.07
PWR_VCORE_VSN: length 7.4
  TOP w0.203: PU4401.52 21.5,60.95 21.69,61.14
  TOP w0.254: 21.69,61.14 21.88,61.14 22.91,62.17 22.95,62.17 23.57,62.79 v2(23.57,64.31) 23.57,64.62 24.5,65.54 24.54,65.54 PC4411.2 PR4420.2
PWR_VCORE_VSP: length 6.2
  TOP w0.203: PU4401.51 21.97,60.17 22.25,60.44 22.25,60.79
  TOP w0.254: PC4409.1 24.55,63.74 PR4418.2 24.59,63.7 24.59,62.89 v2(24.23,62.53) 23.36,61.66 23.12,61.66 22.25,60.79
PWR_VDDQ: length 25
  TOP w0.508: PR5027.1 PR5030.1 PR5028.1 PR5029.1 PR5026.1 PR5015.1 PR5017.1 PR5018.1 PR5020.1 PR5021.1 PR5022.1 PR5023.1 77.22,173.99 ; PR5006.1 PR5008.1 PR5010.1 PR5011.1 PR5012.1 PR5013.1 77.55,176.86 ; PR5019.2 65.75,173.14
  TOP w1.016: 75.4,179.92 PT5001.1 ; PT5001.1 76.45,182.03 ; PT5001.1 76.45,179.92 ; PT5001.1 75.4,180.97 ; 69.21,180.48 PL5001.2 ; PL5001.2 70.46,181.72 ; PL5001.2 70.46,179.23 ; PL5001.2 71.7,180.48
PWR_VDDQ_PG: length 138.9
  TOP w0.203: 42.85,177.32 42.65,177.52 PU5001.10
  TOP w0.254: v3(127.41,177.32) 127.17,177.55 122.38,177.55 121.3,176.47 120.88,176.47 120.52,176.11 v3(120.52,174.68) ; 42.85,177.32 42.85,176.9 v3(43.26,176.49) 44.55,175.2 R4802.2 ; v3(122,185.14) 151.16,185.14 154.18,188.16 154.55,188.16 154.89,188.5 U4801.2
  BOTTOM w0.254: v3(120.52,174.68) 120.52,174.22 119.13,172.82 105.65,172.82 105.42,172.59 104.89,172.59 103.5,173.99 99.81,173.99 99.64,174.17 80.48,174.17 79.93,174.73 61.44,174.73 59.82,173.1 51.05,173.1 48.51,175.64 47.88,175.64 46.8,176.72 43.49,176.72 v3(43.26,176.49) ; v3(127.41,177.32) 127.41,177.37 124.09,180.68 v2(124.09,180.96) 122,183.05 v3(122,185.14)
PWR_VDDQ_PG_ISOLATE: length 4.8
  TOP w0.254: R4803.1 152.67,190.55 v2(152.81,190.7) 152.92,190.8 U4801.6 154.24,190.19 154.48,189.94 154.66,189.94 154.89,190.17 U4801.5
PWR_VDDQ_S3_EN: length 4.4
  TOP w0.203: PU5001.7 41.13,176.94 40.97,176.78 40.97,176.77
  TOP w0.254: 40.97,176.77 40.94,176.75 40.94,176.31 41.64,175.62 v2(41.79,175.62) 41.61,175.43 R5001.1 R5002.1
PWR_VDDQ_S5_EN: length 13.4
  TOP w0.203: PU5001.8 41.53,176.58 41.48,176.53 v3(41.48,176.53)
  TOP w0.254: R5003.2 30.8,175.92 31.78,176.91 v2(32.69,176.91) 34.04,176.91 34.77,176.17 37.36,176.17 37.46,176.28 v3(37.72,176.28)
  BOTTOM w0.254: v3(37.72,176.28) 37.72,176.48 37.97,176.73 41.27,176.73 41.48,176.53 v3(41.48,176.53)
PWR_VDDQ_SNB: length 1.4
  TOP w0.635: PC5014.1 PR5016.2
PWR_VDDQ_TON: length 4.1
  TOP w0.203: PU5001.9 41.93,176.86 42.05,176.74
  TOP w0.254: 42.05,176.74 v3(42.4,176.39) 43.59,175.2 PR5009.2
  BOTTOM w0.254: v3(42.4,176.39) 42.26,176.53 42.26,177.33 v2(42.25,177.34)
PWR_VDDQ_VDDP: length 4.7
  TOP w0.203: PU5001.12 43.63,178.67 43.94,178.36
  TOP w0.508: PR5002.1 PC5002.1 45.16,177.7 v2(44.52,177.7) 44.52,177.78 43.94,178.36
PWR_VDDQ_VIN: length 14
  TOP w0.254: PR5009.1 43.69,173.61 44.55,172.75 48.98,172.75 49.96,173.73 49.96,174.09 49.96,177.37 49.66,177.67 49.66,178.77 50.29,179.4 50.29,179.58 PC5003.1
  vias: v2(50.55,189.23)
PWR_VDDQ_VIOP: length 5.4
  TOP w0.203: PU5001.11 43.08,177.92 43.56,177.44
  TOP w0.508: PR5001.2 45.87,175.04 PC5001.1 45.23,175.77 v2(44.57,176.43) 43.56,177.44
PWR_VTT: length 1.7
  TOP w0.203: PU5001.20 40.21,180.62 ; 39.01,179.88 39.43,179.47 PU5001.2
  vias: v2(38.53,180.97)
PWRBTN_N: length 456.9
  TOP w0.102: SB1.BE46 162.79,133.71 v1(163.05,133.45) ; U2401.34 179.51,16.58 v3(180.14,15.95) 180.14,15.8 181.66,14.27 182.47,14.27 183.29,13.46 184.56,13.46 184.87,13.14 R9920.1 ; C9904.1 19.51,237.57 19.51,238.43 19.02,238.91 R6420.2 19.02,239.94 C6404.1 19.11,239.98 R6417.2 20.77,240.54 21.91,240.54 v3(21.95,240.51) ; v3(195.65,136.27) v3(195.65,134.09) ; v3(56.73,201.61) 56.72,201.61 56.71,201.6 56.26,201.6 56.16,201.7 56.16,202.36 56.13,202.39 56.13,202.79 56.16,202.82 56.16,208.55 53.38,211.33 51.82,214.1 v2(51.82,215.57) 52.25,216 52.25,217.75 51.08,218.92 51.08,220.44 51.89,221.25 51.89,222.02 52.5,222.63 52.5,224.31 52.5,224.71 52.43,224.79 v3(52.43,228.32) ; v3(170.58,187.96) 168.39,185.77 155.85,185.77 153.32,183.24 120.34,183.24 117.36,183.91 82.78,183.91 81.98,184.22 81.91,184.25 81.86,184.3 81.83,184.3 81.83,184.31 81.78,184.32 81.76,184.33 81.59,184.42 81.56,184.42 81.39,184.49 v3(81.23,184.56)
  BOTTOM w0.102: v3(180.14,15.95) 180.55,15.54 183,15.54 184.81,17.35 184.81,20.5 183.68,21.62 183.68,23.03 183.74,23.09 183.74,23.18 184.51,23.94 184.51,28.35 185.6,29.44 185.6,33.08 190.19,37.67 194.52,37.67 195,38.14 195,39.68 195.13,39.82 195.13,39.86 195.51,40.23 195.51,41.43 197.38,43.31 197.38,132.35 v3(195.65,134.09) 191.26,138.48 191.08,138.48 188.57,141 182.3,141 181.34,141.96 174.04,141.96 174.01,141.92 174,141.92 173.17,141.1 170.27,141.1 170.17,141 170.1,141 169.72,140.61 169.72,140.15 167.92,138.35 167.92,138.07 166.64,136.79 166.3,136.79 166.27,136.76 166.23,136.76 163.05,133.58 v1(163.05,133.45) ; v3(52.43,228.32) 52.22,228.52 52.22,229.97 41.77,240.42 22.04,240.42 v3(21.95,240.51) ; v3(81.23,184.56) 78.59,187.2 75.53,187.2 72.36,190.37 69.41,190.37 67.51,192.28 62.79,192.28 61.67,193.39 61.67,197.49 61.62,197.54 60.14,198.99 v3(56.73,201.61) ; v3(195.65,136.27) 196.17,136.79 196.17,140.76 192.43,144.5 191.44,144.5 191.06,144.88 186.56,144.88 185.29,146.15 185.29,146.58 183.29,148.58 183.29,152.37 183.67,152.75 184.58,153.67 184.58,160.53 183.3,161.81 182.53,161.81 181.23,163.11 181.23,165.78 180.9,166.11 180.9,171.11 186.31,176.52 186.31,178.98 186.31,178.98 186.31,179.38 184.31,181.37 183.82,181.86 176.1,181.86 172.59,185.37 172.59,185.86 170.97,187.48 170.79,187.66 170.74,187.66 170.58,187.82 v3(170.58,187.96)
PWRBTN_N_CN: length 1.3
  TOP w0.102: TP9905.1 185.19,11.63 R9920.2
PWRGD_PS: length 9.2
  TOP w0.203: U2401.123 162.26,18.18 162.1,18.33
  TOP w0.254: 162.1,18.33 162.1,18.62 161.37,19.35 161.31,19.35 160.98,19.68 v2(160.02,19.68) 160.02,19.03 159.07,18.07 R2435.2 159.05,18.06 158.06,17.07 158.06,16.37 158.43,16 Q2407.D
PWRGD_VPP: length 86.4
  TOP w0.102: U4010.2 26.8,171.2 26.47,170.87 v3(26.48,170.87) ; PR5202.2 100.32,174.81 v3(100.32,173.23) 100.53,173.23 101.06,172.69 102,172.69 102.43,173.13 103.95,173.13 104.35,172.72 105.78,172.72 106.41,173.35 PU5201.7
  BOTTOM w0.102: v3(26.48,170.87) 26.79,170.56 30.48,170.56 30.73,170.81 34.86,170.81 35.16,170.51 65.61,170.51 66.93,171.83 74.8,171.83 75.06,171.58 85.34,171.58 v2(85.7,171.93) 85.8,171.83 91.87,171.83 92.41,172.36 96.57,172.36 96.95,171.98 98.83,171.98 100.07,173.23 v3(100.32,173.23)
Q82_B: length 4.6
  TOP w0.102: Q2703.B 68.4,238.33 v2(68.2,238.13) 68.01,237.95 R2718.2
Q83_B: length 5.8
  TOP w0.102: R2719.2 61.93,242.46 v3(61.93,239.51) Q2704.B
  BOTTOM w0.102: v3(61.93,239.51) 62.87,239.51 62.89,239.53 v2(62.9,239.53)
Q84_B: length 13.5
  TOP w0.102: R2717.2 v2(67.26,243.15) 66.27,244.14 64.8,244.14 64.05,243.4 Q2702.B 63.91,243.21 64.42,242.7 64.81,242.7 65.48,242.03 65.48,240.89 64.81,240.23 Q2704.E 66.33,239.51 66.43,239.61 Q2703.E
Q84_E: length 44.7
  TOP w0.102: Q2702.E 65.88,242.47 65.74,242.33 v3(65.74,240.23) ; R2715.1 46.86,261.54 43.53,258.21 43.53,256.06 48.05,251.54 53.01,251.54 58.8,245.75 v3(58.8,239.01)
  BOTTOM w0.102: v3(65.74,240.23) 64.85,239.34 v2(64.8,239.34) 64.43,238.98 58.84,238.98 v3(58.8,239.01)
Q84_E2: length 5.3
  TOP w0.102: R2716.1 51.24,263.78 C2722.1 49.29,263.78 v2(48.6,263.09) R2715.2
Q85_B: length 4.1
  TOP w0.102: R2716.2 R2714.1 53.48,265.24 v3(53.67,265.43) 54.29,266.05 Q2701.B
  BOTTOM w0.102: v2(53.67,264.46) v3(53.67,265.43)
Q9103: length 8.1
  TOP w0.102: U6303.D 66.1,235.42 66.46,235.78 R6304.1 65.38,236.12 v2(65.33,236.07) 65.22,235.96 64.38,235.96 63.57,235.15 Q9103.5 Q9103.2
RED_CRT: length 28.7
  TOP w0.102: L5903.2 48.96,11.87 C5921.1 48.96,8.83 47.62,7.49 41.73,7.49 40.16,9.07 40.16,13.21 40.42,13.47 EU5901.3 40.89,13.84 40.72,14.02 40.11,14.02 39.52,13.44 39.52,7.69 VGA1.1
RP_AUDOUT_L: length 16.4
  TOP w0.203: AUD1.22 14.63,11.81 24.1,11.81 v2(25.93,13.64) 25.97,13.68 C3006.1 L3003.2
RP_AUDOUT_R: length 27.4
  TOP w0.203: L3004.2 C3005.1 29.78,14.97 v2(28.65,13.84) 26.09,11.28 7.66,11.28 AUD1.25
RP_LINE1_L: length 14.9
  TOP w0.203: AUD1.32 16.46,17.39 20.95,12.9 22.38,12.9 23.18,13.7 C3004.1 23.48,14.05 24.37,14.05 24.43,14.11 v2(24.49,14.11) 24.49,14.95 L3001.2
RP_LINE1_R: length 18.8
  TOP w0.203: AUD1.35 6.55,18.36 8.13,19.94 14.67,19.94 20.26,14.35 C3003.1 L3002.2
RP_MIC1_L: length 39.2
  TOP w0.203: AUD1.2 13.95,8.74 7.24,8.74 6.34,7.83 6.34,7.1 5.69,6.45 4.91,6.45 2.08,9.28 2.08,18.4 3.29,19.61 3.72,19.61 3.72,19.61 5.43,19.61 10.9,25.08 C3010.1 12.31,24.84 L3005.2
RP_MIC1_R: length 24
  TOP w0.203: L3006.2 12.13,22.35 C3009.1 8.88,22.29 5.61,19.02 3.53,19.02 2.59,18.08 2.59,10.1 AUD1.5
RSMRST_SIO_N: length 453.1
  TOP w0.089: 161.82,136.01 161.52,136.01 161.49,135.98 161.48,135.98 161.09,135.59 161.09,135.03 161.1,135.02 161.1,134.51 SB1.BA47
  TOP w0.102: v3(65.3,229.57) 68.01,232.27 U6303.G ; v1(163.86,137.13) 163.63,137.13 163.48,136.98 162.9,136.98 161.93,136.01 161.82,136.01 ; v3(52.48,233.78) 51.21,232.51 51.21,223.39 48.9,221.08 48.9,220.86 48.9,216.17 49.23,215.58 55.12,204.42 v3(55.12,202.67) ; v3(195.5,39.17) 195.43,39.24 194.57,39.24 192.87,40.94 190.93,40.94 190.24,40.26 188.77,40.26 188.41,40.61 188.01,40.61 187.87,40.47 180.26,40.47 179.02,41.7 178.64,41.7 v3(177.29,43.05) 175.9,43.05 174.67,41.83 174.67,39.46 175.72,38.41 177.99,38.41 181.85,34.55 181.85,32.72 ; 181.85,32.72 181.84,32.7 R2434.1 ; 181.85,32.72 R2474.1 ; v3(161.8,184.61) 159.68,184.61 159.48,184.8 156.47,184.8 156.06,184.61 153.72,182.27 119.94,182.27 118.75,182.57 117.16,182.93 82.53,182.93 82.46,183 81.62,183.33 81.61,183.33 81.46,183.39 81.26,183.5 81.21,183.52 81.16,183.54 80.92,183.64 80.64,183.76 80.53,183.81 79.82,184.26 v3(79.43,184.65) ; R9906.1 128.17,54.23 128.27,54.33 v3(128.27,54.48)
  BOTTOM w0.102: v3(161.8,184.61) 161.93,184.46 163.35,183.04 163.44,182.92 164.25,181.43 165.38,178.87 166.11,176.08 166.27,175.56 166.38,175.28 166.52,174.83 166.52,173.46 170.06,169.92 170.07,169.91 170.17,169.81 170.87,166.87 170.99,166.29 171.02,166.06 171.02,162.59 171.37,161.32 171.44,161.09 172.1,158.72 172.66,157.08 172.9,156.25 173.42,155.5 173.46,155.41 173.62,155.12 174.71,153.07 174.71,145.13 174.33,144.75 174.3,144.75 174.02,144.48 173.94,144.3 173.94,143.91 173.8,143.77 173.66,143.63 173.66,142.93 ; v3(65.3,229.57) 65.07,229.57 60.85,233.78 v3(52.48,233.78) ; 173.66,142.93 181.74,142.93 182.6,142.07 182.7,141.96 188.97,141.96 191.48,139.45 191.66,139.45 198.35,132.75 198.35,41.49 196.02,39.17 v3(195.5,39.17) ; 173.66,142.93 172.97,142.93 172.13,142.09 171.88,142.09 171.43,141.63 170.12,141.63 169.97,141.48 169.03,141.48 166.55,139 166.55,138.64 166.19,138.28 165.94,138.28 164.8,137.13 v1(163.86,137.13) ; v3(79.43,184.65) 77.85,186.23 75.06,186.23 71.88,189.41 69.01,189.41 67.11,191.31 62.39,191.31 60.71,192.99 60.71,197.07 59.46,198.3 58.08,199.17 57.76,199.42 56.08,200.9 55.12,201.87 v3(55.12,202.67) ; v3(128.27,54.48) 128.62,54.48 129.96,55.83 131.72,55.83 132.64,54.91 140.97,54.91 142.01,53.87 143.28,53.87 144.45,52.7 156.25,52.7 158.39,50.56 158.39,49.67 158.85,49.22 159.22,49.22 160.5,47.93 161.47,47.93 163.5,45.9 164.19,45.9 165.32,44.77 175.17,44.77 v2(176.2,43.74) 176.89,43.05 v3(177.29,43.05)
RSMRST_SIO_N_1: length 7.5
  TOP w0.102: U2401.58 179.35,26.18 179.58,26.4 179.58,26.43 180.52,27.38 v2(180.52,27.48) 180.52,27.49 180.52,27.63 179.89,28.27 179.89,30.99 180.71,31.81 R2434.2
RTCRST_N_CN: length 1.8
  TOP w0.102: v3(169.77,152.7) 169.62,152.7 169.56,152.77 R9919.2
  BOTTOM w0.102: v3(169.77,152.7) 169.72,152.65 TP9904.1
RTL_ISOLATE_N: length 5
  TOP w0.102: U3101.20 140.99,23.8
  TOP w0.305: 140.99,23.8 141.2,23.6 141.55,23.6 141.55,23.57 142.1,23.03 142.1,22.86 v2(142.31,22.64) 142.37,22.58 143.29,22.58 R3103.2 R3106.1
S0_5V_EN: length 4.7
  TOP w0.102: U4201.3 7.36,220.9 7.58,221.12 7.7,221.12 8.42,221.84 R4201.2 9.08,222.41 v3(9.33,222.15)
  BOTTOM w0.102: v2(8.41,222.82) v3(9.33,222.15)
S3_QUK: length 7.3
  TOP w0.102: U4003.G v3(103.28,30.42) 102.84,30.86 R4001.2 101.52,30.59 U4002.3 102.09,29.35 102.23,29.21 102.23,28.8 102.13,28.7 U4002.2
  BOTTOM w0.102: v3(103.28,30.42) 104.02,31.03 v2(104.03,31.03)
S4_VPP_OR: length 5.7
  TOP w0.102: Q4002.5 95.38,171.96 95.28,171.86 v3(95.28,171.73) 95.28,170.59 95.05,170.36 93.88,170.36 93.54,170.7 R4021.1
  BOTTOM w0.102: v2(96.24,171.81) v3(95.28,171.73)
S4_VPP_OR_R: length 5.2
  TOP w0.102: R4022.1 94.82,173.99 95.17,173.63 v3(95.17,173.28) 94.74,172.85 R4023.1 C4010.1 R4021.2
  BOTTOM w0.102: v3(95.17,173.28) v2(94.21,173.28)
SATA_LED_OUT: length 31.2
  TOP w0.406: 27.42,265.67 U6401.3 27,264.21 v3(26.54,264.67)
  TOP w0.508: v3(29.44,263.27) 29.84,262.86 29.84,261.1 30.02,260.92 30.02,258.62 28.22,256.82 U6402.3 ; 27.42,265.67 27.42,270.68 21.74,276.35 19.66,276.35 18.31,277.7 LED1.K
  BOTTOM w0.508: v3(26.54,264.67) 28.04,264.67 v2(28.05,264.66) v3(29.44,263.27)
SATA_RX_CON_N0: length 6.1
  TOP w0.102: C6004.2 113.3,194.5 113.3,198.16 SATA1.5
  BOTTOM w0.102: SATA1.5 v2(112.65,198.08)
SATA_RX_CON_N2: length 15.8
  TOP w0.102: SATA2.3 178.19,177.5 178.3,177.6 178.3,178.04 177.29,179.05 171.25,180.85 168.12,180.85 167.6,181.37 167.6,182.08 167.5,182.18 167.21,182.18 167.11,182.08 167.11,181.74 167,181.64 C6007.2
  BOTTOM w0.102: v2(177.07,176.73) SATA2.3
SATA_RX_CON_N3: length 5.7
  TOP w0.102: SATA3.5 133.31,198.14 133.31,194.86 C6012.2
  BOTTOM w0.102: SATA3.5 v2(132.65,198.08)
SATA_RX_CON_P0: length 6.1
  TOP w0.102: SATA1.6 113.51,198.16 113.51,194.49 C6003.2
  BOTTOM w0.102: SATA1.6 v2(114.83,198.3)
SATA_RX_CON_P2: length 15.9
  TOP w0.102: SATA2.2 178.61,177.5 178.51,177.6 178.51,178.13 177.4,179.24 171.28,181.06 168.21,181.06 167.82,181.46 167.82,182.17 167.59,182.4 166.84,182.4 C6008.2
  BOTTOM w0.102: v2(178.55,178.43) SATA2.2
SATA_RX_CON_P3: length 5.7
  TOP w0.102: C6011.2 133.53,194.82 133.53,198.17 SATA3.6
  BOTTOM w0.102: SATA3.6 v2(134.83,198.3)
SATA_RX_PCH_N0: length 97
  TOP w0.102: C6004.1 v3(112.89,192.3) ; SB1.C45 v1(142.24,132.97)
  BOTTOM w0.102: v3(112.89,192.3) 113.16,192.57 113.16,193.07 113.38,193.29 134.37,193.29 134.89,192.77 134.89,188.54 145.11,178.31 145.11,176.45 145.82,175.74 ; v1(142.24,132.97) 141.87,133.67 141.69,133.85 141.42,134.12 141.41,134.27 141.41,135.7 139.81,137.3 139.81,148.48 151.28,159.95 151.28,165.21 151.28,165.21 151.28,165.96 148.36,168.89 148.36,173.2 145.82,175.74 ; 145.82,175.74 v2(146.08,176.02)
SATA_RX_PCH_N1: length 152.9
  TOP w0.102: v1(143.02,133.87) 142.67,133.87 SB1.D46 ; v3(137.83,101.41) 138.21,101.03 138.49,101.03 138.77,100.75 138.77,100.13 144.65,94.25 145.63,94.25 147.92,91.96 147.92,75.34 147.92,75.32 147.61,71.07 147.61,46.46 149.61,44.47 149.61,37.84 149.6,37.84 148.96,34.35 148.96,30.35 150.33,28.97 150.33,23.5 152.25,21.58 152.25,13.28 151.57,11.74 151.57,8.19 151.34,7.96 151.11,7.73 150.86,7.48 143.47,5.14 143.04,5.14 142.95,5.05 142.95,4.72 142.85,4.62 C6210.1
  BOTTOM w0.102: v1(143.02,133.87) 143.02,134.23 143.11,134.32 143.25,134.32 144.03,133.54 144.03,132.4 145.6,130.83 145.6,125.76 144.64,124.8 144.64,122.59 145.38,121.86 147.28,119.96 147.66,119.05 ; 147.66,119.05 v2(147.35,118.87) ; 147.66,119.05 147.84,118.63 147.84,116.88 148.28,116.44 148.28,112.16 144.3,108.19 141.55,103.42 140.39,102.27 139.06,101.41 v3(137.83,101.41)
SATA_RX_PCH_N1_C: length 7.1
  TOP w0.102: C6210.2 141.17,4.62 141.03,4.76 139.89,4.76 139.27,5.38 ; NGFF2.43 138.75,8.44 138.89,8.31 138.89,5.77 139.27,5.38 ; v2(139,5.12) 139.27,5.38
SATA_RX_PCH_N2: length 75.8
  TOP w0.102: v1(143.59,133.1) SB1.F44 ; C6007.1 165.7,182 165.58,182.12 165.2,182.12 163.96,180.87 162.82,180.87 161.45,179.51 157.74,179.51 157.07,178.83 147.68,178.83 147.49,178.64 v3(147.49,178.28)
  BOTTOM w0.102: v2(152.37,164.67) 151.98,164.67 ; 151.98,164.67 151.98,159.66 140.51,148.19 140.51,137.36 141.88,135.99 141.88,134.41 143.11,133.19 143.17,133.13 143.21,133.1 v1(143.59,133.1) ; 151.98,164.67 151.98,166.25 149.06,169.18 149.06,173.82 146.91,175.97 146.91,178.28 147.2,178.57 147.39,178.57 147.49,178.47 v3(147.49,178.28)
SATA_RX_PCH_N3: length 82.3
  TOP w0.102: v1(144.57,130.31) 145.17,130.31 145.2,130.27 145.52,130.27 145.67,130.43 145.76,130.85 SB1.L41 ; C6012.1 v3(132.96,192.56)
  BOTTOM w0.102: v1(144.57,130.31) 145.04,130.31 145.14,130.41 145.14,130.55 144.03,131.66 141.72,131.66 138.9,134.48 138.9,148.86 150.37,160.32 150.37,165.59 147.45,168.51 147.45,172.82 144.2,176.07 144.2,177.65 133.3,188.54 133.3,189.33 ; 133.3,189.33 133.3,192.21 v3(132.96,192.56) ; 133.3,189.33 v2(132.92,189.33)
SATA_RX_PCH_P0: length 97.1
  TOP w0.102: v1(141.48,133.39) 141.69,133.44 141.85,133.68 SB1.C46 ; C6003.1 113.58,193.21 113.41,193.04 113.41,192.42 113.53,192.3 v3(113.91,192.3)
  BOTTOM w0.102: 122.1,193.08 113.47,193.08 113.37,192.98 113.37,192.42 113.49,192.3 v3(113.91,192.3) ; 122.1,193.08 134.28,193.08 134.67,192.68 134.67,188.45 144.89,178.22 144.89,176.36 148.15,173.11 148.15,168.8 151.07,165.88 151.07,165.3 151.07,160.03 139.6,148.57 139.6,137.21 141.2,135.61 141.2,134.27 141.2,134.04 141.48,133.76 v1(141.48,133.39) ; 122.1,193.08 v2(122.1,192.71)
SATA_RX_PCH_P1: length 153
  TOP w0.102: v1(142.52,134.5) 142.52,134.5 141.99,134.36 SB1.C47 ; C6209.1 142.9,5.51 143.05,5.36 143.43,5.36 150.75,7.67 151.02,7.95 151.36,8.28 151.36,11.79 152.03,13.33 152.03,21.49 150.11,23.41 150.11,28.88 148.74,30.26 148.74,34.37 149.39,37.87 149.39,44.38 147.4,46.37 147.4,71.08 147.7,75.33 147.7,75.34 147.7,91.87 145.54,94.03 144.56,94.03 138.56,100.04 138.56,100.66 138.4,100.81 138.22,100.81 v3(137.9,100.49)
  BOTTOM w0.102: v3(137.9,100.49) 138.2,100.49 138.3,100.59 138.3,101.09 138.4,101.19 139.12,101.19 140.53,102.1 141.72,103.29 143.31,106.04 143.9,107.05 144.48,108.05 148.5,112.08 148.5,116.52 148.05,116.97 148.05,118.67 147.46,120.08 145.53,122.01 ; 145.53,122.01 144.86,122.68 144.86,124.71 145.81,125.67 145.81,130.92 144.25,132.49 144.25,133.63 143.34,134.54 143.02,134.54 142.98,134.5 v1(142.52,134.5) ; 145.53,122.01 v2(145.8,122.28)
SATA_RX_PCH_P1_C: length 7.1
  TOP w0.102: v2(140.44,5.36) 140.44,4.98 ; 140.44,4.98 140.92,4.98 141.02,5.08 141.02,5.41 141.12,5.51 C6209.2 ; 140.44,4.98 139.98,4.98 139.45,5.51 139.1,5.86 139.1,8.32 139.25,8.47 NGFF2.41
SATA_RX_PCH_P2: length 75.7
  TOP w0.102: SB1.E45 143.05,132.53 v1(143.04,132.53) ; v3(147.22,179.05) 147.22,179.05 156.98,179.05 157.65,179.72 161.36,179.72 162.73,181.09 163.87,181.09 165.11,182.33 165.38,182.33 C6008.1
  BOTTOM w0.102: v2(146.33,177.27) 146.7,177.27 ; 146.7,177.27 146.7,175.88 148.84,173.73 148.84,169.09 151.77,166.17 151.77,165.01 151.77,159.74 140.3,148.28 140.3,137.27 141.67,135.9 141.67,134.32 143.04,132.95 v1(143.04,132.53) ; 146.7,177.27 146.7,178.37 147.22,178.89 v3(147.22,179.05)
SATA_RX_PCH_P3: length 82.2
  TOP w0.102: C6011.1 v3(133.84,192.56) ; v1(145.19,129.85) 145.4,130.06 145.61,130.06 145.87,130.32 145.99,130.87 146.1,130.96 146.24,130.96 SB1.M40
  BOTTOM w0.102: v1(145.19,129.85) 145.27,129.93 145.27,130.24 145.35,130.32 145.35,130.64 144.12,131.88 141.81,131.88 139.12,134.57 139.12,148.77 150.58,160.23 150.58,165.68 147.66,168.6 147.66,172.91 144.41,176.16 144.41,177.74 133.52,188.63 133.52,191.34 ; 133.52,191.34 v2(133.91,191.34) ; 133.52,191.34 133.52,192.23 v3(133.84,192.56)
SATA_TX_CON_N0: length 6
  TOP w0.102: SATA1.3 109.7,198.16 109.7,194.61 C6001.2
  BOTTOM w0.102: SATA1.3 v2(110.36,198.08)
SATA_TX_CON_N2: length 11.1
  TOP w0.102: C6006.2 166.84,180.36 171.15,180.36 174.2,178.9 174.7,178.39 174.7,177.6 174.8,177.5 SATA2.5
  BOTTOM w0.102: SATA2.5 v2(174.76,178.39)
SATA_TX_CON_N3: length 5.6
  TOP w0.102: SATA3.3 129.73,198.19 129.73,194.8 C6010.2
  BOTTOM w0.102: SATA3.3 v2(130.36,198.08)
SATA_TX_CON_P0: length 6
  TOP w0.102: SATA1.2 109.49,198.16 109.49,194.63 C6002.2
  BOTTOM w0.102: SATA1.2 v2(108.13,198.33)
SATA_TX_CON_P2: length 11.1
  TOP w0.102: SATA2.6 174.39,177.5 174.49,177.6 174.49,178.3 174.07,178.72 171.1,180.15 167.21,180.15 167.11,180.05 167.11,179.71 167,179.6 C6005.2
  BOTTOM w0.102: SATA2.6 v2(173.21,176.82)
SATA_TX_CON_P3: length 5.7
  TOP w0.102: C6009.2 129.51,194.87 129.51,198.13 SATA3.2
  BOTTOM w0.102: SATA3.2 v2(128.13,198.33)
SATA_TX_PCH_N0: length 103.1
  TOP w0.102: v3(145.54,171.36) 145.54,171.37 145.55,171.37 145.9,171.37 146,171.27 146,170.98 146.1,170.88 146.66,170.88 149.03,168.5 149.03,167.9 153.18,163.76 153.18,153.12 148.31,148.25 148.31,147.12 138.47,137.28 138.47,133.36 139,132.83 139,130.5 140.16,129.34 141.15,129.34 141.48,129.67 SB1.B38 ; C6001.1 v3(110.1,192.28)
  BOTTOM w0.102: 110.43,190.44 109.31,191.55 109.31,191.76 109.45,191.9 109.99,191.9 110.1,192 v3(110.1,192.28) ; 110.43,190.44 110.93,189.93 126.3,189.93 134.74,181.49 135.54,180.99 137.18,180.99 142,176.17 142,175.17 143.66,173.51 144.46,172.71 144.46,171.39 144.83,171.02 145.2,171.02 v3(145.54,171.36) ; 110.43,190.44 v2(110.68,190.72)
SATA_TX_PCH_N1: length 152.7
  TOP w0.102: v1(139.62,131.23) 139.86,131 140.21,131 140.77,130.43 141.37,130.43 141.56,130.25 142.17,130.25 SB1.C39 ; C6211.1 148.08,5.33 148.21,5.21 148.21,4.86 148.31,4.76 148.83,4.76 152.06,7.99 152.06,8.14 152.06,8.29 152.06,11.18 152.73,13.14 152.73,21.78 150.81,23.7 150.81,29.17 149.45,30.53 149.45,34.18 150.09,37.56 150.09,37.64 150.09,37.64 150.09,44.67 148.09,46.66 148.09,70.49 148.53,75.27 148.53,92.03 145.83,94.73 144.85,94.73 139.26,100.33 139.26,101.28 137.86,102.68 137.26,102.68 v3(136.84,102.25)
  BOTTOM w0.102: 138.99,102.67 137.25,102.67 v3(136.84,102.25) ; 138.99,102.67 140.08,102.67 140.86,103.45 143.79,108.48 147.92,112.61 147.92,115.39 146.12,120.71 144.44,122.39 144.44,124.89 145.28,125.73 145.28,128.05 142.32,131.01 139.85,131.01 v1(139.62,131.23) ; 138.99,102.67 v2(138.99,102.29)
SATA_TX_PCH_N1_C: length 14.6
  TOP w0.102: 143.79,4.11 v2(143.79,4.5) ; 143.79,4.11 144.22,4.11 144.94,4.84 146.18,4.84 146.28,4.94 146.28,5.23 146.38,5.33 C6211.2 ; 143.79,4.11 139.14,4.11 137.62,5.64 137.62,8.36 137.75,8.49 NGFF2.47
SATA_TX_PCH_N2: length 77.6
  TOP w0.102: SB1.B40 141.68,130.64 140.86,130.64 139.2,132.29 139.2,133.13 138.71,133.63 138.71,136.83 148.79,146.92 148.79,148.05 153.92,153.19 153.92,163.7 149.67,167.96 149.67,168.31 150.1,168.74 150.1,168.75 v3(150.1,169.2) ; v3(148.51,178.17) 148.91,178.17 149.09,178.35 157.27,178.35 157.94,179.02 161.65,179.02 162.81,180.18 165.09,180.18 165.1,180.18 165.26,180.18 C6006.1
  BOTTOM w0.102: 148.2,176.35 148.2,177.65 148.51,177.97 v3(148.51,178.17) ; 148.2,176.35 v2(147.8,176.35) ; 148.2,176.35 148.2,175.4 149.57,174.03 149.57,170.6 150.57,169.6 150.57,169.29 150.48,169.2 v3(150.1,169.2)
SATA_TX_PCH_N3: length 86.3
  TOP w0.102: C6010.1 v3(130.03,192.53) ; v3(144.2,174.99) 144.54,174.86 144.78,174.88 144.87,174.97 145.38,174.97 146.66,173.69 150.14,173.69 151.94,171.88 151.94,166.97 154.84,164.08 154.84,152.81 149.71,147.68 149.71,146.54 139.53,136.37 139.53,133.95 139.85,133.63 139.85,132.54 141.12,131.27 141.6,131.27 SB1.B41
  BOTTOM w0.102: v3(130.03,192.53) 130.03,192.3 129.93,192.2 129.54,192.2 129.38,192.04 129.38,188.35 132.16,185.57 ; 132.16,185.57 136.04,181.69 137.47,181.69 142.65,176.5 142.7,176.4 142.7,175.46 143.67,174.49 144.18,174.49 144.32,174.62 144.32,174.86 v3(144.2,174.99) ; 132.16,185.57 v2(132.42,185.84)
SATA_TX_PCH_P0: length 103.1
  TOP w0.102: C6002.1 v3(109.08,192.28) ; v3(145.54,170.55) 145.91,170.55 146.02,170.66 146.57,170.66 148.82,168.41 148.82,167.82 152.96,163.67 152.96,153.21 148.09,148.34 148.09,147.21 138.25,137.36 138.25,133.27 138.79,132.74 138.79,130.41 140.07,129.12 141.24,129.12 141.67,129.55 SB1.C38
  BOTTOM w0.102: v3(109.08,192.28) 109.24,192.11 109.24,192 109.09,191.85 109.09,191.46 110.84,189.71 113.31,189.71 ; 113.31,189.71 126.21,189.71 134.6,181.32 135.48,180.77 137.09,180.77 141.78,176.08 141.78,175.08 143.57,173.3 144.25,172.62 144.25,171.3 144.74,170.8 145.29,170.8 v3(145.54,170.55) ; 113.31,189.71 v2(113.31,189.33)
SATA_TX_PCH_P1: length 152.7
  TOP w0.089: 139.78,130.78 v1(139.6,130.6)
  TOP w0.102: C6212.1 148.08,4.45 148.18,4.55 148.92,4.55 152.27,7.9 152.27,8.14 152.27,11.14 152.95,13.1 152.95,21.87 151.03,23.79 151.03,29.26 149.67,30.62 149.67,34.16 150.3,37.54 150.31,37.55 150.31,44.76 148.31,46.75 148.31,70.48 148.74,75.26 148.74,92.12 145.92,94.95 144.94,94.95 139.47,100.42 139.47,101.37 137.95,102.9 137.13,102.9 v3(136.86,103.17) ; SB1.D39 142.29,130.03 141.47,130.03 141.28,130.22 140.68,130.22 140.12,130.78 139.78,130.78
  BOTTOM w0.102: v3(136.86,103.17) 137.15,102.88 139.99,102.88 140.69,103.58 141.92,105.69 ; v2(141.58,105.9) 141.92,105.69 ; 141.92,105.69 141.96,105.77 143.61,108.61 147.7,112.7 147.7,115.36 145.93,120.59 144.22,122.3 144.22,124.98 145.06,125.82 145.06,127.96 142.23,130.79 139.81,130.79 v1(139.6,130.6)
SATA_TX_PCH_P1_C: length 14.6
  TOP w0.102: 145.49,4.62 146.2,4.62 146.38,4.45 C6212.2 ; 145.49,4.62 v2(145.49,4.24) ; 145.49,4.62 145.03,4.62 144.31,3.9 139.05,3.9 137.4,5.55 137.4,8.34 137.25,8.5 NGFF2.49
SATA_TX_PCH_P2: length 77.7
  TOP w0.102: v3(150.68,168.63) 150.29,168.63 149.88,168.22 149.88,168.05 154.14,163.79 154.14,153.1 149.01,147.97 149.01,146.83 138.93,136.74 138.93,133.72 139.42,133.22 139.42,132.38 140.95,130.85 141.77,130.85 SB1.C40 ; v3(148.89,177.45) 148.89,177.85 149.18,178.13 157.36,178.13 158.03,178.81 161.74,178.81 162.9,179.96 165.34,179.96 C6005.1
  BOTTOM w0.102: 149.31,174.59 149.78,174.12 149.78,170.69 150.79,169.69 150.79,169.2 150.68,169.09 v3(150.68,168.63) ; 149.31,174.59 v2(149.59,174.87) ; 149.31,174.59 148.41,175.49 148.41,177.56 148.51,177.66 148.68,177.66 v3(148.89,177.45)
SATA_TX_PCH_P3: length 86.3
  TOP w0.102: v3(144.75,174.4) 144.87,174.66 144.96,174.75 145.29,174.75 146.57,173.47 150.05,173.47 151.73,171.79 151.73,166.88 154.62,163.99 154.62,152.9 149.49,147.77 149.49,146.63 139.32,136.45 139.32,133.86 139.64,133.54 139.64,132.45 141.03,131.06 141.76,131.06 SB1.C41 ; v3(129.16,192.53) 129.15,192.55 C6009.1
  BOTTOM w0.102: 129.16,191.54 129.16,188.27 135.95,181.47 137.38,181.47 142.47,176.38 142.48,176.35 142.48,175.37 143.58,174.27 144.27,174.27 144.4,174.4 v3(144.75,174.4) ; 129.16,191.54 v3(129.16,192.53) ; 129.16,191.54 v2(128.78,191.54)
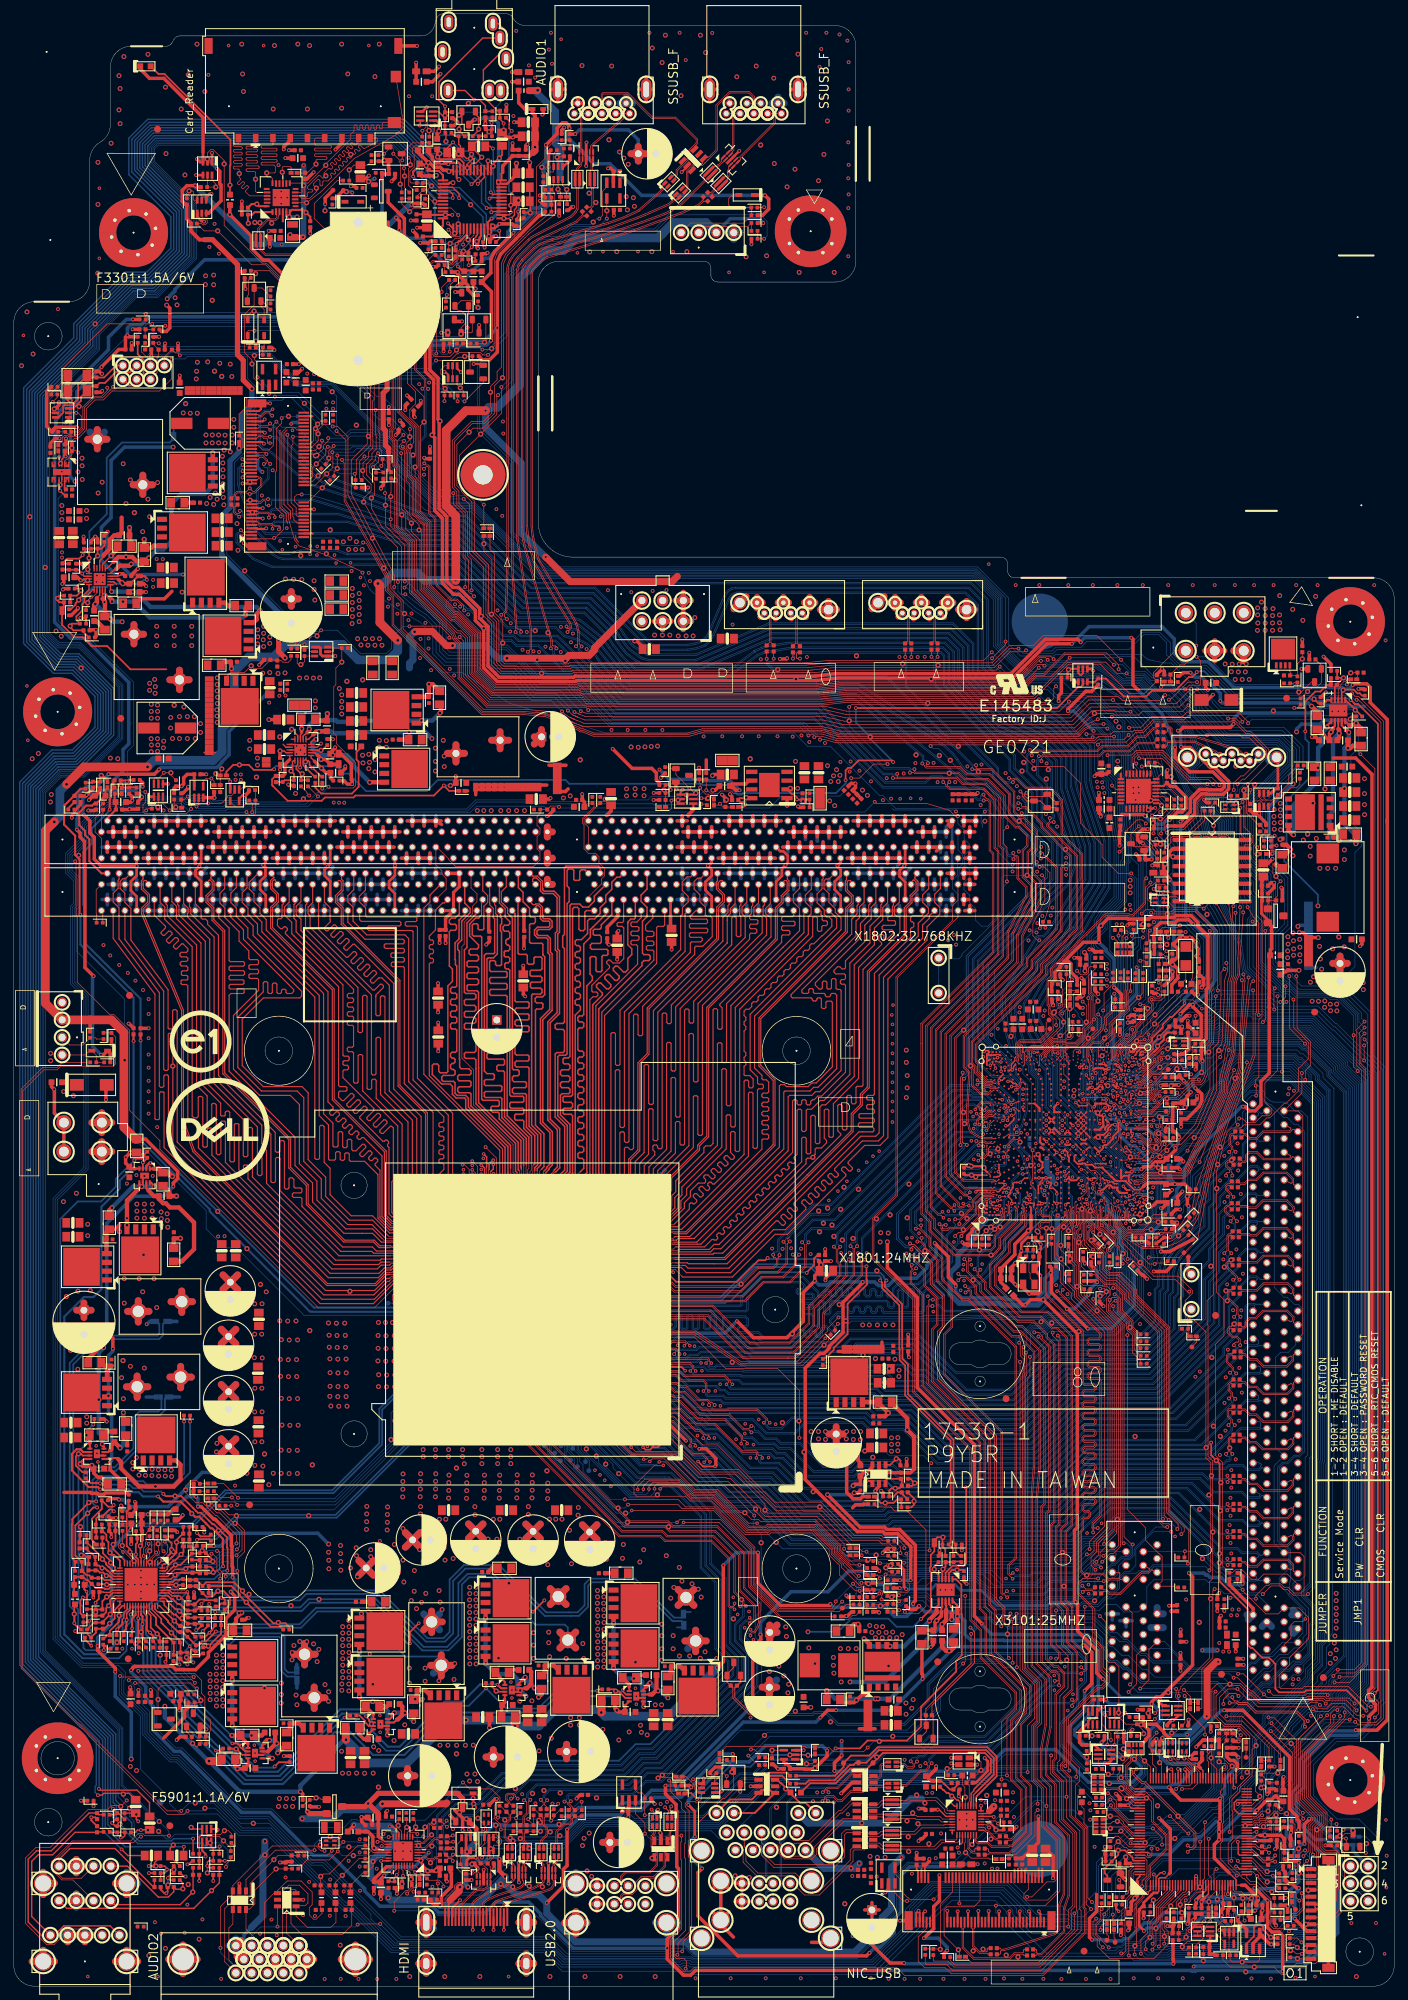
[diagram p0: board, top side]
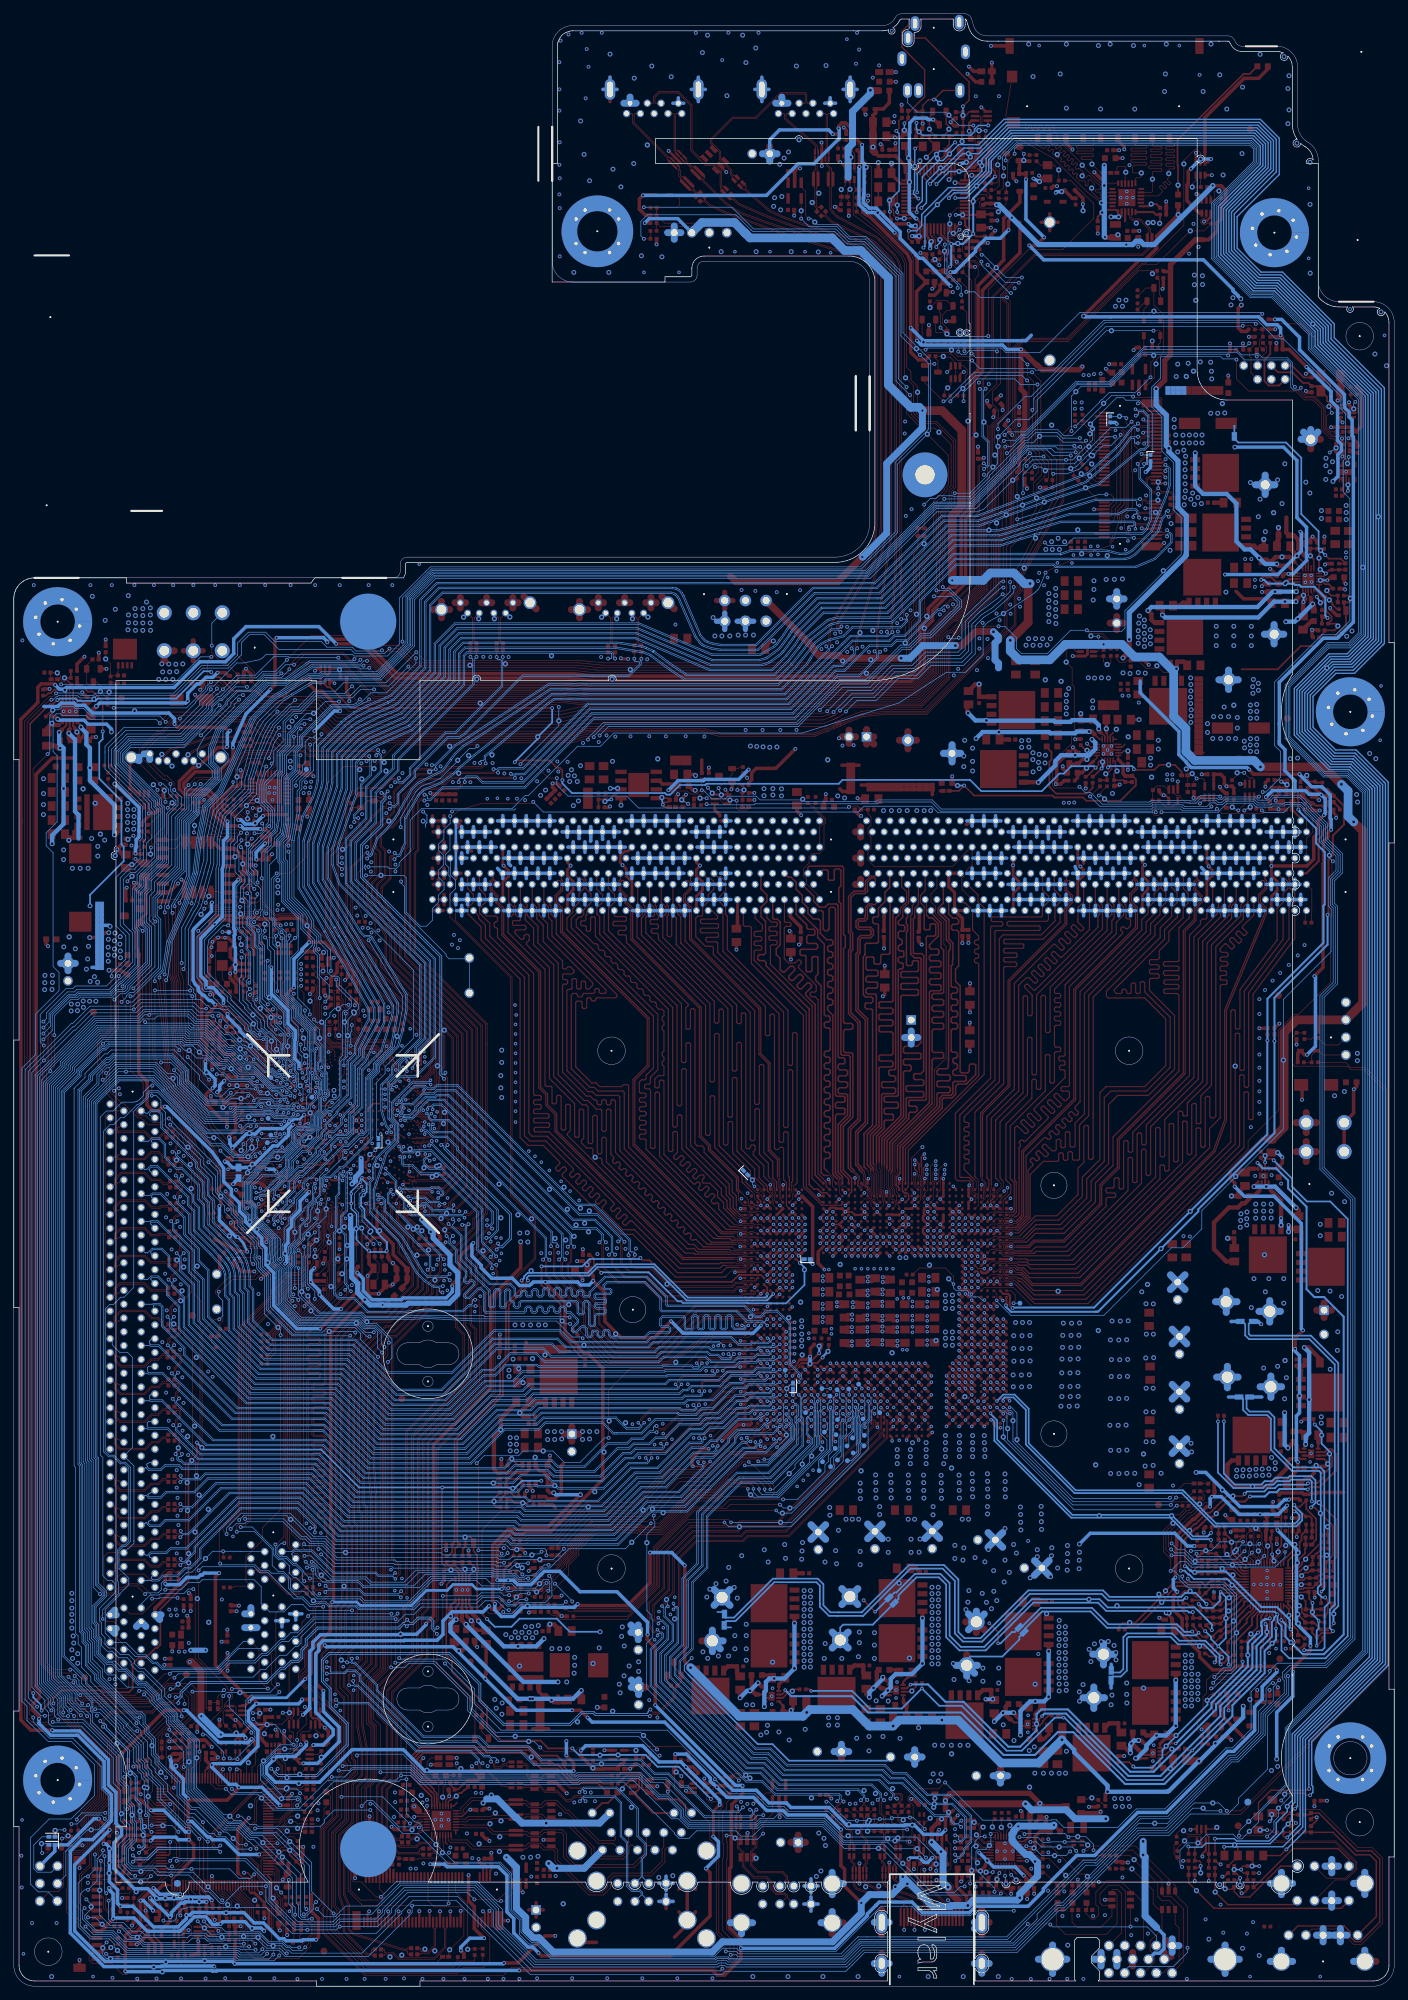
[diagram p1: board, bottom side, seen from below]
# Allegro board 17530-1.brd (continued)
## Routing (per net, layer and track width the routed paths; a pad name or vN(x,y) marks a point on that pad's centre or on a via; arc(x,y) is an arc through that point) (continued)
SB3V_CT2: length 3.7
  TOP w0.203: U4201.10 6.56,217.58
  TOP w0.254: 6.56,217.58 6.56,216.76 v3(6.71,216.61) 7.42,215.9 C4202.1
  BOTTOM w0.254: v2(6.71,217.47) v3(6.71,216.61)
SB3V_EN: length 3
  TOP w0.102: U4201.5 6.56,221.49 v3(6.58,221.51) 6.56,221.53 6.56,221.94 6.55,221.95 6.55,222.29 R4202.2
  BOTTOM w0.102: v3(6.58,221.51) v2(6.76,220.56)
SB5V_CT1: length 1.5
  TOP w0.203: 7.36,217.58 U4201.12
  TOP w0.254: C4201.1 7.36,217.01 7.36,217.58
SD_CD_BD: length 24.8
  TOP w0.102: SD1.10 53.5,269.95 53.38,269.83 53.38,269.16 53.26,269.04 53.1,269.04 52.98,269.16 52.98,269.48 52.86,269.59 52.69,269.59 52.57,269.48 52.57,269.08 52.45,268.96 52.28,268.96 52.16,269.08 52.16,269.48 52.05,269.59 51.88,269.59 51.76,269.48 51.76,269.08 51.64,268.96 51.47,268.96 51.35,269.08 51.35,269.48 51.23,269.59 51.06,269.59 50.95,269.48 50.95,269.08 50.83,268.96 50.66,268.96 50.54,269.08 50.54,269.48 50.42,269.59 50.25,269.59 50.13,269.48 50.13,269.03 50.01,268.91 49.85,268.91 49.73,269.03 49.73,269.48 49.61,269.59 49.43,269.59 49.3,269.47 49.3,268.73 48.82,268.25 48.82,267.56 45.2,263.95 v2(45.2,263.76) 45.14,263.7 42.61,261.18 U3301.13
SD_CLK_BD: length 20.7
  TOP w0.102: R3301.1 42.2,262.66 C3305.1 42.53,262.67 v2(43.79,263.93) 43.79,264.5 43.91,264.62 45.25,264.62 45.36,264.74 45.36,264.9 45.25,265.02 43.68,265.02 43.56,265.14 43.56,265.31 43.68,265.43 45.91,265.43 46.02,265.55 46.02,265.72 45.91,265.84 43.68,265.84 43.56,265.95 43.56,266.12 43.68,266.24 45.91,266.24 46.02,266.36 46.02,266.53 45.91,266.65 43.71,266.65 43.59,266.78 43.59,267.51 43.76,267.69 45.04,267.69 SD1.5
SD_CMD_BD: length 24.7
  TOP w0.102: SD1.2 37.55,266.76 37.43,266.64 35.96,266.64 35.84,266.52 35.84,266.35 35.96,266.23 38.02,266.23 38.14,266.11 38.14,265.94 38.02,265.83 35.96,265.83 35.84,265.71 35.84,265.54 35.96,265.42 38.02,265.42 38.14,265.3 38.14,265.13 38.02,265.01 35.96,265.01 35.84,264.89 35.84,264.73 35.96,264.61 38.02,264.61 38.14,264.49 38.14,264.32 38.02,264.2 35.96,264.2 35.84,264.08 35.84,263.91 35.96,263.79 37.68,263.79 37.9,263.57 37.9,262.78 37.77,262.65 v2(36.64,262.65) 36.64,262.19 36.86,261.98 37.31,261.98 37.49,261.8 U3301.18
SD_DATA0_BD: length 24.7
  TOP w0.102: 40.77,259.83 41.63,259.83 41.75,259.95 41.75,260.82 41.87,260.93 42.04,260.93 42.16,260.82 42.16,259.3 42.28,259.18 42.44,259.18 42.57,259.31 42.57,259.76 42.69,259.88 43.19,259.88 43.31,260 43.31,260.17 43.19,260.28 42.69,260.28 42.57,260.4 42.57,260.68 44.14,262.25 44.37,262.25 44.71,261.91 44.89,261.91 v2(45.21,262.23) 44.96,262.48 44.96,262.66 45.58,263.28 45.76,263.28 45.83,263.21 46.01,263.21 46.2,263.39 46.2,263.56 45.91,263.85 45.91,264.02 46.03,264.14 46.2,264.14 46.49,263.85 46.65,263.85 46.77,263.97 46.77,264.14 46.48,264.43 46.48,264.59 46.6,264.71 46.77,264.71 47.06,264.42 47.23,264.42 47.35,264.54 47.35,264.71 47.06,265 47.06,265.17 47.18,265.29 47.35,265.29 47.64,265 47.8,265 47.92,265.12 47.92,265.29 47.63,265.58 47.63,265.74 47.75,265.86 47.92,265.86 48.21,265.57 48.38,265.57 48.5,265.69 48.5,265.86 48.21,266.15 48.21,266.32 48.33,266.44 48.5,266.44 48.79,266.15 48.95,266.15 49.07,266.27 49.07,266.44 48.78,266.73 48.78,266.89 48.9,267.01 49.07,267.01 49.36,266.72 49.53,266.72 49.97,267.17 SD1.7
SD_DATA1_BD: length 24.5
  TOP w0.102: 40.77,259.33 41.36,259.33 41.76,258.93 42.82,258.93 43.84,259.94 v2(43.84,260.45) 43.42,260.87 43.42,261.07 44.03,261.68 44.21,261.68 44.36,261.53 44.36,260.9 44.48,260.78 44.64,260.78 44.76,260.9 44.76,261.37 44.88,261.49 45.52,261.49 46.05,262.03 46.05,262.19 45.91,262.33 45.91,262.5 46.03,262.62 46.2,262.62 46.34,262.48 46.51,262.48 46.62,262.6 46.62,262.77 46.49,262.91 46.49,263.07 46.61,263.19 46.78,263.19 46.91,263.06 47.08,263.06 47.2,263.18 47.2,263.34 47.06,263.48 47.06,263.65 47.18,263.77 47.35,263.77 47.49,263.63 47.66,263.63 47.77,263.75 47.77,263.92 47.64,264.06 47.64,264.22 47.76,264.34 47.93,264.34 48.04,264.23 48.21,264.23 48.32,264.35 48.32,264.52 48.21,264.63 48.21,264.8 48.33,264.92 48.5,264.92 48.61,264.81 48.78,264.81 48.9,264.93 48.9,265.09 48.79,265.21 48.79,265.37 48.91,265.49 49.08,265.49 49.21,265.36 49.38,265.36 49.5,265.48 49.5,265.64 49.36,265.78 49.36,265.95 49.48,266.07 49.65,266.07 49.89,265.83 50.06,265.83 50.18,265.95 50.18,266.12 49.94,266.36 49.94,266.52 50.06,266.64 50.23,266.64 50.63,266.24 50.81,266.21 51.36,266.49 52.7,267.25 52.7,267.57 52.58,267.7 SD1.8
SD_DATA2_BD: length 24.9
  TOP w0.102: U3301.21 34.17,259.33 33.58,259.92 33.58,260.09 33.99,260.5 33.99,260.67 33.87,260.79 33.7,260.79 33.29,260.38 33.12,260.38 33,260.5 33,260.67 33.41,261.08 33.41,261.25 33.3,261.37 33.13,261.37 32.71,260.95 32.54,260.95 32.43,261.07 32.43,261.24 32.84,261.65 32.84,261.82 32.66,262 v2(32.66,262.56) 32.66,263.1 32.55,263.22 31.95,263.22 31.83,263.34 31.83,263.51 31.95,263.63 32.98,263.63 33.1,263.75 33.1,263.91 32.98,264.03 31.95,264.03 31.83,264.15 31.83,264.32 31.95,264.44 32.98,264.44 33.1,264.56 33.1,264.73 32.98,264.85 31.95,264.85 31.83,264.96 31.83,265.13 31.95,265.25 32.98,265.25 33.1,265.37 33.1,265.54 32.98,265.66 31.95,265.66 31.83,265.78 31.83,265.95 31.95,266.06 32.98,266.06 33.1,266.18 33.1,266.35 32.98,266.47 31.95,266.47 31.83,266.59 31.83,266.76 31.95,266.88 32.42,266.88 32.55,267 SD1.9
SD_DATA3_BD: length 24.5
  TOP w0.102: SD1.1 35.03,267.68 35.03,266.64 34.91,266.52 33.78,266.52 33.66,266.4 33.66,266.23 33.78,266.11 35.2,266.11 35.31,265.99 35.31,265.82 35.2,265.7 33.78,265.7 33.66,265.59 33.66,265.42 33.78,265.3 35.2,265.3 35.31,265.18 35.31,265.01 35.2,264.89 33.78,264.89 33.66,264.77 33.66,264.6 33.78,264.49 35.2,264.49 35.31,264.37 35.31,264.2 35.2,264.08 33.78,264.08 33.66,263.96 33.66,263.79 33.78,263.67 35.42,263.67 35.54,263.55 35.54,263.39 35.42,263.27 33.78,263.27 33.66,263.15 33.66,262.98 33.78,262.86 34.91,262.86 35.03,262.74 v2(35.03,261.75) 35.03,259.96 35.15,259.83 U3301.20
SD_RCOMP: length 9.6
  TOP w0.102: SB1.BE2 162.26,111.89 SB1.BD1 SB1.BE1 162.76,111.69 163.22,111.23 163.34,111.23 163.41,111.16 v1(163.94,111.16) 164.52,111.16 165.15,111.79 R1514.1 ; SB1.BE5 162.55,113.57 v1(163.07,113.57) 163.07,113.4 SB1.BE4
  BOTTOM w0.102: v1(163.94,111.16) 163.85,111.16 v2(163.19,111.81) 163.19,113.45 v1(163.07,113.57)
SD_WP_BD: length 26.9
  TOP w0.102: 40.77,258.33 v2(42.42,258.33) 44.47,259.89 49.33,264.75 55.34,268.15 56.27,269.08 56.27,270.92 SD1.11
SIO_GREEN: length 438
  TOP w0.102: v3(20.05,240.79) 13.5,240.79 6.99,234.27 6.99,232.48 6.99,232.47 6.99,232.34 6.34,231.69 R6412.2 5.42,230.76 R6414.2 ; v3(174.26,16.99) 174.18,16.92 174.12,16.92 173.89,16.69 U2401.24 ; v3(160.07,190.75) 160.07,191.38 158.33,193.12 152.22,193.12 149.22,190.12 147.97,190.12 145.76,187.91 120.37,187.91 116.36,187.5 82.18,187.5 82.07,187.4 69.4,187.4 66.5,190.3 66.5,195.68 63.97,198.21 63.54,198.21 59.31,202.45 59.31,211.66 57.72,213.24 57.72,218.01 57.06,218.67 57.06,222.11 57.12,222.17 57.12,222.53 56.85,222.81 56.85,223.49 57.38,224.02 v2(57.38,224.43) 57.38,225.53 v3(57.4,225.55) ; U2401.2 165.09,16.12 v3(165.16,16.19) ; v3(195.71,137.13) 196.13,136.71 196.13,46.6 193.53,43.99 191.44,43.99 191.41,44.02 v3(191.36,44.02)
  BOTTOM w0.102: v3(195.71,137.13) 195.25,137.6 195.02,137.83 194.43,138.42 194.43,140.67 191.89,143.21 190.83,143.21 190.47,143.56 185.87,143.56 185.07,144.37 184.06,144.37 183.79,144.63 183.79,145 180.64,148.15 180.64,153.14 181.41,153.9 181.41,158.38 180.72,159.06 180.72,160.4 178.21,162.91 178.21,170.84 178.64,171.27 178.64,172.05 184.05,177.46 184.05,178.44 183.06,179.43 175.33,179.43 169.04,185.72 169.04,186.05 167.58,187.5 165.74,187.5 163.66,189.59 161.17,189.59 160.07,190.68 v3(160.07,190.75) ; v3(191.36,44.02) 191.36,43.8 188.78,41.22 188.78,40.54 188.9,40.42 188.9,39.85 188.59,39.54 188.59,38.23 184.15,33.79 184.15,31.15 183.03,30.03 183.03,29.05 183.03,26.69 182.47,26.14 182.47,23.96 182.23,23.72 182.23,21.02 183.36,19.9 183.36,17.95 182.81,17.4 178.06,17.4 177.54,16.88 175.45,16.88 175.34,16.99 v3(174.26,16.99) 168.74,16.99 167.37,15.62 165.74,15.62 v3(165.16,16.19) ; v3(57.4,225.55) 57.4,226.33 53.43,230.3 52.57,230.3 41.9,240.97 20.23,240.97 v3(20.05,240.79)
SIO_GREEN_1: length 4.9
  TOP w0.102: Q6401.5 5.41,227.9 5.31,228 5.31,229.16 v3(5.64,229.49) 6.31,230.16 R6414.1
  BOTTOM w0.102: v2(5.87,228.47) 5.92,229.16 v3(5.64,229.49)
SIO_PECI_REQ_N: length 164
  TOP w0.102: v3(172.59,23.75) 172.53,23.69 172.53,15.62 172.29,15.38 U2401.20 172.29,13.92 171.99,13.61 171.35,13.61 170.43,12.7 170.43,12.27 170.43,12.26 170.23,12.06 R2002.1 ; v1(164.99,129.98) 164.82,129.81 164.82,129.32 164.46,128.96 163.96,128.96 163.83,129.09 SB1.BF36
  BOTTOM w0.102: v3(172.59,23.75) 172.59,23.78 173.86,25.04 174.56,25.04 177.73,28.22 177.73,29.24 178.67,30.18 179.53,31.04 179.53,31.49 180.11,32.07 180.11,32.74 180.64,33.27 180.64,35.41 181.58,36.35 181.58,37.07 182.06,37.54 182.31,37.54 182.92,38.15 182.92,38.2 188.85,44.13 188.85,44.86 190.2,46.21 190.2,49.09 190.68,49.57 190.68,50.74 190.88,50.94 191.03,51.1 191.03,75.15 191.26,75.37 191.26,130.05 191.26,130.05 189.69,131.62 189.69,132.19 186.83,135.05 186.46,135.05 185.9,135.61 176.76,135.61 173.1,131.95 173.1,131.33 170.7,128.93 169.83,128.93 168.78,129.98 168.12,129.98 v2(167.66,130.44) 167.2,129.98 v1(164.99,129.98)
SIO_PS_ON_N: length 202.2
  TOP w0.102: v3(195.71,138) 195.17,137.46 195.17,133.64 195.86,132.94 195.86,46.65 194.02,44.8 192.08,44.8 v3(192.08,44.81) ; v3(180.85,24.77) 180.61,24.77 180.21,24.36 179.65,24.36 179.47,24.18 U2401.53 ; v3(166.22,188.2) 166.33,188.2 166.69,188.56 R4302.1
  BOTTOM w0.102: v3(180.85,24.77) 180.94,24.85 180.94,26.76 181.1,26.92 v2(181.1,28.83) 181.1,29.79 181.51,30.2 181.51,30.67 182.09,31.25 182.09,31.9 182.63,32.44 182.63,34.48 185.28,37.13 185.28,37.38 187.57,39.67 188.4,39.67 188.67,39.94 188.67,40.32 188.55,40.44 188.55,41.39 190.91,43.75 190.91,44.21 191.17,44.48 191.74,44.48 v3(192.08,44.81) ; v3(166.22,188.2) 167.89,188.2 169.72,186.37 169.86,186.23 170.16,186.23 171.17,185.26 171.17,184.78 175.51,180.44 183.23,180.44 184.89,178.79 184.89,177.11 179.48,171.7 179.48,170.92 179.04,170.49 179.04,163.27 181.56,160.75 181.56,159.41 182.25,158.72 182.25,153.34 181.86,152.96 181.86,147.78 184.38,145.26 184.5,145.26 185.97,143.79 190.64,143.79 191,143.43 191.99,143.43 194.66,140.76 194.66,139.04 v3(195.71,138)
SIO_SMBCLK1: length 5
  TOP w0.102: U2401.70 175.09,31.09 175.3,31.29 175.58,31.29 175.84,31.56 175.84,31.94 175.53,32.26 174.88,32.26 v2(174.62,32.51) R2425.1
SIO_SMBCLK2: length 3.5
  TOP w0.102: U2401.26 174.69,13.4 174.38,13.09 v2(174.38,12.58) 174.37,12.58 174.19,12.4 R2426.2
SIO_SMBDAT1: length 5.1
  TOP w0.102: R2427.1 173.58,34.68 173.58,33.18 v2(173.48,33.07) 173.45,33.04 173.45,32.29 174.29,31.45 U2401.72
SIO_SMBDAT2: length 3.8
  TOP w0.102: U2401.25 174.29,13.89 173.15,12.75 v2(173.15,12.24) 173.1,12.19 R2422.2
SIO_SPKR: length 8.2
  TOP w0.102: U2401.125 162.21,17.38 161.57,16.74 161.57,13.87 v3(161.26,13.57) 161.26,13.49 160.68,12.9 R2452.2 160.59,12.85 R2453.1
  BOTTOM w0.102: v2(161.95,14.25) v3(161.26,13.57)
SIO_YELLOW: length 419.8
  TOP w0.102: v3(13.54,231.53) 13.54,231.53 13.54,231.13 12.71,230.3 11.56,230.3 10.01,228.75 10.01,225.67 9.02,224.69 8.02,224.69 7.84,224.87 7.73,224.87 R6411.2 6.44,225.15 R6410.2 ; U2401.23 173.49,15.71 173.12,16.09 v3(173.12,21.35) ; v3(159.38,191.41) 157.91,192.89 152.31,192.89 149.31,189.89 148.06,189.89 145.85,187.68 120.57,187.68 116.51,187.27 82.27,187.27 82.17,187.17 69.3,187.17 66.27,190.21 66.27,195.59 63.87,197.98 63.87,197.98 63.45,197.98 63.43,198 59.08,202.35 59.08,210.57 v2(58.72,210.92) 58.72,211.66 57.37,213.02 57.37,217.61 56.83,218.14 56.83,222.01 56.83,222.2 56.9,222.27 56.9,222.43 56.62,222.71 56.62,222.75 56.48,222.88 56.48,222.88 v3(56.36,223) ; v3(191.19,44.93) 191.62,45.36 194.25,45.36 195.63,46.74 195.63,132.79 194.94,133.48 194.94,138.09 v3(195.71,138.86)
  BOTTOM w0.102: v3(191.19,44.93) 190.55,44.3 190.55,43.71 184.47,37.64 184.47,37.34 181.91,34.78 181.91,32.74 181.38,32.21 181.38,31.55 180.8,30.96 180.8,30.49 179.12,28.81 179.12,27.02 175.06,22.96 174.59,22.96 174.17,22.54 174.17,22.4 v3(173.12,21.35) ; v3(13.54,231.53) 13.64,231.43 13.64,231.42 13.86,231.2 14.58,231.2 14.99,231.61 14.99,235.09 15.46,235.56 21.69,235.56 22.81,236.68 36.39,236.68 41.09,231.98 45.96,231.98 53.35,224.59 53.87,224.59 53.87,224.59 55.44,223.01 56.35,223.01 v3(56.36,223) ; v3(159.38,191.41) 160.63,191.41 161.88,190.17 161.97,190.08 163.81,190.08 164.74,189.15 167.26,189.15 169.95,186.46 170.26,186.46 171.4,185.35 171.4,184.88 175.61,180.67 183.33,180.67 185.11,178.88 185.11,177.02 179.71,171.61 179.71,170.83 179.27,170.4 179.27,163.36 181.79,160.85 181.79,159.5 182.47,158.82 182.47,153.25 182.09,152.86 182.09,147.87 184.47,145.49 184.59,145.49 186.06,144.02 190.74,144.02 191.09,143.66 192.08,143.66 194.89,140.86 194.89,139.68 v3(195.71,138.86)
SIO_YELLOW_1: length 6.4
  TOP w0.102: R6411.1 9.16,225.15 9.78,225.77 9.78,227.43 9.31,227.9 v3(9.04,227.9) Q6401.2
  BOTTOM w0.102: v3(9.04,227.9) v2(9.46,228.82)
SKL_CNL_N: length 15.6
  TOP w0.102: R422.2 68.81,104.03 65.04,104.03 63.85,102.84 v1(63.85,101.69) ; CPU1.AB36 v1(59.38,99.37)
  BOTTOM w0.102: v1(59.38,99.37) 59.7,99.37 60.17,99.84 61.41,99.84 61.65,100.08 61.65,100.42 61.65,100.42 61.65,100.53 61.86,100.74 63.44,100.74 63.85,101.15 v1(63.85,101.69) v2(64.54,102.46)
SKL_PCUDEBUG_0: length 68.1
  TOP w0.102: v1(80.78,85.67) 81.23,86.11 CPU1.H15 ; v3(119.09,55.73) 119.09,55.52 118.54,54.71 110.9,54.71 107.37,58.24 107.37,63.57 101.5,69.43 97.32,69.43 96.24,70.51 v3(88.54,70.51) ; v3(121.59,58.3) 122.15,57.73 122.74,57.73 123.01,57.47 123.01,57.2 123.63,56.58 R9913.1
  BOTTOM w0.102: v3(119.09,55.73) 119.09,55.8 v3(121.59,58.3) ; v3(88.54,70.51) 86.49,70.51 82.47,74.52 82.47,75.51 81.99,76 81.99,76.88 TP404.1 81.41,78.33 81.41,83.4 81.21,83.61 81.21,85.24 v1(80.78,85.67)
SKL_PCUDEBUG_1: length 4.9
  TOP w0.102: CPU1.F15 v1(80.8,83.84)
  BOTTOM w0.102: v1(80.8,83.84) 80.8,83.68 81.21,83.27 81.21,80.22 TP405.1
SKL_PCUDEBUG_2: length 2.7
  TOP w0.102: CPU1.F16 v1(79.87,83.83)
  BOTTOM w0.102: TP406.1 80.34,82.4 80.34,83.35 v1(79.87,83.83)
SKL_PCUDEBUG_3: length 66.2
  TOP w0.102: CPU1.H16 v1(79.87,85.66) ; R423.1 120.6,55.3 TP407.1 119.55,54.25 110.71,54.25 106.91,58.05 106.91,63.38 101.38,68.91 v1(89.53,68.91)
  BOTTOM w0.102: v1(79.87,85.66) 79.41,85.2 79.41,82.8 79.06,82.45 78.82,82.45 78.55,82.17 78.55,80.45 79.82,79.17 79.82,76.02 87.31,68.53 v2(88.65,68.53) 89.15,68.53 v1(89.53,68.91)
SKL_PCUDEBUG_4: length 62.6
  TOP w0.102: v1(96.09,67.18) 96.51,67.61 102.36,67.61 106.68,63.29 106.68,57.96 111.07,53.57 R424.1 ; CPU1.F19 77.58,84.25 v1(77.14,83.81)
  BOTTOM w0.102: v1(96.09,67.18) v2(88.9,67.18) 87.3,67.18 77.37,77.11 77.37,78.53 77.52,78.68 77.52,81.27 77.37,81.42 77.37,81.82 77.5,81.95 77.5,82.58 77.64,82.72 77.64,83.31 v1(77.14,83.81)
SKL_PCUDEBUG_5: length 7.3
  TOP w0.102: CPU1.H18 v1(78.06,85.64)
  BOTTOM w0.102: TP408.1 78.14,79.77 78.14,82.34 78.28,82.48 78.28,83.14 78.46,83.32 78.46,85.23 v1(78.06,85.64)
SKL_PCUDEBUG_6: length 2.6
  TOP w0.102: v1(75.27,84.73) 75.73,85.2 CPU1.G21
  BOTTOM w0.102: TP409.1 74.85,83.35 74.85,84.32 v1(75.27,84.73)
SKL_PCUDEBUG_7: length 7.5
  TOP w0.102: CPU1.H20 v1(76.19,85.64)
  BOTTOM w0.102: TP410.1 77.11,80.13 77.11,81.1 76.81,81.41 76.66,81.41 76,82.07 76,84.28 75.8,84.47 75.8,85.25 v1(76.19,85.64)
SKL_PCUDEBUG_8: length 2.7
  TOP w0.102: CPU1.G16 v1(79.87,84.74)
  BOTTOM w0.102: v1(79.87,84.74) 80.38,85.25 80.38,86.07 TP411.1
SKL_PCUDEBUG_9: length 94.5
  TOP w0.102: CPU1.E16 79.87,82.91 v1(79.88,82.91) ; R425.1 125.11,69.42 127.05,69.42 127.64,68.83 129.41,68.83 132.16,66.09 132.16,55.02 131.08,53.95 129.36,53.95 v3(129.09,54.21) ; v3(89,69.75) 96.23,69.75 96.79,69.19 101.42,69.19 107.14,63.48 107.14,58.15 110.81,54.48 118.79,54.48 v3(120.02,55.7)
  BOTTOM w0.102: v3(89,69.75) 88.52,69.27 v2(87.55,69.27) 86.9,69.27 81.13,75.04 81.13,75.48 81.2,75.56 81.2,76.52 80.24,77.49 80.24,78.16 80.26,78.19 80.26,79.35 79.83,79.78 79.83,81.47 79.47,81.83 79.47,82.51 v1(79.88,82.91) ; v3(129.09,54.21) 128.88,54 127.79,54 126.47,55.32 120.4,55.32 v3(120.02,55.7)
SKL_PCUDEBUG_10: length 6.9
  TOP w0.102: CPU1.F17 79.38,84.28 v1(78.93,83.83)
  BOTTOM w0.102: TP412.1 79.01,78.53 79.01,79.64 78.34,80.3 78.34,82.26 78.49,82.4 78.49,83.06 78.93,83.5 v1(78.93,83.83)
SKL_PCUDEBUG_11: length 1.5
  TOP w0.102: CPU1.H17 v1(78.95,85.66)
  BOTTOM w0.102: v1(78.95,85.66) 78.95,86.45 TP413.1
SKL_PCUDEBUG_12: length 4.4
  TOP w0.102: CPU1.G20 v1(77.11,85.64)
  BOTTOM w0.102: v1(77.11,85.64) 76.7,85.23 76.7,84.19 76.71,84.14 76.71,82.4 TP414.1
SKL_PCUDEBUG_13: length 7.8
  TOP w0.102: CPU1.F20 v1(76.21,84.74)
  BOTTOM w0.102: TP415.1 77.31,78.76 77.31,81.19 76.89,81.61 76.75,81.61 76.21,82.15 v1(76.21,84.74)
SKL_PCUDEBUG_14: length 67.6
  TOP w0.102: CPU1.F21 75.75,84.26 v1(75.3,83.8) ; v1(97.04,67.17) 97.04,67.18 102.18,67.18 106.45,62.91 106.45,57.86 111.2,53.11 120.88,53.11 121.49,53.72 122.02,53.72 122.53,54.23 R426.1
  BOTTOM w0.102: v1(97.04,67.17) 96.41,66.55 v2(94.87,66.55) 87.43,66.55 76.23,77.75 76.23,81.56 75.77,82.01 75.77,83.33 v1(75.3,83.8)
SKL_PCUDEBUG_15: length 1.5
  TOP w0.102: CPU1.H19 v1(77.12,86.57)
  BOTTOM w0.102: v1(77.12,86.57) 77.12,86.73 TP416.1
SKL_PCUSTB_0_DN: length 9.1
  TOP w0.102: CPU1.E14 v1(81.68,83.84)
  BOTTOM w0.102: TP420.1 82.83,76.42 81.61,77.63 81.61,83.49 81.61,83.49 81.61,83.77 v1(81.68,83.84)
SKL_PCUSTB_0_DP: length 11.6
  TOP w0.102: v1(81.68,84.72) 82.12,84.28 CPU1.F14
  BOTTOM w0.102: TP419.1 83.36,74.73 83.36,76.19 83.05,76.5 83.05,76.5 81.83,77.72 81.83,83.38 82.08,83.64 82.08,84.32 v1(81.68,84.72)
SKL_PCUSTB_1_DN: length 10.6
  TOP w0.102: CPU1.G18 78.5,85.16 v1(78.06,84.72)
  BOTTOM w0.102: TP422.1 78.65,76.12 77.64,77.14 77.64,78.5 77.72,78.59 77.72,82.52 77.84,82.64 77.84,83.49 77.65,83.68 77.65,84.32 v1(78.06,84.72)
SKL_PCUSTB_1_DP: length 7.8
  TOP w0.102: CPU1.F18 v1(78.06,83.84)
  BOTTOM w0.102: TP421.1 77.95,77.24 77.85,77.34 77.85,78.41 77.94,78.5 77.94,82.43 78.06,82.55 v1(78.06,83.84)
SLP_A_N_CN: length 1.9
  TOP w0.102: R9916.2 159.41,7.04 159.56,6.88 TP9901.1
SLP_S0_N: length 249.5
  TOP w0.102: v3(184.39,142.58) 184.32,142.58 183.74,142.01 v3(183.74,132.46) ; v3(173.79,174.11) 173.12,174.78 170.3,174.78 166.41,178.66 162.71,178.66 162.03,177.98 162.03,176.84 162.69,176.18 U9101.29 ; SB1.BC28 161.81,124.95 163.76,124.95 163.8,124.99 164.12,124.99 164.55,125.43 v1(165.13,125.43) ; v3(156.21,12.19) 155.61,12.79 155.61,22.98 155.59,23 155.07,23.52 155.07,25.65 154.74,25.98 DB2002.1
  BOTTOM w0.102: v3(173.79,174.11) 174.93,172.97 174.93,170.54 176.33,169.14 176.33,162.09 178.84,159.58 178.84,158.28 179.53,157.6 179.53,154.94 179.01,154.42 179.01,154.21 179.05,147.5 179.06,147.49 179.08,147.47 182.63,143.92 183.22,143.92 183.64,143.49 183.64,143.33 v3(184.39,142.58) ; v3(156.21,12.19) 156.54,11.86 156.54,11.21 157.8,9.95 158.18,9.95 158.45,10.21 158.45,16.29 v2(161.6,19.44) 164.01,21.84 165.59,21.84 167.29,23.55 169.06,23.55 174.02,28.5 174.02,35.48 176.94,38.4 176.94,39.14 179.3,41.5 179.3,41.95 180.97,43.62 182.03,43.62 182.72,44.31 182.72,44.46 183.88,45.62 184.8,45.62 185.8,46.62 186.53,46.62 187.96,48.05 187.96,48.43 187.96,50.02 188.44,50.5 188.44,51.67 188.79,52.02 188.79,76.07 188.8,76.07 189.02,76.3 189.02,127.61 189.02,127.62 189.02,128.31 184.87,132.46 v3(183.74,132.46) 179.76,132.46 177.52,130.22 177.52,130.14 177.47,130.08 177.47,130.02 172.4,124.96 167.63,124.96 167.16,125.43 v1(165.13,125.43)
SLP_S0_PLT_N: length 3.5
  TOP w0.102: TP2002.1 154.13,25.52 154.13,27.56 DB2002.2
SLP_S3_N: length 660.7
  TOP w0.102: v3(180.37,140.69) 180.37,154.1 179.62,154.85 v3(178.77,156.3) ; U2401.121 163.89,18.98 164.25,18.62 164.63,18.62 164.9,18.89 164.9,19.89 v3(164.85,19.94) ; v3(194.26,40.94) 193.47,41.73 190.59,41.73 190.56,41.71 190.18,41.71 189.9,41.99 187.41,41.99 187.26,41.84 181.55,41.84 v3(181.13,42.27) 178.15,45.25 v3(177.38,45.25) ; R5002.2 42.62,173.79 v3(44.07,172.34) ; SB1.BF42 163.39,131.96 165.28,133.84 165.42,133.84 165.66,134.08 165.66,134.54 166.3,135.18 v1(166.42,135.18) ; R4224.1 R2046.1 27.83,36.36 28.5,37.03 28.5,38.56 27.69,39.37 27.69,41.93 27.18,42.44 27.18,44.32 26.21,45.29 22.93,45.29 22.56,45.67 v3(18.03,45.67) ; v3(185.52,185.17) 185.95,185.17 186.42,185.64 R4225.1 ; v3(167.35,186.36) 167.57,186.36 170.12,188.9 v3(171.42,188.9) ; v3(144.17,47.52) 143.97,47.73 v2(143.97,51) 143.97,52.03 144.22,52.28 144.22,53.35 144.4,53.53 v3(144.4,53.98) ; v3(177.47,37.17) 177.68,37.17 178.31,36.54 178.32,36.54 178.56,36.3 R9917.1 ; U4002.5 99.33,28.7 98.96,29.08 98.96,29.44 v3(98.42,29.97) ; v3(65.07,29.51) 65.11,29.51 66.04,28.57 69.2,28.57 70.43,27.34 70.43,26.92 70.11,26.59 70.06,26.59 69.69,26.22 69.69,24.24 69.96,23.97 69.97,23.97 70.56,23.38 v3(70.56,22.71)
  BOTTOM w0.102: v3(70.56,22.71) 79.38,22.71 81.98,25.31 87.69,25.31 88.42,26.04 90.37,26.04 90.37,26.03 90.79,26.03 92.62,27.87 96.32,27.87 v3(98.42,29.97) 98.42,30.22 105.29,37.08 129.41,37.08 133.24,40.91 133.24,43.08 137.54,47.38 144.03,47.38 v3(144.17,47.52) ; v1(166.42,135.18) 166.58,135.18 168.54,137.14 169.21,137.14 171.79,139.73 173.61,139.73 174.73,140.84 180.21,140.84 v3(180.37,140.69) 180.39,140.72 181.04,140.72 181.86,139.89 188.13,139.89 196.29,131.72 196.29,43.76 194.41,41.88 194.41,41.88 194.26,41.73 v3(194.26,40.94) ; v3(178.77,156.3) 178.29,157.91 178.19,158.25 178.19,159.37 175.72,161.84 175.72,168.89 174.33,170.28 174.33,170.28 174.27,170.34 174.27,172.34 172.97,173.63 172.78,173.63 171.25,175.17 171.25,176.12 171.94,176.81 172.06,176.91 172.51,177.28 173.43,178.19 173.43,179.12 172.42,180.93 168.28,185.08 168.14,185.21 168.14,185.25 168.07,185.32 168.07,185.64 v3(167.35,186.36) ; v3(171.42,188.9) 171.49,188.9 172.21,188.17 172.21,187.92 174.97,185.17 v3(185.52,185.17) ; v3(164.85,19.94) 165.84,20.93 165.97,20.93 167.67,22.63 168.13,22.63 168.13,22.63 169.47,22.63 174.93,28.09 174.93,34.63 v3(177.47,37.17) 177.47,37.64 177.85,38.02 177.85,38.76 180.29,41.2 180.29,41.43 v3(181.13,42.27) ; v3(144.4,53.98) 144.76,53.62 144.86,53.62 144.99,53.49 156.57,53.49 158.87,51.19 159.87,51.19 160.85,50.22 161.35,50.22 163.35,48.22 164.08,48.22 165.18,47.12 168.82,47.12 170.38,45.55 177.08,45.55 v3(177.38,45.25) ; v3(44.07,172.34) 42.65,170.92 35.19,170.92 34.99,171.12 30.61,171.12 30.35,170.87 27.15,170.87 26.62,171.4 25.88,171.4 25.63,171.15 24.85,171.15 24.35,171.65 20.45,171.65 19.89,171.09 17.9,171.09 17.75,171.25 16.07,171.25 15.84,171.48 13.41,171.48 12.67,170.74 12.67,170.56 10.26,168.15 10.26,165.96 8.13,163.83 8.13,161.49 9.25,160.37 9.25,156.59 8.84,156.19 8.84,145.41 10.76,143.49 10.76,118.33 6.3,113.87 6.3,50.53 10.05,46.78 16.95,46.78 18.03,45.69 v3(18.03,45.67) 18.03,45.37 20.73,42.67 20.73,37.25 23.46,34.52 24.37,34.52 33.21,25.68 37.37,25.68 40.07,22.99 47.85,22.99 48.92,24.05 48.97,24.11 49.6,24.11 49.66,24.05 50.54,24.05 50.54,24.05 59.61,24.05 v3(65.07,29.51)
SLP_S3_N_CN: length 1.3
  TOP w0.102: R9917.2 178.56,33.93 178.54,33.91 TP9902.1
SLP_S3_N_Q4205: length 7.7
  TOP w0.102: R4225.2 186.45,186.52 187.4,187.48 187.4,187.48 v2(187.45,187.53) 188.08,188.16 188.8,188.16 189.45,188.81 Q4205.B 189.45,191.33 C4226.1
SLP_S3_N_Q4207: length 4.2
  TOP w0.102: Q4207.B 25.03,36.88 C4227.1 25.78,35.31 v2(25.91,35.18) 26.41,34.68 26.55,34.68 26.94,35.07 R4224.2
SLP_S4_N: length 825.1
  TOP w0.102: U4010.1 26.15,171.43 25.68,170.97 v3(25.68,170.54) 24.99,169.85 18.99,169.85 18.72,170.12 18.72,171.12 19.1,171.5 19.1,172.5 19.05,172.55 v3(19.05,172.98) ; v3(152.78,8.64) 152.78,11.03 153.43,11.68 153.43,22.07 151.51,23.99 151.51,29.48 151.39,29.6 150.17,30.82 150.17,33.31 v3(150.29,33.43) ; v3(177.19,16.03) 177.19,16.06 174.8,18.44 174.8,20.67 175.13,21 175.13,22.56 175.13,22.56 175.13,23.54 175.26,23.67 175.26,27.39 174.8,27.85 174.8,28.24 175.49,28.93 U2401.69 ; 85.92,258.95 v2(85.92,257.18) v3(85.92,256.03) ; R9918.1 157.92,9.08 157.45,8.61 v3(157.45,8.15) ; v3(175.95,183.62) 175.96,183.63 177.06,183.63 177.53,183.15 177.53,182.86 178.65,181.74 179.23,181.74 181.83,179.13 181.83,177.19 v3(178.79,174.14) 178.79,173.86 178.77,173.84 178.77,173.79 R809.2 ; U3901.4 90.08,28.39 90.47,27.99 91.03,27.99 91.43,27.6 R2045.1 91.43,26.4 91.41,26.39 v3(91.41,24.77) ; v3(99.62,171.22) 100.34,171.22 100.46,171.11 100.46,171.08 R4020.1 ; v3(163.47,14.48) 163.47,15.28 163.63,15.44 164.17,15.98 164.17,18.27 163.86,18.58 U2401.122 ; SB1.BE42 162.74,131.99 163.38,132.63 163.78,132.63 165.25,134.11 v1(165.25,134.25) ; v3(194.71,132.56) 194.13,133.14 v3(194.13,137.75) ; v3(68.72,236.29) 67.95,236.29 67.61,236.63 64.56,236.63 64.37,236.44 64.18,236.44 63.22,235.48 v3(61.18,235.48) ; v3(133.27,12.57) 129.83,12.57 129.6,12.8 129.53,12.8 128.32,14.01 128.32,15.62 127.67,16.27 U3201.4
  BOTTOM w0.102: v3(194.13,137.75) 194.13,140.54 191.77,142.9 190.7,142.9 190.35,143.26 186.19,143.26 185.75,143.26 184.94,144.06 183.93,144.06 183.49,144.51 183.49,144.87 180.34,148.02 180.34,153.27 181.1,154.03 181.1,154.03 181.1,158.25 180.42,158.94 180.42,160.24 177.9,162.76 177.9,169.8 176.52,171.18 176.52,171.72 177.57,172.77 177.57,173.38 178.33,174.14 v3(178.79,174.14) ; v3(175.95,183.62) 173.69,185.87 173.69,186.01 171.91,187.8 171.91,188.05 171.64,188.32 171.04,188.32 167.7,191.66 166.78,191.66 166.54,191.71 164.92,192.03 164.92,192.03 164.56,192.1 164.22,192.25 163.91,192.45 163.47,192.89 150.92,192.89 150.71,192.68 145.86,192.68 144.15,194.39 144.15,201.07 140.34,204.87 139.62,205.59 77.34,205.59 72.3,210.63 72.3,220.71 67.46,225.54 67.46,235.04 v3(68.72,236.29) 71.48,239.05 71.48,247.96 76.58,253.06 78.94,253.06 80.77,254.89 84.78,254.89 v3(85.92,256.03) ; v3(99.62,171.22) 99.52,171.12 92.75,171.12 92.6,171.27 74.87,171.27 74.62,171.53 67.06,171.53 65.73,170.21 35.04,170.21 34.73,170.51 30.91,170.51 30.66,170.26 25.96,170.26 v3(25.68,170.54) ; 157.45,8.17 153.25,8.17 v3(152.78,8.64) 147.3,8.64 145.29,10.65 145.29,11.23 142.96,13.56 134.26,13.56 v3(133.27,12.57) ; 157.45,8.17 v3(157.45,8.15) ; 157.45,8.17 159.29,8.17 163.47,12.35 v3(163.47,14.48) 167.08,14.48 169.6,11.96 170,11.96 171.75,13.72 172.25,13.72 174.63,16.1 177.11,16.1 v3(177.19,16.03) 179.13,16.03 179.89,16.79 183.07,16.79 183.97,17.7 183.97,20.15 182.84,21.27 182.84,23.47 183.08,23.71 183.08,25.88 183.64,26.44 183.64,28.8 184.76,29.92 184.76,33.43 189.99,38.66 192.91,38.66 193.62,39.38 193.62,41.53 195.99,43.89 195.99,131.28 v3(194.71,132.56) 194.71,132.87 188,139.59 181.74,139.59 181.22,140.11 179.63,140.11 179.2,140.54 174.85,140.54 173.74,139.42 173.48,139.42 171.92,139.42 168.78,136.28 168.16,136.28 166.63,134.75 165.75,134.75 v1(165.25,134.25) ; v3(61.18,235.48) 60.01,234.31 52.15,234.31 51.92,234.09 49.28,234.09 42.06,241.3 41.91,241.3 19.83,241.3 17.13,238.61 16.03,238.61 7.72,230.3 7.72,228.92 7.7,228.89 7.7,228.45 7.04,227.79 7.04,224.45 7.09,224.4 7.09,224.02 7.04,223.97 7.04,221.34 7.39,220.98 7.39,216.43 6.43,215.47 6.43,197.79 7.81,196.4 7.82,196.4 8.46,195.76 10.48,195.76 10.51,195.73 17.32,188.91 17.32,179.71 16.48,178.87 16.48,175.07 18.58,172.98 v3(19.05,172.98) ; v3(150.29,33.43) 150.11,33.6 143.63,33.6 140.73,30.71 140.72,30.71 140.62,30.61 118.72,30.61 118.4,30.93 109.15,30.93 108.67,30.45 107.71,29.49 105.93,29.49 102.64,26.2 102.64,24.74 101.87,23.98 93.02,23.98 92.23,24.77 v3(91.41,24.77)
SLP_S4_N_CN: length 1.7
  TOP w0.102: TP9903.1 158.62,6.91 158.62,7.26 158.37,7.52 R9918.2
SLP_S4_N_SFR: length 6.7
  TOP w0.102: Q802.2 181.11,171.22 180.64,171.7 179.58,171.7 C806.1 178.92,171.46 178.92,171.61 178.92,171.9 178.84,171.98 178.84,171.99 178.37,172.47 R809.1 178.44,172.57 178.92,172.57 179.18,172.83 v3(179.18,173.28)
  BOTTOM w0.102: v2(179.78,174.04) v3(179.18,173.28)
SLP_S4_N_SFR_1: length 10.3
  TOP w0.102: R807.2 186,176.68 184.72,175.4 184.72,174.15 R810.1 182.94,172.37 182.9,172.37 182.34,171.81 181.46,171.81 ; Q802.6 180.46,172.22 180.88,171.81 181.46,171.81 ; 181.46,171.81 181.11,172.15 Q802.5
SLP_S4_N_SFR_2: length 14.5
  TOP w0.102: R804.2 186.33,174.07 185.85,173.59 185.06,173.59 183.61,172.14 182.99,172.14 Q802.3 181.94,170.73 181.94,166.95 182.25,166.65 182.68,166.65 v3(182.68,166.65) 182.69,166.64 182.69,166.49 R806.1 182.13,165.94 181.14,165.94 R805.1
  BOTTOM w0.102: v3(182.68,166.65) v2(183.48,166.11)
SLP_S4_N_SFR_G: length 13.3
  TOP w0.102: R805.2 181.67,164.52 182.56,164.52 182.83,164.25 182.83,162.89 182.42,162.48 182.42,161.16 v3(183.54,160.05) 183.51,160.05 183.1,159.63 183.1,157.93 182.88,157.71 182.88,157.29 C802.1 C803.1 181.76,157.26 181.76,156.79 181.71,156.74 Q801.G
  BOTTOM w0.102: v2(182.86,160.77) 182.86,160.76 v3(183.54,160.05)
SLP_S4_VPP_N: length 3
  TOP w0.102: R4020.2 100.32,172.09 v3(99.62,172.09) 99.49,171.96 Q4002.2
  BOTTOM w0.102: v3(99.62,172.09) v2(100.58,172.09)
SLP_S5_N: length 1.7
  TOP w0.102: v1(161.89,131.17) 161.66,131.4 SB1.BC42
  BOTTOM w0.102: TP2003.1 162.3,131.17 v1(161.89,131.17)
SLP_SUSB: length 477.3
  TOP w0.089: 164.41,130.78 164.4,130.77 163.76,130.77 163.39,130.4 162.76,130.4 162.68,130.48 162.21,130.48 SB1.BD39
  TOP w0.102: v3(175.39,31.75) 175.11,31.75 174.69,31.33 U2401.71 ; v3(171.37,192.56) 171.93,192 171.93,188.56 171.82,188.44 170.31,188.44 v3(169.71,187.85) ; v3(184.81,146.3) 184.81,142.81 184.85,142.77 184.85,142.39 184.81,142.36 184.81,138.79 v3(187.07,136.53) ; v3(14.39,231.66) 14.39,231.61 12.85,230.07 11.65,230.07 10.24,228.66 10.24,225.58 10.1,225.44 9.12,224.46 7.93,224.46 7.75,224.64 7.37,224.64 7.1,224.37 7.1,223.83 6.95,223.67 6.86,223.67 6.46,223.28 R4202.1 ; v3(56.55,223.84) 55.9,223.19 55.9,222.81 56.17,222.54 56.46,222.54 56.6,222.4 56.6,221.92 56.6,214.03 57.1,213.54 57.1,212.45 v2(57.61,211.94) 57.61,210.72 58.85,209.47 58.85,202.26 63.29,197.82 63.35,197.76 63.35,197.75 63.78,197.75 66.04,195.49 66.04,190.11 69.21,186.94 82.26,186.94 82.37,187.05 116.71,187.05 120.63,187.45 145.95,187.45 148.16,189.66 150.22,189.66 v3(152.98,192.43) ; v3(193.14,188.56) 193.69,189.11 R5101.1 ; v3(177.77,36.36) 177.63,36.36 176.67,37.31 174.66,37.31 R2055.1 173.58,38.4 173.58,39.94 173.58,43.02 174.37,43.81 177.75,43.81 179.1,42.46 179.34,42.46 180.57,41.23 187.55,41.23 187.7,41.38 189.64,41.38 v3(190.08,40.94) ; v1(164.74,131.07) 164.46,130.78 164.41,130.78
  BOTTOM w0.102: v3(193.14,188.56) 193.12,188.54 176.94,188.54 174.01,191.48 172.93,192.56 v3(171.37,192.56) ; v1(164.74,131.07) 165.36,131.07 165.82,131.52 167.57,131.52 169.38,133.34 170.29,133.34 173.38,136.42 175.25,136.42 175.68,136.86 186.74,136.86 v3(187.07,136.53) 187.11,136.53 190.93,132.71 190.93,132.38 193.34,129.97 193.34,44.98 190.83,42.47 190.83,42.24 190.83,41.69 v3(190.08,40.94) ; v3(177.77,36.36) 177.72,36.36 175.39,34.02 v3(175.39,31.75) ; v3(152.98,192.43) 160.08,192.43 160.24,192.58 162.31,192.58 162.46,192.43 164.18,190.72 164.19,190.71 165.01,189.89 167.67,189.89 v3(169.71,187.85) 170.39,187.17 170.53,187.17 170.54,187.17 172.11,185.66 172.11,185.17 175.9,181.38 183.62,181.38 183.83,181.17 185.82,179.18 185.82,176.72 180.42,171.31 180.42,170.53 179.98,170.1 179.98,166.34 180.75,165.58 180.75,162.91 182.33,161.33 183.1,161.33 184.1,160.33 184.1,153.87 183.18,152.95 182.8,152.57 182.8,148.31 v3(184.81,146.3) ; v3(14.39,231.66) 14.73,232 14.73,235.15 15.44,235.86 19.06,235.86 19.72,236.52 20.1,236.52 20.33,236.3 22.1,236.3 22.87,237.06 36.33,237.06 41.18,232.21 45.87,232.21 46.06,232.21 53.45,224.82 53.96,224.82 53.97,224.81 54.85,223.93 56.47,223.93 v3(56.55,223.84)
SLP_WLAN_N: length 258.3
  TOP w0.089: SB1.BD42 162.3,131.91 162.67,131.55 163.74,131.55 164.1,131.91 164.1,132.05 164.7,132.64 164.78,132.64 165.9,133.76 165.99,133.76
  TOP w0.102: v3(181.33,152.86) 181.33,140 v3(180.97,139.65) ; v1(166.27,134.29) 166.27,134.04 165.99,133.76 ; v3(170.19,185.54) 169.28,184.63 163.47,184.63 162.97,184.13 159.47,184.13 159.28,184.32 157.06,184.32 155.89,183.76 153.92,181.79 119.74,181.79 118.46,182.14 117.11,182.45 82.33,182.45 82.19,182.59 81.45,182.88 81.26,182.95 81.26,182.95 81.06,183.06 80.97,183.09 80.86,183.14 80.82,183.16 80.73,183.2 80.69,183.21 80.57,183.27 80.45,183.31 80.45,183.32 80.11,183.46 80.04,183.53 79.92,183.58 79.72,183.66 77.23,184.64 77.19,184.64 77.13,184.66 74.14,184.96 68.06,184.96 56.41,196.61 56.41,200.69 54.64,202.47 54.64,204.29 48.41,216.01 48.41,221.06 48.41,224.43 46.89,225.96 46.23,225.96 v3(46.2,225.93) ; v3(35.31,233.04) 35.26,233.1 35.26,233.24 35.26,235.2 34.85,235.61 v2(34.85,236.21) 34.94,236.3 R2044.1 36.08,237.36 R2048.1 36.27,237.55 D6301.K
  BOTTOM w0.102: v3(180.97,139.65) 180.82,139.5 174.32,139.5 173.94,139.12 173.86,139.12 172.04,139.12 168.91,135.98 168.29,135.98 166.6,134.29 v1(166.27,134.29) ; v3(46.2,225.93) 42.68,229.45 42.68,229.52 42.34,229.86 42.28,229.86 41.3,230.84 37.97,230.84 37.95,230.81 37.54,230.81 v3(35.31,233.04) ; v3(170.19,185.54) 170.87,184.86 170.87,184.66 175.39,180.14 183.11,180.14 184.58,178.66 184.58,177.24 179.17,171.83 179.17,171.05 178.74,170.62 178.74,163.14 181.25,160.62 181.25,159.28 181.94,158.6 181.94,153.69 181.94,153.68 181.94,153.46 181.56,153.09 v3(181.33,152.86)
SM_DRAMRST#: length 201.2
  TOP w0.089: 161.89,135.81 161.58,135.81 161.28,135.51 161.28,135.11 161.31,135.08 161.31,134.44 SB1.BB46
  TOP w0.102: v3(121.33,174.99) 122.54,174.99 124.57,177.02 v3(126.6,177.02) ; v1(164.39,137.9) 164.39,137.09 164.02,136.73 162.94,136.73 162.11,135.9 162.02,135.81 161.89,135.81 ; v3(121.04,185.29) 121.37,185.62 149.74,185.62 150.67,186.56 150.67,187.96 v3(151,188.29) ; DIMM1.58 62.64,158.89 62.64,160.48 62.03,161.09 62.03,161.54 61.15,162.42 DIMM2.58 61.3,165 62.99,163.31 62.99,163.21 64.02,162.18 75.28,162.18 76.24,163.14 76.24,164.32 75.81,164.74 75.81,166.52 76.24,166.94 76.24,167.73 75.81,168.15 75.81,169.41 76.26,169.86 R1104.2 C1108.1 77.79,170.94 78.87,170.94 v3(78.99,170.81)
  BOTTOM w0.102: v3(151,188.29) 152.07,187.22 156.39,187.22 158.66,184.96 159.74,184.96 162.16,182.54 162.64,181.5 163.12,180.56 164.04,178.57 164.14,178.31 164.92,175.9 164.96,175.74 165.15,175.17 165.22,174.98 165.33,174.63 165.33,172.96 168.53,169.76 168.53,166.28 169.11,165.7 169.11,162.33 169.29,161.69 169.29,154.7 170.84,153.15 170.84,153.12 172.2,151.75 172.4,151.56 172.4,146.64 169.01,143.25 169.01,142.66 165.71,139.36 165.71,139.09 165.63,139.01 165.63,138.56 165.35,138.28 165.15,138.28 164.77,137.9 v1(164.39,137.9) ; v3(78.99,170.81) 79.15,170.66 109.47,170.66 111.2,172.39 119.41,172.39 119.7,172.39 121.33,174.02 v3(121.33,174.99) ; v3(121.04,185.29) v2(121.04,183.29) 121.04,182.58 v3(126.6,177.02)
SM_PGCNTL: length 113.7
  TOP w0.089: CPU1.AC36 59.35,101.23 55.79,101.23
  TOP w0.102: R416.2 19.43,170.56 v3(19.18,170.31) ; v3(8.89,162.94) 9.02,162.81 9.02,155.11 9.19,154.93 9.19,145.44 13.85,140.78 14.47,140.78 16.76,138.49 16.76,126.87 21.16,122.47 21.16,121.24 44.13,98.27 52.24,98.27 55.2,101.23 55.79,101.23
  BOTTOM w0.102: v3(8.89,162.94) 9.4,163.45 v2(9.4,163.8) 9.4,164.35 10.79,165.74 10.79,167.93 13.21,170.34 13.21,170.52 13.63,170.94 15.08,170.94 15.99,170.03 18.9,170.03 v3(19.18,170.31)
SMB_CLK_MAIN: length 284.3
  TOP w0.102: DIMM1.141 136.8,154.85 128.04,146.09 128.04,114.52 124.61,111.09 124.61,105.42 130.47,99.56 130.47,86.13 138.75,77.86 138.75,53.09 140.23,51.61 140.23,47.64 145.29,42.59 145.29,40.12 143.89,38.73 v3(143.89,30.53) ; RN2405.1 167.25,33.51 167.04,33.3 167.04,32.78 167.82,32 169.76,32 170.18,31.58 170.18,31.58 170.69,31.07 U2401.81 170.69,29.41 170.31,29.03 168.86,29.03 v3(168.4,28.57) ; v3(56.99,13.42) 56.99,13.44 57.82,14.27 58.36,14.27 R5911.2
  BOTTOM w0.102: v3(168.4,28.57) 167.89,28.07 164.11,28.07 161.77,25.73 158.65,25.73 154.53,29.84 144.58,29.84 v3(143.89,30.53) 143.32,30.53 143.31,30.54 142.51,30.54 141.3,29.34 141.29,29.34 141.19,29.24 118.06,29.24 117.74,29.55 111.61,29.55 104.27,22.21 104.27,22.06 103.63,21.42 102.15,21.42 101.07,22.5 95.4,22.5 94.64,21.74 92.94,21.74 91.52,23.16 82.89,23.16 79.69,19.96 v2(74.73,19.96) 74.23,19.96 67.46,13.2 57.21,13.2 v3(56.99,13.42) ; DIMM2.141 136.74,163.34 136.74,160.96 135.99,160.22 135.99,158.96 136.8,158.15 DIMM1.141
SMB_CLK_RESUME: length 168.3
  TOP w0.102: v1(165.5,122.55) 165.1,122.96 165.1,123.36 164.2,124.26 162.43,124.26 SB1.BE26 ; SLOT2.B5 184.05,49.45 185.04,50.44 185.04,52.32 185.55,52.83 186.77,52.83 v1(187.12,53.19) ; RN2404.1 169.26,33.53 v3(168.72,33) ; SLOT1.B5 162.69,47.98 162.69,43.79 v3(161.52,42.62) ; v3(167.59,32.89) 168.25,32.23 169.93,32.23 170.41,31.76 170.41,31.68 170.94,31.14 171.03,31.14 171.09,31.08 U2401.80
  BOTTOM w0.102: SLOT1.B5 167.41,48.94 168.75,47.6 168.76,47.6 170.5,45.86 178.47,45.86 179.32,46.71 179.88,46.71 180.94,47.78 182.4,47.78 183.53,48.91 183.93,48.91 SLOT2.B5 ; v1(187.12,53.19) 187.12,54.53 184.86,56.79 184.86,58.54 184.99,58.67 184.99,63.18 184.26,63.91 183.93,63.91 183.34,64.5 183.34,75.08 183.92,75.67 184.57,75.67 185.59,76.68 186.27,76.68 186.99,77.4 186.99,123.86 186,124.84 185.49,124.84 184.52,125.81 184.03,125.81 182.17,127.66 181.84,127.8 181.66,127.92 181.51,128.02 181.24,128.29 180.72,128.81 180.72,129.3 180.44,129.58 180.3,129.72 179.07,129.72 171.45,122.1 169.96,122.1 168.61,120.74 168.51,120.74 168.04,120.27 166.74,120.27 166.05,120.96 166.05,121.02 v2(165.5,121.56) v1(165.5,122.55) ; v3(168.72,33) 168.62,32.89 v3(167.59,32.89) 167.59,33.19 165.9,34.87 165.82,34.87 165.07,35.62 165.07,36.88 166.45,38.25 166.45,40.39 166.4,40.44 166.4,41.35 165.58,42.16 161.98,42.16 v3(161.52,42.62)
SMB_DATA_MAIN: length 306.6
  TOP w0.102: RN2405.2 167.9,33.24 168.09,33.05 168.09,32.98 168.6,32.48 170.06,32.48 170.64,31.9 170.64,31.77 171.04,31.37 171.17,31.37 171.49,31.04 U2401.79 171.49,29.33 170.74,28.57 v3(169.27,28.57) ; v3(55.12,10.92) 55.12,12.2 56.8,13.88 57.1,13.88 57.66,14.43 R5912.2 ; v3(143.12,29.97) 143.12,38.28 145.06,40.22 145.06,42.49 140,47.55 140,51.51 138.52,53 138.52,77.76 130.24,86.04 130.24,99.47 124.38,105.32 124.38,111.18 127.81,114.61 127.81,146.19 136.02,154.39 136.02,156.53 136.8,157.32 DIMM1.285
  BOTTOM w0.102: DIMM2.285 136.8,164.57 137.49,163.89 137.49,162.55 136.96,162.03 136.96,160.86 136.8,160.7 DIMM1.285 ; v3(55.12,10.92) 59.12,10.92 59.19,10.99 60.6,10.99 60.75,10.84 61.38,10.21 68.5,10.21 69.88,11.58 74.35,11.58 80.88,5.05 94.85,5.05 95.3,5.5 97.3,5.5 98.54,4.26 122.12,4.26 124.18,6.32 125,6.32 126.52,7.84 126.52,9.68 127.89,11.05 127.89,16.33 129.52,17.96 136.19,17.96 140.84,22.61 140.84,23.18 141.44,23.77 141.9,23.77 143.12,25 v3(143.12,29.97) 143.89,29.97 144.25,29.62 153.67,29.62 157.78,25.5 162.36,25.5 v2(164.11,27.25) 164.67,27.81 168.5,27.81 v3(169.27,28.57)
SMB_DATA_RESUME: length 168
  TOP w0.102: v3(172.59,36.45) 172.59,37.26 169.5,40.35 169.5,40.83 168.75,41.58 168.59,41.58 168.33,41.85 168.33,42.23 168.4,42.3 v3(168.4,43.05) ; U2401.78 171.89,30.97 171.26,31.6 171.13,31.6 170.87,31.87 170.87,31.99 169.86,32.99 169.67,32.99 169.65,32.97 v3(169.59,32.97) 169.91,33.29 RN2404.2 ; v1(164.69,122.58) 164.69,122.58 164.69,123.48 164.14,124.03 SB1.BF26 ; v3(163.19,43.1) 164.47,44.37 164.47,48.76 SLOT1.B6
  BOTTOM w0.102: SLOT1.B6 166.73,49.94 168.84,47.83 168.86,47.83 170.6,46.09 178.37,46.09 179.22,46.94 179.78,46.94 180.85,48.01 181.99,48.01 183.78,49.79 SLOT2.B6 186.05,50.44 186.76,51.15 186.76,52.94 186.69,53.01 186.69,53.37 186.76,53.44 186.76,54.56 184.63,56.7 184.63,56.88 183.34,58.16 183.34,59.08 184.02,59.77 184.03,59.77 184.76,60.5 184.76,63.08 184.17,63.68 183.83,63.68 183.11,64.4 183.11,75.18 183.83,75.9 184.48,75.9 185.5,76.91 186.18,76.91 186.76,77.5 186.76,98.08 186.09,98.76 185.55,98.76 184.51,99.8 184.04,99.8 182.63,101.21 182.63,126.72 181.77,127.57 181.37,127.84 180.49,128.72 180.49,129.21 180.21,129.49 179.16,129.49 171.39,121.72 169.91,121.72 168.7,120.51 168.6,120.51 168.13,120.04 166.51,120.04 166.48,120.07 166.14,120.07 v2(166.07,120.14) 164.69,121.51 164.69,122.58 v1(164.69,122.58) ; v3(168.4,43.05) 168.35,43.1 v3(163.19,43.1) ; v3(172.59,36.45) 172.14,36.45 169.59,33.9 v3(169.59,32.97)
SMBALERT_N: length 8.1
  TOP w0.102: R2314.1 166.99,125.46 166.37,124.84 166.37,124.05 v2(165.86,123.55) 166.11,123.29 166.11,122.47 166.11,122.47 166.11,122.3 165.76,121.94 164.46,121.94 163.21,123.2 162.9,123.2 SB1.BE25
SML0ALERT#: length 5.6
  TOP w0.102: SB1.BF24 163.15,122.97 164.37,121.74 164.55,121.74 164.91,121.38 v2(165.5,121.38) 165.58,121.46 165.82,121.46 166.12,121.76 166.12,122 166.54,122.42 166.72,122.42 166.88,122.58 R2323.1
SML0CLK_PCH: length 11.1
  TOP w0.102: SB1.BF25 163.19,123.5 164.54,122.15 165.67,122.15 165.91,122.38 165.91,122.72 165.67,122.96 165.66,122.96 165.3,123.31 165.3,123.78 165.63,124.1 165.84,124.1 166.12,124.38 166.12,124.77 165.98,124.9 v2(165.98,125.92) 166.18,126.11 167.1,126.11 167.49,126.5 167.49,127.47 R2009.1
SML0DATA_PCH: length 8.4
  TOP w0.102: R2010.1 167.75,122.66 167.75,122.66 167.49,122.4 167.17,122.4 v3(166.73,121.96) 166.29,121.53 166.29,121.39 165.73,120.83 165.18,120.83 164.47,121.54 164.29,121.54 163.29,122.54 162.63,122.54 SB1.BE24
  BOTTOM w0.102: v2(167.06,121.06) 167.06,121.07 167.06,121.08 v3(166.73,121.96)
SMLICLK_PCH: length 192.4
  TOP w0.102: v3(165.68,124.56) 165.25,124.99 164.68,124.99 164.43,124.75 163.04,124.75 SB1.BF27 ; v3(173.35,9.4) 173.35,9.59 R2426.1 ; v3(157.78,5.64) 157.28,6.14 157.28,6.85 156.67,7.46 156.67,8.93 157.48,9.74 157.48,11.05 v3(157.61,11.18) R2012.1
  BOTTOM w0.102: v3(165.68,124.56) 166.16,124.56 167.01,123.71 172.02,123.71 178.08,129.77 178.08,129.83 178.13,129.88 178.13,129.97 179.76,131.6 184.87,131.6 188.41,128.06 188.41,127.87 188.41,76.55 188.18,76.32 188.18,58.12 187.05,56.99 187.05,56.61 188.54,55.12 188.54,52.6 188.21,52.27 188.21,50.6 187.73,50.11 187.73,48.14 186.44,46.85 185.7,46.85 184.7,45.85 183.78,45.85 182.49,44.56 182.49,44.4 181.94,43.85 180.88,43.85 179.07,42.04 179.07,41.6 176.71,39.23 176.71,38.5 173.79,35.58 173.79,28.65 168.91,23.77 167.2,23.77 165.49,22.07 162.43,22.07 157.86,17.5 157.86,11.43 v3(157.61,11.18) ; v3(157.78,5.64) 158.27,5.15 159.6,5.15 160.04,5.59 160.5,5.59 161.12,6.21 163.1,6.21 164.54,7.65 170.05,7.65 170.16,7.54 171.5,7.54 v2(172.38,8.42) v3(173.35,9.4)
SMLIDATA_PCH: length 192.3
  TOP w0.102: v3(172.47,9.4) 173.1,10.03 R2422.1 ; 157.96,10.4 v3(157.99,10.4) ; 157.96,10.4 157.96,10.5 158.7,11.24 R2013.1 ; 157.96,10.4 157.91,10.35 157.91,9.85 156.9,8.83 156.9,7.56 157.51,6.95 157.51,6.75 v3(158.64,5.61) ; SB1.BE27 162.71,124.46 163.65,124.46 163.73,124.54 164.8,124.54 v1(164.85,124.59)
  BOTTOM w0.102: v3(158.64,5.61) 159.74,5.61 159.94,5.82 160.4,5.82 161.03,6.44 163,6.44 164.44,7.88 169.32,7.88 169.95,8.51 171.58,8.51 v3(172.47,9.4) ; v3(157.99,10.4) 157.73,10.4 157.15,10.99 157.15,17.42 162.03,22.3 165.4,22.3 167.1,24 168.07,24 v2(168.69,24.62) 168.91,24.84 169.57,24.84 173.56,28.83 173.56,35.67 176.48,38.59 176.48,39.33 178.84,41.69 178.84,42.14 180.78,44.08 181.84,44.08 182.26,44.5 182.26,44.65 183.69,46.08 184.34,46.08 185.34,47.08 186.34,47.08 187.5,48.24 187.5,50.21 187.99,50.69 187.99,52.36 188.32,52.69 188.32,55.02 186.82,56.52 186.82,57.08 187.95,58.22 187.95,76.42 188.18,76.64 188.18,127.96 184.78,131.37 179.88,131.37 179.65,131.14 178.36,129.85 178.36,129.79 178.31,129.74 178.31,129.67 172.12,123.48 166.91,123.48 166.46,123.93 165.5,123.93 v1(164.85,124.59)
SP_CTS_N: length 7.1
  TOP w0.102: U2401.101 162.38,26.98 162.01,27.34 162.01,27.47 161.98,27.51 161.98,27.53 160.99,28.52 160.99,28.96 160.58,29.36 v2(158.72,29.36) 158.45,29.64 RN2402.3
SP_DCD_N: length 4.4
  TOP w0.102: U2401.96 164.69,31.78 v2(163.83,32.64) 163.33,33.14 RN2401.4
SP_DSR_N: length 7.2
  TOP w0.102: U2401.97 162.33,28.58 161.9,29.01 161.9,29.54 161.29,30.15 161.29,31.83 v2(162.36,32.89) 162.68,33.22 RN2401.3
SP_DTR_N: length 6.8
  TOP w0.102: U2401.102 162.35,26.58 161.79,27.14 161.79,27.37 161.75,27.41 161.75,27.44 161.46,27.72 161.43,27.72 v2(160.43,28.73) 158.34,28.73 157.93,29.14 RN2402.2
SP_RI_N: length 6.6
  TOP w0.102: U2401.103 162.21,26.18 v2(161.23,27.17) 160.22,28.17 160.19,28.17 159.88,28.49 RN2402.1
SP_RTS_N: length 8.2
  TOP w0.102: U2401.99 162.42,27.78 161.44,28.75 161.44,29.18 v2(160.43,30.2) 160.68,30.45 160.68,32.2 161.53,33.05 RN2401.1
SP_RXD_N: length 62
  TOP w0.102: v3(186.64,4.7) 185.8,4.7 185.43,5.07 R6802.1 ; v3(162.4,4.59) 162.4,5.8 v2(162.43,5.84) 162.69,6.1 162.69,8.58 162.66,8.61 162.66,11.11 162.69,11.13 162.69,11.85 163.75,12.92 163.75,13.65 164.16,14.06 164.16,15.21 164.71,15.76 164.71,17.41 167.08,19.78 167.08,21.92 165.1,23.9 165.1,27.08 164,28.18 U2401.98 162.4,28.18 161.67,28.91 161.67,29.45 161.06,30.06 161.06,31.92 161.77,32.63 161.77,33.12 162.18,33.53 RN2401.2
  BOTTOM w0.102: v3(162.4,4.59) 163.07,3.91 167.47,3.91 167.83,4.27 186.21,4.27 v3(186.64,4.7)
SP_RXD_N_CON: length 3.1
  TOP w0.102: LPC1.14 186.01,3.96 v2(185.99,3.99) 185.8,4.18 R6802.2
SP_TXD_N: length 4.4
  TOP w0.102: Q2402.3 157.14,32 R2473.1 157.78,31.47 v2(158.57,30.68) 159.13,30.68 159.31,30.86 159.31,31.48 R2429.2
SP_TXD_N_1: length 5.4
  TOP w0.102: R2405.2 159.94,36.13 159.94,35.69 159.93,35.67 159.93,34.05 160.66,33.33 v2(160.66,32.96) 160.18,32.96 159.56,33.58 Q2402.5
SP_TXD_SIO: length 63.8
  TOP w0.102: R6801.1 185.94,6.97 v3(186.56,6.35) ; R2429.1 160.19,30.9 159.87,30.58 159.87,29.97 160.22,29.62 160.65,29.62 161.21,29.05 161.21,28.62 162.2,27.62 162.2,27.6 162.43,27.38 U2401.100 164.24,27.38 164.82,26.8 164.82,23.86 166.85,21.83 166.85,19.88 164.48,17.51 164.48,15.86 163.93,15.31 163.93,14.15 163.53,13.75 163.53,13.01 162.46,11.95 162.46,11.23 162.43,11.2 162.43,8.51 162.46,8.48 162.46,8 161.54,7.09 v3(161.54,4.45)
  BOTTOM w0.102: 187.1,5.55 187.1,5.81 v3(186.56,6.35) ; 187.1,5.55 v2(187.1,5.55) ; 187.1,5.55 187.1,4.51 186.63,4.04 168.16,4.04 167.81,3.68 162.31,3.68 v3(161.54,4.45)
SP_TXD_SIO_CON: length 3.6
  TOP w0.102: LPC1.13 187.02,4.96 186.68,5.3 186.24,5.3 v2(185.94,5.6) 185.46,6.08 R6801.2
SPEED_100*_CON: length 13.6
  TOP w0.267: R3201.1 111.32,30.48 109.59,30.48 109.42,30.31 109.42,28.56 109.97,28.01 EU3202.4 107.37,25.09 RJ45R1.19
SPEED_100_N: length 39.3
  TOP w0.203: U3101.26 139.05,27.71 139.48,28.14 139.48,28.15
  TOP w0.267: 139.48,28.15 141.98,30.65 141.98,33.08 140.88,34.19 125.33,34.19 123.53,32.38 TP3102.1 122,32.38 121.64,32.03 121.11,32.03 118.9,29.81 115.2,29.81 114.72,29.34 R3201.2
SPEED_1000*_CON: length 14.3
  TOP w0.267: RJ45R1.20 103.75,27.04 106.94,27.04 EU3202.3 108.3,28.4 108.62,28.4 109,28.78 109,30.48 109.45,30.93 112.01,30.93 R3202.1
SPEED_1000_N: length 40.1
  TOP w0.203: U3101.25 139.45,27.42 139.54,27.52 139.54,27.56 139.58,27.59
  TOP w0.267: R3202.2 118.97,30.48 120.22,31.73 TP3103.1 121.28,33.4 123.95,33.4 125.16,34.61 141.05,34.61 142.4,33.26 142.4,30.42 139.58,27.59
SPI_CLK_PCH: length 55.7
  TOP w0.102: RN2502.4 175.03,170.46 174.05,171.44 R1515.1 174.04,171.45 173.33,170.74 172.24,170.74 172.03,170.53 172.03,169.06 169.99,167.02 167.66,167.02 167.02,166.37 v3(167.02,166.01) 166.56,166.01 165.77,166.8 165.77,169.04 167.08,170.36 R9107.1 ; v1(161.29,137.79) 161.29,137.79 159.19,135.69 159.19,134.43 159.34,134.28 159.38,134.28 159.58,134.08 SB1.AW47
  BOTTOM w0.102: v1(161.29,137.79) 161.97,137.79 163.22,139.04 163.22,140.01 163.3,140.09 163.3,140.36 165.1,142.17 165.1,142.48 165.35,142.73 165.35,143.29 165.22,143.42 165.22,150.04 165.64,150.46 165.64,152.26 166.83,153.45 166.83,154.84 166.56,155.11 166.56,156.86 v2(166.95,157.26) 167.17,157.47 167.17,159.19 166.52,159.84 166.52,160.67 167.39,161.54 167.39,164.24 167.61,164.46 167.61,165.16 167.02,165.75 v3(167.02,166.01)
SPI_CLK_ROM1: length 12.6
  TOP w0.102: RN2502.1 177.17,170.46 177.39,170.68 v3(177.71,170.68) 177.71,166.92 178.33,166.3 U2502.16 176.48,166.04 175.74,166.78 174.74,166.78 174.61,166.65 174.61,165.82 174.36,165.57 U2501.6
  BOTTOM w0.102: v3(177.71,170.68) 177.7,170.69 v2(177.08,171.41)
SPI_CLK_TPM: length 1.8
  TOP w0.102: R9107.2 166.62,172.35 U9101.19
SPI_CS_PCH_N0: length 32.7
  TOP w0.102: SB1.AY47 160.08,134.22 159.86,134.45 159.86,134.86 159.76,134.95 159.76,135.69 160.21,136.13 160.26,136.19 161.01,136.93 161.14,137.06 161.42,137.06 162.05,137.69 v1(162.05,138.56) ; U2501.1 170.47,158.58 170.31,158.42 U2502.7 SSKT2.7 166.64,158.42 166.54,158.32 v3(166.19,158.32)
  BOTTOM w0.102: v1(162.05,138.56) 162.74,139.24 v2(162.74,140.32) 162.74,140.67 164.44,142.37 164.44,150.27 164.93,150.75 164.93,152.56 166.12,153.75 166.12,154.54 165.84,154.81 165.84,157.97 v3(166.19,158.32)
SPI_CS_PCH_N2: length 48.4
  TOP w0.102: v3(166.22,166.99) 166.28,167.04 166.28,168.87 168.15,170.74 R9108.1 ; v1(159.39,131.07) 158.47,131.07 SB1.AT40 ; R9928.2 164.11,151.13 164.39,151.41 164.39,152.71 v3(164.59,152.91)
  BOTTOM w0.102: v3(166.22,166.99) 166.35,166.86 166.35,165.66 v2(166.12,165.43) 166.24,165.3 166.24,161.4 165.81,160.97 165.81,159.54 165.81,159.54 165.81,158.65 165.62,158.45 165.62,154.72 165.89,154.45 165.89,153.84 165.49,153.44 165.12,153.44 v3(164.59,152.91) 164.59,150.74 164.21,150.36 164.21,142.58 163.36,141.73 163.36,141.73 162.18,140.55 162.18,139.26 160.88,137.96 160.88,136.66 161.09,136.46 161.09,135.83 161.04,135.78 161.04,134.67 160.43,134.05 160.43,132.55 160.06,132.18 159.45,132.18 159.18,131.92 159.18,131.28 v1(159.39,131.07)
SPI_HOLD_PCH: length 48.3
  TOP w0.089: 160.16,135.44 160.16,135.12 160.48,134.8 160.48,134.09 SB1.BA46
  TOP w0.102: R2507.2 172.52,170.26 172.52,168.87 170.19,166.54 167.86,166.54 167.64,166.31 167.64,165.64 167.11,165.11 167.11,165.07 167.1,165.07 v3(167.1,165) 167.03,165 166.98,164.95 166.95,164.95 166.67,164.67 R2502.2 ; 160.16,135.44 160.17,135.44 160.17,135.52 160.43,135.78 160.44,135.78 160.45,135.78 161.32,136.65 161.58,136.65 162.53,137.6 162.53,138.05 162.74,138.25 162.74,138.73 164.06,140.05 164.06,140.29 165.07,141.3 165.07,142.34 164.87,142.54 v1(164.87,142.9) 164.95,142.82 166.26,142.82 166.7,143.27 R2317.1
  BOTTOM w0.102: v1(164.87,142.9) 164.87,143.01 164.74,143.14 164.74,150.24 165.16,150.66 165.16,152.46 166.34,153.65 166.34,154.64 166.07,154.91 166.07,157.17 166.69,157.78 166.69,158.99 166.04,159.64 166.04,160.87 166.83,161.66 v2(166.83,162.56) 166.83,164.72 v3(167.1,165)
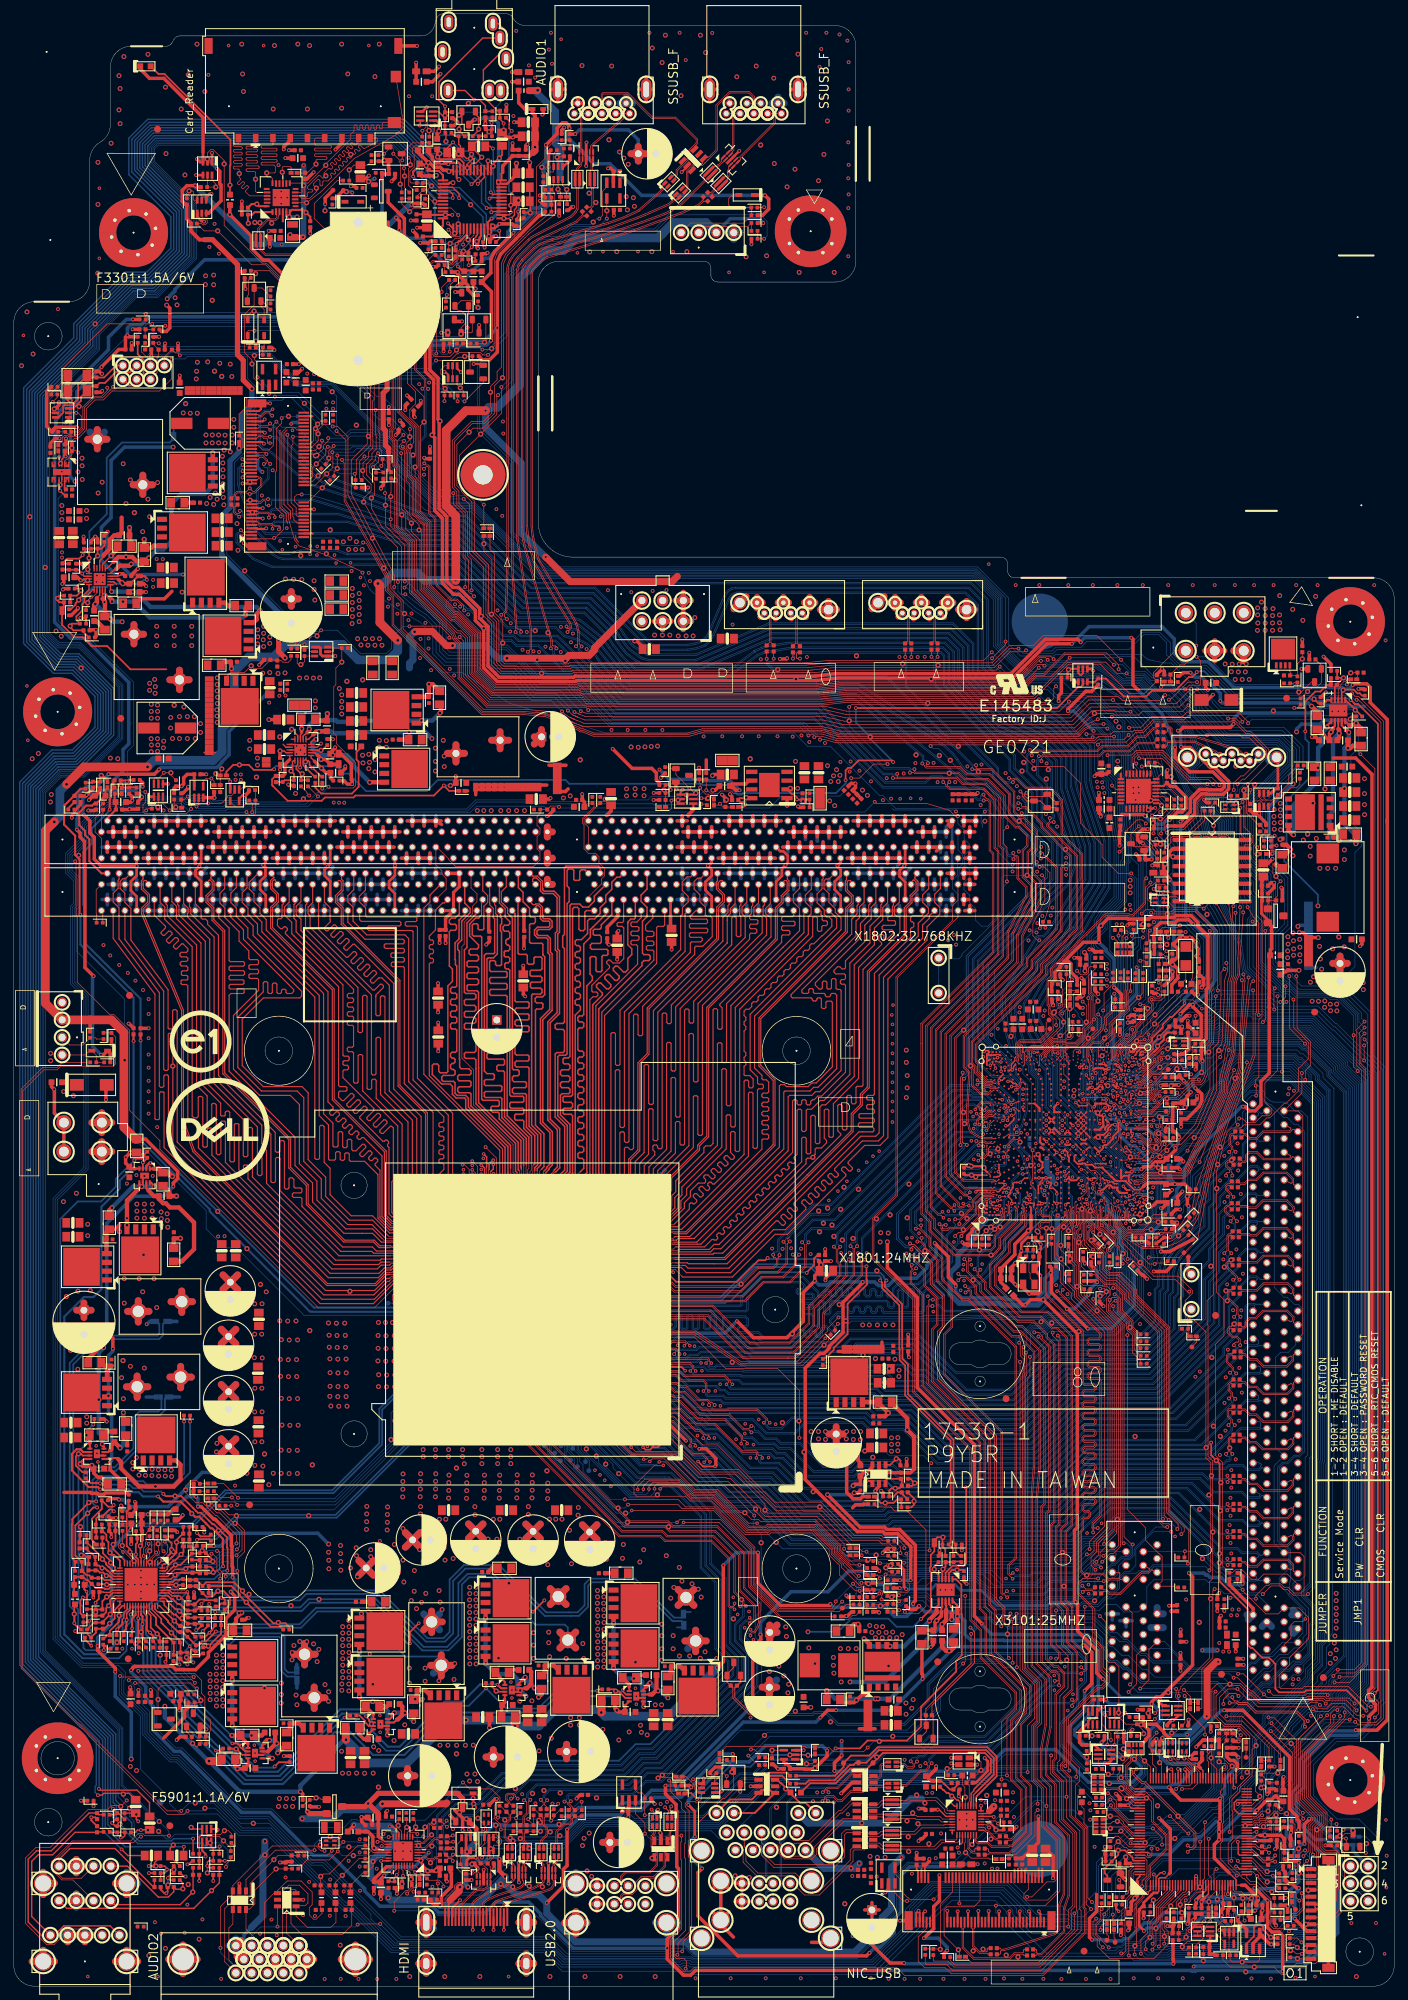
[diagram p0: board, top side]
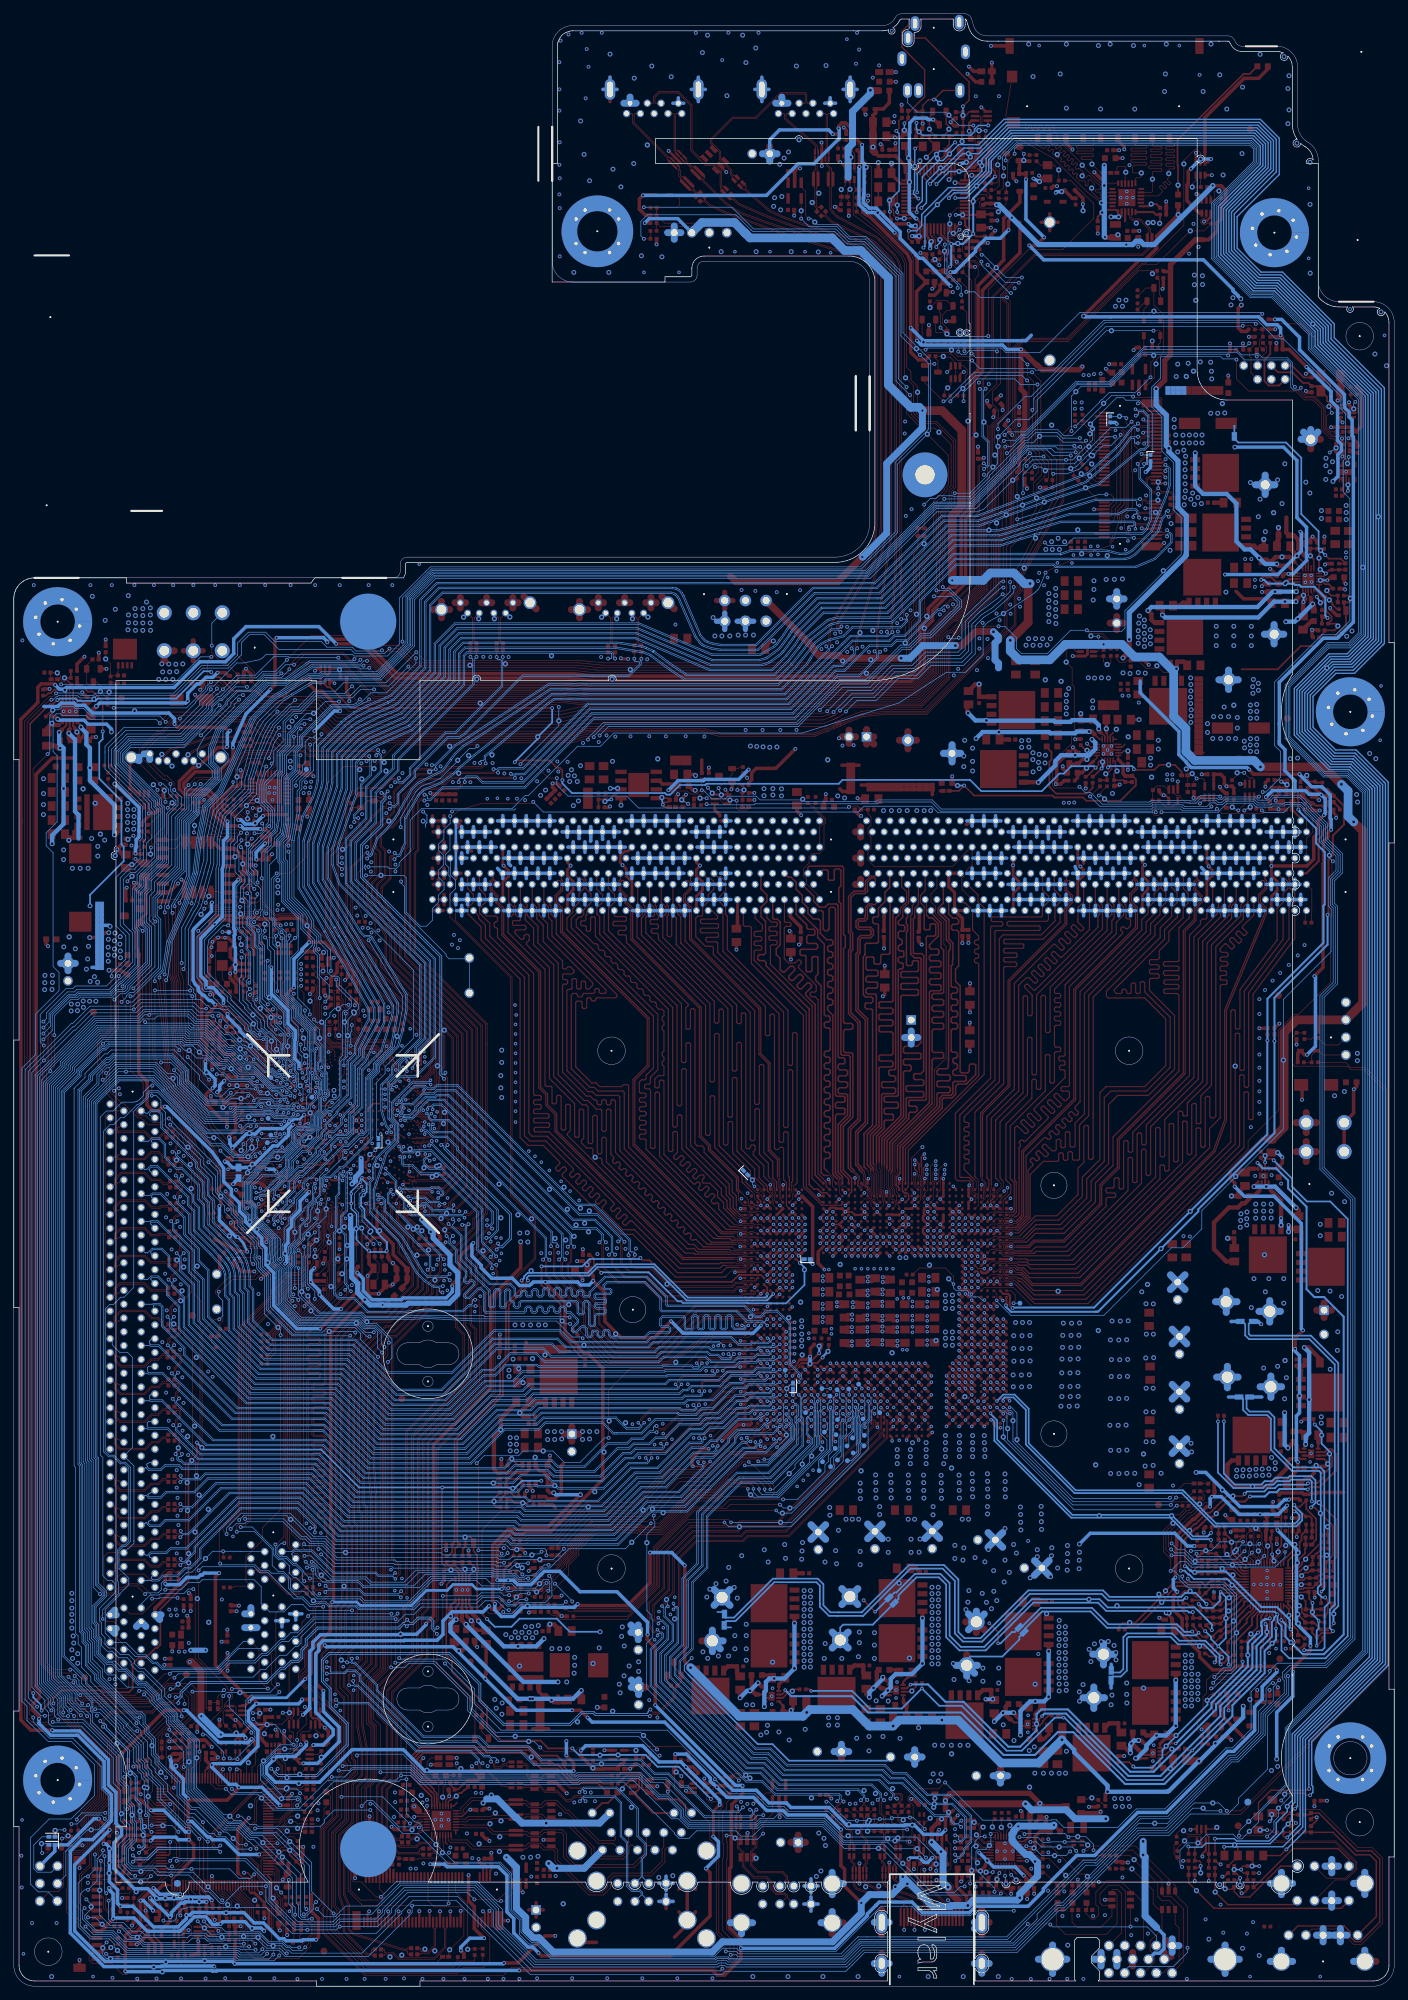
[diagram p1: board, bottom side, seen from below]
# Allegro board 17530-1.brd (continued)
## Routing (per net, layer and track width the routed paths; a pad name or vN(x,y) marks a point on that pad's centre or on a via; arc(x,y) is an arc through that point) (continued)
SPI_HOLD_ROM1: length 12
  TOP w0.102: U2502.1 170.19,166.04 170.95,166.8 171.93,166.8 172.06,166.67 172.06,165.79 172.28,165.57 U2501.7 173.09,165.57 173.34,165.82 173.34,166.79 173.63,167.08 173.88,167.08 v3(173.91,167.11) 173.91,168.96 173.4,169.48 R2507.1
  BOTTOM w0.102: v2(173.82,168.13) v3(173.91,167.11)
SPI_SI_PCH: length 64.4
  TOP w0.102: RN2502.3 175.69,171.11 176.36,171.79 176.36,171.96 176.38,171.98 176.38,172.42 R9903.1 175.92,172.43 175.7,172.22 172.66,172.22 172.61,172.28 172.25,172.28 171.55,171.58 171.55,169.6 169.47,167.51 167.48,167.51 167.08,167.12 v3(167.08,167.09) 167.05,167.09 166.76,167.37 166.76,168.89 168.38,170.51 168.67,170.51 R9106.1 ; v1(159.59,131.75) 159.44,131.75 159.1,131.41 SB1.AU41 ; v3(165.79,144.45) 165.37,144.45 R2326.1 164.9,145.2 R2325.1
  BOTTOM w0.102: v1(159.59,131.75) 159.92,131.75 160.63,132.46 160.63,133.97 161.26,134.6 161.26,135.72 161.29,135.74 161.29,136.59 162.98,138.28 163.13,138.28 163.7,138.85 163.7,139.81 163.78,139.89 163.78,140.16 165.58,141.97 165.58,142.28 166.25,142.94 166.25,144 165.8,144.45 165.8,144.45 ; v3(167.08,167.09) 167.56,166.61 167.56,165.88 168.09,165.36 168.09,163.75 v2(167.94,163.6) 167.94,161.41 167,160.47 167,160.04 167.69,159.35 167.69,153.34 167.54,153.19 167.54,153.07 166.35,151.88 166.35,150.16 165.93,149.75 165.93,146.01 166.32,145.62 166.32,144.97 165.8,144.45 ; 165.8,144.45 v3(165.79,144.45)
SPI_SI_ROM1: length 15
  TOP w0.102: RN2502.2 177.14,171.11 177.2,171.17 177.64,171.17 v3(178.03,171.56) 178.21,171.39 178.21,170.86 178.23,170.83 178.23,167.92 179.52,166.63 179.52,165.71 179.14,165.33 178.44,165.33 178.33,165.22 U2502.15 176.61,164.77 175.55,165.83 SSKT1.5
  BOTTOM w0.102: v2(178.21,173.2) v3(178.03,171.56)
SPI_SI_TPM: length 4.3
  TOP w0.102: U9101.21 167.71,173.35 R9106.2
SPI_SO_PCH: length 33.8
  TOP w0.089: 159.65,134.43 159.65,134.37 159.84,134.18 159.84,134.01 SB1.BA45
  TOP w0.102: R9113.1 165.98,158.79 165.56,158.37 165.56,157.76 RN2501.1 164.92,157.61 164.72,157.82 v3(164.72,158.19) ; v3(163.19,142.21) 163.22,142.19 163.8,142.19 164.29,141.71 v2(164.29,141.63) 164.29,141.2 163.61,140.53 R2328.1 163.27,139.92 162.35,138.99 161.87,138.99 161.62,138.74 161.62,138.04 161.7,137.96 161.7,137.63 161.33,137.26 161.05,137.26 159.56,135.77 159.56,134.87 159.65,134.77 159.65,134.43
  BOTTOM w0.102: v3(164.72,158.19) 164.72,157.86 165.06,157.52 165.06,155.91 165.27,155.69 165.27,155.29 165.06,155.07 165.06,154.92 165.66,154.32 165.66,153.94 165.39,153.67 164.71,153.67 164.13,153.1 164.13,152.53 164.36,152.3 164.36,151.05 163.98,150.67 163.98,143 v3(163.19,142.21)
SPI_SO_PCH_TPM: length 24
  TOP w0.102: R9113.2 166.87,159.4 166.67,159.59 165.64,159.59 165.53,159.48 165.53,159.31 v3(165.16,158.94) ; R9105.1 164.43,177.23 163.87,176.67 v3(163.42,176.67)
  BOTTOM w0.102: v3(165.16,158.94) 165.51,159.29 165.51,160.99 166.01,161.49 166.01,164.74 165.56,165.2 165.56,165.36 163.45,167.47 163.45,167.82 163.45,167.82 163.45,168.2 163.12,168.53 163.12,170.08 164.74,171.7 164.74,171.71 v2(164.74,171.76) 164.36,172.14 164.36,173.35 164.36,173.36 164.36,173.61 164.36,174.08 163.59,176.5 v3(163.42,176.67)
SPI_SO_ROM1: length 9.3
  TOP w0.102: RN2501.4 167.32,157.61 167.51,157.81 168.49,157.81 168.71,157.58 SSKT2.8 U2502.8 169.95,157.15 170.59,156.51 171.78,156.51 v3(172.2,156.93) 172.69,157.43 SSKT1.2
  BOTTOM w0.102: v2(171.75,157.87) v3(172.2,156.93)
SPI_SO_TPM: length 3.5
  TOP w0.102: R9105.2 165.81,177.24 166.37,176.68 166.37,175.73 U9101.24
SPI_WP_PCH: length 35.4
  TOP w0.089: SB1.AY48 160.08,134.93 159.97,135.04 159.97,135.53
  TOP w0.102: v3(167.23,156.33) 166.05,156.33 RN2501.2 164.73,156.96 164.21,157.48 164.21,158.95 164.68,159.41 164.96,159.41 165.71,160.16 R2501.2 ; R2313.1 166.96,146.08 166.22,145.34 v1(165.89,145.34) 166.25,144.98 166.25,143.39 165.98,143.12 165.26,143.12 165.05,143.33 164.69,143.33 164.44,143.08 164.44,142.62 164.85,142.21 164.85,141.4 163.96,140.52 163.83,140.38 163.83,140.15 162.51,138.83 162.51,138.35 162.3,138.14 162.3,137.66 161.5,136.85 161.23,136.85 160.42,136.04 160.36,135.98 160.35,135.98 160.3,135.94 159.97,135.6 159.97,135.53
  BOTTOM w0.102: v3(167.23,156.33) 167.23,155.42 v2(167.13,155.32) 167.31,155.14 167.31,153.17 166.12,151.98 166.12,150.26 165.71,149.84 165.71,145.52 v1(165.89,145.34)
SPI_WP_ROM1: length 15.3
  TOP w0.102: U2502.9 177.42,157.15 177.19,157.38 174.74,157.38 174.61,157.5 174.61,158.22 174.51,158.33 SSKT1.3 173.96,157.66 v3(172.4,156.09) 172.2,156.29 168.06,156.29 167.38,156.96 RN2501.3
  BOTTOM w0.102: v2(172.88,155.25) v3(172.4,156.09)
SPKR: length 297.3
  TOP w0.102: v3(80.29,184.78) 80.3,184.78 80.9,184.17 81.09,184.09 81.25,184.03 81.35,183.98 81.47,183.93 81.48,183.93 81.56,183.89 81.61,183.87 81.66,183.83 81.79,183.78 81.8,183.78 82.73,183.41 117.22,183.41 120.14,182.75 153.52,182.75 156.05,185.29 168.88,185.29 v3(171.45,187.86) ; v3(53.14,234.9) 53.14,233.3 52.22,232.38 52.22,229.86 51.94,229.58 51.94,224.59 52.02,224.51 52.02,222.83 51.41,222.22 51.41,221.45 50.6,220.64 50.6,218.72 51.77,217.55 51.77,216.62 50.69,215.54 v2(50.69,214.98) 52.81,211.21 55.59,208.43 55.6,208.41 55.6,203.58 v3(55.65,203.4) ; v3(61.22,236.5) 61.22,247.02 62.48,248.28 R2302.1 62.42,248.41 R2304.1 62.79,248.93 63.53,248.93 64.15,249.55 64.41,249.55 64.97,250.11 R2702.2 ; v3(187.12,131.29) 187.12,132.62 187.86,133.35 187.86,136.85 185.93,138.78 185.93,145.87 185.83,145.97 185.83,146.29 v3(185.82,146.3) ; v1(159.46,126.34) 159.46,126.29 159.72,126.03 SB1.AW29
  BOTTOM w0.102: v3(80.29,184.78) 78.35,186.72 75.33,186.72 72.16,189.89 69.21,189.89 67.31,191.8 62.59,191.8 61.19,193.19 61.19,197.28 61.03,197.43 60.91,197.56 60.9,197.56 59.77,198.67 59.73,198.7 58.35,199.57 58.07,199.79 56.4,201.26 55.65,202.02 v3(55.65,203.4) ; v3(187.12,131.29) 186.96,131.29 185.03,133.22 179.66,133.22 176.91,130.47 176.91,130.39 176.86,130.34 176.86,130.27 172.15,125.57 167.99,125.57 167.52,126.04 167.27,126.04 167.27,126.03 165.73,126.03 165.5,126.26 163.75,126.26 163.57,126.44 162.73,126.44 162.19,125.91 159.89,125.91 v1(159.46,126.34) ; v3(53.14,234.9) 54.13,235.89 60.61,235.89 v3(61.22,236.5) ; v3(171.45,187.86) 171.45,187.68 173.08,186.06 173.08,185.57 176.3,182.35 178.06,182.35 178.06,182.35 184.02,182.35 184.8,181.57 186.79,179.58 186.79,178.78 186.79,176.32 181.38,170.91 181.38,166.31 181.71,165.98 181.71,163.31 182.56,162.46 v2(182.91,162.46) 183.34,162.46 185.19,160.6 185.19,153.99 185.19,153.59 184.15,152.55 183.77,152.17 183.77,148.78 185.83,146.73 185.83,146.3 v3(185.82,146.3)
SSD_PEDET: length 229.8
  TOP w0.089: v3(156.76,132.27) 156.63,132.27 156.23,132.67 156.23,132.98 156.37,133.13 156.37,133.76 SB1.AM46
  TOP w0.102: R1705.1 161.42,144.37 161.22,144.17 161.22,141.55 158.98,139.31 158.98,138.07 157.48,136.58 156.38,136.58 155.77,135.96 155.77,134.98 155.98,134.77 155.98,134.15 SB1.AM46 ; v3(164.44,105.56) 168.85,105.56 C6215.1 169.6,106.26 171.5,108.16 173.6,118.54 174.07,120.04 174.22,120.68 175.17,123.73 175.25,123.99 175.73,125.32 176.05,126.19 176.48,127.36 178.12,132.07 178.32,132.62 178.66,133.61 v3(178.66,133.81) ; v3(150.52,94.68) 150.52,94.24 151.33,93.42 151.33,66.96 150.9,66.53 150.9,55.27 151.82,54.36 151.82,49.45 153.23,48.04 153.23,43 152.17,41.95 152.04,41.82 152.04,32.54 151.67,32.17 151.67,31.45 153.01,30.11 153.01,24.61 154.93,22.69 154.93,11.33 155.12,11.14 155.12,8.64 155.12,7.84 149.08,1.8 135.82,1.8 134.96,2.67 131.98,2.67 131.04,3.61 131.04,7.14 132.25,8.35 NGFF2.69
  BOTTOM w0.102: v3(156.76,132.27) 156.89,132.14 156.89,129.52 157.57,128.84 157.57,127.23 157.95,126.85 159.08,126.85 159.36,127.12 159.57,127.12 159.61,127.17 161.4,127.17 161.61,127.37 162.79,127.37 162.82,127.33 163.39,127.33 163.89,127.83 164.33,127.83 164.89,127.27 165.87,127.27 165.89,127.24 167.94,127.24 168.47,126.71 171.68,126.71 175.72,130.75 175.72,130.81 175.77,130.86 175.77,131.11 175.77,132.32 177.26,133.81 v3(178.66,133.81) ; v3(150.52,94.68) 150.68,94.84 v2(154.31,94.84) 154.71,94.44 159.54,94.44 163.14,98.05 163.14,103 164.26,104.12 164.29,104.2 164.29,105.41 v3(164.44,105.56)
SSD_PEWAKE_N: length 13.3
  TOP w0.102: R6202.1 R6203.1 134.18,5.4 v2(134.24,5.33) 134.27,5.37 134.27,11.92 136,13.65 NGFF2.54
SUS_ACK_EN_N: length 351.4
  TOP w0.102: v3(159.41,181) 157.12,181 156.54,180.42 119.17,180.42 117.16,181.03 117.06,181.05 116.42,181.05 v3(115.98,180.92) ; v3(163.42,155.37) 164.03,155.98 165.12,155.98 165.48,155.62 167.76,155.62 168.1,155.96 171.29,155.96 174.42,152.83 174.42,144.24 v3(174.45,144.22) ; v3(179.55,144.25) 179.55,134.89 175.54,123.89 175.46,123.64 174.52,120.6 174.18,119.15 173.79,117.44 173.79,100.18 172.9,99.29 172.9,95.91 173.02,95.78 173.02,76.75 173.69,76.09 173.69,59.02 173.25,58.58 173.25,47.53 169.08,43.35 169.08,43.08 168.78,42.78 v3(168.78,42.04) ; Q3801.1 78.22,260.65 77.89,260.32 R3809.2 77.89,260.21 78.38,259.71 78.38,256.62 74.64,253.85 73.1,252.3 71.5,250.7 70.94,249.46 70.94,233.12 v2(70.8,232.98) 69.62,231.8 69.62,227.8 69.55,227.72 68.17,226.35 66.43,226.35 63.84,223.76 63.84,217.22 64.49,216.57 64.49,214.77 65.71,213.55 65.71,207.21 66.32,206.6 v3(66.32,202.18) ; v3(165.57,36.73) 165.57,36.72 165.57,36.62 164.52,35.57 164.52,35.42 164.47,35.37 164.47,34.62 164.97,34.11 R2419.1 164.97,32.18 165.49,31.66 U2401.94
  BOTTOM w0.102: v3(115.98,180.92) 115.98,181.1 114.33,182.75 86.48,182.75 80.54,188.7 80.28,188.95 76.41,188.95 71.41,193.95 70.19,193.95 68.54,195.61 67.26,195.61 63.02,199.85 63.02,200.63 64.57,202.18 v3(66.32,202.18) ; v3(174.45,144.22) 179.53,144.22 v3(179.55,144.25) ; v3(163.42,155.37) 163.3,155.5 163.3,164.24 162.27,165.28 162.27,166.27 161.43,167.11 161.42,167.16 161.39,167.32 161.24,168.14 161.24,175.17 160.78,175.63 160.78,178.36 159.41,179.73 v3(159.41,181) ; v3(165.57,36.73) 165.57,36.95 166.75,38.13 166.75,38.35 168.78,40.39 v3(168.78,42.04)
SUS_PWR_ACK: length 249.5
  TOP w0.102: v3(174.8,134.59) 175.53,136.66 175.86,143.13 175.87,143.15 175.87,145.11 175.89,145.57 176.17,146.48 176.17,153.41 v3(174.25,156.87) ; v3(163.04,177.86) 166.35,177.86 167.87,176.34 167.87,174.78 v1(168.22,174.42) ; v3(161.52,181.25) 160.8,180.54 157.1,180.54 156.67,180.11 119.12,180.11 117.87,180.48 117.48,180.57 v3(116.81,180.57) ; 167.76,129.53 168.25,130.02 169.42,130.02 169.77,130.38 169.84,130.38 170.28,130.82 170.28,130.89 170.56,131.17 170.62,131.17 170.62,131.17 171.55,131.17 v3(171.7,131.32) ; 167.76,129.53 R2004.1 ; 167.76,129.53 167.31,129.97 166.6,129.97 166.58,129.96 166.41,129.96 166.17,129.72 165.91,129.72 165.43,129.24 165.43,129.07 164.56,128.2 162.74,128.2 162.36,128.58 SB1.BE35 ; v3(66.67,201.32) 66.27,201.73 66.13,201.73 65.86,201.99 65.86,206.58 65.41,207.04 65.41,213.42 64.19,214.64 64.19,216.45 63.54,217.1 63.54,223.89 66.3,226.65 68.04,226.65 68.72,227.33 69.24,227.85 69.24,228.59 69.06,228.77 v2(69.06,230.89) 69.06,231.72 70.03,232.69 70.03,233.88 70.64,234.49 70.64,249.53 71.24,250.88 72.97,252.6 72.97,252.6 73.79,253.42 73.79,253.42 74.44,254.08 74.8,254.44 R3807.2 C3806.1 R3812.2 77.89,259.33 R3809.1 76.71,260.52 R3810.1
  BOTTOM w0.102: v3(163.04,177.86) 162.24,180.15 v3(161.52,181.25) ; v3(116.81,180.57) 116.81,180.79 114.55,183.06 86.61,183.06 80.67,189 80.66,189 80.41,189.26 76.54,189.26 71.53,194.26 70.31,194.26 68.66,195.91 67.38,195.91 63.32,199.97 63.32,200.51 64.14,201.32 v3(66.67,201.32) ; v3(174.8,134.59) 172.54,132.33 172.54,132.16 v3(171.7,131.32) ; v3(174.25,156.87) 174.17,157.48 172.92,161.52 172.47,163.15 172.47,164.5 172.47,166.14 172.42,166.57 171.54,170.65 168.22,173.97 v1(168.22,174.42)
SUS_PWR_ACK_5V_DUAL: length 91.1
  TOP w0.102: R3818.1 v3(19.11,242.24) ; v3(67.89,237.06) 69.08,237.06 v2(69.22,237.2) 69.6,237.58 69.6,240.4 69.62,240.42 69.62,249.93 69.96,250.92 69.97,250.93 72.58,253.54 75.74,256.71 75.74,263.52 76.98,264.76 76.98,265.94 78.43,267.4 R3815.1 R3811.2 80.58,267.33 R3814.1
  BOTTOM w0.102: v3(67.89,237.06) 67.67,237.29 56.92,237.29 56.26,236.63 51.33,236.63 45.52,242.44 19.32,242.44 v3(19.11,242.24)
SUS_PWR_ACK_5V_DUAL_L: length 3.6
  TOP w0.102: Q3801.5 78.87,264.16 78.71,264.31 v2(78.71,264.92) 78.84,265.05 C3807.1 R3814.2
SUS_PWR_ACK_BJT: length 3.8
  TOP w0.102: R3817.1 79.02,258.65 79.21,258.84 R3813.2 79.21,259.91 v2(78.84,260.27) 78.87,260.3 Q3801.2
SUS_PWR_ACK_BJT_L: length 3.8
  TOP w0.102: Q3801.3 79.52,260.84 v2(80.11,260.25) 80.1,260.24 R3813.1 80.1,258.64 80.16,258.57 R3816.1
SUS_PWR_ACK_R: length 6.7
  TOP w0.102: R3810.2 76.71,262.51 76.5,262.71 v2(76.5,263.47) 76.87,263.47 77.56,262.79 78.12,262.79 78.22,262.89 Q3801.6 78.22,264.26 78.16,264.32 78.16,265.42 R3808.2
SUS_WARNB: length 154.9
  TOP w0.102: SB1.BC37 161.42,129.26 v1(161.42,128.19) ; R2004.2 166,129.51 165.63,129.15 165.63,128.98 165.23,128.58 v1(165.23,128.27) ; R2477.1 175.07,37.08 176.27,37.08 176.38,36.98 176.38,36.97 176.62,36.73 R2438.1 176.62,36.61 177.32,35.92 177.66,35.92 177.93,35.65 v3(177.93,30.23)
  BOTTOM w0.102: v1(161.42,128.19) 162.32,128.19 162.78,128.65 164.85,128.65 v1(165.23,128.27) 165.23,128.75 165.9,129.42 167.77,129.42 168.22,128.96 168.5,128.96 169.32,128.14 171.93,128.14 174.88,131.1 174.88,131.97 174.88,131.97 174.88,132.62 177.09,134.82 185.58,134.82 186.13,134.26 186.5,134.26 188.9,131.87 188.9,131.3 190.47,129.72 190.47,75.7 190.34,75.57 190.25,75.47 190.25,51.42 189.89,51.07 189.89,49.9 189.41,49.42 189.41,46.53 188.06,45.19 188.06,44.54 182.08,38.56 182.03,38.56 181.76,38.29 181.76,38.04 181.03,37.3 181.03,36.58 180.09,35.64 180.09,33.5 179.55,32.97 179.55,32.3 178.69,31.44 v2(178.69,30.99) v3(177.93,30.23)
SUS_WARNB_R: length 7.7
  TOP w0.102: U2401.68 175.89,31.18 176.53,31.82 v2(176.53,31.88) 176.21,32.19 176.04,32.19 175.18,33.05 175.18,35.06 C2412.1 R2438.2
SUSCLK: length 177
  TOP w0.102: R1822.1 68.96,211.16 68.96,210.72 68.97,210.71 68.97,210.53 68.99,210.52 68.99,210.07 R1818.1 68.99,210.05 68.99,209.6 69,209.59 69,208.1 69.62,207.48 69.62,198.96 70.84,197.74 v2(70.84,194.56) 70.64,194.36 70.64,192.02 71.12,191.54 80.35,191.54 80.5,191.69 80.51,191.69 114.53,191.69 118.17,192.05 140.52,192.05 v3(141.69,193.22) ; SB1.BE45 162.05,133.34 162.04,133.34 v1(162.02,133.34)
  BOTTOM w0.102: v3(141.69,193.22) 146.11,188.8 152.2,188.8 153.42,187.58 156.54,187.58 158.81,185.31 159.89,185.31 162.51,182.69 162.51,182.64 163.21,181.43 163.44,180.97 164.21,179.11 164.48,178.43 165.26,176 165.3,175.84 165.48,175.29 165.55,175.09 165.68,174.69 165.68,173.11 169.19,169.61 169.37,169.36 170.18,166 170.18,162.47 170.36,161.83 170.36,155.15 171.13,154.38 172.84,152.62 172.96,152.51 173.29,152.17 173.3,152.17 173.46,152 173.46,146.1 172.89,145.41 172.72,145.24 172.72,144.62 172.7,144.57 172.69,144.57 172.69,144.42 172.37,144.09 171.36,144.09 171.1,143.83 171.1,143.29 169.77,141.96 168.83,141.96 166.07,139.2 166.07,138.94 166.07,138.94 166.07,138.84 165.99,138.76 165.99,138.61 165.78,138.4 165.77,138.4 165.44,138.07 165.3,138.07 164.72,137.49 164.22,137.49 164.17,137.54 163.69,137.54 163.45,137.3 163.45,134.76 v1(162.02,133.34)
SUSCLK_SIO: length 333.1
  TOP w0.102: v3(160.43,192.13) 156.89,195.67 149.17,195.67 147.72,194.21 144.25,194.21 141.73,191.69 118.19,191.69 116.74,191.55 115.08,191.38 114.69,191.34 80.65,191.34 80.49,191.18 70.97,191.18 70.28,191.87 70.28,197.8 69.27,198.82 69.27,206.63 68.11,207.78 v2(68.11,208.94) R1818.2 ; v3(191.82,45.85) 194.23,45.85 195.28,46.89 195.28,132.64 194.58,133.33 194.58,138.6 v3(195.71,139.72) ; U2401.19 v3(171.89,20.95)
  BOTTOM w0.102: v3(195.71,139.72) 195.24,140.19 195.24,141.01 192.23,144.02 191.24,144.02 190.88,144.37 186.21,144.37 184.74,145.85 184.62,145.85 182.45,148.02 182.45,152.72 182.83,153.1 182.83,158.97 182.14,159.65 182.14,161.01 179.63,163.52 179.63,170.25 180.06,170.68 180.06,171.46 185.47,176.87 185.47,179.03 183.48,181.03 175.75,181.03 171.75,185.03 171.75,185.51 170.4,186.82 170.38,186.82 170.1,186.82 169.99,186.93 167.41,189.51 164.89,189.51 164.88,189.52 163.96,190.44 162.12,190.44 v3(160.43,192.13) ; v3(191.82,45.85) 191.45,45.85 190.17,44.56 190.17,43.84 184.12,37.78 184.12,37.48 181.56,34.92 181.56,32.89 181.03,32.36 181.03,31.69 180.44,31.11 180.44,30.64 178.71,28.91 178.71,27.12 174.92,23.32 174.44,23.32 172.08,20.95 v3(171.89,20.95)
SUSCLK_WIFI: length 36
  TOP w0.102: R1822.2 68.1,211.19 v3(68.1,214.6) ; NGFF1.50 43.33,221.92 43.48,221.77 v2(43.92,221.77) 44.85,222.7 44.86,222.85 44.86,223.14 45.55,223.84 v3(45.55,224.25)
  BOTTOM w0.102: v3(68.1,214.6) 67.21,215.49 66.4,215.49 66,215.89 63.96,215.89 63.87,215.8 61.44,215.8 58.62,218.61 58.62,218.81 53.51,223.93 53.06,223.93 51.92,225.07 48.86,225.07 48.03,224.23 45.57,224.23 v3(45.55,224.25)
SYS_FAN2_TACH_SIO: length 5.6
  TOP w0.102: R2462.1 183.13,16.33 182.85,16.61 v2(181.6,16.61) 181.42,16.61 179.46,18.58 U2401.39
SYS_FAN_CTRL_CONN: length 18.4
  TOP w0.102: D2602.A 104.08,259.46 103.57,258.95 103.57,258 103.95,257.62 R2614.2 106.86,257.6 106.86,257.16 106.87,257.15 106.87,257.01 106.88,257 106.88,256.55 R2616.2 105.7,255.37 98.06,255.37 FANS1.4
SYS_FAN_CTRL_SIO: length 419.8
  TOP w0.102: v3(180.05,22.35) 179.71,22.35 179.53,22.18 U2401.48 ; R2614.1 108.65,257.62 v3(108.71,257.68) ; v3(145.57,193.75) 144.29,193.75 141.88,191.34 118.52,191.34 115.31,191.02 114.99,190.98 80.79,190.98 80.64,190.83 70.82,190.83 69.93,191.72 69.93,197.65 68.78,198.8 68.78,205.92 66.73,207.98 66.73,215.13 65.2,216.65 65.2,216.87 64.55,217.52 64.55,221.72 v2(67.64,224.81) 70.65,227.82 v3(70.65,231.64) ; v3(194.56,186.34) 194.83,186.33 195.01,186.14 198.07,183.08 198.07,41.32 198.07,41.32 198.07,38.94 197.37,38.24 197.33,38.2 196.6,38.2 196.57,38.18 196.11,38.18 196.08,38.2 195.18,38.2 194.62,38.76 194.37,38.76 192.67,40.46 191.13,40.46 190.44,39.77 188.57,39.77 v3(188.21,40.13)
  BOTTOM w0.102: v3(108.71,257.68) 95.96,257.68 92.81,254.53 80.92,254.53 79.09,252.7 76.73,252.7 71.83,247.81 71.83,232.82 v3(70.65,231.64) ; v3(188.21,40.13) 187.47,40.13 184.83,37.49 184.83,37.19 182.27,34.63 182.27,32.59 181.74,32.05 181.74,31.4 181.15,30.81 181.15,30.34 180.54,29.73 180.54,28.6 180.57,28.57 180.57,25.13 180.39,24.95 180.39,24.58 180.49,24.47 180.49,22.79 v3(180.05,22.35) ; v3(145.57,193.75) 146.28,193.03 150.57,193.03 151.13,193.6 161.54,193.6 163.71,195.77 165.87,195.77 167.03,194.61 167.03,192.83 168.94,190.92 172.66,190.92 176.64,186.94 188,186.94 188.34,186.6 190.42,186.6 190.79,186.97 193.51,186.97 193.72,186.76 193.88,186.76 194.31,186.34 v3(194.56,186.34)
SYS_FAN_TACH_1: length 9.4
  TOP w0.102: FANS1.3 100.12,254.89 106.36,254.89 R2615.2 R2618.1
SYS_FAN_TACH_SIO: length 432.6
  TOP w0.102: v3(194.35,38.29) 194.79,37.85 195.94,37.85 195.96,37.82 196.72,37.82 196.75,37.85 197.19,37.85 197.48,37.85 197.69,38.06 197.74,38.11 198.43,38.79 198.43,41.47 198.42,41.47 198.42,183.25 194.83,186.85 194.61,186.85 194.61,186.85 194.3,186.85 v3(193.88,187.27) ; v3(146.66,193.49) 146.46,193.29 144.34,193.29 142.02,190.98 118.69,190.98 115.69,190.66 115.52,190.64 115.43,190.62 80.94,190.62 80.79,190.47 70.67,190.47 69.57,191.58 69.57,197.51 68.4,198.67 68.4,205.8 66.37,207.83 66.37,214.98 64.85,216.5 64.85,216.72 64.2,217.37 64.2,223.33 v2(65.96,225.09) 66.55,225.68 68,225.68 69.98,227.65 69.98,230.3 v3(70.15,230.48) ; v3(108.71,253.11) R2617.1 R2618.2 ; U2401.38 179.35,18.18 179.97,17.56 179.97,17.42 181.38,16 v3(182.41,16) 183.12,15.29 R2476.1
  BOTTOM w0.102: v3(70.15,230.48) 72.19,232.51 72.19,247.66 76.88,252.35 79.24,252.35 81.07,254.18 92.96,254.18 93.16,254.39 95.37,256.59 108.18,256.59 109.14,255.63 109.14,253.54 v3(108.71,253.11) ; v3(182.41,16) 182.54,16.13 182.91,16.13 184.32,17.55 184.32,20.3 183.2,21.42 183.2,23.23 183.26,23.29 183.26,23.38 184.02,24.14 184.02,25.86 184.02,25.86 184.02,28.68 185.12,29.77 185.12,33.28 189.99,38.15 194.21,38.15 v3(194.35,38.29) ; v3(146.66,193.49) 146.76,193.4 150.41,193.4 150.97,193.95 154.64,193.95 155.45,194.77 162.16,194.77 163.51,196.12 166.02,196.12 167.58,194.57 167.58,192.79 169.09,191.28 172.51,191.28 172.81,191.28 176.79,187.3 188.15,187.3 188.49,186.96 190.27,186.96 190.64,187.32 193.83,187.32 v3(193.88,187.27)
SYS_THERMDA+: length 250.6
  TOP w0.127: U2401.43 179.86,20.18 180.2,19.84 180.38,19.84 C2402.1 181.17,19.68 181.51,19.68 v3(181.86,19.33) ; v3(138.61,51.94) 139.2,51.35 139.2,46.85 133.03,40.68 C2427.1 133.19,39.08 Q2409.E ; v3(130.05,106.7) 130.05,106.98 130.19,107.13 130.37,107.13 132.79,104.71 132.79,101.68 134.52,99.95 134.52,95.54 133.82,94.85 133.82,87.92 142.11,79.63 142.11,55.9 143.31,54.7 143.31,53.4 v3(143,53.09) ; v3(145.84,173.07) 145.84,173.05 146.18,172.72 146.18,172.32 146.82,171.68 Q2403.C 148.74,171.68 Q2403.B 150.88,170.69 C2403.1 ; v3(137.48,132.33) 137.48,131.95 137.15,131.62 137.15,121.86 v3(137.16,121.84) ; v3(176.55,41.86) 176.55,41.64 176.87,41.31 177.27,41.31 177.5,41.08 178.77,41.08 180,39.84 185.96,39.84 187.4,38.41 v3(187.48,38.41)
  BOTTOM w0.127: v3(176.55,41.86) 176.07,41.86 175.9,42.04 175.9,42.62 174.37,44.15 163.4,44.15 161.34,46.2 160.84,46.2 159.84,47.2 158.84,47.2 158.41,47.63 158.41,48.77 158.14,49.05 157.77,49.41 157.77,50.3 156.05,52.02 144.25,52.02 143.61,52.66 143.43,52.66 v3(143,53.09) 142.57,52.65 142.27,52.65 141.45,53.47 139.64,53.47 139.15,52.99 139.15,51.83 139.03,51.7 138.85,51.7 v3(138.61,51.94) ; v3(187.48,38.41) 187.16,38.09 186.87,38.09 186.58,37.8 186.58,37.49 183.25,34.16 183.25,31.53 182.13,30.41 182.13,29.43 182.13,29.42 182.13,27.07 181.56,26.5 181.56,24.32 181.33,24.1 181.33,22.75 180.99,22.41 180.99,20.13 181.28,19.84 181.36,19.84 v3(181.86,19.33) ; 138,138.48 138,149.23 149.47,160.7 149.47,165.21 146.55,168.13 146.55,171.4 146.08,171.86 146.08,172.83 v3(145.84,173.07) ; 138,138.48 v2(137.62,138.48) ; 138,138.48 138,132.15 137.86,132.02 137.6,132.02 137.48,132.15 v3(137.48,132.33) ; v3(130.05,106.7) 130.05,106.7 130.05,106.76 129.85,106.96 129.17,106.96 127.91,108.22 127.91,111.91 137.41,121.41 137.41,121.59 v3(137.16,121.84)
SYS_THERMDA-: length 248.6
  TOP w0.127: v3(143.07,52.13) 143.5,52.57 143.5,53.19 143.59,53.28 143.59,54.82 142.39,56.02 142.39,79.74 134.1,88.03 134.1,94.73 134.8,95.43 134.8,100.07 133.07,101.8 133.07,104.83 130.49,107.4 130.03,107.4 v3(129.84,107.59) ; C2403.2 150.75,171.72 150.67,171.72 Q2403.E 149.39,172.33 147.14,172.33 146.94,172.13 146.76,172.13 146.46,172.43 146.46,172.65 146.65,172.85 v3(146.74,172.85) ; v3(138.71,51.03) 138.68,51.01 138.68,46.73 132.14,40.19 C2427.2 132.14,37.85 Q2409.C 132.21,36.86 Q2409.B ; U2401.44 179.85,20.58 180.31,20.12 180.71,20.12 C2402.2 181.14,19.96 181.6,19.96 v3(181.88,20.24) ; v3(137.67,131.44) 137.51,131.6 137.43,131.51 137.43,122.28 137.62,122.09 137.85,122.09 v3(138.08,121.86) ; v3(176.17,41.03) 177.15,41.03 177.39,40.8 178.65,40.8 179.89,39.57 185.85,39.57 186.94,38.47 186.94,37.72 v3(187.07,37.59)
  BOTTOM w0.127: v3(187.07,37.59) 183.53,34.05 183.53,31.41 182.41,30.29 182.41,29.31 182.41,26.95 181.84,26.38 181.84,24.21 181.61,23.98 181.61,22.64 181.27,22.29 181.27,20.24 181.39,20.12 181.75,20.12 v3(181.88,20.24) ; 138.28,133.32 138.28,149.11 149.75,160.58 149.75,165.33 146.82,168.25 146.82,171.51 146.36,171.98 146.36,172.72 146.49,172.85 v3(146.74,172.85) ; 138.28,133.32 v2(138.63,133.32) ; 138.28,133.32 138.28,132.04 137.98,131.74 137.97,131.74 v3(137.67,131.44) ; v3(138.71,51.03) 139.1,51.42 139.14,51.42 139.43,51.71 139.43,52.87 139.75,53.19 141.34,53.19 142.15,52.37 142.82,52.37 v3(143.07,52.13) 143.31,52.38 143.49,52.38 144.14,51.74 155.94,51.74 157.49,50.18 157.49,49.3 158.02,48.77 158.02,48.77 158.13,48.66 158.13,47.52 158.73,46.92 159.73,46.92 160.73,45.92 161.23,45.92 163.29,43.87 174.26,43.87 175.62,42.51 175.62,41.92 176.17,41.37 v3(176.17,41.03) ; v3(138.08,121.86) 137.88,121.86 137.69,121.67 137.69,121.3 128.19,111.8 128.19,108.33 129.29,107.24 129.71,107.24 129.84,107.37 v3(129.84,107.59)
TH_SET: length 8.1
  TOP w0.254: U2601.1 178.6,6.16 179.68,7.24 179.68,8.56 179.93,8.81 180.79,8.81 181.01,8.59 181.01,8.18 v2(182.11,7.08) 182.15,7.08 182.26,6.97 R2611.1
THERMTRIP#_CPU: length 130.5
  TOP w0.102: v3(120.29,63.35) 120.29,64.08 116.33,68.05 108.89,68.05 108.2,68.73 108.2,69.18 103.83,73.56 103.35,73.56 103.22,73.69 99.23,73.69 95.9,77.01 89.43,77.01 86.29,80.14 86.29,80.66 85.81,81.15 85.69,81.15 85.34,81.49 85.34,82.01 CPU1.D11 ; R1710.2 150.32,105.13 151.02,104.43 R1703.1 151.02,104.24 151.23,104.03 151.23,104.02 151.61,103.64 151.61,102.4 151.61,102 153.21,100.4 153.21,99.59 158.04,94.76 158.04,66.6 155.86,64.42 v3(155.86,63.32)
  BOTTOM w0.102: v3(155.86,63.32) 155.51,63.32 153.45,61.25 144.98,61.25 144.78,61.05 130.29,61.05 130.1,60.86 128.32,60.86 127.38,61.8 v2(123.8,61.8) 121.84,61.8 v3(120.29,63.35)
THERMTRIP#_PCH: length 5.6
  TOP w0.089: 152.44,112.57 152.52,112.48 152.52,111.33 152.33,111.14 152.33,111.06 152.09,110.81
  TOP w0.102: 152.09,110.81 151,109.73 v2(150.39,109.73) 150.32,109.65 R1710.1 ; SB1.AD3 152.44,112.57
TMIN_SHIFT: length 8.1
  TOP w0.102: R2306.2 R2431.1 182.63,11.75 182.63,12.76 R2446.2 182.61,13.34 v2(182.27,13.69) 182.24,13.72 181.53,13.72 180.06,15.19 179.15,15.19 178.64,15.7 U2401.33
TMIN_SHIFT_PCH: length 166.3
  TOP w0.102: v3(186.86,18.85) 186.9,18.85 187.54,19.49 187.54,23.4 188.18,24.04 188.18,24.41 188.14,24.45 185.83,26.76 185.83,35.66 182.6,38.89 181.85,38.89 181.8,38.94 181.79,38.94 v3(181.78,38.94) ; SB1.BD33 162.42,127.83 165.36,127.83 165.63,128.1 165.63,128.58 v1(166.04,128.98) ; v3(186.6,13.47) 186.6,12.72 186.72,12.61 186.72,11.39 185.87,10.54 185.28,10.54 185.28,10.54 185.23,10.54 R2307.1 184.29,9.6 R2309.1 R2306.1
  BOTTOM w0.102: v3(186.6,13.47) 186.86,13.73 v3(186.86,18.85) ; v3(181.78,38.94) 182.14,38.94 187.78,44.58 187.78,45.49 189.18,46.89 189.18,49.51 189.66,49.99 189.66,51.16 190.02,51.52 190.02,75.57 190.25,75.8 190.25,129.63 188.62,131.25 188.62,131.82 186.66,133.78 186.29,133.78 185.48,134.59 177.18,134.59 175.11,132.52 175.11,131.88 175.11,131 172.02,127.91 169.22,127.91 169.09,128.05 168.56,128.57 v2(167.08,128.57) 166.45,128.57 v1(166.04,128.98)
TP_CLKIN_XTAL: length 9.2
  TOP w0.102: v3(147.61,121.1) 147.6,121.09 147.6,120.91 147.57,120.88 147.57,116.68 147.34,116.45 147.34,116.06 148.08,115.32 SB1.R6
  BOTTOM w0.102: v2(148.41,120.47) v3(147.61,121.1) R1816.1
TP_CPU1_L8: length 1.6
  TOP w0.102: CPU1.L8 v1(88.1,88.4)
  BOTTOM w0.102: TP903.1 88.24,88.54 v1(88.1,88.4)
TP_DIMM1_PIN1: length 1.8
  TOP w0.102: DIMM1.1 12.89,155.61 R1102.1
TP_DIMM1_PIN145: length 5.9
  TOP w0.102: R1102.2 12,155.3 11.94,155.36 11.94,158.84 DIMM1.145
TP_DIMM2_PIN1: length 8.8
  TOP w0.102: DIMM2.1 12.7,166.27 11.79,167.18 11.79,169.27 12.47,169.95 12.47,170.84 12.93,171.3 R1202.1
TP_DIMM2_PIN145: length 3.3
  TOP w0.102: DIMM2.145 12.7,169.62 12.93,169.85 R1202.2
TP_SLP_LAN_N: length 5.3
  TOP w0.089: SB1.BF40 163.34,130.62 163.68,130.96 164.02,130.96 164.2,131.15
  TOP w0.102: 164.2,131.15 164.71,131.65 164.71,131.8 164.95,132.04 166.05,132.04 166.42,132.41 166.88,132.41 TP2001.1
TP_VCCPHY_SENSE: length 8.4
  TOP w0.102: SB1.K47 145.6,134.17 145.6,134.87 145.36,135.1 145.36,136.42 145.82,136.88 148.72,136.88 150.11,138.27 TP2101.1
TP_VSS_AL37: length 1.9
  TOP w0.102: v1(156.3,129.57) 155.89,129.16 SB1.AL37
  BOTTOM w0.102: v1(156.3,129.57) 156.3,129.29 TP1501.1
TP_VSSPHY_SENSE: length 10.3
  TOP w0.089: 145.37,134.81 145.4,134.78 145.4,134.43 145.32,134.35 145.32,133.91 SB1.K46
  TOP w0.102: 145.37,134.81 145.16,135.02 145.16,136.51 145.74,137.08 148.6,137.08 149.58,138.06 149.58,139.55 TP2102.1
TPEV_CFG_RCOMP: length 6
  TOP w0.305: R418.1 81.93,92.89 81.93,91.94 v3(82.81,91.06) 83.63,90.24 84.18,90.24 84.4,90.02 84.41,90.02 84.6,89.83 84.83,89.83 CPU1.M11
  BOTTOM w0.305: v2(82.04,91.95) 82.81,91.18 v3(82.81,91.06)
TPM_CS: length 3.1
  TOP w0.102: U9101.20 167.19,172.85 R9108.2
TPM_PIRQ: length 5.2
  TOP w0.102: R9112.1 165.2,169.14 165.32,169.25 165.32,169.27 166.1,170.06 v3(166.1,170.07) 166.16,170.13 166.17,170.13 166.36,170.31 166.36,171.35 165.85,171.85 U9101.18
  BOTTOM w0.102: v3(166.1,170.07) 166.1,169.13 v2(166.13,169.1)
TPM_PP: length 4.5
  TOP w0.102: U9101.4 159.69,173.35 159.69,173.35 159.68,173.35 v3(159.12,173.91)
  BOTTOM w0.102: v3(159.12,173.91) 159.12,174.51 157.61,176.02 TP9106.1
TPM_RST_R: length 12.9
  TOP w0.102: Q9101.S 164.97,165.26 164.97,164.87 165.65,164.2 R9111.2 165.66,164.67 165.43,164.9 165.43,165.34 R9110.2 164.67,166.1 164.67,167.27 164.74,167.35 164.74,167.83 164.67,167.91 164.67,169.31 164.92,169.56 v3(164.92,169.57) 164.98,169.62 164.98,169.62 166.13,170.77 166.13,171.25 166.03,171.35 U9101.17
  BOTTOM w0.102: v2(164.37,170.4) v3(164.92,169.57)
TPM_VDD_P8: length 17.9
  TOP w0.305: U9101.22 166.6,173.85 C9102.1
  TOP w0.508: v3(167.46,168.94) 168.61,170.08 169.26,170.08 169.82,170.64 169.82,172.26 168.3,173.78 167.58,173.78 C9102.1 ; v3(163.91,169.49) 163.69,169.71 160.49,169.71
  BOTTOM w0.508: v3(163.91,169.49) 164.94,168.46 v2(165.03,168.46) 165.15,168.34 166.47,168.34 167.06,168.94 v3(167.46,168.94)
TRST_N: length 3
  TOP w0.203: 161.8,17.78 U2401.124
  TOP w0.508: 161.8,17.78 161.8,17.78 R2450.2 v2(161.1,18.72)
TS_CRIT#: length 10.2
  TOP w0.102: U2602.2 176.1,7 176.07,6.97 176.07,5.11 176.23,4.95 176.23,4.48 R2613.2 176.21,4.29 176.23,4.28 176.23,3.84 176.56,3.51 v2(177.98,3.51) 180.16,3.51 180.5,3.85 U2601.3
U1.1: length 5
  TOP w0.254: v2(33.99,255.35) 33.92,255.41 R3302.1
  TOP w0.305: U3301.1 34.91,256.98 34.54,256.62 R3302.1
U1.6: length 4.1
  TOP w0.305: C3304.1 42.95,256.3 v2(42.33,256.92) 41.95,257.3 40.3,257.3 U3301.6
U1.15: length 4.5
  TOP w0.102: R3301.2 40.18,263.45 40.05,263.58 39.02,263.58 38.9,263.45 v2(38.9,262.75) 38.99,262.67 U3301.15
U1.24: length 3.1
  TOP w0.305: U3301.24 35.51,257.83 v2(35.2,258.14) 34.46,258.14 C3303.1
UART0_RX: length 1.9
  TOP w0.102: v1(162,122.4) 162.1,122.4 162.2,122.31 SB1.BE23
  BOTTOM w0.102: v1(162,122.4) 162.51,122.4 162.74,122.17 TP1505.1
UART0_TX: length 2.2
  TOP w0.102: v1(161.42,123.42) 161.42,123.4 161.17,123.15 SB1.BB24
  BOTTOM w0.102: v1(161.42,123.42) 161.75,123.09 162.56,123.09 TP1504.1
UART_BT_WAKE_N: length 219.9
  TOP w0.102: SB1.BE32 162.76,126.62 164.8,126.62 166.04,127.86 166.04,128.03 166.75,128.74 168.49,128.74 168.72,128.98 168.81,128.98 169.9,130.07 169.96,130.07 170.59,130.7 170.59,130.76 170.69,130.86 171.89,130.86 172.21,131.18 172.36,131.48 172.69,132.3 172.69,136.27 172.69,136.27 172.69,136.34 173.2,136.85 173.2,144.17 173.46,144.43 173.46,152.68 v3(173.28,152.86) ; v3(82.14,184.68) 82.16,184.68 82.16,184.67 82.88,184.39 117.56,184.39 120.54,183.72 153.12,183.72 155.71,186.31 v3(159.26,186.31) ; v3(56.62,202.59) 57.11,203.08 57.11,203.26 57.12,203.28 57.12,208.95 54.61,211.46 v3(54.61,212.48) 54.61,212.48 v2(54.61,215.77) 54.61,216.33 54.66,216.38 R2007.1 ; v3(41.71,216.08) 41.05,216.08 40.69,215.72 40.69,215.06 41.05,214.69 41.33,214.42 NGFF1.20
  BOTTOM w0.102: v3(82.14,184.68) 79.15,187.68 75.73,187.68 72.56,190.86 69.61,190.86 67.71,192.76 62.99,192.76 62.15,193.59 62.15,197.7 61.34,198.52 59.43,200.36 56.91,202.61 v3(56.62,202.59) ; v3(54.61,212.48) 42.78,216.08 v3(41.71,216.08) ; v3(173.28,152.86) 170.71,155.42 170.71,161.88 170.54,162.52 170.54,166.03 170.53,166.05 170.52,166.21 170.44,166.55 169.89,168.86 169.89,168.89 169.73,169.56 169.5,169.79 166.04,173.26 166.04,174.76 165.92,175.12 165.82,175.4 165.64,175.94 165.59,176.17 164.83,178.5 163.76,181.27 163.02,182.64 162.87,182.84 160.46,185.25 160.04,185.67 159.9,185.67 v3(159.26,186.31)
USB2_COMP: length 6
  TOP w0.127: SB1.F4 143.28,112.57 143.28,111.95 143.34,111.89 143.34,111.48 142.76,110.9 142.57,110.9 141.11,109.43 v2(140.88,109.43) 140.34,108.89 140.34,108.83 140.26,108.75 R1609.1
USB2_ID: length 5.5
  TOP w0.102: R1611.1 141.27,108.79 v2(142.14,109.65) 143.55,111.07 143.55,112.01 143.49,112.07 143.49,112.48 SB1.G3
USB2_VBUSSENSE: length 6.3
  TOP w0.089: 142.57,111.12 142.68,111.12 143.13,111.57 143.13,111.8 142.99,111.95 SB1.F3
  TOP w0.102: R1610.1 139.24,108.32 139.6,108.67 139.6,109.24 v2(139.62,109.27) 140.52,110.17 141.53,110.17 142.49,111.12 142.57,111.12
USB30_RX_CON_N1: length 10.1
  TOP w0.102: R3804.4 81.33,262.76 81.55,262.98 81.55,263.34 82.05,263.84 82.05,264.14 81.93,264.26 EU3801.1 EU3801.10 81.93,266.08 82.09,266.24 82.09,271.14 81.97,271.25 USB3F1.5
USB30_RX_CON_N2: length 10.4
  TOP w0.102: R3806.4 101.43,263.63 101.75,263.63 102.01,263.88 102.11,263.88 102.49,264.26 102.49,264.63 EU3802.1 EU3802.10 103.77,265.91 104.01,265.91 104.11,266.01 104.11,271.15 104.01,271.25 USB3F2.5
USB30_RX_CON_P1: length 10.1
  TOP w0.102: R3804.3 81.99,262.79 81.76,263.02 81.76,263.25 82.27,263.75 82.27,264.16 82.41,264.3 EU3801.2 EU3801.9 82.41,266.06 82.3,266.16 82.3,271.12 82.43,271.25 USB3F1.6
USB30_RX_CON_P2: length 10.4
  TOP w0.102: R3806.3 101.9,263.17 101.9,263.47 102.1,263.66 102.2,263.66 EU3802.2 EU3802.9 104.14,265.6 104.14,265.74 104.33,265.92 104.33,271.15 104.43,271.25 USB3F2.6
USB30_RX_PCH_N1: length 222.4
  TOP w0.102: v3(70.63,198.64) 71.11,199.13 71.22,199.24 71.22,199.5 71.37,204.71 71.42,206.45 71.42,227.04 71.42,248.77 71.5,249.25 71.8,250.05 72.37,250.89 72.69,251.2 72.7,251.22 73.3,251.82 74.49,253.01 74.5,253.01 74.62,253.14 74.64,253.15 75.05,253.47 80.68,256.42 81.29,257.03 81.53,257.45 81.56,257.56 81.56,260.53 81.33,260.76 R3804.1 ; SB1.D11 142.33,116.51 141.94,116.51 141.84,116.61 137.57,116.61 136.31,117.87 136.31,137.4 146.7,147.79 146.7,148.92 150.96,153.19 150.96,161.99 149.4,163.55 149,163.55 v3(148.79,163.35)
  BOTTOM w0.102: 75.54,196.72 78.46,196.72 79.73,195.46 81.79,194.91 81.9,194.87 81.91,194.87 82.38,194.65 82.68,194.48 82.98,194.31 83.35,194.01 83.44,193.92 83.52,193.81 84.39,192.43 84.46,192.3 84.5,192.23 84.65,192 84.66,192 85.01,191.44 88.7,187.76 89.56,187.76 89.56,187.76 122.2,187.76 123.59,186.85 127.06,184.55 131.93,181.35 134.8,179.55 136,178.42 136.58,177.63 136.59,177.62 137.62,176.22 137.88,175.96 141.37,174.17 142.26,173.28 144.76,168.95 145.88,167.58 147.25,166.21 148.08,163.91 148.09,163.88 148.12,163.78 148.35,163.61 148.53,163.61 v3(148.79,163.35) ; 75.54,196.72 71.45,196.72 70.51,197.67 70.51,197.96 70.63,198.08 v3(70.63,198.64) ; 75.54,196.72 v2(75.54,196.35)
USB30_RX_PCH_N2: length 228.7
  TOP w0.102: v3(139.42,176.87) 139.42,176.43 139.47,176.38 141.72,176.38 145.03,173.07 145.03,170.16 145.81,169.38 146.34,169.38 148.34,167.39 148.34,164.66 148.34,164.55 147.72,163.93 147.72,161.3 148.9,160.13 148.9,157.38 148.14,155.89 147.95,155.51 146.22,152.1 146.22,147.99 135.83,137.6 135.83,117.64 137.76,115.7 141.6,115.7 SB1.B9 ; v3(80.09,196.95) 80.09,196.75 80.19,196.65 80.42,196.65 80.6,196.83 80.6,196.98 80.49,197.36 77.4,202.45 77.39,202.45 76.78,203.51 76.66,203.73 75.28,206.26 75.26,206.3 74.62,208.58 74.6,208.69 74.6,208.69 74.45,209.51 74.42,209.69 74.42,209.81 74.41,209.85 74.38,210.04 74.3,210.69 74.23,211.54 74.23,248.09 74.24,248.19 74.3,248.5 74.38,248.74 74.66,249.21 76.03,250.58 76.27,250.77 76.94,251.16 77.21,251.26 77.44,251.35 78.88,251.82 79.24,251.93 84.76,253.57 86.77,254.19 91,255.61 92.32,256.1 94.19,256.79 95.12,257.23 96.75,258.32 100.07,261.64 100.07,261.78 99.9,261.95 99.9,262.09 R3806.1
  BOTTOM w0.102: v3(80.09,196.95) 80.39,196.65 81.52,196.65 83.98,194.69 83.99,194.67 84.13,194.51 84.15,194.5 84.4,194.17 84.41,194.15 84.62,193.81 85.69,192.49 86.76,191.18 89.27,188.67 122.56,188.67 134.18,181.02 134.22,180.99 136.13,179.79 136.59,179.34 ; 136.59,179.34 139.05,176.87 v3(139.42,176.87) ; 136.59,179.34 v2(136.86,179.6)
USB30_RX_PCH_P1: length 222.5
  TOP w0.102: v3(148.76,164.18) 149.13,164.18 149.2,164.11 149.2,163.86 149.29,163.77 149.49,163.77 151.18,162.08 151.18,153.1 146.91,148.83 146.91,147.7 136.53,137.31 136.53,117.96 137.66,116.82 141.93,116.82 142.01,116.74 SB1.C11 ; R3804.2 81.99,260.73 81.78,260.52 81.78,257.53 81.74,257.37 81.46,256.9 80.81,256.24 75.16,253.29 74.77,252.99 74.66,252.87 74.59,252.8 74.58,252.8 73.39,251.6 72.86,251.08 72.86,251.07 72.54,250.75 71.99,249.95 71.71,249.19 71.64,248.76 71.64,226.95 71.64,206.45 71.44,199.49 71.44,199.15 71.33,199.04 71.11,198.82 71.11,198.36 v3(71.45,198.02)
  BOTTOM w0.102: 145.38,168.54 145.15,168.8 144.93,169.07 142.43,173.42 141.5,174.34 138.01,176.14 137.79,176.36 136.76,177.75 136.75,177.76 136.17,178.55 136.15,178.58 134.95,179.7 134.9,179.74 132.04,181.53 127.18,184.74 123.7,187.03 122.27,187.97 89.47,187.97 88.79,187.97 85.18,191.58 84.83,192.13 84.83,192.14 84.68,192.35 84.64,192.4 84.58,192.53 83.7,193.94 83.6,194.06 83.5,194.17 83.1,194.49 82.78,194.67 82.48,194.84 81.99,195.07 81.98,195.07 81.85,195.12 79.84,195.65 78.55,196.94 71.54,196.94 70.72,197.76 70.72,197.87 70.87,198.02 v3(71.45,198.02) ; 145.38,168.54 146.04,167.73 147.44,166.33 148.13,164.39 148.28,163.98 148.29,163.97 148.31,163.91 148.42,163.83 148.66,163.83 148.76,163.93 v3(148.76,164.18) ; 145.38,168.54 v2(145.67,168.78)
USB30_RX_PCH_P2: length 229.3
  TOP w0.102: v3(80.22,196.15) 80.81,196.74 80.81,197.02 80.69,197.45 77.58,202.56 76.85,203.83 75.47,206.36 74.83,208.63 74.81,208.73 74.66,209.54 74.64,209.71 74.64,209.83 74.63,209.89 74.59,210.07 74.52,210.67 74.51,210.71 74.45,211.55 74.45,248.08 74.46,248.16 74.51,248.45 74.57,248.65 74.84,249.08 76.18,250.42 76.39,250.59 77.03,250.96 77.28,251.06 77.28,251.06 77.51,251.15 78.94,251.61 79.31,251.72 84.82,253.36 86.84,253.99 86.84,253.99 91.06,255.41 91.63,255.61 94.28,256.59 95.22,257.04 96.89,258.15 R3806.2 ; SB1.C9 142.01,115.72 141.78,115.49 137.67,115.49 135.61,117.55 135.61,137.69 146,148.08 146,152.15 147.76,155.61 147.95,155.99 148.68,157.43 148.68,160.04 147.51,161.21 147.51,164.02 148.12,164.64 148.12,164.75 148.12,167.3 146.25,169.16 145.72,169.16 144.82,170.07 144.82,172.98 141.63,176.16 139.38,176.16 139.26,176.28 v3(138.87,176.28)
  BOTTOM w0.102: v3(80.22,196.15) 80.5,196.43 81.45,196.43 83.83,194.53 83.97,194.37 84.22,194.04 84.44,193.69 86.6,191.03 89.18,188.46 122.49,188.46 128.27,184.65 128.27,184.65 134.06,180.84 134.1,180.81 136,179.62 138.87,176.75 v3(138.87,176.28) v2(139.75,175.93)
USB30_TX_CMC_N1: length 4.5
  TOP w0.102: 83.73,259.71 83.73,260.54 83.48,260.79 R3801.1 ; 83.73,259.71 v2(83.36,259.71) ; 83.73,259.71 83.73,257.9 83.52,257.69 C3802.2
USB30_TX_CMC_N2: length 1.9
  TOP w0.102: R3802.1 101.47,260.62 101.47,260.27 101.01,259.82 C3804.2
USB30_TX_CMC_P1: length 4.6
  TOP w0.102: 83.64,257.06 83.65,257.07 83.65,257.51 83.95,257.81 83.95,258.37 ; R3801.2 84.14,260.72 83.95,260.53 83.95,258.37 ; v2(84.33,258.37) 83.95,258.37
USB30_TX_CMC_P2: length 1.9
  TOP w0.102: R3802.2 101.94,260.15 101.65,260.15 101.17,259.66 C3803.2
USB30_TX_CON_N1: length 11.9
  TOP w0.102: R3801.4 83.48,262.83 83.62,262.97 83.62,264.11 83.45,264.27 EU3801.4 EU3801.7 83.45,266.08 83.58,266.2 83.58,266.59 84.04,267.04 87.67,270.14 88.11,270.59 88.11,271.15 88.01,271.25 USB3F1.8
USB30_TX_CON_N2: length 13.6
  TOP w0.102: USB3F2.8 109.99,271.25 110.12,271.12 110.12,269.94 105.1,264.92 104.93,264.92 EU3802.7 EU3802.4 103.58,263.57 103.58,263.2 103.43,263.05 103.43,262.26 103.25,262.08 102.93,262.08 R3802.4
USB30_TX_CON_P1: length 12
  TOP w0.102: USB3F1.9 88.43,271.25 88.33,271.15 88.33,270.5 87.81,269.98 84.18,266.88 83.79,266.5 83.79,266.27 83.93,266.13 EU3801.6 EU3801.5 83.93,264.27 83.83,264.17 83.83,263.13 84.14,262.82 R3801.3
USB30_TX_CON_P2: length 13.7
  TOP w0.102: USB3F2.9 110.45,271.25 110.34,271.14 110.34,269.85 105.28,264.8 105.28,264.59 EU3802.6 103.64,262.96 103.64,262.17 103.38,261.9 103.38,261.59 R3802.3
USB30_TX_PCH_N1: length 224.6
  TOP w0.102: v1(144.1,115.6) SB1.F9 ; v3(131.63,177.12) 131.97,176.78 131.97,176.68 132.2,176.45 137.01,176.45 138.01,175.45 141.35,175.45 144.12,172.69 144.12,169.78 145.43,168.47 145.94,168.47 147.42,166.98 147.42,165.05 147.42,164.92 146.81,164.31 146.81,160.92 147.98,159.75 147.98,157.6 147.33,156.3 147.24,156.13 147.14,155.93 145.33,152.37 145.3,152.32 145.3,148.37 134.91,137.98 134.91,117.23 137.68,114.47 138.21,114.47 v1(138.53,114.14) ; C3802.1 82.38,256.58 81.49,255.69 79.21,254.61 77.21,253.67 76.65,253.43 75.81,253.07 75.08,252.61 72.91,250.44 72.42,249.72 72.21,249.17 72.14,248.66 72.14,208.81 72.14,205.19 72.7,196.82 v3(72.7,196.15)
  BOTTOM w0.102: 130.97,178.65 131.63,178.09 v3(131.63,177.12) ; 130.97,178.65 122.74,185.55 121.68,186.33 87.97,186.33 82.02,192.28 80.66,193.56 79.97,194.25 79.86,194.36 79.57,194.63 78.73,195.47 73.39,195.47 73.09,195.77 73.08,195.77 v3(72.7,196.15) ; 130.97,178.65 v2(130.71,178.35) ; v1(138.53,114.14) 138.21,114.47 137.96,114.47 137.71,114.72 137.71,115.13 138.37,115.79 139.55,115.79 139.74,115.6 v1(144.1,115.6)
USB30_TX_PCH_N2: length 228.9
  TOP w0.102: v1(136.27,112.3) 135.94,112.62 135.74,112.62 133.52,114.85 133.52,138.56 143.9,148.95 143.9,152.65 144.02,152.88 144.02,152.89 144.08,153.01 144.98,154.78 146.07,156.92 146.17,157.11 146.59,157.93 146.59,159.17 145.47,160.28 145.47,160.29 145.34,160.42 145.34,160.6 145.34,163.49 145.24,163.59 144.95,163.59 144.85,163.49 v3(144.85,163.23) ; v3(81.46,194.09) 81.7,194.33 81.7,196.05 81.7,196.07 81.62,196.51 81.49,197 81.36,197.38 81.18,197.72 80.65,198.65 76.02,206.42 75.86,206.77 75.17,209.58 75.17,209.6 75.11,209.94 75.07,210.15 74.99,210.73 74.99,210.76 74.93,211.57 74.93,248.06 74.93,248.1 74.98,248.33 75.01,248.44 75.22,248.78 76.5,250.06 76.67,250.19 77.24,250.53 84.97,252.87 89.91,254.46 96.51,256.89 97.27,257.22 99.13,258.08 99.82,258.71 99.82,258.71 99.91,258.8 C3804.1 ; v1(142.48,112.52) SB1.C3
  BOTTOM w0.102: v1(142.48,112.52) 142.16,112.85 141.12,112.85 140.67,113.3 140.33,113.3 139.32,112.29 137.31,112.29 137.12,112.48 136.46,112.48 v1(136.27,112.3) ; 135.8,175.96 136.19,175.56 137.85,174.36 137.9,174.33 138.9,173.83 140.22,173.34 140.65,173.11 140.69,173.08 141.15,172.61 143.19,169.17 143.2,169.16 143.2,165.55 143.96,163.81 144.12,163.65 144.43,163.65 v3(144.85,163.23) ; 135.8,175.96 135.55,176.21 135.25,176.51 133.9,177.64 133.18,178.24 122.01,187.03 88.26,187.03 81.78,193.52 81.78,193.78 v3(81.46,194.09) ; 135.8,175.96 v2(135.53,175.69)
USB30_TX_PCH_P1: length 224.6
  TOP w0.102: SB1.F7 143.3,115.04 143.42,115.16 143.66,115.16 v1(143.86,114.97) ; v3(73.51,196.18) 73.51,196.47 73.41,196.57 73.01,196.57 72.91,196.67 72.91,196.82 72.35,205.2 72.35,208.9 72.35,248.65 72.42,249.11 72.62,249.62 73.08,250.3 75.21,252.44 75.91,252.87 76.73,253.23 77.29,253.47 79.74,254.62 81.61,255.51 82.54,256.43 C3801.1 ; v1(138.53,115) 138.21,114.68 137.77,114.68 135.13,117.32 135.13,137.89 145.52,148.28 145.52,152.27 145.52,152.27 147.33,155.83 147.43,156.03 147.52,156.21 148.2,157.55 148.2,159.84 147.02,161.01 147.02,164.22 147.64,164.84 147.64,164.96 147.64,164.96 147.64,167.07 146.03,168.68 145.52,168.68 144.34,169.87 144.34,172.78 141.44,175.67 138.1,175.67 137.1,176.66 132.29,176.66 132.19,176.77 132.19,176.91 v3(132.45,177.17)
  BOTTOM w0.102: 77.39,195.68 73.48,195.68 73.3,195.86 73.3,195.98 v3(73.51,196.18) ; 77.39,195.68 78.82,195.68 79.72,194.78 80.01,194.51 80.12,194.41 80.81,193.71 82.18,192.43 88.06,186.55 121.75,186.55 122.87,185.72 131.77,178.26 131.79,178.24 131.85,178.18 131.85,177.65 131.95,177.55 132.34,177.55 132.45,177.45 v3(132.45,177.17) ; 77.39,195.68 v2(77.39,196.06) ; v1(138.53,115) 138.21,114.68 138.05,114.68 137.92,114.81 137.92,115.04 138.46,115.57 139.46,115.57 139.65,115.38 143.74,115.38 143.86,115.26 v1(143.86,114.97)
USB30_TX_PCH_P2: length 228.9
  TOP w0.102: v3(82.27,194.07) 81.91,194.42 81.91,196.06 81.91,196.1 81.84,196.54 81.83,196.57 81.7,197.05 81.61,197.31 81.56,197.44 81.56,197.45 81.55,197.47 81.38,197.82 81.27,198 80.83,198.76 76.21,206.54 76.15,206.66 76.06,206.84 75.38,209.63 75.31,210.01 75.28,210.18 75.21,210.78 75.17,211.31 75.15,211.58 75.15,248.06 75.19,248.29 75.21,248.35 75.39,248.64 76.64,249.9 76.79,250.02 77.33,250.33 85.03,252.66 89.98,254.26 96.59,256.69 97.36,257.02 99.25,257.9 99.97,258.55 99.97,258.56 C3803.1 ; v3(144.82,164.15) 144.82,163.91 144.92,163.81 145.33,163.81 145.56,163.58 145.56,160.51 145.69,160.38 145.69,160.37 146.8,159.26 146.8,157.88 146.36,157.02 146.27,156.83 145.18,154.68 144.28,152.91 144.23,152.81 144.22,152.81 144.12,152.6 144.12,148.86 133.73,138.47 133.73,114.93 135.83,112.84 135.98,112.84 v1(136.3,113.16) ; v1(142.82,113.06) 142.82,113.06 SB1.D4
  BOTTOM w0.102: 133.86,177.95 v2(134.11,178.26) ; 133.86,177.95 135.39,176.67 135.64,176.43 136.34,175.73 137.96,174.54 137.99,174.53 138,174.52 138.98,174.03 140.31,173.54 140.78,173.28 141.19,172.88 141.32,172.75 143.37,169.29 143.38,169.28 143.41,169.22 143.41,165.59 144.14,163.93 144.21,163.87 144.53,163.87 v3(144.82,164.15) ; 133.86,177.95 133.32,178.4 133.31,178.41 122.08,187.25 88.35,187.25 81.99,193.61 81.99,193.79 v3(82.27,194.07) ; v1(136.3,113.16) 136.3,112.89 136.49,112.7 137.21,112.7 137.4,112.5 139.23,112.5 140.24,113.51 140.76,113.51 141.21,113.06 v1(142.82,113.06)
USB_CON_PN1: length 25.8
  TOP w0.102: USB3F1.2 85.43,272.75 85.33,272.85 85.33,273.98 85.43,274.08 88.89,274.08 92.45,270.51 95.81,270.51 98.87,267.45 98.87,267.02 97.57,265.72 97.57,264.69 97.28,264.4 EU3803.1 96.92,264.04 95.96,263.08 95.96,262.48 95.79,262.31 95.46,262.31 TR3801.4
USB_CON_PN2: length 23.8
  TOP w0.102: USB3F2.2 107.43,272.75 107.33,272.85 107.33,273.67 106.55,274.45 103.68,274.45 101.73,272.49 101.73,265.99 100.69,264.95 100.16,264.95 EU3803.4 99.77,264.56 99.77,264.03 99.67,263.93 98.47,263.93 97.45,262.9 97.45,262.86 97.45,262.85 97.45,260.81 97.35,260.71 97.09,260.71 TR3802.4
USB_CON_PN5: length 34.5
  TOP w0.102: TR3202.4 126.14,28.74 126.05,28.83 124.83,28.83 EU3204.4 124.3,28.83 123.8,28.83 123.06,28.09 121.31,28.09 120.02,26.8 119.3,26.8 118.72,27.38 117.81,27.38 117.68,27.25 117.68,27.1 v3(117.98,26.8)
  BOTTOM w0.102: RJ45R1.2 108.89,13.17 108.89,13.59 109.23,13.93 110.4,13.93 111.04,14.57 111.04,20.87 111.93,21.76 111.93,26.63 112.85,27.56 117.41,27.56 117.68,27.29 117.68,27.1 v3(117.98,26.8)
USB_CON_PN6: length 35.2
  TOP w0.102: v3(118.03,28.09) 117.81,28.31 117.81,28.51 117.92,28.61 119.39,28.61 121.51,30.73 121.9,30.73 EU3204.1 122.44,30.73 122.81,30.73 123.56,29.98 125.28,29.98 125.72,30.42 125.72,31.92 125.82,32.02 126.12,32.02 126.32,31.82 TR3201.4
  BOTTOM w0.102: v3(118.03,28.09) 117.66,28.46 117.66,28.61 117.44,28.84 112.61,28.84 112.09,28.32 ; 112.09,28.32 109.51,25.74 109.51,21.81 108.33,20.63 108.33,19.05 108.89,18.49 108.89,15.79 RJ45R1.6 ; 112.09,28.32 v2(111.83,28.58)
USB_CON_PN7: length 14
  TOP w0.102: TR3902.3 92.53,22.87 92.71,22.68 92.71,22.17 92.33,21.79 92.33,20.17 93.07,19.43 93.07,18.93 EU3901.4 93.07,18.4 93.07,17.58 92.12,16.64 88.59,16.64 87.89,15.93 87.89,15.41 USB2R1.6
USB_CON_PN8: length 5.9
  TOP w0.102: 35.92,255.18 36.73,255.98 36.98,255.98 36.98,255.98 37.16,255.98 37.87,255.98 38.1,256.21 38.1,256.49 37.98,256.6 U3301.2 ; 35.92,255.18 v2(35.66,255.44) ; 35.92,255.18 35.33,254.58 35.33,254.1 35.1,253.87 R3303.2
USB_CON_PN9: length 16.7
  TOP w0.102: USB2R1.2 87.89,12.79 87.89,13.14 88.23,13.47 89.47,13.47 90.13,14.13 90.13,15.11 90.88,15.87 92.69,15.87 94.22,17.4 94.22,19.39 94.96,20.13 94.96,20.8 EU3901.1 94.96,21.31 94.96,22.44 94.69,22.71 TR3901.3
USB_CON_PP1: length 26.7
  TOP w0.102: USB3F1.3 85.01,272.75 85.11,272.85 85.11,274.07 85.34,274.29 88.98,274.29 92.54,270.73 95.9,270.73 99.09,267.54 99.09,266.93 98.61,266.45 EU3803.6 98.25,266.09 97.79,265.63 97.79,264.6 96.18,262.99 96.18,262.39 95.91,262.12 95.91,261.83 TR3801.3
USB_CON_PP2: length 23.2
  TOP w0.102: USB3F2.3 107.01,272.75 107.11,272.85 107.11,273.58 106.46,274.23 103.77,274.23 101.94,272.4 101.94,265.9 100.57,264.53 100.17,264.13 99.76,263.71 98.56,263.71 98.27,263.42 EU3803.3 97.91,263.06 97.67,262.82 97.67,262.77 97.66,262.76 97.66,260.68 97.54,260.55 97.54,260.23 TR3802.3
USB_CON_PP5: length 34.3
  TOP w0.102: TR3202.3 126.29,29.39 125.95,29.04 123.71,29.04 122.97,28.31 122.43,28.31 EU3204.3 121.92,28.31 121.22,28.31 119.93,27.01 119.39,27.01 118.81,27.6 117.72,27.6 117.46,27.34 117.46,27.1 v3(117.16,26.8)
  BOTTOM w0.102: v3(117.16,26.8) 117.46,27.1 117.46,27.2 117.32,27.34 112.94,27.34 112.14,26.54 112.14,21.67 111.25,20.78 111.25,14.48 110.49,13.72 109.32,13.72 109.11,13.5 109.11,13.17 RJ45R1.3
USB_CON_PP6: length 34.8
  TOP w0.102: TR3201.3 126.33,32.47 126.09,32.23 125.73,32.23 125.5,32 125.5,30.51 125.19,30.2 124.83,30.2 EU3204.6 124.3,30.2 123.65,30.2 122.9,30.95 121.42,30.95 119.3,28.83 117.83,28.83 117.6,28.6 117.6,28.47 v3(117.22,28.09)
  BOTTOM w0.102: 110.25,26.17 v2(110.51,25.91) ; 110.25,26.17 112.7,28.63 117.35,28.63 117.45,28.52 117.45,28.32 v3(117.22,28.09) ; 110.25,26.17 109.73,25.65 109.73,21.72 108.55,20.54 108.55,19.14 109.11,18.58 109.11,15.79 RJ45R1.7
USB_CON_PP7: length 14
  TOP w0.102: USB2R1.7 88.11,15.41 88.11,15.85 88.68,16.42 92.21,16.42 93.28,17.49 93.28,19.52 92.54,20.26 92.54,20.8 EU3901.3 92.54,21.31 92.54,21.7 92.93,22.08 92.93,22.67 93.18,22.92 TR3902.4
USB_CON_PP8: length 5.9
  TOP w0.102: R3303.1 35.76,253.87 35.55,254.09 35.55,254.5 36.82,255.77 37.36,255.77 ; U3301.3 38.48,256.59 38.32,256.43 38.32,256.12 37.96,255.77 37.36,255.77 ; 37.36,255.77 v2(37.36,255.37)
USB_CON_PP9: length 16.7
  TOP w0.102: TR3901.4 95.34,22.59 95.17,22.43 95.17,20.04 94.44,19.3 94.44,18.93 EU3901.6 94.44,18.4 94.44,17.31 92.77,15.65 90.97,15.65 90.34,15.02 90.34,14.04 89.56,13.26 88.32,13.26 88.11,13.05 88.11,12.79 USB2R1.3
USB_OC0_R_N: length 229.7
  TOP w0.102: v3(143.69,194.77) 143.69,194.31 v3(141.73,192.35) ; U3801.3 85.92,260.62 85.27,259.97 85.27,256.46 v3(84.84,256.03) ; SB1.AH36 154.52,129.27 154.77,129.27 154.77,129.27 v1(154.86,129.27) ; v3(159.26,151.84) 159.44,151.84 159.93,151.34 RN1901.4
  BOTTOM w0.102: v3(141.73,192.35) 141.73,191.61 145.99,187.35 148.26,187.35 149.58,186.03 150.26,185.64 150.71,185.39 153.92,185.39 158.37,180.94 158.37,180.75 158.37,180.75 158.37,179.84 158.37,179.65 159.18,178.84 159.18,176.15 159.32,176.02 160.41,174.92 160.41,168.42 160.44,168.28 160.45,168.19 160.47,168.1 160.75,166.59 161.5,165.84 161.5,162.92 161.21,162.64 161.21,157.08 158.95,154.82 158.95,152.15 v3(159.26,151.84) 160.1,151 160.1,143.77 158.28,141.96 158.28,140.76 156.24,138.72 156.24,136.81 155.57,136.14 155.57,133.94 155.84,133.66 155.84,132.94 155.6,132.7 155.55,132.7 154.99,132.15 154.99,129.4 v1(154.86,129.27) ; v3(143.69,194.77) 143.69,201.09 140.03,204.75 139.5,205.28 77.21,205.28 71.99,210.5 71.99,210.76 71.99,210.76 71.99,220.46 67.16,225.3 67.16,235.51 71.17,239.52 71.17,248.08 76.53,253.44 78.89,253.44 80.64,255.19 83.62,255.19 v2(83.95,255.52) 84.45,256.03 v3(84.84,256.03)
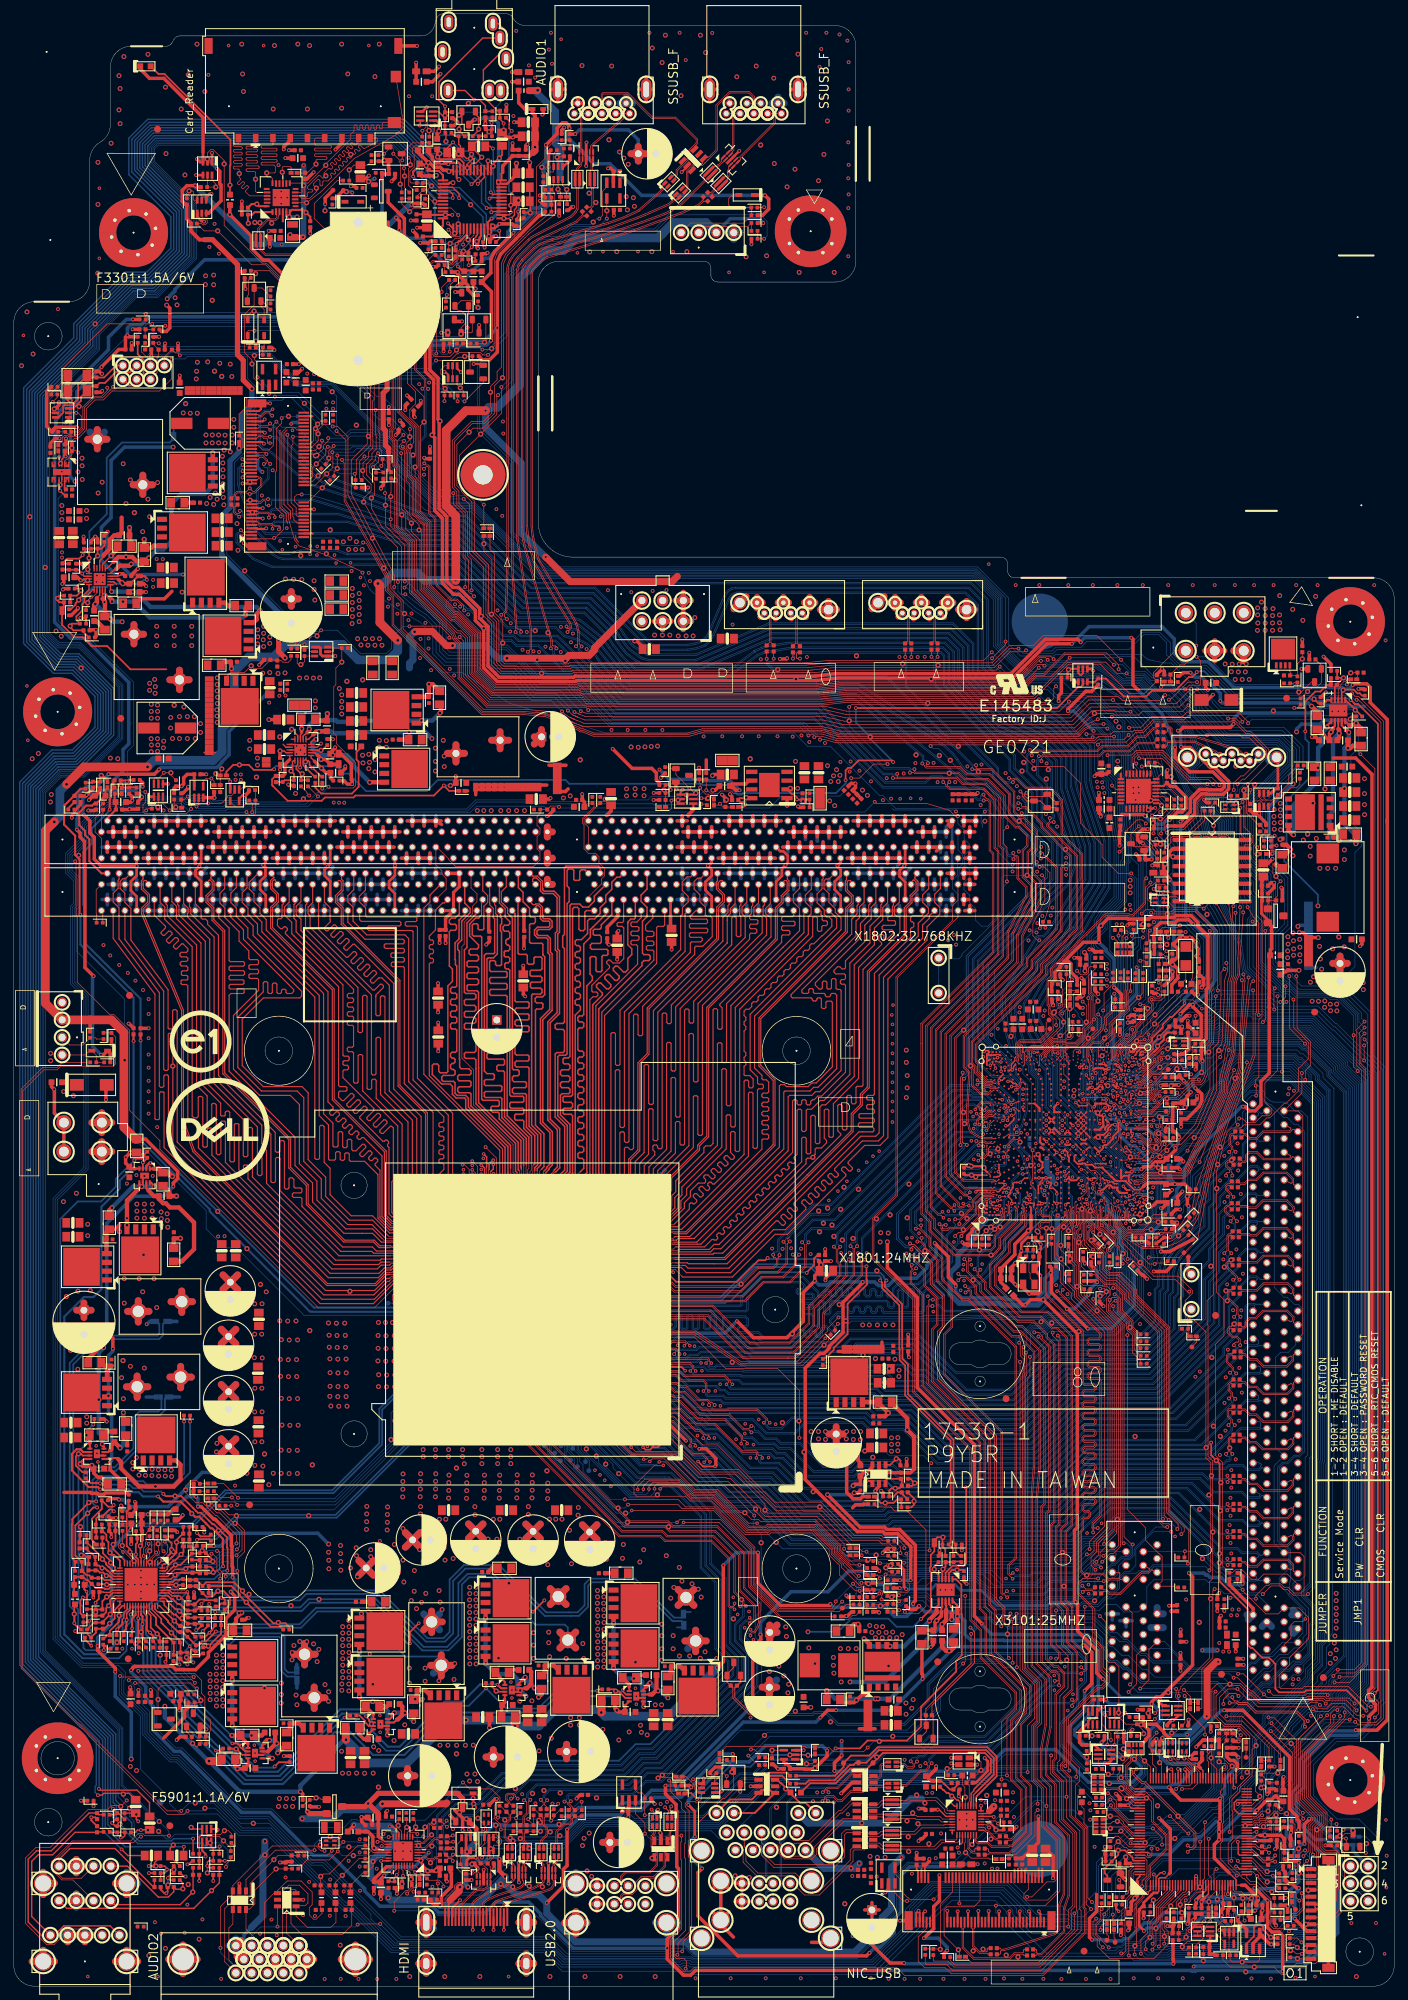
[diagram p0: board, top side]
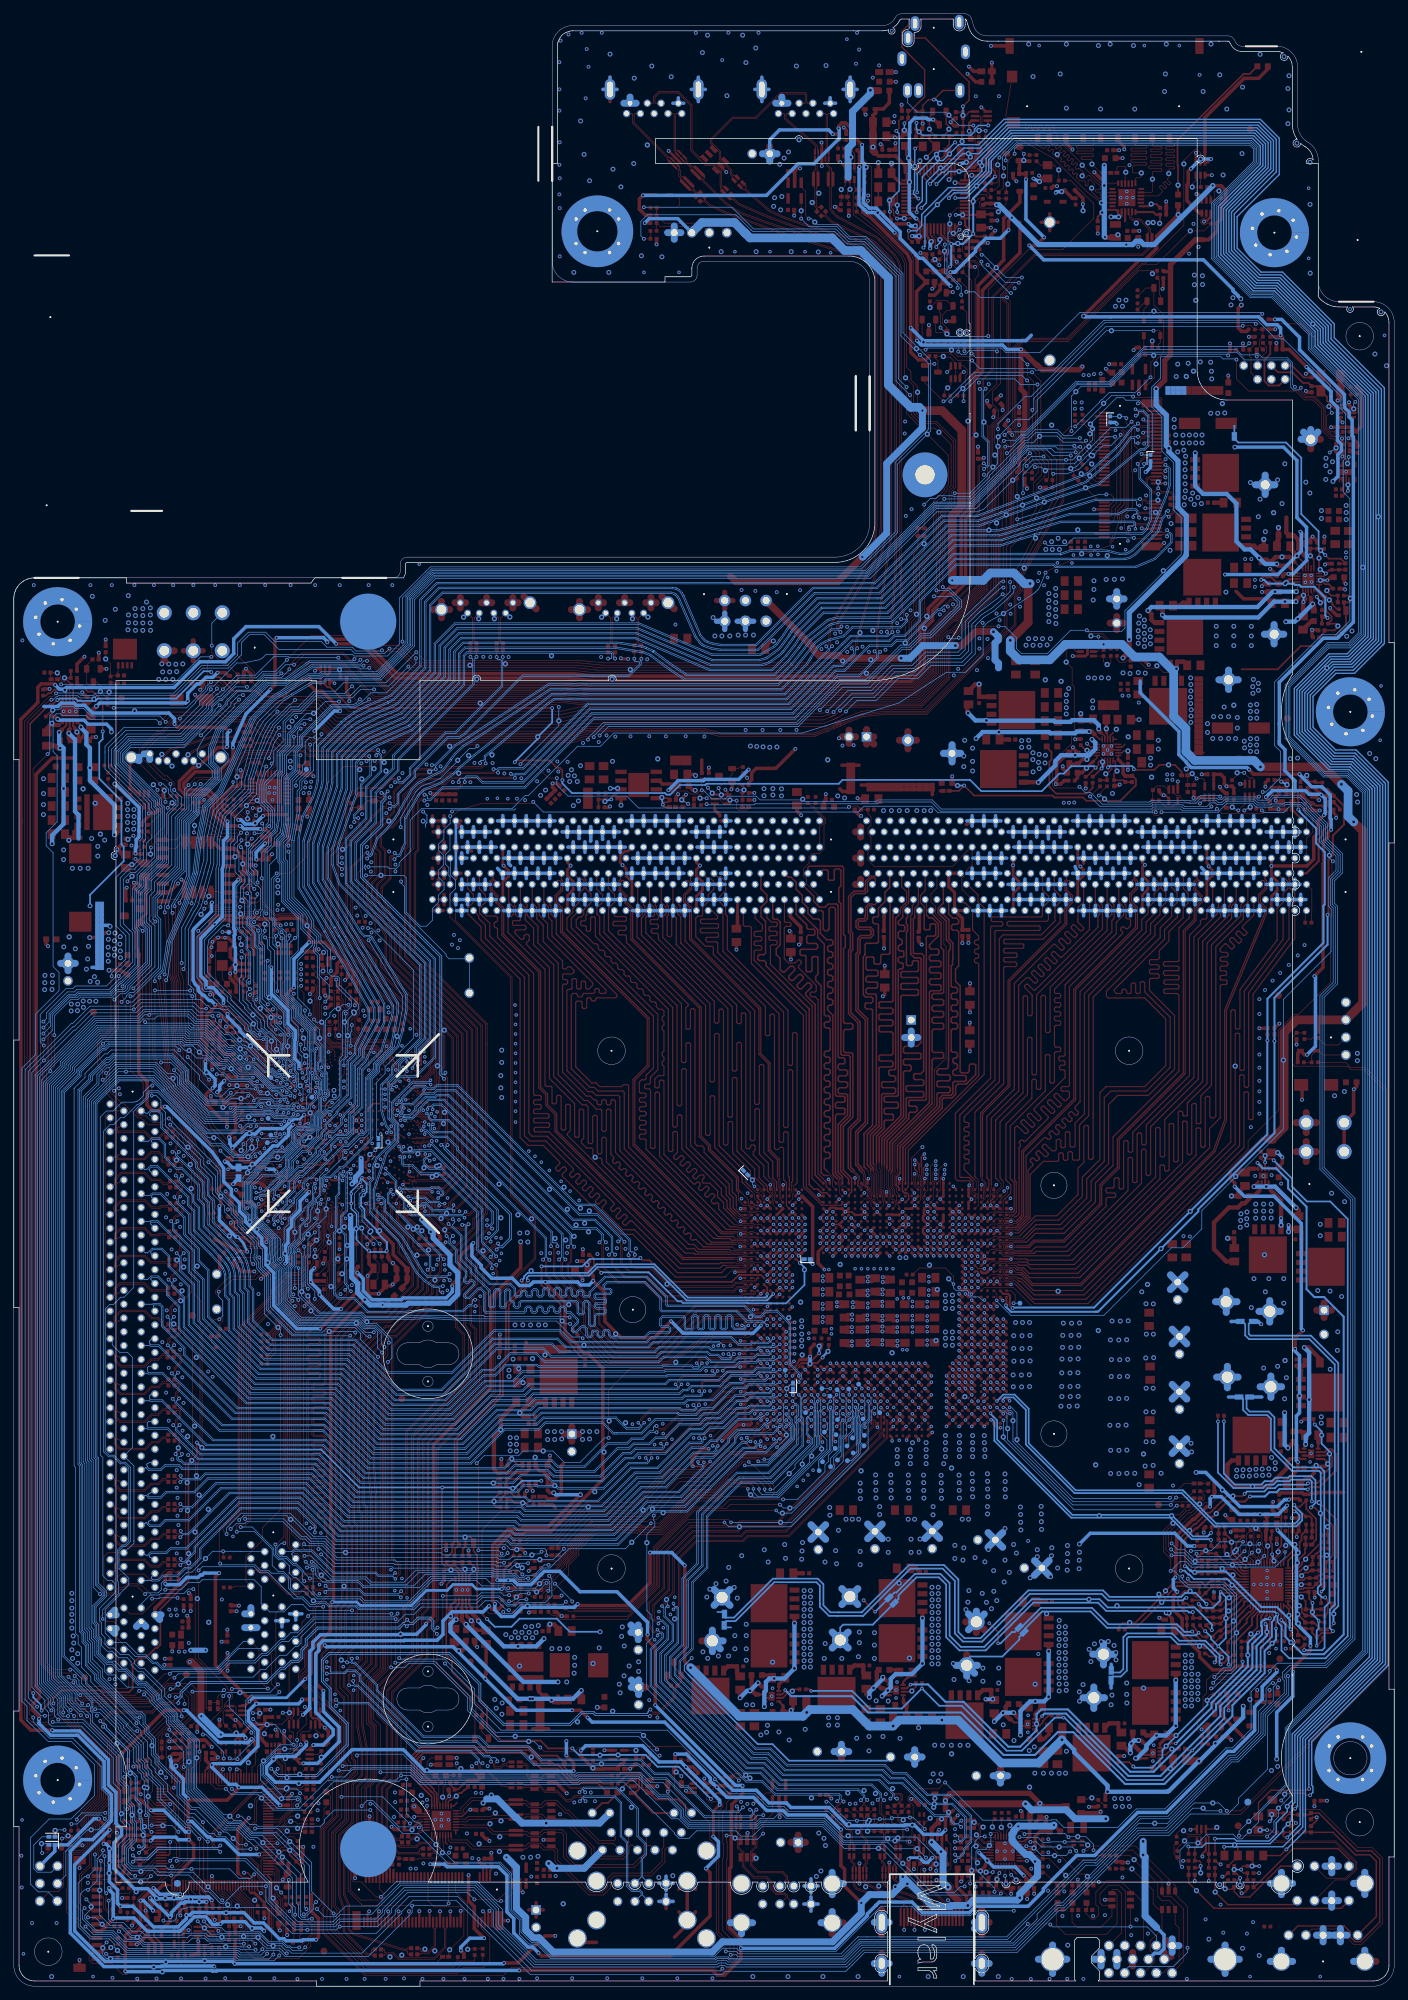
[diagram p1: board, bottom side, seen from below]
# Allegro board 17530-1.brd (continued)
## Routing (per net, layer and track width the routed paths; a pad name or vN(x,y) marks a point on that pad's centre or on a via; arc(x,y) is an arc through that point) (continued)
USB_OC1_R_N: length 292
  TOP w0.102: RN1901.3 160.58,152 161.19,152.61 161.19,152.65 v3(161.21,152.68) ; SB1.AL40 155.89,130.68 156.06,130.85 v3(156.06,130.89) ; v3(151.26,94.23) 151.58,93.91 151.58,66.89 151.13,66.44 151.13,55.37 152.04,54.45 152.04,49.55 153.45,48.14 153.45,42.91 152.27,41.72 152.27,32.44 151.9,32.07 151.9,31.56 153.24,30.22 153.24,24.7 155.16,22.79 155.16,11.43 155.35,11.24 155.35,7.74 149.18,1.57 129.06,1.57 127.89,2.74 98.6,2.74 97.94,2.08 97.14,2.08 95.12,4.1 95.12,6.67 96.74,8.29 96.74,18.27 96.64,18.37 96.64,20.87 96.72,20.95 v3(96.72,21.82) ; v3(91.44,22.1) 91.44,23.6 90.08,24.96 U3901.3 ; v3(176.8,132.7) 175.89,130.29 175.89,129.41 173.1,122.82 v3(171.81,119.35)
  BOTTOM w0.102: v3(91.44,22.1) 92.25,21.29 95.33,21.29 v2(95.5,21.46) 95.86,21.82 96.72,21.82 v3(96.72,21.82) ; v3(151.26,94.23) 151.28,94.21 159.63,94.21 163.37,97.95 163.37,102.91 164.46,103.99 164.52,104.17 164.52,104.73 164.65,105.13 164.9,105.37 164.9,105.75 164.76,105.89 164.76,107.04 164.88,107.16 164.88,107.93 167.23,110.28 167.23,111.05 168.2,112.01 168.2,112.46 168.2,112.88 170.46,115.14 170.46,118.01 v3(171.81,119.35) ; v3(176.8,132.7) 176,131.9 176,131.21 176,130.77 175.95,130.72 175.95,130.65 171.77,126.48 168.37,126.48 168.24,126.61 167.84,127.01 165.89,127.01 165.89,127.01 163.99,127.01 163.94,127.06 162.8,127.06 162.7,127.17 161.69,127.17 161.45,126.92 159.61,126.92 159.59,126.9 159.42,126.9 159.17,126.65 157.86,126.65 157.3,127.21 157.3,127.54 156.29,128.56 156.29,129.02 155.9,129.4 155.9,129.95 155.81,130.04 155.81,130.64 v3(156.06,130.89) 156.18,130.89 156.69,131.39 156.69,131.73 156.33,132.09 156.33,132.45 156.46,132.59 156.46,135.22 156.95,135.71 156.95,138.46 158.98,140.49 158.98,141.68 160.78,143.49 160.78,151.58 160.76,151.61 160.76,152.22 v3(161.21,152.68)
USB_OC2_R_N: length 15.2
  TOP w0.102: v1(155.43,133.11) 155.46,133.11 155.25,132.9 SB1.AJ44 ; v3(157.82,141.34) 157.82,141.36 157.96,141.5 157.96,143.85 159.26,145.15 R1605.1
  BOTTOM w0.102: v1(155.43,133.11) 155.43,133.16 155.36,133.23 155.36,133.85 155.36,136.4 155.68,136.71 v2(155.68,137.31) 155.68,138.53 157.82,140.68 v3(157.82,141.34)
USB_OC3_R_N: length 192.4
  TOP w0.102: v3(129.41,12.34) 128.83,12.34 127.67,13.5 U3201.3 ; SB1.AL41 155.47,131.74 155.47,131.78 155.4,131.85 v1(155.4,131.98) ; v3(146.81,12.93) 147.49,12.93 149.67,15.11 150.72,15.11 151.02,15.41 151.02,21.07 148.92,23.16 148.92,28.63 147.73,29.82 147.73,37.66 148.37,38.31 148.37,43.96 146.38,45.95 146.38,88.52 146.48,88.62 146.48,91.16 146.17,91.48 146.17,92.45 v3(146.3,92.58) ; R1604.1 160.06,152.63 v3(160.06,152.17)
  BOTTOM w0.102: v3(146.3,92.58) 146.76,93.04 146.76,94.6 147.64,95.48 149.18,95.48 150.1,96.39 158.55,96.39 161.21,99.05 161.21,103.8 162.35,104.94 162.35,105.74 162.27,105.83 162.27,108.21 164.1,110.04 164.26,110.04 165.38,111.16 165.38,112.68 165.57,112.86 165.57,113.02 166.12,113.57 166.12,116.34 164.72,117.73 164.72,117.89 162.52,120.09 v2(161.77,120.09) 161.12,120.09 159.12,122.1 159.12,123.57 158.78,123.91 157.86,123.91 157.62,124.15 157.01,124.15 156.44,124.72 156.44,126.05 155.6,126.89 155.6,128.7 155.27,129.03 155.27,129.71 155.2,129.78 155.2,131.78 v1(155.4,131.98) 155.4,132.21 156.04,132.85 156.04,133.74 155.77,134.02 155.77,135.97 156.44,136.64 156.44,138.6 158.52,140.68 158.52,141.87 160.32,143.68 160.32,151.39 160.06,151.66 v3(160.06,152.17) ; v3(146.81,12.93) 144.58,15.16 132.83,15.16 129.96,12.29 129.46,12.29 v3(129.41,12.34)
USB_OC4_R_N: length 13.7
  TOP w0.102: SB1.AV47 159.06,134.19 158.99,134.26 158.99,135.86 160.78,137.65 160.78,140.47 161.67,141.36 161.67,141.91 v2(162.97,143.21) 163.6,143.84 R1607.1
USB_OC5_R_N: length 29.5
  TOP w0.102: v3(163.6,151.92) 162.44,151.92 161.73,151.21 RN1901.1 ; SB1.AR35 157.8,128.36 v1(158.27,128.36)
  BOTTOM w0.102: v1(158.27,128.36) 158.1,128.53 158.1,130.03 v2(158.51,130.44) 158.78,130.7 158.78,132.24 159.16,132.62 159.16,133.65 159.69,134.18 159.69,137.25 159.61,137.33 159.61,138.18 160.7,139.27 160.7,141.15 163.14,143.59 163.14,147.76 162.76,148.14 162.76,149.86 163.23,150.32 163.23,151.55 v3(163.6,151.92)
USB_OC6_R_N: length 23.7
  TOP w0.102: R1606.1 163.79,148.54 v3(163.22,148.54) ; SB1.AR37 158.42,129.18 158.42,129.19 v1(158.55,129.19)
  BOTTOM w0.102: v1(158.55,129.19) 158.55,129.69 159.07,130.21 159.07,130.82 158.98,130.91 158.98,132.15 159.36,132.54 159.36,133.56 160.32,134.53 v2(160.32,136.14) 160.32,137.11 159.82,137.62 159.82,138 160.83,139.01 160.93,139.12 160.93,141.05 163.37,143.49 163.37,148.39 v3(163.22,148.54)
USB_PCH_PN1: length 244.7
  TOP w0.102: v3(74.48,193.29) 74.8,193.62 74.8,196.45 72.9,209.39 72.88,209.47 72.84,210.07 72.83,210.08 72.83,248.6 73.01,249.22 73.03,249.27 73.19,249.54 73.29,249.69 73.48,249.96 73.56,250.08 73.6,250.12 73.64,250.18 75.35,251.88 75.91,252.28 75.94,252.3 76.14,252.4 76.25,252.45 77.66,253 77.97,253.1 77.97,253.1 78.02,253.11 80.65,253.9 80.68,253.91 82.54,254.45 84.96,255.16 85.49,255.32 85.5,255.32 86.1,255.49 88.33,256.28 90.47,257.28 90.56,257.36 93.5,259.92 93.93,260.35 93.93,260.77 TR3801.1 ; SB1.J3 145.26,112.7 145.27,112.7 145.41,112.57 145.41,110.79 142.95,108.34 142.95,106.84 141.9,105.79 136.25,105.79 132.59,109.45 132.59,110.69 131.42,111.86 131.42,136.5 131.42,139.43 141.77,149.78 141.77,164.03 141.32,164.49 141.32,171.54 141.1,171.75 v3(140.52,171.75)
  BOTTOM w0.102: v3(140.52,171.75) 139.6,171.75 137.81,173.55 125.9,173.55 115.91,183.54 86.81,183.54 80.61,189.74 77.42,189.74 76.7,190.46 ; 76.7,190.46 74.75,192.4 74.75,193.02 v3(74.48,193.29) ; 76.7,190.46 v2(76.46,190.16)
USB_PCH_PN2: length 238.6
  TOP w0.102: v1(146.19,117.65) SB1.N13 ; v1(134.69,111.31) 134.32,111.68 133.88,111.68 132.82,112.75 132.82,138.85 143.19,149.22 143.19,164.67 142.71,165.15 142.71,172.11 140.79,174.04 137.44,174.04 136.58,174.9 127.96,174.9 127.86,175.01 v3(127.38,175.01) ; v3(77.81,193.79) 77.81,194.91 77.24,196.79 77.23,196.79 77.21,196.87 76.75,198.49 73.88,208.62 73.88,208.63 73.71,209.46 73.61,210.26 73.53,211.33 73.53,248.12 73.55,248.29 73.58,248.43 73.58,248.48 73.59,248.52 73.66,248.9 73.69,248.96 74.11,249.65 75.56,251.1 75.97,251.43 76.52,251.75 77.2,252.01 78.91,252.56 79.49,252.73 84.78,254.33 86.31,254.8 90.32,256.25 91.45,256.71 94.89,258.23 95.56,258.83 95.68,258.95 95.68,259.29 TR3802.1
  BOTTOM w0.102: 138.1,111.58 134.96,111.58 v1(134.69,111.31) ; 138.1,111.58 142.42,111.58 143.55,112.71 143.55,113.78 144.72,114.95 144.72,116.55 145.82,117.65 v1(146.19,117.65) ; 138.1,111.58 v2(138.1,111.2) ; v3(77.81,193.79) 78.09,193.5 78.09,192.95 79.91,191.13 81.19,191.13 87.39,184.94 116.49,184.94 125.95,175.48 127.27,175.48 127.38,175.36 v3(127.38,175.01)
USB_PCH_PN5: length 113.5
  TOP w0.102: v2(150.38,96.08) 150.11,95.81 ; 150.11,95.81 148.83,97.09 145.79,97.09 141.57,101.31 141.57,104.47 143.65,106.55 143.65,108.05 146.14,110.54 146.14,111.62 SB1.M1 ; 150.11,95.81 150.48,95.44 151.2,95.44 152.67,93.97 152.67,66.98 151.83,66.15 151.83,55.65 152.74,54.74 152.74,54.61 152.74,54.61 152.74,49.83 154.15,48.42 154.15,41.69 154.15,41.51 153.64,41 153.43,41 153.33,40.89 v3(153.33,40.59) ; TR3202.1 128.41,28.74 128.64,28.98 129.33,28.98 131.47,31.11 132.16,31.11 132.68,31.63 132.68,31.98 132.98,32.28 v3(132.98,32.3)
  BOTTOM w0.102: v3(153.33,40.59) 153.02,40.89 148.66,40.89 141.71,33.93 133.86,33.93 132.71,32.79 132.71,32.56 v3(132.98,32.3)
USB_PCH_PN6: length 112.3
  TOP w0.102: TR3201.1 128.47,31.82 128.65,32 129.02,32 129.45,31.57 130.29,31.57 130.52,31.8 130.52,32.2 v3(130.86,32.54) ; v3(151.43,43.59) 151.43,44.09 151.55,44.21 151.55,45.16 151.02,45.69 150.38,45.69 149.01,47.06 149.01,69.4 149.44,69.83 149.44,92.41 146.16,95.69 145.18,95.69 140.17,100.71 140.17,101.66 138.26,103.57 138.26,104.99 v3(138.53,105.26) ; SB1.K7 v1(145.34,115.37)
  BOTTOM w0.102: v1(145.34,115.37) 145.88,114.82 145.88,113.47 142.66,110.25 ; 142.66,110.25 138.3,105.89 138.3,105.51 v3(138.53,105.26) ; 142.66,110.25 v2(142.91,109.97) ; v3(130.86,32.54) 130.86,32.91 131.17,33.21 131.91,33.21 133.34,34.63 141.42,34.63 150.18,43.4 150.64,43.4 150.83,43.59 v3(151.43,43.59)
USB_PCH_PN7: length 152.8
  TOP w0.102: SB1.L4 146.48,112.67 146.48,112.1 146.67,111.91 146.67,110.08 144.35,107.76 144.35,106.26 142.32,104.23 142.32,101.55 146.08,97.79 149.84,97.79 153.4,94.23 153.4,66.73 152.53,65.86 152.53,55.94 153.44,55.03 153.44,54.9 153.44,50.12 155.49,48.08 155.49,45.87 155.26,45.64 155.02,45.64 v3(154.66,45.28) ; TR3902.2 92.53,24.74 92.73,24.94 92.73,25.26 v3(92.41,25.58)
  BOTTOM w0.102: 116.1,31.98 124.66,31.98 126.59,33.91 131.52,33.91 132.94,35.33 141.06,35.33 149.92,44.19 149.92,44.97 150.56,45.61 151.63,45.61 151.95,45.28 v3(154.66,45.28) ; 116.1,31.98 v2(116.1,31.6) ; 116.1,31.98 109.5,31.98 107.49,29.97 105.5,29.97 99.99,24.46 93.22,24.46 92.75,24.93 92.75,25.24 v3(92.41,25.58)
USB_PCH_PN8: length 251.6
  TOP w0.089: 144.31,111.2 144.31,111.23 144.32,111.24 144.32,111.76 144.06,112.02 144.06,112.96 SB1.G4
  TOP w0.102: 144.31,111.2 144.31,111.04 142.04,108.76 142.04,107.22 141.52,106.71 136.63,106.71 133.5,109.83 133.5,111.15 132.33,112.32 132.33,139.05 142.71,149.42 142.71,164.45 142.23,164.93 142.23,171.91 140.59,173.56 135.65,173.56 135.25,173.96 135.25,174.11 v3(135.55,174.41) ; v3(59.21,231.39) 59.48,231.66 59.48,232.73 58.07,234.13 58.07,244.64 52.01,250.7 36.43,250.7 35.1,252.02 R3303.3 ; v3(64.67,199.84) 64.78,199.95 64.78,200.09 64.17,200.7 63.36,200.7 61.22,202.83 60.93,203.53 60.93,212.52 60.08,213.37 60.08,220.03 59.98,220.13 59.78,220.13 v3(59.42,219.77)
  BOTTOM w0.102: 67.46,198.17 66.14,199.49 65.73,199.49 65.19,200.03 64.87,200.03 v3(64.67,199.84) ; 67.46,198.17 70.61,195.02 72.15,195.02 72.89,194.28 76.07,194.28 79.71,190.65 80.99,190.65 87.19,184.45 116.29,184.45 126.27,174.47 132.05,174.47 132.89,175.31 134.45,175.31 134.82,174.94 135.32,174.94 135.55,174.72 v3(135.55,174.41) ; 67.46,198.17 v2(67.72,198.43) ; v3(59.21,231.39) 59.51,231.09 59.51,224.56 58.7,223.75 58.7,220.28 58.93,220.06 59.14,220.06 v3(59.42,219.77)
USB_PCH_PN9: length 148
  TOP w0.102: v3(151.72,46.91) 151.6,47.24 151.6,48.3 150.42,49.48 150.42,66.8 150.85,67.23 150.85,93 149.76,94.09 149.76,94.46 147.83,96.39 145.5,96.39 140.87,101.02 140.87,101.98 139.79,103.06 139.79,103.53 v3(140.04,103.78) ; v3(94.36,25.91) 94.9,25.37 94.9,25.18 94.69,24.96 TR3901.2 ; SB1.M6 v3(147.18,113.95)
  BOTTOM w0.102: v3(140.04,103.78) 139.8,104.01 139.8,105.69 146.35,112.24 146.35,113.84 146.65,114.13 147,114.13 v3(147.18,113.95) ; v2(152.55,47.24) v3(151.72,46.91) 151.2,46.91 151.01,46.72 150.65,46.72 147.5,43.57 147.5,42.84 140.69,36.03 132.65,36.03 131.23,34.61 125.51,34.61 123.58,32.68 109.21,32.68 107.2,30.67 105.21,30.67 103.34,28.8 102.42,28.8 98.77,25.16 95.03,25.16 94.63,25.57 94.63,25.64 v3(94.36,25.91)
USB_PCH_PN14: length 207.6
  TOP w0.102: SB1.E5 v1(142.54,113.77) ; v1(138.38,113.06) 137.92,113.06 137.61,112.75 137.01,112.75 136.78,112.98 136.78,113.36 134.21,115.93 134.21,138.27 144.6,148.66 144.6,152.49 144.67,152.62 144.67,152.62 144.71,152.69 146.51,156.25 146.61,156.44 146.7,156.62 147.29,157.77 147.29,159.46 146.1,160.64 146.1,164.59 146.72,165.21 146.72,166.64 145.59,167.77 145.14,167.77 143.42,169.49 143.42,172.4 141.08,174.74 137.73,174.74 136.83,175.64 130.51,175.64 130.37,175.78 v3(129.84,175.78) ; v3(32.9,210.9) 33.24,210.56 33.53,210.56 33.63,210.67 NGFF1.5
  BOTTOM w0.102: v3(129.84,175.78) 129.84,176.15 129.69,176.3 126.12,176.3 117.08,185.34 117.07,185.34 116.78,185.64 87.68,185.64 81.73,191.58 81.54,191.78 80.18,193.05 79.47,193.76 79.37,193.86 79.09,194.12 78.44,194.77 73.09,194.77 72.35,195.5 70.86,195.5 68.63,197.73 68.63,200.57 63.41,205.79 53.59,205.79 ; v3(32.9,210.9) 32.57,210.58 32.44,210.58 32.18,210.32 32.18,209.09 34.61,206.67 36.02,206.07 37.42,205.47 48.82,205.47 48.82,205.47 49.07,205.47 49.38,205.79 53.59,205.79 ; 53.59,205.79 v2(53.59,205.41) ; v1(142.54,113.77) 142.24,114.07 140.46,114.07 139.88,113.49 138.48,113.49 138.38,113.39 v1(138.38,113.06)
USB_PCH_PP1: length 243.9
  TOP w0.102: v3(75.29,193.35) 75.02,193.62 75.02,196.47 75.02,196.47 73.1,209.49 73.05,210.08 73.05,248.57 73.22,249.16 73.38,249.43 73.66,249.84 73.73,249.95 73.77,249.98 73.81,250.04 75.48,251.72 76.03,252.1 76.24,252.21 77.73,252.8 78.03,252.89 78.08,252.91 78.09,252.91 80.72,253.69 80.73,253.7 82.6,254.25 85.02,254.96 85.55,255.11 86.16,255.28 86.17,255.29 88.4,256.08 88.81,256.27 90.58,257.09 90.7,257.19 93.64,259.76 93.65,259.77 94.16,260.27 94.35,260.27 TR3801.2 ; v3(140.49,172.59) 140.62,172.34 140.99,171.97 141.19,171.97 141.53,171.62 141.53,164.58 141.99,164.12 141.99,149.69 131.64,139.34 131.64,139.31 131.64,111.95 132.8,110.78 132.8,109.54 136.34,106.01 141.81,106.01 142.74,106.93 142.74,108.43 145.19,110.88 145.19,112.38 SB1.J2
  BOTTOM w0.102: v3(75.29,193.35) 74.97,193.03 74.97,192.49 75.58,191.88 ; v2(75.84,192.15) 75.58,191.88 ; 75.58,191.88 77.51,189.95 80.7,189.95 86.9,183.76 116,183.76 125.99,173.76 137.9,173.76 139.69,171.97 140,171.97 140.11,172.07 140.11,172.49 140.21,172.59 v3(140.49,172.59)
USB_PCH_PP2: length 239.1
  TOP w0.102: TR3802.2 96.13,258.83 95.86,258.83 95.71,258.68 95.01,258.05 92.15,256.78 91.53,256.51 90.85,256.24 90.39,256.05 86.38,254.6 86.37,254.6 84.84,254.12 84.84,254.12 78.97,252.35 77.28,251.81 76.61,251.55 76.09,251.25 75.71,250.94 74.28,249.51 73.88,248.86 73.87,248.83 73.8,248.47 73.79,248.4 73.76,248.26 73.75,248.11 73.75,211.34 73.83,210.29 73.93,209.5 74.09,208.68 76.96,198.55 77.42,196.93 77.42,196.93 78.02,194.94 78.02,194.25 78.15,194.13 78.52,194.13 78.62,194.03 v3(78.62,193.79) ; v3(127.99,175.62) 127.99,175.18 128.05,175.12 136.67,175.12 137.53,174.26 140.88,174.26 142.93,172.2 142.93,165.24 143.41,164.76 143.41,149.13 133.03,138.76 133.03,112.84 133.97,111.9 134.26,111.9 v1(134.55,112.18) ; v1(146.11,118.46) 146.11,118.46 SB1.N15
  BOTTOM w0.102: 79.64,191.71 78.31,193.04 78.31,193.47 78.62,193.78 v3(78.62,193.79) ; 79.64,191.71 v2(79.91,191.97) ; 79.64,191.71 80,191.35 81.28,191.35 84.37,188.27 87.48,185.15 116.58,185.15 126.04,175.69 127.36,175.69 127.61,175.43 127.81,175.43 v3(127.99,175.62) ; v1(134.55,112.18) 134.94,111.79 142.33,111.79 143.33,112.8 143.33,113.87 144.5,115.04 144.5,116.64 146.11,118.25 v1(146.11,118.46)
USB_PCH_PP5: length 113.7
  TOP w0.102: 149.11,96.51 150.39,95.22 151.11,95.22 152.45,93.88 152.45,67.07 151.61,66.24 151.61,55.57 152.53,54.65 152.53,54.52 152.53,49.74 153.94,48.33 153.94,41.6 153.6,41.26 153.43,41.26 153.33,41.36 v3(153.33,41.5) ; 149.11,96.51 v2(148.84,96.24) ; 149.11,96.51 148.74,96.88 145.7,96.88 141.35,101.22 141.35,104.56 143.43,106.64 143.43,108.14 145.92,110.63 145.92,111.88 146.03,111.99 SB1.L2 ; v3(132.09,32.3) 132.46,31.93 132.46,31.72 132.07,31.33 131.38,31.33 129.24,29.19 128.64,29.19 128.44,29.39 TR3202.2
  BOTTOM w0.102: v3(132.09,32.3) 132.4,32.3 132.5,32.4 132.5,32.88 133.77,34.15 141.62,34.15 148.58,41.11 152.94,41.11 v3(153.33,41.5)
USB_PCH_PP6: length 112.6
  TOP w0.102: v3(129.95,32.57) 130.3,32.22 130.3,31.89 130.2,31.79 129.54,31.79 129.11,32.22 128.66,32.22 128.41,32.47 TR3201.2 ; v3(137.72,105.31) 138.05,104.98 138.05,103.48 139.95,101.57 139.95,100.62 145.09,95.48 146.07,95.48 149.22,92.32 149.22,69.92 148.79,69.49 148.79,46.97 150.29,45.48 150.93,45.48 151.33,45.07 151.33,44.3 151.26,44.22 v3(150.83,44.22) ; SB1.K6 v1(145.02,114.68)
  BOTTOM w0.102: 141.78,109.68 145.67,113.56 145.67,114.73 145.44,114.96 145.31,114.96 v1(145.02,114.68) ; 141.78,109.68 v2(141.55,109.97) ; 141.78,109.68 138.09,105.98 138.09,105.63 v3(137.72,105.31) ; v3(129.95,32.57) 129.95,32.85 130.18,33.07 130.73,33.07 131.08,33.43 131.83,33.43 133.25,34.85 141.33,34.85 150.09,43.61 150.55,43.61 150.83,43.89 v3(150.83,44.22)
USB_PCH_PP7: length 152.8
  TOP w0.102: TR3902.1 93.18,24.71 92.94,24.94 92.94,25.46 93.05,25.57 v3(93.33,25.57) ; SB1.L3 146.16,112.69 146.26,112.58 146.26,112.01 146.46,111.82 146.46,110.17 144.13,107.85 144.13,106.35 142.1,104.32 142.1,101.46 145.99,97.57 149.75,97.57 153.18,94.14 153.18,66.82 152.31,65.95 152.31,55.85 153.23,54.94 153.23,54.81 153.23,50.03 155.27,47.99 155.27,45.96 155.17,45.86 155,45.86 v3(154.66,46.2)
  BOTTOM w0.102: v3(93.33,25.57) 93.07,25.57 92.96,25.46 92.96,25.02 93.31,24.68 99.9,24.68 105.41,30.19 107.4,30.19 109.41,32.19 124.57,32.19 125.3,32.92 ; v3(154.66,46.2) 154.53,46.33 154.25,46.33 154.15,46.23 154.15,45.6 154.05,45.5 152.04,45.5 151.72,45.82 150.47,45.82 149.71,45.06 149.71,44.28 140.97,35.55 132.85,35.55 131.43,34.12 126.5,34.12 125.3,32.92 ; v2(125.02,33.2) 125.3,32.92
USB_PCH_PP8: length 251.5
  TOP w0.089: 144.53,111.2 144.53,111.23 144.51,111.24 144.51,111.84 144.25,112.1 144.25,113.04 144.11,113.19 SB1.G5
  TOP w0.102: v3(59.47,220.58) 59.71,220.34 60.07,220.34 60.3,220.12 60.3,213.46 61.15,212.61 61.15,203.57 61.41,202.95 63.45,200.91 64.26,200.91 64.86,200.32 64.87,200.32 65.15,200.04 65.15,199.39 v3(65.26,199.28) ; v3(60.03,231.37) 59.69,231.71 59.69,232.82 58.28,234.22 58.28,244.73 52.1,250.91 36.52,250.91 35.76,251.67 R3303.4 ; 144.53,111.2 144.53,110.95 142.25,108.67 142.25,107.13 141.61,106.49 136.54,106.49 133.29,109.74 133.29,111.06 132.12,112.23 132.12,136.79 132.12,139.14 142.49,149.51 142.49,164.36 142.02,164.84 142.02,171.82 140.5,173.34 135.56,173.34 135.03,173.87 135.03,174.04 v3(134.66,174.41)
  BOTTOM w0.102: 68.35,196.98 v2(68.07,196.7) ; 68.35,196.98 67.31,198.02 66.05,199.28 v3(65.26,199.28) ; 68.35,196.98 70.52,194.81 72.06,194.81 72.8,194.07 75.98,194.07 79.62,190.44 80.9,190.44 87.1,184.24 116.2,184.24 126.18,174.26 132.14,174.26 132.98,175.1 134.36,175.1 134.66,174.79 v3(134.66,174.41) ; v3(59.47,220.58) 59.16,220.27 59.02,220.27 58.92,220.37 58.92,223.66 59.73,224.47 59.73,231.27 59.83,231.37 v3(60.03,231.37)
USB_PCH_PP9: length 147.6
  TOP w0.102: v3(151.02,47.44) 151.28,47.44 151.38,47.54 151.38,48.21 150.2,49.39 150.2,66.89 150.63,67.32 150.63,92.91 149.54,94 149.54,94.37 147.74,96.18 145.41,96.18 140.65,100.93 140.65,101.89 139.57,102.97 139.57,103.48 v3(139.2,103.85) ; SB1.N8 146.83,114.54 146.93,114.44 147.08,114.44 v3(147.27,114.63) ; v3(95.25,26.04) 95.12,25.9 95.12,25.18 95.34,24.96 TR3901.1
  BOTTOM w0.102: 140.18,106.38 139.59,105.78 139.59,104.23 v3(139.2,103.85) ; 140.18,106.38 146.14,112.33 146.14,113.93 146.56,114.35 146.99,114.35 v3(147.27,114.63) ; 140.18,106.38 v2(139.9,106.65) ; v3(95.25,26.04) 95.12,26.04 95.02,25.93 95.02,25.48 95.12,25.37 98.68,25.37 102.33,29.02 103.25,29.02 105.12,30.89 107.11,30.89 109.12,32.89 123.49,32.89 125.42,34.82 131.14,34.82 132.56,36.25 140.6,36.25 147.28,42.93 147.28,43.66 150.56,46.94 150.92,46.94 151.02,47.04 v3(151.02,47.44)
USB_PCH_PP14: length 207.7
  TOP w0.102: v3(32.9,209.99) 33.26,210.35 33.49,210.35 33.67,210.17 NGFF1.3 ; v1(137.55,113.37) 137.67,113.25 137.67,113.11 137.52,112.96 137.1,112.96 137,113.06 137,113.45 134.43,116.02 134.43,138.18 144.82,148.57 144.82,152.43 144.87,152.54 144.87,152.54 144.9,152.59 146.71,156.15 146.81,156.35 146.9,156.52 147.5,157.71 147.5,159.55 146.32,160.73 146.32,164.5 146.94,165.13 146.94,166.73 145.68,167.98 145.23,167.98 143.64,169.58 143.64,172.49 141.17,174.96 137.82,174.96 136.92,175.86 130.6,175.86 130.48,175.97 130.48,176.27 v3(130.49,176.28) ; SB1.F6 142.91,114.41 v1(142.85,114.36)
  BOTTOM w0.102: v1(142.85,114.36) 142.78,114.29 140.37,114.29 139.79,113.7 138.39,113.7 138.2,113.51 138.19,113.51 138.05,113.37 v1(137.55,113.37) ; 68.85,198.73 68.85,200.66 63.5,206.01 49.29,206.01 48.98,205.69 48.73,205.69 48.73,205.69 37.47,205.69 34.73,206.85 32.4,209.18 32.4,210.23 32.53,210.36 32.8,210.36 32.9,210.26 v3(32.9,209.99) ; 68.85,198.73 68.85,197.82 70.95,195.72 72.44,195.72 73.18,194.98 78.53,194.98 79.23,194.28 79.52,194.02 79.62,193.91 80.33,193.21 81.69,191.93 87.77,185.85 116.87,185.85 117.16,185.56 117.17,185.56 126.21,176.52 129.78,176.52 130.02,176.28 v3(130.49,176.28) ; 68.85,198.73 v2(69.22,198.73)
V_3_CARD_BD: length 12
  TOP w0.762: v3(41.91,253.37) 41.86,253.31 F3301.2
  BOTTOM w0.762: v3(41.91,253.37) 42,253.46 v2(42,260.83) v3(42,263.75)
V_CPU_ST_PLL: length 602.7
  TOP w0.203: U2401.29 175.89,13.59 175.9,13.59 v3(175.9,13.34)
  TOP w0.406: R808.1 180.85,158.25 180.85,157.29 C803.2 180.77,157.19 180.77,155.37 181.71,154.43 Q801.S
  TOP w0.508: v3(107.06,40.71) 107.06,49.05 108.23,50.22 108.23,50.94 v3(108.16,50.94) ; R2026.2 R2024.2 156.74,102.17 156.95,102.01 156.97,101.98 v3(156.97,101.98) ; v3(129.95,58.8) 129.95,62.35 129.98,62.38 129.98,63.64 128.08,65.53 126.23,65.53 125.9,65.86 122.19,65.86 114.66,73.39 114.66,89.53 115.06,89.92 116.81,91.67 117.4,91.67 118.16,92.43 118.16,92.7 120.14,94.69 120.14,99.06 122.99,101.9 v3(122.99,102.01) ; R2028.2 156.08,104.39 v1(156.46,104.01) ; C1033.1 116.76,104.91 C1032.1 116.05,102.92 v3(116.05,102.16) 114.38,100.49 114.38,96.64 114.38,96.32 114.37,96.31 112.05,93.98 111.98,93.94 107.18,93.94 v1(104.78,96.34) ; PC4401.1 23.04,69.09 PR4404.1 PR4406.1 PR4405.1 20.25,68.35 v3(19.43,68.35) ; Q801.S 181.74,154.03 182.25,153.52 182.25,150.32 182.07,150.14 182.07,149.38 R803.2 181.89,149.2 181.89,143.23 181.89,143.22 181.89,141.88 181.89,141.87 181.89,132.26 180.7,131.06 180.7,127.64 179.85,126.8 179.02,126.8 178.41,127.41 v3(178.1,127.41) ; C2411.1 178.89,10.08 R2430.1 179.67,10.86 179.76,10.95 v3(179.84,10.95) ; v3(26.67,69.47) 27.15,69.47 28.98,67.64 29.17,67.64 29.25,67.56 31.52,65.28 31.52,63.81 31.61,63.73 31.61,62.13 31.63,62.1 31.63,60.82 31.7,60.76 v3(31.7,59.21) ; v3(155.7,100.15) 155.7,100.36 155.97,100.63 R2021.2 ; v3(136.46,101.38) 136.46,101.66 135.41,102.72 135.41,105.66 v3(133.43,107.64) ; R404.1 15.62,68.91 15.62,69.49 15.53,69.58 v3(15.53,69.62) ; R403.1 26.07,71.75 R401.1 26.02,71.29 v3(26.42,70.9) ; v3(94.41,29.04) 94.41,27.86 95.95,26.32 95.95,25.43 96.06,25.32 96.06,17.28 96.31,17.04 96.31,8.47 94.67,6.82 v3(94.67,5.51) 94.67,3.95 97.02,1.6 98.07,1.6 98.76,2.29 v3(126.77,2.29) ; R808.1 C805.1 180.82,159.42 180.82,160.1 180.91,160.19 180.91,160.62 C804.1 ; 150.34,103.34 150.34,104.02 R1703.2 ; 150.34,103.34 150.34,100.5 152.58,98.26 v3(152.58,98.09) 152.75,98.09 155.59,95.25 v3(155.6,95.25) ; 150.34,103.34 v3(150.22,103.34) ; R402.2 v3(128.37,58.8) ; v3(179.76,14.23) 179.8,14.23 180.13,13.9 180.13,13.9 181.63,12.4 v3(181.65,12.4) 181.65,8.48 182.28,7.85 183.34,7.85 183.85,7.34 v3(183.85,2.16) ; v3(17.01,45.78) 17.16,45.93 17.25,46.15 17.49,46.31 17.51,46.33 22.24,46.33 22.27,46.35 23,46.35 23.51,45.85 26.34,45.85 28.19,47.7 28.19,48.34 30.73,50.88 30.73,53.25 32,54.52 32,56.54 v3(31.42,57.12)
  BOTTOM w0.508: 156.97,101.98 v3(156.97,101.98) ; 156.97,101.98 156.97,101.97 155.7,100.7 v3(155.7,100.15) 153.64,98.09 v3(152.58,98.09) ; 156.97,101.98 156.97,101.98 156.97,103.51 v1(156.46,104.01) ; v3(175.9,13.34) 178.87,13.34 v3(179.76,14.23) ; v3(94.41,29.04) 94.44,29.01 94.47,29.01 94.54,29.08 95.44,29.08 v3(107.06,40.71) ; v3(126.77,2.29) 170.57,2.29 170.67,2.18 171.22,2.18 171.32,2.29 178.31,2.29 178.49,2.11 ; v3(183.85,2.16) 183.79,2.11 178.49,2.11 ; v3(26.67,69.47) 26.67,70.65 v3(26.42,70.9) 25.05,70.9 22.5,68.35 v3(19.43,68.35) 16.8,68.35 v3(15.53,69.62) ; v3(178.1,127.41) 177.85,127.41 171.24,120.79 169.6,118.47 169.6,116.56 168.48,115.44 168.48,114.61 167.3,113.42 167.3,112.26 166.42,111.39 166.42,110.73 164.07,108.38 164.07,107.5 163.47,106.9 163.47,104.48 162.33,103.34 162.33,102.58 162.33,98.59 161.68,97.94 158.99,95.25 v3(155.6,95.25) ; v3(31.42,57.12) 32,57.71 32,58.91 v3(31.7,59.21) ; v1(91.75,95.71) 92.88,94.59 103.02,94.59 v1(104.78,96.34) ; v2(178.49,2.08) 178.49,2.11 ; v3(108.16,50.94) 108.18,50.94 108.18,52.71 112.61,57.14 117.97,57.14 120.93,60.1 123.14,60.1 125.07,58.17 126.99,58.17 127.38,58.56 127.62,58.8 v3(128.37,58.8) v3(129.95,58.8) ; v3(133.43,107.64) 133.62,107.45 133.62,105.76 132.27,104.41 132.27,104.25 132.27,104.05 130.77,102.55 127.77,102.55 126.72,101.5 125.28,101.5 125.1,101.68 125.04,101.68 124.71,102.01 v3(122.99,102.01) 118.31,102.01 117.88,101.57 116.64,101.57 v3(116.05,102.16) ; v3(136.46,101.38) 136.46,100.59 137.36,99.69 143.64,99.69 143.89,99.44 148.08,99.44 149.35,100.71 149.35,102.48 150.22,103.34 v3(150.22,103.34) ; v3(94.67,5.51) 94.63,5.48 81.06,5.48 76.33,10.22 76.33,10.46 75.11,11.68 75.02,11.77 74.61,12.18 69.87,12.18 68.32,10.64 61.56,10.64 61.47,10.73 60.62,11.58 53.04,11.58 50.83,13.8 50.83,14.12 46.01,18.94 43.4,18.94 37.16,25.17 33,25.17 24.16,34.01 23.25,34.01 20.22,37.04 20.22,40.46 19.13,41.55 19.13,43.38 17.01,45.5 v3(17.01,45.78) ; v3(181.65,12.4) 181.2,12.4 179.84,11.04 v3(179.84,10.95)
V_SM_VREF_CNT: length 108.4
  TOP w0.305: CPU1.AB40 56.18,98.71 v3(56.27,98.62) ; v3(17.35,136.91) C601.1 ; R601.1 9.66,173.44 8.79,172.57 C602.1 8.7,172.4 7.28,170.98 7.28,168.26 8.88,166.66 8.89,166.63 8.89,163.85 9.53,163.21 9.53,155.32 v3(9.65,155.19)
  BOTTOM w0.305: v3(56.27,98.62) 56.27,98.43 55.52,97.69 43.23,97.69 43.21,97.71 42.9,97.71 v2(33.78,106.83) 28.38,112.23 28.38,112.54 17.35,123.57 v3(17.35,136.91) 17.35,143.18 9.65,150.88 v3(9.65,155.19)
V_VCC3P3_EN: length 12.1
  TOP w0.102: Q4201.4 30.84,189.69 31.42,190.27 33.4,190.27 v2(34.39,191.26) 34.77,190.88 35.77,190.88 35.8,190.91 35.97,190.91 37.17,192.11 C4209.1 37.67,192.13 37.76,192.04 C4210.1 38.72,192.04 38.99,191.77 39.78,191.77 40.17,192.16 R4204.2
V_VCC3P3_EN_R: length 4.6
  TOP w0.102: R4204.1 41.06,191.65 41.26,191.45 v2(41.59,191.45) 41.71,191.45 42.11,191.85 R4203.2 42.12,192.67 U4202.6
VCORE_VCC_SEN: length 45.8
  TOP w0.254: R802.1 28.33,64.74 26.64,64.74 v3(26.54,64.64) 26.54,64.39 26.5,64.35 PR4416.2 26.26,63.53 25.64,63.53 PR4418.1 ; v1(58.42,82.04) 58.41,82.04 58.01,82.44 CPU1.C38
  BOTTOM w0.254: v3(26.54,64.64) 26.64,64.74 29.31,64.74 31.83,67.26 ; v2(32.05,67.06) 31.83,67.26 ; 31.83,67.26 32.44,67.87 46.8,67.87 57.94,79.01 57.94,81.79 58.19,82.04 v1(58.42,82.04)
VCORE_VSS_SEN: length 48.2
  TOP w0.254: v1(58.48,83) 58.12,83.37 CPU1.D38 ; PC4409.2 PC4411.1 PR4420.1 26.45,66.53 PR4423.1 26.45,65.75 v3(26.54,65.66) 27.05,65.15 28.32,65.15 28.55,65.38 R802.2
  BOTTOM w0.254: v3(26.54,65.66) 27.05,65.15 29.14,65.15 29.82,65.83 ; 29.82,65.83 32.27,68.27 46.63,68.27 57.53,79.18 57.53,81.96 58.48,82.91 v1(58.48,83) ; 29.82,65.83 v2(29.64,66.01)
VCTRL_VCC_EN: length 383.7
  TOP w0.102: v3(45.59,173.74) 45.77,173.56 49.18,173.56 49.53,173.91 49.53,177.19 46.74,179.98 46.74,181.1 46.35,181.48 46.35,188.21 46.66,188.52 46.66,190.93 v2(47.52,191.8) 47.52,193.81 R4206.2 46.3,193.83 ; v3(160.16,15.39) 160.34,15.21 Q2407.G ; 46.3,193.83 46.16,193.97 U4202.3 ; 46.3,193.83 46.3,193.5 46.13,193.32 U4202.2
  BOTTOM w0.102: v3(160.16,15.39) 160.16,11.9 159.64,11.38 159.64,10.67 159.69,10.62 159.69,10.17 158.84,9.32 153.78,9.32 152.72,10.38 148.18,10.38 143.93,14.63 133.15,14.63 129.77,11.25 129.77,8.88 124.39,3.5 98.22,3.5 98.01,3.71 96.7,3.71 96.49,3.5 79.62,3.5 77.17,5.94 55.08,5.94 48.96,12.06 48.11,12.06 37.27,22.91 33.11,22.91 23.53,32.49 22.62,32.49 18.69,36.41 18.69,39.28 15.63,42.34 15.63,44.49 15.85,44.7 15.85,45.12 14.8,46.17 9.8,46.17 5.69,50.28 5.69,114.12 10.15,118.58 10.15,143.23 8.23,145.16 8.23,156.44 8.64,156.85 8.64,160.12 7.52,161.24 7.52,164.08 9.65,166.22 9.65,168.4 12.06,170.81 12.06,170.99 13.59,172.52 17.58,172.52 18.29,171.8 19.73,171.8 20.2,172.26 24.6,172.26 25,171.86 25.48,171.86 25.7,172.09 28.04,172.09 28.75,171.37 29.64,171.37 29.69,171.42 35.11,171.42 35.32,171.22 42.3,171.22 44.01,172.92 44.79,172.92 45.59,173.72 v3(45.59,173.74)
VGA1_DETECT: length 15.4
  TOP w0.102: SB1.P48 147.45,134.68 147.45,135.06 147.42,135.09 147.42,135.42 147.66,135.66 149.16,135.66 150.55,137.06 152.25,137.06 v2(152.91,137.72) 152.91,139 152.93,139.02 152.93,141.13 153.31,141.52 153.31,141.56 153.57,141.82 153.57,143.77 153.93,144.13 R1706.1 154.05,144.18 154,144.23 153.14,144.23 R1701.2
VGA_CABLE_DET_N: length 288.4
  TOP w0.102: EU5901.6 v3(38.2,8.64) ; SB1.Y48 150.43,135.13 150.39,135.17 150.39,135.46 150.53,135.59 150.72,135.59 150.73,135.59 151.6,135.59 152.01,136 152.34,136 152.59,136.25 152.67,136.33 153.98,136.33 155.32,137.68 155.32,138.42 155.74,138.84 155.8,138.91 156.17,139.32 156.29,139.45 156.29,139.8 v3(156.51,140.03) 156.36,140.18 156.36,142.84 156.37,142.84 156.37,143.41 156.36,143.42 156.36,143.45 155.93,143.88 155.93,145.85 156.65,146.57 R1502.1 ; v3(49.82,8.93) 49.91,9.02 v3(53.09,9.02) ; v3(148.34,26.43) 148.34,28.89 147.5,29.73 147.5,37.76 148.15,38.41 148.15,43.86 146.15,45.85 146.15,88.75 146.25,88.85 146.25,90.88 145.82,91.31 145.82,93.07 v3(145.67,93.22)
  BOTTOM w0.102: v3(145.67,93.22) 145.67,93.83 147.55,95.71 149.09,95.71 150,96.62 158.46,96.62 160.99,99.15 160.99,103.9 162.12,105.04 162.12,105.65 162.04,105.73 162.04,108.27 164.01,110.24 164.18,110.24 165.18,111.24 165.18,112.76 165.36,112.95 165.36,113.11 165.91,113.65 165.91,116.25 164.52,117.65 164.52,117.81 162.89,119.43 161.5,119.43 158.86,122.06 158.86,122.61 157.53,123.95 156.93,123.95 156.24,124.64 156.24,125.96 155.4,126.8 155.4,128.61 155.14,128.87 154.7,128.87 154.46,129.11 154.46,129.47 154.79,129.8 154.79,132.23 155.03,132.47 155.03,133.28 155.05,133.3 155.05,139.31 v2(155.38,139.64) 156.12,139.64 v3(156.51,140.03) ; VGA1.4 34.46,7.28 35.77,8.59 38.16,8.59 v3(38.2,8.64) 38.25,8.59 49.48,8.59 v3(49.82,8.93) ; v3(53.09,9.02) 55.63,6.48 77.4,6.48 79.84,4.03 96.27,4.03 96.48,4.24 98.23,4.24 98.44,4.03 122.21,4.03 124.28,6.1 125.33,6.1 126.75,7.51 126.75,9.58 128.12,10.95 128.12,16.23 129.61,17.73 137.03,17.73 141.42,22.12 143.65,22.12 147.96,26.43 v3(148.34,26.43)
VIDALERT#_CPU: length 37.1
  TOP w0.102: CPU1.E39 v1(56.64,83.83) ; R405.2 28.99,71.69 29.9,70.79 v3(31.6,70.79)
  BOTTOM w0.102: v1(56.64,83.83) 56.33,83.83 55.9,83.4 55.52,83.4 55.24,83.12 v2(55.24,81.92) 55.24,78.88 46.53,70.17 32.21,70.17 v3(31.6,70.79)
VIDALERT#_CPU_R: length 32.6
  TOP w0.102: R401.2 R405.1 28.11,71.69 27.53,71.12 27.53,70.46 29.44,68.55 29.84,68.55 32.72,65.68 32.72,63.67 v3(32.31,63.27) ; PR4406.2 20.32,66.5 20.32,64.79 20.35,64.76 20.35,63.09 v3(20.62,62.81) 19.64,61.83 PU4401.4
  BOTTOM w0.102: v3(20.62,62.81) v2(21.6,61.83) 22.02,61.42 29.05,61.42 30.4,62.76 31.8,62.76 v3(32.31,63.27)
VIDSCK_CPU: length 37.7
  TOP w0.102: CPU1.E38 v1(57.55,83.83) ; v3(32.36,69.72) 32.36,69.8 32,70.15 29.95,70.15 29.44,70.66 R407.2
  BOTTOM w0.102: v1(57.55,83.83) 57.04,83.32 56.47,83.32 56.11,82.96 56.11,80.87 v2(56.01,80.77) 56.01,79.13 46.6,69.72 v3(32.36,69.72)
VIDSCK_CPU_R: length 31.1
  TOP w0.102: R407.1 28.11,70.51 29.71,68.91 30.03,68.91 31.63,67.31 31.65,67.31 33.07,65.89 33.07,63.21 v3(32.27,62.41) ; PR4405.2 19.66,66.85 PR4411.2 19.62,66.08 19.18,65.63 19.18,64.38 19.08,64.27 19.08,63.73 18.77,63.43 18.77,62.38 v3(18.82,62.33)
  BOTTOM w0.102: v3(18.82,62.33) v2(19.72,61.43) 20.09,61.06 29.2,61.06 30.55,62.41 v3(32.27,62.41)
VIDSOUT_CPU: length 36.2
  TOP w0.102: CPU1.E40 v1(55.72,83.83) ; R408.2 30.4,72.82 v3(32.49,70.74)
  BOTTOM w0.102: v1(55.72,83.83) 55.45,83.83 54.66,83.04 v2(54.66,79.17) 54.66,78.8 46.52,70.66 32.56,70.66 v3(32.49,70.74)
VIDSOUT_CPU_R: length 33.4
  TOP w0.102: PR4404.2 22.28,67.45 21.27,66.45 21.18,66.45 20.79,66.05 PR4410.2 21.39,65.44 21.39,64.39 21.46,64.32 21.46,63.22 v3(21.69,62.99) ; v3(32.26,64.14) 32.26,65.35 29.41,68.2 29.21,68.2 27.38,70.03 26.37,70.03 24.89,71.5 v2(24.89,71.88) 24.89,72.44 25.73,73.28 26.45,73.28 R403.2 27.48,72.77 27.53,72.82 R408.1
  BOTTOM w0.102: v3(21.69,62.99) 21.77,62.99 22.91,61.85 28.98,61.85 30.35,63.22 31.34,63.22 v3(32.26,64.14)
VPP_EN: length 4
  TOP w0.102: PR5204.2 103.11,170.81 C4009.1 102.76,170.83 v3(102.31,171.27) 102.12,171.08 R4019.2
  BOTTOM w0.102: v3(102.31,171.27) v2(103.25,171.85)
VPP_EN_CR: length 6.8
  TOP w0.102: Q9102.C 98.41,174.82 98.84,174.82 98.86,174.83 99.3,174.83 R4017.2 99.31,174.37 99.44,174.24 v3(99.44,173.61) 99.44,173.46 100.23,172.67 100.63,172.67 101.33,171.97 R4019.1
  BOTTOM w0.102: v3(99.44,173.61) v2(98.81,172.82)
VPP_EN_DDR4: length 10.3
  TOP w0.102: R4018.2 94.37,176.58 94.82,176.58 95.02,176.38 Q9102.B 95.92,175.5 v3(97.88,173.54) 98.46,172.96 Q4002.3 97.81,172.61 97.67,172.47 97.67,171.82 97.16,171.31 Q4002.6
  BOTTOM w0.102: v3(97.88,173.54) v2(97.49,172.55)
VR_ENABLE: length 6.5
  TOP w0.102: R4006.2 95.85,28.4 R4005.2 95.85,29.68 95.28,30.25 94.26,30.25 v2(93.95,30.56) 94.23,30.84 95.48,30.84 95.95,30.37 R4007.1
VR_ENABLE_IMVP: length 179.7
  TOP w0.102: R4007.2 97.4,30.35 98.65,29.1 98.65,28.55 99.15,28.05 U4002.6 99.64,27.12 99.19,26.66 98.81,26.66 98.74,26.72 97.54,26.72 97.28,26.46 97.28,25.98 97.84,25.41 97.84,20.49 97.76,20.4 97.76,18.84 97.86,18.73 97.86,7.83 96.24,6.21 96.24,4.65 v3(96.14,4.55) ; v3(30.71,59.35) 30.71,59.46 29.78,60.39 29.78,62.93 29.64,63.07 29.47,63.07 v3(29.45,63.05) ; v1(21.89,64.37) 21.89,64.34 22.26,63.97 22.26,62.85 21.49,62.08 20.89,62.08 20.67,61.85 20.67,61.85 20.56,61.75 20.56,61.74 20.44,61.62 PU4401.2 ; v3(16.66,44.33) 16.83,44.33 16.89,44.4 25.78,44.4 v3(26.23,43.95)
  BOTTOM w0.102: v3(29.45,63.05) 28.88,63.05 28.83,63.1 28.45,63.1 28.45,63.09 v2(27.3,63.09) 26.49,63.09 25.22,64.37 v1(21.89,64.37) ; v3(16.66,44.33) 17.12,43.88 17.12,43.73 17.53,43.32 17.53,41.31 19.3,39.53 19.3,36.66 22.87,33.1 23.78,33.1 32.62,24.26 36.78,24.26 43.21,17.83 43.34,17.83 43.42,17.91 44.88,17.91 56.01,6.78 76.53,6.78 77.52,6.78 79.97,4.34 95.14,4.34 95.35,4.55 v3(96.14,4.55) ; v3(30.71,59.35) 30.71,58.98 29.92,58.19 24.77,58.19 23.19,56.61 23.19,46.25 23.67,45.77 24.41,45.77 v3(26.23,43.95)
VR_READY: length 85.9
  TOP w0.102: Q2405.1 160.11,46.26 159.44,46.94 158.62,46.94 158.24,47.32 158.24,52.7 v3(157.35,53.59) ; v3(145.33,46.19) 145.33,53.91 v3(145.29,53.95) ; v3(123.72,34.57) 123.11,33.96 118.75,33.96 118.1,34.61 116.71,34.61 116.64,34.53 R4015.1 114.79,34.53 114.58,34.75 103.26,34.75 R4013.2
  BOTTOM w0.102: v3(145.33,46.19) 143.3,46.19 142.78,46.72 139.16,46.72 134.26,41.82 134.26,39.94 129.79,35.46 v2(125.4,35.46) 124.61,35.46 v3(123.72,34.57) ; v3(145.29,53.95) 157,53.95 v3(157.35,53.59)
VR_READY_A: length 3.3
  TOP w0.102: U4009.1 114.06,32.88 114.73,32.21 v2(114.86,32.21) 115.66,32.21 R4011.2
VR_READY_B: length 3
  TOP w0.102: R4015.2 115.89,33.46 v2(115.08,33.46) 114.52,33.46 114.45,33.53 U4009.2
VR_READY_IMVP: length 181.9
  TOP w0.102: v3(19.53,64.08) 19.53,63.68 19.13,63.28 19.13,62.81 19.28,62.66 19.28,62.14 19.01,61.87 18.99,61.87 18.84,61.73 PU4401.6 ; v3(29.91,59.03) 29.91,59.12 29.9,59.13 29.9,59.72 29.43,60.19 29.43,62.01 28.8,62.64 v3(28.64,62.64) ; R4013.1 102.3,32.77 R4003.2 104.27,31.81 U4003.D 104.27,28.45 103,27.18 102.7,27.18 99.16,23.64 99.16,21.31 98.11,20.26 98.11,18.98 98.21,18.88 98.21,7.68 96.99,6.45 96.99,5.22 96.85,5.08 v3(96.85,5.04) ; v3(17.58,43.92) 25.62,43.92 26.4,43.13 v3(26.52,43.13)
  BOTTOM w0.102: v3(29.91,59.03) 29.91,58.99 29.46,58.55 24.62,58.55 22.83,56.76 22.83,46.1 23.67,45.26 24.08,45.26 26.21,43.13 v3(26.52,43.13) ; v3(17.58,43.92) 17.78,43.92 18.57,43.13 18.57,41.32 18.59,41.3 18.59,40.86 19.66,39.79 19.66,36.81 23.02,33.45 23.93,33.45 32.77,24.61 36.93,24.61 43.28,18.27 45.02,18.27 56.15,7.14 76.38,7.14 76.39,7.14 77.7,7.14 80.15,4.69 95,4.69 95.35,5.04 v3(96.85,5.04) ; v3(28.64,62.64) 28.65,62.63 28.65,62.33 28.55,62.23 23.8,62.23 v2(23.11,62.92) 22.12,63.91 19.71,63.91 v3(19.53,64.08)
VTT_EN: length 22.7
  TOP w0.102: v3(42.8,172.47) 42.48,172.79 42.48,172.94 41.62,173.8 R5001.2 ; R4025.2 24.26,170.75 C4013.1 24.72,171.89 25.04,172.22 25.09,172.22 v3(25.19,172.32)
  BOTTOM w0.102: v3(42.8,172.47) 42.45,172.47 v2(41.96,171.98) 41.51,171.53 35.44,171.53 35.24,171.73 30.91,171.73 29.57,171.73 29.52,171.68 28.88,171.68 28.09,172.47 26.44,172.47 25.35,172.47 v3(25.19,172.32)
W_DISABLE#1: length 5.6
  TOP w0.102: R6311.2 44.49,226.73 v2(44.02,226.26) 43.45,225.7 43.45,223.89 42.98,223.42 NGFF1.56
W_DISABLE#2: length 6.8
  TOP w0.102: R6312.2 45.77,226.25 44.92,226.25 44.09,225.43 v2(44.09,224.87) 44.09,223.85 43.16,222.92 NGFF1.54
WAKE_M2_SSD_N: length 191
  TOP w0.102: R6203.2 133.22,3.73 133.32,3.63 135.36,3.63 136.22,2.77 148.68,2.77 154.15,8.24 154.15,10.74 153.95,10.94 153.95,11.44 153.96,11.46 153.96,22.29 152.04,24.21 152.04,29.71 150.7,31.05 150.7,32.57 151.07,32.94 151.07,42.22 152.26,43.4 152.26,45.46 151.31,46.41 150.77,46.41 149.72,47.46 149.72,68.44 150.15,68.87 150.15,92.71 149.06,93.8 149.06,94.16 148.5,94.72 v3(147.85,94.72) ; v1(156.28,131.56) 156.24,131.61 156.24,131.61 155.84,132.01 155.84,132.4 155.89,132.46 155.89,133.17 155.82,133.24 155.82,133.72 155.69,133.85 SB1.AL47 155.69,134.24 155.46,134.47 155.46,135.95 156.29,136.78 157.36,136.78 158.7,138.11 158.7,139.35 160.99,141.64 160.99,144.27 161.04,144.32 161.04,145.32 160.37,145.99 R1503.1
  BOTTOM w0.102: v1(156.28,131.56) 156.12,131.56 155.61,131.05 155.61,129.95 155.68,129.88 155.68,129.34 156.01,129.01 156.01,128.55 157.05,127.5 v2(157.05,126.51) 156.94,126.4 156.94,124.8 157.18,124.56 157.92,124.56 158.15,124.32 158.95,124.32 159.53,123.74 159.53,122.26 160.86,120.93 162.26,120.93 165.13,118.06 165.13,117.98 166.57,116.53 166.57,114.11 166.61,114.07 166.61,112.51 165.79,111.68 165.79,110.99 164.43,109.63 164.3,109.63 162.72,108.06 162.72,106.02 162.81,105.93 162.81,104.75 161.67,103.61 161.67,98.86 158.74,95.94 150.29,95.94 149.07,94.72 v3(147.85,94.72)
WLAN_PEDET: length 227.3
  TOP w0.102: v1(158.2,132.3) 157.93,132.03 157.79,132.03 SB1.AR42 ; R1709.2 53.43,220.51 53.26,220.34 v3(53.26,220.22) ; v3(157.89,182.82) 156.41,182.82 155.75,182.51 155.7,182.48 155.11,182.2 154.16,181.25 119.52,181.25 117.84,181.74 117.05,181.91 99.93,181.91 97.59,181.28 84.04,181.28 82.43,181.91 82.1,181.91 81.89,182.13 81.25,182.38 80.88,182.53 80.88,182.53 80.86,182.54 80.82,182.58 80.77,182.6 80.73,182.61 80.68,182.64 80.54,182.7 80.45,182.74 80.34,182.78 80.27,182.81 80.18,182.85 80.16,182.86 79.74,183.04 79.72,183.06 77.07,184.12 77.03,184.13 76.84,184.13 76.84,184.14 73.94,184.43 67.84,184.43 55.04,197.23 55.04,201.31 54.1,202.25 54.1,204.09 54.06,204.17 53.93,204.42 53.83,204.62 53.82,204.62 47.87,215.12 47.87,220.62 47.55,220.94 v3(47.55,221.09) ; NGFF1.51 36.35,222.17 36.58,221.95 v3(36.6,221.95)
  BOTTOM w0.102: v3(53.26,220.22) 52.39,221.09 v3(47.55,221.09) 46.59,221.09 43.71,223.97 v2(43.71,225.6) 43.71,226.61 40.22,230.1 39.24,230.1 38.87,229.73 36.95,229.73 35.05,227.83 35.05,222.06 R9938.1 36.46,221.81 v3(36.6,221.95) ; v3(157.89,182.82) 158.43,182.82 158.9,182.36 158.9,182.15 159.87,181.19 159.87,179.7 161.09,178.49 161.09,175.76 161.54,175.3 161.54,168.88 161.56,168.87 161.73,167.97 161.85,167.28 162.71,166.42 162.71,165.26 163.6,164.37 163.6,155.84 163.88,155.56 163.88,154.99 162.95,154.06 162.95,150.73 162.23,150.01 162.23,143.92 159.74,141.43 159.74,139.92 158.8,138.98 158.8,136.85 158.88,136.77 158.88,135.29 158.27,134.68 158.27,132.37 v1(158.2,132.3)
WLAN_USB_DET: length 215.9
  TOP w0.102: v3(158.45,182.17) 158.33,182.28 155.81,182.28 155.26,182.02 154.27,181.03 119.42,181.03 117.34,181.61 117.03,181.69 100.06,181.69 97.87,181.05 83.99,181.05 83.56,181.22 82.39,181.69 82.01,181.69 81.76,181.93 81.17,182.17 81.16,182.17 81.14,182.18 81.11,182.19 80.72,182.35 80.72,182.35 80.69,182.36 80.28,182.54 80.25,182.56 80.24,182.57 80.09,182.63 80.09,182.63 80.04,182.66 79.61,182.84 79.59,182.87 77.02,183.89 76.87,183.9 76.75,183.9 76.74,183.92 73.88,184.2 67.75,184.2 54.81,197.13 54.81,201.21 53.87,202.15 53.87,204.04 53.67,204.43 51.08,208.99 v3(50.62,209.12) ; SB1.AP48 157.16,134.67 157.16,135.93 159.21,137.97 159.21,139.21 161.45,141.45 161.45,143.79 v1(161.8,144.15) 161.8,145.15 R1901.1 ; NGFF1.1 34.47,209.65 37.59,209.65 v3(37.72,209.78) 37.84,209.78 39.07,211 39.07,212.54 39.14,212.61 39.14,213 39.13,213.01 39.13,213.09 38.87,213.36 38.79,213.36 37.9,214.25 37.9,219.32 38.07,219.5 38.07,225.65 38.81,226.39 v3(38.81,227.13)
  BOTTOM w0.102: v3(38.81,227.13) 39.08,227.39 v2(39.8,227.39) R9939.1 ; v3(50.62,209.12) 50.19,208.69 47.53,208.69 46.44,209.77 40.21,209.77 40.08,209.86 38.91,209.86 38.83,209.78 v3(37.72,209.78) ; v1(161.8,144.15) 161.8,150.26 162.47,150.93 162.47,154.26 162.93,154.73 162.93,162.44 161.96,163.41 161.96,166.08 161.16,166.88 161.13,167.02 160.91,168.25 160.91,168.27 160.87,168.46 160.87,175.11 160.48,175.5 160.48,178.23 158.88,179.83 158.88,181.74 v3(158.45,182.17)
XCLK_RBIAS: length 4.7
  TOP w0.102: SB1.T3 148,112.49 148,112.04 148.08,111.96 148.08,109.58 v2(148.27,109.39) 148.79,108.86 148.79,108.55 R1802.2
XDP_PCUDEBUG_3: length 1.1
  TOP w0.102: R423.2 122.52,55.32 R9904.2
XDP_PWR_DEBUG: length 5.6
  TOP w0.102: v3(125.4,56.9) 125.32,56.81 125.32,56.74 124.97,56.39 R9913.2 ; v3(128.23,55.75) 128.43,55.94 R9912.2
  BOTTOM w0.102: v3(128.23,55.75) 127.79,55.75 v2(127.18,56.36) 126.64,56.9 v3(125.4,56.9)
XDP_PWRGD: length 3.4
  TOP w0.102: R9907.2 125.4,55.24 v2(125.57,55.08) 125.94,55.08 126.24,55.37 R9908.2 R9906.2
XDP_VR_READY: length 12.3
  TOP w0.102: R9923.2 180.14,164.4 v3(180.14,164.95) 180.14,164.96 180.52,165.34 180.52,166.33 R9905.2 180.56,168.15 C9901.1 180.31,168.22 178.59,169.95 178.59,170.98 178.56,171.01 178.56,171.75 178.3,172.02 177.66,172.02 R9903.2
  BOTTOM w0.102: v3(180.14,164.95) v2(180.19,163.98)
XTAL_24M_PCH_IN: length 17.2
  TOP w0.102: 147.7,105.69 C1802.1 ; 147.7,105.69 147.7,106.67 R1812.1 147.7,106.69 147.7,107.34 v3(147.88,107.52) ; 147.7,105.69 147.7,105.31 147.08,104.69 147.08,103.45 147.26,103.27 147.26,102.52 147.89,101.89 X1801.3 ; v1(149.62,115.85) 149.51,115.85 SB1.U10
  BOTTOM w0.102: v1(149.62,115.85) 150.62,114.84 150.62,112.62 150.09,112.09 150.09,110.29 v2(149.61,109.8) 149.45,109.64 149.45,109.09 v3(147.88,107.52)
XTAL_24M_PCH_OUT: length 13.8
  TOP w0.102: v3(146.99,107.54) 146.99,107.24 146.83,107.08 R1812.2 146.83,105.84 C1801.1 146.68,105.15 146.24,104.71 X1801.1 ; v1(149.36,115.26) 149.04,115.59 SB1.U9
  BOTTOM w0.102: v1(149.36,115.26) 149.97,114.66 149.97,112.8 149.56,112.39 149.56,110.86 148.4,109.71 v2(148.4,109.25) 148.4,108.95 v3(146.99,107.54)

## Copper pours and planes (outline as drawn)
1V_CPU_CORE on TOP: 65.91,104.65 65.53,105.03 65.53,105.92 66.04,106.43 69.98,106.43 70.11,106.29 70.11,105.42 69.34,104.65
1V_CPU_CORE on TOP: outline of 142 points within 33.27,45.47 101.88,107.44 ; 2 cut-outs
1V_CPU_CORE on BOTTOM: 59.03,50.65 57.66,52.02 57.66,53.21 52.1,58.78 49.05,58.78 49.02,58.8 45.21,58.8 44.58,59.44 44.58,63.88 59.05,78.36 59.05,81.28 59.82,82.04 59.82,83.95 59.18,84.58 59.18,84.96 59.94,85.72 59.94,87.5 64.26,91.82 67.69,91.82 68.33,92.46 68.33,95.76 68.71,96.14 69.98,96.14 70.23,96.39 70.23,97.41 70.1,97.54 69.22,97.54 68.83,97.92 68.83,101.09 68.2,101.73 66.42,101.73 65.53,102.62 65.53,105.92 65.66,106.05 81.41,106.05 81.79,105.66 81.79,104.9 81.28,104.39 81.28,92.33 83.21,90.4 83.21,87.73 82.45,86.97 82.42,87 75.18,87 74.8,86.61 74.8,85.47 74.04,84.71 74.04,82.93 75.87,81.1 75.87,77.57 87.66,65.79 97.66,65.79 98.09,65.35 98.09,60.66 100.46,58.29 100.46,54.38 100.03,53.95 96.29,53.95 90.7,59.54 83.72,59.54 82.32,58.14 82.32,55.6 81.31,54.58 77.88,54.58 70.89,61.57 65.18,61.57 62.89,59.28 62.89,50.9 62.64,50.65
1V_CPU_CORE on BOTTOM: 41.94,45.87 41.71,46.1 40.26,46.1 39.9,46.46 39.9,49.94 41.63,51.66 45.62,51.66 45.75,51.54 45.75,47.22 44.4,45.87
1V_CPU_GT on TOP: 28.93,73.41 27.78,74.55 27.78,81.66 24.79,84.66 22.17,84.66 21.31,85.52 21.31,94.69 21.93,95.31 21.93,102.45 22.23,102.74 26.16,102.74 26.54,103.12 26.54,105.16 27.61,106.22 33.07,106.22 42.51,96.78 52.55,96.78 54.95,99.18 60.67,99.18 62.02,100.54 62.25,100.54 62.43,100.36 62.73,100.36 63.67,101.3 63.7,101.3 65.76,103.35 66.88,103.35 67.01,103.23 67.01,99.69 65.79,99.69 65.63,99.54 65.63,97.87 65.76,97.74 71.47,97.74 71.6,97.61 71.6,96.09 71.47,95.96 65.76,95.96 65.63,95.84 65.63,94.44 65.88,94.19 69.31,94.19 69.6,93.9 69.6,92.58 69.42,92.41 65.88,92.41 65,91.52 64.36,91.52 64.35,91.53 63.71,91.53 60.06,87.88 60.06,85.74 59.86,85.55 55.83,85.55 53.59,83.31 47.77,83.31 45.95,81.49 45.95,76.53 42.82,73.41 ; 3 cut-outs
1V_CPU_GT on BOTTOM: 29.05,73.28 27.78,74.55 27.78,81.66 26.39,83.06 24.38,83.06 22.48,84.96 22.48,85.72 20.76,87.44 20.76,92.77 22.35,94.36 22.35,100.33 26.29,104.27 33.78,104.27 41.2,96.85 42.98,96.85 43.31,96.52 44.83,96.52 44.83,96.52 54.43,96.52 55.97,98.05 55.97,98.19 56.72,98.95 59.72,98.95 61.31,100.54 63.85,100.54 64.87,101.55 68.3,101.55 68.74,101.11 68.74,97.81 69.06,97.49 69.95,97.49 70.08,97.36 70.08,96.34 69.95,96.22 68.55,96.22 68.17,95.84 68.17,92.79 67.66,92.28 64.52,92.28 61.7,89.46 61.63,89.44 61.57,89.48 60.92,89.59 61.03,88.94 61.07,88.88 61.05,88.81 60.5,88.26 60.5,88.22 59.89,87.61 59.89,86.54 59.56,86.21 55.22,86.21 52.32,83.31 47.77,83.31 45.95,81.49 45.95,76.53 42.69,73.28
1V_PCH_SB on TOP: 140.85,110.43 140.56,110.72 140.56,111.35 140.75,111.54 140.94,111.54 141.26,111.86 141.26,112.87 141.39,113 141.51,113 142.47,112.04 142.47,111.16 141.74,110.43
1V_PCH_SB on TOP: 183.16,147.55 183.01,147.7 183.01,155.98 183.62,156.59 186.61,156.59 187.02,156.18 187.02,152.7 187.5,152.22 187.5,147.96 187.32,147.78 185.42,147.78 185.19,147.55 ; 4 cut-outs
1V_PCH_SB on TOP: 149.22,119.76 148.97,120.02 148.97,120.73 149.4,121.16 149.4,122.05 149,122.45 149,122.81 149.03,122.84 149.03,123.04 149,123.04 148.31,123.72 148.31,125.98 149.4,127.08 150.01,127.08 150.33,126.76 150.33,126.45 150.5,126.29 151.69,126.29 151.84,126.44 151.84,126.77 151.94,126.87 154.03,126.87 154.08,126.82 154.08,126.62 153.49,126.03 153.49,125.53 153.34,125.37 152.93,125.37 152.78,125.22 152.78,124.82 153.44,124.16 153.44,122.28 153.35,122.19 152.92,122.19 152.78,122.05 152.58,122.05 152.4,122.22 152.2,122.22 152.04,122.07 152.04,121.67 152.46,121.26 152.46,120.98 152,120.52 151.79,120.52 151.79,120.52 151.16,121.16 150.72,121.16 150.47,120.9 150.47,120.4 149.83,119.76
1V_PCH_SB on TOP: 148.39,138.02 148.26,138.15 148.26,139.12 147.99,139.38 147.99,139.4 147.84,139.55 147.84,142.99 147.98,143.13 148.59,143.13 149.86,141.86 149.86,140.59 149.4,140.13 149.4,138.13 149.3,138.02 ; 5 cut-outs
1V_PCH_SB on BOTTOM: 185.42,147.19 184.15,148.46 184.15,153.27 185.53,154.65 185.53,156.93 185.9,157.3 187.38,157.3 187.5,157.18 187.5,155 187.71,154.79 187.71,147.19
1V_PCH_SB on L2VCC: 150.99,111.19 150.56,112.06 150.56,116.51 150.7,116.65 151.81,116.65 152.21,116.25 152.21,111.46 151.94,111.19
1V_PCH_SB on L2VCC: 149.37,119.82 149.29,119.93 149.29,120.95 150.3,121.97 150.3,122.63 149.94,123 148.39,123 148.15,123.16 148.15,144.07 150.43,146.35 150.43,147.62 159.19,156.39 159.19,156.5 159.58,156.78 167.56,156.78 168.2,156.15 172.04,156.15 172.67,156.78 185.98,156.78 187.13,155.62 187.13,143.94 187.12,143.92 187.13,143.87 187.13,143.01 187.13,142.94 187.13,142.94 187.13,142.19 186.74,141.8 176.96,141.8 176.21,141.05 176.21,134.32 169.48,127.59 169.48,126.06 169.21,125.79 168.12,125.79 167.47,125.07 167.47,123.6 167.05,123.2 157.53,123.18 157.45,123.18 157.04,122.76 157.04,121.76 157.03,121.75 157.04,121.68 157.04,121.36 156.26,120.59 150.67,120.59 150.46,120.38 149.88,119.82 ; 1 cut-out
1V_VCCAMPHYPLL on TOP: 141.83,135.03 141.6,135.25 141.6,136.84 143,138.23 143,138.72 143.09,138.81 144.27,138.81 144.58,139.12 147.8,139.12 147.96,138.96 147.96,138.18 147.7,137.92 145.92,137.92 143.03,135.03 ; 7 cut-outs
5V_DDC_HDMI on TOP: 66.73,24.43 65.89,25.27 65.89,28.17 66.04,28.32 67.03,28.32 68.3,27.05 68.3,25.88 69.01,25.17 69.01,24.51 68.94,24.43 ; 2 cut-outs
5V_DISPLAY_S0 on TOP: 46.35,22.1 46.13,22.33 46.13,23.83 46.89,24.59 46.89,26.95 47.12,27.18 48.26,27.18 48.64,26.8 48.64,23.85 47.65,22.86 47.65,22.38 47.37,22.1
5V_S0 on TOP: 92.46,192.41 92.33,192.53 92.33,198.12 93.09,198.88 95,198.88 95.5,198.37 95.5,192.79 95.12,192.41
5V_S0 on TOP: 62.53,25.1 61.98,25.65 61.98,28.24 62.13,28.4 64.59,28.4 65.43,27.56 65.43,25.17 65.35,25.1
5V_S0 on TOP: 5.46,193.55 3.61,195.4 3.61,211.25 4.03,211.67 10.63,211.67 10.64,211.68 10.69,211.68 11.35,212.34 11.35,216 9.83,217.53 7.85,217.53 7.59,217.78 7.59,218.49 7.77,218.67 10.29,218.67 10.82,219.2 10.82,220.34 11.18,220.7 13.21,220.7 13.84,220.07 13.84,212.34 11.94,210.44 9.96,210.44 9.55,210.03 5.89,210.03 5.59,209.73 5.59,197.35 8.05,194.88 8.05,194.11 7.49,193.55
5V_S0 on TOP: 4.45,133.6 2.03,136.02 2.03,169.16 3.94,171.07 3.94,173.1 4.45,173.61 5.08,173.61 5.84,172.85 5.84,170.81 3.17,168.15 3.17,137.79 5.71,135.25 5.71,133.86 5.46,133.6
5V_S0 on BOTTOM: 92.58,195.2 92.46,195.33 92.46,197.87 93.34,198.75 95,198.75 95.5,198.25 95.5,195.45 95.25,195.2
5V_S0 on L2VCC: 35.81,23.94 31.02,23.95 31.01,23.95 24.87,23.96 23.36,23.96 23.11,23.95 17.79,29.22 17.46,29.54 17.46,30.02 19.24,31.8 19.24,32.84 4.13,47.96 4.13,135.28 4.53,135.57 5.29,135.57 5.65,135.39 5.65,133.3 5.35,133 5.32,132.99 5.3,132.95 4.64,132.29 4.64,48.69 20.64,32.69 20.64,31.83 19.24,30.43 19.24,29.13 23.8,24.57 42.85,24.57 42.99,24.43 42.99,24.34 42.59,23.94
5V_S0 on L2VCC: 5.41,170.37 5.02,170.77 5.02,172.51 5.82,173.32 7.4,173.43 8.57,174.62 10.27,176.29 15.02,181.02 15.04,181.27 15.05,181.28 15.05,181.35 15.06,181.42 15.05,181.42 15.05,188.17 9.6,193.61 6.94,193.61 5.78,194.79 5.78,196.09 5.78,196.48 5.79,196.48 6.1,196.79 6.58,196.79 8.63,194.73 9.73,194.73 14.75,189.71 14.75,189.7 14.8,189.65 14.86,189.6 14.86,189.6 15.46,189.05 15.48,189.06 15.74,188.83 15.74,188.82 15.78,188.78 15.81,188.73 15.83,188.73 15.85,188.71 15.86,188.71 15.94,188.64 15.94,183.02 15.93,182.95 15.94,182.94 15.94,180.55 14.25,178.86 14.22,178.84 14.19,178.8 12.34,176.95 12.3,176.93 12.29,176.89 12.07,176.68 12.02,176.64 12.02,176.62 5.76,170.37
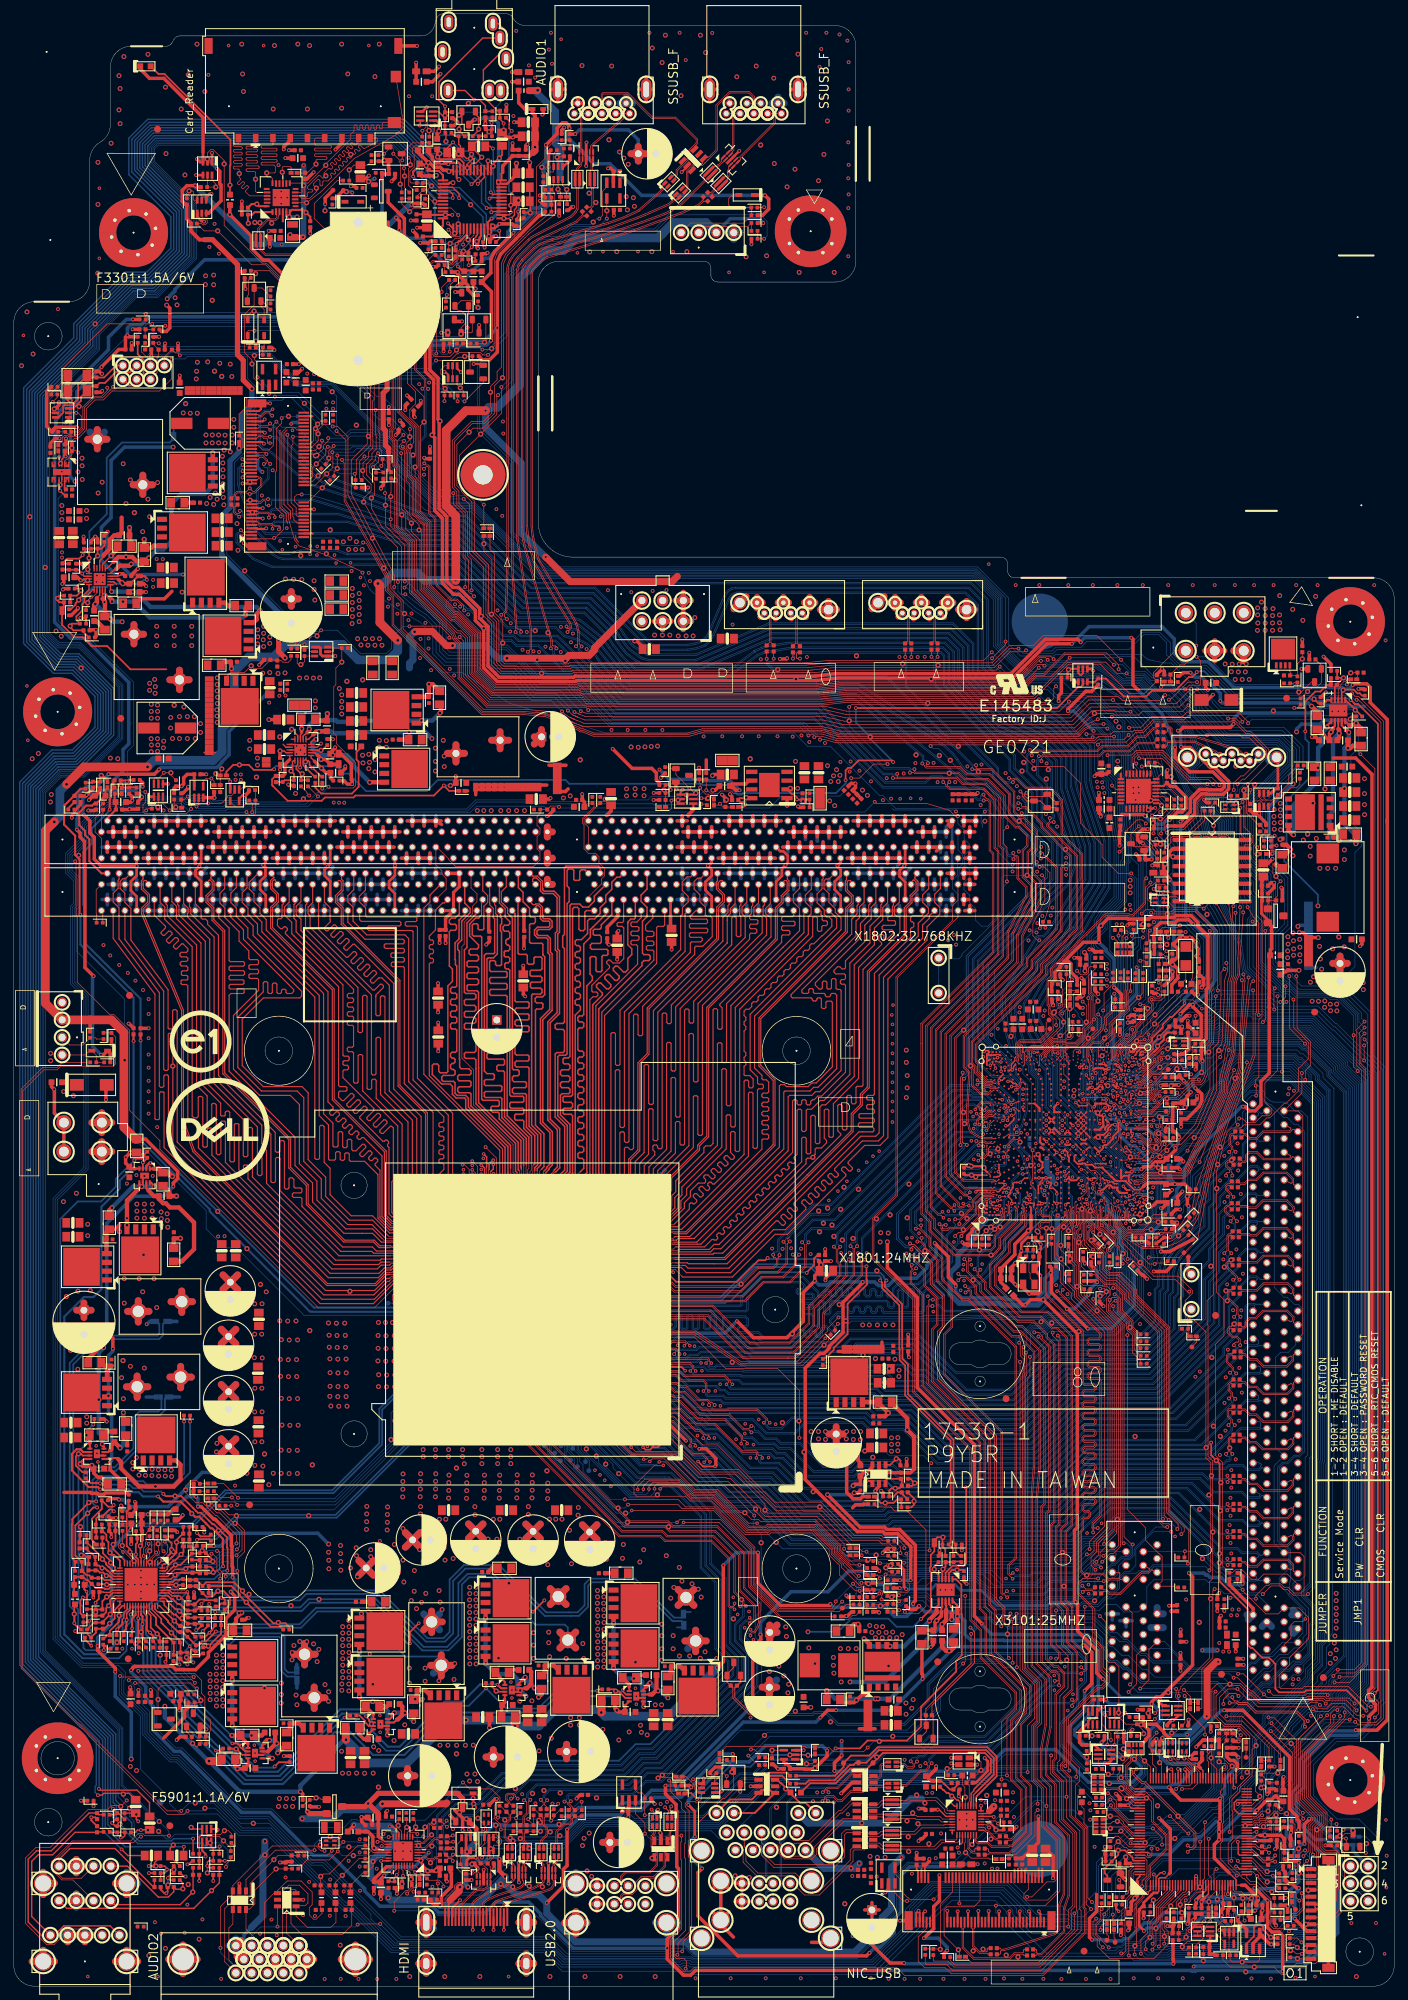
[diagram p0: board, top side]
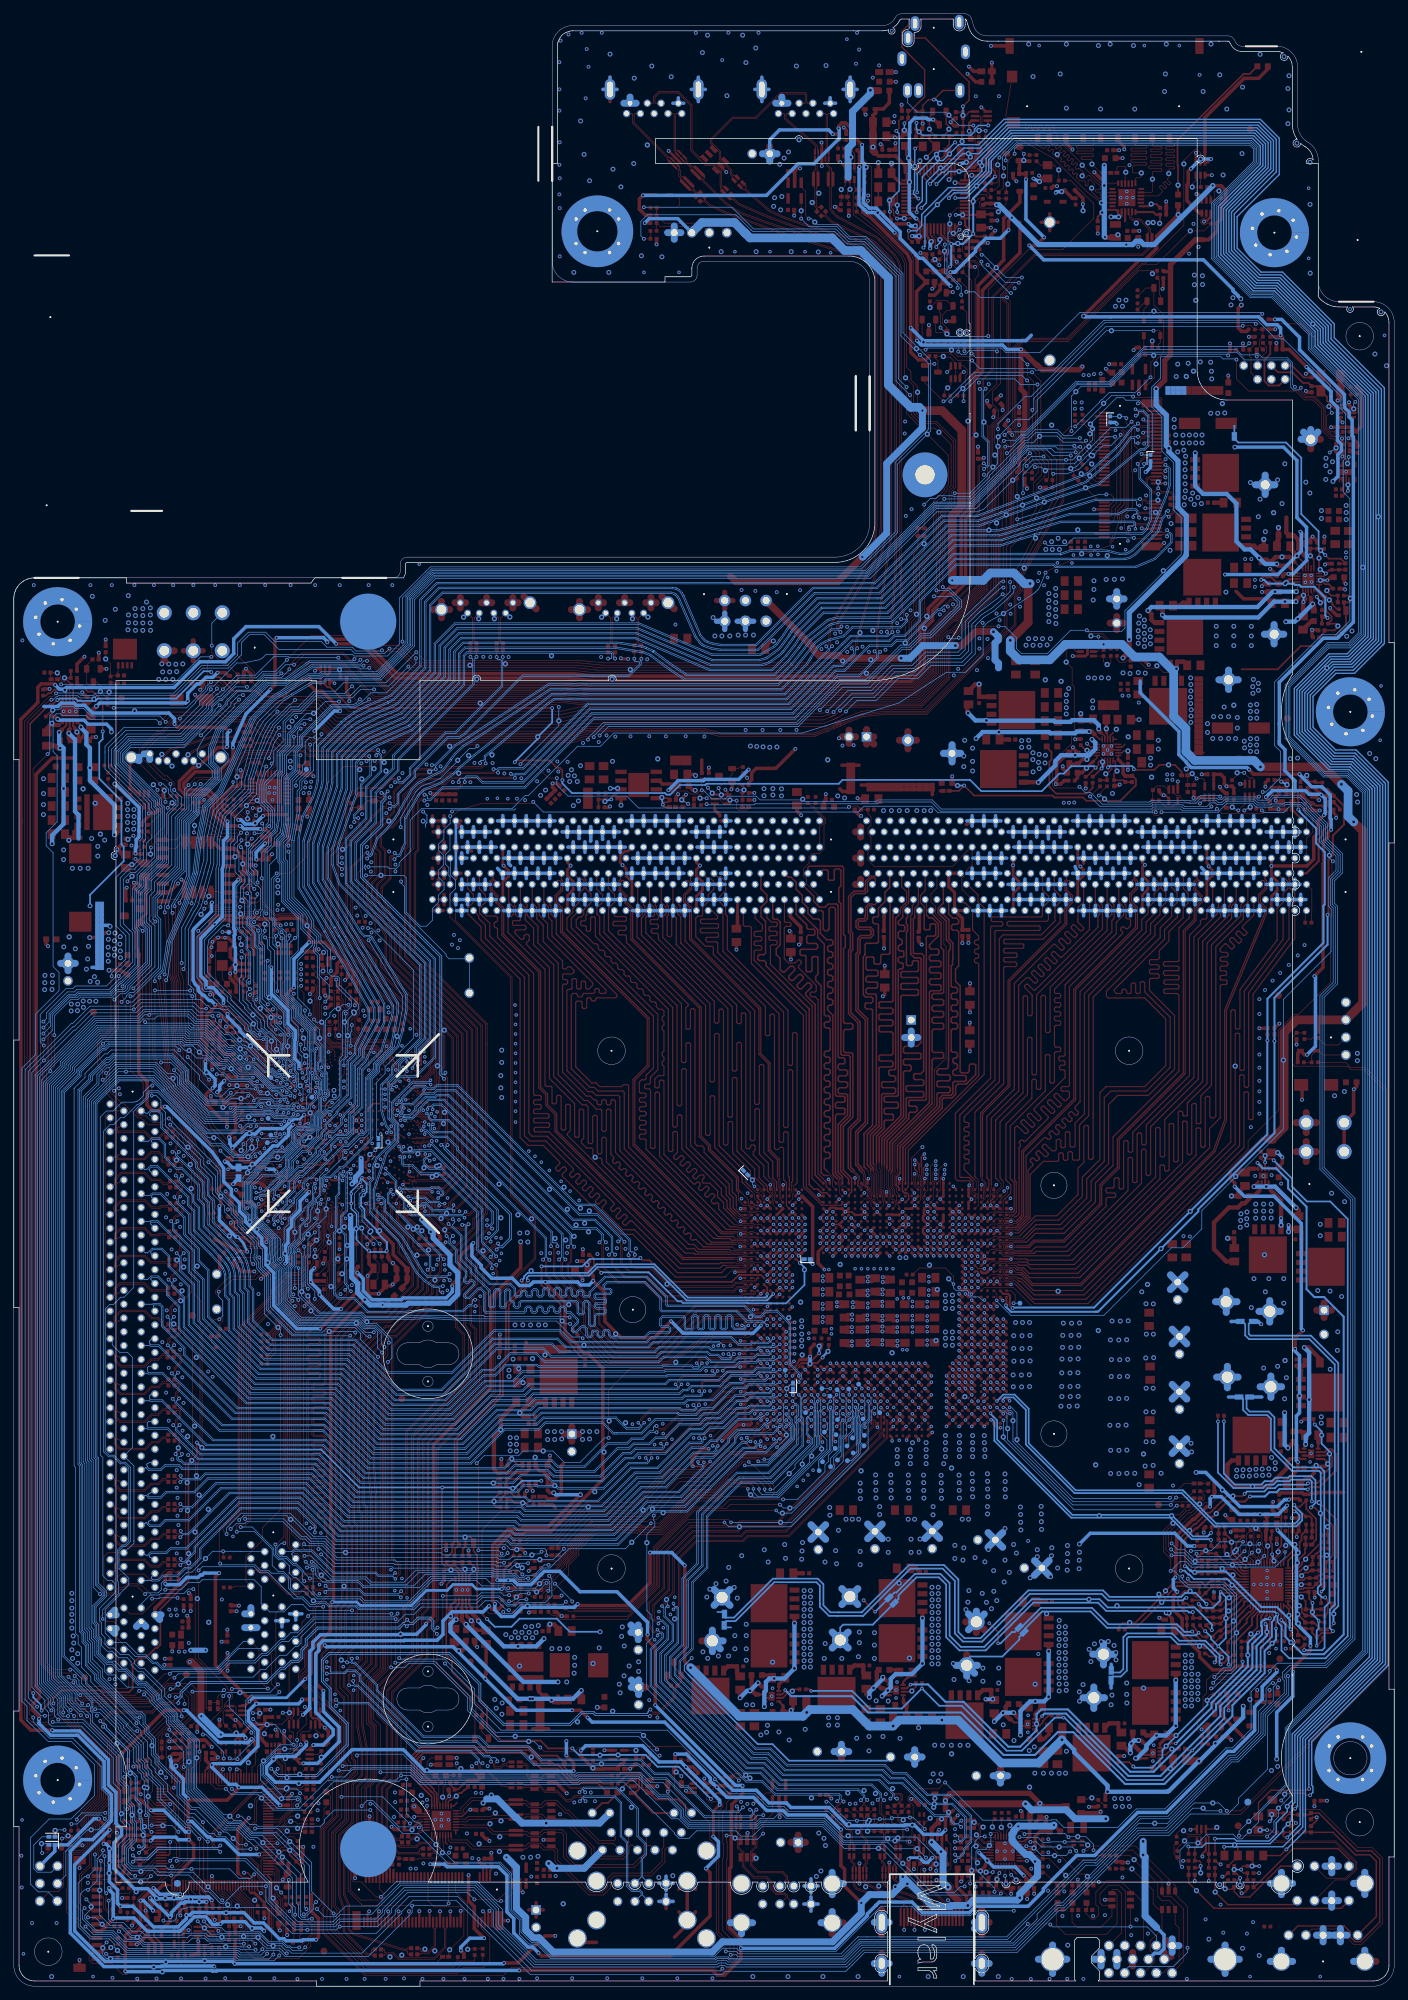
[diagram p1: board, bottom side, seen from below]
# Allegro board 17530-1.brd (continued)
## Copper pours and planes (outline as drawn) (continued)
5V_S0 on L2VCC: 72.34,190.82 65.72,197.44 65.72,197.79 66.48,198.55 66.48,199.72 61.68,204.6 61.68,220.4 53.76,228.32 53.75,228.35 53.71,228.38 52.99,229.09 52.98,229.13 52.94,229.14 51.77,230.31 45.09,230.31 44.1,231.31 36.22,231.31 33.68,228.76 18.18,228.74 14.62,225.15 14.67,216.92 14.67,215.98 14.27,215.58 8.37,215.58 8.19,215.94 8.19,218.36 8.64,218.81 10.42,218.81 10.99,219.38 10.99,225.16 10.6,226.1 10.6,227.89 13.62,230.9 31.8,230.9 33.71,232.8 53.72,232.8 63.61,222.96 63.59,207.59 69.53,201.65 69.53,197.15 74.09,192.6 83.39,192.6 89.87,199.07 94.79,199.07 95.57,198.3 95.57,192.32 90.42,192.34 88.57,192.34 87.04,190.82
5V_S5 on TOP: 87.63,256.92 87.38,257.18 87.38,259.71 87.5,259.84 89.79,259.84 90.3,259.33 90.3,257.3 89.92,256.92 ; 1 cut-out
5V_S5 on TOP: 125.43,16.36 125.25,16.54 125.25,17.25 124.92,17.58 123.93,17.58 123.57,17.93 123.57,19.05 123.72,19.2 126.54,19.2 126.9,18.85 126.9,16.56 126.7,16.36 ; 2 cut-outs
5V_S5 on TOP: 24.87,231.3 24.79,231.38 24.79,248.13 25.58,248.92 32.08,248.92 32.97,248.03 32.97,244.14 32.44,243.61 32.44,234.72 33.3,233.86 33.3,231.42 33.18,231.3
5V_S5 on TOP: 2.16,177.16 1.91,177.42 1.91,178.31 2.54,178.94 14.48,178.94 15.37,178.05 15.37,177.8 14.73,177.16
5V_S5 on TOP: 8.94,219 8.66,219.28 8.66,219.99 8.56,220.09 7.65,220.09 7.65,220.83 8.26,221.44 8.33,221.44 8.61,221.72 8.79,221.72 9.3,222.22 10.19,222.22 10.39,222.02 10.39,219.25 10.13,219
5V_S5 on TOP: 81.08,19.71 80.8,19.99 80.8,22.15 82.89,24.24 82.89,28.18 82.68,28.4 68,28.4 67.31,29.08 65.91,29.08 65.3,29.69 65.3,31.09 65.96,31.75 67.69,31.75 68.33,31.11 88.18,31.11 88.49,30.8 88.49,28.42 88.47,28.4 86.08,28.4 85.78,28.09 85.78,23.8 85.76,23.79 85.76,23 82.47,19.71 ; 2 cut-outs
5V_S5 on BOTTOM: 54.94,239.83 48.64,246.13 27.61,246.13 27.23,246.51 27.23,247.9 29.01,249.68 50.04,249.68 56.71,243.01 61.91,243.01 65.91,247.01 66.04,247.01 75.06,256.03 76.2,256.03 77.98,257.81 77.98,262.25 78.55,262.83 86.61,262.83 86.61,262.81 90.81,258.62 90.81,257.38 90.35,256.92 84.33,256.92 82.96,255.55 82.52,255.55 82.5,255.52 81.33,255.52 81.31,255.55 79.97,255.55 70.9,246.47 70.9,244.51 69.15,242.76 65.98,242.76 63.04,239.83
5V_S5 on BOTTOM: 25.93,231.34 25.57,231.69 25.57,235.53 25.78,235.74 25.78,235.76 25.93,235.92 33.07,235.92 33.46,235.53 33.46,231.77 33.02,231.34
5V_S5 on BOTTOM: 98.65,5.99 97.5,7.15 97.5,8.6 95.53,10.57 90.58,10.57 89.92,11.23 89.92,14.86 89.41,15.37 87.68,15.37 86.44,16.61 84.86,16.61 81.92,19.56 81.92,21.84 82.63,22.56 84.58,22.56 85.14,22 85.14,20.24 85.78,19.61 89.71,19.61 90.93,20.83 94.97,20.83 104.95,10.85 110.67,10.85 111,11.18 113.16,11.18 115.44,13.46 117.88,13.46 121.18,16.76 123.01,16.76 123.39,17.14 123.39,18.85 123.8,19.25 126.47,19.25 126.8,18.92 126.8,11.51 121.28,5.99
5V_S5 on L2VCC: 16.72,30.29 15.12,31.88 15.07,31.94 15.06,31.94 0.76,46.24 0.76,179.29 6.73,179.29 7.83,179.55 8.93,179.99 9.78,180.6 10.67,181.5 11.31,182.79 11.65,184.21 11.57,185.37 11.23,186.69 10.75,187.5 10.14,188.35 8.7,189.4 7.64,189.77 6.46,189.9 1.93,189.9 1.56,190.27 1.56,191.41 1.51,232.23 8.84,239.46 26.47,239.46 27.37,240.06 27.37,247.95 28.15,248.73 32.56,248.73 33.46,247.83 33.44,233.1 33.41,233.07 33.41,233.05 31.65,231.28 13.46,231.28 10.22,228.04 10.22,226.02 10.6,225.08 10.6,219.53 10.26,219.19 6.35,219.19 5.48,218.32 5.42,218.19 5.4,196.17 5.4,194.72 5.45,194.58 6.78,193.23 9.45,193.23 14.67,188.01 14.67,181.37 14.65,181.19 10,176.56 8.3,174.89 7.13,173.7 5.64,173.7 5.52,173.59 5.52,173.56 4.64,172.67 4.64,136.12 4.41,135.95 4.39,135.95 4.35,135.91 3.75,135.48 3.75,47.8 18.86,32.69 18.86,31.96 17.19,30.29
5V_S5 on L2VCC: 36.8,171.64 36.36,172.31 35.2,174.24 33.1,176.34 12.83,176.34 12.67,176.74 14.05,178.12 14.43,178.12 14.46,178.1 14.51,178.12 32.96,178.12 33.29,177.9 37.4,174.78 37.4,173.8 37.88,173.16 47.17,173.19 47.55,173.19 48.82,174.51 49.35,174.51 50.06,173.8 62.56,173.8 64.09,175.32 69.17,175.32 69.66,175.82 69.66,176.96 70.06,177.36 94.57,177.36 95.82,178.61 95.82,180.77 96.61,181.56 96.63,181.57 96.65,181.59 96.68,181.6 96.69,181.63 97.54,182.49 101.53,186.55 151.68,186.5 152.19,186.75 174.8,186.75 175.2,186.36 175.2,184.86 174.8,184.47 161.37,184.47 160.73,185.1 151.79,185.1 150.26,185.48 126.54,185.48 126.03,184.98 120.35,184.98 119.71,185.61 103.15,185.56 103.13,185.59 102.97,185.58 97.98,180.55 97.98,178 97.57,177.52 96.01,175.93 74.22,175.96 71.8,173.55 66.22,173.55 65.07,172.4 49.71,172.4 49.32,172.02 46.15,172.02 45.77,171.64
5V_S5 on L3SGND: 37.04,22.92 35.13,24.83 31.16,24.83 30.46,24.13 23.15,24.13 16.81,30.76 16.79,34.56 16.84,34.61 17.95,34.61 22.85,29.58 24.56,27.88 37.01,27.88 37.66,27.23 37.66,25.58 38.15,25.08 40.85,25.08 41.47,25.7 41.47,27.23 42.88,28.64 60.91,28.64 63.45,31.18 67.74,31.18 68.14,30.78 68.14,29.67 67.74,29.27 64.44,29.27 62.15,26.99 44.24,26.99 43.24,25.99 43.24,23.32 42.85,22.92
5V_USB_FRONT on TOP: 87.63,260.35 87.38,260.6 87.38,266.95 87.63,267.21 91.44,267.21 91.82,266.83 91.82,260.48 91.69,260.35 ; 2 cut-outs
5V_USB_FRONT on BOTTOM: 88.77,263.4 85.6,266.57 85.6,272.29 87.76,274.45 89.41,274.45 94.61,269.24 106.93,269.24 107.95,270.26 107.95,273.69 108.2,273.94 112.14,273.94 115.32,270.76 115.32,268.1 113.54,266.32 97.66,266.32 94.74,263.4
5V_USB_REAR on TOP: 83.57,10.03 83.14,10.46 83.14,15.72 82.22,16.64 82.22,18.76 86.28,22.83 86.28,27.46 86.59,27.76 88.37,27.76 88.44,27.69 88.44,24.23 91.19,21.49 91.19,18.77 89.69,17.27 87.6,17.27 85.98,15.65 85.98,10.54 85.47,10.03 ; 2 cut-outs
5V_USB_REAR on BOTTOM: 83.39,10.16 83.13,10.41 83.13,15.67 82.52,16.28 82.52,17.07 82.97,17.51 83.4,17.51 84.68,16.23 85.72,16.23 85.98,15.98 85.98,10.41 85.72,10.16
5V_USB_RJ45 on TOP: 105.45,7.07 104.01,8.51 104.01,15.75 104.65,16.38 106.3,16.38 106.93,15.75 106.93,14.66 107.01,14.66 107.62,14.05 113.36,14.05 114.57,12.84 119.42,12.84 121.82,15.24 125.4,15.24 125.5,15.34 125.5,15.62 125.55,15.67 126,15.67 126.05,15.62 126.05,10.22 125.73,9.91 123.24,9.91 121.84,8.51 117.65,8.51 116.22,7.07 ; 2 cut-outs
5V_USB_RJ45 on BOTTOM: 105.03,11.43 104.01,12.45 104.01,15.75 104.65,16.38 106.3,16.38 106.93,15.75 106.93,11.81 106.55,11.43
5V_VGA_CONN on TOP: 44.3,20.22 43.89,20.62 36.07,20.62 35.81,20.88 35.81,23.11 36.55,23.85 45.64,23.85 45.77,23.72 45.77,20.32 45.67,20.22
12V_CPU on TOP: outline of 89 points within 1.45,25.4 123.44,132.21 ; 6 cut-outs
12V_CPU on BOTTOM: 39.29,24.13 37.92,25.5 37.92,27.38 38.23,27.69 42.19,27.69 46.35,31.85 46.38,31.85 46.66,32.13 57.45,32.13 62.38,37.06 69.49,37.06 70,36.55 76.23,36.55 79.02,39.34 82.58,39.34 84.07,37.85 89.79,37.85 90.04,37.59 90.04,36.53 86.54,33.02 72.01,33.02 70.61,31.62 68.2,31.62 67.56,32.26 64.9,32.26 59.69,27.05 44.7,27.05 41.78,24.13
12V_CPU on L2VCC: outline of 100 points within 5.02,24.96 101.92,132.02
12V_CPU_S0 on TOP: 21.97,37.97 21.59,38.35 21.59,42.93 21.84,43.18 23.11,43.18 23.37,42.93 23.37,38.35 22.99,37.97 ; 4 cut-outs
12V_S0 on TOP: 96.39,192.02 95.89,192.53 95.89,198.37 95.12,199.14 95.12,203.96 96.52,205.36 141.22,205.36 144.23,202.35 181.26,202.35 184.51,199.11 184.51,195.35 185.8,194.06 185.8,192.28 185.69,192.16 181.62,192.16 177.72,196.07 158.87,196.07 156.82,198.12 143.89,198.12 140.08,201.93 104.34,201.93 103.25,200.84 103.25,192.71 102.57,192.02
12V_S0 on TOP: 190.04,46.18 189.87,46.35 189.87,137.36 188.67,138.56 188.67,140.06 188.95,140.34 191.8,140.34 192.33,140.87 192.33,142.47 191.64,143.15 191.64,144.15 192.11,144.61 192.9,144.61 193.65,145.36 193.65,147.32 194.16,147.83 195.45,147.83 195.83,147.45 195.83,140.21 194.56,138.94 194.56,47.19 193.55,46.18
12V_S0 on BOTTOM: 179.58,201.04 182.25,201.04 184.28,199.01 184.28,194.46 186.51,192.23 198.68,192.23 199.24,191.67 199.24,144.83 198.27,143.87 194.49,143.87 194.01,144.35 194.01,146.53 195,147.52 195,163.83 195.83,164.67 195.83,167.64 194.34,169.14 194.34,176.73 195.76,178.16 195.76,178.84 195.35,179.25 195.35,188.24 194.45,189.14 181.44,189.14 179.32,191.26 179.32,200.79
12V_S0 on BOTTOM: 96.01,195.07 95.76,195.33 95.76,198.5 96.27,199.01 98.42,199.01 99.19,198.25 99.19,195.33 98.93,195.07
12V_S0 on L2VCC: 158.83,41.85 158.43,42.24 158.43,48.44 158.7,48.7 170.74,48.7 171.13,48.31 171.13,46.91 171.75,46.29 176.74,46.29 177.62,47.18 180.67,47.18 181.43,47.94 186.77,47.94 189.82,50.99 197.66,50.99 198.06,50.59 198.06,44.4 195.5,41.85
12V_S5 on TOP: 186.13,175.41 185.95,175.59 185.95,176 186.59,176.63 186.59,177.06 186.28,177.37 185.22,177.37 180,182.59 180,182.79 177.55,185.24 175.59,185.24 175.39,185.45 175.39,186.56 174.88,187.07 174.5,187.07 172.97,188.59 172.97,191.01 172.21,191.77 172.21,194.69 172.85,195.33 177.77,195.33 180.09,193.01 180.09,192.28 180.47,191.9 184.28,191.9 184.43,191.74 184.43,188.26 184.86,187.83 184.86,181.71 185.9,180.67 186.92,180.67 188.52,179.07 191.36,179.07 191.58,178.85 191.58,175.84 191.45,175.72 187.25,175.72 186.94,175.41 ; 9 cut-outs
12V_S5 on TOP: 170.21,2.49 169.93,2.77 169.93,4.98 170.08,5.13 171.5,5.13 171.63,5 171.63,2.67 171.45,2.49 ; 2 cut-outs
12V_S5 on TOP: 49.63,191.13 48.11,192.66 48.11,194.26 46.76,195.61 46.76,204.09 47.12,204.44 47.12,204.47 48.7,204.47 50.23,202.95 50.23,202.69 52.04,200.88 52.04,196.82 55.96,192.91 55.96,191.31 55.78,191.13 ; 2 cut-outs
12V_S5 on L2VCC: 69.17,182.69 59.51,192.34 47.07,192.34 46.67,192.74 46.67,203.88 46.94,204.15 58.09,204.15 59.18,203.06 64.6,197.76 64.61,197.73 64.66,197.71 64.73,197.67 64.92,197.58 65.41,197.21 72.18,190.44 87.2,190.44 88.72,191.96 90.42,191.96 95.81,191.93 95.84,191.96 98.38,191.96 99,192.58 99,204.26 100.03,205.3 141.27,205.3 146.23,200.34 162.35,200.34 162.88,199.82 162.88,196.01 163.75,195.14 179.37,195.14 180.15,194.36 180.15,188.17 179.12,187.13 152.1,187.13 151.59,186.88 101.37,186.93 97.27,182.76 97.2,182.69 96.17,182.69 96.12,182.7 96.09,182.69 ; 1 cut-out
AGND on TOP: 3,2.06 2.06,3 2.06,7.37 2.21,7.52 2.79,7.52 2.87,7.59 2.77,7.7 2.77,18.9 4.28,20.41 7.51,20.41 7.54,20.45 14.86,20.45 18.16,17.14 18.16,2.57 17.65,2.06 ; 2 cut-outs
AGND on BOTTOM: 2.9,2.26 2.18,2.97 2.18,20.65 2.87,21.34 8,21.34 10.29,19.05 28.96,19.05 30.48,20.57 32,20.57 32.26,20.32 32.26,16.64 26.16,10.54 19.68,10.54 18.29,9.14 18.29,2.84 17.7,2.26
AGND on L2VCC: 66.88,251.52 66.74,251.67 66.74,252.78 67.25,253.29 67.25,255.6 64.98,257.87 61.04,257.87 60.28,257.5 59.91,257.37 58.2,257.37 57.57,256.6 57.21,256.6 56.88,256.82 56.14,257.44 55.69,257.89 55.69,261.67 55.94,261.92 55.94,263.85 55.33,264.51 54.73,265.16 54.72,265.49 55.13,265.9 55.51,266.28 55.51,267.56 56.83,268.88 56.83,270.94 59.12,273.23 59.12,281.74 60.68,282.31 61.64,283.68 61.98,284.77 62.06,284.89 62.21,284.94 71.4,284.94 71.52,284.91 71.6,284.82 71.73,284.6 72.58,283.7 73.72,283.26 73.72,273.35 74.22,272.86 75.87,272.86 76.14,272.59 76.14,264.49 75.5,263.86 75.5,257.08 75.3,256.88 74.57,256.12 73.05,254.65 72.01,254.65 71.75,254.39 71.03,253.65 70.43,253.05 70.41,253.05 68.88,251.52
AGND on L2VCC: 2.9,1.89 2.03,2.48 1.54,3.04 1.54,20.13 1.95,20.49 5.51,20.49 10.29,25.18 10.31,25.19 13.97,31.56 14.9,31.56 15.15,31.28 15.18,31.28 16.46,30.01 16.47,29.98 16.52,29.95 17.52,28.95 22.97,23.55 23.38,23.58 24.87,23.58 30.21,23.57 30.56,23.22 30.57,23.19 30.61,23.17 30.65,23.13 30.65,23.13 32.5,21.28 32.5,17.15 25.6,10.25 19.33,10.25 18.22,9.15 18.22,2.29 17.83,1.89
AGND on L3SGND: outline of 108 points within 0.76,0.76 76.14,284.94 ; 1 cut-out
GND on TOP (solid shape): outline of 284 points within 1.16,27.83 11.54,38.21
GND on TOP (solid shape): outline of 284 points within 110.26,249.01 120.64,259.39
GND on BOTTOM (solid shape): outline of 284 points within 1.16,27.83 11.54,38.21
GND on BOTTOM (solid shape): outline of 284 points within 110.26,249.01 120.64,259.39
GND on TOP: 50.76,208.65 50.9,208.51 51.49,207.01 52.03,206.47 52.03,204.69 51.19,203.85 50.04,203.85 49.46,204.43 49.16,204.62 48.39,204.98 47.2,205.27 46.48,205.99 44.07,206.95 42.82,207.18 42.48,207.52 39.04,207.52 38.25,208.31 38.25,209.75 39.37,210.87 39.37,213.23 38.23,214.38 38.23,225.43 39.5,226.69 40.77,226.69 41.02,226.44 41.02,225.17 40.89,225.04 39.62,225.04 39.24,224.66 39.24,214.76 40.39,213.61 40.39,212.47 41.02,211.84 41.02,209.8 42.04,208.79 43.91,208.79 44.05,208.65 ; 5 cut-outs
GND on TOP: 16.23,115.8 15.88,116.15 15.88,117.7 16.05,117.88 20.12,117.88 20.37,117.63 20.37,117.14 20.17,116.94 17.7,116.94 17.35,116.59 17.35,116.18 16.97,115.8 ; 1 cut-out
GND on TOP: 127.89,36.7 127.51,37.08 127.51,41.78 127.89,42.16 130.3,42.16 130.81,41.66 130.81,37.24 130.28,36.7 ; 1 cut-out
GND on TOP: 29.11,39.6 28.07,40.64 28.07,45.69 28.98,46.61 28.98,48.16 31.37,50.55 31.37,52.07 31.75,52.45 32.26,52.45 32.38,52.32 32.38,46.2 30.76,46.2 30.63,46.08 30.63,43.54 30.76,43.41 32.28,43.41 32.38,43.31 32.38,39.6
GND on TOP: 69.34,67.18 69.09,67.44 69.09,69.6 69.34,69.85 70.48,69.85 70.74,69.6 70.74,67.44 70.48,67.18
GND on TOP: 26.8,214.25 26.67,214.38 26.67,215.39 26.92,215.65 27.56,215.65 28.12,216.2 28.12,220.18 28.17,220.24 29.74,220.24 29.9,220.4 29.9,222.43 30.1,222.63 31.62,222.63 31.93,222.32 31.93,217.35 31.11,216.53 31.11,214.38 30.99,214.25 ; 2 cut-outs
GND on TOP: 20.02,202.1 19.96,202.16 19.96,206.76 20.22,207.01 21.84,207.01 22.11,206.74 22.11,202.44 21.78,202.1
GND on TOP: 34.06,178.41 33.66,178.82 33.66,181.13 34.65,182.12 36.04,182.12 36.25,181.91 36.25,178.56 36.09,178.41
GND on TOP: 54.99,35.18 54.76,35.41 54.76,35.84 55.52,36.6 55.52,37.26 56.49,38.23 56.87,38.23 57.02,38.07 57.02,35.69 56.52,35.18
GND on TOP: 104.29,5.56 100.84,9.02 100.84,15.62 101.85,16.64 102.87,16.64 103.76,15.75 103.76,8.26 105.16,6.86 116.56,6.86 118.06,8.36 119.02,8.36 119.02,5.56
GND on TOP: 48.13,179.07 47.02,180.19 47.02,189.36 47.14,189.48 49.15,189.48 49.71,188.93 49.71,179.37 49.4,179.07 ; 1 cut-out
GND on TOP: 42.13,231.94 41.83,232.23 41.83,233.5 42.19,233.86 45.11,233.86 45.59,233.38 45.59,232.16 45.38,231.94 ; 4 cut-outs
GND on TOP: 140.31,133.22 140.21,133.32 140.21,133.6 139.85,133.96 139.85,135.92 139.98,136.04 140.74,136.04 141.49,135.29 141.49,133.97 141.15,133.63 141.15,133.38 141,133.22
GND on TOP: 8.89,107.7 8.76,107.82 8.76,111.38 8.89,111.51 10.92,111.51 11.18,111.25 11.18,108.08 10.79,107.7
GND on TOP: 142.24,125.48 141.99,125.73 141.99,125.98 142.37,126.36 142.37,127 142.24,127.13 142.24,127.51 142.37,127.64 142.88,127.64 143.13,127.38 143.13,125.73 142.88,125.48
GND on TOP: 71.91,40.23 71.78,40.36 71.78,44.17 71.91,44.3 72.42,44.3 72.54,44.17 72.54,41.25 72.67,41.12 72.67,40.36 72.54,40.23
GND on TOP: 187.2,14.66 187.17,14.68 187.17,15.24 187.22,15.29 189.43,15.29 189.48,15.24 189.48,14.73 189.41,14.66
GND on TOP: 18.16,73.41 15.88,75.69 15.88,77.6 16,77.72 16.76,77.72 17.6,76.89 21.69,76.89 21.79,76.78 21.79,75.21 21.87,75.13 22.81,75.13 23.11,74.83 23.11,73.74 22.78,73.41 ; 1 cut-out
GND on TOP: 163.49,111.31 163,111.8 163,112.83 163.07,112.9 163.19,112.9 163.45,112.65 164.08,112.65 164.52,112.21 164.52,111.44 164.4,111.31
GND on TOP: 148.11,152.06 147.7,152.48 147.7,154.3 149.48,156.08 149.48,160.66 149.03,161.11 148.01,161.11 147.83,161.29 147.83,162.94 147.96,163.07 149.42,163.07 150.87,161.62 150.87,153.51 150.51,153.15 150.48,153.15 149.39,152.06 ; 2 cut-outs
GND on TOP: 149.68,8.1 149.3,8.48 148.59,8.48 148.59,11.25 148.69,11.35 150.7,11.35 151.03,11.02 151.03,8.15 150.98,8.1
GND on TOP: 32,191.52 31.88,191.64 31.88,192.28 33.02,192.28 33.3,192.56 33.3,196.65 33.32,196.67 35.03,196.67 35.81,197.46 35.81,198.27 36.45,198.91 42.01,198.91 42.52,198.4 42.52,196.75 41.55,195.78 37.92,195.78 37.59,195.45 37.59,192.91 37.47,192.79 35.05,192.79 33.78,191.52
GND on TOP: 47.24,33.5 46.99,33.76 46.99,34.59 47.17,34.77 51.71,34.77 51.98,35.04 52.46,35.04 53.24,34.26 53.24,34.04 52.7,33.5
GND on TOP: 143.51,139.06 143.38,139.19 143.38,139.57 146.79,142.98 147.4,142.98 147.55,142.82 147.55,139.55 147.45,139.45 144.53,139.45 144.15,139.06 ; 7 cut-outs
GND on TOP: 89.69,39.34 89.56,39.47 89.56,40.11 89.81,40.36 89.81,43.41 89.94,43.54 90.45,43.54 90.58,43.41 90.58,39.47 90.45,39.34
GND on TOP: 124.84,48.77 124.59,49.02 124.59,50.16 123.83,50.93 123.19,50.93 122.94,51.18 122.94,51.92 123.6,52.58 126.16,52.58 126.85,51.89 127.71,51.89 128.27,51.33 128.98,51.33 129.11,51.21 129.11,49.15 128.73,48.77 ; 1 cut-out
GND on TOP: 27.81,223.14 27.43,223.52 27.43,226.82 27.94,227.33 32,227.33 32.26,227.08 32.26,223.52 31.88,223.14
GND on TOP: 133.6,56.52 133.48,56.64 133.48,58.17 133.6,58.29 136.4,58.29 136.53,58.17 136.53,56.64 136.4,56.52
GND on TOP: 104.27,201.68 140.09,201.68 143.74,198.02 153.18,198.02 154.18,197.03 154.18,195.12 153.54,194.49 153.54,193.93 144.15,193.93 142.62,192.41 134.49,192.41 134.24,192.66 134.24,197.74 134.87,198.37 134.87,199.39 134.49,199.77 128.14,199.77 127.64,199.26 127.64,198.75 128.4,197.99 128.4,193.42 128.65,193.17 128.65,192.66 128.52,192.53 115.98,192.53 115.49,192.05 114.63,192.05 114.17,192.51 114.17,193.68 114.3,193.8 114.3,198.12 114.81,198.63 114.81,199.39 114.55,199.64 108.2,199.64 107.95,199.39 107.95,198.63 108.58,197.99 108.58,193.8 108.84,193.55 108.84,192.66 108.71,192.53 108.71,192.2 108.48,191.97 104.44,191.97 103.63,192.79 103.63,201.04
GND on TOP: 36.27,185.55 35.94,185.88 35.94,187.68 36.3,188.04 39.98,188.04 40.13,187.88 40.13,187.2 38.48,185.55 ; 3 cut-outs
GND on TOP: 183.39,165.91 183.13,166.17 183.13,166.9 182.85,167.18 182.47,167.18 182.3,167.36 182.3,171.58 183.3,172.58 185.1,172.58 185.24,172.44 185.24,169.06 185.12,168.94 183.97,168.94 183.87,168.83 183.87,167.16 184.25,166.78 184.25,165.99 184.18,165.91
GND on TOP: 34.57,31.17 34.52,31.22 34.52,34.59 34.44,34.67 34.44,34.9 34.7,35.15 35.2,35.15 35.38,34.98 35.38,31.22 35.33,31.17
GND on TOP: 125.48,77.09 125.09,77.47 125.09,81.79 125.22,81.92 128.02,81.92 128.52,81.41 128.52,77.6 128.02,77.09 ; 1 cut-out
GND on TOP: 78.23,178.94 77.93,179.25 77.93,181.94 78.31,182.32 80.49,182.32 80.87,181.94 80.87,179.32 80.49,178.94
GND on TOP: 51.69,175.26 50.09,176.86 50.09,178.56 50.34,178.82 51.87,178.82 52.15,179.1 52.15,180.8 52.58,181.23 54.99,181.23 55.17,181.05 55.17,180.19 54.38,179.4 54.38,175.29 54.36,175.26 ; 2 cut-outs
GND on TOP: 9.07,212.01 8.89,212.19 8.89,215.14 8.51,215.52 8.26,215.52 8.13,215.65 8.13,217.04 8.26,217.17 8.76,217.17 9.53,216.41 10.01,216.41 11.05,215.37 11.05,212.47 10.59,212.01 ; 3 cut-outs
GND on TOP: 190.5,183.9 190.37,184.02 190.37,185.55 190.5,185.67 193.29,185.67 193.42,185.55 193.42,184.02 193.29,183.9
GND on TOP: 133.4,17.12 133.24,17.28 133.24,19.42 134.26,20.45 135.1,20.45 135.25,20.29 135.25,19.58 135.1,19.43 135.1,17.25 134.98,17.12 ; 4 cut-outs
GND on TOP: 66.04,98.17 65.91,98.3 65.91,99.31 66.04,99.44 66.98,99.44 67.21,99.67 67.21,103.15 67.34,103.28 68.86,103.28 68.91,103.23 68.91,101.14 69.09,100.97 73.69,100.97 73.74,100.91 73.74,98.27 73.63,98.17 ; 4 cut-outs
GND on TOP: 18.16,47.5 17.14,48.51 14.86,48.51 14.61,48.77 14.61,49.28 14.35,49.53 13.72,49.53 13.59,49.66 13.59,50.16 13.72,50.29 17.27,50.29 17.53,50.04 17.53,49.66 17.78,49.4 21.46,49.4 21.59,49.28 21.59,47.75 21.34,47.5 ; 12 cut-outs
GND on TOP: 65.68,46.33 65.56,46.46 65.56,55.5 64.14,56.92 64.14,58.17 64.26,58.29 64.77,58.29 65.41,58.93 65.41,60.2 65.56,60.35 68.1,60.35 68.15,60.3 68.15,59.36 69.09,58.42 69.09,55.19 67.56,55.19 67.34,54.97 67.34,52.81 67.72,52.43 68.86,52.43 69.09,52.2 69.09,48.67 67.39,48.67 67.34,48.62 67.34,46.46 67.21,46.33 ; 1 cut-out
GND on TOP: 117.53,175.79 117.3,176.02 113.92,176.02 112.78,177.16 112.78,177.67 112.93,177.83 113.56,177.83 113.97,177.42 118.11,177.42 118.29,177.24 118.29,176 118.08,175.79
GND on TOP: 34.8,94.11 34.42,94.49 34.42,96.04 34.67,96.29 36.26,96.29 36.47,96.08 36.47,94.63 36.45,94.61 36.45,94.49 36.07,94.11
GND on TOP: outline of 263 points within 0.76,0.76 199.24,284.94 ; 18 cut-outs
GND on TOP: 161.16,171.27 161.06,171.37 161.06,174.83 161.14,174.9 164.39,174.9 164.59,174.7 164.59,171.45 164.41,171.27
GND on TOP: 159.38,113.28 159.26,113.41 159.26,113.92 159.89,114.55 160.53,114.55 161.42,113.67 161.42,113.41 161.29,113.28 161.04,113.28 160.91,113.41 159.77,113.41 159.64,113.28
GND on TOP: 121.31,15.54 121.21,15.65 121.21,16.18 121.28,16.26 123.67,16.26 123.88,16.46 123.88,17.22 123.93,17.27 124.46,17.27 124.54,17.2 124.54,16.38 124.74,16.18 125.15,16.18 125.2,16.13 125.2,15.6 125.15,15.54
GND on TOP: 34.67,71.25 34.42,71.5 34.42,72.54 34.67,72.79 37.19,72.79 37.59,72.39 37.59,71.63 37.21,71.25
GND on TOP: 66.04,94.49 65.91,94.61 65.91,95.63 66.04,95.76 71.53,95.76 71.63,95.66 71.63,94.54 71.58,94.49
GND on TOP: 20.45,177.29 20.32,177.42 20.32,177.8 17.78,180.34 17.78,185.67 18.16,186.06 20.95,186.06 21.46,185.55 21.46,181.48 22.1,180.85 22.1,178.94 21.59,178.44 21.59,177.42 21.46,177.29 ; 1 cut-out
GND on TOP: 84.1,45.82 83.74,46.18 83.74,60.12 84.15,60.53 84.91,60.53 85.06,60.38 85.06,58.95 86.13,57.89 87.5,57.89 87.63,57.76 87.63,54.46 86,54.46 85.88,54.33 85.88,51.79 86,51.66 87.53,51.66 87.63,51.56 87.63,47.9 86.06,47.9 85.88,47.73 85.88,45.95 85.75,45.82 ; 2 cut-outs
GND on TOP: 12.32,152.53 13.03,152.53 19.83,143.45 19.83,125.28 20.22,124.89 21.26,124.89 21.41,124.74 21.41,123.93 21.18,123.7 20.19,123.7 19.05,124.84 19.05,139.19 18.16,140.08 17.53,140.08 12.95,144.65 12.95,146.69 11.94,147.7 11.94,152.15
GND on TOP: 73.81,39.47 73.66,39.62 73.66,40.03 73.05,40.64 73.05,41.5 73.18,41.63 73.43,41.63 73.94,41.12 74.57,41.12 74.68,41.22 74.68,41.45 74.9,41.68 75.29,41.68 75.46,41.5 75.46,41.15 75.62,41 77.11,41 77.24,40.87 77.24,39.6 77.11,39.47
GND on TOP: 120.78,24.69 120.68,24.79 120.68,25.04 121.28,25.65 122.45,25.65 122.48,25.63 122.48,25.12 122.45,25.1 121.41,25.1 121.01,24.69
GND on TOP: 161.29,131.95 161.16,132.08 161.16,132.97 161.54,133.35 161.67,133.35 162.05,132.97 162.56,132.97 162.81,132.72 162.81,132.33 162.56,132.08 161.54,132.08 161.42,131.95
GND on TOP: 14.05,162.41 13.49,162.97 13.49,163.65 13.03,164.11 13.03,167.97 14.35,169.29 75.18,169.29 75.82,168.66 75.82,163.07 75.18,162.43 60.71,162.43 60.68,162.41 ; 1 cut-out
GND on TOP: 47.37,41.68 47.24,41.81 47.24,52.45 49.2,54.41 49.2,56.01 49.25,56.06 49.83,56.06 49.94,55.96 49.94,54.89 50.9,53.92 50.9,50.32 49.15,50.32 49.02,50.19 49.02,47.78 49.28,47.52 50.65,47.52 50.77,47.4 50.77,43.76 49.2,43.76 49.02,43.59 49.02,41.81 48.9,41.68
GND on TOP: 92.08,38.86 91.97,38.96 91.97,40.46 92.66,41.15 93.93,41.15 94.77,40.31 95.4,40.31 95.5,40.21 95.5,38.99 95.38,38.86
GND on TOP: 143.76,23.37 143.62,23.51 143.62,23.99 143.61,24 143.61,27.33 143.28,27.66 143.28,29.36 143.38,29.46 144.27,29.46 145.41,28.32 145.41,23.88 144.91,23.37 ; 9 cut-outs
GND on TOP: 52.37,35.36 52.25,35.48 52.25,36.37 52.6,36.73 52.63,36.73 52.63,39.34 52.73,39.45 53.37,39.45 53.49,39.32 53.49,35.48 53.37,35.36 ; 1 cut-out
GND on TOP: 85.5,71.35 78.87,77.98 78.87,78.87 79.15,79.15 85.95,79.15 89.41,75.69 89.41,71.98 88.77,71.35
GND on TOP: 6.1,206.5 5.84,206.76 5.84,207.39 5.71,207.52 5.71,209.17 5.84,209.3 5.84,209.68 6.1,209.93 9.4,209.93 9.53,209.8 9.53,207.9 8.64,207.01 7.87,207.01 7.37,206.5
GND on TOP: 127,86.49 126.49,87 126.49,92.13 126.57,92.2 128.23,92.2 128.82,91.62 128.82,91.61 128.85,91.57 128.85,86.64 128.7,86.49 ; 2 cut-outs
GND on TOP: 59.44,13.34 59.36,13.41 59.36,14.94 59.41,14.99 60.81,14.99 60.99,14.81 60.99,13.39 60.93,13.34 ; 3 cut-outs
GND on TOP: 12.57,74.27 12.42,74.42 12.42,75.03 11.53,75.92 11.53,78.23 11.79,78.49 12.32,78.49 12.55,78.26 12.55,76.1 12.75,75.9 13,75.9 13.74,75.16 13.74,74.37 13.64,74.27
GND on TOP: 34.8,86.23 34.42,86.61 34.42,88.16 34.67,88.42 36.26,88.42 36.47,88.2 36.47,86.76 36.45,86.74 36.45,86.61 36.07,86.23
GND on TOP: 34.8,78.49 34.42,78.87 34.42,80.41 34.67,80.67 36.26,80.67 36.47,80.46 36.47,79.01 36.45,78.99 36.45,78.87 36.07,78.49
GND on TOP: outline of 213 points within 141.78,112.75 162.18,134.11
GND on TOP: 61.47,67.31 61.34,67.44 61.34,69.6 61.47,69.72 62.61,69.72 62.87,69.47 62.87,67.44 62.74,67.31
GND on TOP: 8.64,78.61 8.51,78.74 8.51,82.55 8.76,82.8 10.67,82.8 10.92,82.55 10.92,81.53 10.74,81.36 10.06,81.36 9.91,81.2 9.91,78.74 9.78,78.61
GND on TOP: 29.31,106.88 29.21,106.98 29.21,108.97 29.34,109.09 32.31,109.09 32.89,108.51 32.89,106.96 32.82,106.88
GND on TOP: 77.34,67.31 77.09,67.56 77.09,69.6 77.34,69.85 79.5,69.85 79.76,69.6 79.76,67.44 79.63,67.31
GND on TOP: 17.22,108.92 17.08,109.05 17.08,113.22 17.53,113.67 20.32,113.67 21.34,112.65 22.61,112.65 23.61,111.65 23.61,108.98 23.55,108.92 ; 1 cut-out
GND on TOP: 6.88,217.81 6.86,217.83 6.86,218.74 6.71,218.9 5.69,218.9 5.64,218.95 5.64,219.76 5.66,219.79 8.2,219.79 8.23,219.76 8.23,218.92 8.2,218.9 7.21,218.9 7.06,218.74 7.06,217.83 7.04,217.81
GND on TOP: 81.79,93.47 81.13,94.13 81.13,99.42 80.9,99.64 79.91,99.64 79.76,99.8 79.76,100.71 79.53,100.94 78.79,100.94 78.61,101.12 78.61,101.68 78.79,101.85 80.7,101.85 81.1,102.26 81.1,103.02 81.41,103.33 82.63,103.33 82.93,103.02 82.93,94.61 82.55,94.23 82.55,93.85 82.17,93.47 ; 4 cut-outs
GND on TOP: 99.06,93.22 99.57,92.71 104.63,89.41 109.86,89.41 113.28,85.98 113.28,78.99 113.92,78.36 113.92,73.15 112.9,72.14 108.33,72.14 101.98,78.49 99.82,78.49 98.68,79.63 98.68,80.01 98.81,80.14 99.31,80.14 99.44,80.01 104.78,80.01 105.28,80.52 105.28,82.93 104.52,83.69 99.95,83.69 99.57,84.07 99.57,85.09 98.04,86.61 98.04,87.12 98.3,87.38 99.31,87.38 99.57,87.12 99.57,86.11 99.82,85.85 100.97,85.85 101.09,85.98 101.09,87.12 99.19,89.03 99.19,89.79 97.79,91.19 97.03,91.19 96.77,91.44 96.77,91.82 95.76,92.84 95.76,92.96 96.01,93.22
GND on TOP: 115.06,105.66 114.43,106.3 109.86,106.3 109.6,106.55 109.6,107.7 110.62,108.71 112.39,108.71 125.09,121.41 125.73,121.41 127,122.68 127,142.37 127.13,142.49 127.64,142.49 127.76,142.37 127.76,115.19 123.95,111.38 123.95,106.05 123.83,105.92 119.63,105.92 119.51,106.05 119.51,106.93 119.13,107.31 115.95,107.31 115.7,107.06 115.7,105.79 115.57,105.66
GND on TOP: 84.05,162.46 83.72,162.79 83.72,167.47 82.47,168.72 82.47,169.51 82.65,169.68 99.97,169.68 99.98,169.68 132.2,169.68 134.01,167.87 134.01,162.97 133.5,162.46
GND on TOP: 31.06,207.59 30.56,208.1 30.56,213.41 30.61,213.46 31.75,213.46 32,213.21 32,212.7 32.72,211.99 32.72,211.58 32.28,211.15 32.28,209.17 32.92,208.53 32.92,207.82 32.69,207.59
GND on TOP: 193.93,168.15 193.8,168.28 193.8,175.9 193.42,176.28 193.42,177.04 193.55,177.16 194.21,177.16 195.12,176.25 195.22,176.25 196.22,175.26 196.22,173.58 196.47,173.33 196.47,169.16 195.45,168.15 ; 1 cut-out
GND on BOTTOM: 51.82,175.39 49.91,177.29 49.91,178.56 50.29,178.94 51.56,178.94 51.94,179.32 51.94,180.59 52.2,180.85 54.1,180.85 54.36,180.59 54.36,175.64 54.1,175.39
GND on BOTTOM: 124.65,50.03 123.42,51.26 123.42,52.48 123.55,52.6 126.09,52.6 126.9,51.79 127.48,51.79 127.94,51.33 128.98,51.33 129.18,51.13 129.18,50.57 128.64,50.03
GND on BOTTOM: 124.97,174.12 127.38,171.83 128.02,170.94 128.07,170.94 128.07,172.85 128.12,172.9 137.46,172.9 138.91,171.45 141.22,171.45 141.55,171.12 141.63,171.12 143.41,169.34 143.41,165.13 143.38,165.1 143.38,164.16 144.65,162.89 147.37,162.89 147.47,162.99 148.89,162.99 149.15,162.74 149.15,161.37 149,161.21 144.37,161.21 143.66,161.93 143.66,162.03 141.64,164.05 141.74,164.15 141.74,168.68 140.64,169.77 136.27,169.77 135.94,170.1 135.94,170.18 127.76,170.18 126.11,171.07 122.68,174.5 120.65,175.9 117.98,178.56 114.81,178.82 112.78,180.72 86.21,180.72 81.22,182.31 71.37,185.17 64.39,189.61 61.26,189.61 58.47,192.41 58.47,196.69 58.43,196.73 57.53,197.23 53.34,199.9 50.93,202.18 49.53,204.34 49.66,205.23 50.04,205.49 51.18,205.49 51.94,204.72 52.96,202.56 53.59,201.8 58.8,198.63 60.83,196.85 60.83,193.17 62.74,191.26 65.02,191.26 72.26,186.56 82.17,183.9 85.34,183.01 86.12,182.23 113.48,182.23 113.83,181.89 114.3,181.48 115.44,180.34 118.62,180.34
GND on BOTTOM: 23.67,235.38 24.69,235.38 25.07,235 25.07,231.7 24.82,231.44 21.64,231.44 21.51,231.57 21.51,233.22 21.64,233.35 23.04,233.35 23.42,233.73 23.42,235.13
GND on BOTTOM: 148.44,118.59 148.11,118.92 148.11,119.71 146.44,121.37 146.44,123.43 146.43,123.44 146.43,124.46 146.94,124.97 146.94,130.68 145.41,132.21 145.41,133.22 141.35,137.29 141.35,147.7 149.1,155.45 150.37,155.45 150.62,155.19 150.62,154.05 149.22,152.65 148.46,152.65 142.75,146.94 142.75,137.41 146.94,133.22 146.94,132.46 147.96,131.44 147.96,122.68 149.2,121.44 149.2,119.1 148.69,118.59
GND on BOTTOM: 81.53,6.99 78.03,10.49 78.03,12.01 76.2,13.84 73.15,13.84 72.01,14.99 72.01,17.65 73.79,19.43 81.15,19.43 82.42,18.16 82.42,16.26 83.06,15.62 83.06,10.41 83.31,10.16 92.58,10.16 92.96,10.54 95.5,10.54 97.28,8.76 97.28,7.37 96.9,6.99
GND on BOTTOM: 75.56,10.54 75.56,8.38 74.8,7.62 58.93,7.62 57.66,8.89 57.66,10.54 58.67,11.56 74.55,11.56 ; 1 cut-out
GND on BOTTOM: 172.24,174.6 171.68,175.16 171.68,176.2 171.75,176.28 178.87,176.28 179.71,177.11 179.71,178.94 179.83,179.07 183.13,179.07 183.9,178.31 183.9,177.67 183.26,177.04 182.27,177.04 182.22,176.99 182.22,175.49 181.33,174.6
GND on BOTTOM: 84.23,45.82 84.1,45.95 84.1,57.63 84.23,57.76 85.75,57.76 85.88,57.63 85.88,45.95 85.75,45.82
GND on BOTTOM: 135.59,31.67 135.25,32 135.25,33.38 135.46,33.58 140.82,33.58 140.97,33.43 140.97,32.03 140.61,31.67
GND on BOTTOM: 65.68,46.33 65.56,46.46 65.56,57.89 65.94,58.27 67.21,58.27 67.34,58.14 67.34,46.46 67.21,46.33
GND on BOTTOM: 186.82,192.79 184.66,194.94 184.66,198.88 181.36,202.18 143.76,202.18 140.84,205.1 140.84,206.11 140.97,206.24 143,206.24 143.17,206.17 143.24,206 143.24,205 143.75,203.75 145,203.24 197,203.24 198.58,202.58 199.24,201 199.24,193.78 198.25,192.79
GND on BOTTOM: 47.27,42.39 47.14,42.52 47.14,52.43 48.03,53.31 48.79,53.31 48.92,53.19 48.92,42.52 48.79,42.39
GND on BOTTOM: 135.47,21.69 135.09,22.07 135.09,26.38 135.38,26.67 139.09,26.67 139.49,26.27 139.49,21.9 139.28,21.69
GND on BOTTOM: 29.51,250.11 27.15,252.48 27.15,258.14 20.19,265.1 20.19,266.19 20.57,266.57 53.31,266.57 55.93,263.96 55.93,262.23 55.47,261.77 55.47,257.89 55.8,257.56 55.8,256.08 49.83,250.11
GND on BOTTOM: 44.37,98.81 19.27,123.9 19.24,123.94 19.24,143.29 11.81,150.72 11.81,169.42 12.22,169.82 135.1,169.82 137.03,167.89 137.03,155.35 137.05,155.33 139.33,155.33 139.78,155.78 139.78,165.02 139.75,165.05 139.75,167.54 140.34,168.12 141,168.12 141.1,168.02 141.1,163.93 142.6,162.43 142.6,155.52 136.65,149.58 133.93,149.58 133.57,149.21 133.57,147.03 127.97,141.43 127.25,141.43 126.8,140.97 126.8,124.76 102.49,100.46 92.96,100.46 92.58,100.08 91.57,100.08 91.06,100.58 89.79,100.58 89.18,99.98 88.8,99.98 88.32,100.46 87.38,100.46 86.74,101.09 86.74,104.78 85.22,106.3 63.63,106.3 63.31,105.98 63.31,101.16 63.12,100.97 61.08,100.97 60.61,100.49 56.43,100.49 54.74,98.81 ; 2 cut-outs
GND on BOTTOM: 18.21,73.41 16.69,74.93 16.69,75.62 18.03,76.96 22.61,76.96 23.11,76.45 23.11,73.79 22.73,73.41
GND on BOTTOM: 47.37,12.7 43.43,16.64 43.43,17.02 43.56,17.14 44.83,17.14 48.64,13.34 48.64,13.08 48.26,12.7
GND on BOTTOM: 29.11,40.23 27.58,41.76 27.58,45.19 28.98,46.58 28.98,48.23 29.26,48.51 30.43,48.51 30.63,48.31 30.63,40.36 30.51,40.23
GND on BOTTOM: outline of 218 points within 0.76,0.76 199.24,284.94 ; 1 cut-out
GND on BOTTOM: 17.5,109.47 16.99,109.98 16.99,112.95 17.7,113.67 22.99,113.67 23.88,112.78 23.88,110.03 23.32,109.47
GND on L2VCC: 168.61,147 168.21,147.4 168.21,152.32 168.61,152.72 171.24,152.72 172.15,151.81 172.15,147.53 171.63,147
GND on L2VCC: 15.53,189.51 15.07,189.93 9.88,195.11 8.79,195.11 6.73,197.17 6.1,197.17 5.78,197.49 5.8,218.11 6.51,218.81 7.36,218.81 7.81,218.36 7.81,215.86 8.14,215.2 14.43,215.2 15.05,215.82 15.05,216.92 15,224.99 18.34,228.36 33.84,228.38 36.38,230.92 43.94,230.92 44.41,230.45 44.41,229.85 44.01,229.5 44.01,229.42 44,229.35 44.01,229.34 44.01,227.51 44.75,226.76 48.05,226.76 48.58,226.24 48.58,220.68 47.05,219.15 47.05,209.22 47.67,208.6 52.15,208.6 53.02,209.47 53.02,227.83 53.21,227.89 53.22,227.89 53.28,227.91 53.54,228 61.3,220.24 61.3,204.44 66.1,199.57 66.1,198.71 65.45,198.06 64.85,198.06 59.44,203.34 58.24,204.53 46.94,204.53 46.67,204.8 46.67,205.98 43.35,207.71 31.32,207.71 30.54,208.49 30.54,213.57 29.92,214.19 22.91,214.19 22.03,213.31 22.03,201.09 23.8,199.33 45.9,199.33 46.29,198.93 46.29,192.74 45.9,192.34 41.7,192.34 41.39,192.03 39.29,189.95 16.36,189.93 ; 9 cut-outs
GND on L2VCC: outline of 743 points within 0.76,0.76 199.24,283.24 ; 44 cut-outs
GND on L2VCC: 38.07,173.55 37.78,173.93 37.78,174.97 33.57,178.16 33.57,178.17 33.51,178.21 33.45,178.25 33.45,178.25 33.08,178.5 14.62,178.5 14.57,178.64 16.32,180.39 16.32,181.79 16.72,182.18 35.26,182.18 37.42,184.34 45.42,184.34 48.59,187.52 59.1,187.52 69.28,177.47 69.28,175.97 69.01,175.7 63.93,175.7 62.41,174.18 50.22,174.18 49.51,174.89 48.66,174.89 47.39,173.57 47.17,173.57
GND on L2VCC: 104.22,192.34 103.44,193.12 103.44,200.96 104.22,201.74 138.86,201.74 141.03,199.57 141.03,198.07 135.3,192.34 134.19,192.34 134.2,192.76 133.84,192.97 132.96,192.97 132.6,192.76 132.61,192.34 130.4,192.34 130.38,192.74 130.03,192.94 129.16,192.94 128.81,192.74 128.8,192.34 114.31,192.34 114.18,192.61 113.91,192.71 112.89,192.71 112.61,192.61 112.48,192.34 110.5,192.34 110.36,192.59 110.1,192.69 109.08,192.69 108.81,192.59 108.68,192.34 ; 4 cut-outs
GND on L3SGND: 6.35,188.3 6.35,180.9
GND on L3SGND: outline of 180 points within 5.46,0.76 199.24,283.24 ; 3 cut-outs
GND on L3SGND: 0.76,231.92 0.76,241 1.42,242.58 3,243.24 8,243.24 10.66,244.34 11.76,247 11.76,264.5 12.06,265.62 12.88,266.44 14.26,267.81 14.76,269.7 14.76,278 15.42,279.58 17,280.24 22.06,280.24 22.94,280.47 23.58,281.12 23.87,281.62 23.96,281.71 24.08,281.74 58.86,281.74 58.86,273.51 58.56,273.21 57.64,272.28 56.82,271.46 17.83,271.46 15.43,269.06 15.43,262.68 22.03,256.08 22.03,252.05 19.23,249.24 15.8,249.24 7.94,241.38 7.94,239.09
VBAT1 on TOP: 46.55,253.97 44.32,256.2 44.32,257.91 44.78,258.37 46.58,258.37 48.08,256.87 52.17,256.87 52.88,256.16 52.88,254.25 52.6,253.97 ; 2 cut-outs
VBAT1_L on TOP: 49.76,258.17 48.62,259.31 47.35,259.31 46.99,259.66 46.99,260.71 47.27,260.99 47.88,260.99 48.77,260.1 49.25,260.1 49.86,259.49 52.53,259.49 52.76,259.26 52.76,258.39 52.53,258.17
VBAT1_R on TOP: 50.37,260.32 50.24,260.45 50.24,261.26 50.37,261.39 51.36,261.39 51.94,261.98 51.94,262.94 51.99,262.99 52.65,262.99 52.76,262.89 52.76,260.53 52.55,260.32
VBAT2 on TOP: 53.8,253.06 53.49,253.37 53.49,256.64 52.78,257.35 48.29,257.35 47.42,258.22 47.42,258.75 48.51,258.75 49.4,257.86 53.59,257.86 54.56,256.9 54.56,253.29 54.33,253.06
0D95V_CPU_VCCIO on TOP: 82.93,93.34 82.68,93.6 82.68,93.98 82.93,94.23 82.96,94.23 83.24,94.51 83.24,95.38 83.31,95.45 85.06,95.45 85.17,95.35 85.17,93.57 84.94,93.34 ; 4 cut-outs
0D95V_CPU_VCCIO on TOP: 80.01,102.41 79.88,102.54 79.88,103.66 80.37,104.14 82.55,104.14 82.8,103.89 82.8,103.76 82.55,103.5 82.55,103.48 80.95,103.48 80.77,103.3 80.77,102.46 80.72,102.41
0D95V_CPU_VCCIO on TOP: 129.62,54.1 128.98,54.74 128.98,55.45 129.06,55.52 129.62,55.52 130.43,56.34 130.43,60.2 129.79,60.83 129.79,65.53 128.4,66.93 123.25,66.93 122.33,67.85 121,67.85 115.18,73.67 115.18,77.86 115.06,77.98 115.06,88.49 115.44,88.87 115.44,88.9 116.84,90.3 117.65,90.3 117.75,90.2 117.75,85.62 118.03,85.34 122.05,85.34 122.05,83.74 122.85,82.94 124.75,82.94 124.84,82.85 124.84,77.47 124.59,77.22 121.79,77.22 121.54,76.96 121.54,75.82 120.27,74.55 120.27,71.12 122.17,69.22 128.65,69.22 131.83,66.04 131.83,54.64 131.29,54.1 ; 4 cut-outs
0D95V_CPU_VCCIO on TOP: 69.62,101.35 69.49,101.47 69.49,102.31 69.52,102.34 69.82,102.34 70.36,102.87 70.36,107.06 70.61,107.31 70.99,107.31 72.14,106.17 72.14,101.47 72.01,101.35 ; 5 cut-outs
0D95V_CPU_VCCIO on BOTTOM: 84.45,89.92 81.66,92.71 81.66,97.66 81.92,97.92 81.92,99.31 81.79,99.44 81.79,100.84 81.66,100.97 81.66,103.89 81.92,104.14 83.19,104.14 83.57,103.76 83.57,102.74 87.12,99.19 87.12,90.17 86.87,89.92
0D95V_CPU_VCCIO on L2VCC: outline of 112 points within 70.24,78.93 123.89,108.24
0D675V_VTT_S0 on TOP: 34.67,176.48 34.57,176.58 34.57,178 34.7,178.13 36.35,178.13 36.4,178.08 36.4,176.56 36.32,176.48
0D675V_VTT_S0 on TOP: 76.96,159 76.83,159.13 76.83,160.27 76.58,160.53 76.58,167.94 78.87,170.23 78.87,171.25 78.57,171.54 78.57,172.49 78.83,172.75 81.43,172.75 81.76,172.42 81.76,168.63 80.33,167.2 80.33,163.13 79.63,162.43 79.63,159.38 79.25,159 ; 4 cut-outs
0D675V_VTT_S0 on BOTTOM: 49.07,170.81 45.26,174.62 40.49,174.62 40.13,174.27 36.04,174.27 34.59,175.72 34.59,178.03 34.75,178.18 36.17,178.18 36.45,177.9 36.45,175.77 38.35,175.77 38.57,175.98 46.65,175.98 50.15,172.48 62.9,172.48 64.8,174.37 79.83,174.37 81.38,172.82 81.38,171.75 81.31,171.68 78.87,171.68 78.33,172.21 66.73,172.21 65.33,170.81
1D2V_SM_S3 on TOP: 125.32,107.34 124.97,107.7 124.97,110.24 128.02,113.28 128.02,145.29 137.41,154.69 139.32,154.69 140.08,155.45 140.08,169.33 140.22,169.46 141.41,169.46 141.69,169.19 141.69,152.1 141.67,152.08 141.67,150.3 130.94,139.57 130.94,111.76 128.02,108.84 128.02,107.62 127.74,107.34
1D2V_SM_S3 on TOP: 41.8,184.8 41.66,184.94 41.66,186.13 41.68,186.16 41.68,186.46 41.91,186.69 43.94,186.69 44.2,186.44 44.2,184.91 44.08,184.8
1D2V_SM_S3 on TOP: 37.88,169.63 35.59,171.93 35.59,173.69 34.77,174.5 31.75,174.5 31.62,174.62 31.62,175.77 31.88,176.02 36.45,176.02 37.08,175.39 37.08,173.48 39.5,171.07 52.96,171.07 53.47,171.58 65.15,171.58 66.5,172.92 66.5,173.28 66.83,173.61 76.4,173.61 76.56,173.46 76.56,173 76.53,172.97 75.77,172.97 75.69,172.9 75.69,170.18 75.44,169.93 67.06,169.93 66.93,169.8 53.72,169.8 53.56,169.63 ; 1 cut-out
1D2V_SM_S3 on TOP: 120.04,92.33 119.89,92.48 119.89,93.62 121.18,94.92 121.2,94.91 123.06,96.77 127.61,96.77 127.84,96.55 127.84,92.58 127.58,92.33 ; 1 cut-out
1D2V_SM_S3 on TOP: 87.8,170.04 87.58,170.26 87.58,171.91 87.48,172.01 83.52,172.01 83.06,172.47 83.06,172.97 82.93,173.1 79.07,173.1 79.07,178.13 79.3,178.36 86.49,178.36 89.08,175.77 91.31,175.77 92.08,175.01 92.08,170.43 91.68,170.04 ; 4 cut-outs
1D2V_SM_S3 on BOTTOM: 31.75,174.37 31.62,174.5 31.62,180.85 33.53,182.75 37.21,182.75 41.08,186.63 44.01,186.63 44.2,186.44 44.2,185.04 43.94,184.78 41.53,184.78 37.91,181.17 34.23,181.17 33.27,180.21 33.27,174.62 33.02,174.37
1D2V_SM_S3 on BOTTOM: 128.78,127.38 128.4,127.76 128.4,141.35 134.75,147.7 137.03,147.7 137.41,147.32 137.41,144.22 132.49,139.29 132.49,128.42 131.44,127.38
1D2V_SM_S3 on L2VCC: outline of 191 points within 16.9,92.65 141.29,173.8
1D2V_SM_S3 on L3SGND: 135.46,149.03 134.81,149.68 134.81,152.08 134.87,152.15 134.87,153.4 135.45,153.97 135.45,153.99 135.89,154.43 135.89,156.84 135.76,156.97 135.76,158.98 135.45,159.3 135.45,169.21 135.71,169.48 140.13,169.48 141.29,168.32 141.29,153.62 136.7,149.03
1D05V_CPU_SA on TOP: 110.39,41.4 109.88,41.91 108.58,41.91 107.82,42.67 107.82,51.82 108.71,52.7 116.97,52.7 117.67,52.01 117.67,44.2 114.88,41.41 114.88,41.4 ; 2 cut-outs
1D05V_CPU_SA on TOP: 88.39,90.45 88.03,90.81 87.96,90.81 87.83,90.93 86.28,90.93 85.9,91.31 85.6,91.31 84.96,91.95 84.96,93.12 85.34,93.5 85.34,95.45 84.96,95.83 84.96,95.89 84.81,96.04 83.19,96.04 83.17,96.05 83.17,103.29 83.19,103.3 84.45,103.3 87.47,100.28 89.01,100.28 89.14,100.15 89.14,99.61 89.94,98.81 90.09,98.81 90.24,98.66 90.24,98.33 89.86,97.95 89.86,97.01 89.2,96.34 89.2,96.01 89.3,95.92 89.3,95.59 89.13,95.42 89.13,94.97 89.3,94.8 89.3,94.57 88.69,93.96 88.69,93.68 88.87,93.5 88.87,93.32 88.67,93.12 88.67,92.76 88.79,92.64 88.79,92.33 88.69,92.23 88.69,91.87 88.82,91.75 88.82,91.42 88.67,91.26 88.67,90.93 88.87,90.73 88.87,90.55 88.77,90.45
1D05V_CPU_SA on BOTTOM: 108.84,41.27 108.2,41.91 108.2,52.32 108.84,52.96 116.76,52.96 117.6,52.12 117.6,43.94 114.94,41.27
1D05V_CPU_SA on L2VCC: 108.16,42.23 107.89,42.5 107.86,50.41 108.05,50.98 108.7,52.15 108.7,55.73 106.59,57.84 106.62,64.82 106.62,64.98 103.71,67.88 92.2,67.88 82.66,77.42 82.66,79.47 83.88,80.69 83.88,83.36 84.15,83.63 84.79,83.63 85.23,84.07 85.23,88.31 85.55,88.63 87.83,88.63 88.28,88.33 88.75,88.33 89.04,88.62 89.04,89.11 88.27,89.88 87.99,90.13 87.82,90.3 87.82,91.75 87.33,92.24 85.88,92.24 85.43,92.49 85.43,96.47 85.73,96.76 89.23,96.76 89.34,96.59 89.34,95.43 89.71,95.06 91.49,95.06 93.01,93.54 98.22,93.54 99.64,92.09 102.81,88.94 113.07,78.63 119.12,72.76 121.6,70.28 121.6,66.09 123.89,63.8 123.89,62.94 122.87,61.93 122.87,53.93 122.36,53.42 122.36,42.62 121.97,42.23
1D05V_LAN on TOP: 139.9,25.32 139.83,25.4 139.83,26.04 139.78,26.09 139.78,27.71 141.53,29.46 142.88,29.46 142.98,29.36 142.98,27.66 142.85,27.53 141.73,27.53 141.36,27.17 141.36,27.15 141.3,27.09 141.3,26.49 140.51,25.7 140.51,25.37 140.46,25.32 ; 2 cut-outs
1D05V_LAN on TOP: 141.48,23.88 141.22,24.13 141.22,24.36 142.75,25.88 143.28,25.88 143.31,25.86 143.31,24.43 142.75,23.88 ; 1 cut-out
1D05V_LAN on TOP: 133.06,21.27 132.74,21.59 132.74,22.38 132.8,22.44 134.95,22.44 135.27,22.12 136.14,22.12 136.25,22.02 136.25,21.77 136.02,21.54 134.12,21.54 133.86,21.27 ; 1 cut-out
1D05V_LAN on BOTTOM: 133.93,21.77 133.17,22.53 133.17,27.08 133.63,27.53 141.12,27.53 141.25,27.41 141.25,25.76 141.66,25.35 142.09,25.35 142.37,25.07 142.37,24.38 142.11,24.13 139.95,24.13 139.83,24.26 139.83,26.14 139.55,26.42 135,26.42 134.75,26.16 134.75,21.92 134.59,21.77
1D8V_SB on TOP: 161.9,115.19 160.96,116.13 160.15,116.13 159.89,116.38 159.51,116.38 159.28,116.61 158.72,116.61 158.09,117.25 157.48,117.25 156.72,118.01 155.22,118.01 154.79,118.44 154.79,118.49 154.41,118.87 153.59,118.87 152.91,119.56 152.91,121.26 153.01,121.36 154.08,121.36 154.41,121.03 154.41,119.89 154.1,119.58 154.1,119.35 154.23,119.23 154.43,119.23 154.58,119.38 155.19,119.38 155.42,119.15 156.31,119.15 156.59,118.87 157.76,118.87 158.64,118 160.13,118 160.27,117.86 160.27,117.12 160.41,116.98 161.28,116.98 162.18,116.08 163.7,116.08 163.83,115.95 163.83,115.57 163.45,115.19
1D24V_PCH on TOP: 154.64,121.69 154.46,121.87 154.46,122.78 154.56,122.89 155.51,122.89 155.75,122.64 156.01,122.64 156.25,122.89 158.8,122.89 159,122.68 159,122.05 158.73,121.77 155.72,121.77 155.64,121.69
1D24V_PCH on L2VCC: 166.07,112.46 165.67,112.85 165.67,115.65 164.71,116.61 164.71,118.75 164.68,118.77 164.68,118.82 164.2,119.33 164.2,119.33 164.14,119.39 164.09,119.44 164.09,119.44 164.01,119.44 163.93,119.45 163.93,119.44 158.63,119.44 158.31,119.76 158.31,120.98 157.92,121.37 157.91,121.38 157.86,121.43 157.81,121.48 157.8,121.48 157.42,121.78 157.42,122.6 157.61,122.8 167.05,122.82 167.47,122.36 167.45,112.86 167.45,112.85 167.05,112.46
2D5V_VPP_S3 on TOP: 116.13,169.98 115.98,170.13 115.98,171.86 116.2,172.09 118.49,172.09 119.25,171.32 119.25,170.31 118.92,169.98
2D5V_VPP_S3 on TOP: 138.14,155.09 136.65,156.59 136.65,168.11 136.69,168.15 136.68,168.16 136.68,169.42 135.45,170.65 134.37,170.94 132.21,171.83 132.17,171.83 131.58,172.42 125.73,172.42 125.16,171.85 125.16,171.83 123.85,171.83 122.56,173.13 122.56,173.66 122.76,173.86 124.98,173.86 125.66,174.54 133.31,174.54 135.76,172.09 139.57,172.09 139.9,171.75 139.9,155.63 139.37,155.09 ; 6 cut-outs
2D5V_VPP_S3 on BOTTOM: 118.01,170.05 117.47,170.59 117.47,171.81 117.69,172.02 120.79,172.02 122.53,173.76 123.55,173.76 124.33,172.97 124.33,171.83 122.56,170.05
3D3V_CARD_S0 on TOP: 39.8,253.75 39.62,253.92 39.62,256.11 39.75,256.24 40.21,256.24 40.64,256.67 41.27,256.67 41.4,256.54 41.4,253.85 41.3,253.75
3D3V_LAN on TOP: 134.96,26.29 133.6,27.65 132.01,27.65 131.47,28.19 131.47,29.31 131.75,29.59 134.14,29.59 134.29,29.44 134.29,28.19 135.66,26.82 136.14,26.82 136.25,26.72 136.25,26.56 136.01,26.33 135.59,26.33 135.55,26.29 ; 1 cut-out
3D3V_LAN on TOP: 140.87,24.89 140.79,24.97 140.79,25.55 140.92,25.68 141.15,25.68 141.6,26.14 141.6,27.05 141.86,27.3 143.26,27.3 143.37,27.19 143.37,27.04 143.41,27 143.41,26.01 143.36,25.96 142.62,25.96 141.55,24.89 ; 1 cut-out
3D3V_LAN on TOP: 135.59,17.04 135.41,17.22 135.41,19.23 135.56,19.38 135.56,20.04 135.59,20.07 135.59,20.24 135.71,20.37 135.89,20.37 135.92,20.4 136.3,20.4 137.27,21.37 137.27,21.76 137.57,22.05 137.57,22.78 137.62,22.83 137.77,22.83 137.79,22.81 137.79,20.8 137.53,20.54 137.53,20.23 137.67,20.09 137.21,19.63 137.21,19.05 137.64,18.62 137.64,17.14 137.54,17.04 ; 4 cut-outs
3D3V_LAN on BOTTOM: 133.43,19.02 131.46,20.99 131.46,27.9 132.44,28.88 142.54,28.88 143.26,28.17 143.26,26.04 142.9,25.68 141.81,25.68 141.63,25.86 141.63,27.58 141.38,27.84 133.45,27.84 132.74,27.13 132.74,22.23 133.68,21.29 137.21,21.29 137.46,21.03 137.46,19.28 137.21,19.02
3D3V_PCIVAUX_SB on TOP: 175.51,50.29 175.26,50.55 175.26,55.24 175.51,55.5 177.55,55.5 177.8,55.24 177.8,50.55 177.55,50.29 ; 5 cut-outs
3D3V_PCIVAUX_SB on BOTTOM: 185.42,53.21 185.04,53.59 180.85,53.59 179.58,54.86 178.82,54.86 177.42,53.47 173.89,53.47 172.06,55.3 172.06,55.32 170.79,56.59 169.49,56.59 168.15,55.24 168.15,54.97 166.65,53.47 165.35,53.47 164.47,54.36 164.47,55.37 164.48,55.38 164.48,55.44 164.47,55.45 164.47,56.9 164.87,57.3 166.07,57.3 166.78,58.01 166.78,58.04 167.18,58.45 172.57,58.45 175.01,56.01 181.36,56.01 182.75,54.61 184.4,54.61 185.04,55.24 186.23,55.24 186.23,53.21
3D3V_S0 on TOP: 53.98,12.22 53.86,12.33 53.86,16.01 54.61,16.76 54.99,16.76 55.12,16.89 55.12,17.91 55.24,18.03 55.52,18.03 55.63,17.93 55.63,16.38 54.99,15.75 54.94,15.75 54.69,15.49 54.69,12.34 54.56,12.22
3D3V_S0 on TOP: 135.13,160.08 134.26,160.95 134.26,168 132.33,169.93 121.18,169.93 117.96,173.15 117.96,175.13 118.64,175.82 118.64,176.78 118.85,176.99 119.48,176.99 120.14,176.33 120.14,173.79 122.86,171.07 132.84,171.07 134.62,170.4 135.35,170.4 136.58,169.18 136.58,160.56 136.09,160.08 ; 5 cut-outs
3D3V_S0 on TOP: 160.73,34.62 160.55,34.8 160.55,35.51 160.68,35.64 163.65,35.64 163.83,35.46 163.83,34.67 163.78,34.62
3D3V_S0 on TOP: 169.42,55.12 169.16,55.37 169.16,58.17 167,60.33 167,63.5 163.83,66.67 163.83,94.61 162.76,95.68 162.76,96.27 162.94,96.44 164.59,96.44 165.23,95.81 165.23,67.44 169.04,63.63 169.04,60.07 170.31,58.8 170.31,55.24 170.18,55.12 ; 14 cut-outs
3D3V_S0 on TOP: 155.73,24.94 155.52,25.15 155.52,28.7 155.14,29.08 155.14,31.72 155.27,31.85 156.97,31.85 157.07,31.75 157.07,25.93 157.26,25.74 157.26,24.98 157.23,24.94 ; 6 cut-outs
3D3V_S0 on TOP: 141.6,16.64 141.35,16.89 141.35,17.63 141.5,17.78 143.64,17.78 143.76,17.91 146.33,17.91 146.63,18.21 146.63,18.24 147.22,18.82 149.63,18.82 149.71,18.75 149.71,17.09 149.5,16.89 144.15,16.89 143.89,16.64 ; 5 cut-outs
3D3V_S0 on TOP: 31.62,188.37 31.52,188.47 31.52,189.94 31.9,190.32 35.62,190.32 36.5,191.2 36.92,191.2 37.13,191.41 45.69,191.41 46.48,190.63 46.48,189.1 45.75,188.37 ; 6 cut-outs
3D3V_S0 on TOP: 54.2,22.63 54.15,22.68 54.15,23.72 54.51,24.08 54.51,25.25 54.86,25.6 58.09,25.6 58.27,25.43 58.27,24.92 58.17,24.82 55.47,24.82 55.27,24.61 55.27,23.83 55.83,23.27 55.83,22.78 55.68,22.63
3D3V_S0 on TOP: 38.35,251.71 38.1,251.97 38.1,253.67 38.38,253.95 38.38,255.65 38.48,255.75 38.48,255.78 39.12,255.78 39.19,255.7 39.19,251.92 38.99,251.71
3D3V_S0 on TOP: 157.25,172.59 156.59,173.25 156.59,174.78 156.67,174.85 158.22,174.85 158.47,174.6 158.47,172.75 158.32,172.59
3D3V_S0 on TOP: 129.87,15.85 129.67,16.05 129.67,17.78 129.79,17.91 132.21,17.91 132.33,17.78 132.33,17.02 132.21,16.89 130.76,16.89 130.51,16.64 130.51,16 130.35,15.85 ; 3 cut-outs
3D3V_S0 on BOTTOM: 170.43,46.23 167.51,49.15 167.26,49.15 166.12,50.29 160.66,50.29 159.77,51.18 158.88,51.18 157.99,52.07 157.99,54.36 158.88,55.24 160.02,55.24 160.78,54.48 164.08,54.48 165.23,53.34 166.73,53.34 168.4,55.02 168.4,55.45 169.01,56.06 169.37,56.06 169.6,56.29 170.71,56.29 170.94,56.06 171.04,56.06 171.35,55.75 171.37,55.75 173.91,53.21 177.29,53.21 178.69,54.61 179.58,54.61 181.23,52.96 185.67,52.96 186.41,52.22 186.41,50.65 184.78,49.02 181.36,49.02 180.47,48.13 178.56,48.13 176.66,46.23
3D3V_S0 on BOTTOM: 130.1,15.6 129.62,16.08 129.62,17.45 129.72,17.55 130.86,17.55 131.37,17.04 141.25,17.04 141.6,17.4 142.62,17.4 142.88,17.14 142.88,15.85 142.62,15.6
3D3V_S0 on BOTTOM: 63.51,189.3 63.92,189.31 71.21,184.49 84.28,181.1 112.22,181.1 114,179.32 117.07,179.32 117.51,178.88 118.25,178.88 120.24,176.89 120.24,174.02 120.07,173.84 106.96,173.84 105.54,175.26 72.01,175.26 67.56,179.71 67.56,180.09 62.26,185.39 50.32,185.39 47.37,188.34 33.1,188.34 32.66,188.77 32.66,192.38 33.91,193.62 48.06,193.62 49.81,191.87 58.19,191.87 60.76,189.3
3D3V_S0 on BOTTOM: 163.7,97.18 163.7,102.74 164.67,103.71 165.53,103.71 165.99,103.25 165.99,101.98 165.1,101.09 165.1,96.65 164.97,96.52 164.97,96.49 163.35,94.87 162.76,94.87 162.43,95.2 162.43,95.94 163.68,97.18
3D3V_S0 on L2VCC: 189.82,51.37 189.55,51.64 189.55,130 187.52,132.03 187.52,142.91 188.03,143.32 189.69,143.32 190.71,144.34 197.29,144.34 198.06,143.7 198.06,51.66 197.68,51.37
3D3V_S0 on L2VCC: 163.95,99.63 163.77,99.99 163.77,108.89 164.67,109.79 167.34,109.79 167.83,110.28 167.83,112.52 167.83,112.97 167.85,122.34 167.86,122.35 167.86,122.42 167.86,122.5 167.86,122.5 167.86,123.52 167.86,123.59 167.85,123.6 167.86,124.99 168.28,125.41 169.21,125.41 169.48,125.14 169.48,108.41 169.21,108.14 166.04,108.14 165.54,107.65 165.54,99.9 165.28,99.63
3D3V_S0 on L2VCC: 157.05,172.53 156.67,172.91 152.1,172.91 150.57,174.43 146.64,174.43 144.86,176.21 142.7,176.21 140.79,178.12 121.21,178.12 120.33,177.24 120.33,174.68 120.03,174.18 105.36,174.18 105.09,174.45 105.09,178.61 108.92,182.44 156.39,182.44 156.78,182.04 156.78,180.7 156.21,179.87 146.24,179.87 145.76,179.26 145.76,178.2 146.49,177.47 148.01,176.67 150.17,176.67 151.19,177.36 159.15,177.36 159.45,176.86 159.45,173.92 158.73,172.84 158.42,172.53
3D3V_S0 on L3SGND: 142.49,15.35 128.62,15.38 128.21,15.96 128.21,19.13 128.56,19.39 139.01,19.39 139.78,19.75 141.99,21.94 144.18,24.15 146.89,26.89 156.11,26.89 157.81,25.21 162.81,25.21 163.44,25.8 163.41,34.8 162.16,36.03 160.45,36.03 160.21,36.27 160.21,38.38 160.61,38.8 167.39,38.85 167.65,38.96 169.96,41.35 169.99,49.35 168.73,50.61 165.05,50.61 164.04,51.63 158.07,51.63 157.54,52.15 157.54,55.04 158.32,55.82 165.69,55.82 167.59,57.72 176.45,57.72 177.85,56.32 186.13,56.32 187.15,57.34 191.82,57.34 192.21,56.94 192.21,51.13 191.82,50.74 185.75,50.74 184.86,51.63 183.06,51.63 181.91,50.48 173.02,50.48 172.15,49.61 172.17,40.49 167.2,35.51 167.2,22.81 166.17,21.83 160.04,21.83 157.86,19.42 156.24,19.42 152.68,22.97 150.09,22.97 149.97,22.86
